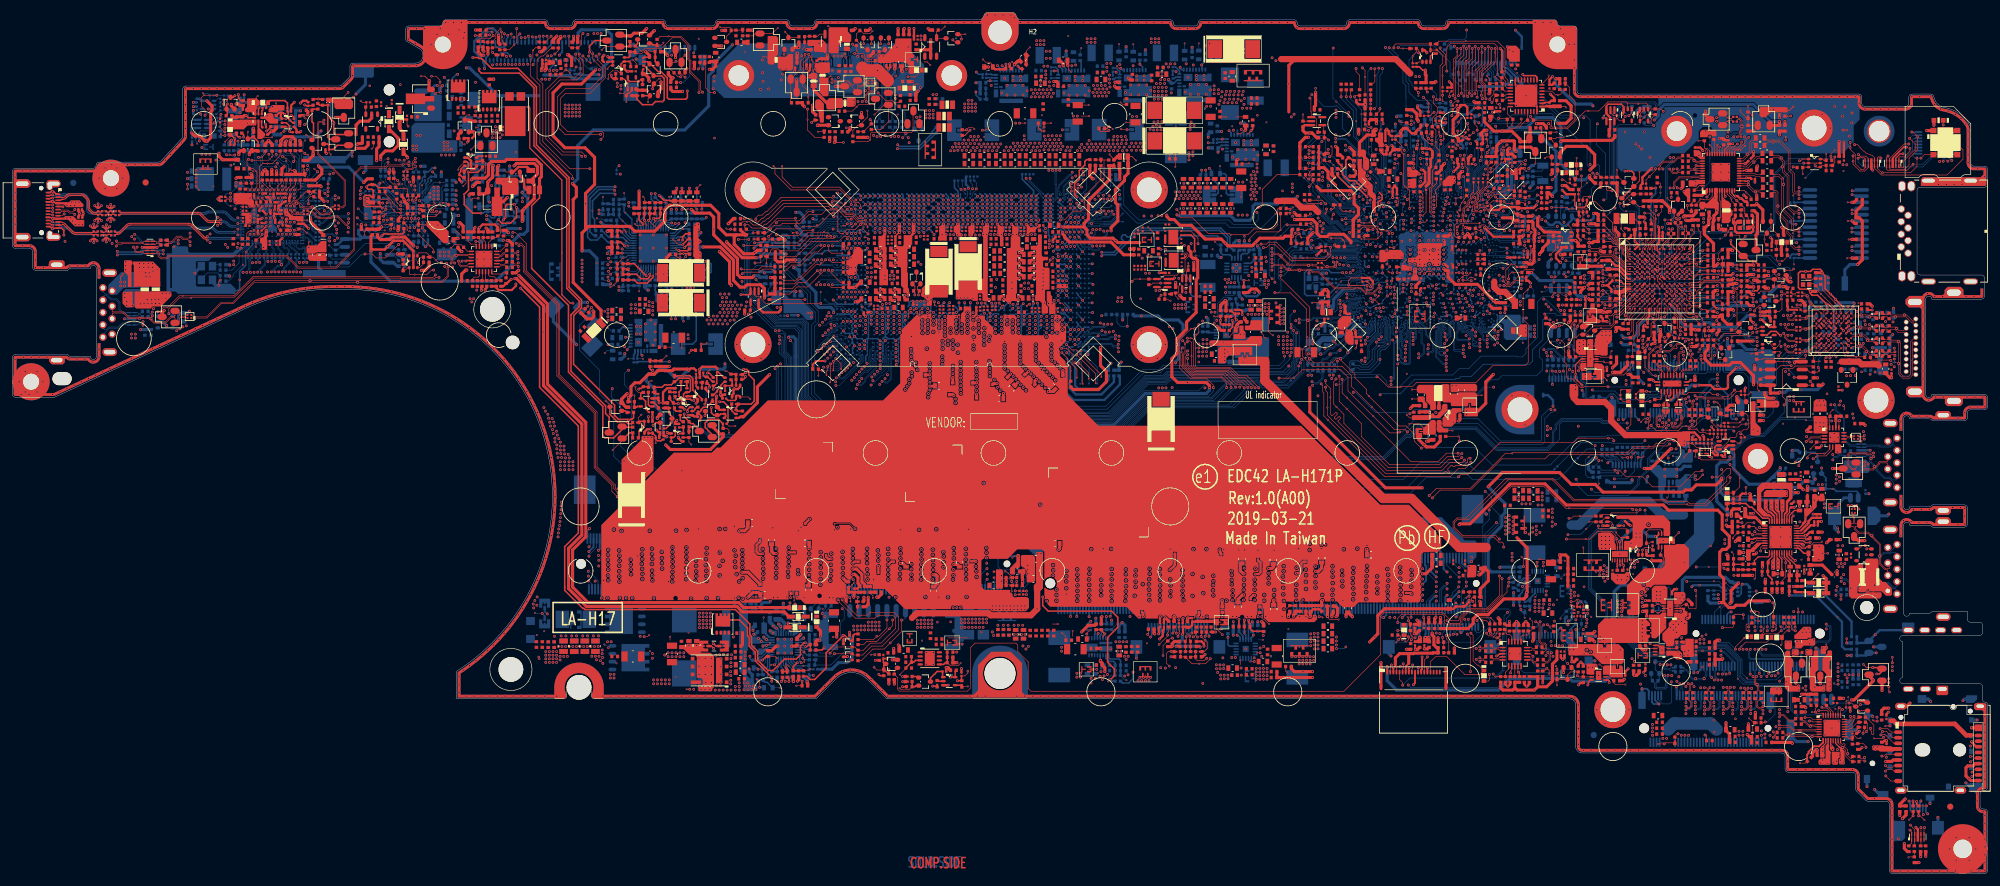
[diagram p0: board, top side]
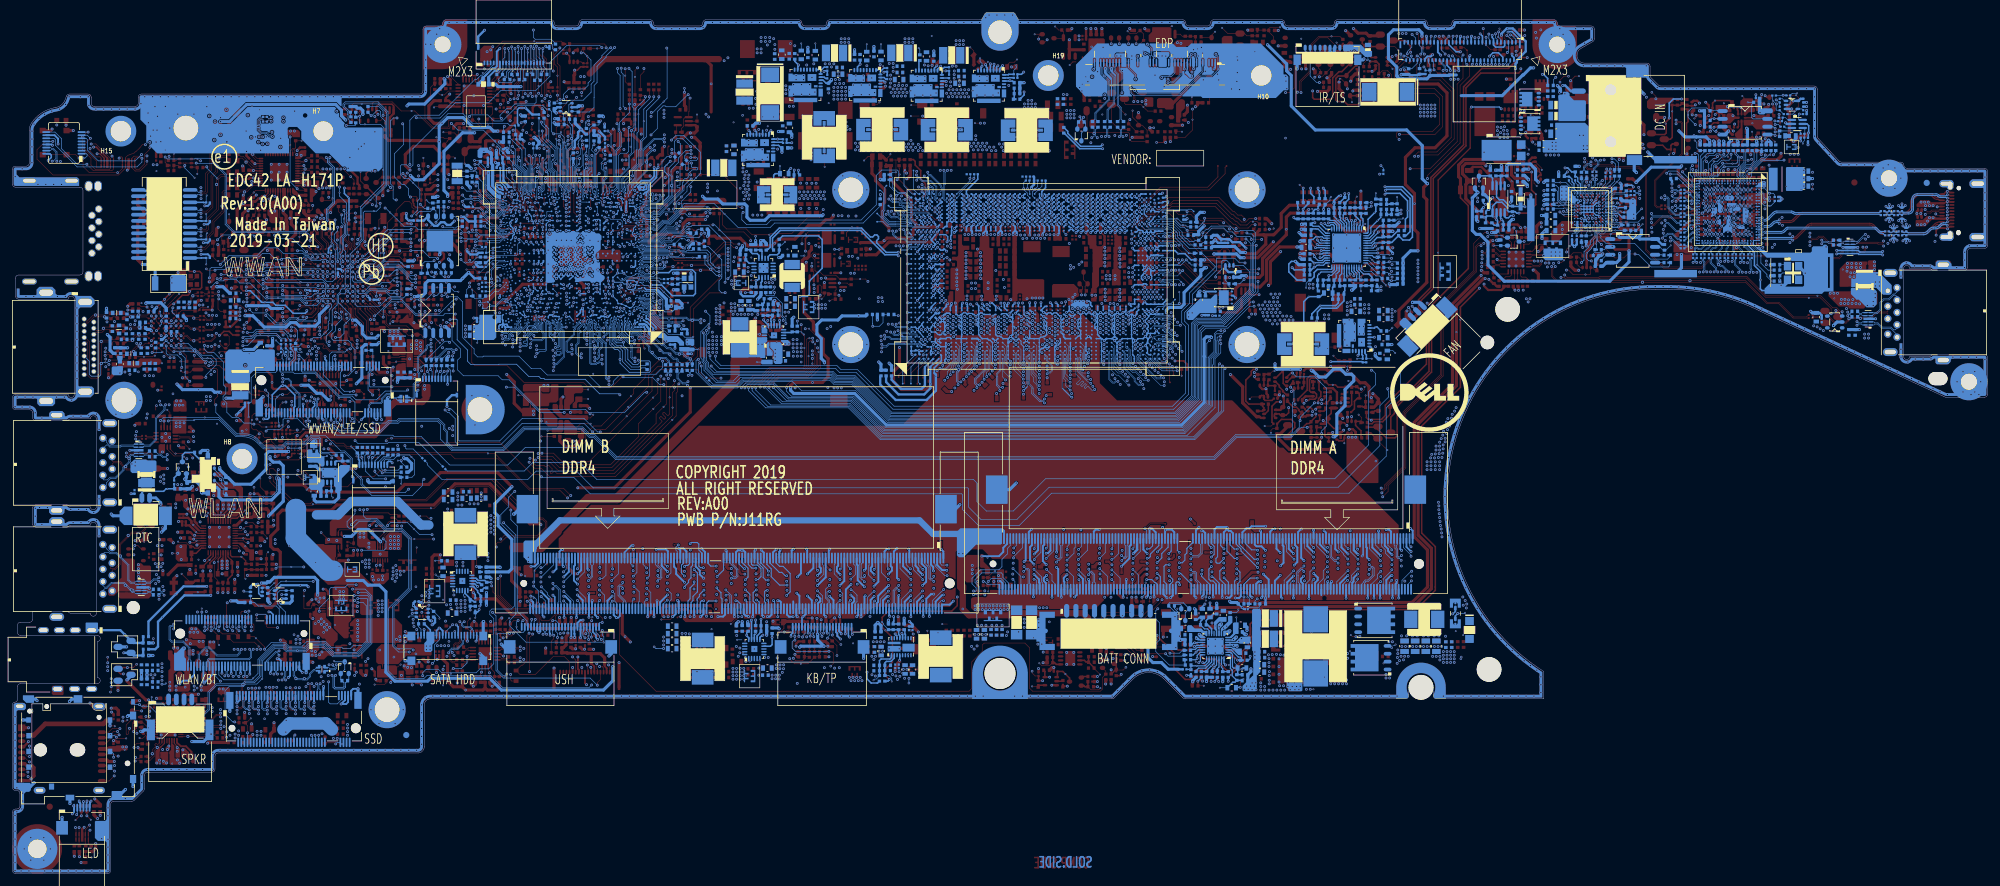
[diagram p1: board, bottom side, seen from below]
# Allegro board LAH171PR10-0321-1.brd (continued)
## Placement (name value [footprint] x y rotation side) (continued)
RH335  20K_0402_5%  [R_0402]  247.91 110.06 180 top
RH339  10K_0402_5%  [R_0402]  230.83 114.16 180 top
RH340  8.2K_0402_1%  [R_0402]  234.88 109.57 90 top
RH344  10K_0402_5%  [R_0402]  245.82 103.07 180 top
RH345  10K_0402_5%  [R_0402]  216.28 127.59 270 top
RH348  10K_0201_5%  [R_0201]  250.2 101.23 180 top
RH351  33_0402_5%  [R_0402]  248.14 97.1 0 bottom
RH352  0_0402_5%  [R_0402]  253.3 90.26 270 top
RH353  33_0402_5%  [R_0402]  250.69 90.4 270 top
RH355  10K_0402_1%  [R_0402]  230 113.22 270 top
RH361  49.9K_0402_1%  [R_0402]  224.28 122.45 270 bottom
RH364  1K_0402_5%  [R_0402]  210.96 87.26 180 bottom
RH365  0_0402_5%  [R0402_0OHM]  212.92 88.53 180 bottom
RH371  10K_0201_5%  [R_0201]  223.45 118.63 90 top
RH372  10K_0201_5%  [R_0201]  222.88 118.63 90 top
RH373  100K_0402_5%  [R_0402]  208.72 108.84 90 top
RH374  2.2K_0402_5%  [R_0402]  231.52 124.55 270 bottom
RH376  49.9K_0402_1%  [R_0402]  225.1 120.08 90 bottom
RH377  10K_0402_5%  [R_0402]  235.51 102.79 0 top
RH378  10K_0201_5%  [R_0201]  223.39 120.61 270 bottom
RH379  100_0402_1%  [R_0402]  233.67 102.83 0 top
RH400  10K_0201_5%  [R_0201]  223.32 118.08 90 bottom
RH401  10K_0201_5%  [R_0201]  223.32 117.4 270 bottom
RH402  10K_0402_5%  [R_0402]  233.56 118.44 180 top
RH424  10K_0201_5%  [R_0201]  239.8 108.72 0 top
RH431  100K_0402_5%  [R_0402]  248.72 114.64 270 top
RH432  499K_0402_1%  [R_0402]  245.16 120.53 0 top
RH433  49.9K_0402_1%  [R_0402]  248.41 119.72 270 top
RH434  0_0402_5%  [R_0402]  242.62 118.31 0 top
RH435  60.4_0402_1%  [R_0402]  211.76 92.59 0 bottom
RH436  0_0201_5%  [R_0201]  213.77 95.45 180 bottom
RH439  0_0402_5%  [R_0402]  242.62 117.42 0 top
RH440  0_0402_5%  [R0402_0OHM]  238.12 115 90 top
RH441  0_0201_5%  [R_0201]  251.58 112.23 270 top
RH442  0_0402_5%  [R0402_0OHM]  252.41 112.23 270 top
RH445  0_0402_5%  [R0402_0OHM]  249.61 113.73 90 top
RH553  10K_0402_5%  [R_0402]  229.17 126.93 90 top
RH554  10K_0402_5%  [R_0402]  228.34 126.93 90 top
RH555  10K_0402_5%  [R_0402]  226.69 126.93 90 top
RH556  10K_0402_5%  [R_0402]  227.52 126.93 90 top
RH566  0_0402_5%  [R0402_0OHM]  248.92 103.08 270 top
RH600  100K_0402_5%  [R_0402]  236.22 122.45 270 bottom
RH601  100K_0402_5%  [R_0402]  243.56 96.21 180 bottom
RH602  100K_0402_5%  [R_0402]  238.81 119.05 0 bottom
RH603  10K_0402_5%  [R_0402]  208.87 115.77 180 top
RH604  4.7K_0402_5%  [R_0402]  210.1 115.77 0 top
RH605  20K_0402_5%  [R_0402]  210.1 117.49 0 top
RH606  100K_0402_5%  [R_0402]  208.87 117.49 180 top
RH607  100K_0402_5%  [R_0402]  210.1 113.99 0 top
RH608  100K_0402_5%  [R_0402]  208.87 113.99 180 top
RH609  200_0402_1%  [R_0402]  214.05 116.16 270 top
RH610  200_0402_1%  [R_0402]  213.15 113.93 0 top
RH611  200_0402_1%  [R_0402]  213.15 113.1 0 top
RH612  150_0402_1%  [R_0402]  211.89 116.23 270 top
RH613  20K_0402_5%  [R_0402]  211.02 114.82 180 top
RH614  20K_0402_5%  [R_0402]  211.02 116.6 180 top
RH615  2.2K_0402_5%  [R_0402]  244.74 97.17 180 top
RH616  0_0402_5%  [R0402_0OHM]  213.53 108.09 0 top
RH617  75K_0402_5%  [R_0402]  223.96 116.99 270 top
RH618  71.5K_0402_1%  [R_0402]  225.23 123.47 270 top
RH619  0_0402_5%  [R_0402]  185.21 92.85 0 top
RH620  0_0402_5%  [R0402_0OHM]  187.08 93.67 180 top
RH625  0_0402_5%  [R_0402]  226.31 117.6 90 bottom
RH626  100K_0201_5%  [R_0201]  239.77 116.49 90 bottom
RH627  100K_0201_5%  [R_0201]  240.56 115.52 0 top
RH628  100K_0201_5%  [R_0201]  235.75 114.69 180 top
RH629  100K_0201_5%  [R_0201]  238.1 118.69 180 top
RH630  100K_0201_5%  [R_0201]  234.92 117.23 180 bottom
RH631  100K_0201_5%  [R_0201]  237.65 118.69 180 bottom
RH632  100K_0201_5%  [R_0201]  236.6 117.26 90 top
RH633  75K_0201_5%  [R_0201]  234.16 114.69 180 top
RH634  100K_0201_5%  [R_0201]  244.69 107.77 0 bottom
RH635  100K_0201_5%  [R_0201]  226.18 130.99 270 top
RH636  100K_0201_5%  [R_0201]  217.06 125.04 0 top
RH637  100K_0201_5%  [R_0201]  219.11 121.1 180 top
RH640  100K_0201_5%  [R_0201]  232.34 123.54 90 bottom
RH641  10K_0201_5%  [R_0201]  244.14 99.58 0 top
RH642  10K_0201_5%  [R_0201]  242.59 94.12 0 bottom
RH643  10K_0201_5%  [R_0201]  242.59 95.51 0 bottom
RH644  10K_0201_5%  [R_0201]  242.59 94.82 0 bottom
RH645  10K_0201_5%  [R_0201]  238.31 111.76 90 top
RH646  10K_0201_5%  [R_0201]  236.02 111.76 90 top
RH647  10K_0201_5%  [R_0201]  236.79 111.76 90 top
RH648  10K_0201_5%  [R_0201]  237.55 111.76 90 top
RH649  15K_0201_5%  [R_0201]  243.04 98.05 0 top
RH650  15K_0201_5%  [R_0201]  243.34 99.58 180 top
RH651  15K_0201_5%  [R_0201]  243.92 96.47 0 top
RH652  15K_0201_5%  [R_0201]  243.92 95.83 0 top
RH653  33_0402_5%  [R_0402]  250.71 97.1 180 bottom
RH654  33_0402_5%  [R_0402]  246.38 104.58 90 bottom
RH655  33_0402_5%  [R_0402]  250.26 107.77 180 bottom
RH656  33_0402_5%  [R_0402]  251.95 107.52 180 bottom
RH657  33_0402_5%  [R_0402]  252.47 90.26 270 top
RH658  33_0402_5%  [R_0402]  249.74 91.88 90 top
RH659  33_0402_5%  [R_0402]  251.01 91.88 90 top
RH660  33_0402_5%  [R_0402]  252.66 91.88 90 top
RH661  10K_0402_5%  [R_0402]  243.53 93.36 180 bottom
RH662  0_0402_5%  [R_0402]  238.81 119.83 0 bottom
RH663  0_0402_5%  [R0402_0OHM]  244.78 93.36 0 bottom
RH868  75K_0402_5%  [R_0402]  222.48 116.1 270 bottom
RI13  10K_0402_5%  [R_0402]  291.42 69.76 270 top
RI14  22.1K_0402_1%  [R_0402]  294.52 73.92 180 top
RI27  0_0402_5%  [R_0402-NPM]  267.45 75.72 270 top
RI28  0_0402_5%  [R_0402-NPM]  266.69 75.72 270 top
RI29  0_0402_5%  [R_0402-NPM]  269.48 75.8 270 top
RI30  0_0402_5%  [R_0402-NPM]  268.72 75.8 270 top
RI47  0_0402_5%  [R_0402-NPM]  255.37 76.35 0 bottom
RI48  0_0402_5%  [R_0402-NPM]  255.37 77.11 0 bottom
RI59  4.7K_0402_5%  [R_0402]  78.15 95.85 270 top
RI60  4.7K_0402_5%  [R_0402]  77.39 95.85 270 top
RI61  4.7K_0402_5%  [R_0402]  74.53 102.81 90 top
RI62  4.7K_0402_5%  [R_0402]  76.05 102.81 90 top
RI63  4.7K_0402_5%  [R_0402]  74.34 94.93 90 top
RI64  4.7K_0402_5%  [R_0402]  75.29 102.81 90 top
RI65  4.7K_0402_5%  [R_0402]  78.91 95.85 270 top
RI66  4.7K_0402_5%  [R_0402]  72.81 102.81 90 top
RI67  4.7K_0402_5%  [R_0402]  78.4 103.06 90 top
RI68  4.7K_0402_5%  [R_0402]  75.1 95.85 270 top
RI69  2K_0402_5%  [R_0402]  78.64 102.41 270 bottom
RI70  4.7K_0402_5%  [R_0402]  79.85 97.11 0 top
RI71  4.7K_0402_5%  [R_0402]  77.58 102.81 90 top
RI72  4.7K_0402_5%  [R_0402]  79.74 96.29 270 top
RI73  4.7K_0402_5%  [R_0402]  73.58 102.81 90 top
RI74  4.7K_0402_5%  [R_0402]  76.62 95.85 270 top
RI75  0_0402_5%  [R_0402]  80.76 101.61 180 top
RI76  4.7K_0402_5%  [R_0402]  75.86 95.85 270 top
RI77  4.99K_0402_1%  [R_0402]  71.98 101.23 0 top
RI78  4.7K_0402_5%  [R_0402]  76.81 102.81 90 top
RL1  10K_0402_5%  [R_0402]  274.84 118.65 90 top
RL2  10K_0402_5%  [R_0402]  273.29 118.45 90 top
RL3  0_0402_5%  [R0402_0OHM]  275.59 105.75 270 top
RL4  4.7K_0402_5%  [R_0402]  271.65 110.46 180 top
RL5  10K_0402_5%  [R_0402]  271.65 108.81 180 top
RL6  4.7K_0402_5%  [R_0402]  271.65 109.63 180 top
RL7  0_0402_5%  [R0402_0OHM]  271.2 107.12 90 top
RL8  0_0603_5%  [R0603_0OHM]  272.98 107.96 270 top
RL9  10K_0402_5%  [R_0402]  271.97 108.04 270 top
RL11  1M_0402_5%  [R_0402]  278.3 108.11 0 top
RL12  1K_0402_5%  [R_0402]  276.41 117.79 90 top
RL13  3.01K_0402_1%  [R_0402]  280.84 108.98 0 top
RL14  150_0402_5%  [R_0402]  292.97 115.29 0 top
RL15  75_0402_1%  [R_0402]  297.89 108.93 0 top
RL16  75_0402_1%  [R_0402]  297.81 105.09 90 top
RL17  75_0402_1%  [R_0402]  297.89 102.51 0 top
RL18  75_0402_1%  [R_0402]  297.89 99.47 0 top
RL19  150_0402_5%  [R_0402]  289.19 114.12 180 top
RL20  0_0402_5%  [R0402_0OHM]  293.88 114.46 180 top
RL29  1M_0402_5%  [R_0402]  293.88 113.63 180 top
RL34  0_0402_5%  [R0402_0OHM]  279.21 107.28 180 top
RL71  2.2_0603_5%  [R_0603]  282.75 109.7 0 top
RL72  2.2_0603_5%  [R_0603]  282.75 110.9 0 top
RL73  2.2_0603_5%  [R_0603]  282.75 112.17 0 top
RL74  2.2_0603_5%  [R_0603]  282.75 113.38 0 top
RL75  2.2_0603_5%  [R_0603]  282.69 115.22 0 top
RL76  2.2_0603_5%  [R_0603]  282.69 116.43 0 top
RL77  2.2_0603_5%  [R_0603]  281.61 117.7 0 top
RL78  2.2_0603_5%  [R_0603]  281.61 118.91 0 top
RN1  100K_0402_5%  [R_0402]  252.52 40.36 0 bottom
RN2  100K_0402_5%  [R_0402]  251.01 41.48 90 bottom
RN3  10K_0402_5%  [R_0402]  248.98 39.11 90 top
RN4  10K_0402_5%  [R_0402]  253.74 33.52 270 top
RN5  10K_0402_5%  [R_0402]  253.74 31.8 270 top
RN6  4.7K_0402_5%  [R_0402]  243.45 30.93 90 top
RN7  4.7K_0402_5%  [R_0402]  244.21 30.93 90 top
RN8  4.7K_0402_5%  [R_0402]  242.69 31.84 270 top
RN9  4.7K_0402_5%  [R_0402]  241.93 30.93 90 top
RN10  4.7K_0402_5%  [R_0402]  244.09 39.21 90 top
RN11  4.7K_0402_5%  [R_0402]  243.32 40.12 270 top
RN12  4.7K_0402_5%  [R_0402]  241.04 40.38 270 top
RN13  4.7K_0402_5%  [R_0402]  240.28 40.38 270 top
RN14  4.7K_0402_5%  [R_0402]  240.4 30.93 90 top
RN15  7.87K_0402_1%  [R_0402]  241.16 30.93 90 top
RN16  4.7K_0402_5%  [R_0402]  244.85 40.12 270 top
RN17  4.7K_0402_5%  [R_0402]  245.68 38.83 90 top
RN18  4.7K_0402_5%  [R_0402]  246.37 31.84 90 top
RN19  4.7K_0402_5%  [R_0402]  247.2 32.76 270 top
RN20  4.7K_0402_5%  [R_0402]  241.8 40.12 270 top
RN21  4.7K_0402_5%  [R_0402]  242.56 39.21 90 top
RN37  10K_0402_5%  [R_0402]  274.56 21.5 180 top
RN99  0_0402_5%  [R0402_0OHM]  268.54 21.14 90 top
RN129  0_0402_5%  [R0402_0OHM]  281.54 24.39 0 top
RN226  4.7K_0402_5%  [R_0402]  252.91 33.52 270 top
RN227  0_0402_5%  [R0402_0OHM]  249.48 31.46 90 top
RR3  10K_0402_5%  [R_0402]  293 28.11 270 top
RR4  6.2K_0402_1%  [R_0402]  289.91 18.14 45 top
RR5  0_0402_5%  [R0402_0OHM]  297.21 21.85 270 top
RR6  0_0402_5%  [R0402_0OHM]  298.26 23.65 0 top
RR7  0_0402_5%  [R0402_0OHM]  298.39 24.48 0 top
RR8  0_0402_5%  [R0402_0OHM]  298.39 25.3 0 top
RR9  0_0402_5%  [R0402_0OHM]  297.35 18.11 0 top
RR10  0_0402_5%  [R0402_0OHM]  297.35 18.93 0 top
RR19  10K_0402_5%  [R_0402]  291.43 27.21 180 top
RR274  0_0603_5%  [R0603_0OHM]  288.09 28.1 0 top
RT1  3.3K_0402_5%  [R_0402]  37.79 124.66 180 bottom
RT2  2.2K_0402_5%  [R_0402]  44.82 123.29 0 bottom
RT3  2.2K_0402_5%  [R_0402]  44.81 121.74 0 bottom
RT4  3.3K_0402_5%  [R_0402]  44.82 120.69 0 bottom
RT5  10K_0402_5%  [R_0402]  45.72 112.1 90 top
RT6  10K_0402_5%  [R_0402]  44.2 112.1 90 top
RT7  10K_0402_5%  [R_0402]  44.96 112.1 90 top
RT8  10K_0402_5%  [R_0402]  46.48 112.1 90 top
RT9  0_0402_5%  [R0402_0OHM]  47.24 113.02 270 top
RT10  0_0402_5%  [R_0402]  58.1 111.38 90 top
RT11  10K_0402_5%  [R_0402]  38.31 113.92 180 top
RT12  2.2K_0402_5%  [R_0402]  44.89 116.87 90 bottom
RT13  2.2K_0402_5%  [R_0402]  45.66 116.87 90 bottom
RT14  2.2K_0402_5%  [R_0402]  44.89 116.87 90 top
RT15  2.2K_0402_5%  [R_0402]  43.43 112.1 90 top
RT16  10K_0402_5%  [R_0402]  43.24 116.77 90 top
RT17  10K_0402_5%  [R_0402]  34.23 116.87 90 bottom
RT18  2.2K_0402_5%  [R_0402]  40.32 116.87 90 bottom
RT19  2.2K_0402_5%  [R_0402]  41.08 116.87 90 bottom
RT20  10K_0402_5%  [R_0402]  38.04 116.87 90 bottom
RT21  1M_0201_5%  [R_0201]  34.38 109.39 180 top
RT22  1M_0201_5%  [R_0201]  34.38 108.75 180 top
RT23  100K_0402_5%  [R_0402]  40.37 112.1 90 top
RT24  100K_0402_5%  [R_0402]  46.99 114.36 90 top
RT25  100K_0402_5%  [R_0402]  35.75 116.87 90 bottom
RT26  100K_0402_5%  [R_0402]  38.67 111.6 90 top
RT27  10K_0402_5%  [R_0402]  41.97 116.77 90 top
RT28  100K_0402_5%  [R_0402]  41.85 116.87 90 bottom
RT29  100K_0402_5%  [R_0402]  48.69 109.42 0 top
RT30  1M_0402_5%  [R_0402]  46.56 116.85 90 top
RT31  1M_0201_5%  [R_0201]  34.39 109.36 180 bottom
RT32  1M_0201_5%  [R_0201]  34.39 108.72 180 bottom
RT33  100K_0402_5%  [R_0402]  39.56 116.87 90 bottom
RT34  3.01K_0402_1%  [R_0402]  43.36 103.99 0 top
RT35  14K_0402_1%  [R_0402]  40.83 116.77 90 top
RT36  100_0402_5%  [R_0402]  34.99 116.87 90 bottom
RT37  100_0402_5%  [R_0402]  50.27 112.34 0 bottom
RT38  14K_0402_1%  [R_0402]  46.29 104.2 270 top
RT39  4.75K_0402_0.5%  [R_0402]  41.03 108.56 180 top
RT40  0_0402_5%  [R_0402]  34.48 95.76 180 bottom
RT41  499_0402_1%  [R_0402]  39.35 102.39 0 top
RT42  499_0402_1%  [R_0402]  38.04 102.63 270 top
RT48  0_0603_5%  [R0603_0OHM]  32.38 119.23 180 bottom
RT49  0_0603_5%  [R_0603]  36.33 115.38 270 top
RT50  3.3K_0402_5%  [R_0402]  52.19 100.77 90 bottom
RT51  3.3K_0402_5%  [R_0402]  56.84 103.96 180 bottom
RT52  3.3K_0402_5%  [R_0402]  63.7 99.9 180 bottom
RT53  3.3K_0402_5%  [R_0402]  62.4 99.07 0 bottom
RT54  0_0402_5%  [R0402_0OHM]  51.35 99.96 0 bottom
RT55  0_0402_5%  [R0402_0OHM]  51.35 98.75 0 bottom
RT56  0_0402_5%  [R0402_0OHM]  63.32 100.85 180 bottom
RT57  0_0402_5%  [R0402_0OHM]  58.56 103.96 180 bottom
RT58  0_0402_5%  [R0402_0OHM]  63.12 97.56 90 top
RT59  0_0402_5%  [R0402_0OHM]  67.32 99.64 180 top
RT60  0_0402_5%  [R0402_0OHM]  65.6 102.16 90 bottom
RT63  0_0201_5%  [R0201_0OHM]  58.69 106.87 180 bottom
RT64  0_0201_5%  [R_0201]  66.36 103.08 270 bottom
RT65  0_0201_5%  [R_0201]  67.13 103.08 270 bottom
RT66  3.3K_0402_5%  [R_0402]  66.4 98.82 0 top
RT67  3.3K_0402_5%  [R_0402]  63.12 99.21 90 top
RT68  10K_0402_5%  [R_0402]  64.84 103.08 270 bottom
RT69  0_0402_5%  [R_0402]  61.21 104.9 90 top
RT70  0_0402_5%  [R0402_0OHM]  59.01 104.84 180 bottom
RT71  1M_0402_5%  [R_0402]  66.42 106.23 90 top
RT72  0_0402_5%  [R0402_0OHM]  70.15 110.5 0 bottom
RT73  0_0402_5%  [R0402_0OHM]  65.6 104.89 270 top
RT74  0_0402_5%  [R_0402]  70.47 108.09 315 top
RT75  0_0402_5%  [R_0402]  70.15 111.26 0 bottom
RT76  10K_0402_1%  [R_0402]  61.93 110.94 180 top
RT81  100K_0402_5%  [R_0402]  59.27 105.22 180 top
RT82  1M_0402_5%  [R_0402]  58.43 106.95 270 top
RT83  0_0402_5%  [R0402_0OHM]  59.25 106.04 90 top
RT84  0_0402_5%  [R_0402]  60.22 110.24 180 top
RT85  0_0402_5%  [R_0402]  62.1 109.03 90 top
RT86  1M_0402_5%  [R_0402]  67.25 107.96 180 top
RT87  0_0402_5%  [R0402_0OHM]  61.59 113.27 270 top
RT88  0_0402_5%  [R0402_0OHM]  60.83 113.27 270 top
RT89  0_0201_5%  [R_0201]  61.72 113.27 270 bottom
RT90  0_0201_5%  [R_0201]  60.96 113.27 270 bottom
RT92  0_0402_5%  [R0402_0OHM]  60.26 113.65 270 bottom
RT93  0_0402_5%  [R0402_0OHM]  59.5 113.65 270 bottom
RT95  100K_0402_5%  [R_0402]  58.36 110.35 90 bottom
RT96  100K_0402_5%  [R_0402]  58.36 109.62 270 bottom
RT97  0_0402_5%  [R_0402]  71.06 109.74 180 bottom
RT98  100K_0402_5%  [R_0402]  71.06 108.94 180 bottom
RT99  0_0402_5%  [R0402_0OHM]  70.15 108.18 0 bottom
RT100  15K_0402_0.1%  [R_0402]  59.2 108.46 180 top
RT101  100K_0402_5%  [R_0402]  63.82 106.67 90 top
RT103  0_0402_5%  [R_0402]  70.15 112.02 0 bottom
RT104  0_0201_5%  [R0201_0OHM]  66.62 112.07 90 bottom
RT105  0_0201_5%  [R0201_0OHM]  67.63 112.07 90 bottom
RT106  10K_0402_5%  [R_0402]  59.2 109.35 180 top
RT107  10K_0402_5%  [R_0402]  63.24 105.18 270 top
RT108  0_0402_5%  [R0402_0OHM]  65.6 112.45 90 bottom
RT109  0_0402_5%  [R0402_0OHM]  64.78 112.45 90 bottom
RT110  0_0402_5%  [R_0402]  70.15 107.42 0 bottom
RT111  100K_0402_5%  [R_0402]  57.98 123.9 180 top
RT120  0_0402_5%  [R0402_0OHM]  24.9 102.37 180 top
RT121  0_0402_5%  [R0402_0OHM]  24.9 101.61 180 top
RT122  0_0402_5%  [R0402_0OHM]  23.99 102.37 0 bottom
RT123  0_0402_5%  [R0402_0OHM]  23.99 101.61 0 bottom
RT124  100K_0402_5%  [R_0402]  44.13 116.87 90 bottom
RT125  100K_0402_5%  [R_0402]  46.42 116.87 90 bottom
RT126  100K_0402_5%  [R_0402]  44.06 116.84 90 top
RT127  100K_0402_5%  [R_0402]  42.67 112.08 90 top
RT128  100K_0402_5%  [R_0402]  48.69 110.25 0 top
RT129  100K_0402_5%  [R_0402]  41.14 112.1 90 top
RT184  1M_0402_5%  [R_0402]  38.8 116.87 90 bottom
RT190  2.2_0201_1%  [R_0201]  16.55 103.16 180 top
RT191  2.2_0201_1%  [R_0201]  16.55 103.8 180 top
RT192  2.2_0201_1%  [R_0201]  16.55 103.16 180 bottom
RT193  2.2_0201_1%  [R_0201]  16.55 103.8 180 bottom
RT194  2.2_0201_1%  [R_0201]  17.25 107.07 180 bottom
RT195  2.2_0201_1%  [R_0201]  17.25 106.44 180 bottom
RT196  2.2_0201_1%  [R_0201]  17.25 107.07 180 top
RT197  2.2_0201_1%  [R_0201]  17.25 106.44 180 top
RT219  221K_0201_1%  [R_0201]  13.14 103.17 270 top
RT220  221K_0201_1%  [R_0201]  13.14 103.79 90 top
RT221  221K_0201_1%  [R_0201]  13.84 107.07 90 bottom
RT222  221K_0201_1%  [R_0201]  13.84 106.45 270 bottom
RT336  2.2K_0402_5%  [R_0402]  47.88 110.26 90 top
RT337  2.2K_0402_5%  [R_0402]  41.9 112.1 90 top
RT338  10K_0402_5%  [R_0402]  45.72 116.85 90 top
RT339  0_0402_5%  [R_0402]  64.71 106.67 90 top
RT371  10K_0402_5%  [R_0402]  43.37 116.87 90 bottom
RT372  10K_0402_5%  [R_0402]  37.27 116.87 90 bottom
RT377  43K_0402_1%  [R_0402]  63.84 109.6 180 top
RT391  10K_0402_5%  [R_0402]  42.61 116.87 90 bottom
RT392  0_0402_5%  [R0402_0OHM]  36.51 116.87 90 bottom
RT393  100K_0402_5%  [R_0402]  58.8 123.98 90 top
RT394  0_0402_5%  [R_0402]  34.48 97.54 180 bottom
RT398  0_0402_5%  [R_0402]  57.45 119.04 180 top
RT399  0_0402_5%  [R_0402]  57.45 118.16 180 top
RT400  0_0201_5%  [R0201_0OHM]  63.19 113.43 270 top
RT401  0_0201_5%  [R0201_0OHM]  63.82 113.43 270 top
RT402  0_0201_5%  [R_0201]  63.19 113.43 270 bottom
RT403  0_0201_5%  [R_0201]  63.82 113.43 270 bottom
RT440  1M_0201_5%  [R_0201]  30.2 118.95 180 bottom
RT441  0_0201_5%  [R0201_0OHM]  29.61 119.58 0 bottom
RT445  0_0201_5%  [R_0201]  33.82 121.61 180 bottom
RT447  10K_0201_5%  [R_0201]  29.23 122.76 0 bottom
RT448  0_0201_5%  [R0201_0OHM]  33.43 120.72 180 bottom
RT455  10K_0402_5%  [R_0402]  33.59 120.04 270 bottom
RT456  0_0201_5%  [R0201_0OHM]  33.69 122.18 180 bottom
RT482  0_0402_5%  [R_0402]  58.15 103.24 90 top
RT483  0_0402_5%  [R_0402]  58.98 103.24 90 top
RT488  221K_0201_1%  [R_0201]  13.14 103.17 270 bottom
RT489  221K_0201_1%  [R_0201]  13.14 103.79 90 bottom
RT490  221K_0201_1%  [R_0201]  13.84 106.45 270 top
RT491  221K_0201_1%  [R_0201]  13.84 107.07 90 top
RT499  0_0201_5%  [R0201_0OHM]  33.58 124.65 90 bottom
RT500  0_0201_5%  [R0201_0OHM]  32.48 125.78 180 bottom
RT501  0_0201_5%  [R0201_0OHM]  32.34 122.76 0 bottom
RT502  0_0201_5%  [R_0201]  33.58 123.97 270 bottom
RT503  100K_0201_5%  [R_0201]  29.77 123.97 270 bottom
RT554  0_0201_5%  [R_0201]  34.2 125.75 0 bottom
RT555  0_0201_5%  [R_0201]  33.54 122.01 270 top
RV1  4.7K_0402_5%  [R_0402]  136.89 136.27 0 top
RV2  4.7K_0402_5%  [R_0402]  139.99 132.85 180 top
RV3  100K_0402_5%  [R_0402]  148.64 136.34 0 top
RV4  270K_0402_5%  [R_0402]  128.77 135.34 270 top
RV5  47K_0402_5%  [R_0402]  127.96 135.27 180 top
RV6  47K_0402_5%  [R_0402]  116.87 136.33 270 top
RV7  100K_0402_5%  [R_0402]  139.37 131.39 0 top
RV8  10K_0402_5%  [R_0402]  143.44 124.84 90 top
RV9  47K_0402_5%  [R_0402]  116.11 136.28 180 top
RV22  2.2K_0402_5%  [R_0402]  292.94 82.76 270 top
RV23  2.2K_0402_5%  [R_0402]  293.77 82.76 270 top
RV24  5.6_0402_5%  [R_0402]  301.13 89.76 0 top
RV25  5.6_0402_5%  [R_0402]  301.13 90.65 0 top
RV26  200_0402_5%  [R_0402]  303.14 90.6 270 top
RV27  5.6_0402_5%  [R_0402]  301.13 87.7 0 top
RV28  5.6_0402_5%  [R_0402]  301.13 88.59 0 top
RV29  200_0402_5%  [R_0402]  303.14 88.56 270 top
RV30  5.6_0402_5%  [R_0402]  301.13 85.67 0 top
RV31  5.6_0402_5%  [R_0402]  301.13 86.56 0 top
RV32  200_0402_5%  [R_0402]  303.14 86.53 270 top
RV33  5.6_0402_5%  [R_0402]  301.11 83.64 0 top
RV34  5.6_0402_5%  [R_0402]  301.11 84.53 0 top
RV35  200_0402_5%  [R_0402]  303.14 84.5 270 top
RV38  4.3K_0402_1%  [R_0402]  294.21 89.3 270 bottom
RV98  2.2K_0402_5%  [R_0402]  108.65 129.44 180 top
RV99  2.2K_0402_5%  [R_0402]  105.96 129.44 0 top
RV319  1K_0402_5%  [R_0402]  106.35 127.07 0 top
RV323  0_0402_5%  [R0402_0OHM]  111.82 131.12 90 top
RV324  0_0402_5%  [R_0402]  111.06 131.12 90 top
RV326  100K_0402_5%  [R_0402]  112.59 131.12 90 top
RV601  68_0402_5%  [R_0402]  286.69 92.69 0 top
RV602  68_0402_5%  [R_0402]  286.69 94.59 0 top
RV603  1K_0402_5%  [R_0402]  290.9 81.88 90 top
RV604  0_0402_5%  [R_0402]  300.11 83.45 180 top
RV605  4.7K_0402_5%  [R_0402]  294.19 90.1 90 bottom
RV606  4.7K_0402_5%  [R_0402]  298.69 91.26 0 top
RV607  10K_0402_5%  [R_0402]  292.36 90.12 180 bottom
RV608  10K_0402_5%  [R_0402]  289.56 91.84 270 top
RV609  1K_0402_5%  [R_0402]  292.1 95.25 90 top
RV610  4.7K_0402_5%  [R_0402]  292.49 87.57 0 bottom
RV611  4.7K_0402_5%  [R_0402]  294.95 85.41 90 bottom
RV614  0_0603_5%  [R0603_0OHM]  301.68 83.07 270 bottom
RV615  10K_0402_5%  [R_0402]  298.69 92.09 0 top
RV616  4.7K_0402_5%  [R_0402]  291.69 78.94 180 top
RV617  4.7K_0402_5%  [R_0402]  282.34 78.99 90 top
RV618  4.7K_0402_5%  [R_0402]  282.35 81.48 180 top
RV619  10K_0402_5%  [R_0402]  290.91 81.04 270 top
RV623  100K_0402_5%  [R_0402]  132.9 119 90 top
RV624  1M_0402_5%  [R_0402]  132.01 119.91 270 top
RV625  47K_0402_5%  [R_0402]  135.76 118.3 90 top
RV626  200K_0402_5%  [R_0402]  145.02 124.98 0 top
RV627  10K_0402_5%  [R_0402]  143.24 124.03 0 top
RV628  0_0402_5%  [R0402_0OHM]  131.12 119.91 270 top
RV629  200K_0402_5%  [R_0402]  136.58 119.91 270 top
RV630  47K_0402_5%  [R_0402]  134.45 123.24 180 top
RV631  10K_0402_5%  [R_0402]  138.74 120.27 90 top
RV732  0_0603_5%  [R_0603]  113.6 132.66 270 top
RV733  0_0603_5%  [R0603_0OHM]  118.46 134.35 180 top
RV1400  0_0402_5%  [R0402_0OHM]  117.95 136.33 270 top
RV1657  100K_0402_5%  [R_0402]  106.35 127.9 0 top
RZ8  4.7K_0402_5%  [R_0402]  230.3 35.7 0 top
RZ9  4.7K_0402_5%  [R_0402]  230.28 36.52 0 top
RZ10  100K_0402_5%  [R_0402]  225.86 36.26 90 top
RZ18  4.7K_0402_5%  [R_0402]  188.59 36.7 0 top
RZ19  4.7K_0402_5%  [R_0402]  191.22 36.7 180 top
RZ20  2.2K_0402_5%  [R_0402]  191.27 40.78 270 top
RZ21  2.2K_0402_5%  [R_0402]  193.62 40.78 270 top
RZ22  0_0402_5%  [R_0402]  189.49 35.89 270 top
RZ23  0_0402_5%  [R_0402]  190.31 35.89 270 top
RZ25  150_0402_5%  [R_0402]  259.2 112.55 270 top
RZ26  0_0402_5%  [R0402_0OHM]  191.19 39.05 0 top
RZ28  330_0402_5%  [R_0402]  307.02 10.03 90 top
RZ29  0_0402_5%  [R0402_0OHM]  193.76 39.05 180 top
RZ32  330_0402_5%  [R_0402]  281.74 84.03 270 top
RZ38  100K_0402_5%  [R_0402]  271.28 43.5 180 top
RZ40  100K_0402_5%  [R_0402]  251.59 83.53 0 top
RZ43  10K_0402_5%  [R_0402]  261.93 84.58 90 bottom
RZ56  0_0402_5%  [R0402_0OHM]  284.48 41.43 270 top
RZ58  33_0402_5%  [R_0402]  241.45 121.92 0 top
RZ59  33_0402_5%  [R_0402]  239.76 124.98 0 top
RZ60  33_0402_5%  [R_0402]  239.74 126.87 0 top
RZ61  0_0402_5%  [R0402_0OHM]  239.76 125.8 0 top
RZ63  33_0402_5%  [R_0402]  239.74 127.69 0 top
RZ64  0_0402_5%  [R0402_0OHM]  260.88 55.24 270 top
RZ69  10K_0402_5%  [R_0402]  240.6 129.56 270 top
RZ70  0_0402_5%  [R_0402]  272.98 86.26 270 top
RZ71  0_0402_5%  [R_0402]  274.76 86.26 270 top
RZ78  0_0402_5%  [R_0402]  286.13 41.43 270 top
RZ79  0_0402_5%  [R_0402]  286.95 41.43 270 top
RZ80  0_0402_5%  [R_0402]  287.78 41.43 270 top
RZ86  0_0201_5%  [R_0201]  259.75 77.33 270 top
RZ87  0_0201_5%  [R_0201]  262.25 77.49 270 top
RZ89  0_0402_5%  [R_0402]  249.93 127.66 270 top
RZ112  0_0402_5%  [R0402_0OHM]  250.82 127.66 270 top
RZ114  0_0402_5%  [R0402_0OHM]  225.8 40.22 270 top
RZ116  10K_0402_5%  [R_0402]  192.03 40.78 270 top
RZ117  10K_0402_5%  [R_0402]  192.85 40.78 270 top
RZ119  0_0402_5%  [R_0402]  123.93 90.88 0 bottom
RZ120  0_0402_5%  [R0402_0OHM]  121.63 95.32 0 bottom
RZ128  0_0201_5%  [R_0201]  274.12 85.58 90 bottom
RZ129  0_0201_5%  [R_0201]  274.88 85.58 90 bottom
RZ130  0_0201_5%  [R_0201]  275.64 85.58 90 bottom
RZ132  0_0402_5%  [R_0402]  273.29 85.69 270 bottom
RZ133  100K_0402_5%  [R_0402]  276.92 74.95 270 top
RZ151  0_0402_5%  [R_0402]  181.94 100.01 90 top
RZ320  0_0402_5%  [R_0402]  183.57 95.18 90 top
RZ326  0_0402_5%  [R_0402]  264.29 74.25 180 top
RZ334  51_0402_5%  [R_0402]  307.21 2.7 270 top
RZ335  15K_0402_5%  [R_0402]  309.05 3.57 90 top
RZ345  0_0402_5%  [R0402_0OHM]  269.76 37.41 180 top
RZ346  0_0402_5%  [R0402_0OHM]  192.04 35.87 180 top
RZ347  0_0402_5%  [R0402_0OHM]  187.76 35.87 0 top
RZ350  0_0201_5%  [R0201_0OHM]  277.96 121.55 0 bottom
RZ351  0_0201_5%  [R0201_0OHM]  277.96 122.31 0 bottom
RZ360  10K_0402_5%  [R_0402]  265.29 76.61 270 top
RZ361  150_0402_5%  [R_0402]  307.91 10.03 90 top
RZ362  10K_0402_5%  [R_0402]  249.92 128.47 0 top
RZ372  0_0201_5%  [R_0201]  274.88 84.89 270 bottom
RZ373  0_0201_5%  [R_0201]  275.64 84.89 270 bottom
RZ374  0_0201_5%  [R_0201]  274.12 84.89 270 bottom
RZ376  10K_0402_5%  [R_0402]  281.5 43.83 180 bottom
RZ377  100K_0402_5%  [R_0402]  277.81 44.38 90 bottom
RZ378  100K_0402_5%  [R_0402]  273.87 44.83 90 bottom
RZ379  20K_0402_5%  [R_0402]  273.87 85.34 90 top
RZ381  100K_0402_5%  [R_0402]  277.81 47.14 270 bottom
RZ400  10K_0402_5%  [R_0402]  256.61 57.79 270 top
RZ401  1K_0402_5%  [R_0402]  255.79 57.79 270 top
RZ518  100K_0402_5%  [R_0402]  277.68 88.8 270 top
RZ542  10K_0402_5%  [R_0402]  187.89 93.85 90 top
RZ543  10K_0402_5%  [R_0402]  189.91 97.55 0 top
RZ580  0_0402_5%  [R0402_0OHM]  280.35 122.17 90 top
RZ1380  0_0402_5%  [R0402_0OHM]  129.76 121.79 0 top
RZ1381  22_0402_5%  [R_0402]  278 40.52 90 top
RZ1382  33_0402_5%  [R_0402]  211.38 116.48 315 bottom
RZ1383  22_0402_5%  [R_0402]  280.98 40.52 90 top
RZ1384  33_0402_5%  [R_0402]  210.17 115.28 315 bottom
RZ1388  0_0201_5%  [R_0201]  277.96 121.55 0 top
RZ1389  0_0201_5%  [R_0201]  277.96 122.31 0 top
RZ1390  0_0402_5%  [R_0402]  285.43 120.01 90 top
RZ1391  0_0402_5%  [R_0402]  286.32 120.01 90 top
RZ1392  100K_0402_5%  [R_0402]  286.32 122.43 90 top
RZ1393  0_0201_5%  [R0201_0OHM]  276.56 72.84 0 top
RZ1394  0_0201_5%  [R0201_0OHM]  279.23 70.5 0 top
RZ1395  0_0201_5%  [R0201_0OHM]  276.09 71.09 90 top
RZ1396  0_0201_5%  [R_0201]  275.46 71.68 270 top
RZ1397  100K_0201_5%  [R_0201]  277.68 74.92 270 top
RZ1398  0_0201_5%  [R0201_0OHM]  279.2 77.96 270 top
RZ1399  10K_0201_5%  [R_0201]  279.84 77.38 90 top
RZ1400  100K_0201_5%  [R_0201]  276.73 71.68 270 top
RZ1401  0_0201_5%  [R0201_0OHM]  273.87 69.57 90 top
RZ1402  0_0402_5%  [R0402_0OHM]  271.85 68.34 180 top
RZ1403  0_0201_5%  [R_0201]  272.6 69.57 90 top
RZ1404  0_0201_5%  [R_0201]  271.97 69.57 90 top
RZ1405  10K_0201_5%  [R_0201]  271.33 70.15 270 top
RZ1406  2.2K_0201_5%  [R_0201]  274.82 71.09 90 top
RZ1407  0_0402_5%  [R_0402]  245.67 121.79 180 top
RZ1408  0_0402_5%  [R0402_0OHM]  236.9 123.77 0 top
RZ1409  0_0402_5%  [R_0402]  236.9 124.6 0 top
RZ1410  0_0402_5%  [R_0402]  249.93 124.93 270 top
RZ1411  0_0402_5%  [R0402_0OHM]  238.63 39.43 90 top
RZ1413  330K_0402_5%  [R_0402]  262.63 86.13 270 top
RZ1414  0_0402_5%  [R_0402]  239.45 39.43 90 top
RZ1415  0_0402_5%  [R0402_0OHM]  263.71 84.35 270 top
RZ1450  0_0201_5%  [R_0201]  280.9 76.09 0 bottom
RZ1471  0_0201_5%  [R_0201]  264.94 53.01 90 top
RZ1472  100K_0402_5%  [R_0402]  265 51.38 90 top
RZ1473  0_0402_5%  [R_0402]  222.87 38.55 0 top
RZ1474  100K_0402_5%  [R_0402]  259.08 89.18 270 top
RZ1475  0_0201_5%  [R0201_0OHM]  188.41 40.48 270 top
RZ1480  0_0201_5%  [R_0201]  274.51 70.15 270 top
RZ1481  0_0201_5%  [R_0201]  274.19 71.09 90 top
RZ1482  1M_0402_5%  [R_0402]  263.46 108.74 270 top
RZ1483  10K_0402_5%  [R_0402]  272.73 74.95 270 top
RZ1484  20K_0402_5%  [R_0402]  278.64 86.06 180 top
RZ1485  10K_0201_5%  [R_0201]  270.7 70.15 270 top
RZ1486  0_0603_5%  [R_0603-NPM]  133.79 124.53 0 top
RZ1487  0_0603_5%  [R0603_0OHM]  130.86 129.74 270 top
RZ1488  0_0603_5%  [R0603_0OHM]  129.43 128.79 270 top
RZ1489  0_0402_5%  [R_0402]  237.79 122.08 90 top
SHDCAN  SION_C7521R  [SION_C7521R_1P-T]  28.42 97.17 90 bottom
SW1  SSAJ120100_3P  [SW_SSAJ120100_3P]  286.42 65.53 270 bottom
SW3  SKRBAAE010_4P  [SW_SKRBAAE010_4P]  310.3 120.1 0 top
T1  PAD~D  [TPC12]  172.46 79.16 180 bottom
T2  PAD~D  [TPC12]  172.88 79.16 0 top
T3  PAD~D  [TPC12]  174.99 79.27 0 top
T4  PAD~D  [TPC12]  173.86 80.02 0 top
T5  PAD~D  [TPC12]  132.58 81.35 0 top
T6  PAD~D  [TPC12]  133.85 81.54 0 top
T7  PAD~D  [TPC12]  122.93 114.37 0 top
T8  PAD~D  [TPC12]  124.33 114.37 0 top
T9  PAD~D  [TPC12]  168.87 100.25 0 top
T10  PAD~D  [TPC12]  170.16 100.29 0 top
T11  PAD~D  [TPC12]  134.96 105.76 0 top
T12  PAD~D  [TPC12]  160.05 91.86 0 top
T13  PAD~D  [TPC12]  163.83 91.77 0 top
T14  PAD~D  [TPC12]  165.9 105.69 0 top
T15  PAD~D  [TPC12]  156.69 105.51 0 top
T18  PAD~D  [TPC12]  178.94 110.44 180 bottom
T19  PAD~D  [TPC12]  177.86 111.2 180 bottom
T20  PAD~D  [TPC12]  171.95 80.15 0 top
T21  PAD~D  [TPC12]  175.89 80.27 0 top
T22  PAD~D  [TPC12]  138.11 104.47 0 top
T23  PAD~D  [TPC12]  128.24 107.03 180 bottom
T24  PAD~D  [TPC12]  134.17 104.72 0 top
T25  PAD~D  [TPC12]  145.56 91.11 0 top
T26  PAD~D  [TPC12]  148.27 90.82 0 top
T27  PAD~D  [TPC12]  148.97 91.89 0 top
T28  PAD~D  [TPC12]  148.56 103.69 0 top
T29  PAD~D  [TPC12]  136.88 104.05 0 top
T30  PAD~D  [TPC12]  137.62 102.84 0 top
T31  PAD~D  [TPC12]  146.57 90.31 0 top
T32  PAD~D  [TPC12]  144.75 90 0 top
T33  PAD~D  [TPC12]  235.49 97.09 90 top
T34  PAD~D  [TPC12]  233.17 97.1 0 top
T35  PAD~D  [TPC12]  233.33 103.99 90 top
T36  PAD~D  [TPC12]  213.04 117.55 90 top
T37  PAD~D  [TPC12]  213.16 105.8 90 top
T38  PAD~D  [TPC12]  212.09 106.69 90 top
T40  PAD~D  [TPC12]  222.96 96.21 90 top
T41  PAD~D  [TPC12]  152.89 90.27 0 top
T42  PAD~D  [TPC12]  169.22 92.21 0 top
T43  PAD~D  [TPC12]  175.23 79.18 180 bottom
T44  PAD~D  [TPC12]  135.63 104.53 0 top
T45  PAD~D  [TPC12]  174.87 113.71 180 bottom
T46  PAD~D  [TPC12]  131.5 80.59 0 top
T47  PAD~D  [TPC12]  132.06 79.4 0 top
T48  PAD~D  [TPC12]  173.91 79.19 180 bottom
T49  PAD~D  [TPC12]  173.49 113.65 180 bottom
T50  PAD~D  [TPC12]  135.38 43.98 0 top
T51  PAD~D  [TPC12]  132.8 56.54 0 top
T52  PAD~D  [TPC12]  211.63 41.4 0 top
T53  PAD~D  [TPC12]  212.12 53.14 0 top
T60  PAD~D  [TPC12]  223.25 94.27 0 top
T61  PAD~D  [TPC12]  222.05 95.3 0 top
T62  PAD~D  [TPC12]  237 105.17 0 top
T63  PAD~D  [TPC12]  234.35 104.79 0 top
T66  PAD~D  [TPC12]  223.32 102.25 0 top
T67  PAD~D  [TPC12]  222.5 101.23 0 top
T68  PAD~D  [TPC12]  231.62 94.97 0 top
T69  PAD~D  [TPC12]  230.77 93.89 0 top
T70  PAD~D  [TPC12]  234.3 96.43 90 top
T71  PAD~D  [TPC12]  236.24 96.05 90 top
T72  PAD~D  [TPC12]  224.16 97.08 90 top
T73  PAD~D  [TPC12]  222.27 97.29 90 top
T74  PAD~D  [TPC12]  228.47 103.9 90 top
T75  PAD~D  [TPC12]  215.39 114.63 90 top
T76  PAD~D  [TPC12]  242.25 92.4 0 bottom
T77  PAD~D  [TPC12]  243.07 91.39 270 bottom
T88  PAD~D  [TPC12]  275.42 117.78 0 top
T89  PAD~D  [TPC12]  274.15 117.79 0 top
T179  PAD~D  [TPC12]  126.03 103.57 0 top
T180  PAD~D  [TPC12]  122.74 101.55 0 top
T181  PAD~D  [TPC12]  121.79 98.69 0 top
T182  PAD~D  [TPC12]  210.9 102.64 180 bottom
T183  PAD~D  [TPC12]  208.97 103.96 180 top
T184  PAD~D  [TPC12]  93.44 131.04 0 top
T185  PAD~D  [TPC12]  134.13 103.43 0 top
T186  PAD~D  [TPC12]  212.4 102.94 180 bottom
T187  PAD~D  [TPC12]  208.21 102.82 90 top
T188  PAD~D  [TPC12]  214.88 102.44 90 top
T189  PAD~D  [TPC12]  134.04 100.28 0 top
T190  PAD~D  [TPC12]  129.03 100.28 180 bottom
T191  PAD~D  [TPC12]  84.11 133.08 0 top
T192  PAD~D  [TPC12]  211.51 103.71 90 top
T194  PAD~D  [TPC12]  177.54 107.96 180 bottom
T199  PAD~D  [TPC12]  131.25 92.78 180 bottom
T258  PAD~D  [TPC12]  232.71 116.84 270 bottom
T268  PAD~D  [TPC12]  233.4 106.89 90 top
T284  PAD~D  [TPC12]  179.36 106.69 180 bottom
T285  PAD~D  [TPC12]  179.38 105.36 180 bottom
T286  PAD~D  [TPC12]  234.97 115.72 270 bottom
T287  PAD~D  [TPC12]  231.9 105.96 180 top
T300  PAD~D  [TPC12]  220.72 93.42 90 top
T301  PAD~D  [TPC12]  220.72 92.09 90 top
T302  PAD~D  [TPC12]  242.31 102.63 270 bottom
T418  PAD~D  [TPC12]  286.44 119.07 0 top
T419  PAD~D  [TPC12]  279.9 117.64 0 top
T421  PAD~D  [TPC12]  233.37 115.68 270 bottom
T422  PAD~D  [TPC12]  234.23 114.62 270 bottom
T423  PAD~D  [TPC12]  264.49 93.78 180 bottom
T424  PAD~D  [TPC12]  233.17 109.17 0 top
T425  PAD~D  [TPC12]  295.18 90.84 180 bottom
TL1  350UH_IH-160  [TAIMA_IH-160_24P]  290.35 99.5 90 bottom
UA1  -  [ALC3204-CG_MQFN40_5X5]  283.07 56.2 0 top
UC1  CFL-H_BGA1440  [CFL-H_BGA_1440P-T]  173.85 83.22 270 bottom
UC3  -  [74AHC1G09GW_TSSOP5]  209.79 122.26 270 top
UC5  W25Q256JVEIQ_WSON8_8X6  [W25Q256FVEIQ_WSON8_8X6]  251.9 98.25 180 bottom
UC6  -  [W25Q128JVSIQ_SO8]  252.34 87.38 180 bottom
UD1  74AUP1G07SE-7_SOT353  [74AUP1G07GW_TSSOP5]  120.53 94.12 180 top
UE1  MEC5105_WFBGA169_11X11  [MEC5105_WFBGA_169P]  261.27 100.93 0 top
UE3  MC74VHC1G08DFT2G_SC70-5  [TC7SH08FU_SSOP5]  261.57 123.58 180 top
UE4  -  [74AUP1G07GW_TSSOP5]  258.77 123.4 180 top
UE5  MC74VHC1G08DFT2G_SC70-5  [TC7SH08FU_SSOP5]  264.18 123.56 180 top
UH1  CNP-H_BGA874  [CNP-H_BGA_874P-T]  216.65 88.33 0 bottom
UH7  MC74VHC1G08DFT2G_SC70-5  [TC7SH08FU_SSOP5]  227.75 131.2 0 top
UI1  EM5203J-20_SOT23-5  [SY6288D20AAC_SOT23-5]  23.49 88.21 90 bottom
UI2  EM5203J-20_SOT23-5  [SY6288D20AAC_SOT23-5]  300.29 50.58 90 top
UI3  -  [SLGC55544CVTR_TQFN16_3X3]  292.73 71.25 270 top
UI6  -  [PS8713BTQFN24GTR2-A_TQFN24_4X4]  77.43 101.38 270 top
UL1  WGI219LM-SLKJ2-A0_QFN48_6X6~D  [WGI219LM-SLKJ3-A0_QFN48_6X6]  273.76 110.42 90 top
UN7  PI3EQX6741STZDEX_TQFN20_4X4  [PI3EQX6741STZDEX_TQFN20_4X4-S]  240.71 36.54 0 top
UR1  -  [RTS5242-GR_QFN32_4X4]  291.84 24.92 0 top
UT1  ALPINE-RIDGE_BGA337  [ALPINE-RIDGE_BGA_337P]  36.91 111.98 270 bottom
UT2  -  [W25Q80DVSSIG_SO8]  42.81 123.26 270 bottom
UT5  SN1804044ZBHR_NFBGA96  [TPS65982_BGA_96P]  61.7 104.88 0 bottom
UT6  GD25Q80CSIGR_SO8  [W25Q80DVSSIG_SO8]  60.95 102.56 270 bottom
UT7  AP2112K-3.3TRG1_SOT23-5  [AP2112K-3P3TRG1_SOT23-5]  58.98 122.74 180 top
UT8  AP2204R-5.0TRG1_SOT89-3  [AP2204R-5P0TRG1_SOT89-3]  67.62 123.73 90 top
UT32  -  [TS5A3159ADCKR_SC70-6]  31.6 121.82 270 bottom
UT34  MC74VHC1G08DFT2G_SC70-5  [TC7SH08FU_SSOP5]  32.56 124.89 270 bottom
UV2  -  [AP2330W-7_SC59-3]  296.35 79.01 180 top
UV24  -  [G524B1T11U_SOT23-5]  147.38 132.11 0 top
UV31  PS175HDMBGA64GTR2-B1_TFBGA64  [PS175HDMBGA64GTR2-B1_TFBGA_64P]  291.4 84.94 90 top
UV32  -  [W25X20CLSNIG_SO8]  289.11 78.94 90 top
UZ2  -  [EM5209VF_DFN14_3X2]  253.88 84.4 270 top
UZ3  -  [EM5209VF_DFN14_3X2]  260.85 52.64 180 top
UZ4  -  [EM5209VF_DFN14_3X2]  268.77 41.66 90 top
UZ6  MC74VHC1G08DFT2G_SC70-5  [TC7SH08FU_SSOP5]  257.63 57.53 270 top
UZ8  -  [AOZ1336DI_DFN8_2X2]  267.54 35.39 90 top
UZ10  MC74VHC1G08DFT2G_SC70-5  [TC7SH08FU_SSOP5]  282.7 88.35 270 top
UZ12  ST33HTPH2032AHC1_VQFN32_5X5  [ST33HTPH2E32AHB4_VQFN32_5X5]  247.06 123.98 180 top
UZ19  -  [AOZ1334DI-01_DFN8-7_3X3]  188.87 98.16 90 top
UZ21  -  [AOZ1334DI-01_DFN8-7_3X3]  188.81 101.91 90 top
UZ23  -  [AOZ1336DI_DFN8_2X2]  255.11 32.8 270 top
UZ26  -  [AOZ1334DI-01_DFN8-7_3X3]  122.08 92.13 90 bottom
UZ29  -  [PI3PCIE3212ZBEX_TQFN20_2P5X4P5]  265.79 78.95 0 top
UZ34  MC74VHC1G08DFT2G_SC70-5  [TC7SH08FU_SSOP5]  121.82 98.31 0 bottom
UZ35  MC74VHC1G08DFT2G_SC70-5  [SN74AHC1G08DCKR_SC70-5]  186.75 94.8 90 top
UZ51  -  [SN74LVC1G3157DCKR_SC70-6]  277.89 68.58 90 top
UZ52  SN74AUP1T97YZPR_DSBGA6~D  [SN74AUP1T97YZPR_DSBGA_6P]  272.93 67.9 90 top
UZ53  AOZ1336_DFN8_2X2  [AOZ1336_DFN8_2X2-S]  267.4 54.94 180 top
UZ54  MC74VHC1G32DFT2G_SC70-5~D  [MC74VHC1G32DFT2G_SC70-5]  263.29 52.48 0 top
UZ61  -  [74AUP1G07GW_TSSOP5]  190.26 96.22 180 top
YE1  32.768KHZ_9PF_X1A000141000200  [Y_X1A000141000200_2P]  259.11 105.88 0 top
YH1  32.768KHZ_12.5PF_9H03200042  [Y_9H03200042_2P]  247.2 111.92 90 bottom
YH2  24MHZ_12PF_8Y24000034  [Y_8Y24000034_4P]  210.54 96.21 270 bottom
YL1  25MHZ_20PF_XRCGB25M000F2P18R0  [Y_XRCGB25M000F2P18R0_4P]  280.38 105.37 180 top
YT1  25MHZ_10PF_7V25000034  [Y_7V25000034_4P]  32.32 98.18 270 bottom
YV6  27MHZ_10PF_XRCGB27M000F2P18R0  [Y_XRCGB27M000F2P18R0_4P]  290.25 95.22 90 top

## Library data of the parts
CA1-CA4 CA9 CA10 CA12 CA13 CA19 CA22-CA25 CA27-CA29 CA31 CA33 CA35 CA41 CA43-CA49 CA51-CA61 CA69 CA73-CA80 = CAP NP: room: CODEC
CA5 CA6 CA62 CA72 = CAP NP: room: CAMERA
CA7 CV1-CV6 CV12-CV17 CV632-CV636 CV1641 CZ1 CZ2 CZ9 CZ1206 = CAP NP: room: LCD
CA8 CD9-CD18 CD23 CD24 CD41-CD48 CD50 CD51 CD55 CD56 CE14 CE30 CE31 CE63 CH29 CH40 CH41 CH554 CN60-CN62 CN80-CN82 CN84 CN86 CR15 CR22 CT74-CT78 CT95-CT98 CT326-CT329 CV605 CV1637 CZ100 CZ102 CZ105 CZ218 = CAP NP
CA63-CA68 CE59 CE60 CH2 CI9 CI43-CI48 CL29 CL30 CR25-CR28 CT2-CT21 CT25-CT57 CT59-CT64 CT68 CT69 CT99-CT102 CT123-CT130 CT178-CT187 CT189 CT190 CV18-CV25 CV620-CV624 CZ3 CZ41 CZ57 CZ58 CZ62 CZ63 CZ83-CZ89 CZ1201 CZ1202 = CAP NP: room: TBT
CC28 CC29 CC33 CC269 CC306-CC308 CC334-CC337 = CAP NP: room: CPU XDP
CC32 CC161 CC163-CC168 CC170-CC172 CC185-CC189 CC191 CC192 CC195 CC209 CC210 CC272 CC300-CC305 CC310 CC311 CC322-CC324 CC327-CC333 CC500 CC501 CC568 CC569 CE61 CH45 CH324 CH349 CH350 CV625-CV629 = CAP NP: room: CPU
CC81-CC84 = P_CAP NP: room: CPU
CC193 CC194 CT1 CT67 = P_CAP NP: room: TBT
CC316 CC318-CC320 CC325 CE57 CH9 CH270 CH321 CH322 CT237 CT360 = CAP NP: room: SPI ROM
CC549 CC556-CC558 CE548 CE549 CH550-CH553 CH556 CH558 CZ12 CZ13 CZ27-CZ36 = CAP NP: room: WLAN
CD1-CD8 CD19 CD20 CD22 CD25-CD29 CD31-CD40 CD52-CD54 CD57-CD62 CZ544 = CAP NP: room: MEMORY
CD21 CD49 = CAP WP: room: MEMORY
CE3 CE4 CE10-CE13 CE15-CE29 CE32 CE35-CE40 CE46 CE47 CE54 CE62 CE66 CZ80 CZ81 = CAP NP: room: KBC
CE8 = CAP NP: room: SIO
CE52 CE53 CH4 CH5 CH10 CH13 CH14 CH20 CH21 CH31 CH33-CH38 CH44 CH46 CH47 CH62-CH68 CH266-CH268 CH323 CH341-CH348 CH555 = CAP NP: room: PCH
CE64 CE65 = CAP NP: room: RTC_2
CH22 CH30 CH32 CH559 CR1-CR7 CR11-CR14 CR17-CR21 = CAP NP: room: RTS5242
CH340 CZ500 CZ1200 = P_CAP NP: room: CAMERA
CI1 CI8 CI14 PC1171 PC1635 = CAP WP
CI3-CI7 = CAP NP: room: USB2
CI10-CI12 CI27 CI28 = CAP NP: room: USB3
CI13 CI16 CI17 CI19 CI31 CI33 CI34 CI49-CI54 = CAP NP: room: USB1
CI32 CI103 CI104 = CAP WP: room: USB1
CL1-CL14 CL16-CL22 CL28 = CAP NP: room: LAN
CLP1-CLP4 = EMIST_SUL-12A2M_0
CMOS1 = OPEN: User Part Number: PART#; room: PCH
CN1-CN17 CZ129 CZ130 = CAP NP: room: HDD
CN63-CN72 CN77 = CAP NP: room: SATA EXPRESS
CT70 CT82 CT92 = P_CAP NP: room: PD
CT71-CT73 CT80 CT81 CT83-CT91 CT93 CT94 = CAP NP: room: PD
CV8-CV10 CZ64 CZ66-CZ69 CZ71-CZ73 CZ1203-CZ1205 = CAP NP: room: USH
CV11 PC2 PC4 PC6 PC8-PC10 PC12 PC104-PC110 PC113 PC117 PC118 PC120-PC124 PC127 PC129 PC130 PC161-PC164 PC167 PC168 PC171 PC172 PC214 PC228-PC237 PC301 PC304-PC311 PC313 PC401-PC404 PC406-PC409 PC425 PC426 PC501 PC504 PC509-PC511 PC513 PC515 PC516 PC531 PC532 PC707 PC751 PC762 PC764 PC811 PC812 PC815-PC818 PC834-PC844 PC865 PC1000-PC1020 PC1023-PC1077 PC1079-PC1099 PC1629 PC1634 PC1636-PC1654 PC1675 PC2027-PC2058 PC2073-PC2080 PC2120 PC2121 PC2208 PC2212 PCA3 PCA4 PCA8-PCA14 PCH1 PCH4 PCH8 PCH13 PCH14 PCH17 PCH20-PCH29 PCH32 PCH33 PCH39 PCH40 PCH44-PCH54 PCT4-PCT14 PCZ1-PCZ10 PCZ12-PCZ33 PCZ35-PCZ39 = P_CAP NP
CV31-CV48 CV601-CV604 CV606-CV619 CV630 = CAP NP: room: HDMI
CV1635 CV1638 = P_CAP NP: room: TOUCH
CZ7 CZ8 CZ10 CZ11 CZ17-CZ21 CZ23-CZ25 CZ150-CZ155 CZ198 = CAP NP: room: WWAN
CZ26 = CAP WP: room: WWAN
CZ37-CZ40 = CAP NP: room: SIM
CZ50-CZ56 CZ75 = CAP NP: room: TPM
CZ82 = CAP NP: room: RSMRST
CZ90-CZ92 CZ309 = CAP NP: room: KBTP
CZ93 = CAP NP: room: LED
CZ101 = CAP NP: room: +1.0V_VCCST
CZ103 CZ104 = CAP NP: room: +VCCPLL_OC
CZ106 = CAP NP: room: +1.0V_VCCSTG
CZ109-CZ111 CZ122 = CAP NP: room: UZ2
CZ112-CZ115 CZ216 CZ217 = CAP NP: room: UZ3
CZ116-CZ119 CZ124 = CAP NP: room: UZ4
CZ120 CZ121 CZ197 CZ305 CZ306 = CAP NP: room: UZ8
DA1-DA3 DA6 DA7 = L03ESDL5V0CC3-2_SOT23-3: room: CODEC
DA4 DA5 DT1-DT3 = P_1N4148WS-7-F_SOD323-2: room: PD
DA8 DH1-DH3 DN1 = RB751S40T1G_SOD523-2: room: KBC
DA9 DA10 DZ10 DZ11 = AZC199-02SPR7G_SOT23-3
DD32 DE43 DT5 DT6 DT9 DT10 DT13 DT14 DT17 DT18 = ESD8011MUT5G_X3DFN2-2
DE1 = P_BZV55-B5V1_SOD80C2
DE2 = RB751S40T1G_SOD523-2: room: RTC_2
DI1 DZ13 = L05ESDL5V0NA-4_SLP2510P8-10-9: room: USB2
DI2 = AZC199-02SPR7G_SOT23-3: room: USB2
DI3 = AZC199-02SPR7G_SOT23-3: room: USB3
DI4 = L05ESDL5V0NA-4_SLP2510P8-10-9: room: USB1
DI5 = AZC199-02SPR7G_SOT23-3: room: USB1
DI6 = L05ESDL5V0NA-4_SLP2510P8-10-9: room: USB3
DT4 = AZ4A24-01F.R7G_DFN0603P2Y2
DT39-DT42 = L05ESDL5V0NA-4_SLP2510P8-10-9: room: JUSB2
DV1-DV3 DZ9 = BAT54CW_SOT323-3~D: room: LCD
DV11 DV12 = RB751S40T1G_SOD523-2: room: GPU
DZ1 DZ2 = RB751S40T1G_SOD523-2: room: WLAN
DZ5 DZ6 = RB751S40T1G_SOD523-2: room: WWAN
DZ8 = RB751S40T1_SOD523-2~D: room: USH
DZ12 = RB751S40T1G_SOD523-2: room: PD
FD1-FD4 = FIDUCIAL MARK: room: LED
FV1 FZ1-FZ5 = 1A_65V_T0603FF1000TM
H1-H4 H7 H8 H10-H13 H15-H20 H22 H23 H25-H27 H30 H32-H37 = HOLE: room: LED
JAPS1 = CVILU_CF4218FH0R0-05-NH_1
JDEG1 JESPI = JXT_FP241AH-010GAAM_0
JDIMM1 JDIMM2 = LOTES_ADDR0206-P001A_0
JEDP1 = ACES_50398-04041-001: room: LCD
JFAN1 = ACES_50271-0040N-001: room: KBC
JFPBTN1 = FOX_QT510166-L010-7H
JHDMI1 = YUQIU_HD074-F19M1BR-C
JHP1 = SINGA_2SJ3095-136111F~D
JIRTS1 = ACES_6
JKBTP1 = HRS_TF31-20S-0P5SH-800_0
JLED1 = HRS_TF31-6S-0P5SH_0
JLOM1 = SINGA_2RJ3081-1C8211F
JNGFF1 = LOTES_APCI0136-P001A_1
JNGFF2 = LOTES_APCI0103-P001A_1
JNGFF3 = LOTES_APCI0079-P005A_1
JRTC1 = TYCO_0
JSATA1 = FOX_GS12206-10100-7H
JSD1 = T-SOL_2
JSIM1 = JAE_SF51S006V4DR1000Q_0
JSPI1 = ACES_50696-0200M-P01: room: SPI ROM
JSPK1 = ACES_50278-00401-001: room: CODEC
JTAG1 = OPEN: User Part Number: PART#; room: KBC
JUSB1-JUSB3 = C-K_26230A-8K1A-02~D
JUSBC1 = JAE_DX07SD24JJ2R1300~D_1
JUSH1 = HRS_TF31C-26S-0P5SH-800
JXDP1 = JXT_FP270H-061G1AM
LA5-LA16 = L: room: CODEC
LC1-LC3 = L: room: PCH
LC562 LH421 LH423 = L: room: SOC
LED3 = LTW-C193DC-C_WHITE: room: LED
LGA1 = LNG2DMTR_LGA12_0: room: HDD
LI3 LI4 LI7 LZ1 = DLM0NSN900HY2D_4P
LI8 LI9 = MCM1012B900F06BP_4P
LI16 LI17 = HCM1012GH900BP_4P
LI49 LI50 = L
LL1 = L: room: LAN
LT1 LT2 = L: room: TBT
LV1 = L: room: LCD
LV3 LV6 LV9 LV12 = MCF12102G900-T_4P: room: HDMI
LV601-LV605 = L: room: GPU
PBATT1 = P_DEREN_1
PC1 PC5 PC7 PC11 PC802 PC803 PC807 PC808 PC810 = P_CAP NP: room: P_DCIN
PC3 PC102 PC111 PC112 PC114 PC119 PC125 PC126 PC128 PC142 PC204 PC205 PC302 PC312 PC314 PC411 PC507 PC508 PC514 PC517 PC719 PC725-PC727 PC736 PC740 PC743-PC750 PC752 PC753 PC755 PC765 PC766 = P_CAP NP: room: CHARGER
PC13 PC754 PC814 PC3005-PC3009 PCZ34 = P_CAP NP: room: CPU_CORE
PC100 PC103 PC115 PC116 PC303 = P_CAP NP: room: 3_5V
PC135-PC138 PC141 PC165 PC166 PC169 PC170 PC202 PC203 PC206-PC213 PC216-PC219 PC221-PC227 PC316 PC410 PC428 PC530 PC738 PC739 PC768 PCH55 PCT16 = P_CAP NP: room: P_1.2V
PC200 PC201 PC427 PC700 PC701 PC737 PC757 PC761 PC767 PC800 PC801 PC804 PC805 PC813 PC3002 = P_CAP NP: room: Charger
PC503 PC505 PC506 PC2211 = P_CAP NP: room: 1.8V
PC702-PC704 PC706 PC708-PC710 PC716 PC717 PC720 PC721 PC741 PC742 PC758 PC763 PC3001 PC3003 PC3004 = P_CAP NP: room: PWR_CHARGER
PC715 PC756 PC848 PC849 PC2060 PC2061 PCA7 PCH5 PCH15 PCH19 PCH36 PCH43 PCT1 PCT15 = P_CAP WP
PC806 PC809 = P_CAP NP: room: P_USBA
PCA1 PCA2 PCH2 PCH3 PCH6 PCH7 PCH11 PCH16 PCH30 PCH31 PCH37 PCH38 PCT2 PCT3 = P_CAP NP: room: P_1.35V0.675V
PD1 PD2 PD4 = TVNST52302AB0_SOT523-3
PD3 = P_BAS40-05W_SC70-3~D
PD5 PD801 = P_PDS5100H-13_POWERDI5-3~D: room: P_Selector
PD700 PD702 = P_SDMK0340L-7-F_SOD323-2~D
PD701 = P_DFLS160-7_POWERDI123-2
PD704 PD706 PD3001 PD3002 = RB520SM-30T2R_EMD2-2
PD705 PD800 PD803 PD3000 = BAT54CW_SOT323~D
PD802 = P_SDMK0340L-7-F_SOD323-2~D: room: P_selector
PHZ1 = P_100K_0402_1%_TSM0B104F4251RZ
PHZ2-PHZ5 = P_220K_0402_5%_ERTJ0EV224J
PJP1 = PAD-OPEN: room: +1.0V_VCCST
PJP2 = PAD-OPEN: room: +1.0V_VCCSTG
PJP3 PJP31 PJP1604 = P_JUMP_43X118: room: +3.3V_RUN_Source
PJP5 = P_JUMP_43X118: room: TBT
PJP6 = PAD-OPEN: room: TBT
PJP8 = PAD-OPEN: room: PD
PJP12 = PAD-OPEN: room: LCD
PJP14 = PAD-OPEN: room: RTS5242
PJP17 PJP40 PJP41 = PAD-OPEN: room: UZ4
PJP18 = PAD-OPEN: room: CODEC
PJP19 PJP36 PJP37 = PAD-OPEN: room: UZ2
PJP20 PJP22 = PAD-OPEN: room: KBC
PJP32-PJP34 = PAD-OPEN: room: HDD
PJP35 = PAD-OPEN: room: KBTP
PJP38 PJP39 = PAD-OPEN: room: UZ3
PJP42 = PAD-OPEN: room: UZ8
PJP100 PJP101 PJP202 PJP301 = VCCPAD: room: DDR_VTT_0.75V
PJP102 PJP103 PJP401 PJP701 = P_JUMP_43X118: room: 1.5V
PJP200 = P_JUMP_43X118: room: P_1.2V
PJP201 = P_JUMP_43X39: room: P_1.2V
PJP302 PJPA1 PJPT1 = P_JUMP_43X118
PJP403 PJP501-PJP506 = PAD-OPEN: room: VGA_CORE
PJP700 = PAD-OPEN: room: Charger
PJPDC1 = P_CVILU_CI0805M1HRC-NH_4
PL1-PL3 = P_L: room: P_DCIN
PL4 PL5 PLH11-PLH13 = P_L: room: PWR_SUPPORT
PL100 PL201 PL301 PL402 PL501 PL700 PL701 PL800 PL801 = P_L
PL101 = P_L: room: VDDCI
PLA1 = P_0.47UH_MMD05CZR47M_12A_20%
PLH1-PLH4 PLT1 = P_L_4P
PQ1 PQ10 PQ802 PQ804 PQ806 PQ813 = P_DMN65D8LDW-7_SOT363-6
PQ2 = P_FDV301N_NL_SOT23-3~D: room: P_DCIN
PQ3 = MMST3904-7-F_SOT323~D: room: P_DCIN
PQ4 = P_AON7409_DFN8-5_2
PQ5 PQ11 PQ803 PQ805 = NTR4502PT1G_SOT23-3: room: P_Charger
PQ6-PQ8 PQ12 PQ807 PQ812 PQ814 = DMN65D8LW-7_SOT323-3
PQ9 = P_DFN33-P_TR_1
PQ13 = P_L2N7002WT1G_SC70-3
PQ700 = P_DFN56-N_TR_2
PQ701 = P_AOE6930_DFN5X6E8-10_0
PQ702 = P_AON7409_DFN8-5_1
PQ703 = P_RHU002N06_SOT323-3~D
PQ704 = P_DFN56-N_TR_1
PQ800 = P_DFN33-P_TR_0
PQ801 = P_AON7409_DFN8-5_5
PQ808-PQ811 = P_DMN66D0LDW-7_SOT363-6: room: P_USBB
PQ3000 = P_L2N7002DW1T1G_SC88-6
PR1-PR8 PR11 PR13 PR14 PR16 PR24 PR27 PR41 PR43 PR511 PR804 PR819 PR821 PR823 PR831 PR856 PR857 PR862 PR866 PR870-PR872 PR1616-PR1627 RZ1406 = P_R: room: P_DCIN
PR9 PR100 PR111 PR114 PR308 PR412 PR422 PR512 PR745 PR746 PR3001 PR3006 RC140 RC141 RC221 RE79 RE300 RE362 RE731 RH361 RH376 RI27-RI30 RI47 RI48 RT190-RT197 RT219-RT222 RT398 RT399 RT440 RT447 RT482 RT483 RT488-RT491 RT503 RV732 RZ22 RZ23 RZ70 RZ89 RZ128-RZ130 RZ334 RZ372-RZ374 RZ1407 RZ1409 RZ1410 RZ1489 = R
PR10 PR15 PR17 PR28 PR33 PR45 PR705 PR706 PR801 PR802 PR806-PR808 PR810-PR813 PR822 PR824 PR825 PR828 PR830 PR833 PR838 PR839 PR846 PR851 PR852 PR855 = P_R: room: P_Selector
PR12 PR18 PR31 PR32 PR202-PR204 PR206 PR209 PR212 PR517 PR739 PR744 = P_R: room: P_1.2V
PR19 PR20 PR22 PR25 PR42 PR44 PR46 PR47 PR49 PR104 PR105 PR119 PR120 PR709 PR713 PR715 PR719 PR721 PR722 PR727 PR729 PR731 PR736 PR737 PR740 PR741 PR743 PR814 PR816 PR818 PR820 PR826 PR827 PR829 PR836 PR840 PR844 PR853 PR854 PR858 PR859 PR861 PR1649 PR1651 PR1652 PRZ11 PRZ13 PRZ21 PRZ27 PRZ28 PRZ30 PRZ31 PRZ38 PRZ78 PRZ79 = P_R-SHORT
PR38-PR40 PR102 PR108 PR116 PR117 PR205 PR207 PR208 PR210 PR302-PR304 PR306 PR311 PR312 PR402-PR404 PR421 PR425 PR429 PR504 PR509 PR510 PR513-PR516 PR701-PR703 PR712 PR717 PR718 PR720 PR725 PR726 PR728 PR733-PR735 PR800 PR809 PR815 PR817 PR832 PR835 PR842 PR843 PR865 PR1648 PR1650 PR1708 PR3002-PR3005 PR3007-PR3013 PRA1-PRA3 PRH1-PRH16 PRT1-PRT4 PRZ1 PRZ3-PRZ9 PRZ12 PRZ14-PRZ20 PRZ22-PRZ24 PRZ26 PRZ29 PRZ32 PRZ37 PRZ39-PRZ77 PRZ80-PRZ83 RH618 RZ335 RZ1413 RZ1482 = P_R
PR103 = P_R: room: 3_5V
PR106 PR112 = P_R: room: 1.5V
PR107 PR113 PR307 PR310 PR1711-PR1713 = P_R: room: 1P5V
PR405 PR501 PR502 PR505 PR506 = P_R: room: 1.8V
PR413-PR416 PR708 PR710 PR716 PR724 PR805 = P_R: room: Charger
PR700 PR711 = P_R~D: room: CHARGER
PR704 PR707 PR714 PR723 PR738 = P_R: room: CHARGER
PR803 = P_R: room: P_selector
PR834 PR841 PR845 = P_R: room: P_USBB
PU2 = AP2204R-5.0TRG1_SOT89-3
PU3 PU801 = TC7SH08FU_SSOP5~D: room: PCH
PU100 = P_SY8288BRAC_QFN20_0
PU102 = P_SY8288CRAC_QFN20_1
PU200 = P_SY8210AQVC_QFN19_4X3: room: P_1.2V
PU301 = P_SY8288RAC_QFN20_1
PU401 = P_SY8057BQDC_QFN16_0
PU501 = P_RT8097ALGE_SOT23-6
PU502 = P_EM1109V-AD_DFN3308-8_0
PU503 = P_EM1109V-AD_DFN3308-8_1
PU700 = P_ISL88738HRTZ-T_TQFN32_4X4
PU701 = SN74AHC1G08DCKR_SC70-5
PU800 = P_AS393MMTR-G1_MSOP8
PU3000 = P_AZV3002RL-7_U-FLGA8_1P65X1P65
PUA1 PUH1-PUH4 PUT1 = P_NCP302045MNTWG_PQFN33_5X5
PUZ1 = P_NCP81215MNTXG_QFN52_6X6
QE2 QZ17 QZ18 = DMN65D8LDW-7_SOT363-6
QE3-QE7 QV19 QV21 QZ21 = LMBT3904WT1G_SC70-3
QE11 QE12 QE20 QN6 QZ15 QZ19 QZ24 = L2N7002WT1G_SC-70-3
QE15 = LP2301ALT1G_SOT23-3: room: RTC_2
QE17 = L2N7002WT1G_SC-70-3: room: RTC_2
QH4 = DMN65D8LDW-7_SOT363-6: room: PCH
QH6 = L2N7002WT1G_SC-70-3: room: DSW_2
QH7 = LP2301ALT1G_SOT23-3: room: DSW_2
QH8 = DMN66D0LDW-7_SOT363-6~D: room: CPU
QI2 = L2N7002WT1G_SC-70-3: room: USB1
QL1 = P_DMN66D0LDW-7_SOT363-6~D: room: LAN
QN1 = P_DMN66D0LDW-7_SOT363-6~D: room: HDD
QR1 = L2N7002WT1G_SC-70-3: room: RTS5242
QT1 = DMN66D0LDW-7_SOT363-6~D: room: PD
QV1 = P_AO6405_TSOP6_0: room: LCD
QV2 = L2N7002WT1G_SC-70-3: room: LCD
QV7 = L2N7002WT1G_SC-70-3: room: TOUCH
QV8 = LP2301ALT1G_SOT23-3: room: TOUCH
QV18 QV20 = MMBT3906H_SOT23-3
QZ1 QZ38 = LP2301ALT1G_SOT23-3: room: CAMERA
QZ3 = DDTA144VCA-7-F_SOT23-3
QZ7 = P_DMN66D0LDW-7_SOT363-6~D: room: LED
QZ8 = L2N7002WT1G_SC-70-3: room: SIO
RA3 RA35-RA37 RA48 RA53 = R-SHORT: room: CODEC
RA5-RA9 RA12-RA14 RA17 RA18 RA44 RA45 RA51 RA52 RA59 RA60 RH97 = R: room: CODEC
RA50 RA54 RA57 RA58 = R: room: UZ8
RC1 RC2 RC5-RC7 RC66 RC71 RC74 RC78-RC80 RC83 RC84 RC114 RC152 RC153 RC157 RC166 RC168 RC171 RC177 RC181 RC239 RC240 RC321-RC325 RC370 RC436-RC443 RC557-RC561 RC834 RC840 RE95 RE349 RE529 RE716-RE718 RH1 RH104 RH152 RH156 RH267 RH268 RH311 RH355 RH379 RH435 RH436 RH625 RH649-RH652 RV7 RV98 RV99 RV319 RV324 RV326 RV623-RV627 RV629-RV631 RV1657 RZ20 RZ21 RZ86 RZ87 RZ133 RZ151 RZ1392 RZ1396 RZ1403 RZ1404 RZ1450 RZ1480 RZ1481 RZ1483 = R: room: CPU
RC75 = R: room: RSMRST
RC115 RC121 RC122 RC124 RC126-RC129 RC132 RC133 RC135-RC139 RC144 RC217-RC219 RC241 = R: room: CPU XDP
RC143 RC169 RC216 RC228-RC230 RC314 RC315 RC319 = R-SHORT: room: CPU XDP
RC178 RC179 RC326 = R-SHORT: room: CPU
RC304 = R-SHORT: room: +1.0V_VCCST
RC366-RC369 RE509 RH43 RH62 RH66 RH100 RH161 RH166-RH170 RH187 RH215 RH237 RH240 RH242 RH246 RH256-RH260 RH286-RH288 RH290 RH292-RH294 RH297-RH300 RH302-RH306 RH365 RH440 RH442 RH445 RH616 RH620 RH663 RN129 RZ580 = R-SHORT: room: PCH
RC422 = R: room: Other
RC756 RH38 RH39 RH42 RH44-RH46 RH48 RH50 RH56 RH57 RH61 RH67 RH70 RH73-RH78 RH80 RH81 RH83 RH86 RH90 RH92-RH95 RH101 RH110 RH123-RH127 RH131-RH133 RH153 RH192 RH193 RH198-RH201 RH203 RH204 RH214 RH221-RH225 RH238 RH239 RH241 RH243 RH247 RH250 RH254 RH255 RH279 RH289 RH291 RH295 RH296 RH308-RH310 RH316-RH319 RH323-RH326 RH328 RH329 RH331 RH339 RH340 RH344 RH345 RH348 RH364 RH373 RH377 RH378 RH402 RH424 RH600-RH602 RH609-RH615 RH617 RH619 RH641-RH648 RH661 RH662 RH868 RZ1399 RZ1405 RZ1485 = R: room: PCH
RC841-RC847 RE31 RE33 RE37 RE43 RE48 RE51 RE55-RE58 RE60 RE63-RE65 RE67-RE75 RE77 RE86 RE280 RE288 RE292 RE301-RE304 RE306 RE312-RE314 RE342 RE343 RE536 RE551 RE702 RE706-RE708 RE712-RE715 RE826-RE828 RH154 RH155 RH371 RH372 RH400 RH401 RH441 RH553-RH556 RH603-RH608 RZ542 RZ543 RZ1382 RZ1384 = R: room: KBC
RC866 RE5 RE8 RE10-RE12 RE20 RE21 RE25 RE26 RE35 RE83-RE85 RE91-RE94 RE274 RE324 RE340 RE365 RE505 RE507 RE508 RE524-RE526 RE532 RE549 RE550 RE561 RE605 RE606 RE704 RE721-RE730 RE821 RE825 = R: room: SIO
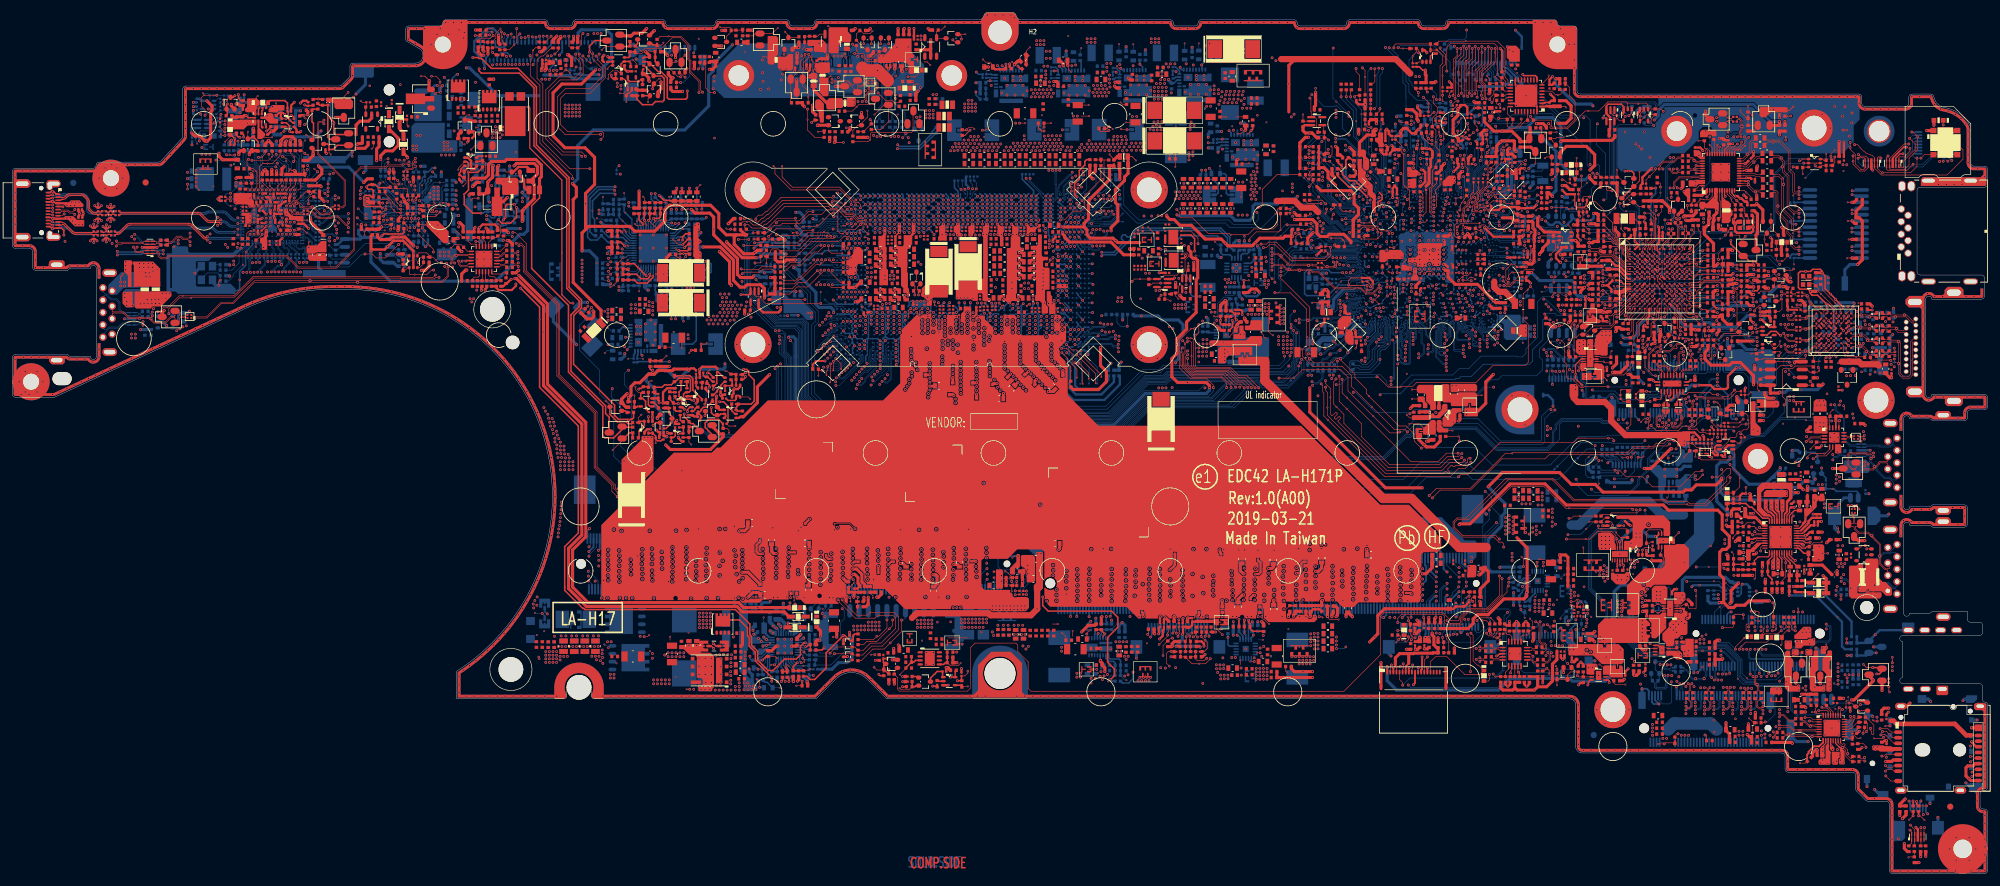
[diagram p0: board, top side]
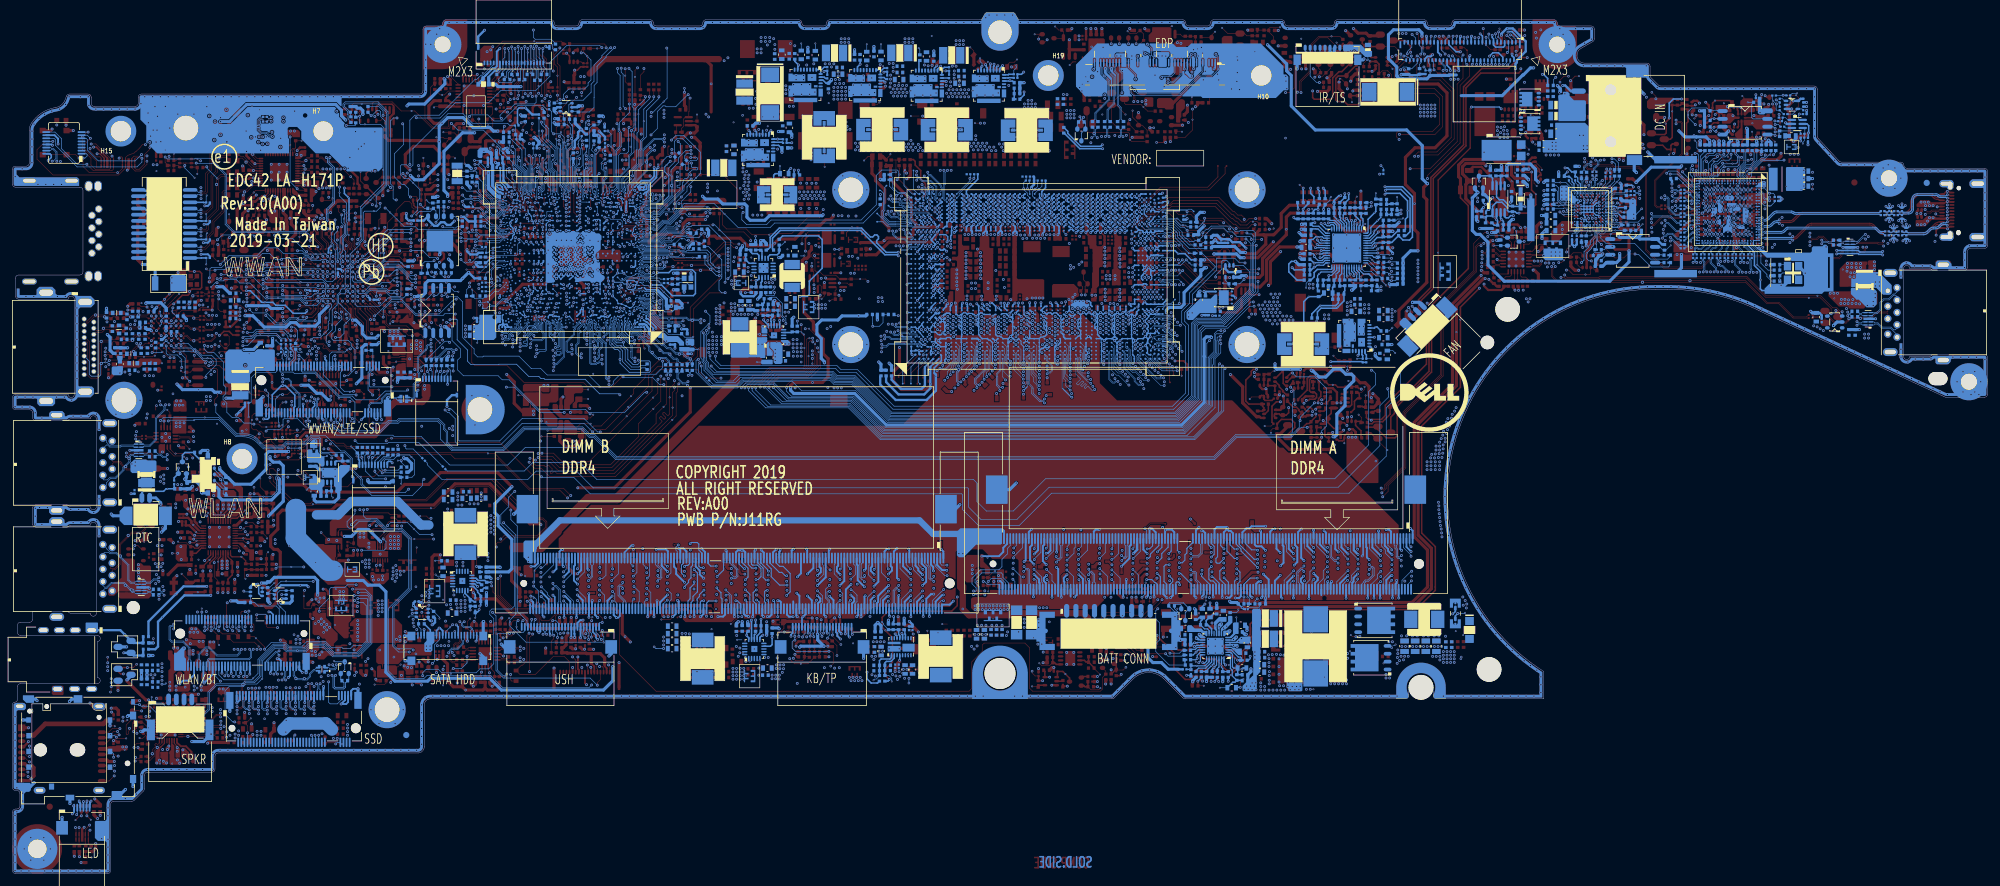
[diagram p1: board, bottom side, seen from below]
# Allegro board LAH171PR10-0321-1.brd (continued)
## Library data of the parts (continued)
RD4 RD6 RD8 RD11 RD14-RD20 RD23 RD24 RD27-RD31 = R: room: MEMORY
RD5 RD7 RD9 RD10 RD12 RD21 RD22 RD25 RD26 = R-SHORT: room: MEMORY
RE30 RE90 RE275 = R-SHORT: room: SIO
RE32 RE59 RE100 RE290 RE318 RE506 RE548 RE703 RH10 RH11 RH13-RH16 RT63 RT104 RT105 RT400 RT401 RZ350 RZ351 RZ1393-RZ1395 RZ1398 RZ1401 RZ1475 = R-SHORT: room: KBC
RE350 RE539 RH28-RH30 RH177-RH185 RH334 RH335 RH351-RH353 RH653-RH660 RZ58-RZ60 = R: room: SPI ROM
RE541 RE543 RE546 = R: room: RTC_2
RE565 RH566 RR274 RT48 RT120-RT123 RT441 RT448 RT456 RT499-RT501 RV628 RV733 RV1400 RZ61 RZ64 RZ112 RZ114 RZ345 RZ1380 RZ1402 RZ1408 RZ1411 RZ1415 RZ1487 RZ1488 = R-SHORT
RH37 = R-SHORT: room: SPI ROM
RH65 RZ1397 = R: room: RTC_1
RH312-RH315 RH333 RH374 RH626-RH637 RH640 RZ1400 = R: room: PCH XDP
RH431-RH434 RH439 = R: room: DSW_2
RI13 RI14 RI59-RI78 = R: room: USB1
RL1 RL2 RL4-RL6 RL9 RL11-RL19 RL29 RL71-RL78 = R: room: LAN
RL3 RL7 RL8 RL20 RL34 = R-SHORT: room: LAN
RN1-RN21 RN226 = R: room: HDD
RN37 = R: room: SATA EXPRESS
RN99 = R-SHORT: room: SATA EXPRESS
RN227 RV323 RZ120 = R-SHORT: room: +VCC_SFR_OC
RR3 RR4 RR19 = R: room: RTS5242
RR5-RR10 = R-SHORT: room: RTS5242
RT1-RT8 RT10-RT42 RT49 RT124-RT129 RT184 RT336-RT339 RT371 RT372 RT391 RT394 RT455 RZ1486 = R: room: TBT
RT9 RT392 = R-SHORT: room: TBT
RT50-RT53 RT66-RT69 RT71 RT74-RT76 RT81 RT82 RT84-RT86 RT95-RT98 RT100 RT101 RT103 RT106 RT107 RT110 RT111 RT377 RT393 = R: room: PD
RT54-RT60 RT70 RT72 RT73 RT83 RT87 RT88 RT92 RT93 RT99 RT108 RT109 = R-SHORT: room: PD
RT64 RT65 RT89 RT90 RT402 RT403 RT445 RT502 RT554 RT555 RZ1388 RZ1389 RZ1471 = R: room: AR
RV1-RV5 = R: room: LCD
RV6 RV8 RV9 = R: room: TOUCH
RV22-RV35 RV38 RV601-RV611 RV615-RV619 = R: room: HDMI
RV614 = R-SHORT: room: HDMI
RZ8-RZ10 RZ1414 RZ1473 = R: room: USH
RZ18 RZ19 RZ116 RZ117 = R: room: KBTP
RZ25 RZ28 RZ32 RZ361 = R: room: LED
RZ26 RZ29 RZ346 RZ347 = R-SHORT: room: KBTP
RZ38 RZ71 = R: room: UZ2
RZ40 RZ1472 RZ1474 = R: room: UZ4
RZ43 RZ63 RZ69 RZ362 RZ376-RZ379 RZ381 RZ400 RZ518 RZ1484 = R: room: TPM
RZ56 = R-SHORT: room: WLAN
RZ78-RZ80 RZ1381 RZ1383 = R: room: WLAN
RZ119 = R: room: +VCCPLL_OC
RZ132 RZ326 RZ360 = R: room: WWAN
RZ320 = R: room: +1.0V_VCCSTG
RZ401 = R: room: GPU
RZ1390 RZ1391 = R: room: CAMERA
SHDCAN = SION_C7521R_1P-T
SW1 = SSAJ120100_3P
SW3 = SKRBAAE010_4P: room: LED
T1-T15 T18-T38 T40-T49 T284 T285 T300 T301 T424 = PAD_1: room: CPU
T50-T53 T425 = PAD_9: room: MEMORY
T60-T63 = PAD_1: room: PCH
T66-T77 T179-T192 T194 T199 T258 T268 T286 T287 T302 T418 T421-T423 = PAD_0: room: CPU
T88 T89 = PAD_1: room: LAN
T419 = PAD_0: room: LAN
TL1 = 350UH_IH-160: room: LAN
UA1 = ALC3204-CG_MQFN40_5X5
UC1 = CFL-H_BGA1440: room: CPU
UC3 = 74AHC1G09GW_TSSOP5: room: PCH
UC5 = W25Q256FVEIQ_WSON8_8X6
UC6 = W25Q128JVSIQ_SO8
UD1 = 74AUP1G07GW_TSSOP5: room: MEMORY
UE1 = MEC5105_WFBGA169_0
UE3 UE5 = TC7SH08FU_SSOP5~D: room: CPU
UE4 UZ61 = 74AUP1G07GW_TSSOP5
UH1 = CNP-H_BGA874_0: room: PCH
UH7 = TC7SH08FU_SSOP5: room: PCH
UI1 = SY6288D20AAC_SOT23-5: room: USB2
UI2 = SY6288D20AAC_SOT23-5: room: USB3
UI3 = SLGC55544CVTR_TQFN16_3X3: room: USB1
UI6 = PS8713BTQFN24GTR2_TQFN24_0: room: USB1
UL1 = WGI217LM-QPN9-A2_QFN48_6X6~D: room: LAN
UN7 = PI3EQX6741STZDEX_TQFN20_0: room: HDD
UR1 = RTS5242-GR_QFN32_4X4: room: RTS5242
UT1 = ALPINE-RIDGE_BGA337: room: TBT
UT2 = W25Q80DVSSIG_SO8: room: TBT
UT5 = TPS65982_BGA96_2: room: PD
UT6 = W25Q80DVSSIG_SO8: room: PD
UT7 = AP2112K-3.3TRG1_SOT23-5: room: PD
UT8 = AP2204R-5.0TRG1_SOT89-3: room: PD
UT32 = TS5A3159ADCKR_SC70-6
UT34 = TC7SH08FU_SSOP5~D: room: +1.0V_VCCSTG
UV2 = AP2330W-7_SC59-3: room: HDMI
UV24 = G524B1T11U_SOT23-5: room: LCD
UV31 = PS175HDMBGA64GTR2-B1_TFBGA64_0
UV32 = W25X20CLSNIG_SO8
UZ2 = TPS22966DPUR_SON14_0: room: UZ2
UZ3 = TPS22966DPUR_SON14_0: room: UZ3
UZ4 = TPS22966DPUR_SON14_0: room: UZ4
UZ6 = TC7SH08FU_SSOP5~D: room: RSMRST
UZ8 = AOZ1336_DFN8_0: room: UZ8
UZ10 = TC7SH08FU_SSOP5~D: room: LED
UZ12 = ST33HTPH2E32AHB4_VQFN32_5X5
UZ19 UZ21 UZ26 = AOZ1334DI-01_DFN8-7_3X3: room: +1.0V_VCCSTG
UZ23 = AOZ1336_DFN8_0: room: HDD
UZ29 = PI3PCIE3212ZBEX_TQFN20_0: room: WWAN
UZ34 = TC7SH08FU_SSOP5: room: +VCCPLL_OC
UZ35 = SN74AHC1G08DCKR_SC70-5: room: +1.0V_VCCSTG
UZ51 = SN74LVC1G3157DCKR_SC70-6
UZ52 = SN74AUP1T97YZPR_DSBGA6~D
UZ53 = AOZ1336_DFN8_1: room: UZ8
UZ54 = MC74VHC1G32DFT2G_SC70-5~D
YE1 = 32.768KHZ_9PF_X1A000141000200
YH1 = 32.768KHZ_12.5PF_9H03200042: room: PCH
YH2 = 24MHZ_12PF_8Y24000034
YL1 = 25MHZ_20PF_XRCGB25M000F2P18R0_0
YT1 = 25MHZ_18PF_0: room: TBT
YV6 = 27MHZ_10PF_XRCGB27M000F2P18R0_0

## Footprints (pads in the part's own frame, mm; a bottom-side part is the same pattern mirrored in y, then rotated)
1N4148WS-7-F_SOD323-2
  rect 1.346x0.66 smd: 1(0,0) 2(2.4,0)
5A_Z80_0805_2P
  rect 0.813x1.397 smd: 1(0,0) 2(1.702,0)
74AHC1G09GW_TSSOP5
  oval 0.381x1.346 smd: 1(0,0) 2(0.65,0) 3(1.3,0) 4(1.3,1.79) 5(0,1.79)
74AUP1G07GW_TSSOP5
  oval 0.381x1.346 smd: 1(0,0) 2(0.65,0) 3(1.3,0) 4(1.3,1.79) 5(0,1.79)
ACES_50208-01001-P03_10P
  oval 0.508x0.991 smd: 1(0,0) 2(0.8,0) 3(1.6,0) 4(2.4,0) 5(3.2,0) 6(4,0) 7(4.8,0) 8(5.6,0) 9(6.4,0) 10(7.2,0)
  rect 1.194x1.702 smd: 11(-1.3,-1.95) 12(8.5,-1.95)
ACES_50271-0020N-001_2P-S
  oval 0.787x1.6 smd: 1(0,0) 2(1.25,0)
  rect 2.108x2.997 smd: 3(3.8,-2.9)
  custom 0.527x0.527 smd: 4(-2.55,-2.9)
ACES_50271-0040N-001_4P
  oval 0.787x1.6 smd: 1(0,0) 2(-1.25,0) 3(-2.5,0) 4(-3.75,0)
  rect 2.108x2.997 smd: 5(2.55,-2.9) 6(-6.3,-2.9)
ACES_50278-00401-001_4P
  oval 0.787x1.905 smd: 1(0,0) 2(1.25,0) 3(2.5,0) 4(3.75,0)
  rect 1.295x3.353 smd: 5(-2.85,-4.925) 6(6.6,-4.925)
ACES_50398-04041-001_40P
  oval 0.254x1.295 smd: 1(0,0) 2(0.5,0) 3(1,0) 4(1.5,0) 5(2,0) 6(2.5,0) 7(3,0) 8(3.5,0) 9(4,0) 10(4.5,0) 11(5,0) 12(5.5,0) 13(6,0) 14(6.5,0) 15(7,0) 16(7.5,0) 17(8,0) 18(8.5,0) 19(9,0) 20(9.5,0) 21(10,0) 22(10.5,0) 23(11,0) 24(11.5,0) 25(12,0) 26(12.5,0) 27(13,0) 28(13.5,0) 29(14,0) 30(14.5,0) 31(15,0) 32(15.5,0) 33(16,0) 34(16.5,0) 35(17,0) 36(17.5,0) 37(18,0) 38(18.5,0) 39(19,0) 40(19.5,0)
  rect 1.194x3.2 smd: 41(-2.4,1.95) 45(21.9,1.95)
  rect 2.311x1.295 smd: 42(0.85,3.9) 43(9.75,3.9) 44(18.65,3.9)
ACES_50696-0200M-P01_20P
  oval 0.305x0.787 smd: 1(0,0) 2(-0.5,0) 3(-1,0) 4(-1.5,0) 5(-2,0) 6(-2.5,0) 7(-3,0) 8(-3.5,0) 9(-4,0) 10(-4.5,0) 11(-5,0) 12(-5.5,0) 13(-6,0) 14(-6.5,0) 15(-7,0) 16(-7.5,0) 17(-8,0) 18(-8.5,0) 19(-9,0) 20(-9.5,0)
  rect 0.406x0.787 smd: 21(1,-2.5) 22(-10.5,-2.5)
ALC3204-CG_MQFN40_5X5
  oval 0.889x0.203 smd: 1(0,0) 2(0,-0.4) 3(0,-0.8) 4(0,-1.2) 5(0,-1.6) 6(0,-2) 7(0,-2.4) 8(0,-2.8) 9(0,-3.2) 10(0,-3.6) 21(5.1,-3.6) 22(5.1,-3.2) 23(5.1,-2.8) 24(5.1,-2.4) 25(5.1,-2) 26(5.1,-1.6) 27(5.1,-1.2) 28(5.1,-0.8) 29(5.1,-0.4) 30(5.1,0)
  oval 0.203x0.889 smd: 11(0.75,-4.35) 12(1.15,-4.35) 13(1.55,-4.35) 14(1.95,-4.35) 15(2.35,-4.35) 16(2.75,-4.35) 17(3.15,-4.35) 18(3.55,-4.35) 19(3.95,-4.35) 20(4.35,-4.35) 31(4.35,0.75) 32(3.95,0.75) 33(3.55,0.75) 34(3.15,0.75) 35(2.75,0.75) 36(2.35,0.75) 37(1.95,0.75) 38(1.55,0.75) 39(1.15,0.75) 40(0.75,0.75)
  rect 3.607x3.607 smd: 41(2.55,-1.8)
ALPINE-RIDGE_BGA_337P
  round 0.254 smd: A1(0,0) A23(10.12,0) AA2(0.46,-9.2) AA22(9.66,-9.2) AB2(0.46,-9.66) AB3(0.92,-9.66) AB4(1.38,-9.66) AB5(1.84,-9.66) AB6(2.3,-9.66) AB7(2.76,-9.66) AB8(3.22,-9.66) AB9(3.68,-9.66) AB10(4.14,-9.66) AB11(4.6,-9.66) AB12(5.06,-9.66) AB13(5.52,-9.66) AB14(5.98,-9.66) AB15(6.44,-9.66) AB16(6.9,-9.66) AB17(7.36,-9.66) AB18(7.82,-9.66) AB19(8.28,-9.66) AB20(8.74,-9.66) AB21(9.2,-9.66) AB22(9.66,-9.66) AC1(0,-10.12) AC23(10.12,-10.12) B2(0.46,-0.46) B3(0.92,-0.46) B4(1.38,-0.46) B5(1.84,-0.46) B6(2.3,-0.46) B7(2.76,-0.46) B8(3.22,-0.46) B9(3.68,-0.46) B10(4.14,-0.46) B11(4.6,-0.46) B12(5.06,-0.46) B13(5.52,-0.46) B14(5.98,-0.46) B15(6.44,-0.46) B16(6.9,-0.46) B17(7.36,-0.46) B18(7.82,-0.46) B19(8.28,-0.46) B20(8.74,-0.46) B21(9.2,-0.46) B22(9.66,-0.46) C2(0.46,-0.92) C22(9.66,-0.92) D2(0.46,-1.38) D4(1.16,-1.16) D5(1.81,-1.16) D6(2.46,-1.16) D8(3.11,-1.16) D9(3.76,-1.16) D11(4.41,-1.16) D12(5.06,-1.16) D13(5.71,-1.16) D15(6.36,-1.16) D16(7.01,-1.16) D18(7.66,-1.16) D19(8.31,-1.16) D20(8.96,-1.16) D22(9.66,-1.38) E2(0.46,-1.84) E4(1.16,-1.81) E5(1.81,-1.81) E6(2.46,-1.81) E8(3.11,-1.81) E9(3.76,-1.81) E11(4.41,-1.81) E12(5.06,-1.81) E13(5.71,-1.81) E15(6.36,-1.81) E16(7.01,-1.81) E18(7.66,-1.81) E19(8.31,-1.81) E20(8.96,-1.81) E22(9.66,-1.84) F2(0.46,-2.3) F4(1.16,-2.46) F5(1.81,-2.46) F6(2.46,-2.46) F8(3.11,-2.46) F9(3.76,-2.46) F11(4.41,-2.46) F12(5.06,-2.46) F13(5.71,-2.46) F15(6.36,-2.46) F16(7.01,-2.46) F18(7.66,-2.46) F19(8.31,-2.46) F20(8.96,-2.46) F22(9.66,-2.3) G2(0.46,-2.76) G22(9.66,-2.76) H2(0.46,-3.22) H4(1.16,-3.11) H5(1.81,-3.11) H6(2.46,-3.11) H8(3.11,-3.11) H9(3.76,-3.11) H11(4.41,-3.11) H12(5.06,-3.11) H13(5.71,-3.11) H15(6.36,-3.11) H16(7.01,-3.11) H18(7.66,-3.11) H19(8.31,-3.11) H20(8.96,-3.11) H22(9.66,-3.22) J2(0.46,-3.68) J4(1.16,-3.76) J5(1.81,-3.76) J6(2.46,-3.76) J8(3.11,-3.76) J9(3.76,-3.76) J11(4.41,-3.76) J12(5.06,-3.76) J13(5.71,-3.76) J15(6.36,-3.76) J16(7.01,-3.76) J18(7.66,-3.76) J19(8.31,-3.76) J20(8.96,-3.76) J22(9.66,-3.68) K2(0.46,-4.14) K22(9.66,-4.14) L2(0.46,-4.6) L4(1.16,-4.41) L5(1.81,-4.41) L6(2.46,-4.41) L8(3.11,-4.41) L9(3.76,-4.41) L11(4.41,-4.41) L12(5.06,-4.41) L13(5.71,-4.41) L15(6.36,-4.41) L16(7.01,-4.41) L18(7.66,-4.41) L19(8.31,-4.41) L20(8.96,-4.41) L22(9.66,-4.6) M2(0.46,-5.06) M4(1.16,-5.06) M5(1.81,-5.06) M6(2.46,-5.06) M8(3.11,-5.06) M9(3.76,-5.06) M11(4.41,-5.06) M12(5.06,-5.06) M13(5.71,-5.06) M15(6.36,-5.06) M16(7.01,-5.06) M18(7.66,-5.06) M19(8.31,-5.06) M20(8.96,-5.06) M22(9.66,-5.06) N2(0.46,-5.52) N4(1.16,-5.71) N5(1.81,-5.71) N6(2.46,-5.71) N8(3.11,-5.71) N9(3.76,-5.71) N11(4.41,-5.71) N12(5.06,-5.71) N13(5.71,-5.71) N15(6.36,-5.71) N16(7.01,-5.71) N18(7.66,-5.71) N19(8.31,-5.71) N20(8.96,-5.71) N22(9.66,-5.52) P2(0.46,-5.98) P22(9.66,-5.98) R2(0.46,-6.44) R4(1.16,-6.36) R5(1.81,-6.36) R6(2.46,-6.36) R8(3.11,-6.36) R9(3.76,-6.36) R11(4.41,-6.36) R12(5.06,-6.36) R13(5.71,-6.36) R15(6.36,-6.36) R16(7.01,-6.36) R18(7.66,-6.36) R19(8.31,-6.36) R20(8.96,-6.36) R22(9.66,-6.44) T2(0.46,-6.9) T4(1.16,-7.01) T5(1.81,-7.01) T6(2.46,-7.01) T8(3.11,-7.01) T9(3.76,-7.01) T11(4.41,-7.01) T12(5.06,-7.01) T13(5.71,-7.01) T15(6.36,-7.01) T16(7.01,-7.01) T18(7.66,-7.01) T19(8.31,-7.01) T20(8.96,-7.01) T22(9.66,-6.9) U2(0.46,-7.36) U22(9.66,-7.36) V2(0.46,-7.82) V4(1.16,-7.66) V5(1.81,-7.66) V6(2.46,-7.66) V8(3.11,-7.66) V9(3.76,-7.66) V11(4.41,-7.66) V12(5.06,-7.66) V13(5.71,-7.66) V15(6.36,-7.66) V16(7.01,-7.66) V18(7.66,-7.66) V19(8.31,-7.66) V20(8.96,-7.66) V22(9.66,-7.82) W2(0.46,-8.28) W4(1.16,-8.31) W5(1.81,-8.31) W6(2.46,-8.31) W8(3.11,-8.31) W9(3.76,-8.31) W11(4.41,-8.31) W12(5.06,-8.31) W13(5.71,-8.31) W15(6.36,-8.31) W16(7.01,-8.31) W18(7.66,-8.31) W19(8.31,-8.31) W20(8.96,-8.31) W22(9.66,-8.28) Y2(0.46,-8.74) Y4(1.16,-8.96) Y5(1.81,-8.96) Y6(2.46,-8.96) Y8(3.11,-8.96) Y9(3.76,-8.96) Y11(4.41,-8.96) Y12(5.06,-8.96) Y13(5.71,-8.96) Y15(6.36,-8.96) Y16(7.01,-8.96) Y18(7.66,-8.96) Y19(8.31,-8.96) Y20(8.96,-8.96) Y22(9.66,-8.74)
  oval 0.178x0.33 smd: A2(0.46,0) A3(0.92,0) A4(1.38,0) A5(1.84,0) A6(2.3,0) A7(2.76,0) A8(3.22,0) A9(3.68,0) A10(4.14,0) A11(4.6,0) A12(5.06,0) A13(5.52,0) A14(5.98,0) A15(6.44,0) A16(6.9,0) A17(7.36,0) A18(7.82,0) A19(8.28,0) A20(8.74,0) A21(9.2,0) A22(9.66,0) AC2(0.46,-10.12) AC3(0.92,-10.12) AC4(1.38,-10.12) AC5(1.84,-10.12) AC6(2.3,-10.12) AC7(2.76,-10.12) AC8(3.22,-10.12) AC9(3.68,-10.12) AC10(4.14,-10.12) AC11(4.6,-10.12) AC12(5.06,-10.12) AC13(5.52,-10.12) AC14(5.98,-10.12) AC15(6.44,-10.12) AC16(6.9,-10.12) AC17(7.36,-10.12) AC18(7.82,-10.12) AC19(8.28,-10.12) AC20(8.74,-10.12) AC21(9.2,-10.12) AC22(9.66,-10.12)
  oval 0.33x0.178 smd: AA1(0,-9.2) AA23(10.12,-9.2) AB1(0,-9.66) AB23(10.12,-9.66) B1(0,-0.46) B23(10.12,-0.46) C1(0,-0.92) C23(10.12,-0.92) D1(0,-1.38) D23(10.12,-1.38) E1(0,-1.84) E23(10.12,-1.84) F1(0,-2.3) F23(10.12,-2.3) G1(0,-2.76) G23(10.12,-2.76) H1(0,-3.22) H23(10.12,-3.22) J1(0,-3.68) J23(10.12,-3.68) K1(0,-4.14) K23(10.12,-4.14) L1(0,-4.6) L23(10.12,-4.6) M1(0,-5.06) M23(10.12,-5.06) N1(0,-5.52) N23(10.12,-5.52) P1(0,-5.98) P23(10.12,-5.98) R1(0,-6.44) R23(10.12,-6.44) T1(0,-6.9) T23(10.12,-6.9) U1(0,-7.36) U23(10.12,-7.36) V1(0,-7.82) V23(10.12,-7.82) W1(0,-8.28) W23(10.12,-8.28) Y1(0,-8.74) Y23(10.12,-8.74)
AO3409_SOT23-3
  oval 1.016x1.524 smd: 1(0,0) 2(0.965,2.083) 3(-0.965,2.083)
AO6405_TSOP6
  oval 0.508x1.473 smd: 1(0,0) 2(0.95,0) 3(1.9,0) 4(1.9,2.35) 5(0.95,2.35) 6(0,2.35)
AOE6930_DFN5X6E8-10
  rect 0.61x0.61 smd: 1(0,0) 2(1.27,0) 3(2.54,0) 4(3.81,0) 5(3.81,5.5) 6(2.54,5.5) 7(1.27,5.5)
  rect 0.61x1.676 smd: 8(0,4.96)
  rect 4.191x1.041 smd: 9(1.905,1.215)
  custom 0.617x0.617 smd: 10(1.905,3.465)
AOZ1334DI-01_DFN8-7_3X3
  oval 0.305x0.406 smd: 1(0,0) 2(0.65,0) 3(1.3,0) 4(1.95,0) 5(1.95,2.6)
  oval 1.6x0.406 smd: 6(0.65,2.6)
  rect 2.388x1.6 smd: 7(0.975,1.3)
AOZ1336_DFN8_2X2-S
  oval 0.254x0.787 smd: 1(0,0) 2(0.5,0) 3(1,0) 4(1.5,0) 5(1.5,2.2) 6(1,2.2) 7(0.5,2.2) 8(0,2.2)
  rect 1.499x0.889 smd: 9(0.75,1.1)
AOZ1336DI_DFN8_2X2
  oval 0.254x0.787 smd: 1(0,0) 2(0.5,0) 3(1,0) 4(1.5,0) 5(1.5,2.2) 6(1,2.2) 7(0.5,2.2) 8(0,2.2)
  rect 1.499x0.889 smd: 9(0.75,1.1)
AP2112K-3P3TRG1_SOT23-5
  oval 0.508x0.965 smd: 1(0,0) 2(0.95,0) 3(1.9,0) 4(1.9,2.375) 5(0,2.375)
AP2204R-5P0TRG1_SOT89-3
  oval 0.889x1.295 smd: 1(0,0) 3(3,0)
  custom 0.433x0.433 smd: 2(1.5,1.775)
AP2330W-7_SC59-3
  oval 0.787x0.991 smd: 1(0,0) 2(-0.95,-2.4) 3(0.95,-2.4)
AS393MMTR-G1_MSOP8
  oval 1.549x0.381 smd: 1(0,0) 2(0,-0.65) 3(0,-1.3) 4(0,-1.95) 5(4.37,-1.95) 6(4.37,-1.3) 7(4.37,-0.65) 8(4.37,0)
AZ4A24-01FPR7G_DFN0603P2Y2
  rect 0.305x0.356 smd: 1(0,0) 2(0.4,0)
AZC199-02SPR7G_SOT23-3
  oval 1.016x1.524 smd: 1(0,0) 2(0.965,2.083) 3(-0.965,2.083)
AZV3002RL-7_U-FLGA8_1P65X1P65
  oval 0.406x0.508 smd: 1(0,0)
  oval 0.305x0.508 smd: 2(0.55,0) 3(1.05,0) 5(1.05,1.22) 6(0.55,1.22) 7(0.05,1.22)
  oval 0.508x0.305 smd: 4(1.15,0.61) 8(-0.05,0.61)
BAT54CW_SOT323-3
  oval 0.711x0.889 smd: 1(0,0) 2(-0.65,-1.9) 3(0.65,-1.9)
BSS138W-7-F_SOT323-3
  oval 0.711x0.889 smd: 1(0,0) 2(-0.65,-1.9) 3(0.65,-1.9)
BZV55-B5V1_SOD80C2
  rect 0.889x1.6 smd: 1(0,0) 2(3.3,0)
C-K_26230A-8K1A-02_9P
  round 1.194 hole 0.711: 1(0,0) 2(-2.5,0) 3(-4.5,0) 4(-7,0) 5(-7.5,-1.5) 6(-5.5,-1.5) 7(-3.5,-1.5) 8(-1.5,-1.5) 9(0.5,-1.5)
  oval 1.295x2.388 hole 0.711x1.803: 10(2.9,-0.4) 11(4.2,-8.95) 12(-11.2,-8.95) 13(-9.9,-0.4)
C_0201
  rect 0.381x0.356 smd: 1(0,0) 2(0.584,0)
C_0402
  rect 0.508x0.584 smd: 1(0,0) 2(0.914,0)
C_0603
  rect 0.635x0.889 smd: 1(0,0) 2(1.397,0)
C_0603-S3
  rect 0.635x0.889 smd: 1(0,0) 2(1.397,0)
C_0805
  rect 0.813x1.397 smd: 1(0,0) 2(1.702,0)
C_1808
  rect 1.041x2.311 smd: 1(0,0) 2(4.35,0)
C_A
  rect 1.626x1.829 smd: 1(0.389,0) 2(2.989,0)
C_B2
  rect 1.346x2.692 smd: 1(0,0) 2(-2.75,0)
C_B2-NPM
  rect 1.346x2.692 smd: 1(0,0) 2(-2.75,0)
C_D2
  rect 2.388x2.794 smd: 1(0,0) 2(6.4,0)
C_D3
  rect 2.388x2.794 smd: 1(0,0) 2(6.4,0)
C_D3L
  rect 2.388x2.896 smd: 1(0,0) 2(6.1,0)
C_D7
  rect 1.803x2.794 smd: 1(0,0) 2(6.5,0)
C_X
  rect 1.803x2.896 smd: 1(0,0) 2(6,0)
CFL-H_BGA_1440P-T
  round 0.406 smd: A3(-1.254,0) A37(-26.054,0) B2(-0.66,0.66) B38(-26.628,0.553) BR1(0,40.062) BR38(-26.628,40.036) BT2(-0.571,40.628) BT37(-26.037,40.628) C1(0,1.267)
  round 0.381 smd: A4(-1.971,0) A34(-24.46,0) A36(-25.272,0) B3(-1.382,0.699) B37(-25.909,0.703) BN1(0,38.614) BN38(-26.628,38.599) BP1(0,39.338) BP38(-26.628,39.31) BR2(-0.719,39.934) BR37(-25.904,39.927) BT3(-1.295,40.628) BT4(-2.019,40.628) BT35(-24.498,40.628) BT36(-25.311,40.628) C2(-0.699,1.361) C38(-26.628,1.334) D1(0,1.991) D38(-26.628,2.097)
  round 0.356 smd: A5(-2.771,0) A33(-23.66,0) B4(-2.031,0.971) B36(-25.198,0.701) BM1(0,37.814) BM38(-26.628,37.888) BN2(-0.65,38.642) BN37(-25.965,38.665) BP2(-0.828,39.28) BP37(-25.689,39.257) BR3(-1.387,39.978) BR36(-25.193,39.971) BT5(-2.819,40.628) BT34(-23.698,40.628) C37(-25.908,1.402) D3(-1.233,1.822) E1(0,2.779) E2(-0.65,2.474) E38(-26.628,2.897)
  round 0.33 smd: A6(-3.546,0) A32(-22.872,0) B5(-2.743,0.65) B34(-24.443,0.67) BK1(0,37.037) BL2(-0.65,37.438) BL38(-26.628,37.176) BM2(-0.963,38.053) BM37(-25.978,37.986) BN3(-1.3,38.701) BN36(-25.314,38.638) BP3(-1.483,39.334) BP35(-24.561,39.328) BR5(-2.166,39.984) BR34(-23.774,39.978) BR35(-24.536,39.978) BT6(-3.594,40.628) BT32(-22.923,40.628) C36(-25.145,1.388) D4(-1.894,1.655) D37(-25.603,1.985) E3(-1.3,2.474) E37(-25.978,2.604) F2(-0.65,3.16) G1(0,3.581) G38(-26.628,3.671)
  round 0.305 smd: A8(-4.318,0) A9(-5.105,0) A10(-5.893,0) A11(-6.68,0) A12(-7.468,0) A13(-8.255,0) A14(-9.042,0) A15(-9.83,0) A16(-10.617,0) A17(-11.405,0) A18(-12.192,0) A19(-12.979,0) A20(-13.767,0) A21(-14.554,0) A22(-15.342,0) A23(-16.129,0) A24(-16.916,0) A25(-17.704,0) A26(-18.491,0) A27(-19.279,0) A28(-20.066,0) A29(-20.853,0) A30(-21.844,0) AA1(0,14.019) AA2(-0.65,14.019) AA3(-1.3,14.019) AA4(-1.951,14.019) AA5(-2.601,14.019) AA6(-3.251,13.968) AA7(-3.911,14.548) AA8(-4.561,14.548) AA9(-5.212,14.548) AA10(-5.862,14.548) AA11(-6.512,14.548) AA12(-7.162,14.548) AA13(-7.813,14.548) AA14(-8.463,14.548) AA29(-20.725,14.415) AA30(-21.376,14.415) AA31(-22.077,14.415) AA32(-22.727,14.415) AA33(-23.377,14.415) AA34(-24.027,14.415) AA35(-24.678,14.415) AA36(-25.328,14.415) AA37(-25.978,14.415) AA38(-26.628,14.415) AB1(0,14.756) AB2(-0.65,14.756) AB3(-1.3,14.756) AB4(-1.951,14.756) AB5(-2.601,14.756) AB6(-3.251,14.806) AB29(-20.725,15.203) AB30(-21.376,15.203) AB31(-22.077,15.203) AB32(-22.727,15.203) AB33(-23.377,15.203) AB34(-24.027,15.203) AB35(-24.678,15.203) AB36(-25.328,15.203) AB37(-25.978,15.203) AB38(-26.628,15.203) AC1(0,15.645) AC2(-0.65,15.645) AC3(-1.3,15.645) AC4(-1.951,15.645) AC5(-2.601,15.645) AC6(-3.251,15.645) AC7(-3.911,15.463) AC8(-4.561,15.463) AC9(-5.212,15.463) AC10(-5.862,15.463) AC11(-6.512,15.463) AC12(-7.162,15.463) AC13(-7.813,15.463) AC14(-8.463,15.463) AC29(-20.725,15.99) AC30(-21.376,15.99) AC31(-22.077,15.99) AC32(-22.727,15.99) AC33(-23.377,15.99) AC34(-24.027,15.99) AC35(-24.678,15.99) AC36(-25.328,15.99) AC37(-25.978,15.99) AC38(-26.628,15.99) AD1(0,16.534) AD2(-0.65,16.534) AD3(-1.3,16.534) AD4(-1.951,16.534) AD5(-2.601,16.534) AD6(-3.251,16.483) AD7(-3.911,16.377) AD8(-4.561,16.377) AD9(-5.212,16.377) AD10(-5.862,16.377) AD11(-6.512,16.377) AD12(-7.162,16.377) AD13(-7.813,16.377) AD14(-8.463,16.377) AD29(-20.725,16.777) AD30(-21.376,16.777) AD31(-22.077,16.777) AD32(-22.727,16.777) AD33(-23.377,16.777) AD34(-24.027,16.777) AD35(-24.678,16.777) AD36(-25.328,16.777) AD37(-25.978,16.777) AD38(-26.628,16.777) AE1(0,17.27) AE2(-0.65,17.27) AE3(-1.3,17.27) AE4(-1.951,17.27) AE5(-2.601,17.27) AE6(-3.251,17.321) AE7(-3.911,17.291) AE8(-4.561,17.291) AE9(-5.212,17.291) AE10(-5.862,17.291) AE11(-6.512,17.291) AE12(-7.162,17.291) AE13(-7.813,17.291) AE14(-8.463,17.291) AE29(-20.725,17.565) AE30(-21.376,17.565) AE31(-22.077,17.565) AE32(-22.727,17.565) AE33(-23.377,17.565) AE34(-24.027,17.565) AE35(-24.678,17.565) AE36(-25.328,17.565) AE37(-25.978,17.565) AE38(-26.628,17.565) AF1(0,18.159) AF2(-0.65,18.159) AF3(-1.3,18.159) AF4(-1.951,18.159) AF5(-2.601,18.159) AF6(-3.251,18.159) AF7(-3.911,18.206) AF8(-4.561,18.206) AF9(-5.212,18.206) AF10(-5.862,18.206) AF11(-6.512,18.206) AF12(-7.162,18.206) AF13(-7.813,18.206) AF14(-8.463,18.206) AF29(-20.725,18.352) AF30(-21.376,18.352) AF31(-22.077,18.352) AF32(-22.727,18.352) AF33(-23.377,18.352) AF34(-24.027,18.352) AF35(-24.678,18.352) AF36(-25.328,18.352) AF37(-25.978,18.352) AF38(-26.628,18.352) AG1(0,19.048) AG2(-0.65,19.048) AG3(-1.3,19.048) AG4(-1.951,19.048) AG5(-2.601,19.048) AG6(-3.251,18.997) AG7(-3.911,19.12) AG8(-4.561,19.12) AG9(-5.212,19.12) AG10(-5.862,19.12) AG11(-6.512,19.12) AG12(-7.162,19.12) AG13(-7.813,19.12) AG14(-8.463,19.12) AG29(-20.725,19.14) AG30(-21.376,19.14) AG31(-22.077,19.14) AG32(-22.727,19.14) AG33(-23.377,19.14) AG34(-24.027,19.14) AG35(-24.678,19.14) AG36(-25.328,19.14) AG37(-25.978,19.14) AG38(-26.628,19.14) AH1(0,19.785) AH2(-0.65,19.785) AH3(-1.3,19.785) AH4(-1.951,19.785) AH5(-2.601,19.785) AH6(-3.251,19.836) AH7(-3.911,20.035) AH8(-4.561,20.035) AH9(-5.212,20.035) AH10(-5.862,20.035) AH11(-6.512,20.035) AH12(-7.162,20.035) AH13(-7.813,20.035) AH14(-8.463,20.035) AH29(-20.725,19.927) AH30(-21.376,19.927) AH31(-22.077,19.927) AH32(-22.727,19.927) AH33(-23.377,19.927) AH34(-24.027,19.927) AH35(-24.678,19.927) AH36(-25.328,19.927) AH37(-25.978,19.927) AH38(-26.628,19.927) AJ1(0,20.674) AJ2(-0.65,20.674) AJ3(-1.3,20.674) AJ4(-1.951,20.674) AJ5(-2.601,20.674) AJ6(-3.251,20.674) AJ7(-3.911,20.949) AJ8(-4.561,20.949) AJ9(-5.212,20.949) AJ10(-5.862,20.949) AJ11(-6.512,20.949) AJ12(-7.162,20.949) AJ13(-7.813,20.949) AJ14(-8.463,20.949) AJ29(-20.725,20.714) AJ30(-21.376,20.714) AJ31(-22.077,20.714) AJ32(-22.727,20.714) AJ33(-23.377,20.714) AJ34(-24.027,20.714) AJ35(-24.678,20.714) AJ36(-25.328,20.714) AJ37(-25.978,20.714) AJ38(-26.628,20.714) AK1(0,21.563) AK2(-0.65,21.563) AK3(-1.3,21.563) AK4(-1.951,21.563) AK5(-2.601,21.563) AK6(-3.251,21.512) AK29(-20.725,21.502) AK30(-21.376,21.502) AK31(-22.077,21.502) AK32(-22.727,21.502) AK33(-23.377,21.502) AK34(-24.027,21.502) AK35(-24.678,21.502) AK36(-25.328,21.502) AK37(-25.978,21.502) AK38(-26.628,21.502) AL1(0,22.299) AL2(-0.65,22.299) AL3(-1.3,22.299) AL4(-1.951,22.299) AL5(-2.601,22.299) AL6(-3.251,22.35) AL7(-3.911,21.863) AL8(-4.561,21.863) AL9(-5.212,21.863) AL10(-5.862,21.863) AL11(-6.512,21.863) AL12(-7.162,21.863) AL13(-7.813,21.863) AL14(-8.463,21.863) AL29(-20.725,22.289) AL30(-21.376,22.289) AL31(-22.077,22.289) AL32(-22.727,22.289) AL33(-23.377,22.289) AL34(-24.027,22.289) AL35(-24.678,22.289) AL36(-25.328,22.289) AL37(-25.978,22.289) AL38(-26.628,22.289) AM1(0,23.188) AM2(-0.65,23.188) AM3(-1.3,23.188) AM4(-1.951,23.188) AM5(-2.601,23.188) AM6(-3.251,23.188) AM7(-3.911,22.778) AM8(-4.561,22.778) AM9(-5.212,22.778) AM10(-5.862,22.778) AM11(-6.512,22.778) AM12(-7.162,22.778) AM13(-7.813,22.778) AM14(-8.463,22.778) AM29(-20.725,23.077) AM30(-21.376,23.077) AM31(-22.077,23.077) AM32(-22.727,23.077) AM33(-23.377,23.077) AM34(-24.027,23.077) AM35(-24.678,23.077) AM36(-25.328,23.077) AM37(-25.978,23.077) AM38(-26.628,23.077) AN1(0,24.077) AN2(-0.65,24.077) AN3(-1.3,24.077) AN4(-1.951,24.077) AN5(-2.601,24.077) AN6(-3.251,24.027) AN7(-3.911,23.692) AN8(-4.561,23.692) AN9(-5.212,23.692) AN10(-5.862,23.692) AN11(-6.512,23.692) AN12(-7.162,23.692) AN13(-7.813,23.692) AN14(-8.463,23.692) AN29(-20.725,23.864) AN30(-21.376,23.864) AN31(-22.077,23.864) AN32(-22.727,23.864) AN33(-23.377,23.864) AN34(-24.027,23.864) AN35(-24.678,23.864) AN36(-25.328,23.864) AN37(-25.978,23.864) AN38(-26.628,23.864) AP1(0,24.814) AP2(-0.65,24.814) AP3(-1.3,24.814) AP4(-1.951,24.814) AP5(-2.601,24.814) AP6(-3.251,24.865) AP7(-3.911,24.607) AP8(-4.561,24.607) AP9(-5.212,24.607) AP10(-5.862,24.607) AP11(-6.512,24.607) AP12(-7.162,24.607) AP13(-7.813,24.607) AP14(-8.463,24.607) AP29(-20.725,24.651) AP30(-21.376,24.651) AP31(-22.077,24.651) AP32(-22.727,24.651) AP33(-23.377,24.651) AP34(-24.027,24.651) AP35(-24.678,24.651) AP36(-25.328,24.651) AP37(-25.978,24.651) AP38(-26.628,24.651) AR1(0,25.703) AR2(-0.65,25.703) AR3(-1.3,25.703) AR4(-1.951,25.703) AR5(-2.601,25.703) AR6(-3.251,25.703) AR7(-3.911,25.521) AR8(-4.561,25.521) AR9(-5.212,25.521) AR10(-5.862,25.521) AR11(-6.512,25.521) AR12(-7.162,25.521) AR13(-7.813,25.521) AR14(-8.463,25.521) AR29(-20.725,25.439) AR30(-21.376,25.439) AR31(-22.077,25.439) AR32(-22.727,25.439) AR33(-23.377,25.439) AR34(-24.027,25.439) AR35(-24.678,25.439) AR36(-25.328,25.439) AR37(-25.978,25.439) AR38(-26.628,25.439) AT1(0,26.592) AT2(-0.65,26.592) AT3(-1.3,26.592) AT4(-1.951,26.592) AT5(-2.601,26.592) AT6(-3.251,26.541) AT7(-3.911,26.435) AT8(-4.561,26.435) AT9(-5.212,26.435) AT10(-5.862,26.435) AT11(-6.512,26.435) AT12(-7.162,26.435) AT13(-7.813,26.435) AT14(-8.463,26.435) AT29(-20.725,26.226) AT30(-21.376,26.226) AT31(-22.077,26.226) AT32(-22.727,26.226) AT33(-23.377,26.226) AT34(-24.027,26.226) AT35(-24.678,26.226) AT36(-25.328,26.226) AT37(-25.978,26.226) AT38(-26.628,26.226) AU1(0,27.329) AU2(-0.65,27.329) AU3(-1.3,27.329) AU4(-1.951,27.329) AU5(-2.601,27.329) AU6(-3.251,27.379) AU7(-3.911,27.35) AU8(-4.561,27.35) AU9(-5.212,27.35) AU10(-5.862,27.35) AU11(-6.512,27.35) AU12(-7.162,27.35) AU13(-7.813,27.35) AU14(-8.463,27.35) AU29(-20.725,27.014) AU30(-21.376,27.014) AU31(-22.077,27.014) AU32(-22.727,27.014) AU33(-23.377,27.014) AU34(-24.027,27.014) AU35(-24.678,27.014) AU36(-25.328,27.014) AU37(-25.978,27.014) AU38(-26.628,27.014) AV29(-20.725,27.801) AV30(-21.376,27.801) AV31(-22.077,27.801) AV32(-22.727,27.801) AV33(-23.377,27.801) AV34(-24.027,27.801) AV35(-24.678,27.801) AV36(-25.328,27.801) AV37(-25.978,27.801) AV38(-26.628,27.801) AW1(0,28.218) AW2(-0.65,28.218) AW3(-1.3,28.218) AW4(-1.951,28.218) AW5(-2.601,28.218) AW6(-3.251,28.218) AW7(-3.911,28.264) AW8(-4.561,28.264) AW9(-5.212,28.264) AW10(-5.862,28.264) AW11(-6.512,28.264) AW12(-7.162,28.264) AW13(-7.813,28.264) AW14(-8.463,28.264) AW29(-20.725,28.588) AW30(-21.376,28.588) AW31(-22.077,28.588) AW32(-22.727,28.588) AW33(-23.377,28.588) AW34(-24.027,28.588) AW35(-24.678,28.588) AW36(-25.328,28.588) AW37(-25.978,28.588) AW38(-26.628,28.588) AY1(0,29.107) AY2(-0.65,29.107) AY3(-1.3,29.107) AY4(-1.951,29.107) AY5(-2.601,29.107) AY6(-3.251,29.056) AY7(-3.911,29.179) AY8(-4.561,29.179) AY9(-5.212,29.179) AY10(-5.862,29.179) AY11(-6.512,29.179) AY12(-7.162,29.179) AY13(-7.813,29.179) AY14(-8.463,29.179) AY29(-20.725,29.376) AY30(-21.376,29.376) AY31(-22.077,29.376) AY32(-22.727,29.376) AY33(-23.377,29.376) AY34(-24.027,29.376) AY35(-24.678,29.376) AY36(-25.328,29.376) AY37(-25.978,29.376) AY38(-26.628,29.376) B6(-3.531,0.65) B8(-4.318,0.65) B9(-5.105,0.65) B10(-5.893,0.65) B11(-6.68,0.65) B12(-7.468,0.65) B13(-8.255,0.65) B14(-9.042,0.65) B15(-9.83,0.65) B16(-10.617,0.65) B17(-11.405,0.65) B18(-12.192,0.65) B19(-12.979,0.65) B20(-13.767,0.65) B21(-14.554,0.65) B22(-15.342,0.65) B23(-16.129,0.65) B24(-16.916,0.65) B25(-17.704,0.65) B26(-18.491,0.65) B27(-19.279,0.65) B28(-20.066,0.65) B29(-20.853,0.65) B30(-21.641,0.65) B31(-22.428,0.65) B33(-23.216,0.65) BA1(0,29.843) BA2(-0.65,29.843) BA3(-1.3,29.843) BA4(-1.951,29.843) BA5(-2.601,29.843) BA6(-3.251,29.894) BA7(-3.911,30.093) BA8(-4.561,30.093) BA9(-5.212,30.093) BA10(-5.862,30.093) BA11(-6.512,30.093) BA12(-7.162,30.093) BA13(-7.813,30.093) BA14(-8.463,30.093) BA29(-20.725,30.163) BA30(-21.376,30.163) BA31(-22.077,30.163) BA32(-22.727,30.163) BA33(-23.377,30.163) BA34(-24.027,30.163) BA35(-24.678,30.163) BA36(-25.328,30.163) BA37(-25.978,30.163) BA38(-26.628,30.163) BB1(0,30.732) BB2(-0.65,30.732) BB3(-1.3,30.732) BB4(-1.951,30.732) BB5(-2.601,30.732) BB6(-3.251,30.732) BB7(-3.911,31.007) BB8(-4.561,31.007) BB9(-5.212,31.007) BB10(-5.862,31.007) BB11(-6.512,31.007) BB12(-7.162,31.007) BB13(-7.813,31.007) BB14(-8.463,31.007) BB29(-20.725,30.951) BB30(-21.376,30.951) BB31(-22.077,30.951) BB32(-22.727,30.951) BB33(-23.377,30.951) BB34(-24.027,30.951) BB35(-24.678,30.951) BB36(-25.328,30.951) BB37(-25.978,30.951) BB38(-26.628,30.951) BC1(0,31.621) BC2(-0.65,31.621) BC3(-1.3,31.621) BC4(-1.951,31.621) BC5(-2.601,31.621) BC6(-3.251,31.57) BC7(-3.911,31.922) BC8(-4.561,31.922) BC9(-5.212,31.922) BC10(-5.862,31.922) BC11(-6.512,31.922) BC12(-7.162,31.922) BC13(-7.813,31.922) BC14(-8.463,31.922) BC29(-20.725,31.738) BC30(-21.376,31.738) BC31(-22.077,31.738) BC32(-22.727,31.738) BC33(-23.377,31.738) BC34(-24.027,31.738) BC35(-24.678,31.738) BC36(-25.328,31.738) BC37(-25.978,31.738) BC38(-26.628,31.738) BD1(0,32.358) BD2(-0.65,32.358) BD3(-1.3,32.358) BD4(-1.951,32.358) BD5(-2.601,32.358) BD6(-3.251,32.409) BD7(-3.911,32.836) BD8(-4.561,32.836) BD9(-5.212,32.836) BD10(-5.862,32.836) BD11(-6.512,32.836) BD12(-7.162,32.836) BD13(-7.813,32.836) BD14(-8.463,32.836) BD29(-20.725,32.525) BD30(-21.376,32.525) BD31(-22.077,32.525) BD32(-22.727,32.525) BD33(-23.377,32.525) BD34(-24.027,32.525) BD35(-24.678,32.525) BD36(-25.328,32.525) BD37(-25.978,32.525) BD38(-26.628,32.525) BE1(0,33.247) BE2(-0.65,33.247) BE3(-1.3,33.247) BE4(-1.951,33.247) BE5(-2.601,33.247) BE6(-3.251,33.247) BE29(-20.725,33.313) BE30(-21.376,33.313) BE31(-22.077,33.313) BE32(-22.727,33.313) BE33(-23.377,33.313) BE34(-24.027,33.313) BE35(-24.678,33.313) BE36(-25.328,33.313) BE37(-25.978,33.313) BE38(-26.628,33.313) BF1(0,34.136) BF2(-0.65,34.136) BF3(-1.3,34.136) BF4(-1.951,34.136) BF5(-2.601,34.136) BF6(-3.251,34.085) BF7(-3.911,33.751) BF8(-4.561,33.751) BF9(-5.212,33.751) BF10(-5.862,33.751) BF11(-6.512,33.751) BF12(-7.162,33.751) BF13(-7.813,33.751) BF14(-8.463,33.751) BF29(-20.725,34.1) BF30(-21.376,34.1) BF31(-22.077,34.1) BF32(-22.727,34.1) BF33(-23.377,34.1) BF34(-24.027,34.1) BF35(-24.678,34.1) BF36(-25.328,34.1) BF37(-25.978,34.1) BF38(-26.628,34.1) BG1(0,34.872) BG2(-0.65,34.872) BG3(-1.3,34.872) BG4(-1.951,34.872) BG5(-2.601,34.872) BG6(-3.251,34.923) BG7(-3.911,34.665) BG8(-4.561,34.665) BG9(-5.212,34.665) BG10(-5.862,34.665) BG11(-6.512,34.665) BG12(-7.162,34.665) BG13(-7.813,34.665) BG14(-8.463,34.665) BG29(-20.725,34.888) BG30(-21.376,34.888) BG31(-22.077,34.888) BG32(-22.727,34.888) BG33(-23.377,34.888) BG34(-24.027,34.888) BG35(-24.678,34.888) BG36(-25.328,34.888) BG37(-25.978,34.888) BG38(-26.628,34.888) BH1(0,36.015) BH2(-0.65,35.761) BH3(-1.3,35.761) BH4(-1.951,35.761) BH5(-2.601,35.761) BH6(-3.251,35.761) BH7(-3.911,35.579) BH8(-4.561,35.579) BH9(-5.212,35.579) BH10(-5.862,35.579) BH11(-6.512,35.579) BH12(-7.162,35.579) BH13(-7.813,35.579) BH14(-8.463,35.541) BH29(-20.725,35.548) BH30(-21.376,35.675) BH31(-22.077,35.675) BH32(-22.727,35.675) BH33(-23.377,35.675) BH34(-24.027,35.675) BH35(-24.678,35.675) BH36(-25.328,35.675) BH37(-25.978,35.675) BH38(-26.628,35.675) BJ7(-3.911,36.494) BJ8(-4.561,36.494) BJ9(-5.212,36.494) BJ10(-5.862,36.494) BJ11(-6.512,36.494) BJ12(-7.282,36.405) BJ13(-8.171,36.126) BJ14(-8.851,36.077) BJ15(-9.601,36.077) BJ16(-10.388,36.077) BJ17(-11.175,36.077) BJ18(-11.963,36.077) BJ19(-12.75,36.077) BJ20(-13.538,36.077) BJ21(-14.325,36.077) BJ22(-15.112,36.077) BJ23(-15.9,36.077) BJ24(-16.687,36.077) BJ25(-17.475,36.077) BJ26(-18.262,36.077) BJ27(-19.049,36.077) BJ28(-19.837,36.077) BJ29(-20.497,36.158) BJ30(-21.353,36.329) BJ31(-22.077,36.462) BJ32(-22.727,36.462) BJ33(-23.377,36.462) BJ34(-24.027,36.462) BJ35(-24.678,36.462) BJ36(-25.328,36.462) BJ37(-25.978,36.462) BJ38(-26.628,36.412) BK2(-0.65,36.6) BK3(-1.3,36.6) BK4(-1.951,36.6) BK5(-2.601,36.6) BK6(-3.251,36.6) BK13(-7.899,36.727) BK14(-8.813,36.727) BK15(-9.601,36.727) BK16(-10.388,36.727) BK17(-11.175,36.727) BK18(-11.963,36.727) BK19(-12.75,36.727) BK20(-13.538,36.727) BK21(-14.325,36.727) BK22(-15.112,36.727) BK23(-15.9,36.727) BK24(-16.687,36.727) BK25(-17.475,36.727) BK26(-18.262,36.727) BK27(-19.049,36.727) BK28(-19.837,36.727) BK29(-20.833,36.735) BL3(-1.3,37.387) BL4(-1.951,37.387) BL5(-2.601,37.387) BL6(-3.251,37.438) BL7(-3.987,37.383) BL8(-4.876,37.377) BL9(-5.664,37.377) BL11(-6.451,37.377) BL12(-7.238,37.377) BL13(-8.026,37.377) BL14(-8.813,37.377) BL15(-9.601,37.377) BL16(-10.388,37.377) BL17(-11.175,37.377) BL18(-11.963,37.377) BL19(-12.75,37.377) BL20(-13.538,37.377) BL21(-14.325,37.377) BL22(-15.112,37.377) BL23(-15.9,37.377) BL24(-16.687,37.377) BL25(-17.475,37.377) BL26(-18.262,37.377) BL27(-19.049,37.377) BL28(-19.837,37.377) BL29(-20.624,37.377) BL30(-21.426,37.25) BL31(-22.077,37.25) BL32(-22.727,37.25) BL33(-23.377,37.25) BL34(-24.027,37.25) BL35(-24.678,37.25) BL36(-25.328,37.25) BL37(-25.978,37.25) BM3(-1.613,38.129) BM5(-2.525,38.129) BM6(-3.169,38.231) BM7(-4.089,38.027) BM8(-4.876,38.027) BM9(-5.664,38.027) BM11(-6.451,38.027) BM12(-7.238,38.027) BM13(-8.026,38.027) BM14(-8.813,38.027) BM15(-9.601,38.027) BM16(-10.388,38.027) BM17(-11.175,38.027) BM18(-11.963,38.027) BM19(-12.75,38.027) BM20(-13.538,38.027) BM21(-14.325,38.027) BM22(-15.112,38.027) BM23(-15.9,38.027) BM24(-16.687,38.027) BM25(-17.475,38.027) BM26(-18.262,38.027) BM27(-19.049,38.027) BM28(-19.837,38.027) BM29(-20.624,38.027) BM30(-21.412,38.027) BM31(-22.199,38.027) BM33(-22.986,38.027) BM34(-23.774,38.027) BM35(-24.561,38.027) BM36(-25.328,37.986) BN4(-2.106,38.629) BN5(-2.748,38.793) BN7(-4.089,38.678) BN8(-4.876,38.678) BN9(-5.664,38.678) BN11(-6.451,38.678) BN12(-7.238,38.678) BN13(-8.026,38.678) BN14(-8.813,38.678) BN15(-9.601,38.678) BN16(-10.388,38.678) BN17(-11.175,38.678) BN18(-11.963,38.678) BN19(-12.75,38.678) BN20(-13.538,38.678) BN21(-14.325,38.678) BN22(-15.112,38.678) BN23(-15.9,38.678) BN24(-16.687,38.678) BN25(-17.475,38.678) BN26(-18.262,38.678) BN27(-19.049,38.678) BN28(-19.837,38.678) BN29(-20.624,38.678) BN30(-21.412,38.678) BN31(-22.199,38.678) BN33(-22.986,38.678) BN34(-23.774,38.678) BN35(-24.562,38.678) BP5(-2.374,39.351) BP6(-3.294,39.288) BP7(-4.089,39.328) BP8(-4.876,39.328) BP9(-5.664,39.328) BP11(-6.451,39.328) BP12(-7.238,39.328) BP13(-8.026,39.328) BP14(-8.813,39.328) BP15(-9.601,39.328) BP16(-10.388,39.328) BP17(-11.175,39.328) BP18(-11.963,39.328) BP19(-12.75,39.328) BP20(-13.538,39.328) BP21(-14.325,39.328) BP22(-15.112,39.328) BP23(-15.9,39.328) BP24(-16.687,39.328) BP25(-17.475,39.328) BP26(-18.262,39.328) BP27(-19.049,39.328) BP28(-19.837,39.328) BP29(-20.624,39.328) BP30(-21.412,39.328) BP31(-22.199,39.328) BP33(-22.986,39.328) BP34(-23.774,39.328) BR6(-3.192,39.961) BR7(-4.089,39.978) BR8(-4.876,39.978) BR9(-5.664,39.978) BR11(-6.451,39.978) BR12(-7.238,39.978) BR13(-8.026,39.978) BR14(-8.813,39.978) BR15(-9.601,39.978) BR16(-10.388,39.978) BR17(-11.175,39.978) BR18(-11.963,39.978) BR19(-12.75,39.978) BR20(-13.538,39.978) BR21(-14.325,39.978) BR22(-15.112,39.978) BR23(-15.9,39.978) BR24(-16.687,39.978) BR25(-17.475,39.978) BR26(-18.262,39.978) BR27(-19.049,39.978) BR28(-19.837,39.978) BR29(-20.624,39.978) BR30(-21.412,39.978) BR31(-22.199,39.978) BR33(-22.986,39.978) BT8(-4.648,40.628) BT9(-5.664,40.628) BT11(-6.451,40.628) BT12(-7.238,40.628) BT13(-8.026,40.628) BT14(-8.813,40.628) BT15(-9.601,40.628) BT16(-10.388,40.628) BT17(-11.175,40.628) BT18(-11.963,40.628) BT19(-12.75,40.628) BT20(-13.538,40.628) BT21(-14.325,40.628) BT22(-15.112,40.628) BT23(-15.9,40.628) BT24(-16.687,40.628) BT25(-17.475,40.628) BT26(-18.262,40.628) BT27(-19.049,40.628) BT28(-19.837,40.628) BT29(-20.624,40.628) BT30(-21.412,40.628) BT31(-22.174,40.628) C5(-2.743,1.3) C6(-3.531,1.3) C8(-4.318,1.3) C9(-5.105,1.3) C10(-5.893,1.3) C11(-6.68,1.3) C12(-7.468,1.3) C13(-8.255,1.3) C14(-9.042,1.3) C15(-9.83,1.3) C16(-10.617,1.3) C17(-11.405,1.3) C18(-12.192,1.3) C19(-12.979,1.3) C20(-13.767,1.3) C21(-14.554,1.3) C22(-15.342,1.3) C23(-16.129,1.3) C24(-16.916,1.3) C25(-17.704,1.3) C26(-18.491,1.3) C27(-19.279,1.3) C28(-20.066,1.3) C29(-20.853,1.3) C30(-21.641,1.3) C31(-22.428,1.3) C33(-23.216,1.3) C34(-24.011,1.29) D5(-2.743,1.951) D6(-3.531,1.951) D8(-4.318,1.951) D9(-5.105,1.951) D10(-5.893,1.951) D11(-6.68,1.951) D12(-7.468,1.951) D13(-8.255,1.951) D14(-9.042,1.951) D15(-9.83,1.951) D16(-10.617,1.951) D17(-11.405,1.951) D18(-12.192,1.951) D19(-12.979,1.951) D20(-13.767,1.951) D21(-14.554,1.951) D22(-15.342,1.951) D23(-16.129,1.951) D24(-16.916,1.951) D25(-17.704,1.951) D26(-18.491,1.951) D27(-19.279,1.951) D28(-20.066,1.951) D29(-20.853,1.951) D30(-21.641,1.951) D31(-22.428,1.951) D33(-23.216,1.951) D34(-24.003,1.951) D35(-24.655,1.861) E4(-1.951,2.575) E5(-2.743,2.601) E6(-3.531,2.601) E8(-4.318,2.601) E9(-5.105,2.601) E10(-5.893,2.601) E11(-6.68,2.601) E12(-7.468,2.601) E13(-8.255,2.601) E14(-9.042,2.601) E15(-9.83,2.601) E16(-10.617,2.601) E17(-11.405,2.601) E18(-12.192,2.601) E19(-12.979,2.601) E20(-13.767,2.601) E21(-14.554,2.601) E22(-15.342,2.601) E23(-16.129,2.601) E24(-16.916,2.601) E25(-17.704,2.601) E26(-18.491,2.601) E27(-19.279,2.601) E28(-20.066,2.601) E29(-20.853,2.601) E30(-21.641,2.601) E31(-22.428,2.601) E33(-23.216,2.601) E34(-24.003,2.601) E35(-24.678,2.604) E36(-25.328,2.604) F3(-1.3,3.16) F4(-1.951,3.261) F5(-2.743,3.273) F6(-3.531,3.273) F8(-4.318,3.251) F9(-5.105,3.251) F10(-5.893,3.251) F11(-6.68,3.251) F12(-7.468,3.251) F13(-8.255,3.251) F14(-9.042,3.251) F15(-9.83,3.251) F16(-10.617,3.251) F17(-11.405,3.251) F18(-12.192,3.251) F19(-12.979,3.251) F20(-13.767,3.251) F21(-14.554,3.251) F22(-15.342,3.251) F23(-16.129,3.251) F24(-16.916,3.251) F25(-17.704,3.251) F26(-18.491,3.251) F27(-19.279,3.251) F28(-20.066,3.251) F29(-20.853,3.251) F30(-21.641,3.251) F31(-22.428,3.251) F33(-23.216,3.251) F34(-24.027,3.392) F35(-24.678,3.392) F36(-25.328,3.392) F37(-25.978,3.392) G2(-0.65,3.947) G3(-1.3,3.947) G4(-1.951,3.947) G5(-2.601,3.947) G6(-3.251,3.947) G8(-4.318,3.901) G9(-5.105,3.901) G10(-5.893,3.901) G11(-6.68,3.901) G12(-7.468,3.901) G13(-8.255,3.901) G14(-9.042,3.901) G15(-9.83,3.901) G16(-10.617,3.901) G17(-11.405,3.901) G18(-12.192,3.901) G19(-12.979,3.901) G20(-13.767,3.901) G21(-14.554,3.901) G22(-15.342,3.901) G23(-16.129,3.901) G24(-16.916,3.901) G25(-17.704,3.901) G26(-18.491,3.901) G27(-19.279,3.901) G28(-20.066,3.901) G29(-20.853,3.901) G30(-21.641,3.901) H1(0,4.443) H11(-6.68,4.552) H12(-7.468,4.552) H13(-8.255,4.602) H14(-9.042,4.602) H15(-9.83,4.602) H16(-10.617,4.602) H17(-11.405,4.602) H18(-12.192,4.602) H19(-12.979,4.602) H20(-13.767,4.602) H21(-14.554,4.602) H22(-15.342,4.602) H23(-16.129,4.602) H24(-16.916,4.602) H25(-17.704,4.602) H26(-18.491,4.602) H27(-19.279,4.602) H28(-20.066,4.602) H29(-20.853,4.552) H30(-21.603,4.552) H32(-22.727,4.179) H33(-23.377,4.179) H34(-24.027,4.179) H35(-24.678,4.179) H36(-25.328,4.179) H37(-25.978,4.179) J2(-0.65,4.748) J3(-1.3,4.748) J4(-1.951,4.748) J5(-2.601,4.748) J6(-3.251,4.748) J7(-3.893,4.619) J8(-4.541,4.716) J9(-5.212,4.693) J10(-5.893,4.628) J14(-9.042,5.253) J15(-9.83,5.253) J16(-10.617,5.253) J17(-11.405,5.253) J18(-12.192,5.253) J19(-12.979,5.253) J20(-13.767,5.253) J21(-14.554,5.253) J22(-15.342,5.253) J23(-16.129,5.253) J24(-16.916,5.253) J25(-17.704,5.253) J26(-18.491,5.253) J27(-19.279,5.253) J28(-20.066,5.253) J30(-21.061,5.168) J31(-22.077,5.005) J32(-22.727,4.966) J33(-23.377,4.966) J34(-24.027,4.966) J35(-24.678,4.966) J36(-25.328,4.966) J37(-25.978,4.966) J38(-26.628,4.712) K1(0,5.586) K2(-0.65,5.586) K3(-1.3,5.586) K4(-1.951,5.586) K5(-2.601,5.586) K6(-3.251,5.586) K7(-3.911,5.557) K8(-4.561,5.48) K9(-5.212,5.48) K10(-5.862,5.48) K11(-6.512,5.48) K12(-7.162,5.48) K13(-7.879,5.176) K14(-8.463,5.658) K29(-20.725,5.754) K30(-21.376,5.754) K31(-22.077,5.754) K32(-22.727,5.754) K33(-23.377,5.754) K34(-24.027,5.754) K35(-24.678,5.754) K36(-25.328,5.754) K37(-25.978,5.754) K38(-26.628,5.754) L1(0,6.475) L2(-0.65,6.475) L3(-1.3,6.475) L4(-1.951,6.475) L5(-2.601,6.475) L6(-3.251,6.424) L7(-3.911,6.395) L8(-4.561,6.344) L9(-5.212,6.319) L10(-5.862,6.319) L11(-6.512,6.319) L12(-7.162,6.319) L13(-7.813,6.319) L14(-8.463,6.319) L29(-20.725,6.541) L30(-21.376,6.541) L31(-22.077,6.541) L32(-22.727,6.541) L33(-23.377,6.541) L34(-24.027,6.541) L35(-24.678,6.541) L36(-25.328,6.541) L37(-25.978,6.541) L38(-26.628,6.541) M1(0,7.212) M2(-0.65,7.212) M3(-1.3,7.212) M4(-1.951,7.212) M5(-2.601,7.212) M6(-3.251,7.263) M7(-3.911,7.233) M8(-4.561,7.233) M9(-5.212,7.233) M10(-5.862,7.233) M11(-6.512,7.233) M12(-7.162,7.233) M13(-7.813,7.233) M14(-8.463,7.233) M29(-20.725,7.329) M30(-21.376,7.329) M31(-22.077,7.329) M32(-22.727,7.329) M33(-23.377,7.329) M34(-24.027,7.329) M35(-24.678,7.329) M36(-25.328,7.329) M37(-25.978,7.329) M38(-26.628,7.329) N1(0,8.101) N2(-0.65,8.101) N3(-1.3,8.101) N4(-1.951,8.101) N5(-2.601,8.101) N6(-3.251,8.101) N7(-3.911,8.147) N8(-4.561,8.147) N9(-5.212,8.147) N10(-5.862,8.147) N11(-6.512,8.147) N12(-7.162,8.147) N13(-7.813,8.147) N14(-8.463,8.147) N29(-20.725,8.116) N30(-21.376,8.116) N31(-22.077,8.116) N32(-22.727,8.116) N33(-23.377,8.116) N34(-24.027,8.116) N35(-24.678,8.116) N36(-25.328,8.116) N37(-25.978,8.116) N38(-26.628,8.116) P1(0,8.99) P2(-0.65,8.99) P3(-1.3,8.99) P4(-1.951,8.99) P5(-2.601,8.99) P6(-3.251,8.939) P7(-3.911,9.062) P8(-4.561,9.062) P9(-5.212,9.062) P10(-5.862,9.062) P11(-6.512,9.062) P12(-7.162,9.062) P13(-7.813,9.062) P14(-8.463,9.062) P29(-20.725,8.903) P30(-21.376,8.903) P31(-22.077,8.903) P32(-22.727,8.903) P33(-23.377,8.903) P34(-24.027,8.903) P35(-24.678,8.903) P36(-25.328,8.903) P37(-25.978,8.903) P38(-26.628,8.903) R1(0,9.726) R2(-0.65,9.726) R3(-1.3,9.726) R4(-1.951,9.726) R5(-2.601,9.726) R6(-3.251,9.777) R7(-3.911,9.976) R8(-4.561,9.976) R9(-5.212,9.976) R10(-5.862,9.976) R11(-6.512,9.976) R12(-7.162,9.976) R13(-7.813,9.976) R14(-8.463,9.976) R29(-20.725,9.691) R30(-21.376,9.691) R31(-22.077,9.691) R32(-22.727,9.691) R33(-23.377,9.691) R34(-24.027,9.691) R35(-24.678,9.691) R36(-25.328,9.691) R37(-25.978,9.691) R38(-26.628,9.691) T1(0,10.615) T2(-0.65,10.615) T3(-1.3,10.615) T4(-1.951,10.615) T5(-2.601,10.615) T6(-3.251,10.615) T7(-3.911,10.891) T8(-4.561,10.891) T9(-5.212,10.891) T10(-5.862,10.891) T11(-6.512,10.891) T12(-7.162,10.891) T13(-7.813,10.891) T14(-8.463,10.891) T29(-20.725,10.478) T30(-21.376,10.478) T31(-22.077,10.478) T32(-22.727,10.478) T33(-23.377,10.478) T34(-24.027,10.478) T35(-24.678,10.478) T36(-25.328,10.478) T37(-25.978,10.478) T38(-26.628,10.478) U1(0,11.504) U2(-0.65,11.504) U3(-1.3,11.504) U4(-1.951,11.504) U5(-2.601,11.504) U6(-3.251,11.454) U29(-20.725,11.266) U30(-21.376,11.266) U31(-22.077,11.266) U32(-22.727,11.266) U33(-23.377,11.266) U34(-24.027,11.266) U35(-24.678,11.266) U36(-25.328,11.266) U37(-25.978,11.266) U38(-26.628,11.266) V1(0,12.241) V2(-0.65,12.241) V3(-1.3,12.241) V4(-1.951,12.241) V5(-2.601,12.241) V6(-3.251,12.292) V7(-3.911,11.805) V8(-4.561,11.805) V9(-5.212,11.805) V10(-5.862,11.805) V11(-6.512,11.805) V12(-7.162,11.805) V13(-7.813,11.805) V14(-8.463,11.805) V29(-20.725,12.053) V30(-21.376,12.053) V31(-22.077,12.053) V32(-22.727,12.053) V33(-23.377,12.053) V34(-24.027,12.053) V35(-24.678,12.053) V36(-25.328,12.053) V37(-25.978,12.053) V38(-26.628,12.053) W1(0,13.13) W2(-0.65,13.13) W3(-1.3,13.13) W4(-1.951,13.13) W5(-2.601,13.13) W6(-3.251,13.13) W7(-3.911,12.719) W8(-4.561,12.719) W9(-5.212,12.719) W10(-5.862,12.719) W11(-6.512,12.719) W12(-7.162,12.719) W13(-7.813,12.719) W14(-8.463,12.719) W29(-20.725,12.84) W30(-21.376,12.84) W31(-22.077,12.84) W32(-22.727,12.84) W33(-23.377,12.84) W34(-24.027,12.84) W35(-24.678,12.84) W36(-25.328,12.84) W37(-25.978,12.84) W38(-26.628,12.84) Y7(-3.911,13.634) Y8(-4.561,13.634) Y9(-5.212,13.634) Y10(-5.862,13.634) Y11(-6.512,13.634) Y12(-7.162,13.634) Y13(-7.813,13.634) Y14(-8.463,13.634) Y29(-20.725,13.628) Y30(-21.376,13.628) Y31(-22.077,13.628) Y32(-22.727,13.628) Y33(-23.377,13.628) Y34(-24.027,13.628) Y35(-24.678,13.628) Y36(-25.328,13.628) Y37(-25.978,13.628) Y38(-26.628,13.628)
CNP-H_BGA_874P-T
  round 0.305 smd: A2(0.354,0) A3(0.855,0) A4(1.355,0) A46(22.273,0) A47(22.773,0) A48(23.274,0) AA19(8.715,-9.765) AA20(9.49,-9.765) AA22(10.265,-9.765) AA23(11.039,-9.765) AA25(11.814,-9.765) AA27(12.589,-9.765) AA28(13.363,-9.765) AA30(14.138,-9.765) AA31(14.913,-9.765) AB19(8.715,-10.539) AB20(9.49,-10.539) AB22(10.265,-10.539) AB23(11.039,-10.539) AB25(11.814,-10.539) AB27(12.589,-10.539) AB28(13.363,-10.539) AB30(14.138,-10.539) AB31(14.913,-10.539) AC6(2.44,-10.735) AC7(3.202,-10.735) AC9(3.964,-10.735) AC11(4.726,-10.735) AC12(5.488,-10.735) AC14(6.25,-10.735) AC15(7.012,-10.735) AC17(7.774,-10.735) AC33(15.854,-10.735) AC35(16.616,-10.735) AC36(17.378,-10.735) AC38(18.14,-10.735) AC39(18.902,-10.735) AC41(19.664,-10.735) AC43(20.426,-10.735) AC44(21.188,-10.735) AD19(8.715,-11.314) AD20(9.49,-11.314) AD22(10.265,-11.314) AD23(11.039,-11.314) AD25(11.814,-11.314) AD27(12.589,-11.314) AD28(13.363,-11.314) AD30(14.138,-11.314) AD31(14.913,-11.314) AE6(2.44,-11.893) AE7(3.202,-11.893) AE9(3.964,-11.893) AE11(4.726,-11.893) AE12(5.488,-11.893) AE14(6.25,-11.893) AE15(7.012,-11.893) AE17(7.774,-11.893) AE33(15.854,-11.893) AE35(16.616,-11.893) AE36(17.378,-11.893) AE38(18.14,-11.893) AE39(18.902,-11.893) AE41(19.664,-11.893) AE43(20.426,-11.893) AE44(21.188,-11.893) AF19(8.715,-12.089) AF20(9.49,-12.089) AF22(10.265,-12.089) AF23(11.039,-12.089) AF25(11.814,-12.089) AF27(12.589,-12.089) AF28(13.363,-12.089) AF30(14.138,-12.089) AF31(14.913,-12.089) AG19(8.715,-12.863) AG20(9.49,-12.863) AG22(10.265,-12.863) AG23(11.039,-12.863) AG25(11.814,-12.863) AG27(12.589,-12.863) AG28(13.363,-12.863) AG30(14.138,-12.863) AG31(14.913,-12.863) AH9(3.895,-13.519) AH10(4.634,-13.328) AH12(5.412,-13.328) AH14(6.25,-13.328) AH15(7.025,-13.328) AH17(7.787,-13.328) AH33(15.841,-13.328) AH35(16.603,-13.328) AH36(17.378,-13.328) AH38(18.216,-13.328) AH40(18.994,-13.328) AH41(19.733,-13.519) AJ6(2.417,-13.9) AJ7(3.156,-13.709) AJ19(8.715,-13.638) AJ20(9.49,-13.638) AJ22(10.265,-13.638) AJ23(11.039,-13.638) AJ25(11.814,-13.638) AJ27(12.589,-13.638) AJ28(13.363,-13.638) AJ30(14.138,-13.638) AJ31(14.913,-13.638) AJ43(20.472,-13.709) AJ44(21.211,-13.9) AK19(8.715,-14.413) AK20(9.49,-14.413) AK22(10.265,-14.413) AK23(11.039,-14.413) AK25(11.814,-14.413) AK27(12.589,-14.413) AK28(13.363,-14.413) AK30(14.138,-14.413) AK31(14.913,-14.413) AL9(3.9,-14.809) AL10(4.633,-14.573) AL12(5.395,-14.573) AL13(6.157,-14.573) AL15(6.919,-14.573) AL17(7.681,-14.573) AL21(9.8,-14.892) AL24(11.235,-14.905) AL26(12.393,-14.905) AL29(13.828,-14.892) AL33(15.947,-14.573) AL35(16.709,-14.573) AL37(17.471,-14.573) AL38(18.233,-14.573) AL40(18.995,-14.573) AL41(19.728,-14.809) AM7(3.179,-15.157) AM18(8.555,-14.997) AM32(15.073,-14.997) AM43(20.449,-15.157) AN6(2.519,-15.538) AN10(4.633,-15.97) AN12(5.37,-15.665) AN13(6.132,-15.665) AN15(6.894,-15.665) AN16(7.463,-15.708) AN18(8.555,-15.708) AN21(9.8,-15.603) AN24(11.235,-15.616) AN26(12.393,-15.616) AN29(13.828,-15.603) AN32(15.073,-15.708) AN34(16.165,-15.708) AN35(16.734,-15.665) AN37(17.496,-15.665) AN38(18.258,-15.665) AN40(18.995,-15.97) AN44(21.109,-15.538) AP9(3.9,-16.282) AP21(9.8,-16.378) AP24(11.235,-16.378) AP26(12.393,-16.378) AP29(13.828,-16.378) AP41(19.728,-16.282) AR8(3.306,-16.783) AR12(5.37,-16.757) AR13(6.132,-16.757) AR15(6.894,-16.757) AR16(7.463,-16.496) AR18(8.555,-16.47) AR32(15.073,-16.47) AR34(16.165,-16.496) AR35(16.734,-16.757) AR37(17.496,-16.757) AR38(18.258,-16.757) AR42(20.322,-16.783) AT6(2.519,-16.973) AT10(4.633,-17.087) AT16(7.463,-17.258) AT18(8.555,-17.232) AT21(9.8,-17.216) AT24(11.235,-17.14) AT26(12.393,-17.14) AT29(13.828,-17.216) AT32(15.073,-17.232) AT34(16.165,-17.258) AT40(18.995,-17.087) AT44(21.109,-16.973) AU9(3.9,-17.73) AU24(11.235,-17.902) AU26(12.393,-17.902) AU41(19.728,-17.73) AV6(2.519,-18.408) AV7(3.217,-18.078) AV11(4.735,-18.289) AV13(6.066,-18.071) AV16(7.158,-18.032) AV18(8.555,-17.994) AV21(9.8,-17.993) AV29(13.828,-17.993) AV32(15.073,-17.994) AV34(16.47,-18.032) AV37(17.562,-18.071) AV39(18.893,-18.289) AV43(20.411,-18.078) AV44(21.109,-18.408) AW9(3.99,-18.891) AW10(4.552,-18.823) AW13(5.804,-18.804) AW15(6.922,-18.766) AW18(8.319,-18.727) AW21(9.609,-18.733) AW24(11.235,-18.664) AW26(12.393,-18.664) AW29(14.019,-18.733) AW32(15.309,-18.727) AW35(16.706,-18.766) AW37(17.824,-18.804) AW40(19.076,-18.823) AW41(19.638,-18.891) AY8(3.281,-19.212) AY42(20.347,-19.212) B1(0,-0.354) B2(0.484,-0.484) B3(1.105,-0.436) B47(22.523,-0.436) B48(23.144,-0.484) B49(23.628,-0.354) BA6(2.684,-19.517) BA12(5.329,-19.449) BA14(6.574,-19.449) BA17(7.971,-19.449) BA20(9.419,-19.472) BA24(11.235,-19.426) BA26(12.393,-19.426) BA30(14.209,-19.472) BA33(15.657,-19.449) BA36(17.054,-19.449) BA38(18.299,-19.449) BA44(20.944,-19.517) BB6(2.726,-20.02) BB7(3.225,-20.314) BB9(3.79,-20.088) BB11(4.948,-20.109) BB14(6.193,-20.109) BB16(7.59,-20.109) BB20(9.228,-20.211) BB24(11.235,-20.188) BB26(12.393,-20.188) BB30(14.4,-20.211) BB34(16.038,-20.109) BB36(17.435,-20.109) BB39(18.68,-20.109) BB41(19.838,-20.088) BB43(20.403,-20.314) BB44(20.902,-20.02) BC5(2.18,-20.568) BC45(21.448,-20.568) BD1(0,-21.273) BD4(1.34,-21.297) BD46(22.288,-21.297) BD49(23.628,-21.273) BE1(0,-21.773) BE2(0.441,-21.51) BE3(0.954,-21.625) BE4(1.423,-21.801) BE5(1.849,-21.526) BE45(21.779,-21.526) BE46(22.205,-21.801) BE47(22.674,-21.625) BE48(23.187,-21.51) BE49(23.628,-21.773) BF1(0,-22.274) BF2(0.484,-22.144) BF3(1.105,-22.192) BF47(22.523,-22.192) BF48(23.144,-22.144) BF49(23.628,-22.274) BG2(0.354,-22.628) BG3(0.855,-22.628) BG4(1.355,-22.628) BG46(22.273,-22.628) BG47(22.773,-22.628) BG48(23.274,-22.628) C1(0,-0.855) C2(0.441,-1.118) C3(0.954,-1.003) C4(1.423,-0.827) C5(1.849,-1.102) C45(21.779,-1.102) C46(22.205,-0.827) C47(22.674,-1.003) C48(23.187,-1.118) C49(23.628,-0.855) D1(0,-1.355) D4(1.34,-1.331) D46(22.288,-1.331) D49(23.628,-1.355) E5(2.18,-2.06) E45(21.448,-2.06) F6(2.726,-2.608) F7(3.225,-2.314) F9(3.79,-2.539) F11(4.948,-2.519) F14(6.193,-2.519) F16(7.59,-2.519) F20(9.228,-2.417) F24(11.235,-2.44) F26(12.393,-2.44) F30(14.4,-2.417) F34(16.038,-2.519) F36(17.435,-2.519) F39(18.68,-2.519) F41(19.838,-2.539) F43(20.403,-2.314) F44(20.902,-2.608) G6(2.684,-3.111) G12(5.329,-3.179) G14(6.574,-3.179) G17(7.971,-3.179) G20(9.419,-3.156) G24(11.235,-3.202) G26(12.393,-3.202) G30(14.209,-3.156) G33(15.657,-3.179) G36(17.054,-3.179) G38(18.299,-3.179) G44(20.944,-3.111) H8(3.281,-3.416) H42(20.347,-3.416) J9(3.99,-3.737) J10(4.552,-3.805) J13(5.804,-3.824) J15(6.922,-3.862) J18(8.319,-3.9) J21(9.609,-3.895) J24(11.235,-3.964) J26(12.393,-3.964) J29(14.019,-3.895) J32(15.309,-3.9) J35(16.706,-3.862) J37(17.824,-3.824) J40(19.076,-3.805) J41(19.638,-3.737) K6(2.519,-4.22) K7(3.217,-4.55) K11(4.735,-4.339) K13(6.066,-4.557) K16(7.158,-4.595) K18(8.555,-4.633) K21(9.8,-4.634) K29(13.828,-4.634) K32(15.073,-4.633) K34(16.47,-4.595) K37(17.562,-4.557) K39(18.893,-4.339) K43(20.411,-4.55) K44(21.109,-4.22) L9(3.9,-4.898) L24(11.235,-4.726) L26(12.393,-4.726) L41(19.728,-4.898) M6(2.519,-5.655) M10(4.633,-5.541) M16(7.463,-5.37) M18(8.555,-5.395) M21(9.8,-5.412) M24(11.235,-5.488) M26(12.393,-5.488) M29(13.828,-5.412) M32(15.073,-5.395) M34(16.165,-5.37) M40(18.995,-5.541) M44(21.109,-5.655) N8(3.306,-5.845) N12(5.37,-5.871) N13(6.132,-5.871) N15(6.894,-5.871) N16(7.463,-6.132) N18(8.555,-6.157) N32(15.073,-6.157) N34(16.165,-6.132) N35(16.734,-5.871) N37(17.496,-5.871) N38(18.258,-5.871) N42(20.322,-5.845) P9(3.9,-6.346) P21(9.8,-6.25) P24(11.235,-6.25) P26(12.393,-6.25) P29(13.828,-6.25) P41(19.728,-6.346) R6(2.519,-7.09) R10(4.633,-6.658) R12(5.37,-6.963) R13(6.132,-6.963) R15(6.894,-6.963) R16(7.463,-6.919) R18(8.555,-6.919) R21(9.8,-7.025) R24(11.235,-7.012) R26(12.393,-7.012) R29(13.828,-7.025) R32(15.073,-6.919) R34(16.165,-6.919) R35(16.734,-6.963) R37(17.496,-6.963) R38(18.258,-6.963) R40(18.995,-6.658) R44(21.109,-7.09) T7(3.179,-7.471) T17(8.003,-7.631) T18(8.555,-7.631) T32(15.073,-7.631) T43(20.449,-7.471) U9(3.9,-7.819) U10(4.633,-8.055) U12(5.395,-8.055) U13(6.157,-8.055) U15(6.919,-8.055) U17(7.681,-8.055) U21(9.8,-7.736) U24(11.235,-7.723) U26(12.393,-7.723) U29(13.828,-7.736) U33(15.947,-8.055) U35(16.709,-8.055) U37(17.471,-8.055) U38(18.233,-8.055) U40(18.995,-8.055) U41(19.728,-7.819) V19(8.715,-8.215) V20(9.49,-8.215) V22(10.265,-8.215) V23(11.039,-8.215) V25(11.814,-8.215) V27(12.589,-8.215) V28(13.363,-8.215) V30(14.138,-8.215) V31(14.913,-8.215) W6(2.417,-8.728) W7(3.156,-8.919) W19(8.715,-8.99) W20(9.49,-8.99) W22(10.265,-8.99) W23(11.039,-8.99) W25(11.814,-8.99) W27(12.589,-8.99) W28(13.363,-8.99) W30(14.138,-8.99) W31(14.913,-8.99) W43(20.472,-8.919) W44(21.211,-8.728) Y9(3.895,-9.109) Y10(4.634,-9.3) Y12(5.412,-9.3) Y14(6.25,-9.3) Y15(7.025,-9.3) Y17(7.787,-9.3) Y33(15.841,-9.3) Y35(16.603,-9.3) Y36(17.378,-9.3) Y38(18.216,-9.3) Y40(18.994,-9.3) Y41(19.733,-9.109)
  round 0.279 smd: A5(1.856,0) A45(21.772,0) BC1(0,-20.772) BC49(23.628,-20.772) BG5(1.856,-22.628) BG45(21.772,-22.628) E1(0,-1.856) E49(23.628,-1.856)
  oval 0.203x0.254 smd: A6(2.415,0) A8(3.52,0) A42(20.108,0) A44(21.213,0) BD8(3.403,-21.127) BD12(5.6,-21.127) BD17(7.797,-21.127) BD21(9.994,-21.127) BD29(13.634,-21.127) BD33(15.831,-21.127) BD38(18.028,-21.127) BD42(20.225,-21.127) BE9(4.03,-21.5) BE10(4.531,-21.373) BE14(6.227,-21.5) BE15(6.728,-21.373) BE18(8.424,-21.5) BE19(8.925,-21.373) BE23(10.621,-21.5) BE24(11.122,-21.373) BE26(12.506,-21.373) BE27(13.007,-21.5) BE31(14.703,-21.373) BE32(15.204,-21.5) BE35(16.9,-21.373) BE36(17.401,-21.5) BE40(19.097,-21.373) BE41(19.598,-21.5) BG6(2.415,-22.628) BG8(3.52,-22.628) BG42(20.108,-22.628) BG44(21.213,-22.628) C9(4.03,-1.128) C10(4.531,-1.255) C14(6.227,-1.128) C15(6.728,-1.255) C18(8.424,-1.128) C19(8.925,-1.255) C23(10.621,-1.128) C24(11.122,-1.255) C26(12.506,-1.255) C27(13.007,-1.128) C31(14.703,-1.255) C32(15.204,-1.128) C35(16.9,-1.255) C36(17.401,-1.128) C40(19.097,-1.255) C41(19.598,-1.128) D8(3.403,-1.501) D12(5.6,-1.501) D17(7.797,-1.501) D21(9.994,-1.501) D29(13.634,-1.501) D33(15.831,-1.501) D38(18.028,-1.501) D42(20.225,-1.501)
  oval 0.178x0.254 smd: A13(5.742,0) A17(7.939,0) A22(10.136,0) A25(11.814,0) A28(13.492,0) A33(15.689,0) A37(17.886,0) B10(4.691,-0.711) B12(5.549,-0.498) B14(6.227,-0.627) B15(6.888,-0.711) B17(7.746,-0.498) B18(8.424,-0.627) B19(9.085,-0.711) B21(9.943,-0.498) B23(10.621,-0.627) B24(11.282,-0.711) B25(11.814,-0.508) B26(12.346,-0.711) B27(13.007,-0.627) B29(13.685,-0.498) B31(14.543,-0.711) B32(15.204,-0.627) B33(15.882,-0.498) B35(16.74,-0.711) B36(17.401,-0.627) B38(18.079,-0.498) B40(18.937,-0.711) BE11(5.054,-21.432) BE12(5.519,-21.627) BE16(7.251,-21.432) BE17(7.716,-21.627) BE20(9.448,-21.432) BE21(9.913,-21.627) BE25(11.814,-21.612) BE29(13.715,-21.627) BE30(14.18,-21.432) BE33(15.912,-21.627) BE34(16.377,-21.432) BE38(18.109,-21.627) BE39(18.575,-21.432) BF10(4.691,-21.917) BF12(5.549,-22.129) BF14(6.227,-22) BF15(6.888,-21.917) BF17(7.746,-22.129) BF18(8.424,-22) BF19(9.085,-21.917) BF21(9.943,-22.129) BF23(10.621,-22) BF24(11.282,-21.917) BF25(11.814,-22.12) BF26(12.346,-21.917) BF27(13.007,-22) BF29(13.685,-22.129) BF31(14.543,-21.917) BF32(15.204,-22) BF33(15.882,-22.129) BF35(16.74,-21.917) BF36(17.401,-22) BF38(18.079,-22.129) BF40(18.937,-21.917) BG13(5.742,-22.628) BG17(7.939,-22.628) BG22(10.136,-22.628) BG25(11.814,-22.628) BG28(13.492,-22.628) BG33(15.689,-22.628) BG37(17.886,-22.628) C11(5.054,-1.196) C12(5.519,-1.001) C16(7.251,-1.196) C17(7.716,-1.001) C20(9.448,-1.196) C21(9.913,-1.001) C25(11.814,-1.016) C29(13.715,-1.001) C30(14.18,-1.196) C33(15.912,-1.001) C34(16.377,-1.196) C38(18.109,-1.001) C39(18.575,-1.196)
  oval 0.254x0.178 smd: AA1(0,-9.636) AA49(23.628,-9.636) AB2(0.627,-10.121) AB48(23.001,-10.121) AC2(0.711,-10.782) AC48(22.917,-10.782) AD1(0,-11.314) AD2(0.508,-11.314) AD3(1.016,-11.314) AD47(22.612,-11.314) AD48(23.12,-11.314) AD49(23.628,-11.314) AE2(0.711,-11.846) AE48(22.917,-11.846) AF2(0.627,-12.507) AF48(23.001,-12.507) AG1(0,-12.992) AG49(23.628,-12.992) AH2(0.498,-13.185) AH3(1.001,-13.215) AH47(22.627,-13.215) AH48(23.13,-13.185) AJ3(1.196,-13.68) AJ47(22.432,-13.68) AK2(0.711,-14.043) AK48(22.917,-14.043) AL2(0.627,-14.704) AL48(23.001,-14.704) AM1(0,-15.189) AM2(0.498,-15.382) AM3(1.001,-15.412) AM47(22.627,-15.412) AM48(23.13,-15.382) AM49(23.628,-15.189) AN3(1.196,-15.877) AN47(22.432,-15.877) AP2(0.711,-16.24) AP48(22.917,-16.24) P2(0.711,-6.388) P48(22.917,-6.388) R3(1.196,-6.751) R47(22.432,-6.751) T1(0,-7.439) T2(0.498,-7.246) T3(1.001,-7.216) T47(22.627,-7.216) T48(23.13,-7.246) T49(23.628,-7.439) U2(0.627,-7.924) U48(23.001,-7.924) V2(0.711,-8.585) V48(22.917,-8.585) W3(1.196,-8.948) W47(22.432,-8.948) Y2(0.498,-9.443) Y3(1.001,-9.413) Y47(22.627,-9.413) Y48(23.13,-9.443)
  round 0.254 smd: AA5(1.958,-9.712) AA45(21.67,-9.712) AC4(1.754,-10.735) AC46(21.874,-10.735) AE4(1.754,-11.893) AE46(21.874,-11.893) AG5(1.958,-12.915) AG45(21.67,-12.915) AJ4(1.716,-13.588) AJ46(21.912,-13.588) AK4(1.754,-14.09) AK46(21.874,-14.09) AM5(1.958,-15.112) AM45(21.67,-15.112) AN4(1.716,-15.785) AN46(21.912,-15.785) AP4(1.754,-16.287) AP46(21.874,-16.287) AT5(1.958,-17.31) AT45(21.67,-17.31) AV4(1.716,-17.982) AV46(21.912,-17.982) AW4(1.754,-18.484) AW46(21.874,-18.484) B6(2.417,-0.503) B44(21.211,-0.503) BA2(0.498,-19.84) BA3(1.005,-19.908) BA4(1.51,-19.782) BA5(1.958,-19.507) BA45(21.67,-19.507) BA46(22.118,-19.782) BA47(22.623,-19.908) BA48(23.13,-19.84) BB3(0.496,-20.629) BB4(0.989,-20.44) BB46(22.64,-20.44) BB47(23.132,-20.629) BC8(3.621,-20.67) BC10(4.644,-20.874) BC13(5.818,-20.67) BC15(6.841,-20.874) BC17(8.015,-20.67) BC19(9.038,-20.874) BC22(10.213,-20.67) BC24(11.235,-20.874) BC26(12.393,-20.874) BC28(13.416,-20.67) BC31(14.59,-20.874) BC33(15.613,-20.67) BC35(16.787,-20.874) BC37(17.81,-20.67) BC40(18.984,-20.874) BC42(20.007,-20.67) BD7(2.9,-21.186) BD11(5.146,-20.912) BD16(7.343,-20.912) BD20(9.54,-20.912) BD30(14.088,-20.912) BD34(16.285,-20.912) BD39(18.483,-20.912) BD43(20.728,-21.186) BE6(2.723,-21.671) BE44(20.905,-21.671) BF6(2.417,-22.125) BF44(21.211,-22.125) C6(2.723,-0.957) C44(20.905,-0.957) D7(2.9,-1.441) D11(5.146,-1.716) D16(7.343,-1.716) D20(9.54,-1.716) D30(14.088,-1.716) D34(16.285,-1.716) D39(18.483,-1.716) D43(20.728,-1.441) E8(3.621,-1.958) E10(4.644,-1.754) E13(5.818,-1.958) E15(6.841,-1.754) E17(8.015,-1.958) E19(9.038,-1.754) E22(10.213,-1.958) E24(11.235,-1.754) E26(12.393,-1.754) E28(13.416,-1.958) E31(14.59,-1.754) E33(15.613,-1.958) E35(16.787,-1.754) E37(17.81,-1.958) E40(18.984,-1.754) E42(20.007,-1.958) F3(0.496,-1.999) F4(0.989,-2.187) F46(22.64,-2.187) F47(23.132,-1.999) G2(0.498,-2.788) G3(1.005,-2.72) G4(1.51,-2.846) G5(1.958,-3.121) G45(21.67,-3.121) G46(22.118,-2.846) G47(22.623,-2.72) G48(23.13,-2.788) J4(1.754,-4.144) J46(21.874,-4.144) K4(1.716,-4.645) K46(21.912,-4.645) M5(1.958,-5.318) M45(21.67,-5.318) P4(1.754,-6.341) P46(21.874,-6.341) R4(1.716,-6.843) R46(21.912,-6.843) T5(1.958,-7.515) T45(21.67,-7.515) V4(1.754,-8.538) V46(21.874,-8.538) W4(1.716,-9.04) W46(21.912,-9.04)
  oval 0.254x0.203 smd: AB3(1.128,-10.121) AB47(22.5,-10.121) AC3(1.255,-10.622) AC47(22.373,-10.622) AE3(1.255,-12.006) AE47(22.373,-12.006) AF3(1.128,-12.507) AF47(22.5,-12.507) AH4(1.501,-13.134) AH46(22.127,-13.134) AK3(1.255,-14.197) AK47(22.373,-14.197) AL3(1.128,-14.704) AL47(22.5,-14.704) AM4(1.501,-15.331) AM46(22.127,-15.331) AP3(1.255,-16.394) AP47(22.373,-16.394) AR3(1.128,-16.901) AR47(22.5,-16.901) AT1(0,-17.411) AT49(23.628,-17.411) AU4(1.501,-17.528) AU46(22.127,-17.528) AW3(1.255,-18.591) AW47(22.373,-18.591) AY3(1.128,-19.098) AY47(22.5,-19.098) BA1(0,-19.634) BA49(23.628,-19.634) G1(0,-2.994) G49(23.628,-2.994) H3(1.128,-3.53) H47(22.5,-3.53) J3(1.255,-4.037) J47(22.373,-4.037) L4(1.501,-5.1) L46(22.127,-5.1) M1(0,-5.217) M49(23.628,-5.217) N3(1.128,-5.727) N47(22.5,-5.727) P3(1.255,-6.234) P47(22.373,-6.234) T4(1.501,-7.297) T46(22.127,-7.297) U3(1.128,-7.924) U47(22.5,-7.924) V3(1.255,-8.431) V47(22.373,-8.431) Y4(1.501,-9.494) Y46(22.127,-9.494)
  oval 0.305x0.152 smd: AR2(0.627,-16.901) AR48(23.001,-16.901) AU2(0.498,-17.579) AU3(1.001,-17.609) AU47(22.627,-17.609) AU48(23.13,-17.579) AV3(1.196,-18.074) AV47(22.432,-18.074) AW2(0.711,-18.437) AW48(22.917,-18.437) AY2(0.627,-19.098) AY48(23.001,-19.098) H2(0.627,-3.53) H48(23.001,-3.53) J2(0.711,-4.19) J48(22.917,-4.19) K3(1.196,-4.553) K47(22.432,-4.553) L2(0.498,-5.049) L3(1.001,-5.019) L47(22.627,-5.019) L48(23.13,-5.049) N2(0.627,-5.727) N48(23.001,-5.727)
  oval 0.152x0.305 smd: B8(3.352,-0.498) B9(4.03,-0.627) B41(19.598,-0.627) B42(20.276,-0.498) BE8(3.322,-21.627) BE42(20.307,-21.627) BF8(3.352,-22.129) BF9(4.03,-22) BF41(19.598,-22) BF42(20.276,-22.129) C8(3.322,-1.001) C42(20.307,-1.001)
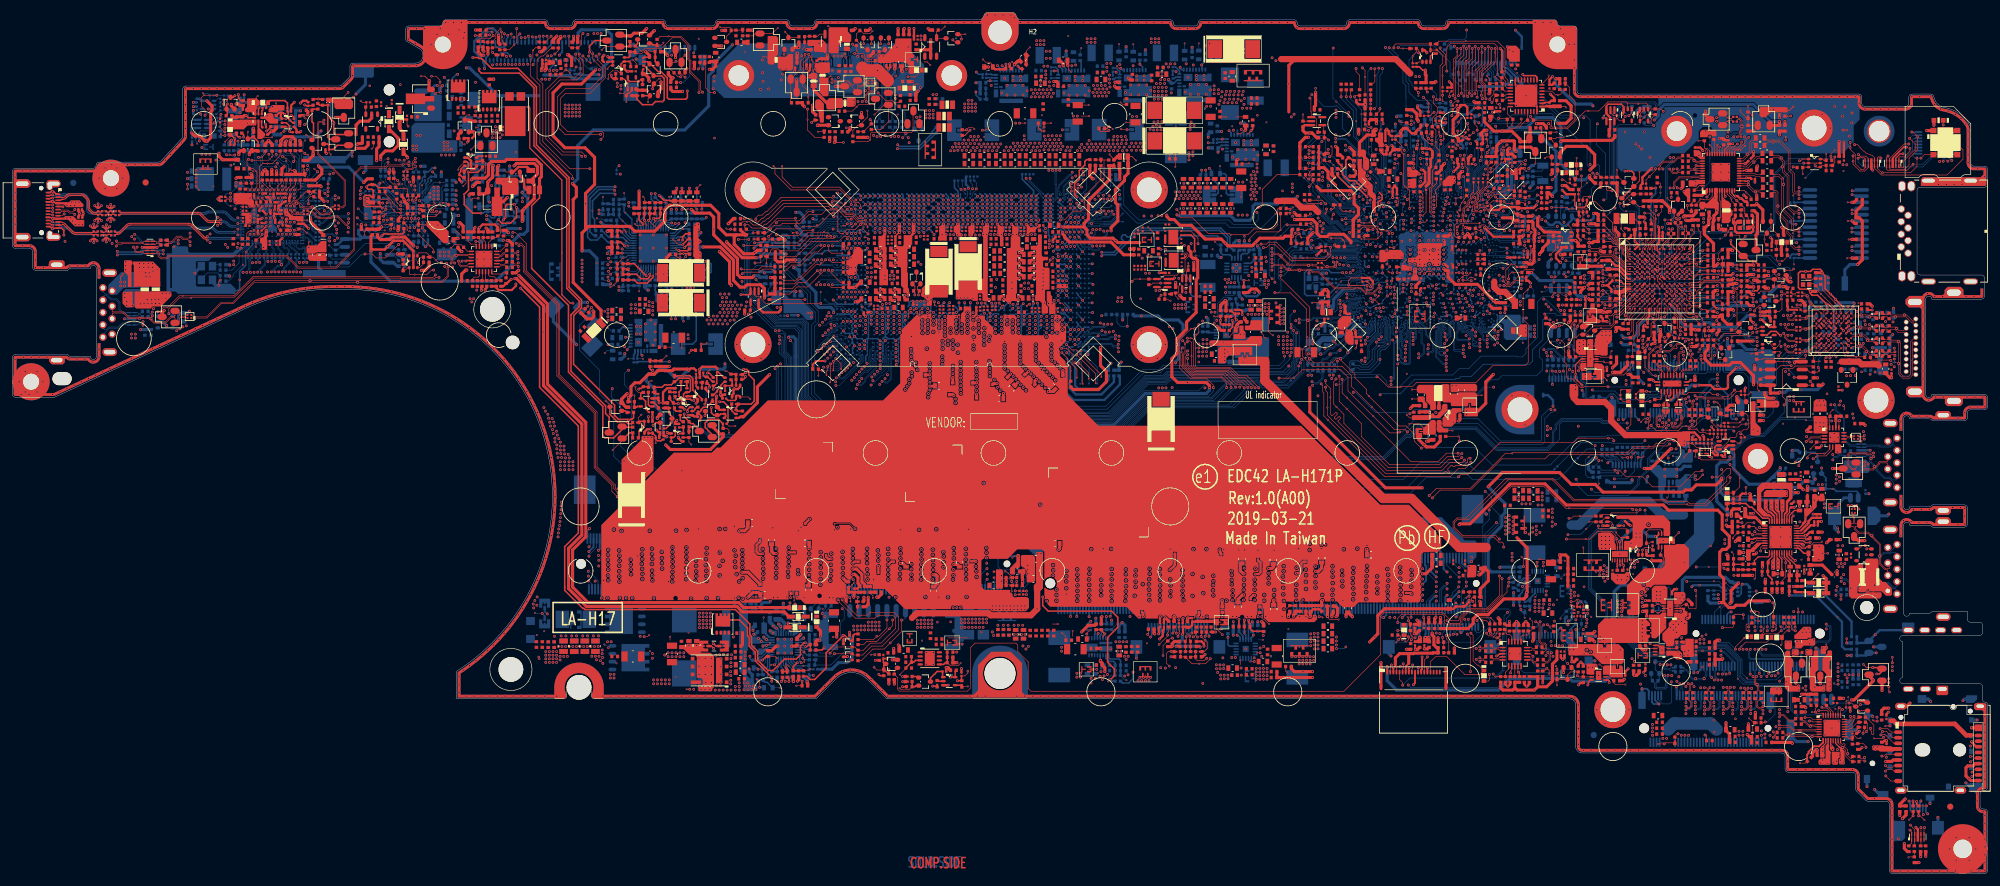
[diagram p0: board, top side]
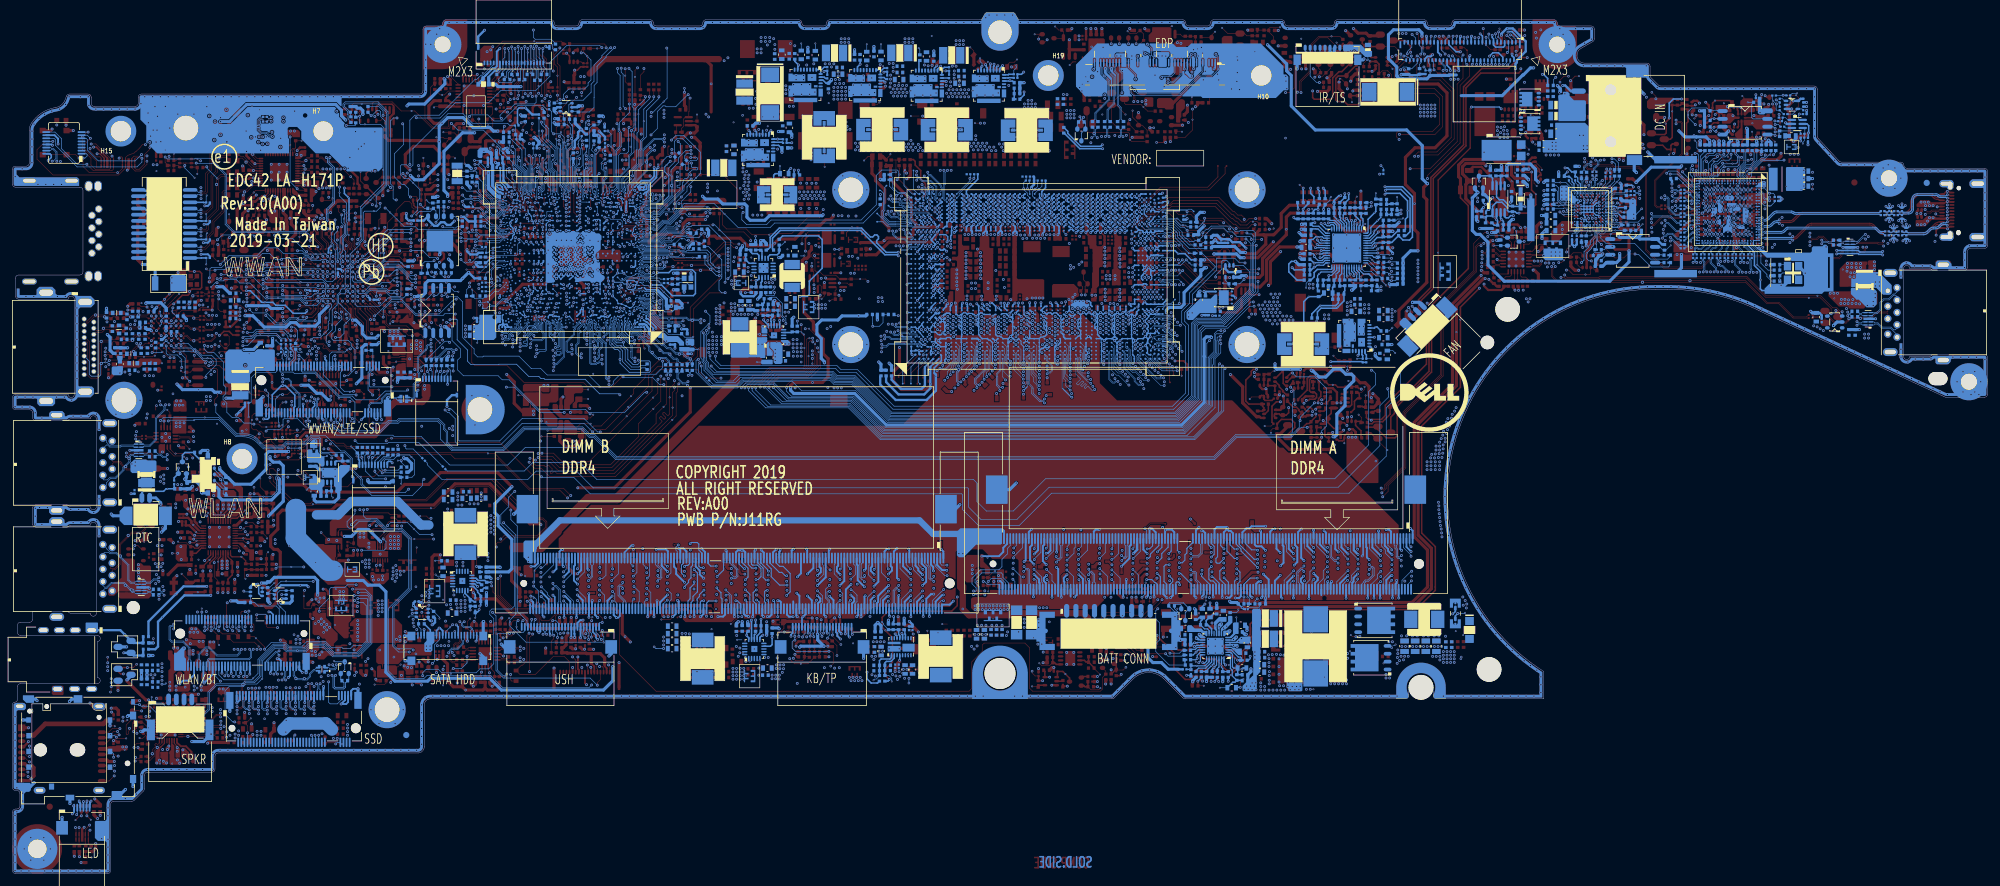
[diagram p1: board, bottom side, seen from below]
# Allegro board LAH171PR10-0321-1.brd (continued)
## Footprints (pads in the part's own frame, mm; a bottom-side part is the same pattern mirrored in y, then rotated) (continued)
CVILU_CF4218FH0R0-05-NH_18P-T
  oval 0.305x0.787 smd: 1(0,0) 2(0.5,0) 3(1,0) 4(1.5,0) 5(2,0) 6(2.5,0) 7(3,0) 8(3.5,0) 9(4,0) 10(4.5,0) 11(5,0) 12(5.5,0) 13(6,0) 14(6.5,0) 15(7,0) 16(7.5,0) 17(8,0) 18(8.5,0)
  rect 0.406x0.787 smd: 19(-1,-2.5) 20(9.5,-2.5)
CVILU_CI0805M1HRC-NH_5P-T
  round 1.803 hole 1.803 unplated: (-0.2,5.2) (8.2,5.2)
  oval 0.889x2.388 smd: 1(0,0) 2(2,0) 3(4,0) 4(6,0) 5(8,0)
  rect 1.6x2.489 smd: 6(11.15,9.05) 7(-3.15,9.05)
CYNTE_PCMB042T-1R0MS_2P
  rect 1.499x2.489 smd: 1(0,0) 2(3.7,0)
CYNTE_PCMB051H-1R0MS_2P
  rect 2.159x2.794 smd: 1(0,0) 2(4.35,0)
DB3J315E0L_SMINI3-F2-B3
  oval 0.889x0.787 smd: 1(0,0) 2(-0.65,-1.9) 3(0.65,-1.9)
DDTA114EUA-7-F_SOT323-3
  oval 0.813x0.914 smd: 1(0,0) 2(0.65,1.6) 3(-0.65,1.6)
DEREN_40-42251-01001RHF_10P-T
  oval 0.838x2.21 smd: 1(0,0.1) 2(1.5,0.1) 3(3,0.1) 4(4.5,0.1) 5(6,0.1) 6(7.5,0.1) 7(9,0.1) 8(10.5,0.1) 9(12,0.1) 10(13.5,0.1)
  custom 0.75x0.75 smd: 11(-3.4,-3.15) 12(16.9,-3.15)
DMN65D8LDW-7_SOT363-6
  oval 0.432x0.61 smd: 1(0,0) 2(0.65,0) 3(1.3,0) 4(1.3,1.9) 5(0.65,1.9) 6(0,1.9)
DMN65D8LW-7_SOT323-3
  oval 0.711x0.889 smd: 1(0,0) 2(-0.65,-1.9) 3(0.65,-1.9)
DMN66D0LDW-7_SOT363-6
  oval 0.432x0.61 smd: 1(0,0) 2(0.65,0) 3(1.3,0) 4(1.3,1.9) 5(0.65,1.9) 6(0,1.9)
EM1109V-AD_DFN3308-8_3X3
  oval 0.381x0.889 smd: 1(0,0) 2(0.65,0) 3(1.3,0) 4(1.95,0) 5(1.95,3.1) 6(1.3,3.1) 7(0.65,3.1) 8(0,3.1)
  rect 2.388x1.6 smd: 9(0.975,1.55)
EM5209VF_DFN14_3X2
  oval 0.203x0.711 smd: 1(0,0) 2(0.4,0) 3(0.8,0) 4(1.2,0) 5(1.6,0) 6(2,0) 7(2.4,0) 8(2.4,2) 9(2,2) 10(1.6,2) 11(1.2,2) 12(0.8,2) 13(0.4,2) 14(0,2)
  rect 2.591x0.991 smd: 15(1.2,1)
EMIST_SUL-12A2M_1P
  rect 6.909x1.194 smd: 1(0,0)
ESD8011MUT5G_X3DFN2-2
  rect 0.33x0.356 smd: 1(0,0) 2(0.43,0)
F_T0603FF1000TM
  rect 0.711x0.991 smd: 1(0,0) 2(1.5,0)
F_T0603FF1000TM-NPM
  rect 0.711x0.991 smd: 1(0,0) 2(1.5,0)
FDMC6679AZ_MLP8-5
  oval 0.432x0.711 smd: 1(0,0) 2(0.65,0) 3(1.3,0) 4(1.95,0)
  custom 0.537x0.537 smd: 5(0.975,2.075)
FDV301N-G_SOT23-3
  oval 1.016x1.524 smd: 1(0,0) 2(0.965,2.083) 3(-0.965,2.083)
FIDUCIAL_C40M80
  round 1.016 smd: 1(0,0)
FOX_ASAA821-H4RB5-7H_260P
  round 1.092 hole 1.092 unplated: (-67.775,-4.1)
  round 1.6 hole 1.6 unplated: (1.025,-4.1)
  oval 0.305x1.753 smd: 1(0,0) 2(-0.25,-8.2) 3(-0.5,0) 4(-0.75,-8.2) 5(-1,0) 6(-1.25,-8.2) 7(-1.5,0) 8(-1.75,-8.2) 9(-2,0) 10(-2.25,-8.2) 11(-2.5,0) 12(-2.75,-8.2) 13(-3,0) 14(-3.25,-8.2) 15(-3.5,0) 16(-3.75,-8.2) 17(-4,0) 18(-4.25,-8.2) 19(-4.5,0) 20(-4.75,-8.2) 21(-5,0) 22(-5.25,-8.2) 23(-5.5,0) 24(-5.75,-8.2) 25(-6,0) 26(-6.25,-8.2) 27(-6.5,0) 28(-6.75,-8.2) 29(-7,0) 30(-7.25,-8.2) 31(-7.5,0) 32(-7.75,-8.2) 33(-8,0) 34(-8.25,-8.2) 35(-8.5,0) 36(-8.75,-8.2) 37(-9,0) 38(-9.25,-8.2) 39(-9.5,0) 40(-9.75,-8.2) 41(-10,0) 42(-10.25,-8.2) 43(-10.5,0) 44(-10.75,-8.2) 45(-11,0) 46(-11.25,-8.2) 47(-11.5,0) 48(-11.75,-8.2) 49(-12,0) 50(-12.25,-8.2) 51(-12.5,0) 52(-12.75,-8.2) 53(-13,0) 54(-13.25,-8.2) 55(-13.5,0) 56(-13.75,-8.2) 57(-14,0) 58(-14.25,-8.2) 59(-14.5,0) 60(-14.75,-8.2) 61(-15,0) 62(-15.25,-8.2) 63(-15.5,0) 64(-15.75,-8.2) 65(-16,0) 66(-16.25,-8.2) 67(-16.5,0) 68(-16.75,-8.2) 69(-17,0) 70(-17.25,-8.2) 71(-17.5,0) 72(-17.75,-8.2) 73(-18,0) 74(-18.25,-8.2) 75(-18.5,0) 76(-18.75,-8.2) 77(-19,0) 78(-19.25,-8.2) 79(-19.5,0) 80(-19.75,-8.2) 81(-20,0) 82(-20.25,-8.2) 83(-20.5,0) 84(-20.75,-8.2) 85(-21,0) 86(-21.25,-8.2) 87(-21.5,0) 88(-21.75,-8.2) 89(-22,0) 90(-22.25,-8.2) 91(-22.5,0) 92(-22.75,-8.2) 93(-23,0) 94(-23.25,-8.2) 95(-23.5,0) 96(-23.75,-8.2) 97(-24,0) 98(-24.25,-8.2) 99(-24.5,0) 100(-24.75,-8.2) 101(-25,0) 102(-25.25,-8.2) 103(-25.5,0) 104(-25.75,-8.2) 105(-26,0) 106(-26.25,-8.2) 107(-26.5,0) 108(-26.75,-8.2) 109(-27,0) 110(-27.25,-8.2) 111(-27.5,0) 112(-27.75,-8.2) 113(-28,0) 114(-28.25,-8.2) 115(-28.5,0) 116(-28.75,-8.2) 117(-29,0) 118(-29.25,-8.2) 119(-29.5,0) 120(-29.75,-8.2) 121(-30,0) 122(-30.25,-8.2) 123(-30.5,0) 124(-30.75,-8.2) 125(-31,0) 126(-31.25,-8.2) 127(-31.5,0) 128(-31.75,-8.2) 129(-32,0) 130(-32.25,-8.2) 131(-32.5,0) 132(-32.75,-8.2) 133(-33,0) 134(-33.25,-8.2) 135(-33.5,0) 136(-33.75,-8.2) 137(-34,0) 138(-34.25,-8.2) 139(-34.5,0) 140(-34.75,-8.2) 141(-35,0) 142(-35.25,-8.2) 143(-35.5,0) 144(-35.75,-8.2) 145(-38,0) 146(-38.25,-8.2) 147(-38.5,0) 148(-38.75,-8.2) 149(-39,0) 150(-39.25,-8.2) 151(-39.5,0) 152(-39.75,-8.2) 153(-40,0) 154(-40.25,-8.2) 155(-40.5,0) 156(-40.75,-8.2) 157(-41,0) 158(-41.25,-8.2) 159(-41.5,0) 160(-41.75,-8.2) 161(-42,0) 162(-42.25,-8.2) 163(-42.5,0) 164(-42.75,-8.2) 165(-43,0) 166(-43.25,-8.2) 167(-43.5,0) 168(-43.75,-8.2) 169(-44,0) 170(-44.25,-8.2) 171(-44.5,0) 172(-44.75,-8.2) 173(-45,0) 174(-45.25,-8.2) 175(-45.5,0) 176(-45.75,-8.2) 177(-46,0) 178(-46.25,-8.2) 179(-46.5,0) 180(-46.75,-8.2) 181(-47,0) 182(-47.25,-8.2) 183(-47.5,0) 184(-47.75,-8.2) 185(-48,0) 186(-48.25,-8.2) 187(-48.5,0) 188(-48.75,-8.2) 189(-49,0) 190(-49.25,-8.2) 191(-49.5,0) 192(-49.75,-8.2) 193(-50,0) 194(-50.25,-8.2) 195(-50.5,0) 196(-50.75,-8.2) 197(-51,0) 198(-51.25,-8.2) 199(-51.5,0) 200(-51.75,-8.2) 201(-52,0) 202(-52.25,-8.2) 203(-52.5,0) 204(-52.75,-8.2) 205(-53,0) 206(-53.25,-8.2) 207(-53.5,0) 208(-53.75,-8.2) 209(-54,0) 210(-54.25,-8.2) 211(-54.5,0) 212(-54.75,-8.2) 213(-55,0) 214(-55.25,-8.2) 215(-55.5,0) 216(-55.75,-8.2) 217(-56,0) 218(-56.25,-8.2) 219(-56.5,0) 220(-56.75,-8.2) 221(-57,0) 222(-57.25,-8.2) 223(-57.5,0) 224(-57.75,-8.2) 225(-58,0) 226(-58.25,-8.2) 227(-58.5,0) 228(-58.75,-8.2) 229(-59,0) 230(-59.25,-8.2) 231(-59.5,0) 232(-59.75,-8.2) 233(-60,0) 234(-60.25,-8.2) 235(-60.5,0) 236(-60.75,-8.2) 237(-61,0) 238(-61.25,-8.2) 239(-61.5,0) 240(-61.75,-8.2) 241(-62,0) 242(-62.25,-8.2) 243(-62.5,0) 244(-62.75,-8.2) 245(-63,0) 246(-63.25,-8.2) 247(-63.5,0) 248(-63.75,-8.2) 249(-64,0) 250(-64.25,-8.2) 251(-64.5,0) 252(-64.75,-8.2) 253(-65,0) 254(-65.25,-8.2) 255(-65.5,0) 256(-65.75,-8.2) 257(-66,0) 258(-66.25,-8.2) 259(-66.5,0) 260(-66.75,-8.2)
  rect 3.505x4.597 smd: 261(-67.175,7.9) 262(0.425,7.9)
FOX_GS12206-10100-7H_20P-T
  oval 0.254x1.143 smd: 1(0,0) 2(0.5,0) 3(1,0) 4(1.5,0) 5(2,0) 6(2.5,0) 7(3,0) 8(3.5,0) 9(4,0) 10(4.5,0) 11(5,0) 12(5.5,0) 13(6,0) 14(6.5,0) 15(7,0) 16(7.5,0) 17(8,0) 18(8.5,0) 19(9,0) 20(9.5,0)
  rect 1.295x1.397 smd: 21(10.55,0.125) 22(10.55,4.125) 23(-1.05,4.125) 24(-1.05,0.125)
FOX_QT510166-L010-7H_16P
  oval 0.305x1.295 smd: 1(0,0) 2(0,-5.7) 3(-0.5,0) 4(-0.5,-5.7) 5(-1,0) 6(-1,-5.7) 7(-1.5,0) 8(-1.5,-5.7) 9(-2,0) 10(-2,-5.7) 11(-2.5,0) 12(-2.5,-5.7) 13(-3,0) 14(-3,-5.7) 15(-3.5,0) 16(-3.5,-5.7)
G524B1T11U_SOT23-5
  oval 0.533x1.194 smd: 1(0,0) 2(0.95,0) 3(1.9,0) 4(1.9,3) 5(0,3)
H_2P1N
  round 2.108 hole 2.108 unplated: (0,0)
H_2P1X3P1N
  oval 2.108x3.099 hole 2.108x3.099 unplated: (0,0)
H_2P2N
  round 2.21 hole 2.21 unplated: (0,0)
H_2P5X2P1N
  oval 2.489x2.108 hole 2.489x2.108 unplated: (0,0)
H_2P6-G
  round 3.099 hole 2.591: 1(0,0)
H_3P0-G
  round 3.505 hole 2.997: 1(0,0)
H_3P2
  round 3.708 hole 3.2: 1(0,0)
H_3P3
  round 3.81 hole 3.302: 1(0,0)
H_3P8
  round 4.318 hole 3.81: 1(0,0)
H_4P0-G
  round 4.496 hole 3.988: 1(0,0)
H_4P0N
  round 3.988 hole 3.988 unplated: (0,0)
H_5P0N
  round 5.004 hole 5.004 unplated: (0,0)
HRS_TF31-6S-0P5SH_6P-T
  oval 0.305x1.295 smd: 1(0,0) 2(0.5,0) 3(1,0) 4(1.5,0) 5(2,0) 6(2.5,0)
  rect 1.905x2.21 smd: 7(-1.95,-3.25) 8(4.45,-3.25)
HRS_TF31-20S-0P5SH-800_20P-T
  oval 0.305x1.295 smd: 1(0,0) 2(0.5,0) 3(1,0) 4(1.5,0) 5(2,0) 6(2.5,0) 7(3,0) 8(3.5,0) 9(4,0) 10(4.5,0) 11(5,0) 12(5.5,0) 13(6,0) 14(6.5,0) 15(7,0) 16(7.5,0) 17(8,0) 18(8.5,0) 19(9,0) 20(9.5,0)
  rect 1.905x2.21 smd: 21(11.45,3.25) 22(-1.95,3.25)
HRS_TF31C-26S-0P5SH-800_26P-T
  oval 0.305x1.295 smd: 1(0,0) 2(0.5,0) 3(1,0) 4(1.5,0) 5(2,0) 6(2.5,0) 7(3,0) 8(3.5,0) 9(4,0) 10(4.5,0) 11(5,0) 12(5.5,0) 13(6,0) 14(6.5,0) 15(7,0) 16(7.5,0) 17(8,0) 18(8.5,0) 19(9,0) 20(9.5,0) 21(10,0) 22(10.5,0) 23(11,0) 24(11.5,0) 25(12,0) 26(12.5,0)
  rect 1.905x2.21 smd: 27(14.45,3.25) 28(-1.95,3.25)
INPAQ_HCM1012GH900BP_4P
  rect 0.711x0.305 smd: 1(0,0) 2(1.25,0) 3(1.25,-0.5) 4(0,-0.5)
INPAQ_MCM1012B900F06BP_4P
  rect 0.711x0.305 smd: 1(0,0) 2(1.25,0) 3(1.25,-0.5) 4(0,-0.5)
INPAQ_MCM1012B900F06BP_4P-NPM
  rect 0.711x0.305 smd: 1(0,0) 2(1.25,0) 3(1.25,-0.5) 4(0,-0.5)
ISL88738HRTZ-T_TQFN32_4X4
  oval 0.889x0.203 smd: 1(0,0) 2(0,-0.4) 3(0,-0.8) 4(0,-1.2) 5(0,-1.6) 6(0,-2) 7(0,-2.4) 8(0,-2.8) 17(4.1,-2.8) 18(4.1,-2.4) 19(4.1,-2) 20(4.1,-1.6) 21(4.1,-1.2) 22(4.1,-0.8) 23(4.1,-0.4) 24(4.1,0)
  oval 0.203x0.889 smd: 9(0.65,-3.45) 10(1.05,-3.45) 11(1.45,-3.45) 12(1.85,-3.45) 13(2.25,-3.45) 14(2.65,-3.45) 15(3.05,-3.45) 16(3.45,-3.45) 25(3.45,0.65) 26(3.05,0.65) 27(2.65,0.65) 28(2.25,0.65) 29(1.85,0.65) 30(1.45,0.65) 31(1.05,0.65) 32(0.65,0.65)
  rect 2.692x2.692 smd: 33(2.05,-1.4)
JAE_DX07SD24JJ2R1300_24P
  round 0.711 hole 0.711 unplated: (-0.975,-2.7)
  oval 0.838x0.711 hole 0.838x0.711 unplated: (6.225,-2.635)
  oval 1.295x2.591 hole 0.711x2.007: 1(-1.695,-5.75) 3(6.945,-5.75)
  oval 1.194x2.311 hole 0.61x1.905: 2(-1.695,-0.7) 4(6.945,-0.7)
  oval 1.651x1.092 hole 1.245x0.711: 5(-1.37,-1.3) 6(6.62,-1.3)
  oval 0.279x0.889 smd: A1(0,0) A2(0.5,0) A3(1,0) A4(1.5,0) A5(2,0) A6(2.5,0) A7(3,0) A8(3.5,0) A9(4,0) A10(4.5,0) A11(5,0) A12(5.5,0)
  oval 0.279x0.787 smd: B1(5.25,-1.6) B2(4.75,-1.6) B3(4.25,-1.6) B4(3.75,-1.6) B5(3.25,-1.6) B6(2.75,-1.6) B7(2.25,-1.6) B8(1.75,-1.6) B9(1.25,-1.6) B10(0.75,-1.6) B11(0.25,-1.6) B12(-0.25,-1.6)
JAE_SF51S006V4DR1000Q_8P-S
  round 0.762 hole 0.762 unplated: (-2.19,-10.215)
  round 0.889 hole 0.889 unplated: (7.01,2.835)
  rect 0.991x0.838 smd: 1(10.765,-9.44)
  rect 0.889x0.61 smd: 2(-2.94,3.715)
  custom 0.311x0.311 smd: 3(-3.39,-13.165)
  rect 1.245x1.397 smd: 4(-3.39,-5.165)
  rect 1.295x1.016 smd: 5(-0.715,3.725) 6(9.535,3.725)
  rect 1.041x1.397 smd: 7(12.1,1.025)
  rect 0.94x1.397 smd: 8(12.55,-6.465)
  rect 1.219x1.143 smd: 9(10.795,-13.49)
  rect 0.889x0.762 smd: C1(0,0) C2(2.54,0) C3(5.08,0) C4(7.62,0) C5(0,-13.15) C6(2.54,-13.15) C7(5.08,-13.15) C8(7.62,-13.15)
JUMP_43X39
  custom 0.191x0.191 smd: 1(0,0) 2(0.914,0)
JUMP_43X79
  custom 0.188x0.188 smd: 1(0,0) 2(1.1,0)
JUMP_43X118
  custom 0.187x0.187 smd: 1(0,0) 2(1.1,0)
JUMP_43X118-NPM
  custom 0.187x0.187 smd: 1(0,0) 2(1.1,0)
JXT_FP241AH-010GAAM_10P
  oval 0.305x1.092 smd: 1(0,0) 2(0.5,0) 3(1,0) 4(1.5,0) 5(2,0) 6(2.5,0) 7(3,0) 8(3.5,0) 9(4,0) 10(4.5,0)
  rect 0.406x0.787 smd: 11(-1,-2.65) 12(5.5,-2.65)
JXT_FP270H-061G1AM_61P
  oval 0.305x0.787 smd: 1(0,0) 3(0.6,0) 5(1.2,0) 7(1.8,0) 9(2.4,0) 11(3,0) 13(3.6,0) 15(4.2,0) 17(4.8,0) 19(5.4,0) 21(6,0) 23(6.6,0) 25(7.2,0) 27(7.8,0) 29(8.4,0) 31(9,0) 33(9.6,0) 35(10.2,0) 37(10.8,0) 39(11.4,0) 41(12,0) 43(12.6,0) 45(13.2,0) 47(13.8,0) 49(14.4,0) 51(15,0) 53(15.6,0) 55(16.2,0) 57(16.8,0) 59(17.4,0) 61(18,0)
  oval 0.305x0.66 smd: 2(0.3,2.875) 4(0.9,2.875) 6(1.5,2.875) 8(2.1,2.875) 10(2.7,2.875) 12(3.3,2.875) 14(3.9,2.875) 16(4.5,2.875) 18(5.1,2.875) 20(5.7,2.875) 22(6.3,2.875) 24(6.9,2.875) 26(7.5,2.875) 28(8.1,2.875) 30(8.7,2.875) 32(9.3,2.875) 34(9.9,2.875) 36(10.5,2.875) 38(11.1,2.875) 40(11.7,2.875) 42(12.3,2.875) 44(12.9,2.875) 46(13.5,2.875) 48(14.1,2.875) 50(14.7,2.875) 52(15.3,2.875) 54(15.9,2.875) 56(16.5,2.875) 58(17.1,2.875) 60(17.7,2.875)
  rect 0.305x1.143 smd: 62(-0.65,0.375) 63(18.65,0.375)
L2N7002DW1T1G_SC88-6
  oval 0.406x0.508 smd: 1(0,0) 2(0.65,0) 3(1.3,0) 4(1.3,1.9) 5(0.65,1.9) 6(0,1.9)
L2N7002WT1G_SC70-3
  oval 0.711x0.889 smd: 1(0,0) 2(0.65,1.9) 3(-0.65,1.9)
L2N7002WT1G_SC-70-3
  oval 0.711x0.889 smd: 1(0,0) 2(-0.65,-1.9) 3(0.65,-1.9)
L03ESDL5V0CC3-2_SOT23-3
  oval 1.016x1.524 smd: 1(0,0) 2(0.965,2.083) 3(-0.965,2.083)
L05ESDL5V0NA-4_SLP2510P8-10-9
  rect 0.203x0.686 smd: 1(0,0) 2(-0.5,0) 4(-1.5,0) 5(-2,0) 6(-2,-0.875) 7(-1.5,-0.875) 8(-0.5,-0.875) 9(0,-0.875)
  rect 0.406x1.549 smd: 3(-1,-0.437)
L_5X5X3_M_2P
  rect 2.159x2.794 smd: 1(0,0) 2(4.35,0)
L_7X7X3_M_2P
  rect 2.362x3.505 smd: 1(0,0) 2(6.05,0)
L_7X7X4_M
  custom 0.591x0.591 smd: 1(0,0) 4(6.05,0)
  rect 0.762x0.508 smd: 2(0.8,0) 3(5.25,0)
LED_LTW-C193DC-C_2P
  rect 0.787x0.787 smd: 1(0,0) 2(1.5,0)
LMBT3904WT1G_SC70-3
  oval 0.711x0.889 smd: 1(0,0) 2(0.65,1.9) 3(-0.65,1.9)
LNG2DMTR_LGA12_2X2
  oval 0.406x0.305 smd: 1(0,0) 4(0,-1.5) 7(1.602,-1.5) 10(1.602,0)
  oval 0.508x0.305 smd: 2(0.051,-0.5) 3(0.051,-1) 8(1.551,-1) 9(1.551,-0.5)
  oval 0.305x0.508 smd: 5(0.551,-1.5) 6(1.051,-1.5) 11(1.051,0) 12(0.551,0)
LOTES_APCI0079-P005A_75P
  round 1.092 hole 1.092 unplated: (-0.75,-5.275)
  round 1.6 hole 1.6 unplated: (19.25,-5.275)
  oval 0.305x1.549 smd: 1(0,0) 2(0.25,-7.55) 3(0.5,0) 4(0.75,-7.55) 5(1,0) 6(1.25,-7.55) 7(1.5,0) 8(1.75,-7.55) 9(2,0) 10(2.25,-7.55) 11(2.5,0) 12(2.75,-7.55) 13(3,0) 14(3.25,-7.55) 15(3.5,0) 16(3.75,-7.55) 17(4,0) 18(4.25,-7.55) 19(4.5,0) 20(4.75,-7.55) 21(5,0) 22(5.25,-7.55) 23(5.5,0) 24(5.75,-7.55) 25(6,0) 26(6.25,-7.55) 27(6.5,0) 28(6.75,-7.55) 29(7,0) 30(7.25,-7.55) 31(7.5,0) 32(7.75,-7.55) 33(8,0) 34(8.25,-7.55) 35(8.5,0) 36(8.75,-7.55) 37(9,0) 38(9.25,-7.55) 39(9.5,0) 40(9.75,-7.55) 41(10,0) 42(10.25,-7.55) 43(10.5,0) 44(10.75,-7.55) 45(11,0) 46(11.25,-7.55) 47(11.5,0) 48(11.75,-7.55) 49(12,0) 50(12.25,-7.55) 51(12.5,0) 52(12.75,-7.55) 53(13,0) 54(13.25,-7.55) 55(13.5,0) 56(13.75,-7.55) 57(14,0) 58(14.25,-7.55) 67(16.5,0) 68(16.75,-7.55) 69(17,0) 70(17.25,-7.55) 71(17.5,0) 72(17.75,-7.55) 73(18,0) 74(18.25,-7.55) 75(18.5,0)
  rect 1.194x2.743 smd: 76(-1.1,-0.775) 77(19.6,-0.775)
LOTES_APCI0103-P001A_75P-T
  round 1.092 hole 1.092 unplated: (-0.75,-5.275)
  round 1.6 hole 1.6 unplated: (19.25,-5.275)
  oval 0.305x1.549 smd: 1(0,0) 2(0.25,-7.55) 3(0.5,0) 4(0.75,-7.55) 5(1,0) 6(1.25,-7.55) 7(1.5,0) 8(1.75,-7.55) 9(2,0) 10(2.25,-7.55) 11(2.5,0) 20(4.75,-7.55) 21(5,0) 22(5.25,-7.55) 23(5.5,0) 24(5.75,-7.55) 25(6,0) 26(6.25,-7.55) 27(6.5,0) 28(6.75,-7.55) 29(7,0) 30(7.25,-7.55) 31(7.5,0) 32(7.75,-7.55) 33(8,0) 34(8.25,-7.55) 35(8.5,0) 36(8.75,-7.55) 37(9,0) 38(9.25,-7.55) 39(9.5,0) 40(9.75,-7.55) 41(10,0) 42(10.25,-7.55) 43(10.5,0) 44(10.75,-7.55) 45(11,0) 46(11.25,-7.55) 47(11.5,0) 48(11.75,-7.55) 49(12,0) 50(12.25,-7.55) 51(12.5,0) 52(12.75,-7.55) 53(13,0) 54(13.25,-7.55) 55(13.5,0) 56(13.75,-7.55) 57(14,0) 58(14.25,-7.55) 59(14.5,0) 60(14.75,-7.55) 61(15,0) 62(15.25,-7.55) 63(15.5,0) 64(15.75,-7.55) 65(16,0) 66(16.25,-7.55) 67(16.5,0) 68(16.75,-7.55) 69(17,0) 70(17.25,-7.55) 71(17.5,0) 72(17.75,-7.55) 73(18,0) 74(18.25,-7.55) 75(18.5,0)
  rect 1.194x2.743 smd: 76(-1.1,-0.775) 77(19.6,-0.775)
LOTES_APCI0136-P001A_75P
  round 1.092 hole 1.092 unplated: (-0.75,-5.275)
  round 1.6 hole 1.6 unplated: (19.25,-5.275)
  oval 0.305x1.549 smd: 1(0,0) 2(0.25,-7.55) 3(0.5,0) 4(0.75,-7.55) 5(1,0) 6(1.25,-7.55) 7(1.5,0) 8(1.75,-7.55) 9(2,0) 10(2.25,-7.55) 11(2.5,0) 12(2.75,-7.55) 13(3,0) 14(3.25,-7.55) 15(3.5,0) 16(3.75,-7.55) 17(4,0) 18(4.25,-7.55) 19(4.5,0) 20(4.75,-7.55) 21(5,0) 22(5.25,-7.55) 23(5.5,0) 32(7.75,-7.55) 33(8,0) 34(8.25,-7.55) 35(8.5,0) 36(8.75,-7.55) 37(9,0) 38(9.25,-7.55) 39(9.5,0) 40(9.75,-7.55) 41(10,0) 42(10.25,-7.55) 43(10.5,0) 44(10.75,-7.55) 45(11,0) 46(11.25,-7.55) 47(11.5,0) 48(11.75,-7.55) 49(12,0) 50(12.25,-7.55) 51(12.5,0) 52(12.75,-7.55) 53(13,0) 54(13.25,-7.55) 55(13.5,0) 56(13.75,-7.55) 57(14,0) 58(14.25,-7.55) 59(14.5,0) 60(14.75,-7.55) 61(15,0) 62(15.25,-7.55) 63(15.5,0) 64(15.75,-7.55) 65(16,0) 66(16.25,-7.55) 67(16.5,0) 68(16.75,-7.55) 69(17,0) 70(17.25,-7.55) 71(17.5,0) 72(17.75,-7.55) 73(18,0) 74(18.25,-7.55) 75(18.5,0)
  rect 1.194x2.743 smd: 76(-1.1,-0.775) 77(19.6,-0.775)
LP2301ALT1G_SOT23-3
  oval 1.016x1.524 smd: 1(0,0) 2(0.965,2.083) 3(-0.965,2.083)
MAG_MLV-FY12N1R0M-O1L_2P
  rect 0.889x2.489 smd: 1(0,0) 2(2.6,0)
MAG_MMD05CZR47M_4P
  custom 0.54x0.54 smd: 1(0,0) 4(4.35,0)
  rect 0.762x0.508 smd: 2(0.699,0) 3(3.652,0)
MAG_MMD-10DZ-1R0M-X1A_2P
  rect 4.242x3.988 smd: 1(0,0) 2(8.75,0)
MAG_MND-04ABIR60M-XGL_2P
  rect 1.448x3.708 smd: 1(0,0) 2(2.845,0)
MC74VHC1G32DFT2G_SC70-5
  oval 0.457x0.711 smd: 1(-0.65,-0.925) 2(0,-0.925) 3(0.65,-0.925) 4(0.65,0.925) 5(-0.65,0.925)
MEC5105_WFBGA_169P
  round 0.343 smd: A1(0,0) A2(0.8,0) A3(1.6,0) A4(2.4,0) A5(3.2,0) A6(4,0) A7(4.801,0) A8(5.601,0) A9(6.401,0) A10(7.201,0) A11(8.001,0) A12(8.801,0) A13(9.601,0) B1(0,-0.8) B2(0.8,-0.8) B3(1.6,-0.8) B4(2.4,-0.8) B5(3.2,-0.8) B6(4,-0.8) B7(4.801,-0.8) B8(5.601,-0.8) B9(6.401,-0.8) B10(7.201,-0.8) B11(8.001,-0.8) B12(8.801,-0.8) B13(9.601,-0.8) C1(0,-1.6) C2(0.8,-1.6) C3(1.6,-1.6) C4(2.4,-1.6) C5(3.2,-1.6) C6(4,-1.6) C7(4.801,-1.6) C8(5.601,-1.6) C9(6.401,-1.6) C10(7.201,-1.6) C11(8.001,-1.6) C12(8.801,-1.6) C13(9.601,-1.6) D1(0,-2.4) D2(0.8,-2.4) D3(1.6,-2.4) D4(2.4,-2.4) D5(3.2,-2.4) D6(4,-2.4) D7(4.801,-2.4) D8(5.601,-2.4) D9(6.401,-2.4) D10(7.201,-2.4) D11(8.001,-2.4) D12(8.801,-2.4) D13(9.601,-2.4) E1(0,-3.2) E2(0.8,-3.2) E3(1.6,-3.2) E4(2.4,-3.2) E5(3.2,-3.2) E6(4,-3.2) E7(4.801,-3.2) E8(5.601,-3.2) E9(6.401,-3.2) E10(7.201,-3.2) E11(8.001,-3.2) E12(8.801,-3.2) E13(9.601,-3.2) F1(0,-4) F2(0.8,-4) F3(1.6,-4) F4(2.4,-4) F5(3.2,-4) F6(4,-4) F7(4.801,-4) F8(5.601,-4) F9(6.401,-4) F10(7.201,-4) F11(8.001,-4) F12(8.801,-4) F13(9.601,-4) G1(0,-4.801) G2(0.8,-4.801) G3(1.6,-4.801) G4(2.4,-4.801) G5(3.2,-4.801) G6(4,-4.801) G7(4.801,-4.801) G8(5.601,-4.801) G9(6.401,-4.801) G10(7.201,-4.801) G11(8.001,-4.801) G12(8.801,-4.801) G13(9.601,-4.801) H1(0,-5.601) H2(0.8,-5.601) H3(1.6,-5.601) H4(2.4,-5.601) H5(3.2,-5.601) H6(4,-5.601) H7(4.801,-5.601) H8(5.601,-5.601) H9(6.401,-5.601) H10(7.201,-5.601) H11(8.001,-5.601) H12(8.801,-5.601) H13(9.601,-5.601) J1(0,-6.401) J2(0.8,-6.401) J3(1.6,-6.401) J4(2.4,-6.401) J5(3.2,-6.401) J6(4,-6.401) J7(4.801,-6.401) J8(5.601,-6.401) J9(6.401,-6.401) J10(7.201,-6.401) J11(8.001,-6.401) J12(8.801,-6.401) J13(9.601,-6.401) K1(0,-7.201) K2(0.8,-7.201) K3(1.6,-7.201) K4(2.4,-7.201) K5(3.2,-7.201) K6(4,-7.201) K7(4.801,-7.201) K8(5.601,-7.201) K9(6.401,-7.201) K10(7.201,-7.201) K11(8.001,-7.201) K12(8.801,-7.201) K13(9.601,-7.201) L1(0,-8.001) L2(0.8,-8.001) L3(1.6,-8.001) L4(2.4,-8.001) L5(3.2,-8.001) L6(4,-8.001) L7(4.801,-8.001) L8(5.601,-8.001) L9(6.401,-8.001) L10(7.201,-8.001) L11(8.001,-8.001) L12(8.801,-8.001) L13(9.601,-8.001) M1(0,-8.801) M2(0.8,-8.801) M3(1.6,-8.801) M4(2.4,-8.801) M5(3.2,-8.801) M6(4,-8.801) M7(4.801,-8.801) M8(5.601,-8.801) M9(6.401,-8.801) M10(7.201,-8.801) M11(8.001,-8.801) M12(8.801,-8.801) M13(9.601,-8.801) N1(0,-9.601) N2(0.8,-9.601) N3(1.6,-9.601) N4(2.4,-9.601) N5(3.2,-9.601) N6(4,-9.601) N7(4.801,-9.601) N8(5.601,-9.601) N9(6.401,-9.601) N10(7.201,-9.601) N11(8.001,-9.601) N12(8.801,-9.601) N13(9.601,-9.601)
MMBT3906H_SOT23-3
  oval 1.016x1.524 smd: 1(0,0) 2(0.965,2.083) 3(-0.965,2.083)
MMST3904-7-F_SOT323-3
  oval 0.711x0.889 smd: 1(0,0) 2(0.65,1.9) 3(-0.65,1.9)
MURAT_BLM15AG102SN1D_2P
  rect 0.457x0.508 smd: 1(0,0) 2(0.85,0)
MURAT_BLM15BD121SN1D_2P
  rect 0.457x0.508 smd: 1(0,0) 2(0.85,0)
MURAT_BLM15GA750SN1D_2P
  rect 0.508x0.762 smd: 1(0,0) 2(0.75,0)
MURAT_BLM15PD800SN1D_2P
  rect 0.457x0.508 smd: 1(0,0) 2(0.85,0)
MURAT_BLM15PX221SN1D_2P
  rect 0.457x0.508 smd: 1(0,0) 2(0.85,0)
MURAT_BLM15PX330SN1D_2P
  rect 0.457x0.508 smd: 1(0,0) 2(0.85,0)
MURAT_BLM15PX600SN1D_2P
  rect 0.457x0.508 smd: 1(0,0) 2(0.85,0)
MURAT_BLM18EG221SN1D_2P
  rect 0.66x1.041 smd: 1(0,0) 2(1.2,0)
MURAT_BLM18KG331SN1D_2P
  rect 0.61x0.711 smd: 1(0,0) 2(1.3,0)
MURAT_DLM0NSN900HY2D_4P
  rect 0.305x0.305 smd: 1(0,0) 2(0.6,0) 3(0.6,-0.5) 4(0,-0.5)
MURAT_LQM18NN1R0K00D_2P
  rect 0.61x0.711 smd: 1(0,0) 2(1.3,0)
NCP81215MNTXG_QFN52_6X6
  oval 0.838x0.203 smd: 1(0,0) 2(0,-0.4) 3(0,-0.8) 4(0,-1.2) 5(0,-1.6) 6(0,-2) 7(0,-2.4) 8(0,-2.8) 9(0,-3.2) 10(0,-3.6) 11(0,-4) 12(0,-4.4) 13(0,-4.8) 27(6.15,-4.8) 28(6.15,-4.4) 29(6.15,-4) 30(6.15,-3.6) 31(6.15,-3.2) 32(6.15,-2.8) 33(6.15,-2.4) 34(6.15,-2) 35(6.15,-1.6) 36(6.15,-1.2) 37(6.15,-0.8) 38(6.15,-0.4) 39(6.15,0)
  oval 0.203x0.838 smd: 14(0.675,-5.475) 15(1.075,-5.475) 16(1.475,-5.475) 17(1.875,-5.475) 18(2.275,-5.475) 19(2.675,-5.475) 20(3.075,-5.475) 21(3.475,-5.475) 22(3.875,-5.475) 23(4.275,-5.475) 24(4.675,-5.475) 25(5.075,-5.475) 26(5.475,-5.475) 40(5.475,0.675) 41(5.075,0.675) 42(4.675,0.675) 43(4.275,0.675) 44(3.875,0.675) 45(3.475,0.675) 46(3.075,0.675) 47(2.675,0.675) 48(2.275,0.675) 49(1.875,0.675) 50(1.475,0.675) 51(1.075,0.675) 52(0.675,0.675)
  rect 4.699x4.699 smd: 53(3.075,-2.4)
NCP302045MNTWG_PQFN33_5X5
  oval 0.305x0.711 smd: 1(0,0) 2(0.5,0) 3(1,0) 4(1.5,0) 5(2,0) 6(2.5,0) 7(3,0) 8(3.5,0)
  custom 0.32x0.32 smd: 9(3.135,1.266)
  custom 0.543x0.543 smd: 10(2.225,3.266)
  rect 3.81x0.711 smd: 11(1.75,4.902)
  rect 0.711x1.295 smd: 12(-0.701,3.701)
  oval 0.711x0.305 smd: 13(-0.701,2.701) 14(-0.701,2.201) 15(-0.701,1.701) 16(-0.701,1.201) 17(-0.701,0.701)
  rect 1.422x1.118 smd: 18(0.7,1.266)
  rect 0.584x0.356 smd: 19(0.09,2.676)
PDS5100H-13_POWERDI5-3
  rect 4.851x3.353 smd: 1(0,0)
  rect 1.397x1.397 smd: 2(3.982,-0.92) 3(3.982,0.92)
PESD5V0U2BT_SOT23-3
  oval 1.016x1.524 smd: 1(0,0) 2(0.965,2.083) 3(-0.965,2.083)
PI3EQX6741STZDEX_TQFN20_4X4-S
  oval 1.041x0.254 smd: 1(0,0) 2(0,-0.5) 3(0,-1) 4(0,-1.5) 5(0,-2) 11(3.95,-2) 12(3.95,-1.5) 13(3.95,-1) 14(3.95,-0.5) 15(3.95,0)
  oval 0.254x1.041 smd: 6(0.975,-2.975) 7(1.475,-2.975) 8(1.975,-2.975) 9(2.475,-2.975) 10(2.975,-2.975) 16(2.975,0.975) 17(2.475,0.975) 18(1.975,0.975) 19(1.475,0.975) 20(0.975,0.975)
  rect 2.108x2.108 smd: 21(1.975,-1)
PI3PCIE3212ZBEX_TQFN20_2P5X4P5
  oval 0.889x0.254 smd: 1(0,0) 10(4.6,0) 11(4.6,0.5) 20(0,0.5)
  oval 0.254x0.889 smd: 2(0.55,-1.05) 3(1.05,-1.05) 4(1.55,-1.05) 5(2.05,-1.05) 6(2.55,-1.05) 7(3.05,-1.05) 8(3.55,-1.05) 9(4.05,-1.05) 12(4.05,1.55) 13(3.55,1.55) 14(3.05,1.55) 15(2.55,1.55) 16(2.05,1.55) 17(1.55,1.55) 18(1.05,1.55) 19(0.55,1.55)
  rect 2.997x0.991 smd: 21(2.3,0.25)
PS175HDMBGA64GTR2-B1_TFBGA_64P
  round 0.343 smd: A1(0,0) A2(0.8,0) A3(1.6,0) A4(2.4,0) A5(3.2,0) A6(4,0) A7(4.801,0) A8(5.601,0) B1(0,-0.8) B2(0.8,-0.8) B3(1.6,-0.8) B4(2.4,-0.8) B5(3.2,-0.8) B6(4,-0.8) B7(4.801,-0.8) B8(5.601,-0.8) C1(0,-1.6) C2(0.8,-1.6) C3(1.6,-1.6) C4(2.4,-1.6) C5(3.2,-1.6) C6(4,-1.6) C7(4.801,-1.6) C8(5.601,-1.6) D1(0,-2.4) D2(0.8,-2.4) D3(1.6,-2.4) D4(2.4,-2.4) D5(3.2,-2.4) D6(4,-2.4) D7(4.801,-2.4) D8(5.601,-2.4) E1(0,-3.2) E2(0.8,-3.2) E3(1.6,-3.2) E4(2.4,-3.2) E5(3.2,-3.2) E6(4,-3.2) E7(4.801,-3.2) E8(5.601,-3.2) F1(0,-4) F2(0.8,-4) F3(1.6,-4) F4(2.4,-4) F5(3.2,-4) F6(4,-4) F7(4.801,-4) F8(5.601,-4) G1(0,-4.801) G2(0.8,-4.801) G3(1.6,-4.801) G4(2.4,-4.801) G5(3.2,-4.801) G6(4,-4.801) G7(4.801,-4.801) G8(5.601,-4.801) H1(0,-5.601) H2(0.8,-5.601) H3(1.6,-5.601) H4(2.4,-5.601) H5(3.2,-5.601) H6(4,-5.601) H7(4.801,-5.601) H8(5.601,-5.601)
PS8713BTQFN24GTR2-A_TQFN24_4X4
  oval 0.889x0.254 smd: 1(0,0) 2(0,-0.5) 3(0,-1) 4(0,-1.5) 5(0,-2) 6(0,-2.5) 13(4.1,-2.5) 14(4.1,-2) 15(4.1,-1.5) 16(4.1,-1) 17(4.1,-0.5) 18(4.1,0)
  oval 0.254x0.889 smd: 7(0.8,-3.3) 8(1.3,-3.3) 9(1.8,-3.3) 10(2.3,-3.3) 11(2.8,-3.3) 12(3.3,-3.3) 19(3.3,0.8) 20(2.8,0.8) 21(2.3,0.8) 22(1.8,0.8) 23(1.3,0.8) 24(0.8,0.8)
  rect 2.692x2.692 smd: 25(2.05,-1.25)
Q_N_DFN56-8-5
  oval 0.61x1.27 smd: 1(0,0) 2(1.27,0) 3(2.54,0) 4(3.81,0)
  custom 1.105x1.105 smd: 5(1.905,3.715)
R0201_0OHM
  custom 0.089x0.089 smd: 1(0,0)
  rect 0.381x0.356 smd: 2(0.584,0)
R0402_0OHM
  custom 0.14x0.14 smd: 1(0,0)
  rect 0.508x0.559 smd: 2(0.914,0)
R0603_0OHM
  custom 0.222x0.222 smd: 1(0,0)
  rect 0.635x0.889 smd: 2(1.397,0)
R_0201
  rect 0.381x0.356 smd: 1(0,0) 2(0.584,0)
R_0402
  rect 0.508x0.559 smd: 1(0,0) 2(0.914,0)
R_0402-NPM
  rect 0.508x0.559 smd: 1(0,0) 2(0.914,0)
R_0603
  rect 0.635x0.889 smd: 1(0,0) 2(1.397,0)
R_0603-NPM
  rect 0.635x0.889 smd: 1(0,0) 2(1.397,0)
R_0805
  rect 0.813x1.397 smd: 1(0,0) 2(1.702,0)
R_1206
  rect 1.016x1.651 smd: 1(0,0) 2(2.667,0)
R_1206_4P-D
  custom 0.371x0.371 smd: 1(0,0) 4(3.327,0)
  custom 0.114x0.114 smd: 2(0.775,0) 3(2.553,0)
RB520SM-30T2R_EMD2-2
  rect 0.61x0.787 smd: 1(0,0) 2(1.7,0)
RB751S40T1G_SOD523-2
  rect 0.61x0.787 smd: 1(0,0) 2(1.7,0)
RT8097ALGE_SOT23-6
  oval 0.711x0.991 smd: 1(0,0) 2(0.95,0) 3(1.9,0) 4(1.9,2.6) 5(0.95,2.6) 6(0,2.6)
RTS5242-GR_QFN32_4X4
  oval 0.889x0.203 smd: 1(0,0) 2(0,-0.4) 3(0,-0.8) 4(0,-1.2) 5(0,-1.6) 6(0,-2) 7(0,-2.4) 8(0,-2.8) 17(4.1,-2.8) 18(4.1,-2.4) 19(4.1,-2) 20(4.1,-1.6) 21(4.1,-1.2) 22(4.1,-0.8) 23(4.1,-0.4) 24(4.1,0)
  oval 0.203x0.889 smd: 9(0.65,-3.45) 10(1.05,-3.45) 11(1.45,-3.45) 12(1.85,-3.45) 13(2.25,-3.45) 14(2.65,-3.45) 15(3.05,-3.45) 16(3.45,-3.45) 25(3.45,0.65) 26(3.05,0.65) 27(2.65,0.65) 28(2.25,0.65) 29(1.85,0.65) 30(1.45,0.65) 31(1.05,0.65) 32(0.65,0.65)
  rect 2.692x2.692 smd: 33(2.05,-1.4)
SDMK0340L-7-F_SOD323-2
  rect 1.346x0.66 smd: 1(0,0) 2(2.4,0)
SHORTPADS
  custom 0.19x0.19 smd: 1(-0.483,0) 2(0.483,0)
SHORTPADS-NPM
  custom 0.19x0.19 smd: 1(-0.483,0) 2(0.483,0)
SINGA_2RJ3081-1C8211F_12P-T
  round 1.194 hole 0.889: 1(0,0) 2(1.02,1.1) 3(2.04,0) 4(3.06,1.1) 5(4.08,0) 6(5.1,1.1) 7(6.12,0) 8(7.14,1.1)
  oval 0.991x2.388 hole 0.61x2.007: 9(-4.58,-3.3) 10(-4.58,-10.1) 11(11.72,-10.1) 12(11.72,-3.3)
  oval 1.702x1.295 hole 1.397x0.991: A1(10.845,0.98) A2(10.845,-0.52) B1(-3.705,0.98) B2(-3.705,-0.52)
SINGA_2SJ3095-136111F_6P
  oval 0.991x1.803 hole 0.61x1.397: 1(0,0) 2(-9.5,5.5) 3(0,5.2) 4(0,7.8) 5(-9.5,0) 6(-9.5,2.75) 7(0,2.65)
SION_C7521R_1P-T
  custom 1.55x1.55 smd: 1(0,0)
SLGC55544CVTR_TQFN16_3X3
  oval 0.254x0.889 smd: 1(0,0) 2(0.5,0) 3(1,0) 4(1.5,0) 9(1.5,3.1) 10(1,3.1) 11(0.5,3.1) 12(0,3.1)
  oval 0.889x0.254 smd: 5(2.3,0.8) 6(2.3,1.3) 7(2.3,1.8) 8(2.3,2.3) 13(-0.8,2.3) 14(-0.8,1.8) 15(-0.8,1.3) 16(-0.8,0.8)
  rect 1.702x1.702 smd: 17(0.75,1.55)
SMF4L22A_SOD123FL2
  rect 1.295x1.397 smd: 1(0,0) 2(2.9,0)
SN74AHC1G08DCKR_SC70-5
  oval 0.381x1.295 smd: 1(0,0.15) 2(0.65,0.15) 3(1.3,0.15) 4(1.3,1.89) 5(0,1.89)
SN74AUP1T97YZPR_DSBGA_6P
  round 0.254 smd: A1(0,0) A2(0.5,0) B1(0,-0.5) B2(0.5,-0.5) C1(0,-1) C2(0.5,-1)
SN74LVC1G3157DCKR_SC70-6
  oval 0.406x0.889 smd: 1(0,0) 2(0.65,0) 3(1.3,0) 4(1.3,2.2) 5(0.65,2.2) 6(0,2.2)
ST33HTPH2E32AHB4_VQFN32_5X5
  oval 0.889x0.254 smd: 1(0,0) 2(0,-0.5) 3(0,-1) 4(0,-1.5) 5(0,-2) 6(0,-2.5) 7(0,-3) 8(0,-3.5) 17(5.1,-3.5) 18(5.1,-3) 19(5.1,-2.5) 20(5.1,-2) 21(5.1,-1.5) 22(5.1,-1) 23(5.1,-0.5) 24(5.1,0)
  oval 0.254x0.889 smd: 9(0.8,-4.3) 10(1.3,-4.3) 11(1.8,-4.3) 12(2.3,-4.3) 13(2.8,-4.3) 14(3.3,-4.3) 15(3.8,-4.3) 16(4.3,-4.3) 25(4.3,0.8) 26(3.8,0.8) 27(3.3,0.8) 28(2.8,0.8) 29(2.3,0.8) 30(1.8,0.8) 31(1.3,0.8) 32(0.8,0.8)
  rect 3.607x3.607 smd: 33(2.55,-1.75)
SW_SKRBAAE010_4P
  rect 0.991x0.889 smd: 1(0,0) 2(0,-3.9) 3(3.85,0) 4(3.85,-3.9)
SW_SSAJ120100_3P
  oval 0.61x0.508 smd: 1(0,0) 2(1,0) 3(2,0)
  rect 0.889x0.711 smd: 4(-2,-1.06) 5(4,-1.06)
SY6288D20AAC_SOT23-5
  oval 0.559x0.787 smd: 1(0,0) 2(0.95,0) 3(1.9,0) 4(1.9,2.4) 5(0,2.4)
SY8057BQDC_QFN16_3X3
  oval 0.889x0.254 smd: 1(0,0) 2(0,-0.5) 3(0,-1) 4(0,-1.5) 9(3.1,-1.5) 10(3.1,-1) 11(3.1,-0.5) 12(3.1,0)
  oval 0.254x0.889 smd: 5(0.8,-2.3) 6(1.3,-2.3) 7(1.8,-2.3) 8(2.3,-2.3) 13(2.3,0.8) 14(1.8,0.8) 15(1.3,0.8) 16(0.8,0.8)
  rect 1.6x1.6 smd: 17(1.55,-0.75)
SY8210AQVC_QFN19_4X3
  oval 0.711x0.254 smd: 1(0,0) 2(0,-0.45) 3(0,-0.9) 4(0,-1.35) 5(0,-1.8) 6(0,-2.25) 7(0,-2.7) 8(0,-3.15) 12(2.75,-3.15) 13(2.75,-2.7) 14(2.75,-2.25) 15(2.75,-1.8) 16(2.75,-1.35) 17(2.75,-0.9) 18(2.75,-0.45) 19(2.75,0)
  rect 0.94x2.083 smd: 9(1.045,-0.437)
  rect 0.406x2.083 smd: 10(1.975,-0.437)
  rect 1.295x1.981 smd: 11(1.225,-2.763)
SY8288BRAC_QFN20_3X3
  oval 0.889x0.254 smd: 1(0,0) 2(0,-0.45) 3(0,-0.9) 4(0,-1.35) 5(0,-1.8) 11(3.1,-1.8) 12(3.1,-1.35) 13(3.1,-0.9) 14(3.1,-0.45) 15(3.1,0)
  oval 0.254x0.889 smd: 6(0.65,-2.45) 7(1.1,-2.45) 8(1.55,-2.45) 9(2,-2.45) 10(2.45,-2.45) 16(2.45,0.65) 17(2,0.65) 18(1.55,0.65) 19(1.1,0.65) 20(0.65,0.65)
  rect 0.991x0.991 smd: 21(1.55,-0.9)
SY8288CRAC_QFN20_3X3
  oval 0.889x0.254 smd: 1(0,0) 2(0,-0.45) 3(0,-0.9) 4(0,-1.35) 5(0,-1.8) 11(3.1,-1.8) 12(3.1,-1.35) 13(3.1,-0.9) 14(3.1,-0.45) 15(3.1,0)
  oval 0.254x0.889 smd: 6(0.65,-2.45) 7(1.1,-2.45) 8(1.55,-2.45) 9(2,-2.45) 10(2.45,-2.45) 16(2.45,0.65) 17(2,0.65) 18(1.55,0.65) 19(1.1,0.65) 20(0.65,0.65)
  rect 0.991x0.991 smd: 21(1.55,-0.9)
SY8288RAC_QFN20_3X3
  oval 0.889x0.254 smd: 1(0,0) 2(0,-0.45) 3(0,-0.9) 4(0,-1.35) 5(0,-1.8) 11(3.1,-1.8) 12(3.1,-1.35) 13(3.1,-0.9) 14(3.1,-0.45) 15(3.1,0)
  oval 0.254x0.889 smd: 6(0.65,-2.45) 7(1.1,-2.45) 8(1.55,-2.45) 9(2,-2.45) 10(2.45,-2.45) 16(2.45,0.65) 17(2,0.65) 18(1.55,0.65) 19(1.1,0.65) 20(0.65,0.65)
  rect 0.991x0.991 smd: 21(1.55,-0.9)
T-SOL_158-1240902600_23P-T
  round 0.787 hole 0.787 unplated: (2.4,-0.45) (3.4,-11.65)
  oval 0.61x1.295 smd: 1(0,0) 2(-0.9,0) 3(-1.8,0) 4(-2.7,0) 5(-3.6,0) 6(-4.5,0) 7(-5.4,0) 8(-6.3,0)
  oval 0.711x1.295 smd: 9(-7.9,0)
  oval 1.092x1.905 hole 0.508x1.194: 10(-9.4,-0.45) 11(4.2,-0.45) 12(4.2,-13.25) 13(-9.4,-10.05)
  rect 1.092x1.194 smd: 14(0.71,-12.95)
  oval 0.61x1.194 smd: 15(-0.54,-12.95) 16(-1.45,-12.95) 17(-2.36,-12.95) 18(-3.27,-12.95) 19(-4.18,-12.95) 20(-5.09,-12.95) 21(-6,-12.95) 22(-6.91,-12.95) 23(-7.82,-12.95)
TAI-T_HCB2012KF-121T50_2P
  rect 0.813x1.397 smd: 1(0,0) 2(1.702,0)
TAIMA_IH-160_24P
  oval 0.61x2.362 smd: 1(0,0) 2(1,0) 3(2,0) 4(3,0) 5(4,0) 6(5,0) 7(6,0) 8(7,0) 9(8,0) 10(9,0) 11(10,0) 12(11,0) 13(11,8.35) 14(10,8.35) 15(9,8.35) 16(8,8.35) 17(7,8.35) 18(6,8.35) 19(5,8.35) 20(4,8.35) 21(3,8.35) 22(2,8.35) 23(1,8.35) 24(0,8.35)
TAIYO_BRC2012T4R7MD_2P
  rect 0.61x1.448 smd: 1(0,0) 2(1.6,0)
TAIYO_FBMJ4516HS720NT_2P
  rect 1.549x1.854 smd: 1(0,0) 2(3.95,0)
TAIYO_MCF12102G900-T_4P-NPM
  rect 0.508x0.305 smd: 1(0,0) 2(0,-0.55) 3(1.25,-0.55) 4(1.25,0)
TC7SH08FU_SSOP5
  oval 0.406x0.787 smd: 1(0,0) 2(0.65,0) 3(1.3,0) 4(1.3,1.9) 5(0,1.9)
TPC12
  round 0.305 smd: 1(0,0)
TPS65982_BGA_96P
  round 0.254 smd: A1(0,0) A2(0.5,0) A3(1,0) A4(1.5,0) A5(2.001,0) A6(2.501,0) A7(3.001,0) A8(3.501,0) A9(4.001,0) A10(4.501,0) A11(5.001,0) B1(0,-0.5) B2(0.5,-0.5) B3(1,-0.5) B4(1.5,-0.5) B5(2.001,-0.5) B6(2.501,-0.5) B7(3.001,-0.5) B8(3.501,-0.5) B9(4.001,-0.5) B10(4.501,-0.5) B11(5.001,-0.5) C1(0,-1) C2(0.5,-1) C10(4.501,-1) C11(5.001,-1) D1(0,-1.5) D2(0.5,-1.5) D5(2.001,-1.5) D6(2.501,-1.5) D7(3.001,-1.5) D8(3.501,-1.5) D10(4.501,-1.5) D11(5.001,-1.5) E1(0,-2.001) E2(0.5,-2.001) E4(1.5,-2.001) E5(2.001,-2.001) E6(2.501,-2.001) E7(3.001,-2.001) E8(3.501,-2.001) E10(4.501,-2.001) E11(5.001,-2.001) F1(0,-2.501) F2(0.5,-2.501) F4(1.5,-2.501) F5(2.001,-2.501) F6(2.501,-2.501) F7(3.001,-2.501) F8(3.501,-2.501) F10(4.501,-2.501) F11(5.001,-2.501) G1(0,-3.001) G2(0.5,-3.001) G4(1.5,-3.001) G5(2.001,-3.001) G6(2.501,-3.001) G7(3.001,-3.001) G8(3.501,-3.001) G10(4.501,-3.001) G11(5.001,-3.001) H1(0,-3.501) H2(0.5,-3.501) H4(1.5,-3.501) H5(2.001,-3.501) H6(2.501,-3.501) H7(3.001,-3.501) H8(3.501,-3.501) H10(4.501,-3.501) H11(5.001,-3.501) J1(0,-4.001) J2(0.5,-4.001) J10(4.501,-4.001) J11(5.001,-4.001) K1(0,-4.501) K2(0.5,-4.501) K3(1,-4.501) K4(1.5,-4.501) K5(2.001,-4.501) K6(2.501,-4.501) K7(3.001,-4.501) K8(3.501,-4.501) K9(4.001,-4.501) K10(4.501,-4.501) K11(5.001,-4.501) L1(0,-5.001) L2(0.5,-5.001) L3(1,-5.001) L4(1.5,-5.001) L5(2.001,-5.001) L6(2.501,-5.001) L7(3.001,-5.001) L8(3.501,-5.001) L9(4.001,-5.001) L10(4.501,-5.001) L11(5.001,-5.001)
TS5A3159ADCKR_SC70-6
  oval 0.381x1.372 smd: 1(0,0) 2(0.65,0) 3(1.3,0) 4(1.3,1.74) 5(0.65,1.74) 6(0,1.74)
TVNST52302AB0_SOT523-3
  oval 0.508x0.559 smd: 1(0,0) 2(-0.5,-1.4) 3(0.5,-1.4)
W25Q80DVSSIG_SO8
  oval 0.635x1.676 smd: 1(0,0) 2(1.27,0) 3(2.54,0) 4(3.81,0) 5(3.81,7.25) 6(2.54,7.25) 7(1.27,7.25) 8(0,7.25)
W25Q128JVSIQ_SO8
  oval 0.635x1.676 smd: 1(0,0) 2(1.27,0) 3(2.54,0) 4(3.81,0) 5(3.81,7.25) 6(2.54,7.25) 7(1.27,7.25) 8(0,7.25)
W25Q256FVEIQ_WSON8_8X6
  oval 0.66x0.991 smd: 1(0,0) 2(1.27,0) 3(2.54,0) 4(3.81,0) 5(3.81,8) 6(2.54,8) 7(1.27,8) 8(0,8)
  rect 4.293x3.404 smd: 9(1.905,4)
W25X20CLSNIG_SO8
  oval 0.635x1.854 smd: 1(0,0) 2(1.27,0) 3(2.54,0) 4(3.81,0) 5(3.81,5.165) 6(2.54,5.165) 7(1.27,5.165) 8(0,5.165)
WGI219LM-SLKJ3-A0_QFN48_6X6
  oval 0.762x0.254 smd: 1(0,0) 2(0,-0.4) 3(0,-0.8) 4(0,-1.2) 5(0,-1.6) 6(0,-2) 7(0,-2.4) 8(0,-2.8) 9(0,-3.2) 10(0,-3.6) 11(0,-4) 12(0,-4.4) 25(5.9,-4.4) 26(5.9,-4) 27(5.9,-3.6) 28(5.9,-3.2) 29(5.9,-2.8) 30(5.9,-2.4) 31(5.9,-2) 32(5.9,-1.6) 33(5.9,-1.2) 34(5.9,-0.8) 35(5.9,-0.4) 36(5.9,0)
  oval 0.254x0.762 smd: 13(0.75,-5.15) 14(1.15,-5.15) 15(1.55,-5.15) 16(1.95,-5.15) 17(2.35,-5.15) 18(2.75,-5.15) 19(3.15,-5.15) 20(3.55,-5.15) 21(3.95,-5.15) 22(4.35,-5.15) 23(4.75,-5.15) 24(5.15,-5.15) 37(5.15,0.75) 38(4.75,0.75) 39(4.35,0.75) 40(3.95,0.75) 41(3.55,0.75) 42(3.15,0.75) 43(2.75,0.75) 44(2.35,0.75) 45(1.95,0.75) 46(1.55,0.75) 47(1.15,0.75) 48(0.75,0.75)
  rect 2.997x2.997 smd: 49(2.95,-2.2)
Y_7V25000034_4P
  rect 1.397x1.194 smd: 1(0,0) 2(2.2,0) 3(2.2,1.8) 4(0,1.8)
Y_8Y24000034_4P
  rect 0.889x0.787 smd: 1(0,0) 2(1.4,0) 3(1.4,1.1) 4(0,1.1)
Y_9H03200042_2P
  rect 0.991x1.803 smd: 1(0,0) 2(2.5,0)
Y_X1A000141000200_2P
  rect 0.991x1.803 smd: 1(0,0) 2(2.5,0)
Y_XRCGB25M000F2P18R0_4P
  rect 0.762x0.711 smd: 1(0,0) 2(1.35,0) 3(1.35,1) 4(0,1)
Y_XRCGB27M000F2P18R0_4P
  rect 0.762x0.711 smd: 1(0,0) 2(1.35,0) 3(1.35,1) 4(0,1)
YUQIU_HD074-F19M1BR-C_19P-T
  round 0.787 hole 0.559: 1(0,0) 2(0.5,1.55) 3(1,0) 4(1.5,1.55) 5(2,0) 6(2.5,1.55) 7(3,0) 8(3.5,1.55) 9(4,0) 10(4.5,1.55) 11(5,0) 12(5.5,1.55) 13(6,0) 14(6.5,1.55) 15(7,0) 16(7.5,1.55) 17(8,0) 18(8.5,1.55) 19(9,0)
  oval 1.6x2.794 hole 0.991x2.21: 20(-2.75,0.15) 21(11.75,0.15) 22(-4.25,-6.15) 23(13.25,-6.15)

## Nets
0.6V_DDR_VTT_ON: PR210.1 RD19.2 UD1.4(Y)
0.6V_DDR_VTT_ON_R: PC222.1 PR210.2 PR212.1 PU200.2(S3)
1.8V_1.0V_PWRGD: PR1712.2 PR1713.1 UE1.L7(GPIO227/SHD_IO2)
3.3V_CAM_EN#: RC834.2 RZ1380.1 UH1.BE18(GPP_D2/SPI1_MISO/SBK2_BK2)
3.3V_CAM_EN#_R: CZ1200.1 QZ1.2(G) RZ1380.2
3.3V_TS_EN: RV323.1 UE1.J7(GPIO223/SHD_IO0)
3.3V_TS_EN_R: CV1638.1 QV7.2(G) RV323.2 RV324.2 RV326.2
3.3V_WWAN_EN: RZ40.2 UE1.C6(GPIO165/32KHZ_IN/CTOUT0) UZ2.3(ON1)
3V5V_EN: PC128.1 PR114.2 PR116.1 PU100.12(EN1) PU102.12(EN1)
+0.6V_DDR_VTT: CD22.1 CD23.1 CD24.1 CD54.1 CD55.1 CD56.1 JDIMM1.258(VTT) JDIMM2.258(VTT) PJP201.2
+0.6VSP: PC219.1 PC230.1 PJP201.1 PU200.5(VTTSNS) PU200.6(VTT)
+0.9V_LAN: CL3.1 CL4.1 CL8.1 CL9.1 CL10.1 CL11.1 CL12.1 LL1.2 UL1.8(VDD0P9_8) UL1.11(VDD0P9_11) UL1.16(VDD0P9_16) UL1.22(VDD0P9_22) UL1.37(VDD0P9_37) UL1.40(VDD0P9_40) UL1.43(VDD0P9_43) UL1.46(VDD0P9_46) UL1.47(VDD0P9_47)
+0.9V_TBT_CIO: CT38.1 CT39.1 CT40.1 UT1.R8(VCC0P9_CIO#R8) UT1.R9(VCC0P9_CIO#R9) UT1.R11(VCC0P9_CIO#R11) UT1.R12(VCC0P9_CIO#R12)
+0.9V_TBT_DP: CT25.1 CT26.1 CT27.1 CT28.1 CT29.1 CT30.1 CT31.1 UT1.L6(VCC0P9_ANA_DPSRC#L6) UT1.L8(VCC0P9_DP#L8) UT1.L11(VCC0P9_DP#L11) UT1.L12(VCC0P9_DP#L12) UT1.M6(VCC0P9_ANA_DPSRC#M6) UT1.M8(VCC0P9_DP#M8) UT1.T11(VCC0P9_DP#T11) UT1.T12(VCC0P9_DP#T12) UT1.V11(VCC0P9_ANA_DPSNK#V11) UT1.V12(VCC0P9_ANA_DPSNK#V12) UT1.V13(VCC0P9_ANA_DPSNK#V13)
+0.9V_TBT_LVR_OUT: CT59.1 CT60.1 CT61.1 CT62.1 UT1.F18(VCC0P9_LVR#F18) UT1.H11(VCC0P9_LVR_SENSE) UT1.H18(VCC0P9_LVR#H18) UT1.J11(VCC0P9_LVR#J11)
+0.9V_TBT_PCIE: CT34.1 CT35.1 CT36.1 CT37.1 UT1.L18(VCC0P9_ANA_PCIE_2#L18) UT1.L19(VCC0P9_ANA_PCIE_1#L19) UT1.M13(VCC0P9_PCIE#M13) UT1.M15(VCC0P9_PCIE#M15) UT1.M16(VCC0P9_PCIE#M16) UT1.M18(VCC0P9_ANA_PCIE_2#M18) UT1.N18(VCC0P9_ANA_PCIE_2#N18) UT1.N19(VCC0P9_ANA_PCIE_1#N19)
+0.9V_TBT_SVR: CT48.1 CT49.1 CT50.1 CT51.1 CT52.1 CT53.1 CT54.1 CT55.1 CT56.1 CT57.1 LT1.2 UT1.E12(VCC0P9_SVR_ANA#E12) UT1.E13(VCC0P9_SVR_ANA#E13) UT1.F11(VCC0P9_SVR_ANA#F11) UT1.F12(VCC0P9_SVR_ANA#F12) UT1.F13(VCC0P9_SVR_ANA#F13) UT1.F15(VCC0P9_SVR_ANA#F15) UT1.J9(VCC0P9_SVR_SENSE) UT1.L9(VCC0P9_SVR#L9) UT1.M9(VCC0P9_SVR#M9)
+0.9V_TBT_USB: CT32.1 CT33.1 UT1.R15(VCC0P9_USB#R15) UT1.R16(VCC0P9_USB#R16)
+1.0V_ALW_PCH: CH29.1 LH421.1 LH423.1 PJP3.2 RH238.1 RH240.1 RH241.1 RH254.2 RH255.1 RH256.1 RH257.1 RH258.1 RH259.1 RH260.1 RH286.1 RH287.1 RH288.1 RH289.1 RH290.1
+1.0V_AMPHYPLL: CH267.1 CH324.1 CH350.1 CH555.1 LH423.2 RH289.2 UH1.C49(VCCAMPHYPLL_1P051) UH1.D49(VCCAMPHYPLL_1P052) UH1.E49(VCCAMPHYPLL_1P053)
+1.0V_AZPLL: CH32.1 CH46.1 RH241.2 UH1.D1(VCCPRIM_1P0521) UH1.E1(VCCPRIM_1P0522)
+1.0V_BCLKPLL2: CC330.1 LC2.1 RH259.2
+1.0V_BCLKPLL2_R: CC311.1 CH31.1 LC2.2 UH1.B1(VCCAPLL_1P051) UH1.B2(VCCAPLL_1P052) UH1.B3(VCCAPLL_1P053)
+1.0V_CLPLLEBB: CC328.1 CH66.1 RH290.2 UH1.W31(VCCPRIM_MPHY_1P05)
+1.0V_DSW: CH35.1 RH255.2 UH1.BG45(VCCDSW_1P051) UH1.BG46(VCCDSW_1P052)
+1.0V_DUSB: CH38.1 RH286.2 UH1.W22(VCCDUSB_1P051) UH1.W23(VCCDUSB_1P052)
+1.0V_MPHY: CH34.1 CH47.1 PJP3.1 UH1.U26(VCCPRIM_1P0523) UH1.U29(VCCPRIM_1P0524) UH1.V25(VCCPRIM_1P0525) UH1.V27(VCCPRIM_1P0526) UH1.V28(VCCPRIM_1P0527) UH1.V30(VCCPRIM_1P0528) UH1.V31(VCCPRIM_1P0529)
+1.0V_OC: CH44.1 RH260.2 UH1.V19(VCCA_BCLK_1P05)
+1.0V_OCPLL1: CC332.1 LC3.1 RH240.2
+1.0V_OCPLL1_R: CC331.1 CH20.1 LC3.2 UH1.C1(VCCAPLL_1P054) UH1.C2(VCCAPLL_1P055)
+1.0V_PRIM: CC334.1 CC335.1 CH36.1 CZ100.1 CZ105.1 PJP302.2 RC216.1 RH254.1 UH1.AA22(VCCPRIM_1P051) UH1.AA23(VCCPRIM_1P052) UH1.AB20(VCCPRIM_1P053) UH1.AB22(VCCPRIM_1P054) UH1.AB23(VCCPRIM_1P055) UH1.AB27(VCCPRIM_1P056) UH1.AB28(VCCPRIM_1P057) UH1.AB30(VCCPRIM_1P058) UH1.AD20(VCCPRIM_1P059) UH1.AD23(VCCPRIM_1P0510) UH1.AD27(VCCPRIM_1P0511) UH1.AD28(VCCPRIM_1P0512) UH1.AD30(VCCPRIM_1P0513) UH1.AF23(VCCPRIM_1P0516) UH1.AF27(VCCPRIM_1P0517) UH1.AF30(VCCPRIM_1P0518) UZ19.1(VIN1) UZ19.2(VIN2) UZ19.7(VIN THERMAL) UZ21.1(VIN1) UZ21.2(VIN2) UZ21.7(VIN THERMAL)
+1.0V_PRIM_CNV_HVLO: RH257.2 UH1.AE17(VCCPRIM_1P0515)
+1.0V_PRIM_FUSE: RH256.2 UH1.AD31(VCCPRIM_1P0514)
+1.0V_PRIM_XDP: CC28.1 CC29.1 JXDP1.43 JXDP1.44 RC115.2 RC138.1 RC216.2
+1.0V_SRC: RH258.2 UH1.W19(VCCA_SRC_1P051) UH1.W20(VCCA_SRC_1P052)
+1.0V_VCCSFR: LC562.1 RC304.2 RC422.1
+1.0V_VCCSFR_R: CC192.2 CC333.2 LC562.2 RC422.2 UC1.H28(VCCPLL1) UC1.J28(VCCPLL2)
+1.0V_VCCST: CC191.2 CC193.2 CC194.2 CC569.2 PCZ3.1 PJP1.1 PRZ6.1 PRZ7.1 PRZ8.1 PRZ9.1 RC71.1 RC79.1 RC80.1 RC152.1 RC157.1 RC166.1 RC218.1 RC304.1 RE59.1 RE90.1 RZ151.2 UC1.H30(VCCST)
+1.0V_VCCST_C: CZ101.1 PJP1.2 UZ21.6(VOUT)
+1.0V_VCCSTG: CC186.2 CC195.2 CC336.1 CC337.1 CC557.1 CC558.1 PJP2.1 RC83.1 RC135.2 RC326.2 RH312.2 RH314.2 RH315.2 RZ151.1 UC1.H29(VCCSTG2)
+1.0V_VCCSTG_C: CZ106.1 PJP2.2 UZ19.6(VOUT)
+1.0V_XTAL: CH2.1 CH45.1 CH349.1 LH421.2 RH238.2 UH1.P2(VCCA_XTAL_1P051) UH1.P3(VCCA_XTAL_1P052)
+1.0VS_VCCIO: CC187.1 CC188.1 CC189.1 CC272.1 CC500.1 CC501.1 PJP401.2 QE11.1(D) RC1.2 RC2.1 RC132.1 RC439.2 UC1.AG12(VCCIO1) UC1.G15(VCCIO2) UC1.G17(VCCIO3) UC1.G19(VCCIO4) UC1.G21(VCCIO5) UC1.H15(VCCIO6) UC1.H16(VCCIO7) UC1.H17(VCCIO8) UC1.H19(VCCIO9) UC1.H20(VCCIO10) UC1.H21(VCCIO11) UC1.H26(VCCIO12) UC1.H27(VCCIO13) UC1.J15(VCCIO14) UC1.J16(VCCIO15) UC1.J17(VCCIO16) UC1.J19(VCCIO17) UC1.J20(VCCIO18) UC1.J21(VCCIO19) UC1.J26(VCCIO20) UC1.J27(VCCIO21)
+1.2V_DDRP: PC208.1 PC209.1 PC210.1 PC211.1 PC212.1 PC213.1 PC214.1 PC216.1 PC217.1 PC223.1 PC224.1 PC225.1 PC231.1 PC232.1 PC233.1 PC234.1 PC235.1 PJP200.1 PL201.2 PR204.1 PU200.7(VLDOIN) PU200.8(VDDQSNS)
+1.2V_LDO: CR5.1 CR6.1 CR7.1 UR1.10(AV12) UR1.14(DV12S)
+1.2V_LSPCON_VDD: CV43.1 CV44.1 CV48.1 CV610.1 CV625.1 LV602.2 UV31.D6(VDD12_1) UV31.F5(VDD12_2)
+1.2V_LSPCON_VDDA: CV45.1 CV46.1 CV626.1 LV603.2 UV31.F4(VDDA12)
+1.2V_LSPCON_VDDRX: CV614.1 CV615.1 CV616.1 CV617.1 CV618.1 CV619.1 CV628.1 LV605.2 UV31.B4(VDDRX12_3) UV31.B5(VDDRX12_2) UV31.B7(VDDRX12_1)
+1.2V_LSPCON_VDDTX: CV42.1 CV611.1 CV612.1 CV613.1 CV627.1 LV604.2 UV31.G5(VDDTX12_2) UV31.G7(VDDTX12_1)
+1.2V_MEM: CC81.1 CC82.1 CC83.1 CC84.1 CC161.1 CC163.1 CC164.1 CC165.1 CC166.1 CC167.1 CC168.1 CC170.1 CC171.1 CC172.1 CC185.1 CD1.1 CD2.1 CD3.1 CD4.1 CD5.1 CD6.1 CD7.1 CD8.1 CD9.1 CD10.1 CD11.1 CD12.1 CD13.1 CD14.1 CD15.1 CD16.1 CD21.1 CD32.1 CD33.1 CD34.1 CD35.1 CD36.1 CD37.1 CD38.1 CD39.1 CD40.1 CD41.1 CD42.1 CD43.1 CD44.1 CD45.1 CD46.1 CD47.1 CD48.1 CD49.1 CZ102.1 JDIMM1.12(DM0#/DBI0#) JDIMM1.33(DM1#/DBI1#) JDIMM1.54(DM2#/DBI2#) JDIMM1.75(DM3#/DBI3#) JDIMM1.96(DM8#/DBI8#) JDIMM1.111(VDD1) JDIMM1.112(VDD2) JDIMM1.117(VDD3) JDIMM1.118(VDD4) JDIMM1.123(VDD5) JDIMM1.124(VDD6) JDIMM1.129(VDD7) JDIMM1.130(VDD8) JDIMM1.135(VDD9) JDIMM1.136(VDD10) JDIMM1.141(VDD11) JDIMM1.142(VDD12) JDIMM1.147(VDD13) JDIMM1.148(VDD14) JDIMM1.153(VDD15) JDIMM1.154(VDD16) JDIMM1.159(VDD17) JDIMM1.160(VDD18) JDIMM1.163(VDD19) JDIMM1.178(DM4#/DBI4#) JDIMM1.199(DM5#/DBI5#) JDIMM1.220(DM6#/DBI6#) JDIMM1.241(DM7#/DBI7#) JDIMM2.12(DM0#/DBI0#) JDIMM2.33(DM1#/DBI1#) JDIMM2.54(DM2#/DBI2#) JDIMM2.75(DM3#/DBI3#) JDIMM2.96(DM8#/DBI8#) JDIMM2.111(VDD1) JDIMM2.112(VDD2) JDIMM2.117(VDD3) JDIMM2.118(VDD4) JDIMM2.123(VDD5) JDIMM2.124(VDD6) JDIMM2.129(VDD7) JDIMM2.130(VDD8) JDIMM2.135(VDD9) JDIMM2.136(VDD10) JDIMM2.141(VDD11) JDIMM2.142(VDD12) JDIMM2.147(VDD13) JDIMM2.148(VDD14) JDIMM2.153(VDD15) JDIMM2.154(VDD16) JDIMM2.159(VDD17) JDIMM2.160(VDD18) JDIMM2.163(VDD19) JDIMM2.178(DM4#/DBI4#) JDIMM2.199(DM5#/DBI5#) JDIMM2.220(DM6#/DBI6#) JDIMM2.241(DM7#/DBI7#) PJP200.2 RD11.1 RD15.1 RD28.1 RZ119.1 UC1.AA6(VDDQ1) UC1.AE12(VDDQ2) UC1.AF5(VDDQ3) UC1.AF6(VDDQ4) UC1.AG5(VDDQ5) UC1.AG9(VDDQ6) UC1.AJ12(VDDQ7) UC1.AL11(VDDQ8) UC1.AP6(VDDQ9) UC1.AP7(VDDQ10) UC1.AR6(VDDQ12) UC1.AR12(VDDQ11) UC1.AT12(VDDQ13) UC1.AW6(VDDQ14) UC1.AY6(VDDQ15) UC1.J5(VDDQ16) UC1.J6(VDDQ17) UC1.K6(VDDQ19) UC1.K12(VDDQ18) UC1.L6(VDDQ21) UC1.L12(VDDQ20) UC1.R6(VDDQ22) UC1.T6(VDDQ23) UC1.W6(VDDQ24) UC1.Y12(VDDQ25) UD1.5(VCC) UZ26.1(VIN1) UZ26.2(VIN2) UZ26.7(VIN THERMAL)
+1.2V_RUN: CV621.1 CV622.1 CV623.1 CV624.1 LV602.1 LV603.1 LV604.1 LV605.1 PJP504.2
+1.05VALWP: PC308.1 PC309.1 PC310.1 PC311.1 PJP302.1 PL301.2 PR1650.2
+1.8V_ALW_PCHRES: RH247.1 RH250.1 RH294.1 RH295.1 RH296.1
+1.8V_ALW_VTR3: CE21.1 PJP20.2 RE340.1 RE549.1 UE1.N5(VTR3)
+1.8V_PHVLDO: RH239.1 UH1.AF19(VCCPRIM_1P81) UH1.AF20(VCCPRIM_1P82)
+1.8V_PRIM: CE22.1 CZ544.1 PJP20.1 PJP502.2 QZ8.2(G) QZ24.2(G) RH242.1 RH247.2 RH604.2 RH605.2 RH607.2 RH613.1 RH614.1 RZ1483.1 UZ8.1(VIN_1) UZ8.2(VIN_2) UZ61.5(VCC)
+1.8V_PRIM_PCH: CH21.1 CH22.1 RH239.2 RH242.2 RZ376.1 RZ378.1 RZ543.2 UH1.AG19(VCCPRIM_1P83) UH1.AG20(VCCPRIM_1P84) UH1.AN15(VCCPRIM_1P85) UH1.AR15(VCCPRIM_1P86) UH1.BB11(VCCPRIM_1P87)
+1.8V_RUN: CA65.1 CA66.1 PJP42.2 RA3.2
+1.8V_RUN_AUDIO: CA57.1 CA58.1 CA69.1 RA3.1 UA1.29(CPVDD) UA1.33(AVDD2)
+1.8V_RUN_CARD: CR19.2 CR20.2 JSD1.15(VDD2) UR1.13(SD_VDD2)
+1.8V_RUN_UZ8: CZ120.1 PJP42.1 UZ8.7(VOUT_1) UZ8.8(VOUT_2)
+1.8VALWP: PC501.1 PC503.1 PC504.1 PC531.1 PC532.1 PJP502.1 PL501.2 PR501.1
+1.24V_DPHY: RH237.1 UH1.AJ22(VCCDPHY_1P241) UH1.AJ23(VCCDPHY_1P242)
+1.24V_DPHY_MAR: CH30.1 CH559.1 T75.1 UH1.BG5(VCCDPHY_1P243)
+1.24V_LDOSRAM: RH237.2 T74.1 UH1.AK22(VCCPRIM_1P241) UH1.AK23(VCCPRIM_1P242)
+1VS_VCCIOP: PC406.1 PC407.1 PC425.1 PC426.1 PC427.1 PC428.1 PJP401.1 PL402.2 PR421.1 PU401.1(OUT)
+2.5V_MEM: CD17.1 CD18.1 CD19.1 CD20.1 CD50.1 CD51.1 CD52.1 CD53.1 JDIMM1.257(VPP1) JDIMM1.259(VPP2) JDIMM2.257(VPP1) JDIMM2.259(VPP2) PJP506.2
+2.8V_FHV0: RH287.2 UH1.AF31(VCCPRIM_1P0519)
+2.8V_FHV1: RH288.2 UH1.AG31(VCCPRIM_1P0520)
+3.3V_1.8V_AZIO: CC329.1 LC1.1 RH292.2 RH295.2
+3.3V_1.8V_AZIO_R: CC310.1 CC327.1 LC1.2 UH1.BB14(VCCHDA)
+3.3V_1.8V_GPPA: RH95.2 RH291.2 RH294.2 RH340.2 UH1.AN32(VCCPGPPA)
+3.3V_1.8V_GPPD: RH293.2 RH296.2 UH1.AN24(VCCPGPPD)
+3.3V_1.8V_SPI: RH246.2 RH250.2 UH1.AN44(VCCSPI)
+3.3V_ALW: CE16.1 CE52.1 CE53.1 CE59.1 CE60.1 CE61.1 CT237.1 CT360.1 CV8.1 CV9.1 CV17.1 CZ57.1 CZ58.1 CZ68.1 CZ73.1 CZ82.1 CZ91.1 CZ93.1 CZ104.1 CZ1204.1 JAPS1.3 JAPS1.7 JKBTP1.6 JLED1.1 JUSH1.11 JUSH1.12 JUSH1.13 PC206.1 PC226.1 PC312.2 PC314.2 PJP22.1 PJP102.2 PJP403.1 PJP501.1 PJP505.1 PQ807.2(G) PR1.1 PR4.2 PR28.2 PR107.1 PR113.1 PR205.1 PR307.1 PR404.1 PR413.1 PR414.1 PR517.1 PR726.1 PR821.2 PR824.1 PR825.1 PR828.1 PR830.1 PR833.1 PR838.1 PR839.1 PR851.1 PR852.1 PR865.2 PR1711.1 PU200.13(BYP) PU301.15(BYP) QH7.3(S) QZ38.3(S) RC241.1 RE5.2 RE8.2 RE10.2 RE11.2 RE12.2 RE21.2 RE25.1 RE35.2 RE37.2 RE43.2 RE63.2 RE68.2 RE69.1 RE71.1 RE72.1 RE73.1 RE74.1 RE75.1 RE79.1 RE83.2 RE84.2 RE91.2 RE92.2 RE300.1 RE301.2 RE302.2 RE303.2 RE343.2 RE362.2 RE365.2 RE505.2 RE524.2 RE525.2 RE526.1 RE532.1 RE561.2 RE605.2 RE606.2 RE704.2 RE712.1 RE713.1 RE714.1 RE715.1 RE721.2 RE722.2 RE723.2 RE724.2 RE725.2 RE726.2 RE727.2 RE728.2 RE729.2 RE730.2 RE821.2 RE827.1 RH431.2 RH432.1 RH434.2 RT48.2 RT68.2 RT483.1 RZ8.1 RZ9.1 RZ133.1 RZ377.1 RZ381.1 RZ518.1 RZ1390.2 RZ1397.1 RZ1404.2 RZ1405.1 RZ1410.1 RZ1474.2 RZ1482.1 RZ1484.1 RZ1489.1 UE3.5(P) UE4.5(VCC) UE5.5(P) UT32.5(V+) UT34.5(P) UV24.5(VIN) UZ2.1(VIN1_1) UZ2.2(VIN1_2) UZ2.6(VIN2_1) UZ2.7(VIN2_2) UZ3.1(VIN1_1) UZ3.2(VIN1_2) UZ3.6(VIN2_1) UZ3.7(VIN2_2) UZ4.6(VIN2_1) UZ4.7(VIN2_2) UZ6.5(P) UZ10.5(P) UZ34.5(P) UZ35.5(P) UZ53.1(VIN1) UZ53.2(VIN2) UZ54.5(P)
+3.3V_ALW2: PR104.2 RE57.2
+3.3V_ALW_DSW_R: QH7.1(D) RH439.2
+3.3V_ALW_PCH: CI50.1 CI52.1 CZ216.1 DH3.2 JAPS1.1 JSPI1.5 PJP38.2 RC74.1 RC133.1 RC137.2 RC557.2 RC559.1 RC834.1 RC840.1 RC866.1 RH56.1 RH57.1 RH61.1 RH67.1 RH77.1 RH78.1 RH80.1 RH81.1 RH86.1 RH101.1 RH185.1 RH203.2 RH204.2 RH279.1 RH309.1 RH310.1 RH311.1 RH329.2 RH371.2 RH376.1 RH400.2 RH440.1 RH553.2 RH555.2 RH640.2 RH641.2 RH642.2 RH643.2 RH644.2 RH645.2 RH646.2 RH647.2 RH648.2 RH661.1 RI62.2 RI63.1 RI64.2 RI65.2 RI66.2 RI67.2 RI68.2 RI72.2 RI74.2 RT391.2 RZ69.1 RZ379.1 RZ1408.1 UH7.5(P) UI6.1(VDD_1) UI6.13(VDD_2) UZ51.5(VCC)
+3.3V_ALW_PCH_UZ3: CZ112.1 PJP38.1 UZ3.13(VOUT1_2) UZ3.14(VOUT1_1)
+3.3V_ALW_PCHRES: RH246.1 RH279.2 RH291.1 RH292.1 RH293.1 RH298.1 RH299.1 RH300.1 RH302.1 RH303.1 RH304.1 RH305.1 RH306.1
+3.3V_ALW_UE1: CE13.1 CE14.1 CE15.1 CE19.1 CE20.1 CE23.1 PJP22.2 RE314.2 UE1.B7(VTR_ANALOG) UE1.G8(VTR1) UE1.H1(VTR_REG) UE1.K2(VREF_ADC) UE1.M9(VTR2)
+3.3V_ALW_UZ12: CZ51.1 CZ52.1 RZ1410.2 UZ12.1(NIC_1)
+3.3V_ALWP: PC106.1 PC107.1 PC108.1 PC109.1 PC110.1 PC129.1 PC135.1 PC136.1 PC141.1 PC142.1 PC161.1 PC162.1 PJP102.1 PL100.2 PR108.2 PU100.14(OUT)
+3.3V_CAM: CV22.1 CV23.1 CZ1.1 CZ1206.1 FZ5.1 JEDP1.11 RZ1487.1
+3.3V_CAM_F: FZ5.2 QZ1.1(D) RZ1487.2
+3.3V_DSW: CH63.1 RH92.2 RH93.2 RH94.2 RH243.2 RH434.1 RH439.1 RH440.2 RH602.2 UH1.BE48(VCCDSW_3P31) UH1.BE49(VCCDSW_3P32)
+3.3V_EC_PLL: CE17.1 CE18.1 RE314.1 UE1.F1(VTR_PLL)
+3.3V_FPBTN: CZ309.1 DT42.2 DT42.8 JFPBTN1.14 QE20.2(G) QZ38.1(D) RE706.2 RE707.2 RE708.2 RE826.1 RZ1390.1 RZ1391.1 RZ1392.2
+3.3V_FUSE: RH300.2 UH1.AT44(VCCPRIM_3P31)
+3.3V_HDD: CN10.1 CN11.1 CN16.1 CN17.1 JSATA1.9 JSATA1.10 PJP34.2 RN3.1 RN6.1 RN8.2 RN10.2 RN12.1 RN14.1 RN16.1 RN18.1 RN20.1 UN7.10(VDD_1) UN7.20(VDD_2)
+3.3V_HDD_M2: CN60.1 CN61.1 CN62.1 CN63.1 CN64.1 CN77.1 CN80.1 CN81.1 CN82.1 CN84.1 CN86.1 JNGFF3.2(3P3VAUX1) JNGFF3.4(3P3VAUX2) JNGFF3.12(3P3VAUX3) JNGFF3.14(3P3VAUX4) JNGFF3.16(3P3VAUX5) JNGFF3.18(3P3VAUX6) JNGFF3.70(3P3VAUX7) JNGFF3.72(3P3VAUX8) JNGFF3.74(3P3VAUX9) PJP31.1 PJP1604.1 RN37.1
+3.3V_LAN: CL18.1 CL19.1 JLOM1.A1(YELLOW LED+) JLOM1.B1(GREEN LED+) PJP37.2 RL1.2 RL2.2 RL4.2 RL5.2 RL6.2 RL8.2 RL29.1
+3.3V_LAN_OUT: CL7.1 CL28.1 CL29.1 CL30.1 RL8.1 UL1.4(VDD3P3_4) UL1.5(VDD3P3_IN) UL1.15(VDD3P3_15) UL1.19(VDD3P3_19) UL1.29(VDD3P3_29)
+3.3V_LAN_UZ2: CZ111.1 PJP37.1 UZ2.8(VOUT2_2) UZ2.9(VOUT2_1)
+3.3V_LSPCON: CV620.1 CV630.1 CV1641.1 LV601.1 RV605.2 RV606.2 RV607.2 RV608.1 RV614.1 RV616.1 RV617.1 UV32.8(VCC)
+3.3V_LSPCON_VDD: CV47.1 CV608.1 CV609.1 CV629.1 LV601.2 UV31.B2(VDD33_3) UV31.G2(VDD33_2) UV31.G4(VDD33_1)
+3.3V_MMI_AUX: CR1.1 CR2.1 CR27.1 CR28.1 RR3.1 RR19.2 RR274.2 UR1.27(3V3AUX)
+3.3V_MMI_IN: CR3.1 CR4.1 CR25.1 CR26.1 PJP14.2 RR274.1 UR1.11(3V3_IN)
+3.3V_PDA_VOUT: CT83.1 UT5.H2(VOUT_3V3)
+3.3V_PGPPBC: RH304.2 UH1.AN26(VCCPGPPBC1) UH1.AP26(VCCPGPPBC2)
+3.3V_PGPPEF: CH62.1 RH303.2 UH1.AE35(VCCPGPPEF1) UH1.AE36(VCCPGPPEF2)
+3.3V_PGPPG: RH305.2 UH1.AN21(VCCPGPPG_3P3)
+3.3V_PGPPHK: CH64.1 RH306.2 UH1.AC35(VCCPGPPHK1) UH1.AC36(VCCPGPPHK2)
+3.3V_PHVC: RH299.2 UH1.AW9(VCCPRIM_3P32)
+3.3V_PHVLDO: CH37.1 CH67.1 CH323.1 RH298.2 UH1.AY8(VCCPRIM_3P33) UH1.BB7(VCCPRIM_3P34)
+3.3V_PRTC: CH33.1 CH65.1 RH297.2 UH1.BC49(VCCRTC1) UH1.BD49(VCCRTC2)
+3.3V_PUSB2: RH302.2 UH1.V23(VCCPRIM_3P35)
+3.3V_RTC_LDO: PC9.1 PD3.3 PR105.2 RA53.2
+3.3V_RUN: CA7.1 CH10.1 CN1.1 CN2.1 CN3.1 CZ67.1 CZ72.1 FZ3.2 JESPI.1 JESPI.2 JUSH1.8 LGA1.2(CS) LGA1.3(SDO/SA0) LGA1.9(VDD) LGA1.10(VDD_IO) PJP5.2 PJP14.1 PJP18.1 PJP31.2 PJP34.1 PJP35.1 PJP39.2 PJP503.2 PRZ20.1 QH4.2(G1) QH4.5(G1) QV20.3 RC370.2 RD4.1 RD6.1 RD8.1 RD10.1 RD19.1 RD20.1 RD22.1 RD24.1 RD26.1 RE48.1 RE51.1 RE67.2 RH76.1 RH90.1 RH104.1 RH123.2 RH124.2 RH125.2 RH126.2 RH127.2 RH131.2 RH132.2 RH133.2 RH199.2 RH214.1 RH221.2 RH222.2 RH223.2 RH224.2 RH225.2 RH267.2 RH316.1 RH318.1 RH319.1 RH324.1 RH331.1 RH333.2 RH339.1 RH344.1 RH345.1 RH348.1 RH355.1 RH361.1 RH373.2 RH374.2 RH378.1 RH402.1 RN2.1 RN4.1 RN226.1 RV8.2 RV98.1 RV99.1 RV326.1 RV614.2 RV732.2 RV1657.1 RZ89.1 RZ362.1 RZ542.2 RZ1391.2 RZ1403.2 RZ1409.1 RZ1485.1 RZ1486.2 UC3.5(P)
+3.3V_RUN_AUDIO: CA67.1 CA68.1 LA12.2 LA14.2 PJP18.2 RA18.2 RA59.1
+3.3V_RUN_AUDIO_DVDD: CA10.1 CA61.1 LA14.1 UA1.1(DVDD)
+3.3V_RUN_AUDIO_IO: CA55.1 CA56.1 LA12.1 UA1.8(DVDD-IO)
+3.3V_RUN_CARD: CR17.2 CR18.2 JSD1.4(VDD1) UR1.12(CARD_3V3)
+3.3V_RUN_DIMM1: CD27.1 CD28.1 JDIMM1.255(VDDSPD) RD10.2
+3.3V_RUN_DIMM2: CD59.1 CD60.1 JDIMM2.255(VDDSPD) RD26.2
+3.3V_RUN_F: FZ3.1 FZ4.2 QZ1.3(S) RZ1486.1 RZ1488.2
+3.3V_RUN_QZ1: FZ4.1 JEDP1.10 RZ1488.1
+3.3V_RUN_UZ3: CZ115.1 PJP39.1 UZ3.8(VOUT2_2) UZ3.9(VOUT2_1)
+3.3V_SPI: CH9.1 CH270.1 DH3.1 JSPI1.6 RH30.1 RH185.2 RH335.1 RH600.1 RH601.1 RH615.1 UC5.8(VCC) UC6.8(VCC)
+3.3V_SSD: CZ305.1 PJP1604.2 UZ53.7(VOUT1) UZ53.8(VOUT2)
+3.3V_TBT: CT43.1 CT44.1 CT45.1 CT46.1 CT47.1 LT2.2 PJP5.1 RT11.2 RT12.2 RT13.2 RT14.2 RT15.2 RT49.2 RT336.2 RT337.2 UT1.A2(VCC3P3_SVR#A2) UT1.A3(VCC3P3_SVR#A3) UT1.B3(VCC3P3_SVR#B3) UT1.H9(VCC3P3A)
+3.3V_TBT_FLASH_R: CT1.1 RT1.2 RT2.2 RT3.2 RT4.2 RT9.2 RT10.2 UT2.8(VCC)
+3.3V_TBT_LC: CT41.1 RT5.2 RT6.2 RT7.2 RT8.2 RT9.1 UT1.R6(VCC3P3_LC)
+3.3V_TBT_S0: CT67.1 CT68.1 CT69.1 LT2.1 UT1.R13(VCC3P3_S0)
+3.3V_TBT_SX: CT42.1 PJP6.2 RT16.2 RT17.2 RT18.2 RT19.2 RT20.2 RT48.1 RT49.1 RT338.2 RT371.2 RT372.2 RT455.2 UT1.F8(VCC3P3_SX)
+3.3V_TBTA_FLASH: CT70.1 CT84.1 RT10.1 RT50.2 RT51.2 RT52.2 RT53.2 RT66.2 RT67.2 RT76.2 RT95.2 RT98.1 RT106.2 RT107.2 RT399.1 UT5.G1(LDO_3V3) UT6.8(VCC)
+3.3V_TP: CZ83.1 CZ90.1 CZ1203.1 JKBTP1.12 PJP35.2 RZ18.1 RZ19.1 RZ20.1 RZ21.1 RZ116.1 RZ117.1
+3.3V_VDD_DCIN: PC10.1 PC12.1 PC3002.1 PD800.3(1) PD3000.2 PR17.1 PR27.2 PR33.1 PR47.1 PR806.1 PR809.1 PR832.1 PR866.1 PR3002.1 PU2.3(VOUT) PU3000.8(VCC)
+3.3V_VDD_PIC: PD800.2 PJP6.1 PR810.1 PR813.1 PR822.1 PR859.1 QT1.2(G2) QT1.5(G1) RT398.2 RT399.2 RT482.1
+3.3V_VDD_PIC_PDA: CT74.1 RT482.2 RT483.2 UT5.B1(VDDIO) UT5.H1(VIN_3V3)
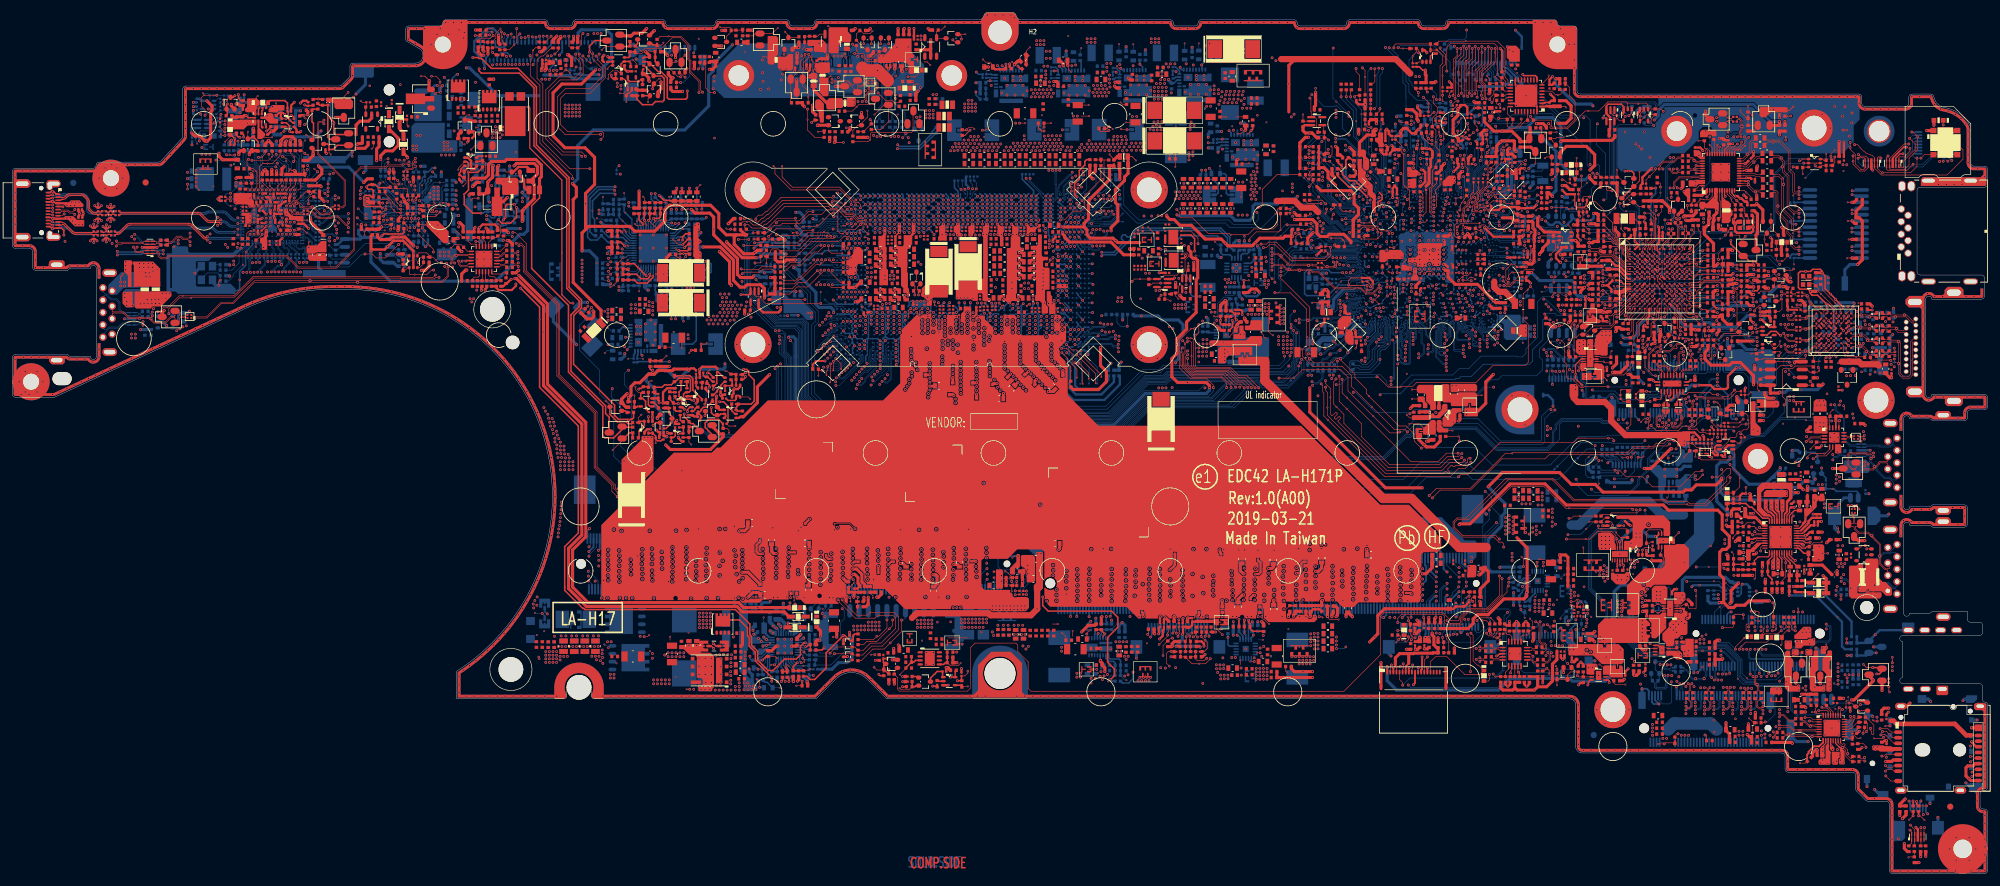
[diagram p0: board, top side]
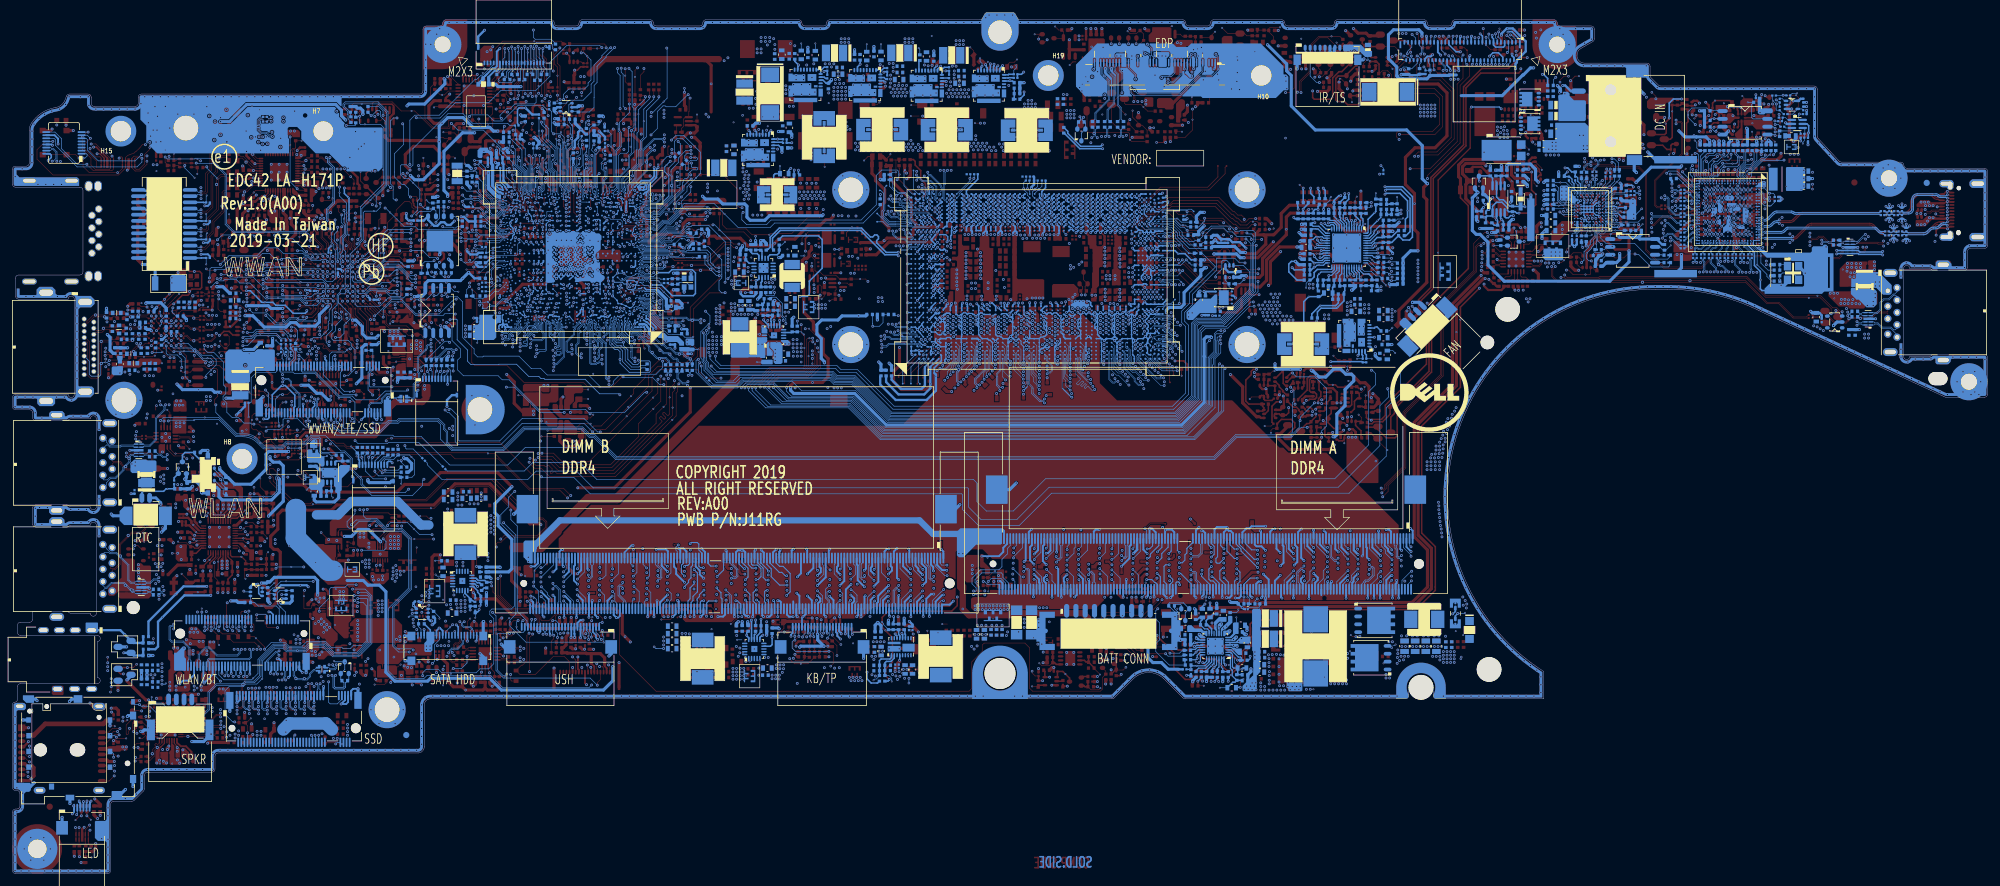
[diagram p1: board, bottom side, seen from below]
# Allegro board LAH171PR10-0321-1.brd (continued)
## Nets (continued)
+3.3V_VDD_PIC_R: CT91.1 CT92.1 RT398.1 UT7.5(VOUT)
+3.3V_VPS_UZ12: CZ53.1 CZ54.1 CZ55.1 CZ1201.1 CZ1202.1 RZ1408.2 RZ1409.2 RZ1489.2 UZ12.14(NIC_11) UZ12.22(VPS)
+3.3V_WLAN: CZ7.1 CZ8.1 CZ9.1 CZ27.1 CZ28.1 CZ29.1 CZ30.1 CZ31.1 CZ32.1 CZ33.1 CZ34.1 CZ35.1 CZ36.1 JNGFF1.2(3.3V1) JNGFF1.4(3.3V2) JNGFF1.72(3.3V3) JNGFF1.74(3.3V4) PJP36.2
+3.3V_WLAN_UZ4: CZ122.1 PJP36.1 UZ4.8(VOUT2_2) UZ4.9(VOUT2_1)
+3.3V_WWAN: CZ17.1 CZ18.1 CZ19.1 CZ20.1 CZ21.1 CZ23.1 CZ24.1 CZ25.1 CZ26.1 CZ154.1 CZ155.1 JNGFF2.2(3.3V_2) JNGFF2.4(3.3V_4) JNGFF2.70(3.3V_70) JNGFF2.72(3.3V_72) JNGFF2.74(3.3V_74) PJP41.2 RZ43.2 RZ1400.2 UZ29.1(VDD_1) UZ29.6(VDD_2) UZ29.10(VDD_3)
+3.3V_WWAN_UZ2: CZ119.1 CZ124.1 PJP41.1 UZ2.13(VOUT1_2) UZ2.14(VOUT1_1)
+5V_ALW: CI6.1 CI7.1 CI9.1 CI11.1 CI12.1 CI19.1 CI31.1 CI33.1 CI34.1 CZ64.1 CZ69.1 CZ1205.1 DT1.2 JLED1.6 JUSH1.9 JUSH1.10 LED3.2(ANODE) PCA11.1 PCH26.1 PCH27.1 PCH49.1 PCH51.1 PCT13.1 PJP8.1 PJP103.2 PR7.1 PRA1.1 PRH1.1 PRH2.1 PRH9.1 PRH11.1 PRT1.1 PRZ51.1 PRZ61.1 PRZ77.1 PUA1.15(VCCD) PUH1.2(SMOD#) PUH1.15(VCCD) PUH2.2(SMOD#) PUH2.15(VCCD) PUH3.2(SMOD#) PUH3.15(VCCD) PUH4.2(SMOD#) PUH4.15(VCCD) PUT1.2(SMOD#) PUT1.15(VCCD) RI13.2 RV9.2 UI1.5(IN) UI2.5(IN) UI3.1(VIN) UI3.7(CTL2) UI3.8(CTL3) UZ2.4(VBIAS) UZ3.4(VBIAS) UZ4.1(VIN1_1) UZ4.2(VIN1_2) UZ4.4(VBIAS) UZ8.4(VBIAS) UZ19.3(VBIAS) UZ21.3(VBIAS) UZ23.1(VIN_1) UZ23.2(VIN_2) UZ23.4(VBIAS) UZ26.3(VBIAS) UZ53.4(VBIAS)
+5V_ALW2: PC126.1 PU102.15(LDO)
+5V_ALW_PDA: CT75.1 CT76.1 CT77.1 CT78.1 PJP8.2 UT5.A11(PP_5V0_1) UT5.B11(PP_5V0_2) UT5.C11(PP_5V0_3) UT5.D11(PP_5V0_4) UT5.H10(PP_CABLE)
+5V_ALWP: PC120.1 PC121.1 PC122.1 PC123.1 PC124.1 PC130.1 PC137.1 PC138.1 PC163.1 PC164.1 PJP103.1 PL101.2 PR117.2 PU102.14(OUT)
+5V_HDD: CN8.1 CN9.1 JSATA1.15 JSATA1.16 JSATA1.17 PJP32.2 PJP33.1 RN1.1
+5V_HDD_UZ23: CZ129.1 PJP32.1 UZ23.7(VOUT_1) UZ23.8(VOUT_2)
+5V_PD_VDD: CT88.1 CT89.1 DT1.1 DT2.1 RT111.1 RT393.1 UT7.1(VCC)
+5V_RUN: CE32.1 CV39.1 CZ66.1 CZ71.1 CZ92.1 DE1.1 JFAN1.4 JKBTP1.5 JUSH1.7 PJP17.1 PJP33.2 PJP40.2 RV6.2 RV733.2 UV2.1(IN)
+5V_RUN_AUDIO: CA59.1 CA60.1 CA63.1 CA64.1 LA5.2 LA13.2 PJP17.2
+5V_RUN_PVDD_L: CA45.1 CA46.1 CA47.1 CA48.1 LA13.1 UA1.34(PVDD1) UA1.39(PVDD2)
+5V_RUN_UZ4: CZ116.1 PJP40.1 UZ4.13(VOUT1_2) UZ4.14(VOUT1_1)
+5V_TBT_VBUS: CT93.1 DT2.2 DT3.1
+5V_TBTA_VBUS_D: DT3.2 UT8.3(VOUT)
+5V_USB_CHG_PWR: CI14.1 CI17.1 CI32.1 CI43.1 CI44.1 JUSB1.1(VBUS) UI3.12(VOUT)
+13.2VB_BATT: PL1.2 PL2.2 PQ702.5(D) PR738.2
+13.2VB_PBATT_C: PBATT1.1 PBATT1.2 PBATT1.3 PC1.1 PL1.1 PL2.1
+13.5VB: CV13.2 CZ3.1 FZ1.2 PC165.1 PC166.1 PC167.1 PC168.1 PC169.1 PC170.1 PC171.1 PC172.1 PC707.1 PC708.1 PC709.1 PC710.1 PC715.1(P) PC720.1 PC721.1 PC756.1(P) PC762.1 PC764.1 PC765.1 PC766.1 PCH1.1 PCH2.1 PCH6.1 PCH13.1 PCT1.1(P) PD702.2 PD3000.3(1) PJP100.1 PJP101.1 PJP202.1 PJP301.1 PJP701.1 PJPT1.2 PLH11.1 PLH12.1 PLH13.1 PQ701.3(D1_1) PQ701.4(D1_2) PQ701.9(D1_3) PR102.2 PR711.1 PR721.2 PR3006.1 QV1.4(S) QV18.3 RV4.2
+13.5VB_1.05VALWP: PC301.1 PC303.1 PC305.1 PC306.1 PJP301.2 PU301.2(IN1) PU301.3(IN2) PU301.4(IN3) PU301.5(IN4)
+13.5VB_3V: PC100.1 PC103.1 PC104.1 PC105.1 PJP100.2 PU100.2(IN1) PU100.3(IN2) PU100.4(IN3) PU100.5(IN4)
+13.5VB_5V: PC115.1 PC116.1 PC117.1 PC118.1 PJP101.2 PU102.2(IN1) PU102.3(IN2) PU102.4(IN3) PU102.5(IN4)
+13.5VB_CPU: PCH3.1 PCH4.1 PCH5.1(P) PCH7.1 PCH8.1 PCH11.1 PCH14.1 PCH15.1(P) PCH16.1 PCH17.1 PCH19.1(P) PCH20.1 PCH24.1 PCH30.1 PCH31.1 PCH32.1 PCH33.1 PCH36.1(P) PCH37.1 PCH38.1 PCH39.1 PCH40.1 PCH43.1(P) PCH45.1 PCH47.1 PCH54.1 PCH55.1 PCT15.1(P) PJP701.2 PJPA1.2 PLH11.2 PLH12.2 PLH13.2 PRZ57.1 PUH1.8(VIN1) PUH1.9(VIN2) PUH2.8(VIN1) PUH2.9(VIN2) PUH3.8(VIN1) PUH3.9(VIN2) PUH4.8(VIN1) PUH4.9(VIN2)
+13.5VB_DDR: PC200.1 PC201.1 PC202.1 PC203.1 PC228.1 PC229.1 PC236.1 PC237.1 PJP202.2 PU200.10(IN)
+13.5VB_GT: PCT2.1 PCT3.1 PCT4.1 PCT5.1 PCT6.1 PCT7.1 PCT8.1 PCT9.1 PCT10.1 PCT16.1 PJPT1.1 PUT1.8(VIN1) PUT1.9(VIN2)
+13.5VB_IR: FZ1.1 JIRTS1.9 JIRTS1.10
+13.5VB_SA: PCA1.1 PCA2.1 PCA3.1 PCA4.1 PCA7.1(P) PCA9.1 PCA13.1 PCA14.1 PJPA1.1 PUA1.8(VIN1) PUA1.9(VIN2)
+13.5VB_VCHGR: PC741.1 PC742.1 PQ702.1(S1) PQ702.2(S2) PQ702.3(S3) PR711.4
+19.5V_AC: PD701.1 PJP700.1 PL700.1 PR700.4
+19.5V_CHARGER: PC700.1 PC701.1 PC702.1 PC703.1 PC704.1 PC706.1 PC716.1 PC717.1 PC757.1 PC758.1 PC761.1 PC763.1 PC767.1 PC768.1 PJP700.2 PL700.2 PQ704.5(D)
+19.5V_DC_IN: PC6.1 PC7.1 PL4.2 PL5.2 PQ9.1(S1) PQ9.2(S2) PQ9.3(S3) PQ11.3(S) PR12.1 PR13.1 PR31.1 PR800.1 PR871.2
+19.5V_DC_IN_SS: PC8.1 PD5.2 PD5.3 PD700.2 PQ4.5(D) PQ9.5(D) PR14.1
+19.5V_DCIN_JACK: PC5.1 PJPDC1.2 PJPDC1.3 PL4.1 PL5.1
+19.5V_SDC_IN: PC4.1 PC802.1 PD5.1 PD706.2 PD801.1 PQ4.1(S1) PQ4.2(S2) PQ4.3(S3) PQ5.3(S) PQ801.1(S1) PQ801.2(S2) PQ801.3(S3) PQ805.3(S) PR10.1 PR11.1 PR700.1 PR703.1 PR705.1 PR802.1 PR804.1
+20V_LDO_INPUT: PC11.1 PD803.1(3) PU2.1(VCC)
+20V_TBTA_VBUS: CT99.1 CT100.2 CT101.1 CT102.2 CT189.1 CT190.1 DT4.1(INPUT) JUSBC1.A4(VBUS_1) JUSBC1.A9(VBUS_2) JUSBC1.B4(VBUS_3) JUSBC1.B9(VBUS_4) PC806.1 PC807.1 PL800.1 PL801.1
+20V_TBTA_VBUS_1: CT82.1 CT94.1 PC803.1 PC808.1 PC809.1 PL800.2 PL801.2 PQ800.1(S1) PQ800.2(S2) PQ800.3(S3) PQ803.3(S) PR801.1 PR803.1 PR823.1 PR831.1 PR872.2 UT5.A10(SENSEN) UT5.B10(SENSEP) UT5.H11(VBUS_1) UT5.J10(VBUS_2) UT5.J11(VBUS_3) UT5.K11(VBUS_4) UT8.1(VCC)
+20V_VBUS_DC_SS: PD704.2 PD801.2 PD801.3 PQ800.5(D) PQ801.5(D) PR862.1 PR870.1
+DV33_18: CR22.1 UR1.18(DV33_18)
+GND_CHASSIS: CL22.2 RL15.2 RL16.2 RL17.2 RL18.2
+VCC1V8A_TBTA_LDO: CT73.1 UT5.K1(LDO_1V8A)
+VCC1V8D_TBTA_LDO: CT72.1 RT97.1 UT5.A2(LDO_1V8D)
+VCC3V3_ANA_PCIE: CT63.1 UT1.L16(VCC3P3_ANA_PCIE)
+VCC3V3_ANA_USB2: CT64.1 UT1.J16(VCC3P3_ANA_USB2)
+VCC_FUSEPRG: RC326.1 UC1.G30(VCCSTG1)
+VCC_SFR_OC: CC209.2 CC210.2 CC322.1 CC568.2 CZ103.1 RZ119.2 UC1.BH13(VCCPLL_OC1) UC1.BJ13(VCCPLL_OC2) UC1.G11(VCCPLL_OC3) UZ26.6(VOUT)
+VCCRTCEXT: CH68.1 UH1.BF47(DCPRTC1) UH1.BG47(DCPRTC2)
+VDDA_AVDD1: CA8.1 CA9.1 LA5.1 UA1.20(AVDD1)
+VSS_PLL: CE17.2 CE18.2 UE1.G1(VSS_PLL)
GND: CA5.2 CA6.2 CA7.2 CA10.2 CA12.2 CA13.1 CA19.2 CA22.2 CA23.2 CA24.2 CA31.2 CA33.2 CA45.2 CA46.2 CA47.2 CA48.2 CA49.1 CA53.2 CA54.2 CA55.2 CA56.2 CA59.2 CA60.2 CA61.2 CA62.2 CA63.2 CA64.2 CA65.2 CA66.2 CA67.2 CA68.2 CA69.2 CA72.2 CA73.2 CA74.2 CA75.2 CA76.2 CA80.1 CC28.2 CC29.2 CC32.2 CC33.2 CC81.2 CC82.2 CC83.2 CC84.2 CC161.2 CC163.2 CC164.2 CC165.2 CC166.2 CC167.2 CC168.2 CC170.2 CC171.2 CC172.2 CC185.2 CC186.1 CC187.2 CC188.2 CC189.2 CC191.1 CC192.1 CC193.1 CC194.1 CC195.1 CC209.1 CC210.1 CC269.2 CC272.2 CC300.2 CC301.2 CC302.2 CC303.2 CC304.2 CC305.2 CC306.2 CC307.2 CC308.2 CC310.2 CC311.2 CC316.2 CC318.2 CC319.2 CC320.2 CC322.2 CC323.2 CC324.2 CC325.2 CC327.2 CC328.2 CC329.2 CC330.2 CC331.2 CC332.2 CC333.1 CC334.2 CC335.2 CC336.2 CC337.2 CC500.2 CC501.2 CC549.2 CC556.2 CC557.2 CC558.2 CC568.1 CC569.1 CD1.2 CD2.2 CD3.2 CD4.2 CD5.2 CD6.2 CD7.2 CD8.2 CD9.2 CD10.2 CD11.2 CD12.2 CD13.2 CD14.2 CD15.2 CD16.2 CD17.2 CD18.2 CD19.2 CD20.2 CD21.2 CD22.2 CD23.2 CD24.2 CD25.2 CD26.2 CD27.2 CD28.2 CD29.2 CD32.2 CD33.2 CD34.2 CD35.2 CD36.2 CD37.2 CD38.2 CD39.2 CD40.2 CD41.2 CD42.2 CD43.2 CD44.2 CD45.2 CD46.2 CD47.2 CD48.2 CD49.2 CD50.2 CD51.2 CD52.2 CD53.2 CD54.2 CD55.2 CD56.2 CD57.2 CD58.2 CD59.2 CD60.2 CD61.2 CE3.2 CE4.2 CE8.2 CE10.2 CE11.2 CE12.2 CE13.2 CE14.2 CE15.2 CE16.2 CE19.2 CE20.2 CE21.2 CE22.2 CE23.2 CE25.2 CE28.2 CE29.2 CE30.2 CE31.2 CE32.2 CE36.2 CE38.2 CE40.2 CE47.2 CE52.2 CE53.2 CE54.2 CE57.2 CE59.2 CE60.2 CE61.2 CE62.2 CE63.2 CE64.2 CE65.2 CE66.2 CE548.2 CE549.2 CH2.2 CH4.1 CH5.1 CH9.2 CH10.2 CH13.2 CH14.2 CH20.2 CH21.2 CH22.2 CH29.2 CH30.2 CH31.2 CH32.2 CH33.2 CH34.2 CH35.2 CH36.2 CH37.2 CH38.2 CH40.1 CH41.1 CH44.2 CH45.2 CH46.2 CH47.2 CH62.2 CH63.2 CH64.2 CH65.2 CH66.2 CH67.2 CH68.2 CH266.2 CH267.2 CH268.1 CH270.2 CH321.2 CH322.2 CH323.2 CH324.2 CH340.2 CH341.2 CH342.2 CH343.2 CH344.2 CH345.2 CH346.2 CH347.2 CH348.2 CH349.2 CH350.2 CH550.2 CH551.2 CH552.2 CH553.2 CH554.2 CH555.2 CH556.2 CH558.2 CH559.2 CI1.2 CI3.2 CI6.2 CI7.2 CI8.2 CI9.2 CI10.2 CI11.2 CI12.2 CI14.2 CI17.2 CI19.2 CI31.2 CI32.2 CI33.2 CI34.2 CI43.2 CI44.2 CI45.2 CI46.2 CI47.2 CI48.2 CI50.2 CI52.2 CI103.2 CI104.2 CL3.2 CL4.2 CL7.2 CL8.2 CL9.2 CL10.2 CL11.2 CL12.2 CL13.2 CL14.2 CL16.2 CL17.2 CL18.2 CL19.2 CL20.2 CL21.2 CL22.1 CL28.2 CL29.2 CL30.2 CLP1.1(P1) CLP2.1(P1) CLP3.1(P1) CLP4.1(P1) CMOS1.1 CN1.2 CN2.2 CN3.2 CN8.2 CN9.2 CN10.2 CN11.2 CN16.2 CN17.2 CN60.2 CN61.2 CN62.2 CN63.2 CN64.2 CN77.2 CN80.2 CN81.2 CN82.2 CN84.2 CN86.2 CR1.2 CR2.2 CR3.2 CR4.2 CR5.2 CR6.2 CR7.2 CR15.2 CR17.1 CR18.1 CR19.1 CR20.1 CR21.2 CR22.2 CR25.2 CR26.2 CR27.2 CR28.2 CT1.2 CT20.2 CT21.2 CT25.2 CT26.2 CT27.2 CT28.2 CT29.2 CT30.2 CT31.2 CT32.2 CT33.2 CT34.2 CT35.2 CT36.2 CT37.2 CT38.2 CT39.2 CT40.2 CT41.2 CT42.2 CT43.2 CT44.2 CT45.2 CT46.2 CT47.2 CT48.2 CT49.2 CT50.2 CT51.2 CT52.2 CT53.2 CT54.2 CT55.2 CT56.2 CT57.2 CT59.2 CT60.2 CT61.2 CT62.2 CT63.2 CT64.2 CT67.2 CT68.2 CT69.2 CT70.2 CT71.2 CT72.2 CT73.2 CT74.2 CT75.2 CT76.2 CT77.2 CT78.2 CT82.2 CT83.2 CT84.2 CT85.2 CT86.2 CT87.2 CT88.2 CT89.2 CT90.2 CT91.2 CT92.2 CT93.2 CT94.2 CT99.2 CT100.1 CT101.2 CT102.1 CT189.2 CT190.2 CT237.2 CT360.2 CV8.2 CV9.2 CV10.2 CV11.2 CV12.2 CV14.2 CV15.2 CV16.2 CV17.2 CV18.2 CV19.2 CV20.2 CV21.2 CV22.2 CV23.2 CV24.2 CV25.2 CV39.2 CV40.2 CV41.2 CV42.2 CV43.2 CV44.2 CV45.2 CV46.2 CV47.2 CV48.2 CV605.2 CV606.2 CV607.2 CV608.2 CV609.2 CV610.2 CV611.2 CV612.2 CV613.2 CV614.2 CV615.2 CV616.2 CV617.2 CV618.2 CV619.2 CV620.2 CV621.2 CV622.2 CV623.2 CV624.2 CV625.2 CV626.2 CV627.2 CV628.2 CV629.2 CV630.2 CV632.2 CV633.2 CV634.2 CV635.2 CV636.2 CV1635.2 CV1637.2 CV1638.2 CV1641.2 CZ1.2 CZ2.2 CZ3.2 CZ7.2 CZ8.2 CZ9.2 CZ17.2 CZ18.2 CZ19.2 CZ20.2 CZ21.2 CZ23.2 CZ24.2 CZ25.2 CZ26.2 CZ27.2 CZ28.2 CZ29.2 CZ30.2 CZ31.2 CZ32.2 CZ33.2 CZ34.2 CZ35.2 CZ36.2 CZ37.2 CZ39.2 CZ40.2 CZ41.2 CZ50.2 CZ51.2 CZ52.2 CZ53.2 CZ54.2 CZ55.2 CZ56.2 CZ57.2 CZ58.2 CZ62.2 CZ63.2 CZ64.2 CZ66.2 CZ67.2 CZ68.2 CZ69.2 CZ71.2 CZ72.2 CZ73.2 CZ75.2 CZ80.2 CZ81.2 CZ82.2 CZ83.2 CZ84.2 CZ85.2 CZ86.2 CZ87.2 CZ88.2 CZ89.2 CZ90.2 CZ91.2 CZ92.2 CZ93.2 CZ100.2 CZ101.2 CZ102.2 CZ103.2 CZ104.2 CZ105.2 CZ106.2 CZ109.2 CZ110.2 CZ111.2 CZ112.2 CZ113.2 CZ114.2 CZ115.2 CZ116.2 CZ117.2 CZ118.2 CZ119.2 CZ120.2 CZ121.2 CZ122.2 CZ124.2 CZ129.2 CZ130.2 CZ154.2 CZ155.2 CZ197.2 CZ198.2 CZ216.2 CZ217.2 CZ218.2 CZ305.2 CZ306.2 CZ309.2 CZ500.2 CZ544.2 CZ1200.2 CZ1201.2 CZ1202.2 CZ1203.2 CZ1204.2 CZ1205.2 CZ1206.2 DA1.1 DA2.1 DA3.1 DA6.1 DA7.1 DA9.1 DA10.1 DD32.2 DE1.2 DE43.2 DI1.3 DI2.1 DI3.1 DI4.3 DI5.1 DI6.3 DT4.2(OUT) DT5.2 DT6.2 DT9.2 DT10.2 DT13.2 DT14.2 DT17.2 DT18.2 DT39.3 DT40.3 DT41.3 DT42.3 DZ10.1 DZ11.1 DZ13.3 H1.1 H2.1 H3.1 H4.1 H7.1 H8.1 H10.1 H11.1 H12.1 H13.1 H15.1 H16.1 H17.1 H18.1 H19.1 H20.1 H23.1 H30.1 H35.1 JAPS1.8 JAPS1.10 JAPS1.12 JAPS1.14 JAPS1.19(GND1) JAPS1.20(GND2) JDEG1.10 JDEG1.11(GND1) JDEG1.12(GND2) JDIMM1.1(VSS1) JDIMM1.2(VSS2) JDIMM1.5(VSS3) JDIMM1.6(VSS4) JDIMM1.9(VSS5) JDIMM1.10(VSS6) JDIMM1.14(VSS7) JDIMM1.15(VSS8) JDIMM1.18(VSS9) JDIMM1.19(VSS10) JDIMM1.22(VSS11) JDIMM1.23(VSS12) JDIMM1.26(VSS13) JDIMM1.27(VSS14) JDIMM1.30(VSS15) JDIMM1.31(VSS16) JDIMM1.35(VSS17) JDIMM1.36(VSS18) JDIMM1.39(VSS19) JDIMM1.40(VSS20) JDIMM1.43(VSS21) JDIMM1.44(VSS22) JDIMM1.47(VSS23) JDIMM1.48(VSS24) JDIMM1.51(VSS25) JDIMM1.52(VSS26) JDIMM1.56(VSS27) JDIMM1.57(VSS28) JDIMM1.60(VSS29) JDIMM1.61(VSS30) JDIMM1.64(VSS31) JDIMM1.65(VSS32) JDIMM1.68(VSS33) JDIMM1.69(VSS34) JDIMM1.72(VSS35) JDIMM1.73(VSS36) JDIMM1.77(VSS37) JDIMM1.78(VSS38) JDIMM1.81(VSS39) JDIMM1.82(VSS40) JDIMM1.85(VSS41) JDIMM1.86(VSS42) JDIMM1.89(VSS43) JDIMM1.90(VSS44) JDIMM1.93(VSS45) JDIMM1.94(VSS46) JDIMM1.98(VSS47) JDIMM1.99(VSS48) JDIMM1.102(VSS49) JDIMM1.103(VSS50) JDIMM1.106(VSS51) JDIMM1.107(VSS52) JDIMM1.167(VSS53) JDIMM1.168(VSS54) JDIMM1.171(VSS55) JDIMM1.172(VSS56) JDIMM1.175(VSS57) JDIMM1.176(VSS58) JDIMM1.180(VSS59) JDIMM1.181(VSS60) JDIMM1.184(VSS61) JDIMM1.185(VSS62) JDIMM1.188(VSS63) JDIMM1.189(VSS64) JDIMM1.192(VSS65) JDIMM1.193(VSS66) JDIMM1.196(VSS67) JDIMM1.197(VSS68) JDIMM1.201(VSS69) JDIMM1.202(VSS70) JDIMM1.205(VSS71) JDIMM1.206(VSS72) JDIMM1.209(VSS73) JDIMM1.210(VSS74) JDIMM1.213(VSS75) JDIMM1.214(VSS76) JDIMM1.217(VSS77) JDIMM1.218(VSS78) JDIMM1.222(VSS79) JDIMM1.223(VSS80) JDIMM1.226(VSS81) JDIMM1.227(VSS82) JDIMM1.230(VSS83) JDIMM1.231(VSS84) JDIMM1.234(VSS85) JDIMM1.235(VSS86) JDIMM1.238(VSS87) JDIMM1.239(VSS88) JDIMM1.243(VSS89) JDIMM1.244(VSS90) JDIMM1.247(VSS91) JDIMM1.248(VSS92) JDIMM1.251(VSS93) JDIMM1.252(VSS94) JDIMM1.261(GND2) JDIMM1.262(GND1) JDIMM2.1(VSS1) JDIMM2.2(VSS2) JDIMM2.5(VSS3) JDIMM2.6(VSS4) JDIMM2.9(VSS5) JDIMM2.10(VSS6) JDIMM2.14(VSS7) JDIMM2.15(VSS8) JDIMM2.18(VSS9) JDIMM2.19(VSS10) JDIMM2.22(VSS11) JDIMM2.23(VSS12) JDIMM2.26(VSS13) JDIMM2.27(VSS14) JDIMM2.30(VSS15) JDIMM2.31(VSS16) JDIMM2.35(VSS17) JDIMM2.36(VSS18) JDIMM2.39(VSS19) JDIMM2.40(VSS20) JDIMM2.43(VSS21) JDIMM2.44(VSS22) JDIMM2.47(VSS23) JDIMM2.48(VSS24) JDIMM2.51(VSS25) JDIMM2.52(VSS26) JDIMM2.56(VSS27) JDIMM2.57(VSS28) JDIMM2.60(VSS29) JDIMM2.61(VSS30) JDIMM2.64(VSS31) JDIMM2.65(VSS32) JDIMM2.68(VSS33) JDIMM2.69(VSS34) JDIMM2.72(VSS35) JDIMM2.73(VSS36) JDIMM2.77(VSS37) JDIMM2.78(VSS38) JDIMM2.81(VSS39) JDIMM2.82(VSS40) JDIMM2.85(VSS41) JDIMM2.86(VSS42) JDIMM2.89(VSS43) JDIMM2.90(VSS44) JDIMM2.93(VSS45) JDIMM2.94(VSS46) JDIMM2.98(VSS47) JDIMM2.99(VSS48) JDIMM2.102(VSS49) JDIMM2.103(VSS50) JDIMM2.106(VSS51) JDIMM2.107(VSS52) JDIMM2.167(VSS53) JDIMM2.168(VSS54) JDIMM2.171(VSS55) JDIMM2.172(VSS56) JDIMM2.175(VSS57) JDIMM2.176(VSS58) JDIMM2.180(VSS59) JDIMM2.181(VSS60) JDIMM2.184(VSS61) JDIMM2.185(VSS62) JDIMM2.188(VSS63) JDIMM2.189(VSS64) JDIMM2.192(VSS65) JDIMM2.193(VSS66) JDIMM2.196(VSS67) JDIMM2.197(VSS68) JDIMM2.201(VSS69) JDIMM2.202(VSS70) JDIMM2.205(VSS71) JDIMM2.206(VSS72) JDIMM2.209(VSS73) JDIMM2.210(VSS74) JDIMM2.213(VSS75) JDIMM2.214(VSS76) JDIMM2.217(VSS77) JDIMM2.218(VSS78) JDIMM2.222(VSS79) JDIMM2.223(VSS80) JDIMM2.226(VSS81) JDIMM2.227(VSS82) JDIMM2.230(VSS83) JDIMM2.231(VSS84) JDIMM2.234(VSS85) JDIMM2.235(VSS86) JDIMM2.238(VSS87) JDIMM2.239(VSS88) JDIMM2.243(VSS89) JDIMM2.244(VSS90) JDIMM2.247(VSS91) JDIMM2.248(VSS92) JDIMM2.251(VSS93) JDIMM2.252(VSS94) JDIMM2.261(GND2) JDIMM2.262(GND1) JEDP1.4 JEDP1.6 JEDP1.8 JEDP1.15 JEDP1.23 JEDP1.24 JEDP1.25 JEDP1.27 JEDP1.28 JEDP1.39 JEDP1.41(G1) JEDP1.42(G2) JEDP1.43(G3) JEDP1.44(G4) JEDP1.45(G5) JESPI.9 JESPI.11(GND1) JESPI.12(GND2) JFAN1.1 JFAN1.5(GND1) JFAN1.6(GND2) JFPBTN1.2 JFPBTN1.8 JHDMI1.2(D2_SHIELD) JHDMI1.5(D1_SHIELD) JHDMI1.8(D0_SHIELD) JHDMI1.11(CK_SHIELD) JHDMI1.17(DDC/CEC_GND) JHDMI1.20(GND1) JHDMI1.21(GND2) JHDMI1.22(GND3) JHDMI1.23(GND4) JIRTS1.6 JIRTS1.7 JIRTS1.11(GND1) JIRTS1.12(GND2) JKBTP1.2 JKBTP1.3 JKBTP1.9 JKBTP1.15 JKBTP1.17 JKBTP1.20 JKBTP1.21(GND1) JKBTP1.22(GND2) JLED1.3 JLED1.7(GND1) JLED1.8(GND2) JLOM1.9(GND1) JLOM1.10(GND2) JLOM1.11(GND3) JLOM1.12(GND4) JNGFF1.1(GND1) JNGFF1.7(GND2) JNGFF1.13(SDIO_DAT0) JNGFF1.18(GND3) JNGFF1.19(SDIO_DAT3) JNGFF1.33(GND4) JNGFF1.39(GND5) JNGFF1.45(GND6) JNGFF1.51(GND7) JNGFF1.57(GND8) JNGFF1.63(GND9) JNGFF1.69(GND10) JNGFF1.75(GND11) JNGFF1.76(GND12) JNGFF1.77(GND13) JNGFF2.3(GND_3) JNGFF2.5(GND_5) JNGFF2.11(GND_11) JNGFF2.27(GND_27) JNGFF2.33(GND_33) JNGFF2.39(GND_39) JNGFF2.45(GND_45) JNGFF2.51(GND_51) JNGFF2.57(GND_57) JNGFF2.71(GND_71) JNGFF2.73(GND_73) JNGFF2.76(GND2) JNGFF2.77(GND1) JNGFF3.1(GND1) JNGFF3.3(GND2) JNGFF3.9(GND3) JNGFF3.15(GND4) JNGFF3.21(GND5) JNGFF3.27(GND6) JNGFF3.33(GND7) JNGFF3.39(GND8) JNGFF3.45(GND9) JNGFF3.51(GND10) JNGFF3.57(GND11) JNGFF3.71(GND12) JNGFF3.73(GND13) JNGFF3.75(GND14) JNGFF3.76(GND15) JNGFF3.77(GND16) JRTC1.2 JRTC1.3(G1) JRTC1.4(G2) JSATA1.1 JSATA1.4 JSATA1.7 JSATA1.12 JSATA1.14 JSATA1.18 JSATA1.21(GND1) JSATA1.22(GND2) JSATA1.23(GND3) JSATA1.24(GND4) JSD1.6(VSS1) JSD1.10(GND1) JSD1.11(GND2) JSD1.12(GND3) JSD1.13(GND4) JSD1.14(GND5) JSD1.17(VSS2) JSD1.20(VSS3) JSD1.23(VSS4) JSIM1.3(GND1) JSIM1.4(GND2) JSIM1.5(GND3) JSIM1.6(GND4) JSIM1.7(GND5) JSIM1.8(GND6) JSIM1.9(GND7) JSIM1.C5(GND) JSPI1.1 JSPI1.2 JSPI1.3 JSPI1.21(GND_1) JSPI1.22(GND_2) JSPK1.5(G1) JSPK1.6(G2) JTAG1.2 JUSB1.4(GND1) JUSB1.7(GND_DRAIN) JUSB1.10(GND2) JUSB1.11(GND3) JUSB1.12(GND4) JUSB1.13(GND5) JUSB2.4(GND1) JUSB2.7(GND_DRAIN) JUSB2.10(GND2) JUSB2.11(GND3) JUSB2.12(GND4) JUSB2.13(GND5) JUSB3.4(GND1) JUSB3.7(GND_DRAIN) JUSB3.10(GND2) JUSB3.11(GND3) JUSB3.12(GND4) JUSB3.13(GND5) JUSBC1.1(GND_5) JUSBC1.2(GND_6) JUSBC1.3(GND_7) JUSBC1.4(GND_8) JUSBC1.5(GND_9) JUSBC1.6(GND_10) JUSBC1.A1(GND_1) JUSBC1.A12(GND_2) JUSBC1.B1(GND_3) JUSBC1.B12(GND_4) JUSH1.3 JUSH1.17 JUSH1.20 JUSH1.21 JUSH1.27(GND1) JUSH1.28(GND2) JXDP1.2 JXDP1.7 JXDP1.8 JXDP1.13 JXDP1.14 JXDP1.19 JXDP1.20 JXDP1.25 JXDP1.26 JXDP1.31 JXDP1.32 JXDP1.37 JXDP1.38 JXDP1.49 JXDP1.50 JXDP1.59 JXDP1.61 JXDP1.62(GND#62) JXDP1.63(GND#63) LGA1.5(RES) LGA1.6(GND1) LGA1.7(GND2) LGA1.8(GND3) PBATT1.7 PBATT1.8 PBATT1.9 PBATT1.10 PC1.2 PC2.1 PC3.2 PC5.2 PC7.2 PC8.2 PC9.2 PC10.2 PC11.2 PC12.2 PC13.1 PC100.2 PC103.2 PC104.2 PC105.2 PC106.2 PC107.2 PC108.2 PC109.2 PC110.2 PC111.1 PC112.2 PC115.2 PC116.2 PC117.2 PC118.2 PC119.2 PC120.2 PC121.2 PC122.2 PC123.2 PC124.2 PC125.2 PC126.2 PC128.2 PC129.2 PC130.2 PC135.2 PC136.2 PC137.2 PC138.2 PC141.2 PC142.2 PC161.2 PC162.2 PC163.2 PC164.2 PC165.2 PC166.2 PC167.2 PC168.2 PC169.2 PC170.2 PC171.2 PC172.2 PC200.2 PC201.2 PC202.2 PC203.2 PC204.2 PC206.2 PC207.2 PC209.2 PC210.2 PC211.2 PC212.2 PC213.2 PC214.2 PC216.2 PC217.2 PC218.2 PC219.2 PC221.2 PC222.2 PC223.2 PC224.2 PC225.2 PC226.2 PC227.2 PC228.2 PC229.2 PC230.2 PC231.2 PC232.2 PC233.2 PC234.2 PC235.2 PC236.2 PC237.2 PC301.2 PC302.2 PC303.2 PC305.2 PC306.2 PC308.2 PC309.2 PC310.2 PC311.2 PC312.1 PC313.2 PC314.1 PC316.2 PC401.2 PC402.2 PC403.2 PC404.2 PC406.2 PC407.2 PC408.2 PC409.2 PC410.2 PC411.2 PC425.2 PC426.2 PC427.2 PC428.2 PC501.2 PC504.2 PC505.2 PC506.2 PC507.2 PC508.2 PC510.2 PC511.2 PC513.2 PC514.2 PC516.2 PC517.2 PC530.1 PC531.2 PC532.2 PC700.2 PC701.2 PC702.2 PC703.2 PC704.2 PC706.2 PC707.2 PC708.2 PC709.2 PC710.2 PC715.2(G) PC716.2 PC717.2 PC720.2 PC721.2 PC725.2 PC726.2 PC736.2 PC737.1 PC738.2 PC739.1 PC741.2 PC742.2 PC743.2 PC744.2 PC745.2 PC746.2 PC747.2 PC748.2 PC749.2 PC750.2 PC751.2 PC753.2 PC754.1 PC755.2 PC756.2(G) PC757.2 PC758.2 PC761.2 PC762.2 PC763.2 PC764.2 PC765.2 PC766.2 PC767.2 PC768.2 PC800.2 PC801.1 PC804.2 PC805.2 PC806.2 PC807.2 PC808.2 PC809.2 PC810.2 PC811.2 PC812.2 PC813.2 PC814.1 PC815.2 PC816.2 PC817.2 PC818.2 PC834.2 PC835.2 PC836.2 PC837.2 PC838.2 PC839.2 PC840.2 PC841.2 PC842.2 PC843.2 PC844.2 PC848.2(G) PC849.2(G) PC865.2 PC1000.2 PC1001.2 PC1002.2 PC1003.2 PC1004.2 PC1005.2 PC1006.2 PC1007.2 PC1008.2 PC1009.2 PC1010.2 PC1011.2 PC1012.2 PC1013.2 PC1014.2 PC1015.2 PC1016.2 PC1017.2 PC1018.2 PC1019.2 PC1020.2 PC1023.2 PC1024.2 PC1025.2 PC1026.2 PC1027.2 PC1028.2 PC1029.2 PC1030.2 PC1031.2 PC1032.2 PC1033.2 PC1034.2 PC1035.2 PC1036.2 PC1037.2 PC1038.2 PC1039.2 PC1040.2 PC1041.2 PC1042.2 PC1043.2 PC1044.2 PC1045.2 PC1046.2 PC1047.2 PC1048.2 PC1049.2 PC1050.2 PC1051.2 PC1052.2 PC1053.2 PC1054.2 PC1055.2 PC1056.2 PC1057.2 PC1058.2 PC1059.2 PC1060.2 PC1061.2 PC1062.2 PC1063.2 PC1064.2 PC1065.2 PC1066.2 PC1067.2 PC1068.2 PC1069.2 PC1070.2 PC1071.2 PC1072.2 PC1073.2 PC1074.2 PC1075.2 PC1076.2 PC1077.2 PC1079.2 PC1080.2 PC1081.2 PC1082.2 PC1083.2 PC1084.2 PC1085.2 PC1086.2 PC1087.2 PC1088.2 PC1089.2 PC1090.2 PC1091.2 PC1092.2 PC1093.2 PC1094.2 PC1095.2 PC1096.2 PC1097.2 PC1098.2 PC1099.2 PC1171.2 PC1629.2 PC1634.2 PC1635.2 PC1636.2 PC1637.2 PC1638.2 PC1639.2 PC1640.2 PC1641.2 PC1642.2 PC1643.2 PC1644.2 PC1645.2 PC1646.2 PC1647.2 PC1648.2 PC1649.2 PC1650.2 PC1651.2 PC1652.2 PC1653.2 PC1654.2 PC1675.2 PC2027.2 PC2028.2 PC2029.2 PC2030.2 PC2031.2 PC2032.2 PC2033.2 PC2034.2 PC2035.2 PC2036.2 PC2037.2 PC2038.2 PC2039.2 PC2040.2 PC2041.2 PC2042.2 PC2043.2 PC2044.2 PC2045.2 PC2046.2 PC2047.2 PC2048.2 PC2049.2 PC2050.2 PC2051.2 PC2052.2 PC2053.2 PC2054.2 PC2055.2 PC2056.2 PC2057.2 PC2058.2 PC2060.2(G) PC2061.2(G) PC2073.2 PC2074.2 PC2075.2 PC2076.2 PC2077.2 PC2078.2 PC2079.2 PC2080.2 PC2120.2 PC2121.2 PC2208.2 PC2211.2 PC2212.2 PC3001.1 PC3002.2 PC3003.1 PC3004.1 PC3005.2 PC3006.2 PC3007.2 PC3008.2 PC3009.2 PCA1.2 PCA2.2 PCA3.2 PCA4.2 PCA7.2(G) PCA8.2 PCA9.2 PCA11.2 PCA12.2 PCA13.2 PCA14.2 PCH1.2 PCH2.2 PCH3.2 PCH4.2 PCH5.2(G) PCH6.2 PCH7.2 PCH8.2 PCH11.2 PCH13.2 PCH14.2 PCH15.2(G) PCH16.2 PCH17.2 PCH19.2(G) PCH20.2 PCH21.2 PCH23.2 PCH24.2 PCH26.2 PCH27.2 PCH28.2 PCH29.2 PCH30.2 PCH31.2 PCH32.2 PCH33.2 PCH36.2(G) PCH37.2 PCH38.2 PCH39.2 PCH40.2 PCH43.2(G) PCH44.2 PCH45.2 PCH47.2 PCH48.2 PCH49.2 PCH51.2 PCH52.2 PCH53.2 PCH54.2 PCH55.2 PCT1.2(G) PCT2.2 PCT3.2 PCT4.2 PCT5.2 PCT6.2 PCT7.2 PCT8.2 PCT9.2 PCT10.2 PCT11.2 PCT13.2 PCT14.2 PCT15.2(G) PCT16.2 PCZ3.2 PCZ6.1 PCZ8.2 PCZ9.1 PCZ12.1 PCZ22.1 PCZ24.2 PCZ27.1 PCZ30.2 PCZ31.2 PCZ32.2 PCZ33.2 PCZ34.2 PD1.1 PD2.1 PD4.1 PD701.2 PHZ4.2 PHZ5.2 PJP19.2 PJPDC1.4 PJPDC1.5 PJPDC1.6(GND1) PJPDC1.7(GND2) PQ1.1(S1) PQ1.4(S2) PQ3.3(EMITTER) PQ6.3(S) PQ7.3(S) PQ10.1(S1) PQ10.4(S2) PQ12.3(S) PQ13.3(SOURCE) PQ700.1(S1) PQ700.2(S2) PQ700.3(S3) PQ701.10(S2) PQ703.3(S) PQ802.1(S1) PQ802.4(S2) PQ804.1(S1) PQ804.4(S2) PQ806.1(S1) PQ806.4(S2) PQ808.1(S) PQ808.4(S) PQ809.1(S) PQ809.4(S) PQ811.1(S) PQ811.4(S) PQ812.3(S) PQ813.1(S1) PQ813.4(S2) PQ814.3(S) PQ3000.1(S) PQ3000.4(S) PR8.2 PR9.2 PR13.2 PR14.2 PR24.2 PR45.2 PR103.2 PR116.2 PR206.2 PR207.2 PR209.2 PR212.2 PR302.2 PR310.2 PR403.2 PR412.1 PR415.2 PR416.2 PR505.2 PR506.2 PR509.2 PR510.2 PR514.2 PR516.2 PR706.2 PR709.1 PR716.2 PR720.2 PR723.2 PR725.2 PR739.2 PR744.2 PR815.2 PR817.2 PR819.2 PR823.2 PR842.2 PR843.2 PR846.2 PR855.2 PR862.2 PR1648.2 PR1708.2 PR3003.1 PR3005.1 PR3008.1 PR3011.2 PRZ1.2 PRZ15.1 PRZ22.1 PRZ24.1 PRZ26.2 PRZ39.2 PRZ41.1 PRZ44.2 PRZ62.2 PRZ63.2 PRZ66.2 PRZ67.2 PRZ68.2 PRZ69.2 PRZ70.2 PRZ82.2 PRZ83.2 PU2.2(GND) PU3.3(G) PU100.7(GND1) PU100.8(GND2) PU100.18(GND4) PU100.21(GND3) PU102.7(GND1) PU102.8(GND2) PU102.18(GND4) PU102.21(GND3) PU200.4(VTTGND) PU200.9(PGND) PU200.15(SGND) PU301.7(GND1) PU301.8(GND2) PU301.18(GND3) PU301.21(PAD) PU401.6(SGND) PU401.15(PGND1) PU401.16(PGND2) PU401.17(TP) PU501.2(GND) PU502.4(GND1) PU502.9(GND2) PU503.4(GND1) PU503.9(GND2) PU700.33(PAD) PU701.3(G) PU800.4(G) PU801.3(G) PU3000.4(VEE) PUA1.2(SMOD#) PUA1.4(CGND) PUA1.10(PGND1) PUA1.14(PGND2) PUA1.18(AGND) PUH1.4(CGND) PUH1.10(PGND1) PUH1.14(PGND2) PUH1.18(AGND) PUH2.4(CGND) PUH2.10(PGND1) PUH2.14(PGND2) PUH2.18(AGND) PUH3.4(CGND) PUH3.10(PGND1) PUH3.14(PGND2) PUH3.18(AGND) PUH4.4(CGND) PUH4.10(PGND1) PUH4.14(PGND2) PUH4.18(AGND) PUT1.4(CGND) PUT1.10(PGND1) PUT1.14(PGND2) PUT1.18(AGND) PUZ1.53(TAB) QE2.1(S1) QE2.4(S1) QE12.3(S) QE17.3(S) QH6.3(S) QH8.1(S2) QH8.4(S1) QN1.1(S1) QN1.4(S2) QN6.3(S) QR1.3(S) QV2.3(S) QV7.3(S) QV19.3(EMITTER) QV21.3(EMITTER) QZ17.1(S1) QZ17.4(S1) QZ18.1(S1) QZ18.4(S1) QZ19.3(S) RA35.2 RA36.2 RA37.2 RA45.2 RA51.2 RA52.1 RC5.1 RC6.1 RC7.1 RC75.2 RC114.2 RC122.2 RC136.2 RC139.2 RC141.2 RC171.1 RC178.2 RC179.2 RC181.2 RC219.1 RC319.1 RC321.2 RC322.2 RC323.2 RC324.2 RC325.2 RC436.2 RC437.2 RC438.2 RC440.2 RC441.2 RC442.2 RC443.2 RC558.2 RC756.2 RD5.2 RD7.2 RD9.2 RD16.2 RD18.2 RD21.2 RD23.2 RD25.2 RD29.2 RD31.2 RE20.2 RE55.2 RE56.2 RE58.2 RE65.2 RE77.2 RE85.2 RE86.2 RE93.2 RE95.1 RE313.2 RE342.2 RE541.1 RE550.2 RE702.2 RE716.1 RE717.1 RE718.1 RH1.1 RH65.2 RH70.2 RH74.2 RH83.2 RH110.2 RH193.2 RH268.2 RH308.2 RH313.2 RH317.1 RH323.1 RH325.1 RH326.1 RH334.1 RH364.2 RH365.2 RH372.2 RH377.1 RH379.2 RH401.2 RH424.2 RH435.1 RH554.2 RH556.2 RH603.2 RH606.2 RH608.2 RH609.1 RH610.1 RH611.1 RH612.1 RH617.1 RH618.1 RH626.2 RH627.2 RH628.2 RH629.2 RH630.2 RH631.2 RH632.2 RH633.2 RH634.2 RH635.2 RH636.1 RH637.1 RH649.2 RH650.2 RH651.2 RH652.2 RH868.1 RI14.1 RI59.2 RI60.2 RI61.2 RI69.1 RI70.2 RI71.2 RI73.2 RI75.1 RI76.2 RI77.1 RI78.2 RL3.2 RL9.2 RL12.2 RL13.2 RN5.2 RN7.1 RN9.1 RN11.1 RN13.1 RN15.1 RN17.1 RN19.2 RN21.2 RR4.2 RT21.2 RT22.2 RT23.2 RT24.2 RT25.2 RT26.2 RT27.2 RT28.2 RT29.2 RT30.2 RT31.2 RT32.2 RT33.2 RT34.2 RT35.2 RT36.2 RT37.2 RT38.2 RT41.2 RT42.2 RT63.2 RT64.2 RT65.2 RT71.2 RT81.2 RT82.2 RT86.2 RT96.2 RT99.2 RT100.2 RT101.2 RT103.2 RT124.2 RT125.2 RT126.2 RT127.2 RT128.2 RT129.2 RT184.2 RT219.2 RT220.2 RT221.2 RT222.2 RT377.2 RT393.2 RT440.1 RT447.1 RT488.2 RT489.2 RT490.2 RT491.2 RT503.1 RV1.2 RV2.2 RV3.1 RV38.2 RV319.1 RV601.1 RV602.1 RV610.2 RV611.2 RV615.2 RV618.2 RV619.2 RV624.2 RV626.2 RV629.2 RZ10.1 RZ25.2 RZ38.1 RZ40.1 RZ334.2 RZ360.2 RZ1399.2 RZ1406.2 RZ1450.2 RZ1472.1 SHDCAN.1(P1) SW1.4(G1) SW1.5(G2) SW3.1 SW3.3 UA1.41(THERMAL_PAD) UC1.A3(VSS_A3) UC1.A4(VSS_A4) UC1.A6(VSS_11) UC1.A9(VSS_12) UC1.A10(VSS_1) UC1.A12(VSS_2) UC1.A14(VSS_154) UC1.A16(VSS_3) UC1.A18(VSS_4) UC1.A20(VSS_5) UC1.A22(VSS_6) UC1.A24(VSS_7) UC1.A26(VSS_8) UC1.A28(VSS_9) UC1.A30(VSS_10) UC1.A34(VSS_A34) UC1.AA12(VSS_13) UC1.AA29(VSS_14) UC1.AA30(VSS_15) UC1.AB6(VSS_18) UC1.AB33(VSS_16) UC1.AB34(VSS_17) UC1.AC1(VSS_19) UC1.AC2(VSS_21) UC1.AC3(VSS_22) UC1.AC4(VSS_25) UC1.AC5(VSS_26) UC1.AC6(VSS_27) UC1.AC12(VSS_20) UC1.AC37(VSS_23) UC1.AC38(VSS_24) UC1.AD6(VSS_33) UC1.AD7(VSS_155) UC1.AD8(VSS_34) UC1.AD9(VSS_35) UC1.AD10(VSS_28) UC1.AD11(VSS_29) UC1.AD12(VSS_30) UC1.AD29(VSS_31) UC1.AD30(VSS_32) UC1.AE6(VSS_38) UC1.AE33(VSS_36) UC1.AE34(VSS_37) UC1.AF1(VSS_39) UC1.AF2(VSS_43) UC1.AF3(VSS_44) UC1.AF4(VSS_45) UC1.AF12(VSS_40) UC1.AF13(VSS_41) UC1.AF14(VSS_42) UC1.AG6(VSS_51) UC1.AG7(VSS_52) UC1.AG8(VSS_53) UC1.AG10(VSS_46) UC1.AG11(VSS_47) UC1.AG13(VSS_48) UC1.AG29(VSS_49) UC1.AG30(VSS_50) UC1.AH6(VSS_59) UC1.AH12(VSS_54) UC1.AH33(VSS_55) UC1.AH34(VSS_56) UC1.AH35(VSS_57) UC1.AH36(VSS_58) UC1.AJ1(VSS_60) UC1.AJ2(VSS_62) UC1.AJ3(VSS_63) UC1.AJ4(VSS_66) UC1.AJ5(VSS_67) UC1.AJ6(VSS_68) UC1.AJ13(VSS_61) UC1.AJ37(VSS_64) UC1.AJ38(VSS_65) UC1.AK4(VSS_82) UC1.AK29(VSS_80) UC1.AK30(VSS_81) UC1.AL4(VSS_88) UC1.AL7(VSS_89) UC1.AL8(VSS_90) UC1.AL9(VSS_91) UC1.AL10(VSS_83) UC1.AL12(VSS_84) UC1.AL14(VSS_85) UC1.AL33(VSS_86) UC1.AL34(VSS_87) UC1.AM1(VSS_92) UC1.AM2(VSS_94) UC1.AM3(VSS_95) UC1.AM4(VSS_98) UC1.AM5(VSS_99) UC1.AM12(VSS_93) UC1.AM37(VSS_96) UC1.AM38(VSS_97) UC1.AN5(VSS_103) UC1.AN6(VSS_104) UC1.AN12(VSS_100) UC1.AN29(VSS_101) UC1.AN30(VSS_102) UC1.AP8(VSS_110) UC1.AP9(VSS_111) UC1.AP10(VSS_105) UC1.AP11(VSS_106) UC1.AP12(VSS_107) UC1.AP33(VSS_108) UC1.AP34(VSS_109) UC1.AR1(VSS_112) UC1.AR2(VSS_115) UC1.AR3(VSS_117) UC1.AR4(VSS_127) UC1.AR5(VSS_128) UC1.AR13(VSS_113) UC1.AR14(VSS_114) UC1.AR29(VSS_116) UC1.AR30(VSS_118) UC1.AR31(VSS_119) UC1.AR32(VSS_120) UC1.AR33(VSS_121) UC1.AR34(VSS_122) UC1.AR35(VSS_123) UC1.AR36(VSS_124) UC1.AR37(VSS_125) UC1.AR38(VSS_126) UC1.AT6(VSS_131) UC1.AT29(VSS_129) UC1.AT30(VSS_130) UC1.AU6(VSS_137) UC1.AU7(VSS_138) UC1.AU8(VSS_139) UC1.AU9(VSS_140) UC1.AU10(VSS_132) UC1.AU11(VSS_133) UC1.AU12(VSS_134) UC1.AU33(VSS_135) UC1.AU34(VSS_136) UC1.AV37(VSS_141) UC1.AV38(VSS_142) UC1.AW1(VSS_143) UC1.AW2(VSS_145) UC1.AW3(VSS_147) UC1.AW4(VSS_149) UC1.AW5(VSS_163) UC1.AW12(VSS_144) UC1.AW29(VSS_146) UC1.AW30(VSS_148) UC1.AY12(VSS_164) UC1.AY14(VSS_316) UC1.AY33(VSS_165) UC1.AY34(VSS_166) UC1.B3(VSS_B3) UC1.B9(VSS_167) UC1.B37(VSS_B37) UC1.BA6(VSS_173) UC1.BA7(VSS_174) UC1.BA8(VSS_175) UC1.BA9(VSS_176) UC1.BA10(VSS_168) UC1.BA11(VSS_169) UC1.BA12(VSS_170) UC1.BA37(VSS_171) UC1.BA38(VSS_172) UC1.BB1(VSS_177) UC1.BB2(VSS_179) UC1.BB3(VSS_181) UC1.BB4(VSS_183) UC1.BB5(VSS_184) UC1.BB6(VSS_185) UC1.BB12(VSS_178) UC1.BB29(VSS_180) UC1.BB30(VSS_182) UC1.BC6(VSS_191) UC1.BC12(VSS_186) UC1.BC13(VSS_187) UC1.BC14(VSS_188) UC1.BC33(VSS_189) UC1.BC34(VSS_190) UC1.BD6(VSS_196) UC1.BD7(VSS_197) UC1.BD8(VSS_198) UC1.BD9(VSS_199) UC1.BD10(VSS_192) UC1.BD11(VSS_193) UC1.BD12(VSS_194) UC1.BD37(VSS_195) UC1.BD38(VSS_317) UC1.BE1(VSS_200) UC1.BE2(VSS_201) UC1.BE3(VSS_203) UC1.BE4(VSS_205) UC1.BE5(VSS_206) UC1.BE6(VSS_207) UC1.BE29(VSS_202) UC1.BE30(VSS_204) UC1.BF6(VSS_211) UC1.BF12(VSS_208) UC1.BF33(VSS_209) UC1.BF34(VSS_210) UC1.BG6(VSS_217) UC1.BG12(VSS_212) UC1.BG13(VSS_213) UC1.BG14(VSS_214) UC1.BG37(VSS_215) UC1.BG38(VSS_216) UC1.BH1(VSS_218) UC1.BH2(VSS_223) UC1.BH3(VSS_224) UC1.BH4(VSS_225) UC1.BH5(VSS_226) UC1.BH6(VSS_227) UC1.BH7(VSS_228) UC1.BH8(VSS_229) UC1.BH9(VSS_230) UC1.BH10(VSS_219) UC1.BH11(VSS_220) UC1.BH12(VSS_221) UC1.BH14(VSS_222) UC1.BJ12(VSS_242) UC1.BJ14(VSS_243) UC1.BJ15(VSS_244) UC1.BJ18(VSS_245) UC1.BJ22(VSS_246) UC1.BJ25(VSS_247) UC1.BJ29(VSS_248) UC1.BJ30(VSS_249) UC1.BJ31(VSS_250) UC1.BJ32(VSS_251) UC1.BJ33(VSS_252) UC1.BJ34(VSS_253) UC1.BJ35(VSS_254) UC1.BJ36(VSS_255) UC1.BK6(VSS_263) UC1.BK13(VSS_256) UC1.BK14(VSS_257) UC1.BK15(VSS_258) UC1.BK18(VSS_259) UC1.BK22(VSS_260) UC1.BK25(VSS_261) UC1.BK29(VSS_262) UC1.BL6(VSS_275) UC1.BL13(VSS_264) UC1.BL14(VSS_265) UC1.BL18(VSS_266) UC1.BL19(VSS_267) UC1.BL20(VSS_268) UC1.BL21(VSS_269) UC1.BL22(VSS_270) UC1.BL29(VSS_271) UC1.BL33(VSS_272) UC1.BL35(VSS_273) UC1.BL38(VSS_274) UC1.BM2(VSS_281) UC1.BM3(VSS_291) UC1.BM5(VSS_295) UC1.BM6(VSS_296) UC1.BM7(VSS_297) UC1.BM8(VSS_298) UC1.BM9(VSS_299) UC1.BM11(VSS_276) UC1.BM12(VSS_277) UC1.BM13(VSS_278) UC1.BM14(VSS_279) UC1.BM18(VSS_280) UC1.BM21(VSS_282) UC1.BM22(VSS_283) UC1.BM23(VSS_284) UC1.BM24(VSS_285) UC1.BM25(VSS_286) UC1.BM26(VSS_287) UC1.BM27(VSS_288) UC1.BM28(VSS_289) UC1.BM29(VSS_290) UC1.BM33(VSS_292) UC1.BM35(VSS_293) UC1.BM38(VSS_294) UC1.BN2(VSS_304) UC1.BN4(VSS_325) UC1.BN7(VSS_326) UC1.BN12(VSS_300) UC1.BN14(VSS_301) UC1.BN18(VSS_302) UC1.BN19(VSS_303) UC1.BN20(VSS_305) UC1.BN21(VSS_306) UC1.BN24(VSS_307) UC1.BN29(VSS_308) UC1.BN30(VSS_309) UC1.BN31(VSS_310) UC1.BN34(VSS_311) UC1.BP7(VSS_337) UC1.BP12(VSS_327) UC1.BP14(VSS_328) UC1.BP18(VSS_329) UC1.BP21(VSS_330) UC1.BP24(VSS_331) UC1.BP25(VSS_332) UC1.BP26(VSS_333) UC1.BP29(VSS_334) UC1.BP33(VSS_335) UC1.BP34(VSS_336) UC1.BR7(VSS_348) UC1.BR9(VSS_479) UC1.BR12(VSS_338) UC1.BR14(VSS_339) UC1.BR18(VSS_340) UC1.BR21(VSS_341) UC1.BR24(VSS_342) UC1.BR25(VSS_343) UC1.BR26(VSS_344) UC1.BR29(VSS_345) UC1.BR34(VSS_346) UC1.BR36(VSS_347) UC1.BR38(VSS_BR38) UC1.BT3(VSS_BT3) UC1.BT4(VSS_BT4) UC1.BT5(VSS_357) UC1.BT8(VSS_478) UC1.BT12(VSS_349) UC1.BT14(VSS_350) UC1.BT18(VSS_351) UC1.BT21(VSS_352) UC1.BT24(VSS_353) UC1.BT26(VSS_354) UC1.BT29(VSS_355) UC1.BT32(VSS_356) UC1.BT35(VSS_BT35) UC1.BT36(VSS_BT36) UC1.C2(VSS_C2) UC1.C5(VSS_370) UC1.C8(VSS_371) UC1.C9(VSS_372) UC1.C11(VSS_358) UC1.C13(VSS_359) UC1.C15(VSS_360) UC1.C17(VSS_361) UC1.C19(VSS_362) UC1.C21(VSS_363) UC1.C23(VSS_364) UC1.C25(VSS_365) UC1.C27(VSS_366) UC1.C29(VSS_367) UC1.C31(VSS_368) UC1.C37(VSS_369) UC1.D3(VSS_383) UC1.D6(VSS_386) UC1.D9(VSS_387) UC1.D10(VSS_373) UC1.D12(VSS_374) UC1.D14(VSS_375) UC1.D16(VSS_376) UC1.D18(VSS_377) UC1.D20(VSS_378) UC1.D22(VSS_379) UC1.D24(VSS_380) UC1.D26(VSS_381) UC1.D28(VSS_382) UC1.D30(VSS_384) UC1.D33(VSS_385) UC1.D38(VSS_D38) UC1.E4(VSS_391) UC1.E9(VSS_392) UC1.E34(VSS_388) UC1.E35(VSS_389) UC1.E38(VSS_390) UC1.F2(VSS_412) UC1.F3(VSS_418) UC1.F4(VSS_421) UC1.F5(VSS_422) UC1.F8(VSS_423) UC1.F9(VSS_424) UC1.F11(VSS_407) UC1.F13(VSS_408) UC1.F15(VSS_409) UC1.F17(VSS_410) UC1.F19(VSS_411) UC1.F21(VSS_413) UC1.F23(VSS_414) UC1.F25(VSS_415) UC1.F27(VSS_416) UC1.F29(VSS_417) UC1.F31(VSS_419) UC1.F36(VSS_420) UC1.G4(VSS_436) UC1.G5(VSS_437) UC1.G6(VSS_438) UC1.G8(VSS_439) UC1.G9(VSS_440) UC1.G10(VSS_425) UC1.G12(VSS_426) UC1.G14(VSS_427) UC1.G16(VSS_428) UC1.G18(VSS_429) UC1.G20(VSS_430) UC1.G22(VSS_431) UC1.G23(VSS_432) UC1.G24(VSS_433) UC1.G26(VSS_434) UC1.G28(VSS_435) UC1.H11(VSS_441) UC1.H12(VSS_442) UC1.H18(VSS_443) UC1.H22(VSS_444) UC1.H25(VSS_445) UC1.H32(VSS_446) UC1.H35(VSS_447) UC1.J4(VSS_455) UC1.J7(VSS_456) UC1.J10(VSS_448) UC1.J18(VSS_449) UC1.J22(VSS_450) UC1.J25(VSS_451) UC1.J32(VSS_452) UC1.J33(VSS_453) UC1.J36(VSS_454) UC1.K1(VSS_457) UC1.K2(VSS_460) UC1.K3(VSS_461) UC1.K4(VSS_463) UC1.K5(VSS_464) UC1.K7(VSS_465) UC1.K8(VSS_466) UC1.K9(VSS_467) UC1.K10(VSS_458) UC1.K11(VSS_459) UC1.K38(VSS_462) UC1.L29(VSS_468) UC1.L30(VSS_469) UC1.L33(VSS_470) UC1.L34(VSS_471) UC1.M6(VSS_405) UC1.M12(VSS_472) UC1.M13(VSS_473) UC1.M14(VSS_404) UC1.N1(VSS_406) UC1.N2(VSS_477) UC1.N3(VSS_393) UC1.N4(VSS_396) UC1.N5(VSS_397) UC1.N6(VSS_398) UC1.N7(VSS_399) UC1.N8(VSS_400) UC1.N9(VSS_401) UC1.N10(VSS_474) UC1.N11(VSS_475) UC1.N12(VSS_476) UC1.N33(VSS_394) UC1.N34(VSS_395) UC1.P6(VSS_313) UC1.P12(VSS_402) UC1.P37(VSS_403) UC1.P38(VSS_312) UC1.R12(VSS_314) UC1.R29(VSS_315) UC1.R30(VSS_318) UC1.T1(VSS_319) UC1.T2(VSS_231) UC1.T3(VSS_232) UC1.T4(VSS_235) UC1.T5(VSS_236) UC1.T7(VSS_237) UC1.T8(VSS_238) UC1.T9(VSS_239) UC1.T10(VSS_320) UC1.T11(VSS_321) UC1.T12(VSS_322) UC1.T13(VSS_323) UC1.T14(VSS_324) UC1.T33(VSS_233) UC1.T34(VSS_234) UC1.U6(VSS_150) UC1.U37(VSS_240) UC1.U38(VSS_241) UC1.V6(VSS_156) UC1.V12(VSS_151) UC1.V29(VSS_152) UC1.V30(VSS_153) UC1.W1(VSS_157) UC1.W2(VSS_159) UC1.W3(VSS_160) UC1.W4(VSS_69) UC1.W5(VSS_70) UC1.W12(VSS_158) UC1.W33(VSS_161) UC1.W34(VSS_162) UC1.Y7(VSS_77) UC1.Y8(VSS_78) UC1.Y9(VSS_79) UC1.Y10(VSS_71) UC1.Y11(VSS_72) UC1.Y13(VSS_73) UC1.Y14(VSS_74) UC1.Y37(VSS_75) UC1.Y38(VSS_76) UC3.3(G) UC5.4(GND1) UC5.9(GND2) UC6.4(GND) UD1.3(GND) UE1.A6(VSS1) UE1.A13(VSS2) UE1.C4(VSS_ANALOG) UE1.E6(VSS3) UE1.H4(VSS_ADC) UE3.3(G) UE4.3(GND) UE5.3(G) UH1.A2(VSS_1) UH1.A3(VSS_3) UH1.A4(VSS_6) UH1.A5(VSS_11) UH1.A8(VSS_12) UH1.A28(VSS_2) UH1.A33(VSS_4) UH1.A37(VSS_5) UH1.A45(VSS_7) UH1.A46(VSS_8) UH1.A47(VSS_9) UH1.A48(VSS_10) UH1.AA5(VSS_21) UH1.AA19(VSS_13) UH1.AA20(VSS_14) UH1.AA25(VSS_15) UH1.AA27(VSS_16) UH1.AA28(VSS_17) UH1.AA30(VSS_18) UH1.AA31(VSS_19) UH1.AA49(VSS_20) UH1.AB19(VSS_22) UH1.AB25(VSS_23) UH1.AB31(VSS_24) UH1.AC4(VSS_29) UH1.AC12(VSS_25) UH1.AC17(VSS_26) UH1.AC33(VSS_27) UH1.AC38(VSS_28) UH1.AC46(VSS_30) UH1.AD1(VSS_31) UH1.AD2(VSS_33) UH1.AD19(VSS_32) UH1.AD22(VSS_34) UH1.AD25(VSS_35) UH1.AD49(VSS_36) UH1.AE4(VSS_40) UH1.AE12(VSS_37) UH1.AE33(VSS_38) UH1.AE38(VSS_39) UH1.AE46(VSS_41) UH1.AF22(VSS_42) UH1.AF25(VSS_43) UH1.AF28(VSS_44) UH1.AG1(VSS_45) UH1.AG22(VSS_46) UH1.AG23(VSS_47) UH1.AG25(VSS_48) UH1.AG27(VSS_49) UH1.AG28(VSS_50) UH1.AG30(VSS_51) UH1.AG49(VSS_52) UH1.AH12(VSS_53) UH1.AH17(VSS_54) UH1.AH33(VSS_55) UH1.AH38(VSS_56) UH1.AJ19(VSS_57) UH1.AJ20(VSS_58) UH1.AJ25(VSS_59) UH1.AJ27(VSS_60) UH1.AJ28(VSS_61) UH1.AJ30(VSS_62) UH1.AJ31(VSS_63) UH1.AK4(VSS_71) UH1.AK19(VSS_64) UH1.AK20(VSS_65) UH1.AK25(VSS_66) UH1.AK27(VSS_67) UH1.AK28(VSS_68) UH1.AK30(VSS_69) UH1.AK31(VSS_70) UH1.AK46(VSS_72) UH1.AL12(VSS_73) UH1.AL17(VSS_74) UH1.AL21(VSS_75) UH1.AL24(VSS_76) UH1.AL26(VSS_77) UH1.AL29(VSS_78) UH1.AL33(VSS_79) UH1.AL38(VSS_80) UH1.AM1(VSS_81) UH1.AM18(VSS_82) UH1.AM32(VSS_83) UH1.AM49(VSS_84) UH1.AN12(VSS_85) UH1.AN16(VSS_86) UH1.AN34(VSS_87) UH1.AN38(VSS_88) UH1.AP4(VSS_89) UH1.AP46(VSS_90) UH1.AR12(VSS_91) UH1.AR16(VSS_92) UH1.AR34(VSS_93) UH1.AR38(VSS_94) UH1.AT1(VSS_95) UH1.AT16(VSS_96) UH1.AT18(VSS_97) UH1.AT21(VSS_98) UH1.AT24(VSS_99) UH1.AT26(VSS_100) UH1.AT29(VSS_101) UH1.AT32(VSS_102) UH1.AT34(VSS_103) UH1.AT45(VSS_104) UH1.AV11(VSS_105) UH1.AV39(VSS_106) UH1.AW4(VSS_108) UH1.AW10(VSS_107) UH1.AW40(VSS_109) UH1.AW46(VSS_110) UH1.B47(VSS_111) UH1.B48(VSS_112) UH1.B49(VSS_113) UH1.BA5(VSS_117) UH1.BA6(VSS_118) UH1.BA12(VSS_114) UH1.BA14(VSS_115) UH1.BA44(VSS_116) UH1.BB9(VSS_121) UH1.BB41(VSS_119) UH1.BB43(VSS_120) UH1.BC8(VSS_132) UH1.BC10(VSS_122) UH1.BC13(VSS_123) UH1.BC15(VSS_124) UH1.BC19(VSS_125) UH1.BC24(VSS_126) UH1.BC26(VSS_127) UH1.BC31(VSS_128) UH1.BC35(VSS_129) UH1.BC40(VSS_130) UH1.BC45(VSS_131) UH1.BD43(VSS_133) UH1.BE44(VSS_134) UH1.BF1(VSS_135) UH1.BF2(VSS_136) UH1.BF3(VSS_137) UH1.BF48(VSS_138) UH1.BF49(VSS_139) UH1.BG2(VSS_141) UH1.BG3(VSS_145) UH1.BG4(VSS_148) UH1.BG17(VSS_140) UH1.BG22(VSS_142) UH1.BG25(VSS_143) UH1.BG28(VSS_144) UH1.BG33(VSS_146) UH1.BG37(VSS_147) UH1.BG48(VSS_149) UH1.C4(VSS_153) UH1.C5(VSS_155) UH1.C12(VSS_150) UH1.C25(VSS_151) UH1.C30(VSS_152) UH1.C48(VSS_154) UH1.D8(VSS_161) UH1.D12(VSS_156) UH1.D16(VSS_157) UH1.D17(VSS_158) UH1.D30(VSS_159) UH1.D33(VSS_160) UH1.E8(VSS_175) UH1.E10(VSS_162) UH1.E13(VSS_163) UH1.E15(VSS_164) UH1.E17(VSS_165) UH1.E19(VSS_166) UH1.E22(VSS_167) UH1.E24(VSS_168) UH1.E26(VSS_169) UH1.E31(VSS_170) UH1.E33(VSS_171) UH1.E35(VSS_172) UH1.E40(VSS_173) UH1.E42(VSS_174) UH1.F41(VSS_176) UH1.F43(VSS_177) UH1.F47(VSS_178) UH1.G6(VSS_180) UH1.G44(VSS_179) UH1.H8(VSS_181) UH1.J4(VSS_185) UH1.J9(VSS_190) UH1.J10(VSS_182) UH1.J26(VSS_183) UH1.J29(VSS_184) UH1.J40(VSS_186) UH1.J46(VSS_187) UH1.J47(VSS_188) UH1.J48(VSS_189) UH1.K11(VSS_191) UH1.K39(VSS_192) UH1.M5(VSS_200) UH1.M16(VSS_193) UH1.M18(VSS_194) UH1.M21(VSS_195) UH1.M24(VSS_196) UH1.M32(VSS_197) UH1.M34(VSS_198) UH1.M49(VSS_199) UH1.N12(VSS_201) UH1.N16(VSS_202) UH1.N34(VSS_203) UH1.N35(VSS_204) UH1.N37(VSS_205) UH1.N38(VSS_206) UH1.P4(VSS_209) UH1.P26(VSS_207) UH1.P29(VSS_208) UH1.P46(VSS_210) UH1.R3(VSS_215) UH1.R4(VSS_218) UH1.R12(VSS_211) UH1.R16(VSS_212) UH1.R26(VSS_213) UH1.R29(VSS_214) UH1.R34(VSS_216) UH1.R38(VSS_217) UH1.T4(VSS_222) UH1.T5(VSS_224) UH1.T7(VSS_225) UH1.T17(VSS_219) UH1.T18(VSS_220) UH1.T32(VSS_221) UH1.T49(VSS_223) UH1.U12(VSS_226) UH1.U15(VSS_227) UH1.U17(VSS_228) UH1.U21(VSS_229) UH1.U24(VSS_230) UH1.U33(VSS_231) UH1.U38(VSS_232) UH1.V4(VSS_235) UH1.V20(VSS_233) UH1.V22(VSS_234) UH1.V46(VSS_236) UH1.W25(VSS_237) UH1.W27(VSS_238) UH1.W28(VSS_239) UH1.W30(VSS_240) UH1.Y9(VSS_246) UH1.Y10(VSS_241) UH1.Y12(VSS_242) UH1.Y17(VSS_243) UH1.Y33(VSS_244) UH1.Y38(VSS_245) UH7.3(G) UI1.2(GND) UI2.2(GND) UI3.14(GND) UI3.17(THERMAL PAD) UI6.10(GND1) UI6.21(GND2) UI6.25(GPAD) UL1.49(VSS_EPAD) UN7.3(TDET_B#) UN7.21(GND) UR1.33(E-PAD) UT1.A1(SVR_VSS#A1) UT1.A6(VSS_ANA#A6) UT1.A8(VSS_ANA#A8) UT1.A10(VSS_ANA#A10) UT1.A12(VSS_ANA#A12) UT1.A14(VSS_ANA#A14) UT1.A16(VSS_ANA#A16) UT1.A18(VSS_ANA#A18) UT1.A20(VSS_ANA#A20) UT1.A22(VSS_ANA#A22) UT1.AA22(VSS_ANA#AA22) UT1.AA23(VSS_ANA#AA23) UT1.AB1(VSS#AB1) UT1.AB2(MONDC_DPSRC) UT1.AB6(VSS_ANA#AB6) UT1.AB8(VSS_ANA#AB8) UT1.AB10(VSS_ANA#AB10) UT1.AB12(VSS_ANA#AB12) UT1.AB14(VSS_ANA#AB14) UT1.AB16(VSS_ANA#AB16) UT1.AB18(VSS_ANA#AB18) UT1.AB20(VSS_ANA#AB20) UT1.AB22(VSS_ANA#AB22) UT1.AC1(TEST_EDM) UT1.AC2(VSS#AC2) UT1.AC6(VSS_ANA#AC6) UT1.AC8(VSS_ANA#AC8) UT1.AC10(VSS_ANA#AC10) UT1.AC12(VSS_ANA#AC12) UT1.AC14(VSS_ANA#AC14) UT1.AC16(VSS_ANA#AC16) UT1.AC18(VSS_ANA#AC18) UT1.AC20(VSS_ANA#AC20) UT1.AC22(VSS_ANA#AC22) UT1.B1(SVR_VSS#B1) UT1.B2(SVR_VSS#B2) UT1.B6(VSS_ANA#B6) UT1.B8(VSS_ANA#B8) UT1.B10(VSS_ANA#B10) UT1.B12(VSS_ANA#B12) UT1.B14(VSS_ANA#B14) UT1.B16(VSS_ANA#B16) UT1.B18(VSS_ANA#B18) UT1.B20(VSS_ANA#B20) UT1.B22(VSS_ANA#B22) UT1.C22(MONDC_CIO_1) UT1.C23(MONDC_CIO_0) UT1.D5(VSS#D5) UT1.D6(MONDC_SVR) UT1.D8(VSS_ANA#D8) UT1.D9(VSS_ANA#D9) UT1.D11(VSS_ANA#D11) UT1.D12(VSS_ANA#D12) UT1.D13(VSS_ANA#D13) UT1.D15(VSS_ANA#D15) UT1.D16(VSS_ANA#D16) UT1.D18(VSS_ANA#D18) UT1.E4(VSS#E4) UT1.E5(VSS#E5) UT1.E6(VSS#E6) UT1.E8(VSS_ANA#E8) UT1.E9(VSS_ANA#E9) UT1.E11(VSS_ANA#E11) UT1.E15(VSS_ANA#E15) UT1.E16(VSS_ANA#E16) UT1.E22(VSS_ANA#E22) UT1.E23(VSS_ANA#E23) UT1.F5(VSS#F5) UT1.F6(VSS#F6) UT1.F9(VSS_ANA#F9) UT1.F16(VSS_ANA#F16) UT1.F20(VSS_ANA#F20) UT1.G22(VSS_ANA#G22) UT1.G23(VSS_ANA#G23) UT1.H1(VSS_ANA#H1) UT1.H2(VSS_ANA#H2) UT1.H5(VSS#H5) UT1.H8(VSS#H8) UT1.H12(VSS_ANA#H12) UT1.H13(VSS_ANA#H13) UT1.H15(VSS_ANA#H15) UT1.H16(VSS_ANA#H16) UT1.H20(VSS_ANA#H20) UT1.J5(VSS_ANA#J5) UT1.J8(VSS#J8) UT1.J12(VSS#J12) UT1.J13(VSS#J13) UT1.J15(VSS#J15) UT1.J18(VSS_ANA#J18) UT1.J19(VSS_ANA#J19) UT1.J20(VSS_ANA#J20) UT1.J22(VSS_ANA#J22) UT1.J23(VSS_ANA#J23) UT1.K1(VSS_ANA#K1) UT1.K2(VSS_ANA#K2) UT1.L5(VSS_ANA#L5) UT1.L13(VSS#L13) UT1.L15(FUSE_VQPS_64) UT1.L20(VSS_ANA#L20) UT1.L22(VSS_ANA#L22) UT1.L23(VSS_ANA#L23) UT1.M1(VSS_ANA#M1) UT1.M2(VSS_ANA#M2) UT1.M5(VSS_ANA#M5) UT1.M11(VSS#M11) UT1.M12(VSS#M12) UT1.M19(VSS_ANA#M19) UT1.M20(VSS_ANA#M20) UT1.N5(VSS_ANA#N5) UT1.N8(VSS#N8) UT1.N9(VSS#N9) UT1.N11(VSS#N11) UT1.N12(VSS#N12) UT1.N13(VSS#N13) UT1.N15(FUSE_VQPS_128) UT1.N20(VSS_ANA#N20) UT1.N22(VSS_ANA#N22) UT1.N23(VSS_ANA#N23) UT1.P1(VSS_ANA#P1) UT1.P2(VSS_ANA#P2) UT1.R5(VSS_ANA#R5) UT1.R18(VSS_ANA#R18) UT1.R19(VSS_ANA#R19) UT1.R20(VSS_ANA#R20) UT1.R22(VSS_ANA#R22) UT1.R23(VSS_ANA#R23) UT1.T1(VSS_ANA#T1) UT1.T2(VSS_ANA#T2) UT1.T5(VSS_ANA#T5) UT1.T6(VSS#T6) UT1.T8(VSS#T8) UT1.T9(VSS#T9) UT1.T13(VSS#T13) UT1.T15(VSS#T15) UT1.T16(VSS#T16) UT1.T18(VSS#T18) UT1.T20(VSS_ANA#T20) UT1.U22(VSS_ANA#U22) UT1.U23(VSS_ANA#U23) UT1.V5(VSS_ANA#V5) UT1.V6(VSS_ANA#V6) UT1.V8(VSS_ANA#V8) UT1.V9(VSS_ANA#V9) UT1.V15(VSS_ANA#V15) UT1.V16(VSS_ANA#V16) UT1.V20(VSS_ANA#V20) UT1.W5(VSS_ANA#W5) UT1.W6(VSS_ANA#W6) UT1.W8(VSS_ANA#W8) UT1.W9(VSS_ANA#W9) UT1.W13(MONDC_DPSNK_0) UT1.W18(MONDC_DPSNK_1) UT1.W20(VSS_ANA#W20) UT1.W22(VSS_ANA#W22) UT1.W23(VSS_ANA#W23) UT1.Y9(VSS_ANA#Y9) UT1.Y13(VSS_ANA#Y13) UT1.Y20(VSS_ANA#Y20) UT2.4(GND) UT5.A1(GND1) UT5.A6(GND21) UT5.A7(GND22) UT5.A8(GND23) UT5.B7(GND24) UT5.B8(GND9) UT5.D8(GND10) UT5.E5(GND2) UT5.E6(GND3) UT5.E7(GND4) UT5.E8(GND11) UT5.F5(GND5) UT5.F6(GND12) UT5.F7(GND13) UT5.F8(GND14) UT5.G5(GND6) UT5.G6(GND15) UT5.G7(GND16) UT5.G8(GND17) UT5.H4(GND7) UT5.H5(GND8) UT5.H8(GND18) UT5.L1(GND19) UT6.4(GND) UT7.2(GND) UT8.2(GND) UT32.2(GND) UT34.3(G) UV2.2(GND) UV24.2(GND) UV31.B3(GND3) UV31.B6(GND8) UV31.D4(GND7) UV31.D5(GND6) UV31.E4(GND5) UV31.E5(GND2) UV31.G3(GND4) UV31.G6(GND1) UV32.4(GND) UZ2.11(GND) UZ2.15(GPAD) UZ3.11(GND) UZ3.15(GPAD) UZ4.11(GND) UZ4.15(GPAD) UZ6.3(G) UZ8.5(GND1) UZ8.9(GND2) UZ10.3(G) UZ12.2(GND0) UZ12.9(NC_6) UZ12.16(NIC_13) UZ12.23(NIC_14) UZ12.32(NIC_22) UZ12.33(THPAD) UZ19.5(GND) UZ21.5(GND) UZ23.5(GND1) UZ23.9(GND2) UZ26.5(GND) UZ29.5(GND1) UZ29.11(GND2) UZ29.20(GND3) UZ29.21(PGND) UZ34.3(G) UZ35.3(G) UZ51.2(GND) UZ52.B1(GND) UZ52.C1(A) UZ53.5(GND1) UZ53.9(GND2) UZ54.3(G) UZ61.3(GND) YH2.2(GND2) YH2.4(GND4) YL1.2(NC1) YL1.4(NC2) YT1.2(GND1) YT1.4(GND2)
GNDA: CA1.2 CA2.1 CA3.1 CA4.2 CA8.2 CA9.2 CA25.2 CA35.2 CA41.2 CA51.2 CA52.2 CA57.2 CA58.2 CA77.2 CA78.2 DA2.2 JHP1.5(#5) JHP1.7(GND) PJP19.1 RA35.1 RA36.1 RA37.1 RA44.2 UA1.19(AVSS1) UA1.31(AVSS2)
VBAT1_CHG: PC755.1 PR738.1 PU700.31(VBAT)
VBUS1_ECOK: PR20.2 PR24.1 PR826.1 PR861.2 UE1.N3(GPIO021/LPCPD#)
VBUS2_ECOK: PR49.2 PR816.1 PR819.1 PR827.1 UE1.M6(GPIO016/GPTP-IN7/SHD_IO3/ICT3)
VCC1_IA: PCH23.1 PRH1.2 PUH1.3(VCC)
VCC2_IA: PCH48.1 PRH11.2 PUH2.3(VCC)
VCC3_IA: PCH21.1 PRH2.2 PUH3.3(VCC)
VCC4_IA: PCH44.1 PRH9.2 PUH4.3(VCC)
VCC_1.05VALWP: PC313.1 PC316.1 PU301.16(NC3) PU301.17(VCC)
VCC_CPU: PCZ34.1 PRZ61.2 PUZ1.16(VCC)
VCC_DDR: PC207.1 PU200.14(VCC)
VCC_GT: PCT11.1 PRT1.2 PUT1.3(VCC)
VCC_SA: PCA8.1 PRA1.2 PUA1.3(VCC)
VCC_SENSE_GT: PRZ29.2 PRZ30.1 UC1.AH38(VCCGT_SENSE)
VCC_SENSE_IA: PRZ27.1 RC140.2 RC221.2 UC1.AG37(VCC_SENSE)
VCC_SENSE_SA: PRZ13.1 PRZ17.2 UC1.M38(VCCSA_SENSE)
VCCDSW_EN: CE66.1 RH445.1 UE1.M7(GPIO012/SMB07_DATA/TOUT3)
VCCDSW_EN_GPIO: DH1.2 QH6.2(G) RH431.1 RH445.2
VCCDSW_EN_Q: DH1.1 DH2.2 RH442.1
VCCIO_SENSE: PR422.2 UC1.H14(VCCIO_SENSE)
VCCMPHY_SENSE: PR1651.1 T76.1 UH1.K47(VCCMPHY_SENSE)
VCCST_PWRGD: CC301.1 RC71.2 RC78.1 UE4.4(Y)
VCCST_PWRGD_CPU: RC78.2 UC1.H13(VCCST_PWRGD)
VCCSTG_EN: RZ120.1 RZ320.2 UZ19.4(ON) UZ35.4(O)
VDD_CHG: PC739.2 PR707.2 PR710.2 PR712.1 PU700.18(VDD)
VDDP_CHG: PC738.1 PR707.1 PU700.8(VDDP)
VIN_1.2V_RUN: PC507.1 PC508.1 PJP503.1 PU502.8(IN)
VIN_1.8VALW: PC530.2 PJP501.2 PU501.4(IN)
VIN_1VS_VCCIO: PC403.1 PC404.1 PC408.1 PC409.1 PC410.1 PC411.1 PJP403.2 PU401.10(SVIN) PU401.11(PVIN1) PU401.12(PVIN2)
VIN_2.5V_MEM: PC514.1 PC517.1 PJP505.2 PU503.8(IN)
VSS_A36: RC178.1 UC1.A36(VSS_A36)
VSS_A37: RC179.1 UC1.A37(VSS_A37)
VSS_SENSE_GT: PRZ38.1 PRZ39.1 UC1.AH37(VSSGT_SENSE)
VSS_SENSE_IA: PRZ31.1 RC141.1 RC221.1 UC1.AG38(VSS_SENSE)
VSS_SENSE_SA: PRZ1.1 PRZ11.1 UC1.M37(VSSSA_SENSE)
VSSIO_SENSE: PR412.2 UC1.J14(VSSIO_SENSE)
VSSMPHY_SENSE: PR1649.1 T77.1 UH1.K46(VSSMPHY_SENSE)
32KHZ_OUT: CE54.1 UE1.F3(GPIO221/GPTP-IN3/32KHZ_OUT)
+BL_PWR_SRC: CV11.1 CV24.1 CV25.1 CV634.1 DV11.2 FZ2.2 JEDP1.17 JEDP1.18 JEDP1.19
+BL_PWR_SRC_P: CV15.1 FZ2.1 QV1.1(D1) QV1.2(D2) QV1.5(D5) QV1.6(D6)
+COINCELL: JRTC1.1 PC2.2 PR2.1
+DDR_VREF_A_CA: CD25.1 CD26.1 JDIMM1.164(VREFCA) RD15.2 RD16.1 RD17.1
+DDR_VREF_B_CA: CD57.1 CD58.1 JDIMM2.164(VREFCA) RD28.2 RD29.1 RD30.1
+DDR_VREF_B_DQ: CD62.1 RD30.2 UC1.BR13(DDR1_VREF_DQ)
+DDR_VREF_CA: CD31.1 RD17.2 UC1.BN13(DDR_VREF_CA)
+EC_DEBUG_VCC: JDEG1.1 RE71.2
+EDP_VDD: PJP12.2 UV24.1(VOUT)
+GT_CORE: PC848.1(P) PC849.1(P) PC1010.1 PC1023.1 PC1024.1 PC1025.1 PC1026.1 PC1027.1 PC1028.1 PC1029.1 PC1030.1 PC1088.1 PC1089.1 PC1090.1 PC1091.1 PC1092.1 PC1093.1 PC1094.1 PC1095.1 PC1096.1 PC1097.1 PC1098.1 PC1099.1 PC2027.1 PC2028.1 PC2029.1 PC2031.1 PC2033.1 PC2034.1 PC2037.1 PC2038.1 PC2039.1 PC2040.1 PC2042.1 PC2043.1 PC2044.1 PC2045.1 PC2046.1 PC2047.1 PC2048.1 PC2050.1 PC2051.1 PC2052.1 PC2053.1 PC2055.1 PC2056.1 PC2057.1 PC2058.1 PLT1.4 PRZ29.1 UC1.AT14(VCCGT1) UC1.AT31(VCCGT2) UC1.AT32(VCCGT3) UC1.AT33(VCCGT4) UC1.AT34(VCCGT5) UC1.AT35(VCCGT6) UC1.AT36(VCCGT7) UC1.AT37(VCCGT8) UC1.AT38(VCCGT9) UC1.AU14(VCCGT10) UC1.AU29(VCCGT11) UC1.AU30(VCCGT12) UC1.AU31(VCCGT13) UC1.AU32(VCCGT14) UC1.AU35(VCCGT15) UC1.AU36(VCCGT16) UC1.AU37(VCCGT17) UC1.AU38(VCCGT18) UC1.AV29(VCCGT19) UC1.AV30(VCCGT20) UC1.AV31(VCCGT21) UC1.AV32(VCCGT22) UC1.AV33(VCCGT23) UC1.AV34(VCCGT24) UC1.AV35(VCCGT25) UC1.AV36(VCCGT26) UC1.AW14(VCCGT27) UC1.AW31(VCCGT28) UC1.AW32(VCCGT29) UC1.AW33(VCCGT30) UC1.AW34(VCCGT31) UC1.AW35(VCCGT32) UC1.AW36(VCCGT33) UC1.AW37(VCCGT34) UC1.AW38(VCCGT35) UC1.AY29(VCCGT36) UC1.AY30(VCCGT37) UC1.AY31(VCCGT38) UC1.AY32(VCCGT39) UC1.AY35(VCCGT40) UC1.AY36(VCCGT41) UC1.AY37(VCCGT42) UC1.AY38(VCCGT43) UC1.BA13(VCCGT44) UC1.BA14(VCCGT45) UC1.BA29(VCCGT46) UC1.BA30(VCCGT47) UC1.BA31(VCCGT48) UC1.BA32(VCCGT49) UC1.BA33(VCCGT50) UC1.BA34(VCCGT51) UC1.BA35(VCCGT52) UC1.BA36(VCCGT53) UC1.BB13(VCCGT54) UC1.BB14(VCCGT55) UC1.BB31(VCCGT56) UC1.BB32(VCCGT57) UC1.BB33(VCCGT58) UC1.BB34(VCCGT59) UC1.BB35(VCCGT60) UC1.BB36(VCCGT61) UC1.BB37(VCCGT62) UC1.BB38(VCCGT63) UC1.BC29(VCCGT64) UC1.BC30(VCCGT65) UC1.BC31(VCCGT66) UC1.BC32(VCCGT67) UC1.BC35(VCCGT68) UC1.BC36(VCCGT69) UC1.BC37(VCCGT70) UC1.BC38(VCCGT71) UC1.BD13(VCCGT72) UC1.BD14(VCCGT73) UC1.BD29(VCCGT74) UC1.BD30(VCCGT75) UC1.BD31(VCCGT76) UC1.BD32(VCCGT77) UC1.BD33(VCCGT78) UC1.BD34(VCCGT79) UC1.BD35(VCCGT80) UC1.BD36(VCCGT81) UC1.BE31(VCCGT82) UC1.BE32(VCCGT83) UC1.BE33(VCCGT84) UC1.BE34(VCCGT85) UC1.BE35(VCCGT86) UC1.BE36(VCCGT87) UC1.BE37(VCCGT88) UC1.BE38(VCCGT89) UC1.BF13(VCCGT90) UC1.BF14(VCCGT91) UC1.BF29(VCCGT92) UC1.BF30(VCCGT93) UC1.BF31(VCCGT94) UC1.BF32(VCCGT95) UC1.BF35(VCCGT96) UC1.BF36(VCCGT97) UC1.BF37(VCCGT98) UC1.BF38(VCCGT99) UC1.BG29(VCCGT100) UC1.BG30(VCCGT101) UC1.BG31(VCCGT102) UC1.BG32(VCCGT103) UC1.BG33(VCCGT104) UC1.BG34(VCCGT105) UC1.BG35(VCCGT106) UC1.BG36(VCCGT107) UC1.BH33(VCCGT108) UC1.BH34(VCCGT109) UC1.BH35(VCCGT110) UC1.BH36(VCCGT111) UC1.BH37(VCCGT112) UC1.BH38(VCCGT113) UC1.BJ16(VCCGT114) UC1.BJ17(VCCGT115) UC1.BJ19(VCCGT116) UC1.BJ20(VCCGT117) UC1.BJ21(VCCGT118) UC1.BJ23(VCCGT119) UC1.BJ24(VCCGT120) UC1.BJ26(VCCGT121) UC1.BJ27(VCCGT122) UC1.BJ37(VCCGT123) UC1.BJ38(VCCGT124) UC1.BK16(VCCGT125) UC1.BK17(VCCGT126) UC1.BK19(VCCGT127) UC1.BK20(VCCGT128) UC1.BK21(VCCGT129) UC1.BK23(VCCGT130) UC1.BK24(VCCGT131) UC1.BK26(VCCGT132) UC1.BK27(VCCGT133) UC1.BL15(VCCGT134) UC1.BL16(VCCGT135) UC1.BL17(VCCGT136) UC1.BL23(VCCGT137) UC1.BL24(VCCGT138) UC1.BL25(VCCGT139) UC1.BL26(VCCGT140) UC1.BL27(VCCGT141) UC1.BL28(VCCGT142) UC1.BL36(VCCGT143) UC1.BL37(VCCGT144) UC1.BM15(VCCGT145) UC1.BM16(VCCGT146) UC1.BM17(VCCGT147) UC1.BM36(VCCGT148) UC1.BM37(VCCGT149) UC1.BN15(VCCGT150) UC1.BN16(VCCGT151) UC1.BN17(VCCGT152) UC1.BN36(VCCGT153) UC1.BN37(VCCGT154) UC1.BN38(VCCGT155) UC1.BP15(VCCGT156) UC1.BP16(VCCGT157) UC1.BP17(VCCGT158) UC1.BP37(VCCGT159) UC1.BP38(VCCGT160) UC1.BR15(VCCGT161) UC1.BR16(VCCGT162) UC1.BR17(VCCGT163) UC1.BR37(VCCGT164) UC1.BT15(VCCGT165) UC1.BT16(VCCGT166) UC1.BT17(VCCGT167) UC1.BT37(VCCGT168)
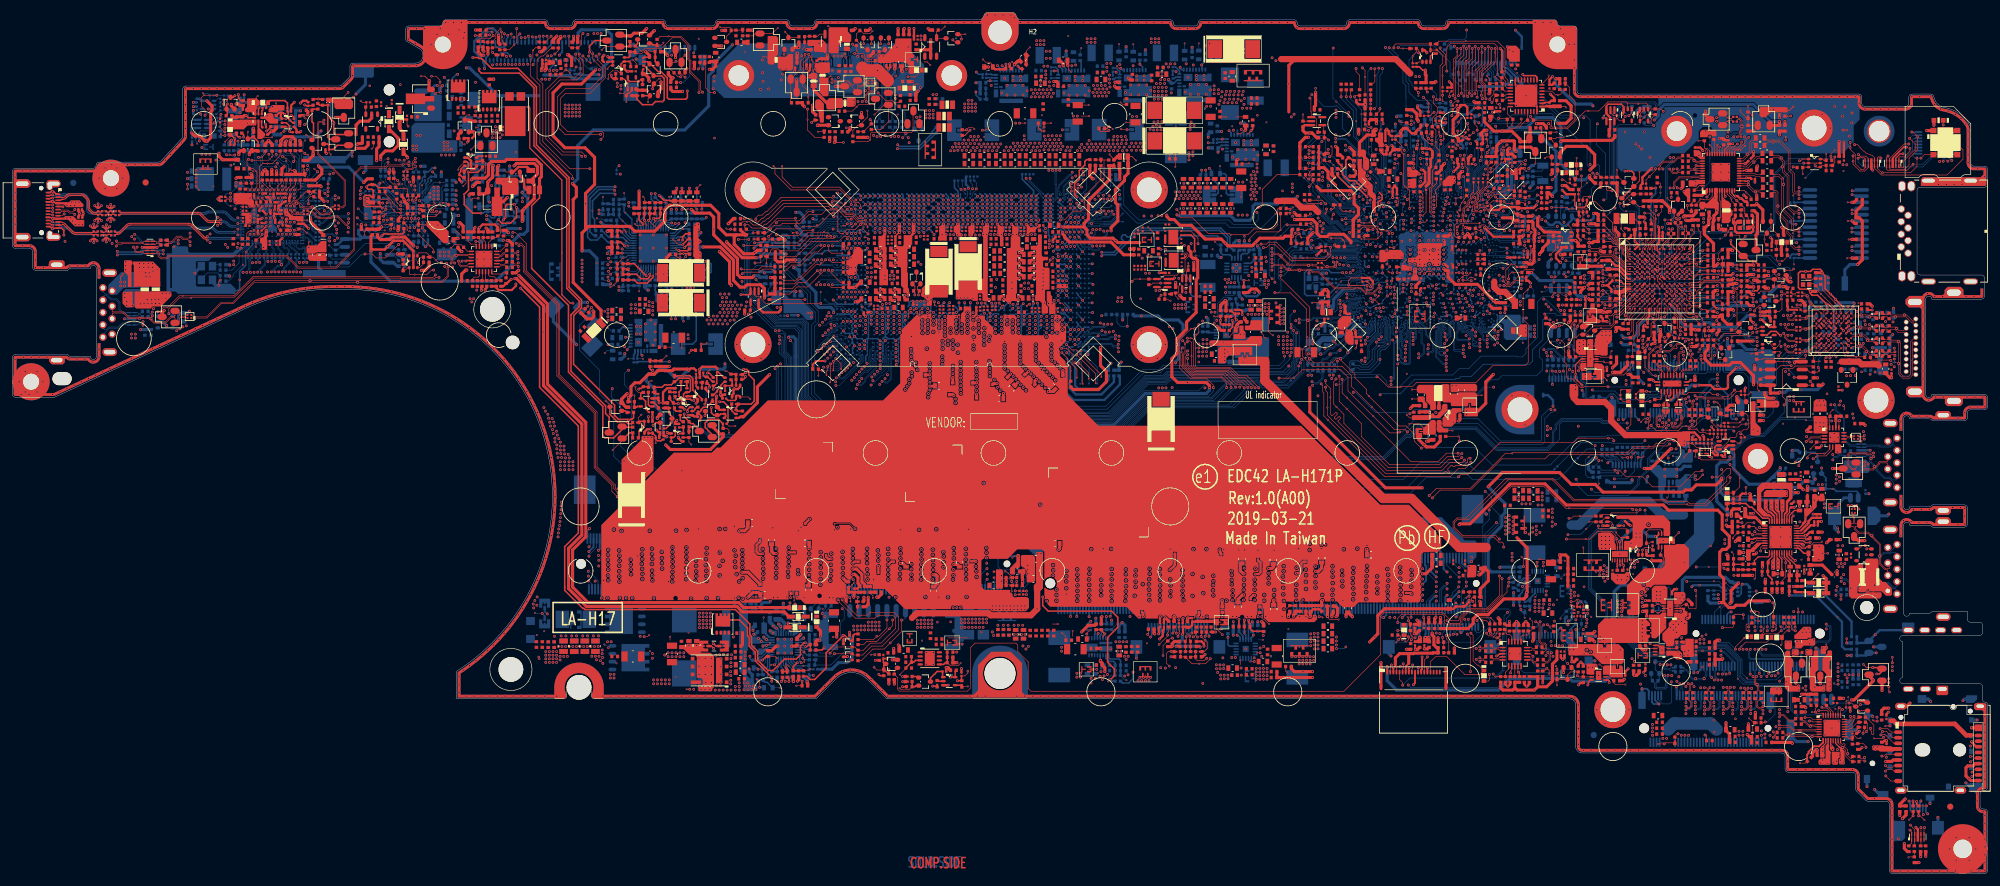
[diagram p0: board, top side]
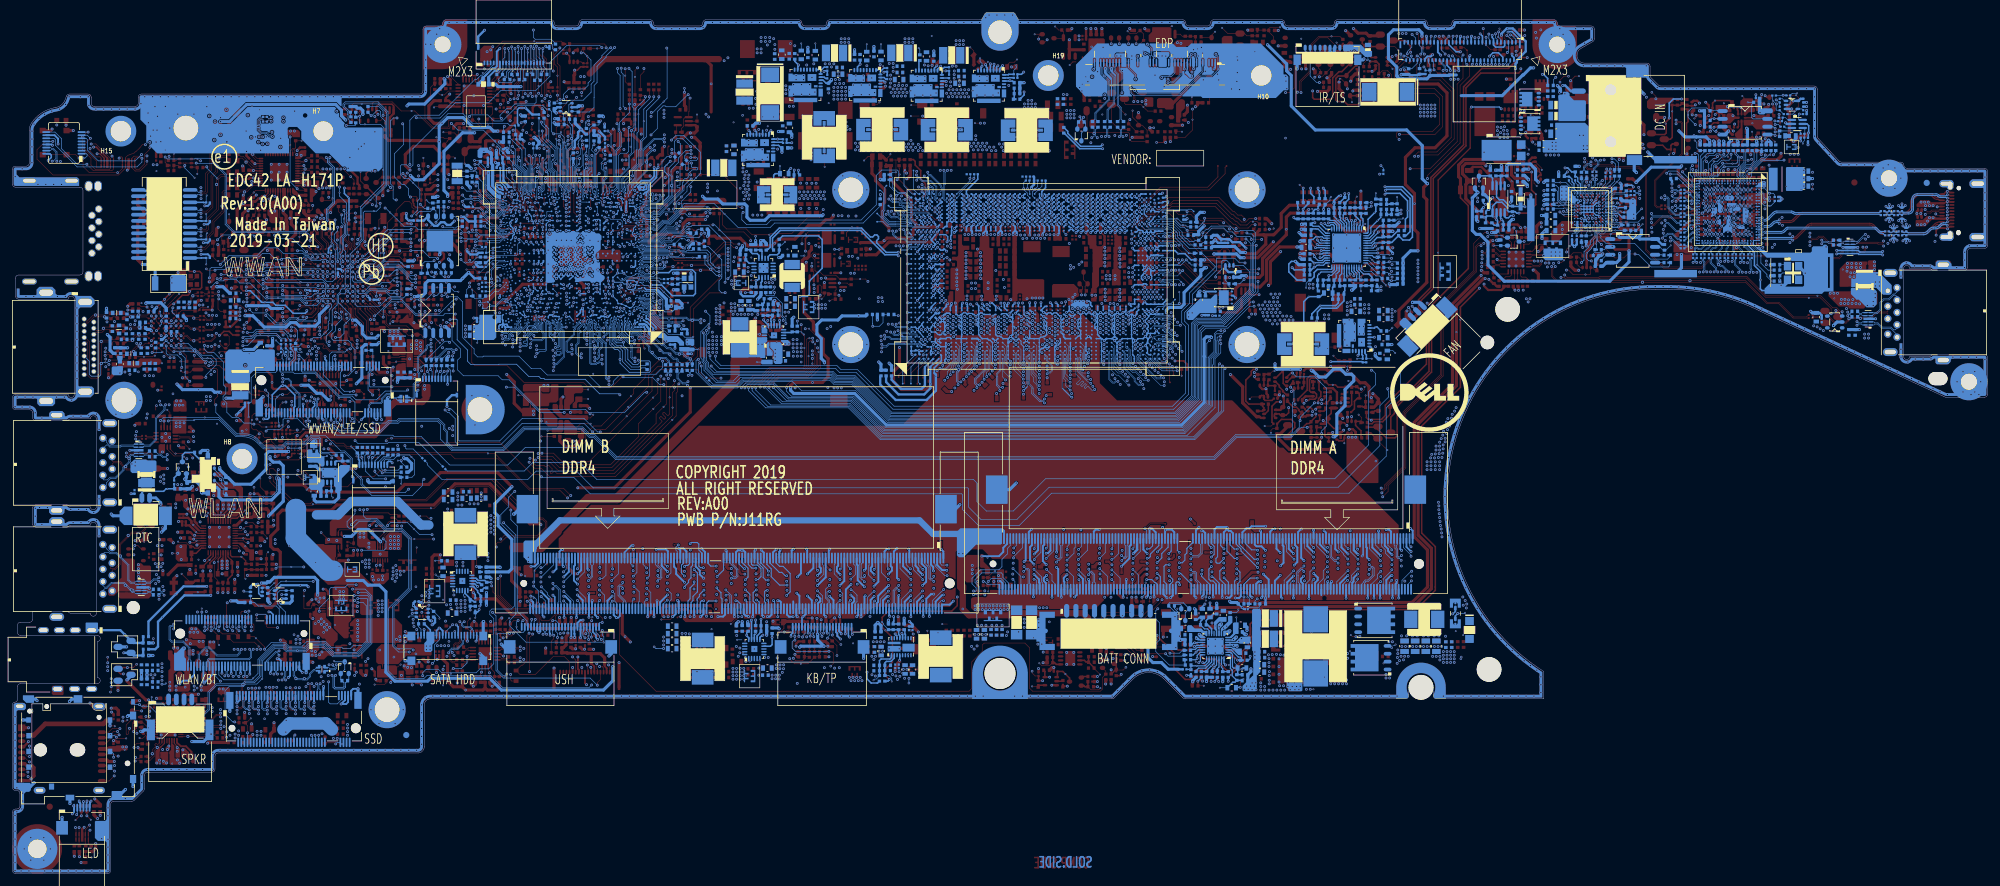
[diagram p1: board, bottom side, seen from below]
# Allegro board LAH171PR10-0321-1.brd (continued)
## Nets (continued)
+IA_CORE: PC1000.1 PC1001.1 PC1002.1 PC1003.1 PC1004.1 PC1005.1 PC1006.1 PC1007.1 PC1008.1 PC1009.1 PC1011.1 PC1012.1 PC1013.1 PC1014.1 PC1015.1 PC1016.1 PC1017.1 PC1018.1 PC1019.1 PC1020.1 PC1031.1 PC1032.1 PC1033.1 PC1034.1 PC1035.1 PC1036.1 PC1037.1 PC1038.1 PC1039.1 PC1040.1 PC1041.1 PC1042.1 PC1043.1 PC1044.1 PC1045.1 PC1046.1 PC1047.1 PC1048.1 PC1049.1 PC1050.1 PC1051.1 PC1052.1 PC1053.1 PC1054.1 PC1055.1 PC1056.1 PC1057.1 PC1058.1 PC1059.1 PC1060.1 PC1061.1 PC1062.1 PC1063.1 PC1064.1 PC1065.1 PC1066.1 PC1067.1 PC1068.1 PC1069.1 PC1070.1 PC1071.1 PC1072.1 PC1073.1 PC1074.1 PC1075.1 PC1076.1 PC1077.1 PC1079.1 PC1080.1 PC1081.1 PC1082.1 PC1083.1 PC1084.1 PC1085.1 PC1086.1 PC1087.1 PC1171.1 PC1629.1 PC1634.1 PC1635.1 PC1636.1 PC1637.1 PC1638.1 PC1639.1 PC1640.1 PC1641.1 PC1642.1 PC1643.1 PC1644.1 PC1645.1 PC1646.1 PC1647.1 PC1648.1 PC1649.1 PC1650.1 PC1651.1 PC1652.1 PC1653.1 PC1654.1 PC1675.1 PC2060.1(P) PC2061.1(P) PC2073.1 PC2074.1 PC2075.1 PC2076.1 PC2077.1 PC2078.1 PC2079.1 PC2080.1 PC2120.1 PC2121.1 PLH1.4 PLH2.4 PLH3.4 PLH4.4 PR3004.1 RC140.1 UC1.AA13(VCC1) UC1.AA31(VCC2) UC1.AA32(VCC3) UC1.AA33(VCC4) UC1.AA34(VCC5) UC1.AA35(VCC6) UC1.AA36(VCC7) UC1.AA37(VCC8) UC1.AA38(VCC9) UC1.AB29(VCC10) UC1.AB30(VCC11) UC1.AB31(VCC12) UC1.AB32(VCC13) UC1.AB35(VCC14) UC1.AB36(VCC15) UC1.AB37(VCC16) UC1.AB38(VCC17) UC1.AC13(VCC18) UC1.AC14(VCC19) UC1.AC29(VCC20) UC1.AC30(VCC21) UC1.AC31(VCC22) UC1.AC32(VCC23) UC1.AC33(VCC24) UC1.AC34(VCC25) UC1.AC35(VCC26) UC1.AC36(VCC27) UC1.AD13(VCC28) UC1.AD14(VCC29) UC1.AD31(VCC30) UC1.AD32(VCC31) UC1.AD33(VCC32) UC1.AD34(VCC33) UC1.AD35(VCC34) UC1.AD36(VCC35) UC1.AD37(VCC36) UC1.AD38(VCC37) UC1.AE13(VCC38) UC1.AE14(VCC39) UC1.AE30(VCC40) UC1.AE31(VCC41) UC1.AE32(VCC42) UC1.AE35(VCC43) UC1.AE36(VCC44) UC1.AE37(VCC45) UC1.AE38(VCC46) UC1.AF29(VCC47) UC1.AF30(VCC48) UC1.AF31(VCC49) UC1.AF32(VCC50) UC1.AF33(VCC51) UC1.AF34(VCC52) UC1.AF35(VCC53) UC1.AF36(VCC54) UC1.AF37(VCC55) UC1.AF38(VCC56) UC1.AG14(VCC57) UC1.AG31(VCC58) UC1.AG32(VCC59) UC1.AG33(VCC60) UC1.AG34(VCC61) UC1.AG35(VCC62) UC1.AG36(VCC63) UC1.AH13(VCC64) UC1.AH14(VCC65) UC1.AH29(VCC66) UC1.AH30(VCC67) UC1.AH31(VCC68) UC1.AH32(VCC69) UC1.AJ14(VCC70) UC1.AJ29(VCC71) UC1.AJ30(VCC72) UC1.AJ31(VCC73) UC1.AJ32(VCC74) UC1.AJ33(VCC75) UC1.AJ34(VCC76) UC1.AJ35(VCC77) UC1.AJ36(VCC78) UC1.AK31(VCC79) UC1.AK32(VCC80) UC1.AK33(VCC81) UC1.AK34(VCC82) UC1.AK35(VCC83) UC1.AK36(VCC84) UC1.AK37(VCC85) UC1.AK38(VCC86) UC1.AL13(VCC87) UC1.AL29(VCC88) UC1.AL30(VCC89) UC1.AL31(VCC90) UC1.AL32(VCC91) UC1.AL35(VCC92) UC1.AL36(VCC93) UC1.AL37(VCC94) UC1.AL38(VCC95) UC1.AM13(VCC96) UC1.AM14(VCC97) UC1.AM29(VCC98) UC1.AM30(VCC99) UC1.AM31(VCC100) UC1.AM32(VCC101) UC1.AM33(VCC102) UC1.AM34(VCC103) UC1.AM35(VCC104) UC1.AM36(VCC105) UC1.AN13(VCC106) UC1.AN14(VCC107) UC1.AN31(VCC108) UC1.AN32(VCC109) UC1.AN33(VCC110) UC1.AN34(VCC111) UC1.AN35(VCC112) UC1.AN36(VCC113) UC1.AN37(VCC114) UC1.AN38(VCC115) UC1.AP13(VCC116) UC1.AP30(VCC117) UC1.AP31(VCC118) UC1.AP32(VCC119) UC1.AP35(VCC120) UC1.AP36(VCC121) UC1.AP37(VCC122) UC1.AP38(VCC123) UC1.K13(VCC124) UC1.K14(VCC1) UC1.L13(VCC2) UC1.L14(VCC3) UC1.N13(VCC4) UC1.N14(VCC5) UC1.N30(VCC6) UC1.N31(VCC7) UC1.N32(VCC8) UC1.N35(VCC9) UC1.N36(VCC10) UC1.N37(VCC11) UC1.N38(VCC12) UC1.P13(VCC13) UC1.P14(VCC14) UC1.P29(VCC15) UC1.P30(VCC16) UC1.P31(VCC17) UC1.P32(VCC18) UC1.P33(VCC19) UC1.P34(VCC20) UC1.P35(VCC21) UC1.P36(VCC22) UC1.R13(VCC23) UC1.R31(VCC24) UC1.R32(VCC25) UC1.R33(VCC26) UC1.R34(VCC27) UC1.R35(VCC28) UC1.R36(VCC29) UC1.R37(VCC30) UC1.R38(VCC31) UC1.T29(VCC32) UC1.T30(VCC33) UC1.T31(VCC34) UC1.T32(VCC35) UC1.T35(VCC36) UC1.T36(VCC37) UC1.T37(VCC38) UC1.T38(VCC39) UC1.U29(VCC40) UC1.U30(VCC41) UC1.U31(VCC42) UC1.U32(VCC43) UC1.U33(VCC44) UC1.U34(VCC45) UC1.U35(VCC46) UC1.U36(VCC47) UC1.V13(VCC48) UC1.V14(VCC49) UC1.V31(VCC50) UC1.V32(VCC51) UC1.V33(VCC52) UC1.V34(VCC53) UC1.V35(VCC54) UC1.V36(VCC55) UC1.V37(VCC56) UC1.V38(VCC57) UC1.W13(VCC58) UC1.W14(VCC59) UC1.W29(VCC60) UC1.W30(VCC61) UC1.W31(VCC62) UC1.W32(VCC63) UC1.W35(VCC64) UC1.W36(VCC65) UC1.W37(VCC66) UC1.W38(VCC67) UC1.Y29(VCC68) UC1.Y30(VCC69) UC1.Y31(VCC70) UC1.Y32(VCC71) UC1.Y33(VCC72) UC1.Y34(VCC73) UC1.Y35(VCC74) UC1.Y36(VCC75)
+LCDVDD: CV10.1 CV12.1 CV16.1 CV20.1 CV21.1 CV636.1 CV1637.1 DV12.2 JEDP1.30 JEDP1.31 PJP12.1 RV7.2 RV623.1
+LINE1-VREFO-L: DA4.1 RA57.1
+LINE1-VREFO-R: DA5.1 RA58.1
+MIC2-VREFO: RA5.1 RA6.1 UA1.23(MIC2-VREFO)
+PECI_VREF: CE25.1 RE59.2 UE1.J11(GPIO044/VREF_VTT)
+REGCTL_PNP10: LL1.1 UL1.7(CTRL0P9)
+RREF: RR4.1 UR1.9(RREF)
+RSVD_VCC3P3_1: RL6.1 UL1.1(RSVD_VCC3P3_1)
+RTC_CELL: PC3.1 PD3.1 QE15.3(S) RA54.2 RE31.1 RE32.2 RE324.2 RE507.2 RE508.2 RE551.2
+RTC_CELL_PCH: CE63.1 QE15.1(D) RE546.1 RE551.1 RH198.1 RH200.1 RH201.1 RH297.1
+RTC_CELL_VBAT: CE11.1 RE32.1 UE1.A2(VBAT)
+SA_CORE: PC815.1 PC816.1 PC817.1 PC818.1 PC834.1 PC835.1 PC836.1 PC837.1 PC838.1 PC839.1 PC840.1 PC841.1 PC842.1 PC843.1 PC844.1 PC2030.1 PC2032.1 PC2035.1 PC2036.1 PC2041.1 PC2049.1 PC2054.1 PC2208.1 PLA1.4 PRZ17.1 UC1.J30(VCCSA1) UC1.K29(VCCSA2) UC1.K30(VCCSA3) UC1.K31(VCCSA4) UC1.K32(VCCSA5) UC1.K33(VCCSA6) UC1.K34(VCCSA7) UC1.K35(VCCSA8) UC1.L31(VCCSA9) UC1.L32(VCCSA10) UC1.L35(VCCSA11) UC1.L36(VCCSA12) UC1.L37(VCCSA13) UC1.L38(VCCSA14) UC1.M29(VCCSA15) UC1.M30(VCCSA16) UC1.M31(VCCSA17) UC1.M32(VCCSA18) UC1.M33(VCCSA19) UC1.M34(VCCSA20) UC1.M35(VCCSA21) UC1.M36(VCCSA22)
+SDREG2: CR15.1 UR1.24(SDREG2)
+SIM_PWR: CZ37.1 CZ41.1 JNGFF2.36(UIM_PWR) JSIM1.C1(VCC) RZ335.1
+TBT_SVR_IND: LT1.1 UT1.C1(SVR_IND#C1) UT1.C2(SVR_IND#C2) UT1.D1(SVR_IND#D1)
+TBTA_LDO_BMC: CT71.1 UT5.E1(LDO_BMC)
+TS_PWR: CV18.1 CV19.1 CZ2.1 FV1.1 JEDP1.1
+TS_PWR_QV8: FV1.2 QV8.1(D)
+USB_EX2_PWR: CI1.1 CI3.1 CI45.1 CI46.1 CI103.1 JUSB2.1(VBUS) UI1.1(OUT)
+USB_EX3_PWR: CI8.1 CI10.1 CI47.1 CI48.1 CI104.1 JUSB3.1(VBUS) UI2.1(OUT)
+UZ12_TPM: CZ50.1 CZ75.1 RZ89.2 UZ12.8(NIC_5)
+VHDMI_VCC: CV40.1 CV41.1 JHDMI1.18(+5V) RV22.2 RV23.2 UV2.3(OUT)
+VR_CAP: CE31.1 UE1.C10(VIN) UE1.J1(VR_CAP)
+Z4012: PD3.2 PQ13.2(GATE) PR2.2 PR9.1
AC1_DISC#: PR736.1 PR1652.1 RT72.2
AC1_DISC#_R: RT72.1 UT5.G11(GPIO3)
AC_DIS: PQ703.2(G) PR720.1 RE83.1 UE1.H12(GPIO134/PWM10/UART1_RTS#)
AC_DISC#: PC810.1 PQ810.3(D) PQ810.6(D) PQ811.6(D) PR828.2 PR829.1 UE1.E13(GPIO124/GPTP-OUT6/PVT_CS#)
AC_PRESENT: RH243.1 UE1.K8(GPIO233) UH1.BG42(GPD1/ACPRESENT)
ACAV_IN: DZ12.1 PR740.2 PR744.1 PR3010.2 UE1.C7(GPIO164/VCI_OVRD_IN)
ACAV_IN1: PQ703.1(D) PR710.1 PR716.1 PR722.1 PR741.1 PR3009.2
ACIN_CHG: PC736.1 PR705.2 PR706.1 PR3001.2 PU700.19(ACIN)
ACOK_CHG: PR722.2 PU700.24(ACOK)
ADJ_1.2V_RUN: PC509.2 PR510.1 PR512.2 PU502.3(ADJ/NC)
ADJ_2.5V_MEM: PC515.2 PR515.2 PR516.1 PU503.3(ADJ/NC)
ADP_CHG: PR703.2 PU700.16(ADP)
ALW_PWRGD_3V_5V: DH2.1 PR119.2 PR120.2 UZ6.2(A)
ALWON: PR114.1 UE1.A5(VCI_OUT)
AMON/BMON_CHG: PC750.1 PR729.1 PR743.1 PU700.29(AMON/BMON)
AR_DET#: RH400.1 RH401.1 UH1.BB16(GPP_D11/ISH_SPI_MISO/GP_BSSB_CL)
AR_DP1_CTRL_CLK: RT13.1 RT125.1 UT1.Y2(GPIO_7)
AR_DP1_CTRL_DATA: RT12.1 RT124.1 UT1.Y1(GPIO_6)
AUD_AZACPU_SCLK: RH38.1 UC1.G27(PROC_AUDIO_CLK)
AUD_AZACPU_SCLK_R: RH38.2 UH1.AM3(HDACPU_SCLK)
AUD_AZACPU_SDI: RC66.1 UC1.G29(PROC_AUDIO_SDO)
AUD_AZACPU_SDI_R: RC66.2 UH1.AN3(HDACPU_SDI)
AUD_AZACPU_SDO: RH39.1 UC1.G25(PROC_AUDIO_SDI)
AUD_AZACPU_SDO_R: RH39.2 UH1.AM2(HDACPU_SDO)
AUD_HP_NB_SENSE: DA2.3 JHP1.6(#6 AGND) RA60.2
AUD_HP_OUT_L: LA16.1 RA7.2 RA57.2
AUD_HP_OUT_L1: CA2.2 DA1.3 JHP1.1(#1 L) LA16.2
AUD_HP_OUT_R: LA15.1 RA8.2 RA58.2
AUD_HP_OUT_R1: CA3.2 DA1.2 JHP1.2(#2 R) LA15.2
AUD_PC_BEEP: CA27.2 CA28.2 UA1.11(PCBEEP)
AUD_PWR_EN: RH345.2 UH1.BD8(GPP_G6/SD_CLK)
AUD_SENSE_A: CA41.1 RA59.2 RA60.1 UA1.12(HP/LINE1_JD1)
AUX_EN_WOWL: DZ9.2 RZ70.1 RZ379.2 RZ1484.2 UE1.D3(GPIO210/ADC08)
BAT1_LED#: RZ28.1 UE1.D10(GPIO157/LED1)
BAT1_LED#_R: QZ3.2 QZ21.1(COLLECTOR)
BAT2_LED#: RZ361.1 UE1.D11(GPIO153/LED2)
BATGONE_CHG: PC744.1 PR723.1 PR724.2 PU700.25(BATGONE)
BATT_WHITE#: JLED1.4 RZ361.2
BATT_YELLOW#: JLED1.5 QZ3.3 RZ28.2
BBS_BIT6: RH311.2 UH1.BA26(GPP_B22/GSPI1_MOSI)
BC_CLK_ECE1117: CZ87.1 JKBTP1.10 UE1.D13(GPIO047/BCM1_CLK)
BC_DAT_ECE1117: CZ86.1 JKBTP1.8 RE365.1 UE1.D12(GPIO046/BCM1_DAT)
BC_INT#_ECE1117: CZ85.1 JKBTP1.7 UE1.E2(GPIO212/ADC10)
BCM5882_ALERT#: JUSH1.14 RE532.2 UE1.G10(GPIO135/UART1_CTS#)
BEEP: RA13.2 UE1.H11(GPIO035/PWM8/CTOUT1)
BEEP_R: CA28.1 CA62.1 RA13.1 RA45.1
BGATE_CHG: PC743.1 PQ702.4(G) PU700.32(BGATE)
BGPO0_R: RE731.1 UE1.D6(BGPO0)
BIA_PWM: DV1.1 LV1.2 RV1.1
BIA_PWM_EC: DV1.2 UE1.N1(GPIO001/PWM4)
BIA_PWM_PCH: DV1.3 UH1.AU48(GPP_F21/EDP_BKLTCTL)
BIOS_REC: RH76.2 UH1.AR42(GPP_F10/SATA_SCLOCK)
BL_PWR_MONITOR: QV19.2(BASE) RV625.2
BL_PWR_SRC_ON: CV13.1 CV14.1 QV1.3(G) RV4.1 RV5.1
BOARD_ID: CE40.1 RE79.2 UE1.J13(GPIO036/RC_ID2/SPI0_MISO)
BOOT1_CHG: PR704.2 PU700.12(BOOT1)
BOOT2_CHG: PC740.1 PU700.4(BOOT2)
BREATH_LED#: QZ7.4(S2) UE1.C11(GPIO156/LED0)
BREATH_LED#_Q: QZ7.3(D2) RZ32.1
BREATH_WHITE_LED_SNIFF#: LED3.1(CATHODE) RZ32.2
BS_DDR: PR203.1 PU200.12(BS)
BS_DDR_R: PC205.1 PR203.2
BST1_CHG_R: PC727.2 PR704.1
BST1_IA: PRH4.1 PUH1.5(BOOT)
BST1_IA_R: PCH25.1 PRH4.2
BST2_CHG_R: PC740.2 PR714.1
BST2_IA: PRH12.1 PUH2.5(BOOT)
BST2_IA_R: PCH50.1 PRH12.2
BST3_IA: PRH3.1 PUH3.5(BOOT)
BST3_IA_R: PCH22.1 PRH3.2
BST4_IA: PRH10.1 PUH4.5(BOOT)
BST4_IA_R: PCH46.1 PRH10.2
BST_1.05VALWP: PR304.1 PU301.1(BS)
BST_1.05VALWP_R: PC304.1 PR304.2
BST_3V: PR100.1 PU100.1(BS)
BST_3V_R: PC102.1 PR100.2
BST_5V: PR111.1 PU102.1(BS)
BST_5V_R: PC114.1 PR111.2
BST_GT: PRT2.1 PUT1.5(BOOT)
BST_GT_R: PCT12.1 PRT2.2
BST_SA: PRA2.1 PUA1.5(BOOT)
BST_SA_R: PCA10.1 PRA2.2
BT_RADIO_DIS#: DZ2.1 RE11.1 UE1.C2(GPIO166)
BT_RADIO_DIS#_R: DZ2.2 JNGFF1.54(W_DISABLE2#)
C10_PWR_GATE#: RH620.1 RZ542.1 UZ61.4(Y)
C10_PWR_GATE#_R: RH619.2 RH620.2 UZ35.1(IN1)
CAM_MIC_CBL_DET#: JEDP1.14 RH319.2 UH1.AW13(GPP_G0/SD_CMD)
CBN: CA29.2 CA79.2 UA1.28(CBN)
CBP: CA29.1 CA79.1 UA1.30(CBP)
CFG0: JXDP1.9 RC126.1 RC321.1 UC1.BN25(CFG_0)
CFG1: JXDP1.11 RC436.1 UC1.BN27(CFG_1)
CFG2: JXDP1.15 RC181.1 UC1.BN26(CFG_2)
CFG3: JXDP1.17 RC121.2 UC1.BN28(CFG_3)
CFG4: JXDP1.27 RC322.1 UC1.BR20(CFG_4)
CFG5: JXDP1.29 RC323.1 UC1.BM20(CFG_5)
CFG6: JXDP1.33 RC324.1 UC1.BT20(CFG_6)
CFG7: JXDP1.35 RC325.1 UC1.BP20(CFG_7)
CFG8: JXDP1.10 RC437.1 UC1.BR23(CFG_8)
CFG9: JXDP1.12 RC438.1 RC439.1 UC1.BR22(CFG_9)
CFG10: JXDP1.16 RC440.1 UC1.BT23(CFG_10)
CFG11: JXDP1.18 RC441.1 UC1.BT22(CFG_11)
CFG12: JXDP1.28 RC442.1 UC1.BM19(CFG_12)
CFG13: JXDP1.30 RC443.1 UC1.BR19(CFG_13)
CFG14: JXDP1.34 UC1.BP19(CFG_14)
CFG15: JXDP1.36 UC1.BT19(CFG_15)
CFG16: JXDP1.6 UC1.BP23(CFG_16)
CFG17: JXDP1.4 UC1.BN23(CFG_17)
CFG18: JXDP1.24 UC1.BN22(CFG_18)
CFG19: JXDP1.22 UC1.BP22(CFG_19)
CFG_RCOMP: RC114.1 UC1.BT25(CFG_RCOMP)
CHR_USB20_N1: LI7.1 UI3.11(DM_IN)
CHR_USB20_N1_R: DI5.2 JUSB1.2(D-) LI7.2
CHR_USB20_P1: LI7.4 UI3.10(DP_IN)
CHR_USB20_P1_R: DI5.3 JUSB1.3(D+) LI7.3
CLK_CNV_PRX_DTX_N: JNGFF1.21(SDIO_WAKE#) UH1.BD4(CNV_WR_CLKN)
CLK_CNV_PRX_DTX_P: JNGFF1.23(SDIO_RESET#) UH1.BE3(CNV_WR_CLKP)
CLK_CNV_PTX_DRX_N: JNGFF1.71(RESERVED/REFCLKP1) UH1.BC5(CNV_WT_CLKN)
CLK_CNV_PTX_DRX_P: JNGFF1.73(RESERVED/REFCLKN1) UH1.BB6(CNV_WT_CLKP)
CLK_PCIE_N0: JNGFF2.53(REFCLKN) UH1.AJ6(CLKOUT_PCIE_N0)
CLK_PCIE_N1: JNGFF1.49(REFCLKN0) UH1.AH9(CLKOUT_PCIE_N1)
CLK_PCIE_N3: JNGFF3.53(REFCLKN) UH1.AE6(CLKOUT_PCIE_N3)
CLK_PCIE_N4: UH1.AC2(CLKOUT_PCIE_N4) UL1.45(PE_CLKN)
CLK_PCIE_N5: UH1.AB2(CLKOUT_PCIE_N5) UR1.6(REFCLKN)
CLK_PCIE_N6: UH1.W4(CLKOUT_PCIE_N6) UT1.T19(PCIE_REFCLK_100_IN_N)
CLK_PCIE_P0: JNGFF2.55(REFCLKP) UH1.AJ7(CLKOUT_PCIE_P0)
CLK_PCIE_P1: JNGFF1.47(REFCLKP0) UH1.AH10(CLKOUT_PCIE_P1)
CLK_PCIE_P3: JNGFF3.55(REFCLKP) UH1.AE7(CLKOUT_PCIE_P3)
CLK_PCIE_P4: UH1.AC3(CLKOUT_PCIE_P4) UL1.44(PE_CLKP)
CLK_PCIE_P5: UH1.AB3(CLKOUT_PCIE_P5) UR1.5(REFCLKP)
CLK_PCIE_P6: UH1.W3(CLKOUT_PCIE_P6) UT1.V19(PCIE_REFCLK_100_IN_P)
CLK_TP_SIO_I2C_DAT: CZ81.1 RZ23.2 RZ346.2 UE1.E10(GPIO154/SMB02_DATA/PS2_CLK1B)
CLK_TP_SIO_R: CZ89.1 JKBTP1.14 RZ19.2 RZ23.1
CLKDET#: T258.1 UH1.BF35(GPP_A18/ISH_GP0)
CLKREQ_CNV: QZ18.2(G1) RH618.2 UH1.BA17(GPP_D6/I2S2_TXD/MODEM_CLKREQ)
CLKREQ_CNV_R: JNGFF1.14(PCM_OUT/I2S_SD_OUT) QZ18.3(D1) RZ376.2
CLKREQ_PCIE#0: JNGFF2.52(CLKREQ#) RH10.2
CLKREQ_PCIE#0_R: RH10.1 RH123.1 UH1.BF31(GPP_B5/SRCCLKREQ0#)
CLKREQ_PCIE#1: JNGFF1.53(CLKREQ0#) RH11.2
CLKREQ_PCIE#1_R: RH11.1 RH124.1 UH1.BE31(GPP_B6/SRCCLKREQ1#)
CLKREQ_PCIE#2_R: RH125.1 UH1.AR32(GPP_B7/SRCCLKREQ2#)
CLKREQ_PCIE#3: JNGFF3.52(CLKREQ#) RH13.2
CLKREQ_PCIE#3_R: RH13.1 RH126.1 UH1.BB30(GPP_B8/SRCCLKREQ3#)
CLKREQ_PCIE#4: RH14.2 RL4.1 UL1.48(CLK_REQ_N)
CLKREQ_PCIE#4_R: RH14.1 RH127.1 UH1.BA30(GPP_B9/SRCCLKREQ4#)
CLKREQ_PCIE#5: RH15.2 UR1.2(CLK_REQ#)
CLKREQ_PCIE#5_R: RH15.1 RH131.1 UH1.AN29(GPP_B10/SRCCLKREQ5#)
CLKREQ_PCIE#6: RH16.2 UT1.AC5(PCIE_CLKREQ_N)
CLKREQ_PCIE#6_R: RH16.1 RH132.1 UH1.AE47(GPP_H0/SRCCLKREQ6#)
CLKREQ_PCIE#7_R: RH133.1 UH1.AC48(GPP_H1/SRCCLKREQ7#)
CLKRUN#: T287.1 UH1.AV32(GPP_A8/CLKRUN#)
CMOUT: PQ811.2(G) PQ811.3(D) PQ812.2(G) PR727.1
CNV_BRI_PRX_DTX: RH614.2 RZ1381.1 UH1.AY2(GPP_J5/CNV_BRI_RSP/UART0B_RXD)
CNV_BRI_PRX_DTX_R: JNGFF1.22(UART_RXD) RZ1381.2
CNV_BRI_PTX_DRX: RH603.1 RH604.1 RZ1384.2 UH1.AV4(GPP_J4/CNV_BRI_DT/UART0B_RTS#)
CNV_BRI_PTX_DRX_R: JNGFF1.36(UART_RTS) RZ1384.1
CNV_COEX1: RH607.1 RH608.1 RZ373.2 UH1.AU9(GPP_J9/CNV_MFUART2_TXD)
CNV_COEX2: RZ372.2 UH1.AW2(GPP_J8/CNV_MFUART2_RXD)
CNV_COEX3: RZ374.2 UH1.AV6(GPP_J0/CNV_PA_BLANKING)
CNV_DET#_EC: RE100.2 RE828.2 UE1.L11(GPIO054/PWM1/GPWM1)
CNV_PRX_DTX_N0: JNGFF1.15(SDIO_DAT1) UH1.BB3(CNV_WR_D0N)
CNV_PRX_DTX_N1: JNGFF1.9(SDIO_CLK) UH1.BA3(CNV_WR_D1N)
CNV_PRX_DTX_P0: JNGFF1.17(SDIO_DAT2) UH1.BB4(CNV_WR_D0P)
CNV_PRX_DTX_P1: JNGFF1.11(SDIO_CMD) UH1.BA2(CNV_WR_D1P)
CNV_PTX_DRX_N0: JNGFF1.65(RESERVED/PERP1) UH1.BE6(CNV_WT_D0N)
CNV_PTX_DRX_N1: JNGFF1.59(RESERVED/PETP1) UH1.BG6(CNV_WT_D1N)
CNV_PTX_DRX_P0: JNGFF1.67(RESERVED/PERN1) UH1.BD7(CNV_WT_D0P)
CNV_PTX_DRX_P1: JNGFF1.61(RESERVED/PETN1) UH1.BF6(CNV_WT_D1P)
CNV_RF_RST: QZ17.5(G1) QZ17.6(D1) RE100.1 RZ377.2
CNV_RF_RST#: QZ17.2(G1) RH617.2 UH1.BE16(GPP_D5/I2S2_SFRM/CNV_RF_RESET#)
CNV_RF_RST#_R: JNGFF1.10(PCM_SYNC/I2S_WS) QZ17.3(D1) RZ378.2
CNV_RGI_PRX_DTX: RH613.2 RZ1383.1 UH1.AV3(GPP_J7/CNV_RGI_RSP/UART0B_CTS#)
CNV_RGI_PRX_DTX_R: JNGFF1.34(UART_CTS) RZ1383.2
CNV_RGI_PTX_DRX: RH605.1 RH606.1 RZ1382.2 UH1.BA4(GPP_J6/CNV_RGI_DT/UART0B_TXD)
CNV_RGI_PTX_DRX_R: JNGFF1.32(UART_TXD) RZ1382.1
CNV_WT_RCOMP: RH612.2 UH1.BA1(CNV_WT_RCOMP)
CNVI_EN#: RE828.1 RH868.2 UH1.BF15(GPP_D20/DMIC_DATA0/SNDW4_DATA)
COMP_1PH_CPU: PCZ10.2 PCZ12.2 PUZ1.50(COMP_1PH)
COMP_2PH_CPU: PCZ21.2 PCZ23.2 PUZ1.33(COMP_2PH)
COMP_4PH_CPU: PCZ17.1 PRZ42.1 PUZ1.6(COMP_4PH)
COMP_CHG: PC749.1 PR728.1 PU700.28(CMOP)
CONTACTLESS_DET#: DZ8.2 RH90.2 UH1.BG8(GPP_G4/SD_DATA3)
CONTACTLESS_DET#_R: DZ8.1 JUSH1.4
CPU_2_PCH_TRIGGER: RC177.1 UH1.AK2(TRIGGER_IN)
CPU_2_PCH_TRIGGER_R: RC177.2 UC1.J23(PROC_TRIGOUT)
CPU_24MHZ_R_D: RH169.1 UC1.E31(CLK24P)
CPU_24MHZ_R_D#: RH170.1 UC1.D31(CLK24N)
CPU_C10_GATE#: PR429.1 RH616.1 RZ543.1 UZ61.2(A)
CPU_DP1_AUXN: CT19.1 UC1.E27(DDI1_AUXN)
CPU_DP1_AUXN_C: CT19.2 UT1.W11(DPSNK0_AUX_N)
CPU_DP1_AUXP: CT18.1 UC1.D27(DDI1_AUXP)
CPU_DP1_AUXP_C: CT18.2 UT1.Y11(DPSNK0_AUX_P)
CPU_DP1_N0: CT11.1 UC1.K37(DDI1_TXN_0)
CPU_DP1_N0_C: CT11.2 UT1.AC7(DPSNK0_ML0_N)
CPU_DP1_N1: CT13.1 UC1.J34(DDI1_TXN_1)
CPU_DP1_N1_C: CT13.2 UT1.AC9(DPSNK0_ML1_N)
CPU_DP1_N2: CT15.1 UC1.H36(DDI1_TXN_2)
CPU_DP1_N2_C: CT15.2 UT1.AC11(DPSNK0_ML2_N)
CPU_DP1_N3: CT17.1 UC1.J38(DDI1_TXN_3)
CPU_DP1_N3_C: CT17.2 UT1.AC13(DPSNK0_ML3_N)
CPU_DP1_P0: CT10.1 UC1.K36(DDI1_TXP_0)
CPU_DP1_P0_C: CT10.2 UT1.AB7(DPSNK0_ML0_P)
CPU_DP1_P1: CT12.1 UC1.J35(DDI1_TXP_1)
CPU_DP1_P1_C: CT12.2 UT1.AB9(DPSNK0_ML1_P)
CPU_DP1_P2: CT14.1 UC1.H37(DDI1_TXP_2)
CPU_DP1_P2_C: CT14.2 UT1.AB11(DPSNK0_ML2_P)
CPU_DP1_P3: CT16.1 UC1.J37(DDI1_TXP_3)
CPU_DP1_P3_C: CT16.2 UT1.AB13(DPSNK0_ML3_P)
CPU_DP2_AUXN: CT184.1 UC1.E26(DDI2_AUXN)
CPU_DP2_AUXN_C: CT184.2 UT1.W12(DPSNK1_AUX_N)
CPU_DP2_AUXP: CT178.1 UC1.F26(DDI2_AUXP)
CPU_DP2_AUXP_C: CT178.2 UT1.Y12(DPSNK1_AUX_P)
CPU_DP2_N0: CT187.1 UC1.H33(DDI2_TXN_0)
CPU_DP2_N0_C: CT187.2 UT1.AC15(DPSNK1_ML0_N)
CPU_DP2_N1: CT180.1 UC1.G38(DDI2_TXN_1)
CPU_DP2_N1_C: CT180.2 UT1.AC17(DPSNK1_ML1_N)
CPU_DP2_N2: CT179.1 UC1.F35(DDI2_TXN_2)
CPU_DP2_N2_C: CT179.2 UT1.AC19(DPSNK1_ML2_N)
CPU_DP2_N3: CT181.1 UC1.E36(DDI2_TXN_3)
CPU_DP2_N3_C: CT181.2 UT1.AC21(DPSNK1_ML3_N)
CPU_DP2_P0: CT186.1 UC1.H34(DDI2_TXP_0)
CPU_DP2_P0_C: CT186.2 UT1.AB15(DPSNK1_ML0_P)
CPU_DP2_P1: CT183.1 UC1.F37(DDI2_TXP_1)
CPU_DP2_P1_C: CT183.2 UT1.AB17(DPSNK1_ML1_P)
CPU_DP2_P2: CT185.1 UC1.F34(DDI2_TXP_2)
CPU_DP2_P2_C: CT185.2 UT1.AB19(DPSNK1_ML2_P)
CPU_DP2_P3: CT182.1 UC1.E37(DDI2_TXP_3)
CPU_DP2_P3_C: CT182.2 UT1.AB21(DPSNK1_ML3_P)
CPU_DP3_AUXN: CV602.1 UC1.B27(DDI3_AUXN)
CPU_DP3_AUXN_C: CV604.2 UV31.C8(AUXN)
CPU_DP3_AUXN_R: CV602.2 CV604.1 RV602.2
CPU_DP3_AUXP: CV601.1 UC1.A27(DDI3_AUXP)
CPU_DP3_AUXP_C: CV603.2 UV31.C7(AUXP)
CPU_DP3_AUXP_R: CV601.2 CV603.1 RV601.2
CPU_DP3_N0: CV32.1 UC1.D34(DDI3_TXN_0)
CPU_DP3_N0_C: CV32.2 UV31.A7(DRX0N)
CPU_DP3_N1: CV34.1 UC1.B34(DDI3_TXN_1)
CPU_DP3_N1_C: CV34.2 UV31.A5(DRX1N)
CPU_DP3_N2: CV36.1 UC1.E33(DDI3_TXN_2)
CPU_DP3_N2_C: CV36.2 UV31.A3(DRX2N)
CPU_DP3_N3: CV38.1 UC1.B33(DDI3_TXN_3)
CPU_DP3_N3_C: CV38.2 UV31.A1(DRX3N)
CPU_DP3_P0: CV31.1 UC1.C34(DDI3_TXP_0)
CPU_DP3_P0_C: CV31.2 UV31.A8(DRX0P)
CPU_DP3_P1: CV33.1 UC1.B36(DDI3_TXP_1)
CPU_DP3_P1_C: CV33.2 UV31.A6(DRX1P)
CPU_DP3_P2: CV35.1 UC1.F33(DDI3_TXP_2)
CPU_DP3_P2_C: CV35.2 UV31.A4(DRX2P)
CPU_DP3_P3: CV37.1 UC1.C33(DDI3_TXP_3)
CPU_DP3_P3_C: CV37.2 UV31.A2(DRX3P)
CPU_VIDALERT#: RC153.2 UC1.BH31(VIDALERT#)
CPU_XDP_HOOK6: JXDP1.46 RC115.1 RC144.1
CPU_XDP_PRDY#: JXDP1.5 RC314.1 T189.1 UC1.BP27(PROC_PRDY#)
CPU_XDP_PREQ#: JXDP1.3 RC138.2 RC315.1 T190.1 UC1.BL30(PROC_PREQ#)
CPU_XDP_PRS: JXDP1.60 RC127.1
CPU_XDP_TCLK: JXDP1.57 RC139.1 RC143.1 T181.1 UC1.BR28(PROC_TCK)
CPU_XDP_TDI: JXDP1.56 RC229.1 T185.1 UC1.BL32(PROC_TDI)
CPU_XDP_TDO: CC306.1 JXDP1.52 RC135.1 RC230.1 T184.1 UC1.BT28(PROC_TDO)
CPU_XDP_TMS: JXDP1.58 RC228.1 T180.1 UC1.BP28(PROC_TMS)
CPU_XDP_TRST#: RC136.1 RC844.2 T179.1 UC1.BP30(PROC_TRST#) UH1.AM4(CPU_TRST#)
CPU_XDP_TRST#_XDP: CC308.1 JXDP1.54 RC844.1
CSCL: RV605.1 UV31.E6(CSCL)
CSCOMP_2PH_CPU: PCZ28.2 PCZ29.2 PHZ3.2 PRZ49.2 PRZ52.2 PUZ1.31(CSCOMP_2PH)
CSCOMP_4PH_CPU: PCZ25.2 PCZ26.2 PHZ2.2 PRZ48.1 PRZ50.2 PUZ1.8(CSCOMP_4PH)
CSDA: RV606.1 UV31.F6(CSDA)
CSIN_CHG: PC719.2 PC726.1 PR702.2 PU700.14(CSIN)
CSIN_CHG_R: PR700.3 PR702.1
CSIP_CHG: PC719.1 PC725.1 PR701.2 PU700.15(CSIP)
CSIP_CHG_R: PR700.2 PR701.1
CSN_1PH_CPU: PCZ2.1 PCZ5.1 PCZ8.1 PRZ5.2 PUZ1.48(CSN_1PH)
CSON_CHG: PC752.2 PC753.1 PR734.1 PU700.1(CSON)
CSON_CHG_R: PR711.3 PR734.2
CSOP_CHG: PC748.1 PC752.1 PR733.1 PU700.2(CSOP)
CSOP_CHG_R: PR711.2 PR733.2
CSP1_2PH_CPU: PCZ36.1 PRZ71.1 PRZ73.1 PUZ1.28(CSP1_2PH)
CSP1_4PH_CPU: PCZ35.1 PRZ64.2 PRZ65.1 PUZ1.11(CSP1_4PH)
CSP2_2PH_CPU: PRZ51.2 PUZ1.27(CSP2_2PH)
CSP2_4PH_CPU: PCZ37.1 PRZ72.2 PRZ74.1 PUZ1.12(CSP2_4PH)
CSP3_4PH_CPU: PCZ38.1 PRZ75.2 PRZ76.1 PUZ1.13(CSP3_4PH)
CSP4_4PH_CPU: PCZ39.1 PRZ77.2 PRZ80.2 PRZ81.1 PUZ1.26(CSP4_4PH)
CSP_1PH_CPU: PCZ2.2 PCZ5.2 PRZ3.2 PRZ4.1 PUZ1.47(CSP_1PH)
CSSUM_2PH_CPU: PCZ28.1 PCZ29.1 PRZ55.1 PRZ59.1 PUZ1.30(CSSUM_2PH)
CSSUM_4PH_CPU: PCZ25.1 PCZ26.1 PRZ53.2 PRZ54.1 PRZ56.2 PRZ58.2 PRZ60.2 PUZ1.9(CSSUM_4PH)
CV2_ON: JUSH1.24 RE539.2
CV2_ON_R: RE539.1 RE716.2 UE1.H8(GPIO222/SER_IRQ)
DAT_TP_SIO_I2C_CLK: CZ80.1 RZ22.2 RZ347.2 UE1.C12(GPIO155/SMB02_CLK/PS2_DAT1B)
DAT_TP_SIO_R: CZ88.1 JKBTP1.13 RZ18.2 RZ22.1
DCIN1_EN: PQ8.3(S) PR28.1 UE1.L12(GPIO107/NSMI)
DCIN2_EN: PQ807.3(S) PR821.1 UE1.K4(GPIO215/ADC13)
DCIN_CHG: PC737.2 PR708.1 PU700.17(DCIN)
DDR4_DRAMRST#_PCH: CH556.1 DD32.1 RD11.2 RD12.2 UH1.BB46(DRAM_RESET#)
DDR_A_ACT#: JDIMM1.114(ACT#) UC1.AU3(DDR0_CAA_8/DDR0_ACT#)
DDR_A_ALERT#: JDIMM1.116(ALERT#) UC1.AU5(NC/DDR0_ALERT#)
DDR_A_BA0: JDIMM1.150(BA0) UC1.AH5(DDR0_CAB_4/DDR0_BA_0)
DDR_A_BA1: JDIMM1.145(BA1) UC1.AH1(DDR0_CAB_6/DDR0_BA_1)
DDR_A_BG0: JDIMM1.115(BG0) UC1.AU1(DDR0_CAA_5/DDR0_BG_0)
DDR_A_BG1: JDIMM1.113(BG1) UC1.AU2(DDR0_CAA_9/DDR0_BG_1)
DDR_A_CKE0: JDIMM1.109(CKE0) UC1.AT1(DDR0_CKE_0/DDR0_CKE_0)
DDR_A_CKE1: JDIMM1.110(CKE1) UC1.AT2(DDR0_CKE_1/DDR0_CKE_1)
DDR_A_CLK0: JDIMM1.137(CK0(T)) UC1.AG1(DDR0_CKP_0/DDR0_CKP_0)
DDR_A_CLK1: JDIMM1.138(CK1(T)) UC1.AK2(DDR0_CKP_1/DDR0_CKP_1)
DDR_A_CLK#0: JDIMM1.139(CK0#(C)) UC1.AG2(DDR0_CKN_0/DDR0_CKN_0)
DDR_A_CLK#1: JDIMM1.140(CK1#(C)) UC1.AK1(DDR0_CKN_1/DDR0_CKN_1)
DDR_A_CS#0: JDIMM1.149(S0#) UC1.AD5(DDR0_CS#_0/DDR0_CS#_0)
DDR_A_CS#1: JDIMM1.157(S1#) UC1.AE2(DDR0_CS#_1/DDR0_CS#_1)
DDR_A_D0: JDIMM1.8(DQ0) UC1.BR6(DDR0_DQ_0/DDR0_DQ_0)
DDR_A_D1: JDIMM1.7(DQ1) UC1.BT6(DDR0_DQ_1/DDR0_DQ_1)
DDR_A_D2: JDIMM1.17(DQ7) UC1.BP3(DDR0_DQ_2/DDR0_DQ_2)
DDR_A_D3: JDIMM1.21(DQ3) UC1.BR3(DDR0_DQ_3/DDR0_DQ_3)
DDR_A_D4: JDIMM1.4(DQ4) UC1.BN5(DDR0_DQ_4/DDR0_DQ_4)
DDR_A_D5: JDIMM1.3(DQ5) UC1.BP6(DDR0_DQ_5/DDR0_DQ_5)
DDR_A_D6: JDIMM1.16(DQ6) UC1.BP2(DDR0_DQ_6/DDR0_DQ_6)
DDR_A_D7: JDIMM1.20(DQ2) UC1.BN3(DDR0_DQ_7/DDR0_DQ_7)
DDR_A_D8: JDIMM1.29(DQ9) UC1.BL4(DDR0_DQ_8/DDR0_DQ_8)
DDR_A_D9: JDIMM1.25(DQ13) UC1.BL5(DDR0_DQ_9/DDR0_DQ_9)
DDR_A_D10: JDIMM1.41(DQ10) UC1.BL2(DDR0_DQ_10/DDR0_DQ_10)
DDR_A_D11: JDIMM1.42(DQ11) UC1.BM1(DDR0_DQ_11/DDR0_DQ_11)
DDR_A_D12: JDIMM1.24(DQ12) UC1.BK4(DDR0_DQ_12/DDR0_DQ_12)
DDR_A_D13: JDIMM1.28(DQ8) UC1.BK5(DDR0_DQ_13/DDR0_DQ_13)
DDR_A_D14: JDIMM1.38(DQ14) UC1.BK1(DDR0_DQ_14/DDR0_DQ_14)
DDR_A_D15: JDIMM1.37(DQ15) UC1.BK2(DDR0_DQ_15/DDR0_DQ_15)
DDR_A_D16: JDIMM1.170(DQ36) UC1.BT11(DDR1_DQ_0/DDR0_DQ_16)
DDR_A_D17: JDIMM1.169(DQ37) UC1.BR11(DDR1_DQ_1/DDR0_DQ_17)
DDR_A_D18: JDIMM1.186(DQ35) UC1.BT9(DDR1_DQ_2/DDR0_DQ_18)
DDR_A_D19: JDIMM1.187(DQ34) UC1.BR8(DDR1_DQ_3/DDR0_DQ_19)
DDR_A_D20: JDIMM1.174(DQ32) UC1.BP11(DDR1_DQ_4/DDR0_DQ_20)
DDR_A_D21: JDIMM1.173(DQ33) UC1.BN11(DDR1_DQ_5/DDR0_DQ_21)
DDR_A_D22: JDIMM1.183(DQ38) UC1.BP8(DDR1_DQ_6/DDR0_DQ_22)
DDR_A_D23: JDIMM1.182(DQ39) UC1.BN8(DDR1_DQ_7/DDR0_DQ_23)
DDR_A_D24: JDIMM1.194(DQ41) UC1.BL12(DDR1_DQ_8/DDR0_DQ_24)
DDR_A_D25: JDIMM1.191(DQ44) UC1.BL11(DDR1_DQ_9/DDR0_DQ_25)
DDR_A_D26: JDIMM1.195(DQ40) UC1.BL8(DDR1_DQ_10/DDR0_DQ_26)
DDR_A_D27: JDIMM1.208(DQ43) UC1.BJ8(DDR1_DQ_11/DDR0_DQ_27)
DDR_A_D28: JDIMM1.203(DQ46) UC1.BJ11(DDR1_DQ_12/DDR0_DQ_28)
DDR_A_D29: JDIMM1.207(DQ42) UC1.BJ10(DDR1_DQ_13/DDR0_DQ_29)
DDR_A_D30: JDIMM1.190(DQ45) UC1.BL7(DDR1_DQ_14/DDR0_DQ_30)
DDR_A_D31: JDIMM1.204(DQ47) UC1.BJ7(DDR1_DQ_15/DDR0_DQ_31)
DDR_A_D32: JDIMM1.46(DQ20) UC1.BG4(DDR0_DQ_16/DDR0_DQ_32)
DDR_A_D33: JDIMM1.45(DQ21) UC1.BG5(DDR0_DQ_17/DDR0_DQ_33)
DDR_A_D34: JDIMM1.59(DQ23) UC1.BF4(DDR0_DQ_18/DDR0_DQ_34)
DDR_A_D35: JDIMM1.63(DQ19) UC1.BF5(DDR0_DQ_19/DDR0_DQ_35)
DDR_A_D36: JDIMM1.49(DQ17) UC1.BG2(DDR0_DQ_20/DDR0_DQ_36)
DDR_A_D37: JDIMM1.50(DQ16) UC1.BG1(DDR0_DQ_21/DDR0_DQ_37)
DDR_A_D38: JDIMM1.58(DQ22) UC1.BF1(DDR0_DQ_22/DDR0_DQ_38)
DDR_A_D39: JDIMM1.62(DQ18) UC1.BF2(DDR0_DQ_23/DDR0_DQ_39)
DDR_A_D40: JDIMM1.71(DQ25) UC1.BD2(DDR0_DQ_24/DDR0_DQ_40)
DDR_A_D41: JDIMM1.67(DQ29) UC1.BD1(DDR0_DQ_25/DDR0_DQ_41)
DDR_A_D42: JDIMM1.79(DQ30) UC1.BC4(DDR0_DQ_26/DDR0_DQ_42)
DDR_A_D43: JDIMM1.83(DQ26) UC1.BC5(DDR0_DQ_27/DDR0_DQ_43)
DDR_A_D44: JDIMM1.66(DQ28) UC1.BD5(DDR0_DQ_28/DDR0_DQ_44)
DDR_A_D45: JDIMM1.70(DQ24) UC1.BD4(DDR0_DQ_29/DDR0_DQ_45)
DDR_A_D46: JDIMM1.84(DQ27) UC1.BC1(DDR0_DQ_30/DDR0_DQ_46)
DDR_A_D47: JDIMM1.80(DQ31) UC1.BC2(DDR0_DQ_31/DDR0_DQ_47)
DDR_A_D48: JDIMM1.212(DQ53) UC1.BG11(DDR1_DQ_16/DDR0_DQ_48)
DDR_A_D49: JDIMM1.211(DQ52) UC1.BG10(DDR1_DQ_17/DDR0_DQ_49)
DDR_A_D50: JDIMM1.215(DQ49) UC1.BG8(DDR1_DQ_18/DDR0_DQ_50)
DDR_A_D51: JDIMM1.229(DQ51) UC1.BF8(DDR1_DQ_19/DDR0_DQ_51)
DDR_A_D52: JDIMM1.228(DQ50) UC1.BF11(DDR1_DQ_20/DDR0_DQ_52)
DDR_A_D53: JDIMM1.224(DQ54) UC1.BF10(DDR1_DQ_21/DDR0_DQ_53)
DDR_A_D54: JDIMM1.216(DQ48) UC1.BG7(DDR1_DQ_22/DDR0_DQ_54)
DDR_A_D55: JDIMM1.225(DQ55) UC1.BF7(DDR1_DQ_23/DDR0_DQ_55)
DDR_A_D56: JDIMM1.246(DQ63) UC1.BB11(DDR1_DQ_24/DDR0_DQ_56)
DDR_A_D57: JDIMM1.236(DQ57) UC1.BC11(DDR1_DQ_25/DDR0_DQ_57)
DDR_A_D58: JDIMM1.249(DQ58) UC1.BB8(DDR1_DQ_26/DDR0_DQ_58)
DDR_A_D59: JDIMM1.237(DQ56) UC1.BC8(DDR1_DQ_27/DDR0_DQ_59)
DDR_A_D60: JDIMM1.233(DQ61) UC1.BC10(DDR1_DQ_28/DDR0_DQ_60)
DDR_A_D61: JDIMM1.245(DQ62) UC1.BB10(DDR1_DQ_29/DDR0_DQ_61)
DDR_A_D62: JDIMM1.232(DQ60) UC1.BC7(DDR1_DQ_30/DDR0_DQ_62)
DDR_A_D63: JDIMM1.250(DQ59) UC1.BB7(DDR1_DQ_31/DDR0_DQ_63)
DDR_A_DQS0: JDIMM1.13(DQS0(T)) UC1.BP5(DDR0_DQSP_0/DDR0_DQSP_0)
DDR_A_DQS1: JDIMM1.34(DQS1(T)) UC1.BK3(DDR0_DQSP_1/DDR0_DQSP_1)
DDR_A_DQS2: JDIMM1.179(DQS4(T)) UC1.BP9(DDR1_DQSP_0/DDR0_DQSP_2)
DDR_A_DQS3: JDIMM1.200(DQS5(T)) UC1.BJ9(DDR1_DQSP_1/DDR0_DQSP_3)
DDR_A_DQS4: JDIMM1.55(DQS2(T)) UC1.BF3(DDR0_DQSP_2/DDR0_DQSP_4)
DDR_A_DQS5: JDIMM1.76(DQS3(T)) UC1.BC3(DDR0_DQSP_3/DDR0_DQSP_5)
DDR_A_DQS6: JDIMM1.221(DQS6(T)) UC1.BF9(DDR1_DQSP_2/DDR0_DQSP_6)
DDR_A_DQS7: JDIMM1.242(DQS7(T)) UC1.BB9(DDR1_DQSP_3/DDR0_DQSP_7)
DDR_A_DQS#0: JDIMM1.11(DQS0#(C)) UC1.BR5(DDR0_DQSN_0/DDR0_DQSN_0)
DDR_A_DQS#1: JDIMM1.32(DQS1#(C)) UC1.BL3(DDR0_DQSN_1/DDR0_DQSN_1)
DDR_A_DQS#2: JDIMM1.177(DQS4#(C)) UC1.BN9(DDR1_DQSN_0/DDR0_DQSN_2)
DDR_A_DQS#3: JDIMM1.198(DQS5#(C)) UC1.BL9(DDR1_DQSN_1/DDR0_DQSN_3)
DDR_A_DQS#4: JDIMM1.53(DQS2#(C)) UC1.BG3(DDR0_DQSN_2/DDR0_DQSN_4)
DDR_A_DQS#5: JDIMM1.74(DQS3#(C)) UC1.BD3(DDR0_DQSN_3/DDR0_DQSN_5)
DDR_A_DQS#6: JDIMM1.219(DQS6#(C)) UC1.BG9(DDR1_DQSN_2/DDR0_DQSN_6)
DDR_A_DQS#7: JDIMM1.240(DQS7#(C)) UC1.BC9(DDR1_DQSN_3/DDR0_DQSN_7)
DDR_A_MA0: JDIMM1.144(A0) UC1.AH3(DDR0_CAB_9/DDR0_MA_0)
DDR_A_MA1: JDIMM1.133(A1) UC1.AP4(DDR0_CAB_8/DDR0_MA_1)
DDR_A_MA2: JDIMM1.132(A2) UC1.AN4(DDR0_CAB_5/DDR0_MA_2)
DDR_A_MA3: JDIMM1.131(A3) UC1.AP5(NC/DDR0_MA_3)
DDR_A_MA4: JDIMM1.128(A4) UC1.AP2(NC/DDR0_MA_4)
DDR_A_MA5: JDIMM1.126(A5) UC1.AP1(DDR0_CAA_0/DDR0_MA_5)
DDR_A_MA6: JDIMM1.127(A6) UC1.AP3(DDR0_CAA_2/DDR0_MA_6)
DDR_A_MA7: JDIMM1.122(A7) UC1.AN1(DDR0_CAA_4/DDR0_MA_7)
DDR_A_MA8: JDIMM1.125(A8) UC1.AN3(DDR0_CAA_3/DDR0_MA_8)
DDR_A_MA9: JDIMM1.121(A9) UC1.AT4(DDR0_CAA_1/DDR0_MA_9)
DDR_A_MA10: JDIMM1.146(A10_AP) UC1.AH2(DDR0_CAB_7/DDR0_MA_10)
DDR_A_MA11: JDIMM1.120(A11) UC1.AN2(DDR0_CAA_7/DDR0_MA_11)
DDR_A_MA12: JDIMM1.119(A12) UC1.AU4(DDR0_CAA_6/DDR0_MA_12)
DDR_A_MA13: JDIMM1.158(A13) UC1.AE3(DDR0_CAB_0/DDR0_MA_13)
DDR_A_MA14: JDIMM1.151(A14_WE#) UC1.AG4(DDR0_CAB_2/DDR0_MA_14)
DDR_A_MA15: JDIMM1.156(A15_CAS#) UC1.AD1(DDR0_CAB_1/DDR0_MA_15)
DDR_A_MA16: JDIMM1.152(A16_RAS#) UC1.AH4(DDR0_CAB_3/DDR0_MA_16)
DDR_A_ODT0: JDIMM1.155(ODT0) UC1.AD3(DDR0_ODT_0/DDR0_ODT_0)
DDR_A_ODT1: JDIMM1.161(ODT1) UC1.AE4(NC/DDR0_ODT_1)
DDR_A_PAR: JDIMM1.143(PARITY) UC1.AG3(NC/DDR0_PAR)
DDR_B_ACT#: JDIMM2.114(ACT#) UC1.AT9(DDR1_CAA_8/DDR1_ACT#)
DDR_B_ALERT#: JDIMM2.116(ALERT#) UC1.AR8(NC/DDR1_ALERT#)
DDR_B_BA0: JDIMM2.150(BA0) UC1.AH8(DDR1_CAB_4/DDR1_BA_0)
DDR_B_BA1: JDIMM2.145(BA1) UC1.AH9(DDR1_CAB_6/DDR1_BA_1)
DDR_B_BG0: JDIMM2.115(BG0) UC1.AR9(DDR1_CAA_5/DDR1_BG_0)
DDR_B_BG1: JDIMM2.113(BG1) UC1.AR7(DDR1_CAA_9/DDR1_BG_1)
DDR_B_CKE0: JDIMM2.109(CKE0) UC1.AT8(DDR1_CKE_0/DDR1_CKE_0)
DDR_B_CKE1: JDIMM2.110(CKE1) UC1.AT10(DDR1_CKE_1/DDR1_CKE_1)
DDR_B_CLK0: JDIMM2.137(CK0(T)) UC1.AM9(DDR1_CKP_0/DDR1_CKP_0)
DDR_B_CLK1: JDIMM2.138(CK1(T)) UC1.AM7(DDR1_CKP_1/DDR1_CKP_1)
DDR_B_CLK#0: JDIMM2.139(CK0#(C)) UC1.AN9(DDR1_CKN_0/DDR1_CKN_0)
DDR_B_CLK#1: JDIMM2.140(CK1#(C)) UC1.AM8(DDR1_CKN_1/DDR1_CKN_1)
DDR_B_CS#0: JDIMM2.149(S0#) UC1.AF11(DDR1_CS#_0/DDR1_CS#_0)
DDR_B_CS#1: JDIMM2.157(S1#) UC1.AE7(DDR1_CS#_1/DDR1_CS#_1)
DDR_B_D0: JDIMM2.3(DQ5) UC1.AB1(DDR0_DQ_32/DDR1_DQ_0)
DDR_B_D1: JDIMM2.4(DQ4) UC1.AB2(DDR0_DQ_33/DDR1_DQ_1)
DDR_B_D2: JDIMM2.16(DQ6) UC1.AA4(DDR0_DQ_34/DDR1_DQ_2)
DDR_B_D3: JDIMM2.17(DQ7) UC1.AA5(DDR0_DQ_35/DDR1_DQ_3)
DDR_B_D4: JDIMM2.7(DQ1) UC1.AB5(DDR0_DQ_36/DDR1_DQ_4)
DDR_B_D5: JDIMM2.8(DQ0) UC1.AB4(DDR0_DQ_37/DDR1_DQ_5)
DDR_B_D6: JDIMM2.20(DQ2) UC1.AA2(DDR0_DQ_38/DDR1_DQ_6)
DDR_B_D7: JDIMM2.21(DQ3) UC1.AA1(DDR0_DQ_39/DDR1_DQ_7)
DDR_B_D8: JDIMM2.24(DQ12) UC1.V5(DDR0_DQ_40/DDR1_DQ_8)
DDR_B_D9: JDIMM2.29(DQ9) UC1.V2(DDR0_DQ_41/DDR1_DQ_9)
DDR_B_D10: JDIMM2.41(DQ10) UC1.U1(DDR0_DQ_42/DDR1_DQ_10)
DDR_B_D11: JDIMM2.37(DQ15) UC1.U2(DDR0_DQ_43/DDR1_DQ_11)
DDR_B_D12: JDIMM2.25(DQ13) UC1.V1(DDR0_DQ_44/DDR1_DQ_12)
DDR_B_D13: JDIMM2.28(DQ8) UC1.V4(DDR0_DQ_45/DDR1_DQ_13)
DDR_B_D14: JDIMM2.38(DQ14) UC1.U5(DDR0_DQ_46/DDR1_DQ_14)
DDR_B_D15: JDIMM2.42(DQ11) UC1.U4(DDR0_DQ_47/DDR1_DQ_15)
DDR_B_D16: JDIMM2.187(DQ34) UC1.AA11(DDR1_DQ_32/DDR1_DQ_16)
DDR_B_D17: JDIMM2.183(DQ38) UC1.AA10(DDR1_DQ_33/DDR1_DQ_17)
DDR_B_D18: JDIMM2.174(DQ32) UC1.AC11(DDR1_DQ_34/DDR1_DQ_18)
DDR_B_D19: JDIMM2.170(DQ36) UC1.AC10(DDR1_DQ_35/DDR1_DQ_19)
DDR_B_D20: JDIMM2.186(DQ35) UC1.AA7(DDR1_DQ_36/DDR1_DQ_20)
DDR_B_D21: JDIMM2.182(DQ39) UC1.AA8(DDR1_DQ_37/DDR1_DQ_21)
DDR_B_D22: JDIMM2.169(DQ37) UC1.AC8(DDR1_DQ_38/DDR1_DQ_22)
DDR_B_D23: JDIMM2.173(DQ33) UC1.AC7(DDR1_DQ_39/DDR1_DQ_23)
DDR_B_D24: JDIMM2.191(DQ44) UC1.W8(DDR1_DQ_40/DDR1_DQ_24)
DDR_B_D25: JDIMM2.195(DQ40) UC1.W7(DDR1_DQ_41/DDR1_DQ_25)
DDR_B_D26: JDIMM2.203(DQ46) UC1.V10(DDR1_DQ_42/DDR1_DQ_26)
DDR_B_D27: JDIMM2.207(DQ42) UC1.V11(DDR1_DQ_43/DDR1_DQ_27)
DDR_B_D28: JDIMM2.190(DQ45) UC1.W11(DDR1_DQ_44/DDR1_DQ_28)
DDR_B_D29: JDIMM2.194(DQ41) UC1.W10(DDR1_DQ_45/DDR1_DQ_29)
DDR_B_D30: JDIMM2.208(DQ43) UC1.V7(DDR1_DQ_46/DDR1_DQ_30)
DDR_B_D31: JDIMM2.204(DQ47) UC1.V8(DDR1_DQ_47/DDR1_DQ_31)
DDR_B_D32: JDIMM2.49(DQ17) UC1.R2(DDR0_DQ_48/DDR1_DQ_32)
DDR_B_D33: JDIMM2.58(DQ22) UC1.P5(DDR0_DQ_49/DDR1_DQ_33)
DDR_B_D34: JDIMM2.50(DQ16) UC1.R4(DDR0_DQ_50/DDR1_DQ_34)
DDR_B_D35: JDIMM2.59(DQ23) UC1.P4(DDR0_DQ_51/DDR1_DQ_35)
DDR_B_D36: JDIMM2.46(DQ20) UC1.R5(DDR0_DQ_52/DDR1_DQ_36)
DDR_B_D37: JDIMM2.63(DQ19) UC1.P2(DDR0_DQ_53/DDR1_DQ_37)
DDR_B_D38: JDIMM2.45(DQ21) UC1.R1(DDR0_DQ_54/DDR1_DQ_38)
DDR_B_D39: JDIMM2.62(DQ18) UC1.P1(DDR0_DQ_55/DDR1_DQ_39)
DDR_B_D40: JDIMM2.67(DQ29) UC1.M4(DDR0_DQ_56/DDR1_DQ_40)
DDR_B_D41: JDIMM2.70(DQ24) UC1.M1(DDR0_DQ_57/DDR1_DQ_41)
DDR_B_D42: JDIMM2.83(DQ26) UC1.L4(DDR0_DQ_58/DDR1_DQ_42)
DDR_B_D43: JDIMM2.80(DQ31) UC1.L2(DDR0_DQ_59/DDR1_DQ_43)
DDR_B_D44: JDIMM2.71(DQ25) UC1.M5(DDR0_DQ_60/DDR1_DQ_44)
DDR_B_D45: JDIMM2.66(DQ28) UC1.M2(DDR0_DQ_61/DDR1_DQ_45)
DDR_B_D46: JDIMM2.79(DQ30) UC1.L5(DDR0_DQ_62/DDR1_DQ_46)
DDR_B_D47: JDIMM2.84(DQ27) UC1.L1(DDR0_DQ_63/DDR1_DQ_47)
DDR_B_D48: JDIMM2.216(DQ48) UC1.R11(DDR1_DQ_48/DDR1_DQ_48)
DDR_B_D49: JDIMM2.229(DQ51) UC1.P11(DDR1_DQ_49/DDR1_DQ_49)
DDR_B_D50: JDIMM2.228(DQ50) UC1.P7(DDR1_DQ_50/DDR1_DQ_50)
DDR_B_D51: JDIMM2.211(DQ52) UC1.R8(DDR1_DQ_51/DDR1_DQ_51)
DDR_B_D52: JDIMM2.212(DQ53) UC1.R10(DDR1_DQ_52/DDR1_DQ_52)
DDR_B_D53: JDIMM2.225(DQ55) UC1.P10(DDR1_DQ_53/DDR1_DQ_53)
DDR_B_D54: JDIMM2.215(DQ49) UC1.R7(DDR1_DQ_54/DDR1_DQ_54)
DDR_B_D55: JDIMM2.224(DQ54) UC1.P8(DDR1_DQ_55/DDR1_DQ_55)
DDR_B_D56: JDIMM2.249(DQ58) UC1.L11(DDR1_DQ_56/DDR1_DQ_56)
DDR_B_D57: JDIMM2.236(DQ57) UC1.M11(DDR1_DQ_57/DDR1_DQ_57)
DDR_B_D58: JDIMM2.250(DQ59) UC1.L7(DDR1_DQ_58/DDR1_DQ_58)
DDR_B_D59: JDIMM2.237(DQ56) UC1.M8(DDR1_DQ_59/DDR1_DQ_59)
DDR_B_D60: JDIMM2.245(DQ62) UC1.L10(DDR1_DQ_60/DDR1_DQ_60)
DDR_B_D61: JDIMM2.232(DQ60) UC1.M10(DDR1_DQ_61/DDR1_DQ_61)
DDR_B_D62: JDIMM2.233(DQ61) UC1.M7(DDR1_DQ_62/DDR1_DQ_62)
DDR_B_D63: JDIMM2.246(DQ63) UC1.L8(DDR1_DQ_63/DDR1_DQ_63)
DDR_B_DQS0: JDIMM2.13(DQS0(T)) UC1.AB3(DDR0_DQSP_4/DDR1_DQSP_0)
DDR_B_DQS1: JDIMM2.34(DQS1(T)) UC1.V3(DDR0_DQSP_5/DDR1_DQSP_1)
DDR_B_DQS2: JDIMM2.179(DQS4(T)) UC1.AA9(DDR1_DQSP_4/DDR1_DQSP_2)
DDR_B_DQS3: JDIMM2.200(DQS5(T)) UC1.V9(DDR1_DQSP_5/DDR1_DQSP_3)
DDR_B_DQS4: JDIMM2.55(DQS2(T)) UC1.R3(DDR0_DQSP_6/DDR1_DQSP_4)
DDR_B_DQS5: JDIMM2.76(DQS3(T)) UC1.M3(DDR0_DQSP_7/DDR1_DQSP_5)
DDR_B_DQS6: JDIMM2.221(DQS6(T)) UC1.P9(DDR1_DQSP_6/DDR1_DQSP_6)
DDR_B_DQS7: JDIMM2.242(DQS7(T)) UC1.L9(DDR1_DQSP_7/DDR1_DQSP_7)
DDR_B_DQS#0: JDIMM2.11(DQS0#(C)) UC1.AA3(DDR0_DQSN_4/DDR1_DQSN_0)
DDR_B_DQS#1: JDIMM2.32(DQS1#(C)) UC1.U3(DDR0_DQSN_5/DDR1_DQSN_1)
DDR_B_DQS#2: JDIMM2.177(DQS4#(C)) UC1.AC9(DDR1_DQSN_4/DDR1_DQSN_2)
DDR_B_DQS#3: JDIMM2.198(DQS5#(C)) UC1.W9(DDR1_DQSN_5/DDR1_DQSN_3)
DDR_B_DQS#4: JDIMM2.53(DQS2#(C)) UC1.P3(DDR0_DQSN_6/DDR1_DQSN_4)
DDR_B_DQS#5: JDIMM2.74(DQS3#(C)) UC1.L3(DDR0_DQSN_7/DDR1_DQSN_5)
DDR_B_DQS#6: JDIMM2.219(DQS6#(C)) UC1.R9(DDR1_DQSN_6/DDR1_DQSN_6)
DDR_B_DQS#7: JDIMM2.240(DQS7#(C)) UC1.M9(DDR1_DQSN_7/DDR1_DQSN_7)
DDR_B_MA0: JDIMM2.144(A0) UC1.AJ9(DDR1_CAB_9/DDR1_MA_0)
DDR_B_MA1: JDIMM2.133(A1) UC1.AK6(DDR1_CAB_8/DDR1_MA_1)
DDR_B_MA2: JDIMM2.132(A2) UC1.AK5(DDR1_CAB_5/DDR1_MA_2)
DDR_B_MA3: JDIMM2.131(A3) UC1.AL5(NC/DDR1_MA_3)
DDR_B_MA4: JDIMM2.128(A4) UC1.AL6(NC/DDR1_MA_4)
DDR_B_MA5: JDIMM2.126(A5) UC1.AM6(DDR1_CAA_0/DDR1_MA_5)
DDR_B_MA6: JDIMM2.127(A6) UC1.AN7(DDR1_CAA_2/DDR1_MA_6)
DDR_B_MA7: JDIMM2.122(A7) UC1.AN10(DDR1_CAA_4/DDR1_MA_7)
DDR_B_MA8: JDIMM2.125(A8) UC1.AN8(DDR1_CAA_3/DDR1_MA_8)
DDR_B_MA9: JDIMM2.121(A9) UC1.AR11(DDR1_CAA_1/DDR1_MA_9)
DDR_B_MA10: JDIMM2.146(A10_AP) UC1.AH7(DDR1_CAB_7/DDR1_MA_10)
DDR_B_MA11: JDIMM2.120(A11) UC1.AN11(DDR1_CAA_7/DDR1_MA_11)
DDR_B_MA12: JDIMM2.119(A12) UC1.AR10(DDR1_CAA_6/DDR1_MA_12)
DDR_B_MA13: JDIMM2.158(A13) UC1.AF9(DDR1_CAB_0/DDR1_MA_13)
DDR_B_MA14: JDIMM2.151(A14_WE#) UC1.AH11(DDR1_CAB_2/DDR1_MA_14)
DDR_B_MA15: JDIMM2.156(A15_CAS#) UC1.AF8(DDR1_CAB_1/DDR1_MA_15)
DDR_B_MA16: JDIMM2.152(A16_RAS#) UC1.AH10(DDR1_CAB_3/DDR1_MA_16)
DDR_B_ODT0: JDIMM2.155(ODT0) UC1.AF7(DDR1_ODT_0/DDR1_ODT_0)
DDR_B_ODT1: JDIMM2.161(ODT1) UC1.AE8(NC/DDR1_ODT_1)
DDR_B_PAR: JDIMM2.143(PARITY) UC1.AJ7(NC/DDR1_PAR)
DDR_DRAMRST#: CD29.1 CD61.1 JDIMM1.108(RESET#) JDIMM2.108(RESET#) RD12.1
DDR_RCOMP0: RC5.2 UC1.G1(DDR_RCOMP_0)
DDR_RCOMP1: RC6.2 UC1.H1(DDR_RCOMP_1)
DDR_RCOMP2: RC7.2 UC1.J2(DDR_RCOMP_2)
DDR_VTT_CTRL: UC1.BT13(DDR_VTT_CNTL) UD1.2(A)
DDR_XDP_WAN_SMBCLK: JDIMM1.253(SCL) JDIMM2.253(SCL) LGA1.1(SCL/SPC) QH4.1(S1) RC845.1 RH333.1
DDR_XDP_WAN_SMBCLK_XDP: JXDP1.53 RC845.2
DDR_XDP_WAN_SMBDAT: JDIMM1.254(SDA) JDIMM2.254(SDA) LGA1.4(SDA/SDI/SDO) QH4.4(S1) RC846.1 RH374.1
DDR_XDP_WAN_SMBDAT_XDP: JXDP1.51 RC846.2
DEBUG_TX: JDEG1.9 RE30.2 RE74.2
DEW1: RN16.2 RN17.2 UN7.16(NC2)
DEW2: RN14.2 RN15.2 UN7.6(NC1)
DGPU_HOLD_RST#: T37.1 UH1.BB20(GPP_D10/ISH_SPI_CLK/GSPI2_CLK)
DGPU_PWR_EN: T38.1 UH1.AN18(GPP_D12/ISH_SPI_MOSI/GP_BSSB_DI)
DGPU_PWROK: RE529.1 UE1.M4(GPIO013/SMB07_CLK/TOUT2)
DIFFOUT_2PH_CPU: PRZ43.1 PRZ46.1 PUZ1.35(DIFFOUT_2PH)
DIFFOUT_4PH_CPU: PCZ18.2 PRZ45.2 PUZ1.4(DIFFOUT_4PH)
DIMM1_SA0: JDIMM1.256(SA0) RD4.2 RD5.1
DIMM1_SA1: JDIMM1.260(SA1) RD6.2 RD7.1
DIMM1_SA2: JDIMM1.166(SA2) RD8.2 RD9.1
DIMM2_SA0: JDIMM2.256(SA0) RD20.2 RD21.1
DIMM2_SA1: JDIMM2.260(SA1) RD22.2 RD23.1
DIMM2_SA2: JDIMM2.166(SA2) RD24.2 RD25.1
DISP_ON: DV2.1 JEDP1.22 RV2.1
DMI_CRX_PTX_N0: UC1.E8(DMI_RXN_0) UH1.C33(DMI0_TXN)
DMI_CRX_PTX_N1: UC1.F6(DMI_RXN_1) UH1.C32(DMI1_TXN)
DMI_CRX_PTX_N2: UC1.E5(DMI_RXN_2) UH1.C31(DMI2_TXN)
DMI_CRX_PTX_N3: UC1.J9(DMI_RXN_3) UH1.C29(DMI3_TXN)
DMI_CRX_PTX_P0: UC1.D8(DMI_RXP_0) UH1.B33(DMI0_TXP)
DMI_CRX_PTX_P1: UC1.E6(DMI_RXP_1) UH1.B32(DMI1_TXP)
DMI_CRX_PTX_P2: UC1.D5(DMI_RXP_2) UH1.B31(DMI2_TXP)
DMI_CRX_PTX_P3: UC1.J8(DMI_RXP_3) UH1.B29(DMI3_TXP)
DMI_CTX_PRX_N0: UC1.A8(DMI_TXN_0) UH1.K34(DMI0_RXN)
DMI_CTX_PRX_N1: UC1.B6(DMI_TXN_1) UH1.G33(DMI1_RXN)
DMI_CTX_PRX_N2: UC1.A5(DMI_TXN_2) UH1.K32(DMI2_RXN)
DMI_CTX_PRX_N3: UC1.B4(DMI_TXN_3) UH1.G30(DMI3_RXN)
DMI_CTX_PRX_P0: UC1.B8(DMI_TXP_0) UH1.J35(DMI0_RXP)
DMI_CTX_PRX_P1: UC1.C6(DMI_TXP_1) UH1.F34(DMI1_RXP)
DMI_CTX_PRX_P2: UC1.B5(DMI_TXP_2) UH1.J32(DMI2_RXP)
DMI_CTX_PRX_P3: UC1.D4(DMI_TXP_3) UH1.F30(DMI3_RXP)
DMIC0: CA6.1 DA9.3 JEDP1.7 RA52.2 UA1.2(GPIO0/DMIC-DATA12)
DMIC_CLK0: CA5.1 CA54.1 DA9.2 JEDP1.9 RA14.1
DMIC_CLK_CODEC: RA14.2 UA1.3(GPIO1/DMIC-CLK)
DPSNK0_DDC_CLK: RT14.1 RT126.1 UT1.Y5(DPSNK0_DDC_CLK)
DPSNK0_DDC_DATA: RT15.1 RT127.1 UT1.R4(DPSNK0_DDC_DATA)
DPSNK1_DDC_CLK: RT128.1 RT336.1 UT1.Y8(DPSNK1_DDC_CLK)
DPSNK_RBIAS: RT38.1 UT1.Y18(DPSNK_RBIAS)
DRON_CPU: PR1616.1 PR1617.1 PR1618.1 PR1619.1 PR1620.1 PR1621.1 PR1622.1 PR1623.1 PR1624.1 PR1625.1 PR1626.1 PR1627.1 PUZ1.17(DRON)
EDP_AUXN: CV1.1 UC1.B26(EDP_AUXN)
EDP_AUXN_C: CV1.2 JEDP1.33
EDP_AUXP: CV2.1 UC1.C26(EDP_AUXP)
EDP_AUXP_C: CV2.2 JEDP1.34
EDP_COMP: RC1.1 UC1.D37(DISP_RCOMP)
EDP_HPD: JEDP1.26 RH1.2 RV7.1 UH1.AN6(GPP_I4/EDP_HPD/DISP_MISC4)
EDP_TXN0: CV4.1 UC1.E29(EDP_TXN_0)
EDP_TXN0_C: CV4.2 JEDP1.36
EDP_TXN1: CV6.1 UC1.E28(EDP_TXN_1)
EDP_TXN1_C: CV6.2 JEDP1.38
EDP_TXP0: CV3.1 UC1.D29(EDP_TXP_0)
EDP_TXP0_C: CV3.2 JEDP1.35
EDP_TXP1: CV5.1 UC1.F28(EDP_TXP_1)
EDP_TXP1_C: CV5.2 JEDP1.37
EN_1.2V_RUN: PC510.1 PR509.1 PR511.2 PU502.5(EN)
EN_1.05VALWP: PC2211.1 PR302.1 PR312.2 PU301.11(EN)
EN_1.8VALW: PC505.1 PR504.2 PR505.1 PU501.1(EN)
EN_1VS_VCCIO: PC402.1 PR402.2 PR403.1 PU401.13(EN)
EN_2.5V_MEM: PC513.1 PR513.2 PR514.1 PU503.5(EN)
EN_CPU: PRZ28.1 PUZ1.43(EN)
EN_INVPWR: QV2.2(G) RE55.1 UE1.B2(GPIO023/GPTP-IN1)
EN_LCDPWR: DV3.1 RV3.2 UV24.4(EN)
EN_PD_HV_1: PQ813.2(G1) PR820.2 PR834.1 PR846.1 PR853.1 PR857.1 RT70.2
EN_PD_HV_1#: PQ802.2(G1) PQ802.3(D2) PR810.2 PR851.2
EN_PD_HV_1_R: RT70.1 UT5.C2(GPIO1)
ENABLE_DS#: RE549.2 RE550.1 UE1.L2(GPIO067/CLKRUN#)
ENLDO_3V5V: PR102.1 PR103.1 PU100.11(EN2) PU102.11(EN2)
ENVDD_PCH: DV3.3 UH1.AV44(GPP_F19/EDP_VDDEN)
ESPI_ALERT#: RH340.1 UE1.H7(GPIO063/SER_IRQ/ESPI_ALERT#) UH1.AW35(GPP_A6/SERIRQ/ESPI_CS1#)
ESPI_CLK: RH97.1 UH1.BB36(GPP_A9/CLKOUT_LPC0/ESPI_CLK)
ESPI_CLK_5105: CC316.1 JESPI.10 RE350.1 RH97.2 UE1.G7(GPIO065/PCI_CLK/ESPI_CLK)
ESPI_CS#: JESPI.7 UE1.H6(GPIO066/LFRAME#/ESPI_CS#) UH1.BE38(GPP_A5/LFRAME#/ESPI_CS0#)
ESPI_IO0: JESPI.3 RC366.2 UE1.K5(GPIO070/LAD0/ESPI_IO0)
ESPI_IO0_R: RC366.1 UH1.BB39(GPP_A1/LAD0/ESPI_IO0)
ESPI_IO1: JESPI.4 RC367.2 UE1.L4(GPIO071/LAD1/ESPI_IO1)
ESPI_IO1_R: RC367.1 UH1.AW37(GPP_A2/LAD1/ESPI_IO1)
ESPI_IO2: JESPI.5 RC368.2 UE1.G6(GPIO072/LAD2/ESPI_IO2)
ESPI_IO2_R: RC368.1 UH1.AV37(GPP_A3/LAD2/ESPI_IO2)
ESPI_IO3: JESPI.6 RC369.2 UE1.L5(GPIO073/LAD3/ESPI_IO3)
ESPI_IO3_R: RC369.1 UH1.BA38(GPP_A4/LAD3/ESPI_IO3)
ESPI_RESET#: CH348.1 JESPI.8 RH95.1 RH633.1 UE1.K6(GPIO061/LPCPD#/ESPI_RESET#) UH1.BF38(GPP_A14/SUS_STAT#/ESPI_RESET#)
FB_1.05VALWP: PR306.2 PR308.2 PR311.1 PU301.14(FB)
FB_1.8VALW: PC503.2 PR501.2 PR506.1 PU501.6(FB)
FB_2PH_CPU: PCZ19.2 PCZ21.1 PRZ46.2 PRZ47.1 PUZ1.34(FB_2PH)
FB_3V: PC113.1 PU100.13(FF)
FB_4PH_CPU: PCZ17.2 PCZ20.2 PRZ40.1 PRZ45.1 PUZ1.5(FB_4PH)
FB_5V: PC127.1 PU102.13(FF)
FB_DDR: PC208.2 PR204.2 PR206.1 PU200.16(FB)
FBS_1VS_VCCIO: PR421.2 PR422.1 PU401.5(FBS)
FFS_INT2: LGA1.11(INT 2) QN1.2(G1) RH378.2 UH1.BE14(GPP_D23/ISH_I2C2_SCL/I2C3_SCL)
FFS_INT2_Q: JSATA1.19 QN1.3(D2) RN1.2
FIVR_EN: RC217.1 RC218.2 RC219.2
FIVR_EN_R: JXDP1.45 RC126.2 RC132.2 RC217.2
FPR_DET#: DT41.1 DT41.9 JFPBTN1.1 RE606.1 UE1.D9(GPIO133/PWM9)
FPR_LOW_PWR_MODE#: DT41.4 DT41.7 JFPBTN1.11 RE708.1 UE1.K12(GPIO111/PS2_DAT2)
FPR_PWR_EN#: RE704.1 RZ580.2 UE1.M11(GPIO027/TIN2)
FPR_PWR_EN#_R: CZ500.1 QZ38.2(G) RZ580.1
FPR_RST#: DT41.5 DT41.6 JFPBTN1.12 RZ1392.1 RZ1411.1
FPR_RST#_USH: JUSH1.25 RZ1411.2
FPR_SCAN_INT#: DT42.4 DT42.7 JFPBTN1.15 QE20.3(S) RE825.1 RE826.2
FPR_SCAN_INT#_EC: QE20.1(D) RE825.2 RE827.2 RZ114.1 UE1.L8(GPIO002/PWM5)
FPR_SCAN_INT#_EC_R: JUSH1.6 RZ114.2
FPR_SSO_EN#: DT42.5 DT42.6 JFPBTN1.16 RE706.1 UE1.H9(GPIO030/TIN3)
FPR_UEFI_MGMT#: DT42.1 DT42.9 JFPBTN1.13 RE707.1 UE1.K9(GPIO032/GPTP-OUT0)
GPP_B23: RH329.1 UH1.BD33(GPP_B23/SML1ALERT#/PCHHOT#)
GPP_C5: RH78.2 UH1.BF24(GPP_C5/SML0ALERT#)
GPP_H12: RH615.2 UH1.AB47(GPP_H12/SML2ALERT#)
GPP_H15: RH601.2 UH1.AC47(GPP_H15/SML3ALERT#)
GPP_J1: RH616.2 UH1.AY3(GPP_J1/CPU_C10_GATE#)
GPPJ_RCOMP: RH609.2 UH1.BD1(GPPJ_RCOMP_1P81) UH1.BE1(GPPJ_RCOMP_1P82) UH1.BE2(GPPJ_RCOMP_1P83)
GPS_DISABLE#: DZ6.1 RE12.1 RZ87.2 UE1.H5(GPIO060/KBRST/48MHZ_OUT)
GPU_PWR_LEVEL: RE5.1 UE1.E12(GPIO126/PVT_IO3)
GPU_SMCLK: RE524.1 UE1.F7(GPIO142/SMB05_CLK/SPI1_MOSI/UAR)
GPU_SMDAT: RE525.1 UE1.B6(GPIO141/SMB05_DATA/SPI1_CLK/UAR)
H_CATERR#: RC79.2 UC1.BM30(CATERR#)
H_PECI: RE60.2 RH73.2 UC1.BT34(PECI)
H_PM_DOWN: RC168.1 UH1.AE2(PM_DOWN)
H_PM_DOWN_R: RC168.2 UC1.BP31(PM_DOWN)
H_PM_SYNC: RH156.2 UC1.BM34(PM_SYNC)
H_PM_SYNC_R: RH156.1 UH1.AF3(PM_SYNC)
H_PROCHOT#_R: RC84.2 UC1.BR30(PROCHOT#)
H_PWRGD: CC300.1 CH551.1 UC1.BT31(PROCPWRGD) UH1.AE3(CPUPWRGD)
H_SKTOCC#: RC319.2 UC1.BR33(SKTOCC#)
H_THERMTRIP#: CC323.1 QE4.3(EMITTER) RC80.2 RC169.1 RD14.2 RD27.2 RH75.2
H_THERMTRIP#_R: RC169.2 UC1.J31(THERMTRIP#)
H_VCCST_PWRGD_XDP: CC307.1 JXDP1.39 RC124.2
HDA_BIT_CLK: CA75.1 RH46.2 RH637.2 UH1.BD11(HDA_BCLK/I2S0_SCLK)
HDA_BIT_CLK_R: CH268.2 RA17.1 RH46.1 UA1.5(BIT-CLK)
HDA_RST#: RH50.2 RH636.2 UH1.BE10(HDA_RST#/I2S1_SCLK)
HDA_RST#_R: RA50.1 RH50.1
HDA_SDIN0: CA73.1 RA9.1 UH1.BE11(HDA_SDI0/I2S0_RXD)
HDA_SDIN0_R: RA9.2 UA1.7(SDATA-IN)
HDA_SDOUT: CA76.1 RH45.2 RH328.2 UH1.BF12(HDA_SDO/I2S0_TXD)
HDA_SDOUT_R: RH45.1 UA1.4(SDATA-OUT)
HDA_SYNC: CA74.1 RH48.2 UH1.BG13(HDA_SYNC/I2S0_SFRM)
HDA_SYNC_R: RH48.1 UA1.9(SYNC)
HDD_A_EQ: RN10.1 RN11.2 UN7.17(A_EQ)
HDD_A_EQ2: RN20.2 RN21.1 UN7.18(TDET_EN)
HDD_A_PRE: RN6.2 RN7.2 UN7.9(A_EM)
HDD_B_EQ: RN12.2 RN13.2 UN7.19(B_EQ)
HDD_B_EQ2: RN18.2 RN19.1 UN7.13(TDET_A#)
HDD_B_PRE: RN8.1 RN9.2 UN7.8(B_EM)
HDD_DET#: JSATA1.13 QN6.2(G) RH324.2 UH1.AK47(GPP_E2/SATAXPCIE2/SATAGP2)
HDD_DEVSLP: JSATA1.11 RN3.2 UH1.AH40(GPP_E6/SATA_DEVSLP2)
HDD_EN: RH625.2 RN4.2 RN5.1 UZ23.3(ON)
HDD_FALL_INT: LGA1.12(INT 1) RH355.2 UH1.AW26(GPP_B19/GSPI1_CS0#)
HDD_UN7_EN: QN6.1(D) RN226.2 RN227.1
HDD_UN7_EN_R: DN1.2 RN227.2 UN7.7(EN)
HDMI_1.2V_EN: PR511.1 RV615.1 UV31.G8(VDD12_ON)
HDMI_CEC: JHDMI1.13(CEC) RV604.1
HDMI_CEC_R: RV604.2 UV31.F2(HDMI_CEC)
HDMI_CLK_27M_IN: CV607.1 UV31.E8(XTLI) YV6.1
HDMI_CLK_27M_OUT: RV609.1 UV31.F8(XTLO)
HDMI_CLK_27M_OUT_R: CV606.1 RV609.2 YV6.3
HDMI_CTRL_CLK: JHDMI1.15(SCL) RV22.1 UV31.E1(DDC_SCL)
HDMI_CTRL_DATA: JHDMI1.16(SDA) RV23.1 UV31.F1(DDC_SDA)
HDMI_HPD: JHDMI1.19(HP_DET) UV31.G1(HDMI_HPD)
HDMI_L_CLKN: JHDMI1.12(CK-) LV12.3 RV33.2 RV35.2
HDMI_L_CLKP: JHDMI1.10(CK+) LV12.4 RV34.2 RV35.1
HDMI_L_TX_N0: JHDMI1.9(D0-) LV9.3 RV30.2 RV32.2
HDMI_L_TX_N1: JHDMI1.6(D1-) LV6.3 RV27.2 RV29.2
HDMI_L_TX_N2: JHDMI1.3(D2-) LV3.3 RV24.2 RV26.2
HDMI_L_TX_P0: JHDMI1.7(D0+) LV9.4 RV31.2 RV32.1
HDMI_L_TX_P1: JHDMI1.4(D1+) LV6.4 RV28.2 RV29.1
HDMI_L_TX_P2: JHDMI1.1(D2+) LV3.4 RV25.2 RV26.1
HDMI_LS_CLKN: LV12.2 RV33.1 UV31.H1(HDMICKN)
HDMI_LS_CLKP: LV12.1 RV34.1 UV31.H2(HDMICKP)
HDMI_LS_TX_N0: LV9.2 RV30.1 UV31.H3(HDMID0N)
HDMI_LS_TX_N1: LV6.2 RV27.1 UV31.H5(HDMID1N)
HDMI_LS_TX_N2: LV3.2 RV24.1 UV31.H7(HDMID2N)
HDMI_LS_TX_P0: LV9.1 RV31.1 UV31.H4(HDMID0P)
HDMI_LS_TX_P1: LV6.1 RV28.1 UV31.H6(HDMID1P)
HDMI_LS_TX_P2: LV3.1 RV25.1 UV31.H8(HDMID2P)
HDMI_PD#: RV607.1 UV31.C3(PDB)
HDMI_RST#: CV605.1 RV608.2 UV31.B8(RESETB)
HOST_DEBUG_TX: JDEG1.8 RE73.2 RE306.2 RZ132.1 UE1.G11(GPIO104/UART0_TX)
HOST_SD_WP#: QR1.2(G) RH214.2 UH1.BE8(GPP_G5/SD_CD#)
HP_OUT_L: CA43.2 CA77.1 RA7.1 UA1.25(HP-OUT-L)
HP_OUT_R: CA44.2 CA78.1 RA8.1 UA1.26(HP-OUT-R)
HV_GATE1_A: RT64.1 UT5.B9(HV_GATE1)
HV_GATE2_A: RT65.1 UT5.A9(HV_GATE2)
HW_ACAVIN_NB: PC805.1 PR25.2 PR41.1 PR42.1 PR737.1 PR746.1 PR805.2 PR806.2 PR835.1 PR844.1 PR845.1 PU800.1(O) UE1.N6(GPIO014/PWM6/GPTP-IN6)
HW_GPS_DISABLE#_R: DZ6.2 JNGFF2.26(W_DISABLE2#) RZ87.1
I2C0_SCL_TS: DZ10.2 JIRTS1.4 RV99.2 UH1.BC22(GPP_C17/I2C0_SCL)
I2C0_SDA_TS: DZ10.3 JIRTS1.3 RV98.2 UH1.BF23(GPP_C16/I2C0_SDA)
I2C1_SCK_TP: RZ21.2 RZ29.1 UH1.BE21(GPP_C19/I2C1_SCL)
I2C1_SCK_TP_R: JKBTP1.19 RZ29.2 RZ117.2 RZ347.1
I2C1_SDA_TP: RZ20.2 RZ26.1 UH1.BF21(GPP_C18/I2C1_SDA)
I2C1_SDA_TP_R: JKBTP1.18 RZ26.2 RZ116.2 RZ346.1
I_ADP: PR743.2 UE1.B11(VCP)
I_BATT: PR729.2 RE64.2
I_BATT_R: CE3.1 RE64.1 UE1.J4(GPIO200/ADC00)
I_SYS: PR731.2 PRZ62.1 PUZ1.24(TTSENSE_1PH/PSYS) RE312.2
I_SYS_R: CE4.1 RE312.1 RE313.1 UE1.J5(GPIO201/ADC01)
ILIM_1PH_CPU: PCZ9.2 PRZ22.2 PUZ1.49(ILIM_1PH)
ILIM_2PH_CPU: PRZ49.1 PUZ1.32(ILIM_2PH)
ILIM_4PH_CPU: PRZ48.2 PUZ1.7(ILIM_4PH)
ILIM_SEL: RI13.1 UI3.4(ILIM_SEL)
ILMT_1.05VALWP: PR307.2 PR310.1 PU301.13(ILMT)
ILMT_DDR: PR205.2 PR207.1 PU200.17(ILMT)
IMON_1PH_CPU: PCZ6.2 PRZ15.2 PUZ1.46(IMON_1PH)
IMON_2PH_CPU: PCZ24.1 PRZ44.1 PUZ1.36(IMON_2PH)
IMON_4PH_CPU: PCZ22.2 PRZ41.2 PUZ1.3(IMON_4PH)
IMVP_VR_ON: PRZ28.2 RE304.1 UE3.4(O) UE4.2(A)
IMVP_VR_ON_EC: RE304.2 RE717.2 UE1.N7(GPIO031/GPTP-OUT1) UE3.1(B)
INT_SPK_L+: CA22.1 LA6.1 UA1.35(SPK-OUT-LP)
INT_SPK_L-: CA23.1 LA7.1 UA1.36(SPK-OUT-LN)
INT_SPK_R+: CA19.1 LA8.1 UA1.38(SPK-OUT-RP)
INT_SPK_R-: CA24.1 LA9.1 UA1.37(SPK-OUT-RN)
INT_SPKR_L+: DA6.2 JSPK1.1 LA6.2
INT_SPKR_L-: DA6.3 JSPK1.2 LA7.2
INT_SPKR_R+: DA7.2 JSPK1.3 LA8.2
INT_SPKR_R-: DA7.3 JSPK1.4 LA9.2
IR_CAM_DET#: JIRTS1.5 RH373.1 UH1.BD16(GPP_D19/DMIC_CLK0/SNDW4_CLK)
ISEN1N_GT: PCZ30.1 PCZ36.2 PRT3.2 PRZ73.2 PUZ1.29(CSREF_2PH)
ISEN1N_IA: PCZ27.2 PCZ35.2 PCZ37.2 PCZ38.2 PCZ39.2 PRH5.2 PRH6.2 PRH13.2 PRH14.2 PRZ65.2 PRZ74.2 PRZ76.2 PRZ81.2 PUZ1.10(CSREF_4PH)
ISEN1N_SA: PHZ1.1 PLA1.3 PRZ5.1
ISEN1P_GT: PLT1.2 PRZ59.2 PRZ71.2
ISEN1P_IA: PLH1.2 PRZ53.1 PRZ64.1
ISEN1P_SA: PLA1.2 PRZ4.2
ISEN2P_IA: PLH2.2 PRZ56.1 PRZ72.1
ISEN3P_IA: PLH3.2 PRZ58.1 PRZ75.1
ISEN4P_IA: PLH4.2 PRZ60.1 PRZ80.1
ISH_UART0_CTS#_R: JNGFF1.62(ALERT#) RZ80.2
ISH_UART0_RXD_R: JNGFF1.58(I2C_DATA) RZ78.2
ISH_UART0_TXD_R: JNGFF1.60(I2C_CLK) RZ79.2
IST_TRIG: T3.1 UC1.E3(IST_TRIG)
ITP_PMODE_CPU: RC144.2 T192.1 UH1.AL3(ITP_PMODE)
JDIMM1_EVENT#: JDIMM1.134(EVENT#) RD14.1
JDIMM2_EVENT#: JDIMM2.134(EVENT#) RD27.1
JTAG_CLK: JDEG1.4 RE713.2 UE1.C8(GPIO147/SMB08_DATA/JTAG_CLK)
JTAG_RST#: CE30.1 JTAG1.1 RE63.1 RE65.1 UE1.G13(JTAG_RST#)
JTAG_TDI: JDEG1.2 RE715.2 UE1.E9(GPIO145/SMB09_DATA/JTAG_TDI)
JTAG_TDO: JDEG1.5 RE712.2 UE1.F6(GPIO146/SMB09_CLK/JTAG_TDO)
JTAG_TMS: JDEG1.3 RE714.2 UE1.C5(GPIO150/SMB08_CLK/JTAG_TMS)
KB_DET#: CZ84.1 JKBTP1.1 RC74.2 UH1.AW15(GPP_D17/DMIC_CLK1/SNDW3_CLK)
LAN_ACTLED_YEL#: QL1.6(D1) RL14.1
LAN_ACTLED_YEL_R#: JLOM1.A2(YELLOW LED-) RL14.2
LAN_DISABLE#_R: RL5.1 RL7.2 RL9.1 UL1.3(LAN_DISABLE_N)
LAN_MDIN0: RL72.1 UL1.14(MDI_MINUS0)
LAN_MDIN0_L: RL72.2 TL1.3(TD1-)
LAN_MDIN1: RL74.1 UL1.18(MDI_MINUS1)
LAN_MDIN1_L: RL74.2 TL1.6(TD2-)
LAN_MDIN2: RL76.1 UL1.21(MDI_MINUS2)
LAN_MDIN2_L: RL76.2 TL1.9(TD3-)
LAN_MDIN3: RL78.1 UL1.24(MDI_MINUS3)
LAN_MDIN3_L: RL78.2 TL1.12(TD4-)
LAN_MDIP0: RL71.1 UL1.13(MDI_PLUS0)
LAN_MDIP0_L: RL71.2 TL1.2(TD1+)
LAN_MDIP1: RL73.1 UL1.17(MDI_PLUS1)
LAN_MDIP1_L: RL73.2 TL1.5(TD2)
LAN_MDIP2: RL75.1 UL1.20(MDI_PLUS2)
LAN_MDIP2_L: RL75.2 TL1.8(TD3+)
LAN_MDIP3: RL77.1 UL1.23(MDI_PLUS3)
LAN_MDIP3_L: RL77.2 TL1.11(TD4+)
LAN_TEST_EN: RL12.1 UL1.30(TEST_EN)
LAN_WAKE#: RH93.1 UE1.L3(GPIO217/ADC15) UH1.BG44(GPD2/LAN_WAKE#) UL1.2(LANWAKE_N)
LCD_CBL_DET#: JEDP1.40 RC370.1 UH1.AW24(GPP_C14/UART1_RTS#/ISH_UART1_RT)
LCD_TST: JEDP1.29 RE20.1 UE1.M2(GPIO052/FAN_TACH2/LRESET#)
LCD_VCC_TEST_EN: DV3.2 UE1.E1(GPIO226/LED3)
LCDVDD_MONITOR: QV21.2(BASE) RV630.2
LDO_3V: PC111.2 PR104.1 PR105.1 PU100.16(NC3) PU100.17(LDO)
LED_GRN#: QL1.3(D2) RL19.1
LED_GRN_R#: JLOM1.B2(GREEN LED-) RL19.2
LED_MASK#: QL1.2(G1) QL1.5(G2) RE21.1 UE1.A12(GPIO140/SMB06_CLK/ICT5) UZ10.1(B)
LG1_CHG: PQ700.4(G) PU700.9(LGATE1)
LG2_CHG: PQ701.8(G2) PU700.7(LGATE2)
LID_CL#: JLED1.2 RE26.1 UZ10.2(A)
LID_CL#_PCH: T268.1 UH1.AV34(GPP_A23/ISH_GP5)
LID_CL_SIO#: CE8.1 RE25.2 RE26.2 UE1.N11(GPIO115/PS2_DAT0A)
LINE1-VREFO: DA4.2 DA5.2 UA1.24(LINE1-VREFO-L)
LINE1_L: CA43.1 UA1.18(LINE1-L)
LINE1_R: CA44.1 UA1.17(LINE1-R)
LM393_P: PC754.2 PC801.2 PD800.1(3) PR735.2 PR866.2 PU701.5(P) PU800.8(P)
LOM_ACTLED_YEL#: QL1.1(S1) UL1.26(LED0)
LOM_CABLE_DETECT#: RE505.1 RL20.1 UE1.D2(GPIO211/ADC09)
LOM_CONNLED_GRN#: QL1.4(S2) RL20.2 RL29.2 UL1.27(LED1)
LOM_LED2: T419.1 UL1.25(LED2)
LPM_1VS_VCCIO: PR404.2 PR425.2 PR429.2 PU401.14(L\P\)
LPSS_UART2_RXD: RH361.2 RH376.2 UH1.BD20(GPP_C20/UART2_RXD)
LSPCON_CLK: RV618.1 UV31.D2(SPI_CK_OUT) UV32.6(CLK)
LSPCON_CS#: RV616.2 UV31.C1(SPI_CS) UV32.1(CS#)
LSPCON_DI: UV31.C2(SPI_D_IN) UV32.2(DO)
LSPCON_DO: UV31.D1(SPI_D_OUT) UV32.5(DI)
LSPCON_GPIO0: RV610.1 UV31.C4(GPIO0)
LSPCON_GPIO2: RV611.1 UV31.E3(GPIO2)
LSPCON_GPIO4: T425.1 UV31.E7(CEC_EN/GPIO4)
LSPCON_HOLD#: RV617.2 UV32.7(HOLD#)
LSPCON_WP#: RV619.1 UV31.E2(SPI_WR_PROT) UV32.3(WP#)
LX1_CHG: PC727.1 PL701.1 PQ700.5(D) PQ704.1(S1) PQ704.2(S2) PQ704.3(S3) PR717.1 PU700.10(PHASE1)
LX1_IA: PLH1.1 PRH8.1 PUH1.11(SW1) PUH1.12(SW2)
LX2_CHG: PL701.2 PQ701.2(S1/D2) PQ701.5(D2/S1_1) PQ701.6(D2/S1_2) PQ701.7(D2/S1_3) PR714.2 PR718.1 PU700.6(PHASE2)
LX2_IA: PLH2.1 PRH16.1 PUH2.11(SW1) PUH2.12(SW2)
LX3_IA: PLH3.1 PRH7.1 PUH3.11(SW1) PUH3.12(SW2)
LX4_IA: PLH4.1 PRH15.1 PUH4.11(SW1) PUH4.12(SW2)
LX_1.05VALWP: PC304.2 PL301.1 PR303.1 PU301.6(LX1) PU301.19(LX2) PU301.20(LX3)
LX_1.8VALW: PL501.1 PR502.1 PU501.3(LX)
LX_1VS_VCCIO: PL402.1 PR405.1 PU401.2(LX1) PU401.3(LX2)
LX_3V: PC102.2 PL100.1 PR106.1 PU100.6(LX1) PU100.19(LX2) PU100.20(LX3)
LX_5V: PC114.2 PL101.1 PR112.1 PU102.6(LX1) PU102.19(LX2) PU102.20(LX3)
LX_DDR: PC205.2 PL201.1 PR202.1 PU200.11(LX)
LX_GT: PLT1.1 PRT4.1 PUT1.11(SW1) PUT1.12(SW2)
LX_SA: PLA1.1 PRA3.1 PUA1.11(SW1) PUA1.12(SW2)
M2280_DEVSLP: JNGFF3.38(DEVSLP) RN37.2 UH1.AH35(GPP_E5/SATA_DEVSLP1)
M2280_PCIE_SATA#: JNGFF3.69(PEDET(NC-PCIE/GND-SATA)) RH317.2 RH318.2 UH1.AJ43(GPP_E1/SATAXPCIE1/SATAGP1)
M3042_DEVSLP: JNGFF2.38(N/C_38) UH1.AR47(GPP_F6/SATA_DEVSLP4)
M3042_PCIE#_SATA: RH344.2 UE1.J12(GPIO043/SB-TSI_CLK) UH1.AM46(GPP_F1/SATAXPCIE4/SATAGP4)
M_BIST: RZ1415.2 UE1.N8(GPI0040/GPTP-OUT2)
M_BIST_R: CZ218.1 DZ12.2 QZ21.2(BASE) RZ1413.2 RZ1415.1 RZ1482.2
MASK_BASE_LEDS#: QZ7.5(G2) UZ10.4(O)
ME_FWP: RH100.1 SW1.3(C) UE1.G12(GPIO105/UART0_RX)
ME_FWP_PCH: RH100.2 RH328.1 SW1.2(B)
ME_RESET#: RH70.1 UC3.2(A)
ME_SUS_PWR_ACK_R: T422.1 UH1.BC37(GPP_A13/SUSWARN#/SUSPWRDNACK)
MEC_XTAL1: CE28.1 UE1.A1(XTAL1) YE1.1
MEC_XTAL2: CE29.1 RE290.2 YE1.2
MEC_XTAL2_R: RE290.1 UE1.A3(XTAL2)
MEDIACARD_IRQ#: RR19.1 UH1.BB26(GPP_B15/GSPI0_CS0#) UR1.32(WAKE#)
MEM_INTERLEAVED: RH371.1 RH372.1 UH1.BA20(GPP_D9/ISH_SPI_CS#/GSPI2_CS0#)
MEM_SMBCLK: CC320.1 QH4.6(D1) RH56.2 UH1.BE26(GPP_C0/SMBCLK)
MEM_SMBDATA: QH4.3(D1) RH57.2 UH1.BF26(GPP_C1/SMBDATA)
MSCLK: JDEG1.6 RE30.1 RE72.2 UE1.H10(GPIO170/TFDP_CLK/UART1_TX)
MSDATA: JDEG1.7 RE75.2 RE86.1 UE1.G9(GPIO171/TFDP_DATA/UART1_RX)
NB_MODE#: T423.1 UE1.J6(GPIO202/ADC02)
NB_MUTE#: DA8.1 RA48.1 UE1.A4(GPIO022/GPTP-IN0)
NB_PSID: PD4.2 PD4.3 PJPDC1.1 PL3.2
NFC_ACTIVITY_STATUS#_R: JUSH1.2 RZ1473.2
NGFF_CONFIG_0: JNGFF2.21(CONFIG_0) RE725.1 UE1.N9(GPIO152/GPTP-OUT3)
NGFF_CONFIG_1: JNGFF2.69(CONFIG_1) RE723.1 UE1.M10(GPIO151/ICT4) UZ29.9(SEL)
NGFF_CONFIG_2: JNGFF2.75(CONFIG_2) RE724.1 UE1.N10(GPIO132/SMB06_DATA)
NGFF_CONFIG_3: JNGFF2.1(CONFIG_3) RE726.1 UE1.F4(GPIO041/SYS_SHDN#)
NRB_BIT: RH331.2 UH1.BE30(GPP_B18/GSPI0_MOSI)
ONE_DIMM#: RH267.1 RH268.1 UH1.BF29(GPP_B16/GSPI0_CLK)
OTGEN/CMIN_CHG: PR709.2 PR712.2 PR746.2 PU700.20(OTGEN/CMIN)
OTGPG/CMOUT_CHG: PR726.2 PR727.2 PR745.2 PU700.26(OTGPG/CMOUT)
PANEL_BKEN_EC: DV2.2 UE1.J9(GPIO015/PWM7)
PANEL_BKEN_PCH: DV2.3 UH1.AV46(GPP_F20/EDP_BKLTEN)
PANEL_MONITOR: RV628.2 UE1.M8(GPIO231)
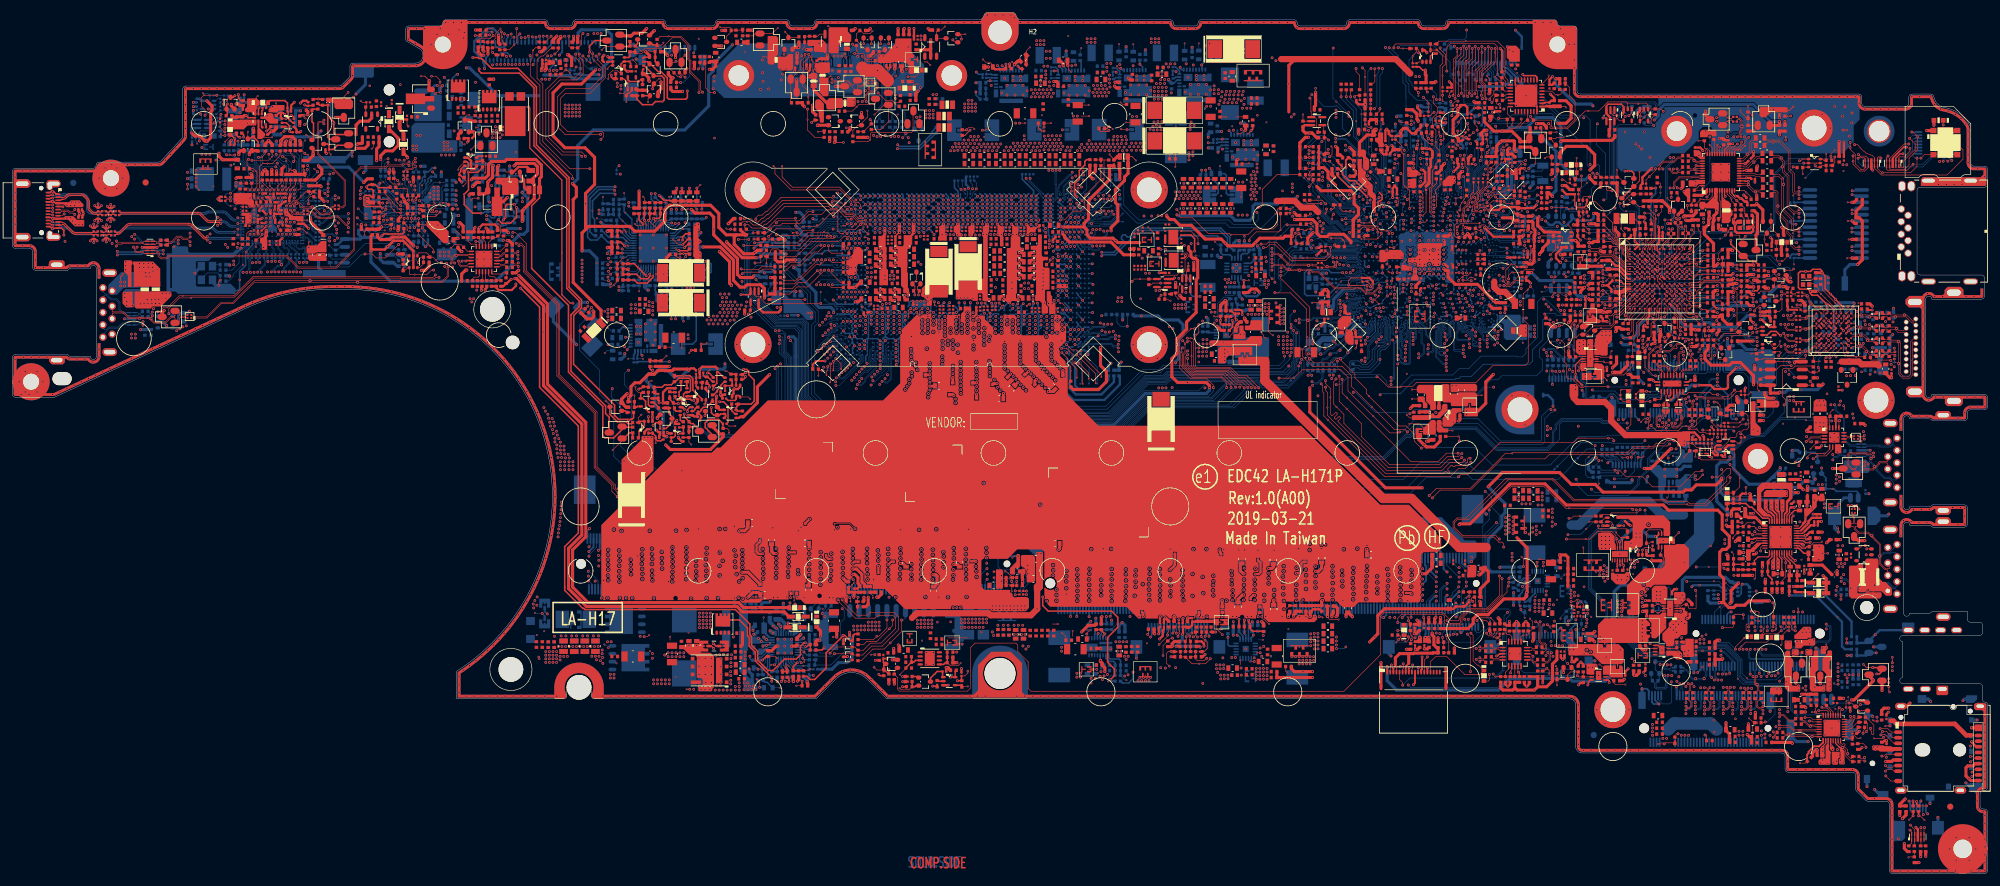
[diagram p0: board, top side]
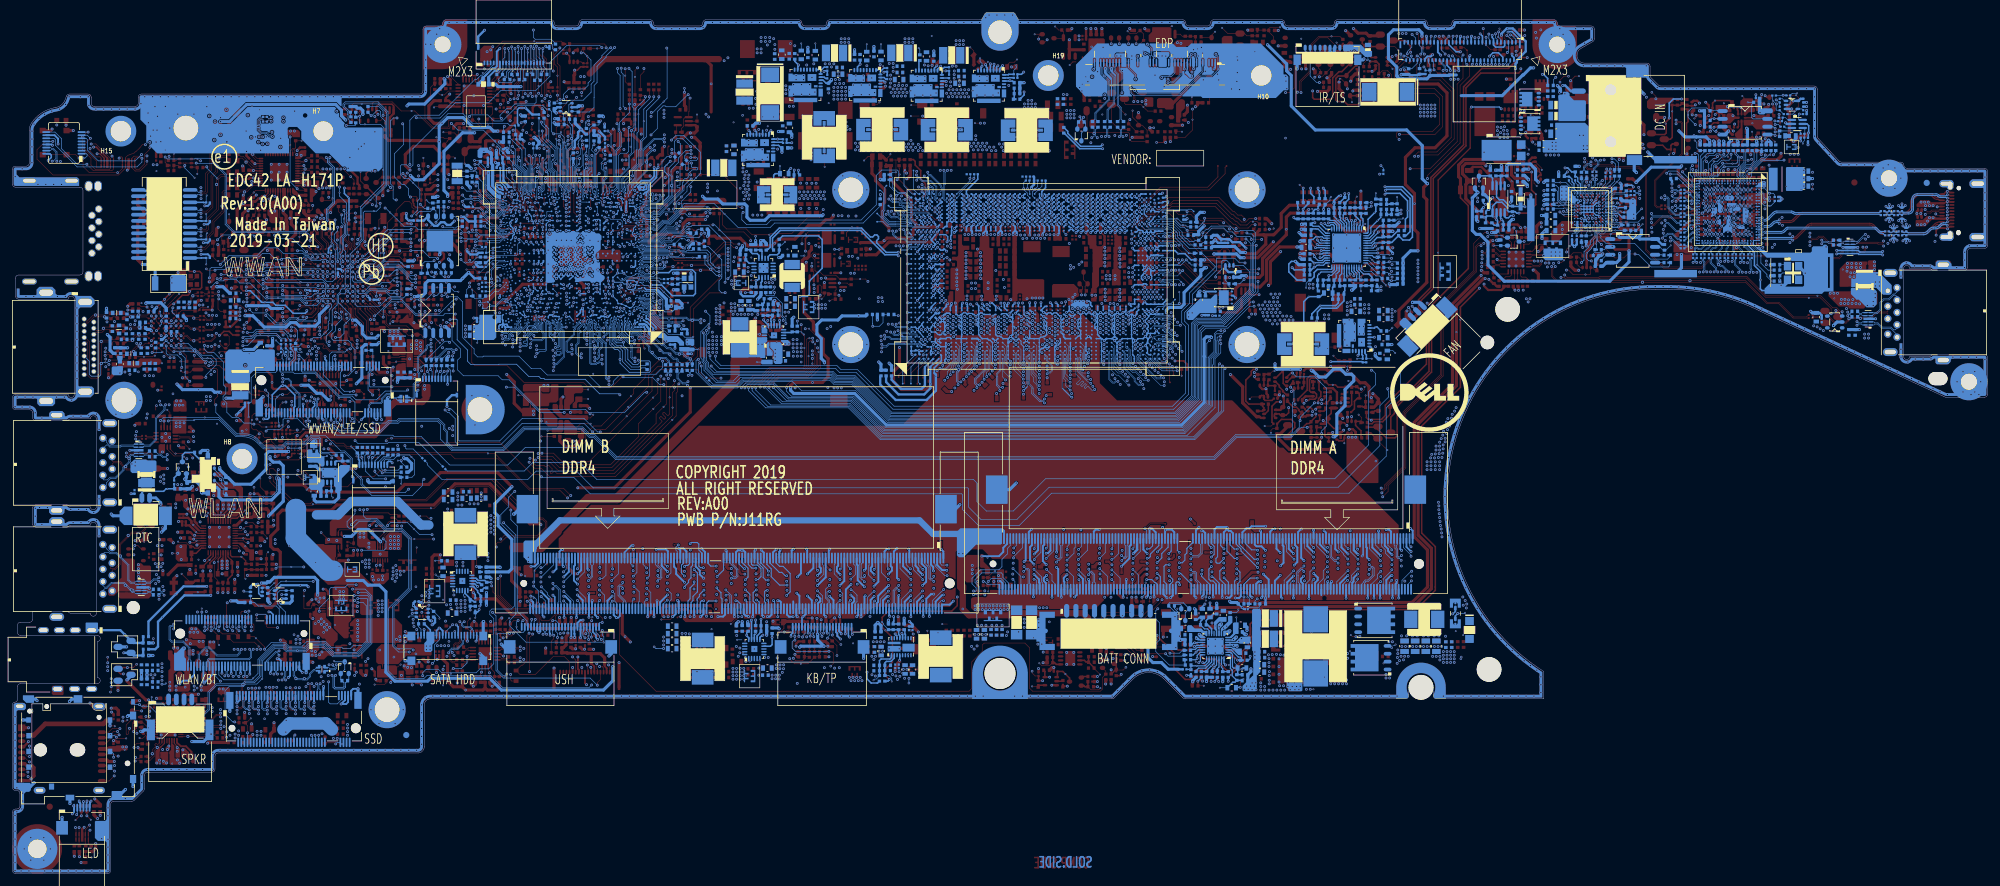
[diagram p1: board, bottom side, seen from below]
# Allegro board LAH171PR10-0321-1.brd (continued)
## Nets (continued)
PANEL_PWRGD: CV632.1 QV19.1(COLLECTOR) QV21.1(COLLECTOR) RV623.2 RV624.1 RV628.1
PBAT_CHARGER_SMBCLK: PD2.3 PR38.2 PR715.1 RE43.1 UE1.N2(GPIO131/SMB10_CLK/TOUT0)
PBAT_CHARGER_SMBDAT: PD1.2 PR39.2 PR713.1 RE37.1 UE1.M3(GPIO130/SMB10_DATA/TOUT1)
PBAT_PRES#: PD1.3 PR1.2 PR40.2 PR724.1 UE1.F9(GPIO175)
PBAT_PRES#_C: PBATT1.6 PR40.1
PBAT_SMBCLK_C: PBATT1.4 PR38.1
PBAT_SMBDAT_C: PBATT1.5 PR39.1
PCH_2_CPU_TRIGGER: RH42.2 UC1.H23(PROC_TRIGIN)
PCH_2_CPU_TRIGGER_R: RH42.1 UH1.AK3(TRIGGER_OUT)
PCH_3.3V_TS_EN: RV324.1 UH1.BD30(GPP_B21/GSPI1_MISO)
PCH_BATLOW#: RH94.1 UH1.BF44(GPD0/BATLOW#)
PCH_CL_CLK1: JNGFF1.42(VENDOR_DEFINED3) UH1.AR2(CL_CLK)
PCH_CL_DATA1: JNGFF1.40(VENDOR_DEFINED2) UH1.AT5(CL_DATA)
PCH_CL_RST1#: JNGFF1.38(VENDER_DEFINED1) UH1.AU4(CL_RST#)
PCH_CPU_BCLK_D: RH161.2 UH1.B8(CLKOUT_CPUBCLK_P)
PCH_CPU_BCLK_D#: RH166.2 UH1.C8(CLKOUT_CPUBCLK#)
PCH_CPU_BCLK_R_D: RH161.1 UC1.B31(BCLKP)
PCH_CPU_BCLK_R_D#: RH166.1 UC1.A32(BCLKN)
PCH_CPU_NSSC_CLK_D: RH169.2 UH1.D7(CLKOUT_CPUNSSC_P)
PCH_CPU_NSSC_CLK_D#: RH170.2 UH1.C6(CLKOUT_CPUNSSC#)
PCH_CPU_PCIBCLK_D: RH167.1 UH1.A6(CLKOUT_CPUPCIBCLK_P)
PCH_CPU_PCIBCLK_D#: RH168.1 UH1.B6(CLKOUT_CPUPCIBCLK#)
PCH_CPU_PCIBCLK_R_D: RH167.2 UC1.D35(PCI_BCLKP)
PCH_CPU_PCIBCLK_R_D#: RH168.2 UC1.C36(PCI_BCLKN)
PCH_DP1_CTRL_CLK: RH222.1 UH1.AL13(GPP_I5/DDPB_CTRLCLK)
PCH_DP1_CTRL_DATA: RH223.1 UH1.AR8(GPP_I6/DDPB_CTRLDATA)
PCH_DP1_HPD: RT24.1 UH1.AT6(GPP_I0/DDPB_HPD0/DISP_MISC0) UT1.AA2(DPSNK0_HPD)
PCH_DP2_CTRL_DATA: RH221.1 UH1.AL10(GPP_I8/DDPC_CTRLDATA)
PCH_DP2_HPD: RT29.1 UH1.AN10(GPP_I1/DDPC_HPD1/DISP_MISC1) UT1.Y6(DPSNK1_HPD)
PCH_DP3_CTRL_CLK: RH224.1 UH1.AL9(GPP_I9/DDPD_CTRLCLK)
PCH_DP3_CTRL_DATA: RH225.1 UH1.AR3(GPP_I10/DDPD_CTRLDATA)
PCH_DP3_HPD: RV603.1 UH1.AP9(GPP_I2/DPPD_HPD2/DISP_MISC2)
PCH_DP3_HPD_R: RV603.2 UV31.B1(DP_HPD)
PCH_DPWROK: CH266.1 CH558.1 RE536.1 RH215.1 RH308.1 UH1.AW41(DSW_PWROK)
PCH_DPWROK_EC: RE536.2 UE1.F8(GPIO020)
PCH_HDD_EN: RH625.1 UH1.BD21(GPP_C15/UART1_CTS#/ISH_UART1_CT)
PCH_INTRUDER_HDR#: RH198.2 UH1.BB44(INTRUDER#)
PCH_JTAG_TCK: RC843.1 RH313.1 T188.1 UH1.AJ3(PCH_JTAG_TCK)
PCH_JTAG_TCK_XDP: JXDP1.55 RC843.2
PCH_JTAG_TDI: CC304.1 RC229.2 RH314.1 T187.1 UH1.AH2(PCH_JTAG_TDI)
PCH_JTAG_TDO: CC303.1 RC230.2 RH315.1 T186.1 UH1.AH3(PCH_JTAG_TDO)
PCH_JTAG_TMS: RC228.2 RH312.1 T183.1 UH1.AJ4(PCH_JTAG_TMS)
PCH_JTAGX: CC305.1 RC143.2 RC166.2 T182.1 UH1.AH4(PCH_JTAGX)
PCH_PCIE_WAKE#: RE274.2 RH92.1 RT445.1 UE1.L1(GPIO216/ADC14) UH1.BB47(WAKE#)
PCH_PECI: RH73.1 RH74.1 UH1.AF2(PECI)
PCH_PLTRST#: CH552.1 RH62.2 RH635.1 UH1.AV29(GPP_B13/PLTRST#) UH7.1(B) UH7.2(A)
PCH_PLTRST#_AND: JIRTS1.1 JNGFF1.52(PERST0#) JNGFF3.50(PERST#) RH65.1 RH187.2 RT499.1 RT502.1 RZ1481.2 UH7.4(Y) UR1.1(PERST#) UZ52.A1(B)
PCH_PRIM_EN: PR312.1 PR504.1 RH441.2 RH442.2 RZ64.1 UZ34.1(B)
PCH_PWROK: CH553.1 PRZ20.2 PUZ1.45(VR_RDY) RH424.1 UH1.AY42(PCH_PWROK)
PCH_RSMRST#: RE342.1 RZ400.1 RZ1413.1 UE1.M5(GPIO055/PWM2/SHD_CS#/(RSMRST#))
PCH_RSMRST#_AND: CC556.1 RC75.1 RC841.1 RH215.2 UH1.BA47(RSMRST#) UZ6.4(O)
PCH_RSMRST#_AND_XDP: RC124.1 RC841.2 T191.1
PCH_RTCRST#: CH40.2 CMOS1.2 JAPS1.9 RE94.2 RH200.2 UH1.BE47(RTCRST#)
PCH_RTCX1: RH43.2 RH44.1 UH1.BA49(RTCX1)
PCH_RTCX1_R: CH4.2 RH43.1 YH1.1
PCH_RTCX2: CH5.2 RH44.2 UH1.BA48(RTCX2) YH1.2
PCH_SMB_ALERT#: RH61.2 UH1.BE25(GPP_C2/SMBALERT#)
PCH_SPI_CLK: JSPI1.13 RH181.2 RH634.1 UH1.AW47(SPI0_CLK)
PCH_SPI_CLK_0_R: RH29.1 RH655.2 UC5.6(CLK)
PCH_SPI_CLK_1_R: RH28.1 RH659.2 UC6.6(CLK)
PCH_SPI_CLK_2_R: RZ60.2 RZ63.2 UZ12.19(SPI_CLK)
PCH_SPI_CLK_R1: JSPI1.14 RH181.1 RH655.1 RH659.1 RZ60.1
PCH_SPI_CS#0: JSPI1.11 RH182.2 UH1.AY47(SPI0_CS0#)
PCH_SPI_CS#0_R1: JSPI1.12 RH37.1 RH182.1
PCH_SPI_CS#0_R2: RH37.2 UC5.1(CS#)
PCH_SPI_CS#1: JSPI1.19 RH177.2 UH1.AW48(SPI0_CS1#)
PCH_SPI_CS#1_R1: JSPI1.20 RH177.1 RH352.1
PCH_SPI_CS#1_R3: RH352.2 UC6.1(CS#)
PCH_SPI_CS#2: RZ61.1 UH1.AT40(SPI0_CS2#)
PCH_SPI_CS#2_R: RZ61.2 UZ12.20(SPI_CS#)
PCH_SPI_D0: JSPI1.17 RC128.1 RH178.2 RH600.2 UH1.AU41(SPI0_MOSI)
PCH_SPI_D0_0_R: RH654.2 UC5.5(DI)
PCH_SPI_D0_1_R: RH658.2 UC6.5(DI(IO0))
PCH_SPI_D0_2_R: RZ59.2 UZ12.21(MOSI)
PCH_SPI_D0_R1: JSPI1.18 RH178.1 RH654.1 RH658.1 RZ59.1
PCH_SPI_D1: JSPI1.15 RH179.2 UH1.BA45(SPI0_MISO)
PCH_SPI_D1_0_R: RH653.2 UC5.2(DO)
PCH_SPI_D1_1_R: RH657.2 UC6.2(DO(IO1))
PCH_SPI_D1_2_R: RZ58.2 UZ12.24(MISO)
PCH_SPI_D1_R1: JSPI1.16 RH179.1 RH653.1 RH657.1 RZ58.1
PCH_SPI_D2: JSPI1.9 RH30.2 RH180.2 RH183.2 UH1.AY48(SPI0_IO2)
PCH_SPI_D2_0_R: RH351.2 UC5.3(WP#)
PCH_SPI_D2_1_R: RH353.2 UC6.3(IO2)
PCH_SPI_D2_R1: JSPI1.10 RH183.1 RH351.1 RH353.1
PCH_SPI_D2_XDP: RC127.2 RH180.1
PCH_SPI_D3: JSPI1.7 RH184.2 RH334.2 RH335.2 UH1.BA46(SPI0_IO3)
PCH_SPI_D3_0_R: RH656.2 UC5.7(HOLD#_RESET#)
PCH_SPI_D3_1_R: RH660.2 UC6.7(IO)
PCH_SPI_D3_R1: JSPI1.8 RH184.1 RH656.1 RH660.1
PCH_TBT_PERST#: RC557.1 RC558.1 RT500.1 RT554.1 UH1.AM48(GPP_F4/SATAXPCIE7/SATAGP7)
PCH_THERMTRIP#: RH75.1 UH1.AD3(THRMTRIP#)
PCH_XDP_CLK_DN: JXDP1.42 RH154.2
PCH_XDP_CLK_DN_R: RH154.1 UH1.Y3(CLKOUT_ITPXDP#)
PCH_XDP_CLK_DP: JXDP1.40 RH155.2
PCH_XDP_CLK_DP_R: RH155.1 UH1.Y4(CLKOUT_ITPXDP_P)
PCH_XDP_PRDY#: RC314.2 UH1.AM5(PRDY#)
PCH_XDP_PREQ#: RC315.2 UH1.AL2(PREQ#)
PCI_CLK_LPC1: T424.1 UH1.BB34(GPP_A10/CLKOUT_LPC1)
PCIE_PRX_C_DTX_N5: CL2.2 UL1.39(PETN)
PCIE_PRX_C_DTX_N6: CR14.2 UR1.8(HSON)
PCIE_PRX_C_DTX_P5: CL1.2 UL1.38(PETP)
PCIE_PRX_C_DTX_P6: CR13.2 UR1.7(HSOP)
PCIE_PRX_C_TTX_N1: CT7.1 UT1.V22(PCIE_TX0_N)
PCIE_PRX_C_TTX_N2: CT9.1 UT1.P22(PCIE_TX1_N)
PCIE_PRX_C_TTX_N3: CT128.1 UT1.K22(PCIE_TX2_N)
PCIE_PRX_C_TTX_N4: CT130.1 UT1.F22(PCIE_TX3_N)
PCIE_PRX_C_TTX_P1: CT6.1 UT1.V23(PCIE_TX0_P)
PCIE_PRX_C_TTX_P2: CT8.1 UT1.P23(PCIE_TX1_P)
PCIE_PRX_C_TTX_P3: CT127.1 UT1.K23(PCIE_TX2_P)
PCIE_PRX_C_TTX_P4: CT129.1 UT1.F23(PCIE_TX3_P)
PCIE_PRX_DTX_N5: CL2.1 UH1.F20(PCIE5_RXN)
PCIE_PRX_DTX_N6: CR14.1 UH1.K21(PCIE6_RXN)
PCIE_PRX_DTX_N7: JNGFF1.43(PERN0) UH1.L24(PCIE7_RXN)
PCIE_PRX_DTX_N9: JNGFF3.5(PERN3) UH1.G36(PCIE9_RXN)
PCIE_PRX_DTX_N10: JNGFF3.17(PERN2) UH1.K37(PCIE10_RXN)
PCIE_PRX_DTX_N11: JNGFF3.29(PERN1) UH1.G38(PCIE11_RXN/SATA0A_RXN)
PCIE_PRX_DTX_N12: JNGFF3.43(PERP0/SATA-B-) UH1.H42(PCIE12_RXN/SATA1A_RXN)
PCIE_PRX_DTX_N17: JNGFF2.43(PET_P0) UH1.K43(PCIE17_RXN/SATA4_RXN)
PCIE_PRX_DTX_N18: UH1.P41(PCIE18_RXN/SATA5_RXN) UZ29.14(C0-)
PCIE_PRX_DTX_P5: CL1.1 UH1.G20(PCIE5_RXP)
PCIE_PRX_DTX_P6: CR13.1 UH1.J21(PCIE6_RXP)
PCIE_PRX_DTX_P7: JNGFF1.41(PERP0) UH1.J24(PCIE7_RXP)
PCIE_PRX_DTX_P9: JNGFF3.7(PERP3) UH1.F36(PCIE9_RXP)
PCIE_PRX_DTX_P10: JNGFF3.19(PERP2) UH1.J37(PCIE10_RXP)
PCIE_PRX_DTX_P11: JNGFF3.31(PERP1) UH1.F39(PCIE11_RXP/SATA0A_RXP)
PCIE_PRX_DTX_P12: JNGFF3.41(PERN0/SATA-B+) UH1.J41(PCIE12_RXP/SATA_1A_RXP)
PCIE_PRX_DTX_P17: JNGFF2.41(PET_N0) UH1.K44(PCIE17_RXP/SATA4_RXP)
PCIE_PRX_DTX_P18: UH1.R40(PCIE18_RXP/SATA5_RXP) UZ29.15(C0+)
PCIE_PRX_L_DTX_N18: JNGFF2.29(USB3.0_TX_N) LI16.2 RI27.2
PCIE_PRX_L_DTX_P18: JNGFF2.31(USB3.0_TX_P) LI16.3 RI28.2
PCIE_PRX_SW_DTX_N18: LI16.1 RI27.1 UZ29.4(A0-)
PCIE_PRX_SW_DTX_P18: LI16.4 RI28.1 UZ29.3(A0+)
PCIE_PRX_TTX_N1: CT7.2 UH1.G17(PCIE1_RXN/USB31_7_RXN)
PCIE_PRX_TTX_N2: CT9.2 UH1.R21(PCIE2_RXN/USB31_8_RXN)
PCIE_PRX_TTX_N3: CT128.2 UH1.K18(PCIE3_RXN/USB31_9_RXN)
PCIE_PRX_TTX_N4: CT130.2 UH1.N18(PCIE4_RXN/USB31_10_RXN)
PCIE_PRX_TTX_P1: CT6.2 UH1.F16(PCIE1_RXP/USB31_7_RXP)
PCIE_PRX_TTX_P2: CT8.2 UH1.P21(PCIE2_RXP/USB31_8_RXP)
PCIE_PRX_TTX_P3: CT127.2 UH1.J18(PCIE3_RXP/USB31_9_RXP)
PCIE_PRX_TTX_P4: CT129.2 UH1.R18(PCIE4_RXP/USB31_10_RXP)
PCIE_PTX_C_DRX_N5: CL6.2 UL1.42(PERN)
PCIE_PTX_C_DRX_N6: CR12.2 UR1.4(HSIN)
PCIE_PTX_C_DRX_N7: CZ13.2 JNGFF1.37(PETN0)
PCIE_PTX_C_DRX_N9: CN65.1 JNGFF3.11(PETN3)
PCIE_PTX_C_DRX_N10: CN67.1 JNGFF3.23(PETN2)
PCIE_PTX_C_DRX_N11: CN69.1 JNGFF3.35(PETN1)
PCIE_PTX_C_DRX_N12: CN71.1 JNGFF3.47(PETN0/SATA-A-)
PCIE_PTX_C_DRX_N17: CZ10.2 JNGFF2.47(PER_N0)
PCIE_PTX_C_DRX_P5: CL5.2 UL1.41(PERP)
PCIE_PTX_C_DRX_P6: CR11.2 UR1.3(HSIP)
PCIE_PTX_C_DRX_P7: CZ12.2 JNGFF1.35(PETP0)
PCIE_PTX_C_DRX_P9: CN66.1 JNGFF3.13(PETP3)
PCIE_PTX_C_DRX_P10: CN68.1 JNGFF3.25(PETP2)
PCIE_PTX_C_DRX_P11: CN70.1 JNGFF3.37(PETP1)
PCIE_PTX_C_DRX_P12: CN72.1 JNGFF3.49(PETP0/SATA-A+)
PCIE_PTX_C_DRX_P17: CZ11.2 JNGFF2.49(PER_P0)
PCIE_PTX_C_SW_DRX_N18: CZ153.2 UZ29.12(C1-)
PCIE_PTX_C_SW_DRX_P18: CZ152.2 UZ29.13(C1+)
PCIE_PTX_C_TRX_N1: CT3.2 UT1.Y22(PCIE_RX0_N)
PCIE_PTX_C_TRX_N2: CT5.2 UT1.T22(PCIE_RX1_N)
PCIE_PTX_C_TRX_N3: CT124.2 UT1.M22(PCIE_RX2_N)
PCIE_PTX_C_TRX_N4: CT126.2 UT1.H22(PCIE_RX3_N)
PCIE_PTX_C_TRX_P1: CT2.2 UT1.Y23(PCIE_RX0_P)
PCIE_PTX_C_TRX_P2: CT4.2 UT1.T23(PCIE_RX1_P)
PCIE_PTX_C_TRX_P3: CT123.2 UT1.M23(PCIE_RX2_P)
PCIE_PTX_C_TRX_P4: CT125.2 UT1.H23(PCIE_RX3_P)
PCIE_PTX_DRX_N5: CL6.1 UH1.B21(PCIE5_TXN)
PCIE_PTX_DRX_N6: CR12.1 UH1.D21(PCIE6_TXN)
PCIE_PTX_DRX_N7: CZ13.1 UH1.C23(PCIE7_TXN)
PCIE_PTX_DRX_N9: CN65.2 UH1.C34(PCIE9_TXN)
PCIE_PTX_DRX_N10: CN67.2 UH1.C35(PCIE10_TXN)
PCIE_PTX_DRX_N11: CN69.2 UH1.B36(PCIE11_TXN/SATA0A_TXN)
PCIE_PTX_DRX_N12: CN71.2 UH1.D38(PCIE12_TXN/SATA1A_TXN)
PCIE_PTX_DRX_N17: CZ10.1 UH1.A42(PCIE17_TXN/SATA4_TXN)
PCIE_PTX_DRX_N18: CZ153.1 UH1.C42(PCIE18_TXN/SATA5_TXN)
PCIE_PTX_DRX_P5: CL5.1 UH1.A22(PCIE5_TXP)
PCIE_PTX_DRX_P6: CR11.1 UH1.C21(PCIE6_TXP)
PCIE_PTX_DRX_P7: CZ12.1 UH1.B23(PCIE7_TXP)
PCIE_PTX_DRX_P9: CN66.2 UH1.D34(PCIE9_TXP)
PCIE_PTX_DRX_P10: CN68.2 UH1.B35(PCIE10_TXP)
PCIE_PTX_DRX_P11: CN70.2 UH1.C36(PCIE11_TXP/SATA0A_TXP)
PCIE_PTX_DRX_P12: CN72.2 UH1.E37(PCIE12_TXP/SATA1A_TXP)
PCIE_PTX_DRX_P17: CZ11.1 UH1.B42(PCIE17_TXP/SATA4_TXP)
PCIE_PTX_DRX_P18: CZ152.1 UH1.D42(PCIE18_TXP/SATA5_TXP)
PCIE_PTX_L_DRX_N18: JNGFF2.35(USB3.0_RX_N) LI17.2 RI29.2
PCIE_PTX_L_DRX_P18: JNGFF2.37(USB3.0_RX_P) LI17.3 RI30.2
PCIE_PTX_SW_DRX_N18: LI17.1 RI29.1 UZ29.8(A1-)
PCIE_PTX_SW_DRX_P18: LI17.4 RI30.1 UZ29.7(A1+)
PCIE_PTX_TRX_N1: CT3.1 UH1.A17(PCIE1_TXN/USB31_7_TXN)
PCIE_PTX_TRX_N2: CT5.1 UH1.B18(PCIE2_TXN/USB31_8_TXN)
PCIE_PTX_TRX_N3: CT124.1 UH1.B19(PCIE3_TXN/USB31_9_TXN)
PCIE_PTX_TRX_N4: CT126.1 UH1.D20(PCIE4_TXN/USB31_10_TXN)
PCIE_PTX_TRX_P1: CT2.1 UH1.B17(PCIE1_TXP/USB31_7_TXP)
PCIE_PTX_TRX_P2: CT4.1 UH1.C18(PCIE2_TXP/USB31_8_TXP)
PCIE_PTX_TRX_P3: CT123.1 UH1.C19(PCIE3_TXP/USB31_9_TXP)
PCIE_PTX_TRX_P4: CT125.1 UH1.C20(PCIE4_TXP/USB31_10_TXP)
PCIE_WAKE#: JNGFF1.55(PEWAKE0#) JNGFF3.54(PEWAKE#) RE274.1 RE275.1 RT448.1 UZ51.1(B2)
PCIE_WAKE#_AR: RT441.2 RT455.1 RT555.2 UT1.W1(GPIO_4)
PCIE_WAKE#_AR_R: RT440.2 RT441.1 UT32.4(COM)
PCIE_WAKE#_R: RE35.1 RE275.2 UE1.N13(GPIO025/TIN0/NEM_INT/UART_CLK)
PCIECOMP: RH192.1 UH1.A13(PCIE_RCOMPP)
PCIECOMP#: RH192.2 UH1.B12(PCIE_RCOMPN)
PD1_GPIO0: RT69.1 UT5.B2(GPIO0)
PD1_GPIO2: RT71.1 UT5.D10(GPIO2)
PD1_GPIO5: RT74.1 UT5.E10(GPIO5)
PD1_GPIO6: RT75.1 UT5.G10(GPIO6)
PD1_GPIO7: RT339.1 UT5.D7(GPIO7)
PD1_GPIO8: RT76.1 RT377.1 UT5.H6(GPIO8)
PD#: CA31.1 DA8.2 RA18.1 RA48.2 RA50.2 UA1.40(PDB)
PECI_EC_R: RE60.1 UE1.K13(GPIO042/PECI_DAT/SB-TSI_DAT)
PEG_COMP: RC2.2 UC1.G2(PEG_RCOMP)
PG_1.05VALWP: PR1711.2 PR1712.1 PU301.9(PG)
PGOOD_3V: PR107.2 PR119.1 PU100.9(PG)
PGOOD_5V: PR113.2 PR120.1 PU102.9(PG)
PLTRST_CPU#: CC549.1 CH550.1 UC1.BP35(RESET#) UH1.AG5(PLTRST_CPU#)
PLTRST_LAN#: RH62.1 UL1.36(PE_RST_N)
PLTRST_TPM#: RH187.1 UZ12.17(SPI_RST#)
PM_LANPHY_ENABLE: RL7.1 UH1.BF41(GPD11/LANPHYPC)
POWER_SW#_MB: CE10.1 JAPS1.11 RE33.2 RZ1414.1 SW3.2 SW3.4
POWER_SW#_MB_USH: JUSH1.26 RZ1414.2
POWER_SW_IN#: CE12.1 QZ21.3(EMITTER) RE31.2 RE33.1 UE1.D5(GPIO163/VCI_IN0#)
PROCHOT#: CC324.1 PR719.1 PR745.1 PRZ6.2 PRZ16.2 RC83.2 RC84.1 RE288.2
PROCHOT#_CHG: PQ812.1(D) PR719.2 PU700.23(PROCHOT#)
PROCHOT#_R1: RE288.1 UE1.H13(GPIO160/PWM11/PROCHOT#)
PROG_CHG: PR725.1 PU700.27(PROG)
PROM_BIOS: RZ400.2 RZ401.2 UZ6.1(B)
PROM_BIOS_R: JSPI1.4 RZ401.1
PS_ID: PR4.1 PR5.2 UE1.J8(GPIO056/PWM3/SHD_CLK)
PSYS_CHG: PR731.1 PU700.30(PSYS)
PTP_DISABLE#: RE605.1 RZ1475.1 UE1.N12(GPIO026/TIN1)
PTP_DISABLE#_R: JKBTP1.11 RZ1475.2
PWM1_1PH/ICCMAX1_CPU: PRZ26.1 PUA1.1(PWM) PUZ1.44(PWM_1PH/ICCMAX_1PH)
PWM1_2PH/ICCMAX2_CPU: PRZ63.1 PUT1.1(PWM) PUZ1.23(PWM1_2PH/ICCMAX_2PH)
PWM1_4PH/ICCMAX4_CPU: PRZ66.1 PUH1.1(PWM) PUZ1.18(PWM1_4PH/ICCMAX_4PH)
PWM2_2PH/ROSC1_CPU: PRZ70.1 PUZ1.22(PWM2_2PH/ROSC_1PH)
PWM2_4PH/ADDR_CPU: PRZ67.1 PUH2.1(PWM) PUZ1.19(PWM2_4PH/ADDR)
PWM3_4PH/VBOOT_CPU: PRZ68.1 PUH3.1(PWM) PUZ1.20(PWM3_4PH/VBOOT)
PWM4_4PH/ROSCM_CPU: PRZ69.1 PUH4.1(PWM) PUZ1.21(PWM4_4PH/ROSC_MPH)
PWM_FAN1: JFAN1.2 RE48.2 UE1.L10(GPIO053/PWM0/GPWM0)
REFCLK_CNV: CH554.1 JNGFF1.64(RESERVED) RH110.1 UH1.R6(CLKIN_XTAL)
REM_DIODE1_N: CE24.1 CE35.1 QE3.3(EMITTER) UE1.A8(DN1_DP1A)
REM_DIODE1_P: CE24.2 CE35.2 QE3.1(COLLECTOR) QE3.2(BASE) UE1.A7(DP1_DN1A)
REM_DIODE2_N: CE26.1 CE37.2 CE46.2 QE5.3(EMITTER) QE7.1(COLLECTOR) QE7.2(BASE) UE1.A10(DN2_DP2A)
REM_DIODE2_P: CE26.2 CE37.1 CE46.1 QE5.1(COLLECTOR) QE5.2(BASE) QE7.3(EMITTER) UE1.A9(DP2_DN2A)
REM_DIODE4_N: CE27.1 CE39.1 QE6.3(EMITTER) UE1.A11(DN4_DP4A)
REM_DIODE4_P: CE27.2 CE39.2 QE6.1(COLLECTOR) QE6.2(BASE) UE1.B10(DP4_DN4A)
RES_BIAS: RL13.1 UL1.12(RBIAS)
RESERVE: DT41.2 DT41.8 JFPBTN1.10 T418.1
RESET_IN#: RE362.1 UE1.C1(GPIO024/NRESETI)
RESET_OUT: RE548.2 UE1.G4(GPIO106/PWROK)
RING2: LA10.1 RA5.2 UA1.13(MIC2-L/RING2)
RING2_R: CA4.1 CA13.2 DA3.2 JHP1.4(#4 G/M) LA10.2
RJ45_MDIN0: JLOM1.2(PR1-) TL1.22(MX1-)
RJ45_MDIN1: JLOM1.6(PR2-) TL1.19(MX2-)
RJ45_MDIN2: JLOM1.5(PR3-) TL1.16(MX3-)
RJ45_MDIN3: JLOM1.8(PR4-) TL1.13(MX4-)
RJ45_MDIP0: JLOM1.1(PR1+) TL1.23(MX1+)
RJ45_MDIP1: JLOM1.3(PR2+) TL1.20(MX2+)
RJ45_MDIP2: JLOM1.4(PR3+) TL1.17(MX3+)
RJ45_MDIP3: JLOM1.7(PR4+) TL1.14(MX4+)
RTC_DET#: PQ13.1(DRAIN) RC866.2 UH1.BF18(GPP_D3/SPI1_MOSI/SBK3_BK3)
RTCRST_ON: QE12.2(G) RE93.1 UE1.F11(GPIO122/BCM0_DAT/PVT_IO1)
RTCRST_ON_POWER: RE565.2 UE1.B13(GPIO127/A20M/UART0_CTS#)
RTCRST_ON_R: CE65.1 DE2.2 QE17.2(G) RE543.1
RTCRST_ON_R1: CE64.1 DE2.1 QE15.2(G) RE541.2 RE543.2 RE565.1
RTD3_CIO_PWR_EN: RC559.2 RT392.2 UH1.AE43(GPP_H16/SML4CLK)
RTD3_CIO_PWR_EN_R: RT25.1 RT372.1 RT392.1 UT1.F1(POC_GPIO_6)
RTD3_SELECT: RE509.1 RT447.2 UT32.6(IN)
RTD3_SELECT_EC: RE509.2 UE1.F13(GPIO121/PVT_IO0)
RTD3_USB_PWR_EN: RT26.1 UT1.D4(POC_GPIO_2)
RUN_ON: PR402.1 QE2.2(G1) RE280.2 RE292.1 RZ320.1 RZ345.1 UE5.4(O) UZ3.5(ON2) UZ4.3(ON1) UZ35.2(IN2) UZ54.1(INB)
RUN_ON#: QE2.5(G1) QE2.6(D1) RE68.1
RUN_ON_1.8V: CZ197.1 RZ345.2 UZ8.3(ON)
RUN_ON_EC: DE43.1 RE292.2 RE718.2 UE1.E8(GPIO045) UE5.2(A)
RUNPWROK: CE549.1 QE2.3(D1) RE67.1 UE1.G3(GPIO057/VCC_PWRGD)
S1_OVP: PQ10.3(D2) PR32.2 PR46.1 PR836.2
SATA_PRX_C_DTX_N2: CN6.1 JSATA1.5
SATA_PRX_C_DTX_P2: CN7.1 JSATA1.6
SATA_PRX_C_RD_DTX_N2: CN14.2 UN7.4(BO-)
SATA_PRX_C_RD_DTX_P2: CN15.2 UN7.5(BO+)
SATA_PRX_DTX_N2: CN14.1 UH1.F44(PCIE15_RXN/SATA2_RXN)
SATA_PRX_DTX_P2: CN15.1 UH1.E45(PCIE15_RXP/SATA2_RXP)
SATA_PRX_RD_DTX_N2: CN6.2 UN7.12(BI-)
SATA_PRX_RD_DTX_P2: CN7.2 UN7.11(BI+)
SATA_PTX_C_DRX_N2: CN5.1 JSATA1.3
SATA_PTX_C_DRX_P2: CN4.1 JSATA1.2
SATA_PTX_C_RD_DRX_N2: CN13.2 UN7.2(AI-)
SATA_PTX_C_RD_DRX_P2: CN12.2 UN7.1(AI+)
SATA_PTX_DRX_N2: CN13.1 UH1.B40(PCIE_15_SATA_2_TXN)
SATA_PTX_DRX_P2: CN12.1 UH1.C40(PCIE15_TXP/SATA2_TXP)
SATA_PTX_RD_DRX_N2: CN5.2 UN7.14(AO-)
SATA_PTX_RD_DRX_P2: CN4.2 UN7.15(AO+)
SATAGP0: RH316.2 RH377.2 UH1.AH41(GPP_E0/SATAXPCIE0/SATAGP0)
SATAGP3: RH323.2 UH1.AN47(GPP_F0/SATAXPCIE3/SATAGP_3)
SATAGP5: RH325.2 UH1.AM43(GPP_F2/SATAXPCIE5/SATAGP5)
SATAGP6: RH326.2 UH1.AM47(GPP_F3/SATAXPCIE6/SATAGP6)
SBIOS_TX: RE306.1 UH1.BB24(GPP_C9/UART0A_TXD)
SCL_CHG: PR715.2 PU700.22(SCL)
SD_1_CD#: JSD1.9(CD) UR1.30(SD_CD#)
SD_1_CLK: RR5.1 UR1.17(SP3)
SD_1_CLK_R: CR21.1 JSD1.5(CLK) RR5.2
SD_1_CMD: RR6.1 UR1.19(SP4)
SD_1_CMD_R: JSD1.3(CMD) RR6.2
SD_1_DAT0: RR10.1 UR1.16(SP2)
SD_1_DAT0_R: JSD1.7(DAT0/RCLK+) RR10.2
SD_1_DAT1: RR9.1 UR1.15(SP1)
SD_1_DAT1_R: JSD1.8(DAT1/RCLK-) RR9.2
SD_1_DAT2: RR8.1 UR1.21(SP6)
SD_1_DAT2_R: JSD1.1(DAT2) RR8.2
SD_1_DAT3: RR7.1 UR1.20(SP5)
SD_1_DAT3_R: JSD1.2(CD/DAT3) RR7.2
SD_1_N0: JSD1.19(D0-) UR1.25(SD_LN0_M)
SD_1_N1: JSD1.21(D1-) UR1.23(SD_LN1_M)
SD_1_P0: JSD1.18(D0+) UR1.26(SD_LN0_P)
SD_1_P1: JSD1.22(D1+) UR1.22(SD_LN1_P)
SD_GPIO: RR3.2 UR1.28(GPIO)
SD_RCOMP_1P8: RH611.2 UH1.BE5(SD_1P8_RCOMP)
SD_RCOMP_3P3: RH610.2 UH1.BE4(SD_3P3_RCOMP)
SDA_CHG: PR713.2 PU700.21(SDA)
SDWP: QR1.1(D) UR1.29(SP7)
SIM_DET: DZ13.5 DZ13.6 JNGFF2.66(SIM_DETECT) JSIM1.2(DTSW)
SIO_EXT_SMI#: RH310.2 UH1.AL47(GPP_E3/CPU_GP0)
SIO_EXT_WAKE#: RE703.1 RH309.2 UH1.AU24(GPP_C12/UART1_RXD/ISH_UART1_RXD)
SIO_EXT_WAKE#_EC: RE703.2 UE1.M12(GPIO120)
SIO_PWRBTN#: RC842.1 UE1.K11(GPIO113/PS2_DAT1A) UH1.BE46(GPD3/PWRBTN#)
SIO_PWRBTN#_XDP: CC269.1 JXDP1.41 RC241.2 RC842.2
SIO_RCIN#: T286.1 UH1.BE39(GPP_A0/RCIN#/ESPI_ALERT1#)
SIO_SLP_A#: CH343.1 JAPS1.6 RH628.1 UH1.BE40(GPD6/SLP_A#)
SIO_SLP_LAN#: CH346.1 RH204.1 RH631.1 UH1.BF40(SLP_LAN#) UZ2.5(ON2)
SIO_SLP_S0#: DN1.1 JAPS1.15 PR425.1 RH619.1 RH640.1 RZ112.1 RZ362.2 RZ1407.1 UH1.BC28(GPP_B12/SLP_S0#)
SIO_SLP_S3#: CH341.1 JAPS1.2 QE11.2(G) RE280.1 RH626.1 UE3.2(A) UE5.1(B) UH1.BF42(GPD4/SLP_S3#) UT1.D2(POC_GPIO_5)
SIO_SLP_S4#: CH342.1 JAPS1.5 PR208.1 PR513.1 RH627.1 UH1.BE42(GPD5/SLP_S4#) UZ21.4(ON) UZ34.2(A)
SIO_SLP_S4#_R: PC221.1 PR208.2 PR209.1 PU200.1(S5)
SIO_SLP_S5#: CH347.1 JAPS1.4 RH632.1 UH1.BC42(GPD10/SLP_S5#)
SIO_SLP_SUS#: CH345.1 RE349.1 RH441.1 RH630.1 UH1.BD39(SLP_SUS#)
SIO_SLP_SUS#_R: RE349.2 RE561.1 UE1.N4(GPIO230)
SIO_SLP_WLAN#: CH344.1 QZ15.1(D) RH629.1 UH1.BD42(GPD9/SLP_WLAN#)
SKL_CNL#: RC171.2 UC1.BN1(PROC_SELECT#)
SLEEVE: LA11.1 RA6.2 UA1.14(MIC2-R/SLEEVE)
SLEEVE_R: CA1.1 CA12.1 DA3.3 JHP1.3(#3 M/G) LA11.2
SLP_WLAN#_GATE: QZ15.2(G) RZ518.2 UE1.K10(GPIO114/PS2_CLK0A/NEC_SCI)
SLP_WLAN#_M: DZ9.3 QZ15.3(S) RZ71.1
SML0_SMBCLK: CC318.1 RH67.2 UH1.BF25(GPP_C3/SML0CLK) UL1.28(SMB_CLK)
SML0_SMBDATA: RH77.2 UH1.BE24(GPP_C4/SML0DATA) UL1.31(SMB_DATA)
SML1_SMBCLK: CC319.1 RH80.2 UE1.D8(GPIO010/SMB03_CLK/PS2_DAT0B) UH1.BF27(GPP_C6/SML1CLK)
SML1_SMBDATA: RH81.2 UE1.E11(GPIO007/SMB03_DATA/PS2_CLK0B) UH1.BE27(GPP_C7/SML1DATA)
SNK0_CONFIG1: RT129.1 RT337.1 UT1.N4(DPSNK1_DDC_DATA)
SNUB1_CHG: PC746.1 PR717.2
SNUB2_CHG: PC747.1 PR718.2
SNUB_1.05VALWP: PC302.1 PR303.2
SNUB_1.8VALW: PC506.1 PR502.2
SNUB_1VS_VCCIO: PC401.1 PR405.2
SNUB_3V: PC112.1 PR106.2
SNUB_5V: PC125.1 PR112.2
SNUB_DDR: PC204.1 PR202.2
SPKR: RA12.2 RH86.2 UH1.AW29(GPP_B14/SPKR)
SPKR_R: CA27.1 CA72.1 RA12.1 RA51.1
SRTCRST#: CH41.2 RH201.2 UH1.BD46(SRTCRST#)
SS_1VS_VCCIO: PC2212.1 PR1708.1 PU401.7(MODE)
SSD_EN: RZ1471.2 UZ53.3(ON) UZ54.4(O)
SSD_SCP#: RE821.1 RN129.2 UE1.L6(GPIO224/GPTP-IN4/SHD_IO1)
SSD_SCP#_R: JNGFF3.8(NC_2) RN129.1
SSD_SCP_PWR_EN: QZ24.3(S) UE1.M1(GPIO100/NEC_SCI)
SSD_SCP_PWR_EN_D: QZ24.1(D) RZ1471.1 RZ1472.2 RZ1474.1 UZ54.2(INA)
SUSACK#_R: T421.1 UH1.BE35(GPP_A15/SUSACK#)
SUSCLK: RH83.1 RN99.2 RZ56.1 UH1.BE45(GPD8/SUSCLK)
SUSCLK_R: JNGFF3.68(SUSCLK(32KHZ)) RN99.1
SVID_ALERT#_PWR_CPU: PRZ21.1 PUZ1.41(ALERT#)
SVID_CLK_PWR_CPU: PRZ19.1 PUZ1.42(SCLK)
SVID_DAT_PWR_CPU: PRZ23.1 PUZ1.40(SDIO)
SW_TBT_A_USB20_N1: RT122.2 UT5.L7(C_USB_BN)
SW_TBT_A_USB20_N1_R: DT40.1 DT40.9 JUSBC1.A7(DN1) RT122.1
SW_TBT_A_USB20_N2: RT121.1 UT5.L6(C_USB_TN)
SW_TBT_A_USB20_N2_R: DT39.4 DT39.7 JUSBC1.B7(DN2) RT121.2
SW_TBT_A_USB20_P1: RT123.2 UT5.K7(C_USB_BP)
SW_TBT_A_USB20_P1_R: DT40.2 DT40.8 JUSBC1.A6(DP1) RT123.1
SW_TBT_A_USB20_P2: RT120.1 UT5.K6(C_USB_TP)
SW_TBT_A_USB20_P2_R: DT39.5 DT39.6 JUSBC1.B6(DP2) RT120.2
SYS_PWROK: CE548.1 RC129.1 RE56.1 RE548.1 RH199.1 UH1.AU3(SYS_PWROK)
SYS_PWROK_R: CC33.1 JXDP1.47 RC128.2 RC129.2 RC133.2
SYS_RESET#: CC302.1 JAPS1.13 RH66.2 UC3.4(Y) UH1.AU2(SYS_RESET#)
SYSTEM_ID: CE47.1 RE300.2 UE1.J10(GPIO034/RC_ID1/SPI0_CLK)
TACH_FAN1: JFAN1.3 RE51.2 UE1.E3(GPIO050/FAN_TACH0/GTACH0)
TBT_A_TRX_C_DTX_N0: CT327.2 JUSBC1.A10(SSRXN2) RT220.1
TBT_A_TRX_C_DTX_N1: CT329.2 JUSBC1.B10(SSRXN1) RT222.1
TBT_A_TRX_C_DTX_P0: CT326.2 JUSBC1.A11(SSRXP2) RT219.1
TBT_A_TRX_C_DTX_P1: CT328.2 JUSBC1.B11(SSRXP1) RT221.1
TBT_A_TRX_DTX_N0: RT191.1 UT1.A21(PA_RX0_N)
TBT_A_TRX_DTX_N1: RT195.1 UT1.B15(PA_RX1_N)
TBT_A_TRX_DTX_P0: RT190.1 UT1.B21(PA_RX0_P)
TBT_A_TRX_DTX_P1: RT194.1 UT1.A15(PA_RX1_P)
TBT_A_TRX_R_DTX_N0: CT327.1 DT14.1 RT191.2
TBT_A_TRX_R_DTX_N1: CT329.1 DT10.1 RT195.2
TBT_A_TRX_R_DTX_P0: CT326.1 DT13.1 RT190.2
TBT_A_TRX_R_DTX_P1: CT328.1 DT9.1 RT194.2
TBT_A_TTX_C_DRX_N0: CT96.2 JUSBC1.B3(SSTXN2) RT489.1
TBT_A_TTX_C_DRX_N1: CT98.2 JUSBC1.A3(SSTXN1) RT490.1
TBT_A_TTX_C_DRX_P0: CT95.2 JUSBC1.B2(SSTXP2) RT488.1
TBT_A_TTX_C_DRX_P1: CT97.2 JUSBC1.A2(SSTXP1) RT491.1
TBT_A_TTX_DRX_N0: RT193.1 UT1.B19(PA_TX0_N)
TBT_A_TTX_DRX_N1: RT197.1 UT1.B17(PA_TX1_N)
TBT_A_TTX_DRX_P0: RT192.1 UT1.A19(PA_TX0_P)
TBT_A_TTX_DRX_P1: RT196.1 UT1.A17(PA_TX1_P)
TBT_A_TTX_R_DRX_N0: CT96.1 DT6.1 RT193.2
TBT_A_TTX_R_DRX_N1: CT98.1 DT18.1 RT197.2
TBT_A_TTX_R_DRX_P0: CT95.1 DT5.1 RT192.2
TBT_A_TTX_R_DRX_P1: CT97.1 DT17.1 RT196.2
TBT_CIO_PLUG_EVENT#: RT371.1 RT391.1 UH1.BF8(GPP_G2/SD_DATA1) UT1.W2(GPIO_5)
TBT_DP_RBIAS: RT35.1 UT1.N6(DPSRC_RBIAS)
TBT_FORCE_PWR: RT27.1 UH1.BE15(GPP_D4/ISH_I2C2_SDA/I2C3_SDA/SB) UT1.H4(POC_GPIO_3)
TBT_I2C_SCL: RT19.1 UT1.U2(GPIO_1) UT5.D2(I2C_SCL1)
TBT_I2C_SDA: RT18.1 UT1.U1(GPIO_0) UT5.D1(I2C_SDA1)
TBT_JTAG_TCK: RT6.1 UT1.T4(TCK)
TBT_JTAG_TDI: RT8.1 UT1.Y4(TDI)
TBT_JTAG_TDO: RT5.1 UT1.W4(TDO)
TBT_JTAG_TMS: RT7.1 UT1.V4(TMS)
TBT_PCIE_RBIAS: RT34.1 UT1.N16(PCIE_RBIAS)
TBT_PERST#: RT501.2 RT502.2 RT554.2 UT1.L4(PERST_N)
TBT_PERST#_R: RT501.1 RT503.2 UT34.4(O)
TBT_RBIAS: RT39.2 UT1.H6(RBIAS)
TBT_RESET_N_EC: RE506.1 RT11.1 RT110.2 UT1.F4(RESET_N)
TBT_RESET_N_EC_R: RE95.2 RE506.2 UE1.D1(GPIO051/FAN_TACH1/GTACH1)
TBT_ROM_CLK: UT1.AB4(EE_CLK) UT2.6(CLK)
TBT_ROM_CS#: RT2.1 UT1.AC3(EE_CS_N) UT2.1(CS#)
TBT_ROM_DI: UT1.AB3(EE_DI) UT2.5(DI(IO0))
TBT_ROM_DO: RT3.1 UT1.AC4(EE_DO) UT2.2(DO(IO1))
TBT_ROM_HOLD#: RT1.1 UT2.7(HOLD#(IO3))
TBT_ROM_WP#: RT4.1 UT1.V1(GPIO_2) UT2.3(WP#(IO2))
TBT_RSENSE: RT39.1 UT1.J6(RSENSE)
TBT_RTD3_WAKE#: RH662.2 RH663.2 RT456.1 RT555.1
TBT_RTD3_WAKE#_GPD7: RH602.1 RH662.1 UH1.BE41(GPD7)
TBT_RTD3_WAKE#_K18: RH661.2 RH663.1 UH1.T47(GPP_K18/NMI#)
TBT_SRC_CFG1: RT30.1 RT338.1 UT1.AA1(GPIO_8)
TBT_SRC_HPD: RT184.1 UT1.G1(DPSRC_HPD)
TBT_TMU_CLK_OUT: RT28.1 UT1.V2(GPIO_3)
TBTA_AUXN: CT81.1 UT1.W15(PA_DPSRC_AUX_N)
TBTA_AUXN_C: CT81.2 RT95.1 UT5.J2(AUX_N)
TBTA_AUXP: CT80.1 UT1.Y15(PA_DPSRC_AUX_P)
TBTA_AUXP_C: CT80.2 RT96.1 UT5.J1(AUX_P)
TBTA_CC1: CT86.1 DT40.4 DT40.7 JUSBC1.B5(CC2) RT104.2 UT5.L9(C_CC1)
TBTA_CC2: CT85.1 DT40.5 DT40.6 JUSBC1.A5(CC1) RT105.2 UT5.L10(C_CC2)
TBTA_DBG_CTL1: RT106.1 UT5.E4(DEBUG_CTL1)
TBTA_DBG_CTL2: RT107.1 UT5.D5(DEBUG_CTL2)
TBTA_DEBUG1: RT92.2 UT5.L2(DEBUG1)
TBTA_DEBUG2: RT93.2 UT5.K2(DEBUG2)
TBTA_DEBUG3: RT89.2 UT5.L3(DIG_AUD_P/DEBUG3)
TBTA_DEBUG4: RT90.2 UT5.K3(DIG_AUD_N/DEBUG4)
TBTA_HPD: RT23.1 RT73.2 UT1.M4(PA_DPSRC_HPD)
TBTA_HPD_R: RT73.1 UT5.C10(GPIO4)
TBTA_I2C_INT: RT16.1 UT1.J4(POC_GPIO_0) UT5.C1(I2C_IRQ1_N)
TBTA_LSRX: RT21.1 RT88.1 RT90.1 UT1.A4(PA_LSRX)
TBTA_LSRX_R: RT88.2 UT5.K4(TBT_LSRX/P2R)
TBTA_LSTX: RT22.1 RT87.1 RT89.1 UT1.A5(PA_LSTX)
TBTA_LSTX_R: RT87.2 UT5.L4(TBT_LSTX/R2P)
TBTA_MRESET: RT86.1 UT5.E11(MRESET)
TBTA_RESET_N_EC_R: RT110.1 UT5.F11(RESET_N)
TBTA_ROM_CLK_PD: RT54.1 UT5.A3(SPI_CLK)
TBTA_ROM_CLK_PD_R: RT54.2 UT6.6(CLK)
TBTA_ROM_CS#_PD: RT57.1 UT5.B3(SPI_SS_N)
TBTA_ROM_CS#_PD_R: RT51.1 RT57.2 UT6.1(CS#)
TBTA_ROM_DI_PD: RT55.1 UT5.B4(SPI_MOSI)
TBTA_ROM_DI_PD_R: RT55.2 UT6.5(DI(IO0))
TBTA_ROM_DO_PD: RT56.1 UT5.A4(SPI_MISO)
TBTA_ROM_DO_PD_R: RT52.1 RT56.2 UT6.2(DO(IO1))
TBTA_ROM_HOLD#_PD: RT50.1 UT6.7(HOLD#(IO3))
TBTA_ROM_WP#_PD: RT53.1 UT6.3(WP#(IO2))
TBTA_ROSC: RT100.1 UT5.G2(R_OSC)
TBTA_SBU1: DT39.2 DT39.8 JUSBC1.B8(SBU2) RT108.2
TBTA_SBU1_R: RT108.1 UT5.K8(C_SBU1)
TBTA_SBU2: DT39.1 DT39.9 JUSBC1.A8(SUB1) RT109.2
TBTA_SBU2_R: RT109.1 UT5.L8(C_SBU2)
TBTA_USB2_RBIAS: RT41.1 UT1.H19(PA_USB2_RBIAS)
TBTA_USB20_N: RT403.1 UT1.D20(PA_USB2_D_N)
TBTA_USB20_N_R: RT401.2 RT403.2 UT5.K5(USB_RP_N)
TBTA_USB20_P: RT402.1 UT1.E20(PA_USB2_D_P)
TBTA_USB20_P_R: RT400.2 RT402.2 UT5.L5(USB_RP_P)
TBTB_HPD: RT33.1 UT1.G2(PB_DPSRC_HPD)
TBTB_I2C_INT: RT17.1 UT1.E2(POC_GPIO_1)
TBTB_LSRX: RT32.1 UT1.B5(PB_LSRX)
TBTB_LSTX: RT31.1 UT1.B4(PB_LSTX)
TBTB_USB2_RBIAS: RT42.1 UT1.F19(PB_USB2_RBIAS)
TDOCK_BATLOW#: RT20.1 UT1.F2(POC_GPIO_4)
TEST_EN: RT36.1 UT1.E1(TEST_EN)
TEST_PWRGD: RT37.1 UT1.AB5(TEST_PWR_GOOD)
THERMDA: UT1.AB23(THERMDA#AB23) UT1.AC23(THERMDA#AC23)
THERMTRIP1#: RE301.1 UE1.B12(THERMTRIP1#)
THERMTRIP2#: CE36.1 QE4.1(COLLECTOR) RE69.2 UE1.H3(GPIO103/THERMTRIP2#)
TOUCH_SCREEN_DET#: JEDP1.32 RV8.1 UH1.BC33(GPP_B4/CPU_GP3)
TOUCH_SCREEN_PD: QH8.5(G1) QH8.6(D2) RH104.2
TOUCH_SCREEN_PD#: QH8.2(G2) RH348.2 RH566.1 UH1.AM45(GPP_E7/CPU_GP1)
TOUCH_SCREEN_PD#_R: JEDP1.5 QH8.3(D1) RH566.2
TOUCHPAD_INTR#: JKBTP1.16 RE318.2 RH402.2 UH1.BF32(GPP_B3/CPU_GP2)
TP_LAN_JTAG_TCK: RL2.1 UL1.35(JTAG_TCK)
TP_LAN_JTAG_TDI: T88.1 UL1.32(JTAG_TDI)
TP_LAN_JTAG_TDO: T89.1 UL1.34(JTAG_TDO)
TP_LAN_JTAG_TMS: RL1.1 UL1.33(JTAG_TMS)
TP_SKL_E30: T284.1 UC1.E30(RSVD23)
TP_SKL_F30: T285.1 UC1.F30(RSVD24)
TPM_GPIO0: RZ112.2 UZ12.6(GPIO)
TPM_GPIO0_NU: RZ1407.2 UZ12.29(NIC_19)
TPM_PIRQ#: RC560.1 RC561.1 RZ69.2 UZ12.18(SPI_PIRQ#)
TPM_PIRQ#_B20: RC561.2 RH339.2 UH1.AU26(GPP_B20/GSPI1_CLK)
TPM_PIRQ#_R: RC560.2 UH1.BD29(GPP_B17/GSPI0_MISO)
TPM_TYPE: RH379.1 UH1.AW32(GPP_A22/ISH_GP4)
TS_INT#: JIRTS1.2 RV319.2 RV1657.2 UH1.AV21(GPP_C23/UART2_CTS#)
TSENSE_2PH_CPU: PCZ33.1 PRZ79.2 PUZ1.25(TTSENSE_2PH)
TSENSE_4PH_CPU: PCZ32.1 PRZ78.2 PUZ1.14(TSENSE_4PH)
TYPEC_CON_SEL1: RH555.1 RH556.1 UH1.BA24(GPP_C10/UART0A_RTS#)
TYPEC_CON_SEL2: RH553.1 RH554.1 UH1.AP24(GPP_C11/UART0A_CTS#)
TYPEC_ID: CE62.1 RE343.1 UE1.F2(GPIO033/RC_ID0)
UART_MISO: RT82.1 RT83.2 UT5.F2(UART_RX)
UART_MOSI: RT81.1 RT83.1 UT5.E2(UART_TX)
UG1_CHG: PQ704.4(G) PU700.11(UGATE1)
UG2_CHG: PQ701.1(G1) PU700.5(UGATE2)
UIM_CLK: CZ38.1 DZ13.2 DZ13.8 JNGFF2.32(UIM_CLK) JSIM1.C3(CLK)
UIM_DATA: CZ39.1 DZ13.4 DZ13.7 JNGFF2.34(UIM_DATA) JSIM1.C7(IO) RZ335.2
UIM_RESET: CZ40.1 DZ13.1 DZ13.9 JNGFF2.30(UIM_RESET) JSIM1.C2(RST)
UPD1_SMBCLK: QT1.1(S2) RE303.1 RT58.1 UE1.C3(GPIO144/SMB04_CLK/SPI1_CS#/UART)
UPD1_SMBCLK_Q: QT1.6(D2) RT58.2 RT67.1 RT92.1 UT5.B5(I2C_SCL2)
UPD1_SMBDAT: QT1.4(S1) RE302.1 RT59.1 UE1.B4(GPIO143/SMB04_DATA/SPI1_MISO/UA)
UPD1_SMBDAT_Q: QT1.3(D1) RT59.2 RT66.1 RT93.1 UT5.A5(I2C_SDA2)
UPD1_SMBINT#: RE91.1 RT60.1 UE1.F10(GPIO225/UART0_RTS#)
UPD1_SMBUS_ALERT#: RT60.2 RT68.1 UT5.B6(I2C_IRQ2_N)
UPD2_SMBCLK: RE721.1 UE1.D7(GPIO004/SMB00_CLK/SPI0_MOSI)
UPD2_SMBDAT: RE722.1 UE1.E7(GPIO003/SMB00_DATA/SPI0_CS#)
UPD2_SMBINT#: RE92.1 UE1.F5(GPIO214/ADC12)
USB2_COMP: RH193.1 UH1.F4(USB2_COMP)
USB2_ID: RH365.1 UH1.G3(USB2_ID)
USB2_VBUSSENSE: RH364.1 UH1.F3(USB2_VBUSSENSE)
USB3_A_DE0: RI60.1 RI74.1 UI6.16(A_DE0/SCL_CTL)
USB3_A_DE1: RI70.1 RI72.1 UI6.18(A_DE1/NC)
USB3_A_EQ0: RI59.1 RI65.1 UI6.17(A_EQ0/NC)
USB3_A_EQ1: RI68.1 RI76.1 UI6.15(A_EQ1/SDA_CTL)
USB3_B_DE0: RI62.1 RI78.1 UI6.3(B_DE0/I2C_ADDR0)
USB3_B_DE1: RI66.1 RI73.1 UI6.6(B_DE1/NC)
USB3_B_EQ0: RI67.1 RI71.1 UI6.2(B_EQ0/NC)
USB3_B_EQ1: RI61.1 RI64.1 UI6.4(B_EQ1/I2C_ADDR1)
USB3_PD#_UI6: QI2.1(D) UI6.5(PD#)
USB3_PRX_C_RD_DTX_N3: CI49.2 UI6.23(B_OUTN)
USB3_PRX_C_RD_DTX_P3: CI53.2 UI6.22(B_OUTP)
USB3_PRX_DTX_N1: DI4.1 DI4.9 JUSB1.5(STDA_SSRX-) UH1.D11(USB31_1_RXN)
USB3_PRX_DTX_N2: UH1.B9(USB31_2_RXN) UZ29.18(B0-)
USB3_PRX_DTX_N3: CI49.1 UH1.B10(USB31_3_RXN)
USB3_PRX_DTX_N4: DI6.1 DI6.9 JUSB3.5(STDA_SSRX-) UH1.K16(USB31_4_RXN)
USB3_PRX_DTX_P1: DI4.2 DI4.8 JUSB1.6(STDA_SSRX+) UH1.C11(USB31_1_RXP)
USB3_PRX_DTX_P2: UH1.C9(USB31_2_RXP) UZ29.19(B0+)
USB3_PRX_DTX_P3: CI53.1 UH1.C10(USB31_3_RXP)
USB3_PRX_DTX_P4: DI6.2 DI6.8 JUSB3.6(STDA_SSRX+) UH1.J15(USB31_4_RXP)
USB3_PRX_RD_DTX_N3: DI1.1 DI1.9 JUSB2.5(STDA_SSRX-) UI6.8(B_INN)
USB3_PRX_RD_DTX_P3: DI1.2 DI1.8 JUSB2.6(STDA_SSRX+) UI6.9(B_INP)
USB3_PTX_C_DRX_N1: CI13.1 DI4.4 DI4.7 JUSB1.8(STDA_SSTX-)
USB3_PTX_C_DRX_N2: CZ151.2 UZ29.16(B1-)
USB3_PTX_C_DRX_N3: CI5.1 DI1.4 DI1.7 JUSB2.8(STDA_SSTX-)
USB3_PTX_C_DRX_N4: CI27.1 DI6.4 DI6.7 JUSB3.8(STDA_SSTX-)
USB3_PTX_C_DRX_P1: CI16.1 DI4.5 DI4.6 JUSB1.9(STDA_SSTX+)
USB3_PTX_C_DRX_P2: CZ150.2 UZ29.17(B1+)
USB3_PTX_C_DRX_P3: CI4.1 DI1.5 DI1.6 JUSB2.9(STDA_SSTX+)
USB3_PTX_C_DRX_P4: CI28.1 DI6.5 DI6.6 JUSB3.9(STDA_SSTX+)
USB3_PTX_C_RD_DRX_N3: CI51.1 UI6.20(A_INN)
USB3_PTX_C_RD_DRX_P3: CI54.1 UI6.19(A_INP)
USB3_PTX_DRX_N1: CI13.2 UH1.F9(USB31_1_TXN)
USB3_PTX_DRX_N2: CZ151.1 UH1.C3(USB31_2_TXN)
USB3_PTX_DRX_N3: CI51.2 UH1.F11(USB31_3_TXN)
USB3_PTX_DRX_N4: CI27.2 UH1.B14(USB31_4_TXN)
USB3_PTX_DRX_P1: CI16.2 UH1.F7(USB31_1_TXP)
USB3_PTX_DRX_P2: CZ150.1 UH1.D4(USB31_2_TXP)
USB3_PTX_DRX_P3: CI54.2 UH1.G12(USB31_3_TXP)
USB3_PTX_DRX_P4: CI28.2 UH1.C14(USB31_4_TXP)
USB3_PTX_RD_DRX_N3: CI5.2 UI6.11(A_OUTN)
USB3_PTX_RD_DRX_P3: CI4.2 UI6.12(A_OUTP)
USB3_TEST: RI63.2 UI6.14(TEST)
USB20_N1: UH1.J3(USB2N_1) UI3.2(DM_OUT)
USB20_N2: LI3.4 UH1.N13(USB2N_2)
USB20_N2_R: DI2.3 JUSB2.2(D-) LI3.3
USB20_N3: LI4.4 UH1.K4(USB2N_3)
USB20_N3_R: DI3.3 JUSB3.2(D-) LI4.3
USB20_N4: RZ1388.2 UH1.M10(USB2N_4)
USB20_N4_FP: DZ11.2 JFPBTN1.6 RZ350.1 RZ1388.1
USB20_N4_USH: JUSH1.23 RZ350.2
USB20_N5: RT401.1 UH1.M1(USB2N_5)
USB20_N6: T300.1 UH1.K7(USB2N_6)
USB20_N8: LI8.4 RI48.1 UH1.G4(USB2N_8)
USB20_N8_R: JNGFF2.9(USB_D_N) LI8.3 RI48.2
USB20_N10: JUSH1.19 UH1.H3(USB2N_10)
USB20_N11: LZ1.1 UH1.R10(USB2N_11)
USB20_N11_R: DA10.2 JEDP1.12 LZ1.2
USB20_N14: LI9.1 LI50.1 UH1.E5(USB2N_14)
USB20_N14_R: JNGFF1.5(USB_D-) LI9.2 LI50.2
USB20_P1: UH1.J2(USB2P_1) UI3.3(DP_OUT)
USB20_P2: LI3.1 UH1.N15(USB2P_2)
USB20_P2_R: DI2.2 JUSB2.3(D+) LI3.2
USB20_P3: LI4.1 UH1.K3(USB2P_3)
USB20_P3_R: DI3.2 JUSB3.3(D+) LI4.2
USB20_P4: RZ1389.2 UH1.L9(USB2P_4)
USB20_P4_FP: DZ11.3 JFPBTN1.4 RZ351.1 RZ1389.1
USB20_P4_USH: JUSH1.22 RZ351.2
USB20_P5: RT400.1 UH1.L2(USB2P_5)
USB20_P6: T301.1 UH1.K6(USB2P_6)
USB20_P8: LI8.1 RI47.1 UH1.G5(USB2P_8)
USB20_P8_R: JNGFF2.7(USB_D_P) LI8.2 RI47.2
USB20_P10: JUSH1.18 UH1.H2(USB2P_10)
USB20_P11: LZ1.4 UH1.P9(USB2P_11)
USB20_P11_R: DA10.3 JEDP1.13 LZ1.3
USB20_P14: LI9.4 LI49.1 UH1.F6(USB2P_14)
USB20_P14_R: JNGFF1.3(USB_D+) LI9.3 LI49.2
USB_OC0#: RH644.1 RH651.1 UH1.AH36(GPP_E9/USB2_OC0#) UI3.13(FAULT#)
USB_OC1#: RH641.1 RH650.1 UH1.AL40(GPP_E10/USB2_OC1#) UI1.3(OCB)
USB_OC2#: RH642.1 RH652.1 UH1.AJ44(GPP_E11/USB2_OC2#) UI2.3(OCB)
USB_OC3#: RH643.1 RH649.1 UH1.AL41(GPP_E12/USB2_OC3#)
USB_OC4#: RH645.1 UH1.AV47(GPP_F15/USB2_OC4#)
USB_OC5#: RH646.1 UH1.AR35(GPP_F16/USB2_OC5#)
USB_OC6#: RH647.1 UH1.AR37(GPP_F17/USB2_OC6#)
USB_OC7#: RH648.1 UH1.AV43(GPP_F18/USB2_OC7#)
USB_POWERSHARE_EN#: RE728.1 UE1.J3(GPIO206/ADC06) UI3.6(CTL1)
USB_POWERSHARE_VBUS_EN: RE702.1 RE730.1 UE1.J2(GPIO205/ADC05) UI3.5(EN)
USB_PWR_EN1#: QI2.2(G) RE729.1 UE1.K3(GPIO207/ADC07) UI1.4(E\N\)
USB_PWR_EN2#: RE727.1 UE1.G5(GPIO213/ADC11) UI2.4(E\N\)
USH_DET#: JUSH1.1 RE526.2 UE1.C13(GPIO125/GPTP-OUT5/PVT_CLK)
USH_EXPANDER_SMBCLK: CZ62.1 JUSH1.16 RZ8.2 UE1.B3(GPIO006/SMB01_CLK/GPTP-OUT7)
USH_EXPANDER_SMBDAT: CZ63.1 JUSH1.15 RZ9.2 UE1.E5(GPIO005/SMB01_DATA/GPTP-OUT4)
USH_PWR_STATE#: JUSH1.5 RZ10.2 UE1.H2(GPIO204/ADC04)
VCI_IN1#: RE507.1 UE1.B5(GPIO162/VCI_IN1#)
VCI_IN2#: RE508.1 UE1.D4(GPIO161/VCI_IN2#)
VCI_IN3#: RE324.1 UE1.E4(GPIO000/VCI_IN3#)
VCT_LAN_R1: RL3.1 UL1.6(SVR_EN_N)
VGA_IDENTIFY: RE84.1 RE85.1 UE1.L9(GPIO017/GPTP-IN5)
VID0_1VS_VCCIO: PR414.2 PR416.1 PU401.9(VID0)
VID1_1VS_VCCIO: PR413.2 PR415.1 PU401.8(VID1)
VOUT_1.2V_RUN: PC509.1 PC511.1 PJP504.1 PR512.1 PU502.1(OUT)
VOUT_2.5V_MEM: PC515.1 PC516.1 PJP506.1 PR515.1 PU503.1(OUT)
VR_SVID_ALERT#: PRZ8.2 PRZ21.2 RC152.2 RC153.1
VR_SVID_CLK: CC325.1 PRZ9.2 PRZ19.2 UC1.BH32(VIDSCK)
VR_SVID_DATA: PRZ7.2 PRZ23.2 RC157.2 UC1.BH29(VIDSOUT)
VRALERT#: RH203.1 UH1.BE32(GPP_B2/VRALERT#)
VRHOT#_CPU: PRZ16.1 PUZ1.39(VRHOT#)
VRMP_CPU: PCZ31.1 PRZ57.2 PUZ1.15(VRMP)
VSET_5105: CE38.1 RE77.1 UE1.C9(VSET)
VSN_1PH_CPU: PCZ1.2 PRZ12.2 PUZ1.51(VSN_1PH)
VSN_2PH_CPU: PCZ16.2 PRZ37.2 PUZ1.37(VSN_2PH)
VSN_4PH_CPU: PCZ14.2 PRZ32.2 PUZ1.2(VSN_4PH)
VSP_1PH_CPU: PCZ7.2 PRZ14.2 PUZ1.52(VSP_1PH)
VSP_2PH_CPU: PCZ15.1 PRZ30.2 PUZ1.38(VSP_2PH)
VSP_4PH_CPU: PCZ13.1 PRZ27.2 PUZ1.1(VSP_4PH)
VSYS_CHG: PC745.1 PR721.1 PU700.3(VSYS)
VTTREF_DDR: PC218.1 PC227.1 PU200.3(VTTREF)
WIGIG_32KHZ: JNGFF1.50(SUSCLK(32KHZ)) RZ56.2
WLAN_COEX1: JNGFF1.48(COEX1) RZ130.2
WLAN_COEX2: JNGFF1.46(COEX2) RZ129.2
WLAN_COEX3: JNGFF1.44(COEX3) RZ128.2
WLAN_PWR_EN: DZ9.1 RZ38.2 RZ70.2 RZ71.2 UZ4.5(ON2)
WLAN_WIGIG60GHZ_DIS#: DZ1.1 RE8.1 UE1.L13(GPIO112/PS2_CLK1A)
WLAN_WIGIG60GHZ_DIS#_R: DZ1.2 JNGFF1.56(W_DISABLE1#)
WWAN_ANT_CONFIG: JNGFF2.68(N/C_68) RZ1450.1
WWAN_BB_RST#: RZ1393.2 UH1.BE36(GPP_A11/PME#/SD_VDD2_PWR_EN#)
WWAN_BB_RST#_PCH: RC847.1 UH1.BF36(GPP_A12/BM_BUSY#/ISH_GP6/SX_EXI)
WWAN_BB_RST#_R: JNGFF2.67(RESET#) RC847.2 RZ1393.1
WWAN_COEX1: JNGFF2.64(COEX1) RZ130.1 RZ373.1
WWAN_COEX2: JNGFF2.62(COEX2) RZ129.1 RZ372.1
WWAN_COEX3: JNGFF2.60(COEX3) RZ128.1 RZ374.1
WWAN_FULL_PWR_EN: CZ198.1 JNGFF2.6(FUL_CARD_PWR_OFF#) RZ43.1 UH1.BF19(GPP_D0/SPI1_CS#/SBK0_BK0)
WWAN_GPIO_CTRL: RE340.2 RZ1398.1 UE1.K1(GPIO064/LRESET#)
WWAN_GPIO_CTRL#: QZ19.1(D) RZ1397.2 UZ51.6(S)
WWAN_GPIO_CTRL_R: QZ19.2(G) RZ1398.2 RZ1399.1
WWAN_GPIO_PERST#: RC756.1 RZ1402.2 RZ1405.2 RZ1480.2 RZ1485.2 UH1.BC17(GPP_D22/SPI1_IO3)
WWAN_GPIO_PERST#_R: RZ1402.1 UZ52.A2(C)
WWAN_GPIO_WAKE#: RC840.2 RZ1394.2 RZ1396.2 UH1.BD17(GPP_D21/SPI1_IO2)
WWAN_GPIO_WAKE#_R: RZ1394.1 UZ51.3(B1)
WWAN_PERST#: JNGFF2.50(PERST#) RZ1401.2 RZ1406.1 RZ1480.1 RZ1481.1
WWAN_PERST#_R: RZ1401.1 UZ52.C2(Y)
WWAN_PEWAKE#: JNGFF2.54(PEWAKE#) RZ1395.2 RZ1396.1 RZ1400.1
WWAN_PEWAKE#_R: RZ1395.1 UZ51.4(A)
WWAN_RADIO_DIS#: DZ5.1 RE10.1 RZ86.2 UE1.F12(GPIO123/BCM0_CLK/PVT_IO2)
WWAN_RADIO_DIS#_R: DZ5.2 JNGFF2.8(W_DISABLE1#) RZ86.1
WWAN_WAKE#: QZ8.1(D) RZ133.2 UE1.M13(GPIO110/PS2_CLK2)
WWAN_WAKE#_D: JNGFF2.23(WOWWAN#) QZ8.3(S) RZ1483.2
XCLK_RBIAS: RH435.2 UH1.T3(XCLK_BIASREF)
XDP_DBRESET#: CC32.1 JXDP1.48 RC137.1 RH66.1 UC3.1(B)
XDP_OBS0: RC239.1 UC1.BR27(BPM#_0)
XDP_OBS0_R: JXDP1.21 RC239.2
XDP_OBS1: RC240.1 UC1.BT27(BPM#_1)
XDP_OBS1_R: JXDP1.23 RC240.2
XDP_PRSNT_PIN1: JXDP1.1 RC121.1 RC122.1
XTAL24_IN: CH13.1 RH153.1 RH436.2 YH2.3(CRYSTAL3)
XTAL24_IN_R1: RH436.1 UH1.U10(XTAL_IN)
XTAL24_OUT: CH14.1 RH152.2 RH153.2 YH2.1(CRYSTAL1)
XTAL24_OUT_R1: RH152.1 UH1.U9(XTAL_OUT)
XTAL_25_IN: RT394.1 UT1.D22(XTAL_25_IN)
XTAL_25_IN_R: CT21.1 RT394.2 YT1.1(IN)
XTAL_25_OUT: RT40.1 UT1.D23(XTAL_25_OUT)
XTAL_25_OUT_R: CT20.1 RT40.2 YT1.3(OUT)
XTALI: CL14.1 RL11.2 UL1.10(XTAL_IN) YL1.1
XTALO: RL11.1 RL34.2 UL1.9(XTAL_OUT)
XTALO_R: CL13.1 RL34.1 YL1.3
Z2805: RL18.1 TL1.24(MCT1)
Z2806: RL16.1 TL1.18(MCT3)
Z2807: RL17.1 TL1.21(MCT2)
Z2808: RL15.1 TL1.15(MCT4)
N13800829: CD31.2 RD18.1
N13829184: CD62.2 RD31.1
N14169789: QN1.5(G2) QN1.6(D1) RN2.2
N16624469: CT90.1 RT111.2 UT7.3(EN)
N16783095: PC113.2 PR108.1
N16783134: PC127.2 PR117.1
N16783222: PC119.1 PU102.16(NC2) PU102.17(VCC)
N17114118: QV2.1(D) RV5.2
N17115081: JEDP1.21 LV1.1
N17138495: RZ360.1 UZ29.2(PD)
N17142422: RI14.2 UI3.16(ILIM_HI)
N17151556: CZ38.2 RZ334.1
N17370862: PC4.2 PQ4.4(G) PQ5.1(D) PR11.2 PR16.1
N17370885: PQ5.2(G) PR10.2 PR15.1
N17370921: PQ1.6(D1) PR15.2
N17370927: PQ7.1(D) PR16.2
N17370961: PL3.1 PQ2.1(D) PR3.1 PR6.1
N17370983: PQ2.3(S) PR3.2 PR5.1
N17370995: PQ3.2(BASE) PR6.2 PR8.1
N17370999: PQ2.2(G) PQ3.1(COLLECTOR) PR7.2
N17371029: PC6.2 PQ9.4(G) PQ11.1(D) PR12.2 PR18.1
N17371043: PQ6.1(D) PR18.2
N17371125: PQ7.2(G) PR20.1
N17371182: PQ6.2(G) PR22.2
N17372063: PQ1.3(D2) PR17.2 PR19.2
N17372074: PQ1.5(G2) PR25.1
N17372283: PQ1.2(G1) PR19.1
N17538214: PQ11.2(G) PR31.2 PR32.1
N17539406: PQ10.5(G2) PQ10.6(D1) PR33.2
N18394878: RE57.1 RE58.1 UE1.B1(SYSPWR_PRES)
N18394936: RE318.1 UE1.G2(GPIO203/ADC03)
N18783667: RT103.1 UT5.L11(GND20)
N18783677: RT104.1 UT5.K9(RPD_G1)
N18783744: RT97.2 RT98.2 RT99.1 UT5.F10(BUSPOWER_N)
N18783748: RT101.1 UT5.D6(HRESET)
N18785154: CT87.1 UT5.H7(SS)
N18785244: RT85.1 UT5.G4(SWD_CLK)
N18785246: RT84.1 UT5.F4(SWD_DATA)
N18785591: RT105.1 UT5.K10(RPD_G2)
N18964580: CZ109.1 UZ2.12(CT1)
N18964619: CZ113.1 UZ3.12(CT1)
N18964665: RZ64.2 UZ3.3(ON1)
N18964738: CZ121.1 UZ8.6(CT)
N18965068: CZ110.1 UZ2.10(CT2)
N18965149: CZ117.1 UZ4.12(CT1)
N18965206: CZ114.1 UZ3.10(CT2)
N18965394: CZ118.1 UZ4.10(CT2)
N19180571: RT63.1 UT5.F1(I2C_ADDR)
N21789330: RI77.2 UI6.7(REXT)
N21789359: RI75.2 UI6.24(I2C_EN)
N22349729: JNGFF2.58(REF_RFFE2_SDATA) RZ132.2
N23124850: CE57.1 RE350.2
N23602829: QE12.1(D) RE94.1
N23766683: T194.1 UC1.A33(EDP_DISP_UTIL)
N23770309: T199.1 UC1.BP13(DDR0_VREF_DQ)
N23795295: T42.1 UC1.G13(RSVD25)
N23795364: T18.1 UC1.B30(RSVD7)
N23795366: T19.1 UC1.C30(RSVD21)
N23795368: T21.1 UC1.G3(RSVD26)
N23795370: T20.1 UC1.J3(RSVD29)
N23795372: T24.1 UC1.BR31(RSVD18)
N23795374: T22.1 UC1.BH30(RSVD9)
N23795376: T23.1 UC1.BR35(RSVD19)
N23795378: T1.1 UC1.D1(RSVD_TP3)
N23795380: T2.1 UC1.E1(RSVD_TP4)
N23795385: T4.1 UC1.E2(RSVD_TP5)
N23795387: T5.1 UC1.BR1(RSVD_TP1)
N23795389: T6.1 UC1.BT2(RSVD_TP2)
N23795391: T7.1 UC1.BN35(RSVD15)
N23795393: T8.1 UC1.BL34(RSVD13)
N23795395: T11.1 UC1.BN33(RSVD14)
N23795397: T9.1 UC1.J24(RSVD28)
N23795399: T10.1 UC1.H24(RSVD27)
N23795401: T12.1 UC1.AA14(RSVD1)
N23795403: T15.1 UC1.AE29(RSVD2)
N23795405: T14.1 UC1.N29(RSVD30)
N23795407: T13.1 UC1.R14(RSVD31)
N23795412: T28.1 UC1.AP29(RSVD5)
N23795414: T27.1 UC1.AP14(RSVD4)
N23795416: T29.1 UC1.BK28(RSVD11)
N23795418: T30.1 UC1.BJ28(RSVD10)
N23795436: T41.1 UC1.AJ8(RSVD3)
N23795438: T44.1 UC1.BL31(RSVD12)
N23795440: T43.1 UC1.B2(RSVD6)
N23795442: T45.1 UC1.B38(RSVD8)
N23795444: T46.1 UC1.BP1(RSVD16)
N23795446: T47.1 UC1.BR2(RSVD17)
N23795448: T48.1 UC1.C1(RSVD20)
N23795450: T49.1 UC1.C38(RSVD22)
N23797472: T25.1 UC1.AW13(MSM#)
N23797474: T26.1 UC1.AT13(ZVM#)
N23797500: T32.1 UC1.AY13(RSVD2)
N23797502: T31.1 UC1.AU13(RSVD1)
N23807582: RZ120.2 UZ26.4(ON) UZ34.4(Y)
N23944525: T34.1 UH1.Y35(RSVD2)
N23944527: T33.1 UH1.Y36(RSVD3)
N23944529: T36.1 UH1.BC1(RSVD1)
N23944531: T35.1 UH1.AL35(TP)
N23948454: T40.1 UH1.U13(RSVD1)
N23950785: T60.1 UH1.R15(RSVD2)
N23950786: T61.1 UH1.R13(RSVD1)
N23950788: T62.1 UH1.AN35(TP)
N23950789: T63.1 UH1.AL37(VSS)
N23950882: CH321.1 RH28.2
N23950883: CH322.1 RH29.2
N23961117: T70.1 UH1.U35(RSVD5)
N23961134: T66.1 UH1.AH14(RSVD1)
N23961136: T67.1 UH1.AH15(RSVD2)
N23961138: T68.1 UH1.R32(RSVD4)
N23961140: T71.1 UH1.U37(RSVD6)
N23961142: T72.1 UH1.Y15(RSVD8)
N23961144: T73.1 UH1.Y14(RSVD7)
N23961148: T69.1 UH1.N32(RSVD3)
N23961156: QH6.1(D) RH433.2
N23961158: CH340.1 QH7.2(G) RH432.2 RH433.1
N24088922: QE17.1(D) RE546.2
N24114512: QI2.3(S) RI69.2
N24908379: PD705.2 PR737.2
N24908381: PD705.3(1) PR735.1 PR736.2
N24908396: PR741.2 PU701.2(IN2)
N24908406: PD705.1(3) PR739.1 PU701.1(IN1)
N24908424: PR740.1 PU701.4(O)
N24908981: PC751.1 PR728.2
N25075615: T302.1 UH1.AL48(GPP_E4/SATA_DEVSLP0)
N25591846: PC13.2 PR47.2 PU3.5(P)
N25591872: PR43.2 PR45.1 PU3.4(O)
N25591876: PR44.2 PU3.2(A)
N25591912: PQ10.2(G1) PR41.2 PR43.1
N25591942: PQ8.1(D) PR22.1 PR27.1 PR44.1
N25591952: PR42.2 PU3.1(B)
N25736614: PR517.2 PR1713.2 PU501.5(PG)
N25907811: PC804.1 PR800.2 PR805.1 PR817.1 PU800.3(+)
N25907817: PC800.1 PR809.2 PR815.1 PU800.2(-)
N25907922: PQ803.2(G) PR801.2 PR807.1
N25907924: PQ802.6(D1) PR807.2 PR858.1
N25907948: PR853.2 PU801.1(B)
N25907954: PC814.2 PR859.2 PU801.5(P)
N25907966: PQ804.2(G1) PR818.2
N25907978: PQ807.1(D) PR818.1 PR822.2 PR854.1
N25907980: PQ802.5(G2) PR856.1 PR857.2
N25907988: PR855.1 PR856.2 PU801.4(O)
N25908000: PR854.2 PU801.2(A)
N25908024: PC811.1 PD802.1 PQ813.6(D1) PR831.2 PR842.1 PR870.2 PU800.5(+)
N25908041: PC813.1 PD802.2 PR835.2 PR840.1 PU800.7(O)
N25908049: PC812.1 PR832.2 PR843.1 PU800.6(-)
N25908061: PQ813.5(G2) PR840.2
N25908120: PQ804.6(D1) PR811.2
N25908122: PC803.2 PQ800.4(G) PQ803.1(D) PR803.2 PR811.1
N25908132: PQ813.3(D2) PR836.1
N25908138: PQ805.2(G) PR802.2 PR808.1
N25908140: PQ806.3(D2) PR808.2
N25908152: PC802.2 PQ801.4(G) PQ805.1(D) PR804.2 PR812.1
N25908168: PQ806.6(D1) PR813.2 PR814.2 PR852.2
N25908188: PQ804.3(D2) PR812.2
N25908210: PQ806.5(G2) PR814.1
N25908220: PQ806.2(G1) PR820.1
N25908319: PQ804.5(G2) PR816.2
N25908329: PQ810.5(G) PR825.2 PR826.2
N25908331: PQ808.5(G) PR834.2 PR841.1 PR1652.2
N25908337: PQ808.6(D) PQ810.1(S) PR830.2 PR841.2
N25908347: PQ808.2(G) PQ808.3(D) PR833.2
N25908367: PQ811.5(G) PR829.2
N25908379: PQ810.2(G) PR824.2 PR827.2
N25908405: PQ809.6(D) PQ810.4(S) PR838.2 PR845.2
N25908421: PQ809.5(G) PR844.2
N25908431: PQ809.2(G) PQ809.3(D) PR839.2
N26168283: PQ12.1(D) PR46.2
N26168409: PQ12.2(G) PR49.1
N26168635: PQ814.1(D) PR858.2
N26172409: PQ814.2(G) PR861.1
N26187732: PHZ5.1 PRZ79.1 PRZ83.1
N26187863: PCZ20.1 PRZ42.2
N26187879: PCZ13.2 PCZ14.1 PRZ31.2 PRZ32.1
N26187927: PCZ10.1 PRZ24.2
N26187941: PHZ2.1 PRZ50.1 PRZ54.2
N26187983: PCZ15.2 PCZ16.1 PRZ37.1 PRZ38.2
N26188037: PCZ1.1 PCZ4.2 PRZ11.2 PRZ12.1
N26188062: PHZ4.1 PRZ78.1 PRZ82.1
N26189598: PCZ19.1 PRZ43.2
N26189600: PCZ18.1 PRZ40.2
N26189682: PCZ4.1 PRZ13.2 PRZ14.1 PRZ18.1
N26189729: PHZ3.1 PRZ52.1 PRZ55.2
N26189992: PCZ7.1 PRZ18.2
N26190033: PHZ1.2 PRZ3.1
N26190221: PCZ23.1 PRZ47.2
N26192621: PCH46.2 PUH4.7(PHASE)
N26192663: PLH4.3 PRH13.1
N26192730: PLH3.3 PRH5.1
N26193321: PCH22.2 PUH3.7(PHASE)
N26193447: PLH1.3 PRH6.1
N26193461: PLH2.3 PRH14.1
N26194097: PCH25.2 PUH1.7(PHASE)
N26194151: PCH50.2 PUH2.7(PHASE)
N26195379: PCT12.2 PUT1.7(PHASE)
N26195438: PLT1.3 PRT3.1
N26196770: PCA10.2 PUA1.7(PHASE)
N26737016: PR1616.2 PUH1.17(THWN)
N26737032: PR1617.2 PUH1.16(DISB#)
N26738097: PR1619.2 PUH2.16(DISB#)
N26738100: PR1618.2 PUH2.17(THWN)
N26738443: PR1620.2 PUT1.17(THWN)
N26738446: PR1621.2 PUT1.16(DISB#)
N26738777: PR1623.2 PUA1.16(DISB#)
N26738780: PR1622.2 PUA1.17(THWN)
N26739146: PR1624.2 PUH4.17(THWN)
N26739149: PR1625.2 PUH4.16(DISB#)
N26739609: PR1626.2 PUH3.17(THWN)
N26739612: PR1627.2 PUH3.16(DISB#)
N26924776: PR311.2 PR1648.1 PR1649.2
N26924800: PC307.1 PR306.1 PR1650.1 PR1651.2
N26924806: PC307.2 PR308.1
N27521746: PCH29.1 PRH8.2
N27522693: PCH28.1 PRH7.2
N27523201: PCH53.1 PRH16.2
N27523847: PCH52.1 PRH15.2
N27524640: PCT14.1 PRT4.2
N27525287: PCA12.1 PRA3.2
N27689839: PC865.1 PQ8.2(G) PR865.1
N27714854: PD803.3(1) PR871.1
N27715583: PC3003.2 PD3001.1 PR3004.2 PR3005.2 PU3000.3(IN+1)
N27715644: PC3004.2 PR3007.2 PR3008.2 PU3000.6(IN-2)
N27715680: PC3005.1 PD3002.1 PR3009.1 PR3010.1 PR3011.1 PU3000.5(IN+2)
N27715692: PD3000.1(3) PR3006.2 PR3007.1
N27715813: PC3007.1 PC3009.1 PD3002.2 PQ3000.2(G) PR3013.2
N27715838: PQ3000.3(D) PQ3000.6(D) PR3001.1
N27715861: PC3006.1 PC3008.1 PD3001.2 PQ3000.5(G) PR3012.2
N27715969: PC3001.2 PR3002.2 PR3003.2 PU3000.2(IN-1)
N27884552: PD700.1 PD702.1 PD704.1 PD706.1 PR708.2
N28028546: PD803.2 PR872.1
N29556778: RV38.1 UV31.C6(REXT)
N29565659: CA51.1 RA44.1 UA1.21(LDO1-CAP)
N29565663: CA53.1 UA1.6(LDO3-CAP)
N29565665: CA52.1 UA1.32(LDO2-CAP)
N29565749: CA25.1 UA1.15(MIC2-CAP)
N29565777: CA49.2 CA80.2 UA1.27(CPVEE)
N29565781: RA53.1 RA54.1 UA1.16(VD33STB)
N29565804: CA35.1 UA1.22(VREF)
N29566049: CA33.1 RA17.2
N29624840: CZ306.1 UZ53.6(CT)
N29889874: RH101.2 SW1.1(A)
N30096018: JDIMM1.162(S2#/C0) T50.1
N30096036: JDIMM1.165(S3#/C1) T51.1
N30107347: JDIMM2.162(S2#/C0) T52.1
N30107379: JDIMM2.165(S3#/C1) T53.1
N30319136: JNGFF2.25(DPR) RZ326.1
N31929130: QV7.1(D) RV6.1 RV9.1 RV1400.1
N31929169: QV8.3(S) RV732.1 RV733.1
N31929212: CV1635.1 QV8.2(G) RV1400.2
N32006014: QZ18.5(G1) QZ18.6(D1) RZ381.2
N32126868: CZ130.1 UZ23.6(CT)
N33127151: CZ56.1 RZ63.1
N35444529: QE11.3(S) RE70.1 RE90.2
N35444573: QE4.2(BASE) RE70.2
N35445396: CV633.1 DV11.1 RV626.1 RV627.2
N35445409: CV635.1 DV12.1 RV629.1 RV631.2
N35445460: QV20.1 RV630.1
N35445475: QV20.2 RV631.1
N35445606: QV18.1 RV625.1
N35445635: QV18.2 RV627.1
N35445977: QZ3.1 RZ25.1
N35754103: RT445.2 RT456.2 UT32.1(NO)
N35754105: RT448.2 UT32.3(NC)
N35754309: RT499.2 UT34.1(B)
N35754313: RT500.2 UT34.2(A)
N38529389: CL17.1 TL1.4(TCT2)
N38529394: CL16.1 TL1.1(TCT1)
N38529410: CL20.1 TL1.7(TCT3)
N38529414: CL21.1 TL1.10(TCT4)
N42376964: CZ217.1 RZ1403.1 RZ1404.1 UZ52.B2(VCC)
N356040180: PR3012.1 PU3000.1(OUT1)
N356040181: PR3013.1 PU3000.7(OUT2)

Pads without a net: FD1 1; FD2 1; FD3 1; FD4 1; JAPS1 16 17 18; JDIMM1 87 88 91 92 95 97 100 101 104 105; JDIMM2 87 88 91 92 95 97 100 101 104 105; JEDP1 2 3 16 20; JFPBTN1 3 5 7 9; JHDMI1 14; JIRTS1 8; JKBTP1 4; JNGFF1 6 8 12 16 20 66 68 70; JNGFF2 10 20 22 24 28 40 42 44 46 48 56 59 61 63 65; JNGFF3 6 10 20 22 24 26 28 30 32 34 36 40 42 44 46 48 56 58 67; JSATA1 8 20; JSD1 16; JSIM1 1 C4 C6 C8; PBATT1 11 12; PD2 2; PU100 10 15; PU102 10; PU200 18 19; PU301 10 12; PU401 4; PU502 2 6 7; PU503 2 6 7; PU700 13; PUA1 6 13 19; PUH1 6 13 19; PUH2 6 13 19; PUH3 6 13 19; PUH4 6 13 19; PUT1 6 13 19; QZ7 1 2 6; RE529 2; RE731 2; RT69 2; RT74 2; RT75 2; RT84 2; RT85 2; RT339 2; RZ78 1; RZ79 1; RZ80 1; RZ326 2; RZ1473 1; UA1 10; UC1 A11 A13 A15 A17 A19 A21 A23 A25 A29 AD2 AD4 AE1 AE5 AE9 AE10 AE11 AF10 AJ10 AJ11 AK3 AL1 AL2 AL3 AM10 AM11 AT3 AT5 AT7 AT11 AW7 AW8 AW9 AW10 AW11 AY1 AY2 AY3 AY4 AY5 AY7 AY8 AY9 AY10 AY11 B10 B11 B12 B13 B14 B15 B16 B17 B18 B19 B20 B21 B22 B23 B24 B25 B28 B29 BA1 BA2 BA3 BA4 BA5 BM31 BT30 C10 C12 C14 C16 C18 C20 C22 C24 C28 D11 D13 D15 D17 D19 D21 D23 D25 E10 E11 E12 E13 E14 E15 E16 E17 E18 E19 E20 E21 E22 E23 E24 E25 F10 F12 F14 F16 F18 F20 F22 F24; UD1 1; UE1 B8 B9 K7; UE4 1; UH1 A25 A44 AA1 AA45 AB48 AC6 AC7 AC9 AC11 AC14 AC15 AC39 AC41 AC43 AC44 AD47 AD48 AE9 AE11 AE14 AE15 AE39 AE41 AE44 AE48 AF47 AF48 AG45 AH46 AH47 AH48 AJ46 AJ47 AK48 AL15 AM7 AN4 AN13 AN37 AN40 AN46 AP2 AP3 AP21 AP29 AP41 AP47 AP48 AR13 AR18 AR48 AT10 AT49 AU46 AU47 AV7 AV13 AV16 AV18 AW3 AW18 AW21 B15 B24 B25 B26 B27 B38 B41 B44 BA33 BA36 BD12 BD34 BD38 BE9 BE12 BE17 BE19 BE20 BE23 BE29 BE33 BE34 BF9 BF10 BF14 BF17 BF33 C15 C16 C17 C24 C26 C27 C38 C39 C41 C44 C45 C46 C47 D29 D39 D43 D46 E28 F14 F24 F26 F46 G1 G2 G14 G24 G26 G45 G46 G47 G48 G49 H47 H48 J13 K13 K29 L3 L4 L26 L41 L46 L47 L48 M6 M26 M29 M40 M44 M45 N2 N3 N8 N42 N47 N48 P24 P47 P48 R24 R35 R37 R44 R46 R47 T1 T2 T43 T45 T46 T48 U2 U3 U40 U41 U47 U48 V2 V3 V47 V48 W6 W7 W43 W44 W46 W47 Y2 Y40 Y41 Y46 Y47 Y48; UI3 9 15; UR1 31; UT1 A7 A9 A11 A13 A23 B7 B9 B11 B13 B23 D19 E18 E19 J1 J2 L1 L2 N1 N2 R1 R2 V18 W16 W19 Y16 Y19; UT7 4; UV24 3; UV31 C5 D3 D7 D8 F3 F7; UZ12 3 4 5 7 10 11 12 13 15 25 26 27 28 30 31; UZ61 1; YV6 2 4

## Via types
v1: diameter 0.305, hole 0.152, TOP to BOTTOM, 917 vias
v2: diameter 0.457, hole 0.203, TOP to BOTTOM, 7777 vias
v3: diameter 0.508, hole 0.254, TOP to BOTTOM, 79 vias
v4: diameter 0.406, hole 0.203, TOP to BOTTOM, 139 vias

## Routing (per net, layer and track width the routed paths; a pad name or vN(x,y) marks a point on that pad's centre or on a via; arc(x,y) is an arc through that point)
0.6V_DDR_VTT_ON: length 28.6
  TOP w0.102: UD1.4 119.2,92.3 RD19.2 119.2,90.74 v2(118.89,90.44)
  TOP w0.254: v2(166.43,44.71) 166.43,43.32 167.32,42.43 177.54,42.43 178.56,41.41 178.56,39.82 v1(178.05,39.32) 176.91,38.17 176.91,34.17 177.99,33.09 177.99,31.97 v2(177.41,31.4)
  BOTTOM w0.254: PR210.1 177.62,31.11 177.41,31.32 v2(177.41,31.4)
0.6V_DDR_VTT_ON_R: length 6.1
  BOTTOM w0.102: PR210.2 177.47,32.03 177.01,31.57 v1(177.01,31.06)
  BOTTOM w0.254: PR210.2 178.14,32.05 PR212.1 178.13,32.83 PC222.1 178.13,34.05 177.87,34.3 177.13,34.3 176.61,34.83 PU200.2
1.8V_1.0V_PWRGD: length 4.3
  TOP w0.102: PR1713.1 v1(233.59,70.67) 233.74,70.52 v2(233.74,69.92)
  TOP w0.109: v2(265.72,92.53) 265.72,92.58 UE1.L7
  BOTTOM w0.102: PR1712.2 192.27,89.31 v2(192.26,89.31)
3.3V_CAM_EN#: length 10.1
  TOP w0.102: RZ1380.1 129.48,121.79 v2(129.1,121.41)
  BOTTOM w0.089: UH1.BE18 225.34,110.09 225.34,110.68 225.06,110.96 225.06,116.49 225.52,116.95 225.52,117.07 225.31,117.28
  BOTTOM w0.102: 225.31,117.28 225.31,117.69 225.19,117.8 v2(225.1,117.8) RC834.2
3.3V_TS_EN: length 6.6
  TOP w0.102: v2(113.41,126.24) 112.73,126.24 112,126.97 112,130.5 111.82,130.68 RV323.1
  TOP w0.109: UE1.J7 265.67,94.93 265.67,94.95 265.67,94.95 v2(265.67,94.99)
3.3V_TS_EN_R:
  vias: v1(110.87,134.95)
3.3V_WWAN_EN: length 7.4
  TOP w0.109: v2(252.26,88.71) 252.26,88.64 252.26,88.64 v1(252.26,84.64) 252.26,83.73 252.46,83.53 RZ40.2 253.02,83.53 253.09,83.6 UZ2.3 ; UE1.C6 264.87,99.73 v2(264.87,99.82)
3V5V_EN: length 5.8
  TOP w0.254: PR114.2 v2(198.13,41.11)
  BOTTOM w0.254: v2(243.91,46.42) 243.95,46.42 244.39,46.86 PU100.12 ; v2(198.13,41.11) PR116.1 PC128.1 198.13,39.05 198.76,38.42 PU102.12
+0.6V_DDR_VTT: length 24.2
  TOP w0.356: CD55.1 CD56.1
  TOP w0.381: v2(235.3,44.21) 235.3,43.9 234.58,43.18 CD55.1 ; CD56.1 232.8,42.81 CD54.1
  TOP w0.508: v2(219.23,37.45) v4(220.09,38.3) 220.54,38.76 220.54,41.72 221.63,42.81 CD54.1
  BOTTOM w0.305: JDIMM2.258 234.92,43.87 235.26,44.21 235.33,44.21 235.33,44.21 v2(235.3,44.21) ; JDIMM1.258 159.12,46.96 159.45,47.28 v2(159.76,47.28)
  vias: v2(159.76,48.17) v2(171.94,32.38) v2(171.94,31.76) v2(172.52,32.38) v2(172.52,31.76)
+0.6VSP:
  vias: v1(175.32,32.4) v2(174.56,33.02) v2(175.14,33.02)
+0.9V_LAN: length 11
  TOP w0.203: UL1.40 272.03,114.37 v2(271.96,114.44) ; v2(280.09,112.44) 280.02,112.37 UL1.16 ; UL1.43 272.03,113.17 v2(271.96,113.24) ; v2(279.87,114.74) 279.84,114.77 UL1.22 ; v2(276.67,109.46) 276.56,109.57 UL1.8 ; UL1.11 277.76,109.98 278.02,109.72 278.02,109.67 278.18,109.51 v2(278.31,109.51)
  TOP w0.381: v2(278.31,109.51) 278.67,109.51 v1(279.07,109.12) 279.31,109.12 279.8,108.62 CL9.1 280.25,108.47 CL10.1 ; v2(279.87,114.74) 279.95,114.74 CL3.1 ; v2(280.09,112.44) 280.72,112.44 CL8.1
  vias: v2(271.91,111.91) v2(271.91,111.27) v2(272.41,116.09) v2(276.66,107.08) v2(277.3,107.08)
+0.9V_TBT_CIO: length 2.9
  TOP w0.381: CT38.1 44.02,108.55 v2(43.59,108.55) 43.59,108.35 43.17,107.94 CT39.1 42.97,107.27 v2(42.94,107.25) 42.98,107.21 CT40.1
+0.9V_TBT_DP: length 3.6
  TOP w0.089: CT29.1 47.24,105.61
  TOP w0.102: 47.24,105.61 v1(47.62,105.61)
  TOP w0.381: v2(41.64,107.25) 41.69,107.2 CT25.1 ; v2(42.29,109.2) 42.2,109.29 CT28.1 ; CT26.1 41.35,109.34 41.5,109.2 v2(41.64,109.2) 41.62,109.18 41.62,108.64 CT27.1
  vias: v2(44.24,107.25) v2(44.24,106.6)
+0.9V_TBT_LVR_OUT: length 1
  TOP w0.254: v2(40.34,107.9) 40.34,107.86 39.89,107.41 CT61.1
  vias: v1(35.87,103.77) v2(39.69,104.65) v2(40.34,104.65)
+0.9V_TBT_PCIE:
  vias: v1(41.97,103.77) v2(41.64,105.95) v2(41.64,105.3) v2(41.64,104.65)
+0.9V_TBT_SVR: length 0.8
  TOP w0.102: v1(30.13,110.54) 29.69,110.98 v2(29.69,111.13)
  vias: v2(29.69,113.67) v2(29.69,113.03) v2(29.69,112.4) v2(29.69,111.76) v2(35.98,107.45) v2(39.04,107.25) v2(39.04,106.6) v2(39.04,105.95) v2(39.04,105.3) v2(40.99,107.9) v2(41.64,107.9)
+0.9V_TBT_USB: length 1.2
  TOP w0.254: CT33.1 43.65,105.24 v2(43.59,105.3) 43.12,105.3 CT32.1
+1.0V_ALW_PCH: length 1.2
  BOTTOM w0.508: RH255.1 240.88,115.78 v2(240.88,116.92)
  vias: v1(225.23,80.78) v2(210.05,86.21) v2(210.05,85.62) v2(240.37,90.65) v2(241.06,90.66) v2(241.43,100.31) v2(241.43,98.53)
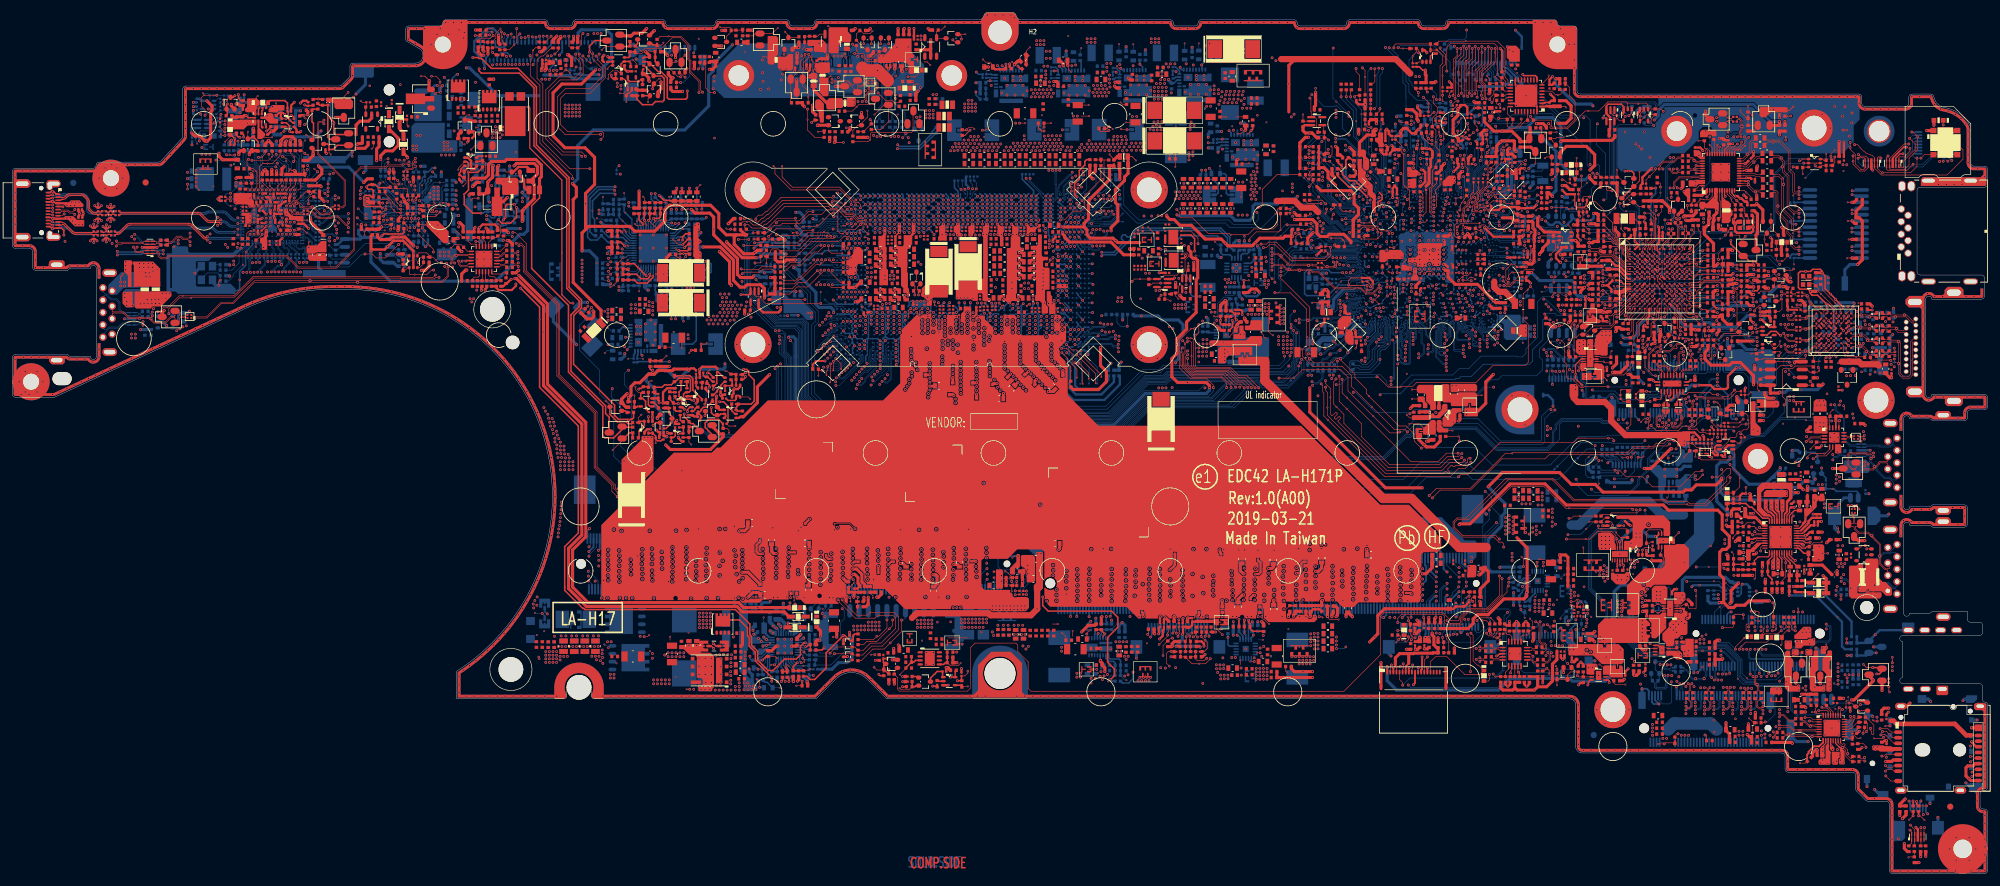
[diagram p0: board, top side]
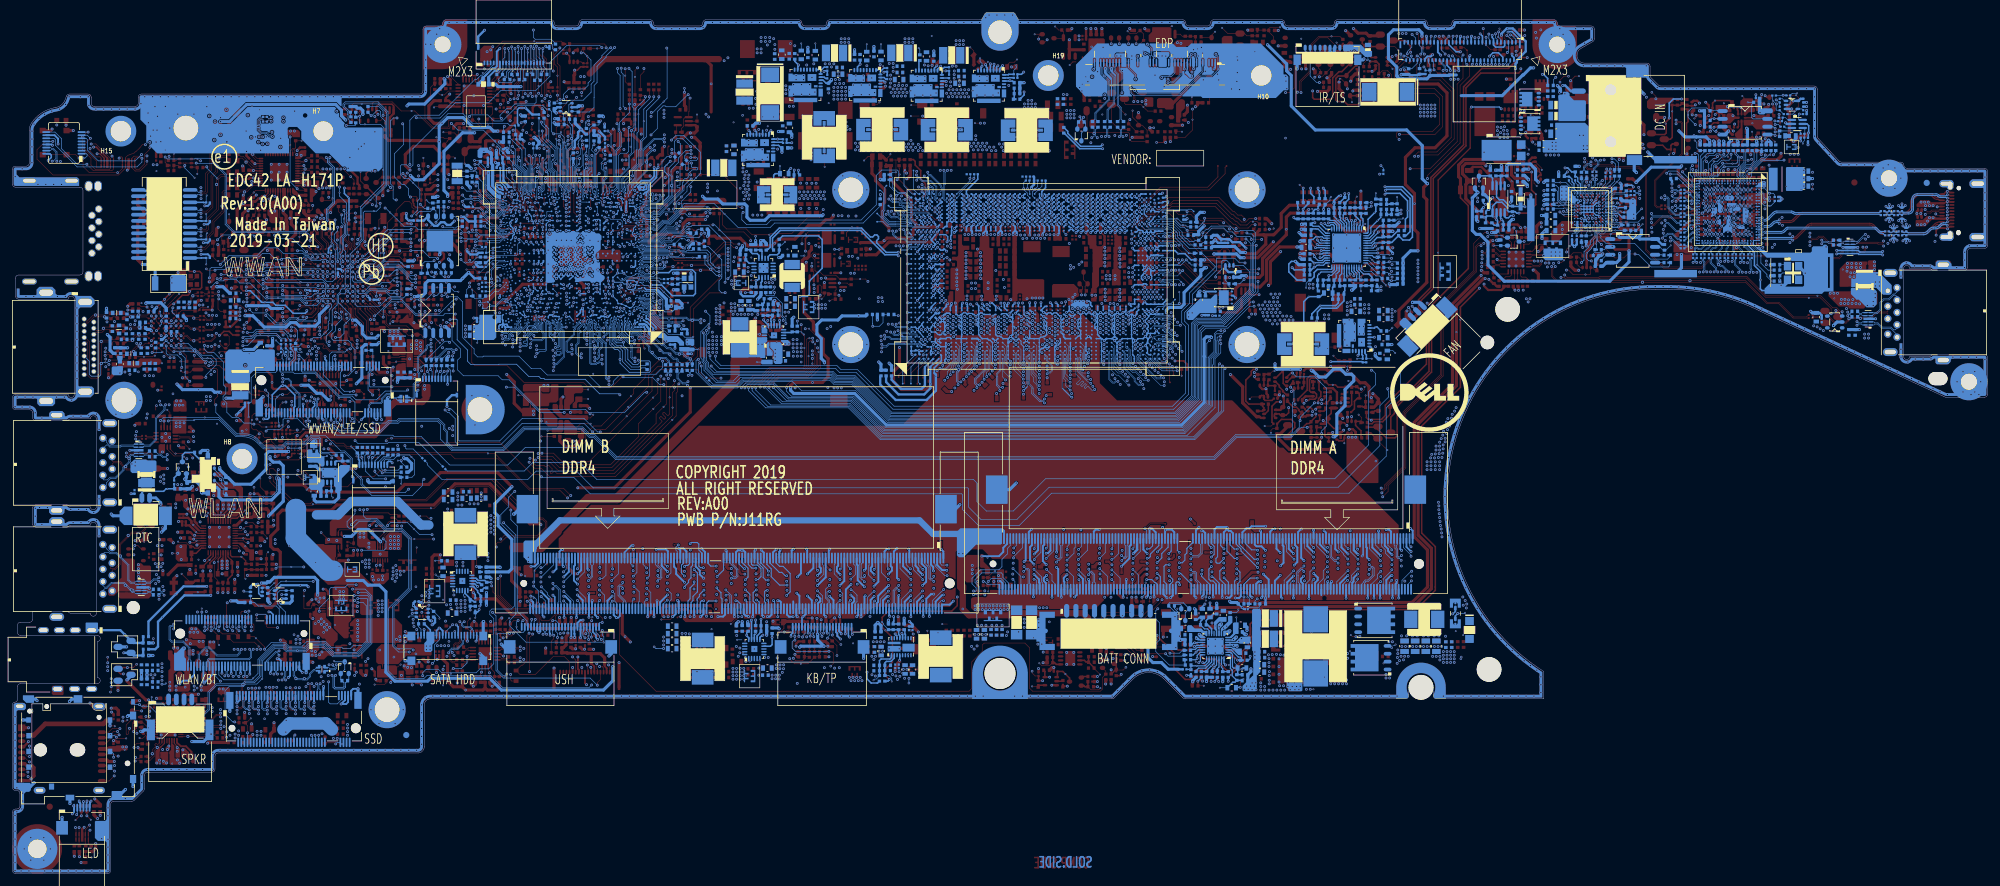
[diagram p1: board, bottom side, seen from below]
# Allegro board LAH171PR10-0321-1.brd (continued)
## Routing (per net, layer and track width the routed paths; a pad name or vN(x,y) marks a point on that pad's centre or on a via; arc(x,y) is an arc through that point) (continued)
+1.0V_AMPHYPLL: length 1.3
  BOTTOM w0.089: v1(243.96,85.8) 243.96,86.81 CH324.1
  vias: v2(244.45,88.15) v2(244.45,87.51)
+1.0V_AZPLL: length 2.8
  BOTTOM w0.254: v2(215.1,88.14) 215.1,88.38 216.41,89.68 UH1.D1 UH1.E1
  vias: v1(215.9,88.91)
+1.0V_BCLKPLL2: length 1
  BOTTOM w0.127: RH259.2 v1(208.24,84.74)
+1.0V_BCLKPLL2_R: length 2
  TOP w0.102: v2(213.37,86.07) v1(213.73,85.7)
  BOTTOM w0.254: UH1.B3 UH1.B2 UH1.B1 216.4,88.37
+1.0V_CLPLLEBB: length 13.5
  TOP w0.508: v2(231.19,97.77) 231.45,97.51 CH66.1 231.9,97.45 231.9,96.42 233.06,95.25 236.64,95.25 v1(239.25,92.65) 239.61,92.29 CC328.1 RH290.2
  BOTTOM w0.254: UH1.W31 231.57,97.39 v2(231.19,97.77)
+1.0V_DSW: length 7.9
  BOTTOM w0.127: v1(240.81,117.52) 240.69,117.52 240.37,117.19 240.37,116.36 239.89,115.87 RH255.2
  BOTTOM w0.254: UH1.BG45 UH1.BG46
  BOTTOM w0.381: RH255.2 CH35.1 239.73,114.67 239.73,111.96 238.93,111.16 UH1.BG46
+1.0V_DUSB: length 2.8
  TOP w0.127: v1(227.69,97.37) 227.36,97.04 227.33,97.04 v2(227.33,96.97)
  TOP w0.508: RH286.2 226.73,95.06 227.31,95.64
  BOTTOM w0.203: UH1.W23 227.6,97.32 227.33,97.04 v2(227.33,96.97) 227.24,96.97 226.92,97.3 UH1.W22
+1.0V_MPHY: length 7.5
  BOTTOM w0.203: UH1.V28 v2(230.37,96.9) 230.44,96.9 UH1.V30 ; UH1.V28 229.63,96.93 v2(229.56,96.93) ; UH1.V28 UH1.U29 UH1.V30 ; UH1.V30 v2(231.18,96.16) UH1.V31 v2(231.18,96.93) UH1.V30 ; UH1.V27 v2(228.89,96.9) 228.53,96.54 UH1.V25 228.79,96.27 UH1.U26
  BOTTOM w0.254: v2(229.56,96.93) 229.56,96.86 UH1.V27
  vias: v1(230.5,89.67) v2(228.61,91.74) v2(229.55,93.24) v2(229.73,90.59) v2(233.74,94.67) v2(234.18,93.42) v2(235.33,91.83) v2(235.87,93.42) v2(236.41,96.78) v2(236.84,93.62) v2(237.61,90.37)
+1.0V_OC: length 1.3
  TOP w0.127: 225.41,95.79 225.41,95.24 v1(225.27,95.1)
  BOTTOM w0.254: v2(225.76,96.93) UH1.V19
+1.0V_OCPLL1: length 1.1
  TOP w0.127: v1(216.94,84.87) 217.1,85.03 LC3.1
+1.0V_OCPLL1_R: length 2.5
  BOTTOM w0.254: v2(215.56,87.72) 215.56,88.17 216.57,89.18 UH1.C1 UH1.C2
  vias: v1(215.37,86.19)
+1.0V_PRIM: length 133.8
  TOP w0.508: 189.99,101.36 189.99,100.85 190.37,100.47 190.37,99.77 190.69,99.45 191.09,99.45 191.46,99.08 191.46,96.29 191.22,96.05 191.22,90.71 189.67,89.16 189.67,88 188.08,86.41 188.08,84.03 187.28,83.23 187.28,80.31 188.21,79.38 v4(189.8,79.38) 192.84,79.38 193.35,78.88 v2(193.35,78.56) ; CC334.1 86.2,130.09 86.19,130.08 86.19,130.06 86.04,129.91 v2(86.04,129.76)
  BOTTOM w0.203: v2(230.36,100.07) 230.02,99.73 UH1.AD28 ; v2(230.36,100.07) UH1.AD30 230.41,99.26 v2(230.38,99.26) ; v2(230.36,100.07) 230.7,100.42 230.77,100.42 ; v2(229.58,99.25) 229.97,99.64 UH1.AD28 ; v2(229.58,99.25) 229.96,98.87 UH1.AB28 ; v2(229.58,99.25) 229.24,99.58 UH1.AD27 ; v2(229.58,99.25) 229.24,98.91 UH1.AB27 ; 230.77,100.42 v2(230.37,100.82) ; 230.77,100.42 UH1.AF30 ; UH1.AB30 230.77,98.87 ; 230.77,98.87 230.74,98.87 v2(230.36,98.49) 230.02,98.83 UH1.AB28 ; 230.77,98.87 v2(230.38,99.26) ; v2(230.38,99.26) 230.38,99.23 UH1.AB28 ; v2(230.38,99.26) 230.38,99.28 UH1.AD28 ; UH1.AB27 v2(228.88,99.23) 228.88,99.28 UH1.AD27 ; UH1.AB27 229.56,98.55 v2(229.56,98.48) 229.63,98.48 UH1.AB28 ; UH1.AB23 v2(227.31,98.48) ; UH1.AB23 v2(227.31,99.25) ; UH1.AB23 v2(228.08,98.48) UH1.AA23 v2(227.31,98.48) ; v2(227.31,98.48) UH1.AA22 ; v2(227.31,98.48) UH1.AB22 v2(227.31,99.25) ; v2(227.31,99.25) UH1.AD23 227.69,99.72 v2(227.33,100.08) 227.67,100.42 UH1.AF23 v2(227.31,100.8) ; UH1.AD27 228.91,99.98 v2(228.91,100.05) 228.93,100.05 229.24,100.37 UH1.AF27 v2(228.88,100.78)
  BOTTOM w0.254: v2(226.53,99.25) UH1.AD20
  BOTTOM w0.305: UH1.AB20 v2(225.76,99.25)
  BOTTOM w0.508: v2(193.35,78.56) 193.35,78.12 192.84,77.61 182.99,77.61 177.88,72.5 130.2,72.5 126.55,76.15 126.55,83.61 126.55,86.39 126.18,86.76 125.46,86.76 v2(125.37,86.67)
  vias: v2(188.73,101.29) v2(189.29,101.55) v2(190.4,101.84) v2(204.1,92.24) v2(204.53,86.79) v2(204.53,86.15) v2(204.53,85.52) v2(204.78,91.86) v2(204.78,91.27) v2(204.78,90.69) v2(204.78,90.02) v2(204.78,89.43) v2(204.78,88.85) v2(205.37,91.34) v2(205.37,90.75) v2(205.37,90.08) v2(205.37,89.49) v2(205.37,88.91) v2(205.29,86.79) v2(205.29,86.15) v2(205.29,85.52) v2(205.29,84.88) v2(205.29,84.25) v2(205.93,86.79) v2(205.93,86.15) v2(205.93,85.52) v2(205.93,84.88) v2(205.93,84.25) v2(205.99,87.51) v2(206.56,86.15) v2(206.56,85.52) v2(206.56,84.88) v2(206.56,84.25)
+1.0V_PRIM_CNV_HVLO: length 0.6
  BOTTOM w0.254: v2(224.46,99.63) UH1.AE17
  vias: v1(223.2,99.83)
+1.0V_PRIM_FUSE: length 0.5
  BOTTOM w0.203: UH1.AD31 v2(231.18,99.25)
  vias: v1(235.52,98.94)
+1.0V_PRIM_XDP: length 4.2
  TOP w0.508: RC138.1 75.24,132.79 v1(75.43,132.6) 75.75,132.28 v2(76.13,132.28)
  BOTTOM w0.305: JXDP1.43 88.8,134.34 88.8,132.77 88.35,132.31 v2(88.35,132.28)
+1.0V_SRC: length 2.4
  TOP w0.127: v1(225.1,99.13) 224.62,98.65 RH258.2
  BOTTOM w0.203: UH1.W20 v2(225.76,97.71) UH1.W19
+1.0V_VCCSFR: length 2.3
  TOP w0.127: RC304.2 177.92,115.45 177.22,116.15 v1(177.22,116.28)
  TOP w0.508: RC422.1 178.48,115.9 RC304.2
+1.0V_VCCSFR_R: length 18.3
  TOP w0.127: v1(181.48,115.26) 180.84,115.9 RC422.2
  TOP w0.381: v2(168.08,102.12) 168.08,102.45 168.49,102.86 CC192.2
  TOP w0.508: RC422.2 CC333.2 180.21,113.17 179.64,112.6 179.64,112.04 179.62,112.01 178.16,110.55 178.16,108.48 178.56,108.09 178.56,105.49 177.47,104.4 v2(177.47,103.89)
  BOTTOM w0.203: v2(168.08,102.12) 167.95,102.25 167.95,102.94 168.29,103.28 UC1.J28 UC1.H28
+1.0V_VCCST: length 137.1
  TOP w0.508: 92.58,104.1 92.02,103.54 v2(92.02,100.66) ; 92.58,104.1 v4(92.58,108.28) 92.58,109.93 94.04,111.39 94.04,115.77 92.49,117.32 89.25,117.32 87.33,119.24 87.33,126.19 88.76,127.62 91.91,127.62 v2(94.21,129.92) ; 92.58,104.1 93.09,104.61 99.74,104.61 100.51,103.84 103.76,103.84 105.41,105.48 105.41,107.33 106.1,108.02 112.77,108.02 114.1,106.69 114.1,104.46 115.31,103.25 116.95,103.25 ; RC166.1 120.35,100.76 120.02,100.43 119.95,100.43 v2(119.9,100.38) 119.7,100.18 118.15,100.18 116.59,101.74 116.59,102.89 116.95,103.25 ; 182.09,101.92 182.01,101.99 178.56,101.99 v2(178.24,102.31) 178.18,102.31 177.77,102.71 174.12,102.71 173.57,103.26 173.57,104.05 173.1,104.52 ; RE90.1 281.83,95.92 281.28,95.92 v2(281.27,95.93) ; v2(283.68,94.63) 283.15,94.63 RE59.1 ; 118.39,103.25 RC157.1 ; 118.39,103.25 116.95,103.25 ; 118.39,103.25 117.61,104.03 RC152.1 ; v2(76.16,132.92) 76,133.08 RC218.1 ; 173.1,104.52 170.45,104.52 ; 173.1,104.52 173.1,105.11 173.81,105.82 173.81,108.12 173.88,108.19 173.88,108.85 177.22,112.19 177.22,114.3 RC80.1 177.29,114.42 177.29,114.42 RC304.1
  BOTTOM w0.254: UC1.H30 169.65,104.47 v2(169.67,104.47)
  BOTTOM w0.508: PCZ3.1 PRZ6.1 PRZ7.1 PRZ8.1 PRZ9.1 94.42,99.45 93.21,100.66 v2(92.02,100.66) ; v2(119.9,100.38) 120.65,100.38 121.62,101.36 125.18,101.36 RC79.1 ; RC71.1 181.05,90.31 181.21,90.14 v2(182.37,90.14) 185.04,90.14 185.7,89.48 188.34,89.48 189.1,88.72 189.1,87.2 188.39,86.49 188.39,83.25 187.89,82.75 v2(187.89,82.56)
+1.0V_VCCST_C: length 1.9
  TOP w0.127: 184.34,102.97 184.34,103.58 v1(183.45,104.47)
+1.0V_VCCSTG: length 44.2
  TOP w0.381: RH312.2 206.62,103.97 206.62,103.18 v2(206.78,103.03) 206.55,102.8 RH314.2
  TOP w0.508: RC326.2 181.15,100.02 179.51,100.02 177.46,102.08 170.73,102.08 169.96,102.84 169.96,103.06 ; v2(124.78,102.42) 124.77,102.42 124.63,102.56 RC135.2 ; v2(186.46,106.42) 186.46,106.22 186.96,105.71 187.66,105.71 188.58,104.79 190.43,104.79 192.65,102.56 195.26,102.56 v4(195.92,101.9) 196.35,101.47 200.25,101.47 201.48,102.7 205.24,102.7 205.57,103.03 v2(206.78,103.03)
  BOTTOM w0.254: UC1.H29 169.3,104.04 v2(169.66,103.68)
  BOTTOM w0.381: v2(124.78,102.42) 124.31,101.95 CC336.1 CC337.1
  BOTTOM w0.508: v2(124.78,102.42) 124.78,102.42 125.22,101.99 RC83.1 ; v2(206.78,103.03) 206.59,103.21 206.59,103.93 206.8,104.14 RH315.2
  vias: v2(182.49,99.47)
+1.0V_VCCSTG_C:
  vias: v2(185.39,99.53)
+1.0V_XTAL: length 12
  TOP w0.127: CH349.1 v1(209.93,92.28)
  TOP w0.508: RH238.2 211.58,92.15 CH349.1 211.56,92.39 CH2.1 212.53,91.77 v2(212.59,91.7)
  BOTTOM w0.152: UH1.P3 217.52,94.56 UH1.P2
  BOTTOM w0.254: 214.88,94.31 214.94,94.37 216.66,94.37 216.97,94.69
  BOTTOM w0.508: v2(212.59,91.7) 212.99,91.7 213.18,91.51 CH45.1 213.28,91.62 213.42,91.76 213.42,92.85 214.88,94.31
+1.0VS_VCCIO: length 44.8
  TOP w0.508: v2(175.76,85.04) 175.76,82.12 176.72,81.16 176.72,79.51 175.45,78.24 171.38,78.24 RC2.1 ; RC132.1 78.53,134.27 v2(78.53,135.5) ; v2(174.59,112.31) 174.49,112.31 173.99,112.82 173.99,113.49 174.05,113.56 RC1.2 ; QE11.1 286.66,96.57 286.62,96.53 286.62,96.02 286.98,95.67 287.27,95.67 287.27,95.64 v2(287.23,95.64)
  BOTTOM w0.254: UC1.G21 169.95,97.64 v2(169.69,97.38) 169.3,97.77 UC1.H21 ; v2(169.63,96.62) 169.26,96.98 UC1.H20 ; UC1.AG12 155.02,90.66 v2(155.19,90.66) ; v2(170.3,94.21) 169.95,94.56 UC1.G17 ; UC1.H17 169.25,94.56 v2(169.6,94.21) 169.25,93.86 UC1.H16 ; UC1.H19 169.28,96.2 v2(169.68,95.8) ; v2(170.29,95.83) 169.95,96.17 UC1.G19
  BOTTOM w0.381: v2(76.26,130.1) 76.26,130.89 76.04,131.11 76.04,131.46 74.61,132.89 74.61,134.52 76.69,136.6 77.68,136.6 78.53,135.75 v2(78.53,135.5)
  BOTTOM w0.508: v2(132.65,90.69) 132.65,91.07 132.2,91.51 130.3,91.51 129.79,92.02 129.79,93.93 127.09,96.63 RC439.2 126.88,97.55 126.51,97.91 126.24,97.91 v2(126.2,97.95)
  vias: v2(167.46,101.19) v2(167.49,101.74) v2(168.02,101.42) v2(168.92,97.38) v2(168.92,96.59) v2(168.92,94.23) v2(168.92,93.44) v2(178.49,92.47) v2(178.61,93.08) v2(179.19,93.1) v2(179.19,92.47) v2(186.88,88.43) v2(187.45,88.08) v2(187.73,91.96) v2(187.73,91.37) v2(188.31,91.96) v2(188.31,91.37) v2(188.9,91.96) v2(188.9,91.37) v2(189.48,91.98) v2(189.48,91.4) v4(182.24,92.91)
+1.2V_DDRP: length 3
  TOP w0.102: 168.02,40.33 v1(168.84,40.33)
  BOTTOM w0.254: PC208.1 PR204.1 176.78,40.7 176.66,40.81 176.66,41.5 v2(176.72,41.55)
  vias: v2(159.19,40.14) v2(160.08,40.14) v2(160.84,40.14) v2(161.79,40.14) v2(162.49,40.14) v2(163.19,40.14)
+1.2V_LDO: length 1.3
  TOP w0.203: 295.08,20.46 294.49,21.04 UR1.14
  vias: v1(295.21,17.79) v2(292.43,20.37) v2(292.43,19.78) v2(295.28,18.34) v2(295.71,17.88)
+1.2V_LSPCON_VDD: length 1.1
  TOP w0.254: v2(293.38,89.37) 293.8,88.95 UV31.D6 ; v2(295.77,87.76) UV31.F5
  vias: v1(296.22,87.26)
+1.2V_LSPCON_VDDA: length 0.5
  TOP w0.254: UV31.F4 v2(295.01,86.95)
  vias: v1(294.89,82.5) v2(294.56,83.59)
+1.2V_LSPCON_VDDRX: length 1.7
  TOP w0.254: UV31.B5 291.81,88.52 v2(291.81,88.54) ; UV31.B4 v2(291.8,86.94) ; UV31.B7 v2(291.8,89.34)
  vias: v1(283.9,88.47)
+1.2V_LSPCON_VDDTX: length 1.1
  TOP w0.254: UV31.G7 v2(296.6,90.14) ; UV31.G5 v2(296.6,88.54)
  vias: v1(298.19,92.21) v2(296.5,91.64)
+1.2V_MEM: length 128.6
  TOP w0.356: v2(192.26,41.52) 192.25,41.53 CD47.1 ; CD48.1 181.88,41.63 v2(181.98,41.53)
  TOP w0.381: UD1.5 120.53,91.42 121.26,90.7 123.73,90.7 124.11,91.08 v2(124.11,91.51)
  TOP w0.508: v2(208.92,41.54) 208.94,41.56 RD28.1
  BOTTOM w0.203: UC1.K6 168.07,86.66 167.62,86.66 167.43,86.47 UC1.L6 ; v2(155.25,86.15) 155.28,86.15 155.6,86.47 UC1.AF6 ; v2(155.25,86.15) 154.92,85.82 UC1.AG5 ; v2(155.25,86.15) 155.59,85.82 UC1.AF5 ; v2(155.19,88.83) 154.78,88.43 UC1.AG9 ; UC1.AL11 152.07,89.73 152.38,90.04 v2(152.45,90.04) 152.57,90.04 UC1.AJ12 ; UC1.Y12 160.39,90.38 v2(160.68,90.09)
  BOTTOM w0.254: JDIMM1.33 100.87,51.53 101.02,51.38 v2(101.02,51.34) ; 160.27,86.08 160.65,86.47 UC1.W6 ; 160.27,86.08 v2(160.27,86.02) ; 160.27,86.08 159.88,86.46 UC1.AA6 ; v2(162.79,86.14) 163.12,86.47 UC1.T6 ; UC1.AE12 156.44,90.38 v2(156.08,90.02) ; UC1.AW6 145.31,86.79 v2(145.23,86.79) 145.05,86.79 144.8,86.54 UC1.AY6 ; UC1.AR12 148.01,90.05 v2(147.87,90.05) 147.74,90.05 UC1.AT12 ; UC1.J5 169.19,85.82 v2(169.5,86.13) 169.17,86.47 UC1.J6 UC1.K6 ; JDIMM2.199 220.17,51.93 219.06,53.04 v2(218.8,53.04) ; v2(168.79,90.09) 168.54,90.34 168.54,90.38 UC1.K12 168.17,90.58 167.73,90.58 UC1.L12 ; v2(149.66,87.54) 149.66,87.48 149.31,87.13 UC1.AP7 149.25,86.73 UC1.AP6 UC1.AR6
  BOTTOM w0.279: JDIMM1.136 126.62,45.08 126.87,44.84 v2(126.87,44.65)
  BOTTOM w0.305: 135.35,55.71 135.35,55.78 135.37,55.75 JDIMM1.163 ; 135.35,55.71 135.29,55.77 134.98,55.77 134.37,55.16 JDIMM1.159 ; 135.35,55.71 v2(135.36,55.71) ; JDIMM2.141 203.67,52.14 v2(203.79,52.26) ; v2(199.03,52.31) 199.17,52.17 JDIMM2.123 ; JDIMM1.75 111.37,55.21 110.89,55.7 v2(110.84,55.7) ; JDIMM1.153 132.87,55.54 132.87,55.55 v2(132.8,55.55) 132.76,55.59 131.76,55.59 131.37,55.2 JDIMM1.147 ; JDIMM2.153 208.67,49.64 208.02,48.98 208.02,48.36 v2(207.4,47.74) ; v2(105.98,47.2) 105.98,47.1 106.12,46.95 JDIMM1.54 ; JDIMM2.12 171.42,44.42 170.67,45.18 v2(170.24,45.18) ; JDIMM1.12 95.62,46.81 95.46,46.97 v2(95.46,47.41) ; JDIMM2.148 207.42,41.95 207.85,41.52 v2(207.93,41.52) ; JDIMM2.112 196.42,41.85 196.74,41.54 v2(197.1,41.54) ; v2(225.39,44.13) 225.42,44.09 JDIMM2.220 ; JDIMM2.33 176.67,52.06 176.21,52.52 v2(176.2,52.52) ; JDIMM2.130 200.92,42 200.59,41.67 200.27,41.67 v2(200.15,41.54) ; JDIMM2.163 211.17,52.29 v2(211.42,52.54) 211.38,52.57 210.66,52.57 210.17,52.08 JDIMM2.159 ; JDIMM1.220 v2(149.62,44.67) ; JDIMM1.111 120.37,55.16 119.73,55.8 119.23,55.8 118.89,56.14 v2(116.63,56.14) ; v2(131.97,44.6) 131.62,44.94 JDIMM1.148 ; v2(207.72,52.52) 207.17,51.98 JDIMM2.147 ; JDIMM1.130 125.12,44.75 v2(125.09,44.71) ; JDIMM1.142 128.12,44.85 v2(127.87,44.59) ; JDIMM2.135 202.17,51.95 201.87,52.26 v2(201.21,52.26) 200.98,52.26 200.67,51.95 JDIMM2.129 ; v2(181.98,41.53) 181.92,41.58 JDIMM2.54 ; JDIMM2.96 192.42,41.68 v2(192.26,41.52) ; JDIMM1.123 123.37,55.17 122.81,55.74 v2(122.81,55.89) ; v2(197.73,41.54) 197.92,41.73 JDIMM2.118 ; UC1.R6 UC1.T6 ; v2(205.1,41.54) 204.25,41.54 203.92,41.87 JDIMM2.142 ; JDIMM2.111 196.17,51.92 v2(195.67,52.43) ; v2(198.11,52.31) 197.67,51.88 JDIMM2.117 ; v2(122.81,55.89) 122.94,56.02 124.48,56.02 124.87,55.63 JDIMM1.129 ; v2(122.81,55.89) 122.89,55.81 122.89,55.71 122.59,55.41 122.28,55.41 121.87,55 JDIMM1.117 ; JDIMM1.154 133.12,45.16 v2(132.55,44.59) ; v2(199.48,41.52) 199.42,41.58 JDIMM2.124 ; JDIMM1.118 122.12,44.92 122.43,44.61 v2(122.93,44.61) ; JDIMM2.136 202.42,41.93 202.43,41.92 v2(202.43,41.54) ; JDIMM1.241 154.87,55.23 v2(154.44,55.66) ; JDIMM1.124 v2(123.62,44.65) ; JDIMM1.141 127.87,55.48 v2(127.39,55.96) ; JDIMM2.178 v2(214.92,44.11) ; v2(121.51,44.55) 120.89,44.55 120.62,44.82 JDIMM1.112 ; v2(134.62,44.71) JDIMM1.160 ; JDIMM2.160 v2(210.42,41.52) ; v2(126.95,55.41) 126.72,55.41 126.37,55.06 JDIMM1.135 ; JDIMM1.199 144.37,55.29 144.08,55.59 v2(143.49,55.59) ; JDIMM2.241 230.67,52.06 230.37,52.37 v2(230.19,52.37) ; v2(187.03,52.45) 187.03,52.43 187.17,52.29 JDIMM2.75 ; v2(116.63,44.55) 116.62,44.56 JDIMM1.96 ; JDIMM1.178 v2(139.12,47.53) ; JDIMM2.154 v2(208.92,41.54)
  BOTTOM w0.381: v2(116.63,44.55) RD11.1
  vias: v2(123.53,91.51) v2(158.29,43.27) v2(158.29,42.68) v2(158.87,43.27) v2(158.87,42.68) v2(159.46,43.27) v2(159.46,42.68) v2(160.04,43.27) v2(160.04,42.68) v2(160.63,43.27) v2(160.63,42.68) v2(161.21,43.27) v2(161.21,42.68) v2(161.79,43.27) v2(161.79,42.68) v2(162.38,43.27) v2(162.38,42.68) v2(162.96,43.27) v2(162.96,42.68) v2(163.55,43.27) v2(163.55,42.68) v4(108.14,65.1)
+1.2V_RUN: length 128.4
  TOP w0.102: v2(240.17,54.08) 239.63,54.61 234.31,54.61 232.94,55.98 232.94,56.75 233.39,57.2 235.17,57.2 241.45,63.47 241.63,63.65 248.74,63.65 248.87,63.52 252.14,60.25 266.92,60.25 267.46,59.7 v1(270.51,59.7) 270.66,59.55 273.66,59.55 277.45,63.34 v2(277.45,64.02) ; v2(240.89,52.79) 240.89,53.3 240.62,53.57 240.11,53.57 239.29,54.39 234.21,54.39 232.71,55.89 232.71,56.84 232.84,56.98 232.84,56.98 233.35,57.48 234.82,57.48 241.23,63.89 248.85,63.89 252.27,60.48 267.06,60.48 267.42,60.12 270.59,60.12 270.94,59.78 273.25,59.78 276.92,63.45 276.92,64.07 277.55,64.7 277.55,65.35 277.45,65.45 276.91,65.45 275.54,64.08 v1(275.2,64.08) v2(274.56,64.08)
  TOP w0.127: v2(271.89,63.7) 272.28,63.7 v4(273.05,64.46)
  vias: v2(271.86,64.29) v2(281.16,92.4) v2(281.74,92.4) v2(286.42,81.15) v2(286.95,80.69) v2(288.55,65.94) v2(288.63,66.52) v2(300.07,80.71) v2(300.87,81.07) v2(302.57,89.23) v2(303.77,89.18)
+1.05VALWP: length 3.7
  TOP w0.102: v1(203.64,87.01) 203.51,87.01 202.89,87.63 202.89,88.85
  BOTTOM w0.508: PC310.1 199.33,91.15 199.17,90.98 PR1650.2
  vias: v2(199.58,90.4) v2(200.18,90.4) v2(200.76,90.4) v2(201.34,90.4) v2(201.93,90.4) v2(202.37,92.11) v2(202.34,91.51) v2(202.34,90.92) v2(202.62,90.4) v2(202.95,92.11) v2(202.92,91.5) v2(202.92,90.91)
+1.8V_ALW_PCHRES: length 2.9
  TOP w0.381: v2(244.14,104) 243.63,104 RH250.1
  TOP w0.508: RH294.1 233.66,113.03 234.1,113.47 v2(234.25,113.47) ; RH296.1 226.19,114.87 v2(226.35,114.7)
  vias: v1(219.2,117.49) v2(220.28,117.04)
+1.8V_ALW_VTR3: length 10
  TOP w0.305: v2(264.11,89.46) 264.11,89.8 264.37,90.06 264.37,91.22 UE1.N5
  TOP w0.356: v2(264.11,89.46) 264.14,89.43 CE21.1
  TOP w0.508: v2(256.92,90.75) 257.61,90.75 257.72,90.86 RE549.1
  BOTTOM w0.508: v2(264.11,89.46) 263.56,89.46 262.5,88.4 262.5,87.26 261.81,86.56 260.37,86.56 259.93,87.01
  vias: v1(258.11,90.71)
+1.8V_PHVLDO: length 1
  BOTTOM w0.254: UH1.AF19 225.44,100.42 v2(225.77,100.09) 226.09,100.42 UH1.AF20
  vias: v1(226.37,103.13)
+1.8V_PRIM: length 350.8
  TOP w0.102: v2(214.31,80.4) 214.31,76.33 v1(215.51,75.13) 217.93,72.72 217.93,70.61 222.45,66.09 230.46,66.09 231.77,67.4 233.56,67.4 234.06,67.89 v2(234.12,67.89) ; v2(234.56,66.84) 234.16,66.43 232.17,66.43 230.86,65.12 222.05,65.12 214.13,73.04 214.13,73.18 214.51,73.56 214.51,73.71 214.37,73.85 214.23,73.85 213.84,73.47 213.7,73.47 213.54,73.63 213.54,73.77 213.98,74.21 213.98,74.44 213.88,74.54 213.73,74.54 213.25,74.06 213.11,74.06 212.89,74.28 v1(212.89,76.97) 212.89,78.43 212.12,79.19 v2(212.12,79.67) ; v2(235.58,66.49) 235.58,66.4 234.65,65.47 233.57,65.47 232.26,64.16 221.64,64.16 v1(212.46,73.34) 211.83,73.97 211.83,77.67 211.63,77.87 211.63,78.92 v2(211.39,79.16) ; v2(267.69,69.45) 267.36,69.12 265.42,69.12 265.07,68.77 262.05,68.77 261.06,67.77 v1(256.79,67.77) 252.93,67.77 252.9,67.75 248.26,67.75 247.55,67.04 240.58,67.04 235.52,61.99 230.63,61.99 v2(229.37,60.73) ; v2(228.86,61.11) 229.97,62.22 235.43,62.22 241.14,67.92 v1(242.25,67.92) 242.28,67.92 242.38,68.03 252.86,68.03 252.93,68.1 260.92,68.1 261.87,69.05 265.02,69.05 265.54,69.57 266.78,69.57 267.19,69.98 268.36,69.98 v2(268.37,69.98) ; v2(212.12,78.62) 212.12,78.08 212.4,77.8 v1(212.4,75.32) 212.4,74.08 221.85,64.64 231.06,64.64 231.43,65.01 231.57,65.01 231.93,64.65 232.07,64.65 232.17,64.75 232.17,64.9 231.86,65.2 231.86,65.45 232.37,65.95 232.6,65.95 232.73,65.82 233,65.82 233.14,65.95 234.45,65.95 235.05,66.55 235.05,67.04 235.2,67.19 235.39,67.19 v2(235.45,67.13) ; v2(234.12,67.26) 233.78,66.91 231.97,66.91 230.66,65.61 222.25,65.61 215.07,72.78 215.07,74.24 v1(213.86,75.45) 213.43,75.89 213.43,79.51 213.8,79.89 v2(213.8,79.96) ; v2(233.52,67.96) 231.64,67.96 230.26,66.57 225.92,66.57 v1(215.55,76.94) 214.8,77.69 214.8,79.86 v2(214.77,79.89)
  TOP w0.381: RH607.2 RH613.1 RH604.2 RH614.1 RH605.2
  TOP w0.508: v2(268.03,68.65) 267.84,68.65 264.66,65.48 263.61,65.48 v2(263.58,65.5) ; v2(213.74,111.25) 212.52,112.47 212.52,113.43 211.85,114.1 211.13,114.1 RH607.2 ; v2(239.2,80.68) 237.99,79.47 237.99,76.02 236.53,74.56 235.83,74.56
  TOP w1.016: 210.91,106.91 210.18,107.64 208.21,107.64 207.13,108.72 204.21,108.72
  BOTTOM w0.102: v2(229.91,74.55) 233.87,74.55 237.94,78.62 v2(239.26,78.62)
  BOTTOM w0.127: v2(248.36,89.51) 248.25,89.62 248.24,89.61 247.33,89.61 247.2,89.48 247.2,86.3 245.55,84.64 245.55,82.84 245.01,82.3 240.5,82.3 240.47,82.32 237.61,82.32 235.62,80.34 233.99,80.34 233.66,80.01 233.16,80.01 233.04,79.89 226.53,79.89 224.2,77.56 221.09,77.56 v2(220.92,77.39)
  vias: v2(189.57,95.17) v2(189.54,94.56) v2(189.54,93.93) v2(197.99,106.44) v2(198.69,106.44) v2(199.45,106.44) v2(206.75,111.45) v2(206.76,110.87) v2(206.75,110.18) v2(210.91,105.96) v2(211.2,105.42) v2(219.94,115.36) v2(220.34,113.9) v2(220.53,115.33) v2(234.88,74.76) v2(234.88,74.18) v2(252.93,72.31) v2(254.19,89.04) v2(268.73,68.65) v2(269.04,35.82) v2(269.43,35.38) v2(273.92,76.31) v2(273.92,75.73) v4(205.16,110.35)
+1.8V_PRIM_PCH: length 93.5
  TOP w0.508: 216.21,101.93 216.21,102.18 215.07,103.33 212.72,103.33 212.38,102.99 211.23,102.99 210.72,103.49 210.72,105.01 210.02,105.71 v2(207.1,105.71) ; v2(233.69,56.41) 233.82,56.54 235.45,56.54 241.72,62.81 241.9,62.99 247.57,62.99 250.97,59.59 266.64,59.59 267.48,58.75 275.46,58.75 276.18,58.03 276.18,55.67 277.33,54.53 277.33,52.91 276.82,52.4 276.22,52.4 275.78,51.95 275.78,48.33 276.42,47.69 276.42,43.83 ; v2(190.83,98.82) RZ543.2 ; v2(283.78,44.08) 280.52,44.08 279.82,43.38 278.42,43.38 278.04,43 277.24,43 276.42,43.83 ; 276.42,43.83 v2(275.72,43.83)
  BOTTOM w0.254: v2(223.32,104.48) 223.55,104.26 UH1.AN15 ; UH1.AG19 225.74,100.83 v2(225.79,100.83) 226.14,101.18 UH1.AG20 ; v2(221.09,108.26) 221.27,108.44 UH1.BB11 ; UH1.AR15 v2(223.02,105.62)
  BOTTOM w0.508: v2(275.72,43.83) 275.61,43.72 274.23,43.72 273.87,44.08 RZ378.1 ; RZ376.1 282.59,43.83 282.84,44.08 v2(283.78,44.08)
  vias: v1(217.29,101.55)
+1.8V_RUN:
  vias: v2(261.62,34.74) v2(262,34.3) v2(262.99,30.63) v2(263.77,32.03) v2(276.6,53.99) v2(276.6,53.35) v2(291.71,62.88) v2(292.35,62.88) v4(274.32,52.97)
+1.8V_RUN_AUDIO: length 4.6
  TOP w0.203: UA1.29 288.63,55.8 289.18,56.35 289.18,56.63 ; CA57.1 287.06,58.99 287.06,58.37 286.62,57.93 UA1.33
  TOP w0.381: CA57.1 v2(287.8,59.2)
  vias: v1(289.64,57.64) v2(290.7,58.95) v2(291.05,60.35)
+1.8V_RUN_CARD: length 14.7
  TOP w0.127: v2(301.22,24.65) 300.66,24.65 v1(300.48,24.84)
  TOP w0.762: 316.35,22.36 315.59,22.36 313.75,24.2 304.35,24.2 303.84,24.71 303.4,24.71
  vias: v2(294.78,20.06) v2(301.18,25.28)
+1.8V_RUN_UZ8:
  vias: v1(265.3,34.11)
+1.8VALWP: length 1.2
  TOP w0.102: PC532.1 v1(237.32,77.32)
+1.24V_DPHY: length 3.1
  TOP w0.102: v1(232.53,102.75) 232.53,103.07 232.28,103.32 v2(232.28,103.42)
  TOP w0.508: RH237.1 231.9,103.04 v2(232.28,103.42)
  BOTTOM w0.254: UH1.AJ23 227.69,101.97 v2(227.32,102.35) 226.93,101.97 UH1.AJ22
+1.24V_DPHY_MAR: length 8.2
  TOP w0.254: CH30.1 216.02,115.71 216.48,115.25 CH559.1
  TOP w0.305: CH30.1 215.39,115.31 T75.1 v2(215.39,114.12)
  BOTTOM w0.203: 217.47,112 218.51,110.96 UH1.BG5
  BOTTOM w0.305: v2(215.39,114.12) 215.39,112.69 216.08,112 217.47,112
+1.24V_LDOSRAM: length 1.1
  BOTTOM w0.254: UH1.AK22 227.29,103.11 v2(227.33,103.11) 227.33,103.11 UH1.AK23
+1VS_VCCIOP: length 18.8
  BOTTOM w0.254: PR421.1 195.19,102.52 194.64,103.07 188.83,103.07 188.25,102.49 188.25,97.84 190.33,95.76 190.33,93.62 190.66,93.29 v2(191.83,93.29)
  vias: v1(191.77,95.32)
+2.5V_MEM: length 96.1
  TOP w1.016: 165.54,46.43 v4(165.54,42.77) 164.52,41.76 157.99,41.76 157.66,42.09 146.08,42.09 145.83,41.83 145.81,41.83 145.31,41.33
  BOTTOM w1.016: 165.73,55.06 165.89,54.91 170.33,54.91 172.52,57.1 230.63,57.1 234.5,53.22
  vias: v2(165.53,51.73) v2(166.16,51.73) v2(235.71,51.13) v2(235.71,50.43)
+2.8V_FHV0: length 0.5
  BOTTOM w0.203: UH1.AF31 231.49,100.42 v2(231.19,100.11)
  vias: v1(233.93,99.64)
+2.8V_FHV1: length 0.5
  BOTTOM w0.203: UH1.AG31 v2(231.18,100.8)
  vias: v1(232.79,100.28)
+3.3V_1.8V_AZIO: length 1
  TOP w0.127: v1(221.04,120.34) 220.86,120.17 RH292.2
+3.3V_1.8V_AZIO_R: length 3.5
  TOP w0.381: v2(221.84,117.71) 222.11,117.44 CC327.1 221.94,116.88 CC310.1 221.49,116.25 221.11,116.63 LC1.2
  BOTTOM w0.254: UH1.BB14 v2(222.3,108.44)
+3.3V_1.8V_GPPA: length 0.5
  BOTTOM w0.254: UH1.AN32 v2(232.27,104.04)
  vias: v1(231.64,104.47)
+3.3V_1.8V_GPPD: length 0.9
  BOTTOM w0.254: v2(227.23,104.44) 227.72,103.94 UH1.AN24
  vias: v1(225.42,112.91) v2(227.2,113.1)
+3.3V_1.8V_SPI: length 6.7
  TOP w0.381: RH250.2 RH246.2 v1(240.53,102.94) 239.23,102.94 v2(237.76,104.41)
  BOTTOM w0.254: UH1.AN44 v2(237.76,104.41)
+3.3V_ALW: length 295.9
  TOP w0.102: 271.15,88.66 RE723.2
  TOP w0.254: PR865.2 102.07,131.96 PR28.2 ; PC312.2 197.54,89.7 v2(197.73,89.51)
  TOP w0.305: JAPS1.7 225.06,33.49 225.55,33.98 ; 223.39,33.79 223.39,33.54 223.06,33.21 JAPS1.3 ; PC314.2 PC312.2 197.33,90.52 196.9,90.96 PR307.1
  TOP w0.356: v2(185.3,37.92) 185.81,38.43 185.81,39.3 186,39.49 CZ91.1
  TOP w0.381: PR1.1 v2(135.23,39.01) ; PR838.1 PR839.1 107.06,72.97 v2(107.32,73.24) ; PR828.1 113.57,81.93 111.43,81.93 v2(111.02,81.52) PR825.1 111.05,80.95 PR852.1 ; v2(46.55,124.53) 46.93,124.91 47.49,124.91 47.71,124.7 PR4.2 ; RZ133.1 276.96,74.92 RZ1397.1 ; v2(263.57,105.35) 263.81,105.11 RE302.2 ; PR851.1 104.49,70.81 104.61,70.93 PR821.2 104.34,71.36 v2(104.02,71.68) ; v2(114.4,77.39) 114.4,77.26 114.7,76.96 PR833.1 ; v2(114.4,77.39) 115.07,77.39 PR830.1 ; v2(114.4,77.39) PR824.1 ; v2(271.49,70.72) 271.33,70.56 RZ1405.1 RZ1404.2 ; v2(282.32,89.51) 282.6,89.51 283.76,88.35 UZ10.5 284.58,88.38 CZ93.1 ; RE43.2 RE37.2
  TOP w0.457: v2(271.81,87.88) 271.73,87.96 RE724.2 ; v2(275.32,87.06) 275.32,87.31 275.66,87.65 RE300.1
  TOP w0.508: v2(172.72,39.06) 173.79,40.14 174.86,40.14 PR205.1 ; RE821.2 v2(281.53,26.07) ; v2(281.21,93.6) 281,93.6 280.54,94.05 RE25.1 ; v2(281.16,86.08) 278.66,86.08 RZ1484.1 ; v2(102.29,132.85) 102.92,132.23 PR865.2 ; RZ1489.1 237.79,121.5 239.28,120.01 v2(240.64,120.01) 242.2,120.01 243.53,118.68 RH434.2 244.56,118.31 QH7.3 245.16,118.91 RH432.1 ; v2(281.27,98.33) 281.23,98.37 RE91.2 RE10.2 ; v2(64.84,101.45) 63.41,102.88 61.34,102.88 60.93,102.48 59.43,102.48 58.98,102.94 RT483.1 ; v2(277.87,100.73) 277.73,100.73 277.62,100.85 RE606.2 RE63.2 ; RE526.1 RE365.2 RE5.2 275.14,98.24 275.46,98.56 v2(275.49,98.56) ; 223.39,33.79 223.39,34.87 224.07,35.56 225.55,35.56 ; 271.15,88.66 271.15,87.97 RE724.2 RE725.2 ; RE605.2 271.94,85.19 v2(271.24,85.19) ; 225.55,35.56 225.55,33.98 ; 225.55,35.56 226.3,35.56 226.38,35.63 229.42,35.63 229.48,35.7 RZ8.1 230.28,35.72 RZ9.1 230.06,36.52 229.61,36.97 229.61,38.3 229.33,38.59 v2(229.33,38.89) ; v2(282.32,90.78) 283.23,90.78 283.33,90.88 RE69.1 ; RZ518.1 277.03,88.8 276.21,89.62 CE60.1 275.92,90.24 275.67,90 v2(275.41,90) 275.4,90.02 274.75,90.02 RE35.2 ; RE827.1 268.49,89.71 v2(268.38,89.81) ; RE729.2 254.82,92.72 v2(254.64,92.9) ; v2(254.64,97.17) RE727.2 RE728.2 ; 227.2,70.43 227.2,70.12 227.97,69.35 v2(228.02,69.35) 228.42,68.96 229.66,68.96 230.63,69.92 PR517.1 ; v2(277.45,43.69) 277.62,43.86 277.62,45.76 v2(278.82,46.96) ; RE84.2 RE79.1 277.68,94.05 277.69,94.04 277.84,94.04 v2(277.97,93.91) ; v2(278.13,75.71) 278.13,75.71 278.13,75.7 277.43,75.7 276.92,75.19 RZ133.1 ; RE83.2 277.74,95.96 278,96.21 v2(278,96.21) ; v2(285.43,121.54) RZ1390.2 283.88,120.93 QZ38.3 ; v2(249.64,121.27) 250.95,121.27 251.77,122.1 251.77,124.1 250.95,124.93 RZ1410.1 ; v2(254.65,101.96) 254.65,101.97 255.24,101.97 255.46,102.18 RE505.2 RE362.2 RE11.2 ; v2(109.66,107.35) 110.26,106.75 112.64,106.75 113.28,106.12 v4(113.28,104.15) 113.28,103.25 117.11,99.42 117.11,96.85 117.62,96.34 119.5,96.34 v2(119.76,96.59) ; RE524.2 255.55,111.63 254.77,112.41 v2(254.77,112.84) ; RC241.1 88.18,134.69 88.58,135.09 v2(88.58,135.33) ; v2(250.11,118.31) 250.27,118.48 255.13,118.48 255.16,118.51 258.33,118.51 258.83,119.02 CE52.1 ; RH431.2 248.72,113.17 v2(248.53,112.98) ; RE561.2 260.87,82.13 259.77,81.03 258.83,81.03 258.83,81.04 v2(258.46,81.04) ; v2(258.96,87.61) 259.08,87.72 RZ1474.2 259.6,88.26 259.87,87.99 RE37.2 ; RE301.2 RE21.2 271.19,105.66 271.09,105.56 270.37,105.56 v2(270.28,105.64) ; RE730.2 v2(254.64,94.5) ; RZ1482.1 RE525.2 RE721.2 RE722.2 266.54,108.74 267.66,107.61 v2(267.66,106.84) ; 243.01,54.3 244.67,52.64 244.67,45.49 v2(244.6,45.41) 244.6,44.84 244.15,44.4 240.91,44.4 238.37,41.86 236.64,41.86 235.95,41.16 235.95,40.45 235.12,39.62 CZ73.1 ; RE8.2 RE532.1 274.91,94.15 275.04,94.15 275.13,94.24 v2(275.39,94.24) ; v2(104.17,73.58) 104.17,73.71 PQ807.2 ; v2(31.41,124.89) 32.24,124.07 32.24,123.32 32.02,123.1 32.02,118.92 31.52,118.41 v2(31.35,118.41) 31.1,118.41 30.28,119.23 29.43,119.23 v2(28.95,119.71) ; v2(271.81,87.88) RE704.2 ; RE68.2 RE303.2 v2(252.13,104.85)
  BOTTOM w0.254: PU301.15 196.92,88.62 197.73,89.43 v2(197.73,89.51) ; JLED1.1 309.07,9.96 v2(309.37,9.66) ; UT32.5 29.17,121.17 28.9,120.9 28.9,119.76 v2(28.95,119.71) 28.96,119.7 28.96,118.97 CT237.1 ; PR107.1 244.28,45.1 v2(244.6,45.41)
  BOTTOM w0.305: v2(185.3,37.92) 185.81,38.43 185.81,38.82 186.01,39.03 JKBTP1.6
  BOTTOM w0.381: RE12.2 254.66,94.51 v2(254.64,94.5) ; 130.68,33.03 130.66,33.02 PR726.1 ; CT360.1 30.22,125.24 30.56,124.89 UT34.5 v2(31.41,124.89) ; RT68.2 v2(64.84,101.45)
  BOTTOM w0.508: 130.68,33.03 132.37,33.03 133.45,34.11 134.83,34.11 135.62,34.91 135.62,37.05 135.61,37.07 135.61,37.4 135.62,37.41 135.62,37.92 135.23,38.31 v2(135.23,39.01) ; v2(192.84,89.93) 193.1,89.67 PR1711.1 ; v2(254.77,112.84) 254.08,112.15 252.68,112.15 250.11,114.72 v2(250.11,118.31) 250.11,120.81 v2(249.64,121.27) 248.73,122.18 246.23,122.18 244.64,120.6 241.93,120.6 241.35,120.01 v2(240.64,120.01) ; PR414.1 201.51,100.77 PR413.1 201.43,101.01 201.12,101.31 v2(201.12,101.48) ; PR404.1 198.12,93.48 198.26,93.35 198.26,93.28 v2(198.69,92.85) ; PR113.1 195.33,39.71 v2(195.2,39.58) ; RZ377.1 277.79,44.37 277.79,44.05 277.64,43.89 277.64,43.88 v2(277.45,43.69) ; v2(111.02,81.52) 114.82,81.52 115.1,81.8 v2(115.1,82.4) ; v2(278.82,46.96) 277.99,46.96 RZ381.1 277.48,47.14 276.73,47.89 270.25,47.89 269.74,47.38 v2(269.74,45.03) ; v2(31.35,118.41) 30.99,118.78 RT48.2 ; v2(285.43,121.54) 283.98,121.54 281.21,124.31 266.84,124.31 265.9,123.37 265.9,122.48 v2(265.22,121.8) ; v2(119.76,96.59) 119.8,96.64 120.52,96.64 CZ104.1 121.8,96.39 UZ34.5
  vias: v2(146.76,135.39) v2(146.76,134.77) v2(152.78,37.09) v2(153.41,37.09) v2(184.72,94.24) v2(185.3,94.24) v2(202.29,95.83) v2(202.29,95.25) v2(202.57,94.73) v2(202.88,95.83) v2(202.88,95.25) v2(229.99,38.89) v2(230.56,38.81) v2(241.2,57.54) v2(241.2,56.84) v2(241.2,56.15) v2(241.2,55.51) v2(241.2,54.88) v2(241.77,57.86) v2(241.77,57.16) v2(241.77,56.46) v2(241.77,55.83) v2(241.77,55.19) v2(242.4,57.61) v2(242.4,56.91) v2(242.4,56.21) v2(242.4,55.57) v2(242.4,54.94) v2(253.13,85.81) v2(253.13,85.18) v2(253.13,84.54) v2(253.61,99.9) v2(253.76,86.13) v2(253.76,85.5) v2(253.76,84.86) v2(254.06,81.48) v2(256.7,54.48) v2(256.7,53.84) v2(256.7,53.21) v2(256.7,52.57) v2(256.82,69.19) v2(257.34,54.48) v2(257.34,53.84) v2(257.34,53.21) v2(257.34,52.57) v2(257.97,54.48) v2(257.97,53.84) v2(257.97,53.21) v2(257.97,52.57) v2(260.51,122.38) v2(261.47,53.4) v2(261.47,52.76) v2(262.27,55.02) v2(262.27,54.38) v2(262.91,55.02) v2(262.91,54.38) v2(267.46,67.19) v2(268.73,44.57) v2(269.36,44.52) v2(269.55,43.94) v2(270,44.38) v4(260.5,119.9) v4(263.62,119.94)
+3.3V_ALW2: length 4.7
  TOP w0.508: RE57.2 255.84,104.85 255.67,105.02 v2(254.61,105.02)
  BOTTOM w0.127: v2(254.61,105.02) 255.24,105.02 v1(255.34,105.12)
  BOTTOM w0.508: PR104.2 240.33,49.54 v2(240.27,49.48)
+3.3V_ALW_DSW_R: length 4.7
  TOP w0.102: v1(245.99,114.75) QH7.1
  TOP w0.508: RH439.2 245.27,117.42 QH7.1
+3.3V_ALW_PCH: length 343.6
  TOP w0.102: v2(81.83,101.5) 82.25,101.5 82.55,101.2 82.55,97.28 87.94,91.88 87.94,80.45 93.98,74.42 93.98,65.59 96.83,62.74 96.83,61.78 v2(97.71,60.91) ; v2(97.85,61.54) 97.15,62.24 97.15,62.74 94.2,65.69 94.2,74.51 88.17,80.54 88.17,91.98 82.77,97.38 82.77,101.3 82.17,101.9 81.41,101.9 v2(81.37,101.86)
  TOP w0.254: CZ216.1 275.48,67.87 274.99,68.36 274.99,68.95 275.27,69.23 UZ51.5 ; v2(236.15,123.75) 236.2,123.75 236.22,123.77 RZ1408.1
  TOP w0.305: JAPS1.1 v2(222.06,33.47) ; RZ69.1 240.6,133.08 v2(240.32,133.36)
  TOP w0.381: RI74.2 76.62,94.72 76.46,94.56 76.46,94.53 76.35,94.42 v2(76.35,94.3) ; RH80.1 227.5,120.63 v2(227.19,120.32) 227.19,120.32 227.06,120.32 226.68,119.93 RH81.1 226.04,119.64 RC74.1 ; v2(274.44,68.22) 275.03,67.64 CZ216.1 ; RI62.2 RI64.2 75.29,104.26 v2(75.43,104.4) 75.94,104.91 77.94,104.91 78.4,104.45 ; 229.08,114.26 RH78.1 229.37,115.78 RH67.1 229.37,116.77 229,117.14 v2(228.47,117.14) 228.41,117.2 RH77.1 ; UH7.5 228.09,133.1 228.47,132.72 v2(228.47,132.66) ; RH371.2 v2(224.34,119.21) ; v2(80.56,96.05) 80.53,96.05 79.85,95.38 RI72.2 79.29,94.93 RI65.2 ; v2(244.75,100.64) 244.75,99.61 RH641.2
  TOP w0.508: RH310.1 248.1,101.99 247.2,101.09 247.2,100.76 247.07,100.64 247.07,100.59 246.66,100.18 v2(246.66,100.06) ; RC559.1 207.52,106.37 v2(207.04,106.86) ; RZ379.1 273.87,84.72 273.38,84.23 273.38,83.18 274.38,82.18 277.36,82.18 277.81,82.62 279.1,82.62 281.24,80.49 v2(281.24,79) ; RC557.2 244.86,104.11 v2(244.75,104) ; v2(72.09,105.18) 72.31,105.18 72.81,104.67 RI66.2 ; RI67.2 78.4,104.45 ; v2(229.93,127.99) 229.86,127.99 229.72,127.85 RH553.2 ; v2(224.34,119.21) 224.28,119.27 v2(224.28,120.03) 224.71,120.46 RC74.1 ; 207.2,131.65 206.18,130.63 v4(206.18,127.65) 206.18,123.11 ; 229.08,114.26 228.86,114.03 228.86,111.63 RH309.1 ; RC133.1 91.31,135.29 v2(91.37,135.35)
  TOP w1.016: 204.94,131.65 223.45,131.65 225.79,129.31
  BOTTOM w0.254: RH204.2 237.29,121.06 237.46,121.22 237.46,123.5 237.2,123.75 v2(236.15,123.75)
  BOTTOM w0.305: RH185.1 242.64,128.98 242.64,128.99 242.48,129.16 242.46,129.16 241.44,130.19 241.11,130.19 240.81,130.49 JSPI1.5 240.81,132.87 v2(240.32,133.36)
  BOTTOM w0.381: v2(228.47,117.14) 228.21,117.4 228.21,118.44 227.68,118.97 RH61.1 227.68,119.83 v2(227.19,120.32) 227.19,120.25 226.47,119.52 RC866.1 ; v2(224.28,120.03) 223.32,119.07 RH400.2 ; RH203.2 235.09,122.69 v2(236.15,123.75) ; RH640.2 v2(232.34,124.79)
  BOTTOM w0.508: 272.79,59.38 273.24,58.94 ; v2(91.37,135.35) 91.37,135.88 91.88,136.39 95.96,136.39 96.78,135.57 96.78,131.72 95.44,130.38 95.44,128.97 95.37,128.9 95.37,128.84 95,128.47 94.47,128.47 94.47,128.47 90.56,128.47 RC137.2 90.03,129 87.61,129 87.61,129.01 87.03,129.01 86.95,129.08 85.82,129.08 ; RH376.1 RC834.1 224.47,119.34 v2(224.34,119.21) 224.28,119.15 RC840.1 ; DH3.2 243.02,128.36 RH185.1 ; v2(274.44,68.22) 277.63,68.22 278.07,67.78 278.07,66.04 278.06,66.03 278.06,65.35 280.47,62.94 283.14,62.94 284.23,64.03 RH101.1 284.54,64.3 285.55,65.31 v2(285.55,65.61) ; RT391.2 42.61,118.33 v2(42.67,118.39) ; v2(227.19,120.32) 228.14,121.26 RH57.1 ; RH56.1 230.88,122.01 v2(231.44,122.01) ; 264.98,47.38 262.38,47.38 261.62,46.62 259.77,46.62 258.72,45.57 258.72,32.56 257.27,31.11 251.98,31.11 251.52,31.57 241.96,31.57 240.06,29.67 223.57,29.67 222.06,31.18 v2(222.06,33.47)
  BOTTOM w1.524: 269.93,57.99 266.44,57.99 264.28,60.14 256.85,60.14 253.04,56.33 251.77,56.33
  BOTTOM w3.302: 273.24,58.94 273.26,58.91 273.26,54.2 268.03,48.97 267.27,48.97
  vias: v2(72.09,104.54) v2(75.01,94.31) v2(80.74,102.98) v2(85.53,128.39) v2(86.11,128.39) v2(203.47,131.86) v2(204.08,131.39) v2(206.59,122.31) v2(207.02,122.74) v2(226.68,128.83) v2(227.26,128.83) v2(231.8,116.07) v2(237.71,112.98) v2(243.71,95.26) v2(243.71,94.56) v2(246.57,103.45) v2(247.73,92.05) v2(247.93,72.31) v2(247.93,71.73) v2(247.93,70.79) v2(248.12,91.61) v2(248.47,71.96) v2(248.53,91.13) v2(248.72,56.84) v2(248.72,56.14) v2(249.23,56.46)
+3.3V_ALW_PCH_UZ3:
  vias: v1(261.81,48.4) v2(261.42,50.68) v2(261.42,50.1) v2(261.42,49.52) v2(262.01,50.68) v2(262.01,50.1) v2(262.01,49.52) v2(262.53,50.42)
+3.3V_ALW_PCHRES: length 14.1
  TOP w0.254: v2(242.49,106.94) 242.92,106.51 RH300.1 243.68,106.51 RH302.1
  TOP w0.508: RH292.1 218.82,119.39 217.61,118.18 RH298.1 ; RH303.1 RH246.1 243.86,102.94 v2(244.13,103.21)
  TOP w1.016: RH279.2 242.69,92.4 241.07,94.02 240.12,94.02 239.37,94.78 239.37,95.68
  vias: v1(218.63,115.39) v2(220.28,120.28) v2(225.62,111.78) v2(225.62,111.2) v2(232.94,112.34) v2(232.94,111.76) v2(240.15,96.72) v2(240.28,95.07) v2(241.87,103.97)
+3.3V_ALW_UE1: length 30.3
  TOP w0.203: 265.67,100.73 265.67,101.7
  TOP w0.229: 265.67,100.73 266.07,100.33 UE1.B7
  TOP w0.254: UE1.H1 260.22,95.33 v2(259.81,95.73) 259.66,95.88 CE15.1
  TOP w0.305: v2(261.67,93.32) 261.67,93.33 UE1.K2
  TOP w0.356: UE1.G8 266.48,96.52 v2(266.39,96.52) ; UE1.M9 v2(268.07,91.73)
  TOP w0.381: CE19.1 281.3,90.35 v2(281.47,90.17) ; v2(265.85,104.55) 265.97,104.43 CE23.1 CE14.1 265.97,101.99 265.67,101.7
  TOP w0.508: v2(254.44,98.18) 256.7,98.18 RE314.2
  BOTTOM w0.356: CE20.1 266.47,96.61 v2(266.39,96.52) ; v2(261.67,93.32) 261.67,93.32 261.29,92.94 CE13.1
  BOTTOM w0.508: v2(268.07,91.73) 269.46,90.34 269.46,89.15 270.12,88.49 272.69,88.49 273.26,89.06 274.12,89.06 274.84,88.34 278.38,88.34 v1(279.24,89.2) 280.21,90.17 v2(281.47,90.17)
  vias: v2(262,101.55)
+3.3V_ALW_UZ12: length 1.1
  TOP w0.102: v1(250.95,123.84) 250.77,124.01 RZ1410.2
+3.3V_ALWP: length 3.4
  BOTTOM w0.254: v2(241.71,47.09) PR108.2 242.73,47.38 243.8,47.38 244.03,47.62 244.04,47.62 244.18,47.76 PU100.14
  vias: v1(247.07,56.27) v2(243.84,59.76) v2(244.47,59.76) v2(244.43,55.83) v2(244.43,55.13) v2(245.01,54.88) v2(245.17,59.76) v2(245.58,55.89) v2(245.58,55.19) v2(246.15,56.15) v2(246.15,55.51) v2(246.15,54.81) v2(246.44,59.57) v2(246.72,55.13) v2(247.07,59.57)
+3.3V_CAM: length 2.7
  TOP w0.127: CZ1.1 129.77,130.78 129.09,131.46 129.09,131.98 v4(129.04,132.02)
  BOTTOM w0.254: v2(129.76,130.06) JEDP1.11
+3.3V_CAM_F: length 1.5
  TOP w0.102: v1(132.15,128.9) 131.54,128.29 FZ5.2
+3.3V_DSW: length 9.7
  TOP w0.508: v2(242.88,116.72) 242.62,116.99 RH439.1 RH434.1 242.49,118.44 v1(241.07,118.44) 240.55,118.44 v2(240.36,118.25) 239.77,117.66 239.77,116.85 239.64,116.72 RH94.2 RH93.2 RH440.2
  BOTTOM w0.508: RH602.2 239.72,118.25 RH243.2 239.85,118.25 239.85,118.25 v2(240.36,118.25)
+3.3V_EC_PLL: length 5.5
  TOP w0.305: UE1.F1 260.8,96.93
  TOP w0.356: CE18.1 259.46,98.26 260.8,96.93
  TOP w0.381: CE18.1 258.14,99.11 CE17.1 256.79,99.11 RE314.1
+3.3V_FPBTN: length 20.6
  TOP w0.127: v4(287.65,123.96) 287.03,123.34 RZ1392.2
  TOP w0.203: DT42.8 DT42.2 304.22,115.64 304.92,116.34 v2(305.37,116.34)
  TOP w0.305: RE708.2 274.72,91.87 275.18,91.41 275.33,91.41 v2(275.39,91.35)
  TOP w0.381: 280.61,91.83 281.19,91.83 v2(281.27,91.75)
  TOP w0.508: RE826.1 266.06,86.9 QE20.2 v2(266.21,87.94) ; RZ1391.1 RZ1390.1 285.43,119.41 v2(285.44,119.4) ; 280.61,91.83 280.17,92.26 RE707.2 ; v2(281.27,96.84) 281.26,96.82 280.27,96.82 RE706.2
  BOTTOM w0.305: JFPBTN1.14 312.24,119.35 311.67,118.78 v2(311.67,117.93)
  BOTTOM w0.508: v2(275.39,91.35) 277.26,91.35 277.71,91.79 281.23,91.79 v2(281.27,91.75)
  vias: v2(284.48,123.45)
+3.3V_FUSE: length 3.2
  TOP w0.508: 240.66,105.99 242.12,105.99 242.51,105.6 RH300.2
  BOTTOM w0.254: UH1.AT44 237.62,105.45 237.62,105.77 v2(237.62,105.77)
  vias: v1(238.25,105.67)
+3.3V_HDD: length 23.2
  TOP w0.381: RN18.1 CN16.1 ; RN16.1 244.85,40.4 v2(244.47,40.78) 244.09,40.4 RN10.2 ; v2(241.8,40.75) RN20.1 241.29,40.12 RN12.1
  TOP w0.508: RN14.1 240.4,30.01 240.74,29.67 242.35,29.67 242.69,30.01 ; RN6.1 RN8.2 242.69,30.01 ; 246.37,30.2 247.83,30.2 248.76,31.14 248.76,33.88 249.49,34.61 249.49,35.98 ; 246.37,30.2 RN18.1 ; 246.37,30.2 v4(245.84,29.67) 243.03,29.67 242.69,30.01
  vias: v2(240.3,37.75) v2(248.6,36.84) v2(249.23,36.84) v2(249.82,36.84) v2(250.4,36.84) v4(247.59,39.14) v4(248.53,37.54)
+3.3V_HDD_M2: length 8.6
  BOTTOM w2.032: 275.27,23.29 274.29,24.27 268.41,24.27 267.44,23.29
  vias: v2(259.33,44.08) v2(259.33,43.5) v2(259.33,42.91) v2(259.33,42.33) v2(259.96,44.08) v2(259.91,43.5) v2(259.91,42.91) v2(259.91,42.33) v2(259.96,41.73) v2(264.92,24.12) v2(264.92,23.53) v2(264.92,22.95) v2(264.92,22.36) v2(278.89,23) v2(278.89,22.36) v2(279.52,23) v2(279.52,22.36) v2(282.51,23.06) v2(282.51,22.36) v2(283.08,22.55) v2(283.08,21.92) v4(274.82,24.78) v4(274.89,22.87) v4(278.32,25.03)
+3.3V_LAN:
  vias: v1(295.78,113.55) v2(249.57,85) v2(253.36,113.86) v2(253.44,114.44) v2(254.06,80.66) v2(254.06,80.02) v2(270,110.25) v2(273.17,105.85) v2(273.17,105.27) v2(273.49,120.03) v2(274.12,120.03) v2(295.69,114.58) v2(296.3,114.58)
+3.3V_LAN_OUT: length 9.3
  TOP w0.203: UL1.15 279.83,111.97 279.9,111.9 280.39,111.9 v2(280.4,111.89) ; UL1.19 279.55,113.57 279.62,113.64 v2(280.12,113.64) ; UL1.29 276.56,117 277.17,117.61 CL7.1
  TOP w0.381: CL7.1 v2(277.87,117.96)
  TOP w0.508: CL28.1 274.7,105.36 274.84,105.5 274.84,105.66 274.84,105.67 274.84,106.32 275.3,106.79 v2(275.3,107.2) ; CL29.1 280.81,113.64 v2(280.12,113.64)
  vias: v1(274.93,109.15)
+3.3V_LAN_UZ2: length 0.9
  TOP w0.127: v1(257.55,79.7) 257.55,79.77 257.11,80.21 256.92,80.21
+3.3V_LSPCON: length 23.9
  TOP w0.33: RV606.2 299.77,91.09 v2(300.4,91.09)
  TOP w0.508: RV617.1 282.39,78.94 UV32.8 283.95,77.7 CV630.1 285.3,77.67 v2(285.44,77.81) ; v2(288.54,92.66) 288.98,92.66 289.38,92.26 289.38,92.24 289.47,92.15 289.47,91.97 289.56,91.88 RV608.1 ; RV616.1 292.28,78.94 v2(292.46,79.12)
  BOTTOM w0.508: v2(292.46,79.12) 291.57,78.23 v1(288.98,78.23) 286.81,78.23 286.39,77.81 v2(285.44,77.81) ; v2(290.94,89.38) 290.94,89.61 RV607.2 ; v2(303.72,87.13) 303.27,86.69 303.27,84.59 302.76,84.08 CV1641.1 ; RV605.2 294.19,91.39 295.08,92.28 297.39,92.28 v2(297.49,92.17)
+3.3V_LSPCON_VDD: length 2.8
  TOP w0.203: UV31.B2 v2(291.8,85.34)
  TOP w0.254: UV31.G4 v2(296.62,87.75) ; UV31.G2 v2(296.6,85.34)
  BOTTOM w0.508: v2(296.62,87.75) 296.81,87.95 297.28,87.95 CV609.1
  vias: v1(296.03,83.7)
+3.3V_MMI_AUX:
  vias: v1(294.44,26.62)
+3.3V_MMI_IN:
  vias: v1(293.24,17.79) v2(286.78,26.83) v2(286.78,26.19) v2(292.03,17.85) v2(292.38,18.37)
+3.3V_PDA_VOUT: length 2.6
  BOTTOM w0.076: 60.91,108.81 61.09,108.63 61.95,108.63 UT5.H2
  BOTTOM w0.112: 60.91,108.81 60.88,108.84
  BOTTOM w0.254: 60.88,108.84 60.56,109.16 CT83.1
+3.3V_PGPPBC: length 1.1
  BOTTOM w0.254: UH1.AN26 v2(229.59,103.94) ; UH1.AP26 v2(229.59,104.71)
  vias: v1(230.25,104.85)
+3.3V_PGPPEF: length 1.5
  BOTTOM w0.254: UH1.AE36 234.03,100.6 v2(234.21,100.78) ; v2(233.63,100.81) 233.37,100.81 233.27,100.71 UH1.AE35
  vias: v1(237.93,101.61)
+3.3V_PGPPG: length 0.5
  BOTTOM w0.254: v2(225.91,103.93) 225.91,103.93 UH1.AN21
  vias: v1(226.37,107.58)
+3.3V_PGPPHK: length 1.3
  BOTTOM w0.254: UH1.AC36 234.03,98.73 v2(234.21,98.55) ; UH1.AC35 233.27,98.87 233.61,98.52 v2(233.61,98.46)
  vias: v1(234.37,97.74)
+3.3V_PHVC: length 3.6
  TOP w0.254: 220.81,110.07 221.25,109.63 221.25,108.99 221.03,108.77 220.86,108.77 220.6,108.5 220.6,107.99 v2(220.85,107.73)
  BOTTOM w0.254: UH1.AW9 220.71,107.29 220.71,107.59 v2(220.85,107.73)
  vias: v1(220.28,111.64)
+3.3V_PHVLDO: length 1.7
  BOTTOM w0.254: UH1.BB7 219.88,107.95 219.94,107.9 UH1.AY8 219.94,107.01 v2(219.91,106.98)
  vias: v1(218.94,111.33)
+3.3V_PRTC: length 1.2
  TOP w0.102: CH33.1 242.91,113.89 v1(243.71,114.69)
  vias: v2(242.18,113.23)
+3.3V_PUSB2: length 2.7
  TOP w0.127: v1(229.23,97.34) 228.52,97.34 228.13,96.95 v2(228.1,96.95)
  TOP w0.508: v2(245.61,106.42) 245.44,106.25 RH302.2
  BOTTOM w0.254: UH1.V23 v2(228.1,96.95)
  vias: v2(237.99,97.61)
+3.3V_RTC_LDO: length 83.1
  TOP w0.508: v2(276.09,63.93) 276.09,63.7 275.22,62.82 272,62.82 271.19,62.01 270.21,62.01 v1(269.87,61.67) 256.92,61.67 255.68,62.9 251.82,62.9 249.91,64.82 240.66,64.82 v2(238.37,62.53) ; RA53.2 v2(285.05,45.41)
  BOTTOM w0.508: v2(276.09,63.93) 275.93,63.77 275.93,61.64 277.17,60.4 285.17,60.4 285.68,60.91 285.68,62.05 286.06,62.43 288.41,62.43 289.35,63.37 290.55,63.37 PC9.1 290.81,63.37 v2(291.21,63.76) 290.94,64.03 PD3.3 ; PR105.2 242.06,48.76 242.06,48.77 238.9,48.77 238.39,49.27 238.39,54.02 240.59,56.22 240.59,57.8 241.1,58.31 241.1,59.8 v2(238.37,62.53)
+3.3V_RUN: length 180.4
  TOP w0.254: LGA1.2 LGA1.3 252.76,43.66 v2(252.83,43.73)
  TOP w0.356: RH125.2 RH127.2
  TOP w0.381: v2(233.48,123.63) 233.52,123.63 233.61,123.72 233.64,123.72 233.83,123.91 233.83,123.93 233.9,124.01 RH126.2 234.63,124.22 235.01,123.84 RH123.2 ; RH267.2 231.16,122.98 v2(231.2,122.95) ; RN4.1 253.74,33.82 v2(253.36,34.2) 252.91,33.76 RN226.1 ; RH125.2 232.47,127.61 v2(232.09,127.99) ; v2(250.06,98.8) 249.99,98.87 249.93,98.87 249.34,99.46 249.34,100.14 250.2,101 RH348.1 RH104.1 ; RC370.2 227.5,111.12 228.21,111.83 228.21,113.36 227.83,113.74 v2(227.55,113.74) ; v2(226.96,124.09) 226.96,123.74 227.42,123.28 RH131.2 ; 270.37,71.3 271.69,71.3 272.6,70.38 RZ1403.2 ; RH124.2 234.09,118.44 RH402.1 ; RH324.1 RH316.1 245.82,101.05 v2(245.61,100.85) ; v2(128.52,129.55) 128.52,129.56 128.81,129.85 128.81,130.33 128.88,130.39 CA7.1
  TOP w0.457: RD6.1 v2(163.14,47.21) RD4.1
  TOP w0.508: RE48.1 RE51.1 92.46,90.05 92.83,89.67 93.55,89.67 93.91,90.03 93.91,90.82 v2(93.78,90.94) ; RH402.1 233.56,118.81 232.72,119.64 232.72,121.8 233.48,122.57 v2(233.48,123.63) ; v2(108.92,130.07) 108.65,129.8 RV98.1 ; RH76.1 245.42,105.42 245.61,105.23 v2(245.61,104.34) 245.94,104.02 245.94,103.19 RH344.1 RH324.1 ; v2(226.88,40.97) 227.26,40.59 CZ72.1 227.16,40.31 CZ67.1 ; RZ89.1 249.93,128.46 RZ362.1 v2(249.31,128.47) ; v2(236.08,124.81) 236.28,124.6 RZ1409.1 ; RD8.1 137.85,43.15 138.24,43.53 v2(138.24,44.67) ; RD4.1 163.14,48.73 RD10.1 ; v2(245.61,100.85) 245.78,100.68 245.78,98.88 245.42,98.52 244.92,98.52 244.7,98.74 v2(244.15,98.74) ; RD22.1 RD20.1 237.09,46 238.4,47.32 238.4,48.8 237.89,49.31 RD26.1 237.54,48.8 237.03,48.29 v2(236.86,48.29) ; v2(114.2,100.54) 115.84,98.89 115.84,95.43 116.14,95.13 v2(116.14,95.07) ; RZ542.2 v2(187.89,95.53) ; RD19.1 v2(118.28,90.43) ; 210.69,111.07 211.39,110.37 216.21,110.37 216.72,109.87 216.72,108.28 217.42,107.58 217.42,106.51 216.58,105.67 RH223.2 RH222.2 RH224.2 RH221.2 ; v2(213.13,41.52) 213.13,41.84 213.34,42.05 RD24.1 ; RV1657.1 106.35,128.27 v2(106.7,128.62) 106.69,128.63 106.47,128.63 105.96,129.14 RV99.1 ; RZ1391.2 v2(286.32,121.55) ; RH355.1 230.23,113.22 230.83,113.82 RH339.1 230.83,114.26 v2(231.33,114.75) ; RV326.1 112.73,131.26 RV732.2 113.6,130.5 113.09,129.99 v2(112.58,129.99) ; RE67.2 251.57,110.56 250.92,111.21 v2(250.33,111.21)
  TOP w1.016: 269.17,70.88 260.55,70.88 258.25,73.18 258.25,75.21 257.23,76.22 252.84,76.22 252.15,76.91
  BOTTOM w0.102: v2(215.9,119.39) 214.88,120.41 214.88,123.17 213.96,124.09 213.61,124.09 213.47,123.95 211.89,123.95 209.94,125.91 v2(209.89,125.91) ; v2(215.84,123.03) 215.59,123.03 v1(213.85,124.78) 213.29,125.33 213.29,133.37 v2(213.35,133.43)
  BOTTOM w0.254: RH331.1 233.17,123.31 v2(233.48,123.63)
  BOTTOM w0.305: v2(226.88,40.97) 227.33,40.97 227.78,40.52 JUSH1.8
  BOTTOM w0.381: CN2.1 253.39,43.98 253.27,43.86 252.96,43.86 v2(252.83,43.73) ; v2(245.61,100.85) 245.61,100.59 245.09,100.07 244,100.07 243.73,100.34 RH132.2 ; QH4.2 227.79,123.87 RH333.2 ; PRZ20.1 96.09,100.33 v2(96.09,100.21) ; QH4.5 231.04,123.87 231.28,123.63 RH374.2 ; v2(251.26,40.21) 251.19,40.21 250.78,40.61 250.78,41.25 RN2.1 ; RH378.1 v2(223.39,121.17) ; RH133.2 243.77,98.07 244.15,98.45 v2(244.15,98.74)
  BOTTOM w0.508: RH374.2 231.52,123.26 v2(231.2,122.95) ; v2(226.96,124.09) 227.56,124.09 RH333.2 ; RH361.1 223.71,122.45 v2(223.58,122.32) ; v2(255.3,124.1) 255.02,124.38 252.46,124.38 249.2,127.64 249.2,128.36 v2(249.31,128.47) ; v2(188.11,106.49) 188.26,106.34 196.77,106.34 197.51,105.6 199.89,105.6 200.4,106.11 200.4,107.88 200.76,108.24 204.3,108.24 205.09,109.03 207.12,109.03 v2(207.58,109.48) ; v2(244.15,98.74) RH318.1
  vias: v2(30.59,116.26) v2(31.24,116.26) v2(31.88,116.26) v2(135.97,124.95) v2(135.97,124.37) v2(142.62,125.88) v2(142.62,125.3) v2(180.53,41.56) v2(196.18,40.79) v2(211.64,113.36) v2(211.64,112.62) v2(211.63,112.03) v2(212.53,117.05) v2(213.8,123.39) v2(213.8,122.81) v2(213.8,122.22) v2(215.89,122.4) v2(222.5,41.41) v2(252.47,78.88) v2(252.47,78.29) v2(253.74,39.44) v2(254.18,39.94) v2(254.31,41.09) v2(254.31,40.51) v2(255.81,48.87) v2(256.39,48.87) v2(256.39,48.29) v2(256.97,49) v2(256.97,48.42) v2(256.97,47.83) v2(257.12,49.79) v2(257.23,47.25) v2(257.56,49.4) v2(257.56,48.81) v2(257.56,48.23) v2(257.69,47.66) v2(264.54,37.16) v2(268.85,31.06) v2(269.17,31.82) v2(270.06,69.92) v2(270.04,69.34) v2(284.92,75.92) v2(285,29.84) v2(285.64,29.84) v2(301.68,80.91) v4(253.87,46.37)
+3.3V_RUN_AUDIO: length 15.6
  TOP w0.508: LA12.2 v2(278.89,50.89) ; LA14.2 278.96,58.94 RA18.2 277.67,58.61 277.67,57.8 v2(277.68,57.8) ; RA59.1 v2(284.22,45.41)
  BOTTOM w0.508: v2(277.44,67.39) 277.44,67.01 276.93,66.5 275.89,66.5 275.3,65.91 275.3,60.18 v2(277.68,57.8)
  vias: v1(281.24,71.77) v2(281.94,71.51)
+3.3V_RUN_AUDIO_DVDD:
  vias: v1(282,57.16)
+3.3V_RUN_AUDIO_IO:
  vias: v1(281.43,52.91)
+3.3V_RUN_CARD:
  vias: v1(300.92,20.01) v2(293.78,20.62) v2(294,20.07) v2(300.64,20.48) v2(301.22,20.48)
+3.3V_RUN_DIMM1: length 7.2
  TOP w0.102: v1(161.54,51.06) 161.79,51.32 v2(162.46,51.32)
  BOTTOM w0.305: v2(162.46,51.32) 159.67,51.32 159,51.99 159,52.68 158.37,53.3 JDIMM1.255
+3.3V_RUN_DIMM2: length 2.2
  BOTTOM w0.305: v2(235.29,49.65) 234.66,49.65 234.17,50.14 JDIMM2.255
  vias: v1(236.22,48.11)
+3.3V_RUN_F: length 4.4
  TOP w0.508: RZ1488.2 129.43,127.39 FZ4.2 129.43,126.67 131.73,124.37 QZ1.3
+3.3V_RUN_QZ1: length 3.8
  TOP w0.102: v1(129.28,129.87) 129.43,129.72 FZ4.1 129.43,128.79 RZ1488.1
  BOTTOM w0.254: JEDP1.10 129.26,129.57 129.34,129.49
  BOTTOM w0.508: 129.34,129.49 129.31,129.49 129.31,129.41 128.8,128.9 v2(128.57,128.9)
+3.3V_RUN_UZ3: length 1
  TOP w0.102: 253.74,51.76 v1(253.74,52.72)
+3.3V_SPI: length 48.8
  TOP w0.356: v2(254.13,93.24) 254.06,93.17 CH270.1
  TOP w0.508: v2(245.36,97.17) RH615.1 ; v2(248.75,109.47) 248.16,110.06 RH335.1 RH30.1
  BOTTOM w0.305: JSPI1.6 240.31,130.16 240.72,129.74 241.17,129.74 242.11,128.8 RH185.2
  BOTTOM w0.381: v2(245.36,97.17) 244.41,96.21 RH601.1 ; CH9.1 252.6,105.55 UC5.8 251.9,105.67 250.94,104.71 250.4,104.71 249.84,105.28 249.28,105.28 248.85,104.85 248.27,104.85 v2(247.65,105.47)
  BOTTOM w0.508: v2(248.75,109.47) 248.75,109.83 249.33,110.41 249.33,116.75 246.35,119.73 v2(244.39,119.73) ; v2(236.95,122.63) 236.77,122.45 RH600.1 ; v2(245.36,97.17) v1(246.31,96.21) 246.67,95.85 251.88,95.85 252.34,95.39 UC6.8 252.34,93.86 252.85,93.35 253.55,93.35 253.64,93.26 254.11,93.26 v2(254.13,93.24) ; v2(236.91,127.2) 240.6,127.2 240.98,127.58 DH3.1 242.11,127.59 RH185.2
+3.3V_SSD:
  vias: v1(270.06,50.3)
+3.3V_TBT: length 16.9
  TOP w0.305: CT43.1 39.4,108.28 39.69,107.99 v2(39.69,107.9)
  TOP w0.508: RT14.2 v2(44.89,118.47) ; v2(41.9,113.83) 41.9,113.67 41.9,113.67 RT337.2 ; LT2.2 50.23,103.27 48.17,105.33 v2(48.17,105.99) ; RT336.2 49.73,111.18 v2(49.86,111.05) ; v2(43.87,114.24) 43.54,113.91 43.54,113.12 RT15.2
  BOTTOM w0.203: v2(39.69,107.9) UT1.H9
  BOTTOM w0.508: RT13.2 RT14.2 v2(44.89,118.47) 45.5,119.08 47.06,119.08 47.06,119.07 48.89,119.07 v2(49.86,120.05)
  vias: v1(32.47,111.08) v2(35.3,114.5) v2(36.13,111.75) v2(36.13,111.14)
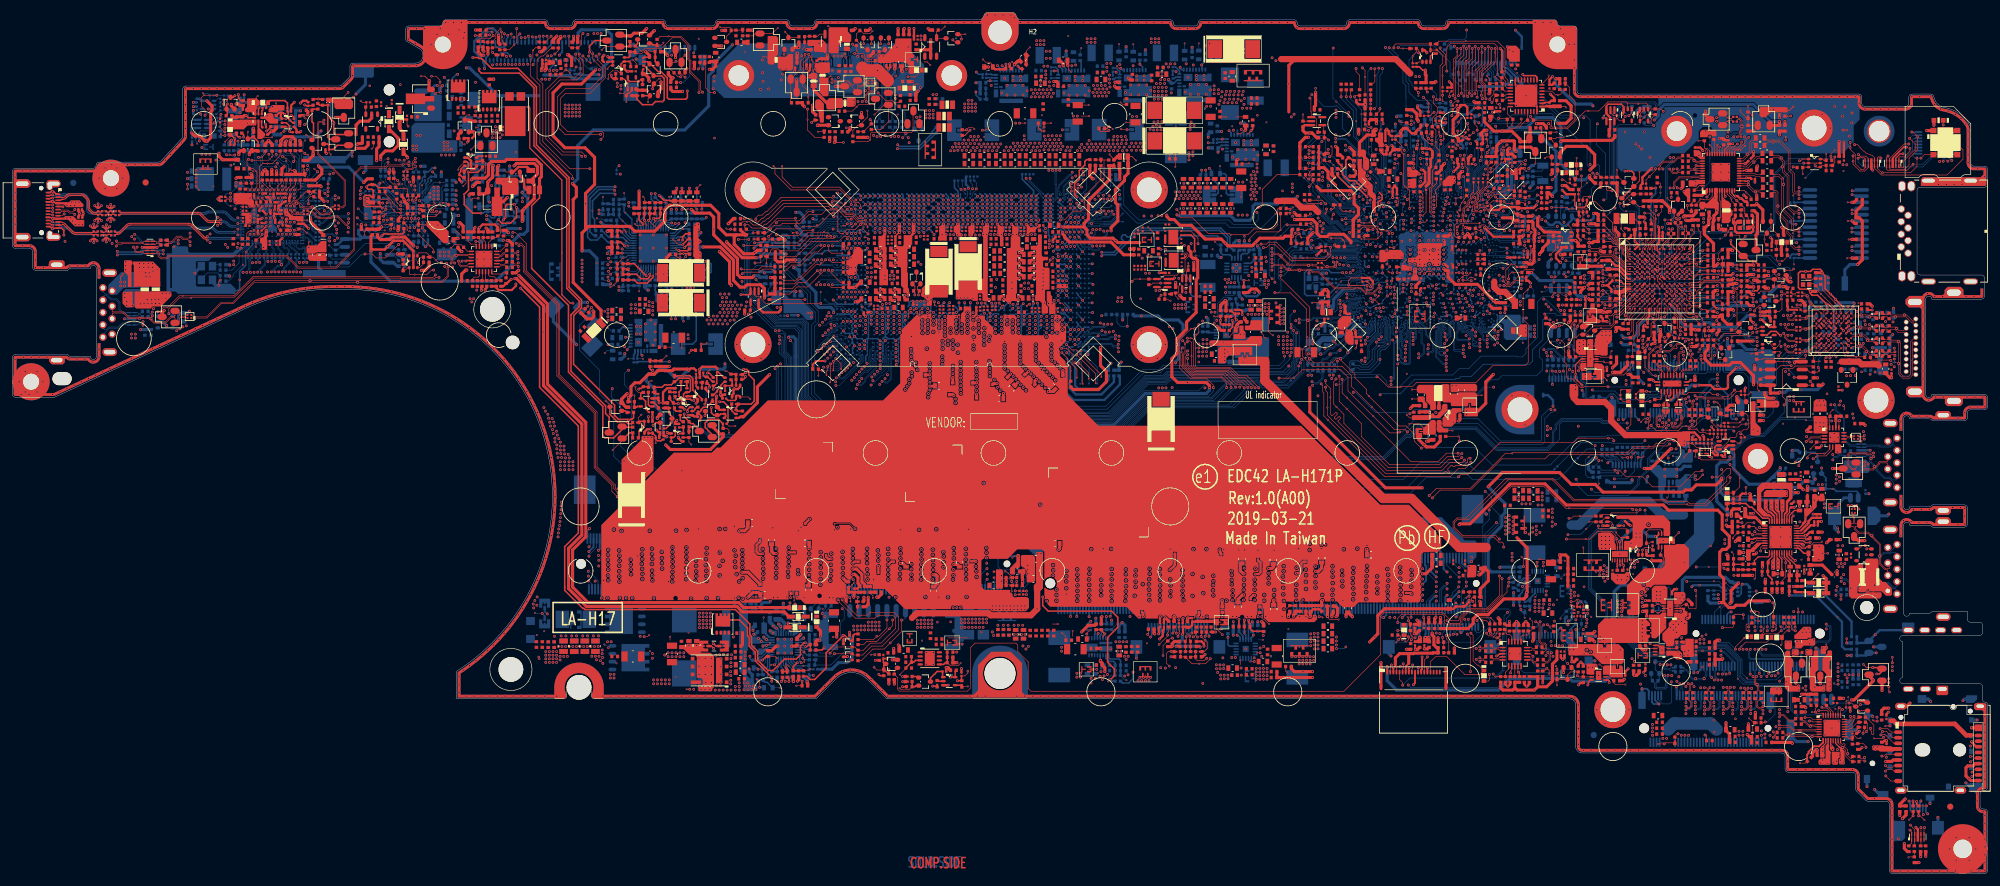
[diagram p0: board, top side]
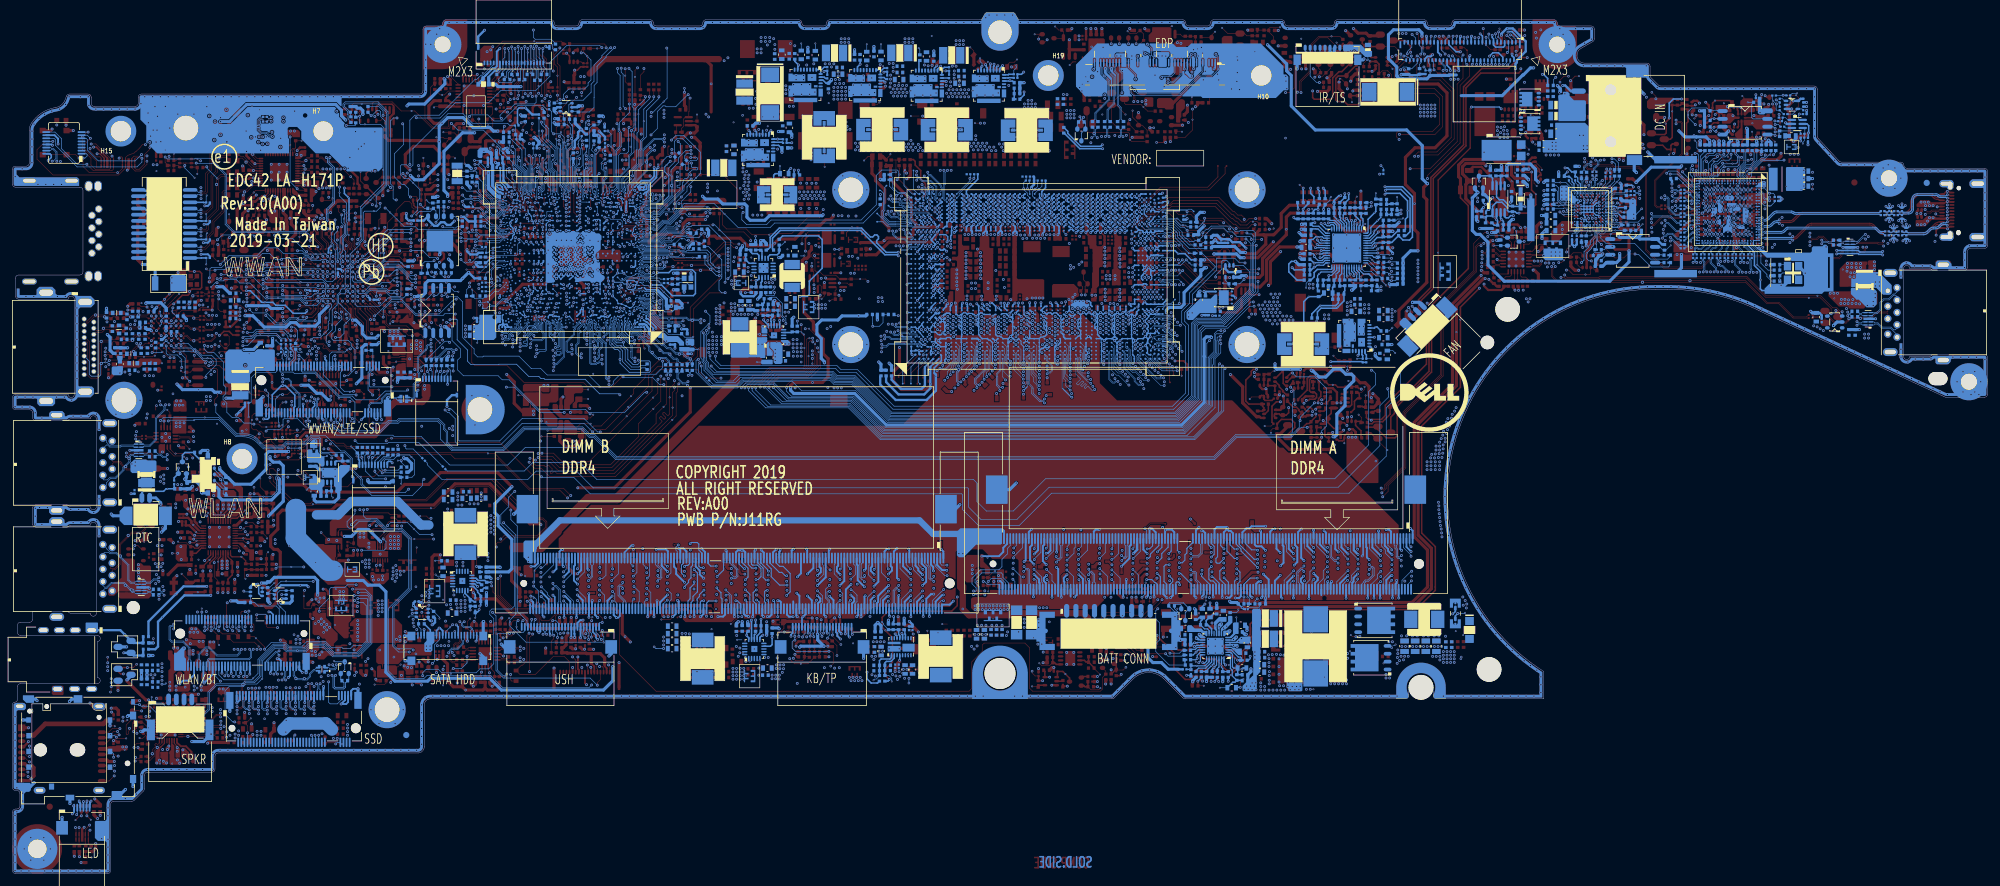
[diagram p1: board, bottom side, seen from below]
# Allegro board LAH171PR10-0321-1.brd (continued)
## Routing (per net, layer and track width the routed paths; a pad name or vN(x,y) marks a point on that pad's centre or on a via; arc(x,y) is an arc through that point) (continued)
+3.3V_TBT_FLASH_R: length 18.1
  TOP w0.508: RT9.2 48.95,112.1 v1(49.42,112.57) 49.97,113.12 49.97,113.84 v2(49.42,114.39) ; RT10.2 57.34,112.29 56.78,111.73 v2(56.78,111.72)
  BOTTOM w0.508: v2(56.78,111.72) 56.78,111.73 54.33,114.18 49.63,114.18 v2(49.42,114.39) ; RT4.2 45.73,121.74 RT3.2 45.73,122.4 45.73,122.4 RT2.2 v2(46.55,123.29)
  vias: v2(36.76,123.01)
+3.3V_TBT_LC: length 5.8
  TOP w0.127: v1(44.76,113.93) 45.04,113.65 v2(45.54,113.65)
  TOP w0.254: v2(43.6,109.19) 43.71,109.29 44.13,109.29 CT41.1
  TOP w0.508: RT5.2 RT8.2 RT9.1 ; RT5.2 RT7.2 RT6.2 ; RT5.2 45.72,113.47 v2(45.54,113.65)
  BOTTOM w0.203: v2(43.6,109.19) 43.27,109.52 UT1.R6
+3.3V_TBT_S0: length 1.4
  TOP w0.127: v2(47.87,101.18) v1(47.87,102.12)
  BOTTOM w0.203: v2(43.6,105.95) 43.28,106.27 UT1.R13
+3.3V_TBT_SX: length 12.7
  TOP w0.356: CT42.1 39.04,109.57 v2(39.04,109.2)
  TOP w0.508: RT16.2 43.36,117.81 v2(43.36,118.4) 43.37,118.41 43.37,118.51 43.97,119.1 45.21,119.1 45.72,118.59 RT338.2 ; v2(33.37,116.43) 33.37,115.96 33.88,115.45 33.9,115.45 v1(33.98,115.38) RT49.1
  BOTTOM w0.203: UT1.F8 v2(39.04,109.2)
  BOTTOM w0.508: v2(40.44,118.39) 40.32,118.27 RT18.2 RT19.2 ; v2(37.34,118.39) 37.34,118.34 37.27,118.28 RT372.2 RT20.2 ; RT371.2 43.37,118.4 v2(43.36,118.4)
+3.3V_TBTA_FLASH: length 40.3
  TOP w0.254: v2(59.74,107.57) 59.47,107.83 57.04,107.83 56.79,108.09 56.79,109.41 56.98,109.61 57.75,109.61 57.9,109.45 57.91,109.45 58.01,109.35 RT106.2 58.29,110.38 58.06,110.61 57.46,110.61 57.25,110.82 57.25,110.97 v2(57.22,111) 57.6,111.38 RT10.1 58.62,111.38 59.12,110.87 60.95,110.87 RT76.2 ; RT107.2 63.24,103.64 62.99,103.39 v1(60.89,103.39) 59.98,103.39 v2(59.69,103.09)
  TOP w0.508: v2(62.17,100.16) 63.09,100.16 RT67.2 ; RT399.1 57.45,117.74 56.94,117.23 v2(55.53,117.23) ; RT66.2 67.32,98.17 66.66,97.52 v2(66.05,97.52)
  BOTTOM w0.203: UT5.G1 61.13,107.88 61.05,107.8 59.96,107.8 v2(59.74,107.57) 59.67,107.64 CT84.1
  BOTTOM w0.254: v2(57.22,111) 57.49,111.27 RT95.2
  BOTTOM w0.381: UT6.8 53.46,102.56 52.59,101.69 RT50.2
  BOTTOM w0.508: v2(62.17,100.16) 62.43,99.9 RT52.2 62.78,99.78 63.06,99.5 63.06,99.46 63.29,99.24 63.32,99.24 RT53.2 63.32,98.24 CT70.1 ; v2(59.69,103.09) 59.41,102.82 56.45,102.82 ; UT6.8 56.19,102.56 56.45,102.82 ; v2(71.67,108.79) 71.51,108.94 RT98.1 ; RT51.2 55.93,103.34 56.45,102.82
+3.3V_TP: length 17.9
  TOP w0.127: v4(195.45,38.62) 194.43,39.63 194.43,40.59
  TOP w0.356: v2(189.01,38.68) 189.1,38.77 189.1,39.85 CZ90.1 189.7,39.9 CZ83.1
  TOP w0.381: v2(187.96,36.76) 187.97,36.77 188.51,36.77 RZ18.1 ; RZ20.1 191.22,40.73 CZ1203.1 190.57,40.18 190.19,39.8 CZ83.1 ; v2(191.87,36.61) 191.77,36.71 191.23,36.71 RZ19.1
  TOP w0.508: RZ20.1 RZ116.1 RZ117.1 RZ21.1
  BOTTOM w0.254: JKBTP1.12 v2(189.01,38.68)
  BOTTOM w0.508: v2(191.87,36.61) 191.72,36.76 v2(187.96,36.76) 188.97,37.77 188.97,38.64 v2(189.01,38.68)
+3.3V_VDD_DCIN: length 25.9
  TOP w0.254: PR27.2 101.79,129.89 PR47.1
  TOP w0.381: v2(72.58,111.77) 72.19,112.15 PR17.1 ; v2(95.56,132.28) 95.31,132.03 95.31,131.42 PR33.1
  TOP w0.508: v2(77.66,114.44) 77.54,114.32 77.54,112.55 v1(76.89,111.9) 76.79,111.79 PU2.3 76.29,109.87 PC10.1 75.37,109.87 PC12.1 ; PD3000.2 36.89,116.85 36.57,116.53 v2(36.57,116.22) ; v2(102.88,128.08) 102.88,128.09 102.78,128.19 102.78,128.62 102.15,129.25 PR47.1
  BOTTOM w0.305: v2(80.58,107.35) 80.72,107.35 81.02,107.04 PR806.1
  BOTTOM w0.508: PR832.1 v2(77.66,114.44) 77.4,114.69 73.86,114.69 73.02,113.85 73.02,112.21 v2(72.58,111.77) ; v2(80.58,107.35) 80.58,107.52 80.49,107.61 80.49,109.01 81.24,109.75 PR809.1 81.51,109.8 PD800.3
  vias: v2(41.14,122.5)
+3.3V_VDD_PIC: length 92.3
  TOP w0.381: v2(109.25,81.36) 109.54,81.65 110.1,81.65 PR813.1 ; PR822.1 PR810.1 105.58,70.75 v2(105.72,70.61)
  TOP w0.406: v2(57.92,100.65) 58.15,100.88 60.16,100.88 v4(60.64,101.36) 61.58,102.3 63.13,102.3 64.77,100.65 QT1.5 QT1.2
  TOP w0.508: RT398.2 RT399.2 56.38,117.99 55.82,117.99 v2(55.69,117.87) ; v2(109.25,81.36) 109.06,81.56 106.84,81.56 106.57,81.29 105.36,81.29 105.31,81.34 104.49,81.34 104.44,81.29 104.24,81.29 103.67,80.72 103.17,80.72 103.13,80.76 102.78,80.76 101.35,79.33 100.54,79.33 99.92,78.72 99.92,77.31 v2(99.55,76.93) PR859.1 ; v2(57.92,100.65) 57.92,103.01 RT482.1
  BOTTOM w0.508: v2(109.25,81.36) 109.15,81.25 108.98,81.25 107.98,80.26 106.92,80.26 105.63,81.54 104.49,81.54 103.67,80.72 102.74,80.72 102.38,80.36 102.38,79.64 103.79,78.23 103.79,75.61 105.11,74.29 105.11,70.97 105.47,70.61 v2(105.72,70.61) ; v2(57.92,100.65) 57.92,98.87 61.04,95.75 78.08,95.75 80.7,98.37 80.7,102.06 81.97,103.32 82.61,103.32 83.23,103.94 83.23,109.2 82.74,109.69 82.73,109.69 v2(82.33,110.09) 82.81,110.58 PD800.2
  vias: v2(30.6,117.36)
+3.3V_VDD_PIC_PDA: length 7.3
  TOP w0.102: v1(56.88,103.19) 56.88,103.74 CT74.1
  TOP w0.508: CT74.1 57.29,104.16 RT482.2 RT483.2 59.25,104.16 v2(59.62,104.53)
  BOTTOM w0.203: v2(59.62,104.53) 59.69,104.47 60.61,104.47 61.52,105.38 UT5.B1 ; UT5.H1 60.68,108.38 60.64,108.42 v2(60.52,108.42)
+3.3V_VDD_PIC_R: length 1.1
  TOP w0.102: CT92.1 58.32,117.45 v1(58.03,117.17)
+3.3V_VPS_UZ12:
  vias: v1(243.07,129.42) v2(240.91,123.58) v2(242.81,130.06)
+3.3V_WLAN:
  vias: v2(272.6,37.87) v2(272.6,37.23) v2(272.92,38.38) v2(273.23,37.87) v2(273.23,37.23) v2(289.11,39.01) v2(289.42,39.55) v2(289.75,39.01) v2(290.08,39.57) v2(290.36,39.01) v4(273.01,36.03) v4(272.99,33.4) v4(273.55,38.62)
+3.3V_WLAN_UZ4:
  vias: v1(266.82,45.98) v2(265.57,45.58) v2(265.57,44.99) v2(265.57,44.41) v2(266.16,45.58) v2(266.16,44.99) v2(266.16,44.41)
+3.3V_WWAN: length 24.2
  TOP w0.254: UZ29.6 268.34,77 267.9,76.56 v2(267.72,76.56)
  TOP w0.381: v2(276.52,70.26) 276.73,70.47 RZ1400.2 ; v2(272.44,78.94) 274.32,78.94 274.92,78.33 276.86,78.33 277.11,78.59 v4(277.11,79.39) 277.11,80.44 v2(278.46,81.79)
  BOTTOM w0.508: v2(267.72,76.56) 268.06,76.56 269.14,77.64 269.9,77.64 271.2,78.94 v2(272.44,78.94) ; RZ43.2 262.09,85.49 262.6,84.99 262.6,80.08 v2(263.5,79.17)
  vias: v2(260.66,79.71) v2(260.66,79.08) v2(279.07,81.79)
+3.3V_WWAN_UZ2:
  vias: v1(257.61,85.99) v2(256.76,87.63) v2(256.76,87) v2(257.39,87.63) v2(257.39,87) v2(258.03,87.63) v2(258.03,87)
+5V_ALW: length 142.2
  TOP w0.203: UZ2.4 253.41,83.2 252.49,82.27 v4(252.49,80.72) 252.49,80 253.37,79.12 253.38,79.12 v2(253.55,78.95) ; UZ3.4 259.65,53.57 v2(259.58,53.64) ; UZ4.4 269.49,42.86
  TOP w0.254: UZ21.3 190.39,103.21 190.96,102.63 v2(190.96,100.62) ; v2(189.48,99.89) 189.48,99.89 189.48,99.71 189.23,99.46 UZ19.3 ; v2(265.43,54.51) 265.64,54.51 265.9,54.76 UZ53.4 ; v2(254.46,30.5) 254.56,30.6 254.56,30.97 254.89,31.3 UZ23.4
  TOP w0.381: RI13.2 291.9,68.84 v2(292.22,69.16) ; v2(50.73,116.41) 50.57,116.57 PR7.1
  TOP w0.508: PRH11.1 169.16,131.46 169.73,130.88 v2(169.73,130.57) ; v2(310.38,120.97) LED3.2 ; PCH26.1 178.74,127.91 v2(178.1,127.91) ; RV9.2 v2(114.58,136.28) ; v2(168.21,128.03) 168.65,128.03 168.89,127.79 PCH51.1 ; v2(111.55,101.29) 114.35,101.29 116.48,99.15 116.48,95.87 117.56,94.79 118.27,94.79 118.66,95.18 120.86,95.18 121.46,94.57 v2(121.46,93.04) ; v2(59.49,115.42) 59.49,116.05 60.26,116.81 61.43,116.81 62.31,117.7 62.31,118.87 60.83,120.35 DT1.2 ; PRH1.1 v2(157.67,130.38)
  BOTTOM w0.102: v2(264.28,56.4) 263.52,57.16 260.27,57.16 258.65,55.55 256.17,55.55 254.82,54.2 254.82,46.05 257.64,43.22 257.64,36.8 256.67,35.82 v2(254.95,35.82) ; v2(262.31,58.8) 262.31,57.8 261.91,57.39 260.17,57.39 259.1,56.31 258.56,55.78 256.07,55.78 254.59,54.29 254.59,45.96 257.42,43.13 257.42,36.89 256.86,36.33 v1(256.6,36.33) 254.5,36.33 v2(254.31,36.14)
  BOTTOM w0.254: PUH2.15 168.27,128.09 v2(168.21,128.03) ; PUH3.15 178.35,128.17 178.1,127.91 v2(178.1,127.91) ; v2(111.82,98.96) 112.45,98.96 112.87,98.54 112.87,97.25 111.55,95.94 PRZ51.1 ; PUH1.2 160.08,130.37 159.88,130.57 v2(159.87,130.57) ; PUA1.15 195.3,117.72 194.88,117.29 PCA11.1 ; PUH2.2 170.12,130.18 v2(169.73,130.57) ; PUH4.15 188.1,128.24 187.62,127.75 PCH49.1 ; PUH1.15 157.97,128.11 v2(157.92,128.15) 157.86,128.09 157.49,128.09 PCH27.1
  BOTTOM w0.305: v2(121.46,93.04) 121.85,93.43 UZ26.3 ; JUSH1.10 228.78,38.21 v2(228.82,38.16) ; v2(306.35,11.72) 306.53,11.54 306.53,11.26 306.57,11.22 JLED1.6 ; JUSH1.9 228.28,38.76 228.24,38.73 v2(228.24,38.16) ; PUT1.15 101.56,83.92 v2(101.71,83.77)
  BOTTOM w0.508: PRZ77.1 111.28,98.41 v2(111.82,98.96) ; PRA1.1 193.48,119.83 193.16,119.52 v2(193.16,119.01) ; v2(259.58,53.64) 259.58,53.68 261.53,55.62 263.16,55.62 264.28,54.51 v2(265.43,54.51) ; PCH49.1 186.75,128.24 v2(186.75,128.34) ; PRZ61.1 110.9,101.29 v2(111.55,101.29) ; PCA11.1 v2(194.75,116.6)
  vias: v2(26.54,87.77) v2(27.05,88.06) v2(27.54,88.37) v2(28.1,88.54) v2(69.1,100.46) v2(69.1,99.83) v2(69.79,100.46) v2(69.79,99.83) v2(70.49,100.46) v2(70.49,99.83) v2(98.86,85.16) v2(178.87,130.76) v2(189.61,130.88) v2(206.69,35.06) v2(207.27,35.06) v2(207.86,35.06) v2(207.86,34.48) v2(207.86,33.89) v2(208.44,35.06) v2(208.44,34.48) v2(208.44,33.89) v2(209.02,35.06) v2(209.02,34.48) v2(209.02,33.89) v2(209.61,35.06) v2(209.61,34.48) v2(209.61,33.89) v2(210.19,35.06) v2(210.19,34.48) v2(254.6,33.28) v2(255.2,33.34) v2(255.77,33.57) v2(267.82,39.82) v2(268.27,40.26) v2(268.28,39.38) v2(268.66,39.82) v2(268.72,40.71) v2(269.17,41.16) v2(269.13,40.3) v2(269.58,40.75) v2(291.32,72.86) v2(291.98,72.87) v2(291.98,72.26) v2(292.59,72.86) v2(292.59,72.26) v2(294.76,50.14) v2(294.83,68.15) v2(295.03,49.6) v2(295.39,50.11) v2(295.66,49.59) v2(295.97,50.11) v4(268.78,39) v4(270.12,40.41)
+5V_ALW2: length 1.5
  BOTTOM w0.254: PU102.15 200.11,38.1 200.44,38.43 v2(200.44,38.54) 200.44,38.95 PC126.1
+5V_ALW_PDA: length 0.6
  BOTTOM w0.203: UT5.H10 66.14,108.38 65.79,108.73 65.79,108.75 v2(65.76,108.78)
  vias: v1(68.7,103.52) v2(67.18,105.19) v2(68.71,104.81) v2(68.71,104.12)
+5V_ALWP: length 7
  TOP w0.254: PC137.1 202.05,39.19 200.34,39.19 199.91,39.62 PR117.2 199.91,40.38 199.68,40.61 199.68,40.97 v2(199.69,40.98)
  BOTTOM w0.254: PU102.14 199.66,40.71 199.69,40.74 v2(199.69,40.98)
  vias: v1(206.12,39.51) v2(202.05,38.49) v2(209.71,38.75) v2(209.71,38.11) v2(209.71,37.48) v2(209.71,36.84) v2(210.29,38.82) v2(210.29,38.24) v2(210.29,37.6) v2(210.29,36.97) v2(210.29,36.33) v2(210.88,38.82) v2(210.88,38.24) v2(210.88,37.6) v2(210.88,36.97) v2(210.88,36.33)
+5V_HDD: length 2.2
  BOTTOM w0.254: RN1.1 251.55,39.39 JSATA1.16
  vias: v2(251.58,36.77) v2(251.58,36.19) v2(252.16,36.78) v2(252.16,36.19) v4(253.87,35.51) v4(257.42,35) v4(259.71,36.14)
+5V_HDD_UZ23: length 1.1
  TOP w0.102: v1(256.34,33.79) 256.41,33.79 256.79,33.41 257.3,33.41
+5V_PD_VDD:
  vias: v1(60.45,124.09)
+5V_RUN: length 71
  TOP w0.356: v2(185.17,38.76) 185.17,39.71 CZ92.1
  TOP w0.508: DE1.1 95.08,91.05 90.58,95.55 90.58,108.94 91.09,109.45 91.09,110.91 v2(90.48,111.52)
  BOTTOM w0.305: JKBTP1.5 185.51,39.16 185.19,38.83 185.17,38.83 v2(185.17,38.76) ; v2(227.28,38.12) JUSH1.7
  BOTTOM w0.508: v2(116.31,133.96) 113.22,130.86 113.22,129.74 112.48,129 112.48,124.08 108.6,120.2 93.84,120.2 91.32,117.67 91.32,112.31 90.52,111.52 v2(90.48,111.52)
  vias: v2(93.15,88.21) v2(93.56,87.8) v2(182.59,46.79) v2(256.47,38.29) v2(256.45,37.71) v2(257.01,37.86) v2(263.27,40.89) v2(263.27,40.25) v2(263.27,39.62) v2(263.27,38.98) v2(263.27,38.35) v2(263.27,37.73) v2(287.08,77.1) v2(287.08,76.46) v2(287.71,77.1) v2(287.71,76.46) v4(293.11,77.54)
+5V_RUN_AUDIO: length 0.6
  TOP w0.508: LA5.2 v2(294.74,48.97)
  vias: v1(286,72.72) v2(290.63,65.73)
+5V_RUN_PVDD_L:
  vias: v1(283.27,62.75)
+5V_RUN_UZ4:
  vias: v1(266.95,40.21)
+5V_TBT_VBUS: length 5.2
  TOP w0.127: CT93.1 63.75,120.98 v4(63.93,120.8)
  TOP w0.381: CT93.1 62.92,121.89 62.54,121.51 DT2.2
  TOP w0.508: DT3.1 63.18,119.77 62.54,120.41 DT2.2
+5V_TBTA_VBUS_D: length 4.5
  TOP w0.127: v2(67.37,128.15) 66.63,128.89 v1(66.01,128.89)
  TOP w0.457: v2(63.8,115.68) 63.8,115.83 63.18,116.46 DT3.2
  TOP w0.508: v2(67.37,128.15) 67.31,128.09 67.31,127.05 UT8.3
+5V_USB_CHG_PWR: length 0.8
  TOP w0.127: v4(295.78,75.64) 295.91,75.51 295.91,74.94
  vias: v2(294.6,64.42) v2(294.6,63.76) v2(294.58,63.09) v2(295.11,64.12) v2(295.13,63.41) v2(297.26,74.29) v2(297.37,73.63)
+13.2VB_BATT: length 15.4
  TOP w0.254: v2(122.65,31.08) 122.65,31.72 v1(122.26,32.11) 120.01,34.36 120.01,35.76 118.99,36.78 118.99,38.21 118.74,38.46 118.74,39.7 117.43,41.01 PQ702.5
  BOTTOM w0.254: PR738.2 v2(122.65,31.08)
  vias: v2(110.98,42.1) v2(110.98,41.51) v2(110.98,40.93) v2(110.98,40.35) v2(110.98,39.76) v2(111.56,42.1) v2(111.56,41.51) v2(111.56,40.93) v2(111.56,40.35) v2(111.56,39.76) v2(112.15,42.1) v2(112.15,41.51) v2(112.15,40.93) v2(112.15,40.35) v2(112.15,39.76) v2(112.73,42.1) v2(112.73,41.51) v2(112.73,40.93) v2(112.73,40.35) v2(112.73,39.76) v2(151.96,42.97) v2(152.55,42.97) v2(153.13,42.97) v2(153.27,41.13) v2(153.27,40.55) v2(153.86,41.13) v2(153.86,40.55) v2(154.44,41.13) v2(154.44,40.55) v2(155.02,41.13) v2(155.02,40.55) v2(155.61,41.13) v2(155.61,40.55) v2(156.19,41.13) v2(156.19,40.55) v2(156.78,41.13) v2(156.78,40.55) v2(157.36,41.13) v2(157.36,40.55)
+13.2VB_PBATT_C:
  vias: v2(146.17,40.97) v2(146.17,40.38) v2(146.17,39.8) v2(146.76,40.97) v2(146.76,40.38) v2(146.76,39.8) v2(147.34,40.97) v2(147.34,40.38) v2(147.34,39.8) v2(147.93,40.97) v2(147.93,40.38) v2(147.93,39.8) v2(148.51,40.97) v2(148.51,40.38) v2(148.51,39.8) v2(153.28,39.8) v2(153.87,39.8) v2(154.45,39.8) v2(155.04,39.8) v2(155.62,39.8) v2(156.21,39.8) v2(156.79,39.8) v4(149.41,40.65) v4(151.56,40.69) v4(156.52,39.08)
+13.5VB: length 146
  TOP w0.102: v2(235.01,38.72) 235.01,38.65 235.52,38.15 v2(235.52,32.65)
  TOP w0.254: 125.22,39.82 125.22,40.45 v2(125.28,40.51)
  TOP w0.508: v2(38.26,116.19) 38.26,116.43 PD3000.3 39.6,116.85 PR3006.1
  TOP w1.524: 202.31,82.62 202.31,79.69 221.36,60.63 226.01,60.63 231.07,55.57 231.07,55.33 233.69,52.72 238.06,52.72
  BOTTOM w0.102: v2(263.71,58.75) 263.71,58.18 264.98,56.91 264.98,56.14 264.66,55.83 264.16,55.83 263.05,56.93 260.36,56.93 258.75,55.32 256.26,55.32 255.05,54.11 255.05,46.14 258.29,42.9 258.29,32.74 257.09,31.54 252.56,31.54 252.1,32 241.78,32 239.88,30.1 225.87,30.1 v2(225.48,30.49)
  BOTTOM w0.203: v2(119.12,35.13) 119.12,34.74 119.38,34.49 PR721.2
  BOTTOM w0.508: 85.02,125.74 78.41,125.74 75.06,129.09 74.99,129.09 73.85,130.23 v2(73.33,130.23) ; PR102.2 242.48,44 v2(242.48,43.38)
  vias: v2(85.85,75.32) v2(86.1,74.75) v2(86.48,74.24) v2(86.61,73.61) v2(86.8,72.97) v2(86.93,72.34) v2(87.19,73.54) v2(87.24,71.77) v2(87.37,71.13) v2(87.43,72.97) v2(87.56,72.34) v2(87.63,70.37) v2(87.63,69.78) v2(87.88,71.51) v2(87.94,69.29) v2(87.94,68.65) v2(88.01,70.88) v2(88.01,67.96) v2(88.13,67.26) v2(88.26,70.3) v2(88.51,69.73) v2(88.51,69.1) v2(88.51,68.46) v2(88.51,66.56) v2(88.51,65.92) v2(88.51,65.29) v2(88.59,67.88) v2(88.72,67.26) v2(89.1,69.1) v2(89.1,68.46) v2(89.21,67.83) v2(89.21,66.56) v2(89.21,65.92) v2(89.21,65.29) v2(89.29,124.22) v2(89.29,123.63) v2(89.29,123.05) v2(89.29,122.44) v2(89.34,67.19) v2(89.87,124.22) v2(89.87,123.63) v2(89.87,123.05) v2(89.87,122.44) v2(89.79,67.76) v2(89.97,67.19) v2(89.91,66.56) v2(89.91,65.92) v2(89.91,65.29) v2(90.46,124.22) v2(90.46,123.63) v2(90.46,123.05) v2(90.46,122.44) v2(90.55,66.56) v2(90.55,65.92) v2(90.55,65.29) v2(91.04,124.22) v2(91.04,123.63) v2(91.04,123.05) v2(91.04,122.44) v2(91.63,124.22) v2(91.63,123.63) v2(91.63,123.05) v2(91.63,122.44) v2(113.53,29.66) v2(113.65,35.32) v2(113.72,30.36) v2(114.17,29.66) v2(114.23,35.38) v2(114.36,30.36) v2(114.45,34.71) v2(114.45,33.46) v2(114.45,32.22) v2(114.45,30.97) v2(114.87,35.44) v2(114.8,29.66) v2(115.44,29.66) v2(115.55,35.41) v2(116.07,34.74) v2(116.07,34.1) v2(116.07,33.47) v2(116.07,29.66) v2(116.16,35.37) v2(116.77,30.25) v2(116.77,29.66) v2(117.41,30.83) v2(117.41,30.25) v2(117.41,29.66) v2(130.3,134.19) v2(130.87,134.31) v2(147.56,123.34) v2(147.56,122.73) v2(147.56,122.15) v2(148.14,123.34) v2(148.14,122.73) v2(148.14,122.15) v2(148.75,123.34) v2(148.73,122.73) v2(148.73,122.15) v2(163.23,36.8) v2(163.71,36.29) v2(164.12,36.73) v2(181.82,31.19) v2(182.1,31.71) v2(182.41,31.19) v2(182.68,31.71) v2(183,31.19) v2(183.27,31.71) v2(183.59,31.19) v2(183.85,31.71) v2(185.48,33.28) v2(186.24,33.22) v2(187.89,33.28) v2(192.27,30.75) v2(200.91,33.17) v2(200.91,32.59) v2(200.91,32) v2(200.91,31.42) v2(201.49,33.17) v2(201.49,32.59) v2(201.49,32) v2(201.49,31.42) v2(202.08,33.17) v2(202.08,32.59) v2(202.08,32) v2(202.08,31.42) v2(202.66,33.17) v2(202.66,32.59) v2(202.66,32) v2(202.66,31.42) v2(242.24,51.76) v2(242.24,51.18) v2(242.24,50.59) v2(249.08,40.8) v2(251.75,45.76) v2(251.75,45.17) v2(251.75,44.59) v2(252.31,45.48) v2(252.31,44.89) v2(252.91,44.91) v4(113.41,118.88)
+13.5VB_1.05VALWP:
  vias: v1(196.34,84.34) v2(195.83,84.69) v2(195.83,84.11) v2(195.83,83.53) v2(195.83,82.94)
+13.5VB_3V:
  vias: v1(249.49,44.27) v2(248.22,42.87) v2(248.28,43.51) v2(248.92,43.44)
+13.5VB_5V: length 0.7
  TOP w0.102: 198.37,33.79 v1(198.37,34.49)
  vias: v2(198.47,33.22) v2(198.5,32.08)
+13.5VB_CPU: length 1.2
  BOTTOM w0.508: PRZ57.1 110.78,103.18 v2(111.22,103.62)
  vias: v1(170.56,135.39) v2(153.82,124.4) v2(153.82,123.82) v2(153.82,123.23) v2(154.4,124.98) v2(154.4,124.4) v2(154.4,123.82) v2(154.4,123.23) v2(154.99,124.98) v2(154.99,124.4) v2(154.99,123.82) v2(154.99,123.23) v2(155.57,124.4) v2(155.57,123.82) v2(155.57,123.23) v2(161.63,128.88) v2(161.63,128.2) v2(162.84,128.88) v2(162.84,128.2) v2(165.45,134.63) v2(165.45,134) v2(166.04,134.63) v2(166.04,134) v2(166.62,134.63) v2(166.62,134) v2(171.67,128.86) v2(171.67,128.19) v2(172.88,128.86) v2(172.88,128.19) v2(173.6,134.94) v2(173.6,134.35) v2(174.24,134.94) v2(174.24,134.35) v2(174.87,134.94) v2(174.87,134.35) v2(181.6,128.94) v2(181.6,128.27) v2(182.81,128.94) v2(182.81,128.27) v2(183.95,134.94) v2(183.95,134.35) v2(184.59,134.94) v2(184.59,134.35) v2(185.17,134.94) v2(185.17,134.35) v2(191.25,129.01) v2(191.25,128.34) v2(192.46,129.01) v2(192.46,128.34) v2(196.08,134.95) v2(196.72,135.14) v2(196.72,134.5) v2(197.1,133.93) v2(197.42,135.14) v2(197.42,134.5) v2(198.12,135.14) v2(198.12,134.5)
+13.5VB_DDR:
  vias: v1(183.26,37.22) v2(178.24,37.48) v2(178.82,37.48) v2(179.41,37.48) v2(179.99,37.48)
+13.5VB_GT:
  vias: v1(94.36,98.69) v2(92.02,99.16) v2(92.02,98.58) v2(92.02,97.99) v2(92.02,97.41) v2(92.02,96.82) v2(92.02,96.24) v2(92.02,95.65) v2(99.94,91.96) v2(99.94,91.32) v2(99.94,90.62) v2(100.64,91.96) v2(100.64,91.32) v2(100.64,90.62) v2(100.79,88.44) v2(100.79,87.23) v2(101.46,88.44) v2(101.46,87.23)
+13.5VB_IR: length 1.2
  BOTTOM w0.102: v1(99.82,131.37) 100.1,131.65 FZ1.1
+13.5VB_SA:
  vias: v1(202.56,121.42) v2(198.91,118.49) v2(198.91,117.81) v2(200.12,118.49) v2(200.12,117.81)
+13.5VB_VCHGR:
  vias: v1(109.22,38.94)
+19.5V_AC:
  vias: v1(85.91,39.19)
+19.5V_CHARGER:
  vias: v1(84.7,38.55) v2(87.56,38.36) v2(88.64,38.43) v2(89.4,38.43) v2(90.36,38.43) v2(91.12,38.43) v2(92.13,38.43) v2(92.9,38.43) v2(93.85,38.43) v2(94.67,38.43)
+19.5V_DC_IN: length 20.2
  TOP w0.508: PQ11.3 98.31,135.41 PR31.1 99.96,135.41 100.39,135.84 101.7,135.84 v2(102.44,136.58) ; v2(81.03,114.4) 81.43,114.79 84.28,114.79 84.81,114.27 84.81,113.09 83.73,112.01 PR871.2 84.29,111.39 84.29,109.09 v4(82.66,107.46) 82.35,107.15 v2(82.35,105.42)
  BOTTOM w0.508: v2(82.35,105.42) 82.57,105.63 PR800.1
  vias: v2(71.36,120.04)
+19.5V_DC_IN_SS: length 93.4
  TOP w0.508: PD700.2 125.45,41.54 124.67,42.31 117.89,42.31 117.02,43.19 92.71,43.19 89.85,46.05 89.85,46.57 89.85,46.57 89.85,52.59 91.98,54.72 91.98,72.67 85.8,78.86 v1(85.8,87.51) 85.8,91.81 81.44,96.17 v2(81.16,96.17)
  vias: v2(74.23,116.28)
+19.5V_DCIN_JACK: length 4.7
  TOP w0.102: v4(67.7,128.88) 68.44,128.88 69.07,128.24 v4(69.07,127.92) 69.07,127.12 69.22,126.97 69.22,126.34 v4(69.15,126.26) 68.5,126.26 v2(68.28,126.05)
+19.5V_SDC_IN: length 15.1
  TOP w0.508: v2(130.53,38.39) 130.53,39.25 PD706.2 ; PQ805.3 113.05,72.27 114.27,71.05 PR802.1 114.8,70.6 112.76,68.55 106.26,68.55 v2(105.52,69.29)
  vias: v2(77.53,119.53) v2(77.53,118.95) v2(77.6,120.11) v2(78.03,120.72) v2(78.11,119.53) v2(78.11,118.95) v2(78.19,120.15) v2(78.6,120.59) v2(78.66,119.76) v2(78.77,118.95) v2(79.13,119.41) v2(79.18,120.67) v2(79.18,120.09) v2(84.13,43.57) v2(84.2,42.94) v2(84.39,44.14) v2(84.77,44.71) v2(84.7,43.38) v2(88.13,54.43) v2(88.26,55.7) v2(88.2,55.06) v2(88.45,56.91) v2(88.39,56.27) v2(88.51,57.54) v2(88.64,59.44) v2(88.64,58.81) v2(88.58,58.18) v2(88.7,60.02) v4(81.34,116.6)
+20V_LDO_INPUT:
  vias: v1(79.41,111.92)
+20V_TBTA_VBUS:
  vias: v1(23.39,97.64) v2(6.51,108.63) v2(6.51,105.9) v2(8.81,107.96) v2(8.81,106) v2(9.39,107.96) v2(9.39,106) v2(9.58,108.53) v2(9.7,105.47) v2(10.03,107.96) v2(10.17,108.53) v2(10.16,104.9) v2(10.75,108.53) v2(10.74,104.87) v2(11.32,104.87) v2(20.53,98.6) v2(20.53,97.97) v2(21.23,98.6) v2(21.23,97.97) v2(21.51,97.12) v2(21.59,96.47) v2(21.95,98.63) v2(21.95,97.99) v2(22.09,97.1) v2(22.22,96.47) v2(22.65,98.63) v2(22.65,97.99) v2(22.72,97.38)
+20V_TBTA_VBUS_1: length 70.4
  TOP w0.254: PR801.1 98.59,72.16 PQ803.3 98.48,71.78 97.14,70.43 95.72,70.43 95.37,70.77 95.37,75.51 89.82,81.06 89.82,91.86 83.88,97.8 83.88,107.96 85.15,109.23 PR872.2
  TOP w0.508: v2(74.18,112.14) 74.44,112.41 76.39,112.41 76.89,112.91 76.89,114.62 77.39,115.11 79.52,115.11 79.84,115.43 84.54,115.43 85.44,114.53 85.44,112.63 85.15,112.34 PR872.2
  BOTTOM w0.508: v2(74.18,112.14) 74.18,112.23 74.8,112.85 PR831.1
  vias: v1(24.76,92.97) v2(20.68,92.09) v2(21.27,92.15) v2(21.78,92.78) v2(21.9,92.15) v2(22.46,92.73) v2(22.54,92.15) v2(23.05,92.82) v2(23.12,92.15) v2(23.63,92.82) v2(23.71,92.15) v2(24.25,93.8) v2(24.84,93.8) v2(25.42,93.8) v2(35.75,99.01) v2(35.75,98.42) v2(66.21,104.38) v2(66.61,103.86) v2(67.44,109.99) v2(67.44,109.35) v2(68.08,110.94) v2(68.08,110.3) v2(68.08,109.67) v2(68.08,109.03) v2(68.78,110.94) v2(68.78,110.3) v2(68.78,109.67) v2(68.78,109.03) v2(69.29,116.14) v2(69.98,116.14) v2(70.62,116.14) v2(71.32,116.14) v2(73.92,92.91) v2(74.21,92.4) v2(74.51,92.91) v2(82.37,109.19) v2(82.4,108.61)
+20V_VBUS_DC_SS: length 93
  TOP w0.508: PD704.2 v4(120.39,43) 118.11,43 117.28,43.83 92.97,43.83 90.48,46.31 90.48,52.33 92.62,54.46 92.62,72.94 86.43,79.12 86.43,92.07 v2(81.82,96.69)
  BOTTOM w0.508: PR870.1 76.89,108.71 v2(77.07,108.53)
  vias: v2(74.81,127.9)
+DV33_18: length 1.4
  TOP w0.089: 297.3,22.36 297.49,22.36 297.75,22.11
  TOP w0.102: 297.75,22.11 298,21.85 298.45,21.85 v1(298.51,21.92)
+GND_CHASSIS: length 16.5
  TOP w0.508: v2(298.05,98.45) 298.8,99.2 RL18.2 v1(298.8,100.85) RL17.2 298.8,105.51 298.31,106 RL16.2 297.81,107.07 298.8,108.07 RL15.2
  BOTTOM w0.508: CL22.2 295.98,97.63 296.81,98.45 v2(298.05,98.45)
+VCC1V8A_TBTA_LDO: length 2.2
  BOTTOM w0.203: UT5.K1 60.92,110.17
  BOTTOM w0.381: CT73.1 60.34,110.75 60.92,110.17
+VCC1V8D_TBTA_LDO: length 2.4
  TOP w0.508: CT72.1 62.35,104.17 62.29,104.1 v2(62.29,103.9)
  BOTTOM w0.203: v2(62.29,103.9) 62.23,103.96 62.23,104.53 62.18,104.57 62.18,104.86 UT5.A2
  BOTTOM w0.508: RT97.1 71.55,109.74 v2(71.67,109.61)
+VCC3V3_ANA_PCIE: length 1.5
  TOP w0.203: v2(40.99,104.65) 40.28,103.94 CT63.1
  BOTTOM w0.203: UT1.L16 v2(40.99,104.65)
+VCC3V3_ANA_USB2: length 1.3
  TOP w0.254: v2(40.99,105.3) 40.85,105.15 40.3,105.15 CT64.1
  BOTTOM w0.203: v2(40.99,105.3) 40.99,105.28 40.69,104.97 UT1.J16
+VCC_FUSEPRG: length 1.3
  TOP w0.508: RC326.1 180.51,100.92 v2(180.46,100.98)
  BOTTOM w0.254: UC1.G30 169.95,104.99 v2(170.27,105.31)
+VCC_SFR_OC: length 3
  TOP w0.127: v2(129.07,90.62) v4(128.48,90.62)
  TOP w0.381: v2(138.73,90.73) 138.17,90.73 CC209.2
  BOTTOM w0.254: UC1.BJ13 138.09,91.03 UC1.BH13 138.43,91.03 v2(138.73,90.73)
  BOTTOM w0.305: v2(169.63,89.5) 169.95,89.84 UC1.G11
  vias: v2(129.07,89.99)
+VCCRTCEXT: length 3.9
  BOTTOM w0.254: UH1.BF47 UH1.BG47 239.43,111.03 240.24,111.84 CH68.1
+VDDA_AVDD1: length 4.1
  TOP w0.508: LA5.1 292.36,49.87 CA9.1
  vias: v1(288.98,50.75)
+VSS_PLL: length 4.2
  TOP w0.305: UE1.G1 260.95,96.13
  TOP w0.356: CE18.2 259.4,97.68 260.95,96.13
  TOP w0.381: CE18.2 257.92,97.68 CE17.2
GND: length 5940.1
  TOP w0.102: v2(189.76,85.95) 189.93,86.12 190.18,86.12 190.45,85.85 v1(190.45,83.64) 190.45,82.02 191.12,81.35 196.4,81.35 197.99,79.77 198.93,79.77 200.15,78.55 v2(200.15,78.54) ; v2(199.56,78.56) 198.67,79.45 197.89,79.45 196.21,81.13 191.02,81.13 189.84,82.31 v1(189.84,82.46) v2(189.84,83.26) ; v2(189.03,86.13) 189.41,85.76 v1(189.41,85.59) 189.41,84.39 188.97,83.96 188.97,82.19 190.73,80.43 195.3,80.43 196.85,78.88 v2(196.85,78.56) ; v2(196.14,78.56) 196.14,79.26 195.21,80.2 190.64,80.2 188.74,82.09 188.74,84.24 v1(188.84,84.34) 188.84,84.85 188.97,84.97 v2(189,84.97) ; v2(189.84,84.48) 189.2,83.85 189.2,82.28 190.83,80.65 195.58,80.65 v1(196.91,79.32) v2(197.61,78.62) ; v2(200.73,78.51) 200.73,78.53 199.12,80.14 198.03,80.14 196.59,81.58 191.21,81.58 190.8,81.99 190.8,86.31 190.57,86.53 v1(190.3,86.53) v2(189.79,86.53) ; v2(189.84,83.86) 189.79,83.86 189.43,83.5 189.43,82.4 190.93,80.9 195.91,80.9 v1(196.18,80.62) 197.67,79.13 198.33,79.13 198.94,78.53 v2(198.98,78.53) ; v2(193.99,78.56) 193.99,78.94 192.96,79.97 190.29,79.97 188.51,81.75 188.51,86.23 v1(190.36,88.07) v2(190.98,88.07) ; v2(191.64,88.73) 191.64,87.38 191.13,86.88 v1(191.13,84.97) 191.13,81.99 191.31,81.81 196.78,81.81 198.14,80.45 199.44,80.45 201.31,78.58 v2(201.31,78.53) ; v2(224.09,71.38) 223.93,71.23 222.51,71.23 v1(219.83,73.92) 215.73,78.01 215.73,80.25 214.54,81.44 208.4,81.44 207.04,80.08 v2(204.59,80.08)
  TOP w0.127: v4(269.17,55.13) 268.03,53.99 v2(267.97,53.99) ; v2(54.89,116.63) v4(54.89,115.94) ; v2(280.02,61.39) v4(280.02,62.44) ; v2(33.36,95.08) 33.33,95.11 33.33,95.7 v4(33.59,95.96) ; v4(294.79,55.92) 294.95,55.75 v2(294.95,55.19) ; v2(295.69,120.17) v4(296.3,120.17) ; v2(28.29,111.42) v4(28.29,110.64) ; RH110.2 216.21,96.28 215.83,95.9 v2(215.83,95.13) 215.9,95.07 v2(218.83,95.07) 218.82,95.05 v2(218.82,94.31) 219.45,94.31 219.77,94.63 219.77,95.26 219.74,95.29 v2(219.74,95.29) ; v2(295.36,44.35) v4(295.36,44.97)
  TOP w0.203: UZ4.11 v2(267.77,42.86) ; QE2.1 254.33,108.42 254.2,108.29 254.2,107.97 253.93,107.71 252.66,107.71 252.37,108 CE549.2 ; UZ52.C1 273.93,67.49 274.13,67.28 v2(274.5,67.28) ; v2(259.66,49.86) 259.65,49.87 UZ3.11 ; v2(292.98,92.09) 293.05,92.02 293.37,92.02 294.2,91.19 294.2,88.54 UV31.E5
  TOP w0.254: v2(16.42,105.66) 16.11,105.97 DT18.2 ; CZ51.2 247.55,124.64 247.41,124.5 247.2,124.5 247.18,124.48 UZ12.2 ; UZ12.23 242.61,124.48 v2(242.94,124.15) ; v2(15.88,108.14) DT17.2 ; DT17.2 15.65,107.54 v2(15.34,107.85) ; DT17.2 16.11,107.54 v2(16.42,107.85) ; v2(239.71,35.18) 239.71,35.19 239.86,35.19 240.21,35.54 UN7.3 ; UV31.D4 293.4,86.94 v2(293.34,86.94) ; DT18.2 15.65,105.97 v2(15.34,105.66) ; DT18.2 v2(15.88,105.37) ; JUSBC1.B1 6.11,104.57 v2(6.47,104.21) 6.58,104.32 JUSBC1.A12 7.95,104.32 8.31,103.96 v2(8.31,103.2) ; v2(13.68,104.69) 13.37,104.38 RT220.2 ; UZ8.5 265.82,36.89 266.44,36.27 v2(266.44,36.14) ; v2(15.72,104.58) 15.41,104.27 DT14.2 ; RT220.2 12.91,104.38 v2(12.6,104.69) ; RT220.2 v2(13.14,104.98) ; v2(13.14,101.99) RT219.2 ; RT219.2 13.37,102.59 v2(13.68,102.28) ; RT219.2 12.91,102.59 v2(12.6,102.28) ; v2(228.23,129.86) 227.8,129.86 227.26,130.4 CH552.2 RH635.2 ; v2(246.09,124.15) 246.26,123.98 UZ12.32 ; UD1.3 119.23,93.83 118.98,93.57 v2(117.68,93.57) ; v2(13.84,108.25) RT491.2 ; RT491.2 14.07,107.66 v2(14.38,107.97) ; RT491.2 13.61,107.66 v2(13.3,107.97) ; 294.47,92.81 295.72,91.56 v2(295.72,91.55) ; 294.47,92.81 v2(294.46,92.82) ; 294.47,92.81 294.47,92.89 v4(293.69,93.67) 292.79,94.57 292.79,96.64 v2(292.29,97.14) 292.29,97.42 292.03,97.67 290.79,97.67 290.44,97.33 v2(289.66,97.33) 288.79,97.33 288.48,97.01 288.48,94.73 288.73,94.47 290.06,94.47 v2(290.43,94.1) 290.43,93.75 290.7,93.48 291.59,93.48 v2(292.98,92.09) ; v2(226.63,36.27) 226.56,36.33 CZ66.2 ; UH7.3 229.05,132.14 v2(229.52,132.61) ; DT13.2 14.95,102.69 v2(14.64,102.38) ; DT13.2 v2(15.18,102.1) ; DT13.2 15.41,102.69 v2(15.72,102.38) ; UE3.3 260.27,123.96 259.87,124.36 257.75,124.36 257.47,124.07 UE4.3 ; UV31.B3 v2(291.8,86.14) ; UZ12.16 242.76,127.48 v2(242.94,127.3) ; v2(292.61,88.54) 292.21,88.94 UV31.B6 ; UZ10.3 283.44,87.05 284.03,87.64 284.89,87.64 285.47,87.07 285.55,87.07 v2(285.62,87.01) ; UI6.10 73.28,99.08 73.21,99.01 73.21,99.01 v2(73.22,99.01) ; v2(271.12,79.75) 271.01,79.75 270.72,79.45 UZ29.11 ; v2(79.23,99.26) 79.04,99.08 UI6.21 ; v2(13.3,105.55) 13.61,105.86 RT490.2 ; CZ68.2 228.02,41.31 v2(227.96,41.38) ; v2(13.84,105.27) RT490.2 ; RT490.2 14.07,105.86 v2(14.38,105.55) ; v2(296.62,89.3) 296.25,88.94 UV31.G6 ; PU3000.4 38.1,122.17 v2(37.75,122.52) ; UV31.E4 v2(294.2,86.94) ; CN17.2 240.24,38.36 239.98,38.11 v2(239.77,38.11) ; DT14.2 14.95,104.27 v2(14.64,104.58) ; DT14.2 v2(15.18,104.86) ; UV31.G3 v2(296.6,86.14) ; RZ1406.2 274.82,71.77 274.47,72.12 v2(274.47,72.22) ; UE1.A6 265.27,101.35 v2(265.13,101.5) ; CZ64.2 v2(228.07,36.33) ; CT87.2 65.16,109.15 v2(65.16,108.94) ; DT42.3 303.72,115.64 305.49,117.42 v2(305.94,117.42) ; UZ52.C1 UZ52.B1 ; UV31.E5 294.24,87.78 v2(294.24,87.73) ; v2(294.56,73.15) 294.53,73.11 UI3.14 ; v2(267.61,77.16) 267.84,77.39 UZ29.5 ; v2(265.05,79.69) 265.29,79.45 UZ29.20 ; JUSBC1.A1 7.08,109.82 6.64,110.27 v2(6.51,110.27) 6.51,110.27 6.3,110.27 6.11,110.07 JUSBC1.B12 ; v2(257.93,30.9) 257.93,31.16 257.79,31.3 UZ23.5 ; UV31.D5 v2(293.42,88.51) ; UZ12.9 246.26,128.72 246.01,128.97 244.16,128.97 v2(243.96,129.17)
  TOP w0.305: v2(227.71,35.02) 227.71,33.1 227.56,32.96 JAPS1.12 ; RH325.1 235.31,104.34 235.11,104.34 235.02,104.43 v2(234.71,104.43) ; RC171.1 129.27,82.29 129.84,82.86 v2(131.26,82.86) ; JAPS1.14 v2(228.56,33.32) ; v2(198.65,90.37) 198.65,90.89 198.43,91.11 PC314.1 PC312.1 ; v2(271.08,101.39) 271.08,101.21 270.87,101.01 UE1.A13 ; CT39.2 42.39,107.34 v2(42.29,107.25) ; PR3003.1 42.67,122.55 43.09,122.97 PC3001.1 43.72,122.97 v2(44,122.69) ; v2(286.77,91.08) 286.83,91.13 CV605.2 ; CV39.2 v2(295.58,78.14) ; v2(225.62,33.34) 225.56,33.28 JAPS1.8 ; JAPS1.10 226.56,30.8 226.31,30.55 v2(226.31,30.53)
  TOP w0.356: RI59.2 78.15,94.7 78.53,94.32 80.67,94.32 81.34,94.99 v2(81.34,95.29) ; CE11.2 261.45,103 261.1,102.65 v2(261.09,102.65) ; v2(43.58,102.7) 43.21,102.34 CT35.2 CT34.2 ; v2(126.35,129.68) 126.45,129.77 CZ2.2 ; CZ218.2 264.87,85.67 v2(265.32,85.67) ; v2(263.62,88.66) 263.96,88.33 CE21.2 ; PC1044.2 PC1045.2 155.7,90.4 155.35,90.05 v2(155.15,90.05) ; v2(265.71,97.38) 265.71,97.35 265.65,97.41 265.64,97.41 265.32,97.73 UE1.E6 ; v2(35.37,118.53) 35.21,118.37 PC3007.2 ; CR19.1 302.7,25.78 v2(303.03,26.11) ; v2(256.82,95.06) 257.66,95.06 258.29,94.44 CE31.2 ; v2(45.54,124.67) 45.02,124.15 PC3006.2 PC3008.2 ; v2(46.58,119.97) 46.43,119.82 PC3009.2 45.89,120.27 PQ3000.4 ; CA55.2 281.52,51.61 v2(281.74,51.84) ; v2(74.61,119.78) 74.61,119.23 PR24.2 ; v2(44.89,109.85) 44.89,109.39 CT41.2 44.76,109.19 44.74,109.17 CT38.2 ; v2(263.25,94.9) 263.25,94.97 263.6,95.33 UE1.H4 ; CR17.1 v2(302.72,21.51) ; v2(241.02,114.96) 241.14,115.09 RH627.2 ; CH22.2 222.95,110.78 CH21.2 222.95,109.28 v2(222.95,109.28) ; PC1060.2 155.72,92.82 PC1043.2 155.26,92.82 v2(155.16,92.92) ; RH110.2 CH554.2 219.2,96.28 219.74,95.73 v2(219.74,95.29) ; CV22.2 130.28,131.7 CZ1.2 ; CA10.2 v2(281.21,58.23)
  TOP w0.381: v2(253.17,106.25) 253.03,106.39 QE2.4 ; v2(105.78,71.31) 105.79,71.31 105.79,71.32 105.96,71.15 PQ809.1 ; CZ75.2 248.75,127.49 CZ50.2 248.28,128.33 v2(248.76,128.81) ; CE549.2 251,109.8 v2(250.32,110.48) ; CH348.2 233.41,114.86 RH633.2 233.57,114.23 v2(232.79,113.44) ; v2(128.76,57.31) 128.08,56.63 CD11.2 ; UC3.3 208.72,120.96 RH70.2 ; CT99.2 10.66,106.25 10.79,106.37 v2(10.79,106.69) 10.79,106.94 10.66,107.07 CT100.1 ; PQ3000.1 43.37,122.2 PC3001.1 ; CD58.2 211.15,42.73 CD57.2 210.1,42.73 RD29.2 ; CD26.2 136.51,46.07 CD25.2 ; v2(207.39,48.55) 207.86,48.55 208.21,48.91 208.21,50.11 208.51,50.41 CD44.2 ; CD12.2 120.77,53.67 120.2,53.1 120.2,52.02 120.52,51.7 v2(121.23,51.7) ; v2(278,105.67) 278,105.74 278.3,106.04 CL13.2 ; PC1091.2 145.53,92.45 v2(145.47,92.51) ; CZ90.2 189.04,41.21 v2(189.1,41.26) ; v2(134.88,35.09) 134.83,35.04 PD2.1 ; v2(261.33,56.25) 261.18,56.41 261.05,56.41 CZ82.2 ; PQ806.4 111.96,78.43 111.96,78.31 112.34,77.92 v2(112.45,77.92) ; v2(260,122.72) 260,122.77 260.27,123.04 UE3.3 ; CZ111.2 v2(257.55,81.86) ; CE19.2 280.73,89.47 281.11,89.09 v2(281.2,89.09) ; v2(252.96,30.5) 253.27,30.81 253.66,30.81 RN5.2 ; v2(161.08,130.88) 161.08,130.41 PCH23.2 ; PQ802.4 v2(103.39,73.78) 103.39,74.59 PR855.2 ; PR45.2 v2(99.44,129.68) 99.25,129.68 98.86,130.06 PQ10.1 ; CH551.2 211.45,100.72 v2(210.69,99.96) ; v2(278.25,104.98) 278.25,103.87 278.55,103.57 280.84,103.57 281.17,103.89 v2(281.17,104.49) v2(281.17,105.25) 281.17,106.22 CL14.2 ; CV40.2 v2(303.53,80.15) ; CD43.2 201.2,50.65 201.61,50.24 201.61,48.71 201.3,48.41 v2(200.73,48.41) ; PQ802.1 102.09,71.39 102.52,71.82 v2(103.12,71.82) ; v2(262.43,122.74) 262.43,122.81 262.88,123.26 UE5.3 ; CH343.2 235.16,115.43 RH628.2 ; CD9.2 125.4,51.91 v2(125.39,51.93) ; CD47.2 191.67,41.82 v2(191.35,41.5) ; v2(244.53,98.05) 244.41,98.05 244.41,98.05 RH649.2 ; CE63.2 284.16,101.93 284.24,102.01 284.24,102.55 v2(283.99,102.79) ; UE1.C4 v2(264.07,98.93) ; CH37.2 217,113.02 CH67.2 216.71,113.84 CH323.2 ; v2(104.45,76.08) 104.45,76.4 104.33,76.53 PR846.2 104.2,76.81 PU801.3 ; v2(132.25,50.87) 131.76,50.87 131.44,51.19 CD14.2 ; v2(40.34,105.95) 40.2,105.8 CT49.2 39.66,105.78 CT64.2 ; CZ1204.2 268.07,45.58 268.47,45.98 v2(268.85,45.98) ; CA31.2 279.01,61.04 279.4,61.42 279.99,61.42 v2(280.02,61.39) ; PR744.2 v2(153.3,33.14) ; RN11.1 243.32,40.43 243.01,40.75 v2(242.94,40.75) 242.56,40.36 RN21.2 ; PQ808.1 116.25,77.33 116.48,77.56 116.48,78.27 v2(116.57,78.37) 116.63,78.32 117.17,78.32 117.55,78.7 PQ808.4 ; v2(286.77,91.08) 286.77,91.62 286.69,91.7 RV601.1 ; v2(236.4,118.39) 236.6,118.19 RH632.2 ; v2(155.64,50.42) 155.57,50.49 CD10.2 ; v2(187.7,96.28) 187.53,96.1 UZ35.3 ; CD46.2 187.76,49.87 v2(186.97,49.08) ; v2(42.94,108.55) 42.91,108.51 CT27.2 ; CL8.2 v2(281.47,111.75) ; v2(23.37,101.22) DT39.3 v2(20.96,101.22) ; v2(246.18,108.09) 245.66,107.57 CH40.1 244.32,107.54 CMOS1.1 243.01,107.73 CH556.2 240.56,107.73 ; RH636.1 217.06,124.7 217.44,124.32 v2(218.54,124.32) ; CH34.2 227.43,94.51 v2(227.43,94.12) ; v2(39.69,103.36) 39.66,103.4 CT63.2 ; CZ92.2 185.36,41.46 v2(185.42,41.52) ; CZ100.2 v2(185.22,97.1) ; v2(110.42,76.02) 110.72,76.32 PQ806.1 110.17,77.15 PQ813.1 ; CZ117.2 263.98,41.64 CZ116.2 ; PC3004.1 41.27,119.45 v2(41.84,120.03) ; v2(141.44,49.91) 141.96,50.43 CD16.2 ; v2(232.51,100.77) 232.56,100.82 CH62.2 ; v2(273.05,116.85) 273.05,116.91 272.6,117.36 CL11.2 ; RN19.2 v2(247.2,30.81) ; CD41.2 200.02,44.6 200.4,44.98 v2(200.68,44.98) ; RH627.2 241.17,115.49 CC556.2 ; RC756.2 223.64,110.74 CH22.2 ; UZ51.2 277.13,69.23 276.61,68.71 v2(276.61,67.41) 276.3,67.41 CZ216.2 ; v2(74.73,104.47) 74.59,104.33 74.59,103.79 RI61.2 ; 240.56,107.73 240.38,107.91 RH424.2 ; 240.56,107.73 240.09,107.26 v2(238.68,107.26) 238.86,107.44 CH553.2 ; v2(47.84,104.28) 47.08,105.03 CT29.2 46.23,105.03 CT30.2 ; v2(65.71,107.99) 65.74,107.96 RT86.2 ; v2(65.72,107.41) 65.92,107.41 66.18,107.15 RT71.2 ; CA75.2 219.11,121.57 RH637.1 ; v2(139.89,49.68) 139.89,49.67 CD15.2 ; v2(187.15,35.05) CZ80.2 ; PR3005.1 37.23,124.06 PC3003.1 ; CE548.2 v2(253.93,94.75) ; CZ217.2 273.24,70.63 v2(273.05,70.82) ; CL10.2 281.49,108.02 v2(281.74,108.28) ; v2(192.65,35.44) 192.26,35.05 CZ81.2 ; CA45.2 v2(288.49,61.59) ; CC209.1 137.54,90.33 v2(137.82,90.05) ; CN9.2 v2(251.9,34.24) ; v2(226.44,38.78) 226.44,38.88 226.5,38.94 CZ67.2 ; v2(192.47,36.76) 192.47,37.14 192.09,37.52 CZ89.2 ; PQ1.4 74.99,114.25 74.61,113.87 v2(74.1,113.87) 74.1,115.2 73.58,115.72 PQ1.1 ; PQ804.1 108.19,75.4 v2(108.53,75.05) ; v2(296.86,26.24) 296.86,26.76 CR15.2 ; CH347.2 237.51,118.1 RH629.2 237.51,119.16 CH344.2 ; CZ51.2 248.57,124.93 CZ52.2 249.04,125.36 v2(248.41,125.99) ; PQ10.4 96.35,131.91 96.33,131.94 96.3,131.94 v2(96.17,132.06) ; CR18.1 302.16,21.25 302.41,21.51 v2(302.72,21.51) ; DZ13.3 307.78,7.17 v2(307.46,7.49) ; v2(109.12,74.09) 109.13,74.1 PQ804.4 109.93,74.1 110.13,73.9 110.6,73.9 PR819.2 ; CE15.2 258.43,95.83 257.66,95.06 ; v2(225.96,45.24) 225.83,45.36 CD42.2 ; v2(134.35,37.92) 134.25,37.82 PD1.1 ; v2(265.05,79.69) 264.9,79.85 CZ155.2 ; v2(263.94,52.26) UZ54.3 264.11,51.38 RZ1472.1 ; CC335.2 CC334.2 85.62,130.3 85.43,130.11 v2(85.43,129.77) ; CE62.2 v2(254.12,99.17) ; PU701.3 v2(151.16,30.45) ; v2(75.76,94.27) 75.76,94.84 RI76.2 ; CC332.2 217.04,86.73 CH20.2 216.97,86.79 216.97,87.3 CC331.2 216.95,87.69 216.84,87.8 v2(216.84,87.84) ; CR21.2 298.45,20.08 v2(298.76,20.39) ; v2(282.32,90.17) 283.65,90.17 CE36.2 283.99,89.82 CZ93.2 ; CA47.2 281.39,59.94 CA46.2 ; v2(40.36,109.85) 40.44,109.92 CT26.2 ; v2(210.69,101.14) 211.08,101.14 211.29,101.36 CH550.2 ; RH313.2 213.84,101.36 v2(213.58,101.61) ; v2(231.54,121.36) 231.07,121.36 230.75,121.68 RH268.2 ; v2(241.43,99.55) 241.45,99.58 242.76,99.58 ; v2(189.87,41.32) 189.88,41.31 CZ1203.2 ; CD13.2 136.02,50.43 v2(135.75,50.16) ; CT102.1 11.3,106.31 11.43,106.44 v2(11.43,106.69) 11.43,107.01 11.23,107.2 CT101.2 ; v2(40.99,106.6) 40.47,107.12 CT61.2 ; CL7.2 276.64,118.54 276.47,118.7 RL12.2 276.41,118.77 276.34,118.84 v2(275.71,118.84) ; v2(186.25,41.33) 186,41.08 CZ91.2 ; v2(279.65,109.67) 279.71,109.67 280.09,109.29 CL9.2 ; CH270.2 v2(254.06,91.56) ; v2(195.04,52.36) 195.04,52.05 195.13,51.95 195.13,51.78 CD45.2 ; CZ54.2 CZ53.2 239.53,123.21 239.45,123.14 239.45,123.14 239.4,123.08 v2(239.07,123.08) ; PC810.2 117.58,73.85 117.39,73.66 PQ811.4 ; PQ811.1 114.23,74.96 113.85,75.34 PQ812.3 113.69,75.56 113.69,76.87 113.72,76.91 113.72,77.14 v2(113.78,77.19) ; CT32.2 42.45,105.79 v2(42.29,105.95) 42.27,105.97 CT25.2 42.31,106.63 CT40.2 ; RE342.2 263.46,88.49 263.62,88.66 v2(263.62,88.66) ; v2(261,33.11) 260.51,32.62 CZ129.2 ; v2(105.09,76.08) 105.1,76.09 105.1,77.79 105.76,78.45 PQ813.4 ; CH36.2 231.33,102.2 v2(231.18,102.35) ; v2(222.81,117.7) 223.02,117.49 CC327.2 223.02,116.93 222.53,116.43 CC310.2 ; CC329.2 221.78,120.12 v2(221.99,120.34) 222.31,120.02 222.31,119.59 222.69,119.21 RH372.2 ; v2(229.52,132.61) 229.59,132.53 RH65.2 ; v2(244.22,113.99) 243.68,113.99 CH33.2 CH65.2 ; CE30.2 277.62,96.72 277.92,97.02 v2(277.94,97.02) ; CN10.2 250.12,34.94 v2(250.44,34.62) 250.69,34.87 CN11.2 ; v2(234.8,119) 235.08,118.72 CH558.2 ; DT41.3 300.27,113.92 v2(300.49,113.7) ; CD48.2 182.67,42.08 v2(182.67,41.53) ; CR22.2 297.95,22.64 v2(298.32,23.01) ; v2(44.24,105.3) 44.24,105.8 CT31.2 ; v2(211.39,88.53) 211.92,89.06 CH29.2 ; v2(145.63,136.6) CV8.2 CV9.2 ; CT28.2 44.18,109.9 v2(44.24,109.85) ; v2(266.56,102.41) CE14.2 CE23.2 ; CA49.1 CA80.1 v2(292.22,56.92) ; CZ309.2 v2(285.43,122.17) ; v2(270.51,41.22) 270.53,41.24 270.68,41.24 270.93,41.48 CZ1205.2 ; v2(281.24,116.72) 281.24,116.02 CL3.2 ; QN6.3 v2(250.55,32.49) ; v2(232.51,98.52) 232.69,98.34 CH64.2 ; CH66.2 231.45,98.48 v2(231.18,98.48) ; CV12.2 141.16,130.42 v2(141.52,130.06) 141.79,130.33 CV10.2 ; RN7.1 244.21,30.59 244.5,30.3 v2(244.6,30.3) 244.69,30.3 245.04,30.65 CN16.2 ; RT377.2 62.92,109.43 63.26,109.09 v2(63.26,108.94) ; UZ6.3 v2(256.88,56.23) ; CT33.2 44.33,104.65 44.9,104.65 v2(44.9,104.65) ; UE4.3 257.47,122.83 258.06,122.25 258.06,120.36 CE53.2 ; CI19.2 289.93,71.39 v2(289.81,71.51) ; v2(263.5,32.55) 263.77,32.83 CZ120.2 ; CE12.2 263.01,111.24 CE10.2 263.29,112.54 264.75,113.99 v2(264.81,113.99) ; CH32.2 215.49,90.47 CH46.2 ; RN9.1 241.93,30.59 241.64,30.3 v2(241.55,30.3) 241.45,30.3 241.16,30.59 RN15.1 ; CL19.2 v2(295.84,118.25) ; JSD1.17 317.22,20.5 316.47,21.26 v2(316.47,21.33) ; CC319.2 229.31,119.18 v2(229.3,119.17) ; CA7.2 128.26,130.73 v2(128.26,130.08) ; v2(107.57,70.54) 107.57,70.41 108.13,69.85 PQ809.4 ; 248.53,103.7 249.3,103.7 249.34,103.66 QH8.1 ; RE550.2 256.89,89.74 CE22.2 257.51,89.29 v2(257.59,89.22) ; CZ122.2 v2(263.76,44.13) ; RT22.2 33.5,108.75 v2(33.21,109.04) 33.55,109.39 RT21.2 ; RH651.2 RH652.2 244.84,95.83 v2(245.21,95.46) ; v2(279.94,78.51) 279.94,78.47 279.84,78.37 RZ1399.2 ; PR739.2 v2(150.83,33.31) ; RI60.2 RI59.2 ; RE93.2 v2(267.37,105.06)
  TOP w0.406: QH8.4 252.46,102.36
  TOP w0.457: v2(162.43,79.43) 161.93,78.93 CC84.2 ; v2(265.32,85.67) 265.32,86.27 CE66.2 ; v2(144.67,93.48) 144.67,93.89 PC2039.2 ; PC1016.2 165.42,98.59 v2(165.01,98.59) ; v2(140.17,94.43) 140.58,94.43 PC2052.2 ; PC1009.2 160.54,92.76 v2(160.14,92.76) ; PC1007.2 162.26,96.17 v2(162.66,96.17) ; CC81.2 148.98,78.8 v2(148.2,78.8) ; v2(151.91,80.16) 151.89,80.13 CC166.2 ; v2(140.19,99.89) 140.59,99.89 PC2050.2 ; v2(165.01,96.17) 165.42,96.17 PC1011.2 ; v2(148.16,80.62) 147.53,80.62 147.5,80.59 CC171.2 ; PC2037.2 140.6,93.22 v2(140.19,93.22) ; CC163.2 163.61,80.66 v2(164.12,81.17) ; v2(140.18,101.11) 140.59,101.11 PC2042.2 ; CC33.2 90.66,134.63 v2(90.66,135.35) ; PC1002.2 162.08,92.74 v2(162.49,92.74) ; v2(218.33,102.96) 218.49,103.12 RH1.1 ; PC1015.2 162.26,98.59 v2(162.66,98.59) ; RD5.2 160.51,47.23 v2(160.52,47.21) 160.51,47.2 RD7.2 ; v2(162.66,99.79) 162.26,99.79 PC1629.2 ; v2(161.22,80.75) 160.74,80.26 160.74,80.23 CC168.2 ; PC1005.2 165.42,99.79 v2(165.01,99.79) ; v2(142.54,92.65) 142.13,92.65 PC2034.2 ; PC2056.2 142.12,93.86 v2(142.53,93.86) ; v2(155.73,79.33) 155.72,79.32 CC164.2 ; PC1008.2 165.42,97.38 v2(165.01,97.38) ; v2(142.6,100) 143,100 PC1010.2 ; RT38.2 45.62,103.29 v2(45.54,103.36) ; v2(140.15,98.66) 140.56,98.66 PC2040.2 ; v2(165.42,79.89) 165.15,79.62 165.15,79.05 ; JSD1.23 316.3,15.04 v2(316.03,15.31) ; CE47.2 274.66,87.75 v2(273.99,87.75) ; CC161.2 155.74,77.48 v2(155.73,77.49) ; v2(294.56,73.15) 294.52,73.19 RI14.1 CI43.2 ; v2(279.23,57.45) 279.21,57.47 279.21,57.48 278.75,57.94 CA61.2 ; PC2038.2 143,98.79 v2(142.6,98.79) ; v2(152.06,77.27) 151.91,77.42 CC165.2 ; v2(159.04,79.23) 159.01,79.19 158.48,79.19 CC170.2 ; v2(142.6,101.2) 143,101.2 PC2051.2 ; v2(162.66,97.38) 162.26,97.38 PC1634.2 ; v2(163.17,100.94) 162.83,100.94 PC1001.2 ; v2(160.08,77.61) 160.06,77.59 CC83.2
  TOP w0.508: v2(209.35,119.01) 208.85,119.01 207.96,118.12 RH606.2 RH603.2 RH608.2 ; DZ11.1 273.46,122.63 v2(273.46,123.24) ; CE60.2 RE85.2 277.89,91.17 v2(278.01,91.05) ; CZ41.2 305.87,9.48 v2(305.29,8.9) ; v2(46.45,118.44) 46.42,118.44 46.56,118.3 RT30.2 ; v2(147.92,136.58) 148.15,136.34 RV3.1 ; v2(269.89,106.14) 270.05,106.3 271.46,106.3 271.97,106.81 RL9.2 ; CA76.2 218.49,124.37 v2(218.54,124.32) 218.49,124.27 CH268.1 ; CH32.2 215.26,91.7 v2(215.06,91.9) ; v2(259.22,109.58) 259.2,109.6 RZ25.2 RE313.2 ; v2(128.39,31.01) 128.39,30.81 128.47,30.73 PC751.2 ; RI61.2 RI73.2 ; RI71.2 RI78.2 76.81,104.04 v2(76.51,104.34) ; v2(142.46,30.64) 142.46,31.3 PR720.2 ; RA45.2 277.1,51.33 276.96,51.47 v2(276.96,51.6) ; v2(287.51,21.07) 287.38,21.21 CN62.2 ; v2(210.5,126.29) 210.5,124.15 210.29,123.95 CH10.2 ; CZ83.2 189.81,41.26 v2(189.87,41.32) ; v2(209.99,31.7) PC166.2 PC167.2 ; CI52.2 79.74,103.98 v2(80.11,103.61) ; PC739.1 v2(142.35,36.4) ; v2(297.05,28.08) 297.49,28.08 300.54,31.13 v2(300.54,31.32) 299.91,31.95 DA2.1 ; PRZ41.1 PCZ22.1 v2(101.23,110.31) ; v2(254.5,95.12) 254.77,95.39 RE702.2 ; CZ86.2 187.25,36.69 v2(187.33,36.76) 187.33,37.14 187.71,37.52 CZ88.2 ; v2(216.02,117.36) 216.72,116.66 CH559.2 ; RA52.1 CA54.2 ; CA54.2 277.06,56.09 v2(276.83,56.32) ; CA54.2 CA33.2 ; RV624.2 v2(132.01,118.31) ; v2(145.33,128.01) 145.32,128.03 CV634.2 ; CD61.2 195.42,44.11 v2(195.42,44.12) ; v2(240,41.31) 240.03,41.31 240.03,41.29 240.28,41.04 RN13.1 ; PC765.2 117.93,37.03 PC743.2 ; v2(106.1,81.98) PRZ83.2 PHZ5.2 ; RZ334.2 v2(307.96,1.79) ; CI50.2 72.56,96.9 73.21,97.55 v2(73.4,97.55) ; RA35.2 v2(283.14,45.43) ; CE4.2 256.55,111.58 256.55,111 256.49,110.94 v2(256.49,110.93) ; v2(152.56,34.09) PR514.2 PC513.2 ; v2(250.06,100.02) 250.43,100.02 250.51,100.1 CE16.2 ; v2(188.59,93.48) 188.59,93.42 189.1,92.91 CZ544.2 ; v2(128.68,52.56) 128.71,52.59 CD6.2 ; v2(306.51,27.56) 306.01,27.06 JSD1.11 ; QR1.3 299.38,27.65 299.08,27.95 v2(298.51,27.95) ; RC139.2 RC436.2 123.24,99.24 123.6,98.88 124.71,98.88 125.03,99.2 v2(126.47,99.2) ; CZ121.2 262.87,36.67 263.38,36.16 v2(263.85,36.16) ; CA66.2 262.76,32.44 262.38,32.06 v2(262,32.06) 261.87,32.19 CA65.2 ; CA73.2 v2(217.47,119.53) ; CZ39.2 v2(308.22,2.74) ; CR27.2 CR28.2 v2(289,29) ; CA75.2 CA74.2 v2(220.33,121.22) ; v2(278.55,95.39) 278.03,95.39 277.9,95.26 277.31,95.26 CE40.2 ; UT7.2 58.03,122.12 57.53,121.61 56.13,121.61 55.51,121 v2(55.51,119.43) ; v2(137.55,44.67) 137.55,44.1 RD9.2 ; v2(199,89.8) 199,89.73 199.12,89.61 199.12,89.49 199.4,89.22 PC313.2 ; v2(216.05,112.76) 216.08,112.72 CH37.2 ; v2(198.93,48.46) 198.85,48.46 198.34,48.97 198.34,49.91 CD39.2 ; PD4.1 52.33,122.22 52.32,122.21 v2(52.16,122.21) ; CT74.2 v2(56.37,104.9) ; v2(126.68,128.29) DA9.1 ; v2(144.07,136.58) 143.95,136.46 CV21.2 ; v2(79.94,109.27) 79.27,108.6 PU2.2 ; 126.99,133.55 126.32,133.55 QV2.3 ; 126.99,133.55 127.05,133.61 CV14.2 ; 126.99,133.55 v2(126.99,133.54) ; CH344.2 237.22,119.64 237.73,120.15 v2(238.17,120.15) ; CZ34.2 276.16,34.63 v2(276.27,34.74) ; CZ34.2 CZ35.2 ; CZ34.2 CZ33.2 ; PCH26.2 178.32,126.99 v2(178.02,127.28) ; v2(50.33,108.66) 49.6,109.39 RT29.2 RT128.2 ; CE28.2 259.47,103.45 258.9,104.02 v2(258.9,104.47) ; CE53.2 CE52.2 ; CC269.2 87.32,134.73 v2(87.94,135.35) ; RH618.1 226.17,123.47 226.87,122.77 226.87,121.94 227.06,121.75 v2(227.06,121.59) ; RC75.2 242.24,116.3 241.52,116.3 CH342.2 241.5,116.97 241.76,117.23 v2(241.87,117.23) ; RV1.2 138.27,136.27 v2(138.57,136.58) ; 274.19,105.93 274,105.74 274,104.98 CL28.2 273.3,103.34 274.77,101.86 RE77.2 CE38.2 ; 274.19,105.93 v2(274.2,105.93) ; 274.19,105.93 274.06,106.06 CL30.2 ; PR862.2 77.73,128.39 v2(77.73,128.43) ; CZ71.2 227,36.27 v2(226.63,36.27) ; v2(263.68,105.96) 263.52,106.13 CE29.2 ; CR20.1 301.94,26.38 302.31,26.74 v2(303.08,26.74) ; v2(238.5,126.06) 238.63,126.18 CZ56.2 ; v2(263.33,42.36) 263.38,42.42 CZ117.2 ; CT78.2 71.46,102.65 v2(71.98,102.65) ; CV607.2 v2(290.43,94.1) ; v2(150.83,33.31) 151.1,33.31 151.17,33.23 151.18,33.23 151.4,33.01 151.4,33 PC754.1 ; v2(134.17,47.76) 134.77,47.16 RD16.2 ; v2(134.2,101.06) 134.22,101.08 RC181.2 ; v2(129.26,124.2) 129.26,123.15 CZ1200.2 ; UV32.4 288.05,82.75 287.86,82.56 v2(287.85,82.56) ; CZ37.2 v2(304.86,9.41) ; v2(24.51,91.01) 24.19,90.69 DI2.1 ; v2(260.96,80.68) 261.29,80.68 CZ21.2 CZ17.2 ; RD18.2 140.34,45.13 139.89,44.67 v2(139.62,44.67) ; v2(210.08,103.59) 209.24,102.75 CC304.2 ; CN3.2 255.23,38.78 255.58,39.13 v2(255.6,39.13) ; v2(258.46,81.73) 258.46,81.75 259.11,82.4 CZ110.2 CZ109.2 ; RH612.1 212.1,116.44 v2(212.53,116.44) ; v2(227.72,62.35) 221.8,62.35 209.56,74.59 v2(209.56,78.52) ; v2(117.85,48.71) 118.82,48.71 CD32.2 ; PC11.2 78.34,114.23 v2(78.54,114.44) ; v2(35.36,124.33) 35.36,124.09 35.87,123.58 PQ13.3 ; v2(210.49,48.86) 210.97,48.86 211.48,49.37 CD33.2 ; CH30.2 214.87,115.77 214.47,116.16 RH609.1 214.05,117.23 v2(213.74,117.55) ; RT127.2 v2(42.67,113.6) ; v2(74.8,136.34) RC122.2 ; v2(216.42,41.52) 216.42,41.54 CD35.2 215.42,41.91 v2(215.42,41.52) ; v2(125.87,36.76) 125.88,36.78 126.56,36.78 PC737.1 ; CR26.2 v2(289.62,26.13) ; PC865.2 105.21,132.85 v2(105.85,132.22) ; QZ19.3 278.55,76.46 v2(278.55,77.08) ; v2(44.26,118.4) 44.06,118.21 RT126.2 ; YL1.4 280.5,104.49 v2(281.17,104.49) ; CA48.2 288.7,62.63 v2(289.28,62.06) ; v2(117.48,55.41) 118.3,55.41 118.8,55.91 CD2.2 ; v2(135.79,48.38) 136.08,48.38 136.58,47.87 136.58,46.91 136.84,46.66 CD26.2 ; JAPS1.19 v2(221.06,34.11) ; v2(228.92,74.55) 228.86,74.55 228.77,74.64 PC505.2 227.33,74.64 PR505.2 ; CZ500.2 v2(281.29,120.01) ; CZ57.2 v2(228.79,41.41) ; PC744.2 126.12,31.11 v2(126.17,31.06) ; PU501.2 230.44,76.72 v2(230.12,77.04) ; RV626.2 CV633.2 145.93,126.13 v2(146.3,126.5) ; v2(122.42,96.34) RC441.2 RC437.2 RC324.2 RC322.2 123.15,93.7 RC442.2 ; CR25.2 289.47,27.02 v2(289.67,26.82) ; CZ55.2 238.8,121.83 v2(238.65,121.69) ; v2(174.62,113.23) 174.94,113.55 CC323.2 ; CE3.2 259.72,92.91 v2(259.77,92.86) ; v2(276.79,24.39) CN63.2 276.79,23.12 277.35,22.57 CN60.2 277.37,22.15 CN61.2 ; v2(203.77,44.2) 203.74,44.17 CD37.2 ; v2(232.91,36.45) 232.93,36.43 CZ62.2 ; PC2055.2 136.65,92.42 v2(136.15,92.42) ; v2(197.94,115.44) 197.72,115.23 PCA12.2 ; v2(58.83,115.24) 58.83,117.12 59.23,117.51 CT92.2 CT91.2 ; CC82.2 168.06,77.92 v2(167.33,77.92) ; RE58.2 RE55.2 255.94,106.7 v2(255.42,106.7) ; CV632.2 135.31,120.27 135.31,120.55 v2(135.33,120.55) ; v2(96.09,103.81) 96.21,103.94 PCZ9.1 PRZ22.1 ; CZ306.2 264.91,50.57 v2(264.79,50.68) ; v2(216.02,114.56) 216.21,114.37 CH323.2 ; v2(105.65,98.99) 105.65,99.52 PRZ63.2 ; v2(96.09,101.14) 96.15,101.21 PCZ6.1 ; v2(316.03,15.31) 315.55,15.8 315.55,17.13 315.83,17.41 316.67,17.41 317.04,17.77 JSD1.20 ; CV1637.2 v2(144.84,136.58) ; PCZ6.1 PRZ15.1 ; PCZ6.1 PRZ26.2 ; v2(253.93,94.75) 253.31,94.13 RE56.2 ; 252.46,102.36 v2(252.5,102.32) 252.93,101.89 CE61.2 253.85,101.41 CE59.2 ; v2(148.33,134.77) 148.33,133.3 ; 148.33,133.3 148.19,133.16 CV17.2 ; 148.33,133.3 UV24.2 ; RH379.2 234.58,102.91 235.08,103.4 v2(235.08,103.42) 235.34,103.16 235.34,102.96 RH377.1 ; v2(280.63,61.4) 280.73,61.3 CA46.2 ; v2(201.8,40.71) 202.1,40.41 PC137.2 ; CV630.2 283.07,77.35 283.57,76.85 v2(284.54,76.85) ; PQ12.3 103.65,136.23 v2(103.7,136.23) ; CD3.2 122.61,52.1 122.98,51.74 v2(123.36,51.74) ; v2(76.82,132.46) 76.82,133.42 RC219.1 ; v2(72.6,100.56) 72.48,100.56 71.98,101.06 RI77.1 ; QV21.3 130.04,120.96 v2(130.04,120.96) ; YL1.2 278.64,105.37 v2(278.25,104.98) 278,105.22 v2(278,105.67) ; v2(186.25,41.33) 186.76,40.83 CZ85.2 ; v2(278.28,53.65) 278.68,54.06 CA53.2 ; CV606.2 292.26,97.11 v2(292.29,97.14) ; CZ36.2 270.63,34.24 270.55,34.15 v2(270.51,34.15) ; CH321.2 251.65,89.35 v2(251.35,89.05) ; PR302.2 195.22,87.8 v2(194.56,88.47) ; PC125.2 206.57,33.16 207.08,32.65 v4(208.47,32.65) v2(209.99,32.65) ; v2(283.66,96.67) 283.04,96.67 CE57.2 ; v2(81.79,97.51) 81.74,97.51 81.33,97.11 RI70.2 ; PR723.2 127.01,31.33 v2(126.8,31.13) ; CT46.2 RT26.2 38.67,112.99 v2(38.54,113.12) ; v2(246.58,106.16) 246.38,105.95 246.38,104.78 247.45,103.7 248.53,103.7 ; PC810.2 118.09,73.85 120.33,76.09 120.33,78.69 v2(122.31,80.67) ; JSD1.6 303.8,18.36 303.56,18.13 v2(302.59,18.13) ; CZ69.2 228.59,36.33 v2(228.07,36.33) ; DA6.1 v2(292.02,30.68) ; CL18.2 v2(295.07,118.31) ; v2(233.99,90.01) 233.78,89.8 CH47.2 ; v2(130.36,37.73) 129.98,37.73 129.79,37.54 PR709.1 ; CZ73.2 v2(230.67,41.39) ; RZ10.1 v2(225.17,36.26) ; RE20.2 248.17,88.9 248.68,88.38 v2(249.3,88.38) ; CC307.2 85.97,133.35 85.46,132.83 v2(85.16,132.83) ; v2(152.06,49.96) 152.64,49.96 CD7.2 ; v2(202.92,49.31) 203.43,49.31 203.67,49.55 CD38.2 ; v2(246.17,121.22) 247.28,121.22 247.79,120.71 CH340.2 ; v2(131.64,132.32) 131.64,131.75 CV23.2 CV22.2 ; CL4.2 276.31,104.07 276.22,104.16 v2(275.72,104.16) 275.59,104.3 RL3.2 ; v2(300.41,91.7) 300.03,92.09 RV615.2 ; CV19.2 CV18.2 126.74,132.53 v2(126.8,132.6) ; CD34.2 218.78,52.38 v2(218.75,52.42) ; CZ118.2 263.97,43.32 263.59,43.32 263.46,43.19 v2(263.33,43.19) ; v2(157.79,92.76) 157.38,92.76 PC1018.2 ; v2(169.03,52.41) 169.16,52.54 CD40.2 ; QH6.3 249.95,116.49 251,117.54 254.25,117.54 255.58,116.22 255.58,114.47 v2(254.82,113.71) ; CR1.2 v2(295.78,28.33) ; RV602.1 286.4,94.88 v2(286.01,94.88) ; v2(228.42,69.91) 228.77,69.91 228.98,70.11 PC530.1 ; DI3.1 298.14,53.82 v2(299.22,53.82) ; CZ3.2 v2(128.26,133.17) ; CA62.2 276.42,50 v2(276.41,49.99) ; CA68.2 v2(282.89,74.11) ; RZ40.1 251.39,83.73 v2(251.39,84.51) ; CC333.1 178.81,113.8 178.87,113.74 v2(178.87,112.21) ; CD52.2 CD53.2 229.33,49.46 228.32,48.46 v2(227.76,48.46) ; v2(213.6,112.5) 213.15,112.95 RH611.1 RH610.1 ; RV2.2 139.08,132.66 138.57,132.15 v2(138.23,132.15) ; RE65.2 277.12,98.41 JTAG1.2 277.74,98.5 277.88,98.36 v2(277.93,98.36) ; PR3005.1 36.76,124.15 36.52,124.4 v2(36.13,124.4) ; QE12.3 269.62,107.07 269.06,106.51 v2(269.06,106.45) ; PC3002.2 42.6,120.41 42.22,120.03 v2(41.84,120.03) ; RT35.2 40.83,117.91 41.38,118.46 v2(41.38,118.47) 41.97,117.87 RT27.2 ; v2(123.63,36.76) 123.36,36.76 122.63,36.03 PC745.2 ; CC328.2 239.07,91.37 v2(238.55,91.89) ; RL13.2 v2(281.76,109.66) ; v2(37.75,122.52) 37.47,122.52 37.27,122.32 PC3005.2 36.25,122.32 PR3011.2 35.68,122.26 PR9.2 ; v2(143.11,36.94) 143.26,36.79 PC516.2 ; v2(175.99,41.52) 175.89,41.43 PR207.2 ; CZ87.2 187.65,41.51 v2(187.65,41.52) ; v2(228.23,129.86) 228.23,129.15 228.34,129.04 RH554.2 RH556.2 ; CE66.2 265.18,86.43 265.18,87.49 RE717.1 ; v2(184.51,38.76) 184.4,38.87 CZ84.2 ; DI5.1 v2(294,65.48) ; v2(312.63,120.34) 312.87,120.1 SW3.3 ; CC185.2 169.67,81.27 v2(169.69,81.29) ; CZ40.2 306.1,3.57 305.6,4.08 v2(305.6,4.85) ; CV41.2 302.57,80.85 303.27,80.15 v2(303.53,80.15) ; v2(235.6,116.07) 235.19,115.65 CH343.2 ; v2(270.67,44.26) 271.28,43.65 RZ38.1 ; v2(225.8,75.19) 226.25,75.64 PC506.2 ; RD29.2 209.64,42.27 209.64,41.59 v2(209.58,41.52) ; CV1638.2 110.17,130.13 v2(110.1,130.07) ; CZ130.2 260.12,31.19 v2(260.35,31.42) ; CE65.2 286.06,103.27 286.06,104.21 v2(285.81,104.47) ; v2(275.76,37.73) 275.34,37.73 CZ8.2 CZ7.2 ; v2(47.72,122.64) 47.72,123.15 PR8.2 ; v2(201.41,94) 200.91,94.5 200.15,94.5 199.56,93.91 PC402.2 ; v2(180.25,128.6) 180.59,128.27 PCH54.2 ; v2(245.55,37.57) 245.68,37.71 RN17.1 ; RD31.2 206.34,42.05 206.12,41.83 v2(206.12,41.54) ; v2(285.87,101.67) 285.73,101.53 RE541.1 285.73,100.02 CE64.2 ; RD25.2 213.7,43.24 214.02,42.92 214.02,41.74 v2(213.81,41.52) ; RD23.2 237.12,43.91 v2(237.02,44.02) ; v2(118.8,44.66) 119.58,45.44 120.46,45.44 CD4.2 ; CL12.2 269.8,110.98 v2(269.53,110.71) ; v2(251.9,34.24) 252.26,34.24 CN8.2 ; v2(143.42,50.11) 143.85,50.11 CD8.2 ; PR716.2 v2(141.57,30.65) ; RV618.2 v2(281.44,82.16) ; v2(176.46,32.65) 176.46,33.28 PC230.2 176.03,34.02 175.75,34.31 v2(175.75,34.47) ; DA10.1 133.09,127.26 133.03,127.2 v2(133,127.2) ; v2(136.14,136.58) 135.84,136.28 CV15.2 ; PC112.2 250.02,51.41 v2(249.92,51.51) 250.88,51.51 251.26,51.13 PC172.2 251.26,48.41 PC170.2 PC169.2 PC171.2 ; CA56.2 v2(279.65,51.9) ; RT23.2 40.39,113.03 40.39,113.33 40.47,113.42 40.47,113.43 40.7,113.65 40.71,113.65 v2(40.83,113.77) 41.14,113.46 RT129.2 ; PC813.2 v2(105.09,76.08) ; PQ703.3 v2(142.11,34.56) ; v2(99.29,77.58) 98.42,76.71 PQ814.3 99.13,75.38 PC814.1 ; v2(128.68,47.5) 128.68,46.65 CD5.2 ; CH2.2 212.53,94.1 v2(212.28,94.36) 211.96,94.36 211.45,93.85 CH349.2 ; v2(127.96,123.95) 127.62,124.29 CA5.2 CA6.2 ; v2(198.88,45.03) 198.67,45.03 197.99,44.35 CD36.2 ; v2(108.23,126.43) 108.21,126.41 106.68,126.41 106.35,126.74 RV319.1 ; PQ6.3 104.28,126.36 104.77,126.86 104.77,127.94 v2(104.76,127.94) ; v2(142.51,130.06) 142.55,130.1 CV636.2 ; CA67.2 v2(282.82,73.23) ; v2(280.22,22.49) 280.6,22.11 CN80.2 280.93,21.17 CN81.2 ; PR506.2 233.82,73.36 v2(233.63,73.17) ; CV20.2 v2(143.07,136.58) ; v2(79.91,102.31) 80.23,102.31 80.76,101.77 RI75.1 ; CT47.2 36.27,112.51 v2(36.13,112.37) ; v2(73.78,109.67) 73.98,109.87 PC10.2 ; v2(281.74,108.28) 282.75,107.28 QE17.3 ; PU3.3 100.85,126.8 101.04,126.62 PC13.1 102.42,126.62 v2(102.53,126.5) ; CC327.2 223.91,117.04 RH617.1 ; PC204.2 175.75,36.4 v2(175.81,36.34) ; v2(63.26,108.94) 63.26,108.88 63.38,108.75 63.38,108.6 63.82,108.16 RT101.2 ; CC29.2 CC28.2 90.33,131.84 89.82,132.35 v2(89.65,132.35) ; CV1635.2 v2(119.5,136.33) ; CN64.2 v2(280.41,24.2) ; v2(281.1,48.21) CA72.2 RA51.2 ; RZ360.2 v2(266.02,75.7) ; QV19.3 v2(137.15,123.01) ; PR310.2 196.02,92.53 v2(195.92,92.63) 195.15,91.87 PC2211.2 ; RT34.2 v2(44.89,103.99) ; v2(148.71,48.31) 149.14,48.31 149.38,48.08 149.38,46.86 148.9,46.39 CD1.2 ; PR3008.1 38.97,120.23 38.92,120.28 v2(38.92,120.47) ; QV7.3 v2(114.59,133.79) ; v2(256.49,100.65) 256.63,100.65 256.77,100.51 RE95.1 ; CT72.2 62.35,105.81 v2(62.72,106.17) ; CN1.2 255.21,37.85 v2(255.58,37.48) ; RT24.2 47.8,115.28 48.58,116.05 v2(48.58,116.34) 48.58,117.09 PQ3.3 ; CV16.2 143.63,129.75 v2(143.76,129.61) ; CR5.2 v2(291.51,20) 291.27,20 290.76,19.49 290.76,18.98 RR4.2 ; DA7.1 v2(288.08,30.8) ; v2(138.17,119.01) 138.16,119 CV635.2 RV629.2 ; CZ63.2 v2(230.28,38.11) ; PC12.2 75.03,111.72 v2(74.35,111.04) ; SW3.1 v2(309.22,120.1) ; CI44.2 299,72.73 v2(299.27,72.46) ; v2(288.81,63.7) CA63.2 CA64.2 ; CZ154.2 v2(271.77,80.4) ; v2(281.87,114.37) 281.79,114.29 281.79,114.11 281.76,114.08 CL29.2 ; RA37.2 v2(295.27,53.99) ; CC302.2 210.69,118.95 209.93,119.71 v2(209.55,119.71) 208.85,119.71 208.47,120.09 RH70.2 ; v2(248.53,110.88) RH334.1 ; CC325.2 116.45,105.86 115.63,105.04 v2(115.63,105.06) ; v2(64.77,111.77) 64.77,112.52 CT94.2 ; PQ7.3 74.5,119.89 v2(74.61,119.78) ; CI31.2 289.81,71.57 v2(289.81,71.51) ; v2(281.26,94.81) 281.26,94.82 280.41,94.82 280.28,94.94 CE8.2 ; JSD1.14 v2(316.44,23.57) ; v2(226.44,38.78) 226.75,38.78 227.26,39.29 CZ72.2 ; RV619.2 v2(291.57,80.13) ; JAPS1.20 v2(231.56,33.22) ; DZ10.1 v2(107.12,131.9) ; v2(289.94,62.61) RA36.2 ; v2(229.92,41.41) 229.74,41.23 CZ58.2 ; RC325.2 RC443.2 136.13,94.74 v2(136.14,94.75) 136.98,95.6 PC2058.2
  GND1 w0.203: 1.75,80.77 H23.1 ; H23.1 3.02,81.23 ; H23.1 4.3,78.23 ; H23.1 1.3,79.5 ; H23.1 3.02,77.77 ; H23.1 4.75,79.5 ; H23.1 1.75,78.23 ; H23.1 4.3,80.77 ; JHDMI1.11 307.91,85.1 ; JHDMI1.11 307.91,84.19 ; JHDMI1.11 308.02,84.65 ; JHDMI1.11 306.99,84.19 ; JHDMI1.11 306.88,84.65 ; JHDMI1.11 306.99,85.1 ; JUSB2.12 8.54,82.17 ; JUSB2.12 5.8,82.17 ; JUSB2.12 7.17,82.17 ; JUSB2.12 5.8,83 ; JUSB2.12 8.54,83 ; JUSB3.13 304.7,54.77 ; JUSB3.13 301.96,54.77 ; JUSB3.13 303.33,56.43 ; JUSB3.13 304.7,55.6 ; JUSB3.13 303.33,54.77 ; JUSB3.13 304.7,56.43 ; JUSB3.13 301.96,55.6 ; JUSB3.13 301.96,56.43 ; 14.35,97.1 JUSB2.10 ; JUSB2.10 14.35,97.93 ; JUSB2.10 15.72,97.93 ; JUSB2.10 17.09,97.1 ; JUSB2.10 17.09,96.27 ; JUSB2.10 15.72,96.27 ; JUSB2.10 17.09,97.93 ; JUSB2.10 14.35,96.27 ; JLOM1.12 310.87,112.67 ; JLOM1.12 308.13,112 ; JLOM1.12 308.13,112.67 ; JLOM1.12 309.5,111.33 ; JLOM1.12 310.87,111.33 ; JLOM1.12 308.13,111.33 ; JLOM1.12 309.5,112.67 ; JLOM1.12 310.87,112 ; H3.1 186.05,85.52 ; H3.1 185.39,83.75 ; H3.1 181.86,83.75 ; H3.1 183.62,87.95 ; H3.1 185.39,87.29 ; H3.1 181.2,85.52 ; H3.1 183.62,83.09 ; H3.1 181.86,87.29 ; 301.96,41.97 JUSB3.10 ; JUSB3.10 303.33,43.63 ; JUSB3.10 304.7,41.97 ; JUSB3.10 303.33,41.97 ; JUSB3.10 304.7,43.63 ; JUSB3.10 304.7,42.8 ; JUSB3.10 301.96,42.8 ; JUSB3.10 301.96,43.63 ; JSD1.10 306.18,13.46 ; JSD1.10 303.92,13.46 ; JSD1.10 305.05,14.19 ; JSD1.10 303.92,14.19 ; JSD1.10 303.92,12.74 ; JSD1.10 305.05,12.74 ; JSD1.10 306.18,12.74 ; JSD1.10 306.18,14.19 ; 289.26,118.73 H12.1 ; H12.1 289.26,122.27 ; H12.1 291.02,118.07 ; H12.1 292.79,118.73 ; H12.1 288.6,120.5 ; H12.1 292.79,122.27 ; H12.1 291.02,122.93 ; H12.1 293.45,120.5 ; JHDMI1.2 306.36,88.69 ; JHDMI1.2 305.44,88.69 ; JHDMI1.2 306.47,89.15 ; JHDMI1.2 305.9,89.72 ; JHDMI1.2 305.33,89.15 ; JHDMI1.2 306.36,89.6 ; JHDMI1.2 305.44,89.6 ; 16.12,86.42 JUSB2.4 ; JUSB2.4 15.52,86.6 ; JUSB2.4 16.12,87.98 ; JUSB2.4 15.34,87.2 ; JUSB2.4 16.9,87.2 ; JUSB2.4 15.52,87.8 ; JUSB2.4 16.72,87.8 ; JUSB2.4 16.72,86.6 ; 280.46,65.56 H8.1 ; H8.1 283.44,65.56 ; H8.1 279.92,67.05 ; H8.1 283.44,68.54 ; H8.1 281.95,65.02 ; H8.1 283.98,67.05 ; H8.1 280.46,68.54 ; H8.1 281.95,69.08 ; JUSB1.11 313.25,58.7 ; JUSB1.11 310.51,57.87 ; JUSB1.11 311.88,57.87 ; JUSB1.11 310.51,58.7 ; JUSB1.11 313.25,57.87 ; JHDMI1.23 315.18,75.42 ; JHDMI1.23 313.6,75.42 ; JHDMI1.23 312.02,76.4 ; JHDMI1.23 315.18,76.4 ; JHDMI1.23 312.02,75.42 ; 314.93,112.67 JLOM1.11 ; JLOM1.11 316.3,112.67 ; JLOM1.11 316.3,111.33 ; JLOM1.11 314.93,111.33 ; JLOM1.11 317.67,111.33 ; JLOM1.11 317.67,112 ; JLOM1.11 317.67,112.67 ; JLOM1.11 314.93,112 ; 303.83,49.8 JUSB3.7 ; JUSB3.7 305.03,48.6 ; JUSB3.7 304.43,48.42 ; JUSB3.7 305.03,49.8 ; JUSB3.7 304.43,49.98 ; JUSB3.7 303.65,49.2 ; JUSB3.7 303.83,48.6 ; JUSB2.7 15.39,90.7 ; JUSB2.7 14.02,91.3 ; JUSB2.7 14.62,91.48 ; JUSB2.7 14.62,89.92 ; JUSB2.7 15.22,91.3 ; JUSB2.7 15.22,90.1 ; JUSB2.7 14.02,90.1 ; 305.72,91.42 JHDMI1.20 ; JHDMI1.20 307.3,91.42 ; JHDMI1.20 305.72,93.38 ; JHDMI1.20 307.3,93.38 ; JHDMI1.20 305.72,92.4 ; JHDMI1.20 308.88,93.38 ; H17.1 17.2,113.67 ; H17.1 14.65,111.13 ; H17.1 17.2,111.13 ; H17.1 14.65,113.67 ; H17.1 15.93,110.67 ; H17.1 15.93,114.13 ; H17.1 17.65,112.4 ; H17.1 14.2,112.4 ; 305.05,26.34 JSD1.11 ; JSD1.11 306.18,26.34 ; JSD1.11 303.92,27.06 ; JSD1.11 303.92,26.34 ; JSD1.11 303.92,27.79 ; JSD1.11 306.18,27.79 ; JSD1.11 306.18,27.06 ; JSD1.11 305.05,27.79 ; JHDMI1.17 307.91,82.1 ; JHDMI1.17 306.99,82.1 ; JHDMI1.17 306.99,81.19 ; JHDMI1.17 307.91,81.19 ; JHDMI1.17 308.02,81.65 ; JHDMI1.17 306.88,81.65 ; JLOM1.9 310.87,96.37 ; JLOM1.9 308.13,95.7 ; JLOM1.9 310.87,95.7 ; JLOM1.9 310.87,95.03 ; JLOM1.9 309.5,95.03 ; JLOM1.9 309.5,96.37 ; JLOM1.9 308.13,95.03 ; JLOM1.9 308.13,96.37 ; JUSB3.12 313.25,56.9 ; JUSB3.12 313.25,57.73 ; JUSB3.12 310.51,56.9 ; JUSB3.12 311.88,57.73 ; JUSB3.12 310.51,57.73 ; JHDMI1.5 307.91,87.19 ; JHDMI1.5 307.91,88.1 ; JHDMI1.5 306.99,88.1 ; JHDMI1.5 306.88,87.65 ; JHDMI1.5 306.99,87.19 ; JHDMI1.5 308.02,87.65 ; 303.33,59.17 JUSB1.10 ; JUSB1.10 303.33,60.83 ; JUSB1.10 304.7,59.17 ; JUSB1.10 301.96,60.83 ; JUSB1.10 304.7,60.83 ; JUSB1.10 301.96,60 ; JUSB1.10 301.96,59.17 ; JUSB1.10 304.7,60 ; 117.2,85.52 H1.1 ; H1.1 119.62,83.09 ; H1.1 117.86,83.75 ; H1.1 121.39,83.75 ; H1.1 117.86,87.29 ; H1.1 119.62,87.95 ; H1.1 121.39,87.29 ; H1.1 122.05,85.52 ; 256.1,26.5 H11.1 ; H11.1 260.29,28.27 ; H11.1 258.53,28.93 ; H11.1 256.76,24.73 ; H11.1 260.29,24.73 ; H11.1 258.53,24.07 ; H11.1 256.76,28.27 ; H11.1 260.95,26.5 ; JUSB3.4 303.53,52.1 ; JUSB3.4 303.53,53.3 ; JUSB3.4 302.33,52.1 ; JUSB3.4 302.33,53.3 ; JUSB3.4 302.15,52.7 ; JUSB3.4 302.93,53.48 ; JUSB3.4 303.71,52.7 ; JUSB3.4 302.93,51.92 ; 69.52,132.27 H16.1 ; H16.1 69.52,135.73 ; H16.1 68.25,132.73 ; H16.1 68.25,135.27 ; H16.1 67.8,134 ; H16.1 71.25,134 ; H16.1 70.8,135.27 ; H16.1 70.8,132.73 ; JUSBC1.4 7.98,102.88 ; JUSBC1.4 7.98,103.65 ; JUSBC1.4 6.65,102.1 ; JUSBC1.4 5.32,102.88 ; JUSBC1.4 5.32,102.1 ; JUSBC1.4 7.98,102.1 ; JUSB1.7 304.43,67.18 ; JUSB1.7 303.65,66.4 ; JUSB1.7 304.43,65.62 ; JUSB1.7 303.83,65.8 ; JUSB1.7 305.03,65.8 ; JUSB1.7 303.83,67 ; JUSB1.7 305.03,67 ; 241.1,75 H35.1 ; H35.1 245.29,76.77 ; H35.1 245.95,75 ; H35.1 241.76,73.23 ; H35.1 243.52,72.57 ; H35.1 245.29,73.23 ; H35.1 241.76,76.77 ; H35.1 243.52,77.43 ; JHDMI1.22 315.18,93.9 ; JHDMI1.22 312.02,94.88 ; JHDMI1.22 313.6,94.88 ; JHDMI1.22 312.02,93.9 ; JHDMI1.22 315.18,94.88 ; 305.33,86.15 JHDMI1.8 ; JHDMI1.8 306.36,86.6 ; JHDMI1.8 305.44,85.69 ; JHDMI1.8 305.44,86.6 ; JHDMI1.8 306.47,86.15 ; JHDMI1.8 306.36,85.69 ; 157.82,134.3 H2.1 ; H2.1 157.19,136 ; H2.1 157.82,137.7 ; H2.1 161.23,134.3 ; H2.1 159.52,133.66 ; H2.1 161.23,137.7 ; H2.1 159.52,138.34 ; H2.1 161.86,136 ; 300,118.48 H15.1 ; H15.1 299.44,120 ; H15.1 301.52,122.08 ; H15.1 303.61,120 ; H15.1 301.52,117.92 ; H15.1 300,121.52 ; H15.1 303.05,121.52 ; H15.1 303.05,118.48 ; JUSB2.13 17.09,83.47 ; JUSB2.13 14.35,85.13 ; JUSB2.13 14.35,84.3 ; JUSB2.13 17.09,85.13 ; JUSB2.13 15.72,83.47 ; JUSB2.13 14.35,83.47 ; JUSB2.13 17.09,84.3 ; JUSB2.13 15.72,85.13 ; JUSB1.4 303.71,69.9 ; JUSB1.4 303.53,70.5 ; JUSB1.4 302.93,70.67 ; JUSB1.4 303.53,69.3 ; JUSB1.4 302.15,69.9 ; JUSB1.4 302.33,70.5 ; JUSB1.4 302.33,69.3 ; JUSB1.4 302.93,69.12 ; 310.51,41.5 JUSB3.11 313.25,41.5 ; 313.52,12.74 JSD1.13 ; JSD1.13 313.52,13.46 ; JSD1.13 315.78,13.46 ; JSD1.13 315.78,14.19 ; JSD1.13 314.65,12.74 ; JSD1.13 315.78,12.74 ; JSD1.13 314.65,14.19 ; JSD1.13 313.52,14.19 ; 314.93,96.37 JLOM1.10 ; JLOM1.10 317.67,95.03 ; JLOM1.10 316.3,96.37 ; JLOM1.10 317.67,95.7 ; JLOM1.10 316.3,95.03 ; JLOM1.10 314.93,95.7 ; JLOM1.10 317.67,96.37 ; JLOM1.10 314.93,95.03 ; 6.05,102.1 JUSBC1.6 ; JUSBC1.6 6.77,102.1 ; JUSBC1.6 6.05,104.11 ; JUSBC1.6 6.77,104.11 ; JUSBC1.6 5.33,102.1 ; JUSBC1.6 5.33,104.11 ; H7.1 270.86,120 ; H7.1 268.82,122.03 ; H7.1 267.34,118.51 ; H7.1 268.82,117.97 ; H7.1 270.31,121.49 ; H7.1 267.34,121.49 ; H7.1 270.31,118.51 ; H7.1 266.79,120 ; 1.6,102.05 JUSBC1.3 ; JUSBC1.3 1.6,103.71 ; JUSBC1.3 3.07,102.05 ; JUSBC1.3 3.07,102.88 ; JUSBC1.3 3.07,103.71 ; H13.1 186.05,110.52 ; H13.1 181.86,112.29 ; H13.1 183.62,108.09 ; H13.1 183.62,112.95 ; H13.1 185.39,112.29 ; H13.1 181.2,110.52 ; H13.1 181.86,108.75 ; H13.1 185.39,108.75 ; 307.3,76.92 JHDMI1.21 ; JHDMI1.21 308.88,76.92 ; JHDMI1.21 305.72,76.92 ; JHDMI1.21 307.3,78.88 ; JHDMI1.21 305.72,77.9 ; JHDMI1.21 305.72,78.88 ; 5.32,111.52 JUSBC1.2 ; JUSBC1.2 7.98,111.52 ; JUSBC1.2 7.98,110.74 ; JUSBC1.2 5.32,112.29 ; JUSBC1.2 7.98,112.29 ; JUSBC1.2 6.65,112.29 ; 301.96,72.8 JUSB1.13 ; JUSB1.13 304.7,71.97 ; JUSB1.13 301.96,73.63 ; JUSB1.13 304.7,72.8 ; JUSB1.13 304.7,73.63 ; JUSB1.13 303.33,73.63 ; JUSB1.13 301.96,71.97 ; JUSB1.13 303.33,71.97 ; H19.1 151.72,131.08 ; H19.1 153.81,129 ; H19.1 149.64,129 ; H19.1 151.72,126.92 ; H19.1 153.25,130.52 ; H19.1 150.2,130.52 ; H19.1 153.25,127.48 ; H19.1 150.2,127.48 ; H10.1 119.41,129 ; H10.1 117.32,131.08 ; H10.1 115.8,127.48 ; H10.1 117.32,126.92 ; H10.1 115.8,130.52 ; H10.1 115.24,129 ; H10.1 118.85,127.48 ; H10.1 118.85,130.52 ; H20.1 315.03,5.93 ; H20.1 313.09,4 ; H20.1 316.44,2.58 ; H20.1 313.61,5.42 ; H20.1 316.96,4 ; H20.1 316.44,5.42 ; H20.1 313.61,2.58 ; H20.1 315.03,2.07 ; JUSBC1.5 6.77,112.3 ; JUSBC1.5 5.33,112.3 ; JUSBC1.5 5.33,111.19 ; JUSBC1.5 5.33,110.29 ; JUSBC1.5 6.77,110.29 ; JUSBC1.5 6.05,112.3 ; JUSBC1.5 6.05,110.29 ; H18.1 301.03,78.93 ; H18.1 298.6,76.5 ; H18.1 299.26,74.73 ; H18.1 301.03,74.07 ; H18.1 302.79,74.73 ; H18.1 303.45,76.5 ; H18.1 302.79,78.27 ; H18.1 299.26,78.27 ; 117.86,112.29 H4.1 ; H4.1 122.05,110.52 ; H4.1 119.62,108.09 ; H4.1 121.39,112.29 ; H4.1 119.62,112.95 ; H4.1 117.86,108.75 ; H4.1 117.2,110.52 ; H4.1 121.39,108.75 ; JUSB2.11 8.54,98.4 ; JUSB2.11 7.17,99.23 ; JUSB2.11 5.8,99.23 ; JUSB2.11 8.54,99.23 ; JUSB2.11 5.8,98.4 ; JUSB1.12 313.25,74.93 ; JUSB1.12 310.51,74.93 ; JUSB1.12 311.88,74.93 ; JUSB1.12 313.25,74.1 ; JUSB1.12 310.51,74.1 ; 247.83,134.02 H30.1 ; H30.1 248.28,132.75 ; H30.1 250.83,135.29 ; H30.1 249.56,135.75 ; H30.1 251.28,134.02 ; H30.1 249.56,132.29 ; H30.1 248.28,135.29 ; H30.1 250.83,132.75 ; JUSBC1.1 3.07,112.35 ; JUSBC1.1 1.6,110.69 ; JUSBC1.1 3.07,110.69 ; JUSBC1.1 3.07,111.52 ; JUSBC1.1 1.6,112.35 ; 316.72,27.06 JSD1.12 ; JSD1.12 316.72,27.79 ; JSD1.12 317.85,27.79 ; JSD1.12 317.85,26.34
  VCC w0.203: JUSB2.10 15.72,97.93 ; JUSB2.10 14.35,96.27 ; JUSB2.10 14.35,97.93 ; JUSB2.10 17.09,97.1 ; JUSB2.10 17.09,97.93 ; JUSB2.10 15.72,96.27 ; JUSB2.10 17.09,96.27 ; JUSB2.10 14.35,97.1 ; 301.03,74.07 H18.1 ; H18.1 298.6,76.5 ; H18.1 302.79,78.27 ; H18.1 299.26,74.73 ; H18.1 302.79,74.73 ; H18.1 301.03,78.93 ; H18.1 299.26,78.27 ; H18.1 303.45,76.5 ; 267.34,118.51 H7.1 ; H7.1 270.31,118.51 ; H7.1 266.79,120 ; H7.1 270.86,120 ; H7.1 267.34,121.49 ; H7.1 268.82,122.03 ; H7.1 270.31,121.49 ; H7.1 268.82,117.97 ; 310.51,41.5 JUSB3.11 313.25,41.5 ; JUSB2.13 17.09,85.13 ; JUSB2.13 14.35,84.3 ; JUSB2.13 14.35,85.13 ; JUSB2.13 15.72,83.47 ; JUSB2.13 17.09,84.3 ; JUSB2.13 15.72,85.13 ; JUSB2.13 14.35,83.47 ; JUSB2.13 17.09,83.47 ; 305.05,26.34 JSD1.11 ; JSD1.11 305.05,27.79 ; JSD1.11 303.92,27.06 ; JSD1.11 303.92,27.79 ; JSD1.11 306.18,27.06 ; JSD1.11 306.18,26.34 ; JSD1.11 303.92,26.34 ; JSD1.11 306.18,27.79 ; 5.33,110.29 JUSBC1.5 ; JUSBC1.5 5.33,112.3 ; JUSBC1.5 5.33,111.19 ; JUSBC1.5 6.77,112.3 ; JUSBC1.5 6.05,112.3 ; JUSBC1.3 1.6,103.71 ; JUSBC1.3 1.6,102.05 ; JUSBC1.3 3.07,102.88 ; JUSBC1.3 3.07,103.71 ; JUSBC1.3 3.07,102.05 ; 314.93,96.37 JLOM1.10 ; JLOM1.10 317.67,96.37 ; JLOM1.10 317.67,95.7 ; JLOM1.10 314.93,95.7 ; JLOM1.10 316.3,96.37 ; JLOM1.10 317.67,95.03 ; JLOM1.10 314.93,95.03 ; JLOM1.10 316.3,95.03 ; 1.3,79.5 H23.1 ; H23.1 1.75,80.77 ; H23.1 4.3,78.23 ; H23.1 3.02,77.77 ; H23.1 1.75,78.23 ; H23.1 4.3,80.77 ; H23.1 3.02,81.23 ; H23.1 4.75,79.5 ; H3.1 186.05,85.52 ; H3.1 183.62,83.09 ; H3.1 185.39,87.29 ; H3.1 181.86,83.75 ; H3.1 181.86,87.29 ; H3.1 183.62,87.95 ; H3.1 181.2,85.52 ; H3.1 185.39,83.75 ; H15.1 303.61,120 ; H15.1 303.05,121.52 ; H15.1 300,118.48 ; H15.1 301.52,117.92 ; H15.1 301.52,122.08 ; H15.1 299.44,120 ; H15.1 300,121.52 ; H15.1 303.05,118.48 ; JUSB1.13 304.7,72.8 ; JUSB1.13 304.7,73.63 ; JUSB1.13 301.96,73.63 ; JUSB1.13 303.33,71.97 ; JUSB1.13 303.33,73.63 ; JUSB1.13 304.7,71.97 ; JUSB1.13 301.96,72.8 ; JUSB1.13 301.96,71.97 ; JUSBC1.2 7.98,112.29 ; JUSBC1.2 5.32,112.29 ; JUSBC1.2 6.65,112.29 ; JUSBC1.2 5.32,111.52 ; JUSBC1.2 7.98,111.52 ; JUSBC1.2 7.98,110.74 ; H20.1 316.44,5.42 ; H20.1 315.03,2.07 ; H20.1 313.61,2.58 ; H20.1 315.03,5.93 ; H20.1 313.09,4 ; H20.1 316.44,2.58 ; H20.1 313.61,5.42 ; H20.1 316.96,4 ; JUSB3.7 305.03,49.8 ; JUSB3.7 303.83,48.6 ; JUSB3.7 304.43,48.42 ; JUSB3.7 303.83,49.8 ; JUSB3.7 303.65,49.2 ; JUSB3.7 305.03,48.6 ; JUSB3.7 304.43,49.98 ; 303.33,59.17 JUSB1.10 ; JUSB1.10 304.7,60.83 ; JUSB1.10 303.33,60.83 ; JUSB1.10 304.7,60 ; JUSB1.10 304.7,59.17 ; JUSB1.10 301.96,60 ; JUSB1.10 301.96,59.17 ; JUSB1.10 301.96,60.83 ; 289.26,118.73 H12.1 ; H12.1 291.02,118.07 ; H12.1 291.02,122.93 ; H12.1 288.6,120.5 ; H12.1 292.79,118.73 ; H12.1 289.26,122.27 ; H12.1 292.79,122.27 ; H12.1 293.45,120.5 ; 310.51,74.93 JUSB1.12 ; JUSB1.12 311.88,74.93 ; JUSB1.12 313.25,74.1 ; JUSB1.12 313.25,74.93 ; JUSB1.12 310.51,74.1 ; JUSB2.12 8.54,82.17 ; JUSB2.12 5.8,82.17 ; JUSB2.12 5.8,83 ; JUSB2.12 7.17,82.17 ; JUSB2.12 8.54,83 ; JUSB3.10 303.33,43.63 ; JUSB3.10 301.96,41.97 ; JUSB3.10 304.7,42.8 ; JUSB3.10 304.7,41.97 ; JUSB3.10 301.96,42.8 ; JUSB3.10 304.7,43.63 ; JUSB3.10 303.33,41.97 ; JUSB3.10 301.96,43.63 ; 1.6,110.69 JUSBC1.1 ; JUSBC1.1 1.6,112.35 ; JUSBC1.1 3.07,110.69 ; JUSBC1.1 3.07,112.35 ; JUSBC1.1 3.07,111.52 ; H17.1 17.2,111.13 ; H17.1 17.2,113.67 ; H17.1 14.65,111.13 ; H17.1 14.65,113.67 ; H17.1 14.2,112.4 ; H17.1 15.93,114.13 ; H17.1 15.93,110.67 ; H17.1 17.65,112.4 ; 303.65,66.4 JUSB1.7 ; JUSB1.7 303.83,65.8 ; JUSB1.7 305.03,67 ; JUSB1.7 303.83,67 ; JUSB1.7 305.03,65.8 ; JUSB1.7 304.43,65.62 ; JUSB1.7 304.43,67.18 ; JUSB2.7 14.62,91.48 ; JUSB2.7 15.22,90.1 ; JUSB2.7 15.22,91.3 ; JUSB2.7 14.02,90.1 ; JUSB2.7 15.39,90.7 ; JUSB2.7 14.62,89.92 ; JUSB2.7 14.02,91.3 ; 302.93,51.92 JUSB3.4 ; JUSB3.4 303.71,52.7 ; JUSB3.4 302.15,52.7 ; JUSB3.4 303.53,53.3 ; JUSB3.4 302.33,53.3 ; JUSB3.4 302.33,52.1 ; JUSB3.4 302.93,53.48 ; JUSB3.4 303.53,52.1 ; 312.02,76.4 JHDMI1.23 ; JHDMI1.23 312.02,75.42 ; JHDMI1.23 315.18,75.42 ; JHDMI1.23 315.18,76.4 ; JHDMI1.23 313.6,75.42 ; 119.62,108.09 H4.1 ; H4.1 121.39,108.75 ; H4.1 119.62,112.95 ; H4.1 117.2,110.52 ; H4.1 122.05,110.52 ; H4.1 121.39,112.29 ; H4.1 117.86,108.75 ; H4.1 117.86,112.29 ; 305.72,92.4 JHDMI1.20 ; JHDMI1.20 305.72,93.38 ; JHDMI1.20 307.3,91.42 ; JHDMI1.20 308.88,93.38 ; JHDMI1.20 305.72,91.42 ; JHDMI1.20 307.3,93.38 ; 302.33,70.5 JUSB1.4 ; JUSB1.4 302.33,69.3 ; JUSB1.4 303.71,69.9 ; JUSB1.4 303.53,69.3 ; JUSB1.4 302.93,69.12 ; JUSB1.4 303.53,70.5 ; JUSB1.4 302.15,69.9 ; JUSB1.4 302.93,70.67 ; JLOM1.9 310.87,96.37 ; JLOM1.9 308.13,95.03 ; JLOM1.9 308.13,96.37 ; JLOM1.9 309.5,95.03 ; JLOM1.9 310.87,95.03 ; JLOM1.9 309.5,96.37 ; JLOM1.9 310.87,95.7 ; JLOM1.9 308.13,95.7 ; JUSB3.13 303.33,56.43 ; JUSB3.13 301.96,56.43 ; JUSB3.13 301.96,54.77 ; JUSB3.13 304.7,54.77 ; JUSB3.13 301.96,55.6 ; JUSB3.13 304.7,55.6 ; JUSB3.13 303.33,54.77 ; JUSB3.13 304.7,56.43 ; 306.99,84.19 JHDMI1.11 ; JHDMI1.11 306.88,84.65 ; JHDMI1.11 307.91,84.19 ; JHDMI1.11 307.91,85.1 ; JHDMI1.11 306.99,85.1 ; JHDMI1.11 308.02,84.65 ; JHDMI1.21 308.88,76.92 ; JHDMI1.21 307.3,76.92 ; JHDMI1.21 305.72,78.88 ; JHDMI1.21 307.3,78.88 ; JHDMI1.21 305.72,76.92 ; JHDMI1.21 305.72,77.9 ; JSD1.13 315.78,14.19 ; JSD1.13 314.65,12.74 ; JSD1.13 313.52,13.46 ; JSD1.13 313.52,12.74 ; JSD1.13 313.52,14.19 ; JSD1.13 315.78,12.74 ; JSD1.13 315.78,13.46 ; JSD1.13 314.65,14.19 ; 306.99,81.19 JHDMI1.17 ; JHDMI1.17 306.88,81.65 ; JHDMI1.17 306.99,82.1 ; JHDMI1.17 307.91,81.19 ; JHDMI1.17 307.91,82.1 ; JHDMI1.17 308.02,81.65 ; JUSB2.4 16.72,87.8 ; JUSB2.4 15.34,87.2 ; JUSB2.4 16.72,86.6 ; JUSB2.4 15.52,87.8 ; JUSB2.4 15.52,86.6 ; JUSB2.4 16.12,87.98 ; JUSB2.4 16.12,86.42 ; JUSB2.4 16.9,87.2 ; JLOM1.12 309.5,112.67 ; JLOM1.12 310.87,112 ; JLOM1.12 310.87,111.33 ; JLOM1.12 309.5,111.33 ; JLOM1.12 308.13,111.33 ; JLOM1.12 308.13,112 ; JLOM1.12 308.13,112.67 ; JLOM1.12 310.87,112.67 ; 305.33,86.15 JHDMI1.8 ; JHDMI1.8 305.44,86.6 ; JHDMI1.8 306.36,86.6 ; JHDMI1.8 306.36,85.69 ; JHDMI1.8 305.44,85.69 ; JHDMI1.8 306.47,86.15 ; JUSB2.11 7.17,99.23 ; JUSB2.11 8.54,99.23 ; JUSB2.11 5.8,99.23 ; JUSB2.11 5.8,98.4 ; JUSB2.11 8.54,98.4 ; 310.51,57.87 JUSB1.11 ; JUSB1.11 310.51,58.7 ; JUSB1.11 311.88,57.87 ; JUSB1.11 313.25,57.87 ; JUSB1.11 313.25,58.7 ; JHDMI1.2 306.36,89.6 ; JHDMI1.2 305.44,89.6 ; JHDMI1.2 305.44,88.69 ; JHDMI1.2 306.47,89.15 ; JHDMI1.2 305.9,89.72 ; JHDMI1.2 306.36,88.69 ; JHDMI1.2 305.33,89.15 ; JLOM1.11 317.67,112 ; JLOM1.11 314.93,112 ; JLOM1.11 316.3,112.67 ; JLOM1.11 316.3,111.33 ; JLOM1.11 317.67,112.67 ; JLOM1.11 317.67,111.33 ; JLOM1.11 314.93,111.33 ; JLOM1.11 314.93,112.67 ; JUSB3.12 313.25,57.73 ; JUSB3.12 313.25,56.9 ; JUSB3.12 310.51,57.73 ; JUSB3.12 310.51,56.9 ; JUSB3.12 311.88,57.73 ; JHDMI1.22 315.18,94.88 ; JHDMI1.22 315.18,93.9 ; JHDMI1.22 312.02,93.9 ; JHDMI1.22 313.6,94.88 ; JHDMI1.22 312.02,94.88 ; 306.99,88.1 JHDMI1.5 ; JHDMI1.5 306.88,87.65 ; JHDMI1.5 306.99,87.19 ; JHDMI1.5 307.91,87.19 ; JHDMI1.5 307.91,88.1 ; JHDMI1.5 308.02,87.65 ; 5.32,102.1 JUSBC1.4 ; JUSBC1.4 5.32,102.88 ; JUSBC1.4 6.65,102.1 ; JUSBC1.4 7.98,102.1 ; JUSBC1.4 7.98,102.88 ; 5.33,102.1 JUSBC1.6 ; JUSBC1.6 6.05,102.1 ; JUSBC1.6 6.77,102.1 ; JUSBC1.6 5.33,104.11 ; 317.85,26.34 JSD1.12 ; JSD1.12 316.72,27.79 ; JSD1.12 316.72,27.06 ; JSD1.12 317.85,27.79
  GND2 w0.203: JHDMI1.11 307.91,85.1 ; JHDMI1.11 306.99,85.1 ; JHDMI1.11 306.99,84.19 ; JHDMI1.11 306.88,84.65 ; JHDMI1.11 308.02,84.65 ; JHDMI1.11 307.91,84.19 ; 310.51,74.93 JUSB1.12 ; JUSB1.12 311.88,74.93 ; JUSB1.12 313.25,74.93 ; JUSB1.12 310.51,74.1 ; JUSB1.12 313.25,74.1 ; JSD1.10 306.18,14.19 ; JSD1.10 306.18,13.46 ; JSD1.10 306.18,12.74 ; JSD1.10 303.92,14.19 ; JSD1.10 305.05,12.74 ; JSD1.10 303.92,12.74 ; JSD1.10 305.05,14.19 ; JSD1.10 303.92,13.46 ; JHDMI1.21 308.88,76.92 ; JHDMI1.21 305.72,78.88 ; JHDMI1.21 305.72,77.9 ; JHDMI1.21 307.3,78.88 ; JHDMI1.21 305.72,76.92 ; JHDMI1.21 307.3,76.92 ; 256.76,28.27 H11.1 ; H11.1 258.53,24.07 ; H11.1 260.29,24.73 ; H11.1 260.95,26.5 ; H11.1 260.29,28.27 ; H11.1 256.1,26.5 ; H11.1 258.53,28.93 ; H11.1 256.76,24.73 ; JUSB1.13 303.33,73.63 ; JUSB1.13 304.7,72.8 ; JUSB1.13 301.96,71.97 ; JUSB1.13 303.33,71.97 ; JUSB1.13 301.96,73.63 ; JUSB1.13 304.7,71.97 ; JUSB1.13 304.7,73.63 ; JUSB1.13 301.96,72.8 ; H1.1 119.62,87.95 ; H1.1 119.62,83.09 ; H1.1 122.05,85.52 ; H1.1 117.86,83.75 ; H1.1 121.39,83.75 ; H1.1 117.86,87.29 ; H1.1 121.39,87.29 ; H1.1 117.2,85.52 ; JUSB2.10 17.09,96.27 ; JUSB2.10 15.72,97.93 ; JUSB2.10 17.09,97.1 ; JUSB2.10 14.35,97.93 ; JUSB2.10 14.35,96.27 ; JUSB2.10 17.09,97.93 ; JUSB2.10 15.72,96.27 ; JUSB2.10 14.35,97.1 ; 266.79,120 H7.1 ; H7.1 268.82,117.97 ; H7.1 270.31,118.51 ; H7.1 267.34,118.51 ; H7.1 268.82,122.03 ; H7.1 270.31,121.49 ; H7.1 267.34,121.49 ; H7.1 270.86,120 ; 302.33,53.3 JUSB3.4 ; JUSB3.4 302.15,52.7 ; JUSB3.4 303.53,52.1 ; JUSB3.4 302.93,53.48 ; JUSB3.4 303.71,52.7 ; JUSB3.4 302.93,51.92 ; JUSB3.4 303.53,53.3 ; JUSB3.4 302.33,52.1 ; 303.83,65.8 JUSB1.7 ; JUSB1.7 304.43,65.62 ; JUSB1.7 303.83,67 ; JUSB1.7 304.43,67.18 ; JUSB1.7 303.65,66.4 ; JUSB1.7 305.03,65.8 ; JUSB1.7 305.03,67 ; 5.32,111.52 JUSBC1.2 ; JUSBC1.2 7.98,111.52 ; JUSBC1.2 5.32,112.29 ; JUSBC1.2 7.98,110.74 ; JUSBC1.2 6.65,112.29 ; JUSBC1.2 7.98,112.29 ; H15.1 303.05,121.52 ; H15.1 299.44,120 ; H15.1 301.52,117.92 ; H15.1 303.05,118.48 ; H15.1 303.61,120 ; H15.1 300,121.52 ; H15.1 300,118.48 ; H15.1 301.52,122.08 ; 181.86,83.75 H3.1 ; H3.1 185.39,87.29 ; H3.1 185.39,83.75 ; H3.1 181.86,87.29 ; H3.1 186.05,85.52 ; H3.1 183.62,83.09 ; H3.1 183.62,87.95 ; H3.1 181.2,85.52 ; 149.64,129 H19.1 ; H19.1 150.2,130.52 ; H19.1 151.72,131.08 ; H19.1 153.25,127.48 ; H19.1 150.2,127.48 ; H19.1 151.72,126.92 ; H19.1 153.81,129 ; H19.1 153.25,130.52 ; JUSB3.13 304.7,54.77 ; JUSB3.13 304.7,56.43 ; JUSB3.13 301.96,56.43 ; JUSB3.13 301.96,55.6 ; JUSB3.13 303.33,56.43 ; JUSB3.13 303.33,54.77 ; JUSB3.13 301.96,54.77 ; JUSB3.13 304.7,55.6 ; JUSB3.10 303.33,43.63 ; JUSB3.10 301.96,43.63 ; JUSB3.10 301.96,42.8 ; JUSB3.10 304.7,42.8 ; JUSB3.10 303.33,41.97 ; JUSB3.10 301.96,41.97 ; JUSB3.10 304.7,41.97 ; JUSB3.10 304.7,43.63 ; JUSB2.12 8.54,82.17 ; JUSB2.12 5.8,83 ; JUSB2.12 8.54,83 ; JUSB2.12 7.17,82.17 ; JUSB2.12 5.8,82.17 ; 303.92,27.79 JSD1.11 ; JSD1.11 306.18,26.34 ; JSD1.11 303.92,26.34 ; JSD1.11 303.92,27.06 ; JSD1.11 306.18,27.06 ; JSD1.11 305.05,26.34 ; JSD1.11 306.18,27.79 ; JSD1.11 305.05,27.79 ; 305.72,91.42 JHDMI1.20 ; JHDMI1.20 308.88,93.38 ; JHDMI1.20 307.3,93.38 ; JHDMI1.20 305.72,92.4 ; JHDMI1.20 305.72,93.38 ; JHDMI1.20 307.3,91.42 ; JUSB3.7 304.43,49.98 ; JUSB3.7 303.83,48.6 ; JUSB3.7 305.03,48.6 ; JUSB3.7 303.83,49.8 ; JUSB3.7 304.43,48.42 ; JUSB3.7 303.65,49.2 ; JUSB3.7 305.03,49.8 ; 313.09,4 H20.1 ; H20.1 315.03,5.93 ; H20.1 315.03,2.07 ; H20.1 316.44,2.58 ; H20.1 313.61,5.42 ; H20.1 316.96,4 ; H20.1 313.61,2.58 ; H20.1 316.44,5.42 ; JHDMI1.23 315.18,75.42 ; JHDMI1.23 312.02,75.42 ; JHDMI1.23 313.6,75.42 ; JHDMI1.23 315.18,76.4 ; JHDMI1.23 312.02,76.4 ; JUSB1.4 303.53,70.5 ; JUSB1.4 302.33,70.5 ; JUSB1.4 302.93,69.12 ; JUSB1.4 302.33,69.3 ; JUSB1.4 303.71,69.9 ; JUSB1.4 302.15,69.9 ; JUSB1.4 303.53,69.3 ; JUSB1.4 302.93,70.67 ; 305.33,86.15 JHDMI1.8 ; JHDMI1.8 306.47,86.15 ; JHDMI1.8 305.44,85.69 ; JHDMI1.8 306.36,85.69 ; JHDMI1.8 305.44,86.6 ; JHDMI1.8 306.36,86.6 ; JUSB2.13 17.09,84.3 ; JUSB2.13 15.72,83.47 ; JUSB2.13 14.35,85.13 ; JUSB2.13 17.09,85.13 ; JUSB2.13 14.35,84.3 ; JUSB2.13 17.09,83.47 ; JUSB2.13 14.35,83.47 ; JUSB2.13 15.72,85.13 ; 314.93,112.67 JLOM1.11 ; JLOM1.11 316.3,112.67 ; JLOM1.11 317.67,111.33 ; JLOM1.11 316.3,111.33 ; JLOM1.11 314.93,112 ; JLOM1.11 317.67,112.67 ; JLOM1.11 317.67,112 ; JLOM1.11 314.93,111.33 ; H35.1 245.29,76.77 ; H35.1 241.1,75 ; H35.1 243.52,77.43 ; H35.1 241.76,76.77 ; H35.1 245.29,73.23 ; H35.1 241.76,73.23 ; H35.1 245.95,75 ; H35.1 243.52,72.57 ; JUSB2.7 15.22,90.1 ; JUSB2.7 15.22,91.3 ; JUSB2.7 14.02,90.1 ; JUSB2.7 14.02,91.3 ; JUSB2.7 15.39,90.7 ; JUSB2.7 14.62,91.48 ; JUSB2.7 14.62,89.92 ; 306.99,82.1 JHDMI1.17 ; JHDMI1.17 307.91,82.1 ; JHDMI1.17 306.99,81.19 ; JHDMI1.17 308.02,81.65 ; JHDMI1.17 307.91,81.19 ; JHDMI1.17 306.88,81.65 ; H30.1 249.56,135.75 ; H30.1 248.28,132.75 ; H30.1 248.28,135.29 ; H30.1 247.83,134.02 ; H30.1 249.56,132.29 ; H30.1 251.28,134.02 ; H30.1 250.83,132.75 ; H30.1 250.83,135.29 ; H12.1 293.45,120.5 ; H12.1 292.79,122.27 ; H12.1 288.6,120.5 ; H12.1 291.02,118.07 ; H12.1 292.79,118.73 ; H12.1 289.26,122.27 ; H12.1 291.02,122.93 ; H12.1 289.26,118.73 ; H18.1 302.79,74.73 ; H18.1 303.45,76.5 ; H18.1 299.26,78.27 ; H18.1 299.26,74.73 ; H18.1 298.6,76.5 ; H18.1 301.03,74.07 ; H18.1 302.79,78.27 ; H18.1 301.03,78.93 ; JLOM1.10 316.3,96.37 ; JLOM1.10 317.67,95.03 ; JLOM1.10 314.93,96.37 ; JLOM1.10 317.67,96.37 ; JLOM1.10 317.67,95.7 ; JLOM1.10 314.93,95.7 ; JLOM1.10 314.93,95.03 ; JLOM1.10 316.3,95.03 ; JUSBC1.5 6.77,112.3 ; JUSBC1.5 5.33,111.19 ; JUSBC1.5 6.05,110.29 ; JUSBC1.5 5.33,112.3 ; JUSBC1.5 6.05,112.3 ; JUSBC1.5 5.33,110.29 ; JUSBC1.5 6.77,110.29 ; JSD1.13 315.78,14.19 ; JSD1.13 313.52,13.46 ; JSD1.13 314.65,14.19 ; JSD1.13 314.65,12.74 ; JSD1.13 315.78,12.74 ; JSD1.13 313.52,14.19 ; JSD1.13 313.52,12.74 ; JSD1.13 315.78,13.46 ; 119.62,108.09 H4.1 ; H4.1 117.86,112.29 ; H4.1 121.39,108.75 ; H4.1 119.62,112.95 ; H4.1 117.2,110.52 ; H4.1 121.39,112.29 ; H4.1 122.05,110.52 ; H4.1 117.86,108.75 ; 115.24,129 H10.1 ; H10.1 117.32,131.08 ; H10.1 117.32,126.92 ; H10.1 118.85,130.52 ; H10.1 115.8,127.48 ; H10.1 118.85,127.48 ; H10.1 119.41,129 ; H10.1 115.8,130.52 ; JUSB2.11 8.54,98.4 ; JUSB2.11 7.17,99.23 ; JUSB2.11 8.54,99.23 ; JUSB2.11 5.8,98.4 ; JUSB2.11 5.8,99.23 ; 279.92,67.05 H8.1 ; H8.1 283.44,68.54 ; H8.1 281.95,69.08 ; H8.1 280.46,68.54 ; H8.1 283.44,65.56 ; H8.1 280.46,65.56 ; H8.1 283.98,67.05 ; H8.1 281.95,65.02 ; JUSB2.4 16.12,87.98 ; JUSB2.4 15.52,86.6 ; JUSB2.4 15.34,87.2 ; JUSB2.4 16.12,86.42 ; JUSB2.4 16.9,87.2 ; JUSB2.4 16.72,87.8 ; JUSB2.4 15.52,87.8 ; JUSB2.4 16.72,86.6 ; 306.99,87.19 JHDMI1.5 ; JHDMI1.5 306.99,88.1 ; JHDMI1.5 308.02,87.65 ; JHDMI1.5 307.91,88.1 ; JHDMI1.5 306.88,87.65 ; JHDMI1.5 307.91,87.19 ; JUSBC1.3 3.07,102.88 ; JUSBC1.3 3.07,103.71 ; JUSBC1.3 1.6,103.71 ; JUSBC1.3 3.07,102.05 ; JUSBC1.3 1.6,102.05 ; 157.19,136 H2.1 ; H2.1 161.23,137.7 ; H2.1 157.82,134.3 ; H2.1 161.23,134.3 ; H2.1 157.82,137.7 ; H2.1 159.52,138.34 ; H2.1 159.52,133.66 ; H2.1 161.86,136 ; 310.51,57.87 JUSB1.11 ; JUSB1.11 313.25,57.87 ; JUSB1.11 313.25,58.7 ; JUSB1.11 311.88,57.87 ; JUSB1.11 310.51,58.7 ; JHDMI1.22 315.18,93.9 ; JHDMI1.22 315.18,94.88 ; JHDMI1.22 313.6,94.88 ; JHDMI1.22 312.02,93.9 ; JHDMI1.22 312.02,94.88 ; JUSB1.10 304.7,59.17 ; JUSB1.10 301.96,59.17 ; JUSB1.10 301.96,60.83 ; JUSB1.10 301.96,60 ; JUSB1.10 304.7,60 ; JUSB1.10 303.33,59.17 ; JUSB1.10 304.7,60.83 ; JUSB1.10 303.33,60.83 ; 1.75,80.77 H23.1 ; H23.1 1.3,79.5 ; H23.1 1.75,78.23 ; H23.1 3.02,81.23 ; H23.1 4.3,80.77 ; H23.1 4.3,78.23 ; H23.1 4.75,79.5 ; H23.1 3.02,77.77 ; H16.1 70.8,132.73 ; H16.1 71.25,134 ; H16.1 69.52,135.73 ; H16.1 70.8,135.27 ; H16.1 68.25,135.27 ; H16.1 68.25,132.73 ; H16.1 67.8,134 ; H16.1 69.52,132.27 ; JLOM1.12 310.87,112 ; JLOM1.12 310.87,111.33 ; JLOM1.12 310.87,112.67 ; JLOM1.12 308.13,111.33 ; JLOM1.12 308.13,112.67 ; JLOM1.12 308.13,112 ; JLOM1.12 309.5,111.33 ; JLOM1.12 309.5,112.67 ; JUSBC1.4 7.98,102.88 ; JUSBC1.4 7.98,102.1 ; JUSBC1.4 5.32,102.1 ; JUSBC1.4 7.98,103.65 ; JUSBC1.4 5.32,102.88 ; JUSBC1.4 6.65,102.1 ; JUSBC1.6 6.77,102.1 ; JUSBC1.6 6.05,102.1 ; JUSBC1.6 6.05,104.11 ; JUSBC1.6 6.77,104.11 ; JUSBC1.6 5.33,102.1 ; JUSBC1.6 5.33,104.11 ; JUSB3.12 313.25,57.73 ; JUSB3.12 310.51,57.73 ; JUSB3.12 311.88,57.73 ; JUSB3.12 313.25,56.9 ; JUSB3.12 310.51,56.9 ; 313.25,41.5 JUSB3.11 310.51,41.5 ; 14.65,111.13 H17.1 ; H17.1 14.2,112.4 ; H17.1 17.65,112.4 ; H17.1 17.2,113.67 ; H17.1 15.93,110.67 ; H17.1 17.2,111.13 ; H17.1 15.93,114.13 ; H17.1 14.65,113.67 ; JHDMI1.2 306.36,89.6 ; JHDMI1.2 306.36,88.69 ; JHDMI1.2 305.33,89.15 ; JHDMI1.2 305.9,89.72 ; JHDMI1.2 306.47,89.15 ; JHDMI1.2 305.44,88.69 ; JHDMI1.2 305.44,89.6 ; 309.5,95.03 JLOM1.9 ; JLOM1.9 310.87,95.03 ; JLOM1.9 310.87,96.37 ; JLOM1.9 310.87,95.7 ; JLOM1.9 309.5,96.37 ; JLOM1.9 308.13,95.7 ; JLOM1.9 308.13,95.03 ; JLOM1.9 308.13,96.37 ; 183.62,108.09 H13.1 ; H13.1 181.2,110.52 ; H13.1 181.86,108.75 ; H13.1 181.86,112.29 ; H13.1 183.62,112.95 ; H13.1 186.05,110.52 ; H13.1 185.39,112.29 ; H13.1 185.39,108.75 ; 316.72,27.79 JSD1.12 ; JSD1.12 316.72,27.06 ; JSD1.12 317.85,27.79 ; JSD1.12 317.85,26.34 ; JUSBC1.1 1.6,112.35 ; JUSBC1.1 3.07,112.35 ; JUSBC1.1 1.6,110.69 ; JUSBC1.1 3.07,111.52 ; JUSBC1.1 3.07,110.69
  GND3 w0.203: 312.02,76.4 JHDMI1.23 ; JHDMI1.23 313.6,75.42 ; JHDMI1.23 315.18,76.4 ; JHDMI1.23 315.18,75.42 ; JHDMI1.23 312.02,75.42 ; 306.99,82.1 JHDMI1.17 ; JHDMI1.17 307.91,81.19 ; JHDMI1.17 306.99,81.19 ; JHDMI1.17 307.91,82.1 ; JHDMI1.17 306.88,81.65 ; JHDMI1.17 308.02,81.65 ; JUSB2.7 15.22,90.1 ; JUSB2.7 15.39,90.7 ; JUSB2.7 14.62,89.92 ; JUSB2.7 14.02,90.1 ; JUSB2.7 14.02,91.3 ; JUSB2.7 15.22,91.3 ; JUSB2.7 14.62,91.48 ; JLOM1.10 317.67,95.03 ; JLOM1.10 317.67,96.37 ; JLOM1.10 314.93,95.03 ; JLOM1.10 316.3,95.03 ; JLOM1.10 314.93,95.7 ; JLOM1.10 317.67,95.7 ; JLOM1.10 316.3,96.37 ; JLOM1.10 314.93,96.37 ; JHDMI1.2 306.36,88.69 ; JHDMI1.2 305.44,88.69 ; JHDMI1.2 305.44,89.6 ; JHDMI1.2 306.36,89.6 ; JHDMI1.2 305.9,89.72 ; JHDMI1.2 306.47,89.15 ; JHDMI1.2 305.33,89.15 ; 289.26,118.73 H12.1 ; H12.1 291.02,118.07 ; H12.1 291.02,122.93 ; H12.1 292.79,118.73 ; H12.1 289.26,122.27 ; H12.1 292.79,122.27 ; H12.1 288.6,120.5 ; H12.1 293.45,120.5 ; JHDMI1.5 308.02,87.65 ; JHDMI1.5 307.91,87.19 ; JHDMI1.5 306.88,87.65 ; JHDMI1.5 306.99,87.19 ; JHDMI1.5 307.91,88.1 ; JHDMI1.5 306.99,88.1 ; H23.1 4.3,80.77 ; H23.1 4.3,78.23 ; H23.1 1.3,79.5 ; H23.1 4.75,79.5 ; H23.1 3.02,81.23 ; H23.1 1.75,78.23 ; H23.1 3.02,77.77 ; H23.1 1.75,80.77 ; JUSB1.12 311.88,74.93 ; JUSB1.12 313.25,74.1 ; JUSB1.12 310.51,74.93 ; JUSB1.12 313.25,74.93 ; JUSB1.12 310.51,74.1 ; 302.33,69.3 JUSB1.4 ; JUSB1.4 303.53,70.5 ; JUSB1.4 302.93,69.12 ; JUSB1.4 302.15,69.9 ; JUSB1.4 303.71,69.9 ; JUSB1.4 302.33,70.5 ; JUSB1.4 302.93,70.67 ; JUSB1.4 303.53,69.3 ; JUSB2.10 17.09,97.1 ; JUSB2.10 15.72,96.27 ; JUSB2.10 15.72,97.93 ; JUSB2.10 14.35,96.27 ; JUSB2.10 17.09,97.93 ; JUSB2.10 14.35,97.1 ; JUSB2.10 14.35,97.93 ; JUSB2.10 17.09,96.27 ; JSD1.12 317.85,27.79 ; JSD1.12 316.72,27.79 ; JSD1.12 317.85,26.34 ; JSD1.12 316.72,27.06 ; JUSB3.4 303.53,53.3 ; JUSB3.4 303.71,52.7 ; JUSB3.4 302.33,53.3 ; JUSB3.4 302.93,51.92 ; JUSB3.4 302.15,52.7 ; JUSB3.4 303.53,52.1 ; JUSB3.4 302.33,52.1 ; JUSB3.4 302.93,53.48 ; 181.86,83.75 H3.1 ; H3.1 183.62,87.95 ; H3.1 185.39,87.29 ; H3.1 186.05,85.52 ; H3.1 181.86,87.29 ; H3.1 183.62,83.09 ; H3.1 181.2,85.52 ; H3.1 185.39,83.75 ; 248.28,132.75 H30.1 ; H30.1 248.28,135.29 ; H30.1 249.56,132.29 ; H30.1 249.56,135.75 ; H30.1 247.83,134.02 ; H30.1 250.83,132.75 ; H30.1 250.83,135.29 ; H30.1 251.28,134.02 ; 1.6,110.69 JUSBC1.1 ; JUSBC1.1 3.07,111.52 ; JUSBC1.1 3.07,112.35 ; JUSBC1.1 3.07,110.69 ; JUSBC1.1 1.6,112.35 ; JUSB3.13 304.7,56.43 ; JUSB3.13 303.33,54.77 ; JUSB3.13 301.96,55.6 ; JUSB3.13 304.7,55.6 ; JUSB3.13 301.96,54.77 ; JUSB3.13 303.33,56.43 ; JUSB3.13 301.96,56.43 ; JUSB3.13 304.7,54.77 ; 5.33,104.11 JUSBC1.6 ; JUSBC1.6 6.77,102.1 ; JUSBC1.6 5.33,102.1 ; JUSBC1.6 6.05,102.1 ; JUSBC1.6 6.05,104.11 ; JUSBC1.6 6.77,104.11 ; 279.92,67.05 H8.1 ; H8.1 283.44,65.56 ; H8.1 281.95,65.02 ; H8.1 283.98,67.05 ; H8.1 283.44,68.54 ; H8.1 281.95,69.08 ; H8.1 280.46,68.54 ; H8.1 280.46,65.56 ; H7.1 270.31,118.51 ; H7.1 267.34,121.49 ; H7.1 270.31,121.49 ; H7.1 266.79,120 ; H7.1 267.34,118.51 ; H7.1 270.86,120 ; H7.1 268.82,122.03 ; H7.1 268.82,117.97 ; JUSBC1.2 7.98,112.29 ; JUSBC1.2 5.32,112.29 ; JUSBC1.2 5.32,111.52 ; JUSBC1.2 7.98,111.52 ; JUSBC1.2 6.65,112.29 ; JUSBC1.2 7.98,110.74 ; JUSB1.13 304.7,73.63 ; JUSB1.13 304.7,72.8 ; JUSB1.13 301.96,72.8 ; JUSB1.13 303.33,71.97 ; JUSB1.13 301.96,71.97 ; JUSB1.13 303.33,73.63 ; JUSB1.13 304.7,71.97 ; JUSB1.13 301.96,73.63 ; 310.51,41.5 JUSB3.11 313.25,41.5 ; 300,121.52 H15.1 ; H15.1 303.61,120 ; H15.1 303.05,118.48 ; H15.1 299.44,120 ; H15.1 301.52,117.92 ; H15.1 303.05,121.52 ; H15.1 300,118.48 ; H15.1 301.52,122.08 ; 6.65,102.1 JUSBC1.4 ; JUSBC1.4 5.32,102.88 ; JUSBC1.4 7.98,102.1 ; JUSBC1.4 7.98,102.88 ; JUSBC1.4 5.32,102.1 ; JUSBC1.4 7.98,103.65 ; JHDMI1.11 307.91,85.1 ; JHDMI1.11 308.02,84.65 ; JHDMI1.11 306.99,85.1 ; JHDMI1.11 307.91,84.19 ; JHDMI1.11 306.88,84.65 ; JHDMI1.11 306.99,84.19 ; 303.33,59.17 JUSB1.10 ; JUSB1.10 304.7,60.83 ; JUSB1.10 304.7,59.17 ; JUSB1.10 301.96,59.17 ; JUSB1.10 301.96,60 ; JUSB1.10 303.33,60.83 ; JUSB1.10 301.96,60.83 ; JUSB1.10 304.7,60 ; 303.92,26.34 JSD1.11 ; JSD1.11 303.92,27.79 ; JSD1.11 306.18,27.79 ; JSD1.11 305.05,27.79 ; JSD1.11 306.18,27.06 ; JSD1.11 303.92,27.06 ; JSD1.11 305.05,26.34 ; JSD1.11 306.18,26.34 ; JUSB1.7 305.03,65.8 ; JUSB1.7 304.43,65.62 ; JUSB1.7 303.83,65.8 ; JUSB1.7 303.65,66.4 ; JUSB1.7 303.83,67 ; JUSB1.7 305.03,67 ; JUSB1.7 304.43,67.18 ; H17.1 17.65,112.4 ; H17.1 17.2,113.67 ; H17.1 17.2,111.13 ; H17.1 14.65,111.13 ; H17.1 15.93,114.13 ; H17.1 14.2,112.4 ; H17.1 14.65,113.67 ; H17.1 15.93,110.67 ; 150.2,127.48 H19.1 ; H19.1 153.25,127.48 ; H19.1 151.72,126.92 ; H19.1 150.2,130.52 ; H19.1 153.81,129 ; H19.1 153.25,130.52 ; H19.1 149.64,129 ; H19.1 151.72,131.08 ; 115.8,127.48 H10.1 ; H10.1 115.8,130.52 ; H10.1 117.32,131.08 ; H10.1 117.32,126.92 ; H10.1 115.24,129 ; H10.1 118.85,127.48 ; H10.1 118.85,130.52 ; H10.1 119.41,129 ; 5.8,82.17 JUSB2.12 ; JUSB2.12 5.8,83 ; JUSB2.12 7.17,82.17 ; JUSB2.12 8.54,82.17 ; JUSB2.12 8.54,83 ; 258.53,24.07 H11.1 ; H11.1 256.1,26.5 ; H11.1 260.29,28.27 ; H11.1 260.95,26.5 ; H11.1 256.76,28.27 ; H11.1 256.76,24.73 ; H11.1 260.29,24.73 ; H11.1 258.53,28.93 ; JUSB3.7 305.03,49.8 ; JUSB3.7 303.83,49.8 ; JUSB3.7 305.03,48.6 ; JUSB3.7 303.65,49.2 ; JUSB3.7 303.83,48.6 ; JUSB3.7 304.43,49.98 ; JUSB3.7 304.43,48.42 ; JLOM1.9 310.87,95.7 ; JLOM1.9 310.87,96.37 ; JLOM1.9 308.13,96.37 ; JLOM1.9 308.13,95.03 ; JLOM1.9 308.13,95.7 ; JLOM1.9 309.5,95.03 ; JLOM1.9 309.5,96.37 ; JLOM1.9 310.87,95.03 ; JUSB2.4 16.12,87.98 ; JUSB2.4 15.52,87.8 ; JUSB2.4 16.12,86.42 ; JUSB2.4 15.52,86.6 ; JUSB2.4 15.34,87.2 ; JUSB2.4 16.72,86.6 ; JUSB2.4 16.9,87.2 ; JUSB2.4 16.72,87.8 ; JLOM1.12 309.5,112.67 ; JLOM1.12 309.5,111.33 ; JLOM1.12 308.13,111.33 ; JLOM1.12 310.87,112 ; JLOM1.12 310.87,112.67 ; JLOM1.12 310.87,111.33 ; JLOM1.12 308.13,112 ; JLOM1.12 308.13,112.67 ; H1.1 121.39,83.75 ; H1.1 121.39,87.29 ; H1.1 117.2,85.52 ; H1.1 119.62,87.95 ; H1.1 117.86,83.75 ; H1.1 119.62,83.09 ; H1.1 122.05,85.52 ; H1.1 117.86,87.29 ; H16.1 69.52,135.73 ; H16.1 70.8,135.27 ; H16.1 67.8,134 ; H16.1 68.25,132.73 ; H16.1 68.25,135.27 ; H16.1 71.25,134 ; H16.1 69.52,132.27 ; H16.1 70.8,132.73 ; JLOM1.11 317.67,112 ; JLOM1.11 317.67,111.33 ; JLOM1.11 317.67,112.67 ; JLOM1.11 314.93,112 ; JLOM1.11 314.93,111.33 ; JLOM1.11 316.3,112.67 ; JLOM1.11 314.93,112.67 ; JLOM1.11 316.3,111.33 ; H2.1 159.52,138.34 ; H2.1 157.19,136 ; H2.1 161.23,137.7 ; H2.1 161.86,136 ; H2.1 157.82,134.3 ; H2.1 157.82,137.7 ; H2.1 159.52,133.66 ; H2.1 161.23,134.3 ; H20.1 316.96,4 ; H20.1 315.03,5.93 ; H20.1 316.44,2.58 ; H20.1 313.61,2.58 ; H20.1 313.09,4 ; H20.1 316.44,5.42 ; H20.1 313.61,5.42 ; H20.1 315.03,2.07 ; JUSBC1.3 3.07,102.88 ; JUSBC1.3 3.07,103.71 ; JUSBC1.3 3.07,102.05 ; JUSBC1.3 1.6,103.71 ; JUSBC1.3 1.6,102.05 ; 15.72,83.47 JUSB2.13 ; JUSB2.13 17.09,84.3 ; JUSB2.13 14.35,84.3 ; JUSB2.13 17.09,85.13 ; JUSB2.13 14.35,85.13 ; JUSB2.13 17.09,83.47 ; JUSB2.13 15.72,85.13 ; JUSB2.13 14.35,83.47 ; JHDMI1.8 306.36,85.69 ; JHDMI1.8 305.44,85.69 ; JHDMI1.8 306.36,86.6 ; JHDMI1.8 305.44,86.6 ; JHDMI1.8 305.33,86.15 ; JHDMI1.8 306.47,86.15 ; 310.51,56.9 JUSB3.12 ; JUSB3.12 313.25,56.9 ; JUSB3.12 311.88,57.73 ; JUSB3.12 313.25,57.73 ; JUSB3.12 310.51,57.73 ; JSD1.10 306.18,12.74 ; JSD1.10 306.18,14.19 ; JSD1.10 303.92,13.46 ; JSD1.10 303.92,14.19 ; JSD1.10 305.05,12.74 ; JSD1.10 306.18,13.46 ; JSD1.10 303.92,12.74 ; JSD1.10 305.05,14.19 ; JUSB3.10 304.7,43.63 ; JUSB3.10 301.96,42.8 ; JUSB3.10 303.33,41.97 ; JUSB3.10 304.7,42.8 ; JUSB3.10 304.7,41.97 ; JUSB3.10 301.96,41.97 ; JUSB3.10 303.33,43.63 ; JUSB3.10 301.96,43.63 ; H13.1 185.39,112.29 ; H13.1 181.86,108.75 ; H13.1 183.62,108.09 ; H13.1 186.05,110.52 ; H13.1 181.86,112.29 ; H13.1 183.62,112.95 ; H13.1 181.2,110.52 ; H13.1 185.39,108.75 ; 241.76,76.77 H35.1 ; H35.1 241.76,73.23 ; H35.1 241.1,75 ; H35.1 243.52,77.43 ; H35.1 245.29,73.23 ; H35.1 243.52,72.57 ; H35.1 245.95,75 ; H35.1 245.29,76.77 ; JHDMI1.22 315.18,93.9 ; JHDMI1.22 312.02,93.9 ; JHDMI1.22 312.02,94.88 ; JHDMI1.22 313.6,94.88 ; JHDMI1.22 315.18,94.88 ; 5.8,99.23 JUSB2.11 ; JUSB2.11 7.17,99.23 ; JUSB2.11 5.8,98.4 ; JUSB2.11 8.54,98.4 ; JUSB2.11 8.54,99.23 ; 313.52,12.74 JSD1.13 ; JSD1.13 313.52,14.19 ; JSD1.13 314.65,12.74 ; JSD1.13 314.65,14.19 ; JSD1.13 315.78,12.74 ; JSD1.13 315.78,13.46 ; JSD1.13 313.52,13.46 ; JSD1.13 315.78,14.19 ; 305.72,76.92 JHDMI1.21 ; JHDMI1.21 305.72,77.9 ; JHDMI1.21 307.3,76.92 ; JHDMI1.21 305.72,78.88 ; JHDMI1.21 308.88,76.92 ; JHDMI1.21 307.3,78.88 ; H4.1 119.62,112.95 ; H4.1 117.86,108.75 ; H4.1 121.39,108.75 ; H4.1 119.62,108.09 ; H4.1 117.2,110.52 ; H4.1 117.86,112.29 ; H4.1 121.39,112.29 ; H4.1 122.05,110.52 ; 305.72,93.38 JHDMI1.20 ; JHDMI1.20 307.3,91.42 ; JHDMI1.20 305.72,91.42 ; JHDMI1.20 307.3,93.38 ; JHDMI1.20 305.72,92.4 ; JHDMI1.20 308.88,93.38 ; 5.33,111.19 JUSBC1.5 ; JUSBC1.5 6.77,110.29 ; JUSBC1.5 6.05,112.3 ; JUSBC1.5 6.77,112.3 ; JUSBC1.5 5.33,112.3 ; JUSBC1.5 5.33,110.29 ; JUSBC1.5 6.05,110.29 ; 310.51,58.7 JUSB1.11 ; JUSB1.11 313.25,58.7 ; JUSB1.11 311.88,57.87 ; JUSB1.11 313.25,57.87 ; JUSB1.11 310.51,57.87 ; H18.1 302.79,78.27 ; H18.1 303.45,76.5 ; H18.1 299.26,74.73 ; H18.1 299.26,78.27 ; H18.1 301.03,74.07 ; H18.1 298.6,76.5 ; H18.1 302.79,74.73 ; H18.1 301.03,78.93
  BOTTOM w0.076: UC1.F25 170.6,101.04 v2(170.28,101.36)
  BOTTOM w0.089: 220.28,97.04 219.71,96.48 219.01,96.48 218.79,96.69 218.58,96.69 UH1.V4 218.25,97.02 217.8,97.02 217.64,96.86 217.64,96.8 217.51,96.68 217.07,96.68 216.96,96.57 216.17,96.57 216.12,96.52 216.05,96.52 ; 216.14,95.51 216.38,95.75 216.38,95.9 216.48,96 216.8,96 216.98,95.81 217.97,95.81 UH1.T4 ; UH1.AR12 222.25,104.86 222.25,104.21 UH1.AN12 ; 221.96,86.28 221.96,88.98 222.17,89.19 UH1.C12 ; 210.08,103.59 v2(210.08,103.59)
  BOTTOM w0.099: v2(218.82,94.31) 217.1,94.31 217.04,94.24
  BOTTOM w0.102: v2(196.14,78.56) 196.12,78.56 194.05,76.49 183.5,76.49 178.37,71.36 129.76,71.36 125.43,75.68 125.43,83.25 124.5,84.18 124.5,86.1 124.46,86.14 124.46,86.62 124.33,86.75 123.99,86.75 v2(123.9,86.84) ; v2(197.61,78.62) 197.48,78.62 194.85,75.99 183.73,75.99 178.58,70.84 129.28,70.84 124.8,75.32 124.8,83.23 123.87,84.17 v2(123.87,85.67) ; v2(125.69,86.15) 126.12,85.72 126.12,83.43 126.12,75.97 130.02,72.07 178.06,72.07 183.17,77.18 193.22,77.18 193.99,77.94 v2(193.99,78.56) ; 222.04,85.02 222.57,85.55 222.57,88.11 222.64,88.18 222.64,88.48 222.49,88.63 222.49,89.59 UH1.D12 ; 221.96,86.28 221.64,85.96 ; UH1.D8 220.21,89.68 220.21,89.03 220.23,89 220.23,88.66 220.21,88.64 220.21,88.46 220.17,88.42 UH1.A8 ; v2(123.25,87.76) 123.25,87.63 123.63,87.25 124.58,87.25 124.68,87.15 124.68,86.25 124.73,86.21 124.73,84.27 125.66,83.34 125.66,75.78 129.85,71.59 178.27,71.59 183.4,76.72 193.73,76.72 196.08,79.07 200.35,79.07 200.75,78.67 200.75,78.52 v2(200.73,78.51) ; v2(124.06,82.39) 124.26,82.19 124.26,74.58 128.24,70.61 178.68,70.61 183.81,75.74 196.56,75.74 198.98,78.15 v2(198.98,78.53) ; v2(224.09,71.38) 224.53,71.38 226.72,73.57 236.7,73.57 240.34,69.93 246.86,69.93 246.96,70.03 246.96,73.89 248.29,75.21 248.43,75.21 248.53,75.11 v2(248.53,75) ; v2(196.85,78.56) 196.85,78.43 194.68,76.26 183.59,76.26 178.46,71.13 129.66,71.13 125.2,75.59 125.2,82.19 125.03,82.37 125.03,83.33 124.27,84.08 124.27,86.01 124.02,86.26 v2(123.96,86.26) ; v2(123.6,82.03) 123.69,81.94 123.69,74.83 128.14,70.38 178.77,70.38 183.9,75.51 197.02,75.51 199.56,78.05 v2(199.56,78.56) ; v2(200.15,78.54) 200.15,78.05 197.38,75.28 184,75.28 178.87,70.15 128.05,70.15 123.38,74.82 123.38,81.52 123.27,81.62 v2(123.19,81.62) ; v2(123.84,87.76) 123.91,87.76 123.92,87.77 124.39,87.77 124.91,87.24 124.91,86.35 124.96,86.3 124.96,84.37 125.89,83.44 125.89,75.87 129.95,71.82 178.16,71.82 183.3,76.95 193.63,76.95 195.98,79.3 200.59,79.3 201.31,78.58 v2(201.31,78.53)
  BOTTOM w0.127: v4(210.5,126.92) v2(210.5,126.29) ; v2(238.55,91.89) 237.81,91.89 237.6,91.68 UH1.G44 ; v2(238.55,91.89) UH1.J47 ; v2(238.55,91.89) 238.53,91.92 UH1.J46 ; CH45.2 211.88,91.39 212.48,90.79 213.65,90.79 213.98,91.13 213.98,92.78 215.29,94.08 216.87,94.08 217.04,94.24 ; v2(215.83,95.13) 215.83,95.2 216.14,95.51 ; v2(213.86,36.38) 215.12,36.38 v4(215.39,36.65) ; v2(130.91,86.95) 131.36,86.95 131.44,87.03 131.78,87.03 131.92,87.17 131.99,87.17 132.35,87.53 132.89,87.53 UC1.BT8 ; v4(55.88,107.45) 56.77,106.56 v2(57.16,106.56) ; v2(135.33,120.55) v4(134.69,120.55) ; v4(199,103.02) 199,102.32 v2(199,102.31) ; v2(186.24,100.91) 186.22,100.89 v4(185.5,100.89) ; 222.04,85.02 221.73,84.72 221.27,84.72 220.9,84.35 v2(220.9,83.11) 220.9,82.51 219.41,81.02 216.17,81.02 216.02,81.17 216.02,82.69 216.21,82.88 217.47,82.88 218.04,82.31 218.82,82.31 219.64,83.13 219.64,84.65 220.33,85.34 v2(220.33,85.91) 220.44,85.8 221.48,85.8 221.64,85.96 ; UT1.A22 UT1.B22 ; v2(174.24,31.57) v4(174.24,30.8) ; v2(292.08,75.72) v4(291.49,75.72) ; v2(221.29,97.08) 221.25,97.04 220.28,97.04 ; v4(259.27,48.13) v2(259.27,47.49) ; 216.05,96.52 215.48,96.52 v2(214.87,97.13)
  BOTTOM w0.152: v2(234.71,104.43) 234.71,104.39 234.91,104.18 UH1.AN38 ; UH1.J48 239.42,92.36 UH1.J47 ; v2(222.34,103.45) 222.34,103.68 UH1.AN12 ; UC1.BH5 UC1.BH4 UC1.BH3 UC1.BH2 ; v2(224.27,113.15) 224.61,112.82 224.61,110.97 UH1.BG17 ; UH1.AE4 218.41,99.86 v2(218.5,99.77) ; UH1.A8 220.17,88.25 220.19,88.23 220.19,87.62 219.41,86.83 219.02,86.83 218.88,86.69 v2(218.88,86.68) ; v2(215.34,105.85) 215.38,105.81 215.48,105.81 215.55,105.74 UH1.AT1 ; 224.98,100.03 UH1.AD19 224.98,99.25 ; v2(228.08,97.71) v2(227.31,97.71) v2(226.53,97.71) UH1.AA20 ; v2(228.08,97.71) UH1.AA25 228.54,98.09 v2(228.89,97.74) ; v2(228.08,97.71) UH1.W25 v2(228.89,97.74) ; UH1.E40 235.72,90.01 v2(236.19,90.01) ; UC1.AC5 158.21,85.69 158.22,85.68 158.22,85.35 158.21,85.34 UC1.AC4 UC1.AC3 UC1.AC2 158.21,83.83 158.2,83.82 158.21,83.69 UC1.AC1 v2(157.83,82.84) ; UC1.AE6 156.12,86.06 156.12,85.6 UC1.AF4 UC1.AF3 UC1.AF2 UC1.AF1 v2(155.69,82.67) ; UH1.AT18 225.06,105.71 224.85,105.71 v2(224.71,105.57) 224.56,105.74 224.3,105.75 UH1.AT16 UH1.AR16 UH1.AN16 ; 224.73,97.91 UH1.Y17 ; UH1.Y17 224.16,97.91 ; UH1.Y17 224.16,97.34 ; UH1.Y17 224.73,97.34 ; UH1.AJ25 228.86,101.58 ; UH1.AJ25 228.08,101.58 ; UH1.AJ25 228.47,102.02 v2(228.78,102.33) ; UH1.AJ25 228.08,102.35 UH1.AK25 228.47,102.65 v2(228.78,102.33) ; 228.86,101.58 UH1.AG27 229.63,101.58 ; 228.86,101.58 UH1.AJ27 ; 228.86,101.58 UH1.AG25 ; v2(238.6,98.52) 238.53,98.59 UH1.AC46 ; UH1.A37 234.6,88.33 234.81,88.53 235.58,88.53 235.88,88.23 v2(235.88,87.88) ; UH1.J29 231.1,92.22 v2(231.2,92.12) ; v2(229.55,102.37) 229.92,102.74 UH1.AK28 230.02,102.72 v2(230.36,102.37) ; v2(229.55,102.37) 229.62,102.37 UH1.AJ28 ; v2(229.55,102.37) 229.55,102.43 UH1.AK27 229.19,102.74 v2(228.78,102.33) ; v2(160.28,84.19) 160.28,84.17 160.63,84.52 UC1.W3 ; 231.18,101.58 UH1.AJ31 v2(231.18,102.35) ; 231.18,101.58 UH1.AJ30 ; 231.18,101.58 UH1.AG30 230.41,101.58 ; UC1.W3 UC1.W4 UC1.W5 ; UC1.W3 UC1.W2 160.72,83.87 160.72,83.74 160.72,83.52 UC1.W1 160.72,82.6 v2(160.28,82.24) ; UT1.B20 37.37,103.24 UT1.A20 v2(36.41,103.24) ; UH1.BC26 229.22,109.38 v2(229.59,109.38) ; UH1.AL38 234.89,103.24 v2(235.08,103.42) ; UH1.AK20 225.76,103.13 UH1.AK19 ; UH1.AK20 v2(225.76,102.35) ; UH1.AK20 226.53,102.35 UH1.AJ20 ; v2(232.25,105.59) 232.22,105.56 UH1.AT32 ; v2(232.25,105.59) 232.28,105.56 UH1.AT34 ; v2(232.25,105.59) 232.81,105.02 232.82,105.02 UH1.AR34 UH1.AN34 ; UH1.N38 234.91,94 v2(235.19,93.73) 235.47,93.45 235.47,92.81 235.55,92.73 UH1.K39 235.73,92.48 UH1.J40 ; UH1.M32 232.11,93.72 232.28,93.9 v2(232.38,93.9) 232.38,93.9 232.45,93.9 232.82,94.27 UH1.N34 UH1.R34 232.82,95.74 232.79,95.77 ; UH1.T17 224.66,96.06 UH1.U17 ; UH1.P46 v2(238.53,94.2) ; v2(230.37,97.74) 230.72,98.09 UH1.AA30 v2(231.18,98.48) ; v2(230.37,97.74) 230.02,97.39 UH1.W28 ; v2(230.37,97.74) UH1.AA28 ; v2(230.37,97.74) UH1.W30 ; UH1.AJ20 UH1.AG22 226.53,100.8 UH1.AF22 226.53,100.03 UH1.AD22 ; UH1.AJ20 v2(225.76,102.35) ; UH1.AJ20 225.76,101.58 UH1.AJ19 ; v2(219.74,95.29) 220.25,95.29 220.53,95.58 221.79,95.58 222.02,95.81 ; v2(219.74,95.29) 219.74,95.71 UH1.T7 219.79,95.84 UH1.T5 218.39,95.62 UH1.T4 218.16,95.39 UH1.R4 ; v2(219.74,95.29) 219.78,95.25 219.78,95.25 219.78,94.63 219.54,94.39 219,94.39 218.92,94.31 v2(218.82,94.31) ; UT1.B18 UT1.A18 v2(36.41,104.16) ; UH1.J26 229.32,92.02 v2(229.55,92.02) ; v2(231.65,86.22) 232.34,86.92 UH1.A33 ; UC1.N5 UC1.N4 UC1.N3 ; v2(229.59,88.33) UH1.A28 ; UH1.AC12 222.14,98.65 v2(222.02,98.53) ; UH1.W27 229.24,97.39 v2(228.89,97.74) ; UH1.AA20 v2(225.76,98.48) ; UH1.AA20 v2(226.53,98.48) ; v2(225.76,98.48) UH1.AB19 ; v2(225.76,98.48) UH1.AA19 ; UH1.AM49 240.56,103.52 240.94,103.9 v2(241.02,103.9) ; UH1.R16 UH1.N16 UH1.M16 224.44,94.02 224.58,94.02 v2(224.58,94.03) 224.91,94.03 UH1.M18 ; UH1.AW46 238.45,106.89 238.45,107.11 238.6,107.26 v2(238.68,107.26) 238.68,107.31 238.6,107.38 238.6,107.4 238.57,107.36 238.32,107.36 237.84,107.84 UH1.BA44 ; UT1.AC2 UT1.AB2 UT1.AB1 UT1.AC1 ; UH1.AJ19 224.98,101.58 ; UH1.AJ19 v2(225.76,102.35) ; UH1.AJ19 224.98,102.35 UH1.AK19 ; v2(227.43,94.12) 227.59,94.12 UH1.M24 ; v2(213.58,101.61) 213.87,101.32 UH1.AG1 ; UH1.AT24 227.53,105.83 227.43,105.83 v2(227.43,105.83) ; UH1.R29 230.32,95.19 v2(230.03,95.19) ; UH1.BA14 v2(222.47,107.78) ; UH1.AJ28 230.41,101.58 ; UH1.AJ28 230.02,102.03 v2(230.36,102.37) ; UH1.AJ28 229.63,101.58 ; 230.41,101.58 UH1.AG28 229.63,101.58 ; 230.41,101.58 UH1.AJ30 ; UC1.BB6 143.19,86.4 143.19,85.89 UC1.BB5 143.12,85.7 143.13,85.68 143.13,85.3 143.12,85.29 UC1.BB4 143.12,85.05 143.13,85.03 143.13,84.65 143.12,84.64 UC1.BB3 143.15,84.49 143.15,83.9 UC1.BB2 143.12,83.73 143.12,83.72 143.12,83.36 143.12,83.35 UC1.BB1 143.12,83.08 143.16,83.03 143.16,82.68 142.77,82.28 v2(142.77,82.28) ; v2(221.99,106.12) 221.99,106.18 221.56,106.62 UH1.AV11 UH1.AW10 ; UT1.AC6 UT1.AB6 ; UH1.AH33 232.5,102.11 v2(232.56,102.18) 232.6,102.22 UH1.AL33 ; v2(226.31,114.09) 226.6,113.8 226.6,111.27 226.79,111.08 UH1.BG22 ; v2(218.82,94.31) 218.65,93.67 UH1.M5 ; v2(218.82,94.31) 218.46,94.67 UH1.P4 UH1.R4 ; v2(215.14,99.55) 215.23,99.64 UH1.AD1 UH1.AD2 ; v2(233.99,90.01) 233.52,90.01 UH1.E35 ; v2(232.79,113.44) 232.53,113.19 232.53,111.15 UH1.BG33 ; 228.08,101.58 UH1.AG25 ; 228.08,101.58 UH1.AG23 227.69,101.17 v2(228.09,100.77) ; UC1.K3 UC1.K2 UC1.K1 ; UC1.K3 168.27,84.64 168.28,84.65 168.28,85.03 168.27,85.05 UC1.K4 ; UC1.K3 168.19,84.52 167.82,84.15 v2(167.82,84.13) ; UH1.N35 233.57,94.02 v2(233.57,93.64) UH1.M34 ; UH1.R12 222.02,94.81 v2(222.01,94.8) ; v2(228.78,102.33) 229.15,101.97 UH1.AJ27 ; UC1.AJ6 UC1.AJ5 UC1.AJ4 UC1.AJ3 ; UH1.BC31 231.32,109.28 231.74,109.28 v2(231.8,109.34) ; UC1.BN4 135.22,85.43 135.53,85.74 UC1.BM5 ; v2(162.83,82.4) 162.83,82.4 163.24,82.81 163.24,83.12 163.24,83.12 UC1.T1 UC1.T2 UC1.T3 ; UT1.A12 UT1.B12 ; UT1.U22 UT1.U23 ; 222.02,95.81 222.05,95.84 UH1.U12 221.99,96.38 v2(221.29,97.08) UH1.Y10 ; 222.02,95.81 v2(222.02,95.78) ; v2(225.97,105.19) 226.32,105.54 UH1.AT21 ; UC1.BT3 v2(132.62,84.32) ; v2(222.47,98.09) 222.47,98.03 UH1.Y12 ; v2(225.76,102.35) UH1.AK19 ; UT1.AC8 46.57,108.76 UT1.AB8 ; UH1.AC33 v2(232.51,98.52) ; UT1.H1 UT1.H2 ; v2(237.56,108.9) UH1.BC45 ; v2(237.56,108.9) UH1.BD43 237.45,109.7 UH1.BE44 ; v2(237.56,108.9) UH1.BB43 ; v2(148.17,82.47) 148.17,83.19 UC1.AR1 UC1.AR2 UC1.AR3 ; UT1.E22 UT1.E23 38.75,101.56 ; v2(235.3,102.06) 235.28,102.06 UH1.AH38 ; v2(227.39,109.37) 227.56,109.2 UH1.BC24 ; UH1.BB41 v2(236.19,109.28) 235.72,109.28 UH1.BC40 ; UH1.T49 240.28,96.11 240.61,96.44 v2(240.79,96.44) ; v2(234.87,97.08) UH1.Y38 ; UT1.J23 UT1.J22 ; UH1.AG49 240.37,101.23 241.27,101.23 241.43,101.08 v2(241.43,101.07) ; UH1.AT29 230.54,105.49 231.02,105.49 v2(231.04,105.51) ; v2(228.89,97.74) UH1.AA27 v2(228.91,98.48) UH1.AB25 228.08,99.25 UH1.AD25 228.08,100.03 UH1.AF25 228.44,100.42 v2(228.09,100.77) ; UC1.T3 163.12,84.52 v2(162.79,84.21) ; UC1.T3 UC1.T4 UC1.T5 ; 229.63,101.58 UH1.AJ27 ; UH1.AA49 240.66,97.96 240.78,97.84 v2(240.78,97.84) ; UH1.D30 230.74,89.62 UH1.C30 ; UT1.AB12 46.57,106.92 UT1.AC12 ; UH1.R4 218.73,95.17 v2(218.83,95.07) ; UH1.R4 UH1.R3 ; v2(36.91,101.1) 37.21,101.1 37.83,101.72 UT1.C23 UT1.C22 UT1.B22 ; UH1.N37 234.29,94.2 v2(234.75,94.65) 234.75,94.68 234.91,94.85 UH1.R38 ; v2(238.6,100.77) 238.53,100.69 UH1.AE46 ; v2(231.18,98.48) UH1.AB31 ; v2(231.18,98.48) UH1.AA31 ; UC1.AJ3 152.85,84.19 v2(152.73,84.19) ; UC1.AJ3 UC1.AJ2 UC1.AJ1 v2(153.18,82.67) ; UH1.R26 v2(229.4,94.99) ; UT1.AC10 UT1.AB10 ; UH1.F43 UH1.E42 v2(236.19,90.01) ; UH1.AG25 228.47,101.15 v2(228.09,100.77) ; v2(165.76,82.49) 165.75,82.5 165.75,83.08 165.75,83.08 UC1.N1 UC1.N2 UC1.N3 ; UH1.AC38 v2(234.79,98.52) ; v2(231.18,102.35) UH1.AJ30 ; v2(231.18,102.35) UH1.AK30 230.73,102.74 v2(230.36,102.37) ; v2(231.18,102.35) UH1.AK31 ; UH1.AJ30 230.77,101.97 v2(230.36,102.37) ; UH1.AF28 229.63,100.03 ; UT1.A6 UT1.B6 ; UH1.P26 v2(228.7,94.92) ; UH1.AR38 234.91,105.37 235.06,105.52 v2(235.14,105.52) 235.18,105.56 235.18,106.16 235.3,106.28 235.3,106.37 UH1.AV39 235.73,106.8 UH1.AW40 ; UH1.AH12 222.07,102.02 v2(221.96,102.13) 222.04,102.21 222.04,102.23 222.05,102.24 UH1.AL12 ; UT1.AC22 46.57,102.32 UT1.AB22 ; UT1.K2 UT1.K1 ; UH1.AD49 241.27,99.64 241.36,99.55 v2(241.43,99.55) ; UT1.R23 UT1.R22 ; UT1.AC14 UT1.AB14 ; UH1.BB9 v2(220.75,109.28) ; v2(220.75,109.28) UH1.BC8 ; v2(220.75,109.28) 221.22,109.28 UH1.BC10 ; v2(36.41,106) UT1.A14 UT1.B14 ; v2(233.99,109.28) 233.52,109.28 UH1.BC35 ; UT1.L22 UT1.L23 ; UH1.P29 v2(229.96,94.58) ; UC1.N3 165.63,84.52 v2(165.31,84.19) ; v2(228.44,114.65) 228.44,114.59 228.53,114.5 228.53,111.72 228.47,111.65 UH1.BG25 ; UH1.C25 UH1.E26 229.12,90.01 v2(229.57,90.01) ; UH1.V22 v2(226.53,96.93) UH1.V20 ; v2(236.19,90.01) 236.31,90.33 236.32,90.39 UH1.F41 ; UH1.AM1 216.11,103.52 v2(215.97,103.66) ; 224.05,96.1 UH1.U17 ; UH1.U17 224.62,96.67 ; UH1.U17 UH1.U15 ; UH1.U17 224.05,96.67 ; v2(220.27,97.04) 220.28,97.04 220.55,97.32 UH1.Y9 ; UT1.AA22 UT1.AA23 ; v2(222.01,100.8) 222.14,100.67 UH1.AE12 ; UT1.T2 43.81,111.52 UT1.T1 ; UH1.AP4 218.41,104.62 218.71,104.32 218.71,103.82 218.88,103.64 218.88,103.6 218.92,103.57 218.92,103.31 218.74,103.14 218.57,102.96 v2(218.33,102.96) 218.41,102.89 UH1.AK4 ; UH1.N12 222.02,93.47 v2(222.12,93.37) 222.09,93.37 UH1.K11 UH1.J10 UH1.J9 UH1.H8 UH1.G6 219.11,91.44 218.75,91.8 218.75,92.04 v2(218.69,92.11) 218.69,92.19 218.41,92.47 UH1.J4 ; UH1.BC15 223.42,109.28 v2(222.95,109.28) UH1.BC13 ; UH1.AL17 224.34,102.3 v2(224.44,102.2) 224.44,102.2 UH1.AH17 ; v2(225.3,108.95) 225.3,108.99 225.51,109.2 UH1.BC19 ; UC1.BE3 140.61,84.39 140.62,84.38 140.62,84 140.61,83.99 UC1.BE2 UC1.BE1 140.61,82.7 v2(140.16,82.26) ; 224.73,101.37 UH1.AH17 ; UH1.AH17 224.16,101.37 ; v2(235.64,95.84) 235.19,95.84 234.89,96.14 UH1.U38 ; UH1.E10 221.22,90.01 v2(220.79,90.01) 220.76,90 UH1.E8 ; v2(230.73,117.93) 230.49,117.69 230.49,111.3 UH1.BG28 ; UT1.W23 UT1.W22 ; UT1.AB16 46.57,105.08 47.03,105.08 UT1.AC16 ; UH1.BG37 234.54,112.51 v2(234.41,112.64) ; UT1.B16 UT1.A16 v2(36.41,105.08) ; UT1.P1 UT1.P2 ; UT1.G23 UT1.G22 ; UH1.AT26 v2(229.59,105.47) ; UT1.AB20 UT1.AC20 ; UH1.AE33 v2(232.51,100.77) ; UH1.V46 v2(238.53,96.41) ; UT1.A8 UT1.B8 ; UT1.N22 UT1.N23 ; UH1.AE38 v2(234.79,100.77) ; UT1.M1 UT1.M2 ; UT1.AC18 UT1.AB18
  BOTTOM w0.203: UT5.B8 65.21,105.73 v2(65.03,105.91) ; UC1.BN12 135.2,90.45 135.5,90.16 135.5,90.09 ; UC1.BN12 135.12,90.4 135.05,90.4 135.04,90.39 134.66,90.39 134.65,90.4 134.58,90.4 UC1.BP12 134.4,90.45 134.37,90.43 134.03,90.43 134,90.45 UC1.BR12 UC1.BT12 ; UC1.BN12 135.17,90.5 135.48,90.8 v2(135.48,90.87) 135.83,91.21 UC1.BM13 ; UC1.A6 175.21,86.76 v2(175.39,86.94) ; UC1.BM3 135.7,84.8 135.7,84.28 UC1.BM2 135.49,83.87 UC1.BN2 ; v2(137.65,86.12) 137.95,85.82 UC1.BH5 138.09,85.91 138.13,85.95 138.13,86.33 138.09,86.37 UC1.BH6 ; v2(137.65,86.12) 138,86.47 UC1.BH6 ; v2(137.65,86.12) 137.55,86.12 137.25,86.42 UC1.BK6 UC1.BL6 ; UC1.C29 172.67,104.07 172.87,103.87 v2(172.87,103.7) ; v2(136.15,101.08) 135.83,101.41 UC1.BM26 ; UC1.AG10 155.11,89.45 v2(155.2,89.45) ; UC1.AU7 146.5,86.5 UC1.AU6 ; UC1.AU7 146.75,86.88 146.9,86.88 UC1.AT6 ; UC1.AU7 146.5,87.29 146.51,87.3 146.51,87.65 146.5,87.66 UC1.AU8 146.55,87.78 v2(146.96,88.18) ; UC1.A30 173.95,105.15 174.23,105.15 v2(174.32,105.07) ; UC1.F19 170.6,96.27 v2(170.28,96.59) 169.95,96.92 UC1.G20 ; v2(166.16,90.06) 165.85,90.38 UC1.N12 ; v2(166.16,90.06) 165.83,89.73 UC1.N11 ; v2(166.16,90.06) 166.48,90.38 UC1.M12 UC1.M13 ; UT5.E8 UT5.D8 65.03,106.21 v2(65.03,105.91) ; UT5.E8 65.58,106.88 v2(65.71,106.75) ; UT5.E8 UT5.E7 ; UT5.E8 UT5.F8 ; UC1.N5 165.79,85.86 165.79,86.43 UC1.N6 ; UC1.AY12 144.5,90.38 v2(144.22,90.09) 143.93,90.38 UC1.BA12 ; UC1.AY12 144.67,90.39 144.33,90.74 v2(144.22,90.74) 144.1,90.74 143.76,90.39 UC1.BA12 ; UC1.AY12 144.77,90.38 v2(145.14,90.75) 145.23,90.75 145.59,90.39 UC1.AW12 145.92,90.71 v2(146.07,90.71) 146.4,90.38 UC1.AU12 ; UC1.BA12 UC1.BA11 ; UC1.BA12 143.63,90.38 v2(143.3,90.7) 143.17,90.7 UC1.BB12 142.58,90.65 v2(142.39,90.65) ; UC1.L33 167.38,106.59 v2(167.71,106.91) 167.38,107.24 UC1.L34 ; UC1.T10 UC1.T11 ; UC1.T10 UC1.T9 ; UC1.T10 163.22,88.82 v2(163.43,88.82) 163.04,88.43 UC1.T9 ; UC1.T10 163.05,89.08 v2(163.42,89.45) 163.15,89.73 UC1.T11 ; UC1.T11 UC1.T12 ; v2(168.75,87.4) 169.04,87.11 UC1.J7 169.53,87.11 UC1.G8 UC1.F8 170.6,87.6 v2(170.93,87.93) ; UC1.AY33 144.55,106.59 v2(144.87,106.91) 144.54,107.24 UC1.AY34 ; UC1.Y10 UC1.Y11 160.39,89.73 160.49,89.63 160.5,89.63 v2(160.68,89.45) 160.31,89.08 UC1.Y10 ; UC1.Y10 UC1.Y9 UC1.Y8 UC1.Y7 159.97,86.88 159.56,86.88 159.45,86.77 159.35,86.77 UC1.AB6 UC1.AC6 158.21,86.35 158.22,86.33 158.22,85.95 158.21,85.94 UC1.AC5 ; v2(157,88.17) 157.26,88.43 UC1.AD9 ; UC1.AD12 UC1.AD11 UC1.AD10 ; UC1.A10 174.39,89.11 v2(174.43,89.07) ; UC1.BJ35 137.46,107.89 137.73,108.16 v2(137.79,108.16) 137.78,108.17 137.78,108.22 137.45,108.54 UC1.BJ36 ; UC1.BB3 143,84.52 142.9,84.42 142.9,84.42 v2(142.69,84.22) ; UC1.BH6 UC1.BG6 UC1.BF6 139.79,86.47 v2(140.15,86.11) 140.3,85.96 140.46,85.96 UC1.BE5 ; UC1.BH6 138.27,86.65 UC1.BH7 UC1.BH8 UC1.BH9 UC1.BH10 ; UH1.D33 232.49,90.07 UH1.E33 ; UC1.BA11 143.95,89.73 v2(144.22,89.45) ; UC1.BA11 UC1.BA10 ; UC1.BH2 137.84,83.61 UC1.BH1 137.84,82.66 138.05,82.45 v2(138.05,82.45) ; UT5.A6 64.21,104.41 v2(64.22,104.4) ; UT5.G7 UT5.G8 ; UT5.G7 UT5.G6 ; UT5.G7 UT5.F7 ; UT5.G8 65.58,107.88 65.69,107.99 v2(65.71,107.99) ; UT5.G8 UT5.F8 ; UT5.G8 UT5.H8 65.16,108.43 v2(65.16,108.94) ; UC1.K8 168.47,87.87 168.47,88.33 UC1.K9 168.47,88.52 168.47,88.98 UC1.K10 ; v2(154.28,90.69) 153.97,90.38 UC1.AH12 ; UC1.A20 v2(174.43,96.98) ; UC1.AM4 150.66,85.04 150.69,85.01 150.69,84.67 150.66,84.64 UC1.AM3 UC1.AM2 UC1.AM1 150.66,82.55 150.38,82.27 150.26,82.27 v2(150.18,82.34) ; UT5.E5 UT5.F5 ; UT5.E5 63.24,106.42 62.92,106.42 62.68,106.17 v2(62.72,106.17) ; UT5.E5 UT5.E6 ; UT5.F5 UT5.G5 ; UT5.F5 UT5.F6 ; v2(135.5,97.94) 135.83,97.61 UC1.BM21 ; UC1.F17 170.28,94.95 v2(170.28,95.02) 169.95,95.34 169.95,95.37 ; UC1.C27 172.55,102.64 172.35,102.84 172.31,102.84 v2(172.28,102.88) 172.21,102.95 172.21,102.97 172.16,103.01 172.16,103.02 172.15,103.03 172.15,103.03 UC1.D28 ; v2(146.95,90.74) 146.59,90.38 UC1.AU12 ; UC1.AD10 157.54,89.08 157.85,89.39 v2(157.94,89.39) ; UC1.AD10 UC1.AD9 ; UC1.BJ15 UC1.BK15 ; v2(141.47,88.18) 141.23,88.43 UC1.BD9 ; v2(141.47,88.18) 141.42,88.18 UC1.BD8 ; v2(141.47,88.18) 141.49,88.17 141.49,87.5 141.12,87.13 UC1.BD7 ; v2(146.96,88.18) 146.72,88.43 UC1.AU9 UC1.AU10 ; v2(146.96,88.18) v2(146.96,88.82) ; UC1.A9 UC1.B9 173.04,88.16 173.04,88.09 v2(172.88,87.93) ; UC1.N11 UC1.N10 UC1.N9 ; UC1.N11 UC1.N12 ; UC1.A34 173.86,107.68 174.24,107.68 v2(174.42,107.87) ; v2(172.88,87.93) 172.88,87.86 UC1.C8 172.5,87.47 172.5,87.45 172.41,87.36 UC1.D6 ; v2(172.88,87.93) 172.55,88.25 UC1.C9 172.15,88.72 ; UC1.AN5 149.78,86.42 UC1.AN6 ; UT5.G6 UT5.G5 ; UT5.G6 UT5.F6 ; UT5.F8 65.69,107.38 v2(65.72,107.41) ; UT5.F8 UT5.F7 ; UC1.BM28 135.83,102.98 v2(136.15,102.66) 136.15,102.59 UC1.BM27 ; UC1.BD7 UC1.BD8 ; UC1.BD7 141.02,86.73 141.03,86.72 ; v2(132.69,85.16) 132.79,85.16 132.86,85.24 UC1.BT4 ; v2(148.79,90.71) 148.65,90.71 UC1.AR13 148,90.7 v2(147.8,90.7) ; v2(152.45,88.82) v2(152.45,88.18) 152.04,87.78 UC1.AL8 ; v2(152.45,88.82) v2(152.45,89.45) 152.36,89.45 UC1.AL10 UC1.AL9 ; v2(152.45,88.82) 152.06,88.43 UC1.AL9 ; UT5.E6 UT5.E7 ; UT5.E6 UT5.F6 ; UT5.E7 UT5.F7 ; UC1.AD9 UC1.AD8 UC1.AD7 ; v2(65.03,105.91) 64.83,105.71 64.83,105.5 UT5.B7 ; UC1.T9 162.96,88.29 162.97,88.28 162.97,87.93 162.96,87.92 UC1.T8 UC1.T7 162.71,86.88 162.71,86.78 UC1.U6 UC1.V6 161.31,86.22 161.12,86.22 UC1.W5 ; UH1.BA6 UH1.BA5 v2(218.33,107.36) UH1.AW4 ; UT5.F7 UT5.F6 ; v2(142.51,107.56) 142.19,107.24 UC1.BC34 ; UC1.AL8 UC1.AL7 152.17,86.95 152.29,86.82 152.49,86.82 152.59,86.72 152.93,86.72 UC1.AJ6 UC1.AH6 UC1.AG6 154.93,86.47 155.21,86.75 v2(155.28,86.75) ; UC1.AL8 UC1.AL9 ; UH1.AT45 238.62,105.34 v2(238.62,105.13) 238.62,104.71 UH1.AP46 238.49,104.62 238.18,104.31 238.18,103.77 237.99,103.58 237.99,103.3 238,103.29 238,103.29 238.25,103.04 238.25,102.7 UH1.AK46 ; UC1.AH33 154,106.59 v2(154.32,106.91) 153.99,107.24 UC1.AH34 ; v2(63.26,108.94) 63.26,108.88 63.71,108.43 UT5.H5 ; UC1.BD10 UC1.BD9 ; UC1.BD10 141.21,89.08 v2(141.47,88.82) ; UC1.BD10 UC1.BD11 ; UC1.BD9 UC1.BD8 ; UC1.BL13 136.15,90.92 136.15,90.9 v2(136.09,90.84) 136.09,90.72 UC1.BM12 135.83,90.41 135.5,90.09 ; UC1.BD11 UC1.BD12 141.11,90.38 141.4,90.09 v2(141.47,90.09) 141.76,90.38 UC1.BC12 UC1.BC13 ; UC1.BD11 141.2,89.73 v2(141.48,89.45) ; UT1.B10 UT1.A10 ; UC1.T13 UC1.T12 ; UC1.T12 162.7,90.64 162.44,90.64 162.18,90.38 UC1.V12 UC1.W12 ; UC1.T12 163.13,90.38 163.42,90.09 ; UC1.BE5 140.61,85.7 140.62,85.68 140.62,85.3 140.61,85.29 UC1.BE4 140.61,85.05 140.62,85.03 140.62,84.65 140.61,84.64 UC1.BE3 140.19,84.1 v2(140.15,84.1) ; UC1.BE5 140.69,85.82 141,86.13 v2(141,86.14) 141.33,86.47 UC1.BD6 ; UC1.N8 UC1.N9 ; UC1.N8 166.16,88.23 v2(166.16,88.7) 166.1,88.7 165.82,88.43 UC1.N9 ; UC1.N8 UC1.N7 165.71,86.87 165.75,86.82 UC1.N6 ; UC1.D26 172.15,101.46 172.15,101.32 UC1.C25 172.55,100.83 v2(172.88,100.51) ; v2(132.45,101.48) UC1.BT26 ; UC1.A12 v2(174.49,90.68) ; 144.22,88.18 144.17,88.18 UC1.BA8 ; 144.22,88.18 144.22,88.82 143.96,89.08 UC1.BA10 ; 144.22,88.18 143.97,88.43 UC1.BA9 ; UT5.A7 64.85,104.73 64.85,104.51 v2(64.95,104.41) 65.21,104.66 UT5.A8 ; v2(170.93,87.93) 170.6,88.25 UC1.F9 170.6,88.39 v2(170.28,88.72) ; v2(170.93,87.93) 171.25,88.25 UC1.E9 ; UC1.BA10 UC1.BA9 ; UH1.C5 218.5,88.88 v2(218.57,88.82) 218.56,88.86 UH1.C4 ; UC1.BA6 UC1.BB6 ; UC1.BB6 143.51,86.86 143.51,86.88 UC1.BA7 UC1.BA8 ; UC1.BB6 143.03,86.47 142.7,86.13 v2(142.69,86.13) ; UC1.AU10 146.7,89.08 v2(146.96,88.82) ; UC1.AU10 UC1.AU11 ; UC1.BH11 138.46,89.73 v2(138.74,89.45) ; UC1.BH11 UC1.BH10 ; UC1.BH11 UC1.BH12 138.44,90.38 v2(138.73,90.09) 139.02,90.38 UC1.BG12 UC1.BG13 ; UC1.BA8 UC1.BA9 ; v2(146.96,88.82) v2(146.97,89.45) 146.78,89.63 146.77,89.63 146.68,89.73 UC1.AU11 ; UC1.J18 UC1.H18 169.27,95.41 v2(169.63,95.05) ; UT5.A1 61.7,104.33 v2(61.65,104.28) ; UC1.A16 v2(174.49,93.83) ; 141.03,86.72 140.86,86.72 UC1.BE6 ; 141.03,86.72 141.19,86.72 UC1.BD6 ; UC1.N12 165.44,90.64 165.05,90.64 UC1.P12 164.63,90.54 164.04,90.54 UC1.R12 163.71,90.38 163.42,90.09 ; v2(136.14,107.42) 136.23,107.33 136.23,106.61 UC1.BM33 ; UC1.AU12 UC1.AU11 ; UC1.BC14 UC1.BC13 ; UC1.BC13 141.75,91.03 v2(141.45,90.73) ; UC1.AP9 149.46,88.43 v2(149.7,88.18) ; UC1.BM35 135.85,107.78 v2(136.18,108.1) 136.39,107.89 UC1.BL35 ; 172.15,88.72 172.15,88.86 UC1.D10 ; 172.15,88.72 UC1.D9 ; UC1.BD38 141.39,109.84 v2(141.72,109.52) 141.4,109.19 UC1.BD37 ; UC1.BL29 136.61,103.98 137.05,103.98 UC1.BK29 ; UC1.BG14 UC1.BG13 ; UC1.BG13 139.52,90.69 v2(139.67,90.69) 139.99,90.38 UC1.BF12 ; 169.51,85.49 169.84,85.82 UC1.G5 ; 169.51,85.49 169.43,85.49 UC1.J4 UC1.K4 168.27,85.29 168.28,85.3 168.28,85.68 168.27,85.7 UC1.K5 ; 169.51,85.49 169.84,85.17 UC1.G4 ; UC1.G5 169.91,85.89 169.96,85.94 169.96,86.32 169.91,86.38 UC1.G6 ; UC1.G5 170.05,85.96 UC1.F5 ; UC1.BN24 135.17,99.83 v2(135.5,99.51) 135.83,99.18 UC1.BM23 ; UC1.BD6 UC1.BC6 ; UC1.AU33 146.9,106.59 v2(147.23,106.26) ; v2(163.42,90.07) 163.42,90.09 ; UC1.AW5 UC1.AW4 UC1.AW3 145.31,84.19 v2(145.19,84.19) 145.52,83.87 UC1.AW2 UC1.AW1 ; UC1.F15 170.6,93.12 v2(170.28,93.44) 169.95,93.77 UC1.G16 ; UC1.C5 172.03,85.44 171.67,85.44 171.61,85.5 171.61,85.53 v2(171.64,85.53) ; UC1.E4 171.14,85.17 171.1,85.12 170.72,85.12 170.67,85.17 UC1.F4 170.59,84.62 UC1.F3 ; UC1.A26 173.88,101.68 174.22,101.68 v2(174.49,101.42) ; UC1.BN30 135.49,104.94 v2(135.49,105.05) 135.49,105.1 UC1.BN31 134.78,105.81 134.78,105.95 UC1.BP33 ; UC1.AJ38 UC1.AJ37 ; UC1.AG7 UC1.AG8 ; UC1.BH10 138.47,89.08 v2(138.73,88.82) ; 135.5,90.09 135.5,89.99 UC1.BM11 135.83,89.66 v2(136.19,89.29) 135.83,88.92 UC1.BM9 135.57,88.63 135.57,88.34 UC1.BM8 135.57,87.84 135.57,87.56 UC1.BM7 UC1.BN7 ; v2(147.23,107.56) 146.91,107.24 UC1.AU34 ; UC1.L30 167.34,104.57 167.34,103.97 UC1.L29 ; UC1.AP8 149.3,87.78 v2(149.7,88.18) ; UH1.A5 UH1.A4 UH1.A3 UH1.A2 ; v2(142.51,106.26) 142.18,106.59 UC1.BC33 ; v2(134.2,89.24) 133.87,88.91 UC1.BR9 ; UC1.BT32 133.07,106.29 132.78,106.29 v2(132.68,106.19) ; UC1.A14 v2(174.41,92.26) ; UH1.AC17 224.79,99.06 224.98,99.25 ; UT5.G5 63.56,108.03 63.56,108.03 63.35,108.23 63.35,108.24 UT5.H4 62.91,108.38 v2(62.74,108.55) ; UC1.A18 174.36,95.41 v2(174.54,95.22) ; UC1.A22 v2(174.43,98.56) ; v2(149.7,88.82) v2(149.71,89.45) 149.71,90.09 v2(149.7,90.09) 149.87,90.09 UC1.AN12 150.42,90.64 150.81,90.64 UC1.AM12 151.34,90.64 151.73,90.64 UC1.AL12 ; v2(149.7,88.82) 149.44,89.08 UC1.AP10 ; v2(149.7,88.82) v2(149.7,88.18) ; UC1.N6 UC1.M6 ; UC1.N6 UC1.P6 ; UC1.BN7 UC1.BP7 134.52,87.44 134.24,87.73 v2(134.23,87.73) 133.87,87.37 UC1.BR7 ; UC1.BN7 135.25,87.23 v2(135.25,86.77) ; v2(146.45,109.52) 146.12,109.19 UC1.AV37 ; v2(132.12,85.99) 132.23,85.99 132.26,86.01 133.2,86.01 UC1.BT5 ; UC1.AD6 157.04,86.13 v2(156.95,86.13) 156.87,86.13 UC1.AE6 ; UC1.AF14 UC1.AF13 UC1.AF12 155.32,90.05 v2(155.15,90.05) 154.83,89.73 UC1.AG11 ; UC1.BL33 136.61,106.59 v2(137,106.99) ; v2(174.58,100.15) 174.31,100.15 174.3,100.13 UC1.A24 ; UC1.BN18 UC1.BP18 UC1.BR18 UC1.BT18 v2(132.45,95.18) ; v2(174.28,103.55) 174.12,103.55 UC1.A28 ; UC1.D12 171.9,90.55 UC1.C11 172.55,89.83 v2(172.88,89.5) ; UC1.B3 173.28,84.47 UC1.A3 UC1.A4 ; UC1.F3 170.69,84.44 170.75,84.38 170.75,84 170.69,83.94 UC1.F2 170.37,84.19 170.37,84.19 ; UC1.F3 170.37,84.19 ; v2(170.3,84.19) 170.37,84.19 ; v2(172.88,92.65) 172.55,92.98 UC1.C15 172.15,93.44 172.15,93.58 UC1.D16 ; UC1.BT35 132.98,107.71 132.4,108.3 132.4,108.58 v2(132.42,108.6) 132.44,108.62 133.13,108.62 UC1.BT36 133.34,108.41 UC1.BR36 ; UH1.F47 239.93,90.19 239.93,89.53 UH1.C48 ; v2(132.44,97.49) 132.49,97.54 UC1.BT21 UC1.BR21 ; UH1.E31 231.21,90.04 UH1.D30 ; UC1.BN20 135.01,96.59 135.01,96.13 UC1.BN19 ; UC1.AC12 158.52,90.5 159.18,90.5 UC1.AA12 ; UC1.AR5 148.15,85.68 148.15,85.68 148.15,85.31 148.15,85.31 UC1.AR4 148.15,85.04 148.16,85.03 148.16,84.53 UC1.AR3 ; UC1.BR34 UC1.BP34 ; v2(61.45,110.3) 61.7,110.05 UT5.L1 ; UH1.M21 227.18,93.74 v2(227.38,93.53) ; UC1.BJ33 137.46,106.59 v2(137.78,106.91) 137.45,107.24 UC1.BJ34 ; UC1.AE34 UC1.AE33
  BOTTOM w0.254: v2(134.2,101.06) 133.87,100.74 UC1.BR25 ; v2(134.2,101.06) 134.2,101.15 UC1.BP26 ; v2(134.2,101.06) 133.87,101.38 UC1.BR26 UC1.BT26 ; v2(134.2,101.06) 134.52,100.73 UC1.BP25 ; v2(170.85,108.91) 170.49,108.54 UC1.F36 ; v2(216.84,87.84) 216.81,87.93 UH1.A2 ; UH1.BA12 v2(221.44,107.78) ; UC1.J32 v2(169.31,106.26) ; v2(169.31,106.26) UC1.H32 ; v2(169.31,106.26) UC1.J33 ; UC1.R30 164.11,104.59 v2(163.76,104.94) ; UC1.AM38 151.19,109.43 v2(151.19,108.85) 150.84,109.19 UC1.AM37 ; PU800.4 78.01,106.22 77.78,105.99 77.4,105.99 77.05,106.35 v2(76.6,106.35) ; UH1.B48 UH1.C48 ; UH1.B48 UH1.A47 ; UH1.B48 UH1.B47 UH1.A46 ; UH1.B48 UH1.B49 240.46,88.5 v2(240.46,87.94) ; UH1.B48 UH1.A48 ; UH1.E13 222.75,90.01 v2(222.95,90.01) 223.42,90.01 UH1.E15 223.96,90.08 UH1.D16 224.21,89.83 UH1.D17 ; v2(80.02,135.5) 80.02,135.12 79.81,134.92 JXDP1.13 79.81,133.92 79.48,133.59 78.21,133.59 78.01,133.79 JXDP1.7 ; v2(170.97,91.06) 170.97,91.06 170.6,91.43 UC1.F13 170.6,91.61 UC1.G14 ; UC1.BJ15 UC1.BJ14 137.78,92.07 v2(138.66,92.07) 138.66,92.03 UC1.BH14 ; UC1.D14 171.9,92.2 v2(172.21,91.89) 172.55,91.55 UC1.C13 ; 135.83,103.82 v2(136.19,103.45) 136.48,103.74 UC1.BL29 ; 135.83,103.82 UC1.BM29 ; 135.83,103.82 135.83,103.74 v2(135.54,103.45) 135.17,103.82 ; v2(173.72,83.87) 173.85,84 UC1.A3 ; UC1.BP21 134.63,97.44 135.07,97.44 UC1.BN21 ; JUSH1.17 232.28,38.89 232.19,38.8 v2(232.19,38.53) ; JFPBTN1.2 313,116.35 312.77,116.12 312.77,115.75 v2(313.26,115.26) ; v2(14.38,105.55) 14.07,105.86 RT490.2 ; v2(161.39,104.98) 161.78,104.59 UC1.V30 ; JDIMM2.202 220.92,41.63 221.18,41.37 221.49,41.37 221.49,41.38 v2(221.49,41.39) ; UC1.AR37 148.48,109.19 v2(148.81,108.87) 148.49,108.54 UC1.AR36 ; UC1.BJ31 137.28,105.4 137.28,105.83 UC1.BJ32 137.37,105.96 137.37,105.99 137.09,106.27 v2(136.99,106.27) ; v2(253.54,78.14) 253.75,77.92 JESPI.11 ; v2(145.66,104.97) 145.28,104.59 UC1.AW30 ; v2(257.71,66.4) 257.94,66.64 258.3,66.64 258.49,66.45 JDEG1.10 ; UC1.BL14 136.48,92.1 v2(136.15,92.42) 135.83,92.1 UC1.BM14 UC1.BN14 UC1.BP14 UC1.BR14 UC1.BT14 133.22,92.08 v2(132.58,92.72) ; RT219.2 v2(13.14,101.99) ; RT219.2 12.91,102.59 v2(12.6,102.28) ; RT219.2 13.37,102.59 v2(13.68,102.28) ; v2(277.38,32.37) 277.38,32.65 277.2,32.83 JNGFF1.19 ; v2(170.94,89.55) 170.6,89.88 UC1.F11 169.95,90.55 UC1.G12 ; v2(14.64,104.58) 14.95,104.27 DT14.2 ; UC1.K1 168.27,83.19 168.45,83.01 168.45,82.7 168.39,82.65 v2(168.39,82.59) ; UC1.D18 171.9,95.31 v2(172.21,95.01) 172.55,94.66 UC1.C17 ; JNGFF2.3 260.04,74.44 260.04,73.53 260.19,73.39 ; v2(141.47,88.82) 141.41,88.82 UC1.BD9 ; v2(175.75,34.47) 175.71,34.51 PU200.4 ; JXDP1.8 78.31,131.97 79,132.66 79.92,132.66 v2(80.45,132.13) ; v2(232.91,133.72) 232.9,133.72 232.7,133.53 JSPI1.22 ; UC1.C2 172.6,84.02 v2(172.6,84.55) ; JNGFF1.18 276.95,41.89 277.36,42.3 v2(277.62,42.3) ; v2(145.47,92.51) 145.1,92.51 144.87,92.28 144.87,91.88 UC1.AY14 ; UC1.F31 170.6,105.71 170.95,106.06 v2(170.95,106.07) ; UC1.AL12 152.31,90.7 v2(152.48,90.7) 152.81,91.03 UC1.AJ13 152.25,91.68 UC1.AL14 ; v2(138.1,101.09) UC1.BJ25 UC1.BK25 ; v2(148.02,104.27) 147.69,103.94 UC1.AT29 ; v2(148.02,104.27) 148.35,103.94 UC1.AR29 ; v2(148.02,104.27) 148.34,104.59 UC1.AR30 ; v2(137.26,91.58) 137.13,91.71 UC1.BK14 ; UC1.D22 171.9,98.43 v2(172.21,98.12) 172.55,97.78 UC1.C21 ; JXDP1.37 87.01,133.98 85.86,132.83 v2(85.16,132.83) ; JEDP1.24 136.26,131.83 v2(136.52,132.09) 136.76,131.85 JEDP1.25 ; JEDP1.15 131.76,132.19 v2(131.64,132.32) ; 38.75,101.56 37.66,100.48 37.66,98.28 36.71,97.33 v4(36.71,95.96) 36.71,94.51 36.44,94.24 35.87,94.24 ; v2(136.04,86.84) 135.8,87.09 135.8,87.28 UC1.BM7 ; v2(136.04,86.84) 135.62,86.42 UC1.BM6 ; v2(136.04,86.84) UC1.BL6 ; v2(177.33,41.58) 177.42,41.68 177.42,41.73 ; UH1.E31 231.61,90.08 v2(231.69,90.16) 231.82,90.29 UH1.E33 ; UC1.AR38 148.71,109.55 148.81,109.55 v2(148.85,109.51) ; v2(170.94,99.7) 170.95,99.7 170.95,99.69 UC1.F23 170.29,99.66 170.29,99.76 v2(170.27,99.78) ; JEDP1.39 v2(143.76,129.61) ; v2(128.26,130.08) JEDP1.8 ; UH1.BG4 UH1.BF3 ; UH1.BG4 218.01,110.99 217.52,111.49 v2(216.66,111.49) ; UH1.BG4 UH1.BG3 ; UH1.BF3 UH1.BF2 ; UH1.BF3 UH1.BG3 ; UC1.Y37 v2(160.62,109.52) UC1.Y38 ; UC1.C31 172.44,105.64 172.19,105.39 v2(172.19,105.23) 172.19,105.14 UC1.D30 ; v2(240.41,93.1) 240.28,93.23 UH1.M49 ; JKBTP1.20 193.01,38.9 193.29,38.62 v2(193.29,38.36) ; UC1.AC38 157.88,109.84 v2(158.24,109.48) ; UC1.AL34 151.5,107.24 v2(151.17,106.91) 151.49,106.59 UC1.AL33 ; RT490.2 13.61,105.86 v2(13.3,105.55) ; RT490.2 v2(13.84,105.27) ; UC1.L29 167.36,103.89 167.36,103.22 167.49,103.09 v2(167.49,102.31) ; UH1.BF2 UH1.BF1 216.59,110.66 216.59,111.42 v2(216.66,111.49) ; UH1.BF2 UH1.BG2 ; 224.1,95.69 224.12,95.68 UH1.R16 ; v2(143.3,103.62) 142.97,103.94 UC1.BB29 ; v2(170.94,98.12) 170.6,97.78 UC1.F21 170.28,98.1 v2(170.28,98.17) 169.95,98.49 UC1.G22 169.85,98.46 169.35,98.46 UC1.H22 169.1,98.41 168.75,98.41 UC1.J22 ; UC1.AM4 150.52,85.31 150.43,85.31 v2(150.27,85.47) ; v2(219.07,98.11) 219,98.04 UH1.AA5 218.41,98.24 UH1.AC4 ; DD32.2 120.19,42.75 CD29.2 ; v2(159.08,104.98) 159.44,104.62 UC1.AA30 UC1.AA29 ; UC1.D24 171.9,100.01 v2(172.21,99.71) 172.55,99.36 UC1.C23 ; UC1.W34 161.36,106.9 v2(161.42,106.9) ; UC1.B37 173.15,109.12 v2(172.78,108.76) 172.45,109.09 UC1.C37 ; v2(13.68,104.69) 13.37,104.38 RT220.2 ; UC1.AC37 v2(158.26,108.87) ; UC1.AK4 152.24,85.17 v2(151.92,84.85) 151.87,84.85 UC1.AL4 ; UC1.AK4 152.58,84.88 152.82,84.88 UC1.AJ3 ; UC1.AK4 151.97,85.49 v2(151.92,85.49) ; UC1.AG7 154.73,86.59 UC1.AG6 ; v2(15.34,107.85) 15.65,107.54 DT17.2 ; v2(239.43,87.85) UH1.A47 ; UH1.A47 UH1.A46 ; UH1.Y33 232.5,97.09 v2(232.5,97.08) 232.6,96.98 UH1.U33 ; UC1.BA10 144.14,89.45 v2(144.22,89.45) ; JNGFF2.57 273.58,75.36 273.43,75.51 273.43,77.35 274.95,78.88 v2(275.39,78.88) 275.49,78.79 275.67,78.79 277.08,77.39 JNGFF2.71 ; UH1.E22 226.87,91.31 226.94,91.39 226.94,91.39 v2(226.96,91.39) 227.3,91.04 227.3,90.67 UH1.E24 ; UH1.E17 224.7,90.32 v2(225.3,90.32) 225.44,90.32 225.67,90.08 UH1.E19 ; UC1.AP11 149.52,89.45 v2(149.71,89.45) ; DT14.2 15.41,104.27 v2(15.72,104.58) ; DT14.2 v2(15.18,104.86) ; v2(15.34,105.66) 15.65,105.97 DT18.2 ; UC1.P37 164.9,109.19 v2(164.58,109.51) 164.92,109.84 UC1.P38 164.95,110.39 163.11,112.23 PRZ1.2 ; v2(224.51,37.86) 224.79,38.14 224.79,38.55 225.28,39.05 JUSH1.3 ; v2(172.6,84.55) 173.1,84.55 UC1.B3 ; v2(172.6,84.55) 172.5,84.45 UC1.D3 ; JDIMM2.244 231.42,44.69 v2(231.74,45.01) ; v2(171.64,106.04) 171.64,106.17 UC1.D33 ; RT220.2 v2(13.14,104.98) ; RT220.2 12.91,104.38 v2(12.6,104.69) ; v2(171.05,110.33) 170.96,110.24 UC1.E38 ; JDIMM2.248 232.42,44.35 232.45,44.37 ; JXDP1.38 87.31,130.63 86.78,130.1 v2(86.78,129.8) ; v2(154.71,103.22) UC1.AG29 UC1.AG30 154.74,104.59 v2(155.12,104.98) ; v2(191.35,41.5) 191.51,41.35 JKBTP1.17 ; UC1.BP34 134.52,107.07 v2(134.85,107.4) 135.17,107.07 UC1.BN34 ; v2(134.49,129.04) 135.76,130.32 JEDP1.23 ; v2(262.69,73.35) 262.08,73.97 JNGFF2.11 ; v2(133.28,109.99) 133.43,109.84 UC1.BR38 ; UC1.BE6 140.68,86.47 v2(141,86.14) ; UC1.J36 168.9,108.54 ; 168.9,108.54 v2(169.24,108.89) ; 168.9,108.54 169.08,108.36 169.2,108.36 UC1.H35 ; UC1.BL22 v2(136.15,97.94) ; v2(136.15,97.94) UC1.BM22 ; v2(136.15,97.94) UC1.BL21 ; v2(135.25,86.77) UC1.BM6 ; UC1.BM6 UC1.BM5 136.01,85.46 v2(136.01,85.32) 135.72,85.03 UC1.BM3 ; UC1.G18 169.95,95.37 v2(169.63,95.05) ; PU200.15 175.26,38.57 175.27,38.58 175.27,38.69 v2(175.38,38.81) ; UC1.BN21 135.17,97.61 v2(135.5,97.94) ; UC1.BN21 UC1.BN20 ; UC1.BG37 139.01,109.19 v2(139.35,109.54) 139.05,109.84 UC1.BG38 ; UC1.AV38 146.12,109.84 v2(146.45,109.52) ; v2(170.27,99.78) 170.27,99.69 169.95,99.37 UC1.G23 ; v2(170.27,99.78) 169.95,100.1 UC1.G24 ; JEDP1.6 127.26,131.91 v2(127.51,132.16) ; PUT1.4 99.06,86.68 v2(99.06,86.69) ; UC1.AN5 150.13,85.47 v2(150.27,85.47) ; UC1.T34 163.44,107.24 v2(163.77,106.91) UC1.T33 ; v2(157.83,86.8) 157.5,87.13 UC1.AD7 ; v2(157.83,86.8) 157.77,86.8 157.44,86.47 UC1.AD6 ; v2(157.83,86.8) 158.16,86.47 UC1.AC6 ; v2(150.27,85.47) 150.31,85.47 UC1.AM5 ; v2(15.88,105.37) DT18.2 ; DT18.2 16.11,105.97 v2(16.42,105.66) ; UC1.AP33 149.27,106.59 v2(149.59,106.91) 149.27,107.24 UC1.AP34 ; v2(143.27,104.99) 142.9,104.62 UC1.BB30 ; JKBTP1.2 184.01,38.42 v2(183.83,38.24) ; UC1.M13 UC1.M14 ; JSATA1.4 v2(245.55,37.57) ; UC1.U38 v2(162.98,109.52) UC1.U37 ; UC1.BD12 140.88,90.38 v2(140.56,90.7) 140.23,90.38 UC1.BF12 ; JEDP1.4 126.26,132.06 v2(126.8,132.6) ; UC1.G10 169.95,89.04 v2(170.28,88.72) 170.28,88.65 UC1.G9 ; UH1.BG2 v2(216.66,111.49) ; UH1.BG2 UH1.BG3 ; CZ102.2 v2(125.21,90.18) ; v2(137.05,109.53) 136.73,109.84 UC1.BL38 UC1.BM38 ; UC1.AW29 145.33,103.94 v2(145.66,103.62) ; v2(81.96,135.72) 81.61,135.37 JXDP1.19 ; JSATA1.18 v2(252.55,39.45) ; JSATA1.14 250.55,39.27 v2(250.12,39.7) ; UC1.AR34 148.49,107.24 v2(148.81,107.56) 148.48,107.89 UC1.AR35 ; UC1.AC12 158.01,90 v2(157.94,90) 157.74,90 UC1.AD11 ; v2(15.72,102.38) 15.41,102.69 DT13.2 ; v2(152.71,104.98) 152.35,104.62 UC1.AK30 UC1.AK29 152.35,103.76 152.65,103.46 v2(152.65,103.21) ; UC1.N10 165.87,89.08 v2(166.17,89.38) ; UH1.A45 UH1.A46 ; v2(150.18,103.26) 149.99,103.46 UC1.AN29 UC1.AN30 150,104.59 150.37,104.97 v2(150.37,104.98) ; UC1.AR32 148.49,105.94 v2(148.81,106.26) 148.48,106.59 UC1.AR33 ; DE43.2 267.99,101.04 v2(267.57,101.46) ; UC1.N34 v2(165.3,106.91) UC1.N33 ; v2(148.79,90.04) 149.13,90.38 UC1.AP12 ; UC1.H25 169.1,100.77 168.75,100.77 UC1.J25 168.47,100.92 v2(168.15,100.59) ; UC1.AT30 147.63,104.61 148,104.99 v2(148,105.01) 148.13,105.01 UC1.AR31 ; v2(157.77,86.15) 158.1,85.82 UC1.AC5 ; v2(278.46,73.48) 278.42,73.48 278.38,73.45 277.83,73.45 277.58,73.7 JNGFF2.73 ; v2(247.36,40.21) 247.04,39.9 JSATA1.7 ; UC1.AG13 154.62,91.03 v2(154.28,90.69) ; RT491.2 v2(13.84,108.25) ; RT491.2 13.61,107.66 v2(13.3,107.97) ; RT491.2 14.07,107.66 v2(14.38,107.97) ; DT17.2 16.11,107.54 v2(16.42,107.85) ; DT17.2 v2(15.88,108.14) ; UC1.K9 168.05,88.75 v2(167.95,88.75) ; DT13.2 v2(15.18,102.1) ; DT13.2 14.95,102.69 v2(14.64,102.38) ; v2(135.5,99.51) 135.83,99.83 UC1.BM24 ; v2(279.43,46.78) 279.26,46.61 279.26,45.28 278.87,44.89 QZ18.4 ; 135.17,103.82 135.17,103.78 v2(134.82,103.43) 134.52,103.73 UC1.BP29 UC1.BR29 UC1.BT29 ; 135.17,103.82 UC1.BN29 ; UC1.D20 171.9,96.9 v2(172.21,96.59) 172.55,96.25 UC1.C19 ; UC1.AB34 v2(159.04,106.91) UC1.AB33 ; UC1.BF34 139.72,107.24 v2(139.39,106.91) 139.7,106.59 UC1.BF33 ; v2(272.08,75.88) 272.08,75.56 272.08,75.56 JNGFF2.51 ; v2(163.29,92.11) 162.96,91.78 UC1.T14 UC1.T13 ; UC1.BE30 140.61,104.59 v2(140.93,104.27) ; v2(80.11,130.79) JXDP1.14 ; UC1.K7 168.48,87.13 v2(168.75,87.4) UC1.K8 ; v2(270.39,76.16) 270.22,75.99 270.22,75.61 270.58,75.25 JNGFF2.45 ; v2(140.93,103.62) 140.61,103.94 UC1.BE29 ; UC1.E34 171.25,107.23 v2(171.61,107.59) 171.31,107.89 UC1.E35 ; v2(156.73,106.27) 156.33,106.6 UC1.AE33 ; v2(170.28,101.36) 169.95,101.69 UC1.G26 170.6,102.36 UC1.F27 UC1.G28 ; JNGFF2.5 260.58,73.65 260.32,73.39 260.19,73.39 ; v2(172.12,110.2) UC1.D38 ; v2(170.86,103.68) 170.87,103.7 UC1.F29 ; CE25.2 271.05,94.31 v2(271.71,94.31) ; UC1.BJ29 137.45,103.71 UC1.BK29 137.52,104.46 UC1.BJ30 ; RH317.1 242.51,98.74 241.7,99.55 v2(241.43,99.55) ; UC1.BK22 UC1.BJ22 v2(138.1,97.93) ; v2(154.27,88.75) 154.6,89.08 UC1.AG10 ; UC1.AH35 153.98,107.89 v2(154.33,108.23) 154.01,108.54 UC1.AH36 ; UC1.AR13 UC1.AR14 ; 260.19,73.39 v2(260.19,73.36) ; UC1.Y13 UC1.Y14 160.78,92.24 v2(161.09,92.24) ; UC1.BK13 137.45,90.79 UC1.BJ12 137.45,90.42 v2(137.82,90.05) 138.14,90.38 UC1.BH12 ; JDIMM2.238 v2(229.92,41.41) ; UC1.BA11 144.12,90.09 v2(144.22,90.09) ; PUH1.4 v2(161.08,130.88) ; UC1.AD29 UC1.AD30 157.1,104.59 v2(157.48,104.98) ; JDIMM2.252 233.42,41.71 v2(233.19,41.48) ; UC1.BM18 135.97,95.32 136.33,95.32 UC1.BL18 UC1.BK18 UC1.BJ18 v2(138.1,94.78) ; v2(136.15,101.08) UC1.BM25 ; JSATA1.1 244.04,37.7 v2(244.17,37.57) ; UC1.BN24 135.12,99.95 134.69,99.95 134.64,99.9 UC1.BP24 134.43,99.9 134.31,100.02 134.04,100.02 133.92,99.9 UC1.BR24 UC1.BT24 ; UC1.BM21 136.1,97.2 136.13,97.17 v2(136.13,97.15) 136.48,96.8 UC1.BL20 136.67,96.56 136.67,96.17 136.48,95.97 UC1.BL19 ; UC1.BA38 143.77,109.77 143.88,109.65 143.88,109.39 UC1.BA37 143.75,109.19 v2(144.08,108.87) ; UC1.K38 168,109.84 v2(167.67,109.52) ; CT1.2 v2(37.44,125.89) ; JXDP1.62 75.56,134.81 76.84,136.09 77.38,136.09 77.48,135.99 77.48,136.01 v2(77.47,136.01) ; v2(214.87,97.13) 213.01,97.13 212.53,97.61 209.23,97.61 208.72,97.1 208.72,93.76 209.06,93.42 212.47,93.42 214.18,95.13 v2(215.83,95.13) ; JESPI.9 v2(248.75,79.08) ; UC1.W33 v2(161.41,106.26) ; UH1.BG48 240.25,111.27 240.77,111.27 v2(240.83,111.22) 240.83,111.07 240.36,110.6 UH1.BF49 UH1.BF48 UH1.BG48
  BOTTOM w0.305: JDIMM2.77 187.67,47.91 v2(189.02,46.56) ; v2(96.12,44.53) JDIMM1.14 ; JDIMM1.23 98.37,55.38 v2(98.39,55.39) ; JDIMM2.85 189.67,49.38 v2(190.62,48.44) ; JDIMM2.72 186.42,44.21 v2(187.04,44.83) ; v2(159.19,103.3) 159.19,103.69 UC1.AA29 159.81,103.57 v2(159.81,103.3) ; UC1.R30 UC1.R29 164.03,103.81 v2(164.03,103.3) ; JDIMM1.69 109.87,52.94 v2(108.88,51.94) ; JDIMM2.15 172.17,50.1 171.45,49.37 171.45,47.16 v2(172.03,46.58) ; JNGFF2.33 v2(267.58,73.3) ; JDIMM2.2 168.92,43.33 168.79,43.47 167.66,43.47 v2(167.07,44.05) ; JDIMM1.235 153.37,52.27 v2(154.01,51.64) ; v2(152.06,49.96) 152.59,50.49 152.59,52.97 152.37,53.18 JDIMM1.231 ; JDIMM2.39 178.17,52.09 177.79,52.48 v2(177.47,52.48) ; v2(191.35,41.5) 190.92,41.93 JDIMM2.90 ; JDIMM2.57 182.67,49.99 182.5,49.82 182.5,47.42 v2(181.43,46.35) ; JDIMM2.52 181.42,44.77 v2(181.29,44.9) ; JDIMM1.202 145.12,47.44 v2(145.23,47.55) ; v2(181.45,49.02) 181.17,49.3 JDIMM2.51 ; JDIMM2.82 188.92,43.68 188.61,44 188.55,44 188.55,44.45 v2(189.02,44.93) ; v2(195.04,52.36) 195.04,52.17 195.17,52.03 JDIMM2.107 ; v2(274.83,27.64) 274.82,27.65 JNGFF3.33 ; JDIMM1.9 94.87,52.46 v2(94.66,52.25) ; JDIMM1.57 106.87,55.11 v2(107.19,55.42) ; v2(112.11,48.11) 113.12,47.09 JDIMM1.82 ; UC1.V29 162.22,103.52 v2(162.22,103.3) ; UC1.V29 UC1.V30 ; UC1.V29 161.61,103.76 v2(161.61,103.3) ; JDIMM2.234 228.92,44.01 229.75,44.84 v2(229.99,44.84) ; v2(185.34,48.36) 185.87,48.88 185.87,49.56 185.67,49.76 JDIMM2.69 ; JNGFF1.39 282.2,32.41 v2(282.16,32.37) ; RV610.2 293.4,87.51 293.4,86.99 v2(293.34,86.94) ; v2(157.4,103.3) 157.4,103.61 UC1.AD29 156.82,103.69 v2(156.82,103.3) ; v2(152.08,51.79) 151.78,51.79 151.37,52.2 JDIMM1.227 ; JDIMM2.167 212.17,49.61 211.84,49.27 211.84,48.44 v2(210.49,47.09) ; v2(154.04,48.39) 153.22,47.57 153.22,47.06 153.12,46.97 JDIMM1.234 ; JNGFF1.57 286.7,32.19 v2(288.08,30.8) 288.2,30.92 JNGFF1.63 ; v2(292.02,30.68) 291.51,31.19 290.63,31.19 289.7,32.12 JNGFF1.69 ; JDIMM1.86 114.12,44.68 v2(113.98,44.53) ; JNGFF3.75 264.32,29.56 264.02,29.87 v2(263.23,29.87) ; JNGFF3.15 v2(279.32,27.64) ; JDIMM1.72 110.62,46.88 110.93,47.19 110.93,47.63 v2(110.48,48.08) ; JDIMM1.77 111.87,53.09 111.5,52.71 111.5,50.36 v2(112,49.86) ; JDIMM1.56 106.62,47.16 v2(106.59,47.2) ; v2(183.59,46.76) 184.42,45.92 JDIMM2.64 ; v2(192.25,47.95) 191.67,48.53 JDIMM2.93 ; v2(288.21,101.98) 287.47,101.98 287.16,102.28 CL17.2 ; JNGFF3.21 277.82,27.67 v2(277.91,27.58) ; v2(230.05,49.63) 230.17,49.76 JDIMM2.239 ; v2(210.69,101.14) 210.81,101.26 210.94,101.26 211.25,101.56 CC305.2 ; JXDP1.26 83.71,132.13 v2(83.62,132.22) ; JDIMM1.81 112.87,52.48 v2(112.13,51.74) ; v2(117.31,44.58) 117.12,44.77 JDIMM1.98 ; v2(169.03,52.41) 168.67,52.06 JDIMM2.1 ; JDIMM1.40 102.62,47.01 102.42,47.22 102.42,47.79 v2(101.78,48.44) ; JDIMM1.210 147.12,45.05 v2(147.47,44.7) ; v2(114.25,48.21) 115.12,47.33 JDIMM1.90 ; JDIMM2.30 175.92,44.92 v2(175.87,44.98) ; v2(117.48,55.41) 117.37,55.3 JDIMM1.99 ; JDIMM2.31 176.17,47.8 v2(175.87,47.5) ; v2(85.43,129.77) 85.43,130.17 85.51,130.26 JXDP1.32 ; JDIMM2.6 169.92,43.97 168.84,45.05 v2(168.67,45.05) ; CL16.2 287.16,99.79 287.47,100.1 v2(288.58,100.1) ; CL21.2 287.16,108.24 287.47,107.93 v2(287.97,107.93) ; v2(168.81,89.41) 168.48,89.08 UC1.K10 ; v2(168.81,89.41) 168.63,89.6 168.59,89.6 168.47,89.73 UC1.K11 ; v2(168.81,89.41) 169.3,89.9 UC1.H11 ; v2(168.81,89.41) 169.12,89.11 UC1.J10 ; JXDP1.31 85.21,135.07 85.13,135.15 v2(85.13,135.35) ; JDIMM2.81 188.67,49.58 188.47,49.37 188.47,48.72 v2(189,48.2) ; UC1.H12 169.45,90.53 169.8,90.53 169.81,90.54 UC1.G12 ; JDIMM2.36 177.42,41.73 ; JDIMM1.175 138.37,53.14 138.62,52.9 138.62,50.96 v2(139.89,49.68) ; v2(179.86,44.8) 180.42,44.24 JDIMM2.48 ; v2(83.35,135.35) 83.41,135.29 JXDP1.25 ; 101.37,52.87 JDIMM1.35 ; v2(103.34,48.18) 104.62,46.9 JDIMM1.48 ; v2(185.39,46.58) 184.67,47.3 JDIMM2.65 ; v2(276.32,27.64) JNGFF3.27 ; v2(227.96,41.38) 227.92,41.41 JDIMM2.230 ; JDIMM2.44 179.42,43.69 179.2,43.91 179.2,44.9 v2(177.52,46.58) ; v2(173.94,44.93) 174.92,43.94 JDIMM2.26 ; v2(271.82,27.64) JNGFF3.45 ; RT440.1 v2(30.2,118.41) ; v2(103.62,44.51) JDIMM1.44 ; v2(99.89,50.75) 100.26,51.12 100.26,52.65 100.37,52.76 JDIMM1.31 ; v2(179.88,46.45) 179.17,47.16 JDIMM2.43 ; v2(226.01,49.07) 226.17,49.24 JDIMM2.223 ; JDIMM2.47 180.17,49.66 180.18,49.66 180.41,49.44 180.41,48.94 v2(179.85,48.38) ; v2(227.76,48.46) 227.17,49.05 JDIMM2.227 ; v2(96.21,51.54) 96.83,52.16 96.83,52.46 97.37,53 JDIMM1.19 ; v2(114.26,51.89) 114.87,52.5 JDIMM1.89 ; JNGFF1.33 v2(280.7,32.24) ; v2(213.23,48.82) 214.17,49.76 JDIMM2.175 ; v2(177.54,48.41) 176.98,48.98 176.98,49.5 177.17,49.7 JDIMM2.35 ; v2(98.05,51.38) 99.37,52.71 JDIMM1.27 ; JDIMM1.93 115.87,55.28 115.44,55.71 v2(115.14,55.71) ; v2(110.43,50.6) 110.87,51.04 JDIMM1.73 ; JDIMM2.86 189.92,44.18 v2(190.62,44.88) ; v2(135.76,51.75) 136.37,52.37 JDIMM1.167 ; JDIMM2.176 214.42,43.86 v2(213.23,45.06) ; JNGFF1.1 272.7,33 v2(272.22,32.52) ; v2(221.49,41.39) 221.51,41.39 221.92,41.8 JDIMM2.206 ; JDIMM2.56 182.42,41.77 v2(182.67,41.53) ; JNGFF1.51 v2(285.2,32.39) ; v2(227.76,46.78) 228.34,47.37 228.34,49.67 228.17,49.84 JDIMM2.231 ; JDIMM1.1 92.87,55.42 v2(93.23,55.77) ; JNGFF3.71 265.32,28.04 v2(265.95,27.42) 265.13,27.42 264.82,27.72 JNGFF3.73 ; v2(89.65,132.35) 89.91,132.09 90.49,132.09 90.91,131.67 JXDP1.50 ; v2(95.12,44.53) JDIMM1.10 ; JDIMM1.226 v2(151.12,44.67) ; v2(117.39,47.22) 117.76,47.22 118.12,46.85 JDIMM1.102 ; v2(81.93,130.79) 81.91,130.81 JXDP1.20 ; v2(99.12,44.53) JDIMM1.26 ; JDIMM1.206 146.12,47.63 v2(146.8,48.31) ; JKBTP1.3 v2(184.51,38.76) ; JDIMM1.15 96.37,55.3 96.67,55.6 v2(97.15,55.6) ; JDIMM2.106 194.92,43.89 195.15,44.12 v2(195.42,44.12) ; JDIMM1.61 107.87,53.22 v2(106.62,51.97) ; JXDP1.49 90.61,135.26 90.66,135.31 v2(90.66,135.35) ; JDIMM2.19 173.17,49.76 172.72,49.31 172.72,49 v2(172.03,48.31) ; v2(96.21,48.18) 96.39,48.18 97.12,47.45 JDIMM1.18 ; 126.57,94.08 UZ26.5 ; v2(222.18,44.86) 222.92,44.12 JDIMM2.210 ; v2(150.38,51.95) 150.37,51.95 JDIMM1.223 ; JDIMM2.10 v2(170.92,41.58) ; v2(274.48,31.69) 274.2,31.97 JNGFF1.7 ; v2(154.12,44.73) JDIMM1.238 ; JDIMM1.68 109.62,44.49 v2(109.64,44.48) ; JDIMM1.5 93.87,52.8 v2(93.13,52.06) ; JNGFF3.1 282.82,27.62 v2(282.78,27.58) 282.32,28.04 JNGFF3.3 ; UC1.BC6 142.35,86.47 v2(142.69,86.13) ; v2(215.06,52.42) 213.48,52.42 213.17,52.12 JDIMM2.171 ; v2(288.09,104.95) 287.47,104.95 287.16,105.25 CL20.2 ; v2(250.12,39.7) 249.99,39.7 249.55,39.25 JSATA1.12 ; v2(108.85,48.51) 108.2,47.86 108.2,47.44 108.62,47.02 JDIMM1.64 ; JDIMM1.78 112.12,44.56 v2(112.14,44.54) ; v2(224.5,41.39) 224.51,41.39 224.92,41.8 JDIMM2.218 ; v2(152,48.2) 152.46,47.74 152.46,47.32 152.12,46.98 JDIMM1.230 ; JDIMM2.243 231.17,49.24 231.66,48.76 v2(231.74,48.76) ; v2(104.89,51.99) 105.37,52.47 JDIMM1.51 ; JDIMM1.30 v2(100.12,44.53) ; v2(187.65,41.52) 187.92,41.79 JDIMM2.78 ; v2(174.27,52.45) 174.17,52.36 JDIMM2.23 ; JLED1.3 308.07,11.37 308.26,11.56 v2(308.26,11.74) ; 149.12,45.12 JDIMM1.218 149.12,47.16 149.22,47.25 149.22,47.8 v2(148.71,48.31) ; JDIMM1.239 154.37,53.08 154.68,52.78 154.68,50.65 v2(154.04,50.01) ; JNGFF3.39 v2(273.32,27.59) ; JDIMM1.47 104.37,52.72 v2(103.32,51.66) ; v2(170.25,48.92) 170.31,48.97 170.31,49.56 170.67,49.93 JDIMM2.9 ; JDIMM1.65 108.87,55.52 v2(108.89,55.54) ; v2(268.86,73.34) 269.08,73.55 JNGFF2.39 ; JKBTP1.15 190.51,38.89 v2(190.51,38.89) ; v2(172.03,44.86) 172.92,43.96 JDIMM2.18 ; JUSH1.21 234.28,39.21 v2(234,38.94) 233.78,39.16 JUSH1.20 ; JDIMM2.27 175.17,49.67 v2(173.96,48.46) ; 150.12,44.85 JDIMM1.222 150.12,49.22 v2(150.4,49.5) ; v2(225.96,45.24) 225.92,45.2 JDIMM2.222 v2(225.92,41.44) ; v2(118.8,44.66) 118.88,44.66 119.12,44.91 JDIMM1.106 ; JDIMM2.5 169.67,49.88 168.85,49.06 168.16,49.06 v2(168.12,49.02) ; v2(187.43,38.87) 187.5,38.95 187.5,39.08 187.51,39.09 JKBTP1.9 ; v2(268.78,30.24) 268.79,30.22 268.79,29.88 268.82,29.84 JNGFF3.57 ; JDIMM2.68 v2(185.42,41.52) ; v2(155.64,50.42) 155.37,50.68 JDIMM1.243 ; v2(227.78,45.03) 226.92,44.17 JDIMM2.226 ; v2(229.99,47.95) 229.17,48.77 JDIMM2.235 ; 232.45,44.37 v2(233.65,45.57) ; v2(117,48.41) 116.12,47.54 JDIMM1.94 116.12,44.72 ; JDIMM2.40 178.42,44.16 177.75,44.83 v2(177.57,44.83) ; JDIMM2.180 v2(215.42,41.52) ; JXDP1.2 76.51,131.9 76.82,132.2 v2(76.82,132.46) ; v2(152.74,108.87) 153.07,109.19 UC1.AJ37 ; JDIMM1.103 118.37,53.17 118.11,52.9 117.3,52.9 v2(116.64,52.25) ; JDIMM2.14 v2(171.92,41.58) ; v2(98.12,44.53) JDIMM1.22 ; JNGFF3.51 v2(270.32,27.64) ; v2(276.27,34.74) 276,34.74 275.7,34.43 JNGFF1.13 ; JDIMM2.102 193.92,41.85 193.6,41.52 v2(192.94,41.52) ; JDIMM2.94 191.92,44.91 v2(192.35,45.34) ; JDIMM2.89 190.67,52.35 v2(190.78,52.45) ; JNGFF3.9 v2(280.82,27.64) ; v2(312.58,117.72) 312.71,117.85 JFPBTN1.8 ; JDIMM2.99 193.17,52.23 192.96,52.45 v2(192.88,52.45) ; 148.12,44.79 JDIMM1.214 ; 107.62,45.02 JDIMM1.60 ; v2(183.61,45.03) 183.07,44.49 183.07,44.01 183.42,43.66 JDIMM2.60 ; JDIMM1.85 113.87,53.05 113.72,52.9 113.72,50.25 v2(114.21,49.76) ; JDIMM2.22 v2(173.92,41.52) ; 192.92,43.99 JDIMM2.98 ; JNGFF2.27 v2(266.08,73.3) ; 157.28,51.87 v2(157.34,51.87) ; v2(283.7,32.37) JNGFF1.45 ; JDIMM2.184 v2(216.42,41.52) ; JDIMM1.180 v2(139.62,44.67)
  BOTTOM w0.356: QZ18.1 280.57,46.22 280.57,46.4 280.19,46.78 v2(279.43,46.78) ; QZ17.4 276.52,45.75 275.66,46.61 v4(272.54,46.61) 271.51,46.61 v2(271.27,46.37) ; v2(265.71,97.38) 265.71,97.36 266.07,97.72 CE20.2 ; QZ17.1 v2(275.55,44.45) ; CE13.2 259.87,92.76 v2(259.77,92.86) ; v2(101.69,51.59) 102.37,52.27 JDIMM1.39 ; RH626.2 239.67,117.08 239.5,117.25 v2(239.14,117.25) ; CI17.2 v2(299.89,61.4) ; DI4.3 v2(300.08,68.43) ; CH68.2 240.83,114.27 240.47,114.63 CH35.2 240.87,114.82 241.01,114.96 v2(241.02,114.96)
  BOTTOM w0.381: CC549.2 129.47,105.7 v2(129.3,105.86) ; CH9.2 254.24,105.56 255.04,105.56 255.42,105.94 v2(255.42,106.7) ; RH326.1 245.35,105.42 246.09,106.16 v2(246.58,106.16) ; RH326.1 RH323.1 ; RH326.1 RC558.2 ; CN2.2 254.25,43.75 254.25,43.32 ; CH346.2 237.07,119.23 RH631.2 236.71,118.69 v2(236.4,118.39) ; CC330.2 v2(209.36,84.02) ; v2(174.18,40.78) 173.65,40.26 PC226.2 PC206.2 ; RH365.2 RH193.2 ; CC303.2 209.57,103.53 209.63,103.59 210.08,103.59 ; v2(242.78,136.32) 243.81,135.29 JSPI1.21 ; JDEG1.11 263.99,64.02 v2(264.16,64.18) ; v2(282.89,74.11) v4(282.28,74.72) 281.49,75.52 RZ1450.2 ; RT64.2 66.36,101.69 v2(66.74,101.32) 67.13,101.71 RT65.2 ; UZ34.3 123.12,97.73 122.61,97.23 121.6,97.23 v2(121.47,97.1) ; v2(210.97,88.04) 210.94,88.04 210.94,88.02 210.96,88 210.1,88 210.04,87.95 RH364.2 ; v2(50.99,111.45) 50.99,111.96 51.19,112.16 RT37.2 ; CT360.2 v2(29.24,124.65) ; RV611.2 294.81,86.32 v2(294.2,86.94) ; 254.25,43.32 253.8,42.87 QN1.1 ; 254.25,43.32 v2(254.27,43.32) ; CT237.2 29.01,117.8 v2(29.01,117.79) ; RH630.2 234.34,117.64 CH345.2 ; PR403.2 198.94,93.68 199.3,93.32 201.02,93.32 201.41,93.7 v2(201.41,94) ; JESPI.12 248.04,77.34 248.85,76.53 v2(248.85,75.51) ; v2(212.02,84.91) CH31.2 212.06,85.51 CC311.2 ; RH634.2 245.87,107.77 v2(246.18,108.09) ; CH555.2 CH267.2 v2(244.53,89.8) ; v2(111.07,100.19) 111.07,100.19 PRZ62.2 ; v2(296.93,46.12) 297.07,46.26 DI6.3 ; RH74.2 209.28,101.8 209.67,101.42 209.67,101.28 v2(209.84,101.1) ; RT503.1 v2(29.24,123.97) ; v2(251.33,40.84) 251.52,40.84 251.9,41.22 QN1.4 ; v2(23.37,101.22) DT39.3 v2(20.96,101.22) ; CC336.2 CC337.2 122.48,102.54 122,102.05 120.76,102.05 v2(119.79,101.08) ; v2(154.44,110.75) 154.44,110.97 154.02,111.39 PRZ39.2 154.02,112.58 RC141.2 ; CI7.2 26.79,90.24 27.17,90.62 CI6.2 ; CC308.2 93.39,129.04 92.07,129.04 91.92,129.19 CC306.2 91.71,129.23 CC32.2 ; v2(126.57,94.08) 126.35,93.85 126.35,93.6 126.34,93.6 CC322.2 ; CH63.2 v2(242.25,114.31) ; v2(18.09,89.67) DI1.3 ; JDIMM1.171 137.37,52.35 v2(138.01,51.71) ; v2(32.63,121.36) 32.44,121.17 UT32.2 ; UT34.3 v2(31.63,123.59) ; CC210.1 126.02,90.27 126.02,90.27 CZ103.2 126.89,90.27 v2(126.93,90.23) ; RT447.1 v2(29.23,123.37) ; RT31.2 33.52,109.36 v2(33.21,109.04) 33.52,108.72 RT32.2 ; CC318.2 v2(228.44,114.65)
  BOTTOM w0.457: CV612.2 296.17,91.1 v2(295.72,91.55) ; v2(295.08,59.7) 295.08,59.94 295.88,60.74 JRTC1.2 ; v2(105.85,132.22) 105.85,132.53 106.23,132.91 JIRTS1.6 ; CT73.2 59.18,111.41 v2(59.37,111.61)
  BOTTOM w0.508: v2(41.84,120.03) 42.42,119.45 UT2.4 ; CLP1.1 53.65,115.39 v2(54.89,116.63) ; v2(309.83,27.82) 309.43,28.22 JSIM1.4 ; RC6.1 RC7.1 178.75,82.33 v2(179.11,82.69) ; JNGFF2.76 258.47,76.83 v2(258.33,76.98) ; CD29.2 121.27,43.83 122.23,43.83 v2(122.42,44.02) ; v2(82.02,104.26) PC805.2 PC800.2 ; v2(69.5,127.36) 69.02,126.88 PC5.2 ; RE716.1 RE718.1 263.33,123.72 262.83,123.72 262.44,123.33 262.44,122.75 v2(262.43,122.74) ; v2(71.68,108.05) 71.58,108.15 71.36,108.15 71.33,108.18 RT99.2 ; JLED1.8 v2(304.62,5.64) ; JFAN1.1 91.82,92.34 92.9,92.34 v2(92.9,92.33) ; v2(130.36,37.73) 130.25,37.84 PR706.2 PC736.2 ; v2(300.79,13.6) 301.66,12.73 JSIM1.7 ; CH14.2 v2(212.28,97.05) ; PC229.2 179.7,40.14 v2(179.26,40.59) 178.75,40.08 PC237.2 ; v2(283.93,26.24) JNGFF3.76 ; PC753.2 PC748.2 118.99,32.64 v2(118.99,33.09) ; v2(288.49,61.59) 288.43,61.53 SW1.5 ; v2(106.44,107.37) 106.44,107.37 PCZ27.1 ; v2(210.54,93.99) YH2.2 ; PC126.2 200.21,40.32 200.27,40.38 v2(200.27,40.71) ; PCZ3.2 95.44,95.2 96.52,95.2 v2(96.64,95.32) ; RT28.2 41.85,118.09 41.47,118.47 v2(41.38,118.47) ; v2(255.71,38.39) 255.71,38.39 255.71,38.4 JSATA1.21 ; PR116.2 PC128.2 v2(197.21,38.54) ; CH345.2 233.98,118.3 234.68,119 v2(234.8,119) ; CZ23.2 CZ24.2 CZ25.2 256.79,79.74 256.86,79.67 v2(256.86,79.42) ; CZ20.2 280.1,84.72 v2(281.62,84.72) ; v2(145.33,128.01) 144.51,127.18 JEDP1.44 ; JFAN1.6 93.65,86.82 v2(93.4,87.07) ; v2(94.74,129.11) 94.67,129.17 CC308.2 ; v2(80.11,103.61) 79.69,103.61 79.67,103.63 79.41,103.63 PR815.2 ; JSIM1.3 315.33,28.22 v2(315.07,27.96) ; PRZ44.2 PCZ24.2 102.12,94.82 102.63,94.31 v2(102.74,94.31) ; PC508.2 PC507.2 270.03,65.83 269.49,65.29 268.78,65.29 ; v2(24.89,88.59) 24.32,89.16 UI1.2 ; v2(289.94,62.61) 290.36,62.19 PC9.2 290.83,62.2 PC2.1 ; v2(98.91,84.04) 98.91,83.69 98.4,83.18 PCT13.2 ; JDIMM1.261 157.97,62.06 v2(156.9,63.13) ; CA12.2 v2(298.2,32.14) CA13.1 ; v2(245.11,110.82) 245.11,110.94 245.13,110.94 245.6,111.42 245.6,111.5 245.61,111.51 CH4.1 ; PCZ34.2 110.95,102.29 v2(111.07,102.16) ; PC3.2 288.37,68.4 v2(287.48,68.4) SW1.4 ; PCA11.2 v2(193.16,117.29) ; v2(300.54,31.32) 299.89,31.97 DA3.1 ; v2(195.92,92.63) 196.15,92.4 PR1648.2 ; PC2212.2 v2(198.17,102.31) 197.72,102.31 197.29,101.88 PR412.1 ; v2(100.74,131.68) 100.89,131.53 JIRTS1.12 ; PC511.2 270.29,60.38 269.99,60.08 267.01,60.08 266.34,60.75 266.34,61.59 PR510.2 ; v2(250.31,109.46) 250.53,109.46 250.68,109.31 CH322.2 ; YT1.2 32.32,95.59 32.83,95.08 v2(33.36,95.08) ; v2(56.73,113.31) 57.08,113.66 57.08,115.28 PJPDC1.6 ; JDIMM2.262 166.73,58.91 v2(166.02,59.62) ; DA1.1 v2(300.6,36.65) ; JUSH1.28 222.33,35.54 v2(222.69,35.18) ; v2(106.5,94.41) 106.5,94.97 PCZ30.2 ; RC438.2 RC114.2 v2(126.47,99.2) ; PJPDC1.7 57.03,127.53 v2(55.49,125.99) ; v2(294.95,55.19) 294.34,55.8 JRTC1.3 ; v2(284.54,76.85) 283.4,76.85 282.93,77.31 CZ26.2 ; v2(277.02,86.5) 277.02,85.33 CZ19.2 CZ18.2 ; v2(20.72,87.93) CI46.2 CI45.2 ; RE86.2 255.07,64.88 254.57,65.39 254.57,66.3 255.33,67.07 255.69,67.07 v2(255.85,67.22) ; v2(73.78,109.67) CLP2.1 ; PCZ33.2 110.82,99.3 v2(111.07,99.56) ; v2(128.39,31.01) 128.39,31.2 PR725.2 ; v2(121.47,97.1) 121.27,97.31 CZ104.2 ; JSPK1.6 287.22,22.28 288.16,21.35 v2(290.06,21.35) ; CI6.2 28.32,90.62 v2(28.57,90.88) ; v2(248.6,99.32) 248.09,98.82 UC5.4 ; CH13.2 v2(212.28,94.36) ; PC401.2 194.95,99.58 v2(195.26,99.58) ; JUSH1.27 239.63,36.64 v2(240.09,37.09) ; PCA9.2 198.99,121.3 v2(198.37,121.3) ; JRTC1.4 302.81,57.84 v2(303.08,58.11) ; PCT11.2 v2(96.23,85.51) ; PCH20.2 v2(183.02,133.16) ; CV1641.2 301.57,85 CV620.2 v2(300.44,84.99) ; JKBTP1.22 v2(181.56,34.81) ; RT36.2 34.99,118.15 v2(35.37,118.53) 35.37,118.47 35.75,118.09 RT25.2 ; PC111.1 241.98,47.94 v2(241.74,47.7) ; v2(177.43,82.5) 177.03,82.1 RC5.1 ; CC316.2 248.85,83.36 v2(248.57,83.64) ; v2(35.09,96.57) 35.02,96.65 CT20.2 ; PC811.2 74.86,111.83 74.35,111.33 v2(74.35,111.04) ; RT124.2 44.13,118.28 v2(44.26,118.4) ; v2(126.17,31.06) PC749.2 126.16,31.73 PC750.2 ; PR206.2 v2(177.54,40.96) ; v2(211.39,88.53) RH365.2 ; PC207.2 v2(175,41.29) ; v2(263.23,29.87) JNGFF3.77 ; v2(110.87,104.15) 110.28,104.15 PCZ31.2 ; PC755.2 v2(123.54,31.02) ; CH341.2 239.14,116.74 v2(239.14,117.25) ; JIRTS1.7 105.53,133.38 105.53,132.53 v2(105.85,132.22) ; CC320.2 231.26,121.08 v2(231.54,121.36) ; UC5.9 249.99,100.09 v2(250.06,100.02) ; PR842.2 74.91,113.87 v2(74.1,113.87) ; JNGFF1.76 v2(271.6,32.47) ; v2(278.55,77.08) 279.17,76.46 JNGFF2.77 ; v2(96.09,103.81) 96.09,103.81 PCZ8.2 ; CC568.1 127.4,93.97 v2(127.22,94.14) ; JSIM1.9 316.17,14.03 v2(315.53,14.68) ; CZ198.2 260.18,85.49 v2(259.83,85.84) ; JSATA1.22 v2(255.62,34.4) ; CH5.1 245.42,114.45 v2(244.94,113.97) ; RC179.2 RC178.2 178.81,112.15 v2(178.87,112.21) ; v2(71.98,102.65) 71.98,103.42 71.47,103.92 CT77.2 ; CC324.2 125.09,103.17 124.45,103.17 CC336.2 ; JSPK1.5 297.75,23.23 297.98,23.01 v2(298.32,23.01) ; CT85.2 v2(69.29,113.42) ; v2(126.53,106.88) 127.19,106.88 127.81,106.26 RC319.1 ; v2(126.55,104.7) 127.44,103.81 RC136.2 128.18,103.27 CC300.2 ; UC6.4 248.53,87.87 249.04,88.38 v2(249.3,88.38) ; JSATA1.24 242.99,40.69 v2(242.94,40.75) ; CT70.2 62.16,98.18 61.59,98.75 UT6.4 59.94,98.75 59.43,99.26 v2(59.43,100.21) ; v2(254.12,99.17) 254.28,99.02 CE54.2 ; RT103.2 71.38,112.02 71.66,111.74 v2(71.67,111.74) ; PC738.2 120.03,38.71 119.92,38.71 119.89,38.68 v2(119.76,38.68) ; PR817.2 77.33,104.87 PC804.2 77.3,105.23 76.79,105.74 v2(76.6,105.74) ; PC726.2 v2(124.52,43.7) ; PR843.2 PC812.2 v2(78.54,114.44) ; JDEG1.12 257.81,63.43 258.05,63.19 261.41,63.19 261.62,63.4 261.62,63.64 v2(261.63,63.65) ; PCH48.2 v2(170.22,132.96) ; v2(201.8,40.71) 202.1,40.41 PC137.2 ; PCH21.2 v2(179.89,133.68) ; v2(286.01,94.88) 285.98,94.85 285.03,94.85 283.98,93.8 CV623.2 ; CC301.2 v2(179.33,89.49) ; JFAN1.5 87.39,89.22 91.12,85.49 v2(91.13,85.49) ; JEDP1.45 v2(146.66,127.04) ; JIRTS1.11 v2(111.53,130.06) ; v2(35.11,98.35) 35.03,98.43 CT21.2 ; v2(72.07,106.37) CT75.2 CT76.2 ; PC801.1 v2(80.32,114.37) ; RT33.2 RT184.2 38.8,120.35 v2(38.92,120.47) ; JLED1.7 v2(311.02,9.09) ; JSIM1.C5 v2(317.36,24.83) ; v2(133,127.2) 133.02,127.18 JEDP1.43 ; v2(128.12,42.81) 127.93,42.62 PC725.2 ; v2(29.46,97.05) 29.46,97.12 YT1.4 ; JSIM1.8 v2(309.75,11.33) ; v2(46.45,118.44) 46.42,118.44 RT125.2 ; v2(209.44,97.1) YH2.4 ; RV38.2 294.21,87.76 v2(294.24,87.73) ; PCZ32.2 v2(110.82,104.95) ; PC119.2 v2(201.16,40.71) ; v2(95.05,105.29) 95.66,104.69 PRZ24.1 96.69,104.69 PCZ12.1 ; v2(238.11,58.12) 237.99,58.12 237.2,58.91 JDIMM2.261 ; CT56.2 v2(28.29,112.33) ; v2(49.45,100.05) 49.45,97.92 CLP4.1 ; CV624.2 v2(303.84,91.37) ; CT86.2 v2(65.95,114.32) ; PRZ82.2 PHZ4.2 PCH27.2 v2(155.63,127.84) ; v2(199,102.31) PR1708.2 199,101.69 PR415.2 ; CH45.2 211.39,91.51 211.33,91.46 v2(210.89,91.46) 210.89,92.09 211.4,92.59 RH435.1 ; v2(243.51,35.54) 242.99,35.02 JSATA1.23 ; v2(300.48,25.41) 300.34,25.54 JSIM1.5 ; RI69.1 78.98,102.41 79.02,102.37 v2(79.31,102.37) ; PCA8.2 v2(195.31,119.95) ; JSIM1.6 v2(299.56,14.06) ; v2(242.48,45.41) PR103.2 ; CV613.2 CV609.2 ; v2(190.56,133.55) PCH44.2
  vias: v2(0.43,112.58) v2(0.43,110.04) v2(0.43,108.77) v2(0.43,107.5) v2(0.43,106.23) v2(0.43,104.96) v2(0.43,101.71) v2(0.43,83.08) v2(1.12,79.5) v2(1.41,77.43) v2(1.66,113.57) v2(1.67,101.48) v2(1.8,83.47) v2(2.07,81.15) v2(2.07,77.85) v2(2.68,77.43) v2(2.93,113.57) v2(2.94,101.48) v2(3.07,83.47) v2(3.7,100.43) v2(3.7,99.16) v2(3.73,97.95) v2(3.98,81.15) v2(3.98,77.85) v2(4.2,113.57) v2(4.34,83.47) v2(4.93,79.5) v2(5,97.95) v2(5.47,113.57) v2(5.61,83.47) v2(6.49,77.43) v2(6.74,113.57) v2(7.68,77.88) v2(8.01,113.57) v2(8.5,102.18) v2(8.82,78.41) v2(9.14,83.2) v2(9.27,98.23) v2(9.28,113.57) v2(9.98,78.95) v2(10.41,83.17) v2(10.55,113.57) v2(10.54,98.24) v2(11.13,79.49) v2(11.68,83.17) v2(11.82,113.57) v2(11.81,98.24) v2(12.29,80.02) v2(12.88,82.68) v2(13.14,98.73) v2(13.44,80.56) v2(14.02,112.4) v2(14,97.84) v2(14,96.57) v2(14.01,84.74) v2(13.99,83.47) v2(14.59,81.09) v2(14.97,114.05) v2(14.97,110.75) v2(15.74,81.63) v2(16.05,114.57) v2(16.11,101.85) v2(16.88,114.05) v2(16.88,110.75) v2(16.89,82.17) v2(17.83,112.4) v2(18.04,82.7) v2(18.16,93.74) v2(18.16,93.1) v2(18.28,98.88) v2(18.28,98.24) v2(18.28,97.61) v2(18.47,92.47) v2(18.47,91.83) v2(18.59,114.57) v2(19.2,83.24) v2(19.28,102.96) v2(19.86,114.57) v2(20.35,83.77) v2(21.13,114.57) v2(21.5,84.31) v2(22.4,114.57) v2(22.65,84.84) v2(22.79,91.32) v2(23.67,114.57) v2(23.8,85.38) v2(24.7,115.31) v2(24.95,85.91) v2(25.56,116.24) v2(26.09,101.29) v2(26.11,86.45) v2(26.43,117.18) v2(27.26,86.98) v2(27.29,118.11) v2(27.96,126.82) v2(27.96,125.55) v2(27.96,124.28) v2(27.96,123.01) v2(27.96,121.74) v2(27.96,120.47) v2(27.96,119.2) v2(28.29,113.36) v2(28.41,87.52) v2(28.7,103.52) v2(28.7,101.53) v2(29.25,126.87) v2(29.56,88.05) v2(30.52,126.87) v2(30.71,88.59) v2(31.79,126.87) v2(31.86,89.12) v2(31.94,103.39) v2(31.94,101.99) v2(33.06,126.87) v2(33.02,89.66) v2(33.14,104.79) v2(33.21,106.06) v2(34.17,90.19) v2(34.33,126.87) v2(34.4,101.7) v2(34.78,101.22) v2(35.32,90.73) v2(35.6,126.87) v2(36,108.53) v2(36.32,101.23) v2(36.44,101.86) v2(36.47,91.26) v2(36.87,126.87) v2(37.27,97.19) v2(37.62,91.81) v2(38.14,126.87) v2(38.39,109.2) v2(38.39,107.9) v2(38.41,106.6) v2(38.41,105.95) v2(38.41,105.3) v2(38.78,98.74) v2(38.78,92.32) v2(39.04,107.9) v2(39.04,97.18) v2(39.41,126.87) v2(39.96,92.78) v2(40.35,111.13) v2(40.57,101.18) v2(40.68,126.87) v2(40.99,105.95) v2(40.99,104) v2(40.99,103.35) v2(41.16,93.2) v2(41.27,98.94) v2(41.22,97.24) v2(41.64,109.85) v2(41.95,126.87) v2(42.38,93.57) v2(42.94,103.35) v2(43.01,97.26) v2(43.11,98.94) v2(43.22,126.87) v2(43.59,111.13) v2(43.61,93.9) v2(44.49,126.87) v2(44.76,97.26) v2(44.84,94.18) v2(44.89,103.36) v2(45.76,126.87) v2(46.09,94.41) v2(46.37,98.78) v2(46.53,97.23) v2(47.03,126.87) v2(47.35,94.6) v2(48.3,126.87) v2(48.61,94.74) v2(49.57,126.87) v2(49.88,94.83) v2(50.16,100.05) v2(50.48,109.96) v2(50.84,126.87) v2(50.94,107.68) v2(51.15,94.88) v2(52.07,102.34) v2(52.11,126.87) v2(52.39,104.12) v2(52.42,94.88) v2(52.64,105.17) v2(52.71,109.23) v2(53.37,127.04) v2(53.69,94.88) v2(54.27,127.93) v2(54.22,103.68) v2(54.96,129.01) v2(54.96,94.86) v2(55.13,130.57) v2(55.11,125.49) v2(56.2,109.13) v2(56.22,94.79) v2(56.36,110.92) v2(57.16,105.92) v2(57.28,108.97) v2(57.28,108.33) v2(57.49,94.67) v2(58.75,94.51) v2(58.95,130.57) v2(60,94.3) v2(60.22,130.57) v2(61.24,94.04) v2(61.49,130.57) v2(61.94,115.36) v2(62.48,93.74) v2(62.76,130.57) v2(63.7,93.39) v2(63.96,136.5) v2(63.97,134.88) v2(64.03,130.57) v2(64.69,117.63) v2(64.69,117.04) v2(64.9,92.99) v2(65.09,134.21) v2(65.27,117.63) v2(65.27,117.04) v2(65.28,136.57) v2(65.3,130.58) v2(65.31,119.33) v2(65.9,119.33) v2(66.1,92.55) v2(66.55,136.57) v2(67.27,92.06) v2(67.62,134) v2(68.42,91.54) v2(68.57,135.65) v2(69.1,136.57) v2(69.56,90.96) v2(69.73,118.18) v2(69.73,117.6) v2(69.73,117.02) v2(69.99,137.56) v2(70.12,98.64) v2(70.32,118.18) v2(70.32,117.6) v2(70.32,117.02) v2(70.48,135.65) v2(70.67,90.35) v2(70.89,117.09) v2(71.12,98.05) v2(71.27,137.57) v2(71.76,89.7) v2(72.17,136.37) v2(72.16,31.81) v2(72.16,30.54) v2(72.16,29.27) v2(72.54,137.57) v2(72.82,89) v2(72.81,32.9) v2(72.88,135.05) v2(73.01,135.96) v2(73.28,28.68) v2(73.86,88.27) v2(73.85,33.63) v2(73.89,137.56) v2(74.55,28.68) v2(74.87,87.49) v2(74.86,34.4) v2(75.06,100.45) v2(75.06,99.33) v2(75.06,98.21) v2(75.08,137.57) v2(75.84,86.68) v2(75.85,35.22) v2(75.82,28.68) v2(76.18,100.45) v2(76.18,99.33) v2(76.18,98.21) v2(76.35,137.57) v2(76.79,85.84) v2(76.78,36.06) v2(77.09,28.68) v2(77.3,100.45) v2(77.3,99.33) v2(77.3,98.21) v2(77.4,111.2) v2(77.62,137.57) v2(77.71,84.96) v2(77.7,36.94) v2(78.36,28.68) v2(78.59,84.04) v2(78.58,37.85) v2(78.89,137.57) v2(79.43,83.1) v2(79.43,38.8) v2(79.63,28.68) v2(80.16,137.57) v2(80.25,82.12) v2(80.24,39.77) v2(80.9,28.68) v2(81.02,81.11) v2(81.01,40.78) v2(81.43,137.57) v2(81.66,99.38) v2(81.75,80.08) v2(81.75,41.82) v2(82.17,28.68) v2(82.45,79.01) v2(82.45,42.88) v2(82.7,137.57) v2(83.11,77.93) v2(83.1,43.96) v2(83.44,28.68) v2(83.72,76.82) v2(83.72,45.08) v2(83.97,137.57) v2(84.29,75.68) v2(84.29,46.21) v2(84.71,28.68) v2(84.83,74.52) v2(84.82,47.36) v2(85.24,137.57) v2(85.31,73.35) v2(85.31,48.54) v2(85.75,72.16) v2(85.75,49.73) v2(85.98,28.68) v2(86.15,70.95) v2(86.15,50.93) v2(86.15,35.89) v2(86.15,35.3) v2(86.15,34.72) v2(86.15,34.14) v2(86.32,136.89) v2(86.5,69.73) v2(86.5,52.15) v2(86.74,35.89) v2(86.74,35.3) v2(86.74,34.72) v2(86.74,34.14) v2(86.81,68.51) v2(86.81,53.39) v2(87.07,67.26) v2(87.07,54.63) v2(87.28,66.01) v2(87.28,55.88) v2(87.32,35.89) v2(87.32,35.3) v2(87.32,34.72) v2(87.32,34.14) v2(87.45,64.75) v2(87.44,57.14) v2(87.55,136.57) v2(87.56,63.49) v2(87.56,58.4) v2(87.64,62.22) v2(87.66,60.95) v2(87.64,59.67) v2(87.9,35.89) v2(87.9,35.3) v2(87.9,34.72) v2(87.9,34.14) v2(87.9,28.69) v2(88.18,36.71) v2(88.48,35.11) v2(88.48,34.53) v2(88.77,36.71) v2(88.82,136.57) v2(89.06,35.11) v2(89.35,36.71) v2(89.64,35.11) v2(89.94,36.71) v2(90.09,136.57) v2(90.52,36.71) v2(91,137.56) v2(91.11,36.71) v2(91.69,36.71) v2(92.27,137.57) v2(92.27,36.71) v2(92.86,36.71) v2(93.05,48.08) v2(93.44,36.71) v2(93.54,137.57) v2(93.58,35.13) v2(93.93,135.78) v2(94.03,36.71) v2(94.14,47.28) v2(94.17,35.13) v2(94.36,34.55) v2(94.52,135.78) v2(94.61,36.71) v2(94.7,49.72) v2(94.75,35.13) v2(94.81,137.57) v2(94.99,34.43) v2(95.1,135.78) v2(95.27,36.14) v2(95.27,35.56) v2(95.33,34.94) v2(95.37,33.98) v2(95.38,28.68) v2(96.08,137.57) v2(96.2,98.44) v2(96.2,96.41) v2(96.2,91.18) v2(96.2,90.6) v2(96.2,90.02) v2(96.22,89.43) v2(96.23,49.93) v2(96.29,97.35) v2(96.59,32.2) v2(96.59,31.62) v2(96.65,28.68) v2(97.18,32.2) v2(97.18,31.62) v2(97.35,137.57) v2(97.71,127.77) v2(97.71,127.19) v2(97.92,28.68) v2(98.01,49.76) v2(98.03,48.01) v2(98.29,127.39) v2(98.29,126.81) v2(98.62,137.57) v2(99.19,28.68) v2(99.89,137.57) v2(99.94,48.39) v2(100.46,28.68) v2(101.16,137.57) v2(101.12,85.88) v2(101.41,103.23) v2(101.41,101.11) v2(101.41,98.99) v2(101.67,50.06) v2(101.73,28.68) v2(102.07,70.53) v2(102.27,88.85) v2(102.27,87.56) v2(102.27,86.26) v2(102.43,137.57) v2(102.65,70.53) v2(102.85,92.44) v2(102.85,91.81) v2(102.96,55.4) v2(103,28.68) v2(103.12,89.5) v2(103.24,70.53) v2(103.3,50.04) v2(103.44,92.28) v2(103.44,91.64) v2(103.44,91.01) v2(103.44,90.31) v2(103.53,103.23) v2(103.53,101.11) v2(103.53,98.99) v2(103.48,85.41) v2(103.7,137.57) v2(103.83,88.85) v2(103.83,87.56) v2(103.83,86.26) v2(104.27,28.68) v2(104.97,137.57) v2(104.94,49.3) v2(105.48,136.75) v2(105.54,28.68) v2(105.65,103.23) v2(105.65,101.11) v2(106.42,90.31) v2(106.42,89.67) v2(106.64,50.42) v2(106.62,48.77) v2(106.74,136.57) v2(106.81,28.68) v2(107.12,90.31) v2(107.12,89.67) v2(108.01,136.57) v2(108.08,28.68) v2(108.96,95.26) v2(108.96,94.63) v2(108.91,50.37) v2(109.28,136.57) v2(109.28,36.9) v2(109.35,28.68) v2(109.55,95.27) v2(109.55,94.64) v2(109.86,36.9) v2(110.35,47.33) v2(110.55,136.57) v2(110.49,36.9) v2(110.62,28.68) v2(110.9,34.81) v2(110.9,33.5) v2(110.9,32.18) v2(111.03,30.27) v2(111.25,29.73) v2(111.62,30.25) v2(111.82,136.57) v2(111.91,34.81) v2(111.91,33.5) v2(111.91,32.18) v2(111.88,29.73) v2(111.89,28.68) v2(111.98,30.87) v2(112.33,30.24) v2(112.64,29.73) v2(112.92,34.81) v2(112.92,33.5) v2(112.92,32.18) v2(112.92,30.87) v2(113.03,30.24) v2(113.09,136.57) v2(113.16,28.68) v2(113.19,126.87) v2(113.37,128.85) v2(113.34,128.09) v2(114,137.56) v2(114.23,55.7) v2(114.43,28.68) v2(114.74,50.56) v2(115.27,137.57) v2(115.7,28.68) v2(116.54,137.57) v2(116.71,50.43) v2(116.77,49.54) v2(116.84,51.38) v2(116.97,28.68) v2(117.02,110.52) v2(117.02,85.52) v2(117.81,137.57) v2(117.91,51.57) v2(117.91,50.18) v2(118.17,29.73) v2(118.2,30.85) v2(118.24,28.68) v2(118.32,112.77) v2(118.32,108.27) v2(118.32,87.77) v2(118.32,83.27) v2(118.36,35.82) v2(118.36,35.24) v2(118.36,34.66) v2(118.42,30.3) v2(118.8,30.82) v2(118.8,29.73) v2(119.06,30.3) v2(119.08,137.57) v2(119.44,29.79) v2(119.51,28.68) v2(119.7,30.31) v2(120.07,29.79) v2(120.35,137.57) v2(120.84,126.72) v2(120.78,28.68) v2(120.93,112.77) v2(120.93,108.27) v2(120.93,87.77) v2(120.93,83.27) v2(121.14,131.49) v2(121.19,129.46) v2(121.27,128.04) v2(121.25,50.14) v2(121.3,48.49) v2(121.62,137.57) v2(122.05,28.68) v2(122.13,126.82) v2(122.23,110.52) v2(122.23,85.52) v2(122.89,137.57) v2(123.32,28.68) v2(123.38,50.21) v2(123.38,48.59) v2(123.63,37.88) v2(123.63,35.65) v2(124.16,137.57) v2(124.2,128.28) v2(124.4,129.21) v2(124.59,28.68) v2(124.75,37.88) v2(124.75,36.76) v2(124.75,35.65) v2(125.32,136.89) v2(125.29,48.77) v2(125.42,50.4) v2(125.87,37.88) v2(125.87,35.65) v2(125.86,28.68) v2(126.55,136.57) v2(126.9,49.04) v2(127.13,28.68) v2(127.82,136.57) v2(128.4,28.68) v2(128.71,50.02) v2(129.09,136.57) v2(129.96,137.49) v2(130.31,29.35) v2(130.54,95.18) v2(130.57,51.1) v2(130.57,49.48) v2(130.55,47.62) v2(130.6,97.54) v2(130.71,99.21) v2(130.7,84.86) v2(130.84,137.57) v2(130.85,89.12) v2(131.15,83.93) v2(131.21,30.25) v2(131.79,87.84) v2(131.88,90.67) v2(132.11,137.57) v2(132.12,47.34) v2(132.11,31.15) v2(132.25,48.97) v2(132.62,99.21) v2(132.98,79.49) v2(133.02,32.03) v2(133.26,55.97) v2(133.38,137.57) v2(133.98,81) v2(134.09,51.08) v2(134.15,49.39) v2(134.12,32.67) v2(134.65,137.57) v2(135.37,82.18) v2(135.37,32.93) v2(135.87,40) v2(135.92,137.57) v2(135.91,39.39) v2(135.99,80.16) v2(136.3,78.39) v2(136.48,40) v2(136.5,39.39) v2(136.58,124.79) v2(136.62,32.78) v2(136.82,81.11) v2(137.08,40.03) v2(137.08,39.39) v2(137.19,137.57) v2(137.19,80.01) v2(137.66,40.03) v2(137.66,39.39) v2(137.77,32.23) v2(138.06,50.19) v2(138.14,48.39) v2(138.25,40.64) v2(138.25,40.03) v2(138.26,39.39) v2(138.46,137.57) v2(138.71,31.38) v2(138.83,40.64) v2(138.83,40.03) v2(138.84,39.39) v2(138.99,79.67) v2(139.11,119.32) v2(139.26,80.72) v2(139.42,40.64) v2(139.42,40.03) v2(139.43,39.39) v2(139.61,30.48) v2(139.73,137.57) v2(139.79,52.25) v2(140,40.64) v2(140,40.03) v2(140.01,39.39) v2(140.1,79.07) v2(140.51,29.58) v2(140.95,96.64) v2(140.95,96.06) v2(141,137.57) v2(140.98,119.3) v2(141.34,80.62) v2(141.47,51.66) v2(141.47,48.31) v2(141.4,28.69) v2(141.6,44.67) v2(142.27,137.57) v2(142.62,44.67) v2(143.12,119.15) v2(143.19,28.68) v2(143.37,48.44) v2(143.54,137.57) v2(143.48,51.79) v2(144.46,28.68) v2(144.53,78.75) v2(144.81,137.57) v2(144.85,118.13) v2(145.16,84.77) v2(145.19,83.54) v2(145.22,82.96) v2(145.2,50.01) v2(145.3,80.39) v2(145.73,28.68) v2(145.89,81.97) v2(146.08,137.57) v2(146.46,55.56) v2(146.83,51.61) v2(146.8,49.93) v2(147,28.68) v2(147.35,137.57) v2(147.4,93.6) v2(147.61,35.76) v2(147.61,33.83) v2(147.76,93.16) v2(147.89,92.52) v2(147.96,77.59) v2(148.27,28.68) v2(148.39,92.78) v2(148.62,137.57) v2(148.7,125.9) v2(148.68,51.51) v2(148.73,49.86) v2(148.75,35.76) v2(148.75,33.83) v2(149.24,55.65) v2(149.28,125.93) v2(149.54,28.68) v2(149.89,137.57) v2(150.8,103.27) v2(150.81,28.68) v2(151.16,137.57) v2(151.93,82.05) v2(152.08,28.68) v2(152.43,137.57) v2(152.61,93.04) v2(153.17,93.04) v2(153.16,81.32) v2(153.17,79.5) v2(153.2,77.61) v2(153.28,103.21) v2(153.35,28.68) v2(153.7,137.57) v2(153.75,93.04) v2(154.31,93.04) v2(154.62,28.68) v2(154.81,116.85) v2(154.97,137.57) v2(155.19,117.36) v2(155.51,116.85) v2(155.73,81.12) v2(155.74,47.95) v2(155.82,117.36) v2(155.89,28.68) v2(156.1,88.75) v2(156.23,137.57) v2(156.27,116.85) v2(157.16,28.68) v2(157.39,50.17) v2(157.47,48.41) v2(157.49,138.76) v2(157.88,81.04) v2(158.11,127.39) v2(158.3,39.06) v2(158.49,38.49) v2(158.75,138.77) v2(159.81,126.18) v2(160.02,138.77) v2(160.21,116.85) v2(160.28,128.54) v2(160.52,117.42) v2(160.66,127.4) v2(160.66,125.83) v2(160.9,116.85) v2(161.22,117.42) v2(161.29,138.77) v2(161.44,95.5) v2(161.46,94.56) v2(161.83,138.34) v2(161.82,38.66) v2(161.95,127.4) v2(161.95,125.83) v2(162.24,28.69) v2(162.4,38.66) v2(162.81,137.57) v2(162.99,38.66) v2(163.25,127.4) v2(163.25,125.83) v2(163.57,38.66) v2(163.51,28.68) v2(163.72,78.11) v2(163.9,126.54) v2(164.01,49.82) v2(164,49.12) v2(164,48.49) v2(164.08,137.57) v2(164.59,126.69) v2(164.59,125.55) v2(164.65,116.85) v2(164.78,28.68) v2(164.9,126.12) v2(164.9,117.42) v2(165.22,126.69) v2(165.22,125.55) v2(165.35,137.57) v2(165.29,116.85) v2(165.54,126.12) v2(165.54,117.42) v2(165.86,126.69) v2(165.86,125.55) v2(165.92,116.85) v2(166.05,28.68) v2(166.09,128.09) v2(166.09,127.45) v2(166.17,126.12) v2(166.42,94.46) v2(166.49,126.69) v2(166.49,125.55) v2(166.49,97.58) v2(166.5,96.93) v2(166.5,96.29) v2(166.5,95.66) v2(166.5,95.05) v2(166.62,137.57) v2(166.62,130.5) v2(166.74,92.22) v2(166.81,126.12) v2(166.82,78.49) v2(166.9,129.73) v2(166.92,129.14) v2(166.92,128.56) v2(167,132.92) v2(167,131.77) v2(167.13,126.69) v2(167.1,81.09) v2(167.22,130.5) v2(167.18,125.6) v2(167.32,28.68) v2(167.44,126.12) v2(167.41,113.67) v2(167.51,127.96) v2(167.51,127.26) v2(167.58,132.92) v2(167.64,131.77) v2(167.76,126.69) v2(167.83,125.55) v2(167.89,137.57) v2(168.14,126.12) v2(168.21,127.39) v2(168.45,79.74) v2(168.59,28.68) v2(169.16,137.57) v2(169.17,113.67) v2(169.85,126.17) v2(169.86,28.68) v2(170.18,116.85) v2(170.23,46.12) v2(170.32,128.53) v2(170.43,137.57) v2(170.43,117.42) v2(170.7,127.39) v2(170.7,125.82) v2(170.81,116.85) v2(171.06,117.42) v2(171.13,130.57) v2(171.13,28.68) v2(171.7,137.57) v2(171.76,112.75) v2(172,127.39) v2(172,125.82) v2(172.4,28.68) v2(172.68,110.98) v2(172.97,137.57) v2(172.98,113.5) v2(173.29,127.39) v2(173.29,125.82) v2(173.67,28.68) v2(173.94,126.53) v2(173.94,46.66) v2(174.24,137.57) v2(174.56,126.25) v2(174.62,127.39) v2(174.87,126.82) v2(174.81,125.68) v2(174.94,31.57) v2(174.94,28.68) v2(175.1,106.91) v2(175.26,127.39) v2(175.19,126.25) v2(175.45,125.68) v2(175.43,109.53) v2(175.51,137.57) v2(175.51,126.82) v2(175.69,104.14) v2(175.72,88.99) v2(175.7,31.89) v2(175.83,126.25) v2(175.83,32.65) v2(175.89,127.39) v2(176,87.75) v2(176.14,126.82) v2(176.08,125.68) v2(176.08,31.38) v2(176.21,28.68) v2(176.31,109.04) v2(176.32,101.47) v2(176.33,31.95) v2(176.46,126.25) v2(176.53,127.39) v2(176.63,106.6) v2(176.72,125.68) v2(176.78,137.57) v2(176.78,130.95) v2(176.78,130.31) v2(176.78,129.68) v2(176.78,126.82) v2(176.88,32.18) v2(177.1,126.25) v2(177.16,109.55) v2(177.2,129.06) v2(177.21,128.41) v2(177.21,127.77) v2(177.29,127.14) v2(177.41,130.95) v2(177.43,36.34) v2(177.57,88.8) v2(177.48,28.68) v2(177.82,87.65) v2(177.91,106.56) v2(178.05,137.57) v2(178.49,35.95) v2(178.66,84.34) v2(178.75,86.86) v2(178.73,86.15) v2(178.75,28.68) v2(179.08,35.95) v2(179.32,137.57) v2(179.64,35.13) v2(179.66,31.94) v2(179.78,126.24) v2(179.9,34.6) v2(180.02,28.68) v2(180.22,35.13) v2(180.21,32.14) v2(180.59,137.57) v2(180.63,127.46) v2(180.63,125.9) v2(181.03,130.58) v2(181.02,110.52) v2(181.02,85.52) v2(181.29,28.68) v2(181.86,137.57) v2(181.93,127.46) v2(181.93,125.9) v2(182.32,112.77) v2(182.32,108.27) v2(182.32,87.77) v2(182.32,83.27) v2(182.56,28.68) v2(182.79,106.28) v2(183.05,97.04) v2(183.13,137.57) v2(183.22,127.46) v2(183.22,125.9) v2(183.37,99.77) v2(183.64,97.04) v2(183.72,48.46) v2(183.87,126.6) v2(183.83,28.68) v2(183.95,99.77) v2(184.02,106.28) v2(184.4,137.57) v2(184.46,127.07) v2(184.46,126.44) v2(184.46,125.8) v2(184.46,125.17) v2(184.78,127.71) v2(184.93,112.77) v2(184.93,108.27) v2(184.93,87.77) v2(184.93,83.27) v2(185.06,106.33) v2(185.1,127.07) v2(185.1,126.44) v2(185.1,125.8) v2(185.1,125.17) v2(185.16,78.51) v2(185.1,28.68) v2(185.34,44.95) v2(185.42,127.71) v2(185.48,128.34) v2(185.67,137.57) v2(185.67,129.55) v2(185.67,128.92) v2(185.64,106.33) v2(185.73,127.07) v2(185.73,126.44) v2(185.73,125.8) v2(185.73,125.17) v2(185.75,78.51) v2(186.11,128.34) v2(186.11,127.71) v2(186.23,110.52) v2(186.23,85.52) v2(186.37,130.88) v2(186.37,127.07) v2(186.37,126.44) v2(186.37,125.8) v2(186.37,125.17) v2(186.33,78.51) v2(186.37,28.68) v2(186.75,130.38) v2(186.94,137.57) v2(187.07,130.88) v2(187.02,47.55) v2(187.19,126.18) v2(187.32,136.89) v2(187.33,78.56) v2(187.64,28.68) v2(187.76,130.88) v2(188.4,96.21) v2(188.54,136.57) v2(188.91,28.68) v2(189.16,107.52) v2(189.23,111.58) v2(189.29,119.64) v2(189.29,119.06) v2(189.29,118.44) v2(189.29,117.8) v2(189.43,126.31) v2(189.82,136.57) v2(189.9,128.67) v2(189.92,111.58) v2(190.24,120.91) v2(190.24,120.28) v2(190.18,28.68) v2(190.28,127.53) v2(190.28,125.97) v2(190.37,107.52) v2(190.4,121.48) v2(190.75,130.69) v2(190.75,111.58) v2(190.88,120.91) v2(191.09,136.57) v2(191.45,28.68) v2(191.57,127.53) v2(191.57,125.97) v2(191.64,85.61) v2(191.64,84.97) v2(191.64,84.34) v2(191.64,83.64) v2(191.73,111.61) v2(191.7,107.52) v2(192,137.56) v2(192.27,84.34) v2(192.25,83.64) v2(192.31,86.31) v2(192.31,85.61) v2(192.31,84.98) v2(192.62,78.51) v2(192.68,133.8) v2(192.72,28.68) v2(192.87,127.53) v2(192.87,125.97) v2(192.91,107.52) v2(192.95,86.31) v2(192.95,85.61) v2(192.95,84.98) v2(192.88,84.37) v2(192.91,83.64) v2(193,111.61) v2(193.27,137.57) v2(193.52,126.67) v2(193.66,90.75) v2(193.92,45.79) v2(193.99,47.25) v2(193.99,28.68) v2(194.11,127.33) v2(194.11,126.69) v2(194.11,126.06) v2(194.24,107.52) v2(194.24,90.75) v2(194.47,33.75) v2(194.54,137.57) v2(194.5,33.12) v2(194.69,32.52) v2(194.81,126.69) v2(194.81,126.06) v2(194.88,124.34) v2(195.07,124.91) v2(195.05,33.73) v2(195.08,33.12) v2(195.15,32.08) v2(195.18,31.46) v2(195.26,28.68) v2(195.32,125.55) v2(195.38,126.38) v2(195.45,117.1) v2(195.51,107.52) v2(195.51,34.87) v2(195.64,33.73) v2(195.66,33.14) v2(195.7,124.6) v2(195.74,32.08) v2(195.76,31.49) v2(195.81,137.57) v2(195.86,125.16) v2(195.89,134) v2(195.89,133.23) v2(195.96,125.87) v2(195.89,96.05) v2(196.02,87.01) v2(196.1,126.43) v2(196.25,95.51) v2(196.34,124.6) v2(196.34,32.08) v2(196.35,31.49) v2(196.48,96.05) v2(196.53,28.68) v2(196.59,125.87) v2(196.59,125.17) v2(196.73,126.43) v2(196.78,107.52) v2(196.83,95.51) v2(196.97,48.27) v2(196.97,46.75) v2(197.04,124.6) v2(197.08,137.57) v2(197.09,115.79) v2(197.15,97.9) v2(197.1,44.97) v2(197.23,120.15) v2(197.29,125.87) v2(197.29,125.17) v2(197.43,126.43) v2(197.42,95.51) v2(197.56,118.15) v2(197.73,124.6) v2(197.72,98.47) v2(197.72,97.32) v2(197.7,28.68) v2(197.97,125.18) v2(197.94,117.01) v2(197.99,125.87) v2(198.12,133.3) v2(198.12,132.66) v2(198.13,126.43) v2(198.25,78.64) v2(198.35,137.57) v2(198.29,97.9) v2(198.34,87.17) v2(198.5,124.91) v2(198.5,120.28) v2(198.65,125.85) v2(198.75,133.3) v2(198.75,132.66) v2(198.69,123.71) v2(198.81,126.44) v2(198.94,124.34) v2(198.94,87.2) v2(198.93,46.66) v2(198.97,28.68) v2(199,125.3) v2(199.23,117.01) v2(199.23,115.44) v2(199.21,36.31) v2(199.39,123.71) v2(199.62,137.57) v2(199.89,91.84) v2(200.02,123.71) v2(200.02,109.67) v2(200.08,112.91) v2(200.08,111.77) v2(200.08,110.61) v2(200.15,109.04) v2(200.21,112.34) v2(200.23,111.17) v2(200.24,28.68) v2(200.46,113.48) v2(200.4,110.12) v2(200.53,117.01) v2(200.53,115.44) v2(200.5,91.84) v2(200.67,110.64) v2(200.59,109.55) v2(200.72,112.91) v2(200.72,111.77) v2(200.68,46.73) v2(200.85,112.34) v2(200.85,108.98) v2(200.89,137.57) v2(200.91,111.21) v2(201.04,114.69) v2(201.04,114.06) v2(201.05,113.42) v2(200.99,110.11) v2(201.09,91.84) v2(201.18,116.15) v2(201.54,36.46) v2(201.51,28.68) v2(201.67,91.84) v2(202.16,137.57) v2(202.12,36.71) v2(202.2,45.04) v2(202.43,99.64) v2(202.54,98.93) v2(202.78,28.68) v2(202.92,46.9) v2(203.43,137.57) v2(203.45,101.05) v2(203.45,99.3) v2(203.45,97.55) v2(204.05,28.68) v2(204.7,137.57) v2(205.23,47.14) v2(205.33,48.87) v2(205.29,45.13) v2(205.32,28.68) v2(205.97,137.57) v2(206.59,28.68) v2(207.3,89.37) v2(207.34,45.02) v2(207.39,46.72) v2(207.48,136.75) v2(207.86,28.68) v2(208.74,136.57) v2(208.96,48.23) v2(208.96,46.01) v2(209.23,28.68) v2(209.54,52.31) v2(210.01,136.57) v2(210.5,28.68) v2(210.88,77.23) v2(211.28,136.57) v2(211.57,45.04) v2(211.77,28.68) v2(212.55,136.57) v2(213.04,28.68) v2(213.1,80.02) v2(213.27,46.96) v2(213.3,99.55) v2(213.74,119.41) v2(213.82,136.57) v2(213.86,38.24) v2(213.86,37.6) v2(213.86,36.97) v2(214.31,28.68) v2(214.4,98.48) v2(214.43,90.32) v2(214.78,48.97) v2(214.83,46.43) v2(215.07,109.1) v2(215.09,136.57) v2(215.58,28.68) v2(215.96,137.49) v2(216.09,109.16) v2(216.55,97.52) v2(216.51,46.96) v2(216.58,48.64) v2(216.63,45.21) v2(216.85,28.68) v2(217.27,137.57) v2(217.24,52.52) v2(217.94,82.98) v2(218.12,28.68) v2(218.54,137.57) v2(218.67,45.49) v2(218.72,47.24) v2(218.78,48.97) v2(219.39,28.68) v2(219.81,137.57) v2(220.43,48.04) v2(220.47,45.32) v2(220.66,28.68) v2(221.08,137.57) v2(221.93,28.68) v2(222.22,48.31) v2(222.18,46.43) v2(222.35,137.57) v2(222.69,79.05) v2(222.97,86.24) v2(223.2,28.68) v2(223.28,41.39) v2(223.54,88.2) v2(223.62,137.57) v2(223.81,83.79) v2(224.19,48.69) v2(224.24,46.63) v2(224.23,45.03) v2(224.47,28.68) v2(224.89,137.57) v2(225.01,84.16) v2(225.22,85.96) v2(225.74,28.68) v2(225.97,94.07) v2(225.96,46.38) v2(226.16,137.57) v2(226.25,87.32) v2(226.26,85.54) v2(227.01,28.68) v2(227.32,136.89) v2(228.28,28.68) v2(228.54,136.57) v2(228.72,85.48) v2(229.55,93.82) v2(229.48,92.66) v2(229.55,28.68) v2(229.58,100.82) v2(229.58,97.72) v2(229.82,136.57) v2(229.99,46.4) v2(230.82,28.68) v2(231.09,136.57) v2(231.59,83.05) v2(231.67,81.29) v2(231.73,84.59) v2(232,137.56) v2(232.09,28.68) v2(232.56,78.92) v2(233.27,137.57) v2(233.2,78.92) v2(233.36,28.68) v2(233.68,48.69) v2(233.68,47.14) v2(234.38,85.31) v2(234.54,137.57) v2(234.58,83.55) v2(234.63,28.68) v2(234.82,86.98) v2(235.39,85.02) v2(235.81,137.57) v2(235.9,28.68) v2(236.44,36.4) v2(236.46,34.62) v2(237.04,86.32) v2(237.04,84.49) v2(237.08,137.57) v2(237.17,28.68) v2(238.25,86.93) v2(238.25,85.13) v2(238.35,137.57) v2(238.44,28.68) v2(239.39,86.83) v2(239.42,85.46) v2(239.62,137.57) v2(239.71,28.68) v2(240.82,107.1) v2(240.89,137.57) v2(240.98,28.68) v2(241.46,133.65) v2(241.79,133.14) v2(241.86,35.54) v2(242.16,137.57) v2(242.22,77.25) v2(242.25,28.68) v2(242.37,132.85) v2(243.32,61.54) v2(243.32,60.96) v2(243.32,60.38) v2(243.43,137.57) v2(243.52,28.68) v2(244.33,72.51) v2(244.51,125.73) v2(244.7,137.57) v2(244.83,77.25) v2(244.79,28.68) v2(245.87,88.53) v2(245.87,87.95) v2(245.87,87.36) v2(245.87,86.78) v2(245.97,137.57) v2(245.93,44.17) v2(245.93,43.58) v2(245.93,43) v2(245.93,42.36) v2(246.06,28.68) v2(246.09,127.3) v2(246.28,50.32) v2(246.28,49.73) v2(246.38,47.31) v2(246.61,44.14) v2(246.61,43.56) v2(246.61,42.98) v2(246.58,42.39) v2(247.1,61.54) v2(247.1,60.96) v2(247.1,60.38) v2(247.24,137.57) v2(247.2,42.94) v2(247.33,43.56) v2(247.33,28.68) v2(247.71,35.25) v2(248.51,137.57) v2(248.6,135.67) v2(248.6,28.68) v2(248.74,58.93) v2(248.74,58.34) v2(248.75,57.54) v2(248.85,35.13) v2(249.87,28.68) v2(250.03,136.57) v2(250.51,135.67) v2(251.14,28.68) v2(251.46,134.02) v2(251.44,86.29) v2(252.29,134.06) v2(252.29,131.52) v2(252.29,130.25) v2(252.29,128.98) v2(252.29,127.71) v2(252.29,126.44) v2(252.38,28.4) v2(252.53,41.03) v2(252.92,42.24) v2(252.96,27.27) v2(252.96,26) v2(252.96,24.72) v2(252.96,23.45) v2(252.96,22.18) v2(252.96,20.91) v2(253.22,125.57) v2(253.76,19.93) v2(254.49,125.57) v2(254.59,85.5) v2(254.59,84.86) v2(254.88,83.2) v2(255.03,19.93) v2(255.76,125.57) v2(255.92,26.5) v2(256.21,32.05) v2(256.3,19.93) v2(257.03,125.57) v2(257.22,24.25) v2(257.57,19.93) v2(258.3,125.57) v2(258.78,62.52) v2(258.84,19.93) v2(259.57,125.57) v2(259.65,51.64) v2(259.83,24.25) v2(259.9,47.49) v2(260.11,19.93) v2(260.73,47.44) v2(260.84,125.57) v2(260.88,48.02) v2(261.13,26.5) v2(261.38,19.93) v2(262.11,125.57) v2(262.21,117.96) v2(262.65,19.93) v2(262.69,117.55) v2(263.15,117.12) v2(263.38,125.57) v2(263.92,19.93) v2(264.54,115.74) v2(264.65,125.57) v2(265.19,19.93) v2(265.92,125.57) v2(266.14,33.79) v2(266.46,19.93) v2(266.65,53.84) v2(266.58,21.85) v2(266.82,79.2) v2(266.91,65.36) v2(266.91,64.22) v2(267.19,125.57) v2(267.19,21.85) v2(267.76,110.81) v2(267.73,19.93) v2(267.9,33.75) v2(268.03,32.01) v2(268.46,125.57) v2(268.84,65.36) v2(268.84,64.22) v2(268.89,113.9) v2(269,19.93) v2(269.36,79.2) v2(269.62,84.91) v2(269.73,125.57) v2(269.93,83.15) v2(270,35.25) v2(270.12,35.89) v2(270.27,19.93) v2(270.31,30.25) v2(270.31,25.85) v2(270.63,35.32) v2(270.75,77.04) v2(270.7,36.01) v2(271,125.57) v2(271.04,84.5) v2(271.33,72.6) v2(271.54,19.93) v2(271.63,30.24) v2(271.86,25.88) v2(272.27,125.57) v2(272.7,30.05) v2(272.81,19.93) v2(273.31,25.83) v2(273.54,125.57) v2(274.08,19.93) v2(274.69,114.64) v2(274.69,113.37) v2(274.69,112.1) v2(274.81,125.57) v2(274.82,30.05) v2(274.82,25.85) v2(275.35,19.93) v2(275.42,80.66) v2(275.52,32.27) v2(275.96,114.64) v2(275.96,113.37) v2(275.96,112.1) v2(276.08,125.57) v2(276.08,31.28) v2(276.35,30.11) v2(276.35,25.88) v2(276.62,19.93) v2(277.23,114.64) v2(277.23,113.37) v2(277.23,112.1) v2(277.35,125.57) v2(277.87,25.83) v2(277.89,19.93) v2(278.04,119.07) v2(278.1,30.11) v2(278.62,125.57) v2(279.16,19.93) v2(279.18,30) v2(279.27,25.84) v2(279.54,36.26) v2(279.79,119.07) v2(279.89,125.57) v2(280.43,19.93) v2(280.85,42.43) v2(280.78,25.88) v2(280.94,29.94) v2(281.16,125.57) v2(281.46,36.26) v2(281.7,19.93) v2(282.27,91.39) v2(282.43,125.57) v2(282.76,25.83) v2(282.97,19.93) v2(283.23,36.26) v2(283.7,125.57) v2(283.9,22.36) v2(284.04,55.98) v2(284.04,54.4) v2(284.04,52.83) v2(284.24,19.93) v2(284.86,23.76) v2(284.97,125.57) v2(285.36,24.63) v2(285.43,26.51) v2(285.51,19.93) v2(285.64,88.78) v2(285.62,55.98) v2(285.62,54.4) v2(285.62,52.83) v2(285.68,85.23) v2(286.09,90.19) v2(286.24,125.57) v2(286.53,61.75) v2(286.53,61.11) v2(286.66,19.41) v2(286.76,18.14) v2(286.78,16.87) v2(287.19,55.98) v2(287.19,54.4) v2(287.19,52.83) v2(287.42,87) v2(287.51,125.57) v2(287.52,88.78) v2(287.48,85.22) v2(287.73,42.35) v2(287.78,90.62) v2(288.27,91.91) v2(288.25,37.54) v2(288.32,16.83) v2(288.6,110.88) v2(288.58,109.1) v2(288.58,106.1) v2(288.58,103.1) v2(288.86,91.89) v2(288.88,37.54) v2(289.16,42.29) v2(289.59,16.83) v2(289.72,122.75) v2(289.81,70.62) v2(290.05,125.57) v2(290.32,37.16) v2(290.86,16.83) v2(290.95,37.79) v2(291.32,125.57) v2(291.33,36.46) v2(291.84,76.4) v2(292.13,16.83) v2(292.33,122.75) v2(292.54,76.4) v2(292.59,125.57) v2(292.72,75.72) v2(292.78,24.64) v2(292.78,22.41) v2(293.29,96.3) v2(293.29,95.48) v2(293.4,16.83) v2(293.63,120.5) v2(293.66,70.5) v2(293.73,75.78) v2(293.86,125.57) v2(293.89,23.52) v2(294.14,17.89) v2(294.34,124) v2(294.28,71.13) v2(294.28,69.88) v2(294.67,18.17) v2(294.67,16.83) v2(294.75,46.41) v2(294.9,70.5) v2(294.88,53.01) v2(295.02,51.51) v2(295.01,24.64) v2(295.01,22.41) v2(295.13,125.57) v2(295.28,76.36) v2(295.61,122.4) v2(295.64,53.01) v2(295.78,48.33) v2(295.91,46.87) v2(295.94,16.83) v2(296.02,123.98) v2(296.27,80.46) v2(296.4,125.57) v2(296.52,59.51) v2(296.73,119.2) v2(296.91,80.49) v2(297.14,122.93) v2(297.09,121.36) v2(297.21,16.83) v2(297.67,125.57) v2(297.67,80.49) v2(298.16,15.98) v2(298.16,14.71) v2(298.25,58.94) v2(298.29,124.45) v2(298.33,85.7) v2(298.42,76.5) v2(298.59,69.9) v2(298.69,49.92) v2(298.69,49.29) v2(298.69,48.65) v2(298.69,48.02) v2(298.97,85.7) v2(299.01,71.44) v2(298.99,12.85) v2(299.22,123.57) v2(299.21,89.35) v2(299.19,66.52) v2(299.22,65.91) v2(299.3,88.75) v2(299.43,51.53) v2(299.72,74.25) v2(299.75,66.22) v2(299.98,88.75) v2(300.49,123.57) v2(300.81,12.13) v2(301.76,123.57) v2(302.33,74.25) v2(303.03,123.57) v2(303.32,11.87) v2(303.63,76.5) v2(303.61,10.63) v2(303.61,9.36) v2(303.61,5.55) v2(303.61,4.28) v2(303.61,3.01) v2(303.61,1.74) v2(303.61,0.48) v2(303.97,84.92) v2(303.97,83.17) v2(304.3,123.57) v2(304.94,0.43) v2(305.05,73.06) v2(305.05,71.79) v2(305.05,60.58) v2(305.05,59.3) v2(305.05,55.86) v2(305.05,54.59) v2(305.45,74.27) v2(305.45,57.06) v2(305.57,123.57) v2(305.91,58.37) v2(306.21,0.43) v2(306.7,124.16) v2(306.71,74.08) v2(306.71,56.88) v2(306.8,125.56) v2(307.08,58.87) v2(307.48,0.43) v2(307.97,73.93) v2(307.97,56.73) v2(308.07,125.56) v2(308.35,58.87) v2(308.62,91.43) v2(308.62,90.16) v2(308.62,88.89) v2(308.61,87.63) v2(308.62,86.35) v2(308.62,85.08) v2(308.62,83.81) v2(308.62,82.54) v2(308.62,81.27) v2(308.62,80.01) v2(308.75,0.43) v2(309.24,73.93) v2(309.24,56.73) v2(309.33,93.76) v2(309.48,76.52) v2(309.62,58.87) v2(309.89,125.55) v2(310.02,0.43) v2(310.46,124.33) v2(310.51,93.28) v2(310.65,77.02) v2(311.11,111.39) v2(311.29,115.1) v2(311.29,0.43) v2(311.43,123.57) v2(311.78,93.28) v2(311.92,77.02) v2(312.38,111.39) v2(312.56,0.43) v2(312.7,123.24) v2(312.92,4) v2(313.39,59.17) v2(313.65,111.39) v2(313.85,122.73) v2(313.83,0.43) v2(313.97,5.83) v2(313.97,2.17) v2(314.29,73.63) v2(314.28,56.43) v2(314.66,59.17) v2(314.75,122.06) v2(314.92,111.39) v2(315.35,74.48) v2(315.35,59.04) v2(315.35,57.77) v2(315.34,56.5) v2(315.55,121.14) v2(315.59,93.28) v2(315.73,77.02) v2(315.89,120) v2(315.89,118.73) v2(315.89,117.46) v2(315.89,116.19) v2(315.89,114.92) v2(316.08,5.83) v2(316.08,2.17) v2(316.22,75.41) v2(316.37,0.43) v2(316.86,93.28) v2(317,77.02) v2(317.13,4) v2(317.46,113.92) v2(317.39,13.01) v2(317.39,11.74) v2(317.49,75.41) v2(317.53,10.45) v2(317.64,0.43) v2(318.27,77.02) v2(318.32,13.87) v2(318.32,10.01) v2(318.6,112.66) v2(318.62,75.48) v2(318.62,25.37) v2(318.62,24.1) v2(318.62,22.83) v2(318.62,21.56) v2(318.62,20.29) v2(318.62,19.02) v2(318.62,17.75) v2(318.62,16.48) v2(318.62,15.21) v2(318.62,9.39) v2(318.62,8.12) v2(318.62,6.85) v2(318.62,5.58) v2(318.62,4.31) v2(318.62,3.04) v2(318.62,1.77) v2(318.62,0.5) v4(19.43,91.83) v4(37.78,100.47) v4(57.72,127.33) v4(62.67,127.52) v4(85.02,35) v4(85.09,34.74) v4(95.69,90.89) v4(96.26,36.52) v4(98.8,66.69) v4(108.39,89.29) v4(110.27,104.77) v4(191.64,82.69) v4(193.39,134.16) v4(201.1,122.57) v4(201.49,110.77) v4(232.28,47.95) v4(278.95,116.91) v4(298.7,81.1)
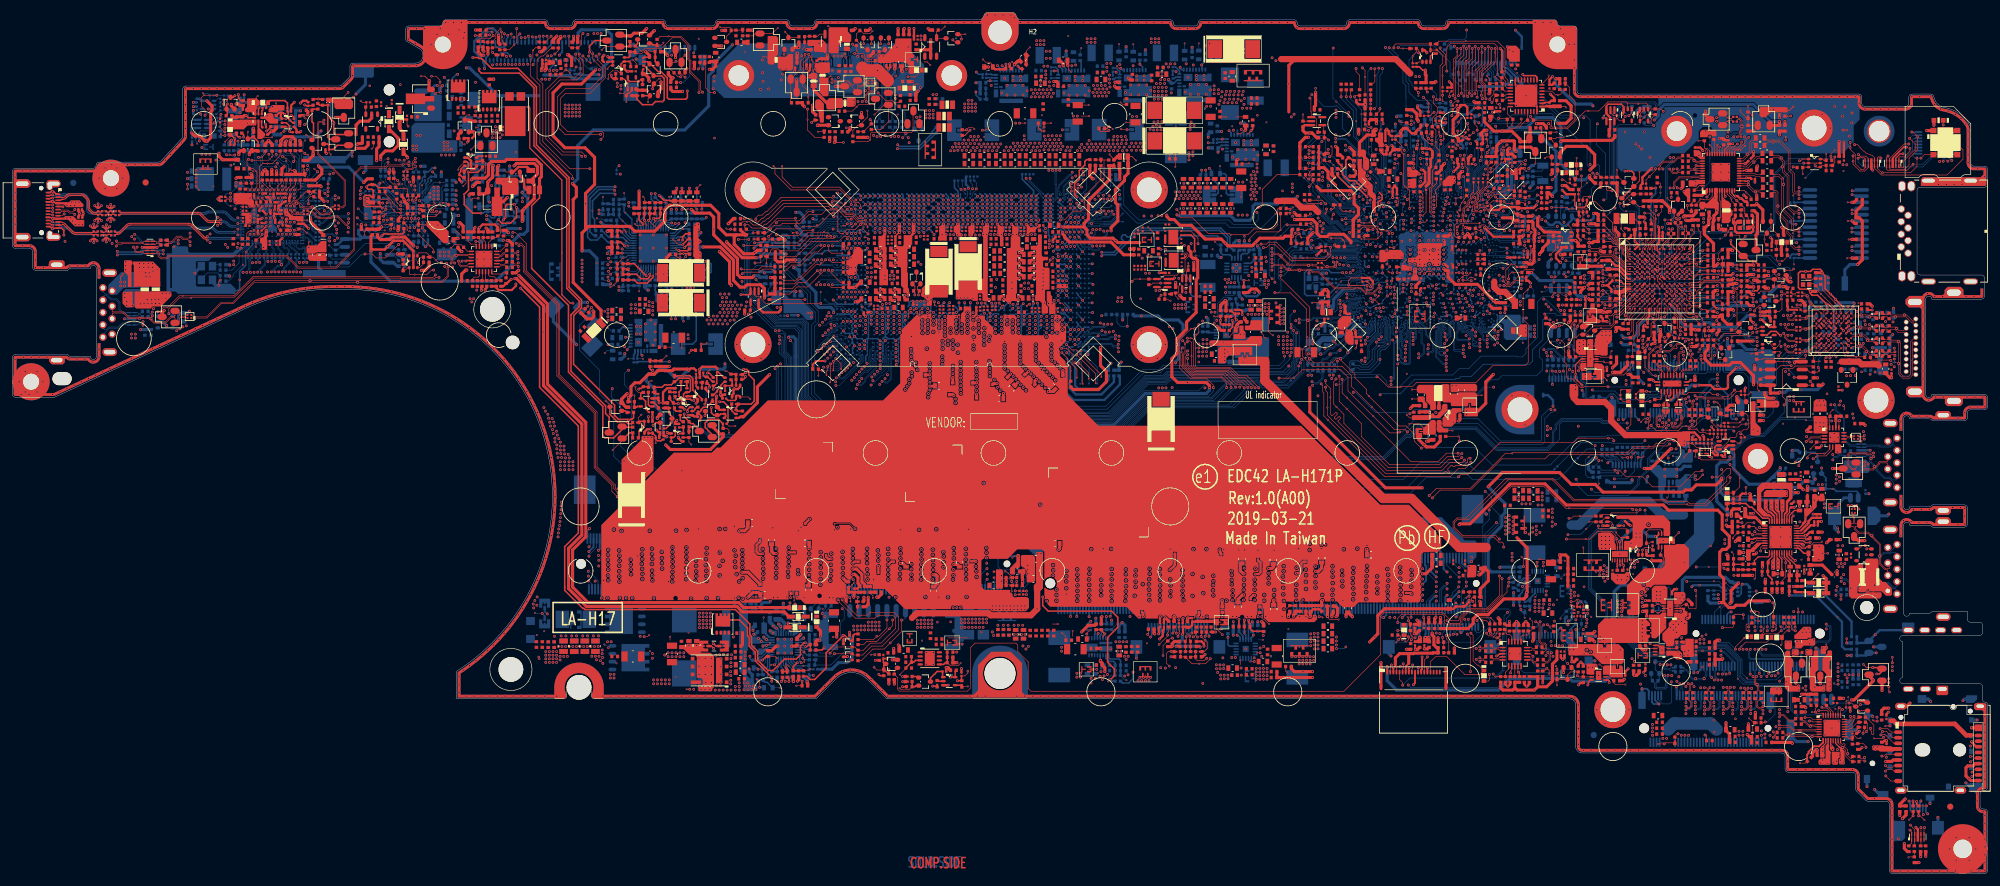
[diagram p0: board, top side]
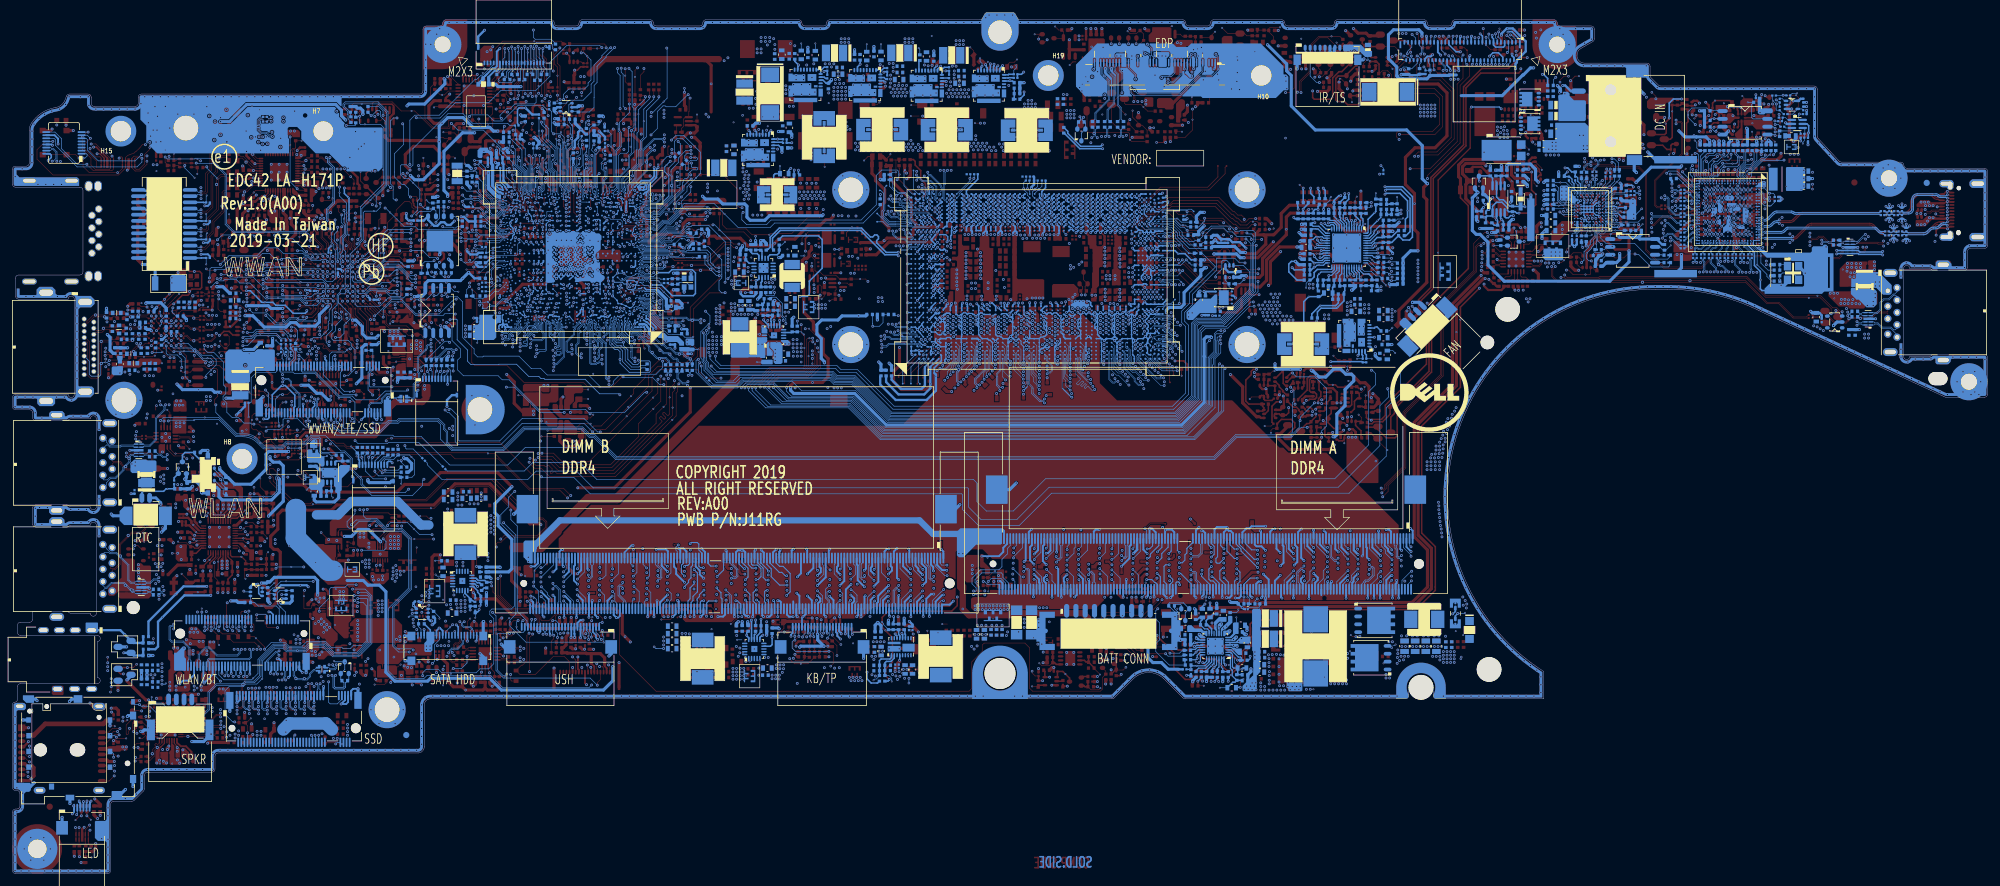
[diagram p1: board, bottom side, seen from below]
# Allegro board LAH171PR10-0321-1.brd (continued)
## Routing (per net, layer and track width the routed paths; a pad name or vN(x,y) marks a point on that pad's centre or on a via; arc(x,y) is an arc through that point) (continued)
GNDA: length 52.3
  TOP w0.127: v2(296.29,37.28) v4(296.29,37.98) ; v2(292.35,51.78) v4(293.23,51.78) ; v2(296.35,35.25) v4(297.02,35.25)
  TOP w0.203: UA1.19 287.02,51.48 287.89,50.61 v2(288,50.61) ; UA1.31 287.42,57.58 v2(287.66,57.82)
  TOP w0.356: CA8.2 v2(289.43,48.54) ; v2(287.78,60.09) 287.78,60.09 287.47,59.78 CA57.2
  TOP w0.508: CA35.2 v2(291.84,52.86) ; RA37.1 293.56,53.99 v2(293.05,53.48) ; CA78.2 v2(292.35,55.19) ; CA51.2 v2(292.35,51.78) ; CA25.2 v2(285.17,48.46) ; CA41.2 v2(282.68,49.54) ; CA77.2 v2(291.89,54.25) ; RA35.1 v2(283.14,47.57) ; v2(288.66,59.4) 288.66,60.09 CA52.2 ; DA2.2 v2(301.99,29.6) ; RA36.1 289.94,60.16 CA58.2 289.87,60.09 v2(289.87,59.4) ; CA9.2 v2(290.38,49.17) ; RA44.2 v2(291.78,50.76)
  GND1 w0.203: JHP1.5 307.33,29.18 ; JHP1.5 307.33,29.85 ; JHP1.5 305.17,29.18 ; JHP1.5 305.17,29.85 ; JHP1.5 306.25,29.18 ; JHP1.7 309.98,40.02 ; JHP1.7 307.82,40.02 ; JHP1.7 307.82,39.35 ; JHP1.7 308.9,40.02 ; JHP1.7 309.98,39.35
  GND2 w0.203: JHP1.7 308.9,40.02 ; JHP1.7 309.98,40.02 ; JHP1.7 307.82,40.02 ; JHP1.7 309.98,39.35 ; JHP1.7 307.82,39.35 ; 306.25,29.18 JHP1.5 ; JHP1.5 305.17,29.85 ; JHP1.5 305.17,29.18 ; JHP1.5 307.33,29.85 ; JHP1.5 307.33,29.18
  GND3 w0.203: JHP1.5 307.33,29.18 ; JHP1.5 306.25,29.18 ; JHP1.5 305.17,29.18 ; JHP1.5 307.33,29.85 ; JHP1.5 305.17,29.85 ; JHP1.7 308.9,40.02 ; JHP1.7 309.98,39.35 ; JHP1.7 307.82,40.02 ; JHP1.7 309.98,40.02 ; JHP1.7 307.82,39.35
  BOTTOM w0.508: CA2.1 v2(296.29,37.28) ; CA1.2 v2(297.31,32.14) CA4.2 ; CA3.1 v2(296.35,35.25)
  vias: v2(292.67,59.76) v2(292.67,59.13)
VBAT1_CHG: length 3
  BOTTOM w0.203: PR738.1 PC755.1 123.54,33.13 123.75,33.34 v1(123.75,33.6) PU700.31
VBUS1_ECOK: length 248.1
  TOP w0.109: v2(261.01,87.27) 261.07,87.27 261.59,87.79 261.59,89.93 262.87,91.21 UE1.N3
  TOP w0.254: PR826.1 112.6,78.95 v2(112.6,78.62) ; PR861.2 100.34,73.7 100.08,73.44 99.83,73.44 99.68,73.29 99.68,73.29 v2(99.56,73.29) 99.44,73.42 97.91,73.42 97.28,74.05 97.28,75.7 90.65,82.33 90.65,85.84 v1(90.67,85.86) 90.67,90.22 91.92,91.47 91.92,92.75 89.92,94.75 89.92,112.51 84.64,117.79 84.64,127.18 81.67,130.15 77.38,130.15 75.78,131.75 75.4,131.75 75.24,131.9 74.38,131.9 74.38,131.88 v2(74.36,131.88)
  TOP w0.381: PR20.2 73.02,118.87 PR24.1 73.67,118.43 v2(73.48,118.23)
  BOTTOM w0.102: v2(112.6,78.62) 112.58,78.62 112.05,78.09 112.05,76.36 112.28,76.13 112.28,71.38 112.71,70.94 121.48,70.94 125.02,67.41 221.43,67.41 224.96,70.94 225.67,70.94 226.92,72.2 236.49,72.2 239.88,68.82 247.86,68.82 248.74,69.7 248.74,71.47 249.2,71.92 249.2,72.56 250.19,73.55 256.66,73.55 256.97,73.24 258.35,73.24 258.77,72.82 v2(260.83,72.82)
VBUS2_ECOK: length 193.5
  TOP w0.102: v2(111.49,126.3) 111.13,126.65 111.13,128.06 109.6,129.6 109.6,131.39 109.28,131.71 109.28,134.06 108.01,135.33 v1(105.98,135.33) 104.63,135.33 PR49.2
  TOP w0.109: v2(265.01,89.77) 264.68,90.1 264.68,91.07 264.8,91.19 264.8,91.65 UE1.M6
  TOP w0.254: PR827.1 113.09,76.34 112.14,75.38 111.63,75.38 111.25,75 111.25,74.85 111.04,74.65 110.88,74.65 PR816.1 110.75,74.48 111.29,73.95 PR819.1 111.29,73.65 111.06,73.42 v2(111.06,73.22)
  BOTTOM w0.102: v2(267.52,72.46) 267.01,72.46 266.12,71.57 259.67,71.57 258.25,72.99 256.89,72.99 256.56,73.32 250.28,73.32 249.43,72.47 249.43,71.82 248.97,71.37 248.97,69.61 247.95,68.59 239.78,68.59 236.4,71.97 227.02,71.97 225.76,70.71 225.05,70.71 221.52,67.18 124.92,67.18 121.39,70.71 112.62,70.71 112.45,70.88 112.45,70.88 111.18,72.15 111.18,73.11 111.07,73.22 v2(111.06,73.22) 111,73.27 111,73.79 108.93,75.86 108.93,75.9 v2(108.73,76.1)
VCC1_IA: length 6.3
  TOP w0.102: v1(156.78,131.58) 157.22,131.14 157.92,131.14 158.24,130.82 158.24,130.5 PRH1.2
  TOP w0.254: PCH23.1 160.49,130.16 v2(160.49,130.82)
  TOP w0.381: PCH23.1 160.32,129.99 158.75,129.99 PRH1.2
  BOTTOM w0.254: v2(160.49,130.82) 160.49,130.54 160.58,130.45 PUH1.3
VCC2_IA: length 2.1
  TOP w0.102: v1(170.94,129.61) 170.56,129.99 170.56,130.57 v2(170.49,130.63)
  TOP w0.508: PRH11.2 170.43,130.69 v2(170.49,130.63)
VCC3_IA: length 1.2
  BOTTOM w0.102: PRH2.2 v1(178.75,134.06)
VCC4_IA: length 1.2
  BOTTOM w0.102: PRH9.2 v1(189.35,134.19)
VCC_1.05VALWP: length 3.4
  TOP w0.102: v1(196.59,86.75) 196.59,86.81 197.49,87.72 PC316.1
  TOP w0.508: PC316.1 197.61,88.21 v2(197.8,88.4) 197.8,88.72 198.24,89.16 PC313.1
VCC_CPU: length 4.3
  BOTTOM w0.203: PUZ1.16 107.24,102.71 107.45,102.92 v1(107.95,102.92) 108.54,102.92 108.96,102.5 109.26,102.5 PCZ34.1
  BOTTOM w0.508: PCZ34.1 109.47,101.26 PRZ61.2
VCC_DDR: length 1.5
  BOTTOM w0.254: PU200.14 174.81,38.66 174.88,38.73 174.88,39.31 PC207.1
VCC_GT: length 1.4
  BOTTOM w0.102: v1(95.69,84.15) 96.07,84.53 PRT1.2
VCC_SA: length 0.7
  BOTTOM w0.254: PUA1.3 197.86,120.15
  vias: v1(197.04,120.79)
VCC_SENSE_GT: length 3.5
  BOTTOM w0.076: 153.26,110.59 v2(153.23,110.59)
  BOTTOM w0.102: v2(97.97,94.86) 98.08,94.75 98.34,94.75 PRZ30.1 ; PRZ29.2 152.75,111.1 153.26,110.59 153.93,109.92 UC1.AH38
VCC_SENSE_IA: length 5
  BOTTOM w0.102: RC140.2 155.3,112.08 RC221.2 155.7,111.68 v2(155.7,110.69) 155.7,110.58 155.13,110.01 155.13,109.67 154.71,109.26 UC1.AG37 ; v2(99.55,107.89) 99.81,107.63 PRZ27.1
VCC_SENSE_SA: length 4.9
  BOTTOM w0.102: PRZ13.1 95.17,107.13 94.86,107.13 v2(94.75,107.24) ; PRZ17.2 164.32,112.43 v2(164.39,112.37) 164.39,111.98 UC1.M38
VCCDSW_EN: length 9.7
  TOP w0.102: v2(263.36,85.59) 263.52,85.59 264.02,86.08 264.02,86.18 CE66.1
  TOP w0.109: UE1.M7 265.67,91.73 265.67,91.09 265.52,90.93 265.52,90.4 265.52,90.4 265.52,89.73 264.69,88.9 264.69,86.86 CE66.1 ; RH445.1 249.61,113.04 v1(249.16,112.58) v2(248.72,112.15)
VCCDSW_EN_GPIO: length 4.7
  TOP w0.102: QH6.2 247.76,115.84 v1(247.54,115.62)
  TOP w0.109: QH6.2 248.65,114.72 RH431.1 RH445.2 250.4,114.64 250.48,114.56 DH1.2
VCCDSW_EN_Q: length 3.6
  TOP w0.102: v1(252.66,115.68) DH1.1
  TOP w0.109: DH1.1 252.69,114.54 DH2.2 252.69,112.51 RH442.1
VCCIO_SENSE: length 25.1
  BOTTOM w0.076: v2(168.92,92.65) 169.25,92.33 UC1.H14
  BOTTOM w0.254: v2(175.95,99.85) 176.13,100.02 178.11,100.02 182.05,103.96 195.01,103.96 196.27,102.7 196.27,100.96 PR422.2
VCCMPHY_SENSE: length 11.3
  BOTTOM w0.089: UH1.K47 239.26,92.88 239.32,92.94 239.89,92.94 240.97,91.87 241.71,91.87 T76.1 242.61,92.4 242.74,92.27 243.38,92.27 v2(243.58,92.47)
  BOTTOM w0.102: v2(194.11,88.91) 194.11,89.67 194.69,90.24 194.69,92.15 195.7,93.16 196.45,93.16 PR1651.1
VCCST_PWRGD: length 21.6
  TOP w0.102: v2(256.93,122.13) 257.32,122.13 257.47,121.98 UE4.4
  BOTTOM w0.102: v2(256.93,122.13) 257.5,122.13 257.97,121.66 257.97,112.34 257.97,111.47 257.55,111.05 257.55,109.11 257.33,108.88 v2(257.04,108.88) ; RC71.2 180.13,88.92 180.08,88.87 v2(180.08,88.47) 179,88.47 178.42,89.05 CC301.1 RC78.1
VCCST_PWRGD_CPU: length 1.3
  BOTTOM w0.076: v2(169.66,91.08) 169.27,91.47 UC1.H13 ; 176.34,90.18 v2(175.95,90.18)
  BOTTOM w0.102: RC78.2 176.45,90.18 176.34,90.18
VCCSTG_EN: length 15.1
  TOP w0.102: v2(180.86,95.72) 181.24,96.1 v1(182.11,96.1) RZ320.2 184.03,96.1 184.03,96.1 UZ35.4 185.43,96.1 186.05,96.72 188.08,96.72 188.59,97.23 189.16,97.23 189.42,97.48 189.42,99.2 189.92,99.71 189.92,100.09 189.71,100.3 189.31,100.3 189.12,100.11 UZ19.4
  BOTTOM w0.102: v2(120.11,96.03) 120.35,95.79 120.35,95.78 120.8,95.32 RZ120.1
VDD_CHG: length 1.6
  TOP w0.102: v2(139.32,35.38) v1(138.68,35.38)
  BOTTOM w0.508: v2(119.63,39.32) 119.63,39.82 PR707.2
  vias: v2(127.82,38.05)
VDDP_CHG: length 1.3
  BOTTOM w0.102: PR707.1 v1(121.34,41.41)
VIN_1.2V_RUN: length 0.9
  BOTTOM w0.102: v1(268.22,67.51) 268.35,67.38 269.11,67.38
VIN_1.8VALW: length 3.2
  TOP w0.102: PJP501.2 227.97,72.01 227.27,72.71 v1(225.65,72.71)
VIN_1VS_VCCIO:
  vias: v1(199.7,99.58) v2(199.7,96.66) v2(200.21,97.99) v2(200.21,97.29)
VIN_2.5V_MEM: length 3
  TOP w0.102: 151.13,38.11 v1(154.11,38.11)
VSS_A36: length 6.4
  BOTTOM w0.102: 174.75,109.78 174.19,109.21 174.19,108.83 UC1.A36
  BOTTOM w0.109: 174.75,109.78 174.88,109.9 175.8,109.9 176.07,109.64 v2(176.22,109.64) 176.28,109.64 176.63,109.99 176.63,110.35 177.4,111.13 177.4,112.07 RC178.1
VSS_A37: length 7.1
  BOTTOM w0.102: v1(176.34,113.36) 176.94,113.36 RC179.1
  BOTTOM w0.109: UC1.A37 173.97,109.27 174.8,110.1 176.04,110.1 176.84,110.9 176.84,112.5 RC179.1
VSS_SENSE_GT: length 4.2
  BOTTOM w0.102: PRZ39.1 153.44,111.05 v2(153.87,110.61) 154.3,110.18 154.3,109.55 153.95,109.19 UC1.AH37 ; v2(97.97,94.28) 98.19,94.5 98.34,94.5 PRZ38.1
VSS_SENSE_IA: length 4
  BOTTOM w0.102: PRZ31.1 100.36,108.47 v2(99.55,108.47) ; UC1.AG38 154.71,110.3 v2(155.1,110.69) 155.1,111.34 154.77,111.67 RC221.1 154.68,112.11 RC141.1
VSS_SENSE_SA: length 5.8
  BOTTOM w0.102: UC1.M37 166.12,109.6 166.12,109.92 163.75,112.29 v2(163.75,112.37) 163.7,112.42 PRZ1.1 ; v2(94.75,106.66) 94.93,106.84 95.08,106.84 PRZ11.1
VSSIO_SENSE: length 27.2
  BOTTOM w0.076: UC1.J14 168.6,92.33 v2(168.27,92.65)
  BOTTOM w0.254: PR412.2 197.15,100.91 196.97,100.91 196.65,101.23 196.65,102.86 195.17,104.34 181.89,104.34 180.45,102.9 180.09,102.9 179.77,103.22 179.41,103.22 179.15,102.97 179.15,102.61 179.45,102.32 179.45,101.96 177.89,100.4 175.98,100.4 v2(175.95,100.43)
VSSMPHY_SENSE: length 9.6
  BOTTOM w0.089: UH1.K46 238.89,92.65 239.29,92.65 239.4,92.75 239.81,92.75 240.89,91.68 242.15,91.68 242.44,91.39 T77.1 243.07,91.69 243.01,91.75 243.01,91.89 243.19,92.08 243.38,92.08 v2(243.58,91.88)
  BOTTOM w0.102: v2(194.54,89.42) 194.54,89.77 194.92,90.15 194.92,91.74 195.14,91.97 PR1649.1
32KHZ_OUT: length 8.9
  TOP w0.109: v2(262.44,97.31) 262.47,97.28 262.49,97.28 262.84,96.93 UE1.F3
  BOTTOM w0.109: v2(262.44,97.31) 262.42,97.33 260.62,97.33 259.04,98.9 256.43,98.9 v1(256.19,98.66) 255.63,98.11 CE54.1
+BL_PWR_SRC: length 5
  TOP w2.032: 141.41,128.15 v4(139.76,129.8) 137.73,129.8 137.28,130.25
  vias: v2(132.75,132.13) v2(133.35,132.15) v2(133.98,132.15) v2(134.47,132.48) v4(134.62,131.91) v4(142.68,128.92)
+BL_PWR_SRC_P: length 0.4
  TOP w0.102: v1(131.76,136.98) 131.88,136.98 132.08,136.79
+COINCELL: length 7.2
  BOTTOM w0.254: JRTC1.1 298.14,61.54 297.89,61.8 294.62,61.8 294.22,62.2 v1(294,62.2) PC2.2 292.92,62.29 PR2.1
+DDR_VREF_A_CA: length 6.8
  TOP w0.127: v1(135.99,47.04) 135.2,46.25 RD16.1
  TOP w0.457: CD25.1 CD26.1 RD17.1 ; CD25.1 135.09,45.49 RD15.2 135.07,46.24 RD16.1 ; CD25.1 135.95,44.74 v2(135.89,44.67)
  BOTTOM w0.305: JDIMM1.164 135.62,44.94 v2(135.89,44.67)
+DDR_VREF_B_CA: length 6.8
  TOP w0.127: v1(208.48,44.28) 208.12,43.92 RD30.1
  TOP w0.508: RD30.1 RD28.2 RD29.1 CD57.1 CD58.1 211.48,44.05 v2(211.6,44.17)
  BOTTOM w0.305: JDIMM2.164 211.42,43.99 v2(211.6,44.17)
+DDR_VREF_B_DQ: length 2.3
  TOP w0.508: v2(206.94,41.6) 206.94,41.79 207.23,42.08 CD62.1 RD30.2
  BOTTOM w0.254: UC1.BR13 133.87,91.2 v2(134.2,90.88)
+DDR_VREF_CA: length 5.4
  TOP w0.508: CD31.1 RD17.2 137.66,46.73 137.22,47.18 137.22,48.37 136.36,49.23 v2(135.77,49.23)
  BOTTOM w0.254: v2(134.85,90.85) 134.85,90.92 UC1.BN13
+EC_DEBUG_VCC: length 3.5
  BOTTOM w0.127: v1(264.33,69.04) 263.34,68.06 RE71.2
  BOTTOM w0.254: RE71.2 263.14,67.78 263.14,66.94 262.99,66.79 JDEG1.1
+EDP_VDD: length 1.2
  TOP w0.127: v1(148.27,130.69) 147.76,131.2 147.25,131.2
+GT_CORE: length 304.2
  TOP w0.457: PC2038.1 142.19,98.21 v2(142.6,98.21) ; v2(142.6,99.41) 142.19,99.41 PC1010.1 ; PC2037.1 139.78,92.64 v2(140.19,92.64) ; PC2042.1 139.78,100.53 v2(140.18,100.53) ; v2(140.19,99.31) 139.78,99.31 PC2050.1 ; PC2056.1 142.94,94.45 v2(142.53,94.45) ; v2(142.54,93.23) 142.94,93.23 PC2034.1 ; v2(142.6,100.62) 142.19,100.62 PC2051.1 ; PC2052.1 139.76,93.84 v2(140.17,93.84) ; v2(140.15,98.08) 139.74,98.08 PC2040.1 ; PC2039.1 144.08,93.08 v2(144.08,93.48)
  TOP w0.508: v2(115.37,102.12) 115.37,102.05 117.88,99.55 v2(120.11,99.55)
  BOTTOM w0.102: v2(208.24,83.13) 208.35,83.02 208.52,83.02 208.62,82.92 208.62,81.01 206.1,78.5 201.92,78.5 200.9,79.53 193.05,79.53 191.56,78.04 182.81,78.04 177.7,72.93 130.52,72.93 126.99,76.46 126.99,87.47 126.29,88.17 122.73,88.17 119.19,91.7 v2(118.49,91.7) ; v2(208.04,82.58) 208.07,82.54 208.07,82.44 208.09,82.42 208.09,82.37 208.22,82.24 208.22,80.94 206.16,78.88 201.87,78.88 200.99,79.75 187.03,79.75 186.38,79.11 183.5,79.11 177.54,73.16 130.74,73.16 127.22,76.68 127.22,87.7 126.52,88.39 123.01,88.39 119.01,92.4 v2(118.6,92.4)
  BOTTOM w0.254: v2(139.36,104.97) 139.68,105.29 UC1.BF31 ; UC1.AW14 146.11,92.2 v2(146.11,92.51) ; UC1.BB38 142.97,109.84 v2(143.3,109.52) ; UC1.AW36 145.33,108.54 v2(145.66,108.22) ; v2(147.23,105.61) 146.9,105.94 UC1.AU32 ; v2(143.3,106.26) 142.97,106.59 UC1.BB33 ; v2(143.3,106.91) 142.97,107.24 UC1.BB34 ; UC1.BE35 140.61,107.89 v2(140.93,108.22) ; v2(142.51,108.87) 142.18,109.19 UC1.BC37 ; UC1.AW34 145.33,107.24 v2(145.66,106.91) ; UC1.AW37 145.59,108.87 v2(145.66,108.87) ; UC1.BC29 142.18,103.94 v2(142.51,103.62) ; UC1.AU36 146.91,108.54 v2(147.23,108.87) 146.9,109.19 UC1.AU37 ; UC1.AV34 146.12,107.24 v2(146.45,106.91) ; v2(141.72,108.87) 141.4,108.54 UC1.BD36 ; v2(146.45,108.22) 146.77,107.89 UC1.AU35 ; UC1.AU30 146.91,104.59 v2(147.23,104.27) ; UC1.BA30 143.76,104.59 v2(144.08,104.27) ; UC1.AY36 144.54,108.54 v2(144.87,108.22) ; UC1.AT14 147.42,92.39 v2(147.28,92.52) ; v2(138.54,104.97) 138.92,104.59 UC1.BG30 ; v2(139.37,108.2) 139.27,108.2 UC1.BG35 ; v2(143.3,107.56) 142.97,107.89 UC1.BB35 ; UC1.BH34 138.25,107.24 v2(138.57,107.56) 138.24,107.89 UC1.BH35 ; v2(144.87,105.61) 144.54,105.94 UC1.AY32 ; UC1.AV36 146.12,108.54 v2(146.45,108.87) ; UC1.BF32 139.82,105.94 v2(140.15,105.61) ; v2(141.72,103.62) 141.4,103.94 UC1.BD29 ; v2(144.08,104.97) 143.76,105.29 UC1.BA31 ; v2(141.72,108.22) 142.04,107.89 UC1.BC35 ; UC1.BA29 143.76,103.94 v2(144.08,103.62) ; UC1.BG29 139.04,103.94 v2(139.36,103.62) ; UC1.BE31 140.5,105.29 v2(140.17,104.96) ; UC1.BC36 142.18,108.54 v2(142.51,108.22) ; v2(146.45,106.26) 146.12,106.59 UC1.AV33 ; UC1.BC32 142.04,105.94 v2(141.72,106.26) ; v2(139.36,106.26) 139.03,106.59 UC1.BG33 ; UC1.AT34 147.56,107.24 v2(147.23,106.91) ; v2(141.72,104.27) 142.04,104.59 UC1.BC30 ; UC1.BB13 UC1.BB14 ; UC1.BE37 140.6,109.19 v2(140.93,108.87) 140.61,108.54 UC1.BE36 ; UC1.BE32 140.61,105.94 v2(140.93,106.26) ; v2(143.3,108.87) 142.97,109.19 UC1.BB37 ; UC1.BB31 142.57,104.96 v2(142.47,104.96) ; UC1.BG36 138.9,108.54 v2(138.57,108.22) 138.24,108.54 UC1.BH36 ; v2(140.93,105.61) 141.26,105.94 UC1.BD32 ; v2(144.87,103.62) 144.55,103.94 UC1.AY29 ; UC1.AT35 147.55,107.89 v2(147.23,108.22) ; UC1.BT37 132.87,109.25 v2(132.66,109.47) ; v2(144.87,107.56) 144.54,107.89 UC1.AY35 ; UC1.AV29 146.12,103.94 v2(146.44,103.62) ; UC1.BE34 140.61,107.24 v2(140.93,107.56) ; v2(140.15,106.26) 140.47,106.59 UC1.BE33 ; UC1.BH38 138.24,109.84 v2(138.57,109.52) 138.25,109.19 UC1.BH37 ; UC1.BF29 139.82,103.94 v2(140.15,104.27) ; v2(152.69,109.52) 152.77,109.6 152.77,110.25 152.17,110.86 PRZ29.1 ; UC1.AW33 145.33,106.59 v2(145.66,106.26) 145.34,105.94 UC1.AW32 ; UC1.BF35 139.82,107.89 v2(140.15,107.56) ; v2(138.56,106.29) 138.26,106.59 UC1.BH33 ; v2(140.15,108.22) 139.82,108.54 UC1.BF36 ; UC1.BF38 139.87,109.84 v2(140.2,109.52) 139.87,109.19 UC1.BF37 ; v2(148.02,108.86) 147.69,109.19 UC1.AT37 ; v2(139.36,105.61) 139.04,105.29 UC1.BG31 ; UC1.BD31 141.4,105.29 v2(141.72,104.98) ; UC1.BB36 142.97,108.54 v2(143.3,108.22) ; v2(140.96,109.54) 140.65,109.84 UC1.BE38 ; v2(148.02,108.22) 147.69,108.54 UC1.AT36 ; UC1.BJ37 137.49,109.19 v2(137.78,109.48) ; v2(145.66,107.56) 145.33,107.89 UC1.AW35 ; v2(146.45,107.56) 146.12,107.89 UC1.AV35 ; v2(144.87,104.27) 144.55,104.59 UC1.AY30 ; UC1.BA35 143.75,107.89 v2(144.08,107.56) ; v2(148.02,109.52) 147.69,109.84 UC1.AT38 ; UC1.BB32 142.84,105.94 v2(142.51,105.61) ; v2(144.08,108.22) 143.76,108.54 UC1.BA36 ; v2(140.93,106.91) 141.26,107.24 UC1.BD34 ; UC1.AT32 147.69,105.94 v2(148.02,105.61) 147.95,105.61 UC1.AT31 ; UC1.BD30 141.33,104.6 v2(140.93,105) ; v2(138.57,105.61) UC1.BG32 ; v2(139.36,104.27) 139.68,104.59 UC1.BF30 ; v2(142.51,109.52) 142.18,109.84 UC1.BC38 ; v2(141.72,105.61) 142.04,105.29 UC1.BC31 ; v2(141.72,107.56) 141.39,107.89 UC1.BD35 ; UC1.AY38 144.54,109.84 v2(144.87,109.52) ; v2(145.69,105.61) 145.58,105.61 UC1.AW31 ; UC1.AV31 146.34,105 v2(146.45,105) ; UC1.BA13 UC1.BA14 ; v2(147.23,103.62) 146.91,103.94 UC1.AU29 ; v2(146.69,92.51) 146.69,91.87 UC1.AU14 ; UC1.AT33 147.7,106.59 v2(148.02,106.91) ; v2(144.08,105.62) 143.76,105.94 UC1.BA32 ; v2(144.88,104.96) 144.55,105.29 UC1.AY31 ; UC1.BA34 143.76,107.24 v2(144.08,106.92) ; v2(144.08,106.26) 143.75,106.59 UC1.BA33 ; v2(141.72,106.91) 141.4,106.59 UC1.BD33 ; v2(145.65,109.49) 145.3,109.84 UC1.AW38 ; UC1.BG34 139.04,107.24 v2(139.36,107.56) ; UC1.AY37 144.54,109.19 v2(144.87,108.87) ; UC1.AU31 147.13,105 v2(147.24,105) ; UC1.BF13 UC1.BF14 ; UC1.BD13 UC1.BD14 ; UC1.AV32 146.12,105.94 v2(146.45,105.61) ; UC1.AU38 146.9,109.84 v2(147.24,109.5) ; v2(146.44,104.27) 146.12,104.59 UC1.AV30
  BOTTOM w0.508: v2(124.96,100.15) 124.96,100.15 121.31,100.15 120.71,99.55 v2(120.11,99.55)
  vias: v1(134.55,92.34) v2(112.2,89.48) v2(112.52,90.05) v2(112.52,88.85) v2(112.83,89.48) v2(113.22,90.12) v2(113.22,88.85) v2(113.53,89.48) v2(113.85,90.12) v2(113.98,88.85) v2(114.36,93.67) v2(114.36,91.83) v2(114.3,90.69) v2(114.3,89.48) v2(114.68,93.1) v2(114.68,92.4) v2(114.74,91.26) v2(114.68,90.12) v2(114.74,88.85) v2(115.06,93.67) v2(114.99,91.83) v2(114.99,90.69) v2(115.12,89.42) v2(115.37,93.1) v2(115.31,92.4) v2(115.44,91.26) v2(115.44,90.12) v2(115.5,88.85) v2(115.76,93.67) v2(115.69,91.83) v2(115.69,90.69) v2(115.95,89.42) v2(116.01,92.4) v2(116.07,91.26) v2(116.26,90.12) v2(116.33,91.83) v2(116.39,90.69) v2(116.58,89.48) v2(116.71,92.4) v2(116.77,91.26) v2(116.96,90.12) v2(117.09,91.89) v2(117.09,90.69) v2(117.47,91.26) v2(117.72,91.89) v2(119.31,89.93) v2(133.56,93.18) v2(134.18,94.01) v2(134.2,93.18) v2(134.53,108.37) v2(134.83,94.01) v2(134.89,93.19) v2(135.53,94.01) v2(135.53,93.18) v2(136.14,101.89) v2(136.16,94.01) v2(136.16,93.18) v2(136.24,108.88) v2(136.81,102.66) v2(136.8,101.88) v2(136.8,94.01) v2(137,108.91) v2(137.43,101.88) v2(137.43,94.01) v2(138.1,97.14) v2(138.1,96.4) v2(138.08,94.01) v2(138.26,101.88) v2(138.74,97.93) v2(138.74,97.14) v2(138.74,96.4) v2(140.15,103.62) v2(140.54,92) v2(141.15,92.15) v2(141.73,92.15) v2(141.78,96.67) v2(141.78,96.09) v2(142.37,96.67) v2(142.37,96.09) v2(142.51,104.27) v2(143.08,92.15) v2(146.31,98.85) v2(146.66,103.01) v2(146.74,98.47)
+IA_CORE: length 109.1
  TOP w0.254: PR3004.1 36.95,124.91 36.52,125.35 36.52,125.9 v2(36.5,125.92)
  TOP w0.457: PC1016.1 164.61,99.17 v2(165.01,99.17) ; v2(165.01,100.38) 164.61,100.38 PC1005.1 ; PC1634.1 163.07,97.96 v2(162.66,97.96) ; PC1629.1 163.07,100.38 v2(162.66,100.38) ; PC1015.1 163.07,99.17 v2(162.66,99.17) ; v2(165.01,96.76) 164.61,96.76 PC1011.1 ; PC1008.1 164.61,97.96 v2(165.01,97.96) ; PC1002.1 162.89,93.33 v2(162.49,93.33) ; v2(162.66,96.76) 163.07,96.76 PC1007.1 ; v2(160.12,93.33) 159.72,93.33 PC1009.1
  BOTTOM w0.152: UC1.W14 161.46,92 v2(161.64,92)
  BOTTOM w0.203: UC1.N32 165.65,105.94 v2(165.33,106.27) 165,106.59 UC1.P33
  BOTTOM w0.254: v2(162.19,108.22) UC1.V35 ; UC1.AJ34 153.21,107.24 v2(153.53,107.56) ; UC1.U33 162.67,106.59 v2(162.99,106.91) ; UC1.AN32 150.06,105.94 v2(150.37,105.63) 150.71,105.29 UC1.AM31 ; v2(153.53,106.26) 153.21,105.94 UC1.AJ32 ; v2(163.77,108.22) 163.45,107.89 UC1.T35 ; UC1.Y31 v2(160.62,105.61) ; v2(162.18,107.56) 161.86,107.24 UC1.V34 ; v2(159.83,107.56) 159.51,107.24 UC1.AA34 ; UC1.AG31 154.75,105.29 v2(155.09,105.63) ; v2(149.59,105.61) 149.27,105.94 UC1.AP32 ; v2(155.09,108.23) 154.75,107.89 UC1.AG35 ; UC1.U31 v2(162.98,104.97) UC1.T30 UC1.T29 UC1.U29 UC1.U30 v2(162.19,104.99) ; v2(163.77,109.52) 163.44,109.84 UC1.T38 ; v2(163.77,109.52) 164.1,109.84 UC1.R38 ; v2(163.77,109.52) 163.45,109.19 UC1.T37 ; v2(155.1,108.86) 155.03,108.86 UC1.AG36 ; v2(151.95,109.55) 152.05,109.55 UC1.AK38 ; v2(151.95,109.55) 152.3,109.19 UC1.AK37 ; v2(151.95,109.55) 151.65,109.84 UC1.AL38 ; v2(148.86,105.62) 149.18,105.29 UC1.AP31 ; v2(161.6,91.39) 161.24,91.03 UC1.W13 ; UC1.AE31 156.27,105.29 v2(155.94,105.62) 156.27,105.94 UC1.AE32 ; v2(156.52,92.22) 156.56,92.18 UC1.AE14 ; UC1.AD14 157.48,91.85 v2(157.1,92.22) ; UC1.AK31 152.31,105.29 v2(151.98,105.63) 152.29,105.94 UC1.AK32 ; v2(162.17,106.3) 161.82,105.94 UC1.V32 ; v2(159.83,108.22) 160.16,107.89 UC1.Y35 ; UC1.AJ14 v2(152.9,92.28) ; v2(153.56,105.63) 153.9,105.29 UC1.AH31 ; v2(157.47,108.87) 157.15,108.54 UC1.AD36 ; v2(152.74,105.61) 153.07,105.29 UC1.AJ31 ; v2(163.77,106.26) 164.1,106.59 UC1.R33 ; UC1.AG14 v2(154.73,92.28) ; v2(154.33,106.27) 154.65,105.94 UC1.AG32 ; UC1.AH14 v2(153.82,92.28) ; v2(158.17,92.2) 158.39,91.98 UC1.AC14 ; v2(162.98,108.87) UC1.U36 ; v2(151.15,106.27) 150.82,106.59 UC1.AM33 ; v2(162.99,108.22) 162.67,107.89 UC1.U35 ; UC1.AB31 158.67,105.29 v2(159.01,105.63) ; v2(151.17,105.61) 151.24,105.61 UC1.AL31 ; UC1.T36 163.45,108.54 v2(163.77,108.87) ; v2(162.18,105.63) 161.85,105.29 UC1.V31 ; UC1.AP30 149.2,104.6 v2(148.84,104.97) ; v2(154.33,105.63) 154.01,105.94 UC1.AH32 ; v2(160.62,107.56) 160.3,107.24 UC1.Y34 ; UC1.AF35 155.54,107.89 v2(155.87,107.57) ; UC1.AM29 UC1.AM30 151.17,104.98 v2(151.19,104.98) ; UC1.V14 162.05,91.77 v2(162.39,92.1) ; v2(155.86,106.94) 155.52,106.59 UC1.AF33 ; v2(164.96,92.18) 164.79,92.01 UC1.P14 UC1.P13 ; v2(157.02,90.57) UC1.AE13 ; v2(159.76,91.45) 159.34,91.03 UC1.AA13 ; v2(159.04,107.56) 158.71,107.89 UC1.AB35 ; v2(158.26,106.26) UC1.AC32 ; UC1.AP36 149.27,108.54 v2(149.59,108.22) ; UC1.R32 164.21,105.98 v2(164.56,106.26) ; v2(158.26,108.22) 157.93,107.89 UC1.AC35 ; v2(167.96,92.12) 168.19,91.89 UC1.K14 168.68,91.2 UC1.K13 ; UC1.AA36 159.51,108.54 v2(159.83,108.87) ; v2(150.38,108.21) 150.05,108.54 UC1.AN36 ; UC1.W38 161.05,109.84 v2(161.41,109.48) ; UC1.AD34 v2(157.47,106.91) ; v2(165.55,92.21) 165.71,92.06 UC1.N14 UC1.N13 ; UC1.AE36 156.36,108.54 v2(156.68,108.87) ; UC1.R31 164.09,105.29 v2(163.77,105.61) UC1.T31 ; UC1.AA31 159.5,105.29 v2(159.83,105.62) ; v2(156.73,107.57) 156.41,107.89 UC1.AE35 ; UC1.W35 v2(161.41,107.56) ; v2(162.98,106.26) UC1.U32 ; UC1.AL29 UC1.AL30 v2(151.95,104.97) ; v2(152.76,107.53) 152.4,107.89 UC1.AK35 ; UC1.AC13 158.81,91.45 v2(158.81,92.2) ; UC1.AD37 v2(157.47,109.52) 157.14,109.84 UC1.AD38 ; UC1.R36 164.21,108.58 v2(164.56,108.87) UC1.R37 ; UC1.L13 UC1.L14 167.36,91.85 v2(167.36,92.15) ; UC1.AK33 152.41,106.59 v2(152.74,106.27) ; UC1.R35 164.1,107.89 v2(163.77,107.56) ; v2(165.35,109.51) 165.68,109.84 UC1.N38 ; UC1.AB36 158.72,108.54 v2(159.04,108.87) ; UC1.Y29 UC1.Y30 ; UC1.AM36 150.84,108.54 v2(151.18,108.21) ; UC1.P31 164.87,105.29 v2(164.56,105.59) 164.91,105.94 UC1.P32 ; UC1.AM14 151.07,91.95 v2(151.4,92.28) ; v2(151.96,107.56) 151.63,107.89 UC1.AL35 ; UC1.V13 v2(162.48,91.46) ; UC1.AN14 150.16,91.95 v2(150.49,92.28) ; UC1.AP37 149.27,109.19 v2(149.59,109.52) 149.27,109.84 UC1.AP38 ; UC1.N36 v2(165.34,108.22) UC1.N35 ; UC1.AG33 154.76,106.59 v2(155.09,106.27) ; v2(162.98,105.61) 163.31,105.94 UC1.T32 ; UC1.AL32 151.64,105.94 v2(151.96,106.26) ; UC1.AE37 156.36,109.19 v2(156.67,109.5) 156.33,109.84 UC1.AE38 ; v2(160.62,108.87) 160.94,108.54 UC1.W36 ; v2(157.93,90.57) UC1.AD13 ; UC1.AN38 150.29,109.55 v2(150.36,109.55) ; UC1.AJ33 153.19,106.59 v2(153.5,106.9) ; UC1.W37 v2(161.41,108.87) ; UC1.AM32 150.74,105.94 v2(150.37,106.31) 150.09,106.59 UC1.AN33 ; v2(153.52,108.23) 153.18,107.89 UC1.AJ35 ; v2(151.19,107.58) 151.09,107.58 UC1.AM35 ; UC1.AH30 153.93,104.6 v2(154.33,105) ; UC1.AC31 157.93,105.29 v2(158.26,105.62) ; UC1.AN31 149.68,104.99 v2(149.59,104.99) ; v2(153.54,104.98) 153.15,104.59 UC1.AJ30 UC1.AJ29 ; v2(155.09,107.6) 154.73,107.24 UC1.AG34 ; UC1.AL36 151.7,108.54 v2(151.96,108.8) 151.56,109.19 UC1.AL37 ; v2(158.26,106.92) 157.93,106.59 UC1.AC33 ; v2(152.74,106.91) 152.42,107.24 UC1.AK34 ; v2(151.99,108.2) 152.33,108.54 UC1.AK36 ; v2(157.47,105.61) UC1.AD31 ; v2(165.35,105.64) 165.69,105.29 UC1.N31 ; 161.08,105.94 UC1.W32 ; UC1.AF32 155.55,105.94 v2(155.87,106.27) ; v2(155.09,106.94) 155.4,107.24 UC1.AF34 ; UC1.AA38 159.51,109.84 v2(159.83,109.52) 159.5,109.19 UC1.AA37 ; UC1.P29 UC1.P30 164.88,104.59 v2(164.53,104.95) ; UC1.P36 165.03,108.54 v2(165.36,108.87) 165.68,109.19 UC1.N37 ; v2(162.98,107.56) UC1.U34 ; UC1.AB38 158.71,109.84 v2(159.04,109.52) 158.72,109.19 UC1.AB37 ; UC1.AN35 150.05,107.89 v2(150.38,107.56) 150.7,107.24 UC1.AM34 ; v2(164.56,107.56) 164.23,107.24 UC1.R34 ; UC1.P35 164.87,107.89 v2(164.53,108.23) ; UC1.V37 v2(162.19,109.52) UC1.V38 161.87,109.84 ; UC1.AF36 v2(155.89,108.22) ; v2(160.62,106.92) 160.3,106.59 UC1.Y33 ; UC1.P34 165.27,107.56 v2(165.34,107.56) ; v2(162.18,106.91) 162.12,106.91 UC1.V33 ; v2(159.01,106.26) 158.96,106.26 UC1.AB32 ; v2(159.83,106.92) 159.5,106.59 UC1.AA33 ; UC1.AN37 150.05,109.19 v2(150.38,108.87) ; UC1.AD35 157.14,107.89 v2(157.47,107.56) ; v2(161.41,108.22) 161.73,108.54 UC1.V36 ; v2(156.73,106.91) 157.05,106.59 UC1.AD33 ; UC1.AJ36 153.07,108.54 v2(152.74,108.22) ; UC1.AF38 155.53,109.84 v2(155.9,109.48) 155.61,109.19 UC1.AF37 ; v2(157.47,106.26) 157.15,105.94 UC1.AD32 ; UC1.W29 UC1.W30 ; UC1.AC34 v2(158.26,107.56) ; v2(160.62,106.26) 160.3,105.94 UC1.Y32 ; v2(159.83,106.26) UC1.AA32 ; UC1.AA35 159.36,107.89 v2(159.04,108.22) ; UC1.AP35 149.27,107.89 v2(149.59,107.56) 149.92,107.24 UC1.AN34 ; v2(155.89,105.02) 155.62,105.29 UC1.AF31 ; UC1.Y36 v2(160.62,108.22) ; v2(157.47,108.22) UC1.AC36
  vias: v1(156.97,119.07) v2(147.63,97.99) v2(148.14,98.3) v2(148.14,97.74) v2(148.33,101.85) v2(149.57,92.28) v2(149.59,106.26) v2(151.46,103.27) v2(151.55,116.84) v2(151.87,117.42) v2(151.99,106.92) v2(152.05,103.27) v2(152.13,116.84) v2(152.28,118.03) v2(152.31,102.69) v2(152.45,117.47) v2(152.71,116.91) v2(152.88,117.99) v2(152.97,102.66) v2(153.03,117.42) v2(153.46,117.99) v2(153.41,116.91) v2(153.51,108.88) v2(153.6,102.69) v2(153.73,118.56) v2(153.73,117.42) v2(153.9,103.21) v2(154.05,117.99) v2(154.11,116.91) v2(154.26,102.69) v2(154.36,117.49) v2(154.43,118.56) v2(154.74,117.99) v2(154.8,119.14) v2(155.13,118.56) v2(155.2,102.68) v2(155.38,119.14) v2(155.44,117.99) v2(155.53,103.22) v2(155.76,118.56) v2(155.84,102.64) v2(155.88,92.22) v2(156.01,119.14) v2(156.14,117.93) v2(156.2,103.21) v2(156.4,118.56) v2(156.52,117.49) v2(156.73,108.22) v2(156.9,117.93) v2(156.97,116.85) v2(157.22,117.42) v2(157.54,117.93) v2(157.6,116.85) v2(157.86,117.42) v2(158.01,103.3) v2(158.24,117.93) v2(158.27,104.98) v2(158.3,116.85) v2(158.55,117.42) v2(158.6,103.3) v2(158.81,94.74) v2(158.94,117.93) v2(159,116.85) v2(158.99,96.04) v2(159.25,117.42) v2(159.63,117.93) v2(159.84,104.98) v2(160.21,97.48) v2(160.4,103.3) v2(160.6,104.98) v2(161.01,103.3) v2(161.67,118.06) v2(161.67,116.98) v2(161.98,117.55) v2(162.36,118.06) v2(162.36,116.98) v2(162.68,117.55) v2(162.84,103.3) v2(163.06,118.06) v2(163.06,116.98) v2(163.44,119.26) v2(163.44,118.63) v2(163.38,117.55) v2(163.42,103.3) v2(163.49,95.45) v2(163.49,94.56) v2(163.76,118.06) v2(163.83,116.98) v2(164.14,117.55) v2(164.12,95.45) v2(164.12,94.56) v2(164.46,118.06) v2(164.62,103.3) v2(164.85,93.36) v2(164.85,92.77) v2(165.16,118.06) v2(165.2,103.3) v2(165.86,118.06) v2(166.17,117.55) v2(166.56,118.06) v2(166.62,116.98) v2(166.68,119.2) v2(166.87,118.63) v2(166.87,117.55) v2(167.25,118.06) v2(167.32,119.26) v2(167.38,116.98) v2(167.57,118.63) v2(167.64,117.55) v2(167.95,119.26) v2(168.02,118.06) v2(168.08,116.98) v2(168.33,118.63) v2(168.33,117.55) v2(168.65,119.26) v2(168.65,118.06) v2(168.71,116.98) v2(168.97,117.55) v2(169.03,118.63) v2(169.29,119.26) v2(169.35,118.06) v2(169.35,117.04) v2(169.67,117.55) v2(172.02,116.85) v2(172.4,117.36) v2(172.72,117.87) v2(172.72,116.85) v2(173.16,117.36) v2(173.6,117.93) v2(173.6,116.91) v2(173.92,118.5) v2(173.92,117.42) v2(174.3,117.93) v2(174.3,116.91) v2(174.62,117.42) v2(175,117.93) v2(175,116.91) v2(175.32,117.42) v2(175.7,117.93) v2(175.76,116.91) v2(176.08,117.42) v2(176.4,117.93) v2(176.46,116.85) v2(176.78,117.42) v2(177.1,118.56) v2(177.1,117.93) v2(177.16,116.85) v2(177.41,117.42) v2(177.8,118.56) v2(177.8,117.93) v2(177.86,116.85) v2(177.92,119.14) v2(178.11,117.42) v2(178.51,119.15) v2(178.49,118.56) v2(178.49,117.93) v2(178.56,116.85) v2(178.81,117.42) v2(179.09,119.14) v2(179.13,117.99) v2(179.26,118.56) v2(179.32,116.85) v2(179.57,117.42) v2(179.76,119.14) v2(179.97,118.59) v2(179.89,117.99) v2(180.02,116.91) v2(180.46,117.49) v2(180.78,118.06) v2(180.78,116.91) v2(181.16,117.49) v2(181.48,118.06) v2(181.54,116.91) v2(181.86,117.49) v2(182.18,118.06) v2(182.24,116.91) v2(182.56,117.49) v2(182.88,118.06) v2(182.88,116.98) v2(183.76,120.3) v2(184.23,120.77) v2(184.34,120.2) v2(184.4,121.49) v2(184.78,120.98) v2(184.92,120.22) v2(185.03,121.55) v2(185.35,120.85) v2(185.53,120.22) v2(185.67,121.55) v2(186.11,120.22) v2(186.11,119.58) v2(186.11,118.96) v2(186.11,118.37) v2(186.11,117.61) v2(186.7,120.22) v2(186.7,119.58) v2(186.75,118.96) v2(186.75,118.37) v2(190.04,116.53) v2(190.05,115.95) v2(190.05,115.36) v2(190.69,116.66) v2(190.69,116.02)
+LCDVDD: length 2.3
  TOP w0.127: v2(132.77,118.18) v4(134.23,118.18)
  TOP w0.508: RV623.1 132.9,118.31 v2(132.77,118.18)
  vias: v2(140.01,132.15) v2(140.65,132.15) v4(142.87,133.55) v4(144.71,133.61)
+LINE1-VREFO-L: length 3.6
  TOP w0.127: DA4.1 290.58,47.32 v1(291.71,48.46)
  TOP w0.381: DA4.1 289.86,47.03 289.54,47.34 RA57.1
+LINE1-VREFO-R: length 2.8
  TOP w0.381: DA5.1 290.41,45.49 v1(289.11,45.49) 288.04,45.49 RA58.1
+MIC2-VREFO: length 0.8
  TOP w0.127: v2(296.35,31.63) v1(296.35,30.81)
  vias: v2(289.24,53.11) v2(296.03,32.14) v2(296.67,32.14)
+PECI_VREF: length 14.1
  TOP w0.254: RE59.2 282.05,94.46 281.8,94.21 v2(281.25,94.21) ; UE1.J11 269.69,94.11 v2(269.74,94.11)
  BOTTOM w0.254: v2(281.25,94.21) 280.61,94.21 v1(279.74,93.33) 278.87,92.47 278.74,92.33 276.97,92.33 276.5,91.86 274.98,91.86 273.69,90.56 271.75,90.56 271.5,90.82 v2(271.5,91.01) ; v2(269.74,94.11) 269.81,94.18 CE25.1
+REGCTL_PNP10:
  vias: v1(276.35,109)
+RREF: length 5.4
  TOP w0.102: v1(288.73,17.85) 289.63,17.85 RR4.1
  TOP w0.305: 292.1,20.84 291.84,20.58 291.02,20.58 290.13,19.7 290.13,19.46 289.9,19.24 289.9,18.15 RR4.1
+RSVD_VCC3P3_1: length 1.8
  TOP w0.508: RL6.1 272.91,109.63 273.29,110.02
+RTC_CELL: length 22.3
  TOP w0.254: v2(277.57,102.32) 277.57,101.76 278.6,100.72 278.63,100.72 279.54,99.82 QE15.3 279.73,99.82 280.56,98.98 v2(281.16,98.98) 281.44,98.98 RE551.2 ; v2(260.48,104.31) 260.85,104.31 261.06,104.1 RE32.2 ; v2(253.3,102.39) 253.28,102.39 252.84,102.83 RE324.2 RE508.2 ; v2(264.68,105.63) 264.72,105.59 RE507.2 ; v2(265.43,110.81) 265.38,110.77 RE31.1
  TOP w0.508: v2(285.87,45.41) RA54.2
  BOTTOM w0.254: v2(287.98,66.49) 287.98,66.61 288.45,67.08 288.93,67.08 289.62,67.76 PC3.1 291.17,68.07 291.59,67.65 PD3.1 ; v2(265.43,110.81) 265.43,109.93 v1(264.79,109.29) 264.68,109.18 v2(264.68,105.63)
+RTC_CELL_PCH: length 7
  TOP w0.508: v2(280.98,107.13) 281.36,107.13 281.87,106.63 281.87,103.45 281.64,103.22 QE15.1
  vias: v1(244.53,111.52) v2(244.15,111.15)
+RTC_CELL_VBAT: length 3.6
  TOP w0.33: CE11.1 262.04,102.22 v2(262.12,102.13) 262.15,102.13 262.55,101.73 262.55,101.37 262.11,100.93 UE1.A2
  TOP w0.508: CE11.1 RE32.1
+SA_CORE: length 13.5
  BOTTOM w0.254: UC1.L35 167.24,107.89 v2(166.92,108.22) ; v2(166.92,105.61) 167.24,105.29 UC1.L31 167.33,105.29 v2(167.67,105.63) ; v2(166.92,105.61) 166.85,105.61 UC1.M32 166.84,106.26 v2(166.93,106.26) ; v2(166.92,105.61) 166.6,105.29 UC1.M31 ; UC1.L37 167.64,108.87 v2(167.66,108.87) ; v2(166.92,109.51) 167.26,109.84 UC1.L38 ; UC1.M33 166.6,106.59 v2(166.92,106.91) 166.85,106.91 UC1.M34 166.84,107.56 v2(166.92,107.56) ; UC1.J30 168.37,104.59 UC1.K30 UC1.K31 168,105.29 v2(167.67,105.63) ; UC1.K33 168.03,106.59 v2(167.71,106.26) 168.03,105.94 UC1.K32 ; v2(167.67,105.63) 167.35,105.94 UC1.L32 ; v2(166.92,108.86) 167.23,108.54 UC1.L36 167.64,108.22 v2(167.71,108.22) 168.03,107.89 UC1.K35 ; UC1.M35 166.6,107.89 v2(166.92,108.22) ; UC1.K34 167.77,107.58 v2(167.66,107.58) ; UC1.M36 166.59,108.54 v2(166.92,108.22) ; v2(166.91,103.63) 166.83,103.63 UC1.M29 ; v2(166.87,104.28) 166.56,104.59 UC1.M30
  vias: v1(195.27,109.56) v2(187.83,109.04) v2(187.89,110.18) v2(188.08,109.61) v2(188.46,109.1) v2(188.53,110.18) v2(188.78,109.61) v2(189.16,110.18) v2(189.16,109.1) v2(189.48,109.61) v2(189.86,110.18) v2(189.86,109.1) v2(190.18,109.61) v2(190.56,110.18) v2(190.56,109.1) v2(190.88,109.61) v2(191.19,110.18) v2(191.19,109.1) v2(191.51,109.61) v2(191.89,110.18) v2(191.89,109.1)
+SDREG2: length 1.1
  TOP w0.102: CR15.1 296.18,27.84 v1(296.29,27.95)
+SIM_PWR: length 6.7
  TOP w0.127: v1(302.51,23.82) 302.57,23.89 v2(303.28,23.89)
  TOP w0.508: v2(305.74,12.08) 304.86,11.2 CZ37.1 CZ41.1 ; RZ335.1 v2(309.05,2.8)
  BOTTOM w0.254: JNGFF2.36 268.33,82.92 268.54,83.13 v2(268.54,83.58)
  BOTTOM w0.508: JSIM1.C1 v2(303.28,23.89)
+TBT_SVR_IND:
  vias: v1(36.38,114.17)
+TBTA_LDO_BMC: length 3.3
  BOTTOM w0.203: UT5.E1 61.7,106.88 61.15,106.88 60.99,106.73 v1(59.7,106.73) 59.08,106.11 CT71.1
+TS_PWR: length 1.1
  BOTTOM w0.254: JEDP1.1 124.76,130.26 v2(124.96,130.06)
  vias: v4(124.14,130.06)
+TS_PWR_QV8: length 1.6
  TOP w0.102: v1(121.22,132.03) 121.76,132.03 122.27,131.52 FV1.2
+USB_EX2_PWR: length 1.4
  TOP w0.127: v2(17.48,95.62) 17.48,96.48 v4(17.86,96.86)
  vias: v2(17.48,94.98) v2(18.12,95.62) v2(18.12,94.98) v2(19.24,87.2) v2(19.24,86.56) v2(19.87,87.2) v2(19.87,86.56)
+USB_EX3_PWR:
  vias: v4(299.58,45.81)
+UZ12_TPM: length 2
  TOP w0.102: v1(248.15,128.98) 248.15,128.73 247.06,127.63 247.07,127.63 247.07,127.48 UZ12.8
+VHDMI_VCC: length 6.3
  TOP w1.016: 301.49,82.12 301.29,82.32 298.69,82.32 298.25,82.75 v1(296.67,82.75) 295.46,82.75
  vias: v2(303.46,82.31) v2(303.97,81.93)
+VR_CAP: length 1.6
  TOP w0.102: CE31.1 258.87,94.76 v1(258.68,94.96)
  TOP w0.356: v2(268.91,99.78) 268.91,99.76 UE1.C10
  vias: v2(259.62,93.5)
+Z4012: length 4.4
  TOP w0.254: v2(34.74,124.39) 34.59,124.24 PQ13.2 34.71,123.46 34.71,122.69 PR9.1
  BOTTOM w0.254: PR2.2 292.92,63.97 PD3.2 v2(292.24,65.56)
AC1_DISC#: length 2.1
  TOP w0.254: PR736.1 v2(143.8,31.04) ; v2(118.45,80.99) 118.33,80.87 118.23,80.87 118.02,80.66 PR1652.1
  BOTTOM w0.102: v2(71.67,110.4) 71.57,110.5 RT72.2
AC1_DISC#_R: length 5.4
  BOTTOM w0.076: UT5.G11 67.18,107.88 67.5,108.2 68.25,108.2
  BOTTOM w0.107: 68.25,108.2 68.93,108.2 69.5,108.78 69.5,110.29 69.72,110.5 RT72.1
AC_DIS: length 135.9
  TOP w0.102: PQ703.2 142.44,32.73 PR720.1 142.95,31.74 142.95,29.86 143.31,29.49 154.26,29.49 154.74,29.97 154.74,36.51 155.49,37.26 162.09,37.26 162.39,36.95 162.39,35.91 164.08,34.22 164.08,29.92 164.52,29.47 215.07,29.47 220.98,35.38 220.98,41.54 221.65,42.21 231.04,42.21 232.38,40.87 233.53,40.87 233.69,41.03 233.69,41.42 235.11,42.85 238.11,42.85 240.2,44.94 v2(240.2,48.11)
  TOP w0.109: RE83.1 275.77,95.96 275.69,95.88 273.25,95.88 272.49,95.11 271.37,95.11 v2(271.34,95.14) 271.31,95.11 271.26,95.11 271.13,94.98 270.42,94.98 UE1.H12
AC_DISC#: length 16.8
  TOP w0.109: v2(271.33,97.14) 271.28,97.19 271.26,97.19 270.87,97.58 UE1.E13
  TOP w0.254: PC810.1 117.09,74.76 116.9,74.96 PQ811.6 116.9,75.31 117.1,75.51 PR829.1 119.34,75.89 119.82,76.38 119.82,79.77 118.94,80.65 118.94,81.19 118.63,81.49 118.11,81.49 v2(118.1,81.51) ; v2(113.22,78.29) PQ810.6 113.39,78.86 113.78,79.25 113.78,80.99 PR828.2 114.02,81.06 114.92,80.16 PQ810.3
AC_PRESENT: length 9.2
  TOP w0.102: v1(238.56,116.99) 238.24,116.67 v2(238.24,116.54)
  TOP w0.109: v2(267.21,93.35) 267.21,93.39 UE1.K8
  BOTTOM w0.089: UH1.BG42 236.76,113.29 237.92,114.45
  BOTTOM w0.109: 237.92,114.45 238.07,114.6 238.07,116.36 v2(238.24,116.54) 238.24,116.64 238.7,117.1 238.7,117.62 238.81,117.72 RH243.1
ACAV_IN: length 6.7
  TOP w0.102: v4(154.34,32.73) 154.34,32.43 153.86,31.95 PR744.1 ; DZ12.1 262.69,81.81 v2(263.52,80.99)
  TOP w0.109: UE1.C7 265.69,99.71 265.69,99.79 v2(265.67,99.79)
  TOP w0.254: PR3010.2 36.19,119.36 36.44,119.1 36.63,119.1 v2(36.76,118.97) ; v2(152.64,31.18) PR740.2 153.3,31.24 PR744.1
ACAV_IN1: length 7.8
  TOP w0.102: PR722.1 139.63,32.91 v4(139.19,33.35)
  TOP w0.254: PR3009.2 37.35,119.4 v2(37.35,119.04) ; v2(141.57,32.94) PR716.1 141.55,32.27 140.91,32.91 PR722.1 140.75,33.59 PQ703.1 140.94,33.91 140.68,34.16 PR710.1 v2(141.27,34.76) ; PR741.1 v2(148.65,30.3)
ACIN_CHG: length 107.5
  TOP w0.254: v2(82.09,94.62) 85.16,91.55 v1(85.16,89.55) 85.16,78.6 91.41,72.35 91.41,55.05 89.21,52.85 89.21,46.31 89.21,46.31 89.21,45.79 92.12,42.87 92.3,42.87 92.49,42.68 116.77,42.68 119.12,40.33 119.12,38.62 119.38,38.36 119.38,36.93 120.39,35.92 120.39,34.52 122.07,32.84 122.88,32.84 124.73,34.68 126.62,34.68 127.29,35.35 127.29,36.72 127.88,37.31 v2(128.07,37.31)
  TOP w0.508: PR3001.2 v2(46.41,120.91)
  BOTTOM w0.203: PU700.19 127.68,37.36 127.73,37.31 v2(128.07,37.31)
  BOTTOM w0.254: PC736.1 128.57,36.98 128.24,37.31 v2(128.07,37.31)
  BOTTOM w0.508: PR705.2 PR706.1 PC736.1
ACOK_CHG: length 2.5
  TOP w0.254: v2(139.95,32.2) 140.16,31.99 PR722.2
  BOTTOM w0.203: PU700.24 127.04,35.36 127.16,35.24 127.16,34.35 v2(127.42,34.1)
ADJ_1.2V_RUN: length 4.2
  BOTTOM w0.102: PR510.1 267.51,61 v1(267.29,60.78)
  BOTTOM w0.254: PU502.3 267.55,61.89 PR510.1 PC509.2 PR512.2
ADJ_2.5V_MEM: length 5.2
  TOP w0.102: v1(143.39,32.17) 143.39,32.22 144.32,33.14 PR516.1
  TOP w0.254: PU503.3 145.89,34.47 145.64,34.21 145.22,34.21 ; PR516.1 144.32,33.27 PC515.2 145.22,34.21 ; 145.22,34.21 PR515.2
ALW_PWRGD_3V_5V: length 11.8
  TOP w0.102: DH2.1 250.66,112.97 v2(250.31,112.97)
  TOP w0.109: UZ6.2 258.2,56.88 258.45,56.63 v2(258.45,56.25)
  BOTTOM w0.102: v2(258.45,56.25) 257.92,56.78 255.27,56.78 v1(254.22,55.73) 253.27,54.79 v2(251.26,54.79)
  BOTTOM w0.254: PR120.2 244.29,43.23 PR119.2 v2(245.11,42.62)
ALWON: length 8
  TOP w0.102: PR114.1 v2(197.21,40.71)
  TOP w0.109: UE1.A5 264.53,100.98 264.53,101.8 265.18,102.45 265.18,105.98 264.41,106.75 v2(263.65,106.75)
AMON/BMON_CHG: length 4.3
  TOP w0.102: v2(124.96,33.28) v1(124.96,33.79)
  TOP w0.254: v2(124.96,33.28) 125.13,33.12 PR743.1 PR729.1
  BOTTOM w0.203: v2(124.96,33.28) 124.55,33.7 PU700.29
  BOTTOM w0.254: PC750.1 125.26,32.99 v2(124.96,33.28)
AR_DET#: length 2.8
  BOTTOM w0.089: 223.44,117.28 223.71,117.02 223.71,116.6 v2(223.29,116.18) ; v2(224.75,108.24) 224.56,108.44 UH1.BB16
  BOTTOM w0.109: 223.44,117.28 RH401.1 RH400.1
AR_DP1_CTRL_CLK: length 8.8
  BOTTOM w0.076: UT1.Y2 45.89,111.76 45.89,112.22 46.33,112.66 46.33,113.05
  BOTTOM w0.102: v1(47.3,118.5) 46.97,118.17 46.97,117.28 46.56,116.87 RT125.1
  BOTTOM w0.107: RT125.1 RT13.1 45.66,116.72 46.41,115.96 46.41,113.13 46.33,113.05
AR_DP1_CTRL_DATA: length 7.3
  BOTTOM w0.076: UT1.Y1 45.7,112.03 45.7,112.41 45.84,112.55 45.84,113.05
  BOTTOM w0.107: 45.84,113.05 46.18,113.39 46.18,115.5 45.27,116.41 44.32,116.41 44.13,116.59 RT124.1 RT12.1
AUD_AZACPU_SCLK: length 22.7
  TOP w0.102: RH38.1 204.47,107.52 204.35,107.4 204.35,104.86 203.69,104.2 200.51,104.2 199.58,103.26 v1(196.78,103.26) 196.57,103.48 193.14,103.48 190.62,105.99 188.72,105.99 188.51,106.2 188.51,106.89 v2(188.08,107.33)
  BOTTOM w0.076: UC1.G27 169.95,102.37 v2(169.6,102.02)
AUD_AZACPU_SCLK_R: length 14.6
  TOP w0.102: v1(206.84,107.68) 206.53,107.37 v2(206.36,107.37)
  TOP w0.109: RH38.2 206.21,107.52 v2(206.36,107.37)
  BOTTOM w0.089: 210.09,107.77 210.44,107.77 212.98,105.23 213.88,105.23 214.97,104.14 215.44,104.14 215.58,104.28 216.31,104.28 216.45,104.14 217.26,104.14 UH1.AM3
  BOTTOM w0.102: 210.09,107.77 206.62,107.77 206.36,107.5 v2(206.36,107.37)
AUD_AZACPU_SDI: length 1.2
  BOTTOM w0.076: UC1.G29 170.25,103.69 v2(170.28,103.69)
  BOTTOM w0.102: RC66.1 178.87,109.73 v2(178.84,109.76)
AUD_AZACPU_SDI_R: length 44.4
  BOTTOM w0.089: 210.09,108.34 210.53,108.34 210.82,108.06 210.82,107.77 210.82,107.67 213.06,105.42 213.96,105.42 215.05,104.33 215.36,104.33 215.53,104.49 216.36,104.49 216.53,104.33 217.73,104.33 UH1.AN3
  BOTTOM w0.102: RC66.2 178.87,107.9 181.62,105.15 195.92,105.15 196.64,104.43 201.82,104.43 v1(204.03,106.64) 205.74,108.34 210.09,108.34
AUD_AZACPU_SDO: length 9.1
  TOP w0.102: RH39.1 204.83,104.04 v1(204.85,104.02) 204.54,103.72 200.92,103.72 199.8,102.59 v2(199.8,102.31)
  BOTTOM w0.076: v2(169.61,101.24) 169.63,101.24 UC1.G25
AUD_AZACPU_SDO_R: length 13.3
  TOP w0.102: RH39.2 205.88,106.82 206.29,106.82 v2(206.36,106.75)
  BOTTOM w0.089: v1(210.09,107.29) 210.66,107.29 212.91,105.04 213.8,105.04 214.9,103.94 215.52,103.94 215.66,104.09 216.23,104.09 216.37,103.94 216.59,103.94 216.83,103.71 UH1.AM2
  BOTTOM w0.102: v1(210.09,107.29) 206.85,107.29 206.36,106.8 v2(206.36,106.75)
AUD_HP_NB_SENSE: length 5.4
  TOP w0.127: v2(300.48,33.3) 299.51,33.3 v4(298.98,33.83)
  TOP w0.254: RA60.2 v2(282.62,48.21) ; v2(300.48,33.3) 301.81,33.3 DA2.3 302.01,33.1 302.01,32.72 301.57,32.28 v2(301.13,32.28)
AUD_HP_OUT_L: length 15.6
  TOP w0.381: RA57.2 RA7.2 v2(287.65,46.43)
  BOTTOM w0.381: LA16.1 297.07,40.76 v1(292.76,45.06) 291.4,46.43 v2(287.65,46.43)
AUD_HP_OUT_L1: length 10.2
  BOTTOM w0.381: LA16.2 297.92,37.32 CA2.2 299.55,37.28 DA1.3 v2(300.88,38.62) 301.62,39.35 JHP1.1
AUD_HP_OUT_R: length 17.5
  TOP w0.381: RA8.2 287.02,45.63 RA58.2 v2(287,44.98)
  BOTTOM w0.381: LA15.1 295.97,36.27 295.52,36.71 295.52,40.71 v1(294.79,41.44) 291.27,44.97 287.02,44.97 v2(287,44.98)
AUD_HP_OUT_R1: length 4.3
  BOTTOM w0.381: v2(301.06,35.68) DA1.2 299.45,35.25 CA3.2 297.92,35.29 LA15.2
AUD_PC_BEEP: length 4.7
  TOP w0.203: CA28.2 280.5,50.07 CA27.2 281.36,50.57 282,51.2 v1(282.06,51.2) 283.59,51.2 283.82,51.44 UA1.11
AUD_PWR_EN: length 19.3
  TOP w0.109: v2(216.16,125.57) 216.16,126.57 RH345.2
  BOTTOM w0.089: UH1.BD8 220.22,109.62 220.22,110.01 220.44,110.22 220.44,110.57 220.61,110.75 220.61,112.32 218.2,114.73 218.2,116.94
  BOTTOM w0.109: 218.2,116.94 218.2,117.04 218.16,117.08 218.16,119.69 217.93,119.92 v1(217.93,122.76) 217.93,123.45 216.16,125.22 v2(216.16,125.57)
AUD_SENSE_A: length 5.5
  TOP w0.203: 283.69,50.67 284.22,51.2 UA1.12
  TOP w0.254: RA59.2 284.22,47.59 283.54,48.28 RA60.1 283.54,50.18 CA41.1 283.6,50.58 283.69,50.67
AUX_EN_WOWL: length 15.5
  TOP w0.102: v2(281.12,87.46) 281.12,87.39 280.73,87.01 278.06,87.01 277.72,86.67 RZ1484.2 277.72,85.38 DZ9.2 ; RZ70.1 RZ379.2 274.06,86.45 v2(274.06,86.92)
  TOP w0.109: v2(262.49,98.96) 262.49,98.91 UE1.D3
  BOTTOM w0.102: v2(281.12,87.46) 280.17,87.46 279.73,87.91 275.05,87.91 v1(274.59,87.45) v2(274.06,86.92)
BAT1_LED#: length 2.1
  TOP w0.127: v2(307.02,9.34) v1(306.38,8.71)
  TOP w0.254: RZ28.1 v2(307.02,9.34) ; UE1.D10 268.83,98.88 v2(268.83,98.88)
BAT1_LED#_R: length 5.5
  TOP w0.127: QZ3.2 261.92,111.06 262.82,111.96 v1(262.82,113.42)
  TOP w0.254: QZ21.1 261.86,111.06 QZ3.2
BAT2_LED#: length 2.5
  TOP w0.127: v1(308.86,8.65) 308.16,9.34 v2(307.91,9.34)
  TOP w0.254: UE1.D11 269.58,98.22 v2(269.68,98.22) ; RZ361.1 v2(307.91,9.34)
BATGONE_CHG: length 5.5
  TOP w0.102: v1(128.84,33.09) 128.55,32.81 PR724.2
  TOP w0.254: PR724.2 PR723.1 PC744.1 126.12,33.43 v2(126.78,34.1)
  BOTTOM w0.203: v2(126.78,34.1) 126.72,34.03 126.46,34.03 126.15,34.35 PU700.25
BATT_WHITE#: length 3.2
  TOP w0.127: RZ361.2 v4(309.23,10.95)
  TOP w0.254: v2(307.57,11.65) 307.57,11.28 RZ361.2
  BOTTOM w0.254: v2(307.57,11.65) JLED1.4
BATT_YELLOW#: length 4.3
  TOP w0.254: RZ28.2 307.02,11.72 v2(307,11.74) ; QZ3.3 261.91,113.19 261.55,113.55 v4(261.04,113.55) v2(260.47,113.55)
  BOTTOM w0.254: JLED1.5 307.07,11.51 307.01,11.57 307.01,11.72 v2(307,11.74)
BBS_BIT6: length 6.1
  TOP w0.109: v2(229.59,107.5) 229.67,107.5 230.06,107.88 230.06,109.8 v1(229.88,109.98) 229.88,110.51 230.76,111.39 RH311.2
  BOTTOM w0.089: v2(229.59,107.5) 229.3,107.5 UH1.BA26
BC_CLK_ECE1117: length 3.4
  TOP w0.102: v2(272.04,98.48) 271.94,98.48 271.77,98.66 271.01,98.66 UE1.D13 ; CZ87.1 187.65,39.24 v2(188.01,38.87)
  BOTTOM w0.102: JKBTP1.10 v2(188.01,38.87)
BC_DAT_ECE1117: length 9.7
  TOP w0.102: UE1.D12 270.34,98.53 270.7,98.88 271.2,98.88 271.22,98.86 272.46,98.86 272.5,98.91 272.72,98.91 272.82,99.01 v2(272.82,99.01) 272.92,99.01 272.98,99.07 RE365.1 ; v2(187.4,38.05) 187.08,38.05 CZ86.1 186.62,37.6 185.86,36.84 v4(185.86,35.25)
  BOTTOM w0.102: v2(187.4,38.05) 187.4,38.19 187.02,38.57 187.02,39.88 JKBTP1.8
BC_INT#_ECE1117: length 10.2
  TOP w0.102: v2(186.61,38.56) 186.61,38.41 v4(185.22,37.03)
  TOP w0.109: v2(259.03,100.91) 258.66,100.54 258.66,100.09 259.02,99.73 259.16,99.73 260.77,98.12 261.68,98.12 UE1.E2 ; CZ85.1 186.76,39.06 186.61,38.91 v2(186.61,38.56)
  BOTTOM w0.109: JKBTP1.7 186.51,38.66 v2(186.61,38.56)
BCM5882_ALERT#: length 17.6
  TOP w0.102: v2(231.77,40.89) 232.24,40.42 233.7,40.42 233.92,40.64 233.92,41.33 235.21,42.62 238.2,42.62 240.61,45.03 v2(240.61,47.69)
  TOP w0.109: v2(268.17,96.52) 268.17,96.44 UE1.G10 ; v2(272.52,93.86) 273.7,93.86 RE532.2
  BOTTOM w0.102: JUSH1.14 230.78,40.42 231.25,40.89 v2(231.77,40.89)
BEEP: length 5.8
  TOP w0.102: RA13.2 276.65,49.17 v2(276.47,49.35)
  TOP w0.109: v2(269.68,95.02) 269.58,95.02 UE1.H11
  BOTTOM w0.102: v2(276.47,49.35) 276.26,49.57 v1(274,49.57) v2(271.98,49.57)
BEEP_R: length 4.4
  TOP w0.102: v1(277.74,51.95) 278.01,51.69 RA45.1
  TOP w0.203: CA62.1 CA28.1 ; CA62.1 RA13.1 ; CA62.1 RA45.1
BGATE_CHG: length 1.6
  TOP w0.102: v2(123.1,33.73) v1(122.56,33.73)
  BOTTOM w0.203: v2(123.1,33.73) 123.35,33.99 PU700.32
  vias: v2(116.45,38.24)
BGPO0_R: length 14.8
  TOP w0.102: RE731.1 266.1,111.63 266.2,111.53 v2(266.2,110.97)
  TOP w0.109: UE1.D6 265.27,98.7 265.05,98.93 264.97,98.93 v2(264.89,99)
  BOTTOM w0.109: v2(264.89,99) 264.95,99 265.27,99.33 265.27,100.6 265.54,100.86 265.54,102.7 264.98,103.26 264.98,105.29 265.09,105.4 265.09,106.46 265.08,106.47 265.08,108.38 266.2,109.5 v1(266.2,110.06) v2(266.2,110.97)
BIA_PWM: length 6.7
  TOP w0.102: RV1.1 136.98,136.27 137.5,135.76 138.51,135.76 v1(138.91,136.16) ; DV1.1 138.11,133.17
  TOP w0.107: 138.11,133.17 137.84,133.17 LV1.2 136.33,135.71 RV1.1
BIA_PWM_EC: length 18.8
  TOP w0.102: DV1.2 138.79,134.14 v2(138.76,134.12)
  TOP w0.109: UE1.N1 260.42,90.48 260.42,90.27 v2(260.55,90.15)
  BOTTOM w0.089: 247.77,92.75 247.67,92.85 v2(247.36,92.85)
  BOTTOM w0.102: v2(260.55,90.15) 260.44,90.15 257.78,92.82 256.18,92.82 253.82,90.46 250.1,90.46 248.03,92.53 247.99,92.53 247.77,92.75
BIA_PWM_PCH: length 1.7
  TOP w0.102: v2(137.54,134.12) 137.49,134.16 DV1.3
  BOTTOM w0.089: UH1.AU48 239.78,105.86 240.11,105.53 240.11,105.38 240.13,105.37 v2(240.13,105.33)
BIOS_REC: length 8.4
  TOP w0.109: v2(237.04,104.53) 237.36,104.85 237.87,104.85 238.44,104.28 v1(238.88,104.28) 240.72,104.28 241.61,105.16 243.69,105.16 RH76.2
  BOTTOM w0.089: v2(237.04,104.53) 236.98,104.6 UH1.AR42
BL_PWR_MONITOR: length 5.4
  TOP w0.102: RV625.2 135.76,120.15 136.57,120.96 QV19.2 137.15,121.29 138.11,122.25 v1(138.11,123.33)
BL_PWR_SRC_ON: length 5.6
  TOP w0.102: v1(127.63,133.3) 127.96,133.63 CV14.1
  TOP w0.107: CV14.1 RV5.1 128.03,135.33 128.77,135.33 RV4.1 128.78,135.33 CV13.1 130.08,135.33 130.41,135.67 QV1.3
BOARD_ID: length 8.1
  TOP w0.102: v1(276.16,93.04) 276.16,94 RE79.2
  TOP w0.109: UE1.J13 271.08,94.73 272.4,94.73 273.3,95.63 275.65,95.63 CE40.1 RE79.2
BOOT1_CHG:
  vias: v1(124.77,40.02)
BOOT2_CHG:
  vias: v1(121.6,36.14)
BREATH_LED#: length 20.2
  TOP w0.102: QZ7.4 284.74,84.4 285.43,84.4 v1(285.62,84.21) 285.62,84.02 v2(285.3,83.7)
  TOP w0.109: UE1.C11 269.63,99.68 v2(269.72,99.68)
  BOTTOM w0.102: v2(269.72,99.68) 269.72,99.54 269.92,99.34 270.73,99.34 271.25,99.87 271.74,99.87 272.13,100.26 275.31,100.26 276.19,101.14 278.28,101.14 279.52,99.9 284.05,99.9 v2(285.47,98.48)
BREATH_LED#_Q: length 2
  TOP w0.102: QZ7.3 281.97,84.26 RZ32.1 v1(280.81,84.03)
BREATH_WHITE_LED_SNIFF#: length 9.2
  TOP w0.102: v2(289.67,83.77) 289.67,83.37 289.54,83.24 282.74,83.24 282.62,83.12 RZ32.2 ; LED3.1 v2(311.88,121)
BS_DDR: length 0.8
  TOP w0.102: v1(173.99,39.32) 173.54,38.87 v2(173.54,38.72)
BS_DDR_R: length 0.9
  TOP w0.102: 171.25,38.36 v1(171.25,39.25)
BST1_CHG_R: length 1.7
  BOTTOM w0.102: PC727.2 121.33,42.19 121.03,42.49 v1(121.03,42.68)
BST1_IA: length 2.8
  TOP w0.102: 161.86,130.8 161.86,130.85 v1(161.49,131.21)
  TOP w0.508: PRH4.1 162.38,131.32 161.86,130.8 v2(161.86,130.76)
  BOTTOM w0.254: v2(161.86,130.76) 161.74,130.64 161.74,130.38 161.58,130.22 PUH1.5
BST1_IA_R: length 3.1
  TOP w0.102: v1(164.33,133.55) 163.8,133.01 PRH4.2
  TOP w0.508: PCH25.1 163.74,132.25 PRH4.2
BST2_IA:
  vias: v2(171.74,130.69)
BST2_IA_R: length 1.2
  BOTTOM w0.102: v1(172.65,133.42) 172.48,133.25 PCH50.1
BST3_IA_R: length 1.2
  BOTTOM w0.102: PRH3.2 v1(181.05,134.04)
BST4_IA_R: length 1.2
  BOTTOM w0.102: PRH10.2 v1(191.63,134.18)
BST_1.05VALWP_R: length 1
  BOTTOM w0.102: PC304.1 v1(198.81,82.67)
BST_3V: length 1.3
  BOTTOM w0.102: PR100.1 250.44,48.08 v1(250.69,48.33)
BST_3V_R: length 1
  BOTTOM w0.102: PC102.1 v1(250.76,50.57)
BST_5V: length 0.6
  TOP w0.102: v2(200.59,34.29) v1(199.96,34.29)
  vias: v2(200.59,34.88)
BST_GT_R: length 1.1
  BOTTOM w0.102: v1(96.15,88.23) 96.67,87.71 PCT12.1
BST_SA: length 3
  TOP w0.102: v1(197.99,119.58) 198.43,119.58 199,120.15 v2(199.13,120.15)
  TOP w0.508: v2(199.13,120.15) 199.19,120.22 PRA2.1
  BOTTOM w0.254: PUA1.5 198.86,119.88 v2(199.13,120.15)
BST_SA_R: length 1.3
  TOP w0.102: PRA2.2 v1(197.86,122.31)
BT_RADIO_DIS#: length 36.6
  TOP w0.102: v2(278.32,36.27) 278.32,36.65 v1(279.71,38.05) 279.97,38.3 DZ2.1
  TOP w0.109: RE11.1 257.14,103.96 v2(257.9,103.2) 257.92,103.2 258.8,102.32 259.18,102.32 260.45,101.05 260.45,100.65 260.92,100.18 260.92,99.91 261.11,99.72 261.68,99.72 UE1.C2
  BOTTOM w0.102: v2(263.26,43.84) 263.25,43.83 262.4,43.83 261.89,43.32 261.89,37.58 262.63,36.84 264.03,36.84 264.47,36.4 265.65,36.4 265.81,36.55 267.52,36.55 268.48,37.5 271.5,37.5 272.23,36.76 274.41,36.76 274.96,37.32 277.26,37.32 v2(278.32,36.27)
BT_RADIO_DIS#_R: length 7
  TOP w0.102: v1(282.89,39.63) 282.89,39 282.6,38.71 DZ2.2
  TOP w0.109: v2(285.71,39.25) 285.64,39.25 285.13,38.75 283.04,38.75 DZ2.2
  BOTTOM w0.109: JNGFF1.54 285.95,40.45 286.1,40.29 286.1,39.59 285.86,39.35 285.81,39.35 v2(285.71,39.25)
C10_PWR_GATE#: length 4.8
  TOP w0.102: RZ542.1 188.3,93.85 188.4,93.95 188.4,94.94 188.58,95.13 188.85,95.13 188.96,95.02 UZ61.4 ; RZ542.1 187.89,93.36 v1(188.34,92.91) ; RZ542.1 187.26,93.85 RH620.1
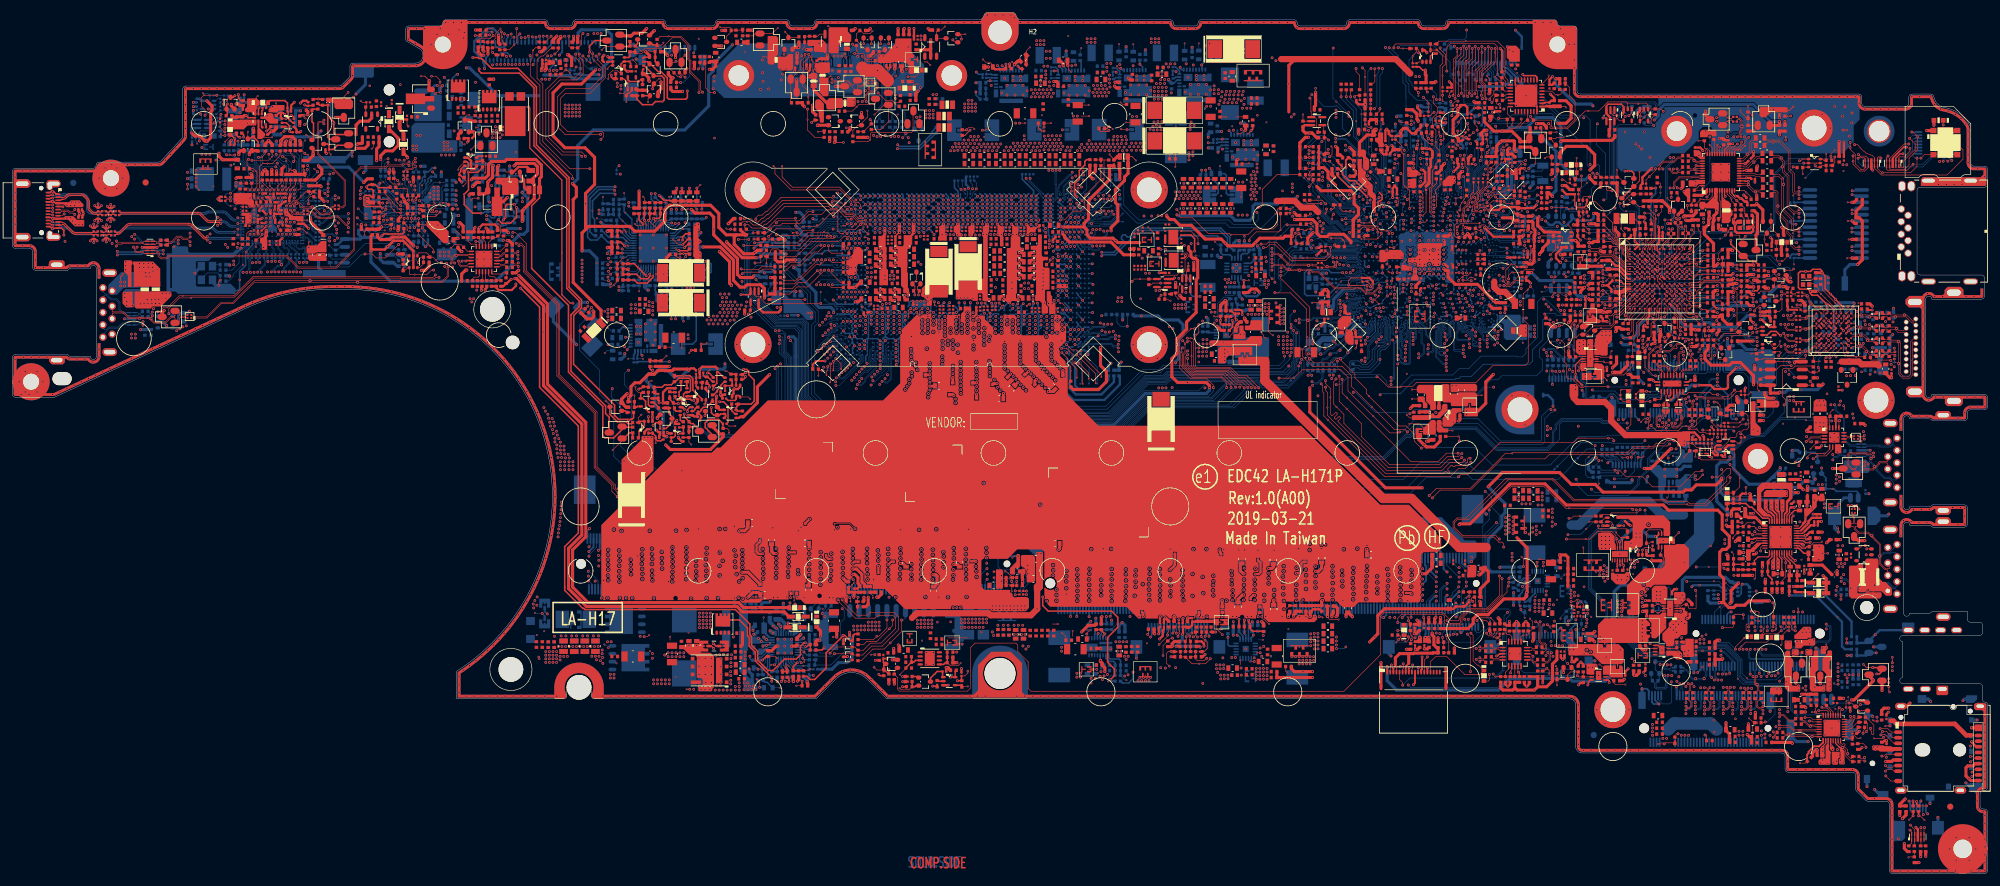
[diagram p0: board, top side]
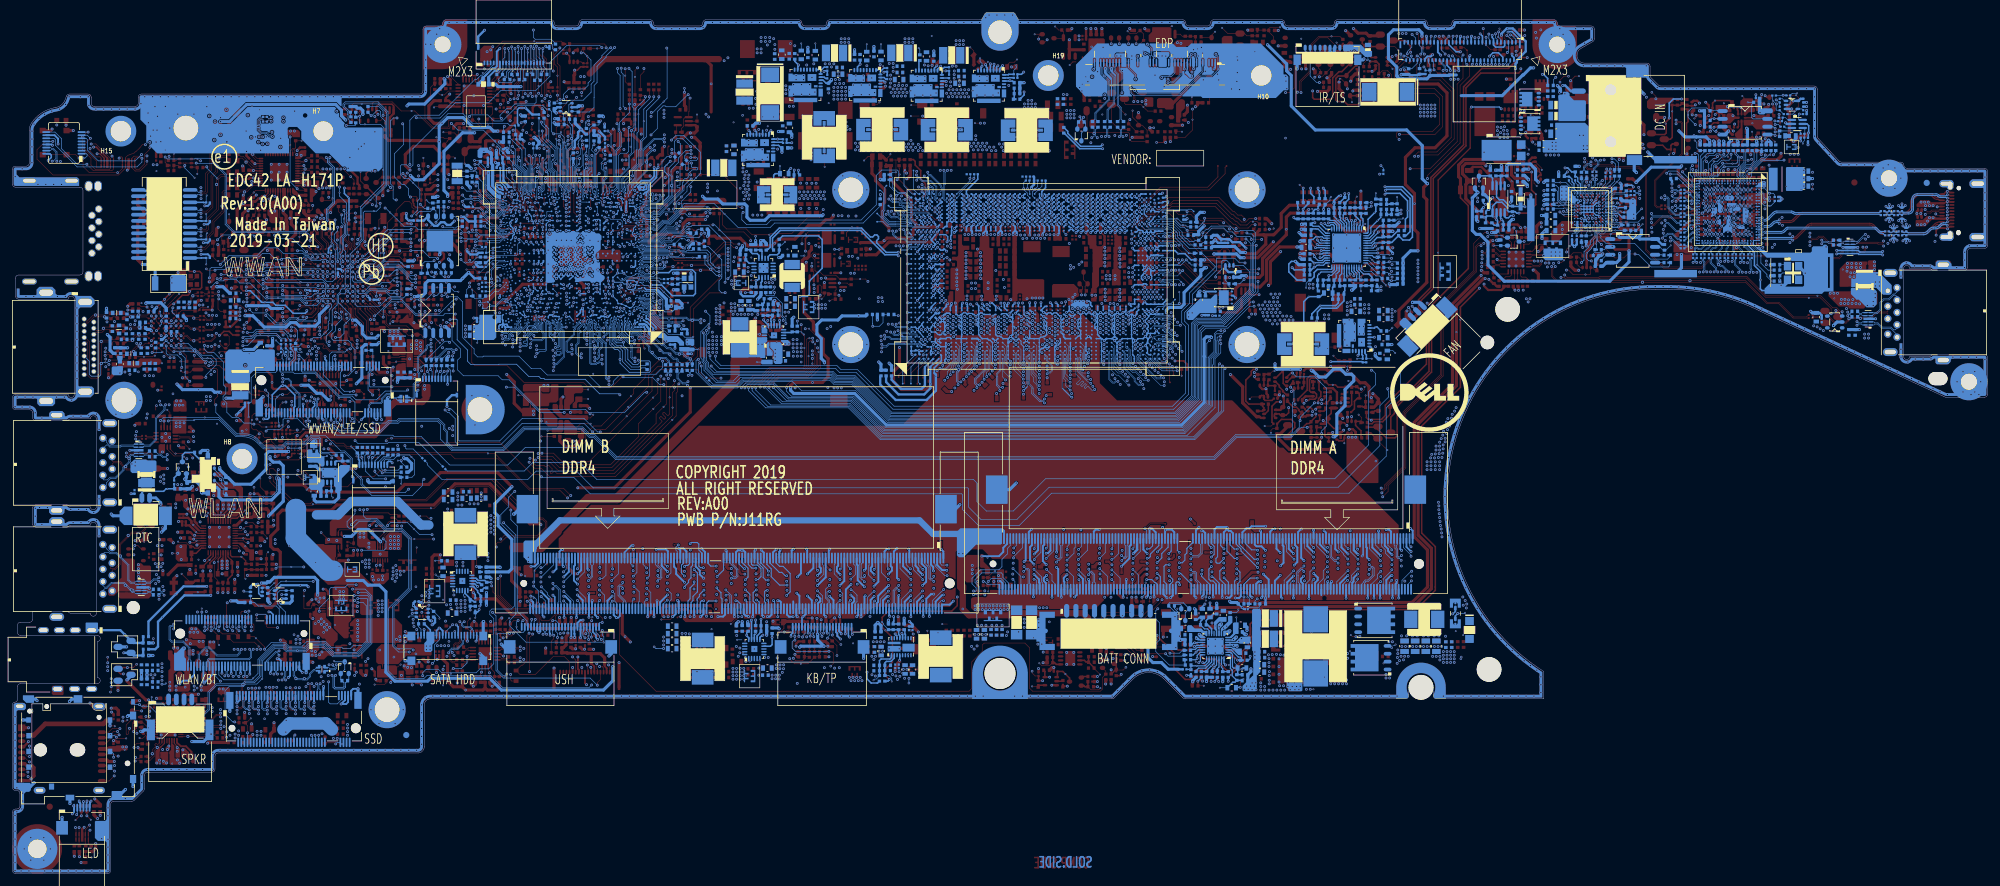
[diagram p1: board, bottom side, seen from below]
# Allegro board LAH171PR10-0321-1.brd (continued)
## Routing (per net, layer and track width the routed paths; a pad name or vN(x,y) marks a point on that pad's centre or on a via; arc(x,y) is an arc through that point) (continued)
C10_PWR_GATE#_R: length 3.6
  TOP w0.102: UZ35.1 186.09,94.8 185.99,94.7 185.99,94.4 186.16,94.22 RH620.2 186.16,92.89 RH619.2 186.62,92.85 186.88,92.59 v1(187.07,92.59)
CAM_MIC_CBL_DET#: length 7.6
  TOP w0.109: RH319.2 211.56,108.84 v2(212.14,108.26)
  BOTTOM w0.089: UH1.AW13 222.23,107.13 v2(221.93,106.82)
  BOTTOM w0.107: v2(133.42,128.66) 133.23,128.85 131.82,128.85 131.26,129.41 JEDP1.14
CBN: length 5
  TOP w0.203: 288.98,55.52 288.86,55.4 UA1.28
  TOP w0.381: CA29.2 CA79.2 290.67,57.52 290.13,56.98 290.13,56.68 v1(289.83,56.38) 288.98,55.52
CBP: length 1.2
  TOP w0.381: v2(290.86,58.1) CA79.1 CA29.1
  vias: v2(288.72,56.86)
CFG0: length 5.6
  TOP w0.102: v2(135.5,101.08) 135.11,100.7 RC321.1
  TOP w0.107: v2(78.99,136.05) 79.07,135.97 v1(79.07,135.21) 79.07,134.57 RC126.1
  BOTTOM w0.076: v2(135.5,101.08) 135.17,100.76 UC1.BN25
  BOTTOM w0.107: JXDP1.9 78.61,134.8 78.99,135.18 v2(78.99,136.05)
CFG1: length 15
  TOP w0.102: RC436.1 124.52,99.58 124.65,99.71 126.61,99.71 129.05,102.14 133.43,102.14 134.3,103.01 135.12,103.01 v2(135.51,102.61)
  BOTTOM w0.076: v2(135.51,102.61) 135.45,102.61 135.17,102.33 UC1.BN27
  BOTTOM w0.107: JXDP1.11 79.21,134.82 79.48,135.08 v2(79.48,135.74)
CFG2: length 2.8
  TOP w0.102: v2(134.85,101.08) 134.85,101.51 RC181.1
  BOTTOM w0.076: v2(134.85,101.08) 135.17,101.41 UC1.BN26
  BOTTOM w0.107: v2(80.57,135.69) 80.57,134.93 80.41,134.77 JXDP1.15
CFG3: length 2.2
  TOP w0.102: v2(74.77,135.46) 75.05,135.46 75.12,135.52 RC121.2
  BOTTOM w0.076: UC1.BN28 135.17,102.98 134.85,102.66 v2(134.85,102.61)
  BOTTOM w0.107: JXDP1.17 v2(81.01,135.18)
CFG4: length 12.9
  TOP w0.102: v2(131.18,97.54) 128.45,94.82 126.73,94.82 125.59,93.67 RC322.1
  BOTTOM w0.076: UC1.BR20 133.58,97.05 133.1,97.05 132.96,96.91 131.81,96.91 v2(131.18,97.54)
  BOTTOM w0.107: JXDP1.27 84.01,134.74 84.16,134.89 84.16,135.13 84.06,135.24 v2(83.98,135.24)
CFG5: length 3.1
  TOP w0.102: v2(135.5,96.36) 135.09,96.36 RC323.1
  BOTTOM w0.076: v2(135.5,96.36) 135.83,96.69 UC1.BM20
  BOTTOM w0.107: v2(84.57,135.19) 84.49,135.11 84.49,134.85 84.61,134.72 JXDP1.29
CFG6: length 11.8
  TOP w0.102: RC324.1 125.98,94.56 126.93,95.51
  TOP w0.109: 126.93,95.51 128.08,95.51 v2(130.02,97.45)
  BOTTOM w0.076: 130.31,97.22 130.42,97.1 v1(130.42,97.04) 130.85,96.61 133.08,96.61 UC1.BT20
  BOTTOM w0.107: v2(85.74,135.35) 85.74,135.1 85.81,135.03 JXDP1.33
  BOTTOM w0.127: 130.31,97.22 130.07,97.45 v2(130.02,97.45)
CFG7: length 7.4
  TOP w0.102: v2(131.81,97.54) 133.8,95.55 RC325.1
  BOTTOM w0.076: v2(131.81,97.54) 132.24,97.12 132.84,97.12 132.97,97.25 133.8,97.25 134,97.05 134.23,97.05 UC1.BP20
  BOTTOM w0.107: v2(86.35,135.35) 86.35,135.1 86.41,135.03 JXDP1.35
CFG8: length 12.5
  TOP w0.102: v2(131.35,99.21) 130.58,98.44 129.79,98.44 127.38,96.02 127.06,96.02 126.36,95.32 124.21,95.32 RC437.1
  BOTTOM w0.076: v2(131.35,99.21) 131.75,99.61 133.38,99.61 UC1.BR23
  BOTTOM w0.107: JXDP1.10 78.91,130.83 v2(78.87,130.79)
CFG9: length 8.4
  BOTTOM w0.076: UC1.BR22 133.5,97.95 132.77,97.95 132.46,98.26 132.25,98.26
  BOTTOM w0.107: JXDP1.12 79.51,130.8 v2(79.52,130.79)
  BOTTOM w0.109: RC439.1 RC438.1 128.61,98.37 v1(128.91,98.68) v2(129.44,99.21) 130.39,98.26 132.25,98.26
CFG10: length 4.8
  TOP w0.102: RC440.1 132.43,98.75 v2(131.98,99.21)
  BOTTOM w0.076: v2(131.98,99.21) 132.46,98.72 132.83,98.72 UC1.BT23
  BOTTOM w0.107: JXDP1.16 80.71,130.78 v2(80.7,130.76)
CFG11: length 11.7
  TOP w0.102: 128.91,98.04 127.27,96.4 127.06,96.4 126.57,95.91 124.52,95.91 RC441.1
  TOP w0.109: 128.91,98.04 v2(130.08,99.21)
  BOTTOM w0.076: UC1.BT22 133.07,98.48 131.93,98.48
  BOTTOM w0.107: v2(81.29,130.79) 81.31,130.82 JXDP1.18
  BOTTOM w0.109: 130.4,98.88 v1(130.57,98.71) 130.8,98.48 131.93,98.48
  BOTTOM w0.127: 130.4,98.88 v2(130.08,99.21)
CFG12: length 7
  TOP w0.102: RC442.1 v2(128.01,92.78)
  BOTTOM w0.076: UC1.BM19 135.83,96.04 v2(136.15,96.36)
  BOTTOM w0.102: v2(84.11,130.76) 84.31,130.97 JXDP1.28
CFG13: length 6.1
  TOP w0.102: RC443.1 132.25,94.74 v2(131.81,95.18)
  BOTTOM w0.076: UC1.BR19 133.87,95.84 133.5,95.47 132.97,95.47 132.87,95.57 132.21,95.57 v2(131.81,95.18)
  BOTTOM w0.102: v2(84.73,132.32) 84.91,132.14 JXDP1.30
CFG14: length 5
  BOTTOM w0.076: v2(131.18,95.18) 131.67,95.67 131.79,95.79 132.99,95.79 133.1,95.67 133.4,95.67 133.52,95.8 133.52,96.06 133.76,96.3 134.2,96.3 UC1.BP19
  BOTTOM w0.102: JXDP1.34 86.11,131.83 v2(86.46,132.17)
CFG15: length 4.6
  BOTTOM w0.076: v1(130.25,95.63) 130.67,96.05 133.14,96.05 UC1.BT19
  BOTTOM w0.102: JXDP1.36 86.71,131.77 87.04,132.1 v2(87.04,132.19)
  BOTTOM w0.127: v1(130.25,95.63) 129.91,95.29 v2(129.91,95.18)
CFG16: length 1.6
  BOTTOM w0.076: v2(134.2,99.51) 134.52,99.18 UC1.BP23
  BOTTOM w0.107: v2(78.27,130.78) 78.04,130.78 77.71,131.11 JXDP1.6
CFG17: length 1.5
  BOTTOM w0.076: UC1.BN23 135.17,99.18 v2(134.85,99.51)
  BOTTOM w0.107: JXDP1.4 77.11,131.13 v2(77.55,130.69)
CFG18: length 1.3
  BOTTOM w0.076: UC1.BN22 135.17,98.26 v2(134.85,97.94)
  BOTTOM w0.107: JXDP1.24 83.11,130.94 v2(83.25,130.81)
CFG19: length 1.2
  BOTTOM w0.076: v2(134.2,97.94) 134.52,98.26 UC1.BP22
  BOTTOM w0.107: v2(82.56,130.79) 82.51,130.84 JXDP1.22
CFG_RCOMP: length 5.8
  BOTTOM w0.254: UC1.BT25 131.26,100.69 v1(130.77,100.2) 129.65,100.2 128.65,99.2 RC114.1
CHR_USB20_N1: length 1.8
  TOP w0.094: UI3.11 296.22,70.75 296.36,70.61 297.35,70.61 LI7.1
CHR_USB20_N1_R: length 16.6
  TOP w0.094: v2(299.13,70.83) 298.92,70.62 298.24,70.62 LI7.2 ; v2(300.64,67.98) 299.51,67.98 299.47,68.01 296.65,68.01 296.36,67.71 296.36,66.06 297.12,65.29 297.7,65.29 297.8,65.2 DI5.2 297.86,64.51 298.57,65.23 300.6,65.23 301.56,66.18 301.56,66.3 301.65,66.39 302.75,66.39 302.93,66.21 JUSB1.2
CHR_USB20_P1: length 1.8
  TOP w0.094: UI3.10 296.21,70.25 296.38,70.42 297.33,70.42 LI7.4
CHR_USB20_P1_R: length 16.3
  TOP w0.094: v2(299.13,70.24) 298.97,70.41 298.24,70.41 LI7.3 ; v2(300.64,67.4) 300.24,67.8 299.43,67.8 299.4,67.83 296.73,67.83 296.54,67.64 296.54,66.13 297.2,65.48 297.7,65.48 297.8,65.57 DI5.3 297.92,66.44 298.95,65.42 300.53,65.42 301.37,66.26 301.37,66.41 301.54,66.58 302.8,66.58 302.93,66.71 JUSB1.3
CLK_CNV_PRX_DTX_N: length 4.3
  BOTTOM w0.089: UH1.BD4 v2(218.17,108.94)
  BOTTOM w0.094: JNGFF1.21 277.7,34.07 277.79,34.15 277.79,34.4 276.43,35.76 276.3,35.76 276.13,35.59 276.13,35.44 v2(275.98,35.29)
CLK_CNV_PRX_DTX_P: length 4.4
  BOTTOM w0.089: UH1.BE3 217.51,109.89 217.41,109.53 217.48,109.43 v2(217.54,109.41)
  BOTTOM w0.094: JNGFF1.23 278.2,34.1 277.97,34.33 277.97,34.48 276.5,35.95 276.03,35.95 v2(275.97,36)
CLK_CNV_PTX_DRX_N: length 10.4
  BOTTOM w0.089: UH1.BC5 218.94,108.79 219.23,108.79 v2(219.32,108.87)
  BOTTOM w0.094: JNGFF1.71 290.2,34.45 290.36,34.6 290.36,36.51 291.45,37.6 293.29,37.6 293.56,37.87 293.56,39.81 293.45,39.92 293.01,39.92 292.92,39.83 292.92,39.62 v2(293,39.55)
CLK_CNV_PTX_DRX_P: length 10.4
  BOTTOM w0.089: v2(218.83,108.41) 218.9,108.35 UH1.BB6
  BOTTOM w0.094: v2(292.98,40.32) 293.2,40.11 293.59,40.11 293.75,39.95 293.75,37.79 293.37,37.41 291.52,37.41 290.54,36.43 290.54,34.6 290.7,34.45 JNGFF1.73
CLK_PCIE_N0: length 8
  BOTTOM w0.094: JNGFF2.53 272.58,77.53 273.94,78.89 273.94,79.56 274.43,80.05 v2(275.39,80.05) ; UH1.AJ6 219.07,101.99 v2(218.76,101.68)
CLK_PCIE_N1: length 2.4
  BOTTOM w0.094: v2(220.2,101.39) 220.3,101.39 220.55,101.64 UH1.AH9 ; v2(284.74,31.97) 284.54,32.18 284.54,32.71 284.7,32.87 JNGFF1.49
CLK_PCIE_N3: length 2.9
  BOTTOM w0.094: UH1.AE6 219.2,100.22 219.67,99.75 v2(219.67,99.72) ; JNGFF3.53 269.82,29.7 269.71,29.81 269.71,30.47 v2(269.93,30.69)
CLK_PCIE_N4: length 9.9
  TOP w0.094: v2(268.93,110.83) 268.93,110.95 268.84,111.05 268.72,111.05 268.53,111.23 268.53,111.7 269.27,112.44 271.28,112.44 271.39,112.55 272.4,112.55 272.57,112.37 UL1.45
  BOTTOM w0.089: UH1.AC2 217.26,99.22 215.6,99.22 215.37,98.99 214.74,98.99 214.56,99.17 214.25,99.17 213.9,99.51 v2(213.9,99.54)
CLK_PCIE_N5: length 10.2
  TOP w0.094: v2(285.39,23.46) 285.59,23.66 287.1,23.66 287.71,23.06 v3(288.74,23.06) 291.22,23.06 291.36,22.92 UR1.6
  BOTTOM w0.089: v2(215.82,98.28) 215.73,98.18 215.53,98.18 215.42,98.29 215.42,98.42 215.79,98.79 217.03,98.79 217.13,98.68 217.44,98.68 217.51,98.61 217.51,98.5 217.45,98.43 217.3,98.43 UH1.AB2
CLK_PCIE_N6: length 3.2
  BOTTOM w0.089: v2(216.1,97.15) 216.1,97.13 216.28,96.95 216.77,96.95 217.21,97.4 217.59,97.4 217.66,97.47 217.91,97.57 218.27,97.57 218.37,97.47 UH1.W4
  BOTTOM w0.094: v2(43.59,103.35) UT1.T19
CLK_PCIE_P0: length 8
  BOTTOM w0.094: UH1.AJ7 219.6,102.04 219.34,101.78 v2(219.34,101.67) ; v2(275.39,79.46) 275,79.86 274.51,79.86 274.12,79.48 274.12,78.81 272.76,77.45 272.76,75.45 273.08,75.14 JNGFF2.55
CLK_PCIE_P1: length 2.3
  BOTTOM w0.094: JNGFF1.47 284.2,32.86 284.35,32.71 284.35,32.17 v2(284.16,31.97) ; UH1.AH10 221.01,101.66 220.92,101.56 v2(220.92,101.35)
CLK_PCIE_P3: length 2.9
  BOTTOM w0.094: v2(220.41,99.67) 220.41,99.67 UH1.AE7 ; v2(269.35,30.69) 269.53,30.51 269.53,29.9 269.32,29.7 JNGFF3.55
CLK_PCIE_P4: length 9.9
  TOP w0.094: UL1.44 272.49,112.77 272.44,112.73 271.31,112.73 271.23,112.65 269.2,112.65 268.35,111.8 v2(268.35,110.83)
  BOTTOM w0.089: UH1.AC3 217.89,98.95 217.67,99.17 217.67,99.17 217.44,99.41 215.52,99.41 215.29,99.18 214.81,99.18 214.55,99.44 v2(214.55,99.54)
CLK_PCIE_P5: length 10.2
  TOP w0.094: v2(285.39,24.05) 285.53,23.91 287.12,23.91 287.78,23.25 288.43,23.25 288.45,23.28 289.03,23.28 289.06,23.25 291.26,23.25 291.33,23.32 UR1.5
  BOTTOM w0.089: v2(215,98.34) 215.07,98.34 215.71,98.98 217.1,98.98 217.21,98.87 217.52,98.87 217.7,98.69 217.7,98.53 UH1.AB3
CLK_PCIE_P6: length 3.2
  BOTTOM w0.089: v2(215.45,97.14) 215.83,96.76 216.85,96.76 217.29,97.21 217.67,97.21 217.74,97.28 UH1.W3
  BOTTOM w0.094: UT1.V19 44.57,103.64 44.27,103.35 v2(44.24,103.35)
CLK_TP_SIO_I2C_DAT: length 4.8
  TOP w0.109: CZ81.1 191.08,35.1 190.44,35.1 RZ23.2 ; CZ81.1 RZ346.2 ; CZ81.1 191.13,34.68 191.4,34.41 192.51,34.41 v2(192.91,34.81) ; v2(268.87,98.19) 268.87,98.12 268.87,98.12 UE1.E10
CLK_TP_SIO_R: length 4.7
  TOP w0.102: v1(189.8,38.81) 190.18,38.42 v2(190.18,38.39)
  TOP w0.109: v2(190.18,38.39) 190.18,37.77 190.3,37.65 CZ89.1 RZ19.2 190.3,35.9 RZ23.1
  BOTTOM w0.109: v2(190.18,38.39) 190.18,38.42 190.1,38.51 190.1,39.08 190.01,39.17 JKBTP1.14
CLKDET#: length 7.1
  BOTTOM w0.089: UH1.BF35 233.15,110.48 233.15,111.33 233.44,111.61 233.44,112.9 233.31,113.03 233.31,115.12 232.71,115.72 T258.1
CLKREQ_CNV: length 3.3
  TOP w0.109: RH618.2 225.71,122.55 225.91,122.35 v2(226.02,122.35)
  BOTTOM w0.089: v2(224.53,106.5) 224.53,107.69 224.62,107.78 UH1.BA17
  BOTTOM w0.109: QZ18.2 281.54,45.54 v2(281.67,45.66)
CLKREQ_CNV_R: length 7.9
  BOTTOM w0.109: JNGFF1.14 275.95,42.79 276.41,43.26 v1(278.82,43.26) 279.33,43.26 279.9,43.83 RZ376.2 280.6,43.84 QZ18.3
CLKREQ_PCIE#0: length 23.6
  TOP w0.102: RH10.2 235.86,122.73 236.22,122.37 v1(236.22,121.36) 236.22,121.1 236.6,120.72 v2(236.6,120.15)
  BOTTOM w0.109: v2(255.2,78.18) 255.38,78 258.82,78 260.04,76.78 260.04,76.77 260.22,76.59 263.56,76.59 264.17,77.19 266.2,77.19 270.08,81.07 272.22,81.07 272.33,81.18 JNGFF2.52
CLKREQ_PCIE#0_R: length 15.1
  TOP w0.102: RH10.1 RH123.1 234.15,122.15 233.58,121.58 v2(233.58,121.46)
  BOTTOM w0.089: 232.84,119.17 232.84,118.73 232.03,117.93 232.03,117.93 231.23,117.13 231.23,115.38 231.83,114.78 231.83,114.1 231.2,113.46 UH1.BF31
  BOTTOM w0.109: v2(233.58,121.46) 233.58,121.07 232.84,120.33 v1(232.84,119.39) 232.84,119.17
CLKREQ_PCIE#1: length 40.9
  TOP w0.102: v2(235.07,121.23) 235.07,120.85 235.15,120.77 RH11.2
  BOTTOM w0.102: JNGFF1.53 285.7,32.12 284.91,31.33 280.4,31.33 v1(280.16,31.57) 279.38,32.34 279.38,34.62 276.91,37.09 275.06,37.09 274.5,36.53 271.91,36.53 271.17,37.27 268.57,37.27 267.03,35.74 263.41,35.74 261.67,37.48 261.67,44.36 261.77,44.46 v2(263.27,44.46)
CLKREQ_PCIE#1_R: length 13.9
  TOP w0.102: RH11.1 234.74,119.67 RH124.1
  TOP w0.109: v2(233.46,120.03) 233.46,119.61 233.89,119.17 RH124.1
  BOTTOM w0.089: 233.46,119.17 233.46,118.9 231.42,116.86 231.42,115.68 v1(231.7,115.4) 232.02,115.08 232.02,114.02 231.43,113.43 231.43,110.05 231.36,109.98 UH1.BE31
  BOTTOM w0.102: v2(233.46,120.03) 233.46,119.17
CLKREQ_PCIE#2_R: length 1.5
  TOP w0.109: v2(232.15,125.59) 232.15,126.15 RH125.1
  BOTTOM w0.089: UH1.AR32 v2(232.27,104.8)
CLKREQ_PCIE#3: length 2.5
  TOP w0.102: RH13.2 232.66,124.41 233.1,124.85 v2(233.48,124.85)
  BOTTOM w0.109: JNGFF3.52 270.07,22.28 v2(270.16,22.36)
CLKREQ_PCIE#3_R: length 2.7
  TOP w0.102: RH126.1 233.32,124.11 232.75,123.54 RH13.1 232.66,122.86 232.51,122.71 v2(232.51,122.5)
  BOTTOM w0.089: v2(231.45,108.15) UH1.BB30
CLKREQ_PCIE#4: length 18.9
  TOP w0.109: UL1.48 272.48,111.17 272.02,110.71 271.91,110.71 RL4.1 272.81,110.46 v2(273.05,110.69) ; v2(230.62,133.46) 230.62,133.23 231.45,132.4 231.45,130.81 231.01,130.37 v1(231.01,128.98) RH14.2
  BOTTOM w0.102: v2(274.19,119.07) 274.19,111.83 v2(273.05,110.69)
CLKREQ_PCIE#4_R: length 3
  TOP w0.102: v1(231.03,124.85) 231.03,125.8 v2(231,125.82)
  TOP w0.109: RH127.1 231.75,126.49 RH14.1 231.01,125.82 v2(231,125.82)
  BOTTOM w0.089: UH1.BA30 230.92,107.8 v2(231.26,107.45)
CLKREQ_PCIE#5: length 53.3
  TOP w0.109: UR1.2 290.83,24.52 290.68,24.67 v2(290.27,24.67) ; v2(227.92,125.45) 228.72,124.65 v1(228.72,124.34) RH15.2
  BOTTOM w0.102: v2(290.27,24.67) 289.03,24.67 287.23,26.46 287.23,29.25 286.04,30.44 281.87,30.44 281.43,30.87 279.93,30.87 278.89,31.92 278.89,34.47 276.72,36.64 275.25,36.64 274.69,36.08 271.72,36.08 270.98,36.82 268.76,36.82 267.22,35.28 263.22,35.28 261.21,37.29 261.21,44.81 261.81,45.41 v2(263.2,45.41)
CLKREQ_PCIE#5_R: length 2.4
  TOP w0.109: RH131.1 228.02,122.49 RH15.1 228.75,122.51 229.01,122.51 229.54,123.04 v2(229.63,123.04)
  BOTTOM w0.089: UH1.AN29 231.03,103.93 v2(231.03,103.93)
CLKREQ_PCIE#6: length 6.7
  BOTTOM w0.076: UT1.AC5 47.2,110.14 48.02,110.97
  BOTTOM w0.089: RH16.2 243.49,101.59 244.23,101.59 v2(244.27,101.54)
  BOTTOM w0.102: 48.02,110.97 48.17,111.11
  BOTTOM w0.107: v2(51.27,113.06) 50.06,113.06 48.25,111.25 48.25,111.19 48.17,111.11
CLKREQ_PCIE#6_R: length 6.9
  BOTTOM w0.089: v1(244.52,101.09) 243.98,101.09 243.84,100.95 242.96,100.95 RH16.1 242.53,101.2 RH132.1 242.24,100.34 241.88,100.7 241.05,100.7 240.88,100.53 239.22,100.53 UH1.AE47
CLKREQ_PCIE#7_R: length 4.9
  BOTTOM w0.089: v1(243.66,97.19) 243.47,97.19 RH133.1 242.48,98.07 241.43,99.11 UH1.AC48
CLKRUN#: length 1.1
  TOP w0.109: v2(232.27,106.32) 231.92,105.96 T287.1
  BOTTOM w0.089: UH1.AV32 v2(232.27,106.32)
CMOUT: length 4.7
  TOP w0.254: v2(112.9,75.32) 112.9,74.5 113.29,74.1 PQ812.2 114.22,74.1 114.42,74.31 PQ811.2 115.03,74.31 115.21,74.13 115.21,73.87 PQ811.3
  BOTTOM w0.203: PR727.1 v2(129.38,32.05)
CNV_BRI_PRX_DTX: length 19
  TOP w0.102: RH614.2 209.87,116.6 209.55,116.91 v2(209.44,116.91) ; RZ1381.1 278,39.95 277.81,39.76 v2(276.22,39.76)
  BOTTOM w0.089: 212.66,113.47 212.66,112.99 212.37,112.7 212.37,111.47 212.36,111.46 212.36,110.94 212.37,110.93 212.37,109.59 214.44,107.52 216.86,107.52 217.04,107.7 217.43,107.7 217.52,107.62 217.52,107.49 217.45,107.43 UH1.AY2
  BOTTOM w0.102: 212.66,113.47 212.66,113.74 211.43,114.96 211.43,115.73 210.25,116.91 v2(209.44,116.91)
CNV_BRI_PRX_DTX_R: length 5
  TOP w0.102: v1(279.59,41.23) v2(279.59,41.83) 279.5,41.92 278.25,41.92 278,41.67 RZ1381.2
  BOTTOM w0.102: v2(279.59,41.83) 279.5,41.92 278.14,41.92 277.95,41.73 JNGFF1.22
CNV_BRI_PTX_DRX: length 21.2
  TOP w0.102: RH603.1 209.46,115.77 v2(209.48,115.75) 209.55,115.75 209.59,115.71 210.04,115.71 RH604.1
  BOTTOM w0.089: 211.21,112.02 211.21,111.35 211.3,111.26 211.6,111.26 211.69,111.17 211.69,111 211.6,110.91 211.3,110.91 211.21,110.82 211.21,110.48 214.75,106.94 215.69,106.94 216.06,106.57 217.17,106.57 217.2,106.54 217.53,106.54 217.62,106.62 218.06,106.62 UH1.AV4
  BOTTOM w0.102: 211.21,112.02 211.21,114.25 RZ1384.2 210.42,114.64 210.31,114.53 210.31,113.79 210.21,113.69 209.99,113.69 209.89,113.79 209.89,114.89 209.48,115.29 208.54,115.29 208.42,115.42 208.42,115.65 208.52,115.75 v1(208.76,115.75) v2(209.48,115.75)
CNV_BRI_PTX_DRX_R: length 3.3
  BOTTOM w0.102: RZ1384.1 210.45,115.56 210.45,116.03 210.05,116.43 209.51,116.43 v2(209.41,116.33) ; JNGFF1.36 v2(281.45,39.89)
CNV_COEX1: length 3.7
  TOP w0.102: v2(209.48,112.93) 209.48,113.36 209.99,113.87 209.99,113.99 ; 209.99,113.99 RH608.1 ; 209.99,113.99 RH607.1
  BOTTOM w0.089: v2(220.35,106.49) 220.37,106.49 220.55,106.31 UH1.AU9
  BOTTOM w0.102: RZ373.2 276.01,83.94 v2(276.18,83.94)
CNV_COEX2: length 1.4
  BOTTOM w0.089: UH1.AW2 216.85,106.77 216.69,106.93 v2(216.69,106.95)
  BOTTOM w0.109: v2(274.94,83.76) 275.05,83.87 275.05,84.14 RZ372.2
CNV_COEX3: length 1.3
  BOTTOM w0.089: UH1.AV6 219.17,106.33 v2(219.39,106.12)
  BOTTOM w0.109: RZ374.2 274.12,83.88 274.11,83.87 274.11,83.85 v2(274,83.74)
CNV_DET#_EC: length 11.5
  TOP w0.102: RE100.2 270.85,86.35 v2(270.8,86.29) 270.59,86.5 RE828.2
  TOP w0.109: v2(268.87,92.57) 268.92,92.57 UE1.L11
  BOTTOM w0.102: v2(268.87,92.57) 268.45,92.14 267.68,92.14 267.52,91.98 267.52,91.47 267.88,91.12 267.88,89.38 268.03,89.23 268.03,87.94 v1(268.69,87.28) 269.34,86.62 270.46,86.62 v2(270.8,86.29)
CNV_PRX_DTX_N0: length 4.9
  BOTTOM w0.089: UH1.BB3 217.1,109.01 216.97,109.01 216.74,108.78 215.77,108.78 215.64,108.92 215.64,109.52 215.47,109.68 215.47,109.89 215.61,110.03 215.77,110.03 215.96,109.84 v2(215.96,109.73)
  BOTTOM w0.094: JNGFF1.15 276.2,32.92 276.38,32.75 276.38,32.41 v2(276.22,32.25)
CNV_PRX_DTX_N1: length 6.6
  BOTTOM w0.089: UH1.BA3 217.26,108.44 216.94,108.44 216.9,108.4 215.14,108.4 214.8,108.74 214.48,109.06 v2(214.48,109.65)
  BOTTOM w0.094: v2(274.91,31.3) 275.08,31.47 275.08,31.68 274.88,31.88 274.88,32.72 274.7,32.9 JNGFF1.9
CNV_PRX_DTX_P0: length 4.9
  BOTTOM w0.089: UH1.BB4 217.52,108.65 216.87,108.65 216.82,108.59 215.69,108.59 215.44,108.84 215.44,109.44 215.18,109.7 v2(215.06,109.7)
  BOTTOM w0.094: v2(276.81,32.25) 276.56,32.5 276.56,32.74 276.7,32.87 JNGFF1.17
CNV_PRX_DTX_P1: length 6.6
  BOTTOM w0.089: UH1.BA2 217.08,108.24 217.01,108.24 216.98,108.21 215.06,108.21 214.28,108.98 214.28,109.31 214.13,109.47 214.07,109.47 v2(213.89,109.65)
  BOTTOM w0.094: v2(275.5,31.3) 275.27,31.53 275.27,31.75 275.07,31.95 275.07,32.77 275.2,32.9 JNGFF1.11
CNV_PTX_DRX_N0: length 23.3
  BOTTOM w0.089: UH1.BE6 219.31,110 219.22,110.09 219.22,110.21 219.32,110.31 219.46,110.31 219.55,110.4 219.55,111.12 218.31,112.35 218.31,113.54 218.11,113.75 217.98,113.75 217.88,113.66 217.76,113.66 217.57,113.84 217.57,113.97 217.67,114.07 217.67,114.19 217.17,114.69 217.17,116.8 216.68,117.28
  BOTTOM w0.094: v2(213.74,118.24) 214.14,118.64 215.33,118.64 216.68,117.28 ; JNGFF1.65 288.7,34.45 288.86,34.6 288.86,35.35 287.74,36.46 287.34,36.46 286.04,35.17 282.68,35.17 282.25,35.6 282.25,36.06 v2(282.05,36.26)
CNV_PTX_DRX_N1: length 17.9
  BOTTOM w0.089: 216,116.81 216.66,116.15 v3(216.66,115.01) 216.66,113.67 218.35,111.97 218.35,111.97 219.01,111.31 219.01,111.02 UH1.BG6
  BOTTOM w0.094: v2(280.14,36.26) 280.4,36 280.4,34.96 280.77,34.59 287.26,34.59 287.39,34.46 287.39,34.24 287.2,34.05 JNGFF1.59 ; 216,116.81 215.62,117.19 215.62,117.2 215.33,117.49 v2(215.33,117.73)
CNV_PTX_DRX_P0: length 23.3
  BOTTOM w0.089: UH1.BD7 219.55,109.79 219.74,109.97 219.74,111.2 218.51,112.43 218.51,113.62 217.36,114.77 217.36,116.88 216.95,117.28
  BOTTOM w0.094: JNGFF1.67 289.2,34.45 289.04,34.6 289.04,35.42 287.82,36.65 287.26,36.65 285.97,35.36 282.76,35.36 282.43,35.68 282.43,36.06 v2(282.63,36.26) ; v2(213.74,118.83) 215.41,118.83 216.67,117.56 216.67,117.56 216.95,117.28
CNV_PTX_DRX_P1: length 17.9
  BOTTOM w0.089: 215.86,116.68 216.47,116.07 216.47,115.32 216.44,115.29 216.44,114.72 216.47,114.7 216.47,113.59 218.24,111.81 218.24,111.6 218.33,111.51 218.54,111.51 218.54,111.51 218.8,111.26 218.8,110.77 219,110.47 UH1.BF6
  BOTTOM w0.094: v2(215.33,116.91) 215.64,116.91 215.74,116.81 215.74,116.8 215.86,116.68 ; JNGFF1.61 287.7,34.15 287.57,34.28 287.57,34.57 287.37,34.77 280.85,34.77 280.58,35.03 280.58,36.12 v2(280.72,36.26)
CNV_RF_RST: length 11.5
  TOP w0.102: RE100.1 270.91,85.76 270.81,85.66 270.81,85 270.66,84.86 v2(270.58,84.86)
  BOTTOM w0.102: v2(270.45,47.23) 270.48,47.23 270.5,47.25 v1(274.82,47.25) 275.65,47.25 276.73,46.17 276.98,46.17 277.81,45.35 RZ377.2
  BOTTOM w0.109: QZ17.6 QZ17.5 276.93,45.3 RZ377.2
CNV_RF_RST#: length 8.1
  TOP w0.102: v2(223.34,115.5) 223.63,115.5 223.96,115.83 RH617.2
  BOTTOM w0.089: v2(223.34,115.5) 223.34,115.47 223.88,114.93 223.88,113.89 223.45,113.47 223.45,112.69 223.78,112.36 223.78,109.89 UH1.BE16
  BOTTOM w0.109: QZ17.2 v2(275.55,45.1)
CNV_RF_RST#_R: length 7.3
  BOTTOM w0.109: JNGFF1.10 274.95,42.3 v1(275.78,43.13) 276.24,43.59 276.24,45.35 275.85,45.75 QZ17.3 274.1,45.75 274.1,45.74 RZ378.2
CNV_RGI_PRX_DTX: length 19.1
  TOP w0.102: RZ1383.1 280.79,40.33 280.15,40.33 280.04,40.23 280.04,39.36 280.15,39.25 v2(280.47,39.25) ; RH613.2 209.65,114.82 209.59,114.76 209.44,114.76 v2(209.36,114.84)
  BOTTOM w0.089: 210.83,110.47 214.54,106.75 215.51,106.75 215.88,106.38 217.09,106.38 217.12,106.35 217.46,106.35 217.63,106.19 217.76,106.19 217.85,106.28 UH1.AV3
  BOTTOM w0.102: v2(209.36,114.84) 209.36,114.24 209.26,114.14 208.48,114.14 208.38,114.04 208.38,113.84 208.48,113.74 209.26,113.74 209.89,113.1 209.89,112.57 210.15,112.31 210.47,112.31 210.69,112.09 210.69,111.77 210.83,111.64
  BOTTOM w0.107: 210.83,110.47 210.83,111.64
CNV_RGI_PRX_DTX_R: length 5.6
  TOP w0.102: v2(281.43,42.34) 282.02,42.34 282.13,42.24 282.13,41.54 282.02,41.44 RZ1383.2 281.58,40.84 v1(282.19,40.84)
  BOTTOM w0.102: JNGFF1.34 280.93,41.09 280.93,41.94 281.33,42.34 v2(281.43,42.34)
CNV_RGI_PTX_DRX: length 21.2
  TOP w0.102: RH605.1 209.5,117.49 v2(209.49,117.49) 208.88,117.49 RH606.1
  BOTTOM w0.089: 213.13,113.94 213.13,113.2 212.58,112.64 v3(212.58,111.2) 212.58,109.65 214.51,107.72 216.53,107.72 216.53,107.71 216.78,107.71 216.96,107.89 217.67,107.89 217.74,107.83 217.74,107.77 217.83,107.67 218.12,107.67 218.33,107.89 218.33,108.01 218.24,108.11 UH1.BA4
  BOTTOM w0.102: 213.13,113.94 212.03,115.05 RZ1382.2 212.03,116.53 212.09,116.58 212.09,118.38 211.69,118.78 210.77,118.78 v2(209.49,117.49)
CNV_RGI_PTX_DRX_R: length 3.3
  BOTTOM w0.102: RZ1382.1 211.13,116.72 211.13,117.95 v2(211.51,118.33) ; JNGFF1.32 v2(280.45,39.88)
CNV_WT_RCOMP: length 11.5
  TOP w0.109: v2(212.78,115.14) 212.07,115.14 RH612.2
  BOTTOM w0.089: UH1.BA1 216.42,107.96 216.36,107.91 214.64,107.91 214.52,108.03
  BOTTOM w0.152: 214.52,108.03 213.01,109.53 213.01,112.76 213.67,113.42 213.67,114.25 v1(213.39,114.53) v2(212.78,115.14)
CNVI_EN#: length 7.3
  TOP w0.102: RE828.1 269.2,86.92 v2(269.41,87.13) ; v2(223.29,114.76) v1(223.86,114.76)
  BOTTOM w0.089: RH868.2 222.87,115.18 v2(223.29,114.76) 223.58,114.47 223.58,113.87 223.2,113.48 223.2,112.48 223.58,112.1 223.58,110.28 UH1.BF15
COMP_1PH_CPU: length 4.7
  BOTTOM w0.203: PCZ12.2 98.2,104.7 v1(98.87,104.03) 99.12,103.78 99.12,103.45 99.86,102.71 PUZ1.50
  BOTTOM w0.254: PCZ12.2 PCZ10.2
COMP_2PH_CPU: length 7.1
  TOP w0.254: PCZ23.2 98.64,95.95 PCZ21.2 100.47,95.95 100.96,95.45 v1(102.42,95.45) 102.55,95.45 103.45,96.35 v2(103.45,96.57)
  BOTTOM w0.203: v2(103.45,96.57) 103.53,96.65 PUZ1.33
COMP_4PH_CPU: length 6.1
  TOP w0.102: 103.71,105.91 103.71,105.59 103.81,105.48 104.64,105.48 v1(104.83,105.67)
  TOP w0.254: v2(103.58,105.91) 104.43,105.91 104.67,106.15 PCZ17.1 104.67,107.49 PRZ42.1
  BOTTOM w0.203: v2(103.58,105.91) 103.27,105.6 103.27,105.47 103.13,105.33 PUZ1.6
COMP_CHG: length 3.4
  BOTTOM w0.203: PR728.1 PC749.1 126.17,32.8 125.36,33.61 v1(125.35,33.61) 125.35,33.62 124.95,34.02 PU700.28
CONTACTLESS_DET#: length 56.2
  TOP w0.102: v2(223.77,39.29) 224.51,39.29 224.79,39.57 DZ8.2
  TOP w0.109: RH90.2 v2(214.63,125.57)
  BOTTOM w0.089: UH1.BG8 220.17,111.94 219.32,112.79 v2(218.88,112.79) 218.88,112.79 218.88,113.51 217.66,114.74 217.66,116.87
  BOTTOM w0.102: v2(239.71,56.72) 237.73,54.73 237.73,41.93 238.69,40.97 v1(238.69,40.71) 238.69,40.01 236.09,37.41 223.62,37.41 223.51,37.51 223.51,38.3 223.77,38.55 v2(223.77,39.29)
  BOTTOM w0.109: 217.66,116.87 217.36,117.16 217.36,118.38 216.66,119.08 216.66,123.26 214.63,125.3 v2(214.63,125.57)
CONTACTLESS_DET#_R: length 3.7
  TOP w0.102: v1(224.98,37.54) 225.23,37.54 225.53,37.84 v2(225.53,38.22) 225.23,38.53 DZ8.1
  BOTTOM w0.109: JUSH1.4 225.78,39.1 225.53,38.86 v2(225.53,38.22)
CPU_2_PCH_TRIGGER: length 23.2
  TOP w0.109: RC177.1 167.04,98.43 167.64,99.03 v2(167.64,99.2)
  BOTTOM w0.089: UH1.AK2 217.32,102.33 214.52,102.33 213.2,103.65 210.98,103.65 210.13,104.51
  BOTTOM w0.109: 210.13,104.51 210.11,104.51 210.03,104.59 209.43,104.59 209.26,104.76 206.55,104.76 v1(204.85,103.07) 203.9,102.11 203.9,97.07 203.89,97.06 203.89,95.64 203.96,95.58 v2(203.93,95.58)
CPU_2_PCH_TRIGGER_R: length 1.8
  TOP w0.109: v2(168.08,99.58) 168.08,98.57 RC177.2
  BOTTOM w0.102: UC1.J23 168.37,99.58 v2(168.08,99.58)
CPU_24MHZ_R_D: length 4
  BOTTOM w0.094: v2(210.02,78.92) 210.24,79.14 210.81,79.14 211.7,80.04 RH169.1 ; UC1.E31 171.25,105.53 170.97,105.25 v2(170.97,105.24)
CPU_24MHZ_R_D#: length 4
  BOTTOM w0.094: UC1.D31 171.59,105.33 v2(171.59,105.26) ; RH170.1 211.52,80.7 211.52,80.12 210.73,79.33 210.12,79.33 v2(209.93,79.51)
CPU_C10_GATE#: length 4.9
  TOP w0.102: UZ61.2 189.61,97.24 RZ543.1 189.91,98.16 v2(189.93,98.18) v1(189.93,98.69)
  TOP w0.109: RH616.1 213.53,107.63 213.23,107.33 213.06,107.33 v2(213.01,107.38)
  BOTTOM w0.102: PR429.1 196.55,93.91 195.96,94.51 v2(195.96,94.82)
CPU_DP1_AUXN: length 24.5
  TOP w0.094: CT19.1 52.87,107.8 53.34,107.8 53.59,108.04 53.59,112.02 50.21,115.39 50.16,115.39 49.28,116.28 49.28,121.35 49.48,121.55 50.09,121.55 v2(50.32,121.78)
  BOTTOM w0.076: UC1.E27 171.25,102.31 171.52,102.04 174.54,102.04 174.95,102.45 176.03,102.45 176.34,102.76
  BOTTOM w0.094: 176.34,102.76 176.36,102.78 176.39,102.78 176.86,103.24 v2(176.86,103.86)
CPU_DP1_AUXN_C: length 9.6
  TOP w0.094: v2(44.89,107.9) 44.93,107.9 45.61,108.57 46.25,108.57 47.05,107.77 v3(48.45,107.77) 48.68,107.77 49.7,106.75 51.16,106.75 51.37,106.95 51.37,107.58 51.62,107.83 51.93,107.83 CT19.2
  BOTTOM w0.094: UT1.W11 v2(44.89,107.9)
CPU_DP1_AUXP: length 24.4
  TOP w0.094: v2(50.32,121.2) 50.16,121.36 49.56,121.36 49.46,121.27 49.46,116.35 50.24,115.58 50.29,115.58 53.77,112.1 53.77,107.97 53.42,107.61 52.87,107.61 CT18.1
  BOTTOM w0.076: UC1.D27 171.9,102.49 171.61,102.49 171.51,102.39 171.51,102.28 171.59,102.21 174.47,102.21 174.88,102.61 175.95,102.61 176.33,102.99 176.34,102.99
  BOTTOM w0.094: 176.27,103.8 176.27,103.74 176.44,103.58 176.57,103.58 176.67,103.48 176.67,103.32 176.34,102.99
  BOTTOM w0.107: 176.27,103.8 v2(176.27,103.86)
CPU_DP1_AUXP_C: length 9.6
  TOP w0.094: CT18.2 51.87,107.64 51.69,107.64 51.55,107.5 51.55,106.88 51.24,106.56 49.63,106.56 48.64,107.55 47.01,107.55 46.82,107.74 46.68,107.74 46.61,107.67 46.44,107.67 46.34,107.76 46.34,107.94 46.42,108.01 46.42,108.14 46.21,108.35 v3(45.91,108.35) 45.66,108.35 45.44,108.13 45.44,107.99 v2(45.54,107.9)
  BOTTOM w0.094: v2(45.54,107.9) 45.54,107.74 45.71,107.57 UT1.Y11
CPU_DP1_N0: length 7.2
  BOTTOM w0.076: 168.39,111.42 168.39,111.4 168.44,111.35 168.44,108.99 168.34,108.89 168.17,108.89 168.1,108.96 UC1.K37
  BOTTOM w0.094: CT11.1 49.79,110.18 50.1,110.18 50.3,110.37 50.86,110.37 v2(51,110.23) ; 168.39,111.42 168.39,111.44 168.4,111.45 168.4,113.28 v2(168,113.68)
CPU_DP1_N0_C: length 3.1
  BOTTOM w0.076: UT1.AC7 46.9,109.22 46.81,109.14 46.81,109.06 46.89,108.98 47.19,108.98 47.39,109.18 47.61,109.18 47.99,109.56 48.02,109.56
  BOTTOM w0.094: 48.02,109.56 48.06,109.56 48.61,110.11 48.83,110.11 CT11.2
CPU_DP1_N1: length 2.3
  BOTTOM w0.076: UC1.J34 169.21,106.92 169.32,106.92 v2(169.33,106.92)
  BOTTOM w0.094: CT13.1 49.68,108.69 50.06,109.07 50.64,109.07 50.92,108.78 50.92,108.68 v2(50.94,108.66)
CPU_DP1_N1_C: length 2.8
  BOTTOM w0.076: UT1.AC9 47,108.3 46.93,108.22 46.93,108.14 47,108.07 47.26,108.07 47.43,108.24 47.43,108.52 47.54,108.62 47.78,108.62 48.02,108.62
  BOTTOM w0.094: 48.02,108.62 48.47,108.62 48.64,108.79 48.89,108.79 CT13.2
CPU_DP1_N2: length 7.9
  BOTTOM w0.076: UC1.H36 169.92,108.79 169.96,108.79 170.17,109 170.17,109.38 169.88,109.67 169.88,110.99 170.14,111.24 170.15,111.24 170.19,111.28 170.2,111.28 170.78,111.86 172.11,111.86 172.11,111.86
  BOTTOM w0.094: v2(50.4,107.15) 50.4,107.36 50.24,107.52 49.67,107.52 CT15.1 ; 172.11,111.86 172.68,112.42 172.81,112.42 172.98,112.25 v2(172.98,112.08)
CPU_DP1_N2_C: length 2.8
  BOTTOM w0.076: 47.86,107.29 47.37,107.29 47.22,107.15 46.87,107.15 46.81,107.21 46.81,107.31 46.89,107.38 UT1.AC11
  BOTTOM w0.094: CT15.2 48.82,107.58 48.17,107.58 47.88,107.29 47.86,107.29
CPU_DP1_N3: length 10.2
  BOTTOM w0.076: 169.39,111.42 169.25,111.28 169.23,111.28 169.16,111.21 169.16,110.94 169.03,110.81 169.03,110.32 169.16,110.18 169.2,110.18 169.42,109.96 169.42,109.62 169.34,109.55 169.2,109.55 169.14,109.61 UC1.J38
  BOTTOM w0.094: CT17.1 49.76,106.53 50.37,106.53 51.45,107.61 51.45,109.15 51.65,109.36 51.94,109.36 v2(52.15,109.56) ; 169.39,111.42 170.76,112.79 171.08,112.79 171.19,112.68 v2(171.19,112.45)
CPU_DP1_N3_C: length 2.7
  BOTTOM w0.076: UT1.AC13 46.89,106.46 46.82,106.54 46.82,106.64 46.86,106.69 47.21,106.69 47.36,106.54 47.86,106.54 47.89,106.58 48.02,106.58
  BOTTOM w0.094: 48.02,106.58 48.84,106.58 CT17.2
CPU_DP1_P0: length 7.2
  BOTTOM w0.076: 168.61,111.42 168.61,108.92 168.41,108.72 168.17,108.72 168.1,108.65 UC1.K36
  BOTTOM w0.094: 168.61,111.42 168.59,111.43 168.59,113.67 v2(168.59,113.68) ; v2(51,110.81) 50.75,110.56 50.22,110.56 50.03,110.37 49.72,110.37 CT10.1
CPU_DP1_P0_C: length 3
  BOTTOM w0.076: UT1.AB7 46.78,109.44 47.23,109.44 47.32,109.34 47.54,109.34 47.88,109.68 47.88,109.69 47.89,109.71
  BOTTOM w0.094: 47.89,109.71 v3(48.12,109.94) 48.48,110.3 48.73,110.3 48.96,110.53 CT10.2
CPU_DP1_P1: length 2.4
  BOTTOM w0.076: UC1.J35 169.21,107.57 169.22,107.57 169.23,107.57 v2(169.33,107.57)
  BOTTOM w0.094: v2(50.95,109.58) 50.95,109.35 50.86,109.25 49.98,109.25 49.85,109.11 49.71,109.11 CT12.1
CPU_DP1_P1_C: length 2.8
  BOTTOM w0.076: 47.89,108.81 47.87,108.79 47.47,108.79 47.2,108.52 46.86,108.52 46.78,108.44 46.7,108.44 UT1.AB9
  BOTTOM w0.094: 48.02,108.83 48.41,108.83 48.62,109.04 48.76,109.04 CT12.2
  BOTTOM w0.097: 47.89,108.81 48,108.81 48.02,108.83
CPU_DP1_P2: length 7.9
  BOTTOM w0.076: UC1.H37 169.74,109.13 169.74,109.06 169.82,108.99 169.93,108.99 170,109.06 170,109.31 169.71,109.6 169.71,111.06 170.08,111.42
  BOTTOM w0.094: v2(173.03,112.92) 173.03,112.85 172.96,112.78 172.96,112.75 172.82,112.61 172.6,112.61 172.03,112.04 170.7,112.04 170.08,111.42 ; CT14.1 49.62,107.99 49.91,107.71 50.24,107.71 50.42,107.88 v2(50.42,107.97)
CPU_DP1_P2_C: length 2.8
  BOTTOM w0.076: 47.87,107.55 47.78,107.46 47.35,107.46 47.2,107.61 46.8,107.61 UT1.AB11
  BOTTOM w0.094: 47.87,107.55 48.09,107.77 48.76,107.77 CT14.2
CPU_DP1_P3: length 10.2
  BOTTOM w0.076: UC1.J37 168.86,109.22 168.86,110.88 168.99,111.01 168.99,111.29 169.13,111.42
  BOTTOM w0.094: CT16.1 49.76,106.34 50.45,106.34 51.64,107.53 51.64,109.08 51.73,109.17 51.95,109.17 v2(52.15,108.98) ; 169.13,111.42 170.68,112.98 171.1,112.98 171.19,113.07 v2(171.19,113.36)
CPU_DP1_P3_C: length 2.7
  BOTTOM w0.076: 48.02,106.39 47.94,106.39 47.9,106.35 47.43,106.35 47.31,106.23 46.84,106.23 46.61,106.46 UT1.AB13
  BOTTOM w0.094: CT16.2 48.76,106.37 48.72,106.37 48.7,106.39 48.02,106.39
CPU_DP2_AUXN: length 8.5
  TOP w0.094: CT184.1 47.88,106.81 48.45,106.81 49.35,105.9 51.51,105.9 51.73,106.12 52.5,106.12 53.9,104.72 54.19,104.72 54.29,104.63 v2(54.29,104.4)
  BOTTOM w0.076: UC1.E26 171.25,101.61 171.5,101.37 v2(171.58,101.37)
CPU_DP2_AUXN_C: length 3.2
  TOP w0.089: CT184.2 47.06,106.57 46.43,106.57
  TOP w0.094: v2(44.89,107.25) 45.09,107.05 45.09,106.71 45.23,106.57 45.77,106.57 45.8,106.54 46.39,106.54 46.43,106.57
  BOTTOM w0.094: UT1.W12 v2(44.89,107.25)
CPU_DP2_AUXP: length 8.6
  TOP w0.094: v2(54.29,105.23) 54.29,105 54.19,104.91 53.97,104.91 52.57,106.31 51.66,106.31 51.44,106.09 49.43,106.09 48.53,106.99 47.83,106.99 CT178.1
  BOTTOM w0.076: v2(170.93,101.37) 170.93,101.51 170.73,101.71 UC1.F26
CPU_DP2_AUXP_C: length 3.1
  TOP w0.089: CT178.2 46.67,106.75
  TOP w0.094: v2(45.52,107.25) 45.41,107.25 45.27,107.1 45.27,106.85 45.36,106.75 v3(46.1,106.75) 46.67,106.75
  BOTTOM w0.094: UT1.Y12 45.54,107.25 v2(45.52,107.25)
CPU_DP2_N0: length 6
  BOTTOM w0.076: UC1.H33 170.03,106.95 v2(170.04,106.95)
  BOTTOM w0.094: v2(54.32,105.82) 54.32,106.03 54.22,106.12 51.25,106.12 50.2,105.07 49.76,105.07 CT187.1
CPU_DP2_N0_C: length 2.8
  BOTTOM w0.076: UT1.AC15 46.89,105.54 46.81,105.46 46.81,105.35 46.86,105.3 47.5,105.3 47.59,105.39 48.02,105.39
  BOTTOM w0.094: CT187.2 48.81,105.05 48.57,105.05 48.24,105.38 48.12,105.38 48.12,105.39 48.02,105.39
CPU_DP2_N1: length 5.8
  BOTTOM w0.094: v2(52.14,104.67) 52.14,104.93 52.02,105.04 51.6,105.04 50.34,103.77 49.74,103.77 CT180.1 ; UC1.G38 170.36,109.84 170.46,109.94 170.46,110.07 170.3,110.23 170.3,110.9 170.5,111.1 170.64,111.1 v2(171.04,111.5)
CPU_DP2_N1_C: length 3.1
  BOTTOM w0.076: 47.94,104.74 47.94,104.75 47.94,104.75 47.5,104.75 47.4,104.65 47.4,104.65 47.34,104.59 47.34,104.5 47.22,104.39 47.04,104.39 46.99,104.44 46.99,104.58 UT1.AC17
  BOTTOM w0.094: 47.94,104.74 47.94,104.74 48.3,104.39 48.3,104.11 48.58,103.83 48.76,103.83 CT180.2
CPU_DP2_N2: length 4.3
  BOTTOM w0.076: UC1.F35 170.53,107.89 170.79,108.15 170.83,108.15 v2(170.9,108.22)
  BOTTOM w0.094: CT179.1 49.74,102.5 50.14,102.5 50.96,103.32 51.61,103.32 51.92,103.01 52.31,103.01 52.52,102.81 v2(52.52,102.71)
CPU_DP2_N2_C: length 3.1
  BOTTOM w0.076: UT1.AC19 46.89,103.7 46.84,103.65 46.84,103.55 46.92,103.47 47.22,103.47 47.4,103.65 47.6,103.65 47.84,103.41 47.84,103.39 47.84,103.39 47.89,103.35 47.88,103.35 47.88,103.33 47.89,103.33
  BOTTOM w0.094: CT179.2 48.79,102.53 48.68,102.53 47.89,103.33
CPU_DP2_N3: length 5.3
  BOTTOM w0.076: v2(172.12,110.79) 172.09,110.82 171.69,110.82 171.62,110.74 171.62,110.15 171.44,109.98 171.44,109.71 171.58,109.57 171.58,109.11 171.25,108.77 UC1.E36
  BOTTOM w0.094: CT181.1 49.67,101.17 49.73,101.17 50.96,102.4 51.1,102.4 v2(51.24,102.25)
CPU_DP2_N3_C: length 3.5
  BOTTOM w0.076: UT1.AC21 46.94,102.78 46.86,102.7 46.86,102.59 46.92,102.54 47.19,102.54 47.37,102.72 47.59,102.72 47.85,102.46 47.85,102.45 47.88,102.41 47.88,102.4 47.89,102.39
  BOTTOM w0.094: CT181.2 48.79,101.26 48.53,101.26 48.32,101.47 48.32,101.96 47.89,102.39
CPU_DP2_P0: length 6
  BOTTOM w0.076: UC1.H34 169.68,107.24 170.02,107.58 v2(170.02,107.58)
  BOTTOM w0.094: v2(54.29,106.69) 54.29,106.46 54.14,106.31 51.18,106.31 50.12,105.26 49.76,105.26 CT186.1
CPU_DP2_P0_C: length 2.8
  BOTTOM w0.076: 48.02,105.58 47.37,105.58 47.17,105.78 46.8,105.78 46.75,105.72 46.75,105.72 UT1.AB15
  BOTTOM w0.094: 48.02,105.58 48.31,105.58 48.64,105.24 48.78,105.24 CT186.2
CPU_DP2_P1: length 5.7
  BOTTOM w0.094: v2(171.04,110.92) 170.58,110.92 170.48,110.82 170.48,110.31 170.64,110.15 170.64,109.51 170.46,109.33 UC1.F37 ; v2(52.09,105.6) 52.09,105.45 51.87,105.22 51.53,105.22 50.26,103.96 49.79,103.96 CT183.1
CPU_DP2_P1_C: length 3.1
  BOTTOM w0.076: 48.02,104.92 47.43,104.92 47.36,104.84 46.79,104.84 UT1.AB17
  BOTTOM w0.094: 48.02,104.92 48.03,104.92 48.08,104.87 48.08,104.87 48.48,104.47 48.48,104.19 48.58,104.09 48.89,104.09 CT183.2
CPU_DP2_P2: length 4.2
  BOTTOM w0.076: UC1.F34 170.53,107.24 170.87,107.58 v2(170.9,107.58)
  BOTTOM w0.094: v2(52.39,103.53) 52.39,103.29 52.29,103.2 52,103.2 51.68,103.51 50.88,103.51 50.06,102.69 49.79,102.69 CT185.1
CPU_DP2_P2_C: length 3.1
  BOTTOM w0.076: UT1.AB19 46.7,103.84 46.81,103.94 47.22,103.94 47.35,103.81 47.67,103.81 48.02,103.46
  BOTTOM w0.094: 48.02,103.46 48.76,102.72 48.79,102.72 CT185.2
CPU_DP2_P3: length 5.2
  BOTTOM w0.076: v2(172.12,111.37) 171.73,110.98 171.62,110.98 171.45,110.81 171.45,110.22 171.27,110.04 171.27,109.57 171.2,109.49 171.08,109.49 171,109.42 171,109.27 171.08,109.19 UC1.E37
  BOTTOM w0.094: v2(51.24,102.84) 50.99,102.58 50.89,102.58 49.82,101.52 49.69,101.52 CT182.1
CPU_DP2_P3_C: length 3.5
  BOTTOM w0.076: UT1.AB21 46.61,102.78 46.84,103.01 47.19,103.01 47.33,102.88 47.66,102.88 48.02,102.52
  BOTTOM w0.094: CT182.2 48.79,101.45 48.6,101.45 48.51,101.54 48.51,102.04 48.02,102.52
CPU_DP3_AUXN: length 4
  TOP w0.094: v2(285.74,94.06) 285.97,93.83 286.62,93.83 CV602.1
  BOTTOM w0.076: v2(174.52,104.09) 174.77,103.84 174.77,103.34 174.4,102.98 173.68,102.98 173.44,102.75 173.44,102.57 173.37,102.49 UC1.B27
CPU_DP3_AUXN_C: length 6.2
  TOP w0.094: UV31.C8 293.02,90.52 293.17,90.52 293.26,90.61 293.26,90.84 293.1,91.01 292.74,91.01 292.06,91.69 291.21,91.69 290.25,92.65 290.25,93.05 v3(289.9,93.39) 289.56,93.73 289.28,93.73 CV604.2
CPU_DP3_AUXN_R: length 2.1
  TOP w0.094: RV602.2 287.31,94.29 CV602.2 287.5,93.73 287.97,93.73 288.16,93.93 CV604.1
CPU_DP3_AUXP: length 4
  TOP w0.094: v2(285.74,93.48) 285.9,93.64 286.35,93.64 286.63,93.36 CV601.1
  BOTTOM w0.076: v2(175.1,104.09) 174.93,103.92 174.93,103.28 174.47,102.82 173.75,102.82 173.61,102.68 173.61,102.57 173.69,102.49 UC1.A27
CPU_DP3_AUXP_C: length 6.2
  TOP w0.094: CV603.2 289.22,93.49 289.49,93.49 290.06,92.92 290.06,92.52 v3(290.5,92.08) 291.08,91.5 291.98,91.5 292.6,90.88 292.6,90.13 UV31.C7
CPU_DP3_AUXP_R: length 2.1
  TOP w0.094: CV603.1 288.16,93.36 287.97,93.55 287.5,93.55 CV601.2 287.31,92.99 RV601.2
CPU_DP3_N0: length 8.2
  TOP w0.094: CV32.1 287.77,89.5 287.69,89.42 286.95,89.42 286.73,89.64 v2(286.73,90.25)
  BOTTOM w0.076: 176.34,108.64 176.32,108.64 176.3,108.62 175.86,108.62 175.25,108.01 175.07,108.01 174.41,107.36 173.07,107.36 172.92,107.51 172.19,107.51 UC1.D34
  BOTTOM w0.094: v2(176.9,109.03) 176.9,108.71 176.82,108.63 176.35,108.63 176.34,108.64
CPU_DP3_N0_C: length 3
  TOP w0.094: CV32.2 288.83,89.61 289.58,89.61 v3(289.75,89.79) 290.02,90.05 291.08,90.05 UV31.A7
CPU_DP3_N1: length 5.9
  TOP w0.094: CV34.1 286.76,87.77 286.32,88.2 286.32,88.74 v2(286.29,88.78)
  BOTTOM w0.076: UC1.B34 173.53,108.01 174.05,108.01 174.39,108.34 175.35,108.34 175.53,108.52 175.53,108.82 v2(175.73,109.02)
CPU_DP3_N1_C: length 3.1
  TOP w0.094: CV34.2 288.99,87.99 v3(289.68,87.99) 290.33,87.99 290.78,88.44 291.26,88.44 291.4,88.3 UV31.A5
CPU_DP3_N2: length 9.4
  TOP w0.094: CV36.1 288.12,85.99 286.87,85.99 286.19,86.68 286.19,87.24 v2(286.11,87.32)
  BOTTOM w0.076: v2(176.33,107.12) 176.33,107.07 176.02,106.76 176.02,106.55 175.85,106.38 173.65,106.38 173.28,106.75 171.15,106.75 171.01,106.62 171.01,106.51 171.09,106.43 UC1.E33
CPU_DP3_N2_C: length 3.3
  TOP w0.094: CV36.2 288.96,86.12 v3(289.75,86.12) 290.2,86.12 290.93,86.84 291.3,86.84 291.4,86.75 UV31.A3
CPU_DP3_N3: length 3.3
  TOP w0.094: CV38.1 286.89,84.15 286.32,84.72 v2(286.32,85.48)
  BOTTOM w0.076: UC1.B33 172.93,106.16 172.93,106.03 v2(172.94,106.03)
CPU_DP3_N3_C: length 3.4
  TOP w0.094: UV31.A1 291.4,85.15 291.3,85.24 291.17,85.24 290.2,84.27 288.83,84.27 CV38.2
CPU_DP3_P0: length 8.2
  TOP w0.094: v2(287.32,90.24) 287.29,90.24 286.95,89.9 286.95,89.7 287.05,89.61 287.61,89.61 CV31.1
  BOTTOM w0.076: UC1.C34 172.68,107.34 172.85,107.34 173.02,107.18 174.47,107.18 175.14,107.85 175.32,107.85 175.48,108.01 175.59,108.01 175.65,107.95 175.75,107.95 175.83,108.03 175.83,108.13 175.77,108.19 175.77,108.3 175.93,108.45 176.33,108.45 176.34,108.45
  BOTTOM w0.094: v2(177.48,109.03) 177.19,108.74 177.18,108.74 176.9,108.45 176.36,108.45 176.34,108.45
CPU_DP3_P0_C: length 3.1
  TOP w0.094: UV31.A8 291.36,90.54 291.06,90.24 289.9,90.24 289.5,89.84 288.98,89.84 CV31.2
CPU_DP3_P1: length 5.9
  TOP w0.094: v2(286.87,88.78) 286.51,88.42 286.51,88.28 286.84,87.95 287.79,87.95 288.18,88.34 CV33.1
  BOTTOM w0.076: UC1.B36 173.39,108.17 173.98,108.17 174.32,108.51 175.28,108.51 175.37,108.59 175.37,108.8 175.19,108.98 v2(174.87,108.98)
CPU_DP3_P1_C: length 3.1
  TOP w0.094: UV31.A6 291.4,88.77 291.25,88.63 290.71,88.63 290.25,88.17 290.01,88.17 289.97,88.21 289.39,88.21 289.36,88.17 288.93,88.17 CV33.2
CPU_DP3_P2: length 9.3
  TOP w0.094: v2(286.81,87) 286.68,87.13 286.49,87.13 286.38,87.02 286.38,86.76 286.95,86.18 287.86,86.18 288.18,86.5 CV35.1
  BOTTOM w0.076: UC1.F33 170.77,106.43 170.84,106.51 170.84,106.68 171.08,106.92 173.34,106.92 173.72,106.55 175.78,106.55 175.86,106.62 175.86,107 175.78,107.07 v2(175.66,107.07)
CPU_DP3_P2_C: length 3.2
  TOP w0.094: UV31.A4 291.4,87.12 291.3,87.03 290.85,87.03 290.16,86.34 288.93,86.34 CV35.2
CPU_DP3_P3: length 3.3
  TOP w0.094: v2(286.88,85.22) 286.63,85.22 286.5,85.1 286.5,84.79 286.96,84.33 287.68,84.33 287.78,84.43 287.78,84.63 287.87,84.72 CV37.1
  BOTTOM w0.076: v2(172.23,106.09) 172.55,106.41 UC1.C33
CPU_DP3_P3_C: length 3.4
  TOP w0.094: UV31.A2 291.4,85.52 291.3,85.43 291.09,85.43 290.15,84.49 v3(289.62,84.49) 288.93,84.49 CV37.2
CPU_VIDALERT#: length 23.7
  TOP w0.102: RC153.2 118.01,105.38 v1(118.68,105.38) 119.09,105.38
  TOP w0.109: 119.09,105.38 119.64,104.83 120.69,104.83 121.31,105.45 121.51,105.45 121.95,105.89 122.14,105.89 124.57,108.33 131.65,108.33 131.98,108 133.2,108 134.71,106.5 135.74,106.5 136.69,105.55 137.72,105.55 v2(137.78,105.61)
  BOTTOM w0.076: UC1.BH31 138.11,105.29 v2(137.78,105.61)
CPU_XDP_HOOK6: length 4.5
  TOP w0.102: v1(90.04,129.42) 89.55,129.91 v2(89.42,129.91) 89.34,129.91 88.65,129.22 RC115.1 87.82,129.22 RC144.1
  BOTTOM w0.102: JXDP1.46 89.53,131.3 89.53,130.03 v2(89.42,129.91)
CPU_XDP_PRDY#: length 8.8
  TOP w0.102: v2(77.58,132.72) 77.95,132.34 RC314.1 ; v2(131.81,101.48) 131.81,100.73 132.27,100.28 T189.1
  BOTTOM w0.076: UC1.BP27 134.03,101.77 132.66,101.77 132.6,101.83 132.17,101.83 v2(131.81,101.48)
  BOTTOM w0.107: v2(77.58,132.72) 77.59,132.72 77.59,132.73 77.41,132.91 JXDP1.5
CPU_XDP_PREQ#: length 15.4
  TOP w0.102: v2(77.67,135.46) 77.23,135.02 75.52,135.02 75.24,134.74 RC138.2
  BOTTOM w0.076: UC1.BL30 136.11,104.15 132.61,104.15 v2(132.58,104.18) 132.04,104.18 131.15,103.29
  BOTTOM w0.107: JXDP1.3 76.81,134.71 77.55,135.46 v2(77.67,135.46)
  BOTTOM w0.109: 131.15,103.29 131.15,102.7 130.04,101.6 130.04,101.29 T190.1 128.69,100.28 RC315.1
CPU_XDP_PRS: length 2.4
  TOP w0.102: v2(248.48,108.66) 248.24,108.42 RC127.1
  BOTTOM w0.102: v2(94.78,132.46) 94.76,132.44 94.76,131.73 94.51,131.48 JXDP1.60
CPU_XDP_TCLK: length 42.8
  TOP w0.102: v2(95.01,119.49) 89.24,119.49 88.02,120.71 88.02,125.56 89.34,126.88 93.37,126.88 95.31,128.83 95.31,130.07 93.74,131.65 v2(93.74,132.51) ; T181.1 121.79,99.76 RC143.1 122.42,100.39 122.42,100.66 122.74,100.98 123.64,100.98 RC139.1 124.34,100.66 126.88,100.66 128.85,102.62 132.64,102.62 132.77,102.75 v2(132.77,102.95)
  BOTTOM w0.076: v2(132.77,102.95) 132.95,102.76 133.58,102.76 UC1.BR28
  BOTTOM w0.107: JXDP1.57 93.01,133.59 93.74,132.86 v2(93.74,132.51)
CPU_XDP_TDI: length 23.3
  TOP w0.102: v2(137,104.93) 136.15,104.09 134.79,104.09 T185.1 133.78,103.43 133.35,103.86 133.35,107.03 133.1,107.28 131.44,107.28 130.72,106.56 128.71,106.56 127.25,105.1 124.36,105.1 124.05,104.79 123.05,104.79 v2(122.46,104.21) 121.83,103.58 RC229.1
  BOTTOM w0.076: v2(137,104.93) 137,105.53 136.6,105.93 UC1.BL32
  BOTTOM w0.107: JXDP1.56 92.71,131.53 93.09,131.91 v2(93.09,132.15)
CPU_XDP_TDO: length 19.6
  TOP w0.102: v2(119.88,101.95) 119.93,102 121.14,102 121.36,102.22 RC230.1 RC135.1 123.43,101.93 126.8,101.93 128.46,103.58 131.69,103.58 132.19,103.09 v2(132.19,103.01) ; v2(92.15,132.16) 93.27,131.04 T184.1
  BOTTOM w0.102: v2(132.19,103.01) 132.58,103.4 132.87,103.4 UC1.BT28 ; JXDP1.52 91.51,131.06 91.75,130.82 CC306.1
  BOTTOM w0.107: JXDP1.52 91.51,131.66 92.02,132.16 v2(92.15,132.16)
CPU_XDP_TMS: length 41.3
  TOP w0.102: v2(95.05,118.66) 95.49,119.1 95.49,119.69 95.21,119.97 89.65,119.97 88.5,121.12 88.5,125.28 89.34,126.12 93.29,126.12 95.79,128.63 95.79,130.27 94.48,131.58 94.48,131.94 v2(94.29,132.14) ; v2(131.6,103.02) 131.49,103.13 128.68,103.13 127.09,101.55 T180.1 RC228.1
  BOTTOM w0.076: 132.24,103.63 132.97,103.63 133.12,103.48 134.1,103.48 UC1.BP28
  BOTTOM w0.102: v2(131.6,103.02) 131.6,103.42 131.81,103.63 132.24,103.63
  BOTTOM w0.107: JXDP1.58 93.31,131.74 93.53,131.95 93.76,131.95 93.97,132.16 94.26,132.16 v2(94.29,132.14)
CPU_XDP_TRST#: length 157.7
  TOP w0.102: v2(126.77,103.57) 126.04,103.57 T179.1
  BOTTOM w0.076: UC1.BP30 134.04,105.11 131.51,105.11 130.11,103.71
  BOTTOM w0.089: UH1.AM4 217.99,103.49 217.3,103.49 217.27,103.46 216.99,103.46 216.81,103.28 214.92,103.28 213.35,104.85 212.83,104.85 211.01,106.66 210.35,106.66 210.24,106.56
  BOTTOM w0.102: v2(98.2,113.05) 98.17,113.09 RC844.2 ; 128.9,102.18 128.19,102.18 128.01,102.36 RC136.1 ; v2(207.44,87.4) 207.44,83.27 207.42,83.24 207.42,82.77 207.08,82.44 207.08,81.55 205.14,79.61 202.62,79.61 201.76,80.48 186.78,80.48 186.1,79.8 183.21,79.8 177.26,73.84 131.03,73.84 127.9,76.97 127.9,88.68 127.5,89.08 123.58,89.08 118.54,94.12 118.54,101.88 118.3,102.12 118.3,103.61 118.65,103.96 120.71,103.96 120.84,103.83 121.54,103.83 121.85,104.15 121.85,104.17 122.34,104.66 125.41,104.66 125.94,104.13 126.21,104.13 v2(126.77,103.57) ; v2(206.79,106.25) 206.88,106.16 207.64,106.16 ; 210.24,106.56 209.84,106.16
  BOTTOM w0.109: v2(126.77,103.57) 126.77,103.01 127.41,102.36 RC136.1 ; 128.9,102.18 129.41,102.69 129.54,102.69 130.11,103.26 130.11,103.71 ; 209.84,106.16 207.64,106.16
CPU_XDP_TRST#_XDP: length 4.8
  BOTTOM w0.102: v2(94.82,129.92) 94.38,130.36 93.8,130.36 CC308.1 93.01,130.08 92.11,130.98 JXDP1.54 ; RC844.1 97.59,114.02 v2(98,114.42)
CSCL: length 2.6
  TOP w0.109: UV31.E6 294.64,88.94 294.98,89.28 294.98,89.29 v2(294.99,89.29)
  BOTTOM w0.102: v2(294.99,89.29) 294.99,88.78 v1(295.21,88.57)
  BOTTOM w0.109: v2(294.99,89.29) 294.99,89.5 294.38,90.1 RV605.1
CSCOMP_2PH_CPU: length 12.6
  BOTTOM w0.203: PUZ1.31 104.33,96.96 104.64,96.65 PCZ28.2
  BOTTOM w0.254: PCZ28.2 PCZ29.2 103.88,94.98 PRZ49.2 103.83,94.19 103.97,94.05 PRZ52.2 103.97,92.56 v1(104.95,91.58) 105.14,91.39 107.67,91.39 108.25,90.8 PHZ3.2
CSCOMP_4PH_CPU: length 14.9
  BOTTOM w0.203: PUZ1.8 103.93,105.01 104.52,105.6 104.52,105.99
  BOTTOM w0.254: PHZ2.2 148.59,119.97 148.59,119.66 146.48,117.55 143.25,117.55 v2(143,117.8) ; v2(103.2,109.91) 103.2,109 PRZ50.2 PRZ48.1 103.84,107.62 PCZ25.2 PCZ26.2 104.64,106.12 104.52,105.99
CSDA: length 2.9
  TOP w0.102: v2(297.94,90.85) 298.34,91.26 RV606.1
  TOP w0.109: v2(295.84,90.13) 295.82,90.1 295.82,89.31 295.44,88.94 UV31.F6
  BOTTOM w0.102: v1(296.1,89.61) 295.84,89.86 v2(295.84,90.13)
CSIN_CHG: length 4.7
  BOTTOM w0.254: PC726.1 125.04,41.97 PR702.2 125.71,41.41 126.22,40.9 PC719.2 125.98,40.21 125.35,39.58 PU700.14
CSIN_CHG_R: length 3.2
  BOTTOM w0.102: v2(85.59,42.05) 84.51,42.05 v1(84.4,42.16)
  BOTTOM w0.254: v2(85.59,42.05) 85.97,41.67 PR700.3 ; PR702.1 v2(125.6,43.75)
CSIP_CHG: length 4.8
  BOTTOM w0.203: PC719.1 126.49,39.56 126.03,39.56 125.75,39.28 PU700.15
  BOTTOM w0.254: PC719.1 127.14,40.76 126.85,41.05 PR701.2 127.31,41.4 127.64,41.07 PC725.1
CSIP_CHG_R: length 2.1
  BOTTOM w0.254: v2(126.42,43.57) 126.85,43.15 PR701.1 ; v2(86.42,41.98) 86.36,41.98 85.97,42.36 PR700.2
CSN_1PH_CPU: length 7
  BOTTOM w0.203: v1(99.16,102.3) 99.55,101.91 PUZ1.48
  BOTTOM w0.254: PCZ2.1 PCZ5.1 96.24,102.93 95.24,103.94 PRZ5.2 ; PCZ2.1 97.62,102.95 PCZ8.1 ; PCZ2.1 97.73,102.82 98.61,102.82 99.13,102.3 v1(99.16,102.3)
CSON_CHG: length 8.9
  BOTTOM w0.102: v1(124.01,30.05) PR734.1
  BOTTOM w0.203: PC752.2 122.01,31.97 122.01,32.87 122.31,33.17 122.31,35.11 122.56,35.36 PU700.1
  BOTTOM w0.254: PC753.1 120.45,31.24 PC752.2 121.59,30.93 121.92,30.93 PR734.1
CSON_CHG_R: length 3.3
  TOP w0.102: v2(120.72,30.11) 120.72,30.93 v1(120.2,31.44)
  TOP w0.254: v2(113.28,36.4) 112.9,36.78 PR711.3
  BOTTOM w0.254: PR734.2 121.34,30.11 v2(120.72,30.11)
CSOP_CHG: length 7.7
  BOTTOM w0.102: v1(121.6,34.81) 121.66,34.74 121.66,34.11 121.13,33.58 PR733.1
  BOTTOM w0.203: PU700.2 122.29,35.76 122.22,35.69 122.22,35.69 121.98,35.45 121.98,33.42 121.78,33.22 121.14,33.22 PR733.1
  BOTTOM w0.254: PC748.1 120.42,32.15 PC752.1 121.13,32.3 PR733.1
CSOP_CHG_R: length 2
  TOP w0.254: PR711.2 113.66,36.78 113.28,37.16 v2(113.22,37.16)
  BOTTOM w0.254: v2(120.45,33.03) 120.25,33.23 PR733.2
CSP1_2PH_CPU: length 6.1
  BOTTOM w0.203: PUZ1.28 105.53,97.61 105.9,97.24 107.66,97.24 v1(107.96,96.94) 108.23,96.67 108.23,95.94 PRZ73.1
  BOTTOM w0.254: PRZ73.1 PCZ36.1 108.23,94.31 PRZ71.1
CSP1_4PH_CPU: length 6.2
  BOTTOM w0.102: v1(106.07,109.39) 106.23,109.23 106.23,108.85 106.9,108.18 PRZ64.2
  BOTTOM w0.203: PUZ1.11 105.13,104.79 105.56,105.22 106.43,105.22 v2(106.48,105.17)
  BOTTOM w0.254: PCZ35.1 PRZ65.1 v2(107.26,107.35) 107.26,107.69 107.01,107.94 PRZ64.2
CSP2_2PH_CPU: length 6.5
  BOTTOM w0.102: PRZ51.2 109.56,95.94 110.08,95.41 v1(110.08,94.7)
  BOTTOM w0.203: PUZ1.27 105.93,97.78 106.06,97.65 106.63,97.65
  BOTTOM w0.254: 106.63,97.65 108.28,97.65 108.79,97.14 108.79,96.45 109.3,95.94 PRZ51.2
CSP2_4PH_CPU: length 6.3
  TOP w0.102: v2(108.14,107.35) 108.99,107.35 v1(109.08,107.44)
  BOTTOM w0.203: v2(107.07,105.08) 106.7,104.71 106.24,104.71 106.06,104.89 105.74,104.89 105.53,104.68 PUZ1.12
  BOTTOM w0.254: PCZ37.1 PRZ74.1 108.91,107.1 108.65,107.35 v2(108.14,107.35) 108.14,107.82 107.95,108.02 PRZ72.2
CSP3_4PH_CPU: length 5
  BOTTOM w0.203: PUZ1.13 106.87,104.18 107.66,104.97 v2(107.66,105.08)
  BOTTOM w0.254: PRZ75.2 109.74,108.27 110.56,107.44 v2(110.56,107.39) PRZ76.1 PCZ38.1
CSP4_4PH_CPU: length 6.1
  BOTTOM w0.203: PUZ1.26 106.89,98.71 107.27,98.33 v1(107.98,98.33) 108.31,98.33 108.61,98.03 v2(108.79,98.03)
  BOTTOM w0.254: PCZ39.1 109.23,97.59 v2(108.79,98.03) ; PCZ39.1 PRZ77.2 ; PCZ39.1 PRZ81.1 ; v2(111.36,107.4) 111.37,107.4 111.37,107.69 111.45,107.77 PRZ80.2
CSP_1PH_CPU: length 21.4
  BOTTOM w0.203: PUZ1.47 99.48,101.51 99.06,101.93 97.7,101.93 PCZ2.2
  BOTTOM w0.254: v2(193.33,113.99) 193.67,113.65 PRZ4.1 ; v2(97.35,111.02) 94.5,111.02 92.91,109.43 92.91,102.87 93.37,102.4 94.44,102.4 PRZ3.2 96.24,102.02 PCZ5.2 PCZ2.2
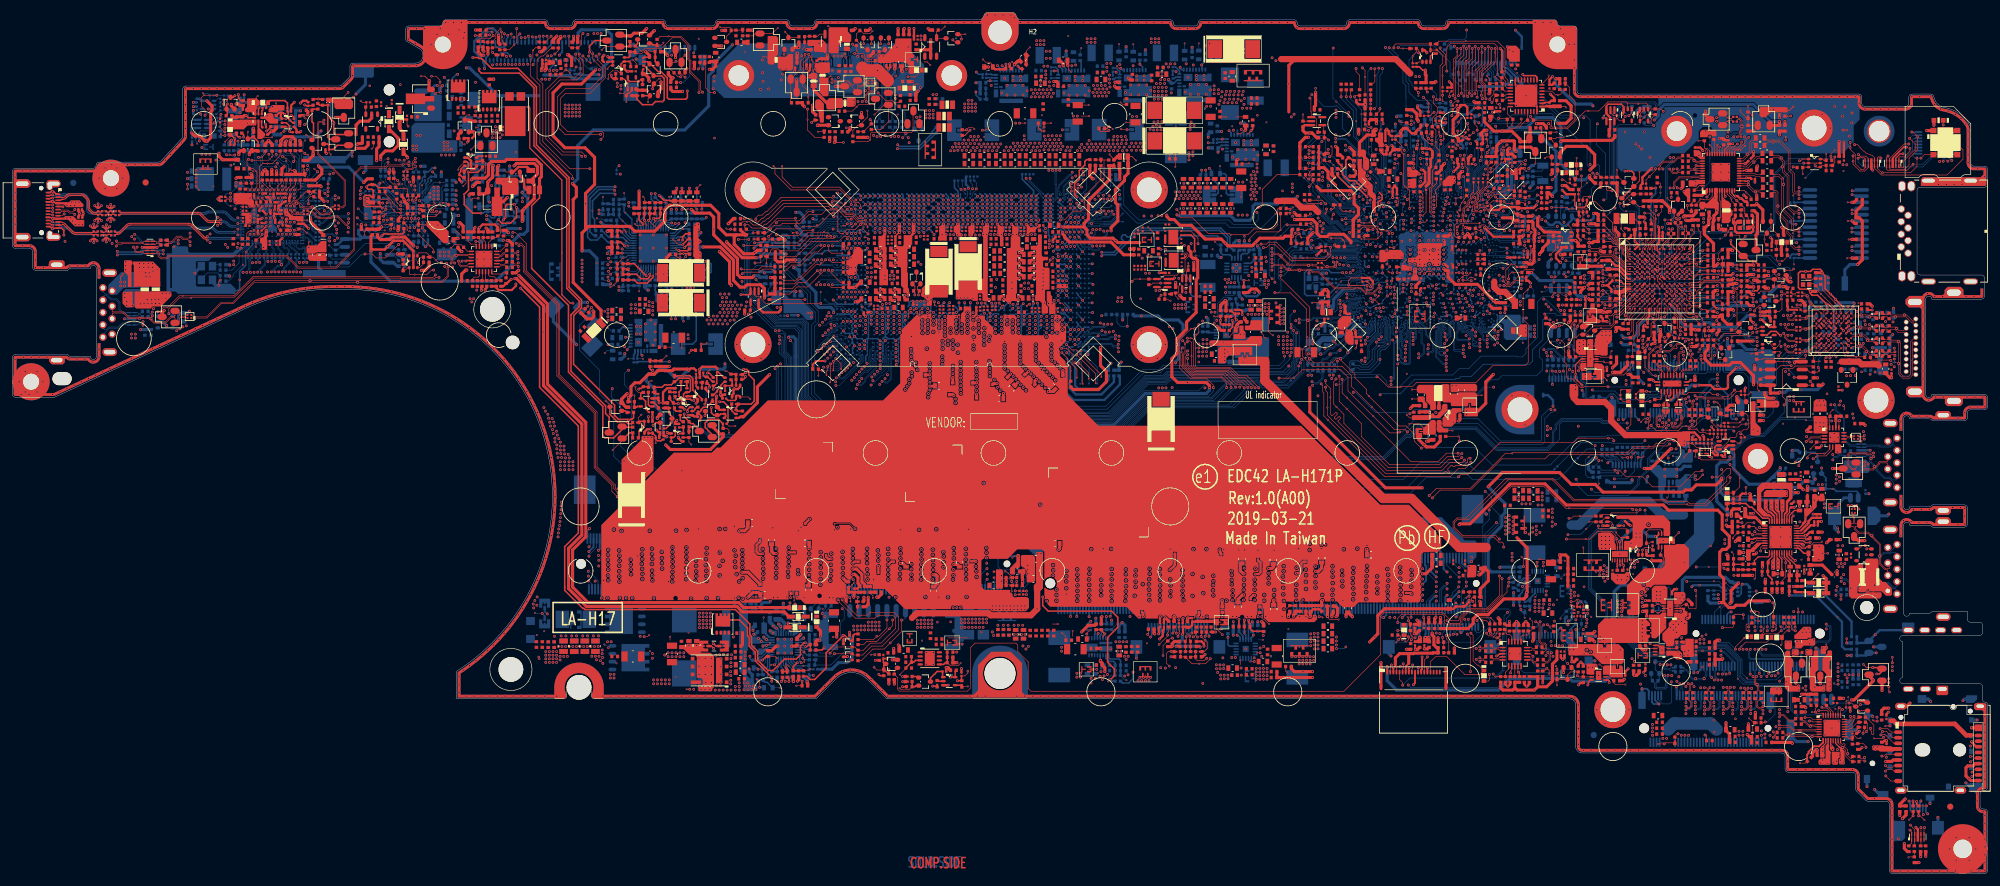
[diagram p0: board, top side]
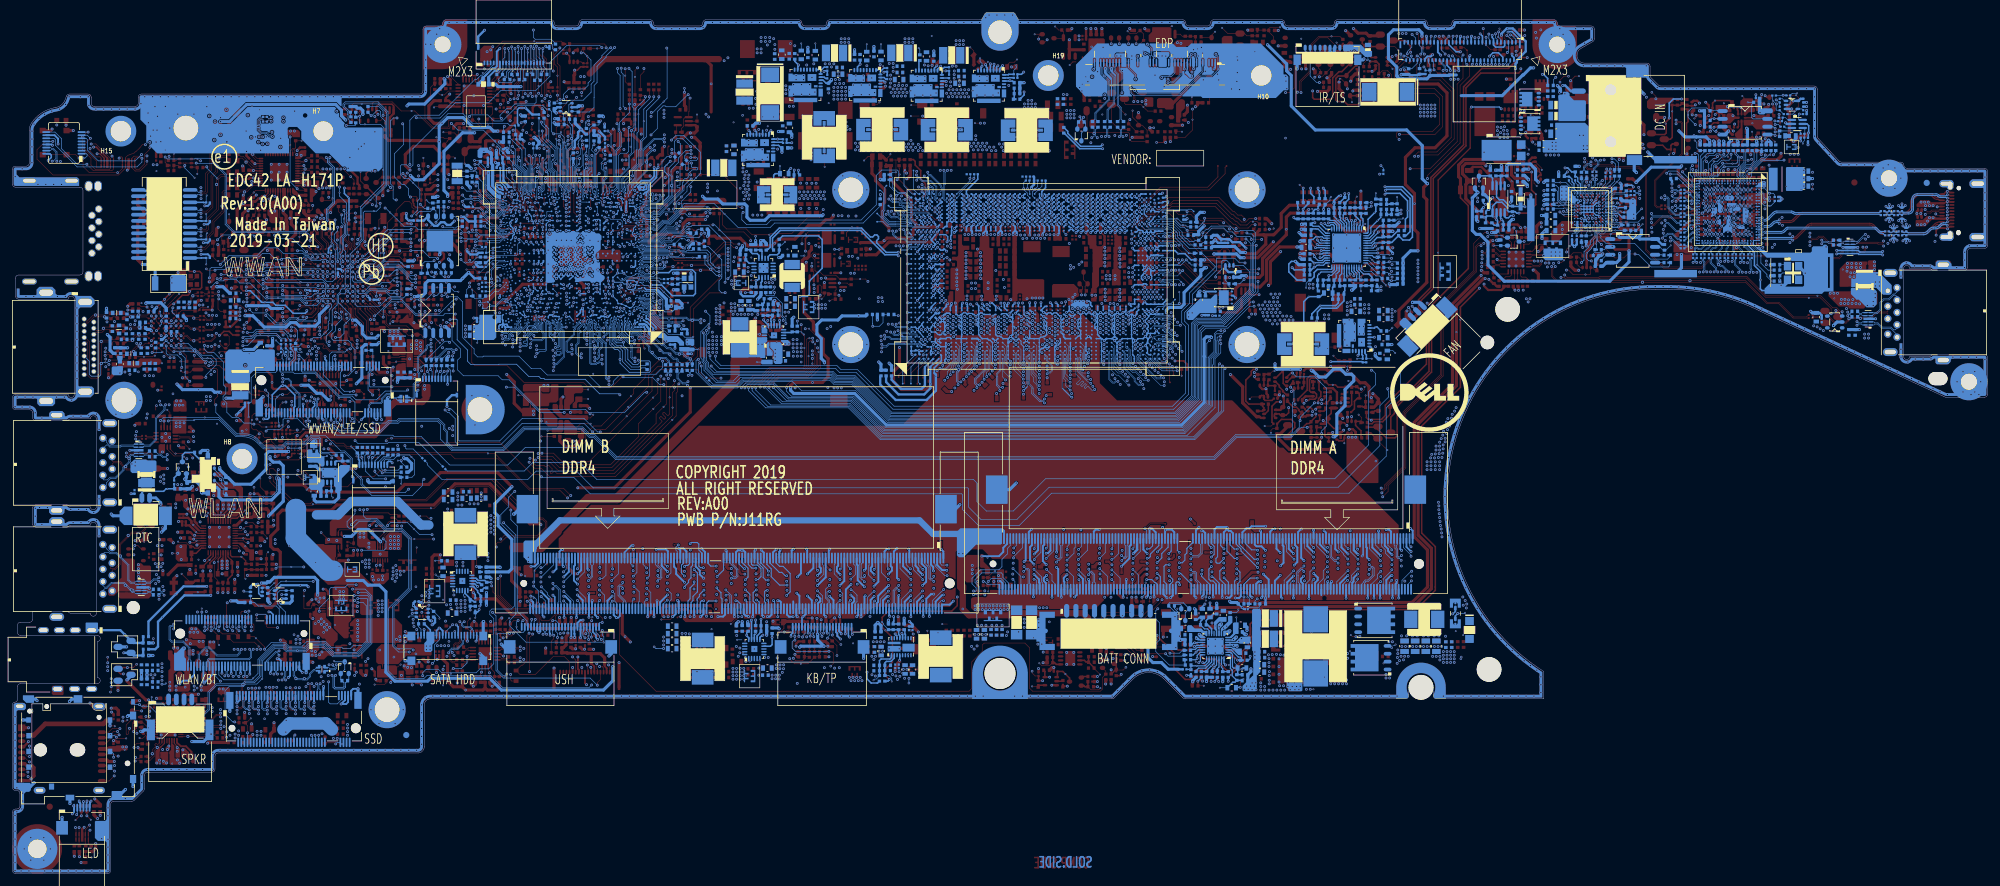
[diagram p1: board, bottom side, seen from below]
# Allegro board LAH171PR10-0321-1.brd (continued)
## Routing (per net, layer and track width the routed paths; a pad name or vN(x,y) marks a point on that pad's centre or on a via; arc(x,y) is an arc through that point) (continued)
CSSUM_2PH_CPU: length 5.6
  BOTTOM w0.203: PCZ28.1 105.21,96.28 v1(105.21,96.89) 104.73,97.37 PUZ1.30
  BOTTOM w0.254: PCZ28.1 PCZ29.1 105.8,94.74 PRZ59.1 105.8,93.84 PRZ55.1
CSSUM_4PH_CPU: length 13
  TOP w0.254: PRZ60.2 PRZ58.2 PRZ56.2 PRZ53.2 106.24,108.72 106.14,108.83 105.25,108.83 105.11,108.97 105.1,108.97 v2(104.49,109.58)
  BOTTOM w0.203: PCZ26.1 105.56,106.23 v1(105.04,105.7) 105.04,105.65 104.33,104.94 PUZ1.9
  BOTTOM w0.254: v2(104.49,109.58) 104.8,109.58 105.56,108.82 PRZ54.1 PCZ25.1 PCZ26.1
CV2_ON: length 70.5
  TOP w0.102: v2(261.74,58.88) 261.56,59.05 v1(251.46,59.05) 250.9,59.05 247.39,62.56 242.08,62.56 238.54,59.02 238.54,58.76 v2(238.53,58.76)
  BOTTOM w0.102: RE539.2 264.37,121.54 264.83,122 264.83,122.63 264.93,122.73 264.93,123.19 265.65,123.92 265.65,124.37 265.29,124.74 259.97,124.74 258.38,123.14 258.38,111.3 258.12,111.05 v2(257.96,110.88) ; JUSH1.24 235.93,40.04 235.93,40.86 237.5,42.42 237.5,56.18 238.53,57.22 238.53,57.94 238.54,57.94 238.54,58.3 238.53,58.3 v2(238.53,58.76)
CV2_ON_R: length 26.3
  TOP w0.109: v2(267.29,94.93) 267.27,94.93 UE1.H8
  BOTTOM w0.102: v2(260.28,107.9) 260.28,109.48 258.61,111.16 258.61,123.05 259.96,124.41 v1(262.63,124.41) 265.3,124.41 265.43,124.28 265.43,124.01 RE716.2 264.47,122.43 RE539.1
DAT_TP_SIO_I2C_CLK: length 7.1
  TOP w0.109: v2(270.57,99.72) 270.47,99.72 UE1.C12 ; RZ347.2 CZ80.1 189.41,35.05 RZ22.2 190.54,33.92 v1(191.7,33.92) 192.72,33.92 193.48,34.68 193.48,34.74 v2(193.49,34.74)
DAT_TP_SIO_R: length 4.1
  TOP w0.109: v2(189.61,38.3) 189.61,37.82 189.44,37.65 CZ88.1 189.44,36.76 RZ18.2 189.5,35.9 RZ22.1
  BOTTOM w0.109: JKBTP1.13 189.51,38.97 189.61,38.88 189.61,38.3 v2(189.61,38.3)
DCIN1_EN: length 13.2
  TOP w0.109: v2(269.72,92.54) 269.75,92.58 269.75,92.61 UE1.L12
  TOP w0.254: v2(109.02,126.5) 109.02,125.42 108.77,125.17 106.04,125.17 105.79,125.42 105.79,128.6 104.77,129.61 104.33,129.61 103.06,130.88 PQ8.3 102.57,131.23 PR28.1
DCIN2_EN: length 2.9
  TOP w0.109: v2(263.27,93.27) 263.27,93.32 UE1.K4
  TOP w0.254: PR821.1 104.61,72.85 PQ807.3 103.94,72.89 v2(103.49,72.44)
DCIN_CHG: length 3.2
  TOP w0.102: v2(133.15,38.24) v1(132.52,38.24)
  TOP w0.508: v2(127.34,38.68) 126.74,38.08 PC737.2 ; v2(133.15,38.24) 133.15,39.13 PR708.1
DDR4_DRAMRST#_PCH: length 7.5
  TOP w0.102: v2(240.93,108.65) 241.26,108.32 CH556.1
  BOTTOM w0.089: v2(240.93,108.65) 240.89,108.6 240.02,108.6 239.94,108.68 239.67,108.68 239.59,108.77 UH1.BB46
  BOTTOM w0.102: v2(117.98,44.41) 118.35,44.04 RD12.2 118.35,43.59 117.55,43.59 ; DD32.1 119.2,43.05 117.67,43.05 117.55,43.18 117.55,43.59 ; 117.55,43.59 RD11.2
DDR_A_ACT#: length 7.2
  BOTTOM w0.076: UC1.AU3 146.6,84.44 146.6,84.26 146.53,84.19 146.32,84.19 146.24,84.11 146.24,83.09 146.36,82.98 146.36,81.6 v2(146.17,81.41)
  BOTTOM w0.168: JDIMM1.114 121.12,46.86 120.76,47.23 120.76,48.73 v2(121.28,49.26)
DDR_A_ALERT#: length 5.8
  BOTTOM w0.076: UC1.AU5 145.91,85.21 145.91,83.1 145.39,82.58 v2(145.39,82.4)
  BOTTOM w0.168: JDIMM1.116 121.62,47.28 v2(121.24,47.66)
DDR_A_BA0: length 6.7
  BOTTOM w0.076: v2(153.18,82.02) 153.57,82.42 153.57,85.32 UC1.AH5
  BOTTOM w0.168: v2(132.17,48.11) 131.63,47.57 131.63,47.19 131.99,46.83 131.99,46.82 132.12,46.68 JDIMM1.150
DDR_A_BA1: length 5.8
  BOTTOM w0.076: v2(153.15,80.1) 154.07,81.02 UC1.AH1
  BOTTOM w0.168: JDIMM1.145 130.87,52.25 v2(130.57,51.95)
DDR_A_BG0: length 9.5
  BOTTOM w0.076: UC1.AU1 146.52,82.65 146.52,82.65 146.52,81.23 146.2,80.91 145.33,80.91 v2(145.26,80.97)
  BOTTOM w0.168: JDIMM1.115 121.37,53.25 120.59,52.47 120.59,52.15 v2(117.91,49.48)
DDR_A_BG1: length 10.2
  BOTTOM w0.076: v2(144.88,79.87) 145.48,79.87 146.77,81.15 146.77,83.07 146.8,83.1 146.8,83.33 146.77,83.37 146.52,83.61 UC1.AU2
  BOTTOM w0.168: JDIMM1.113 120.87,53.22 118.46,50.81 v2(117.91,50.81)
DDR_A_CKE0: length 14.1
  BOTTOM w0.076: UC1.AT1 147.26,80.72 146.53,79.99 146.53,79.89 147.15,79.27 147.15,79.16 146.98,78.99 146.87,78.99 146.25,79.61 146.14,79.61 146.04,79.5 146.04,79.39 146.47,78.96 146.47,78.85 146.36,78.75 146.25,78.75 145.82,79.18 145.71,79.18 145.6,79.07 145.6,78.96 145.91,78.66 145.91,78.55 145.8,78.44 145.69,78.44 145.39,78.74 145.28,78.74 144.68,78.14 144.31,78.14 144.23,78.22 v2(144.23,78.25)
  BOTTOM w0.168: v2(117.91,52.27) 117.97,52.33 118.87,52.33 119.87,53.34 JDIMM1.109
DDR_A_CKE1: length 9
  BOTTOM w0.076: v2(144.86,79.23) 145.46,79.62 146.97,81.12 146.97,83.03 146.97,83.3 UC1.AT2
  BOTTOM w0.168: v2(117.98,47.76) 119.12,47.76 120.12,46.76 JDIMM1.110
DDR_A_CLK0: length 13.9
  BOTTOM w0.076: 154.17,78.36 154.17,78.38 154.2,78.41 154.2,78.62 154.75,79.17 154.75,82.51 155.16,82.92 155.16,83.46 155.03,83.6 154.91,83.6 154.8,83.49 UC1.AG1
  BOTTOM w0.102: v2(128.7,50.87) 128.41,51.17 127.46,51.17 126.87,51.76 JDIMM1.137 ; 154.17,78.36 154.17,77.67 153.01,76.51 152.55,76.51 v2(152.34,76.71)
DDR_A_CLK1: length 8.3
  BOTTOM w0.076: UC1.AK2 152.16,83.74 152.02,83.74 151.84,83.57 151.84,82.95 151.04,82.15 151.04,81.26 151.4,80.91 151.8,80.91 v2(151.91,80.79)
  BOTTOM w0.102: JDIMM1.138 127.12,46.88 127.79,47.54 127.79,48.62 127.98,48.81 128.41,48.81 v2(128.7,49.11)
DDR_A_CLK#0: length 14
  BOTTOM w0.076: 154.4,78.04 154.4,78.38 154.37,78.41 154.37,78.55 154.92,79.1 154.92,82.44 155.33,82.85 155.33,83.53 155.1,83.76 154.91,83.76 UC1.AG2
  BOTTOM w0.102: v2(128.69,51.71) 128.38,51.4 127.56,51.4 127.1,51.85 127.1,53.14 127.37,53.41 JDIMM1.139 ; v2(152.34,76.08) 152.55,76.28 153.1,76.28 154.4,77.58 154.4,78.04
DDR_A_CLK#1: length 7.7
  BOTTOM w0.076: v2(151.91,81.43) 151.91,81.29 151.69,81.07 151.47,81.07 151.21,81.33 151.21,82.08 152.01,82.88 152.01,83.5 152.08,83.57 152.21,83.57 152.29,83.5 UC1.AK1
  BOTTOM w0.102: v2(128.68,48.26) 128.35,48.59 128.07,48.59 128.01,48.52 128.01,47.44 127.62,47.06 JDIMM1.140
DDR_A_CS#0: length 3.1
  BOTTOM w0.076: v2(156.95,85.47) 157.3,85.82 UC1.AD5
  BOTTOM w0.168: JDIMM1.149 131.87,52.11 v2(132.27,51.72)
DDR_A_CS#1: length 10.3
  BOTTOM w0.076: UC1.AE2 156.3,83.59 156.3,82.43 155.98,82.11 155.53,82.11 155.29,81.86 155.29,79.18 v2(155.76,78.71)
  BOTTOM w0.168: v2(135.76,50.97) 135.5,50.97 135.25,51.23 135.25,51.64 133.87,53.01 JDIMM1.157
DDR_A_D0: length 7.3
  BOTTOM w0.076: v2(131.13,85.29) 131.13,85.84 131.83,86.54 132.48,86.54 132.56,86.45 132.91,86.45 132.96,86.51 133.79,86.51 UC1.BR6
  BOTTOM w0.102: JDIMM1.8 94.62,46.77 94.6,46.8 94.6,47.4 93.13,48.87 v2(93.03,48.87)
DDR_A_D1: length 3.9
  BOTTOM w0.076: UC1.BT6 v2(132.7,86.81)
  BOTTOM w0.102: JDIMM1.7 94.37,52.73 93.13,51.49 v2(93.13,51.3)
DDR_A_D2: length 5.4
  BOTTOM w0.076: UC1.BP3 134.3,84.92 133.74,84.92 133.72,84.9 133.11,84.9 132.93,84.71 132.46,84.71 132.16,84.42 132.16,83.84 v2(132.18,83.82)
  BOTTOM w0.102: v2(96.24,52.32) 96.24,52.44 96.87,53.08 JDIMM1.17
DDR_A_D3: length 6.8
  BOTTOM w0.076: UC1.BR3 133.83,84.6 133.36,84.13 133.03,84.13 132.22,83.31 v2(131.69,83.31)
  BOTTOM w0.102: v2(96.2,50.72) 97.24,51.76 97.24,52.3 97.87,52.93 JDIMM1.21
DDR_A_D4: length 8.6
  BOTTOM w0.076: UC1.BN5 134.86,86.63 134.69,86.8 133.15,87.17 132.56,87.17 131.68,86.7
  BOTTOM w0.102: JDIMM1.4 93.62,46.76 v2(93.07,47.32) ; v2(130.12,84.41) 130.3,84.59 130.3,85.32 131.68,86.7
DDR_A_D5: length 5.2
  BOTTOM w0.076: v2(131.59,85.71) 131.59,86.03 131.93,86.37 132.41,86.37 132.49,86.29 133.03,86.29 133.08,86.34 133.5,86.34 133.73,86.12 134.17,86.12 134.56,86.51 UC1.BP6
  BOTTOM w0.102: JDIMM1.3 93.37,53.06 v2(93.14,52.82)
DDR_A_D6: length 7.2
  BOTTOM w0.076: v2(131.04,81.85) 131.28,81.85 131.54,81.59 133.36,81.59 134.85,83.08 134.85,83.77 UC1.BP2
  BOTTOM w0.102: v2(96.24,47.42) 96.62,47.04 JDIMM1.16
DDR_A_D7: length 4.5
  BOTTOM w0.102: JDIMM1.20 97.62,47.61 96.24,48.99 v2(96.24,49.12) ; UC1.BN3 135.15,84.73 v2(134.75,85.13)
DDR_A_D8: length 4.9
  BOTTOM w0.076: UC1.BL4 136.53,85.17 v2(136.86,84.84)
  BOTTOM w0.102: v2(98.08,50.57) 98.08,50.73 99.87,52.52 JDIMM1.29
DDR_A_D9: length 2.8
  BOTTOM w0.076: v2(136.86,85.49) 136.53,85.82 UC1.BL5
  BOTTOM w0.102: JDIMM1.25 98.87,53.1 v2(98,52.23)
DDR_A_D10: length 7.4
  BOTTOM w0.076: v2(134.5,81.34) 134.42,81.41 134.42,81.97 135.35,82.89 135.37,82.89 135.59,83.11 135.59,83.34 136.11,83.87 UC1.BL2
  BOTTOM w0.102: v2(101.72,50.82) 102.87,51.98 JDIMM1.41
DDR_A_D11: length 5.9
  BOTTOM w0.076: v2(134.92,81.75) 134.92,82.23 135.33,82.63 135.37,82.63 135.95,83.22 UC1.BM1
  BOTTOM w0.102: JDIMM1.42 103.12,46.95 102.98,47.1 102.98,47.17 102.75,47.39 102.75,48.21 v2(101.72,49.25)
DDR_A_D12: length 2.1
  BOTTOM w0.076: v2(137.68,84.84) 137.65,84.84 UC1.BK4
  BOTTOM w0.102: v2(98.05,47.2) 98.13,47.2 98.62,46.71 JDIMM1.24
DDR_A_D13: length 4.1
  BOTTOM w0.102: JDIMM1.28 99.62,46.68 98.55,47.76 98.55,48.34 v2(98.02,48.87) ; v2(137.66,85.44) 137.28,85.82 UC1.BK5
DDR_A_D14: length 3
  BOTTOM w0.076: UC1.BK1 136.21,82.61 v2(135.86,82.61)
  BOTTOM w0.102: v2(101.74,47.62) 101.74,47.42 102.12,47.04 JDIMM1.38
DDR_A_D15: length 9.1
  BOTTOM w0.076: UC1.BK2 137.54,83.58 137.54,82.86 133.6,78.92 133.04,78.92 v2(133.01,78.89)
  BOTTOM w0.102: JDIMM1.37 101.87,52.55 v2(101.75,52.43)
DDR_A_D16: length 5.6
  BOTTOM w0.076: UC1.BT11 132.49,89.67 132.33,89.51 131.39,89.51 131.33,89.57 v2(131.33,89.61)
  BOTTOM w0.102: JDIMM1.170 137.12,48.23 v2(138.06,49.17)
DDR_A_D17: length 7.6
  BOTTOM w0.076: v2(130.39,88.63) 131.39,88.63 132.04,89.28 132.32,89.28 132.4,89.36 133.33,89.36 133.64,89.67 UC1.BR11
  BOTTOM w0.102: JDIMM1.169 136.87,52.06 v2(138.01,50.93)
DDR_A_D18: length 2.9
  BOTTOM w0.076: v2(132.21,88.79) 132.21,88.9 132.31,89.01 133.1,89.01 UC1.BT9
  BOTTOM w0.102: v2(141.47,47.52) 141.12,47.18 JDIMM1.186
DDR_A_D19: length 4.7
  BOTTOM w0.076: UC1.BR8 133.77,88.2 133.12,88.2 132.65,87.72 132.23,87.72 131.87,87.36 131.37,87.36 v2(131.31,87.41)
  BOTTOM w0.102: v2(141.46,52.5) 141.37,52.58 JDIMM1.187
DDR_A_D20: length 4.9
  BOTTOM w0.076: v2(131.59,90.13) 132.01,89.71 132.3,89.71 132.55,89.96 134.23,89.96 UC1.BP11
  BOTTOM w0.102: JDIMM1.174 v2(138.12,47.55)
DDR_A_D21: length 5
  BOTTOM w0.076: UC1.BN11 134.94,89.67 134.44,90.16 132.25,90.16 v2(132.19,90.1)
  BOTTOM w0.102: v2(138.06,52.5) 137.87,52.69 JDIMM1.173
DDR_A_D22: length 7
  BOTTOM w0.076: v2(132.25,88.21) 132.25,88.08 132.38,87.94 132.63,87.94 133.1,88.41 134.52,88.41 134.61,88.32 134.61,88.18 UC1.BP8
  BOTTOM w0.102: v2(141.47,50.77) 141.32,50.77 140.37,51.72 JDIMM1.183
DDR_A_D23: length 6.3
  BOTTOM w0.076: v2(132.77,88.59) 132.78,88.58 134.69,88.58 UC1.BN8
  BOTTOM w0.102: v2(141.46,49.1) 140.12,47.77 JDIMM1.182
DDR_A_D24: length 2.3
  BOTTOM w0.076: UC1.BL12 136.48,90.39 v2(136.15,90.06)
  BOTTOM w0.102: JDIMM1.194 143.12,47.4 v2(143.35,47.62)
DDR_A_D25: length 4.3
  BOTTOM w0.076: UC1.BL11 136.56,89.67 v2(136.94,90.05)
  BOTTOM w0.102: v2(143.44,50.95) 142.53,51.86 142.53,53.31 142.37,53.47 JDIMM1.191
DDR_A_D26: length 2.1
  BOTTOM w0.076: v2(136.15,88.49) 136.48,88.16 UC1.BL8
  BOTTOM w0.102: v2(143.44,52.58) 143.37,52.64 JDIMM1.195
DDR_A_D27: length 2.2
  BOTTOM w0.076: UC1.BJ8 137.49,87.78 v2(137.82,88.1)
  BOTTOM w0.102: v2(146.78,47.52) 146.62,47.37 JDIMM1.208
DDR_A_D28: length 4.6
  BOTTOM w0.076: UC1.BJ11 137.49,89.73 v2(137.82,89.4)
  BOTTOM w0.102: JDIMM1.203 145.37,52.27 v2(146.87,50.77)
DDR_A_D29: length 2.5
  BOTTOM w0.076: UC1.BJ10 137.49,89.08 v2(137.82,88.75)
  BOTTOM w0.102: JDIMM1.207 146.37,52.87 v2(146.84,52.4)
DDR_A_D30: length 4.5
  BOTTOM w0.076: UC1.BL7 136.47,87.39 v2(136.19,87.67)
  BOTTOM w0.102: JDIMM1.190 142.12,48.01 v2(143.41,49.3)
DDR_A_D31: length 4.3
  BOTTOM w0.076: UC1.BJ7 137.49,87.13 v2(137.82,87.45)
  BOTTOM w0.102: JDIMM1.204 145.62,47.21 145.76,47.34 145.76,47.99 146.82,49.04 v2(146.82,49.15)
DDR_A_D32: length 6
  BOTTOM w0.076: v2(137.64,81.97) 138.23,81.97 138.41,82.14 138.41,82.65 138.32,82.74 138.32,83.55 138.49,83.71 138.49,84.67 UC1.BG4
  BOTTOM w0.102: JDIMM1.46 104.12,46.76 103.49,47.4 v2(103.38,47.4)
DDR_A_D33: length 7.9
  BOTTOM w0.076: UC1.BG5 139.18,85.82 139.28,85.73 139.28,85.07 139.26,85.05 139.1,84.89 139.09,84.88 138.94,84.88 138.68,84.62 138.68,83.61 138.51,83.45 138.51,82.85 138.57,82.79 138.57,82.07 138.3,81.8 138.14,81.8 137.9,81.56 v2(137.22,81.56)
  BOTTOM w0.102: v2(103.3,52.53) 103.87,53.1 JDIMM1.45
DDR_A_D34: length 2.4
  BOTTOM w0.076: UC1.BF4 139.88,85.17 v2(140.15,84.89)
  BOTTOM w0.102: JDIMM1.59 107.37,53.22 106.88,52.73 v2(106.63,52.73)
DDR_A_D35: length 4.3
  BOTTOM w0.076: v2(140.16,85.49) 139.84,85.82 UC1.BF5
  BOTTOM w0.102: JDIMM1.63 108.37,52.96 v2(106.62,51.21)
DDR_A_D36: length 9.2
  BOTTOM w0.076: v2(136.34,80.66) 136.5,80.49 136.85,80.49 137.61,81.25 138.08,81.25 138.87,82.04 138.87,82.81 138.68,82.99 138.68,83.33 138.98,83.63 UC1.BG2
  BOTTOM w0.102: JDIMM1.49 104.87,52.55 104.05,51.73 104.05,51.55 v2(103.35,50.85)
DDR_A_D37: length 9.5
  BOTTOM w0.076: UC1.BG1 138.98,83.09 139.07,83 139.07,81.95 138.08,80.97 137.6,80.97 136.35,79.72 135.6,79.72 v2(135.59,79.74)
  BOTTOM w0.102: JDIMM1.50 105.12,47.17 v2(103.33,48.97)
DDR_A_D38: length 2.8
  BOTTOM w0.076: v2(140.16,82.89) 139.84,83.22 UC1.BF1
  BOTTOM w0.102: JDIMM1.58 107.12,47.43 106.6,47.95 v2(106.6,47.95)
DDR_A_D39: length 4.8
  BOTTOM w0.076: UC1.BF2 139.79,83.87 v2(140.14,83.52)
  BOTTOM w0.102: v2(106.64,49.6) 107.31,48.94 107.31,47.67 108.12,46.86 JDIMM1.62
DDR_A_D40: length 9
  BOTTOM w0.076: v2(138.81,80.27) 139.37,80.27 140.01,80.91 140.47,80.91 141.28,81.72 141.28,82.91 141.22,82.97 141.22,83.35 141.49,83.63 UC1.BD2
  BOTTOM w0.102: JDIMM1.71 110.37,52.67 v2(108.86,51.16)
DDR_A_D41: length 7.3
  BOTTOM w0.076: UC1.BD1 141.49,81.33 140.73,80.57 140.4,80.57 138.79,78.96 v2(138.7,78.96)
  BOTTOM w0.102: JDIMM1.67 109.37,53.22 v2(108.86,52.7)
DDR_A_D42: length 2.3
  BOTTOM w0.076: v2(142.73,84.84) 142.4,85.17 UC1.BC4
  BOTTOM w0.102: v2(112.15,52.62) 112.37,52.85 JDIMM1.79
DDR_A_D43: length 4.5
  BOTTOM w0.076: v2(142.74,85.49) 142.42,85.82 UC1.BC5
  BOTTOM w0.102: v2(112.04,50.83) 113.28,52.07 113.28,53.15 113.37,53.25 JDIMM1.83
DDR_A_D44: length 6.5
  BOTTOM w0.076: v2(140.16,81.62) 140.89,82.34 140.89,83.68 140.98,83.77 140.98,85.3 UC1.BD5
  BOTTOM w0.102: v2(108.84,47.57) 109.12,47.29 JDIMM1.66
DDR_A_D45: length 9.1
  BOTTOM w0.076: v2(139.71,81.17) 140.27,81.17 141.11,82.01 141.11,82.75 141.05,82.81 141.05,83.52 141.2,83.67 141.2,84.87 UC1.BD4
  BOTTOM w0.102: JDIMM1.70 110.12,46.85 109.47,47.51 109.47,48.8 v2(108.86,49.4)
DDR_A_D46: length 4.3
  BOTTOM w0.076: v2(142.77,82.88) 142.43,83.22 UC1.BC1
  BOTTOM w0.102: v2(112.09,48.95) 113.62,47.41 JDIMM1.84
DDR_A_D47: length 2.3
  BOTTOM w0.076: v2(142.73,83.54) 142.4,83.87 UC1.BC2
  BOTTOM w0.102: JDIMM1.80 112.62,46.96 112.29,47.29 v2(112.13,47.29)
DDR_A_D48: length 4.2
  BOTTOM w0.076: UC1.BG11 139.34,89.73 v2(139.64,90.04)
  BOTTOM w0.102: JDIMM1.212 147.62,47.98 v2(148.72,49.07)
DDR_A_D49: length 4.6
  BOTTOM w0.076: UC1.BG10 139.32,89.08 v2(139.64,89.4)
  BOTTOM w0.102: JDIMM1.211 147.37,52.75 147.57,52.55 147.57,51.8 v2(148.69,50.67)
DDR_A_D50: length 2.5
  BOTTOM w0.076: UC1.BG8 139.3,87.78 v2(139.63,88.11)
  BOTTOM w0.102: JDIMM1.215 148.37,53.18 148.68,52.87 v2(148.68,52.37)
DDR_A_D51: length 2.3
  BOTTOM w0.076: v2(140.57,88.12) 140.56,88.11 140.56,88.08 140.26,87.78 UC1.BF8
  BOTTOM w0.102: JDIMM1.229 151.87,52.79 v2(152.06,52.6)
DDR_A_D52: length 2.2
  BOTTOM w0.076: UC1.BF11 140.52,90.01 v2(140.56,90.04)
  BOTTOM w0.102: v2(151.93,47.52) 151.62,47.21 JDIMM1.228
DDR_A_D53: length 4.4
  BOTTOM w0.076: UC1.BF10 140.23,89.08 v2(140.56,89.4)
  BOTTOM w0.102: v2(152,49.17) 151.13,48.3 151.13,47.32 150.62,46.82 JDIMM1.224
DDR_A_D54: length 2.2
  BOTTOM w0.076: UC1.BG7 139.31,87.13 v2(139.63,87.45)
  BOTTOM w0.102: JDIMM1.216 148.67,46 v2(148.67,47.55)
DDR_A_D55: length 4.3
  BOTTOM w0.076: UC1.BF7 140.23,87.13 140.56,87.46 v2(140.6,87.46)
  BOTTOM w0.102: v2(152.06,50.95) 150.87,52.14 JDIMM1.225
DDR_A_D56: length 4.5
  BOTTOM w0.076: UC1.BB11 142.98,89.73 v2(143.3,90.05)
  BOTTOM w0.102: v2(157.42,49.3) 156.15,48.03 156.15,45.98 JDIMM1.246
DDR_A_D57: length 2.5
  BOTTOM w0.076: UC1.BC11 142.08,89.73 v2(142.39,90.04)
  BOTTOM w0.102: v2(154.04,47.57) 153.86,47.57 153.62,47.34 JDIMM1.236
DDR_A_D58: length 2.3
  BOTTOM w0.076: v2(143.34,88.1) 143.02,87.78 UC1.BB8
  BOTTOM w0.102: v2(157.31,52.63) 156.87,53.06 JDIMM1.249
DDR_A_D59: length 2.3
  BOTTOM w0.076: v2(142.41,88.11) 142.38,88.11 142.05,87.78 UC1.BC8
  BOTTOM w0.102: JDIMM1.237 153.87,52.64 v2(154,52.51)
DDR_A_D60: length 4.5
  BOTTOM w0.076: UC1.BC10 142.06,89.08 v2(142.39,89.4)
  BOTTOM w0.102: JDIMM1.233 152.87,53.29 152.92,53.24 152.92,51.91 153.98,50.85 v2(153.98,50.75)
DDR_A_D61: length 4.3
  BOTTOM w0.076: UC1.BB10 142.98,89.08 v2(143.3,89.4)
  BOTTOM w0.102: v2(157.35,51.02) 157.35,51.19 155.87,52.66 JDIMM1.245
DDR_A_D62: length 4.4
  BOTTOM w0.076: v2(142.38,87.45) 142.06,87.13 UC1.BC7
  BOTTOM w0.102: v2(154.03,49.18) 152.79,47.94 152.79,47.14 152.62,46.98 JDIMM1.232
DDR_A_D63: length 2.4
  BOTTOM w0.076: v2(143.34,87.47) 143.32,87.47 142.97,87.13 UC1.BB7
  BOTTOM w0.102: JDIMM1.250 157.12,47.25 v2(157.44,47.57)
DDR_A_DQS0: length 8.4
  BOTTOM w0.076: v2(131.63,84.34) 131.63,84.72 131.54,84.82 131.54,85.15 131.82,85.43 132.2,85.43 132.49,85.72 133.45,85.72 133.63,85.9 134.14,85.9 134.45,85.59 UC1.BP5
  BOTTOM w0.102: v2(94.73,50.65) 94.99,50.94 95.13,50.95 95.26,50.95 95.53,51.22 95.53,52.37 95.74,52.57 95.74,53 95.87,53.14 JDIMM1.13
DDR_A_DQS1: length 12.4
  BOTTOM w0.076: UC1.BK3 136.92,84.18 136.92,83.8 136.97,83.75 137.31,83.41 137.31,83.02 134.25,79.95 133.58,79.95 133.4,80.13 v2(133.11,80.13)
  BOTTOM w0.102: v2(99.88,49.15) 99.59,49.44 99.45,49.44 99.31,49.3 99.31,48.27 100.12,47.46 100.54,47.46 100.77,47.22 100.77,47.13 101.12,46.77 JDIMM1.34
DDR_A_DQS2: length 4.3
  BOTTOM w0.076: v2(134.85,89.27) 134.52,88.95 UC1.BP9
  BOTTOM w0.102: v2(139.89,51.42) 139.84,51.42 139.56,51.13 139.41,51.13 139.41,51.16 139.24,51.33 139.24,53 139.37,53.14 JDIMM1.179
DDR_A_DQS3: length 4.3
  BOTTOM w0.076: v2(136.84,88.58) 136.96,88.69 137.19,88.69 137.36,88.52 UC1.BJ9
  BOTTOM w0.102: JDIMM1.200 144.62,46.98 144.49,47.12 144.49,48.3 144.84,48.65 145.03,48.65 145.03,48.64 145.12,48.55 145.12,48.37 145.18,48.31 v2(145.23,48.31)
DDR_A_DQS4: length 12.3
  BOTTOM w0.076: v2(136.48,79.04) 136.75,79.04 136.89,78.9 137.19,78.9 137.86,79.57 137.86,79.97 139.51,81.62 139.51,82.84 139.43,82.92 139.43,84.05 139.58,84.2 139.58,84.37 UC1.BF3
  BOTTOM w0.102: v2(104.92,50.19) 105.21,50.48 105.35,50.47 105.52,50.47 106.2,51.16 106.2,53.1 106.37,53.27 JDIMM1.55
DDR_A_DQS5: length 11
  BOTTOM w0.076: v2(140.48,79.56) 140.71,79.56 140.98,79.28 141.37,79.28 141.95,79.86 141.95,84.02 142.04,84.11 142.04,84.32 UC1.BC3
  BOTTOM w0.102: v2(110.44,49.72) 110.44,49.65 110.68,49.41 110.93,49.41 111.61,48.73 111.61,48.18 111.62,48.17 JDIMM1.76
DDR_A_DQS6: length 4.9
  BOTTOM w0.076: v2(140.53,88.75) 140.48,88.81 140.25,88.81 140.1,88.66 UC1.BF9
  BOTTOM w0.102: JDIMM1.221 149.87,53.14 149.74,53 149.74,51.18 150.05,50.87 150.24,50.87 150.44,51.08 v2(150.44,51.25)
DDR_A_DQS7: length 4.7
  BOTTOM w0.076: v2(143.31,88.79) 143.31,88.76 143.3,88.75 142.99,88.75 142.85,88.61 UC1.BB9
  BOTTOM w0.102: JDIMM1.242 155.12,46.68 154.99,46.82 154.99,49.03 155.06,49.11 155.41,49.11 v2(155.71,48.86)
DDR_A_DQS#0: length 8.2
  BOTTOM w0.076: UC1.BR5 133.87,85.2 133.94,85.12 134.13,85.12 134.2,85.2 134.2,85.61 134.08,85.73 133.7,85.73 133.52,85.55 132.56,85.55 132.26,85.26 131.88,85.26 131.7,85.08 131.7,84.89 131.82,84.77 131.93,84.77 v2(132.01,84.85)
  BOTTOM w0.102: v2(94.67,51.42) 94.97,51.17 95.11,51.18 95.12,51.18 95.17,51.18 95.31,51.32 95.31,52.46 95.51,52.66 95.51,53 95.37,53.14 JDIMM1.11
DDR_A_DQS#1: length 12.3
  BOTTOM w0.076: UC1.BL3 136.51,84.52 136.76,84.27 136.76,83.73 136.81,83.68 137.14,83.35 137.14,83.09 134.18,80.12 133.64,80.12 133.55,80.21 v2(133.55,80.56)
  BOTTOM w0.102: v2(99.89,49.96) 99.59,49.67 99.45,49.67 99.35,49.67 99.08,49.4 99.08,48.18 100.03,47.23 100.44,47.23 100.54,47.13 100.54,47.03 100.62,46.95 JDIMM1.32
DDR_A_DQS#2: length 4.6
  BOTTOM w0.076: v2(135.47,89.25) 135.47,89.25 135.47,89.18 135.17,88.89 UC1.BN9
  BOTTOM w0.102: v2(139.86,50.61) 139.56,50.91 139.32,50.91 139.19,51.04 139.19,51.06 139.01,51.24 139.01,53 138.87,53.14 JDIMM1.177
DDR_A_DQS#3: length 4.6
  BOTTOM w0.076: v2(136.99,89.37) 136.5,88.88 UC1.BL9
  BOTTOM w0.102: v2(145.19,49.21) 145.19,49.04 145.03,48.88 144.75,48.88 144.26,48.39 144.26,47.12 144.12,46.98 JDIMM1.198
DDR_A_DQS#4: length 11.9
  BOTTOM w0.076: UC1.BG3 139.03,84.56 139.28,84.56 139.41,84.44 139.41,84.26 139.27,84.12 139.27,82.85 139.35,82.77 139.35,81.69 137.7,80.03 137.7,79.64 137.12,79.06 136.96,79.06 136.84,79.19 v2(136.84,79.54)
  BOTTOM w0.102: v2(104.92,50.99) 105.21,50.7 105.35,50.7 105.42,50.7 105.98,51.25 105.98,53.1 105.87,53.2 JDIMM1.53
DDR_A_DQS#5: length 10.7
  BOTTOM w0.076: v2(140.96,80.01) 140.86,79.91 140.86,79.64 141.05,79.45 141.3,79.45 141.78,79.93 141.78,84.09 141.87,84.18 141.87,84.39 141.74,84.52 UC1.BD3
  BOTTOM w0.102: v2(110.45,48.84) 110.58,48.97 110.58,49.09 110.68,49.19 110.84,49.19 111.39,48.64 111.39,48.18 111.38,48.17 111.38,47.11 111.12,46.86 JDIMM1.74
DDR_A_DQS#6: length 5.1
  BOTTOM w0.076: UC1.BG9 139.32,88.43 139.67,88.78 v2(139.67,88.82)
  BOTTOM w0.102: v2(150.4,50.34) 150.4,50.48 150.24,50.65 149.95,50.65 149.51,51.09 149.51,53 149.37,53.14 JDIMM1.219
DDR_A_DQS#7: length 5
  BOTTOM w0.076: UC1.BC9 142.06,88.43 142.4,88.76 v2(142.4,88.79)
  BOTTOM w0.102: v2(155.64,49.63) 155.39,49.33 154.97,49.33 154.76,49.13 154.76,46.95 154.62,46.82 JDIMM1.240
DDR_A_MA0: length 9.8
  BOTTOM w0.076: v2(153.18,78.86) 153.7,79.38 153.7,80.25 154.35,80.9 154.35,84.24 UC1.AH3
  BOTTOM w0.168: v2(130.57,48.52) 130.33,48.52 128.62,46.81 JDIMM1.144
DDR_A_MA1: length 6.1
  BOTTOM w0.076: UC1.AP4 148.75,84.87 148.75,83.98 148.59,83.83 148.59,82.97 148.72,82.84 148.72,81.74 v2(148.19,81.21)
  BOTTOM w0.168: JDIMM1.133 125.87,53.16 v2(125.4,52.69)
DDR_A_MA2: length 3.6
  BOTTOM w0.076: v2(150.27,84.84) 149.95,85.17 UC1.AN4
  BOTTOM w0.168: JDIMM1.132 125.62,46.71 126.96,48.05 v2(126.96,48.41)
DDR_A_MA3: length 7.8
  BOTTOM w0.076: UC1.AP5 148.49,85.27 148.49,84.04 148.43,83.97 148.43,82.88 148.54,82.77 148.54,82.22 v2(148.16,81.84)
  BOTTOM w0.168: JDIMM1.131 125.37,53.35 124.93,52.91 124.93,51.61 v2(125.38,51.16)
DDR_A_MA4: length 8.9
  BOTTOM w0.076: UC1.AP2 148.76,83.59 148.76,83.1 148.92,82.94 148.92,80.76 v2(148.19,80.03)
  BOTTOM w0.168: JDIMM1.128 124.62,46.82 125.1,47.3 125.51,47.3 125.79,47.58 125.79,49.23 v2(125.38,49.64)
DDR_A_MA5: length 6.8
  BOTTOM w0.076: v2(148.21,79.42) 149.13,80.34 149.13,83.13 UC1.AP1
  BOTTOM w0.168: v2(125.3,47.99) 125.18,47.99 124.12,46.93 JDIMM1.126
DDR_A_MA6: length 12.6
  BOTTOM w0.076: 148.43,78.39 148.94,78.9 148.94,79.72 149.32,80.1 149.32,84.24 UC1.AP3
  BOTTOM w0.168: JDIMM1.127 124.37,51.21 124.65,50.94 124.65,50.34 124.48,50.18 124.04,50.18 123.4,50.82 v2(123.4,50.98) ; 148.43,78.39 v2(148.19,78.15)
DDR_A_MA7: length 4.7
  BOTTOM w0.076: v2(150.22,82.92) 149.93,83.22 UC1.AN1
  BOTTOM w0.168: v2(123.4,49.41) 123.55,49.41 124.02,48.94 124.02,47.59 123.12,46.7 JDIMM1.122
DDR_A_MA8: length 10.2
  BOTTOM w0.076: UC1.AN3 149.5,84.24 149.5,78.49 149.4,78.39 149.39,78.39
  BOTTOM w0.168: JDIMM1.125 123.87,53.02 v2(123.36,52.5) ; 149.39,78.39 148,77 v2(147.92,77)
DDR_A_MA9: length 4.7
  BOTTOM w0.076: UC1.AT4 147.38,85.17 v2(147.7,84.84)
  BOTTOM w0.168: JDIMM1.121 122.87,52.14 121.67,50.94 v2(121.23,50.94)
DDR_A_MA10: length 5.6
  BOTTOM w0.076: UC1.AH2 153.78,83.57 153.78,81.3 v2(153.18,80.7)
  BOTTOM w0.168: v2(130.51,46.68) 130.51,46.98 130.68,47.14 130.96,47.14 131.12,46.98 JDIMM1.146
DDR_A_MA11: length 2.7
  BOTTOM w0.076: v2(150.2,83.56) 149.89,83.87 UC1.AN2
  BOTTOM w0.168: v2(123.33,47.81) 122.62,47.1 JDIMM1.120
DDR_A_MA12: length 5.3
  BOTTOM w0.076: v2(145.95,82.56) 146.08,82.69 146.08,84.72 UC1.AU4
  BOTTOM w0.168: v2(121.21,52.46) 121.68,52.46 122.37,53.15 JDIMM1.119
DDR_A_MA13: length 6.4
  BOTTOM w0.076: v2(155.71,81.71) 155.97,81.71 156.86,82.6 156.86,84.24 UC1.AE3
  BOTTOM w0.168: JDIMM1.158 134.12,46.77 134.38,47.03 134.49,47.03 134.99,47.52 v2(135.83,47.52)
DDR_A_MA14: length 5.1
  BOTTOM w0.076: UC1.AG4 154.97,85.34 v2(155.25,85.34)
  BOTTOM w0.168: JDIMM1.151 132.37,52.76 133.39,51.74 133.39,51.02 v2(134.15,50.27)
DDR_A_MA15: length 6.7
  BOTTOM w0.076: v2(155.76,79.93) 157.34,81.51 157.34,83.19 UC1.AD1
  BOTTOM w0.168: JDIMM1.156 133.62,48 v2(134.15,48.52)
DDR_A_MA16: length 6.2
  BOTTOM w0.076: v2(155.25,84.75) 155.15,84.85 154.38,84.85 UC1.AH4
  BOTTOM w0.168: v2(132.19,49.91) 132.78,49.91 133.03,49.67 133.03,47.21 132.62,46.81 JDIMM1.152
DDR_A_ODT0: length 7.1
  BOTTOM w0.076: v2(155.73,80.52) 157.04,81.83 157.04,84.09 157.32,84.37 UC1.AD3
  BOTTOM w0.168: v2(134.09,52) 133.37,52.72 JDIMM1.155
DDR_A_ODT1: length 10.5
  BOTTOM w0.076: 155.16,78.65 155.08,78.73 155.08,81.91 155.46,82.29 155.93,82.29 156.14,82.5 156.14,84.72 UC1.AE4
  BOTTOM w0.168: 155.16,78.65 v2(155.74,78.07) ; JDIMM1.161 134.87,52.97 135.33,52.51 135.73,52.51 v2(135.77,52.48)
DDR_A_PAR: length 12.1
  BOTTOM w0.076: v2(153.18,78.23) 153.53,78.58 153.53,78.94 154.08,79.48 154.08,80.19 154.51,80.62 154.51,84.22 UC1.AG3
  BOTTOM w0.168: v2(130.55,50.24) 130.09,50.24 129.66,50.67 129.66,51.51 129.34,51.83 129.34,52.56 128.37,53.53 JDIMM1.143
DDR_B_ACT#: length 2.1
  BOTTOM w0.076: UC1.AT9 147.55,88.43 v2(147.87,88.75)
  BOTTOM w0.168: JDIMM2.114 196.92,44.06 v2(197.07,44.21)
DDR_B_ALERT#: length 3.9
  BOTTOM w0.076: UC1.AR8 148.45,87.78 148.66,87.56 v2(148.75,87.56)
  BOTTOM w0.168: JDIMM2.116 197.42,43.83 197.54,43.95 197.54,45.6 197.36,45.78 v2(197.11,45.78)
DDR_B_BA0: length 2.3
  BOTTOM w0.076: UC1.AH8 v2(154.28,88.1)
  BOTTOM w0.168: JDIMM2.150 207.92,43.89 207.71,44.11 v2(207.39,44.11)
DDR_B_BA1: length 3
  BOTTOM w0.076: UC1.AH9 153.72,88.43 v2(153.36,88.07)
  BOTTOM w0.168: JDIMM2.145 206.67,50.14 206.24,49.7 v2(205.36,49.7)
DDR_B_BG0: length 7
  BOTTOM w0.076: UC1.AR9 148.21,88.43 v2(147.89,88.11)
  BOTTOM w0.168: v2(193.93,46.63) 195.12,46.63 196.48,47.99 196.48,49.28 197.17,49.97 JDIMM2.115
DDR_B_BG1: length 5
  BOTTOM w0.076: v2(147.84,87.42) 148.13,87.13 UC1.AR7
  BOTTOM w0.168: v2(193.99,48.15) 194.22,48.15 194.76,48.69 195.17,48.69 196.67,50.2 JDIMM2.113
DDR_B_CKE0: length 8.1
  BOTTOM w0.076: v2(147,87.38) 147.02,87.38 UC1.AT8
  BOTTOM w0.168: JDIMM2.109 195.67,50.21 195.13,49.67 194.56,49.67 193.42,48.52 193.42,45.54 v2(193.99,44.97)
DDR_B_CKE1: length 2
  BOTTOM w0.076: UC1.AT10 v2(147.87,89.4)
  BOTTOM w0.168: JDIMM2.110 195.92,43.94 v2(196.12,44.13)
DDR_B_CLK0: length 5.1
  BOTTOM w0.076: v2(150.61,88.13) 150.91,88.43 UC1.AM9
  BOTTOM w0.102: v2(202.9,47.75) 202.88,47.73 202.18,47.73 201.86,48.05 201.86,49.19 202.67,50.01 JDIMM2.137
DDR_B_CLK1: length 4
  BOTTOM w0.076: UC1.AM7 151.21,87.13 v2(151.53,87.45)
  BOTTOM w0.102: v2(203.81,45.84) 203.37,45.41 203.19,45.23 202.92,44.96 JDIMM2.138
DDR_B_CLK#0: length 5.2
  BOTTOM w0.076: UC1.AN9 150.26,88.43 150.26,88.43 150.29,88.43 v2(150.61,88.74)
  BOTTOM w0.102: v2(202.92,48.55) 202.92,48.34 202.53,47.95 202.25,47.95 202.07,48.13 202.07,49.11 203.17,50.22 JDIMM2.139
DDR_B_CLK#1: length 3.5
  BOTTOM w0.076: v2(151.53,88.1) 151.21,87.78 UC1.AM8
  BOTTOM w0.102: JDIMM2.140 203.42,43.53 203.15,43.81 203.15,44.87 203.35,45.07 203.72,45.07 v2(203.78,45.01)
DDR_B_CS#0: length 4.6
  BOTTOM w0.168: v2(209.57,53.31) 209.36,53.51 208.42,53.51 208.17,53.27 208.17,52.31 207.67,51.81 JDIMM2.149 ; UC1.AF11 v2(156.09,89.37)
DDR_B_CS#1: length 2.5
  BOTTOM w0.076: UC1.AE7 156.58,87.13 v2(156.95,86.76)
  BOTTOM w0.168: v2(210.49,49.62) 210.31,49.81 209.95,49.81 209.67,50.09 JDIMM2.157
DDR_B_D0: length 5.7
  BOTTOM w0.076: v2(158.63,79.79) 158.63,79.8 159.11,80.28 159.11,83.2 UC1.AB1
  BOTTOM w0.102: v2(168.1,49.87) 168.94,49.87 169.17,50.1 JDIMM2.3
DDR_B_D1: length 6
  BOTTOM w0.076: UC1.AB2 158.82,83.59 158.82,83.1 158.89,83.02 158.89,81.12 158.17,80.4 v2(157.89,80.4)
  BOTTOM w0.102: v2(168.65,44.11) 169.01,44.11 169.42,43.69 JDIMM2.4
DDR_B_D2: length 2.1
  BOTTOM w0.076: v2(160.28,84.8) 160.28,84.8 160.28,84.82 159.93,85.17 UC1.AA4
  BOTTOM w0.102: v2(172.01,44.09) 172.42,43.68 JDIMM2.16
DDR_B_D3: length 2.7
  BOTTOM w0.076: UC1.AA5 v2(160.26,85.39)
  BOTTOM w0.102: v2(171.98,49.17) 172.67,49.87 JDIMM2.17
DDR_B_D4: length 8
  BOTTOM w0.076: v2(157.87,82.24) 158.49,82.86 158.49,85.21 UC1.AB5
  BOTTOM w0.102: v2(168.07,48.16) 168.42,48.16 170,49.74 170,50 170.17,50.17 JDIMM2.7
DDR_B_D5: length 7.9
  BOTTOM w0.076: UC1.AB4 158.8,84.87 158.8,84.03 158.65,83.88 158.65,83 158.73,82.92 158.73,82.48 v2(157.89,81.64)
  BOTTOM w0.102: v2(168.63,45.92) 170.42,44.12 JDIMM2.8
DDR_B_D6: length 4
  BOTTOM w0.076: UC1.AA2 159.98,83.87 160.24,83.61 v2(160.28,83.61)
  BOTTOM w0.102: v2(172.03,45.69) 173.42,44.3 JDIMM2.20
DDR_B_D7: length 4.8
  BOTTOM w0.076: UC1.AA1 160.02,83.22 160.28,82.95 v2(160.28,83.02)
  BOTTOM w0.102: v2(172.01,47.5) 172.01,47.63 173.5,49.12 173.5,49.49 173.67,49.66 JDIMM2.21
DDR_B_D8: length 6.2
  BOTTOM w0.076: UC1.V5 161,85.21 161,85.05 161,85.05 161,84.63 161,84.63 161,84.4 161,84.4 161,83.98 161,83.98 161,83.75 161,83.75 161,83.33 161,83.33 161,82.37 v2(160.28,81.65)
  BOTTOM w0.102: v2(173.94,44.12) 174.42,43.63 JDIMM2.24
DDR_B_D9: length 8
  BOTTOM w0.076: UC1.V2 161.33,83.59 161.33,81.42 161.75,81 161.75,80.79 161.67,80.7 v2(161.67,80.35)
  BOTTOM w0.102: v2(173.91,47.55) 175.67,49.31 JDIMM2.29
DDR_B_D10: length 4.5
  BOTTOM w0.076: v2(162.8,82.99) 162.58,83.22 UC1.U1
  BOTTOM w0.102: v2(177.57,47.55) 178.67,48.65 JDIMM2.41
DDR_B_D11: length 2.4
  BOTTOM w0.076: v2(162.79,83.57) 162.5,83.87 UC1.U2
  BOTTOM w0.102: v2(177.57,49.25) 177.67,49.36 JDIMM2.37
DDR_B_D12: length 5.6
  BOTTOM w0.076: v2(162.09,79.9) 162.17,79.98 162.17,80.94 161.63,81.48 161.63,83.2 UC1.V1
  BOTTOM w0.102: JDIMM2.25 174.67,49.94 v2(174,49.26)
DDR_B_D13: length 7.9
  BOTTOM w0.076: UC1.V4 161.61,85.02 161.17,84.57 161.17,83.68 161.17,81.62 v2(160.78,81.24)
  BOTTOM w0.102: v2(173.94,45.8) 175.42,44.31 JDIMM2.28
DDR_B_D14: length 2
  BOTTOM w0.076: v2(162.79,85.49) 162.47,85.82 UC1.U5
  BOTTOM w0.102: JDIMM2.38 177.92,43.69 v2(177.57,44.04)
DDR_B_D15: length 4
  BOTTOM w0.076: UC1.U4 162.47,85.17 v2(162.79,84.84)
  BOTTOM w0.102: JDIMM2.42 178.92,43.58 178.81,43.69 178.81,44.4 v2(177.54,45.67)
DDR_B_D16: length 2.4
  BOTTOM w0.076: UC1.AA11 159.51,89.73 v2(159.76,89.98)
  BOTTOM w0.102: v2(216.61,49.41) 217.17,49.97 JDIMM2.187
DDR_B_D17: length 4
  BOTTOM w0.076: UC1.AA10 159.46,89.08 v2(159.76,89.38)
  BOTTOM w0.102: JDIMM2.183 216.17,51.01 216.17,48.1 v2(216.51,47.76)
DDR_B_D18: length 2.2
  BOTTOM w0.076: UC1.AC11 v2(158.85,90.05)
  BOTTOM w0.102: JDIMM2.174 213.92,43.56 v2(213.27,44.21)
DDR_B_D19: length 4
  BOTTOM w0.076: v2(158.85,89.4) 158.52,89.08 UC1.AC10
  BOTTOM w0.102: JDIMM2.170 212.92,43.99 212.64,44.28 212.64,45.29 v2(213.24,45.89)
DDR_B_D20: length 2.2
  BOTTOM w0.076: UC1.AA7 v2(159.77,87.46)
  BOTTOM w0.102: v2(216.56,44.33) 216.92,43.97 JDIMM2.186
DDR_B_D21: length 4.1
  BOTTOM w0.076: UC1.AA8 159.73,88.08 v2(159.77,88.08)
  BOTTOM w0.102: JDIMM2.182 215.92,45.45 v2(216.59,46.11)
DDR_B_D22: length 3.7
  BOTTOM w0.076: UC1.AC8 v2(158.77,88.05)
  BOTTOM w0.102: JDIMM2.169 212.67,48.58 v2(213.25,48)
DDR_B_D23: length 2.1
  BOTTOM w0.076: v2(158.8,87.41) 158.8,87.37 158.55,87.13 UC1.AC7
  BOTTOM w0.102: v2(213.24,49.67) 213.36,49.67 213.67,49.99 JDIMM2.173
DDR_B_D24: length 3.8
  BOTTOM w0.076: v2(161.57,88.17) 161.17,87.78 UC1.W8
  BOTTOM w0.102: v2(218.75,48.08) 218.17,48.65 JDIMM2.191
DDR_B_D25: length 2
  BOTTOM w0.076: UC1.W7 161.23,87.13 v2(161.6,87.5)
  BOTTOM w0.102: JDIMM2.195 219.17,50.09 v2(218.82,49.73)
DDR_B_D26: length 4.6
  BOTTOM w0.076: v2(162.47,89.4) 162.05,89.11 UC1.V10
  BOTTOM w0.102: v2(222.25,47.37) 221.17,48.44 JDIMM2.203
DDR_B_D27: length 2.3
  BOTTOM w0.076: UC1.V11 162.05,89.75 v2(162.48,90.05)
  BOTTOM w0.102: v2(222.09,49.25) 222.17,49.33 JDIMM2.207
DDR_B_D28: length 4.6
  BOTTOM w0.076: v2(161.59,89.4) 161.27,89.73 UC1.W11
  BOTTOM w0.102: v2(218.64,46.4) 217.8,45.56 217.8,43.99 217.92,43.87 JDIMM2.190
DDR_B_D29: length 2.2
  BOTTOM w0.076: v2(160.69,88.79) 160.69,88.84 160.94,89.08 UC1.W10
  BOTTOM w0.102: v2(218.67,44.37) 218.92,44.11 JDIMM2.194
DDR_B_D30: length 2
  BOTTOM w0.076: UC1.V7 162.21,87.13 162.53,87.45 v2(162.54,87.45)
  BOTTOM w0.102: JDIMM2.208 222.42,43.77 v2(222.15,44.05)
DDR_B_D31: length 3.7
  BOTTOM w0.076: v2(162.56,88.08) 162.26,87.78 UC1.V8
  BOTTOM w0.102: JDIMM2.204 221.42,43.7 221.74,44.02 221.74,45.22 v2(222.12,45.6)
DDR_B_D32: length 7.5
  BOTTOM w0.076: UC1.R2 163.85,83.59 163.85,81.97 164.54,81.28 v2(164.54,80.76)
  BOTTOM w0.102: JDIMM2.49 180.67,49.85 180.78,49.75 180.78,48.29 v2(179.88,47.4)
DDR_B_D33: length 4.3
  BOTTOM w0.076: v2(165.31,85.49) 164.98,85.82 UC1.P5
  BOTTOM w0.102: JDIMM2.58 182.92,43.66 182.62,43.97 182.62,45.03 183.49,45.9 v2(183.59,45.9)
DDR_B_D34: length 7.1
  BOTTOM w0.076: v2(163.66,81.56) 163.68,81.58 163.68,84.72 UC1.R4
  BOTTOM w0.102: v2(179.86,45.62) 179.98,45.62 180.92,44.67 JDIMM2.50
DDR_B_D35: length 4.4
  BOTTOM w0.076: v2(165.31,84.84) 164.98,85.17 UC1.P4
  BOTTOM w0.102: v2(183.61,47.6) 182.87,48.34 182.87,49.72 183.17,50.02 JDIMM2.59
DDR_B_D36: length 5.5
  BOTTOM w0.076: v2(163.27,82) 163.52,82.24 163.52,85.21 UC1.R5
  BOTTOM w0.102: v2(179.76,44.07) 179.92,43.91 JDIMM2.46
DDR_B_D37: length 2.5
  BOTTOM w0.076: UC1.P2 164.98,83.87 v2(165.31,83.54)
  BOTTOM w0.102: v2(183.69,49.27) 184.17,49.76 JDIMM2.63
DDR_B_D38: length 5.2
  BOTTOM w0.076: UC1.R1 164.13,82.46 165.01,81.58 165.01,80.38 v2(164.95,80.32)
  BOTTOM w0.102: v2(179.86,49.17) 179.67,49.35 JDIMM2.45
DDR_B_D39: length 2.1
  BOTTOM w0.076: v2(165.36,82.92) 165.29,82.92 164.98,83.22 UC1.P1
  BOTTOM w0.102: v2(183.67,44.2) 183.92,43.94 JDIMM2.62
DDR_B_D40: length 5.8
  BOTTOM w0.076: UC1.M4 166.2,84.72 166.2,82.86 166.4,82.66 166.4,82.41 166.65,82.16 166.65,81.59 v2(166.67,81.57)
  BOTTOM w0.102: v2(185.34,49.22) 185.17,49.39 JDIMM2.67
DDR_B_D41: length 5.2
  BOTTOM w0.076: v2(168,80.19) 168,81.16 167.34,81.82 167.34,82.09 166.75,82.68 166.75,82.83 166.64,82.95 UC1.M1
  BOTTOM w0.102: v2(185.37,44.17) 185.92,43.61 JDIMM2.70
DDR_B_D42: length 2.7
  BOTTOM w0.076: UC1.L4 167.78,84.76 v2(167.82,84.76)
  BOTTOM w0.102: v2(188.99,49.02) 189.17,49.2 JDIMM2.83
DDR_B_D43: length 3.9
  BOTTOM w0.076: v2(167.82,83.54) 167.49,83.87 UC1.L2
  BOTTOM w0.102: JDIMM2.80 188.42,43.55 188.21,43.76 188.21,44.92 v2(189,45.71)
DDR_B_D44: length 8.1
  BOTTOM w0.076: UC1.M5 166.03,85.21 166.03,82.72 166.2,82.55 166.2,82.03 v2(166.22,82.02)
  BOTTOM w0.102: v2(185.37,47.52) 186.3,48.46 186.3,49.94 186.17,50.07 JDIMM2.71
DDR_B_D45: length 7
  BOTTOM w0.076: v2(167.55,80.64) 167.55,81.23 167.05,81.73 167.05,82.07 166.56,82.56 166.56,82.73 166.36,82.93 166.36,83.59 UC1.M2
  BOTTOM w0.102: JDIMM2.66 184.92,45.27 v2(185.39,45.74)
DDR_B_D46: length 4.6
  BOTTOM w0.076: UC1.L5 167.67,85.52 v2(167.83,85.52)
  BOTTOM w0.102: JDIMM2.79 188.17,49.95 188.08,49.85 188.08,48.31 v2(189.02,47.37)
DDR_B_D47: length 2.1
  BOTTOM w0.076: v2(167.87,82.96) 167.83,82.96 167.57,83.22 UC1.L1
  BOTTOM w0.102: v2(189.16,44.21) 189.16,44.08 189.42,43.82 JDIMM2.84
DDR_B_D48: length 2
  BOTTOM w0.076: UC1.R11 164.21,89.96 v2(164.33,90.05)
  BOTTOM w0.102: v2(224.19,44.17) 224.42,43.93 JDIMM2.216
DDR_B_D49: length 2.3
  BOTTOM w0.076: UC1.P11 v2(165.25,90.05)
  BOTTOM w0.102: v2(227.78,49.27) 227.67,49.38 JDIMM2.229
DDR_B_D50: length 2.1
  BOTTOM w0.076: v2(165.25,87.45) 164.92,87.13 UC1.P7
  BOTTOM w0.102: JDIMM2.228 227.42,43.8 v2(227.78,44.15)
DDR_B_D51: length 4.6
  BOTTOM w0.076: UC1.R8 164.2,88.1 v2(164.31,88.1)
  BOTTOM w0.102: v2(224.16,47.67) 223.73,47.67 223.17,48.23 JDIMM2.211
DDR_B_D52: length 3.9
  BOTTOM w0.076: UC1.R10 164.21,89.31 v2(164.33,89.4)
  BOTTOM w0.102: v2(224.24,45.84) 223.42,45.03 JDIMM2.212
DDR_B_D53: length 4.4
  BOTTOM w0.076: UC1.P10 v2(165.25,89.4)
  BOTTOM w0.102: v2(227.78,47.61) 226.67,48.72 JDIMM2.225
DDR_B_D54: length 2.1
  BOTTOM w0.076: v2(164.29,87.42) 164.05,87.19 164.04,87.19 163.98,87.13 UC1.R7
  BOTTOM w0.102: JDIMM2.215 224.16,51 v2(224.16,49.5)
DDR_B_D55: length 4.3
  BOTTOM w0.076: UC1.P8 164.92,87.78 v2(165.25,88.1)
  BOTTOM w0.102: JDIMM2.224 226.42,44.5 v2(227.83,45.91)
DDR_B_D56: length 2.7
  BOTTOM w0.076: UC1.L11 v2(167.96,90.05)
  BOTTOM w0.102: v2(233.69,49.46) 233.64,49.41 233.48,49.41 232.67,50.22 JDIMM2.249
DDR_B_D57: length 2.1
  BOTTOM w0.076: UC1.M11 v2(167.08,90.05)
  BOTTOM w0.102: JDIMM2.236 229.42,43.52 229.98,44.08 v2(230,44.08)
DDR_B_D58: length 2.9
  BOTTOM w0.076: UC1.L7 v2(167.94,87.48)
  BOTTOM w0.102: JDIMM2.250 232.92,44.07 v2(233.63,44.78)
DDR_B_D59: length 3
  BOTTOM w0.076: v2(167.01,87.42) 166.62,87.81 UC1.M8
  BOTTOM w0.102: v2(230.03,48.77) 229.61,49.19 229.61,49.85 229.67,49.91 JDIMM2.237
DDR_B_D60: length 4.5
  BOTTOM w0.076: UC1.L10 v2(167.96,89.4)
  BOTTOM w0.102: JDIMM2.245 231.67,49.87 233.62,47.93 v2(233.69,47.93)
DDR_B_D61: length 4
  BOTTOM w0.076: UC1.M10 v2(167.08,89.4)
  BOTTOM w0.102: JDIMM2.232 228.42,44.05 v2(229.98,45.6)
DDR_B_D62: length 4.9
  BOTTOM w0.076: v2(167.01,86.78) 166.66,87.13 UC1.M7
  BOTTOM w0.102: JDIMM2.233 228.67,48.49 v2(229.99,47.17)
DDR_B_D63: length 4.9
  BOTTOM w0.076: v2(167.96,88.15) 167.59,87.78 UC1.L8
  BOTTOM w0.102: v2(233.61,46.36) 232.62,45.37 232.62,45.1 231.92,44.4 JDIMM2.246
DDR_B_DQS0: length 11.5
  BOTTOM w0.076: UC1.AB3 159.31,84.52 159.38,84.44 159.38,81.31 159.91,80.78 159.91,80.37 159.88,80.34 159.88,80.32
  BOTTOM w0.102: v2(159.11,78.6) 159.48,78.6 159.88,79 159.88,80.32 ; JDIMM2.13 171.67,50.15 171.32,49.79 171.32,49.79 171.25,49.72 171,49.47 171,47.7 170.77,47.46 170.41,47.46 170.32,47.37 170.32,47.32 v2(170.23,47.23)
DDR_B_DQS1: length 11.1
  BOTTOM w0.076: 162.89,80.41 162.88,80.42 162.88,80.47 161.9,81.44 161.9,84.44 161.82,84.52 UC1.V3
  BOTTOM w0.102: v2(175.89,46.6) 175.89,46.49 176.08,46.3 176.27,46.3 176.79,45.79 176.79,43.75 176.92,43.62 JDIMM2.34 ; 162.89,80.41 163.11,80.19 163.41,79.89 163.41,79.31 163.1,78.99 v2(162.83,78.99)
DDR_B_DQS2: length 4.8
  BOTTOM w0.076: UC1.AA9 159.44,88.43 v2(159.76,88.75)
  BOTTOM w0.102: JDIMM2.179 215.17,49.94 214.37,49.14 214.37,47.93 214.5,47.8 214.66,47.8 214.81,47.94 v2(214.81,48.21)
DDR_B_DQS3: length 5.8
  BOTTOM w0.076: v2(162.48,88.82) 162.47,88.81 162.47,88.76 162.14,88.43 UC1.V9
  BOTTOM w0.102: JDIMM2.200 220.42,43.83 220.29,43.97 220.29,44.02 221.23,44.97 221.23,46.43 221,46.66 220.67,46.66 220.47,46.86 v2(220.47,47.06)
DDR_B_DQS4: length 10.6
  BOTTOM w0.076: UC1.R3 164.34,84.52 164.41,84.44 164.41,83.04 165.71,81.75 165.71,81.65 166.18,81.18 166.18,81.16 166.19,81.15
  BOTTOM w0.102: JDIMM2.55 182.17,49.99 182.17,49.98 182.17,47.88 181.89,47.6 181.85,47.6 v2(181.43,47.18) ; v2(165.84,79.48) 166.13,79.48 166.33,79.68 166.33,81.01 166.19,81.15
DDR_B_DQS5: length 9.1
  BOTTOM w0.076: v2(169.23,81.69) 169.03,81.69 168.76,81.43 168.3,81.43 166.93,82.8 166.93,84.05 166.83,84.14 166.83,84.33 UC1.M3
  BOTTOM w0.102: JDIMM2.76 187.42,43.59 187.29,43.73 187.29,44.12 187.7,44.53 187.7,45.97 v2(187.08,46.6)
DDR_B_DQS6: length 4.5
  BOTTOM w0.076: v2(165.25,88.75) 164.92,88.43 UC1.P9
  BOTTOM w0.102: JDIMM2.221 225.67,49.99 225.54,49.85 225.54,48.09 225.76,47.87 225.91,47.87 225.99,47.95 225.99,48.22 v2(226.03,48.26)
DDR_B_DQS7: length 5
  BOTTOM w0.076: UC1.L9 v2(167.12,88.15)
  BOTTOM w0.102: v2(231.74,46.02) 231.74,46.14 231.52,46.37 231.33,46.37 230.79,45.83 230.79,43.97 230.92,43.83 JDIMM2.242
DDR_B_DQS#0: length 11.4
  BOTTOM w0.076: UC1.AA3 159.62,84.52 159.55,84.44 159.55,81.38 160.08,80.85 160.08,80.37 160.11,80.34 160.11,80.32
  BOTTOM w0.102: 160.11,80.32 160.11,78.91 159.69,78.49 159.61,78.12 v2(159.56,78.07) ; v2(170.23,48.05) 170.23,47.87 170.41,47.69 170.67,47.69 170.77,47.79 170.77,49.56 171.13,49.91 171.13,50.08 171.17,50.13 JDIMM2.11
DDR_B_DQS#1: length 11
  BOTTOM w0.076: 163.05,80.57 163.04,80.58 162.99,80.58 162.06,81.51 162.06,84.44 162.14,84.52 UC1.U3
  BOTTOM w0.102: 163.05,80.57 163.63,79.98 163.63,79.21 163.26,78.84 v2(163.26,78.57) ; v2(175.84,45.74) 175.99,45.89 175.99,45.98 176.08,46.08 176.18,46.08 176.56,45.69 176.56,43.73 176.42,43.6 JDIMM2.32
DDR_B_DQS#2: length 5.1
  BOTTOM w0.076: v2(158.85,88.75) 158.52,88.43 UC1.AC9
  BOTTOM w0.102: v2(214.82,47.27) 214.83,47.29 214.83,47.5 214.76,47.57 214.41,47.57 214.15,47.83 214.15,49.23 214.76,49.85 214.76,50.1 214.67,50.19 JDIMM2.177
DDR_B_DQS#3: length 5.4
  BOTTOM w0.076: UC1.W9 161.19,88.43 161.57,88.81 v2(161.57,88.82)
  BOTTOM w0.102: v2(220.49,46.08) 220.49,46.32 220.6,46.44 220.9,46.44 221.01,46.33 221.01,45.06 220.06,44.12 220.06,43.97 219.92,43.83 JDIMM2.198
DDR_B_DQS#4: length 10.8
  BOTTOM w0.076: UC1.P3 164.65,84.52 164.58,84.44 164.58,83.11 165.88,81.8 165.88,81.78 v3(166.22,81.45) 166.35,81.31
  BOTTOM w0.102: v2(181.4,48.18) 181.34,48.12 181.34,47.9 181.41,47.83 181.79,47.83 181.95,47.98 181.95,50.05 181.67,50.32 JDIMM2.53 ; v2(166.29,79.03) 166.29,79.32 166.56,79.59 166.56,81.11 166.35,81.31
DDR_B_DQS#5: length 8.2
  BOTTOM w0.076: UC1.L3 167.1,84.52 167,84.41 167,84.21 167.09,84.12 167.09,82.87 168.37,81.59 168.69,81.59 168.85,81.75 168.85,82.07 v2(168.78,82.14)
  BOTTOM w0.102: v2(187.08,45.62) 187.37,45.62 187.48,45.51 187.48,44.62 187.06,44.21 187.06,43.76 186.92,43.62 JDIMM2.74
DDR_B_DQS#6: length 4.7
  BOTTOM w0.076: v2(164.34,88.78) 164.34,88.76 164.01,88.43 UC1.R9
  BOTTOM w0.102: JDIMM2.219 225.17,49.99 225.31,49.85 225.31,48 225.95,47.35 v2(226,47.35)
DDR_B_DQS#7: length 5.5
  BOTTOM w0.076: UC1.M9 166.77,88.43 167.12,88.77 v2(167.15,88.77)
  BOTTOM w0.102: JDIMM2.240 230.42,43.83 230.56,43.97 230.56,45.92 231.23,46.59 231.58,46.59 231.74,46.75 v2(231.74,46.91)
DDR_B_MA0: length 4.3
  BOTTOM w0.076: UC1.AJ9 153.04,88.43 v2(153.36,88.75)
  BOTTOM w0.168: JDIMM2.144 204.42,44.42 204.59,44.59 204.59,45.41 205.26,46.09 v2(205.26,46.19)
DDR_B_MA1: length 2.7
  BOTTOM w0.076: v2(151.89,86.16) 152.03,86.16 UC1.AK6
  BOTTOM w0.168: JDIMM2.133 201.67,50.05 200.92,49.29 v2(200.78,49.29)
DDR_B_MA2: length 2.3
  BOTTOM w0.076: v2(152.67,85.48) 152.62,85.48 UC1.AK5
  BOTTOM w0.168: JDIMM2.132 201.42,43.58 201.95,44.1 v2(202.2,44.1)
DDR_B_MA3: length 4.7
  BOTTOM w0.076: UC1.AL5 151.44,85.82 v2(151.11,85.49)
  BOTTOM w0.168: JDIMM2.131 201.17,50.27 200.83,49.92 200.79,49.92 200.22,49.35 200.22,47.93 v2(200.66,47.5)
DDR_B_MA4: length 2
  BOTTOM w0.076: UC1.AL6 151.49,86.47 v2(151.14,86.12)
  BOTTOM w0.168: JDIMM2.128 200.42,43.98 v2(200.66,44.22)
DDR_B_MA5: length 4
  BOTTOM w0.076: v2(150.24,86.06) 150.25,86.06 UC1.AM6
  BOTTOM w0.168: v2(200.65,45.88) 199.92,45.16 JDIMM2.126
DDR_B_MA6: length 3.1
  BOTTOM w0.076: UC1.AN7 150.44,87.13 150.62,86.95 150.63,86.95 v2(150.64,86.94)
  BOTTOM w0.168: v2(198.96,49.38) 199.6,49.38 200.17,49.95 JDIMM2.127
DDR_B_MA7: length 4.1
  BOTTOM w0.076: UC1.AN10 v2(150.62,89.4)
  BOTTOM w0.168: v2(198.89,45.85) 198.97,45.85 199.41,45.41 199.41,44.05 198.92,43.57 JDIMM2.122
DDR_B_MA8: length 5.7
  BOTTOM w0.076: v2(150.61,87.54) 150.37,87.78 UC1.AN8
  BOTTOM w0.168: JDIMM2.125 199.67,50.02 199.51,49.86 198.69,49.86 198.13,49.29 198.13,48 198.6,47.53 v2(198.94,47.53)
DDR_B_MA9: length 5.1
  BOTTOM w0.076: v2(148.78,89.35) 148.4,89.73 UC1.AR11
  BOTTOM w0.168: v2(196.97,47.44) 197.35,47.44 197.78,47.87 197.78,49.36 198.67,50.26 JDIMM2.121
DDR_B_MA10: length 3.2
  BOTTOM w0.076: UC1.AH7 v2(154.28,87.45)
  BOTTOM w0.168: JDIMM2.146 206.92,43.72 206.58,44.07 v2(205.38,44.07)
DDR_B_MA11: length 2.2
  BOTTOM w0.076: UC1.AN11 v2(150.62,90.05)
  BOTTOM w0.168: v2(198.86,44.23) 198.77,44.23 198.42,43.88 JDIMM2.120
DDR_B_MA12: length 3.2
  BOTTOM w0.076: v2(148.79,88.74) 148.45,89.08 UC1.AR10
  BOTTOM w0.168: JDIMM2.119 198.17,50.24 197.08,49.14 197.08,49.04 v2(196.93,48.89)
DDR_B_MA13: length 5.3
  BOTTOM w0.076: UC1.AF9 155.54,88.43 v2(155.23,88.12)
  BOTTOM w0.168: JDIMM2.158 209.92,44.07 209.59,44.41 209.59,46.17 208.93,46.83 v2(208.93,47.15)
DDR_B_MA14: length 2.7
  BOTTOM w0.076: UC1.AH11 v2(154.28,90.05)
  BOTTOM w0.168: JDIMM2.151 208.17,49.72 207.9,49.45 v2(207.43,49.45)
DDR_B_MA15: length 7.6
  BOTTOM w0.076: UC1.AF8 155.69,87.78 v2(156.08,88.16)
  BOTTOM w0.168: v2(208.93,49.14) 208.4,48.61 208.4,45.54 209.12,44.82 209.12,44.13 209.42,43.82 JDIMM2.156
DDR_B_MA16: length 4
  BOTTOM w0.076: UC1.AH10 v2(154.28,89.4)
  BOTTOM w0.168: JDIMM2.152 208.43,44.44 208.08,44.78 208.08,45.08 v2(207.34,45.83)
DDR_B_ODT0: length 5.9
  BOTTOM w0.076: v2(156.13,87.43) 155.83,87.13 UC1.AF7
  BOTTOM w0.168: v2(210.5,46.24) 210.45,46.28 210.45,46.45 209.83,47.07 209.83,47.42 209.44,47.81 209.44,49.54 209.17,49.8 JDIMM2.155
DDR_B_ODT1: length 3.8
  BOTTOM w0.076: UC1.AE8 v2(156.99,87.35)
  BOTTOM w0.168: JDIMM2.161 210.67,50.17 210.99,49.85 210.99,48.59 v2(210.49,48.1)
DDR_B_PAR: length 4
  BOTTOM w0.076: UC1.AJ7 v2(153.36,87.45)
  BOTTOM w0.168: v2(205.21,48.02) 204.17,49.06 JDIMM2.143
DDR_DRAMRST#: length 7.1
  TOP w0.102: CD61.1 195.42,41.53 v2(195.42,41.52) ; v2(120.12,44.73) 119.63,44.73 v1(119.55,44.65)
  BOTTOM w0.102: JDIMM1.108 119.62,44.9 119.26,44.54 RD12.1 CD29.1 v2(120.13,44.73) ; JDIMM2.108 v2(195.42,41.52)
DDR_RCOMP0: length 11.8
  BOTTOM w0.254: 171.66,81.89 170.33,83.22 UC1.G1
  BOTTOM w0.381: 171.66,81.89 171.66,78.88 172.19,78.34 175.55,78.34 177.03,79.82 RC5.2
DDR_RCOMP1: length 14.8
  BOTTOM w0.254: UC1.H1 170.27,82.36 170.32,82.36 170.77,81.91
  BOTTOM w0.381: RC6.2 177.92,79.46 175.92,77.46 171.76,77.46 170.77,78.45 v1(170.77,79.15) 170.77,81.91
DDR_RCOMP2: length 18.5
  BOTTOM w0.254: UC1.J2 168.99,83.76 168.99,82.89 170.14,81.75 170.14,80.91
  BOTTOM w0.381: 170.14,80.91 169.88,80.66 v1(169.88,80.38) 169.88,78.05 171.38,76.55 176.37,76.55 178.87,79.06 178.87,80.33 RC7.2
DDR_VTT_CTRL: length 16.9
  TOP w0.102: UD1.2 119.88,93.53 120.15,93.27 120.6,93.27 121.75,92.12 130.54,92.12 v2(130.57,92.15)
  BOTTOM w0.076: v2(130.57,92.15) v1(130.57,93.99)
  BOTTOM w0.102: UC1.BT13 133.22,91.35 132.61,91.96 130.67,91.96 130.57,92.06 v2(130.57,92.15)
DDR_XDP_WAN_SMBCLK: length 36.2
  TOP w0.102: v2(163.8,45.68) 163.77,45.65 163.3,45.65 RC845.1 ; v2(251.77,43.97) 252.31,43.97 252.6,44.26 v1(252.75,44.26) 253.05,44.26 253.76,43.55 LGA1.1
  BOTTOM w0.102: 163.74,45.62 v2(163.8,45.68) ; 225.1,125.43 225.1,123.84 225.84,123.1 RH333.1 ; 158.33,52.56 158.33,51.67
  BOTTOM w0.109: JDIMM2.253 233.67,50.1 234.76,49.01 234.76,47.2 v2(234.85,47.11) ; v2(221.78,133.53) 223.16,132.15 223.16,131.94 224.61,130.49 224.61,127.86 225.08,127.39 225.08,125.45 225.1,125.43 ; 158.33,52.56 157.87,53.01 JDIMM1.253 ; 158.33,51.67 159.21,50.79 159.21,49.59 159.7,49.1 162.67,49.1 164.05,47.72 164.05,46.85 163.38,46.17 163.38,45.74 163.5,45.62 163.74,45.62 ; RH333.1 227.77,123.22 QH4.1
DDR_XDP_WAN_SMBCLK_XDP: length 27.7
  TOP w0.102: v2(92.55,115.94) 92.43,116.05 92.43,116.15 91.95,116.63 88.97,116.63 86.65,118.96 86.65,126.48 88.45,128.28 91.19,128.28 92.2,129.29 92.2,131.35 v1(91.97,131.58) 91.51,132.04 91.51,132.4 v2(91.56,132.45) ; v2(161.98,45.7) 161.99,45.69 RC845.2
  BOTTOM w0.102: v2(91.56,132.45) 91.44,132.57 91.44,133.5 91.81,133.87 JXDP1.53
DDR_XDP_WAN_SMBDAT: length 31.7
  TOP w0.102: LGA1.4 252.05,43.38 v2(251.77,43.38) ; RC846.1 163.3,45.17 163.73,45.17 v2(163.8,45.1)
  BOTTOM w0.109: RH374.1 231.49,124.52 QH4.4 229.6,124.52 229.11,125.01 226.85,125.01 225.57,126.29 225.57,127.59 225.1,128.06 225.1,130.69 223.83,131.96 223.83,132.2 222.55,133.49 v2(222.41,133.49) ; v2(234.85,46.48) 234.09,45.72 234.09,43.82 233.92,43.65 JDIMM2.254 ; JDIMM1.254 158.12,46.95 159.06,47.88 159.06,48.36 159.32,48.61 162.47,48.61 163.56,47.52 163.56,47.05 162.89,46.38 162.89,45.54 163.3,45.13 163.77,45.13 v2(163.8,45.1)
DDR_XDP_WAN_SMBDAT_XDP: length 27.6
  TOP w0.102: v2(161.98,45.07) 162.03,45.12 RC846.2 ; v2(90.98,132.45) 91.03,132.4 91.03,131.84 91.71,131.15 91.71,129.49 90.99,128.76 88.25,128.76 86.16,126.68 86.16,118.76 88.77,116.15 91.75,116.15 v2(91.97,115.94)
  BOTTOM w0.102: JXDP1.51 91.21,132.69 v2(90.98,132.45)
DEBUG_TX: length 10.1
  BOTTOM w0.109: RE30.2 254.51,64.06 254.11,64.46 254.11,66.86 v1(254.6,67.35) 254.91,67.67 RE74.2 257.46,66.95 258.8,66.95 258.99,66.76 JDEG1.9
DEW1: length 5.4
  TOP w0.102: RN16.2 245.15,39.21 RN17.2 245.55,39.87 245.55,40.78 v1(245.11,41.22)
  TOP w0.109: UN7.16 243.69,38.28 243.96,38.55 244.74,38.55 244.85,38.66 RN16.2
DEW2: length 3.6
  TOP w0.102: v1(239.52,31.84) RN14.2
  TOP w0.109: UN7.6 241.69,33.08 241.16,32.55 RN15.2 RN14.2
DGPU_HOLD_RST#: length 2.5
  TOP w0.109: T37.1 213.16,106.33 v2(213.41,106.57)
  BOTTOM w0.089: UH1.BB20 225.89,108.53 226.32,108.53 226.33,108.54 227.21,108.54 227.39,108.72 v2(227.39,108.76)
DGPU_PWR_EN: length 1.4
  TOP w0.109: v2(212.27,107.41) 212.27,106.87 T38.1
  BOTTOM w0.089: UH1.AN18 224.83,104.04 v2(224.66,104.21)
DGPU_PWROK: length 7.7
  TOP w0.102: v4(260.16,86.62) RE529.1
  TOP w0.109: RE529.1 261.82,87.09 261.82,89.34 263.22,90.73 263.22,91.67 UE1.M4
DIFFOUT_2PH_CPU: length 6.1
  TOP w0.254: PRZ43.1 99.42,98.56 PRZ46.1 100.43,98.58 v1(101.15,97.86) v2(102.37,96.64)
  BOTTOM w0.203: v2(102.37,96.64) 102.37,97 102.73,97.36 PUZ1.35
DIFFOUT_4PH_CPU: length 4.4
  TOP w0.102: v2(102.12,105.59) 102.12,105.34 102.34,105.12 102.34,104.86 v1(102.42,104.79)
  TOP w0.254: v2(102.12,105.59) 102.04,105.67 PRZ45.2 102.12,106.74 PCZ18.2
  BOTTOM w0.203: v2(102.12,105.59) 102.33,105.38 PUZ1.4
DIMM1_SA0: length 7.4
  TOP w0.102: v1(160.33,48.91) 160.47,48.91 161.43,47.95 RD5.1
  TOP w0.109: RD4.2 RD5.1 v2(161.43,47.21)
  BOTTOM w0.109: JDIMM1.256 158.62,46.97 159.38,47.72 160.92,47.72 v2(161.43,47.21)
DIMM1_SA1: length 5.9
  TOP w0.102: RD7.1 v1(161.43,45.62)
  TOP w0.109: RD7.1 RD6.2 v2(162.23,47.21)
  BOTTOM w0.109: v2(162.23,47.21) 162.01,47.21 161.56,46.77 159.76,46.77 159.62,46.63 JDIMM1.260
DIMM1_SA2: length 3.9
  TOP w0.102: v1(136.51,42.25) RD8.2
  TOP w0.109: RD8.2 RD9.1 136.51,44.6 v2(136.58,44.67)
  BOTTOM w0.127: JDIMM1.166 136.12,45.13 v2(136.58,44.67)
DIMM2_SA0: length 4.7
  TOP w0.102: v1(234.86,44.56) 235.14,44.84 v2(235.31,44.84)
  TOP w0.109: v2(235.31,44.84) RD21.1 RD20.2
  BOTTOM w0.109: v2(235.31,44.84) 234.93,44.84 234.42,44.34 JDIMM2.256
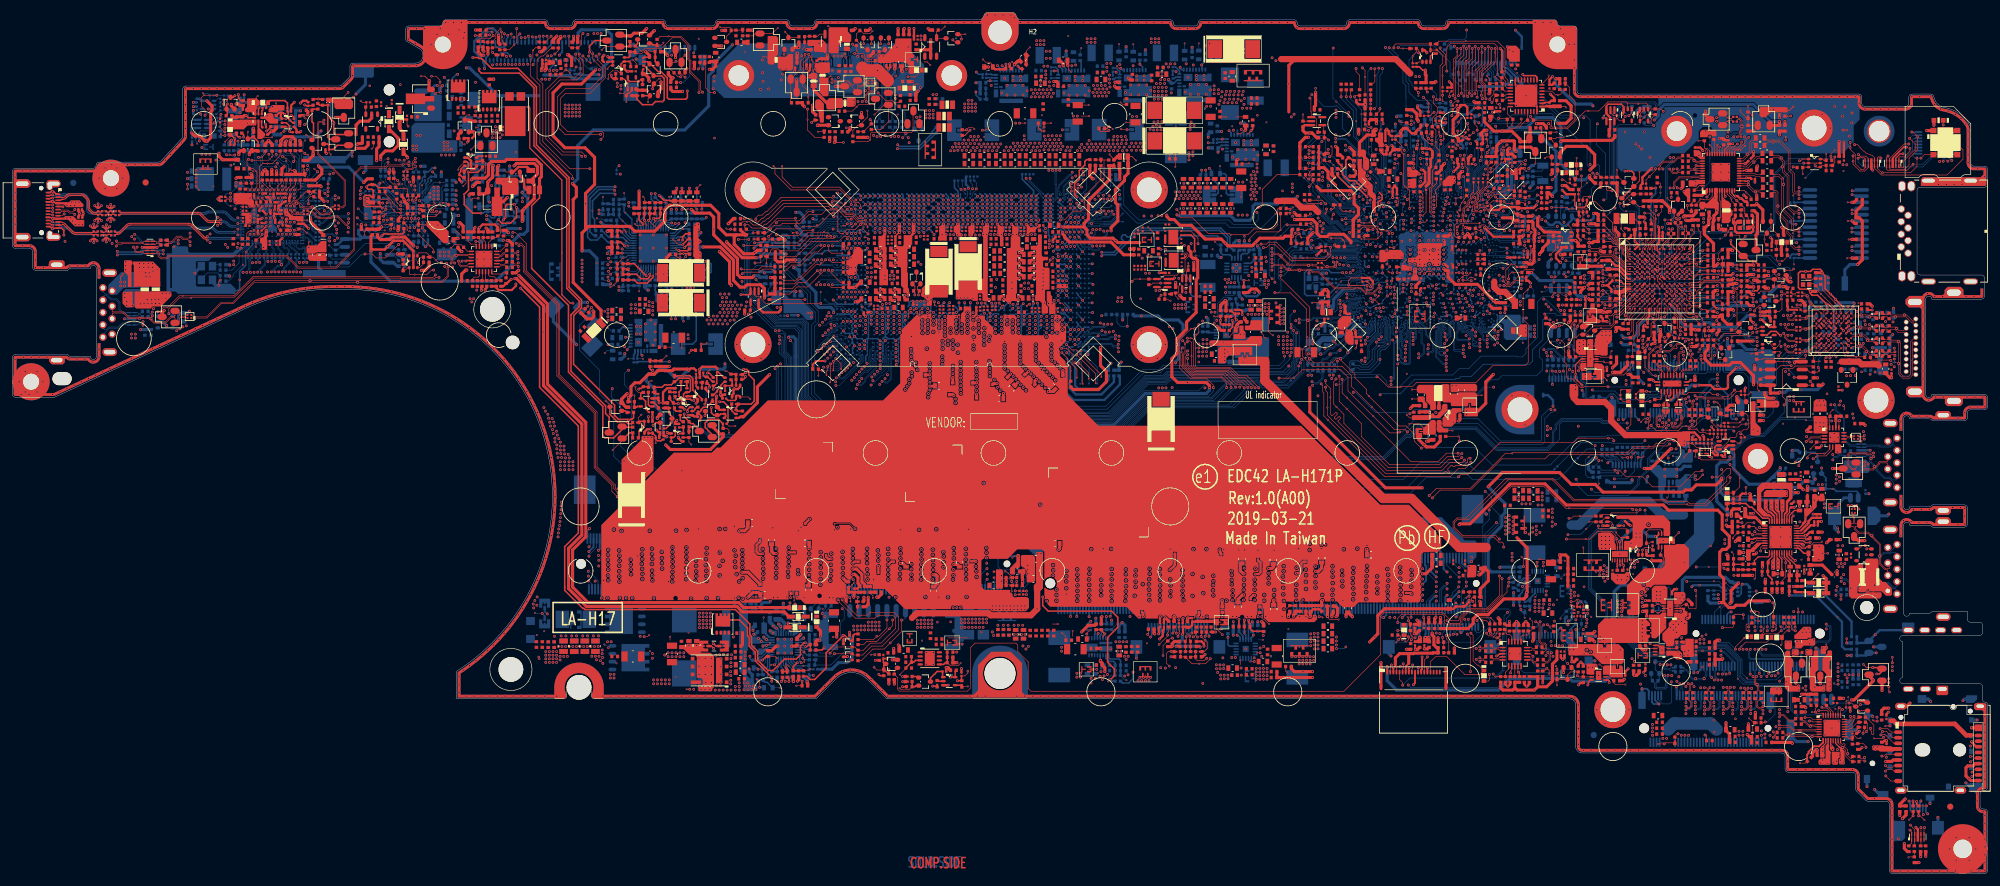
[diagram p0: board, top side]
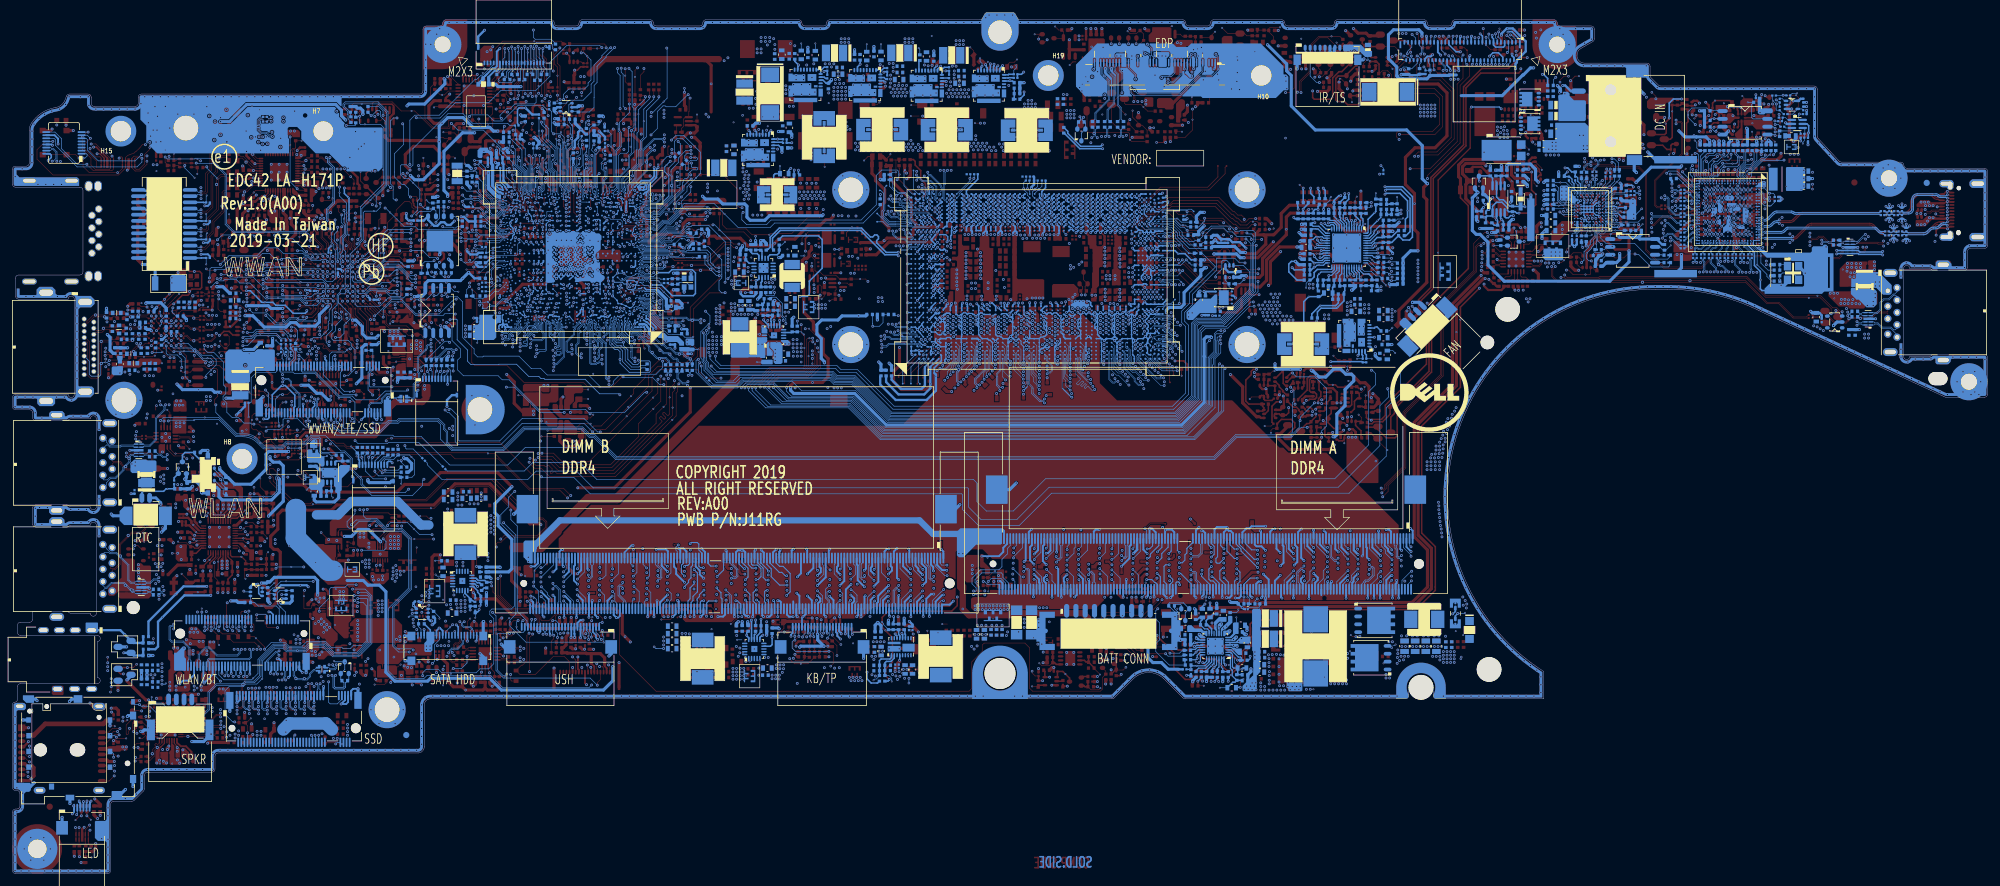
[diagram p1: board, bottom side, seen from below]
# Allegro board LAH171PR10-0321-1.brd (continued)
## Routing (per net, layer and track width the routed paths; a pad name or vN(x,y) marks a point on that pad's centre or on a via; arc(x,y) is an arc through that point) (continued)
DIMM2_SA1: length 5.1
  TOP w0.102: RD23.1 235.42,43.35 v1(235.26,43.19)
  TOP w0.109: RD23.1 236.34,43.48 236.34,44.53 RD22.2 235.88,44.7 235.71,44.52 235.71,44.21 v2(235.9,44.02)
  BOTTOM w0.109: JDIMM2.260 235.42,43.73 235.71,44.02 v2(235.9,44.02)
DIMM2_SA2: length 5.3
  TOP w0.102: v1(214.22,41.07) 212.8,41.07 212.42,41.44 v2(212.42,41.54)
  TOP w0.508: RD25.1 RD24.2 v2(212.42,41.54)
  BOTTOM w0.305: v2(212.42,41.54) 212.33,41.54 211.92,41.95 JDIMM2.166
DISP_ON: length 8.2
  TOP w0.107: DV2.1 140.61,132.85 RV2.1 139.97,132.85 138.72,131.6 v1(138.23,131.6) 138.04,131.6 137.67,131.97 137.67,132.3 137.43,132.54 136.07,132.54 v2(136.05,132.56)
  BOTTOM w0.107: v2(136.05,132.56) 135.66,132.56 135.29,132.2 135.29,132.18 135.26,132.15 JEDP1.22
DMI_CRX_PTX_N0: length 3.6
  BOTTOM w0.076: UC1.E8 171.58,87.86 v2(171.58,87.93)
  BOTTOM w0.089: UH1.C33 232.48,89.24 232.3,89.24 232.16,89.1 232.11,88.98 232.11,88.75 231.92,88.56 231.92,87.24 231.79,87.11 231.64,87.11 v2(231.4,87.34)
DMI_CRX_PTX_N1: length 6.2
  BOTTOM w0.076: UC1.F6 170.69,86.75 170.87,86.57 v2(170.87,86.37)
  BOTTOM w0.089: v2(231.34,85.03) 231.26,85.03 231.26,85.04 231.26,85.04 230.83,85.04 230.63,85.24 230.63,87.36 231.15,87.88 231.15,88.62 231.43,88.9 231.43,89.22 231.67,89.46 UH1.C32
DMI_CRX_PTX_N2: length 8.1
  BOTTOM w0.076: UC1.E5 171.25,85.99 v2(171.6,86.33)
  BOTTOM w0.089: v2(231.65,83.63) 231.27,83.63 231.2,83.7 230.64,83.7 230.25,84.09 230.25,87.52 230.76,88.04 230.76,89.08 230.98,89.3 231.08,89.3 UH1.C31
DMI_CRX_PTX_N3: length 8.6
  BOTTOM w0.076: UC1.J9 169.24,88.43 v2(169.57,88.75)
  BOTTOM w0.089: v2(231.59,82.46) 231.17,82.46 230.06,83.58 230.06,87.6 230.57,88.12 230.57,89.12 UH1.C29
DMI_CRX_PTX_P0: length 3.8
  BOTTOM w0.076: UC1.D8 172.23,87.86 v2(172.23,87.93)
  BOTTOM w0.089: UH1.B33 232.54,89 232.48,89.05 232.38,89.05 232.32,89 232.3,88.94 232.3,88.68 232.11,88.48 232.11,87.16 231.87,86.92 231.57,86.92 v2(231.4,86.75)
DMI_CRX_PTX_P1: length 6.3
  BOTTOM w0.076: UC1.E6 170.91,87.09 v2(170.91,87.14)
  BOTTOM w0.089: UH1.B32 231.88,88.97 231.88,89.1 231.78,89.19 231.67,89.19 231.62,89.14 231.62,88.82 231.34,88.54 231.34,88.34 231.4,88.28 231.49,88.28 231.58,88.19 231.58,88.05 231.49,87.96 231.4,87.96 231.34,87.89 231.34,87.8 230.82,87.28 230.82,87.08 230.94,86.95 230.94,86.75 230.82,86.62 230.82,85.32 230.91,85.23 230.94,85.23 231.17,85.46 231.18,85.46 231.33,85.61 231.33,85.67 v2(231.34,85.67)
DMI_CRX_PTX_P2: length 8.1
  BOTTOM w0.076: v2(172.25,86.35) 171.9,86.01 UC1.D5
  BOTTOM w0.089: UH1.B31 231.12,89.11 231.06,89.11 230.96,89.01 230.96,87.96 230.44,87.44 230.44,84.88 230.56,84.76 231.01,84.76 231.1,84.67 231.1,84.44 231.01,84.35 230.49,84.35 230.44,84.3 230.44,84.17 230.72,83.89 231.08,83.89 v2(231.34,84.15)
DMI_CRX_PTX_P3: length 8.6
  BOTTOM w0.076: v2(169.63,87.93) 169.46,87.76 UC1.J8
  BOTTOM w0.089: v2(231.59,81.88) 231.59,81.93 231.26,82.27 231.09,82.27 229.87,83.5 229.87,87.68 230.38,88.19 230.38,88.46 230.24,88.6 230.24,88.73 UH1.B29
DMI_CTX_PRX_N0: length 4.7
  BOTTOM w0.076: UC1.A8 173.75,87.53 173.68,87.6 173.68,87.76 173.77,87.85 174.01,87.85 174.09,87.93 174.19,87.93
  BOTTOM w0.094: v2(176.93,88.8) 176.61,88.48 176.61,88.47 176.36,88.22 174.55,88.22 174.26,87.93 174.19,87.93 ; v2(233.67,92.93) 233.59,92.85 233.2,92.85 UH1.K34
DMI_CTX_PRX_N1: length 5.6
  BOTTOM w0.076: UC1.B6 173.07,86.75 173.02,86.8 173.02,86.97 173.1,87.06 174.12,87.06 174.41,87.34 174.66,87.34 174.67,87.33 174.68,87.33 174.67,87.32 174.69,87.32
  BOTTOM w0.094: UH1.G33 232.65,91.51 v2(232.78,91.38) ; 174.69,87.32 175.57,87.32 175.93,86.97 176.62,86.97 v2(177.19,87.53)
DMI_CTX_PRX_N2: length 6.2
  BOTTOM w0.076: 176.08,86.29 175.78,86.29 175.76,86.31 174.85,86.31 174.84,86.3 173.61,86.3 173.51,86.21 173.51,86.01 173.6,85.92 173.79,85.92 UC1.A5
  BOTTOM w0.094: UH1.K32 231.9,92.78 232.16,92.78 v2(232.29,92.91) ; v2(178.17,86.44) 177.97,86.63 177.44,86.63 177.1,86.29 176.08,86.29
DMI_CTX_PRX_N3: length 7.6
  BOTTOM w0.076: UC1.B4 172.88,85.22 172.76,85.11 172.66,85.11 172.54,85.22 172.54,85.39 172.64,85.49 172.8,85.55 172.95,85.56 173.12,85.47 173.36,85.47 173.41,85.52 174.83,85.52 174.85,85.5 175,85.5
  BOTTOM w0.094: 175,85.5 177.46,85.5 177.86,85.1 178.49,85.1 v2(178.62,84.97) ; v2(231.41,91.48) UH1.G30
DMI_CTX_PRX_P0: length 4.6
  BOTTOM w0.076: 174.19,88.13 174.05,88.13 173.94,88.02 173.7,88.02 173.51,87.83 173.51,87.67 173.38,87.53 UC1.B8
  BOTTOM w0.094: v2(233.87,92.38) 233.68,92.19 UH1.J35 ; v2(176.3,88.8) 176.42,88.68 176.42,88.55 176.28,88.42 174.48,88.42 174.19,88.13
DMI_CTX_PRX_P1: length 5.6
  BOTTOM w0.076: 174.69,87.52 174.67,87.52 174.66,87.51 174.34,87.51 174.06,87.23 173.04,87.23 172.85,87.04 172.85,86.79 172.77,86.71 172.59,86.71 UC1.C6
  BOTTOM w0.094: v2(176.55,87.53) 176.66,87.43 176.66,87.28 176.54,87.16 176.01,87.16 175.65,87.52 174.69,87.52 ; v2(233.16,90.72) 233.03,90.85 UH1.F34
DMI_CTX_PRX_P2: length 6.2
  BOTTOM w0.076: 176.08,86.48 174.78,86.48 174.77,86.47 173.54,86.47 173.35,86.28 173.35,86.11 UC1.B5
  BOTTOM w0.094: v2(178.17,87.02) 177.98,86.83 177.36,86.83 177.01,86.48 176.08,86.48 ; UH1.J32 232.43,92.23 v2(232.6,92.06)
DMI_CTX_PRX_P3: length 7.6
  BOTTOM w0.076: UC1.D4 172.26,85.11 172.33,85.19 172.33,85.42 172.55,85.63 172.77,85.71 172.98,85.72 173.16,85.63 173.29,85.63 173.34,85.68 174.89,85.68 174.92,85.71 174.93,85.71
  BOTTOM w0.094: v2(178.62,85.56) 178.39,85.33 177.9,85.33 177.52,85.71 175.06,85.71 ; v2(231.6,90.75) UH1.F30
  BOTTOM w0.107: 174.93,85.71 175.06,85.71
DMIC0: length 12
  TOP w0.102: v2(279.36,56.73) 278.9,56.73 RA52.2 ; CA6.1 125.71,124.72 DA9.3 127.31,130.01 127.31,131.33 128.03,132.05 v2(128.03,132.42)
  TOP w0.109: v2(282.2,55.96) 282.35,55.8 UA1.2
  BOTTOM w0.102: JEDP1.7 127.76,131.84 128.03,132.1 v2(128.03,132.42)
DMIC_CLK0: length 12.9
  TOP w0.107: CA5.1 v1(128.54,125.54) 128.54,126.45 127.64,127.34 DA9.2 127.64,129.55 127.82,129.73 127.82,131.07 128.58,131.84 128.58,132.41 v2(128.61,132.41)
  TOP w0.109: v2(281.3,56.72) 280.2,56.72 RA14.1 CA54.1
  BOTTOM w0.107: v2(128.61,132.41) 128.58,132.41 128.76,132.23 JEDP1.9
DMIC_CLK_CODEC: length 2.9
  TOP w0.109: RA14.2 281.37,56.09 v1(281.69,55.77) 282.06,55.4 UA1.3
DPSNK0_DDC_CLK: length 3.4
  TOP w0.102: RT14.1 44.09,116.87 RT126.1 ; 45.52,115.2 45.55,115.22 v1(45.55,115.83) 44.89,116.49 44.89,116.53
  TOP w0.107: 45.52,115.2 v2(45.4,115.07) ; 44.89,116.53 RT14.1
  BOTTOM w0.076: v2(45.53,109.84) 45.53,109.84 45.86,110.17 UT1.Y5
DPSNK0_DDC_DATA: length 3.1
  TOP w0.102: RT15.1 42.7,112.1 RT127.1
  TOP w0.107: v2(42.94,110.5) 42.86,110.58 v1(42.86,111.07) 42.86,111.16 43.43,111.74 RT15.1
  BOTTOM w0.076: v2(42.94,110.5) 42.94,110.51 42.97,110.51 43.27,110.8 UT1.R4
DPSNK1_DDC_CLK: length 7.7
  TOP w0.102: RT336.1 47.45,110.26 v1(46.64,109.45) 46.01,108.82 45.45,108.82 44.9,108.28 44.64,108.28 v2(44.26,107.9)
  TOP w0.107: RT128.1 48.67,110.26 RT336.1
  BOTTOM w0.076: UT1.Y8 45.56,108.56 44.45,108.56 44.26,108.37 v2(44.26,107.9)
DPSNK_RBIAS: length 2.9
  TOP w0.102: v1(47.56,103.52) 46.87,104.2 RT38.1
  TOP w0.107: RT38.1 46.08,103.99 45.55,103.99 v2(45.53,103.98)
  BOTTOM w0.102: v2(45.53,103.98) 45.54,103.98 45.87,104.31 UT1.Y18
DRON_CPU: length 14.1
  TOP w0.102: v2(168.28,129.74) v1(168.79,129.74)
  BOTTOM w0.203: v2(107.64,102.41) 107.53,102.31 PUZ1.17
  BOTTOM w0.254: PR1620.1 PR1621.1 101.05,82.75 v2(106.1,82.75) ; PR1617.1 PR1616.1 156.05,129.19 v2(155.7,129.55) ; v2(168.28,129.74) PR1618.1 PR1619.1 ; PR1622.1 PR1623.1 193.18,118.11 v2(193.16,118.12) ; PR1627.1 PR1626.1 178.19,129.61 v2(178.28,129.53) ; v2(187.96,129.63) 187.82,129.77 PR1624.1 PR1625.1
EDP_AUXN: length 6
  BOTTOM w0.076: UC1.B26 173.09,101.82 172.98,101.82 172.84,101.68 172.84,101.46 172.93,101.36 174.04,101.36 174.49,100.91 175.42,100.91 175.5,100.99 175.5,101.14 175.18,101.46 v2(175.15,101.46)
  BOTTOM w0.094: v2(139.66,119.12) 139.89,119.35 139.89,120.31 139.89,120.31 139.89,120.33 CV1.1
EDP_AUXN_C: length 10.1
  BOTTOM w0.094: JEDP1.33 140.76,130.51 140.92,130.36 140.92,129.76 140.4,129.24 140.4,124.29 139.95,123.85 139.95,121.95 CV1.2
EDP_AUXP: length 6
  BOTTOM w0.076: UC1.C26 172.67,101.59 172.67,101.39 172.86,101.2 173.97,101.2 174.42,100.75 175.49,100.75 175.66,100.92 175.66,101.39 v2(175.73,101.46)
  BOTTOM w0.094: v2(140.24,119.12) 140.08,119.28 140.08,120.19 CV2.1
EDP_AUXP_C: length 10.2
  BOTTOM w0.094: JEDP1.34 141.26,130.55 141.11,130.39 141.11,129.68 140.58,129.16 140.58,124.22 140.14,123.77 140.14,121.94 CV2.2
EDP_COMP: length 8.2
  TOP w0.254: RC1.1 173.52,115.4 173.22,115.11 173.22,114.53 172.33,113.64 172.33,112.28 171.57,111.52 171.57,109.74 171.92,109.39 v2(171.98,109.39)
  BOTTOM w0.127: v2(171.98,109.39) 171.98,109.34 171.96,109.32 171.96,108.91 UC1.D37
EDP_HPD: length 5.2
  TOP w0.107: v2(137.26,132.13) 137.26,132.05 138.04,131.26 139.24,131.26 RV7.1
  TOP w0.109: v2(219.77,104.12) 219.03,104.12 RH1.2
  BOTTOM w0.089: v2(219.77,104.12) 219.52,103.87 UH1.AN6
  BOTTOM w0.102: v2(137.26,132.13) JEDP1.26
EDP_TXN0: length 2.2
  BOTTOM w0.076: v2(171.53,103.69) 171.53,103.79 UC1.E29
  BOTTOM w0.094: v2(142.5,119.14) 142.29,119.34 142.29,120.31 CV4.1
EDP_TXN0_C: length 10.5
  BOTTOM w0.094: CV4.2 142.24,121.94 142.24,123.46 141.24,124.45 141.24,128.69 142.11,129.55 142.11,130.37 142.26,130.53 JEDP1.36
EDP_TXN1: length 2.6
  BOTTOM w0.076: v2(171.59,102.84) 171.59,102.92 171.25,103.25 UC1.E28
  BOTTOM w0.094: v2(144.71,118.95) 144.58,118.95 144.33,119.2 v3(144.33,119.64) 144.33,120.38 CV6.1
EDP_TXN1_C: length 11.1
  BOTTOM w0.094: CV6.2 144.2,121.94 144.2,122.95 141.98,125.18 141.98,128.09 143.11,129.21 143.11,130.36 143.26,130.52 JEDP1.38
EDP_TXP0: length 2.3
  BOTTOM w0.076: UC1.D29 171.9,104.06 v2(172.27,103.69)
  BOTTOM w0.094: CV3.1 141.81,120.64 142.11,120.34 142.11,119.33 v2(141.92,119.14)
EDP_TXP0_C: length 10.5
  BOTTOM w0.094: JEDP1.35 141.76,130.53 141.92,130.37 141.92,129.63 141.06,128.76 141.06,124.38 142.05,123.39 142.05,121.87 CV3.2
EDP_TXP1: length 2.6
  BOTTOM w0.076: UC1.F28 170.69,103.28 170.88,103.09 170.88,102.9 v2(170.86,102.88)
  BOTTOM w0.094: CV5.1 144.11,120.23 144.11,119.25 v2(143.81,118.95)
EDP_TXP1_C: length 11.1
  BOTTOM w0.094: JEDP1.37 142.76,130.48 142.92,130.33 142.92,129.29 141.8,128.17 141.8,125.1 144.02,122.88 144.02,121.87 CV5.2
EN_1.2V_RUN: length 3.3
  BOTTOM w0.254: PC510.1 265.72,67.51 PR511.2 ; PC510.1 266.72,66.68 266.9,66.5 PU502.5 ; PC510.1 PR509.1
EN_1.05VALWP: length 4.6
  TOP w0.102: v1(194.08,90.09) PC2211.1
  TOP w0.254: PC2211.1 195.15,89.45 v2(195.12,89.42) 195.12,88.97 195.37,88.72 PR302.1 PR312.2
  BOTTOM w0.254: v2(195.12,89.42) PU301.11
EN_1.8VALW: length 1.4
  TOP w0.102: v1(225.23,74.18) 225.23,74.11 225.69,73.66 PR504.2
EN_1VS_VCCIO: length 4.5
  TOP w0.102: v2(198.95,95.9) v1(199.7,95.9)
  TOP w0.254: PC402.1 198.88,95.82 v2(198.95,95.9)
  BOTTOM w0.254: PR402.2 198.95,94.84 PR403.1 198.94,95.34 198.95,95.35 v2(198.95,95.9) 198.72,95.9 198.47,96.15 PU401.13
EN_2.5V_MEM: length 5.6
  TOP w0.102: PR514.1 151.05,34.09 151.52,33.61 152.78,33.61 v1(153.17,34.01)
  TOP w0.254: PR513.2 PC513.1 PR514.1 150.7,34.09 150.43,33.82 PU503.5
EN_CPU: length 4.3
  BOTTOM w0.102: PRZ28.1 98.45,99.73 98.09,100.09 96.67,100.09 v1(96.6,100.02)
  BOTTOM w0.203: PRZ28.1 99.13,99.62 99.42,99.91 PUZ1.43
EN_INVPWR: length 39.8
  TOP w0.102: 257.64,106.03 257.17,106.5 RE55.1 257.06,107.25 255.66,108.65 254.95,108.65 254.52,108.22 254.52,107.73 254.23,107.43 v1(251.39,107.43) 251.13,107.69 v2(248.63,107.69)
  TOP w0.107: QV2.2 124.65,133.18 v2(124.65,132.43)
  TOP w0.109: 257.64,106.03 258.44,105.24 258.44,103.87 258.96,103.35 258.96,102.87 259.07,102.76 259.51,102.76 260.92,101.36 260.92,100.81 261.21,100.52 261.68,100.52 UE1.B2
  BOTTOM w0.107: v2(138.36,126.91) 138.36,126.19 137.98,125.8 130.3,125.8 127.19,128.92 125.32,128.92 124.33,129.9 124.33,132.11 v2(124.65,132.43)
EN_LCDPWR: length 4.2
  TOP w0.102: DV3.1 149.38,135.01 UV24.4 149.28,136.08 RV3.2 150.05,136.34 v1(150.62,136.92)
EN_PD_HV_1: length 15.7
  TOP w0.254: v2(118.41,80.36) 118.41,80.2 118.11,79.89 PR834.1 ; v2(110.06,76.48) 109.7,76.48 109.51,76.68 108.68,76.68 108.4,76.95 108.4,77.49 108.71,77.8 PQ813.2 109.28,77.8 109.53,78.05 109.53,79.83 109.28,80.08 107.67,80.08 107.08,79.5 PR820.2 106.43,79 v1(105.79,79) 105.34,79 104.96,78.62 PR857.1 PR853.1 103.92,77.52 PR846.1
  BOTTOM w0.102: RT70.2 v2(57.09,104.84)
EN_PD_HV_1#: length 4
  TOP w0.102: 103.91,70.23 v1(103.91,69.57)
  TOP w0.254: PR810.2 105,70.17 104.78,69.95 104.19,69.95 103.91,70.23 PR851.2 103.91,70.71 103.42,71.2 PQ802.3 PQ802.2
EN_PD_HV_1_R: length 3.6
  BOTTOM w0.076: UT5.C2 62.21,105.84 61.99,105.63 61.61,105.63 61.59,105.61 61.43,105.61 60.8,104.98 59.94,104.98
  BOTTOM w0.102: 59.94,104.98 59.15,104.98 RT70.1
ENABLE_DS#: length 7.1
  TOP w0.102: v1(258.03,88.9) 258.03,89.51 RE550.1
  TOP w0.109: RE550.1 257.64,90.16 258.27,90.16 RE549.2 259.04,90.92 259.47,90.92 261.08,92.53 261.67,92.53 UE1.L2
ENLDO_3V5V: length 4.9
  BOTTOM w0.254: PU100.11 244.58,46.41 243.9,45.72 243.9,45.48 243.39,44.97 PR103.1 243.39,44.03 PR102.1 243.39,44 243.39,43.42 v2(243.55,43.25) ; PU102.11 198.31,38.17 198.05,38.43 197.94,38.43 v2(197.83,38.55)
ENVDD_PCH: length 2.7
  TOP w0.102: v2(153.28,134.88) 153.28,135.33 152.95,135.66 ; 152.95,135.66 DV3.3 ; 152.95,135.66 v1(153.92,135.66)
  BOTTOM w0.089: UH1.AV44 237.76,107.25 v2(237.74,107.27)
ESPI_ALERT#: length 4.5
  TOP w0.109: v2(265.75,96.54) 265.75,96.54 265.75,95.76 266.07,95.44 UE1.H7 ; v2(233.81,107.27) 233.91,107.37 233.91,108.08 234.87,109.57 RH340.1
  BOTTOM w0.089: UH1.AW35 233.63,107.09 v2(233.81,107.27)
ESPI_CLK: length 1.2
  BOTTOM w0.089: UH1.BB36 v2(234.63,108.44)
  BOTTOM w0.102: RH97.1 v2(247.96,83.69)
ESPI_CLK_5105: length 19.6
  TOP w0.102: RE350.1 278.9,95.81 278.71,96 v2(278.57,96)
  TOP w0.109: v2(266.49,94.95) 266.47,94.97 266.47,95.73 UE1.G7
  BOTTOM w0.102: v2(278.57,96) 278.57,95.98 278.11,95.52 v1(272.6,95.52) 268.77,95.52 268.47,95.22 268.47,94.81 268.21,94.55 266.59,94.55 266.47,94.66 266.47,94.93 v2(266.49,94.95) ; v2(247.85,81.24) 247.85,81.99 RH97.2 CC316.1 248.85,81.95 248.25,81.35 JESPI.10
ESPI_CS#: length 8.3
  TOP w0.109: v2(264.9,94.99) 264.9,94.99 264.94,94.99 UE1.H6
  BOTTOM w0.089: UH1.BE38 234.98,110.17 234.98,110.55 234.98,111.73 235,111.76 235,114.38 234.63,114.75 234.63,115.87 234.52,115.97 v2(234.52,116.12)
  BOTTOM w0.102: v2(249.3,81.17) 249.75,80.71 JESPI.7
ESPI_IO0: length 4
  TOP w0.109: UE1.K5 v2(264.07,93.33)
  BOTTOM w0.102: v1(253.14,81.8) 253.04,81.8 252.74,82.1 RC366.2 251.96,81.85 251.96,81.38 252.03,81.31 252.03,81.17 v2(252.03,81.17) 252.03,81.14 251.75,80.86 JESPI.3
ESPI_IO0_R: length 5.6
  BOTTOM w0.089: UH1.BB39 235.74,108.44 v2(235.82,108.51)
  BOTTOM w0.102: v2(248.43,85.86) 248.61,86.05 249.18,86.05 252.2,83.02 RC366.1
ESPI_IO1: length 2.9
  TOP w0.109: v2(263.27,92.53) 263.28,92.54 263.29,92.54 UE1.L4
  BOTTOM w0.102: RC367.2 251.54,81.96 v2(251.54,81.48) 251.25,81.2 JESPI.4
ESPI_IO1_R: length 5.6
  BOTTOM w0.089: UH1.AW37 234.88,107.13 235.04,107.3 v2(235.11,107.3)
  BOTTOM w0.102: v2(247.37,84.69) 247.42,84.64 247.84,84.64 248.11,84.91 248.96,84.91 250.35,83.51 250.86,83.51 251.35,83.02 RC367.1
ESPI_IO2: length 2.8
  TOP w0.109: UE1.G6 v2(264.87,96.53)
  BOTTOM w0.102: RC368.2 250.57,81.37 250.51,81.32 v2(250.51,81.24) 250.57,81.24 250.67,81.13 250.67,81.01 250.75,80.92 JESPI.5
ESPI_IO2_R: length 4.3
  BOTTOM w0.089: UH1.AV37 234.7,106.4 v2(234.77,106.33)
  BOTTOM w0.102: v2(247.76,84.23) 248.2,84.68 248.87,84.68 250.53,83.02 RC368.1
ESPI_IO3: length 2.9
  TOP w0.109: UE1.L5 v2(264.07,92.53)
  BOTTOM w0.102: RC369.2 249.74,81.35 v2(249.93,81.16) 250.25,80.84 JESPI.6
ESPI_IO3_R: length 2.2
  BOTTOM w0.089: v2(235.44,107.78) 235.44,107.78 UH1.BA38
  BOTTOM w0.102: RC369.1 249.74,83.08 248.57,84.25 v2(248.57,84.27)
ESPI_RESET#: length 10.3
  TOP w0.109: v2(234.25,114.12) 234.16,114.21 RH633.1 234.16,115.22 CH348.1 234.63,115.15 234.63,114.37 235.07,113.93 v1(235.07,113.87) RH95.1 ; v2(264.92,93.32) 264.92,93.38 UE1.K6
  BOTTOM w0.089: UH1.BF38 234.73,110.77 234.79,110.82 234.79,111.81 234.81,111.84 234.81,113.87 234.57,114.12 v2(234.25,114.12)
  BOTTOM w0.102: JESPI.8 249.25,80.38 248.85,80.78 248.85,81.1 v2(248.72,81.24)
FB_1.05VALWP: length 3.4
  BOTTOM w0.254: PU301.14 196.47,89.21 196.53,89.27 196.53,89.67 196.27,89.93 PR311.1 197.01,90.24 PR308.2 PR306.2
FB_1.8VALW:
  vias: v1(232.79,72.97)
FB_2PH_CPU: length 8.1
  TOP w0.254: PRZ46.2 99.36,97.74 PCZ19.2 PRZ47.1 98.64,96.86 PCZ21.1 100.82,96.86 v1(101.18,96.5) 101.53,96.15 102.62,96.15 102.94,96.48 v2(102.94,96.89)
  BOTTOM w0.203: PUZ1.34 103.13,97.08 v2(102.94,96.89)
FB_3V: length 1.8
  BOTTOM w0.254: PU100.13 244.27,47.31 243.96,47 243.58,47 PC113.1
FB_4PH_CPU: length 6.6
  TOP w0.102: v2(102.75,105.59) 103.75,104.59 v1(103.75,104.59)
  TOP w0.254: v2(102.75,105.59) 102.96,105.79 PRZ45.1 ; PRZ45.1 PCZ17.2 103.83,106.74 PCZ20.2 ; PRZ45.1 102.94,106.68 PRZ40.1
  BOTTOM w0.203: PUZ1.5 102.73,105.57 v2(102.75,105.59)
FB_5V: length 1.4
  BOTTOM w0.254: PC127.1 199,38.81 199.21,38.6 PU102.13
FB_DDR: length 4.8
  BOTTOM w0.102: v1(178.62,40.71) 178.37,40.46 178.37,40.28 177.54,39.46 PR206.1
  BOTTOM w0.254: PU200.16 175.71,38.45 175.89,38.63 PC208.2 PR204.2 PR206.1
FBS_1VS_VCCIO: length 4.7
  BOTTOM w0.102: v1(194.24,102.12) 194.76,101.6 PR421.2
  BOTTOM w0.254: PR421.2 195.18,101.59 PR422.1 195.18,100.35 195.51,100.02 196.65,100.02 196.97,99.71 PU401.5
FFS_INT2: length 13.2
  TOP w0.109: LGA1.11 254.3,42.12 254.38,42.05 v2(254.46,42.05)
  BOTTOM w0.089: 222.15,117.28 221.88,117.02 221.88,111.88 222.69,111.07 222.69,110.75 222.56,110.63 222.56,109.99 222.73,109.83 UH1.BE14
  BOTTOM w0.102: 222.15,117.28 v1(222.35,117.49) 222.35,117.49 ; QN1.2 254.28,42.14 254.38,42.05 v2(254.46,42.05) ; RH378.2 v2(222.86,120.03)
  BOTTOM w0.109: v2(222.86,120.03) 222.35,119.52 222.35,117.49
FFS_INT2_Q: length 4.6
  BOTTOM w0.102: v1(255.03,41.49) 254.88,41.64 253.95,41.64 QN1.3
  BOTTOM w0.109: JSATA1.19 253.04,39.52 253.43,39.9 RN1.2 253.43,41.13 QN1.3
FIVR_EN: length 4.3
  TOP w0.102: v1(78.85,136.58) 78.09,135.81 78.09,135.06 77.53,134.5 RC217.1 RC219.2 76.13,134.39 RC218.2
FIVR_EN_R: length 7.9
  TOP w0.102: v2(81.47,136.57) 81.47,134.36 v1(81,133.89) 80.26,133.16 RC126.2 RC132.2 78.42,133.47 RC217.2
  BOTTOM w0.107: JXDP1.45 89.41,135.23 89.31,135.34 v2(89.19,135.34)
FPR_DET#: length 37.9
  TOP w0.102: v2(275.59,99.26) 275.59,100.21 276.21,100.84 RE606.1 ; v2(301.81,115.64) 301.81,115.73 301.71,115.83 301.37,115.83 301.27,115.74 DT41.1 DT41.9 301.27,113.97 301.95,113.3 v4(302.06,113.3) 306.63,113.3 307.64,114.31 v2(307.64,115.64)
  TOP w0.109: v2(268.15,98.91) 268.17,98.91 268.17,98.89 268.04,98.89 UE1.D9
  BOTTOM w0.102: v2(275.59,99.26) 276.54,99.26 277.49,100.21 278.7,100.21 279.24,99.67 283.56,99.67 285.23,97.99 286.89,97.99 287.14,97.74 287.14,96.37 v2(287.23,96.28) ; JFPBTN1.1 307.11,116.35 306.97,116.21 306.97,115.99 307.32,115.64 v2(307.64,115.64)
  BOTTOM w0.109: v2(268.15,98.91) 268.17,98.91 268.17,99.02 268.41,99.27 269.1,99.27 269.23,99.14 270.81,99.14 271.34,99.66 271.95,99.66 272.18,99.42 275.42,99.42 v2(275.59,99.26)
FPR_LOW_PWR_MODE#: length 41.4
  TOP w0.102: v2(298.19,116.22) 298.45,115.96 299.39,115.96 299.77,115.58 DT41.4 DT41.7 299.77,114.11 299.22,113.56 298.41,113.56 297.32,114.65 v4(297.32,115.14) v2(297.32,116)
  TOP w0.109: UE1.K12 270.46,93.35 270.46,92.78 270.78,92.45 271.31,92.45 v2(271.52,92.24) 271.72,92.24 271.73,92.25 RE708.1
  BOTTOM w0.102: JFPBTN1.11 307.14,118.85 306.93,118.63 306.93,116.95 305.18,115.2 299.21,115.2 v2(298.19,116.22) ; v2(285.98,96.16) 285.62,95.81 284.95,95.81 284.72,96.04 282.9,96.04 282.32,95.45 280.68,95.45 278.11,92.88 277.77,92.88 277.68,92.97 272.49,92.97 271.76,92.24 v2(271.52,92.24)
FPR_PWR_EN#: length 17.9
  TOP w0.102: v1(280.35,124.11) RZ580.2 280.53,123.09 v2(281.01,122.6) ; RE704.1 272.45,88.97
  TOP w0.109: UE1.M11 269.67,91.73 269.67,90.82 270.58,89.91 v2(271.5,89.91) 272.45,88.97
  BOTTOM w0.102: v2(280.72,91.17) 280.72,91.12 280.22,90.62 277.96,90.62 276.33,89 275.11,89 274.25,89.86 273.1,89.86 272.79,89.55 271.75,89.55 271.5,89.79 v2(271.5,89.91)
FPR_PWR_EN#_R: length 4.8
  TOP w0.102: QZ38.2 281.9,120.93 CZ500.1 RZ580.1 280.09,122.17 279.14,123.12 v1(279.14,123.45)
FPR_RST#: length 38.8
  TOP w0.102: RZ1392.1 287.07,122.43 287.1,122.46 v2(287.25,122.46) ; RZ1411.1 238.63,39.06 238.76,38.94 v2(238.76,38.82) ; v2(298.13,115.63) 298.21,115.71 299.09,115.71 299.27,115.53 DT41.5 DT41.6 299.27,114.04 299.07,113.84 298.56,113.84 297.72,114.68 297.72,116.2 296.86,117.07 v4(296.86,117.36) v2(296.86,118.18)
  BOTTOM w0.102: v2(238.76,38.82) 240.6,38.82 240.71,38.72 240.71,32.92 239.8,32.01 239.43,32.01 v2(239.19,32.26) ; v2(298.13,115.63) 298.13,115.01 298.92,114.22 308.59,114.22 312.1,117.73 312.1,118.62 312.33,118.85 JFPBTN1.12
FPR_RST#_USH: length 5.3
  TOP w0.102: RZ1411.2 238.06,40.91 237.37,40.91 v2(237.36,40.92)
  BOTTOM w0.102: JUSH1.25 236.28,39.25 236.53,39 237.04,39 237.61,39.57 v1(237.61,39.89) 237.61,40.67 v2(237.36,40.92)
FPR_SCAN_INT#: length 20.2
  TOP w0.102: RE826.2 266.97,86.04 267.51,86.58 QE20.3 268.05,87.05 RE825.1 268.51,86.21 268.31,86 267.93,86 v2(267.89,85.96) ; v2(306.81,119.85) 306.99,119.85 v4(307.75,119.09) 307.75,117.04 306.36,115.64 306.36,114.53 305.67,113.84 303.33,113.84 303.22,113.96 DT42.7 DT42.4 303.22,115.58 305.56,117.93 v2(306.32,117.93)
  BOTTOM w0.102: v2(306.81,119.85) JFPBTN1.15
FPR_SCAN_INT#_EC: length 8.6
  TOP w0.102: RZ114.1 225.8,40.57 v2(225.48,40.89) 225.48,41.34 v1(225.37,41.45) ; UE1.L8 266.85,92.93 266.4,92.48 266.4,89.95 v2(266.29,89.84) 266.29,89.52 QE20.1 267.79,88.95 RE827.2 268.49,87.53 RE825.2
FPR_SCAN_INT#_EC_R: length 3.6
  TOP w0.102: v2(226.56,38.11) 226.3,38.11 v1(226.03,38.38) 225.8,38.61 RZ114.2
  BOTTOM w0.109: v2(226.56,38.11) 226.89,38.44 226.89,39.05 226.78,39.17 JUSH1.6
FPR_SSO_EN#: length 39.2
  TOP w0.102: v2(286.32,97.52) 287.5,97.52 v4(287.71,97.74) ; RE706.1 v2(278.57,96.72) ; v2(307.02,114.65) 305.98,113.61 302.98,113.61 302.72,113.88 DT42.6 DT42.5 302.72,115.74 v2(302.95,115.97)
  TOP w0.109: v2(268.09,94.97) 268.03,94.97 UE1.H9
  BOTTOM w0.102: JFPBTN1.16 312.18,119.85 311.11,118.78 311.11,117.17 308.59,114.65 v2(307.02,114.65) ; v2(268.09,94.97) 268.08,94.98 268.08,95.12 268.97,96 277.22,96 277.83,96.62 278.47,96.62 v2(278.57,96.72) 280.03,96.72 280.55,97.24 281.68,97.24 282.41,97.97 284.37,97.97 284.73,97.61 286.23,97.61 v2(286.32,97.52)
FPR_UEFI_MGMT#: length 36.9
  TOP w0.102: v2(306.45,118.84) 307.35,117.95 307.35,117.07 305.49,115.21 305.49,114.2 305.39,114.09 304.82,114.09 304.72,114.2 DT42.9 DT42.1 304.72,115.68 304.88,115.85 305.57,115.85 306.5,116.77 v2(306.5,117.22) ; v4(279.65,91.17) 279.26,91.56 RE707.1 278.89,92.28 278.57,92.59 278.57,93.92 277.94,94.55 v2(277.94,94.65)
  TOP w0.109: UE1.K9 268.03,93.37 268.12,93.37 v2(268.12,93.37)
  BOTTOM w0.102: v2(306.45,118.84) 306.96,119.35 JFPBTN1.13 ; v2(285.33,96.84) 285.28,96.79 284.35,96.79 283.83,96.26 282.77,96.26 282.62,96.42 280.15,96.42 278.72,94.98 278.04,94.98 277.94,94.88 v2(277.94,94.65) 277.91,94.69 275.59,94.69 275.55,94.65 275.22,94.65 275.18,94.69 269.88,94.69 269.76,94.57 268.54,94.57 268.44,94.47 268.44,93.58 268.24,93.37 268.12,93.37 v2(268.12,93.37)
GPP_B23: length 7
  TOP w0.109: v2(232.85,114.86) 232.85,115.04 232.53,115.35 RH329.1
  BOTTOM w0.089: UH1.BD33 232.11,109.83 232.11,113.3 232.85,114.03 v1(232.85,114.25) v2(232.85,114.86)
GPP_C5: length 6.8
  TOP w0.109: v2(227.44,115.58) 228.41,115.58 RH78.2
  BOTTOM w0.089: v2(227.44,115.58) 227.44,114.75 v1(227.51,114.68) 228.11,114.08 228.11,111.88 228.03,111.8 228.03,110.46 227.94,110.37 UH1.BF24
GPP_H12: length 9.4
  TOP w0.102: RH615.2 243.85,97.17 244.32,97.64 v1(245.69,97.64)
  TOP w0.109: RH615.2 242.12,97.17 241.68,96.72 v2(241.68,96.13)
  BOTTOM w0.089: UH1.AB47 239.16,98.45 239.46,98.15 239.84,98.15 240.03,98.34 240.81,98.34 241.68,97.47 v2(241.68,96.13)
GPP_H15: length 5.1
  BOTTOM w0.089: RH601.2 242.64,96.89 v1(242.35,97.18) 242.25,97.18 240.56,98.87 239.42,98.87 239.35,98.95 UH1.AC47
GPP_J1: length 4.5
  TOP w0.109: RH616.2 214.45,107.5 214.88,107.07 v1(215.39,107.07) v2(216.09,107.07)
  BOTTOM w0.089: v2(216.09,107.07) 216.09,107.07 216.34,107.32 216.35,107.32 216.36,107.33 216.89,107.33 217.09,107.13 217.56,107.13 217.78,107.35 UH1.AY3
GPPJ_RCOMP: length 7.8
  TOP w0.305: RH609.2 214.18,115.12 214.18,114.88 214.75,114.31 v2(214.75,114.12)
  BOTTOM w0.089: v2(214.75,114.12) v1(214.75,114.63)
  BOTTOM w0.254: UH1.BE1 216.62,110.1 216.24,110.48 216.24,111.28 215.01,112.51 215.01,113.87 v2(214.75,114.12) ; UH1.BE1 UH1.BD1 ; UH1.BE1 216.83,110.1 UH1.BE2
GPS_DISABLE#: length 15.5
  TOP w0.102: RZ87.2 262.84,76.32 DZ6.1
  TOP w0.109: v2(264.53,76.32) DZ6.1 ; UE1.H5 264.09,94.94 v2(264.05,94.94)
  BOTTOM w0.102: RE12.1 255.88,93.05 258.37,93.05 v1(258.72,92.69) 259.71,91.7 263.39,91.7 263.69,92 263.69,94.55 264.05,94.9 v2(264.05,94.94)
GPU_PWR_LEVEL: length 4.1
  TOP w0.109: RE5.1 273.6,97.99 272.57,97.99 v1(272.52,98.03) 272.5,98.05 270.4,98.05 UE1.E12
GPU_SMCLK: length 9.1
  TOP w0.102: RE524.1 255.53,112.73 255.53,113.1 255.39,113.23 v2(255.27,113.23)
  TOP w0.109: UE1.F7 266.47,97.33 266.47,98.83 266.5,98.86 v2(266.5,98.93)
  BOTTOM w0.109: v2(266.52,104.47) 266.52,104.47 266.52,103.88 267.06,103.35 267.06,102.26 266.62,101.83 266.62,101.27 266.58,101.23 v1(266.58,100.91) 266.58,99.01 v2(266.5,98.93)
GPU_SMDAT: length 8.7
  TOP w0.109: UE1.B6 264.87,100.53 264.87,101.14 264.74,101.27 264.74,101.71 265.44,102.41 265.44,106.38 v1(265.09,106.73) 264.35,107.47 RE525.1
H_CATERR#: length 11.6
  BOTTOM w0.076: 131.82,104.47 132.25,104.47 132.37,104.59 132.75,104.59 133.01,104.34 135.53,104.34 UC1.BM30
  BOTTOM w0.109: RC79.2 126.42,101.04 128.96,101.04 130.87,102.94 130.87,103.52 v1(131.12,103.77) 131.82,104.47
H_PECI: length 90.8
  TOP w0.102: 223.7,71.79 223.7,71.79 223.7,71.79 ; 223.7,71.79 224.91,71.79 v2(225.32,71.38) ; 223.7,71.79 223.24,71.79 v1(219.58,75.45) 216.29,78.74 216.29,80.02 216.29,80.02 216.29,80.48 214.77,82 210.01,82 208.39,83.62 208.39,84.74 209,85.35 209,91.3 206.43,93.86 203.96,93.86 203.96,93.9 v2(203.92,93.9) ; v2(132.66,106.77) 132.31,106.77 132.23,106.69 132.13,106.69 130.04,104.59 127.65,104.59 127.26,104.21 123.4,104.21 122.5,103.31 122.46,103.31 v2(122.14,102.99)
  TOP w0.109: RE60.2 274.86,95.06 v2(275.39,95.06)
  BOTTOM w0.076: UC1.BT34 132.8,106.91 v2(132.66,106.77)
  BOTTOM w0.102: v2(225.32,71.38) 226.69,72.76 236.73,72.76 240.11,69.37 247.09,69.37 247.52,69.8 247.52,73.53 248.49,74.5 248.72,74.5 v2(249.15,74.94)
  BOTTOM w0.109: v2(203.92,93.9) 203.96,93.86 204.47,93.86 204.91,94.31 204.91,95.83 204.47,96.28 204.47,96.48 204.46,96.49 204.46,96.83 204.47,96.84 204.47,99.22 206.59,101.34 RH73.2
H_PM_DOWN: length 22.9
  TOP w0.102: v2(126.49,105.93) 123.55,105.93 122.1,104.47 121.78,104.47 121.57,104.26 v2(121.39,104.26)
  BOTTOM w0.089: 210.08,100.33 210.84,100.33 211.41,99.76 212.72,99.76 213.08,100.13 217.23,100.13 217.27,100.17 UH1.AE2
  BOTTOM w0.102: 210.08,100.33 209.86,100.33
  BOTTOM w0.109: RC168.1 127.4,104.53 v1(126.69,105.24) 126.49,105.44 v2(126.49,105.93) ; 209.86,100.33 206.96,100.33 206.69,100.06 206.69,98.63 205.35,97.29 v2(204.91,97.29)
H_PM_DOWN_R: length 6.5
  BOTTOM w0.076: UC1.BP31 134.18,105.76 133.72,105.76 133.63,105.67 131.24,105.67
  BOTTOM w0.109: 131.24,105.67 130.39,104.81 v1(129.98,104.81) 129.55,104.81 129.27,104.53 RC168.2
H_PM_SYNC: length 23.7
  TOP w0.102: v2(135.5,107.38) 135.05,107.83 134.49,107.83 133.6,108.72 132.84,108.72 132.26,109.3 124.17,109.3 121.87,107.01 121.68,107.01 121.1,106.43 120.51,106.43 120.07,105.99 v2(120.07,105.74)
  BOTTOM w0.076: UC1.BM34 135.83,107.06 v2(135.5,107.38)
  BOTTOM w0.109: v2(204.91,97.91) 205.39,97.91 v1(205.92,98.44) 206.27,98.8 206.27,100.23 206.82,100.78 207.94,100.78 RH156.2
H_PM_SYNC_R: length 9.1
  BOTTOM w0.089: 210.21,100.59 210.28,100.52 211.08,100.52 211.13,100.48 v1(211.93,100.48) 211.98,100.52 212.85,100.52 212.86,100.51 217.05,100.51 217.14,100.6 217.55,100.6 UH1.AF3
  BOTTOM w0.109: 210.21,100.59 210.11,100.69 209.33,100.69 RH156.1
H_PROCHOT#_R: length 7.6
  BOTTOM w0.076: 130.55,103.71 131.57,104.72 132.06,104.72 132.27,104.93 133.57,104.93 UC1.BR30
  BOTTOM w0.109: 130.55,103.71 130.55,103.21 v1(130.16,102.82) 128.95,101.61 RC84.2
H_PWRGD: length 30.3
  TOP w0.102: v2(201.7,101.75) 202.56,101.75 202.86,102.05 204.15,102.05 206.71,99.49 v1(208.47,99.49) 210.46,99.49 210.53,99.43 211.87,99.43 212.54,100.1 v2(212.54,100.14) ; v2(123.42,103.25) 123.77,103.25 123.85,103.17 124.87,103.17 124.93,103.11 126.95,103.11 127.83,103.99 v2(129.3,103.99)
  TOP w0.109: v2(212.54,100.14) 212.38,100.3 212.38,100.4 CH551.1
  BOTTOM w0.089: v2(212.54,100.14) 212.56,100.14 212.74,100.32 217.14,100.32 217.23,100.41 217.56,100.41 217.63,100.33 UH1.AE3
  BOTTOM w0.102: UC1.BT31 131.35,105.39 130.44,104.48 129.8,104.48 v2(129.3,103.99) 129.17,103.85 CC300.1
H_SKTOCC#: length 5.6
  BOTTOM w0.076: UC1.BR33 133.51,105.83 131.36,105.83 131.33,105.87 131.06,105.87
  BOTTOM w0.109: RC319.2 130.23,105.29 130.81,105.87 v1(130.93,105.87) 131.06,105.87
H_THERMTRIP#: length 146.3
  TOP w0.102: CC323.1 175.22,115.4 175.28,115.34 RC169.1 176.33,115.34 ; v2(176.14,112.15) 176.33,112.34 176.33,115.34 ; v2(204.87,96.66) 204.87,96.22 209.56,91.53 209.56,85.11 208.95,84.51 208.95,83.85 210.24,82.56 213.18,82.56 213.85,83.23 214.33,83.23 216.85,80.72 216.85,80.15 218.69,78.31 218.69,77.61 v1(219.13,77.16) 223.95,72.35 225.15,72.35 226.44,71.06 226.44,69.91 v2(227.58,68.77) ; QE4.3 282.19,91.88 281.75,91.44 281.74,91.44 281.55,91.26 281.55,91.12 v2(281.39,90.95) ; 176.33,115.34 RC80.2
  TOP w0.109: RD27.2 201.23,41.92 v2(201.23,41.54) ; RD14.2 125.7,45.23 v2(125.7,44.61)
  BOTTOM w0.102: v2(227.58,68.77) 227.66,68.84 236.24,68.84 239.04,66.04 248.38,66.04 248.52,66.18 248.54,66.18 253.02,70.66 257.4,70.66 257.6,70.86 266.67,70.86 268.13,72.32 271.02,72.32 271.16,72.19 271.63,72.19 272.96,73.52 275.18,73.52 275.33,73.37 275.33,72.26 275.78,71.82 277.77,71.82 v2(278.06,71.53) ; v2(201.02,106.88) 201.23,106.67 201.23,105.67 200.46,104.91 197.22,104.91 196.5,105.64 181.96,105.64 179.51,108.09 179.51,112.85 178.65,113.71 176.11,113.71 175.95,113.56 175.95,112.34 v2(176.14,112.15)
  BOTTOM w0.109: v2(204.87,96.66) 205.31,96.66 207.18,98.54 RH75.2
H_THERMTRIP#_R: length 13.2
  TOP w0.109: RC169.2 175.83,113.99 175.73,113.9 v1(175.73,113) 175.73,112.09 173.19,109.55 173.19,108.48 173.12,108.41 173.12,107.57 172.62,107.07 171.36,107.07 169.96,105.66 169.3,105.66 v2(169.29,105.67)
  BOTTOM w0.076: UC1.J31 168.89,105.29 169.27,105.67 v2(169.29,105.67)
H_VCCST_PWRGD_XDP: length 3.6
  TOP w0.107: RC124.2 85.11,134.39 CC307.1 86.05,134.39 v2(87.02,135.35)
  BOTTOM w0.107: v2(87.02,135.35) 87.02,135.3 87.61,134.71 JXDP1.39
HDA_BIT_CLK: length 15.9
  TOP w0.109: RH46.2 CA75.1 218.49,121.14 RH637.2 218.52,121.06 218.99,120.6 v2(219.45,120.6)
  BOTTOM w0.089: UH1.BD11 221.94,109.38 221.94,109.86 221.93,109.9 221.93,110.12 221.3,110.75 221.3,112.68 221.17,112.82 221.17,116.08 220.81,116.44 219.8,116.44
  BOTTOM w0.109: 219.8,116.44 219.54,116.7 219.54,120.51 v2(219.45,120.6)
HDA_BIT_CLK_R: length 11.2
  TOP w0.109: RA17.1 280.7,55.14 v2(281.08,54.76) 282.57,54.76 282.73,54.6 UA1.5 ; v2(220.01,123.63) 219.41,123.63 CH268.2 RH46.1
  BOTTOM w0.102: v2(220.71,130.19) 220.71,129.52 220.4,129.21 220.4,124.02 v2(220.01,123.63)
HDA_RST#: length 19.4
  TOP w0.102: v2(216.8,125.57) 217.02,125.79 RH50.2 217.65,125.75 RH636.2
  BOTTOM w0.089: UH1.BE10 220.91,109.97 220.91,112.53 219.33,114.11 219.33,115.94 218.65,116.62 218.65,117.28
  BOTTOM w0.102: v2(216.8,125.57) 216.8,125.27 218.41,123.66 218.41,120.12 218.65,119.89 218.65,117.28
HDA_RST#_R: length 4.6
  TOP w0.102: v2(276.87,57.1) 276.87,57.21 276.98,57.33 RA50.1 ; RH50.1 217.61,129.04 217.04,129.61 v2(217.04,130.12)
HDA_SDIN0: length 23.5
  TOP w0.102: CA73.1 218.58,120.09 v2(219.07,120.09) ; RA9.1 v2(278.95,52.98)
  BOTTOM w0.089: UH1.BE11 221.53,109.76 221.31,109.97 221.25,109.97 221.11,110.11 221.11,112.61 219.52,114.19 219.52,116.02 219.06,116.48 219.06,117.28
  BOTTOM w0.102: v2(219.45,130.13) 218.94,129.62 218.94,123.96 218.64,123.66 218.64,120.52 v2(219.07,120.09) 219.06,120.07 219.06,117.28
HDA_SDIN0_R: length 2.9
  TOP w0.102: UA1.7 281.69,53.8 281.38,53.49 v2(281,53.49) RA9.2
HDA_SDOUT: length 17.8
  TOP w0.102: RH45.2 219.39,125.88 RH328.2 CA76.1 v2(219.4,124.39)
  BOTTOM w0.102: UH1.BF12 221.91,110.46 221.5,110.87 221.5,116.7 220.7,117.5 220.7,119.82 220.98,120.09 220.98,121.11 220.99,121.13 220.99,121.41 219.4,123 v2(219.4,124.39)
HDA_SDOUT_R: length 4.7
  TOP w0.102: v2(281.43,55.27) 281.69,55 UA1.4 ; RH45.1 219.65,127.59 220.07,128.01 v1(220.07,128.98) v2(220.07,130.09)
HDA_SYNC: length 12.9
  TOP w0.102: RH48.2 CA74.1 221.24,121.66 221.4,121.51 v2(221.4,121.21)
  BOTTOM w0.089: 221.24,117.28 221.69,116.83 221.69,111.18 221.92,110.96 UH1.BG13
  BOTTOM w0.102: 221.24,117.28 220.93,117.59 220.93,119.72 221.2,119.99 221.2,121.02 v2(221.4,121.21)
HDA_SYNC_R: length 9.1
  TOP w0.102: UA1.9 282.67,53 282.38,52.72 v2(282.38,52.16) ; v2(220.88,123.64) 220.89,123.64 220.89,123.32 RH48.1
  BOTTOM w0.102: v2(220.88,123.64) 220.88,129.01 221.29,129.42 v2(221.29,130.12)
HDD_A_EQ: length 2.5
  TOP w0.109: RN10.1 RN11.2 243.32,38.8 243.19,38.67 UN7.17
HDD_A_EQ2: length 2.5
  TOP w0.109: RN20.2 RN21.1 242.56,38.77 242.69,38.65 UN7.18
HDD_A_PRE: length 2.6
  TOP w0.109: RN7.2 RN6.2 243.45,32.39 v2(243.27,32.57) 243.19,32.65 UN7.9
HDD_B_EQ: length 5.1
  TOP w0.102: v1(239.25,38.25) 239.73,38.73 239.73,38.91 240.28,39.45 RN13.2
  TOP w0.109: RN13.2 RN12.2 241.23,39.27 241.23,38.87 241.45,38.65 241.86,38.65 242.19,38.32 UN7.19
HDD_B_EQ2: length 7.5
  TOP w0.102: v2(247.84,33.16) 247.96,33.16 248.23,32.89 v1(248.23,32.31)
  TOP w0.109: UN7.13 244.67,35.53 245.21,35.53 v2(245.61,35.13) ; v2(247.84,33.16) 247.44,32.76 RN19.1 RN18.2
  BOTTOM w0.109: v2(245.61,35.13) 245.61,34.05 246.5,33.16 v2(247.84,33.16)
HDD_B_PRE: length 2.5
  TOP w0.109: UN7.8 RN8.1 RN9.2
HDD_DET#: length 12.3
  TOP w0.102: v2(251.2,33.98) 251.85,33.34 QN6.2
  TOP w0.109: RH324.2 244.78,102.12 v2(244.28,102.12)
  BOTTOM w0.089: v2(244.28,102.12) 242.39,102.12 242.22,101.95 240.38,101.95 239.74,102.6 239.72,102.6 239.72,102.61 239.11,102.61 UH1.AK47
  BOTTOM w0.102: JSATA1.13 250.04,37.81 250.88,36.97 250.88,34.3 v2(251.2,33.98)
HDD_DEVSLP: length 4
  TOP w0.102: RN3.2 248.14,40.03 v2(247.94,40.23)
  BOTTOM w0.089: v2(236.04,102.18) 236.04,102.13 235.65,101.74 UH1.AH40
  BOTTOM w0.102: JSATA1.11 249.04,39.12 v1(248.38,39.79) v2(247.94,40.23)
HDD_EN: length 50.5
  TOP w0.109: RN5.1 253.75,31.8 UZ23.3 ; RN5.1 252.96,31.8 v2(252.77,32) ; RN5.1 RN4.2
  BOTTOM w0.102: v2(252.77,32) 252.77,32.48 252.22,33.03 250.25,33.03 249.68,32.46 244.15,32.46 243.52,33.09 242.12,33.09 241.3,33.92 241.3,41.22 241.93,41.86 241.93,42.43 241.59,42.77 238.44,42.77 237.96,43.25 237.96,54.38 240.15,56.58 240.15,58.03 238.94,59.24 238.94,60.79 237.94,61.78 v2(237.9,61.78)
  BOTTOM w0.109: RH625.2 226.92,118.51 v2(227.01,118.42)
HDD_FALL_INT: length 7.3
  TOP w0.109: v2(229.59,106.9) 229.47,106.9 229.17,107.2 229.17,110.69 230,111.52 RH355.2 ; v2(254.49,42.63) 254.49,42.62 LGA1.12
  BOTTOM w0.089: UH1.AW26 229.14,106.9 v2(229.59,106.9)
HDD_UN7_EN: length 5.4
  TOP w0.102: v1(249.48,30.43) RN227.1
  TOP w0.109: RN227.1 250.15,31.46 250.2,31.41 QN6.1 251.2,32.11 251.69,32.6 RN226.2
HDD_UN7_EN_R: length 4.3
  TOP w0.102: v1(249.3,33.54) 249.48,33.35 v2(249.48,33) ; v2(238.58,32.19) 238.58,31.32 238.39,31.13 DN1.2
  TOP w0.109: UN7.7 242.19,32.94 241.99,32.75 v2(241.99,32.46) ; RN227.2 v2(249.48,33)
HDMI_1.2V_EN: length 35.2
  TOP w0.109: RV615.1 298.29,91.69 297.42,91.69 v2(297.3,91.58) 296.26,90.54 UV31.G8
  BOTTOM w0.102: PR511.1 267.67,67.62 267.9,67.85 269.13,67.85 269.46,68.18 269.46,70.23 269.59,70.36 270.58,70.36 271.62,69.31 274.73,69.31 275.39,68.65 278.51,68.65 279.51,69.65 arc(280.58,70.37) 281.84,70.62 282.93,70.62 285.71,73.4 289.57,73.4 v1(289.68,73.29) 293.75,73.29 v2(293.87,73.16)
HDMI_CEC: length 12.5
  TOP w0.102: v2(303.4,82.94) 303.33,83 300.29,83 300.11,83.18 RV604.1
  BOTTOM w0.109: JHDMI1.13 306.64,82.84 306.64,80.72 306.32,80.4 304.99,80.4 304.86,80.53 304.86,82.5 304.71,82.64 v1(304.03,82.64) 303.7,82.64 v2(303.4,82.94)
HDMI_CEC_R: length 5.4
  TOP w0.109: RV604.2 299.11,83.54 v1(297.81,83.54) 296.41,83.54 295.8,84.15 295.8,85.34 UV31.F2
HDMI_CLK_27M_IN: length 7.1
  TOP w0.102: UV31.E8 294.61,90.55 294.61,91.22 292.8,93.04 292.8,93.04 v1(292.13,93.71) 291.74,94.09 291.74,94.55 CV607.1 290.95,95.34 290.36,95.34 YV6.1
HDMI_CLK_27M_OUT: length 6.1
  TOP w0.102: UV31.F8 295.4,90.89 295.23,91.06 295.23,91.43 295.22,91.44 295.22,91.48 v1(294.41,92.29) 293.41,93.29 293.41,93.29 292.36,94.34 292.36,94.99 RV609.1
HDMI_CLK_27M_OUT_R: length 3.2
  TOP w0.102: RV609.2 292.06,96.2 CV606.1 290.94,96.2 290.7,95.96 289.86,95.96 YV6.3
HDMI_CTRL_CLK: length 3.1
  TOP w0.089: RV22.1 292.69,83.01 292.69,83.13 v2(292.94,83.38) 294.5,84.94 UV31.E1
HDMI_CTRL_DATA: length 3.2
  TOP w0.089: UV31.F1 294.8,84.34 294.74,84.34 293.79,83.38 v2(293.58,83.38) 293.58,82.95 RV23.1
HDMI_HPD: length 2.5
  TOP w0.109: UV31.G1 296.2,84.49 v2(296.48,84.21)
  BOTTOM w0.102: v2(296.48,84.21) 294.95,84.21 v1(294.83,84.34)
HDMI_L_CLKN: length 2.5
  TOP w0.089: RV33.2 302.02,83.67 LV12.3 302.24,83.82 302.39,83.97 302.76,83.97 RV35.2 303.45,83.89 303.93,83.89 v2(304.07,83.75)
HDMI_L_CLKP: length 2.4
  TOP w0.089: v2(304.07,84.34) 303.93,84.19 303.45,84.19 RV35.1 302.91,84.27 302.37,84.27 302.27,84.37 LV12.4 302.02,84.51 RV34.2
HDMI_L_TX_N0: length 16.9
  TOP w0.089: RV30.2 302.05,85.73 LV9.3 302.24,85.85 302.37,85.98 302.78,85.98 RV32.2 303.45,85.93 304.37,85.93 304.69,85.61 v3(304.69,82.46) 304.69,80.72 305.43,79.97 306.32,79.97 306.87,80.53 306.87,85.82 306.98,85.93 307.3,85.93 307.45,85.77 JHDMI1.9
HDMI_L_TX_N1: length 4.6
  TOP w0.089: JHDMI1.6 305.55,87.5 304.55,87.5 304.1,87.96 303.42,87.96 303.14,87.68 RV29.2 302.78,88.01 302.44,88.01 302.3,87.88 LV6.3 302.05,87.76 RV27.2
HDMI_L_TX_N2: length 6.3
  TOP w0.089: JHDMI1.3 307.1,89 306.85,89 305.86,89.99 v3(304.16,89.99) 303.45,89.99 RV26.2 302.83,89.99 302.25,89.99 LV3.3 302.05,89.79 RV24.2
HDMI_L_TX_P0: length 16.8
  TOP w0.089: RV31.2 302.05,86.52 LV9.4 302.23,86.4 302.35,86.28 302.88,86.28 RV32.1 303.45,86.22 304.5,86.22 v3(304.7,86.02) 304.99,85.74 304.99,80.85 305.56,80.27 306.19,80.27 306.57,80.66 306.57,85.95 307.28,86.65 JHDMI1.7
HDMI_L_TX_P1: length 4.6
  TOP w0.089: 303.14,88.54 303.33,88.34 304.13,88.34 304.35,88.13 v3(304.35,88.13) 304.68,87.8 305.55,87.8 JHDMI1.4 ; 303.14,88.54 303.14,88.46 302.99,88.31 302.29,88.31 LV6.4 302.05,88.55 RV28.2 ; 303.14,88.54 RV29.1
HDMI_L_TX_P2: length 6.4
  TOP w0.089: RV25.2 302.05,90.58 LV3.4 302.26,90.37 302.91,90.37 RV26.1 303.14,90.57 303.42,90.29 305.62,90.29 v3(305.62,90.29) 305.98,90.29 306.97,89.3 307.1,89.3 JHDMI1.1
HDMI_LS_CLKN: length 4.8
  TOP w0.089: RV33.1 300.93,83.82 LV12.2 300.87,83.82 300.75,83.94 299.91,83.94 v3(299.47,84.38) 298.85,85 297.87,85 297.7,85.16 297.23,85.16 UV31.H1
HDMI_LS_CLKP: length 4.8
  TOP w0.089: RV34.1 300.95,84.37 LV12.1 300.82,84.37 300.7,84.24 300.03,84.24 298.97,85.3 v3(298.57,85.3) 297.99,85.3 297.56,85.74 UV31.H2
HDMI_LS_TX_N0: length 4.7
  TOP w0.089: RV30.1 300.95,85.85 LV9.2 300.68,85.85 300.56,85.97 299.86,85.97 v3(299.65,86.18) 299.06,86.77 297.23,86.77 UV31.H3
HDMI_LS_TX_N1: length 4.5
  TOP w0.089: UV31.H5 297.15,88.14 297.35,88.34 297.57,88.34 297.87,88.04 v3(299.97,88.04) 300.76,88.04 LV6.2 300.95,87.88 RV27.1
HDMI_LS_TX_N2: length 4.4
  TOP w0.089: UV31.H7 297.15,89.74 297.39,89.98 v3(299.97,89.98) 300.21,89.98 300.3,90.07 300.65,90.07 300.81,89.91 LV3.2 300.98,89.91 RV24.1
HDMI_LS_TX_P0: length 4.7
  TOP w0.089: UV31.H4 297.27,87.07 v3(298.57,87.07) 299.19,87.07 299.98,86.27 300.7,86.27 300.82,86.4 LV9.1 300.97,86.4 RV31.1
HDMI_LS_TX_P1: length 4.5
  TOP w0.089: RV28.1 300.97,88.43 LV6.1 300.83,88.34 v3(298.57,88.34) 298.06,88.34 297.47,88.94 UV31.H6
HDMI_LS_TX_P2: length 4.4
  TOP w0.089: RV25.1 300.95,90.46 LV3.1 300.83,90.37 300.18,90.37 300.11,90.3 299.26,90.3 299.25,90.31 v3(298.64,90.31) 298.4,90.31 298.37,90.28 297.26,90.28 UV31.H8
HDMI_PD#: length 2.4
  TOP w0.109: UV31.C3 v2(293.36,86.17)
  BOTTOM w0.109: RV607.1 292.6,90.12 293.23,90.74 v1(293.23,90.91) 293.23,91.36 v2(293.13,91.45)
HDMI_RST#: length 5.3
  TOP w0.102: UV31.B8 291.72,91.02 289.64,91.02 RV608.2 289.03,90.93 CV605.1 288.83,91.26 288.6,91.49 287.57,91.49 v1(287.45,91.62)
HOST_DEBUG_TX: length 27.4
  TOP w0.102: v2(258.84,65.2) 259.61,65.2 260.66,64.15 v1(262.76,64.15) 263.29,64.15 264.92,62.52 269.36,62.52 271.81,64.97 272.73,64.97 v2(272.92,65.16)
  TOP w0.109: UE1.G11 v2(269.67,96.53)
  BOTTOM w0.102: RZ132.1 273.29,86.06 272.98,86.37 272.98,87.78 273.54,88.34 v2(273.98,88.34)
  BOTTOM w0.109: RE306.2 256.75,65.2 v2(258.84,65.2) 259.23,65.2 259.49,65.46 JDEG1.8 259.49,66.59 258.9,67.18 258.05,67.18 RE73.2
HOST_SD_WP#: length 20.5
  TOP w0.102: QR1.2 298.64,26.35 298.58,26.29 v2(298.17,26.29)
  TOP w0.109: RH214.2 v2(215.45,125.57)
  BOTTOM w0.089: UH1.BE8 219.98,110.04 220.24,110.3 220.24,110.65 220.42,110.83 220.42,112.24 217.89,114.77 217.89,116.95
  BOTTOM w0.109: v2(215.45,125.57) 215.45,125.17 217.06,123.56 v1(217.06,121.61) 217.06,119.01 217.6,118.48 217.6,117.24 217.89,116.95
HP_OUT_L: length 4
  TOP w0.203: v2(289.76,54.07) 289.62,54.2 UA1.25
  TOP w0.381: v2(288.29,48.92) 288.29,48.35 CA43.2 288.29,48.09 RA7.1 ; v2(289.76,54.07) 290.18,54.07 CA77.1
HP_OUT_R: length 4.5
  TOP w0.203: UA1.26 289.4,54.6 289.48,54.69 v2(289.61,54.69)
  TOP w0.381: RA8.1 287.02,48.09 CA44.2 287.08,48.29 v2(287.08,48.94) ; v2(289.61,54.69) 289.81,54.69 290.32,55.19 CA78.1
HV_GATE1_A: length 2.8
  BOTTOM w0.076: RT64.1 66.36,103.36 65.46,104.27 65.46,105.16 65.68,105.38 UT5.B9
HV_GATE2_A: length 2.7
  BOTTOM w0.076: UT5.A9 65.71,104.25 66.47,103.49 67.02,103.49 67.13,103.38 RT65.1
HW_ACAVIN_NB: length 195
  TOP w0.109: UE1.N6 265.27,90.53 265.17,90.43 v2(265.13,90.43)
  TOP w0.254: v2(131.12,36.52) 130.74,36.14 PR746.1 ; PR844.1 109.28,72.2 PR845.1 109.82,72.21 v2(109.9,72.13) ; v2(73.64,113.4) 73.67,113.37 ; 73.67,113.37 73.67,112.1 73.67,112.1 73.67,110.49 v1(72.98,109.8) 72.98,108.13 74.35,106.75 v2(75.69,106.75) ; 73.67,113.37 73.69,113.35 75.17,113.35 75.94,114.12 PR25.2 ; PR737.1 v2(143.8,31.86) ; PR41.1 PR42.1 97.01,128.47 96.76,128.72 v2(96.76,129.04)
  BOTTOM w0.102: v2(109.9,72.13) 109.92,72.15 110.86,72.15 112.32,70.69 112.42,70.58 112.52,70.48 121.29,70.48 124.83,66.95 221.62,66.95 225.15,70.48 225.86,70.48 227.11,71.74 236.3,71.74 239.69,68.36 248.05,68.36 248.98,69.29 248.98,69.3 249.87,70.18 249.87,72.59 250.38,73.1 256.41,73.1 256.74,72.76 258.16,72.76 259.57,71.35 266.22,71.35 266.71,71.84 266.96,71.84 v2(267.14,72.02)
  BOTTOM w0.254: PR805.2 81.73,106.14 PR806.2 ; PC805.1 81.02,105.24 PR806.2 ; PR806.2 80.88,106.28 80.22,106.28 79.96,106.54 PU800.1 79.96,107.87 79.33,108.51 78.44,108.51 77.55,107.62 77.55,107.2 77.34,106.98 PR835.1 76.3,106.98 76.07,106.75 v2(75.69,106.75)
HW_GPS_DISABLE#_R: length 8.5
  TOP w0.102: v1(264.54,77.86) 264.44,77.96 v2(263.95,77.96) ; DZ6.2 262.78,78.02 RZ87.1
  TOP w0.109: DZ6.2 263.26,77.96 v2(263.95,77.96)
  BOTTOM w0.109: JNGFF2.26 265.83,81.25 266.08,80.99 266.08,78.58 265.46,77.96 v2(263.95,77.96)
I2C0_SCL_TS: length 11
  TOP w0.102: v2(107.18,131.29) 107.02,131.13 DZ10.2 106.15,130.16 RV99.2 107.53,128.79 v2(107.94,128.79)
  BOTTOM w0.089: v2(227.52,112.46) 227.32,112.46 227.09,112.23 227.09,111.72 227.26,111.55 227.26,110.77 227.02,110.54 227.02,109.62 226.94,109.54 226.94,109.35 226.87,109.28 UH1.BC22
  BOTTOM w0.102: JIRTS1.4 107.83,131.66 107.47,131.29 v2(107.18,131.29)
I2C0_SDA_TS: length 7.3
  TOP w0.102: v2(108.64,132.28) 108.08,131.72 DZ10.3 108.08,130.19 107.74,129.85 RV98.2 107.87,129.44 108.58,128.72 v2(108.67,128.72)
  BOTTOM w0.089: v2(227.46,111.88) 227.45,111.87 227.45,110.7 227.28,110.52 UH1.BF23
  BOTTOM w0.102: JIRTS1.3 108.63,132.3 v2(108.64,132.28)
I2C1_SCK_TP: length 8.2
  TOP w0.109: v2(194.37,39.05) RZ29.1 193.62,39.19 RZ21.2
  BOTTOM w0.089: v2(226.35,116.05) 226.34,116.05 226.25,115.96 226.25,115.89 225.75,115.39 225.75,113.86 226.19,113.42 226.19,110.48 226.57,110.1 UH1.BE21
I2C1_SCK_TP_R: length 15.2
  TOP w0.102: v2(187.15,35.92) 186.72,35.92 186.43,35.63 186.43,33.98 v4(186.88,33.54)
  TOP w0.109: v2(187.15,35.92) 187.71,35.92 RZ347.1 ; RZ117.2 192.84,39.85 RZ29.2 192.84,38.53 v2(192.66,38.35)
  BOTTOM w0.109: JKBTP1.19 192.51,38.91 192.66,38.76 v2(192.66,38.35) 192.66,37.91 193.1,37.47 193.1,36.46 192.56,35.92 v2(187.15,35.92)
I2C1_SDA_TP: length 7.4
  TOP w0.109: v2(190.75,38.27) 190.85,38.27 191.19,38.62 RZ26.1 191.19,39.79 RZ20.2
  BOTTOM w0.089: v2(226.35,115.46) 226.25,115.46 225.94,115.15 225.94,113.94 226.38,113.5 226.38,110.94 226.6,110.72 UH1.BF21
I2C1_SDA_TP_R: length 6.6
  TOP w0.109: RZ116.2 192.11,39.79 RZ26.2 192.11,38.44 v2(192.01,38.35) v4(192.64,37.72) 192.98,37.38 192.98,36.38 192.48,35.87 RZ346.1
  BOTTOM w0.109: JKBTP1.18 v2(192.01,38.35)
I_ADP: length 2.2
  TOP w0.102: UE1.B11 269.27,100.32
  TOP w0.109: 269.27,100.32 269.72,100.77 v2(269.72,101.31)
  TOP w0.254: PR743.2 125.42,31.44 v2(125.42,31.06)
I_BATT: length 1.4
  TOP w0.102: RE64.2 v2(254.64,93.61)
  TOP w0.254: v2(124.2,31.06) 124.37,31.23 PR729.2
I_BATT_R: length 10.7
  TOP w0.102: RE64.1 256.17,93.71 256.72,94.26 v2(256.92,94.26) 257.09,94.26 v1(257.39,93.96) 258.05,93.3 CE3.1
  TOP w0.109: UE1.J4 263.32,94.18 v2(263.23,94.18)
  BOTTOM w0.102: v2(256.92,94.26) 258.33,94.26 258.59,94.52 261.34,94.52 262.12,93.74 263.07,93.74 263.23,93.9 263.23,94.17 v2(263.23,94.18)
I_SYS: length 6.5
  TOP w0.102: RE312.2 257.49,110.56 257.61,110.44 258.31,110.44 v2(258.38,110.37)
  BOTTOM w0.203: v2(124.84,31.06) 124.84,31.13 124.43,31.53 PR731.2 ; PRZ62.1 109.47,100.19 108.95,100.19 108.75,99.99 v2(108.75,99.74) 108.75,99.7 108.14,99.09 107.5,99.09 107.08,99.51 PUZ1.24
I_SYS_R: length 3.9
  TOP w0.102: v2(255.96,113.17) 256.03,113.17 256.6,112.6 CE4.1 RE312.1 RE313.1
  TOP w0.109: v2(264.07,94.08) 264.07,94.09 264.47,94.49 UE1.J5
  BOTTOM w0.102: v2(255.96,113.17) v1(255.52,112.72)
ILIM_1PH_CPU: length 5.1
  TOP w0.102: v1(99.18,103.77) 99.12,103.71 v2(98.42,103.71)
  TOP w0.254: PRZ22.2 PCZ9.2 98.19,103.94 v2(98.42,103.71)
  BOTTOM w0.203: v2(98.42,103.71) 98.42,103.64 99.75,102.31 PUZ1.49
ILIM_2PH_CPU: length 2.1
  BOTTOM w0.203: PUZ1.32 v1(103.93,96.91) 103.93,96.05 PRZ49.1
ILIM_4PH_CPU: length 2.9
  BOTTOM w0.203: PUZ1.7 103.53,105.16 v1(103.78,105.41) 104.09,105.72 104.09,106.46
  BOTTOM w0.254: PRZ48.2 104.09,106.46
ILIM_SEL: length 2.8
  TOP w0.102: RI13.1 291.42,69.63 v1(290.44,68.65)
  TOP w0.109: UI3.4 291.42,69.75 RI13.1
ILMT_1.05VALWP: length 2.2
  TOP w0.254: v2(196.02,89.43) PR310.1 PR307.2
  BOTTOM w0.254: v2(196.02,89.43) 196.02,88.56
ILMT_DDR: length 3.1
  TOP w0.102: v2(176.46,38.75) 176.14,38.43 v1(176.14,38.3)
  TOP w0.254: v2(176.46,38.75) 175.89,39.32 PR207.1 PR205.2
  BOTTOM w0.254: PU200.17 176.16,38.36 176.23,38.43 176.23,38.43 176.45,38.66 176.45,38.66 176.46,38.67 v2(176.46,38.75)
IMON_1PH_CPU: length 4.6
  TOP w0.102: v2(98.88,101.46) v1(99.48,101.46)
  TOP w0.254: PCZ6.2 PRZ15.2 98.25,102.1 v2(98.88,101.46)
  BOTTOM w0.203: PUZ1.46 99.24,101.11 v2(98.88,101.46)
IMON_2PH_CPU: length 3.2
  BOTTOM w0.203: PUZ1.36 102.33,97.43 101.93,97.03 v1(101.93,96.89) 101.91,96.87 101.91,96.15 PCZ24.1
  BOTTOM w0.254: PCZ24.1 PRZ44.1
IMON_4PH_CPU: length 5.3
  TOP w0.102: v2(101.86,105.02) 101.86,104.86 101.72,104.72 100.81,104.72 v1(100.52,105.02)
  TOP w0.254: PRZ41.2 PCZ22.2 101.23,105.65 v2(101.86,105.02)
  BOTTOM w0.203: PUZ1.3 101.93,104.95 v2(101.86,105.02)
IMVP_VR_ON: length 8.2
  TOP w0.102: UE3.4 259.58,121.68 259.14,122.12 259.14,122.51 ; UE4.2 258.12,123.01 258.63,122.5 259.13,122.5 259.14,122.51 ; v2(259.17,122.54) 259.14,122.51
  BOTTOM w0.102: v2(259.17,122.54) 259.17,123.29 259.86,123.98 RE304.1
  BOTTOM w0.109: v2(96.28,99.45) 96.32,99.49 97.41,99.49 PRZ28.2
IMVP_VR_ON_EC: length 30.8
  TOP w0.102: v2(261.11,122.5) 261.57,122.96 UE3.1 ; v2(265.9,90.77) 265.87,90.74 265.87,89.79 265.17,89.09 RE717.2
  TOP w0.109: UE1.N7 266.07,90.95 v2(265.9,90.77)
  BOTTOM w0.102: v2(263.38,101.8) 262.61,102.57 262.61,107.48 v1(261.2,108.89) 258.83,111.26 258.83,121.63 259.58,122.37 259.58,123.13 259.77,123.32 260.18,123.32 261,122.5 v2(261.11,122.5) 261.49,122.88 261.49,122.9 261.59,123 261.62,123 RE304.2
INT_SPK_L+: length 0.6
  TOP w0.127: v2(292.98,36.46) v1(292.98,37.06)
  vias: v2(285.87,59.59) v2(285.87,58.95) v2(292.35,36.46)
INT_SPK_L-:
  vias: v1(285.36,58.37) v2(284.98,59.59) v2(284.98,58.95) v2(289.86,36.06) v2(289.86,35.48)
INT_SPK_R+:
  vias: v1(283.59,58.49) v2(283.27,59.59) v2(283.27,58.95) v2(287.64,36) v2(287.64,35.41)
INT_SPK_R-:
  vias: v2(284.09,59.59) v2(284.09,58.95) v2(286.53,37.43) v2(287.12,37.43)
INT_SPKR_L+:
  vias: v2(293.62,30.3) v2(293.62,29.66) v4(293.62,30.93)
INT_SPKR_L-:
  vias: v2(292.6,30.3) v2(292.6,29.66) v4(291.14,30.13)
INT_SPKR_R+:
  vias: v2(289.68,30.3) v2(289.68,29.66) v4(289.21,30)
INT_SPKR_R-:
  vias: v2(288.54,30.3) v2(288.54,29.66) v4(286.51,31.04)
IR_CAM_DET#: length 5.2
  TOP w0.109: RH373.1 209.22,108.33 211.35,108.33 v2(211.39,108.3)
  BOTTOM w0.089: UH1.BD16 223.45,108.69 v2(223.45,108.61)
  BOTTOM w0.102: v2(106.48,132.28) 107.03,132.82 JIRTS1.5
ISEN1N_GT: length 5.9
  TOP w0.102: v1(109.34,84.15) 109.34,84.27 v2(109.66,84.59)
  TOP w0.254: PRT3.2 v2(109.66,84.59)
  BOTTOM w0.203: PCZ30.1 106.42,95.96 v2(106.42,96.66) 106.38,96.7 105.96,96.7 105.13,97.53 PUZ1.29
  BOTTOM w0.254: PCZ36.2 PRZ73.2 107.3,95.95 PCZ30.1
ISEN1N_IA: length 19
  TOP w0.152: v2(166.63,120.03) 166.24,120.03 v1(165.95,120.31) 165.72,120.55 PRH14.2 ; PRH13.2 186.94,115.53 v2(186.94,117.55) ; v2(154.69,120.15) 154.68,120.15 153.84,119.31 PRH6.2 ; v2(177.11,120.13) 176.95,119.96 175.76,119.96 175.5,120.23 PRH5.2
  BOTTOM w0.203: PUZ1.10 104.73,104.86 105.45,105.58 106.18,105.58 PCZ27.2
  BOTTOM w0.254: PRZ81.2 PCZ39.2 111.99,97.59 v2(112.34,97.94) ; PCZ27.2 PRZ65.2 PCZ35.2 PRZ74.2 PCZ37.2 PRZ76.2 PCZ38.2 111.85,105.83 v2(112.07,106.06)
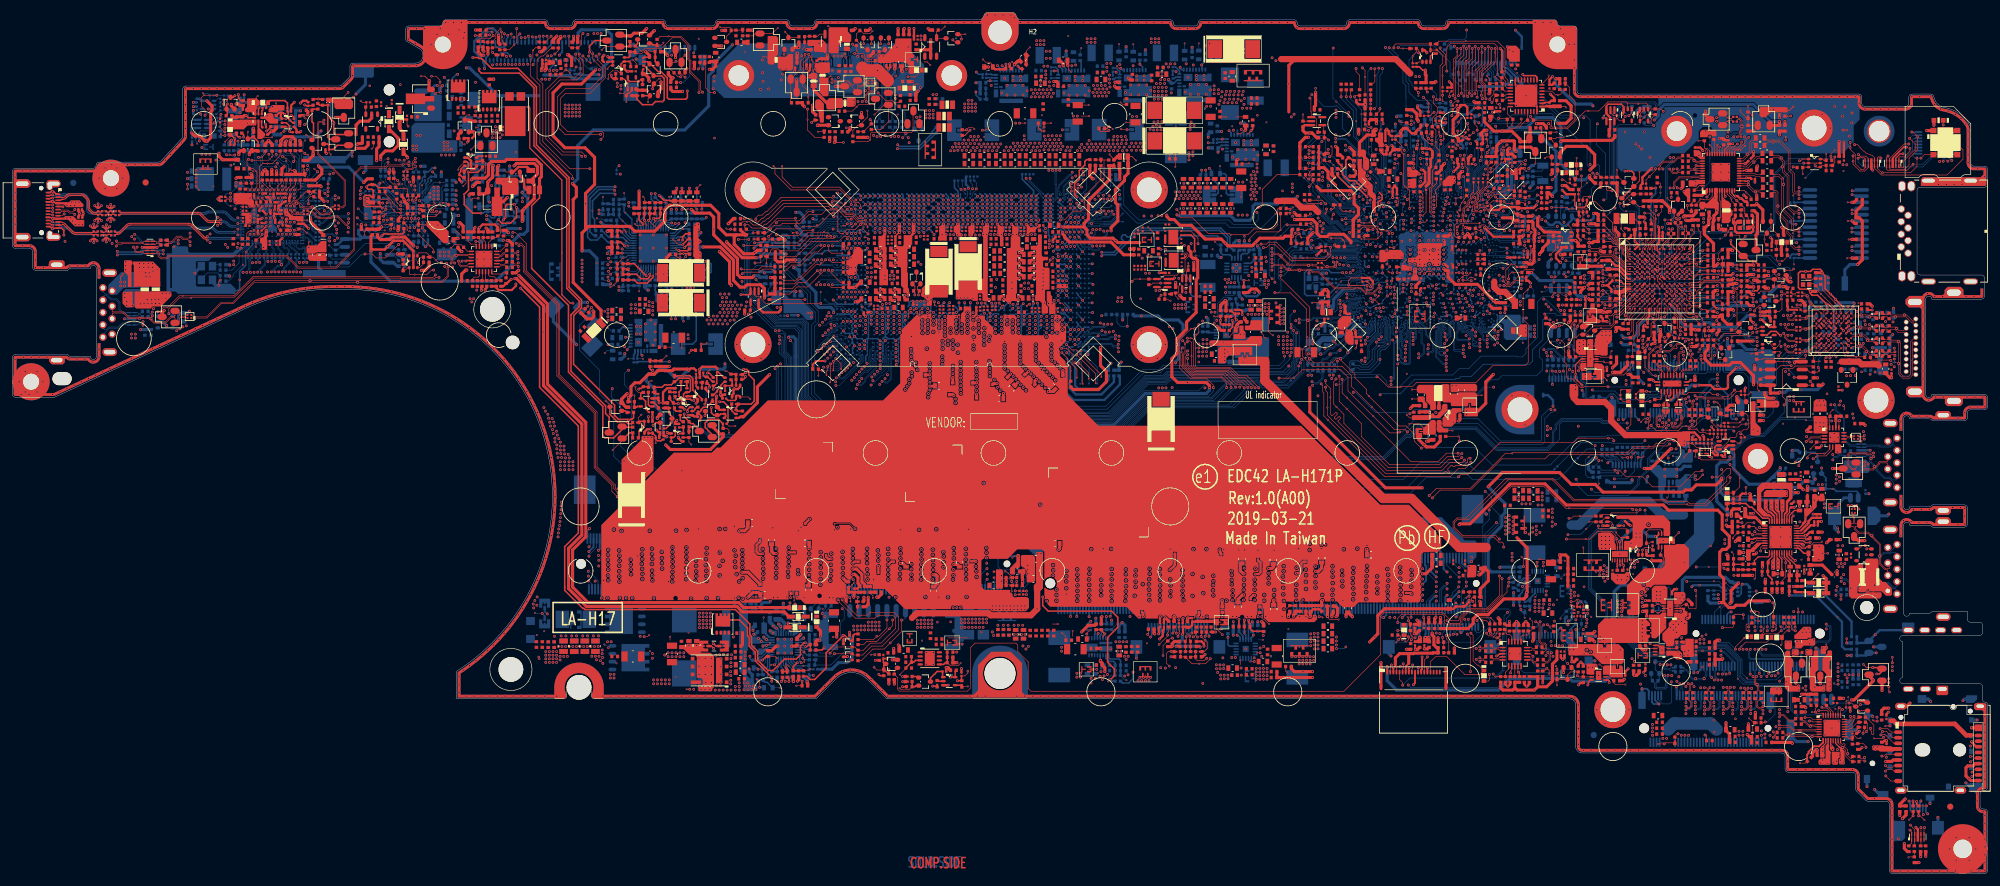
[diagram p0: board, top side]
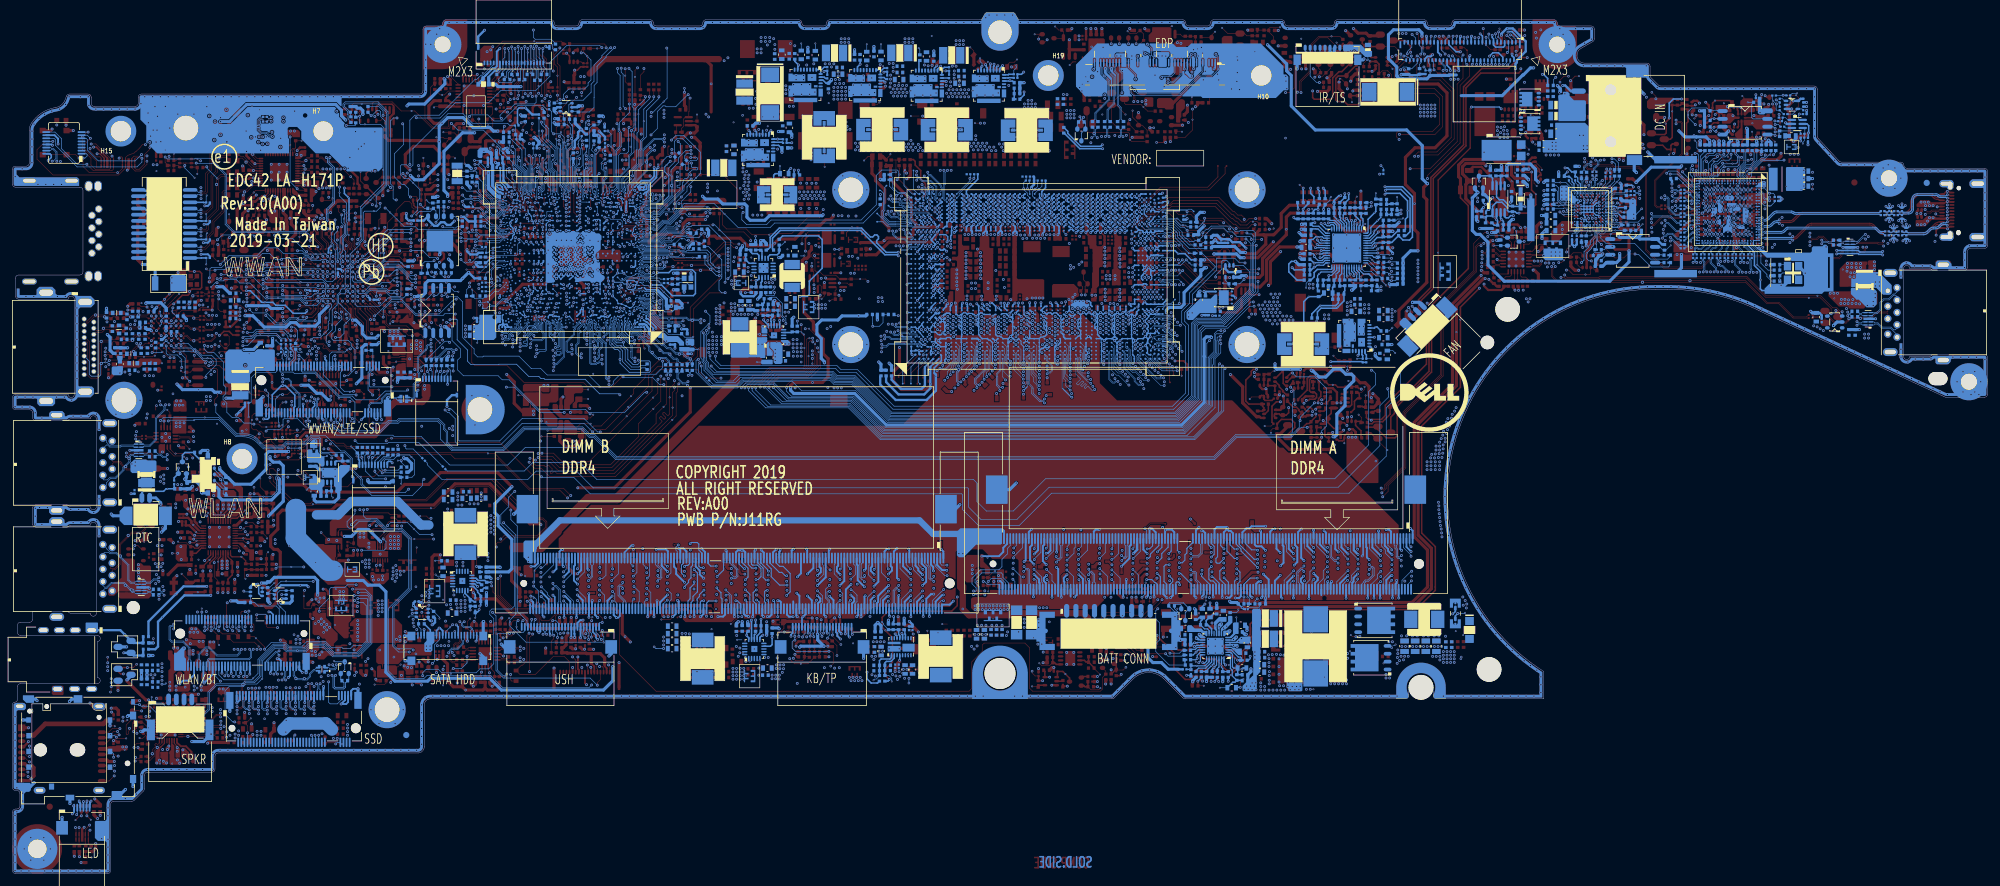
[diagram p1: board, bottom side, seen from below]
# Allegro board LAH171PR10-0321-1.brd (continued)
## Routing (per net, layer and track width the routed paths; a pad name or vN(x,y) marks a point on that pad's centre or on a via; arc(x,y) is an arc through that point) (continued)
ISEN1N_SA: length 15.1
  BOTTOM w0.254: PRZ5.1 94.04,104.12 94.04,105.77 93.7,106.12 v1(93.7,107.13) 93.7,108.73 94.92,109.96 97.19,109.96 v2(97.34,109.8) ; PLA1.3 194.47,109.72 194.78,110.02 194.78,111.35 193.91,112.21 193.12,112.21 192.79,112.55 PHZ1.1 192.79,113.66 v2(192.74,113.71)
ISEN1P_GT: length 12.5
  BOTTOM w0.254: PLT1.2 109.89,85.59 110.46,86.15 110.46,92.44 v1(109.65,93.26) PRZ71.2 107.78,93.26 PRZ59.2
ISEN1P_IA: length 4.2
  TOP w0.102: v1(157.35,120.41) 157.09,120.15 v2(156.68,120.15)
  TOP w0.254: v2(107.31,110.8) 107.31,110.49 PRZ53.1
  BOTTOM w0.152: PLH1.2 v2(156.68,120.15)
  BOTTOM w0.254: PRZ64.1 107.01,110.45 107.31,110.75 v2(107.31,110.8)
ISEN1P_SA: length 6.3
  BOTTOM w0.102: PRZ4.2 v1(195.07,114.37)
  BOTTOM w0.254: PRZ4.2 195.83,113.13 196.08,112.88 196.08,109.97 196.34,109.72 PLA1.2
ISEN2P_IA: length 3.2
  TOP w0.254: PRZ56.1 v2(108.15,110.8)
  BOTTOM w0.152: PLH2.2 v2(169.6,120.21)
  BOTTOM w0.254: PRZ72.1 v1(107.95,110.06) 107.95,110.35 108.15,110.55 v2(108.15,110.8)
ISEN3P_IA: length 5
  TOP w0.102: v2(180.05,120.25) 179.16,120.25 v1(179.07,120.34)
  TOP w0.254: PRZ58.1 v2(109.36,110.8)
  BOTTOM w0.152: PLH3.2 v2(180.05,120.25)
  BOTTOM w0.254: PRZ75.1 108.82,109.41 109.36,109.94 v2(109.36,110.8)
ISEN4P_IA: length 4.6
  TOP w0.102: v2(110.55,110.8) 110.59,110.8 v1(111.12,111.33)
  TOP w0.254: v2(110.55,110.8) 110.55,110.24 110.56,110.22 PRZ60.1
  BOTTOM w0.152: PLH4.2 v2(187.93,120.53)
  BOTTOM w0.254: v2(110.55,110.8) 110.55,108.47 PRZ80.1
ISH_UART0_CTS#_R: length 2
  TOP w0.102: RZ80.2 287.95,40.34 v2(287.95,39.84)
  BOTTOM w0.102: JNGFF1.62 v2(287.95,39.84)
ISH_UART0_RXD_R: length 3
  TOP w0.102: v2(286.95,39.84) 286.79,39.84 ; 286.79,39.84 286.46,39.84 v1(286.19,39.57) ; 286.79,39.84 RZ78.2
  BOTTOM w0.102: JNGFF1.58 v2(286.95,39.84)
ISH_UART0_TXD_R: length 4
  TOP w0.102: v2(288,39.26) 287.72,39.26 v1(287.52,39.46) 287.4,39.58 287.4,40.07 RZ79.2
  BOTTOM w0.102: v2(288,39.26) 287.9,39.26 287.46,39.7 287.46,40.07 287.45,40.08 JNGFF1.60
IST_TRIG: length 6.7
  TOP w0.109: T3.1 174.99,80.78 v2(171.93,83.84)
  BOTTOM w0.076: v2(171.93,83.84) 171.93,83.97 UC1.E3
ITP_PMODE_CPU: length 8.3
  TOP w0.102: RC144.2 86.85,128.51 v2(86.72,128.38)
  TOP w0.109: v2(211.69,104.21) 211.51,104.03 T192.1
  BOTTOM w0.089: v2(211.69,104.21) 211.88,104.03 213.36,104.03 214.68,102.71 217.06,102.71 217.14,102.8 217.55,102.8 UH1.AL3
JDIMM1_EVENT#: length 2.6
  TOP w0.102: v2(126.27,44.71) v1(126.27,44.14)
  TOP w0.109: v2(126.27,44.71) 126.69,45.14 RD14.1
  BOTTOM w0.109: JDIMM1.134 126.12,44.86 v2(126.27,44.71)
JDIMM2_EVENT#: length 5
  TOP w0.102: v2(201.81,41.54) 201.81,41.33 202.11,41.03 202.25,41.03 202.91,40.37 v1(203,40.37)
  TOP w0.109: RD27.1 201.99,42.65 201.99,41.67 201.86,41.54 v2(201.81,41.54)
  BOTTOM w0.109: JDIMM2.134 201.92,41.65 201.82,41.54 v2(201.81,41.54)
JTAG_CLK: length 3.8
  TOP w0.102: v1(262.12,68.08) 261.49,67.45 v2(261.49,67.3)
  TOP w0.109: UE1.C8 267.28,99.73 v2(267.28,99.76)
  BOTTOM w0.109: JDEG1.4 v2(261.49,67.3) 261.49,67.36 RE713.2
JTAG_RST#: length 8.5
  TOP w0.109: UE1.G13 271.52,96.13 272.22,96.83 v1(272.92,96.83) 275.71,96.83 275.81,96.72 CE30.1 276.21,96.75 RE65.1 276.21,97.9 276.25,97.94 JTAG1.1 276.25,99.08 276.21,99.12 RE63.1
JTAG_TDI: length 3.7
  TOP w0.102: v2(262.61,67.28) 263.29,67.28 v1(263.46,67.45)
  TOP w0.109: v2(268.09,98.21) 268.09,98.14 UE1.E9
  BOTTOM w0.109: RE715.2 262.71,67.79 262.71,67.38 v2(262.61,67.28) 262.66,67.23 262.66,67.06 262.49,66.89 JDEG1.2
JTAG_TDO: length 3.9
  TOP w0.102: v2(260.91,67.26) v1(260.03,67.26)
  TOP w0.109: v2(264.88,97.38) 264.88,97.32 UE1.F6
  BOTTOM w0.109: JDEG1.5 260.99,66.98 260.91,67.07 v2(260.91,67.26) 260.8,67.26 260.08,67.98 RE712.2
JTAG_TMS: length 7.6
  TOP w0.109: v2(264.07,99.82) 264.47,99.42 UE1.C5
  BOTTOM w0.102: v2(258.76,63.8) 260.77,63.8 261.99,65.03 JDEG1.3
  BOTTOM w0.109: JDEG1.3 262.12,66.22 262.12,67.55 RE714.2
KB_DET#: length 4.9
  TOP w0.102: RC74.2 224.33,121.37 v4(224.02,121.68) ; v2(183.38,38.67) 183.38,38.67 183.38,38.75 183.48,38.85 CZ84.1
  TOP w0.109: v2(225.95,121.08) 225.52,121.08 RC74.2
  BOTTOM w0.089: UH1.AW15 223.26,107.09 v2(223.08,106.91)
  BOTTOM w0.109: v2(183.38,38.67) 183.38,38.67 183.38,38.75 183.51,38.87 JKBTP1.1
LAN_ACTLED_YEL#: length 2.1
  TOP w0.102: RL14.1 v1(292.97,116.36)
  TOP w0.109: RL14.1 292.59,115.29 292.39,115.49 QL1.6
LAN_ACTLED_YEL_R#: length 2
  TOP w0.102: v2(293.74,115.92) 293.74,116.32 v1(294.36,116.94)
  TOP w0.109: v2(293.74,115.92) 293.74,115.43 RL14.2
LAN_DISABLE#_R: length 6.1
  TOP w0.102: RL9.1 RL7.2
  TOP w0.109: RL5.1 271.2,108.36 RL7.2 ; RL9.1 271.97,108.21 272.47,108.72 272.47,108.81 v1(272.66,109) 273.11,109 273.2,108.91 274.02,108.91 274.56,109.45 UL1.3
LAN_MDIN0: length 4.5
  TOP w0.089: RL72.1 282.33,110.48 281.3,110.48 v3(280.43,111.35) 280.25,111.53 279.5,111.53 279.45,111.57 UL1.14
LAN_MDIN0_L: length 14.1
  TOP w0.089: RL72.2 284.15,110.76 284.53,110.38 284.91,110.38 285.17,110.11 v3(285.17,107.9) 285.17,107.05 285.49,106.74 286.79,105.44 286.79,103.76 287.52,103.03 287.52,101.67 287.97,101.23 288.52,101.23 v2(288.58,101.29)
  BOTTOM w0.089: v2(288.58,101.29) 288.71,101.17 289.04,101.17 289.38,101.5 TL1.3
LAN_MDIN1: length 4.1
  TOP w0.089: RL74.1 282.33,112.96 281.67,112.96 281.48,113.14 279.67,113.14 279.64,113.17 UL1.18
LAN_MDIN1_L: length 14.2
  TOP w0.089: v2(288.58,104.29) 288.42,104.15 287.78,104.15 287.69,104.24 287.69,105.81 286.07,107.43 v3(286.07,111.39) 286.07,112.33 285.45,112.96 284.43,112.96 284.15,113.24 RL74.2
  BOTTOM w0.089: v2(288.58,104.29) 288.74,104.13 289.01,104.13 289.38,104.5 TL1.6
LAN_MDIN2: length 4.7
  TOP w0.089: UL1.21 279.59,114.37 279.62,114.34 280.17,114.34 281.07,115.24 281.77,115.94 282.21,115.94 RL76.1
LAN_MDIN2_L: length 14.3
  TOP w0.089: v2(288.58,107.29) 288.36,107.07 287.69,107.07 286.97,107.8 286.97,112.77 286.19,113.55 286.19,115.2 v3(285.71,115.68) 285.36,116.02 284.49,116.02 RL76.2
  BOTTOM w0.089: v2(288.58,107.29) 288.74,107.13 289.01,107.13 289.38,107.5 TL1.9
LAN_MDIN3: length 5
  TOP w0.089: UL1.24 279.52,115.57 v3(280.22,116.28) 280.58,116.63 280.58,118.14 280.89,118.45 281.16,118.45 RL78.1
LAN_MDIN3_L: length 14.7
  TOP w0.089: RL78.2 283.35,118.56 285.48,118.56 287.14,116.91 287.14,113.87 287.86,113.14 287.86,110.25 287.95,110.17 288.46,110.17 v2(288.58,110.29)
  BOTTOM w0.089: TL1.12 289.38,110.5 288.97,110.09 288.79,110.09 v2(288.58,110.29)
LAN_MDIP0: length 4.5
  TOP w0.089: UL1.13 279.5,111.17 279.56,111.23 280.12,111.23 281.17,110.18 v3(281.55,110.18) 282.27,110.18 282.75,109.7 RL71.1
LAN_MDIP0_L: length 14.1
  TOP w0.089: RL71.2 284.15,109.8 284.43,110.08 284.79,110.08 284.87,109.99 284.87,106.93 285.19,106.61 286.49,105.31 286.49,103.63 287.22,102.9 287.22,101.55 287.84,100.93 288.36,100.93 v2(288.58,100.71)
  BOTTOM w0.089: TL1.2 289.39,100.5 289.02,100.87 288.74,100.87 v2(288.58,100.71)
LAN_MDIP1: length 4.1
  TOP w0.089: UL1.17 279.62,112.77 279.69,112.84 281.36,112.84 281.54,112.66 282.27,112.66 RL73.1
LAN_MDIP1_L: length 14.2
  TOP w0.089: RL73.2 284.15,112.3 284.51,112.66 285.32,112.66 285.77,112.21 285.77,107.3 287.39,105.68 287.39,104.12 287.65,103.85 288.44,103.85 v2(288.58,103.71)
  BOTTOM w0.089: TL1.5 289.39,103.5 289.05,103.83 288.71,103.83 v2(288.58,103.71)
LAN_MDIP2: length 4.6
  TOP w0.089: RL75.1 282.27,115.64 281.95,115.64 v3(281.31,115) 280.35,114.04 279.69,114.04 279.62,113.97 UL1.20
LAN_MDIP2_L: length 14.4
  TOP w0.089: RL75.2 284.09,115.41 284.41,115.73 285.24,115.73 285.89,115.08 v3(285.89,114.25) 285.89,113.42 286.67,112.65 286.67,107.67 287.57,106.77 288.49,106.77 288.5,106.79 v2(288.58,106.71)
  BOTTOM w0.089: TL1.8 289.39,106.5 289.05,106.84 288.71,106.84 v2(288.58,106.71)
LAN_MDIP3: length 5
  TOP w0.089: RL77.1 281.16,118.15 281.01,118.15 280.87,118.01 280.87,116.51 279.54,115.17 UL1.23
LAN_MDIP3_L: length 14.8
  TOP w0.089: RL77.2 283.3,117.99 283.34,117.99 283.61,118.27 v3(284.41,118.27) 285.36,118.27 286.84,116.78 286.84,113.74 287.56,113.02 287.56,110.13 287.83,109.87 288.43,109.87 v2(288.58,109.71)
  BOTTOM w0.089: v2(288.58,109.71) 288.66,109.79 289.09,109.79 289.09,109.79 289.39,109.5 TL1.11
LAN_TEST_EN: length 1.6
  TOP w0.109: UL1.30 276.16,117.36 276.41,117.61 RL12.1
LAN_WAKE#: length 6.4
  TOP w0.109: RH93.1 238.88,114.97 238.35,114.43 238.35,112.93 v2(238.31,112.9) ; v2(273.72,109.36) 274.16,109.8 UL1.2 ; UE1.L3 262.48,92.53 262.4,92.53 v2(262.38,92.52)
  BOTTOM w0.089: UH1.BG44 237.87,111.9 238.31,112.34 v2(238.31,112.9)
LCD_CBL_DET#: length 5.3
  TOP w0.109: v2(227.39,107.01) 227.52,107.01 227.83,107.33 227.83,109.76 RC370.1
  BOTTOM w0.089: v2(227.39,107.01) 227.4,106.99 UH1.AW24
  BOTTOM w0.107: JEDP1.40 144.26,130.13 v2(144.39,129.99)
LCD_TST: length 22
  TOP w0.102: RE20.1 247.71,90.25 v2(247.52,90.44)
  TOP w0.109: v2(259.15,89.94) 259.43,89.94 261.17,91.68 261.38,91.68 261.83,92.13 UE1.M2
  BOTTOM w0.102: v2(247.52,90.44) 247.58,90.5 248.4,90.5 248.4,90.5 249.2,90.5 249.46,90.23 253.92,90.23 256.09,92.4 v1(256.73,92.4) 257.87,92.4 259.15,91.12 v2(259.15,89.94)
  BOTTOM w0.107: JEDP1.29 138.76,130.27 137.62,129.13 v2(137.62,128.41)
LCD_VCC_TEST_EN: length 13.6
  TOP w0.102: v2(151.91,134.77) 152.32,134.36 DV3.2
  TOP w0.109: UE1.E1 260.87,97.73 259.1,99.5 258.92,99.5 258.42,100 256.53,100 256,100.52 254.87,100.52 v2(254.69,100.7)
  BOTTOM w0.102: v2(254.69,100.7) 252.77,100.7 251.65,99.58 250.69,99.58 250.53,99.41 v2(250.36,99.41)
LDO_3V: length 1.7
  TOP w0.102: v1(243.76,51.21) 244.06,50.91 v2(244.06,49.64)
LED_GRN#: length 2
  TOP w0.102: RL19.1 v1(289.19,113.09)
  TOP w0.109: QL1.3 289.26,114.19 RL19.1
LED_GRN_R#: length 3.3
  TOP w0.102: RL19.2 287.78,114.12 v2(287.65,114.25)
  BOTTOM w0.102: v2(287.65,114.25) 287.65,114.06 v1(285.94,112.34)
LED_MASK#: length 37.2
  TOP w0.102: v2(281.58,88.09) 282,88.09 282.27,88.35 UZ10.1
  TOP w0.109: v2(289.36,114.84) QL1.2 291.03,114.84 291.04,114.85 291.38,114.85 291.38,114.84 QL1.5 ; RE21.1 271.65,104.57 v1(271.65,103.76) 271.65,103.48 271.01,102.84 271.01,102.4 v2(270.96,102.35) 270.96,102.04 270.07,101.15 UE1.A12
  BOTTOM w0.102: v2(270.96,102.35) 270.96,103.14 271.34,103.53 276.04,103.53 276.11,103.6 283.35,103.6 284.69,104.94 284.69,112.94 286.56,114.81 289.29,114.81 289.32,114.84 v2(289.36,114.84)
LG1_CHG: length 0.5
  BOTTOM w0.102: v1(95.63,37.03) 95.82,36.84 96.07,36.84
  vias: v2(96.13,37.48) v2(96.72,37.48) v2(122.39,39.24) v2(122.87,38.88)
LG2_CHG: length 0.5
  TOP w0.102: v2(109.41,29.79) v1(108.9,29.79)
  vias: v2(110.04,29.79) v2(121.36,38.22) v2(121.82,37.84)
LID_CL#: length 3.3
  TOP w0.102: UZ10.2 281.87,87.7 281.77,87.6 v2(281.77,87.5) ; RE26.1 280.99,93.16 v2(281.17,92.99)
  BOTTOM w0.109: JLED1.2 308.57,9.63 v2(308.67,9.54)
LID_CL#_PCH: length 1.2
  TOP w0.102: 233.63,106.59 233.63,106.66 T268.1
  TOP w0.109: 233.63,106.59 v2(233.63,106.29)
  BOTTOM w0.089: UH1.AV34 233.56,106.36 v2(233.63,106.29)
LID_CL_SIO#: length 14.1
  TOP w0.102: RE26.2 RE25.2 CE8.1 278.91,94.94 v2(278.52,94.55)
  TOP w0.109: UE1.N11 269.27,90.59 270.13,89.73 270.13,89.37 v2(270.13,89.36)
  BOTTOM w0.102: v2(270.13,89.36) 270.13,89.36 270.13,89.36 270.17,89.32 272.88,89.32 273.2,89.63 274.15,89.63 275.02,88.77 276.68,88.77 v2(278.13,90.22)
LINE1-VREFO: length 5.4
  TOP w0.203: UA1.24 v1(289.31,53.8) 289.62,53.49 290.32,53.49 v2(290.38,53.55)
  TOP w0.508: v2(292.48,48.16) 292.98,47.66 DA4.2 292.98,45.33 DA5.2
LINE1_L: length 3
  TOP w0.203: UA1.18 286.62,51.3 v1(287.21,50.71) 287.24,50.71 288.33,49.62 CA43.1
LINE1_R: length 2.6
  TOP w0.203: UA1.17 286.22,51.16 287.14,50.24 287.14,50.16 287.14,50.16 CA44.1
LM393_P: length 8
  TOP w0.254: PR735.2 v2(143.77,30.21) ; PR866.2 41.75,120.66 41.12,120.03 v2(41.07,120.03) ; v2(151.51,31.75) PU701.5 152.28,32.68 PC754.2
  BOTTOM w0.254: v2(82.1,111.92) 82.16,111.98 PD800.1 82.11,112.77 PC801.2 79.96,112.42 PU800.8
LOM_ACTLED_YEL#: length 6
  TOP w0.109: QL1.1 v1(289.15,115.49) 288.87,115.21 v2(288.65,115.21) ; v2(280.47,119.01) 280.41,119.01 279.84,118.44 279.84,118.09 278.84,117.08 277.95,117.08 277.76,116.9 UL1.26
LOM_CABLE_DETECT#: length 41.9
  TOP w0.109: RL20.1 294.37,114.96 v2(294.37,115.83) ; RE505.1 258.21,102.18 258.62,101.77 258.96,101.77 v1(258.99,101.74) 259.17,101.74 260.03,100.88 260.03,100.21 260.65,99.58 v2(260.65,99.08) 260.67,99.1 260.89,99.1 260.99,99 261.6,99 UE1.D2
  BOTTOM w0.102: v2(294.37,115.83) 294.37,115.83 294.06,115.51 289.62,115.51 289.52,115.62 287.05,115.62 284.46,113.03 284.46,105.04 283.26,103.83 276.02,103.83 275.94,103.76 271.51,103.76 271.23,104.03 v2(271.23,104.05)
LOM_CONNLED_GRN#: length 8.7
  TOP w0.109: RL29.2 RL20.2 292.29,114.46 QL1.4 291.45,114.19 v2(291.21,114.44) ; v2(279.33,118.24) 279.2,118.11 279.2,117.83 278.65,117.28 277.72,117.28 277.36,116.92 UL1.27
  BOTTOM w0.102: v2(291.21,114.44) 291.21,114.06 v1(289.62,112.47)
LOM_LED2: length 2.6
  TOP w0.109: T419.1 279.13,116.87 278.25,116.87 278.16,116.79 UL1.25
LPM_1VS_VCCIO: length 3.1
  BOTTOM w0.254: PU401.14 197.97,95.7 198.12,95.54 PR404.2 197.36,94.82 PR425.2 197.29,94.83 197.28,94.82 196.6,94.82 PR429.2
LPSS_UART2_RXD: length 14.1
  BOTTOM w0.089: 225.79,117.28 225.92,117.15 225.92,115.93 225.47,115.47 225.47,113.56 v1(225.67,113.36) 226,113.03 226,110.38 226.21,110.16 226.34,109.87 226.34,109.38 UH1.BD20
  BOTTOM w0.102: RH361.2 224.28,121.1 224.39,120.99 RH376.2 225.28,120.99 225.79,120.48 225.79,117.28
LSPCON_CLK: length 14.9
  TOP w0.109: v2(287.32,82.1) 285.59,82.1 284.97,81.48 UV32.6 RV618.1 ; UV31.D2 v2(293.4,85.34)
  BOTTOM w0.102: v2(293.4,85.34) 293.02,84.95 290.24,84.95 289.92,84.64 289.59,84.64 288.25,83.3 v1(287.52,83.3) 287.07,83.3 286.62,82.85 286.62,82.41 286.93,82.1 v2(287.32,82.1)
LSPCON_CS#: length 9
  TOP w0.109: v2(291.93,84.05) 292.12,84.05 UV31.C1 ; v2(290.4,79.57) 290.77,79.2 RV616.2 UV32.1
  BOTTOM w0.102: v2(290.4,79.57) 291.14,80.31 v1(291.14,81.04) 291.14,83.32 291.87,84.05 v2(291.93,84.05)
LSPCON_DI: length 13.1
  TOP w0.109: UV31.C2 v2(292.6,85.34) ; UV32.2 v2(287.8,80.21)
  BOTTOM w0.102: v2(292.6,85.34) 292.22,85.72 290.68,85.72 289.8,84.84 289.51,84.84 288.45,83.78 286.87,83.78 286.14,83.05 286.14,82.21 v1(287.01,81.34) 287.8,80.55 v2(287.8,80.21)
LSPCON_DO: length 10.9
  TOP w0.109: UV31.D1 293.22,84.36 v2(292.97,84.36) ; v2(287.02,82.66) 286.93,82.75 UV32.5
  BOTTOM w0.102: v2(287.02,82.66) 287.37,82.66 287.69,82.97 288.21,82.97 289.67,84.44 v1(291.31,84.44) 292.89,84.44 v2(292.97,84.36)
LSPCON_GPIO0: length 1.9
  TOP w0.109: UV31.C4 v2(292.6,86.94)
  BOTTOM w0.102: v1(292.35,86.43) 292.6,86.68 v2(292.6,86.94)
  BOTTOM w0.109: v2(292.6,86.94) 292.6,87.46 RV610.1
LSPCON_GPIO2: length 2.2
  TOP w0.109: UV31.E3 294.22,86.15 294.22,86.15 v2(294.21,86.15)
  BOTTOM w0.102: 294.21,86.15 294.21,86.14 v1(293.81,85.74)
  BOTTOM w0.109: RV611.1 294.21,86.15 v2(294.21,86.15)
LSPCON_GPIO4: length 1.4
  TOP w0.109: UV31.E7 294.76,89.74 295.01,89.98 v2(295.01,90.14)
  BOTTOM w0.102: v2(295.01,90.14) 295.18,90.31 T425.1
LSPCON_HOLD#: length 3.9
  TOP w0.102: RV617.2 282.32,79.9 281.88,79.46 281.88,78.3 v1(282.13,78.05)
  TOP w0.109: UV32.7 282.64,80.21 RV617.2
LSPCON_WP#: length 9.6
  TOP w0.109: v2(294.2,85.29) 294.2,85.34 UV31.E2 ; v2(291.69,81.82) 291.84,81.67 v1(291.84,81.29) 291.6,81.04 RV619.1 290.31,81.04 289.88,81.48 UV32.3
  BOTTOM w0.102: v2(291.69,81.82) 291.69,83.11 292.41,83.83 293.94,83.83 294.2,84.1 v2(294.2,85.29)
LX1_CHG:
  vias: v1(102.99,35.95) v2(103.39,35.57) v2(103.39,34.81) v2(122.91,40) v2(123.42,39.68)
LX1_IA: length 1.1
  TOP w0.102: v1(163.57,121.3) v2(162.68,121.3) 162.81,121.42
  vias: v2(162.05,121.3)
LX2_CHG:
  vias: v1(107.12,31.76) v2(103.56,31.32) v2(103.56,30.68) v2(104.2,31.32) v2(104.2,30.68) v2(104.83,31.32) v2(104.83,30.68) v2(105.37,35.33) v2(105.47,31.32) v2(105.47,30.68) v2(105.91,35.7) v2(105.91,35.06) v2(106.1,31.32) v2(106.1,30.68) v2(106.55,35.7) v2(106.55,35.06) v2(107.18,35.7) v2(107.18,35.06) v2(107.82,35.7) v2(107.82,35.06) v2(108.45,35.7) v2(108.45,35.06) v2(116.01,32.65) v2(116.04,32.01) v2(120.52,37.98) v2(120.96,37.54)
LX2_IA: length 1.3
  TOP w0.102: 172.59,122.44 v1(173.92,122.44)
  vias: v2(171.38,122.44) v2(172.02,122.44)
LX3_IA: length 1.5
  TOP w0.102: v1(179.89,121.42) PRH7.1
  vias: v2(180.91,122.37) v2(181.61,122.37)
LX4_IA:
  vias: v1(187.19,124.53) v2(192.91,124.03) v2(193.54,124.03)
LX_1.05VALWP:
  vias: v1(195.58,85.86) v2(193.62,85.61) v2(194.22,85.61) v2(197.96,85.55) v2(198.6,85.55)
LX_1.8VALW: length 0.9
  TOP w0.102: 226.94,78.24 v1(226.06,78.24)
LX_1VS_VCCIO: length 0.7
  BOTTOM w0.102: v1(191.13,99.9) 191.19,99.83 191.77,99.83
LX_3V: length 1
  TOP w0.102: v1(246.59,50.88) 246.72,50.75 247.52,50.75
  vias: v2(247.29,50.32) v2(247.29,49.73) v2(247.76,45.67) v2(247.74,45.03)
LX_5V: length 0.5
  TOP w0.102: v2(201.56,35.7) v1(201.04,35.7)
  vias: v2(196.96,34.94) v2(197.54,34.93) v2(201.8,35.13)
LX_DDR: length 1.5
  TOP w0.102: v1(169.54,38.94) 170.16,38.31 PC205.2
  vias: v2(169.48,36.59) v2(169.48,35.95)
LX_GT: length 1.6
  TOP w0.102: PRT4.1 v1(108.14,85.01)
  vias: v2(109.13,87.09) v2(109.16,86.47)
LX_SA: length 1.5
  TOP w0.102: PRA3.1 v1(198.5,109.36)
  vias: v2(198.05,111.77) v2(198.75,111.77)
M2280_DEVSLP: length 2.9
  TOP w0.109: RN37.2 273.64,22.3 273.54,22.4 v2(273.41,22.4)
  BOTTOM w0.089: UH1.AH35 233.26,101.84 v2(233.55,102.13)
  BOTTOM w0.109: v2(273.41,22.4) 273.58,22.24 JNGFF3.38
M2280_PCIE_SATA#: length 18.5
  BOTTOM w0.089: UH1.AJ43 237.42,101.74 237.42,100.11 237.61,99.92 237.97,99.92 237.98,99.93 241.77,99.93 242.04,99.65 RH317.2 RH318.2 243.95,99.65 244.85,98.75 v1(245.87,98.75) 246.08,98.75 v2(246.6,99.26)
  BOTTOM w0.109: v2(267.97,31) 267.97,27.68 267.73,27.44 266.56,27.44 265.82,28.18 JNGFF3.69
M3042_DEVSLP: length 9.3
  BOTTOM w0.089: v2(240.18,104.75) 240.07,104.75 239.86,104.95 239.43,104.95 UH1.AR47
  BOTTOM w0.109: JNGFF2.38 268.82,80.63 265.62,77.42 263.59,77.42 v2(263.53,77.36)
M3042_PCIE#_SATA: length 24.5
  TOP w0.109: RH344.2 245.33,103.5 v2(245.33,103.67) ; v2(271.42,93.8) 271.42,93.83 271.12,94.13 270.47,94.13 UE1.J12
  BOTTOM w0.089: 247.77,104.13 247.68,104.13 247.66,104.15 246.73,104.15 246.26,103.67 v2(245.33,103.67) 245.28,103.62 243.94,103.62 243.6,103.28 240.13,103.28 239.94,103.48 239.5,103.48 239.47,103.51 238.94,103.51 UH1.AM46
  BOTTOM w0.102: v2(258.85,107.58) 258.76,107.58 v1(258.03,106.85) 255.79,104.61 254.01,104.61 253.53,104.13 247.77,104.13
M_BIST: length 20.1
  TOP w0.102: RZ1415.2 263.71,81.86 v1(264.31,81.26) 265.11,80.46 v2(265.43,80.46)
  TOP w0.109: v2(266.84,90.7) 266.87,90.73 UE1.N8
  BOTTOM w0.102: v2(266.84,90.7) 266.5,90.7 265.83,90.03 265.83,89.6 266.89,88.54 266.89,87.7 267.46,87.13 267.46,86.42 267.24,86.21 264.82,86.21 264.33,85.72 264.33,85.3 263.71,84.68 263.71,81.54 264.79,80.46 v2(265.43,80.46)
M_BIST_R: length 7.4
  TOP w0.102: RZ1482.2 262.65,107.82 261.96,108.52 QZ21.2 261.3,108.52 v2(260.9,108.12) ; v2(263.36,85) 263.6,85 264.1,85.51 CZ218.1 264.12,85.19 263.71,84.78 RZ1415.1 263.6,84.24 DZ12.2 262.63,84.3 RZ1413.2
MASK_BASE_LEDS#: length 4.4
  TOP w0.102: v1(285.49,86.05) 285.49,85.61 284.79,84.91 QZ7.5 284.03,85.48 284.03,86.81 284.27,87.05 UZ10.4
ME_FWP: length 16.3
  TOP w0.109: UE1.G12 v2(270.47,96.53)
  BOTTOM w0.102: RH100.1 284.2,60.93 v1(278.51,60.93) 277.25,60.93 276.36,61.82 276.36,63.59 276.53,63.75 276.53,64.11 276.27,64.36 276.27,65.12 276.1,65.3 v2(276.09,65.3)
  BOTTOM w0.109: RH100.1 284.89,61.28 285,61.38 285,62.19 286.33,63.53 SW1.3
ME_FWP_PCH: length 7.8
  TOP w0.102: v2(218.07,130.23) 218.49,129.82 v1(218.49,128.79) RH328.1
  BOTTOM w0.109: RH100.2 284.54,62.33 285.23,63.01 285.23,63.49 v2(285.41,63.67) 285.55,63.82 285.55,63.89 286.19,64.53 SW1.2
ME_RESET#: length 2.4
  TOP w0.102: UC3.2 208.48,121.61 RH70.1 v1(208.47,122.69)
ME_SUS_PWR_ACK_R: length 6.1
  BOTTOM w0.089: UH1.BC37 234.46,109.28 234.41,109.33 234.41,109.45 234.34,109.53 234.34,110.47 234.31,110.51 234.31,112.08 234.04,112.35 234.04,113.12 233.88,113.28 233.88,114.34 234.16,114.62 T422.1
MEC_XTAL1: length 6.1
  TOP w0.109: UE1.A1 261.27,101.83 260.38,102.71 CE28.1 260.38,103.63 259.85,104.16 v1(259.85,104.28) 259.85,105.65 259.62,105.88 YE1.1
MEC_XTAL2: length 2.5
  TOP w0.109: RE290.2 262.82,104.36 CE29.1 262.79,105.25 262.68,105.25 262.04,105.88 YE1.2
MEC_XTAL2_R: length 2.4
  TOP w0.109: RE290.1 262.87,103.29 UE1.A3
MEDIACARD_IRQ#: length 4.1
  TOP w0.102: v2(291.23,26.11) v1(290.7,26.11)
  TOP w0.109: RR19.1 291.43,26.9 291.23,26.7 v2(291.23,26.11) 291.42,25.92 292.38,25.92 292.49,25.81 UR1.32
  BOTTOM w0.089: UH1.BB26 229.16,108.52 v2(229.59,108.08)
MEM_INTERLEAVED: length 13.1
  TOP w0.109: RH372.1 RH371.1 224.42,117.66 224.42,116.52 224.72,116.22 224.72,111.33 v1(225.01,111.04) 225.69,110.36 v2(225.69,107.51)
  BOTTOM w0.089: UH1.BA20 225.98,107.8 v2(225.69,107.51)
MEM_SMBCLK: length 15.1
  BOTTOM w0.089: UH1.BE26 229.16,110.02 229.24,110.1 229.24,110.41 229.16,110.48 229.13,110.51 229.13,111.46 229.4,111.74 229.4,117.02 228.79,117.64 228.79,119.05 228.79,119.39 v1(228.91,119.52) 228.91,120.53 229.33,120.95
  BOTTOM w0.109: 229.33,120.95 229.46,121.08 CC320.1 RH56.2 230.05,122.1 230.05,122.95 230.32,123.22 QH4.6
MEM_SMBDATA: length 15.3
  BOTTOM w0.089: 228.56,117.58 229.21,116.93 229.21,111.81 228.94,111.54 228.94,110.43 229,110.37 229,110.37 UH1.BF26
  BOTTOM w0.109: 228.56,117.58 228.56,120.88 v1(228.66,120.98) 229.05,121.37 RH57.2 229.05,122.45 229.17,122.57 229.17,124.26 228.9,124.52 QH4.3
MSCLK: length 9.9
  TOP w0.109: UE1.H10 268.85,94.95 v2(268.94,94.95)
  BOTTOM w0.102: RE30.1 v1(256.24,63.03)
  BOTTOM w0.109: RE30.1 256.48,64.29 259.92,64.29 260.5,64.87 v2(260.5,65.03) 260.5,66.07 JDEG1.6 260.48,66.09 260.48,66.72 RE72.2
MSDATA: length 7.7
  TOP w0.109: UE1.G9 v2(267.27,96.53)
  BOTTOM w0.109: RE75.2 258.64,67.42 259.04,67.42 259.99,66.47 JDEG1.7 259.99,65.47 259.31,64.79 v2(259.31,64.78) 256.35,64.78 RE86.1
NB_MODE#: length 1.1
  TOP w0.109: UE1.J6 v2(264.87,94.13)
  BOTTOM w0.109: T423.1 264.52,93.78 v2(264.87,94.13)
NB_MUTE#: length 8.5
  TOP w0.102: RA48.1 279.01,62.52 v1(279.01,63.89) 279.01,64.46 277.51,65.97 277.51,66.06 v2(277.43,66.13)
  TOP w0.109: v2(264.17,102.54) 264.03,102.4 264.03,101.42 263.67,101.07 UE1.A4 ; DA8.1 277.99,61.52 RA48.1
NB_PSID: length 4.2
  TOP w0.102: v2(53.59,125.23) 53.59,125.63 v4(54.24,126.27)
  BOTTOM w0.381: v2(68.64,127.38) 68.22,127.38 67.32,126.47 PJPDC1.1
Net_21: length 0.6
  BOTTOM w0.089: 225.21,104.8 224.91,104.8 v2(224.72,104.99)
NFC_ACTIVITY_STATUS#_R: length 4.2
  TOP w0.102: v1(223.52,37.35) 223.92,37.75 v2(223.92,37.85) 224.21,38.14 224.21,38.29 223.95,38.55 RZ1473.2
  BOTTOM w0.109: JUSH1.2 224.78,38.99 224.21,38.43 224.21,38.14 v2(223.92,37.85)
NGFF_CONFIG_0: length 7.9
  TOP w0.102: v2(264.13,73.54) 263.6,73.54 v1(263.04,72.97)
  TOP w0.109: RE725.1 270.19,87.17 269.64,87.72 v2(269.4,87.72) 268.96,88.16 268.96,89.86 267.67,91.14 UE1.N9
  BOTTOM w0.109: JNGFF2.21 264.58,73.87 264.24,73.54 v2(264.13,73.54)
NGFF_CONFIG_1: length 14.1
  TOP w0.109: UZ29.9 269.84,77.55 269.95,77.44 270.41,77.44 270.7,77.73 v1(273.17,77.73) 274.32,77.73 274.63,77.42 v2(275.42,77.42) ; UE1.M10 268.83,91.77 268.91,91.77 v2(268.92,91.77) 268.92,90.64 269.57,89.99 269.57,89.29 270.11,88.75 RE723.1
  BOTTOM w0.109: v2(275.42,77.42) 275.84,77.42 276.58,76.68 JNGFF2.69
NGFF_CONFIG_2: length 15.4
  TOP w0.102: v2(271.79,77.24) 271.86,77.24 271.96,77.14 273.08,77.14 273.2,77.01 276.2,77.01 v1(276.28,77.1) 277.11,77.1 278.17,78.16 v2(278.17,78.17) ; v2(269.43,88.32) 269.89,88.32 RE724.1
  TOP w0.109: v2(269.43,88.32) 269.31,88.43 269.31,89.8 268.47,90.64 UE1.N10
  BOTTOM w0.109: v2(278.17,78.17) 277.68,77.67 277.68,75.58 278.08,75.18 JNGFF2.75
NGFF_CONFIG_3: length 13.5
  TOP w0.102: RE726.1 253.31,96.48 253.53,96.7 v2(253.93,96.7)
  TOP w0.109: v2(263.27,97.25) 263.35,97.25 UE1.F4
  BOTTOM w0.102: v2(253.93,96.7) 254.84,96.7 256.65,98.52 v1(258.38,98.52) 258.99,98.52 260.6,96.91 260.89,96.91 260.9,96.9 262.92,96.9 v2(263.27,97.25)
  BOTTOM w0.109: v2(259.41,73.37) 259.41,73.56 259.58,73.73 JNGFF2.1
NRB_BIT: length 13.3
  BOTTOM w0.089: UH1.BE30 230.94,109.87 230.94,117.11 232.41,118.57 232.41,119.17
  BOTTOM w0.102: 232.41,119.17 232.41,119.37
  BOTTOM w0.109: 232.41,119.37 232.41,120.41 v1(232.85,120.85) 233.17,121.17 RH331.2
ONE_DIMM#: length 14.4
  TOP w0.102: RH268.1 229.8,121.77 229.8,122.06 230.14,122.4 RH267.1
  TOP w0.109: RH268.1 229.89,121.52 230.12,121.3 230.48,121.3 231.2,120.57 231.2,119.08 231.2,119.07 v1(231.2,118.75) 231.2,118.63 231.09,118.52 v2(230.75,118.52)
  BOTTOM w0.089: v2(230.75,118.52) 231.11,118.52 231.2,118.43 231.2,117.64 230.72,117.15 230.72,111.14 230.34,110.77 UH1.BF29
OTGEN/CMIN_CHG: length 3.8
  TOP w0.203: v2(128.13,36.7) 128.35,36.7 128.68,37.03 PR709.2 PR746.2
  TOP w0.254: PR712.2 v2(139.38,34.47)
  BOTTOM w0.203: v2(128.13,36.7) 127.97,36.7 127.78,36.89 126.87,36.89 PU700.20
OTGPG/CMOUT_CHG: length 5.2
  BOTTOM w0.203: PU700.26 125.75,34.24 126.4,33.59 v1(127.76,33.59) 128.55,33.59 PR745.2 128.69,33.7 PR727.2 128.74,33.02 PR726.2
PANEL_BKEN_EC: length 1.5
  TOP w0.107: v2(141.56,134.12) 141.56,135.04 DV2.2
  TOP w0.109: UE1.J9 267.75,94.53 268,94.28 v2(268,94.12)
PANEL_BKEN_PCH: length 1.4
  TOP w0.107: v2(140.26,134.12) 140.26,135.04 DV2.3
  BOTTOM w0.089: v2(238.11,106.33) 238.11,106.33 238.13,106.32 238.56,106.32 UH1.AV46
PANEL_MONITOR: length 9
  TOP w0.102: v2(128.43,123.57) v1(128.43,121.87) 128.43,120.18 129.61,119 RV628.2
  TOP w0.109: v2(266.88,90) 267.28,90.4 267.28,91.72 UE1.M8
PANEL_PWRGD: length 1
  TOP w0.102: RV628.1 v1(130.12,119.91)
PBAT_CHARGER_SMBCLK: length 31.2
  TOP w0.102: v2(132.77,35.54) PD2.3 135.86,35.33 PR38.2 137.35,35.33 138.79,36.78 140.5,36.78 143.14,39.42 143.14,41.5 142.4,42.24 v1(138.55,42.24) 138.08,41.77 136.37,41.77 134.04,44.09 v2(134.04,44.27)
  TOP w0.109: UE1.N2 262.07,90.98 261.2,90.11 v2(261.2,89.55) 261.2,89.11 RE43.1
  BOTTOM w0.102: v2(132.77,35.54) 132.39,35.15 130.15,35.15 129.97,35.33 PR715.1
PBAT_CHARGER_SMBDAT: length 32.7
  TOP w0.102: v2(133.35,44.27) 133.46,44.27 133.56,44.17 133.56,43.89 136.17,41.29 139.31,41.29 v1(139.76,41.73) 139.78,41.76 142.2,41.76 142.65,41.3 142.65,39.62 140.3,37.26 138.59,37.26 137.44,36.11 PR39.2 136.07,36.63 PD1.2 133.08,36.63 v2(132.08,35.63)
  TOP w0.109: UE1.M3 262.49,91.75 261.95,91.75 261.69,91.49 261.69,91.24 260.93,90.47 260.93,89.82 260.65,89.54 v2(260.62,89.54) 260.42,89.34 260.42,89.33 260.17,89.08 RE37.1
  BOTTOM w0.102: PR713.1 130.06,36.09 130.52,35.63 v2(132.08,35.63)
PBAT_PRES#: length 15.4
  TOP w0.109: UE1.F9 268.08,97.33 v2(268.16,97.33)
  TOP w0.254: PR724.1 128.32,31.9 128.84,31.38 129.6,31.38 131.44,33.22 131.44,35.7 v1(132.74,37) 134.17,38.43 v2(134.17,38.5) 134.45,38.5 135.29,37.67 135.62,37.67 PD1.3 135.81,37.8 PR1.2 136.08,38.74 PR40.2
PBAT_PRES#_C: length 8.2
  TOP w0.102: v2(141.26,41.02) 141.26,39.68 139.95,38.36 v4(139.63,38.36) 139.09,37.82 PR40.1
  BOTTOM w0.102: PBATT1.6 v2(141.26,41.02)
PBAT_SMBCLK_C: length 12.8
  TOP w0.102: v2(143.63,40.97) 143.63,39.13 v4(141.79,37.28) 140.8,36.29 138.99,36.29 137.11,34.41 PR38.1
  BOTTOM w0.102: v2(143.63,40.97) 143.89,40.97 144.26,41.34 PBATT1.4
PBAT_SMBDAT_C: length 9.5
  TOP w0.102: v2(142.2,40.99) 142.2,40.1 v4(141.66,39.57) 139.61,37.51 137.98,37.51 137.49,37.02 PR39.1
  BOTTOM w0.102: v2(142.2,40.99) 142.76,41.56 PBATT1.5
PCH_2_CPU_TRIGGER: length 14.3
  TOP w0.102: v2(205.89,104.86) 205.9,104.85 207.95,104.85 RH42.2
  BOTTOM w0.076: v2(170.93,99) 169.57,99 169.25,99.32 UC1.H23
  BOTTOM w0.102: v2(203.48,96.15) 203.29,96.35 203.29,96.38 203,96.66 203,102.25 205.62,104.86 v2(205.89,104.86)
PCH_2_CPU_TRIGGER_R: length 10.9
  TOP w0.102: v1(210.12,104.59) 209.74,104.97 v2(209.74,105.1)
  TOP w0.109: RH42.1 209.08,105.07 209.72,105.07 v2(209.74,105.1)
  BOTTOM w0.089: 210.09,105.06 210.62,104.52 210.62,104.28 211.06,103.84 213.28,103.84 214.6,102.52 217.14,102.52 217.23,102.61 217.65,102.61 217.73,102.52 UH1.AK3
  BOTTOM w0.102: 210.09,105.06 210.07,105.07
  BOTTOM w0.109: v2(209.74,105.1) 209.77,105.07 210.07,105.07
PCH_3.3V_TS_EN: length 2.3
  TOP w0.102: v2(110.8,130.06) 111.06,130.32 RV324.1
  BOTTOM w0.089: UH1.BD30 230.74,109.12 230.94,108.91 231.39,108.91 v2(231.58,108.72)
PCH_BATLOW#: length 5.9
  TOP w0.109: v2(238.79,113.99) 239.42,114.61 239.42,114.77 RH94.1
  BOTTOM w0.089: 239.26,113.15 239.26,112.66 238.14,111.54 238.14,110.83 237.87,110.56 UH1.BF44
  BOTTOM w0.102: 239.26,113.15 239.26,113.32
  BOTTOM w0.109: v2(238.79,113.99) 239.15,113.99 239.26,113.88 239.26,113.32
PCH_CL_CLK1: length 4.3
  BOTTOM w0.089: UH1.AR2 217.28,105.39 217.19,105.48 217.04,105.48 216.72,105.16 215.76,105.16 215.7,105.1 215.46,105.1 v2(215.41,105.06)
  BOTTOM w0.102: v2(282.44,39.25) 282.95,39.76 JNGFF1.42
PCH_CL_DATA1: length 5.3
  BOTTOM w0.089: UH1.AT5 218.31,105.64 218.28,105.61 217.34,105.61 217.27,105.67 216.96,105.67 216.72,105.43 214.93,105.43 214.78,105.58 v2(214.78,105.67)
  BOTTOM w0.102: v2(282.45,39.89) JNGFF1.40
PCH_CL_RST1#: length 2.7
  BOTTOM w0.089: UH1.AU4 218.29,105.86 218.4,105.97 218.65,105.97 v2(218.77,106.09)
  BOTTOM w0.102: v2(281.49,39.25) 281.95,39.71 JNGFF1.38
PCH_CPU_BCLK_D: length 11.4
  BOTTOM w0.089: 213.99,83.23 v3(214.52,83.23) 214.96,83.23 215.59,83.86 215.63,83.86 216.26,84.49 216.26,85.09 216.32,85.14 217.59,86.41 217.71,86.41 217.82,86.31 217.94,86.31 218.07,86.43 218.07,86.56 217.97,86.66 217.97,86.79 218.23,87.05 219.03,87.05 219.93,87.96 219.93,88.47 220.01,88.55 UH1.B8
  BOTTOM w0.094: 213.99,83.23 213.54,83.23 213.12,82.81 213.12,82.68 RH161.2
PCH_CPU_BCLK_D#: length 11.4
  BOTTOM w0.089: 213.99,83.42 214.16,83.42 214.18,83.44 214.91,83.44 v3(215.7,84.24) 216.07,84.6 216.07,85.16 216.19,85.28 218.15,87.25 218.95,87.25 219.74,88.03 219.74,88.55 219.77,88.59 219.77,89 219.98,89.2 UH1.C8
  BOTTOM w0.094: 213.99,83.42 213.46,83.42 212.94,82.89 212.94,82.6 213,82.54 RH166.2
PCH_CPU_BCLK_R_D: length 6.3
  BOTTOM w0.076: UC1.B31 173.57,105.64 173.69,105.76 175.8,105.76 176.05,106.01 176.3,106.01 176.32,105.99 176.34,105.99
  BOTTOM w0.094: v2(213.36,80.58) 213.2,80.74 213.2,80.99 RH161.1 ; 176.34,105.99 177.1,105.99 177.5,106.39 177.5,106.96 v2(177.62,107.07)
PCH_CPU_BCLK_R_D#: length 6.3
  BOTTOM w0.076: UC1.A32 173.85,106 173.93,105.93 174.21,105.93 174.29,106 174.29,106.14 174.36,106.22 174.51,106.22 174.59,106.14 174.59,106 174.67,105.93 174.88,105.93 174.96,106 174.96,106.14 175.04,106.22 175.19,106.22 175.27,106.14 175.27,106 175.34,105.93 175.73,105.93 175.98,106.17 176.3,106.17 176.32,106.19 176.34,106.19
  BOTTOM w0.094: 176.34,106.19 177.03,106.19 177.32,106.48 177.32,106.79 v2(177.03,107.07) ; v2(212.78,80.58) 213.01,80.81 213.01,81.05 RH166.1
PCH_CPU_NSSC_CLK_D: length 12.4
  BOTTOM w0.089: 213.99,84.13 v3(214.45,84.59) 215.81,85.96 216.6,85.96 218.07,87.44 218.87,87.44 219.52,88.09 219.52,88.61 219.55,88.63 219.55,89.05 219.65,89.16 219.65,89.43 UH1.D7
  BOTTOM w0.094: 213.99,84.13 213.87,84.02 213.21,84.02 212.33,83.13 211.8,83.13 211.7,83.04 RH169.2
PCH_CPU_NSSC_CLK_D#: length 12.4
  BOTTOM w0.089: UH1.C6 219.28,89.28 219.21,89.21 219.21,89.08 219.36,88.93 219.36,88.71 219.33,88.68 219.33,88.17 218.79,87.63 217.99,87.63 216.52,86.15 215.73,86.15 214.52,84.94 214.49,84.94 214.1,84.55 214.1,84.52 213.97,84.39 213.97,84.39 213.86,84.28
  BOTTOM w0.094: 213.86,84.28 213.79,84.21 213.1,84.21 v3(212.85,83.96) 212.2,83.32 211.72,83.32 211.52,83.12 211.52,82.85 211.26,82.59 211.16,82.59 210.88,82.32 RH170.2
PCH_CPU_PCIBCLK_D: length 13.1
  BOTTOM w0.089: UH1.A6 219.07,88.18 218.71,87.82 217.62,87.82 217.48,87.68 217.48,87.56 217.51,87.53 217.51,87.41 217.38,87.28 217.25,87.28 217.23,87.3 217.11,87.3 216.98,87.18 216.98,87.05 217,87.03 217,86.91 216.88,86.78 216.75,86.78 216.73,86.8 216.6,86.8 216.24,86.44 215.28,86.44 214.15,85.31 213.81,85.31 213.34,84.83
  BOTTOM w0.094: 213.34,84.83 213.31,84.83 212.73,84.79 211.9,83.96 v3(211.32,83.96) 210.81,83.96 210.16,83.31 209.97,83.31 209.55,82.9 209.55,82.75 RH167.1
PCH_CPU_PCIBCLK_D#: length 13.2
  BOTTOM w0.089: 213.13,85.02 213.25,85.02 213.73,85.5 214.07,85.5 215.2,86.63 216.16,86.63 217.54,88.01 218.63,88.01 218.81,88.19 218.81,88.46 219.07,88.73 UH1.B6
  BOTTOM w0.094: RH168.1 209.23,82.88 v3(209.55,83.2) 209.85,83.5 210.09,83.5 210.76,84.18 211.86,84.18 212.7,85.02 213.13,85.02
PCH_CPU_PCIBCLK_R_D: length 1.6
  BOTTOM w0.094: RH167.2 209.69,80.98 209.69,80.71 v2(209.87,80.53) ; UC1.D35 172.09,107.97 172.36,107.97 v2(172.46,107.87)
PCH_CPU_PCIBCLK_R_D#: length 1.6
  BOTTOM w0.094: v2(209.29,80.53) 209.51,80.75 209.51,81.06 RH168.2 ; v2(171.92,108.34) 171.94,108.36 UC1.C36
PCH_DP1_CTRL_CLK: length 6.6
  TOP w0.109: v2(222.92,103.46) 222.49,103.89 v1(221.99,103.89) 221.1,103.89 220.29,104.71 217.5,104.71 RH222.1
  BOTTOM w0.089: UH1.AL13 222.81,103.37 222.9,103.46 v2(222.92,103.46)
PCH_DP1_CTRL_DATA: length 3.9
  TOP w0.109: RH223.1 217.88,105.17 v1(218.37,105.17) 219.72,105.17 220.2,105.64 v2(220.2,105.73)
  BOTTOM w0.089: v2(220.2,105.73) 220.2,105.59 219.96,105.36 UH1.AR8
PCH_DP1_HPD: length 3.9
  TOP w0.102: v2(47.08,113.63) 46.99,113.72 RT24.1
  BOTTOM w0.076: UT1.AA2 46.33,111.74 46.33,111.84 46.35,111.86 46.35,112.15 46.48,112.27 46.53,112.27 47.08,112.81
  BOTTOM w0.089: v2(219.58,105.57) 219.58,105.46 219.41,105.3 UH1.AT6
  BOTTOM w0.107: 47.08,112.81 v2(47.08,113.63)
PCH_DP2_CTRL_DATA: length 5
  TOP w0.109: RH221.1 217.94,102.56 220.4,102.56 v1(220.58,102.74) 221.11,103.27 221.11,103.51 v2(221.11,103.51)
  BOTTOM w0.089: UH1.AL10 221.29,103.33 v2(221.11,103.51)
PCH_DP2_HPD: length 3.2
  TOP w0.102: RT29.1 48.13,109.42
  TOP w0.107: 48.13,109.42 47.81,109.1 v1(47.81,108.91) 47.81,108.27 v2(47.81,108.27)
  BOTTOM w0.089: v2(220.93,105.04) 221.17,104.8 221.17,104.76 221.29,104.64 UH1.AN10
  BOTTOM w0.102: v2(45.52,109.19) 45.53,109.19 45.86,109.52 UT1.Y6
PCH_DP3_CTRL_CLK: length 4.4
  TOP w0.109: RH224.1 218.17,104.5 220.05,104.5 220.38,104.18 220.38,104.15 v1(220.38,104.14) 220.41,104.14 220.55,104 220.55,103.68 v2(220.55,103.68)
  BOTTOM w0.089: v2(220.55,103.68) 220.55,103.68 UH1.AL9
PCH_DP3_CTRL_DATA: length 14.8
  TOP w0.109: RH225.1 210.1,111.76 209.47,111.12 v2(209.47,111.03)
  BOTTOM w0.089: 210.09,109.56 211.01,108.64 211.01,107.75 213.14,105.61 214.04,105.61 214.97,104.68 216.17,104.68 216.46,104.97 218.18,104.97 218.29,105.07 218.29,105.23 218.18,105.33 217.88,105.33 UH1.AR3
  BOTTOM w0.109: 210.09,109.56 209.47,110.17 v2(209.47,111.03)
PCH_DP3_HPD: length 55.9
  TOP w0.109: RV603.1 290.73,82.05 287.96,82.05 287.53,81.61 286.07,81.61 285.94,81.47 v1(285.94,77.61) 285.94,77.08 286.38,76.63 286.38,75.96 v2(286.19,75.77)
  BOTTOM w0.089: UH1.AP9 220.55,105.44 220.86,105.75 222.38,105.75 222.69,106.06 223.13,106.06 223.17,106.09 v2(223.36,106.09)
  BOTTOM w0.102: v2(286.19,75.77) 286.19,74.53 282.74,71.07 281.41,71.07 arc(280.37,70.87) 279.49,70.28 278.32,69.11 275.58,69.11 274.92,69.77 271.86,69.77 270.82,70.81 268.47,70.81 265.97,68.31 265.35,68.31 264.15,67.11 264.15,65.35 262.53,63.74 262.53,62.97 261.15,61.59 255.6,61.59 v2(255.05,62.14)
PCH_DP3_HPD_R: length 3.7
  TOP w0.102: RV603.2 v1(291.9,82.8)
  TOP w0.109: UV31.B1 290.9,83.63 RV603.2
PCH_DPWROK: length 10.6
  TOP w0.102: RE536.1 283.5,97.48 283.66,97.32 v2(283.66,97.28)
  TOP w0.109: v2(236,119.77) 235.53,119.3 CH558.1 ; RH215.1 241.45,112.8 RH308.1 CH266.1 239.38,112.41 239.07,112.41 238.88,112.21 238.88,111.52 237.18,109.81 237.18,108.99 236.65,108.45 236.65,107.82 v2(236.55,107.73)
  BOTTOM w0.089: v2(236.55,107.73) 236.51,107.73 236.29,107.51 UH1.AW41
PCH_DPWROK_EC: length 16.1
  TOP w0.102: RE536.2 282.02,97.51 281.41,97.51 281.27,97.64 281.27,97.65 v2(281.27,97.65)
  TOP w0.109: v2(267.27,97.25) 267.2,97.25 UE1.F8
  BOTTOM w0.102: v2(281.27,97.65) 281.19,97.73 280.34,97.73 279.9,97.29 278.27,97.29 278.13,97.43 277.31,97.43 276.86,96.97 v1(273.87,96.97) 273.05,96.97 272.82,96.75 270.79,96.75 270.63,96.91 267.65,96.91 267.31,97.25 v2(267.27,97.25)
PCH_HDD_EN: length 8.6
  BOTTOM w0.089: UH1.BD21 226.65,109.54 226.83,109.72 226.83,110.61 227.07,110.85 227.07,111.12 226.82,111.36 226.82,116.11 226.4,116.53
  BOTTOM w0.109: RH625.1 226.31,116.62 v1(226.35,116.58) 226.4,116.53
PCH_INTRUDER_HDR#: length 5.9
  TOP w0.109: RH198.2 242.49,109.67 v1(241.1,109.67) 240.41,109.67 240.28,109.8 239.37,109.8 238.18,108.61 v2(238.18,108.42)
  BOTTOM w0.089: v2(238.18,108.42) 238.11,108.35 UH1.BB44
PCH_JTAG_TCK: length 10.7
  TOP w0.109: v2(212.98,102.72) 214.6,102.72 T188.1 215.15,102.17 RH313.1
  BOTTOM w0.089: UH1.AJ3 217.79,101.95 214.32,101.95 213.54,102.72 212.98,102.72 v2(212.98,102.72)
  BOTTOM w0.102: RC843.1 207.75,80.97 207.75,82.02 v2(207.79,82.05)
PCH_JTAG_TCK_XDP: length 110.3
  BOTTOM w0.102: v2(117.85,95.7) 117.85,94.05 118.42,93.48 118.53,93.48 123.39,88.62 126.74,88.62 127.45,87.91 127.45,76.78 130.84,73.39 177.45,73.39 183.4,79.34 186.29,79.34 186.93,79.98 201.09,79.98 201.96,79.11 205.89,79.11 RC843.2 ; v2(92.96,135.62) 92.41,135.08 JXDP1.55
PCH_JTAG_TDI: length 138
  TOP w0.102: T187.1 208.08,102.94 208.08,103.34 207.98,103.44 207.89,103.44 ; RC229.2 119.67,103.58 v2(119.65,103.55)
  TOP w0.109: 207.89,103.44 v2(207.79,103.44) 207.31,102.97 207.31,102.02 RH314.1 CC304.1
  BOTTOM w0.089: UH1.AH2 216.83,101.51 216.78,101.56 214.16,101.56 213.65,102.08 212.64,102.08 211.7,103.01 210.32,103.01 210.13,102.82 210.08,102.82
  BOTTOM w0.102: v2(206.94,87.8) 206.94,87.33 207.21,87.06 207.21,83.36 207.19,83.34 207.19,82.87 206.85,82.53 206.85,81.65 205.91,80.71 186.68,80.71 186,80.03 183.12,80.03 177.16,74.07 131.12,74.07 128.13,77.06 128.13,88.77 127.59,89.31 123.67,89.31 118.77,94.22 118.77,101.97 118.52,102.21 118.52,103.03 118.88,103.39 119.48,103.39 v2(119.65,103.55)
  BOTTOM w0.109: v2(207.79,103.44) 207.79,103.18 208.15,102.82 210.08,102.82
PCH_JTAG_TDO: length 134.8
  TOP w0.102: v2(119.8,102.58) 119.81,102.56 RC230.2 ; v2(206.54,88.23) v4(206.54,88.79)
  BOTTOM w0.089: 210.08,103.05 210.22,103.2 212.15,103.2 T186.1 212.59,102.75 212.59,102.41 212.72,102.28 213.72,102.28 214.24,101.75 217.39,101.75 217.6,101.54 UH1.AH3
  BOTTOM w0.102: v2(206.54,88.23) 206.53,88.21 206.53,87.42 206.97,86.98 206.97,83.44 206.96,83.43 206.96,82.96 206.62,82.63 206.62,81.92 205.64,80.93 186.59,80.93 185.91,80.25 183.02,80.25 177.12,74.35 131.16,74.35 128.36,77.16 128.36,88.87 127.69,89.54 123.77,89.54 118.99,94.31 118.99,101.83 119.74,102.58 v2(119.8,102.58)
  BOTTOM w0.109: v2(207.2,103.5) 207.36,103.66 207.36,103.87 207.64,104.15 RH315.1 208.28,104.15 208.58,103.85 CC303.1 209.05,103.05 210.08,103.05
PCH_JTAG_TMS: length 141.1
  TOP w0.102: RC228.2 v2(118.13,101.55)
  TOP w0.109: RH312.1 208.51,104.09 208.64,103.96 T183.1 209.19,104.18 v2(209.75,104.18)
  BOTTOM w0.089: UH1.AJ4 218.04,102.25 217.64,102.25 217.53,102.14 214.44,102.14 213.11,103.46 210.75,103.46 210.08,104.12
  BOTTOM w0.102: v2(118.13,101.55) 118.28,101.39 118.28,94.05 123.48,88.85 127.36,88.85 127.67,88.54 127.67,76.87 130.93,73.62 177.35,73.62 183.31,79.57 186.19,79.57 186.84,80.21 201.42,80.21 202.24,79.39 205.38,79.39 207.34,81.35 207.34,82.38 207.65,82.68 207.65,83.15 207.85,83.35 207.85,87.57 206.37,89.05 206.37,90.18 v2(207.09,90.9)
  BOTTOM w0.109: 210.08,104.12 209.93,104.12 209.88,104.18 v2(209.75,104.18)
PCH_JTAGX: length 124
  TOP w0.102: v2(119.95,98.7) 120.79,98.7 120.89,98.8 RC143.2 120.89,99.83 121.8,100.75 RC166.2
  BOTTOM w0.089: 210.08,102.31 210.18,102.31 210.51,102.64 T182.1 211.2,102.64 CC305.1 212.99,101.67 213.58,101.08 216.8,101.08 216.99,101.27 217.88,101.27 218.07,101.46 UH1.AH4
  BOTTOM w0.102: v2(119.95,98.7) 120.07,98.82 120.95,98.82 121.6,99.47 124.48,99.47 124.58,99.36 124.58,97.5 128.42,93.66 128.42,91.99 129.69,90.72 129.69,89.26 129.08,88.65 129.08,77.45 131.46,75.06 176.83,75.06 182.73,80.97 185.4,80.97 186.08,81.65 204.82,81.65 206.37,83.2 v2(206.37,83.7) ; 210.08,102.31 209.91,102.31 v2(209.85,102.37)
PCH_PCIE_WAKE#: length 15
  TOP w0.109: v2(257.19,91.39) 258.48,91.39 RE274.2 259,91.83 260.08,91.83 261.18,92.93 UE1.L1
  BOTTOM w0.089: UH1.BB47 239.94,108.96 240.1,108.79 240.48,108.79 240.73,109.05 241.3,109.05 242.66,110.4 242.66,112.97
  BOTTOM w0.102: RT445.1 34.32,121.61 v2(34.36,121.66)
  BOTTOM w0.109: v2(244.41,115.26) 243.64,115.26 243.51,115.12 RH92.1 243.45,114.88 242.66,114.08 242.66,112.97
PCH_PECI: length 11.4
  BOTTOM w0.089: 210.13,101.55 v1(210.14,101.54) 210.31,101.37 210.31,100.97 210.57,100.72 211.22,100.72 211.31,100.81 212.81,100.81 212.92,100.7 216.96,100.7 217.1,100.83 UH1.AF2
  BOTTOM w0.102: 210.13,101.55 210.05,101.55
  BOTTOM w0.109: RH73.1 207.72,101.8 RH74.1 208.57,102.24 209.37,102.24 210.05,101.55
PCH_PLTRST#: length 18.2
  TOP w0.102: RH62.2 226.89,133.36 227.17,133.08 v2(227.17,132.66)
  TOP w0.109: UH7.2 UH7.1 227.2,131.2 226.98,130.99 CH552.1 RH635.1 v1(226.18,132.09) 226.18,132.22 226.77,132.8 RH62.2
  BOTTOM w0.089: UH1.AV29 230.51,106.29 v2(231.03,106.29)
  BOTTOM w0.102: v2(227.17,132.66) 226.75,132.66 225.59,131.5 225.59,128.27 226.06,127.8 226.06,127.39 226.63,126.82 229.17,126.82 230,125.98 v2(230,125.11)
PCH_PLTRST#_AND: length 26
  TOP w0.089: 290.25,25.22 290.51,25.22 290.8,24.92 UR1.1
  TOP w0.102: v2(230.59,125.11) 230.59,125.13 230.6,125.14 230.6,130.54 231.04,130.98 231.04,132.17 230.09,133.12 ; v2(273.05,71.69) 273.06,71.68 RZ1481.2 ; v2(272.45,67.83) 272.86,67.83 272.93,67.9 UZ52.A1 ; 290.25,25.22 v2(289.56,25.22) ; v2(223.14,133.47) 223.14,133.81 223.43,134.1 RH187.2 229.05,133.11 UH7.4
  TOP w0.109: 230.09,133.12 RH65.1 230.04,133.1 UH7.4
  BOTTOM w0.102: v2(110.04,132.64) 110.23,132.83 JIRTS1.1 ; v2(34.15,125.05) 34.09,125.05 33.68,124.65 RT499.1 RT502.1
  BOTTOM w0.109: JNGFF1.52 285.45,39.99 285.56,39.88 v2(285.69,39.88) ; JNGFF3.50 270.58,22.18 v2(270.76,22.36)
PCH_PRIM_EN: length 165.5
  TOP w0.102: PR504.1 226,74.57 225.76,74.32 v2(225.74,74.32) ; v2(250.33,112.15) 250.63,112.15 251.14,111.64 RH441.2 251.91,111.31 RH442.2 ; v2(256.17,56.18) 256.17,55.84 256.27,55.74 v1(256.66,55.74) 260.77,55.74 260.88,55.64 RZ64.1
  TOP w0.254: v2(197.04,89.42) 197.1,89.35 197.1,88.35 PR312.1
  BOTTOM w0.102: v2(248.92,89.1) 248.6,89.1 248.04,88.54 248.04,86.17 246.69,84.82 246.69,83.45 247.12,83.02 247.12,81.4 246.19,80.46 240.58,80.46 239.94,79.82 238.81,79.82 234,75 226.44,75 225.76,74.32 v2(225.74,74.32) 225.5,74.56 220.14,74.56 216.91,77.8 v2(216.59,77.8) ; v2(206.18,82.05) 205.3,81.16 186.49,81.16 185.81,80.48 182.93,80.48 177.03,74.58 131.26,74.58 128.59,77.25 128.59,82.29
  BOTTOM w0.109: 128.59,82.29 128.59,88.96 127.79,89.77 123.86,89.77 119.23,94.41 119.23,97.3 120.23,98.31 UZ34.1
PCH_PWROK: length 6.6
  TOP w0.102: RH424.1 239.1,108.72 CH553.1
  TOP w0.109: v2(237.04,108.06) 237.07,108.09 237.68,108.09 237.87,107.9 CH553.1
  BOTTOM w0.089: v2(237.04,108.06) 237,108.02 UH1.AY42
  BOTTOM w0.109: PUZ1.45 98.75,100.71 v2(98.5,100.95) 98.31,101.14 PRZ20.2
PCH_RSMRST#: length 15.5
  TOP w0.102: v2(263.36,86.18) 263.46,86.28 RE342.1 263.34,86.87 262.63,86.15 RZ1413.1
  TOP w0.109: v2(262.92,58.82) 262.4,58.3 258.31,58.3 258.03,58.02 256.85,58.02 RZ400.1 ; UE1.M5 264.03,91.68 264.03,90.22 262.81,88.99 v1(262.81,88.89) 262.81,87.04 262.48,86.72 262.48,86.28 RZ1413.1
PCH_RSMRST#_AND: length 18.5
  TOP w0.109: UZ6.4 v2(260.28,56.23) ; RH215.2 241.49,114.46 CC556.1 242.67,114.91 RC75.1 242.83,115.07 243.91,115.07 v2(244.34,114.64)
  BOTTOM w0.089: 243.15,112.97 243.15,112.79 242.85,112.49 242.85,110.27 241.42,108.85 241.42,108.61 241.09,108.27 240.62,108.27 240.49,108.4 239.96,108.4 239.9,108.45 239.49,108.45 UH1.BA47
  BOTTOM w0.102: RC841.1 254.32,68.63 255.41,68.63 255.52,68.74 255.52,69.04 v2(255.65,69.18)
  BOTTOM w0.109: v2(244.34,114.64) 244.19,114.64 244.17,114.62 243.95,114.62 243.15,113.81 243.15,112.97
PCH_RSMRST#_AND_XDP: length 200.9
  TOP w0.102: v2(90.48,112.34) 90.48,112.81 85.2,118.1 85.2,127.41 83.7,128.91 83.7,131.54 84.07,131.91 84.07,133.04 T191.1 84.54,133.52 RC124.1
  BOTTOM w0.102: RC841.2 252.04,66.36 252.04,66.09 249.66,63.7 235.8,63.7 234.44,65.06 227.94,65.06 225.23,62.35 164.72,62.35 164.62,62.25 164.62,59.26 162.6,57.24 156.8,57.24 151.58,62.45 104.88,62.45 98.17,69.16 98.17,75.62 96.74,77.04 96.74,77.97 96.9,78.13 v2(96.9,78.39)
PCH_RTCRST#: length 9
  TOP w0.102: RE94.2 v2(267.95,109.31) ; RH200.2 CH40.2 243.99,108.51 CMOS1.2 ; JAPS1.9 226.06,33.03 226.18,33.16 v2(226.18,33.72)
  TOP w0.109: v2(239.57,109.36) 239.57,109.36 239.83,109.1 241.49,109.1 241.5,109.09 242.62,109.09 CMOS1.2
  BOTTOM w0.089: UH1.BE47 239.33,109.61 239.57,109.37 v2(239.57,109.36)
PCH_RTCX1: length 6.9
  BOTTOM w0.089: UH1.BA49 240.35,107.89 241.39,107.89 243.74,110.24 v1(243.74,110.56) 243.74,110.85
  BOTTOM w0.109: 243.74,110.85 243.74,111.47 RH44.1 RH43.2
PCH_RTCX1_R: length 3
  BOTTOM w0.109: RH43.1 CH4.2 247,112.67 247.2,112.47 YH1.1
PCH_RTCX2: length 12
  BOTTOM w0.089: UH1.BA48 240.09,108.17 240.13,108.21 240.41,108.21 240.54,108.08 241.22,108.08 241.74,108.6 241.74,108.85 243.13,110.24 243.13,111.78 243.39,112.04
  BOTTOM w0.109: YH1.2 247.2,113.71 247.02,113.54 CH5.2 244.59,113.54 v1(244.53,113.6) 244.52,113.58 244.25,113.58 244.03,113.36 RH44.2 243.39,112.04
PCH_SMB_ALERT#: length 10.3
  BOTTOM w0.089: UH1.BE25 228.22,110.19 228.22,111.72 228.3,111.8 228.3,114.16 227.87,114.59 227.87,115.9 227.78,115.99 227.58,115.99 227.31,116.25 227.31,117.17 227.43,117.28
  BOTTOM w0.102: 227.43,117.28 227.64,117.5
  BOTTOM w0.109: RH61.2 227.1,118.92 227.64,118.37 v1(227.64,117.87) 227.64,117.5
PCH_SPI_CLK: length 21
  TOP w0.102: v2(236.81,133.36) 236.85,133.32 236.85,131.35 v1(236.48,130.99) 235.78,130.28 235.78,125.75 235.74,125.71 235.74,125.71 v2(235.74,125.71)
  BOTTOM w0.089: UH1.AW47 239.32,106.92 239.4,107 239.76,107 239.8,106.96 239.81,106.96 239.87,106.9 239.91,106.9 240.66,106.14 242.22,106.14 242.9,106.82 242.9,107.1 243.46,107.67 244.58,107.67 RH634.1 244.69,107.99 244.99,108.29 v2(244.99,108.47)
  BOTTOM w0.102: v2(236.81,133.36) JSPI1.13
  BOTTOM w0.109: RH181.2 236.98,128.55 236.98,130.06 236.81,130.23 JSPI1.13
PCH_SPI_CLK_0_R: length 2.4
  BOTTOM w0.102: RH29.1 RH655.2 v2(249.35,107.11) 249.35,106.26 UC5.6
PCH_SPI_CLK_1_R: length 3.4
  TOP w0.109: v2(250.95,93.42) 251.01,93.36 RH659.2 RH28.1
  BOTTOM w0.109: UC6.6 249.8,94.11 250.5,93.42 v2(250.95,93.42)
PCH_SPI_CLK_2_R: length 3.9
  TOP w0.102: UZ12.19 241.04,126.48 RZ60.2 RZ63.2 240.61,127.69 v1(239.49,128.82)
PCH_SPI_CLK_R1: length 19.2
  TOP w0.102: RZ60.1 239.29,126.42 239.29,126.02 238.64,125.37 238.64,125.12 v2(238.63,125.11) ; v2(236.29,133.69) 236.29,131.54 235.29,130.55 v4(235.29,129.44) 235.29,126.15 v2(235.33,126.12) ; RH659.1 250.39,91.88 v2(250.38,91.89)
  BOTTOM w0.102: RH655.1 250.08,107.59 250.08,105.91 250.63,105.36 v2(250.63,105.27) ; JSPI1.14 236.31,133.27 236.29,133.28 v2(236.29,133.69)
  BOTTOM w0.109: RH181.1 236.47,128.55 236.47,129.87 236.31,130.03 JSPI1.14
PCH_SPI_CS#0: length 22
  TOP w0.102: v2(236.59,125.49) 236.66,125.56 236.66,126.38 236.51,126.53 236.51,128.03 v1(236.61,128.13) 236.61,129.69 237.87,130.95 v2(237.87,133.36)
  BOTTOM w0.089: UH1.AY47 239.39,107.19 239.84,107.19 239.88,107.15 239.89,107.15 239.94,107.09 239.99,107.09 240.74,106.33 241.64,106.33 242.06,106.75 242.06,107.12 243.72,108.79 244.57,108.79 244.7,108.91 246.12,108.91 v2(246.38,108.66)
  BOTTOM w0.102: JSPI1.11 237.81,132.89 237.87,132.95 v2(237.87,133.36)
  BOTTOM w0.109: RH182.2 238.39,129.54 237.81,130.12 JSPI1.11
PCH_SPI_CS#0_R1: length 16.4
  TOP w0.102: v2(236.22,126.06) 236.26,126.1 236.26,129.79 237.36,130.88 v4(237.36,132.73) v2(237.36,133.68)
  BOTTOM w0.102: v2(250.93,99.08) 250.93,99.02 251.03,98.92 252.43,98.92 252.93,98.42 RH37.1 ; v2(237.36,133.68) 237.36,133.33 237.31,133.28 JSPI1.12
  BOTTOM w0.109: RH182.1 237.47,130.33 237.31,130.49 JSPI1.12
PCH_SPI_CS#0_R2: length 3.2
  TOP w0.102: v4(250.57,96.91) 250.95,96.53 v2(250.95,96.47)
  BOTTOM w0.102: v2(250.95,96.47) 251.39,96.47 251.96,97.04 RH37.2 252.01,98.13 UC5.1
PCH_SPI_CS#1: length 19.4
  TOP w0.102: v2(233.04,125.3) 233.11,125.37 v1(233.11,131.23) 233.11,131.65 233.99,132.53 233.99,133.23 233.95,133.28 v2(233.95,133.37)
  BOTTOM w0.089: UH1.AW48 239.73,106.77 239.79,106.71 239.83,106.71 240.58,105.95 242.35,105.95 243.09,106.69 243.09,107.02 243.54,107.47 244.25,107.47 v2(244.75,106.98)
  BOTTOM w0.102: v2(233.95,133.37) 233.95,133.28 233.96,133.27 233.96,131.82 233.81,131.66 JSPI1.19
  BOTTOM w0.109: JSPI1.19 233.81,130.46 233.62,130.27 RH177.2
PCH_SPI_CS#1_R1: length 13
  TOP w0.102: v2(233.36,133.36) 233.36,133.35 v1(233.36,132.85) 233.36,132.22 232.78,131.65 232.78,128.59 232.84,128.53 232.84,126.11 232.71,125.98 v2(232.71,125.79)
  TOP w0.109: RH352.1 v2(253.3,90.87)
  BOTTOM w0.102: v2(233.36,133.36) 233.36,133.24 233.46,133.14 233.46,131.79 233.31,131.63 JSPI1.20
  BOTTOM w0.109: JSPI1.20 233.31,130.52 232.71,129.92 RH177.1
PCH_SPI_CS#1_R3: length 3.1
  TOP w0.102: v1(252.64,88.01) 252.64,88.27 v2(252.84,88.48)
  TOP w0.109: v2(252.84,88.48) 252.8,88.52 252.8,88.67 253.3,89.16 RH352.2
  BOTTOM w0.109: UC6.1 252.34,88.21 252.61,88.48 252.84,88.48 v2(252.84,88.48)
PCH_SPI_CS#2: length 2.1
  TOP w0.102: RZ61.1 239.26,125.31 239.26,124.93 v2(238.97,124.63)
  BOTTOM w0.089: UH1.AT40 235.65,105.68 v2(235.88,105.91)
PCH_SPI_CS#2_R: length 1.4
  TOP w0.102: UZ12.20 241.28,125.98 241.1,125.8 RZ61.2
PCH_SPI_D0: length 19.5
  TOP w0.102: v2(234.06,126.12) v1(234.06,127.29) 234.06,131.2 234.86,132 v2(234.86,133.36)
  BOTTOM w0.089: UH1.AU41 236.38,106.15 v2(236.02,106.51)
  BOTTOM w0.102: RC128.1 231.63,133.16 231.83,133.36 231.83,134 232.21,134.38 234.37,134.38 234.86,133.89 v2(234.86,133.36) 234.81,133.31 JSPI1.17
  BOTTOM w0.109: v2(236.87,121.36) 236.69,121.54 RH600.2 ; JSPI1.17 234.81,130.24 234.44,129.87 234.44,128.51 234.7,128.24 RH178.2
PCH_SPI_D0_0_R: length 2
  BOTTOM w0.089: 247.77,106.25 247.58,106.25 v2(247.05,105.71) 246.83,105.5 RH654.2
  BOTTOM w0.102: UC5.5 247.77,106.25
PCH_SPI_D0_1_R: length 4.4
  TOP w0.109: v2(249.68,93.42) 249.74,93.36 RH658.2
  BOTTOM w0.089: 247.77,94.19 247.63,94.05 v1(247.01,94.05)
  BOTTOM w0.102: UC6.5 248.21,94.63 247.77,94.19
  BOTTOM w0.109: UC6.5 248.53,94.11 249.23,93.42 v2(249.68,93.42)
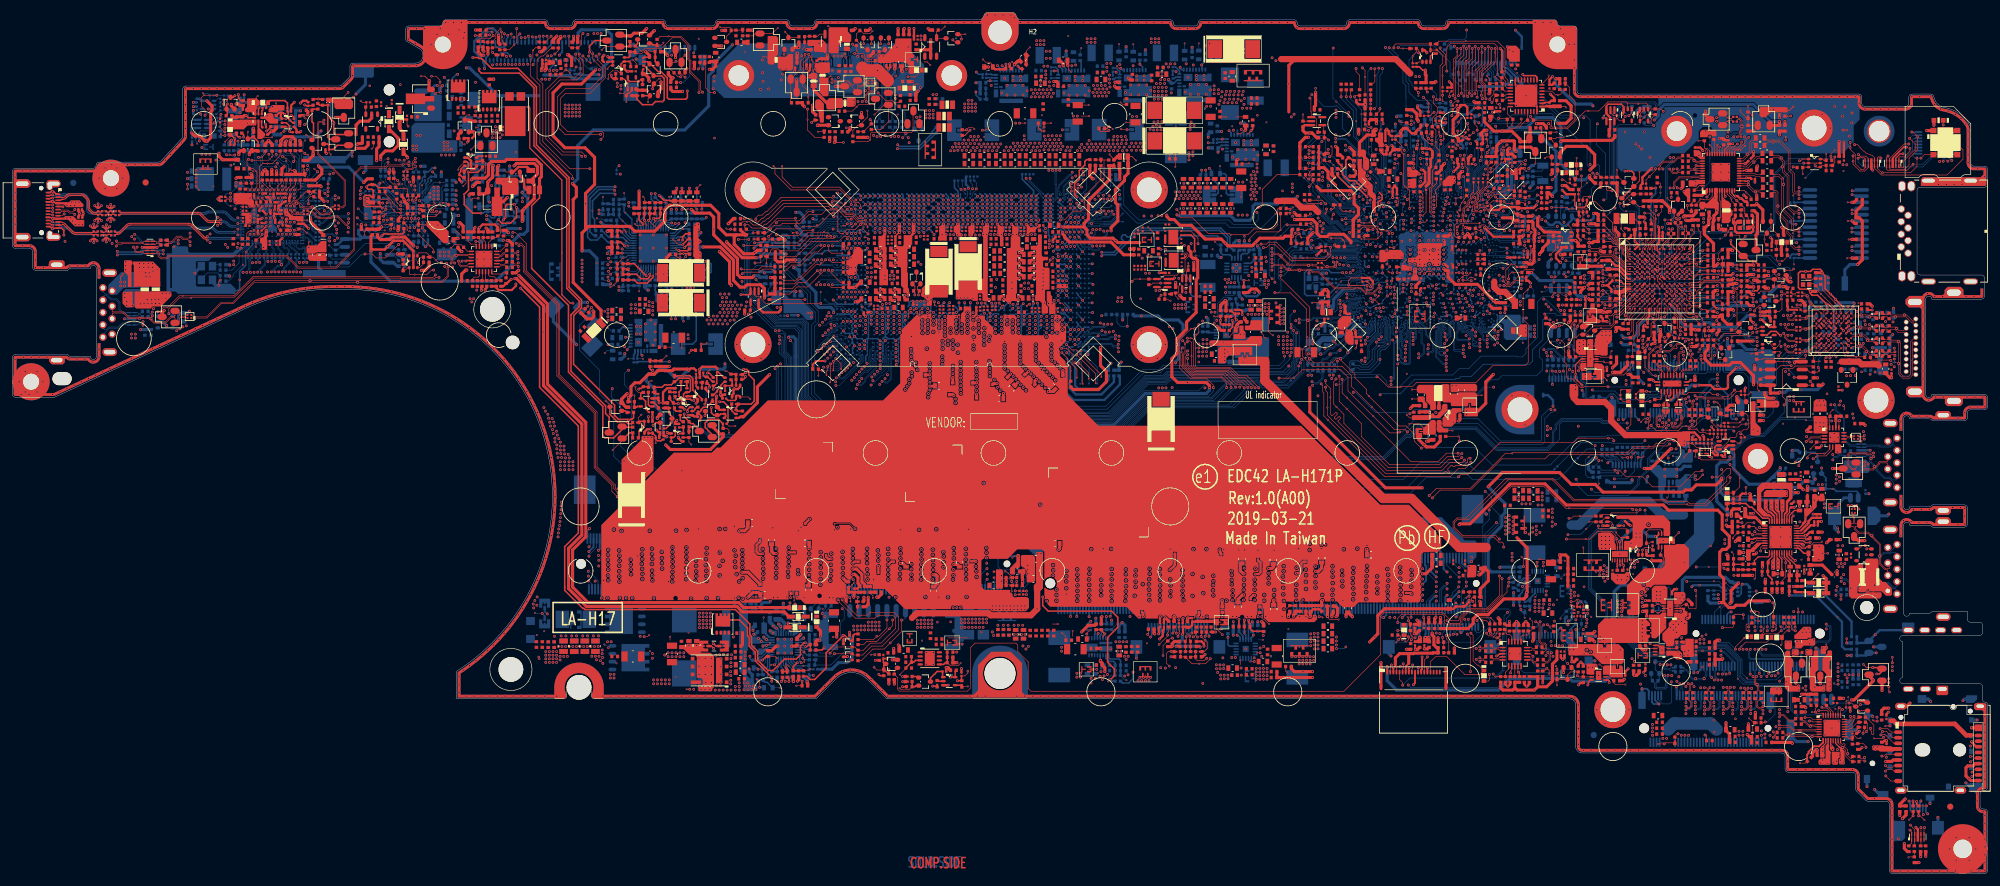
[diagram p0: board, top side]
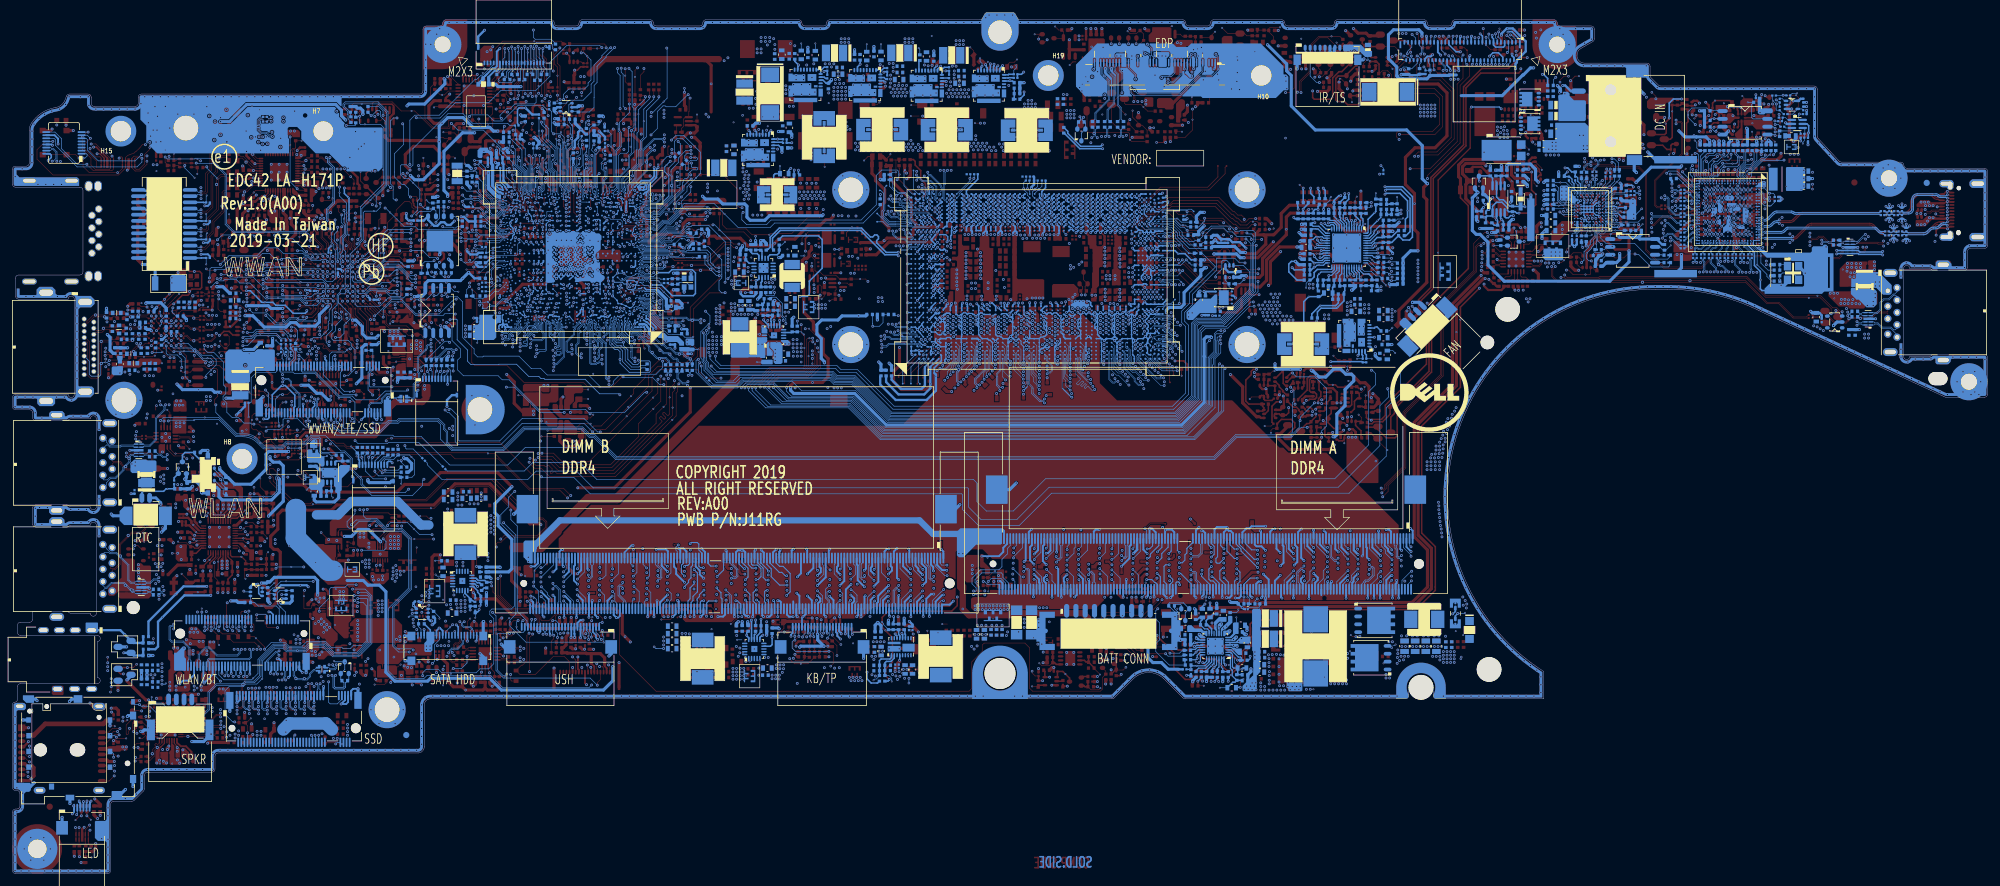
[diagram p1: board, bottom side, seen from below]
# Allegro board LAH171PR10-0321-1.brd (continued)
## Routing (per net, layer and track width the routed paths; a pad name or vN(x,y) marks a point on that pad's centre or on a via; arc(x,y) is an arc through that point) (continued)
PCH_SPI_D0_2_R: length 1.5
  TOP w0.102: RZ59.2 240.91,124.98 241.41,125.48 UZ12.21
PCH_SPI_D0_R1: length 19.6
  TOP w0.102: RZ59.1 239.75,124.97 239.75,124.46 239.86,124.34 v2(240.2,124.34) ; v2(233.57,125.74) 233.55,125.77 v4(233.55,129.54) 233.55,131.39 234.45,132.29 234.45,133.69 v2(234.41,133.73)
  TOP w0.109: v2(250.11,91.03) 249.74,91.39 RH658.1
  BOTTOM w0.089: 247.77,104.35 247.44,104.35 247.21,104.58 RH654.1
  BOTTOM w0.102: JSPI1.18 234.31,131.53 234.45,131.67 234.45,133.69 v2(234.41,133.73) ; v2(249.55,104.59) 249.55,104.58 249.44,104.48 247.9,104.48 247.77,104.35
  BOTTOM w0.109: RH178.1 234.15,128.58 234.15,130.22 234.31,130.37 JSPI1.18
PCH_SPI_D1: length 20.2
  TOP w0.102: v2(235.07,125.6) 235.07,125.6 235.07,125.61 234.81,125.87 234.81,130.75 235.81,131.75 v1(235.81,132.73) v2(235.81,133.36)
  BOTTOM w0.089: 243.29,109.05 241.75,107.51 240.07,107.51 239.9,107.68 239.42,107.68 239.36,107.74 238.87,107.74 238.78,107.82 238.65,107.82 238.64,107.83 UH1.BA45
  BOTTOM w0.102: 243.29,109.05 243.73,109.49 v2(245.01,109.49) ; v2(235.81,133.36) JSPI1.15
  BOTTOM w0.109: RH179.2 235.91,129.73 235.81,129.83 JSPI1.15
PCH_SPI_D1_0_R: length 3.5
  TOP w0.102: v2(249.18,96.47) 248.98,96.26 v4(248.98,95.58)
  BOTTOM w0.102: v2(249.18,96.47) 249.42,96.47 249.79,96.84 RH653.2 249.79,97.41 UC5.2
PCH_SPI_D1_1_R: length 4.7
  TOP w0.109: v2(251.75,88.33) 251.75,88.78 252.32,89.34 252.47,89.34 RH657.2
  BOTTOM w0.102: v1(249.99,85.8) 251.07,86.88 UC6.2
  BOTTOM w0.109: v2(251.75,88.33) 251.07,87.65 UC6.2
PCH_SPI_D1_2_R: length 3.9
  TOP w0.102: UZ12.24 241.59,123.98 241.49,123.87 241.49,122.8 RZ58.2 242.36,121.29 242.18,121.1 v1(242.18,120.91)
PCH_SPI_D1_R1: length 28.6
  TOP w0.102: v2(235.31,133.73) 235.31,131.78 v4(234.81,131.29) 234.5,130.98 234.5,125.72 v2(234.46,125.68) ; v2(243.71,121.97) 243.71,121.45 242.73,120.47 241.8,120.47 241.45,120.82 RZ58.1 241.31,122.06 v2(240.06,122.06)
  TOP w0.109: v2(252.4,90.87) 252.47,90.79 RH657.1
  BOTTOM w0.102: v2(251.33,97.23) 251.2,97.1 RH653.1 ; v2(240.06,122.06) 240.28,122.27 240.28,122.57 239.14,123.71 238.56,123.71 237.87,124.4 234.7,124.4 234.46,124.65 v2(234.46,125.68) ; v2(235.31,133.73) JSPI1.16
  BOTTOM w0.109: RH179.1 235,129.92 235.31,130.23 JSPI1.16
PCH_SPI_D2: length 24.8
  TOP w0.102: v2(237.44,125.24) 237.74,125.54 237.74,127.45 237.26,127.93 237.26,129.44 v1(238.92,131.1) v2(238.92,133.36)
  TOP w0.109: RH180.2 247.01,109.22 RH30.2 246.55,109.68 v2(246.32,109.68)
  BOTTOM w0.089: 240.06,107.28 240.03,107.32 239.99,107.32 239.89,107.43 UH1.AY48
  BOTTOM w0.102: JSPI1.9 238.81,132.84 238.92,132.95 v2(238.92,133.36) ; 240.06,107.28 240.07,107.28 240.82,106.53 241.52,106.53 241.8,106.82 241.8,107.2 243.72,109.11 245.83,109.11 246.32,109.59 v2(246.32,109.68)
  BOTTOM w0.109: RH183.2 239.26,128.67 239.26,129.55 238.81,130.01 JSPI1.9
PCH_SPI_D2_0_R: length 1.3
  BOTTOM w0.102: RH351.2 249.06,97.43 249.36,97.74 UC5.3
PCH_SPI_D2_1_R: length 3.8
  TOP w0.102: RH353.2 250.69,88.87 250.39,88.57 v2(249.9,88.57) 249.49,88.98 v1(249.49,89.48)
  BOTTOM w0.109: UC6.3 249.8,88.23 249.84,88.27 249.84,88.51 v2(249.9,88.57)
PCH_SPI_D2_R1: length 15.9
  TOP w0.102: v2(238.4,133.63) 238.4,130.98 237.03,129.6 237.03,127.84 237.49,127.38 237.49,126.59 v1(237.28,126.39) v2(237.28,125.81)
  TOP w0.109: RH353.1 v2(250.69,91.01)
  BOTTOM w0.102: RH351.1 248.14,96.78 248.46,96.47 v2(248.6,96.47) ; JSPI1.10 238.31,133.13 238.4,133.23 v2(238.4,133.63)
  BOTTOM w0.109: RH183.1 238.96,128.62 238.96,129.41 238.31,130.06 JSPI1.10
PCH_SPI_D2_XDP: length 1.8
  TOP w0.102: v1(246.12,107.2) 246.43,107.5 RH180.1 RC127.2
PCH_SPI_D3: length 24.5
  TOP w0.102: v2(239.5,133.36) v1(239.5,132.73) 239.5,131.13 237.49,129.11 237.49,128.03 237.96,127.55 237.96,125.29 v2(238.02,125.23)
  TOP w0.109: RH335.2 RH334.2 246.4,110.88 v2(246.39,110.87)
  BOTTOM w0.089: UH1.BA46 238.95,107.93 239.44,107.93 239.5,107.87 239.98,107.87 240.15,107.7 241.57,107.7 243.12,109.25
  BOTTOM w0.102: v2(246.39,110.87) 246.38,110.87 246.24,110.87 245.68,110.31 244.18,110.31 243.12,109.25 ; JSPI1.7 239.81,131.62 239.5,131.93 v2(239.5,133.36)
  BOTTOM w0.109: RH184.2 239.81,130.16 JSPI1.7
PCH_SPI_D3_0_R: length 4.6
  BOTTOM w0.102: v1(253.8,106.5) 253.27,107.03 251.52,107.03 RH656.2 250.63,107.11 UC5.7
PCH_SPI_D3_1_R: length 5.1
  TOP w0.102: RH660.2 253.24,92.8 v2(253.3,92.74)
  BOTTOM w0.102: v2(253.3,92.74) 253.91,92.74 v1(254.19,92.47)
  BOTTOM w0.109: UC6.7 251.07,93.89 252.24,92.72 253.28,92.72 v2(253.3,92.74)
PCH_SPI_D3_R1: length 8.4
  TOP w0.109: v2(253.3,91.88) 253.29,91.88 RH660.1
  BOTTOM w0.102: RH184.1 239.89,129.06 240.51,128.43 v1(240.51,128.22) 240.51,127.99 240.4,127.89 238.35,127.89 238.01,128.23 v2(238.01,128.27) ; v2(253.17,108.19) 252.5,107.52 RH656.1
  BOTTOM w0.109: JSPI1.8 239.31,130.14 239.89,129.56 RH184.1
PCH_TBT_PERST#: length 12.7
  TOP w0.102: v2(33.03,125.8) v1(30.93,125.8) 30.92,125.8 30.54,125.42 30.54,124.03 31.12,123.45 v2(31.12,122.55) ; RC557.1 243.7,104.66
  TOP w0.109: v2(242.78,104.66) 242.78,104.66 243.7,104.66
  BOTTOM w0.089: 242.47,104.34 240.84,104.34 240.26,103.76 240.02,103.76 239.97,103.71 UH1.AM48
  BOTTOM w0.102: RT554.1 33.08,125.75 v2(33.03,125.8) 32.51,125.8 RT500.1
  BOTTOM w0.109: 242.47,104.34 v2(242.78,104.66) 242.78,104.66 RC558.1
PCH_THERMTRIP#: length 9.9
  BOTTOM w0.089: 210.13,99.56 210.14,99.57 212.79,99.57 213.16,99.94 217.28,99.94 217.57,99.64 UH1.AD3
  BOTTOM w0.109: RH75.1 208.24,99.56 v1(209.16,99.56) 210.13,99.56
PCH_XDP_CLK_DN: length 10.5
  TOP w0.094: RH154.2 210.6,98.4 210.09,98.4 209.98,98.51 206.26,98.51 v3(204.92,99.85) 204.49,100.28 203.64,100.28 v2(203.45,100.47)
  BOTTOM w0.094: v2(87.95,129.81) 87.78,129.98 87.78,130.46 88.31,130.98 88.31,131.18 88.51,131.39 JXDP1.42
PCH_XDP_CLK_DN_R: length 8.7
  TOP w0.094: v2(213.37,98.85) 213.37,98.85 213.57,98.66 213.57,98.38 213.32,98.13 v3(212.35,98.13) 212.07,98.13 RH154.1
  BOTTOM w0.089: UH1.Y3 217.69,97.78 217.69,97.92 217.6,98.02 216.97,98.02 216.78,98.21 216.53,98.21 216.37,98.06 216.37,97.97 216.11,97.71 214.5,97.71
  BOTTOM w0.107: 214.5,97.71 213.97,97.71 213.67,98.01 213.67,98.55 v2(213.37,98.85)
PCH_XDP_CLK_DP: length 10.5
  TOP w0.094: v2(203.45,99.88) 203.66,100.09 204.42,100.09 204.42,100.04 204.97,99.48 205.02,99.48 206.21,98.29 v3(209.35,98.29) 209.93,98.29 210.01,98.21 210.63,98.21 RH155.2
  BOTTOM w0.094: v2(87.37,129.81) 87.38,129.81 87.6,130.03 87.6,130.54 88.12,131.06 88.12,131.27 JXDP1.40
PCH_XDP_CLK_DP_R: length 8.7
  TOP w0.094: v2(213.95,98.85) 213.83,98.74 213.83,98.33 v3(213.68,98.18) 213.41,97.91 211.52,97.91 RH155.1
  BOTTOM w0.089: 214.5,97.92 214.51,97.92 214.52,97.91 214.58,97.91 214.59,97.9 216.03,97.9 216.18,98.05 216.18,98.13 216.45,98.4 216.86,98.4 217.05,98.21 217.68,98.21 218.06,97.82 UH1.Y4
  BOTTOM w0.107: 214.5,97.92 214.06,97.92 213.88,98.1 213.88,98.78 v2(213.95,98.85)
PCH_XDP_PRDY#: length 8.6
  TOP w0.102: RC314.2 79.54,132.34 v2(79.8,132.08)
  BOTTOM w0.089: v2(211.75,105.12) 212.35,104.53 213.4,104.53 214.84,103.09 216.89,103.09 217.06,103.27 217.35,103.27 217.38,103.3 218.07,103.3 218.18,103.41 218.28,103.41 218.31,103.44 UH1.AM5
PCH_XDP_PREQ#: length 113.4
  BOTTOM w0.089: v2(211.35,104.7) 211.74,104.7 212.1,104.34 213.32,104.34 214.76,102.9 216.97,102.9 217.1,103.03 UH1.AL2
  BOTTOM w0.102: RC315.2 126.87,100.28 124.79,98.19 124.79,97.98 128.9,93.86 128.9,92.19 130.17,90.92 130.17,89.06 129.56,88.45 129.56,77.65 131.66,75.55 176.62,75.55 182.53,81.45 185.2,81.45 185.88,82.13 204.62,82.13 205.48,82.99 v2(205.48,83.64)
PCI_CLK_LPC1: length 1.5
  TOP w0.102: T424.1 233.17,108.27 v2(233.13,108.23)
  BOTTOM w0.089: UH1.BB34 232.93,108.44 v2(233.13,108.23)
PCIE_PRX_C_DTX_N5: length 2.8
  TOP w0.094: UL1.39 272.58,114.77 272.48,114.88 272.01,114.88 v3(271.64,115.25) 271.35,115.53 271.08,115.53 CL2.2
PCIE_PRX_C_DTX_N6: length 6.1
  TOP w0.094: CR14.2 286.37,22.33 287.16,22.33 287.32,22.17 v3(290.7,22.17) 291.21,22.17 291.25,22.12 UR1.8
PCIE_PRX_C_DTX_P5: length 2.7
  TOP w0.094: UL1.38 272.51,115.17 272.42,115.09 272.11,115.09 271.48,115.72 271.03,115.72 CL1.2
PCIE_PRX_C_DTX_P6: length 6.1
  TOP w0.094: UR1.7 291.74,22.43 287.33,22.43 287.21,22.55 v3(286.95,22.55) 286.24,22.55 CR13.2
PCIE_PRX_C_TTX_N1: length 3
  BOTTOM w0.076: 46.16,100.22 46.06,100.32 46.06,100.44 45.37,101.13 45.19,101.13 44.87,101.45 44.87,101.56 44.95,101.64 44.95,102.1 UT1.V22
  BOTTOM w0.094: CT7.1 46.16,100.22
PCIE_PRX_C_TTX_N2: length 2.7
  BOTTOM w0.076: 43.31,100.22 43.37,100.28 43.37,100.51 42.81,101.06 42.81,101.44 42.81,101.44 42.8,101.51 42.65,101.66 42.65,101.67 42.65,102.08 42.75,102.18 UT1.P22
  BOTTOM w0.094: CT9.1 43.31,100.22
PCIE_PRX_C_TTX_N3: length 2.5
  BOTTOM w0.076: 41.08,100.22 41.01,100.29 41.01,100.51 41.15,100.65 41.15,100.82 41.15,100.83 41.15,101.54 41.27,101.66 41.27,102.1 UT1.K22
  BOTTOM w0.094: CT128.1 41.08,100.22
PCIE_PRX_C_TTX_N4: length 2.8
  BOTTOM w0.076: 38.54,100.22 38.42,100.34 38.42,100.45 39.29,101.33 39.29,101.52 39.43,101.66 39.43,102.1 UT1.F22
  BOTTOM w0.094: CT130.1 38.54,100.22
PCIE_PRX_C_TTX_P1: length 3
  BOTTOM w0.076: UT1.V23 44.73,101.98 44.68,102.02 44.58,102.02 44.49,101.94 44.49,101.65 44.57,101.58 44.63,101.58 44.7,101.5 44.7,101.38 45.12,100.96 45.31,100.96 45.9,100.37 45.9,100.26 45.85,100.22
  BOTTOM w0.094: CT6.1 45.85,100.22
PCIE_PRX_C_TTX_P2: length 2.7
  BOTTOM w0.076: UT1.P23 42.89,101.99 42.95,102.05 43.08,102.05 43.13,102 43.13,101.68 42.98,101.53 42.98,101.46 42.98,101.45 42.98,101.13 43.54,100.57 43.54,100.31 43.62,100.22
  BOTTOM w0.094: CT8.1 43.62,100.22
PCIE_PRX_C_TTX_P3: length 2.6
  BOTTOM w0.076: 40.77,100.22 40.84,100.29 40.84,100.29 40.85,100.3 40.85,100.58 40.98,100.72 40.98,100.82 40.98,100.83 40.98,101.52 40.82,101.68 40.82,101.99 40.9,102.07 41,102.07 41.05,102.02 UT1.K23
  BOTTOM w0.094: CT127.1 40.77,100.22
PCIE_PRX_C_TTX_P4: length 2.8
  BOTTOM w0.076: 38.23,100.22 38.25,100.24 38.25,100.58 39.06,101.39 39.06,101.6 38.98,101.68 38.98,101.99 39.06,102.07 39.16,102.07 39.21,102.02 UT1.F23
  BOTTOM w0.094: CT129.1 38.23,100.22
PCIE_PRX_DTX_N5: length 6.1
  TOP w0.094: v2(266.61,113.88) 266.17,114.32 266.17,114.47 266.67,114.98 268.41,114.98 269.08,115.64 269.35,115.64 269.79,115.21 CL2.1
  BOTTOM w0.094: v2(225.3,90.9) 225.56,91.17 225.73,91.17 225.88,91.01 UH1.F20
PCIE_PRX_DTX_N6: length 1.7
  TOP w0.094: CR14.1 285.05,22.04 284.75,22.33 284.61,22.33 284.44,22.17 v2(284.44,22.03)
  BOTTOM w0.094: v2(226.91,92.73) 226.83,92.66 226.63,92.66 226.45,92.83 UH1.K21
PCIE_PRX_DTX_N7: length 2.5
  BOTTOM w0.094: v2(283.4,31.87) 283.26,31.87 283.02,32.11 283.02,32.78 283.2,32.96 JNGFF1.43 ; v2(228.39,93.05) UH1.L24
PCIE_PRX_DTX_N9: length 3.6
  BOTTOM w0.094: JNGFF3.5 281.82,26.95 281.37,26.5 281.13,26.5 280.81,26.49 v2(280.79,26.48) ; v2(234.26,91.43) 234.18,91.51 UH1.G36
PCIE_PRX_DTX_N10: length 3.7
  BOTTOM w0.094: UH1.K37 234.27,92.83 234.6,92.83 234.7,92.93 v2(234.7,92.97) ; v2(277.87,26.41) 278.49,26.41 278.82,26.74 JNGFF3.17
PCIE_PRX_DTX_N11: length 4.1
  BOTTOM w0.094: UH1.G38 235.01,91.45 235.67,91.45 235.81,91.59 v2(235.87,91.59) ; JNGFF3.29 275.82,26.86 275.47,26.5 274.84,26.5 v2(274.82,26.48)
PCIE_PRX_DTX_N12: length 3.7
  BOTTOM w0.094: JNGFF3.43 272.32,28.16 272.64,27.85 272.64,26.83 272.47,26.66 272.24,26.66 v2(271.84,27.06) ; UH1.H42 237.31,92.05 v2(237.31,92.19)
PCIE_PRX_DTX_N17: length 3.4
  BOTTOM w0.094: v2(237.48,93.6) 237.41,93.6 237.07,93.25 UH1.K43 ; v2(270.26,76.73) 270.06,76.53 270.06,76.4 269.92,76.26 269.92,75.4 270.08,75.24 JNGFF2.43
PCIE_PRX_DTX_N18: length 5.7
  TOP w0.094: UZ29.14 268.84,80.94 268.75,81.02 268.6,81.02 268.52,81.1 268.52,81.21 268.52,81.21 269.23,81.91 269.23,84 269.39,84.16 269.54,84.16 v2(269.93,83.77)
  BOTTOM w0.094: v2(236.02,94.31) 236.02,94.64 236.12,94.74 236.32,94.74 UH1.P41
PCIE_PRX_DTX_P5: length 6.1
  TOP w0.094: v2(265.98,113.88) 265.98,114.55 266.59,115.16 268.34,115.16 269,115.83 269.57,115.83 CL1.1
  BOTTOM w0.094: v2(225.27,91.65) 225.27,91.52 225.42,91.36 225.95,91.36 UH1.G20
PCIE_PRX_DTX_P6: length 1.8
  TOP w0.094: CR13.1 284.75,22.52 284.62,22.52 284.52,22.61 284.52,22.82 v2(284.42,22.91)
  BOTTOM w0.094: UH1.J21 226.65,92.22 226.85,92.03 v2(226.85,91.97)
PCIE_PRX_DTX_P7: length 2.5
  BOTTOM w0.094: v2(228.39,92.29) UH1.J24 ; v2(282.45,31.86) 282.48,31.89 282.59,31.89 282.84,32.13 282.84,32.76 282.7,32.9 JNGFF1.41
PCIE_PRX_DTX_P9: length 3.6
  BOTTOM w0.094: v2(234.64,90.86) 234.63,90.85 UH1.F36 ; JNGFF3.7 281.32,28.12 281.64,27.8 281.64,27.03 281.29,26.68 281.16,26.68 280.79,27.05 v2(280.79,27.06)
PCIE_PRX_DTX_P10: length 3.7
  BOTTOM w0.094: v2(277.87,27) 278.24,26.63 278.45,26.63 278.64,26.82 278.64,27.75 278.32,28.07 JNGFF3.19 ; UH1.J37 234.71,92.38 234.94,92.38 v2(234.95,92.39)
PCIE_PRX_DTX_P11: length 4.1
  BOTTOM w0.094: UH1.F39 235.33,91.14 235.43,91.23 235.73,91.23 235.84,91.13 235.84,91.04 v2(235.87,91.01) ; JNGFF3.31 275.32,28.19 275.64,27.88 275.64,26.93 275.39,26.68 275.19,26.68 274.82,27.05 v2(274.82,27.06)
PCIE_PRX_DTX_P12: length 3.7
  BOTTOM w0.094: UH1.J41 236.63,92.06 236.73,92.16 v2(236.73,92.27) ; v2(271.84,26.48) 272.55,26.48 272.82,26.76 JNGFF3.41
PCIE_PRX_DTX_P17: length 3.4
  BOTTOM w0.094: JNGFF2.41 269.58,75.28 269.73,75.44 269.73,76.33 269.88,76.48 269.88,76.53 v2(269.68,76.73) ; v2(237.53,92.99) 237.8,92.99 237.98,92.81 237.98,92.68 237.85,92.55 UH1.K44
PCIE_PRX_DTX_P18: length 5.7
  TOP w0.094: v2(269.93,84.35) 269.92,84.36 269.31,84.36 269.04,84.1 269.04,81.99 268.34,81.29 UZ29.15
  BOTTOM w0.094: v2(235.44,94.31) 235.45,94.31 235.45,94.54 235.65,94.74 UH1.R40
PCIE_PRX_L_DTX_N18: length 7.6
  TOP w0.094: v2(266.53,72.89) 266.55,72.89 266.75,72.69 266.75,72.46 266.53,72.24 266.07,72.24 v3(265.88,72.44) 265.67,72.64 265.67,73.62 265.98,73.93 266.28,73.93 266.37,73.83 266.37,73.64 266.47,73.54 266.61,73.54 266.72,73.65 266.72,73.81 266.84,73.93 266.96,73.93 267.17,74.14 267.17,74.49 LI16.2 267.32,74.7 267.43,74.81 RI27.2
  BOTTOM w0.094: v2(266.53,72.89) 266.73,73.09 266.73,73.63 266.58,73.79 JNGFF2.29
PCIE_PRX_L_DTX_P18: length 7.6
  TOP w0.094: RI28.2 266.82,74.68 LI16.3 266.82,74.38 266.92,74.29 266.92,74.15 266.87,74.11 265.91,74.11 265.49,73.69 265.49,72.52 265.95,72.06 266.61,72.06 266.98,72.42 266.98,72.75 v2(267.12,72.89)
  BOTTOM w0.094: JNGFF2.31 267.08,73.73 266.92,73.57 266.92,73.09 v2(267.12,72.89)
PCIE_PRX_SW_DTX_N18: length 2.4
  TOP w0.094: RI27.1 267.45,75.76 LI16.1 267.32,76.22 267.18,76.36 267.18,77.3 267.34,77.46 UZ29.4
PCIE_PRX_SW_DTX_P18: length 2.4
  TOP w0.094: UZ29.3 266.84,77.43 266.99,77.27 266.99,76.32 266.82,76.14 LI16.4 266.82,75.85 RI28.1
PCIE_PRX_TTX_N1: length 3.8
  BOTTOM w0.089: UH1.G17 224.08,91.51 223.64,91.07 v2(223.42,91.07)
  BOTTOM w0.094: CT7.2 46.11,99.33 46.11,99.09 45.86,98.83 45.86,97.33 v2(45.93,97.25)
PCIE_PRX_TTX_N2: length 3.8
  BOTTOM w0.094: CT9.2 43.18,99.46 43.45,99.19 43.45,99.18 43.51,99.11 43.51,98.78 43.03,98.3 42.77,98.3 42.08,97.61 42.08,97.51 v2(41.82,97.25) ; UH1.R21 226.35,95.25 225.99,95.25 v2(225.98,95.24)
PCIE_PRX_TTX_N3: length 3.8
  BOTTOM w0.089: v2(225.69,93.1) 225.69,93 225.4,92.72 225.26,92.72 225.21,92.77 UH1.K18
  BOTTOM w0.094: CT128.2 41.21,99.45 40.87,99.11 40.87,98.35 40.03,97.51 40.03,97.38 v2(40.21,97.2)
PCIE_PRX_TTX_N4: length 3.3
  BOTTOM w0.094: CT130.2 38.45,99.28 38.45,99.1 38.38,99.03 38.38,97.73 38.26,97.61 38.26,97.36 v2(38.44,97.18) ; UH1.N18 224.93,94.77 224.79,94.77 v2(224.64,94.61)
PCIE_PRX_TTX_P1: length 3.9
  BOTTOM w0.089: v2(223.3,90.5) 223.5,90.7 223.59,90.7 223.97,91.08 224.16,91.08 224.24,90.99 UH1.F16
  BOTTOM w0.094: v2(45.35,97.25) 45.67,97.58 45.67,98.91 45.93,99.17 45.93,99.3 CT6.2
PCIE_PRX_TTX_P2: length 3.7
  BOTTOM w0.094: CT8.2 43.63,99.39 43.63,99.26 43.7,99.19 43.7,98.65 v3(43.47,98.42) 43.16,98.11 42.85,98.11 42.27,97.53 42.27,97.39 v2(42.41,97.25) ; UH1.P21 226.37,94.66 225.98,94.66 v2(225.98,94.66)
PCIE_PRX_TTX_P3: length 3.7
  BOTTOM w0.094: v2(225.71,92.5) 225.68,92.53 225.27,92.53 UH1.J18 ; CT127.2 40.75,99.39 40.75,99.26 40.68,99.19 40.68,98.43 39.84,97.59 39.84,97.43 v2(39.62,97.21)
PCIE_PRX_TTX_P4: length 3.3
  BOTTOM w0.094: CT129.2 38.26,99.34 38.26,99.18 38.19,99.11 38.19,97.81 38.07,97.68 38.07,97.39 v2(37.86,97.18) ; v2(224.62,95.22) 224.8,95.03 224.99,95.03 UH1.R18
PCIE_PTX_C_DRX_N5: length 2.5
  TOP w0.094: CL6.2 270.74,113.36 270.74,113.36 271.06,113.67 272.25,113.67 272.34,113.57 UL1.42
PCIE_PTX_C_DRX_N6: length 3.3
  TOP w0.094: UR1.4 291.25,23.72 291.14,23.83 v3(290.43,23.83) 290.14,23.83 289.48,24.49 289.28,24.49 CR12.2
PCIE_PTX_C_DRX_N7: length 4.9
  TOP w0.094: CZ13.2 282.09,29.65 282.09,30.27 v3(281.81,30.55) 281.54,30.82 281.54,31.66 v2(281.74,31.86)
  BOTTOM w0.094: v2(281.74,31.86) 281.54,32.06 281.54,32.83 281.7,32.99 JNGFF1.37
PCIE_PTX_C_DRX_N9: length 6.1
  TOP w0.094: CN65.1 280.39,28.19 280.39,26.79 280.04,26.43 279.27,26.43 v2(279.27,26.43)
  BOTTOM w0.094: JNGFF3.11 280.32,26.76 280.12,26.56 279.4,26.56 v2(279.27,26.43)
PCIE_PTX_C_DRX_N10: length 5.8
  TOP w0.094: CN67.1 277.47,28.11 277.47,26.98 276.96,26.47 v2(276.35,26.47)
  BOTTOM w0.094: v2(276.35,26.47) 276.99,26.47 277.32,26.8 JNGFF3.23
PCIE_PTX_C_DRX_N11: length 5.9
  TOP w0.094: CN69.1 274.38,28.19 274.38,26.74 274.06,26.42 273.65,26.42 v2(273.31,26.43)
  BOTTOM w0.094: JNGFF3.35 274.32,27 273.84,26.51 273.65,26.51 273.4,26.51 v2(273.31,26.43)
PCIE_PTX_C_DRX_N12: length 5.6
  TOP w0.094: v2(270.33,26.47) 270.53,26.67 270.94,26.67 271.31,27.04 271.31,28.17 CN71.1
  BOTTOM w0.094: JNGFF3.47 271.32,26.93 270.87,26.47 v2(270.33,26.47)
PCIE_PTX_C_DRX_N17: length 2.7
  TOP w0.094: CZ10.2 271.23,73.72 271.23,73.31 v2(271.03,73.12)
  BOTTOM w0.094: v2(271.03,73.12) 271.23,73.31 271.23,73.65 271.08,73.8 JNGFF2.47
PCIE_PTX_C_DRX_P5: length 2.5
  TOP w0.094: CL5.2 271.02,113.89 v3(271.78,113.89) 272.17,113.89 272.25,113.97 UL1.41
PCIE_PTX_C_DRX_P6: length 3.4
  TOP w0.094: CR11.2 289.33,24.67 289.56,24.67 290.18,24.05 290.72,24.05 290.76,24.02 291.14,24.02 291.25,24.12 UR1.3
PCIE_PTX_C_DRX_P7: length 4.9
  TOP w0.094: CZ12.2 281.91,29.65 281.91,30.15 281.36,30.7 281.36,31.66 v2(281.16,31.86)
  BOTTOM w0.094: JNGFF1.35 281.2,32.94 281.36,32.78 281.36,32.06 v2(281.16,31.86)
PCIE_PTX_C_DRX_P9: length 6.1
  TOP w0.094: CN66.1 279.76,28.32 280.2,27.87 280.2,26.87 279.95,26.62 279.68,26.62 v2(279.3,27.03)
  BOTTOM w0.094: JNGFF3.13 279.82,28.16 280.14,27.84 280.14,26.84 280.05,26.74 279.56,26.74 v2(279.3,27.03)
PCIE_PTX_C_DRX_P10: length 5.8
  TOP w0.094: v2(276.35,27.05) 276.75,26.65 276.88,26.65 277.28,27.05 277.28,27.78 CN68.1
  BOTTOM w0.094: JNGFF3.25 276.82,28.11 277.14,27.79 277.14,26.88 276.94,26.68 276.72,26.68 v2(276.35,27.05)
PCIE_PTX_C_DRX_P11: length 5.9
  TOP w0.094: CN70.1 274.19,27.69 274.19,26.82 273.98,26.61 273.71,26.61 v2(273.32,27.01)
  BOTTOM w0.094: v2(273.32,27.01) 273.63,26.7 273.76,26.69 274.14,27.08 274.14,27.75 273.82,28.06 JNGFF3.37
PCIE_PTX_C_DRX_P12: length 5.6
  TOP w0.094: v2(270.33,27.06) 270.53,26.86 270.86,26.86 271.12,27.12 271.12,27.73 270.98,27.87 270.89,27.87 CN72.1
  BOTTOM w0.094: v2(270.33,27.06) 270.5,27.06 270.59,26.97 270.59,26.79 270.68,26.71 270.81,26.71 271.13,27.02 271.13,27.89 270.82,28.19 JNGFF3.49
PCIE_PTX_C_DRX_P17: length 2.7
  TOP w0.094: CZ11.2 271.41,73.72 271.41,73.32 v2(271.62,73.12)
  BOTTOM w0.094: JNGFF2.49 271.58,73.85 271.42,73.7 271.42,73.31 v2(271.62,73.12)
PCIE_PTX_C_SW_DRX_N18: length 3.1
  TOP w0.094: UZ29.12 269.84,81.24 269.95,81.36 271.27,81.36 CZ153.2
PCIE_PTX_C_SW_DRX_P18: length 3.1
  TOP w0.094: CZ152.2 271.06,81.98 271.23,81.81 271.23,81.64 271.14,81.54 269.87,81.54 269.65,81.32 269.65,81.2 269.34,80.88 UZ29.13
PCIE_PTX_C_TRX_N1: length 4
  BOTTOM w0.076: UT1.Y22 45.65,102.3 45.87,102.07 45.87,101.71 45.83,101.67 45.83,101.48 46.29,101.01 46.68,101.01 46.77,101.11 46.77,101.12 46.93,101.29 47.12,101.29
  BOTTOM w0.094: CT3.2 47.37,100.28 47.37,101.1 47.18,101.29 47.12,101.29
PCIE_PTX_C_TRX_N2: length 3.1
  BOTTOM w0.076: UT1.T22 44.03,102.1 44.03,101.67 43.89,101.53 43.89,101.29 44.01,101.17 44.41,101.17 44.81,100.78 44.81,100.31 44.89,100.22
  BOTTOM w0.094: CT5.2 44.89,100.22
PCIE_PTX_C_TRX_N3: length 2.6
  BOTTOM w0.076: UT1.M22 42.19,102.1 42.19,101.66 42.06,101.52 42.06,101.24 42.27,101.03 42.27,100.31 42.35,100.22
  BOTTOM w0.094: CT124.2 42.35,100.22
PCIE_PTX_C_TRX_N4: length 2.7
  BOTTOM w0.076: 39.81,100.22 39.73,100.31 39.73,100.57 40.2,101.05 40.2,101.51 40.35,101.66 40.35,102.1 UT1.H22
  BOTTOM w0.094: CT126.2 39.81,100.22
PCIE_PTX_C_TRX_P1: length 4
  BOTTOM w0.076: UT1.Y23 45.65,102 45.59,102.05 45.49,102.05 45.41,101.97 45.41,101.66 46.22,100.85 46.74,100.85 46.95,101.05
  BOTTOM w0.094: 46.95,101.05 47,101.1 47.1,101.1 47.18,101.02 47.18,100.28 CT2.2
PCIE_PTX_C_TRX_P2: length 3.1
  BOTTOM w0.076: 44.58,100.22 44.64,100.28 44.64,100.71 44.34,101 43.94,101 43.72,101.22 43.72,101.54 43.58,101.68 43.58,101.99 43.66,102.07 43.76,102.07 43.81,102.02 UT1.T23
  BOTTOM w0.094: CT4.2 44.58,100.22
PCIE_PTX_C_TRX_P3: length 2.6
  BOTTOM w0.076: 42.04,100.22 42.1,100.28 42.1,100.96 41.89,101.17 41.89,101.53 41.74,101.68 41.74,101.99 41.82,102.07 41.92,102.07 41.97,102.02 UT1.M23
  BOTTOM w0.094: CT123.2 42.04,100.22
PCIE_PTX_C_TRX_P4: length 2.7
  BOTTOM w0.076: UT1.H23 40.13,102.02 40.08,102.07 39.98,102.07 39.9,101.99 39.9,101.63 40.04,101.49 40.04,101.18 39.56,100.71 39.56,100.28 39.5,100.22
  BOTTOM w0.094: CT125.2 39.5,100.22
PCIE_PTX_DRX_N5: length 5.5
  TOP w0.094: v2(267.71,113.88) 267.91,113.68 267.91,113.43 268.17,113.17 268.89,113.17 269.04,113.32 CL6.1
  BOTTOM w0.089: v2(226.25,86.74) 226.44,86.54 226.53,86.54 226.62,86.63 226.62,87.69 226.28,88.03 226.28,88.32 226.6,88.63 UH1.B21
PCIE_PTX_DRX_N6: length 10.9
  TOP w0.094: v2(285.42,25.34) 285.42,25.36 285.6,25.54 286.05,25.54 287.08,24.51 287.72,24.51 288.04,24.2 CR12.1
  BOTTOM w0.089: UH1.D21 226.65,89.72 226.75,89.62 226.77,89.62 227.03,89.35 227.03,88.82 227.71,88.15 227.71,85.83 228.07,85.47 228.07,84.06 227.59,83.57 227.24,83.57 227.15,83.48 v2(227.15,83.39)
PCIE_PTX_DRX_N7: length 9.8
  TOP w0.094: CZ13.1 282.41,28.32 281.83,27.74 281.83,27.16 282.19,26.81 282.57,26.81 v2(282.76,27)
  BOTTOM w0.089: UH1.C23 227.47,89.26 227.49,89.26 227.7,89.06 227.7,88.9 228.23,88.37 228.23,88.08 228.4,87.91 228.4,87.2 229.63,85.97 229.63,84.49 229.36,84.21 228.9,84.21 v2(228.65,83.97)
PCIE_PTX_DRX_N9: length 7.9
  TOP w0.094: CN65.2 280.15,29.63 280.15,29.78 v2(280.35,29.98)
  BOTTOM w0.089: UH1.C34 233.01,89.55 232.89,89.55 232.8,89.46 232.8,89.21 232.77,89.18 232.77,84.63 232.97,84.43 233.86,84.43 234,84.28 234,84.21 234.12,84.09 v2(234.35,84.09)
PCIE_PTX_DRX_N10: length 6.4
  TOP w0.094: CN67.2 277.68,29.25 277.3,29.63 277.3,29.89 v2(277.52,30.11)
  BOTTOM w0.089: UH1.C35 233.63,89.51 233.63,88.88 233.54,88.79 233.54,87.51 233.34,87.31 233.34,86.58 233.61,86.31 235.2,86.31 v2(235.33,86.44)
PCIE_PTX_DRX_N11: length 8
  TOP w0.094: CN69.2 274.38,29.23 273.94,29.67 273.94,29.81 v2(274.19,30.06)
  BOTTOM w0.089: v2(237.04,85.74) 236.65,85.35 236.11,85.35 236.02,85.43 236.02,85.63 236.11,85.72 236.41,85.72 236.5,85.81 236.5,85.96 236.38,86.07 236.11,86.07 236.02,86.16 236.02,86.59 234.94,87.67 234.28,87.67 233.92,88.03 233.92,88.63 234.06,88.77 UH1.B36
PCIE_PTX_DRX_N12: length 6.8
  TOP w0.094: v2(271.27,30.7) 271.05,30.48 271.05,29.64 CN71.2
  BOTTOM w0.089: v2(236.36,87.54) 236.3,87.54 236.22,87.45 236.22,87.31 236.09,87.19 235.97,87.19 235.83,87.33 235.83,87.43 235.72,87.55 235.61,87.55 235.51,87.65 235.51,87.84 235.39,87.96 235.2,87.96 235.1,88.05 235.1,88.21 235.02,88.3 234.89,88.3 234.8,88.21 234.8,88.14 234.71,88.05 234.44,88.05 234.31,88.19 234.31,88.46 234.5,88.66 234.5,89.43 234.72,89.66 234.72,89.79 UH1.D38
PCIE_PTX_DRX_N17: length 6.4
  TOP w0.094: v2(270.97,76.4) 270.99,76.4 271.23,76.15 271.23,75.97 271.34,75.86 271.34,75.53 270.88,75.07 CZ10.1
  BOTTOM w0.102: v2(239.9,85.78) 239.9,85.83 239.49,86.24 238.87,86.24 238.65,86.46 238.65,87.06 238.26,87.45 237.53,87.45 236.81,88.17 236.81,88.28 UH1.A42
PCIE_PTX_DRX_N18: length 6
  TOP w0.094: v2(271.35,83.98) 271.2,83.83 271.2,83.58 271.88,82.9 CZ153.1
  BOTTOM w0.089: v2(239.98,87.03) 239.72,87.28 239.13,87.28 238.56,87.85 237.7,87.85 237.21,88.34 237.21,88.45 237.4,88.63 237.4,88.79 237.1,89.09 237.1,89.19 UH1.C42
PCIE_PTX_DRX_P5: length 5.5
  TOP w0.094: v2(268.29,113.88) 268.09,113.68 268.09,113.51 268.25,113.35 268.82,113.35 268.97,113.5 269.08,113.5 CL5.1
  BOTTOM w0.089: v2(226.25,86.15) 226.44,86.35 226.61,86.35 226.81,86.55 226.81,87.77 226.47,88.11 226.47,88.24 226.61,88.38 226.74,88.38 UH1.A22
PCIE_PTX_DRX_P6: length 10.8
  TOP w0.094: v2(285.42,25.93) 285.62,25.72 286.13,25.72 287.16,24.7 287.69,24.7 CR11.1
  BOTTOM w0.089: v2(227.15,84.02) 227.15,83.88 227.27,83.76 227.51,83.76 227.88,84.14 227.88,85.39 227.52,85.75 227.52,87.32 227.43,87.41 227.27,87.41 227.16,87.52 227.16,87.67 227.25,87.76 227.43,87.76 227.52,87.85 227.52,88.07 226.84,88.74 226.84,89.27 226.72,89.39 226.63,89.39 UH1.C21
PCIE_PTX_DRX_P7: length 9.8
  TOP w0.094: v2(282.76,26.41) 282.71,26.41 282.5,26.62 282.11,26.62 281.64,27.09 281.64,28.17 CZ12.1
  BOTTOM w0.089: UH1.B23 227.28,88.97 227.38,89.08 227.39,89.08 227.39,89.07 227.41,89.07 227.51,88.98 227.51,88.82 228.04,88.29 228.04,88 228.21,87.83 228.21,87.12 229.44,85.89 229.44,84.57 229.28,84.4 228.57,84.4 228.48,84.49 228.48,84.77 228.57,84.86 v2(228.67,84.86)
PCIE_PTX_DRX_P9: length 8
  TOP w0.094: v2(279.77,29.98) 279.97,29.78 279.97,29.61 CN66.2
  BOTTOM w0.089: v2(234.38,84.67) 233.05,84.67 232.96,84.76 232.96,89.08 232.99,89.11 233.09,89.21 233.29,89.42 233.29,89.69 UH1.D34
PCIE_PTX_DRX_P10: length 6.4
  TOP w0.094: CN68.2 277.11,29.64 277.11,29.93 v2(276.93,30.11)
  BOTTOM w0.089: UH1.B35 233.39,88.93 233.35,88.89 233.35,87.59 233.15,87.39 233.15,86.5 233.53,86.12 235.07,86.12 235.33,85.85 v2(235.33,85.61)
PCIE_PTX_DRX_P11: length 8
  TOP w0.094: CN70.2 273.74,29.44 273.74,29.95 273.65,30.05 v2(273.3,30.05)
  BOTTOM w0.089: v2(237.04,85.16) 236.03,85.16 235.83,85.35 235.83,86.51 234.87,87.48 234.21,87.48 233.73,87.95 233.73,88.71 233.82,88.8 233.82,89.1 234.06,89.34 UH1.C36
PCIE_PTX_DRX_P12: length 6.8
  TOP w0.094: CN72.2 270.87,29.66 270.87,30.52 v2(270.69,30.7)
  BOTTOM w0.089: v2(236.36,86.9) 236.26,87 235.89,87 235.53,87.36 235.53,87.36 235.32,87.57 235.32,87.57 235.03,87.86 234.36,87.86 234.11,88.11 234.11,88.54 234.31,88.74 234.31,88.97 234.3,88.98 234.3,89.8 234.34,89.84 234.34,89.88 234.46,90 UH1.E37
PCIE_PTX_DRX_P17: length 6.3
  TOP w0.094: v2(271.55,76.4) 271.42,76.27 271.42,76.05 271.52,75.94 271.52,75.44 271.44,75.35 271.44,75.22 271.67,74.99 CZ11.1
  BOTTOM w0.102: UH1.B42 237.02,88.74 237.02,88.25 237.62,87.65 238.35,87.65 238.86,87.15 238.86,86.55 238.96,86.45 239.86,86.45 v2(239.87,86.45)
PCIE_PTX_DRX_P18: length 5.9
  TOP w0.094: CZ152.1 271.13,83.02 271.13,83.39 271.02,83.5 271.02,83.73 v2(270.77,83.98)
  BOTTOM w0.089: v2(239.98,87.61) 239.84,87.47 239.21,87.47 238.64,88.04 237.78,88.04 237.59,88.23 237.59,88.87 237.29,89.17 237.29,89.42 UH1.D42
PCIE_PTX_L_DRX_N18: length 6.7
  TOP w0.094: RI29.2 269.35,74.75 LI17.2 269.35,74.51 269.7,74.17 v3(269.7,73.65) 269.7,72.8 268.91,72.01 268.25,72.01 268.03,72.24 v2(268.03,72.8)
  BOTTOM w0.094: JNGFF2.35 268.08,73.75 268.23,73.59 268.23,73 v2(268.03,72.8)
PCIE_PTX_L_DRX_P18: length 6.8
  TOP w0.094: v2(268.62,72.8) 268.62,72.62 268.52,72.52 268.33,72.52 268.24,72.43 268.24,72.29 268.33,72.2 268.84,72.2 269.51,72.87 269.51,73.32 269.48,73.35 269.48,74.03 269.33,74.17 268.95,74.17 268.85,74.27 LI17.3 268.85,74.75 RI30.2
  BOTTOM w0.094: v2(268.62,72.8) 268.42,73 268.42,73.61 268.58,73.77 JNGFF2.37
PCIE_PTX_SW_DRX_N18: length 2.3
  TOP w0.094: UZ29.8 269.34,77.31 269.17,77.15 269.17,76.53 269.35,76.35 LI17.1 269.35,75.93 RI29.1
PCIE_PTX_SW_DRX_P18: length 2.3
  TOP w0.094: RI30.1 268.85,75.93 LI17.4 268.85,76.35 268.99,76.48 268.99,77.18 268.84,77.33 UZ29.7
PCIE_PTX_TRX_N1: length 10.7
  BOTTOM w0.089: UH1.A17 224.29,88.33 224.11,88.14 224.11,87.85 224.2,87.77 224.2,86.55 223.32,85.67
  BOTTOM w0.094: 223.32,85.67 223.28,85.64 223.29,85.63 223.29,80.03 223.08,79.82 222.88,79.82 v2(222.69,79.63) ; v2(47.57,98.79) 47.37,98.99 47.37,99.31 CT3.1
PCIE_PTX_TRX_N2: length 10.7
  BOTTOM w0.089: UH1.B18 224.95,88.96 224.87,88.87 224.87,88.83 224.89,88.77 225.02,88.64 225.02,88.1 224.58,87.66 224.58,87.45 224.64,87.39 224.93,87.39 225.03,87.28 225.03,87.16 224.94,87.07 224.66,87.07 224.58,86.99 224.58,86.39 223.93,85.74 223.93,85.67
  BOTTOM w0.094: 223.93,85.67 223.93,85.66 223.97,85.62 223.97,85.1 224.41,84.65 224.41,84.27 224.47,84.22 224.47,83.83 224.41,83.78 224.41,83.47 224.64,83.24 224.82,83.24 224.99,83.42 v2(224.99,83.46) ; v2(44.18,97.25) 43.98,97.46 43.98,97.84 44.83,98.69 44.83,99.31 45.02,99.51 CT5.1
PCIE_PTX_TRX_N3: length 6.4
  BOTTOM w0.089: 224.57,85.67 224.57,85.69 224.56,85.7 224.56,85.83 225.41,86.68 225.41,87.59 225.5,87.68 225.5,87.72 225.68,87.89 225.68,88.02 225.5,88.19 225.5,88.34 225.67,88.51 225.67,88.72 225.5,88.89 225.5,89.18 225.58,89.26 225.7,89.26 225.8,89.16 225.8,89.1 UH1.B19
  BOTTOM w0.094: v2(42.48,98.96) 42.29,99.15 42.29,99.31 42.48,99.5 CT124.1 ; v2(225.05,85.35) 224.87,85.18 224.71,85.18 224.57,85.31 224.57,85.67
PCIE_PTX_TRX_N4: length 10.8
  BOTTOM w0.089: UH1.D20 225.87,89.72 225.87,89.36 226.02,89.21 226.02,88.95 225.9,88.83 225.9,87.78 225.6,87.48 225.6,85.7 225.59,85.69 225.59,85.67
  BOTTOM w0.094: v2(39.95,98.79) 39.75,98.99 39.75,99.31 CT126.1 ; v2(223.83,83.13) 223.92,83.13 224.4,82.66 224.63,82.66 224.82,82.47 225.51,82.47 225.6,82.57 225.6,85.66 225.59,85.67
PCIE_PTX_TRX_P1: length 10.8
  BOTTOM w0.089: 223.09,85.76 223.11,85.78 223.16,85.78 224.01,86.63 224.01,87.69 223.92,87.77 223.92,88.22 224.4,88.7 UH1.B17
  BOTTOM w0.094: v2(46.98,98.79) 47.18,98.99 47.18,99.31 CT2.1 ; 223.09,85.76 223.07,85.74 223.07,80.62 223.09,80.59 223.09,80.11 223,80.02 222.89,80.02 v2(222.69,80.21)
PCIE_PTX_TRX_P2: length 10.7
  BOTTOM w0.089: 223.73,85.67 223.73,85.81 224.39,86.47 224.39,87.75 224.83,88.19 224.83,88.56 224.73,88.67 224.67,88.79 224.67,89.05 UH1.C18
  BOTTOM w0.094: v2(224.99,82.87) 224.8,83.06 224.56,83.06 224.23,83.39 224.23,84.57 223.73,85.07 223.73,85.67 ; v2(43.59,97.25) 43.79,97.45 43.79,97.92 44.64,98.77 44.64,99.31 CT4.1
PCIE_PTX_TRX_P3: length 6.4
  BOTTOM w0.089: UH1.C19 225.29,89.3 225.29,89.11 225.31,89.09 225.31,87.76 225.22,87.67 225.22,86.76 224.37,85.91 224.37,85.7 224.36,85.69 224.36,85.67
  BOTTOM w0.094: 224.36,85.67 224.36,85.26 224.85,84.77 v2(225.05,84.77) ; CT123.1 42.11,99.31 42.11,99.17 v2(41.9,98.96)
PCIE_PTX_TRX_P4: length 10.8
  BOTTOM w0.089: 225.79,85.67 225.79,85.67 225.79,87.4 226.09,87.7 226.09,88.75 226.21,88.87 226.31,88.87 226.37,88.93 226.37,89.13 226.31,89.19 226.31,89.43 226.22,89.52 UH1.C20
  BOTTOM w0.094: v2(39.36,98.79) 39.56,98.99 39.56,99.31 CT125.1 ; 225.79,85.67 225.79,82.49 225.59,82.29 224.74,82.29 224.56,82.47 224.32,82.47 224.17,82.62 223.9,82.62 223.77,82.5 v2(223.77,82.37)
PCIE_WAKE#: length 13.9
  TOP w0.102: RE275.1 274.87,90.72 275.33,90.72 v2(275.39,90.65) ; v2(257.24,91.98) 257.34,91.87 258.04,91.87 RE274.1 ; UZ51.1 278.13,68.34 278.13,67.32 277.68,66.88 272.82,66.88 v2(272.45,67.24)
  BOTTOM w0.102: v2(285.44,31.11) 286.2,31.87 JNGFF1.55 ; RT448.1 33.78,121.07 v2(34.32,121.07)
  BOTTOM w0.109: JNGFF3.54 v2(269.58,22.36)
PCIE_WAKE#_AR: length 12.4
  TOP w0.102: v1(44.25,115.14) 44.19,115.2 44.19,115.58 43.86,115.92 v2(43.63,115.92) ; v2(34.32,119.88) 34.27,119.88 33.54,120.61 RT555.2
  BOTTOM w0.076: 45.12,113.05 45.12,112.77 45.19,112.71 UT1.W1
  BOTTOM w0.102: 45.12,113.05 45.12,113.19 ; RT441.2 30.2,119.83 30.4,120.04 33.22,120.04 33.22,120.04 RT455.1 33.75,119.88 v2(34.32,119.88)
  BOTTOM w0.107: 45.12,113.19 45.12,114.77 44.33,115.56 43.9,115.56 43.63,115.83 v2(43.63,115.92)
PCIE_WAKE#_AR_R: length 2.9
  BOTTOM w0.102: UT32.4 29.69,120.52 29.52,120.35 29.52,119.67 RT441.1 RT440.2 29.61,118.44 29.84,118.22 v1(29.84,117.99)
PCIE_WAKE#_R: length 4.2
  TOP w0.109: UE1.N13 271.14,91.59 272.3,91.59 272.69,91.2 v1(272.85,91.2) 273.48,91.2 RE275.2 273.81,90.86 273.81,90.53 273.79,90.51 RE35.1
PCIECOMP: length 11.4
  BOTTOM w0.089: UH1.A13 222.37,88.3 222.37,85.82 v1(222.15,85.6) 221.96,85.41
  BOTTOM w0.109: 221.96,85.41 221.65,85.1 221.1,85.1 220.48,84.47 220.48,82.76 219.18,81.47 217.67,81.47 217.4,81.74 216.8,81.74 RH192.1
PCIECOMP#: length 11.3
  BOTTOM w0.089: UH1.B12 222.2,88.53 222.16,88.49 222.16,86.1 221.8,85.74
  BOTTOM w0.109: 221.8,85.74 221.38,85.31 v1(220.7,85.31) 220.06,84.67 220.06,82.93 219.01,81.88 217.84,81.88 217.57,82.15 216.76,82.15 RH192.2
PD1_GPIO0: length 3.7
  TOP w0.102: v1(60.24,104.9) RT69.1 61.21,104.28 v2(61.08,104.15)
  BOTTOM w0.076: v2(61.08,104.15) 61.08,104.63 61.59,105.13 61.96,105.13 UT5.B2
PD1_GPIO2: length 6.2
  TOP w0.107: RT71.1 68.37,106.23 69.02,106.88 v2(69.08,106.94)
  BOTTOM w0.076: 66.92,106.63 66.46,106.63 UT5.D10
  BOTTOM w0.107: v2(69.08,106.94) 68.64,106.5 v1(68.45,106.5) 67.05,106.5 66.92,106.63
PD1_GPIO5: length 5
  TOP w0.107: v2(67.87,107.22) 69.05,108.4 v1(69.53,108.4) 70.16,108.4 RT74.1
  BOTTOM w0.076: UT5.E10 66.46,107.13 67.77,107.13 v2(67.87,107.22)
PD1_GPIO6: length 6.5
  BOTTOM w0.076: UT5.G10 66.46,108.13 67.16,108.13 67.55,108.52 v1(68.07,108.52) 68.37,108.52
  BOTTOM w0.102: 68.44,108.52 68.37,108.52
  BOTTOM w0.107: 68.44,108.52 68.45,108.53 68.93,108.53 69.27,108.87 69.27,110.81 69.72,111.26 RT75.1
PD1_GPIO7: length 2
  TOP w0.102: v2(64.45,105.91) v1(64.45,105.36)
  TOP w0.107: v2(64.45,105.91) 64.45,106.4 RT339.1
  BOTTOM w0.076: v2(64.45,105.91) 64.45,106.12 UT5.D7
PD1_GPIO8: length 4.4
  TOP w0.107: RT76.1 62.12,110.75 v1(63.24,110.75) 63.69,110.75 63.84,110.6 RT377.1 63.96,109.48 63.96,108.88 v2(63.99,108.86)
  BOTTOM w0.076: v2(63.99,108.86) 63.99,108.6 UT5.H6
PD#: length 9.9
  TOP w0.203: UA1.40 283.82,57.28 283.65,57.45 283.46,57.45
  TOP w0.254: RA18.1 278.01,59.84 CA31.1 279.98,59.84 280.59,59.23 280.95,59.23 v1(281.5,58.69) 282.74,57.45 283.46,57.45 ; RA18.1 277.02,59.85 DA8.2 RA50.2 ; RA18.1 RA48.2
PECI_EC_R: length 3.9
  TOP w0.109: UE1.K13 271.18,93.42 271.53,93.42 271.55,93.44 271.86,93.44 272.09,93.67 272.09,94.12 272.32,94.35 v1(272.89,94.35) 273.41,94.86 273.75,94.86 RE60.1
PEG_COMP: length 5.7
  TOP w0.127: v2(169.51,84.19) 170.44,83.27 170.44,82.46 170.95,81.95 v1(170.95,81.29) RC2.2
  BOTTOM w0.076: v2(169.51,84.19) 169.84,83.87 UC1.G2
PG_1.05VALWP: length 3.5
  BOTTOM w0.102: PR1712.1 191.63,87.56 v1(191.19,87.13)
  BOTTOM w0.254: PR1712.1 PR1711.2 193.21,87.46 PU301.9
PGOOD_3V: length 3.7
  BOTTOM w0.102: v1(245.99,44.71) 246.21,44.93 246.21,45.07 245.93,45.35
  BOTTOM w0.254: PU100.9 245.93,45.28 245.11,44.46 PR119.1 244.72,44.14 244.52,43.94 PR107.2
PGOOD_5V: length 5
  BOTTOM w0.102: PR120.1 v1(244.28,41.35)
  BOTTOM w0.254: PR120.1 243.91,42.3 243.65,42.56 v2(243.65,42.68) ; PU102.9 196.59,36.76 196.34,37.01 v2(196.34,38.19) PR113.2
PLTRST_CPU#: length 34.1
  TOP w0.102: v2(212.9,101.23) 212.9,100.6 212.95,100.56 212.95,99.93 212.09,99.07 210.31,99.07 210.29,99.08 v1(206.81,99.08) 206.54,99.08 203.98,101.65 203.03,101.65 202.55,101.17 v2(202.07,101.17) ; v2(123.4,105.2) 123.41,105.2 123.73,105.52 127.1,105.52 128.58,107.01 v2(129.31,107.01)
  TOP w0.109: CH550.1 212.78,101.36 v2(212.9,101.23)
  BOTTOM w0.076: UC1.BP35 134.13,107.38 133.81,107.38 133.65,107.22 129.52,107.22 v2(129.31,107.01) 129.31,106.54
  BOTTOM w0.089: UH1.AG5 218.31,101.24 218.28,101.21 218.09,101.21 217.96,101.08 217.07,101.08 216.88,100.89 213.24,100.89 v2(212.9,101.23)
  BOTTOM w0.109: CC549.1 129.56,106.28 129.31,106.54
PLTRST_LAN#: length 40.2
  TOP w0.089: v2(273.11,116.22) 273.43,116.53 273.43,116.91 273.52,117.01 273.65,117.01 273.76,116.9 UL1.36
  TOP w0.102: v2(223.83,133.51) 224.07,133.51 224.21,133.36 v1(224.59,133.36) RH62.1
  BOTTOM w0.102: v2(253.82,122.17) 253.76,122.12 249.98,122.12 247.51,124.6 242.12,124.6 240.13,126.59 234.5,126.59 232.21,128.88 232.21,131.14 229.48,133.87 224.19,133.87 v2(223.83,133.51)
PLTRST_TPM#: length 18
  TOP w0.102: UZ12.17 241.57,127.86 241.57,128.25 241.1,128.72 241.1,133.3 239.86,134.55 v1(234.75,134.55) 230.42,134.55 RH187.1
PM_LANPHY_ENABLE: length 6.8
  TOP w0.109: v2(270.54,108) 270.54,107.42 270.84,107.12 RL7.1
  BOTTOM w0.089: UH1.BF41 236.25,110.52 236.12,110.65 236.12,111.26 236.17,111.31 236.17,113.5 237.02,114.36 237.02,115.16 v2(237.11,115.26)
POWER_SW#_MB: length 13
  TOP w0.102: v2(265.4,113.93) 265.4,113.64 v4(264.41,112.65) 263.88,112.12 CE10.1 263.9,111.49 RE33.2 ; v2(238.12,38.87) 238.12,38.74 238.45,38.42 238.93,38.42 239.45,38.94 RZ1414.1 ; v2(227.07,33.32) 227.06,33.3 JAPS1.11 ; SW3.4 SW3.2 308.83,116.2 v2(308.27,115.64)
POWER_SW#_MB_USH: length 4.8
  TOP w0.102: RZ1414.2 239.45,40.65 v1(238.82,41.29) 238.76,41.35 237,41.35 v2(236.56,40.91)
  BOTTOM w0.109: JUSH1.26 236.78,40.8 236.67,40.91 v2(236.56,40.91)
POWER_SW_IN#: length 19.7
  TOP w0.102: RE31.2 RE33.1 CE12.1 261.9,109.85 QZ21.3 261.46,109.82 259.98,108.34 v2(259.65,108.34)
  TOP w0.109: UE1.D5 264.51,98.53 264.87,98.17 v2(264.87,98.17)
  BOTTOM w0.109: v2(264.87,98.17) 264.67,98.37 264.67,98.38 264.49,98.56 264.49,100.11 262.92,101.67 262.92,101.92 262.38,102.47 262.38,106.85 262.15,107.07 v1(260.66,107.07) 260.22,107.07 259.65,107.64 v2(259.65,108.34)
PROCHOT#: length 29.3
  TOP w0.102: v2(117.26,102.5) v2(118.93,102.5)
  TOP w0.109: v2(275.44,96.41) 274.84,96.41 RE288.2
  BOTTOM w0.102: PR745.1 132.19,33.71 134.36,35.89 134.36,37.17 133.76,37.77 133.76,40.55 134.36,41.15 134.36,42.49 v2(134.04,42.81) ; RC84.1 126.73,101.99 126.29,101.99 RC83.2 CC324.1 126.29,103.33 125.28,104.34 123.38,104.34 122.76,103.72 122,103.72 121.26,102.98 119.16,102.98 118.93,102.75 v2(118.93,102.5)
  BOTTOM w0.109: PRZ16.2 96.54,95.84 v2(96.3,95.84) 95.69,95.84 PRZ6.2
  BOTTOM w0.203: PR719.1 129.65,33.78 PR745.1
PROCHOT#_CHG: length 4.1
  TOP w0.102: v2(127.67,34.79) 127.91,34.56 v1(127.91,34.24)
  TOP w0.254: PQ812.1 111.95,74.12 v2(111.87,74.04)
  BOTTOM w0.203: PU700.23 127.17,35.76 127.67,35.27 v2(127.67,34.79) 127.9,34.57 PR719.2
PROCHOT#_R1: length 3.4
  TOP w0.109: RE288.1 273.22,96.34 v1(272.49,95.6) 272.41,95.53 271.07,95.53 UE1.H13
PROG_CHG: length 3.8
  BOTTOM w0.203: PR725.1 127.86,32.8 127.45,33.21 126.31,33.21 125.35,34.17 PU700.27
PROM_BIOS: length 3.2
  TOP w0.102: v1(254.66,56.87) RZ401.2
  TOP w0.109: UZ6.1 257.28,57.53 RZ400.2 RZ401.2
PROM_BIOS_R: length 29.2
  TOP w0.102: RZ401.1 v1(253.17,57.79) 252.16,57.79 251.8,57.43 v2(251.43,57.43)
  BOTTOM w0.102: JSPI1.4 241.31,130.81 243.06,129.06 243.35,129.06 244.06,128.34 244.34,128.34 250.1,122.58 254.05,122.58 254.85,121.78 v2(254.85,114.61)
PS_ID: length 2.1
  TOP w0.109: v2(267.29,94.05) 267.29,94.11 UE1.J8
  TOP w0.254: PR5.2 48.48,124.11 PR4.1 47.43,124.11 47.29,124.26 v2(47.22,124.26)
PSYS_CHG: length 2.2
  BOTTOM w0.203: PU700.30 124.15,33.4 124.43,33.12 PR731.1
PTP_DISABLE#: length 4.1
  TOP w0.102: RE605.1 272.09,86.65 271.94,86.81 v2(271.94,87.07)
  TOP w0.109: UE1.N12 270.07,91.09 270.79,90.37 271.69,90.37 271.99,90.07 272,90.07 v2(272.1,89.98) ; RZ1475.1 v2(188.41,41.03)
PTP_DISABLE#_R: length 3.3
  TOP w0.109: RZ1475.2 188.41,39.37 188.51,39.27 v1(188.51,38.97) 188.51,38.79 188.28,38.56 188.28,38.36 v2(188.28,38.35)
  BOTTOM w0.109: v2(188.28,38.35) 188.29,38.52 188.51,38.75 JKBTP1.11
PWM1_1PH/ICCMAX1_CPU: length 3.5
  TOP w0.254: PRZ26.1 98.49,100.32 v2(98.5,100.31)
  BOTTOM w0.203: PUZ1.44 v2(98.5,100.31)
  BOTTOM w0.254: v2(196.53,120.09) 196.86,119.76 PUA1.1
PWM1_2PH/ICCMAX2_CPU: length 3.3
  TOP w0.102: v2(107.83,99.56) 107.41,99.56 107.13,99.83 PRZ63.1
  BOTTOM w0.203: PUZ1.23 107.19,99.91 107.54,99.56 v2(107.83,99.56)
  BOTTOM w0.254: v2(99.31,84.66) 99.31,84.78 99.71,85.18 PUT1.1
PWM1_4PH/ICCMAX4_CPU: length 4.7
  TOP w0.254: PRZ66.1 108.75,103.43 108.26,102.94 108.26,102.43 v2(108.28,102.41)
  BOTTOM w0.203: PUZ1.18 107.83,101.91 108.28,102.35 v2(108.28,102.41)
  BOTTOM w0.254: v2(159.11,130.6) 159.58,130.13 PUH1.1
PWM2_2PH/ROSC1_CPU: length 2.9
  TOP w0.254: PRZ70.1 109.25,100.22 108.4,100.22 v1(108.39,100.21) 107.89,100.21 v2(107.83,100.15)
  BOTTOM w0.203: PUZ1.22 107.33,100.31 107.48,100.15 v2(107.83,100.15)
PWM2_4PH/ADDR_CPU: length 6
  TOP w0.102: v1(106.74,102.5) 107.54,101.7 v2(108.29,101.7)
  TOP w0.254: PRZ67.1 109.19,102.6 v2(108.29,101.7)
  BOTTOM w0.203: PUZ1.19 108.09,101.51 v2(108.29,101.7)
  BOTTOM w0.254: v2(169.11,130.5) 169.62,129.99 PUH2.1
PWM3_4PH/VBOOT_CPU: length 4.4
  TOP w0.102: v2(179.03,130.16) 178.75,130.16 v1(178.4,130.51)
  TOP w0.254: PRZ68.1 109.18,101.78 v2(108.57,101.17)
  BOTTOM w0.203: v2(108.57,101.17) 107.16,101.17 107.1,101.11 PUZ1.20
  BOTTOM w0.254: v2(179.03,130.16) 179.32,129.87 PUH3.1
PWM4_4PH/ROSCM_CPU: length 4.3
  TOP w0.102: v2(107.64,100.71) 107.45,100.71 v1(107.12,101.04)
  TOP w0.254: v2(107.64,100.71) 107.67,100.67 109.07,100.67 PRZ69.1
  BOTTOM w0.203: PUZ1.21 v2(107.64,100.71)
  BOTTOM w0.254: v2(188.63,130.33) 188.63,130.19 188.88,129.94 PUH4.1
PWM_FAN1: length 2.4
  TOP w0.109: 92.49,91.28 92.52,91.28 v2(92.95,91.71) ; UE1.L10 268.16,92.61 268.16,92.59 v2(268.09,92.52)
  BOTTOM w0.109: JFAN1.2 v2(92.95,91.71)
REFCLK_CNV: length 4.3
  TOP w0.102: v2(288.45,42.28) v1(288.45,42.85)
  TOP w0.109: v2(219.37,94.84) 219.37,95.19 CH554.1 RH110.1
  BOTTOM w0.089: UH1.R6 219.37,95.22 v2(219.37,94.84)
  BOTTOM w0.102: JNGFF1.64 v2(288.45,42.28)
REM_DIODE1_N: length 6.4
  TOP w0.127: v2(268.15,104.22) 268,104.08 268,103.8 CE24.1 268.02,103.08 268.02,102.84 266.71,101.53 266.71,101.09 UE1.A8 ; QE3.3 146.22,94.87 146.22,94.45 CE35.1 146.36,94.05 v2(146.36,93.53)
REM_DIODE1_P: length 8.7
  TOP w0.127: UE1.A7 266.11,100.93 266.46,101.27 266.46,101.6 267.8,102.94 267.8,103.09 CE24.2 267.75,103.72 267.75,104.09 267.62,104.22 v2(267.56,104.22) ; QE3.1 146.03,95.98 QE3.2 145.77,94.93 145.77,94.38 CE35.2 145.76,93.99 v2(145.76,93.53)
REM_DIODE2_N: length 20.9
  TOP w0.109: v2(269.33,105.91) 269.18,105.76 269.18,105.55 CE26.1 269.19,104.88 269.19,102.73 268.27,101.81 268.27,101.14 UE1.A10
  BOTTOM w0.127: QE5.3 264.71,31.38 CE37.2 265.23,30.86 265.23,30.13 265.51,29.85 266.99,29.85 267.27,30.13 267.27,31.88 v2(267.43,32.05) ; QE7.1 129.6,42.16 QE7.2 129.9,43.76 132.14,43.76 132.26,43.63 CE46.2 131.26,42.27 v2(131.26,41.55)
REM_DIODE2_P: length 18.9
  TOP w0.109: v2(268.74,105.91) 268.94,105.71 268.94,105.55 CE26.2 268.93,104.88 268.93,102.84 268.01,101.92 268.01,101.26 UE1.A9
  BOTTOM w0.127: v2(266.85,32.05) 266.89,32.05 267.01,31.92 267.01,30.23 266.89,30.11 265.62,30.11 265.49,30.23 265.49,30.86 CE37.1 266.01,31.38 QE5.2 265.36,32.98 QE5.1 266.95,34.23 v1(267.08,34.36) ; QE7.3 130.25,43.38 130.38,43.51 131.12,43.51 CE46.1 131.35,42.85 130.81,42.3 v2(130.81,42.05)
REM_DIODE4_N: length 21.1
  TOP w0.109: UE1.A11 269.12,101.08 269.12,101.33
  TOP w0.127: 269.12,101.33 270.38,102.59 270.38,103.15 CE27.1 270.38,103.84 270.38,104.53 v2(270.25,104.66)
  BOTTOM w0.127: v2(267.76,115.74) 267.76,115.71 267.9,115.57 267.9,115.02 267.03,114.15 267.03,108.35 268.08,107.3 268.08,106.67 268.07,106.66 268.07,105.48 269.45,104.09 269.83,104.09 270.07,104.34 270.07,104.48 v2(270.25,104.66) ; v2(146.62,122.32) 146.51,122.22 146.51,121.82 CE39.1 147.03,121.29 QE6.3
REM_DIODE4_P: length 22.7
  TOP w0.109: CE27.2 270.14,103.16 270.14,102.71 268.87,101.44 268.87,100.52 UE1.B10
  TOP w0.127: v2(269.65,104.51) 270.12,104.04 270.12,103.81 CE27.2
  BOTTOM w0.127: v2(146.03,122.25) 146.26,122.02 146.26,121.82 CE39.2 145.73,121.29 QE6.2 146.38,119.69 QE6.1 ; v2(269.65,104.51) 269.59,104.58 269.33,104.58 268.32,105.59 268.32,106.56 268.33,106.57 268.33,107.41 267.28,108.46 267.28,114.04 268.16,114.92 268.16,115.52 268.35,115.71 v2(268.35,115.74)
RES_BIAS: length 3.5
  TOP w0.109: UL1.12 279.74,110.42 v1(280.07,110.1) 280.84,109.32 RL13.1
RESERVE: length 27.7
  TOP w0.102: T418.1 v2(286.44,118.56) ; v2(297.56,117.81) 298.05,117.81 298.19,117.68 298.45,117.31 299.04,116.76 299.22,116.65 299.41,116.45 300.43,116.07 300.77,115.73 DT41.2 DT41.8 300.77,114.04 301.9,112.91 312.49,112.91 315.07,115.49 315.07,116.99 313.71,118.35 v2(312.52,118.35)
  BOTTOM w0.102: JFPBTN1.10 v2(312.52,118.35)
RESET_IN#: length 6.2
  TOP w0.109: UE1.C1 261.09,99.51 261.02,99.51 260.24,100.29 260.24,100.96 259.12,102.08 258.7,102.08 258.17,102.61 v1(257.99,102.61) 257.9,102.61 257.45,103.07 RE362.1
RESET_OUT: length 15.9
  TOP w0.102: RE548.2 251.57,94.75 v1(250.44,94.75) 248.08,94.75 248.01,94.82 v2(247.61,94.82)
  TOP w0.109: v2(263.19,96.51) 263.58,96.13 UE1.G4
  BOTTOM w0.109: v2(253.92,96.12) 253.94,96.1 254.56,96.1 256.65,98.18 259,98.18 260.5,96.68 261.28,96.68 261.93,96.02 262.71,96.02 v2(263.19,96.51)
RING2:
  vias: v1(295.46,33.54) v2(284.35,50.51) v2(284.35,49.92) v2(284.35,49.34) v2(294.89,33.92) v2(294.89,33.28) v2(294.89,32.65)
RING2_R: length 0.9
  TOP w0.127: v2(303.66,34.08) v4(303.66,34.98)
  vias: v2(303.66,33.44) v2(303.66,32.81)
RJ45_MDIN0: length 1.6
  BOTTOM w0.254: v2(297.13,101.33) 297.72,101.33 297.89,101.5 TL1.22
RJ45_MDIN1: length 1.6
  BOTTOM w0.254: v2(297.13,104.33) 297.6,104.33 297.78,104.5 TL1.19
RJ45_MDIN2: length 1.6
  BOTTOM w0.254: TL1.16 297.73,107.5 297.49,107.26 v2(297.16,107.26)
RJ45_MDIN3: length 1.6
  BOTTOM w0.254: TL1.13 297.75,110.5 297.58,110.33 297.22,110.33 v2(297.18,110.37)
RJ45_MDIP0: length 1.7
  BOTTOM w0.254: v2(297.13,100.69) 297.46,100.69 297.65,100.5 TL1.23
RJ45_MDIP1: length 1.7
  BOTTOM w0.254: v2(297.13,103.69) 297.57,103.69 297.76,103.5 TL1.20
RJ45_MDIP2: length 1.6
  BOTTOM w0.254: v2(297.16,106.68) 297.5,106.68 297.68,106.5 TL1.17
RJ45_MDIP3: length 1.6
  BOTTOM w0.254: v2(297.16,109.73) 297.5,109.73 297.73,109.5 TL1.14
RTC_DET#: length 3.6
  TOP w0.254: v2(35.94,125.73) 35.69,125.48 PQ13.1
  BOTTOM w0.089: v2(224.91,109.39) 224.91,109.49 224.83,109.57 224.83,110.23 224.93,110.33 UH1.BF18
  BOTTOM w0.102: v2(225.96,121.67) 226.3,121.67 226.43,121.54 v1(226.43,121.35) 226.43,120.54 RC866.2
RTCRST_ON: length 15.9
  TOP w0.102: QE12.2 268.47,107 268.47,106.22 RE93.1 266.93,105.65 v2(266.92,105.66)
  TOP w0.109: UE1.F11 v2(268.87,96.53)
  BOTTOM w0.102: v2(266.92,105.66) 266.92,104.84 267,104.75 267,104.1 267.54,103.56 267.54,102.04 v1(267.5,102) 267.13,101.63 267.13,100.95 266.89,100.71 266.89,96.15 267.33,95.7 268.28,95.7 268.87,96.3 v2(268.87,96.53)
RTCRST_ON_POWER: length 8.6
  TOP w0.102: v2(276.69,103.2) 276.7,103.2 277.19,103.68 277.19,103.96 277.49,104.26 RE565.2
  TOP w0.109: UE1.B13 271.14,100.13 v2(271.53,100.52)
  BOTTOM w0.102: v2(276.69,103.2) 276.14,102.64 v1(275.84,102.64) 273.76,102.64 271.63,100.52 v2(271.53,100.52)
RTCRST_ON_R: length 6.3
  TOP w0.102: v1(284.05,106.56) QE17.2 284.05,104.38 CE65.1 285.22,102.32 DE2.2 284.96,100.9 RE543.1
RTCRST_ON_R1: length 16.8
  TOP w0.102: RE565.1 277.78,103.2 278.91,103.2 279.01,103.1 279.01,102.58 279.56,102.04 ; v2(279.9,103.01) 279.9,103.01 279.56,102.66 279.56,102.04 ; RE543.2 284.92,99.26 285.17,99.01 v1(285.81,99.01) 286,99.01 286.71,99.72 CE64.1 286.65,100.02 RE541.2 286.57,100.92 286.57,101.97 DE2.1 286.32,102.05 v2(285.94,102.44) ; 279.56,102.04 QE15.2
  BOTTOM w0.102: v2(279.9,103.01) 279.91,103.01 280.12,103.22 285.15,103.22 v2(285.94,102.44)
RTD3_CIO_PWR_EN: length 2.1
  TOP w0.109: RC559.2 209.42,106.37 v2(209.67,106.63)
  BOTTOM w0.089: UH1.AE43 237.08,100.69 v2(237.05,100.72)
  BOTTOM w0.107: RT392.2 36.51,118.32 v2(36.44,118.39)
RTD3_CIO_PWR_EN_R: length 8
  BOTTOM w0.076: 39.62,113.58 39.62,112.87 39.21,112.46 UT1.F1
  BOTTOM w0.102: 39.62,113.68 39.62,113.58
  BOTTOM w0.107: 39.62,113.68 39.09,114.21 38.33,114.21 37.27,115.26 RT372.1 RT392.1 RT25.1
RTD3_SELECT: length 3
  TOP w0.109: RE509.1 275.42,97.42 275.44,97.4 v2(275.6,97.4)
  BOTTOM w0.102: UT32.6 30.44,121.82 30.54,121.92 30.54,122.63 v2(30.41,122.76) RT447.2
RTD3_SELECT_EC: length 3.6
  TOP w0.109: RE509.2 272.52,97.42 271.53,96.43 271.37,96.43 UE1.F13
RTD3_USB_PWR_EN: length 1.7
  TOP w0.107: RT26.1 38.67,110.78 v2(38.39,110.5)
  BOTTOM w0.102: UT1.D4 v2(38.39,110.5)
RUN_ON: length 54.4
  TOP w0.102: RZ320.1 183.94,95.18 184.21,95.45 v2(185.48,95.45) UZ35.2 ; v2(251.02,54.07) v1(254.12,54.07) 254.78,54.07 256.04,55.33 258.32,55.33 259.01,54.65 259.01,54.25 v2(259.15,54.11) ; UE5.4 262.99,121.66 264.02,122.68 RE280.2 264.8,122.12 264.8,121.24 v2(265.13,120.91) ; v2(254.76,109.35) 254.71,109.4 254.66,109.4 254.64,109.42 253.8,109.42 253.68,109.29 QE2.2
  TOP w0.109: v2(259.15,54.11) 259.15,53.49 259.25,53.39 UZ3.5 ; RZ345.1 269.55,37.62 269.55,38.05 v2(269.63,38.13) ; v2(269.48,42.4) 269.43,42.46 UZ4.3 ; v2(262.64,52.27) UZ54.1
  BOTTOM w0.102: v2(263.52,46.68) 264.92,46.68 265.36,46.24 267.58,46.24 267.84,45.98 267.84,44.59 269.48,42.94 v2(269.48,42.4) ; v2(254.76,109.35) 254.76,109.36 255.07,109.66 255.07,110.72 255.71,111.36 256.1,111.36 257.34,112.6 257.34,113.4 257.34,116.36 255.86,117.84 255.86,121.08 255.96,121.18 256.01,121.18 v2(256.01,121.19) ; v2(262.64,52.27) 259.01,52.27 258.69,52.59 258.69,53.67 259.14,54.11 v2(259.15,54.11) ; RE292.1 263.59,121.02 263.7,120.91 v2(265.13,120.91) ; PR402.1 200.62,93.92 v2(200.66,93.89)
RUN_ON#: length 3.3
  TOP w0.102: QE2.6 QE2.5 253.68,105.81 253.75,105.74 RE68.1 254.95,105.61 v1(255.01,105.67)
RUN_ON_1.8V: length 2.2
  TOP w0.109: UZ8.3 268.71,36.39 CZ197.1 RZ345.2
RUN_ON_EC: length 31.2
  TOP w0.102: UE5.2 263.53,123.42 263.25,123.14 263.25,123.11 262.95,122.8 v2(262.95,122.41)
  TOP w0.109: UE1.E8 267.3,98.15 v2(267.3,98.19)
  BOTTOM w0.102: DE43.1 267.67,100.25 267.67,100.12 267.67,99.68 267.75,99.6 267.75,98.64 v2(267.3,98.19) ; v2(263.26,102.5) 262.84,102.92 262.84,107.78 259.06,111.55 259.06,120.58 259.58,121.1 v1(262.12,121.1) 262.84,121.1 262.95,121.21 v2(262.95,122.41) 263.19,122.41 263.34,122.26 RE292.2 263.62,122.29 263.62,123.02 RE718.2
RUNPWROK: length 4.7
  TOP w0.102: QE2.3 252.95,108.92 CE549.1 252.99,109.84 RE67.1 253.44,111.02 v1(253.44,111.91) v2(253.44,112.76)
  TOP w0.109: v2(262.47,96.44) 262.56,96.44 UE1.G3
S1_OVP: length 25.1
  TOP w0.102: v2(110.9,126.24) 110.9,127.97 109.37,129.5 109.37,131.3 109.05,131.61 109.05,133.96 107.91,135.1 106.57,135.1 104.83,133.36 102.19,133.36 101.86,133.03 101.86,132.74 101.66,132.53 100.88,132.53 PR46.1
  TOP w0.254: PR46.1 PR32.2 99.75,132.09 99.58,131.91 PQ10.3 ; PR836.2 108,78.17 107.69,77.86 107.69,77.15 108.06,76.78 108.06,76.48 108.15,76.39 v2(108.15,76.09)
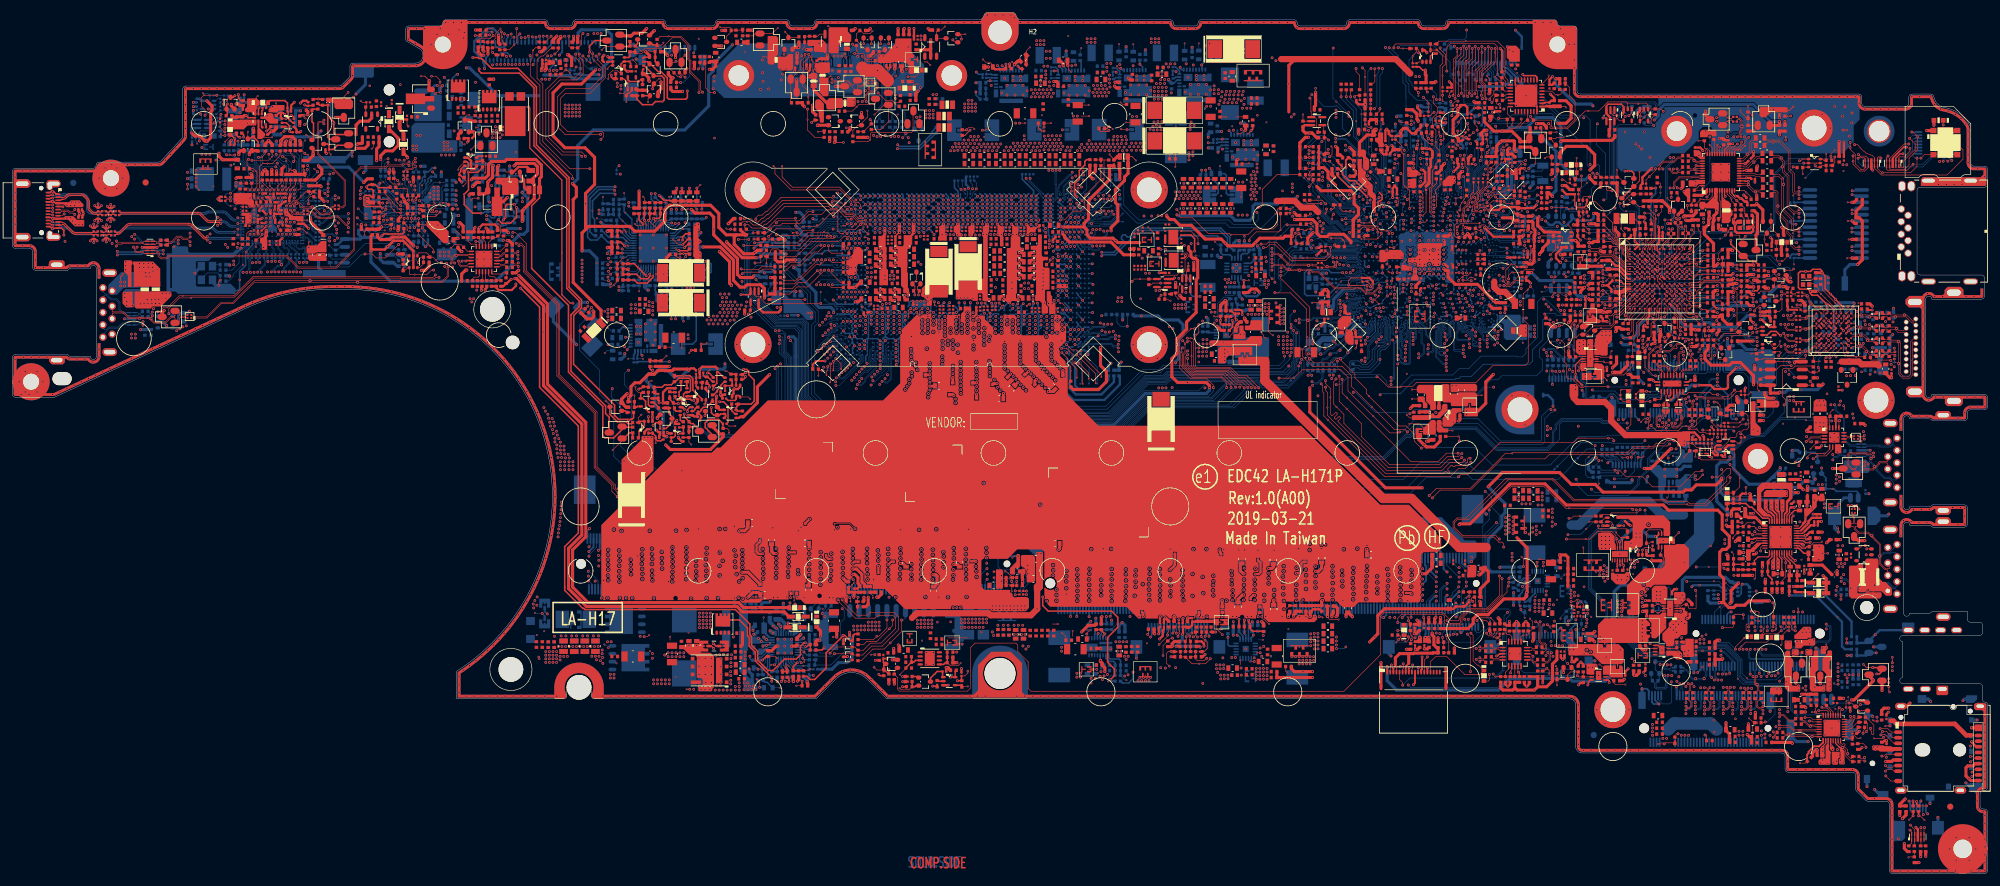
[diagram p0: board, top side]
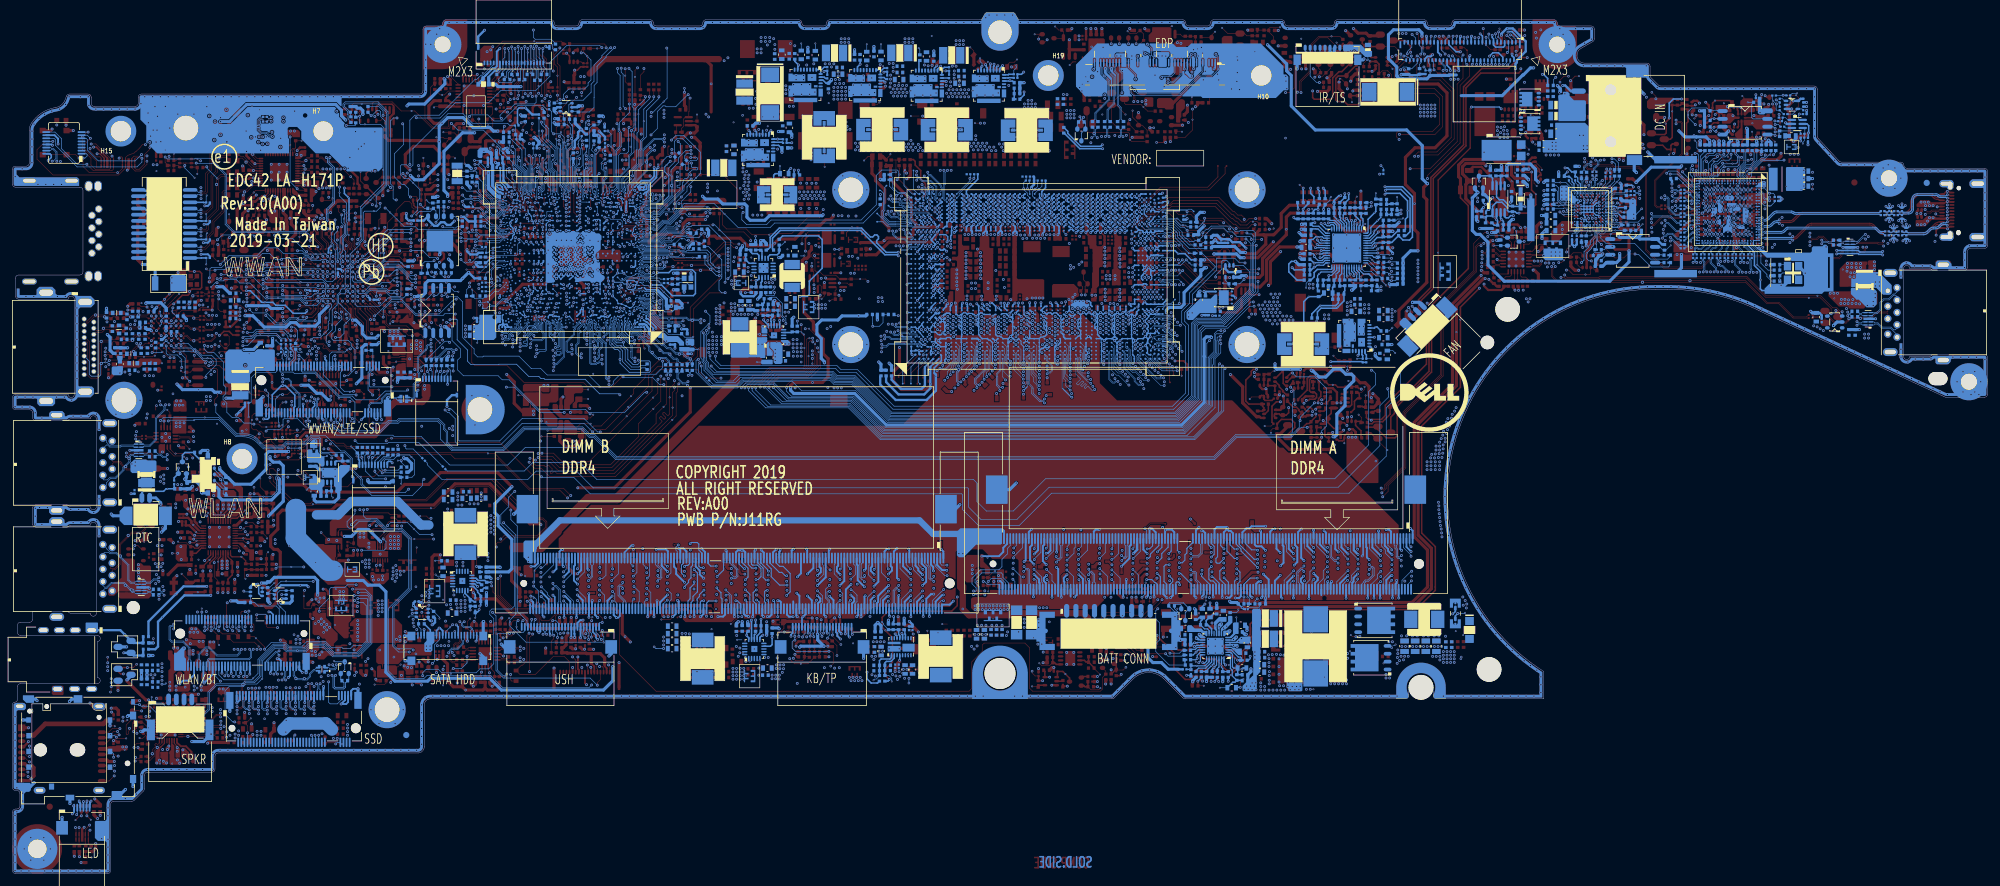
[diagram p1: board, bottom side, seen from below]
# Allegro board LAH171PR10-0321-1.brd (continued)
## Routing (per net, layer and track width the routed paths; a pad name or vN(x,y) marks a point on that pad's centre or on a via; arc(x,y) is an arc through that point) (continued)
SATA_PRX_C_DTX_N2: length 6.8
  TOP w0.094: CN6.1 247.62,34.23 247.89,34.23 248.22,34.57 248.22,35.53 248.01,35.74 v2(248.01,35.75)
  BOTTOM w0.094: v2(248.01,35.75) 248.22,35.97 248.22,36.07 248.02,36.27 247.07,36.27 246.2,37.13 246.2,37.65 246.04,37.8 JSATA1.5
SATA_PRX_C_DTX_P2: length 7.1
  TOP w0.094: v2(248.59,35.69) 248.58,35.69 248.41,35.52 248.41,34.49 247.97,34.05 247.62,34.05 CN7.1
  BOTTOM w0.094: JSATA1.6 246.55,37.8 246.39,37.65 246.39,37.21 247.14,36.45 248.1,36.45 248.41,36.14 248.41,35.87 248.58,35.69 v2(248.59,35.69)
SATA_PRX_C_RD_DTX_N2: length 2.1
  TOP w0.094: UN7.4 240.29,35.04 239.98,34.72 239.2,34.72 CN14.2
SATA_PRX_C_RD_DTX_P2: length 2
  TOP w0.094: UN7.5 239.29,34.54 CN15.2
SATA_PRX_DTX_N2: length 1.8
  TOP w0.094: v2(237.03,34.88) 237.23,34.68 237.62,34.68 CN14.1
  BOTTOM w0.089: UH1.F44 v2(238.22,90.94)
SATA_PRX_DTX_P2: length 1.8
  TOP w0.094: v2(237.03,34.3) 237.22,34.49 237.62,34.49 CN15.1
  BOTTOM w0.089: UH1.E45 238.5,90.39 v2(238.65,90.54)
SATA_PRX_RD_DTX_N2: length 2.2
  TOP w0.094: CN6.2 246.01,34.23 245.81,34.23 245,35.04 UN7.12
SATA_PRX_RD_DTX_P2: length 2
  TOP w0.094: CN7.2 246.01,34.05 245.73,34.05 245.24,34.54 UN7.11
SATA_PTX_C_DRX_N2: length 9.9
  TOP w0.094: CN5.1 247.33,35.73 247.84,36.24 247.84,36.98 247.53,37.28 247.02,37.28 246.77,37.53 v2(246.77,40.72)
  BOTTOM w0.094: v2(246.77,40.72) 246.78,40.72 246.78,40.71 246.76,40.71 246.5,40.46 246.5,40.08 246.18,39.76 245.12,39.76 244.89,39.53 244.89,39.4 245.04,39.24 JSATA1.3
SATA_PTX_C_DRX_P2: length 9.9
  TOP w0.094: CN4.1 247.08,36.43 247.18,36.33 247.55,36.33 247.65,36.43 247.65,36.9 247.45,37.09 246.95,37.09 246.59,37.45 246.59,40.32 246.19,40.71 v2(246.06,40.71)
  BOTTOM w0.094: JSATA1.2 244.55,39.24 244.7,39.4 244.7,39.61 245.04,39.95 246.11,39.95 246.31,40.15 246.31,40.59 246.19,40.71 v2(246.06,40.71)
SATA_PTX_C_RD_DRX_N2: length 2
  TOP w0.094: UN7.2 240.32,36.04 240.09,36.27 239.18,36.27 CN13.2
SATA_PTX_C_RD_DRX_P2: length 2
  TOP w0.094: CN12.2 239.31,36.45 240.02,36.45 240.1,36.54 UN7.1
SATA_PTX_DRX_N2: length 5.8
  TOP w0.094: v2(237.02,36.07) 237.27,36.32 237.64,36.32 CN13.1
  BOTTOM w0.089: UH1.B40 235.71,89.04 235.84,88.9 235.84,88.6 237.45,86.99 237.45,86.32 237.65,86.12 237.83,86.12 v2(238.22,85.73)
SATA_PTX_DRX_P2: length 5.8
  TOP w0.094: v2(237.02,36.65) 237.16,36.51 237.72,36.51 237.98,36.76 CN12.1
  BOTTOM w0.089: v2(238.22,86.31) 237.73,86.31 237.64,86.4 237.64,87.07 236.03,88.67 236.03,88.98 235.75,89.26 UH1.C40
SATA_PTX_RD_DRX_N2: length 1.7
  TOP w0.094: CN5.2 245.76,36.14 245.43,36.14 245.33,36.04 UN7.14
SATA_PTX_RD_DRX_P2: length 1.7
  TOP w0.094: UN7.15 245.33,36.54 245.54,36.33 245.88,36.33 CN4.2
SATAGP0: length 4.4
  TOP w0.102: v2(245.17,99.13) 245.23,99.2 v1(245.23,100.47) 245.17,100.53 245.17,101.36 RH316.2
  TOP w0.109: RH377.2 236.96,102.79 v2(237.24,102.51)
  BOTTOM w0.089: v2(237.24,102.51) 237.05,102.51 UH1.AH41
SATAGP3: length 6.3
  BOTTOM w0.089: v1(243.82,107.15) 243.38,106.71 RH323.2 ; UH1.AN47 239.24,104.21 239.3,104.15 240.11,104.15 240.81,104.85
  BOTTOM w0.109: 240.81,104.85 241.58,104.85 242.91,106.18 RH323.2
SATAGP5: length 2.2
  TOP w0.102: v1(237.55,103.52) 237.55,103.64 v2(237.23,103.96)
  TOP w0.109: RH325.2 236.47,104.28 236.79,103.96 v2(237.23,103.96)
  BOTTOM w0.089: v2(237.23,103.96) 237.19,103.96 237.1,103.87 UH1.AM43
SATAGP6: length 4.8
  BOTTOM w0.089: UH1.AM47 239.43,103.74 239.65,103.96 240.19,103.96 240.83,104.59 241.8,104.59
  BOTTOM w0.109: RH326.2 242.63,105.42 v1(242.38,105.17) 241.8,104.59
SBIOS_TX: length 2.8
  BOTTOM w0.089: v2(227.39,108.18) 227.73,108.18 227.89,108.33 UH1.BB24
  BOTTOM w0.102: RE306.1 255.46,65.71 256.25,66.5 v2(256.25,66.76) v1(256.78,66.76)
SCL_CHG: length 2.3
  BOTTOM w0.203: PR715.2 128.33,35.33 v2(127.86,35.81) 127.5,36.16 PU700.22
SD_1_CD#: length 4.5
  TOP w0.102: JSD1.9 303.43,14.96 v2(302.6,15.8) ; 291.97,26.36 v2(291.77,26.36)
  TOP w0.109: 291.97,26.36 293.12,26.36 293.29,26.18 UR1.30
SD_1_CLK: length 1.4
  TOP w0.102: 296.53,21.98 296.66,21.85 RR5.1
  TOP w0.109: UR1.17 296.39,22.12 296.53,21.98
SD_1_CLK_R: length 5.4
  TOP w0.102: RR5.2 298.02,20.93 CR21.1 298.99,21 299.4,20.58 v2(299.4,20.39) ; JSD1.5 302.52,19.26 302.18,18.92 302.04,18.92 v2(301.96,19)
SD_1_CMD: length 2.7
  TOP w0.102: 296.6,23.04 297.77,23.04 297.88,23.14 297.88,23.27 RR6.1
  TOP w0.109: 296.6,23.04 296.49,22.92 UR1.19
SD_1_CMD_R: length 4.5
  TOP w0.102: RR6.2 299.18,23.28 298.93,23.04 v2(298.93,22.68) ; v2(301.81,22.43) 301.87,22.49 302.48,22.49 303.91,21.06 JSD1.3
SD_1_DAT0: length 4.6
  TOP w0.089: UR1.16 295.29,21.16 295.54,20.91 295.67,20.91 295.78,21.02 295.9,21.02 296.03,20.89 296.03,20.77 295.92,20.66 295.92,20.53 296.45,20 v3(296.45,19.38) 296.45,19.08 296.9,18.63 297.05,18.63 RR10.1
SD_1_DAT0_R: length 3.4
  TOP w0.089: v2(302.55,17.46) 302.55,17.44 302.83,17.16 303.63,17.16 303.92,17.46 304.59,17.46 JSD1.7 ; v2(299.17,18.78) 299.04,18.64 298.56,18.64 RR10.2
SD_1_DAT1: length 4.6
  TOP w0.089: RR9.1 297.13,18.33 296.78,18.33 296.15,18.96 296.15,19.9 v3(295.65,20.39) 294.89,21.15 UR1.15
SD_1_DAT1_R: length 3.4
  TOP w0.089: JSD1.8 303.93,16.56 303.63,16.86 302.83,16.86 302.55,16.59 v2(302.55,16.56) ; v2(299.22,18.19) 299.07,18.34 298.5,18.34 RR9.2
SD_1_DAT2: length 3.3
  TOP w0.102: RR8.1 298.12,25.03 297.57,25.03 v1(297.39,24.85) 297.39,24.52 296.59,23.72
  TOP w0.109: UR1.21 296.59,23.72
SD_1_DAT2_R: length 7.9
  TOP w0.102: v2(301.68,23.44) 302.93,23.44 303.51,22.86 JSD1.1 ; RR8.2 299.38,25.3 300.67,24.01 300.67,22.59 300.57,22.49 300.42,22.49 300.32,22.59 300.32,23 300.08,23.24 300.08,23.42 v2(300.14,23.48)
SD_1_DAT3: length 2.9
  TOP w0.102: 296.79,23.44 296.98,23.44 v1(297.1,23.56) 298.02,24.48 RR7.1
  TOP w0.109: 296.79,23.44 296.68,23.32 UR1.20
SD_1_DAT3_R: length 4.8
  TOP w0.102: v2(302.05,22.97) 302.73,22.97 v1(303.21,22.49) 303.73,21.96 JSD1.2 ; RR7.2 299.5,24.48 299.61,24.37 299.61,23.11 v2(299.45,22.95)
SD_1_N0: length 2.7
  TOP w0.089: v2(295.61,26.53) 295.38,26.53 295.29,26.44 UR1.25 ; v2(316.28,18.06) 316.46,18.23 316.52,18.23 316.97,18.68 JSD1.19
SD_1_N1: length 2.8
  TOP w0.089: JSD1.21 317,16.86 v2(316.54,16.41) ; v2(296.9,25.41) 296.9,25.07 296.72,24.89 296.72,24.68 296.56,24.52 UR1.23
SD_1_P0: length 2.9
  TOP w0.089: UR1.26 294.89,25.58 294.89,26.6 v2(295.09,26.8) ; v2(316.28,18.93) 316.58,18.93 317.24,19.59 JSD1.18
SD_1_P1: length 3.3
  TOP w0.089: UR1.22 296.41,24.12 296.9,24.61 296.9,24.82 v2(297.48,25.4) ; v2(316.51,15.69) 316.77,15.95 JSD1.22
SD_GPIO: length 2.1
  TOP w0.109: UR1.28 294.09,26.14 293.04,27.19 RR3.2
SD_RCOMP_1P8: length 7.1
  TOP w0.254: RH611.2 214.07,112.75 v1(215.72,111.15) 215.89,110.98 217.2,110.98 v2(218.8,109.38)
  BOTTOM w0.089: UH1.BE5 218.68,109.68 218.8,109.56 v2(218.8,109.38)
SD_RCOMP_3P3: length 6.7
  TOP w0.254: 215.31,112.54 215.87,112 216.85,112 218.4,110.45 v2(218.56,110.45) ; 215.31,112.54 v1(215.32,112.54) ; 215.31,112.54 214.82,113.02 214.82,113.36 214.24,113.93 RH610.2
  BOTTOM w0.089: UH1.BE4 218.24,110.13 v2(218.56,110.45)
SDA_CHG: length 2.1
  BOTTOM w0.203: PU700.21 127.65,36.56 127.96,36.26 128.57,36.26 PR713.2
SDWP: length 9.3
  TOP w0.102: v2(296.67,27.57) 297.09,27.57 297.66,27 QR1.1
  TOP w0.109: v2(292.28,26.91) 292.45,26.74 293.11,26.74 293.69,26.16 UR1.29
  BOTTOM w0.102: v1(296.54,28.52) 296.54,28.01 296.67,27.89 v2(296.67,27.57) 294.89,27.57 294.23,26.91 v2(292.28,26.91)
SIM_DET: length 78.9
  TOP w0.102: v2(308.86,7.44) 308.78,7.36 DZ13.6 DZ13.5
  BOTTOM w0.102: v2(298.51,27.31) 298.26,27.06 v1(297.87,27.06) 296.86,27.06 295.45,25.66 288.36,25.66 287.46,26.56 287.46,29.35 286.14,30.67 281.96,30.67 281.53,31.1 280.03,31.1 279.15,31.97 279.15,34.53 276.82,36.86 275.15,36.86 274.6,36.31 271.81,36.31 271.08,37.04 268.66,37.04 267.13,35.51 263.32,35.51 261.44,37.39 261.44,44.72 261.67,44.96 v2(263.84,44.96)
  BOTTOM w0.109: v2(298.51,27.31) 299.27,27.31 299.57,27.62 JSIM1.2 ; v2(263.88,72.97) 263.88,72.97 263.72,73.13 263.72,76.17 264.5,76.95 266.3,76.95 270.18,80.83 273.51,80.83 273.75,81.07 275.72,81.07 275.82,81.18 JNGFF2.66
SIO_EXT_SMI#: length 8.6
  TOP w0.109: v2(246.57,102.18) 246.63,102.25 RH310.2
  BOTTOM w0.089: UH1.AL47 239.27,103.03 239.51,102.8 239.8,102.8 239.8,102.79 239.82,102.79 240.28,102.33 243.79,102.33 243.96,102.5 245.49,102.5 v1(245.74,102.25) 246.5,102.25 v2(246.57,102.18)
SIO_EXT_WAKE#: length 6.4
  TOP w0.102: v2(273.46,86.9) 273.34,87.03 RE703.1
  TOP w0.109: v2(227.39,106.41) 227.87,106.41 228.34,106.88 RH309.2
  BOTTOM w0.089: v2(227.39,106.41) 227.56,106.41 227.75,106.23 UH1.AU24
SIO_EXT_WAKE#_EC: length 5.4
  TOP w0.102: RE703.2 273.34,89.05 272.98,89.4
  TOP w0.109: UE1.M12 270.17,92.13 270.46,91.84 270.46,91.01 270.88,90.59 272.08,90.59 v1(272.86,89.81) 272.98,89.69 272.98,89.4
SIO_PWRBTN#: length 17.2
  TOP w0.109: UE1.K11 v2(269.67,93.33)
  BOTTOM w0.089: v2(238.34,110.33) 238.54,110.37 238.85,110.18 UH1.BE46
  BOTTOM w0.102: RC842.1 249.53,65.8 253.42,69.7 258.29,69.7 258.47,69.52 263.24,69.52 v2(263.7,69.97)
SIO_PWRBTN#_XDP: length 202.7
  TOP w0.102: v2(93.28,113.93) 90.05,113.93 85.68,118.3 85.68,127.61 84.74,128.55 84.74,131.48 85.41,132.15 85.74,132.15 87.04,133.45 CC269.1 RC241.2 88.18,133.02 v2(87.62,132.46)
  BOTTOM w0.102: JXDP1.41 88.21,133.11 87.62,132.52 v2(87.62,132.46) ; RC842.2 248.8,65.07 236.36,65.07 235.01,66.43 227.37,66.43 224.66,63.72 163.84,63.72 163.25,63.13 163.25,60.14 161.72,58.61 157.37,58.61 152.15,63.83 105.45,63.83 99.97,69.3 99.97,77.9 98.86,79 98.86,80.85 99.38,81.36 v2(99.53,81.36)
SIO_RCIN#: length 6.1
  BOTTOM w0.089: UH1.BE39 235.23,109.95 235.17,110.02 235.17,110.47 235.17,111.65 235.21,111.7 235.21,114.55 234.97,114.79 T286.1
SIO_SLP_A#: length 8.1
  TOP w0.102: JAPS1.6 224.56,33.06 224.66,33.15 v2(224.66,33.92)
  TOP w0.109: v2(236.31,114.59) 235.85,114.59 RH628.1 236.1,115.05 CH343.1
  BOTTOM w0.089: v2(236.31,114.59) 236.31,114.47 235.78,113.94 235.78,111.46 235.74,111.42 235.74,110.49 235.83,110.41 235.83,110.09 235.75,110.01 UH1.BE40
SIO_SLP_LAN#: length 48.9
  TOP w0.102: v2(252.95,81.26) 252.95,81.26 253.06,81.37 253.06,82.44 253.41,82.8 UZ2.5
  BOTTOM w0.089: 236.22,116.2 236.22,115.39 235.59,114.77 235.59,111.54 235.55,111.5 235.55,110.41 235.59,110.37 UH1.BF40
  BOTTOM w0.102: RH204.1 238.69,120.91 239.05,121.27 244.71,121.27 246.25,122.82 248.71,122.82 254.35,117.18 254.35,114.53 254.7,114.18 254.99,114.18 255.38,114.56 256.21,114.56 256.37,114.4 256.37,113 255.7,112.33 255,112.33 v1(254.31,111.64) 253.23,110.56 253.23,109.1 253.58,108.76 253.58,107.24 254.52,106.29 v2(254.55,106.29) ; RH631.1 237.65,118.6 236.22,117.17 236.22,116.2
  BOTTOM w0.109: RH631.1 237.65,119.35 CH346.1 237.75,120.79 RH204.1
SIO_SLP_S0#: length 70.3
  TOP w0.102: v2(245.23,122.37) 245.23,122.22 RZ1407.1 248.5,121.79 248.6,121.69 248.6,120.76 248.7,120.66 251.13,120.66 252.41,121.94 252.41,124.89 251.51,125.79 251.51,127.07 250.92,127.66 RZ112.1 250.82,128.46 RZ362.2 ; v2(185.54,93.48) 185.21,93.15 RH619.1 ; v2(235.59,38.86) 235.95,38.5 235.95,34.38 236.63,33.69 236.82,33.69 DN1.1 237.03,32.17 234.59,32.17 231.69,35.06 229.87,35.06 229.06,34.26 JAPS1.15
  BOTTOM w0.089: 230.06,119.17 229.93,119.04 229.93,118.18 230,118.11 230,117.95 229.99,117.94 229.99,111.44 229.71,111.16 229.71,110.74 229.91,110.54 229.91,109.76 230.03,109.64 230.03,109.32 230.07,109.28 UH1.BC28 229.82,109 v2(229.61,108.79)
  BOTTOM w0.102: v2(245.23,122.37) 244.98,122.63 242.25,122.63 241.26,121.64 239.9,121.64 237.37,124.17 233.38,124.17 232.75,123.54 RH640.1 ; PR425.1 197.35,93.52 197.25,93.42 196.06,93.42 195.96,93.52 v2(195.96,93.93)
  BOTTOM w0.109: 230.06,119.17 230.45,119.57 v2(231.61,119.57) 231.97,119.93 231.97,123.18 RH640.1
SIO_SLP_S3#: length 51.9
  TOP w0.102: JAPS1.2 222.56,33.54 v2(222.75,33.73) ; v2(266.66,123.21) 266.28,123.59 RE280.1 264.22,123.59 UE5.1 264.18,124.25 263.9,124.53 260.85,124.53 ; QE11.2 284.6,96.91 285.3,96.22 285.39,96.22 v2(285.39,96.21) ; 260.85,124.53 260.66,124.72 257.69,124.72 256.23,123.26 v1(254.57,123.26) 254.06,123.26 251.23,120.43 248.48,120.43 248.37,120.55 248.37,121.02 v2(248.15,121.24) ; 260.85,124.53 260.92,124.47 UE3.2
  BOTTOM w0.076: UT1.D2 38.5,111.74 38.5,112.31 38.17,112.65
  BOTTOM w0.089: 238.17,114.04 237.99,113.87 v2(237.93,113.87) 237.73,113.87 237.04,113.18 237.04,110.79 236.93,110.68 UH1.BF42
  BOTTOM w0.102: v2(248.15,121.24) 247.07,120.17 242.96,120.17 240.13,117.33 240.13,116.81 239.97,116.66 239.94,116.66 RH626.1
  BOTTOM w0.107: v2(32.89,115.33) 32.97,115.24 36.31,115.24 38.17,113.38 38.17,112.65
  BOTTOM w0.109: 238.17,114.04 238.17,114.37 238.3,114.5 238.3,114.99 CH341.1 239.77,116.46 RH626.1
SIO_SLP_S4#: length 53
  TOP w0.102: JAPS1.5 224.06,31.37 224.57,30.86 v2(224.57,30.45) ; UZ21.4 190.35,103.86 v1(190.91,103.29) 191.51,102.69 v2(191.51,101.8) ; v2(241.4,117.78) 240.95,117.33 240.7,117.33 240.47,117.1 240.47,116.6 240.58,116.48 CH342.1 ; PR513.1 v2(152.55,35.8)
  TOP w0.109: v2(238.79,113.4) 238.99,113.4 240.47,114.88 240.47,115.43 RH627.1 240.58,115.54 CH342.1
  BOTTOM w0.089: v2(238.79,113.4) 237.6,113.4 237.23,113.03 237.23,110.37 236.96,110.1 UH1.BE42
  BOTTOM w0.102: UZ34.2 122.47,98.67 122.87,99.07 123.59,99.07 123.69,98.97 123.69,97.71 124.7,96.7 v2(124.7,96.43) ; v2(241.5,42.23) 240.94,41.67 240.94,32.83 239.71,31.61 225.72,31.61 v2(224.57,30.45)
  BOTTOM w0.254: v2(181.01,32.56) 181.01,31.48 180.33,30.81 179.31,30.81 PR208.1
SIO_SLP_S4#_R: length 6.2
  BOTTOM w0.102: v1(179.95,31.25) 179.76,31.44 179.51,31.44 179,31.95 PR208.2
  BOTTOM w0.254: PR208.2 178.99,32.04 PR209.1 PC221.1 178.99,34.43 178.74,34.68 177.31,34.68 177.06,34.94 PU200.1
SIO_SLP_S5#: length 11.1
  TOP w0.102: JAPS1.4 223.56,33.24 223.72,33.4 223.72,33.42 223.77,33.48 v2(224.2,33.48)
  TOP w0.109: v2(237.29,115.83) 237.36,115.9 CH347.1 237.36,117.09 237.19,117.26 RH632.1
  BOTTOM w0.089: UH1.BC42 236.66,109.3 236.63,109.33 236.63,109.6 236.51,109.73 236.51,110.54 236.32,110.72 236.32,111.2 236.36,111.23 236.36,113.42 237.52,114.59 237.52,114.89
  BOTTOM w0.102: 237.52,114.89 237.52,115.08
  BOTTOM w0.109: v2(237.29,115.83) 237.29,115.62 237.52,115.4 237.52,115.08
SIO_SLP_SUS#: length 17.2
  TOP w0.102: v2(257.74,80.51) 257.83,80.6 260.27,80.6 v1(261.13,81.46) 261.69,82.03 RE349.1
  TOP w0.109: RH441.1 251.58,113.99 v2(251.9,114.31)
  BOTTOM w0.089: UH1.BD39 235.48,109.59 235.48,109.97 235.36,110.1 235.36,110.39 235.36,110.4 235.36,111.58 235.4,111.62 235.4,115.73 234.92,116.21 RH630.1 234.89,117.26 CH345.1 v2(235.54,117.99)
SIO_SLP_SUS#_R: length 9.4
  TOP w0.102: RE561.1 RE349.2
  TOP w0.109: UE1.N4 263.67,90.33 263.27,89.93 262.32,88.98 v1(262.32,87.53) 262.32,87.25 261.93,86.86 261.93,85.49 261.71,85.27 261.69,85.27 RE349.2
SIO_SLP_WLAN#: length 12
  TOP w0.102: v2(281.62,88.67) 281.19,88.67 280.79,88.27 QZ15.1 ; RH629.1 238.29,118.5 v2(238.29,117.56)
  TOP w0.109: CH344.1 238.13,118.73 RH629.1
  BOTTOM w0.089: UH1.BD42 236.88,109.62 236.7,109.81 236.7,110.61 236.52,110.79 236.52,111.12 236.55,111.15 236.55,113.35 237.72,114.52 237.72,114.58
  BOTTOM w0.109: 237.72,114.58 237.83,114.69 237.83,117.1 v2(238.29,117.56)
SKL_CNL#: length 7.1
  TOP w0.102: RC171.2 v1(130.18,80.48)
  TOP w0.109: v2(130.89,81.29) 130.44,81.29 RC171.2
  BOTTOM w0.102: 131,81.26 133.35,81.26 135.24,83.15 UC1.BN1
  BOTTOM w0.109: 131,81.26 131,81.26 130.97,81.29 v2(130.89,81.29)
SLEEVE: length 0.7
  BOTTOM w0.127: v1(294.25,30.74) 294.38,30.62 v2(294.89,30.62)
  vias: v2(285.17,50.51) v2(285.17,49.92) v2(285.17,49.34) v2(294.89,31.89) v2(294.89,31.25)
SLEEVE_R: length 0.9
  TOP w0.127: v4(303.21,29.35) 303.21,29.41 303.09,29.53 v2(303.09,30.24)
  vias: v2(303.09,31.51) v2(303.09,30.87)
SLP_WLAN#_GATE: length 16.9
  TOP w0.102: RZ518.2 278.3,87.88 278.89,88.47 QZ15.2 278.57,89.18 278.57,92.02 v1(278.25,92.34) 277.94,92.65 v2(277.94,93.28)
  TOP w0.109: UE1.K10 268.79,93.41 v2(268.79,93.34)
  BOTTOM w0.102: v2(268.79,93.34) 268.87,93.34 268.88,93.33 269.13,93.33 269.51,92.95 269.9,92.95 270.17,92.68 271.87,92.68 272.4,93.2 277.86,93.2 v2(277.94,93.28)
SLP_WLAN#_M: length 6.5
  TOP w0.102: DZ9.3 274.76,86.23 RZ71.1 275.47,86.26 v1(276.03,86.81) 276.54,87.32 278.32,87.32 278.55,87.56 QZ15.3
SML0_SMBCLK: length 10.6
  TOP w0.109: RH67.2 228.29,116.44 227.91,116.44 v2(227.78,116.57) ; UL1.28 276.96,116.92 277.52,117.49 278.09,117.49 278.54,117.93 v2(278.63,117.93)
  BOTTOM w0.089: v2(227.78,116.57) 227.85,116.49 CC318.1 228.88,116.06 228.88,115.27 228.89,115.26 v1(228.89,114.25) 228.89,111.76 228.75,111.62 228.75,111.62 228.7,111.57 228.7,110.76 228.47,110.53 UH1.BF25
SML0_SMBDATA: length 10.9
  TOP w0.109: UL1.31 v2(275.76,117.44) ; RH77.2 226.81,117.67 v2(226.98,117.84)
  BOTTOM w0.089: 227.15,117.28 227.01,117.15 227.01,114.4 227.3,114.11 227.75,114.11 227.92,113.94 227.92,113.22 v1(227.79,113.08) 227.79,112.72 227.83,112.68 227.83,112.68 227.9,112.61 227.9,111.93 227.84,111.88 227.84,110.54 227.7,110.41 227.7,110.06 227.78,109.98 UH1.BE24
  BOTTOM w0.109: 227.15,117.28 227.15,117.67 v2(226.98,117.84)
SML1_SMBCLK: length 12.4
  TOP w0.109: UE1.D8 266.97,98.53 v2(267.36,98.92) ; v2(229.3,118.54) 229.24,118.48 229.05,118.48 v3(228.72,118.82) 228.39,119.14 CC319.1 228.42,119.86 RH80.2
  BOTTOM w0.089: UH1.BF27 229.66,110.52 229.51,110.67 229.51,111.24 229.8,111.53 229.8,117.16 229.67,117.29 229.67,117.6 229.69,117.61 229.8,117.73 229.8,118.03
  BOTTOM w0.102: 229.8,118.03 v2(229.3,118.54)
SML1_SMBDATA: length 11.8
  TOP w0.109: v2(269.75,97.31) 269.69,97.31 UE1.E11 ; RH81.2 227.9,119.33 227.9,118.94 228.85,117.99 229.19,117.99 v2(229.28,117.9)
  BOTTOM w0.089: v2(229.28,117.9) 229.49,117.69 229.48,117.68 229.48,117.21 229.59,117.1 229.59,111.59 229.32,111.32 229.32,110.59 229.43,110.48 229.43,110.06 UH1.BE27
SNK0_CONFIG1: length 3.3
  TOP w0.102: v1(41.59,111.15) 41.59,111.13 42.21,110.5 v2(42.27,110.5)
  TOP w0.107: v1(41.59,111.15) 41.59,111.79 RT337.1 RT129.1
  BOTTOM w0.076: v2(42.27,110.5) 42.6,110.82 UT1.N4
SNUB1_CHG:
  vias: v1(97.57,34)
SNUB2_CHG: length 0.6
  TOP w0.102: 106.23,37.73 v1(106.23,38.3)
SNUB_1.05VALWP: length 1.9
  TOP w0.102: 201.61,88.08 201.61,87.51 202.05,87.07 202.05,86.88 v1(202.43,86.5)
SNUB_1.8VALW: length 1.5
  TOP w0.102: PR502.2 v1(226.06,76.72)
SNUB_1VS_VCCIO:
  vias: v1(193.86,100.91)
SNUB_3V:
  vias: v1(250.19,47.7)
SNUB_5V: length 1
  TOP w0.102: v1(205.86,32.52) 205.66,32.73 PC125.1
SNUB_DDR:
  vias: v1(174.33,35.42)
SPKR: length 2
  TOP w0.109: RH86.2 232.86,117.49 v2(233.17,117.18) ; RA12.2 v2(278.07,48.21)
  BOTTOM w0.089: UH1.AW29 230.87,106.87 v2(231.2,106.87)
SPKR_R: length 4.3
  TOP w0.102: v1(281.4,47.66) 281.54,47.8 281.54,48.98 CA27.1
  TOP w0.203: RA12.1 RA51.1 CA72.1 280.45,49.16 CA27.1
SRTCRST#: length 6.3
  TOP w0.102: v1(242.62,111.25) RH201.2 242.43,110.5 CH41.2 241.24,110.5 240.91,110.17
  TOP w0.109: v2(238.4,109.37) 238.43,109.37 239.23,110.17 240.91,110.17
  BOTTOM w0.089: v2(238.4,109.37) 238.65,109.63 UH1.BD46
SS_1VS_VCCIO: length 2.3
  BOTTOM w0.254: PR1708.1 198.95,100.82 198.23,100.82 PC2212.1 197.97,100.56 PU401.7
SSD_EN: length 6
  TOP w0.109: UZ53.3 266.4,55.36 266.19,55.57 264.29,55.57 263.94,55.22 v1(263.94,54.94) UZ54.4 264.4,53.4 264.6,53.59 RZ1471.2
SSD_SCP#: length 49.5
  TOP w0.102: v2(283.14,24.52) 283.01,24.52 282.89,24.39 RN129.2 282.46,25.16 RE821.1
  TOP w0.109: v2(264.9,92.53) 264.9,92.55 UE1.L6
  BOTTOM w0.102: v2(283.14,24.52) 283.46,24.52 284.7,25.76 284.7,29.56 284.05,30.21 281.77,30.21 281.34,30.64 279.56,30.64 v1(278.7,31.51) 278.66,31.54 278.66,34.37 276.63,36.41 275.34,36.41 274.78,35.85 271.62,35.85 270.89,36.59 268.85,36.59 267.32,35.05 263.13,35.05 260.98,37.2 260.98,44.91 262.06,45.98 264.09,45.98 v2(264.09,45.98)
SSD_SCP#_R: length 4.7
  TOP w0.102: v1(280.54,25.09) 281.24,24.39 RN129.1 281.54,24.37 281.07,23.9 v2(281.07,22.76)
  BOTTOM w0.109: JNGFF3.8 v2(281.07,22.76)
SSD_SCP_PWR_EN: length 11.6
  TOP w0.102: 258.62,90.14 258.62,88.94 258.21,88.53 255.39,88.53 253.98,87.12 QZ24.3 253.06,87.12 v1(252.61,86.67)
  TOP w0.109: UE1.M1 261.04,91.9 260.96,91.9 259.48,90.42 258.89,90.42 258.62,90.14
SSD_SCP_PWR_EN_D: length 9.3
  TOP w0.102: RZ1474.1 259.08,89.05 258.17,88.15 v1(256.6,88.15) 255.96,88.15 QZ24.1 255.58,87.45 255.07,86.94 254.71,86.94 254.66,86.99 254.51,86.99 v2(254.46,86.94)
  TOP w0.109: RZ1472.2 264.94,52.36 ; 264.94,52.36 RZ1471.1 ; 264.94,52.36 264.59,52.72 263.72,52.72 v2(263.29,52.28) UZ54.2
SUSACK#_R: length 6.4
  BOTTOM w0.089: UH1.BE35 233.63,109.78 233.63,110.4 233.35,110.68 233.35,111.25 233.63,111.53 233.63,112.97 233.5,113.11 233.5,115.56 T421.1
SUSCLK: length 5.6
  TOP w0.102: RN99.2 268.54,22.3 268.84,22.6 v2(269.04,22.6)
  TOP w0.109: RZ56.1 284.48,43.64 v2(284.34,43.77) ; v2(237.96,109.76) 238.07,109.87 238.5,109.87 239.31,110.68 RH83.1
  BOTTOM w0.089: UH1.BE45 238.05,109.85 v2(237.96,109.76)
SUSCLK_R: length 3.7
  TOP w0.102: RN99.1 267,21.14 v2(266.82,20.97) v1(265.81,20.97)
  BOTTOM w0.109: v2(266.82,20.97) 266.56,21.23 JNGFF3.68
SVID_ALERT#_PWR_CPU: length 2.5
  BOTTOM w0.109: PUZ1.41 99.98,99.11 98.84,97.97 PRZ21.1
SVID_CLK_PWR_CPU: length 2.3
  BOTTOM w0.109: PRZ19.1 98.97,98.79 98.99,98.82 99.06,98.82 v1(99.37,99.13) 99.74,99.51 PUZ1.42
SVID_DAT_PWR_CPU: length 2.7
  BOTTOM w0.109: PUZ1.40 100.28,98.71 v1(99.4,97.83) 98.72,97.14 PRZ23.1
SW_TBT_A_USB20_N1: length 3.6
  BOTTOM w0.076: 64.81,110.94 64.81,110.92 64.65,110.76 64.65,110.28 64.71,110.22 UT5.L7
  BOTTOM w0.094: RT122.2 25.17,102.1 25.64,102.1 25.75,102.2 26.61,102.2 v2(26.79,102.39)
  BOTTOM w0.112: 64.81,110.94 v2(65.02,111.14)
SW_TBT_A_USB20_N1_R: length 8
  TOP w0.094: JUSBC1.A7 7.71,106.82 ; 8.42,107.03 8.94,107.03 9.22,106.75 9.97,106.75 10.07,106.66 v2(10.07,106.54)
  TOP w0.102: 8.42,107.03 7.91,107.03 7.71,106.82
  BOTTOM w0.094: RT122.1 23.69,102.07 23.3,102.07 23.15,102.22 DT40.1 DT40.9 21.3,102.22 21.2,102.12 21.07,102.12 19.88,103.32 v2(19.74,103.32)
SW_TBT_A_USB20_N2: length 6.6
  TOP w0.094: v2(28.7,102.12) 28.32,102.5 27.51,102.5 27.19,102.82 26.65,102.82 25.72,101.88 25.17,101.88 RT121.1
  BOTTOM w0.076: 64.13,111.74 64.01,111.61 64.01,111.08 64.21,110.88 UT5.L6
  BOTTOM w0.089: 64.13,111.74 64.14,111.74 v2(64.14,111.8)
SW_TBT_A_USB20_N2_R: length 8.4
  TOP w0.094: RT121.2 23.73,101.86 23.3,101.86 23.15,101.72 DT39.4 DT39.7 21.3,101.72 21.18,101.84 17.8,101.84 17.7,101.74 16.94,101.74 16.8,101.6 v2(16.8,101.43)
  TOP w0.107: JUSBC1.B7 6.47,107.57 v2(6.51,107.54)
SW_TBT_A_USB20_P1: length 3.6
  BOTTOM w0.076: UT5.K7 64.74,109.42 64.88,109.42 64.96,109.5 64.96,110.06 65.15,110.25 65.15,110.35 v2(65,110.5)
  BOTTOM w0.094: RT123.2 25.17,101.88 25.73,101.88 25.84,101.99 26.6,101.99 v2(26.79,101.8)
SW_TBT_A_USB20_P1_R: length 8
  TOP w0.094: v2(10.09,107.34) 9.72,106.97 9.31,106.97 9.03,107.24 8.42,107.24 ; JUSBC1.A6 7.74,107.32
  TOP w0.102: 8.42,107.24 7.83,107.24 7.74,107.32
  BOTTOM w0.094: v2(19.71,102.55) 19.71,102.65 19.81,102.74 20.15,102.74 20.98,101.91 21.11,101.91 21.3,101.72 DT40.8 DT40.2 23.15,101.72 23.3,101.86 23.73,101.86 RT123.1
SW_TBT_A_USB20_P2: length 6.6
  TOP w0.094: RT120.1 25.17,102.1 25.63,102.1 26.56,103.03 27.28,103.03 27.6,102.71 28.56,102.71 28.7,102.85 28.7,102.91 v2(28.72,102.93)
  BOTTOM w0.076: UT5.K6 64.46,109.63 64.46,109.99 64.39,110.05 64.39,111.26 v2(64.41,111.28)
SW_TBT_A_USB20_P2_R: length 8.5
  TOP w0.094: RT120.2 23.69,102.08 23.3,102.08 23.15,102.22 DT39.5 DT39.6 21.3,102.22 21.13,102.05 17.71,102.05 17.61,101.95 16.91,101.95 16.81,102.05 v2(16.81,102.24)
  TOP w0.107: v2(6.51,106.99) 6.42,107.07 JUSBC1.B6
SYS_PWROK: length 65.5
  TOP w0.102: v2(248.78,93.23) 248.78,93.55 v4(249.08,93.85) RE548.1 252.26,93.85 RE56.1 252.37,94.02 CE548.1
  TOP w0.109: 209.41,112.28 RH199.1 ; 209.41,112.28 209.29,112.28 208.87,112.7 RC129.1 ; 209.41,112.28 v2(209.41,112.26)
  BOTTOM w0.089: 210.57,111.2 210.57,110.44 214.45,106.56 215.43,106.56 215.8,106.19 216.85,106.19 216.88,106.16 217.39,106.16 217.61,105.94 UH1.AU3 ; 226.12,80.59 232.66,80.59
  BOTTOM w0.102: v2(214.02,82.83) 214.02,81.77 215.08,80.71 220.86,80.71 221.99,79.58 221.99,79.17 222.52,78.64 224.04,78.64 225.99,80.59 226.12,80.59 ; v2(248.78,93.23) 247.14,93.23 246.32,92.42 246.32,86.66 244.47,84.8 244.47,84.08 243.9,83.51 243.07,83.51 242.94,83.64 237.23,83.64 235.26,81.67 235.22,81.67 235.22,81.67 233.73,81.67 232.66,80.59
  BOTTOM w0.109: 210.57,111.2 209.52,112.26 v2(209.41,112.26)
SYS_PWROK_R: length 22.6
  TOP w0.102: v2(92.16,135.78) 91.93,135.55 91.93,134.09 RC133.2 CC33.1 90.15,133.47 89.88,133.74 v2(89.88,135.35)
  TOP w0.109: RC129.2 v1(205.42,112.98) 204.27,112.98 201.89,110.59 201.89,107.97 201.54,107.63 v2(201.18,107.63)
  BOTTOM w0.102: JXDP1.47 90.01,135.22 v2(89.88,135.35) ; RC128.2 231.33,134.17 232.01,134.86 234.6,134.86 234.89,135.15 v2(234.89,136.34)
SYS_RESET#: length 28.7
  TOP w0.102: JAPS1.13 228.06,34.52 v2(228.57,35.02) ; v2(212.59,118.56) 212.21,118.95 CC302.1 RH66.2 211.77,119.97 211.77,120.86 211.67,120.96 UC3.4
  BOTTOM w0.089: UH1.AU2 216.86,105.91 216.77,106 215.72,106 215.5,106.23 214.52,106.23 213.8,106.95 212.08,106.95 211.76,107.26 211.76,108.6 v2(211.01,109.36) 210.09,110.28 210.09,110.9
  BOTTOM w0.109: 210.09,110.9 210.09,111 v1(208.67,112.42) 207.89,113.19 207.89,116.6 210.56,119.26 211.89,119.26 212.21,118.95 212.21,118.95 v2(212.59,118.56)
SYSTEM_ID: length 9.4
  TOP w0.102: v2(275.28,89.41) 275.66,89.03 RE300.2 CE47.1
  TOP w0.109: v2(268.82,94.09) 268.82,94.18 UE1.J10
  BOTTOM w0.109: v2(268.82,94.09) 269.2,93.71 270.28,93.71 270.76,93.23 v1(271.01,93.23) 271.34,93.23 271.55,93.44 271.87,93.44 271.9,93.42 272.28,93.42 272.32,93.45 275.3,93.45 v2(275.46,93.61)
TACH_FAN1: length 207.5
  TOP w0.102: v2(233.61,64.15) 233.97,64.5 235.11,64.5 240.29,69.68 252.17,69.68 252.88,70.38 253.21,70.38 253.22,70.4 254.15,70.4 254.16,70.38 v4(257.81,70.38) 258.43,70.38 258.67,70.14 v2(258.67,69.95)
  TOP w0.109: v2(262.49,98.13) 262.49,98.09 262.86,97.73 UE1.E3 ; v2(93.54,91.5) 93.29,91.25 93.29,90.91 RE51.2
  BOTTOM w0.102: JFAN1.3 92.97,90 91.63,88.66 91.63,84.59 94.86,81.35 94.86,77.56 97.14,75.29 97.14,67.47 103.12,61.49 151.18,61.49 156.4,56.27 163,56.27 165.58,58.86 165.58,61.28 165.69,61.39 225.71,61.39 228.34,64.02 233.48,64.02 v2(233.61,64.15)
  BOTTOM w0.109: JFAN1.3 93.29,90.28 93.29,91.25 v2(93.54,91.5) ; v2(259.06,100.33) 259.06,99.22 260.18,98.1 262.45,98.1 262.49,98.14 v2(262.49,98.13)
TBT_A_TRX_C_DTX_N0: length 7.2
  TOP w0.18: CT327.2 13.78,103.77 arc(13.65,103.68) 13.49,103.65 arc(13.3,103.69) RT220.1 13.04,103.69 arc(12.96,103.64) 12.86,103.62 10.19,103.62 arc(9.95,103.67) 9.74,103.8 8.47,105.07 arc(8.32,105.17) 8.14,105.21 arc(8.01,105.29) 7.86,105.32 JUSBC1.A10
TBT_A_TRX_C_DTX_N1: length 11.5
  TOP w0.18: JUSBC1.B10 6,109.07 arc(6.07,109.09) 6.13,109.13 6.18,109.17 arc(6.31,109.23) 6.43,109.17 v2(6.51,109.17)
  BOTTOM w0.18: CT329.2 14.46,106.48 arc(14.34,106.57) 14.19,106.6 arc(14,106.56) RT222.1 13.74,106.55 arc(13.65,106.61) 13.55,106.63 12.74,106.63 arc(12.21,106.85) 11.98,107.39 11.98,108.99 arc(11.8,109.43) 11.36,109.61 8.3,109.61 arc(8.2,109.59) 8.11,109.53 8.01,109.44 arc(7.84,109.32) 7.63,109.28 6.61,109.28 v2(6.51,109.17)
TBT_A_TRX_C_DTX_P0: length 7.2
  TOP w0.18: JUSBC1.A11 7.86,104.82 arc(8.01,104.85) 8.14,104.94 arc(8.22,104.92) 8.28,104.88 9.55,103.61 arc(9.84,103.42) 10.19,103.35 12.86,103.35 arc(12.96,103.33) 13.04,103.27 RT219.1 13.14,103.17 arc(13.3,103.28) 13.49,103.32 13.49,103.32 arc(13.64,103.29) 13.77,103.2 CT326.2
TBT_A_TRX_C_DTX_P1: length 11.5
  TOP w0.18: JUSBC1.B11 5.97,109.57 arc(6.09,109.6) 6.19,109.67 arc(6.25,109.71) 6.32,109.72 v2(6.51,109.72)
  BOTTOM w0.18: v2(6.51,109.72) 6.61,109.62 arc(6.69,109.57) 6.78,109.55 7.63,109.55 arc(7.73,109.57) 7.82,109.63 7.92,109.72 arc(8.09,109.84) 8.3,109.88 11.36,109.88 arc(11.99,109.62) 12.25,108.99 12.25,107.39 arc(12.4,107.04) 12.74,106.89 13.55,106.89 arc(13.65,106.91) 13.74,106.97 RT221.1 13.84,107.07 arc(14,106.96) 14.19,106.93 arc(14.34,106.96) 14.48,107.04 CT328.2
TBT_A_TRX_DTX_N0: length 22.6
  TOP w0.18: v2(31.48,102.97) 31.4,102.89 arc(31.33,102.85) 31.26,102.83 31.24,102.83 arc(31.1,102.86) 30.98,102.94 29.08,104.84 arc(28.78,105.03) 28.44,105.1 19.04,105.1 arc(18.69,105.03) 18.4,104.84 17.26,103.69 arc(17.13,103.61) 16.98,103.58 16.91,103.58 arc(16.78,103.6) 16.67,103.68 RT191.1
  BOTTOM w0.076: 36,102.82 36.01,102.82 36.03,102.81 36.4,102.81 arc(36.54,102.83) 36.65,102.91 36.69,102.94 arc(36.78,103) 36.88,103.02 36.95,103.02 arc(37,103.01) 37.05,102.98 37.07,102.97 arc(37.09,102.93) 37.1,102.88 arc(37.07,102.8) 37,102.77 36.92,102.77 UT1.A21
  BOTTOM w0.18: v2(31.48,102.97) 31.57,102.88 arc(31.64,102.83) 31.73,102.82 36,102.82
TBT_A_TRX_DTX_N1: length 20.9
  BOTTOM w0.076: 36,105.46 36.01,105.46 36.07,105.52 36.09,105.52 36.13,105.48 36.2,105.48 36.43,105.48 36.57,105.48 36.62,105.43 36.63,105.43 36.67,105.38 arc(36.75,105.33) 36.83,105.32 36.95,105.32 arc(37.12,105.35) 37.27,105.45 UT1.B15
  BOTTOM w0.18: RT195.1 17.37,106.56 31.11,106.56 arc(31.29,106.6) 31.43,106.7 31.46,106.72 arc(31.57,106.79) 31.69,106.82 34.04,106.82 arc(34.28,106.77) 34.49,106.63 35.33,105.79 35.38,105.74 35.38,105.74 35.41,105.71 arc(35.68,105.53) 36,105.46
TBT_A_TRX_DTX_P0: length 22.6
  TOP w0.18: v2(31.48,102.39) 31.31,102.56 31.24,102.56 arc(30.99,102.61) 30.79,102.75 28.89,104.65 arc(28.68,104.79) 28.44,104.83 19.04,104.83 arc(18.8,104.79) 18.59,104.65 17.45,103.5 arc(17.23,103.36) 16.98,103.31 16.78,103.31 arc(16.7,103.29) 16.64,103.25 RT190.1
  BOTTOM w0.076: 36,102.55 36.07,102.55 36.12,102.6 arc(36.17,102.63) 36.22,102.64 36.4,102.64 36.66,102.6 36.67,102.59 arc(36.71,102.57) 36.75,102.56 36.96,102.56 arc(37.13,102.59) 37.28,102.69 UT1.B21
  BOTTOM w0.18: v2(31.48,102.39) 31.57,102.48 arc(31.65,102.53) 31.74,102.55 36,102.55
TBT_A_TRX_DTX_P1: length 20.9
  BOTTOM w0.076: 36,105.73 36.11,105.73 36.2,105.64 36.51,105.64 arc(36.58,105.66) 36.64,105.7 arc(36.73,105.76) 36.84,105.78 36.91,105.78 arc(37,105.76) 37.06,105.72 arc(37.09,105.64) 37.06,105.57 arc(37.03,105.55) 36.98,105.54 UT1.A15
  BOTTOM w0.18: RT194.1 17.38,106.94 arc(17.5,106.86) 17.64,106.83 31.11,106.83 arc(31.18,106.85) 31.24,106.89 31.27,106.91 arc(31.46,107.04) 31.69,107.09 34.04,107.09 arc(34.38,107.02) 34.68,106.82 35.6,105.9 arc(35.78,105.78) 36,105.73
TBT_A_TRX_R_DTX_N0: length 1.8
  TOP w0.18: RT191.2 15.95,103.78 arc(15.8,103.68) 15.63,103.65 arc(15.39,103.7) DT14.1 arc(14.97,103.7) 14.73,103.65 14.71,103.65 arc(14.55,103.68) 14.42,103.77 CT327.1
TBT_A_TRX_R_DTX_N1: length 1.8
  BOTTOM w0.18: CT329.1 15.11,106.46 arc(15.25,106.55) 15.43,106.59 15.55,106.59 arc(15.68,106.56) 15.79,106.49 DT10.1 15.98,106.5 arc(16.08,106.57) 16.19,106.59 16.3,106.59 arc(16.5,106.55) RT195.2
TBT_A_TRX_R_DTX_P0: length 1.8
  TOP w0.18: CT326.1 14.43,103.2 arc(14.56,103.29) 14.71,103.32 arc(14.96,103.27) 15.18,103.12 DT13.1 15.18,103.12 arc(15.4,103.27) 15.65,103.32 arc(15.8,103.29) 15.93,103.2 RT190.2
TBT_A_TRX_R_DTX_P1: length 1.8
  BOTTOM w0.18: CT328.1 15.12,107.05 arc(15.26,106.95) 15.43,106.92 15.55,106.92 arc(15.67,106.94) 15.78,107.01 DT9.1 15.99,107 arc(16.08,106.94) 16.19,106.92 16.31,106.92 arc(16.49,106.95) 16.65,107.06 RT194.2
TBT_A_TTX_C_DRX_N0: length 8.9
  TOP w0.18: v2(6.51,105.35) 6.35,105.35 6.23,105.48 arc(6.12,105.55) 5.99,105.57 JUSBC1.B3
  BOTTOM w0.18: v2(6.51,105.35) 6.61,105.25 arc(6.69,105.2) 6.78,105.18 7.11,105.18 arc(7.39,105.13) 7.62,104.97 7.92,104.67 arc(8.13,104.53) 8.37,104.48 8.75,104.48 arc(9.1,104.41) 9.39,104.22 9.77,103.84 arc(10.06,103.65) 10.4,103.58 12.78,103.58 arc(12.91,103.6) 13.02,103.67 RT489.1 arc(13.3,103.69) 13.49,103.65 arc(13.65,103.68) 13.78,103.77 CT96.2
TBT_A_TTX_C_DRX_N1: length 9.5
  TOP w0.18: CT98.2 14.46,106.48 arc(14.34,106.57) 14.19,106.6 arc(14,106.56) RT490.1 13.72,106.56 13.35,106.56 arc(13.04,106.63) 12.77,106.8 12.45,107.12 arc(12.26,107.42) 12.19,107.76 12.19,108.52 arc(12.14,108.77) 12,108.97 11.56,109.41 arc(11.36,109.55) 11.12,109.6 9.45,109.6 arc(9.43,109.6) 9.41,109.59 arc(9.09,109.52) 8.81,109.33 8.64,109.16 arc(8.44,109.03) 8.21,108.98 8.03,108.98 arc(7.94,108.96) 7.87,108.91 7.85,108.89 arc(7.77,108.84) 7.69,108.82 JUSBC1.A3
TBT_A_TTX_C_DRX_P0: length 8.9
  TOP w0.18: v2(6.54,104.79) 6.41,104.79 6.24,104.96 arc(6.11,105.04) 5.95,105.07 JUSBC1.B2
  BOTTOM w0.18: CT95.2 13.77,103.2 arc(13.64,103.29) 13.49,103.32 arc(13.3,103.28) 13.14,103.17 RT488.1 13.05,103.26 10.34,103.26 arc(9.99,103.33) 9.7,103.53 9.2,104.03 arc(8.99,104.17) 8.75,104.21 8.37,104.21 arc(8.02,104.28) 7.73,104.48 7.43,104.78 arc(7.28,104.88) 7.11,104.91 6.66,104.91 v2(6.54,104.79)
TBT_A_TTX_C_DRX_P1: length 9.5
  TOP w0.18: JUSBC1.A2 7.78,109.32 7.84,109.26 8.13,109.26 arc(8.14,109.26) 8.14,109.26 8.16,109.26 arc(8.35,109.31) 8.51,109.43 8.76,109.67 arc(8.97,109.82) 9.22,109.87 11.12,109.87 arc(11.46,109.8) 11.75,109.6 12.19,109.16 arc(12.39,108.87) 12.46,108.52 12.46,107.76 arc(12.5,107.52) 12.64,107.31 12.93,107.02 arc(13.12,106.9) 13.34,106.85 13.48,106.85 arc(13.61,106.88) 13.72,106.95 RT491.1 13.84,107.07 arc(14,106.96) 14.19,106.93 arc(14.34,106.96) 14.48,107.04 CT97.2
TBT_A_TTX_DRX_N0: length 21.4
  BOTTOM w0.076: 36,103.78 36.29,103.78 36.29,103.79 36.49,103.79 arc(36.55,103.8) 36.59,103.83 36.6,103.83 arc(36.69,103.9) 36.81,103.92 36.99,103.92 arc(37.13,103.9) 37.25,103.82 37.37,103.7 UT1.B19
  BOTTOM w0.18: 36,103.78 33.37,103.78 arc(33.15,103.82) 32.97,103.94 32.56,104.36 arc(32.43,104.44) 32.29,104.47 18.19,104.47 arc(18.04,104.44) 17.92,104.36 17.39,103.83 arc(17.36,103.81) 17.31,103.8 RT193.1
TBT_A_TTX_DRX_N1: length 21.2
  TOP w0.18: v2(33.65,105.08) 33.56,105.17 arc(33.48,105.22) 33.4,105.24 31.92,105.24 arc(31.58,105.3) 31.28,105.5 30.36,106.43 arc(30.15,106.56) 29.91,106.61 17.53,106.61 arc(17.43,106.59) 17.35,106.54 RT197.1
  BOTTOM w0.076: UT1.B17 37.28,104.53 arc(37.13,104.43) 36.96,104.4 36.8,104.4 arc(36.73,104.41) 36.67,104.45 36.66,104.46 arc(36.59,104.51) 36.52,104.52 36.12,104.52 36.07,104.47 36.04,104.47
  BOTTOM w0.18: v2(33.65,105.08) 33.74,105.17 arc(33.81,105.22) 33.9,105.24 34.1,105.24 arc(34.32,105.19) 34.52,105.06 34.85,104.73 arc(35.14,104.54) 35.48,104.47 36.04,104.47
TBT_A_TTX_DRX_P0: length 21.4
  BOTTOM w0.076: 36,103.51 36.06,103.51 arc(36.11,103.52) 36.15,103.54 36.22,103.61 36.35,103.61 36.36,103.62 36.44,103.62 arc(36.52,103.61) 36.59,103.56 36.6,103.55 arc(36.69,103.49) 36.81,103.47 36.89,103.47 arc(36.97,103.5) 37,103.58 37,103.62 arc(36.98,103.68) 36.92,103.7 UT1.A19
  BOTTOM w0.18: 36,103.51 33.37,103.51 arc(33.05,103.57) 32.78,103.75 32.36,104.17 arc(32.33,104.19) 32.29,104.2 18.19,104.2 arc(18.14,104.19) 18.11,104.17 17.58,103.64 arc(17.46,103.56) 17.31,103.53 17.12,103.53 arc(16.97,103.5) 16.85,103.42 16.59,103.16 RT192.1
TBT_A_TTX_DRX_P1: length 21.2
  TOP w0.18: RT196.1 17.36,106.96 arc(17.45,106.9) 17.56,106.88 29.91,106.88 arc(30.26,106.81) 30.55,106.62 31.48,105.69 arc(31.68,105.55) 31.92,105.5 33.4,105.5 arc(33.48,105.52) 33.56,105.57 v2(33.65,105.66)
  BOTTOM w0.076: UT1.A17 36.99,104.62 arc(37.03,104.63) 37.06,104.65 37.09,104.68 arc(37.09,104.69) 37.1,104.71 arc(37.05,104.82) 36.95,104.86 36.9,104.86 arc(36.78,104.84) 36.67,104.77 36.67,104.77 arc(36.58,104.71) 36.47,104.69 36.12,104.69 36.07,104.74 36.04,104.74
  BOTTOM w0.18: 36.04,104.74 35.48,104.74 arc(35.24,104.79) 35.04,104.92 34.71,105.25 arc(34.43,105.44) 34.1,105.5 33.9,105.5 arc(33.81,105.52) 33.74,105.57 v2(33.65,105.66)
TBT_A_TTX_R_DRX_N0: length 1.8
  BOTTOM w0.18: CT96.1 14.42,103.77 arc(14.55,103.68) 14.71,103.65 14.73,103.65 arc(14.97,103.7) DT6.1 arc(15.39,103.7) 15.63,103.65 arc(15.8,103.68) 15.95,103.78 RT193.2
TBT_A_TTX_R_DRX_N1: length 1.8
  TOP w0.18: CT98.1 15.11,106.46 arc(15.25,106.55) 15.43,106.59 15.55,106.59 arc(15.68,106.56) 15.79,106.49 DT18.1 15.98,106.5 arc(16.08,106.57) 16.19,106.59 16.3,106.59 arc(16.5,106.55) RT197.2
TBT_A_TTX_R_DRX_P0: length 1.8
  BOTTOM w0.18: RT192.2 15.93,103.2 arc(15.8,103.29) 15.65,103.32 arc(15.4,103.27) 15.18,103.12 DT5.1 15.18,103.12 arc(14.96,103.27) 14.71,103.32 arc(14.56,103.29) 14.43,103.2 CT95.1
TBT_A_TTX_R_DRX_P1: length 1.8
  TOP w0.18: CT97.1 15.12,107.05 arc(15.26,106.95) 15.43,106.92 15.55,106.92 arc(15.67,106.94) 15.78,107.01 DT17.1 15.99,107 arc(16.08,106.94) 16.19,106.92 16.31,106.92 arc(16.49,106.95) 16.65,107.06 RT196.2
TBT_CIO_PLUG_EVENT#: length 11.4
  BOTTOM w0.076: UT1.W2 45.41,111.74 45.41,112.36 45.49,112.45 45.49,112.87 45.61,112.99
  BOTTOM w0.089: v2(219.24,112.29) 219.93,111.6 219.93,110.83 219.95,110.8 219.95,110.78 220.01,110.73 UH1.BF8
  BOTTOM w0.102: 45,116.05 45.95,115.09 45.95,113.48 45.61,113.14 45.61,112.99
  BOTTOM w0.107: RT371.1 RT391.1 v2(42.61,116.26) 42.71,116.15 43.18,116.15 43.36,116.32 43.82,116.32 44.1,116.05 45,116.05
TBT_DP_RBIAS: length 2.2
  TOP w0.102: v2(39.75,115.77) v1(40.25,115.77) 40.83,116.34 RT35.1
  BOTTOM w0.102: UT1.N6 v2(42.94,109.2)
TBT_FORCE_PWR: length 9.7
  TOP w0.102: RT27.1 v1(41.97,115.9) 41.37,115.3 v2(38.69,115.3)
  BOTTOM w0.089: v2(223.2,114.06) 223.01,113.87 223.01,112.41 223.38,112.03 223.38,111.45 223.13,111.2 223.13,110.12 223.38,109.87 UH1.BE15
  BOTTOM w0.102: v2(39.69,110.5) UT1.H4
TBT_I2C_SCL: length 11.2
  BOTTOM w0.076: 60.67,105.74 60.81,105.88 61.12,105.88 61.37,106.13 61.96,106.13 UT5.D2 ; 43.65,113.05 43.65,113.03 43.61,112.98 43.61,112.88 43.69,112.79 44.21,112.79 44.49,112.51 44.49,111.74 UT1.U2
  BOTTOM w0.102: 43.65,113.74 42.8,114.59 v2(42.8,114.82) 42.69,114.82 42.59,114.72 40.67,114.72 40.48,114.91
  BOTTOM w0.107: 43.65,113.05 43.65,113.74 ; RT19.1 40.82,116.6 40.82,116.3 40.37,115.85 40.37,115.02 40.48,114.91
  BOTTOM w0.112: 60.67,105.74 60.55,105.62 60.53,105.62 60.53,105.62 v2(60.54,105.62)
TBT_I2C_SDA: length 10.8
  BOTTOM w0.076: 60.67,106.11 61.11,106.11 61.38,106.38 UT5.D1 ; 43.42,113.05 43.42,112.99 43.44,112.97 43.44,112.81 43.62,112.62 44.14,112.62 44.32,112.45 44.32,112.36 44.25,112.29 44.22,112.29 44.15,112.21 44.15,112.06 44.22,111.98 UT1.U1
  BOTTOM w0.102: v2(42.54,114.24) 40.47,114.24 40.28,114.43 40.28,114.43 40.13,114.57
  BOTTOM w0.107: 43.42,113.05 43.18,113.29 43.18,113.74 42.73,114.18 42.6,114.18 v2(42.54,114.24) ; 59.96,105.61 v2(59.95,105.61) ; 40.13,114.57 40.13,115.94 40.59,116.39 40.59,116.6 RT18.1
  BOTTOM w0.112: 59.96,105.61 60.46,106.11 60.67,106.11
TBT_JTAG_TCK: length 2.3
  TOP w0.102: 43.96,110.84 43.61,110.48 v2(43.6,110.48)
  TOP w0.107: RT6.1 44.2,111.07 v1(44.13,111) 43.96,110.84
  BOTTOM w0.102: UT1.T4 43.92,110.8 v2(43.6,110.48)
TBT_JTAG_TDI: length 3
  TOP w0.107: RT8.1 46.48,111.3 v1(46.69,111.08) 46.69,110.97 46.22,110.5 v2(45.54,110.5)
  BOTTOM w0.076: UT1.Y4 v2(45.54,110.5)
TBT_JTAG_TDO: length 2.4
  TOP w0.102: 45.09,110.69 v2(44.89,110.5)
  TOP w0.107: RT5.1 45.72,111.32 v1(45.42,111.02) 45.09,110.69
  BOTTOM w0.102: v2(44.89,110.5) UT1.W4
TBT_JTAG_TMS: length 2.4
  TOP w0.102: 44.58,110.84 v2(44.24,110.5)
  TOP w0.107: 44.58,110.84 44.96,111.21 RT7.1
  BOTTOM w0.102: UT1.V4 v2(44.24,110.5)
TBT_PCIE_RBIAS: length 1.4
  TOP w0.102: v2(42.94,104.65) 42.94,104.19 43.15,103.99 RT34.1
  BOTTOM w0.112: UT1.N16 v2(42.94,104.65)
TBT_PERST#: length 4.6
  BOTTOM w0.102: RT554.2 34.78,125.03 v1(34.68,124.93) 34.15,124.39 v2(34.11,124.39) 34.16,124.34 34.16,123.45 34.09,123.38 RT502.2 32.96,122.76 RT501.2 ; UT1.L4 v2(40.99,110.5)
TBT_PERST#_R: length 3
  BOTTOM w0.102: RT503.2 29.99,123.59 UT34.4 31.5,122.76 RT501.1
TBT_RBIAS: length 2.2
  TOP w0.089: v2(39.68,109.2) 39.68,109.82 v1(39.89,110.03)
  TOP w0.102: RT39.2 40.11,108.77 v2(39.68,109.2)
  BOTTOM w0.102: UT1.H6 39.76,109.26 39.74,109.26 39.68,109.2 v2(39.68,109.2)
TBT_RESET_N_EC: length 10.4
  TOP w0.102: v2(38.13,115.45) 38.03,115.45 37.9,115.33 37.9,114.5 38.31,114.1 RT11.1
  TOP w0.107: RT11.1 38.93,113.92 v1(39.3,113.55) 39.5,113.35 39.5,110.96 v2(39.04,110.5)
  TOP w0.109: RE506.1 256.95,101.11 256.33,101.11 256.22,101 255.05,101 v2(254.69,101.36)
  BOTTOM w0.102: v2(39.04,110.5) 39.37,110.82 UT1.F4 ; RT110.2 v2(71.94,107.42)
TBT_RESET_N_EC_R: length 6
  TOP w0.109: RE95.2 RE506.2 258.11,101.36 259.25,101.36 259.56,101.04 v1(259.56,100.3) 259.56,99.62 260.66,98.53 UE1.D1
TBT_ROM_CLK: length 6.3
  TOP w0.102: v1(48.76,113.93) 48.8,113.93 v2(49.3,113.43)
  BOTTOM w0.076: 47.86,111.93 47.84,111.92 47.84,111.42 47.26,110.84 46.8,110.84 46.57,110.6 UT1.AB4
  BOTTOM w0.107: 47.86,111.93 47.86,111.93 49.3,113.37 v2(49.3,113.43) ; UT2.6 34.65,120.72 34.43,120.5 34.35,120.5 v2(34.32,120.47)
TBT_ROM_CS#: length 12.7
  BOTTOM w0.076: 47.68,112.44 47.68,111.52 47.22,111.06 UT1.AC3
  BOTTOM w0.102: RT2.1 44.92,123.29 45.38,123.75 47.77,123.75 48.38,123.14 v1(48.38,122.63) 48.38,122.23 v2(47.22,121.06) ; 47.68,112.44 47.68,112.61
  BOTTOM w0.107: v2(47.68,114.44) 48.04,114.08 48.04,112.98 47.68,112.61 ; RT2.1 44.73,123.38 43.67,123.38 43.55,123.26 UT2.1
TBT_ROM_DI: length 5.5
  TOP w0.102: v1(33.66,119.54) 33.91,119.29 v2(34.32,119.29)
  BOTTOM w0.076: 47.37,112.75 47.35,112.73 47.35,111.45 47.19,111.29 46.8,111.29 UT1.AB3
  BOTTOM w0.102: 47.37,112.75 47.43,112.8
  BOTTOM w0.107: UT2.5 34.57,119.45 34.41,119.29 v2(34.32,119.29) ; v2(47.63,113.82) 47.63,113.49 47.43,113.29 47.43,112.8
TBT_ROM_DO: length 8.3
  BOTTOM w0.076: UT1.AC4 47.28,110.6 48.02,111.35 48.02,111.41
  BOTTOM w0.107: 48.02,111.41 50.16,113.55 51.49,113.55 v2(51.84,113.2) ; UT2.2 43.61,121.99 43.65,122.02 v2(44.17,122.02) 44.53,122.02 RT3.1
TBT_ROM_HOLD#: length 6.2
  BOTTOM w0.102: UT2.7 37.9,121.99 38.16,122.25 38.16,124.29 RT1.1 v1(38.73,124.66)
TBT_ROM_WP#: length 10
  TOP w0.102: v1(43.37,119.64) 43.68,119.96 v2(43.87,119.96)
  BOTTOM w0.076: 44.29,112.98 44.73,112.54 UT1.V1
  BOTTOM w0.107: v2(41.44,116.26) 41.44,115.64 41.77,115.31 42.94,115.31 43.56,114.69 44,114.69 44.29,114.4 44.29,112.98 ; RT4.1 44.82,120.65 44.13,119.96 v2(43.87,119.96) 43.87,120.15 43.31,120.72 UT2.3
TBT_RSENSE: length 1.5
  TOP w0.102: RT39.1 40.97,108.56 v2(40.33,109.2)
  BOTTOM w0.102: UT1.J6 40.67,109.52 40.32,109.17 40.32,109.2 v2(40.33,109.2)
TBT_RTD3_WAKE#: length 51
  TOP w0.102: v2(33.69,122.72) 33.54,122.57 RT555.1 ; v2(220.42,80.31) 220.56,80.31 222.23,78.64 v1(224.21,78.64) 224.32,78.75 226.18,78.75 226.82,79.39 236.41,79.39 239.14,82.12 244.34,82.12 244.85,82.62 244.85,88.75 244.03,89.57 244.03,93.7 v2(245.2,94.87)
  BOTTOM w0.089: RH663.2 245.69,94.38 v2(245.2,94.87)
  BOTTOM w0.102: v2(220.42,80.31) 220.29,80.17 215.62,80.17 214.49,79.04 v2(213.83,79.04) ; v2(33.69,122.72) RT456.1
  BOTTOM w0.109: v2(239.59,120.79) 239.61,120.79 239.72,120.68 RH662.2
TBT_RTD3_WAKE#_GPD7: length 11.3
  BOTTOM w0.089: UH1.BE41 236.25,109.89 236.02,110.13 236.02,110.48 235.93,110.57 235.93,111.34 235.98,111.39 235.98,113.58 236.74,114.35 236.74,115.67
  BOTTOM w0.109: RH662.1 238.81,119.83 RH602.1 238.77,119.01 238.77,119 v1(237.12,117.35) 236.74,116.97 236.74,115.67
TBT_RTD3_WAKE#_K18: length 7.9
  BOTTOM w0.089: UH1.T47 239.28,95.38 240.57,94.09 241.2,94.09 241.93,93.36 RH661.2 243.06,92.91 244.33,92.91 RH663.1 v1(244.78,94.38)
TBT_SRC_CFG1: length 7.4
  TOP w0.102: v1(47.77,116.18) 47.47,116.18 v2(47.24,116.41) 46.79,116.85 RT30.1 45.72,116.85 RT338.1
  BOTTOM w0.076: UT1.AA1 46.11,112.21 46.67,112.77 46.67,113.05
  BOTTOM w0.102: 46.67,113.05 46.67,113.19
  BOTTOM w0.107: v2(47.24,116.41) 46.92,116.41 46.67,116.15 46.67,113.19
TBT_SRC_HPD: length 5.6
  BOTTOM w0.076: UT1.G1 39.67,112.34 40.09,112.76
  BOTTOM w0.107: RT184.1 39.06,116.6 39.06,114.89 40.09,113.87 40.09,112.76
TBT_TMU_CLK_OUT: length 7.2
  BOTTOM w0.076: 44.64,113.05 44.64,112.91 44.92,112.63 44.92,112.17 44.94,112.15 44.94,111.81 44.92,111.79 44.92,111.71 UT1.V2
  BOTTOM w0.102: 44.64,113.05 44.64,113.1
  BOTTOM w0.107: RT28.1 41.84,116.86 41.84,116.4 42.41,115.83 42.93,115.83 43.69,115.07 44.07,115.07 44.64,114.51 v1(44.64,113.59) 44.64,113.1
TBTA_AUXN: length 1.5
  BOTTOM w0.094: CT81.1 56.87,110.12 56.43,110.12 v2(56.18,110.36)
  BOTTOM w0.102: UT1.W15 v2(44.88,105.29)
TBTA_AUXN_C: length 5.2
  BOTTOM w0.076: 59.94,110.06 60.17,110.06 60.22,110.01 60.55,110.01 61.43,109.13 61.96,109.13 UT5.J2
  BOTTOM w0.094: CT81.2 58.31,110.3 RT95.1 58.66,110.06 59.94,110.06
TBTA_AUXP: length 1.6
  BOTTOM w0.094: v2(56.19,109.78) 56.21,109.78 56.34,109.91 56.82,109.91 CT80.1
  BOTTOM w0.102: UT1.Y15 45.61,105.62 45.54,105.56 v2(45.54,105.29)
TBTA_AUXP_C: length 4.6
  BOTTOM w0.076: 59.94,109.84 60.39,109.84 61.33,108.9 61.68,108.9 UT5.J1
  BOTTOM w0.094: CT80.2 58.31,109.67 RT96.1 58.42,109.62 58.65,109.84 59.94,109.84
TBTA_CC1: length 14.4
  TOP w0.109: v2(6.51,106.44) 6.51,106.47 6.4,106.57 JUSBC1.B5
  BOTTOM w0.127: 65.78,110.36 65.75,110.34 65.75,109.93 UT5.L9
  BOTTOM w0.203: 65.78,110.36 65.78,111.47 66.2,111.88 66.2,112.45 66.4,112.65 RT104.2
  BOTTOM w0.254: v2(16.95,100.57) 17.06,100.47 20.63,100.47 20.88,100.72 DT40.7 DT40.4 24.38,100.72 v2(24.38,100.73) ; RT104.2 66.62,113.4 CT86.1 66.62,113.42 67.18,113.42 67.81,114.06 v2(68.26,114.06)
TBTA_CC2: length 13.5
  TOP w0.254: v2(8.15,107.77) 8.1,107.82 JUSBC1.A5
  BOTTOM w0.203: RT105.2 67.53,112.65 67.13,112.25 67.13,111.83 66.8,111.5 66.8,110.7 66.21,110.11 UT5.L10
  BOTTOM w0.254: v2(24.38,100.15) 24.31,100.22 DT40.5 DT40.6 20.92,100.22 20.79,100.09 17.05,100.09 v2(16.95,99.99) ; v2(67.88,113.42) 68.37,112.93 CT85.1 68.3,112.65 RT105.2
TBTA_DBG_CTL1: length 5.5
  TOP w0.107: RT106.1 59.58,108.97 60.54,108.97 61.16,108.35 61.16,107.68 v1(61.67,107.17) 62.01,106.83 62.69,106.83 v2(62.72,106.8)
  BOTTOM w0.076: v2(62.72,106.8) 62.8,106.88 UT5.E4
TBTA_DBG_CTL2: length 3.3
  TOP w0.102: RT107.1 63.24,105.17 63.76,104.65 63.76,104.05 63.99,103.82 v1(64.19,103.82)
  TOP w0.107: RT107.1 63.24,105.87 v2(63.28,105.91)
  BOTTOM w0.076: UT5.D5 63.28,105.95 v2(63.28,105.91)
TBTA_DEBUG1: length 3.9
  BOTTOM w0.076: 61.17,111 61.59,111 62.21,110.39 UT5.L2
  BOTTOM w0.107: 61.17,111 v1(61.06,111.11) 60.26,111.91 RT92.2
TBTA_DEBUG2: length 4.8
  BOTTOM w0.076: 61.56,110.75 61.96,110.36 61.96,109.63 UT5.K2
  BOTTOM w0.107: RT93.2 59.5,112.18 v1(59.93,111.76) 60.93,110.75 61.56,110.75
TBTA_DEBUG3: length 3.2
  BOTTOM w0.076: UT5.L3 62.71,110.39 62.23,110.86 62.23,111.05 62.19,111.08
  BOTTOM w0.107: 62.19,111.08 61.72,111.55 RT89.2
TBTA_DEBUG4: length 4
  BOTTOM w0.076: UT5.K3 62.46,109.63 62.46,110.39 61.11,111.74
  BOTTOM w0.102: RT90.2 60.96,111.88 61.11,111.74
TBTA_HPD: length 7.1
  TOP w0.102: RT73.2 65.6,103.32 v1(67.5,101.42) 68,100.91 v2(68,100.47)
  TOP w0.107: RT23.1 40.37,111.75 v2(41.63,110.49)
  BOTTOM w0.102: UT1.M4 v2(41.63,110.49)
TBTA_HPD_R: length 2.6
  TOP w0.102: v1(66.58,104.89) RT73.1
  TOP w0.107: RT73.1 65.61,104.91 v2(65.61,105.88)
  BOTTOM w0.102: v2(65.61,105.88) UT5.C10
TBTA_I2C_INT: length 15.8
  TOP w0.102: 40,110.84 v2(40.34,110.5)
  TOP w0.107: RT16.1 43.23,116.77 43.23,116.02 41.97,114.75 v1(41.21,114.75) 40.38,114.75 39.91,114.29 39.91,110.92 40,110.84
  BOTTOM w0.076: 59.94,105.23 60.82,105.23 61.47,105.88 UT5.C1
  BOTTOM w0.102: 59.94,105.23 59.43,105.23 59.36,105.3 56.45,105.3 55.75,105.99 v2(55.71,105.99) ; UT1.J4 v2(40.34,110.5)
TBTA_LSRX: length 5.3
  TOP w0.094: RT88.1 61.13,113.56 61.13,113.7 v2(60.94,113.88) ; v2(35.24,109.34) 35.07,109.17 34.59,109.17 RT21.1
  BOTTOM w0.076: 36.06,109.29 36.1,109.32 36.1,109.9 36.51,110.31 36.68,110.31 36.76,110.38 36.76,110.45 UT1.A4
  BOTTOM w0.094: 36.06,109.29 35.93,109.15 35.42,109.15 v2(35.24,109.34) ; RT90.1 61.19,113.5 61.19,113.64 60.95,113.88 v2(60.94,113.88)
TBTA_LSRX_R: length 4.5
  TOP w0.094: RT88.2 60.83,112.15 61.53,111.45 v2(62.45,111.45)
  BOTTOM w0.076: v2(62.45,111.45) 62.45,111.45 62.67,111.24 62.67,110.9 62.96,110.61 62.96,109.63 UT5.K4
TBTA_LSTX: length 5.2
  TOP w0.094: RT87.1 61.36,113.5 61.36,113.72 v2(61.53,113.88) ; RT22.1 34.59,108.96 35.06,108.96 35.24,108.79 v2(35.24,108.75)
  BOTTOM w0.076: 36.2,109.12 36.27,109.19 36.27,109.83 36.58,110.14 36.61,110.14 36.61,110.14 UT1.A5
  BOTTOM w0.094: v2(35.24,108.75) 35.42,108.94 36.02,108.94 36.2,109.12 ; v2(61.53,113.88) 61.47,113.82 61.47,113.53 RT89.1
TBTA_LSTX_R: length 3.4
  TOP w0.094: RT87.2 61.89,112.36 v2(62.23,112.02)
  BOTTOM w0.076: UT5.L4 63.21,110.74 63.04,110.91 63.04,111.4 v1(62.99,111.45) 62.99,111.45 62.71,111.74
  BOTTOM w0.094: v2(62.23,112.02) 62.42,112.02 62.71,111.74
TBTA_MRESET: length 5.3
  TOP w0.102: RT86.1 67.81,107.96 68.13,108.28 v1(68.26,108.28)
  TOP w0.107: v2(68.51,107.04) 68.5,107.05 68.31,107.05 68.07,106.82 67.7,106.82 67.25,107.26 RT86.1
  BOTTOM w0.076: 68.45,107.05 68.37,107.05 68.12,106.81 66.78,106.81 UT5.E11
  BOTTOM w0.102: v2(68.51,107.04) 68.5,107.05 68.45,107.05
TBTA_RESET_N_EC_R: length 3.6
  BOTTOM w0.076: 68.45,107.55 68.43,107.58 67.56,107.58 67.36,107.38 UT5.F11
  BOTTOM w0.102: RT110.1 70.11,107.46 68.55,107.46 68.45,107.55
TBTA_ROM_CLK_PD: length 15.3
  BOTTOM w0.076: 62.25,102.46 62.51,102.72 v1(62.51,103.01) 62.51,103.13 62.83,103.45 62.83,104.65 62.71,104.77 UT5.A3
  BOTTOM w0.102: 62.25,102.46 61.65,101.86 57.02,101.86 54.48,99.32 51.68,99.32 51.35,99.65 RT54.1
TBTA_ROM_CLK_PD_R: length 1.5
  BOTTOM w0.102: UT6.6 52.65,100.02 52.59,99.96 RT54.2
TBTA_ROM_CS#_PD: length 6.4
  BOTTOM w0.076: UT5.B3 62.46,105.13 62.46,104.78 62.67,104.57 62.67,103.58 62.48,103.39 62.03,103.39 61.65,103.77 60.83,103.77 60.64,103.96 v1(60.14,103.96) 59.94,103.96
  BOTTOM w0.102: RT57.1 59.94,103.96
TBTA_ROM_CS#_PD_R: length 6.9
  BOTTOM w0.076: UT6.1 60.95,103.2 60.57,103.58 59.94,103.58
  BOTTOM w0.102: 59.94,103.58 59.05,103.58 58.97,103.5 57.74,103.5 57.64,103.6 RT57.2 RT51.1 56.74,103.96 v1(55.73,104.96)
TBTA_ROM_DI_PD: length 17.7
  TOP w0.102: v2(56.95,100.15) 58.13,100.15 58.76,99.51 60.22,99.51 v1(60.59,99.88) v2(62.39,101.69)
  BOTTOM w0.076: UT5.B4 62.96,105.13 62.96,104.79 62.99,104.76 62.99,102.57 62.97,102.56 62.97,102.46
  BOTTOM w0.102: RT55.1 51.35,98.26 51.56,98.05 54.35,98.05 56.35,100.05 56.86,100.05 v2(56.95,100.15) ; 62.97,102.46 62.97,102.27 v2(62.39,101.69)
TBTA_ROM_DI_PD_R: length 1.4
  BOTTOM w0.102: RT55.2 UT6.5
TBTA_ROM_DO_PD: length 4.1
  BOTTOM w0.076: UT5.A4 63.21,102.46
  BOTTOM w0.107: RT56.1 63.21,100.96 v1(63.21,101.8) 63.21,102.46
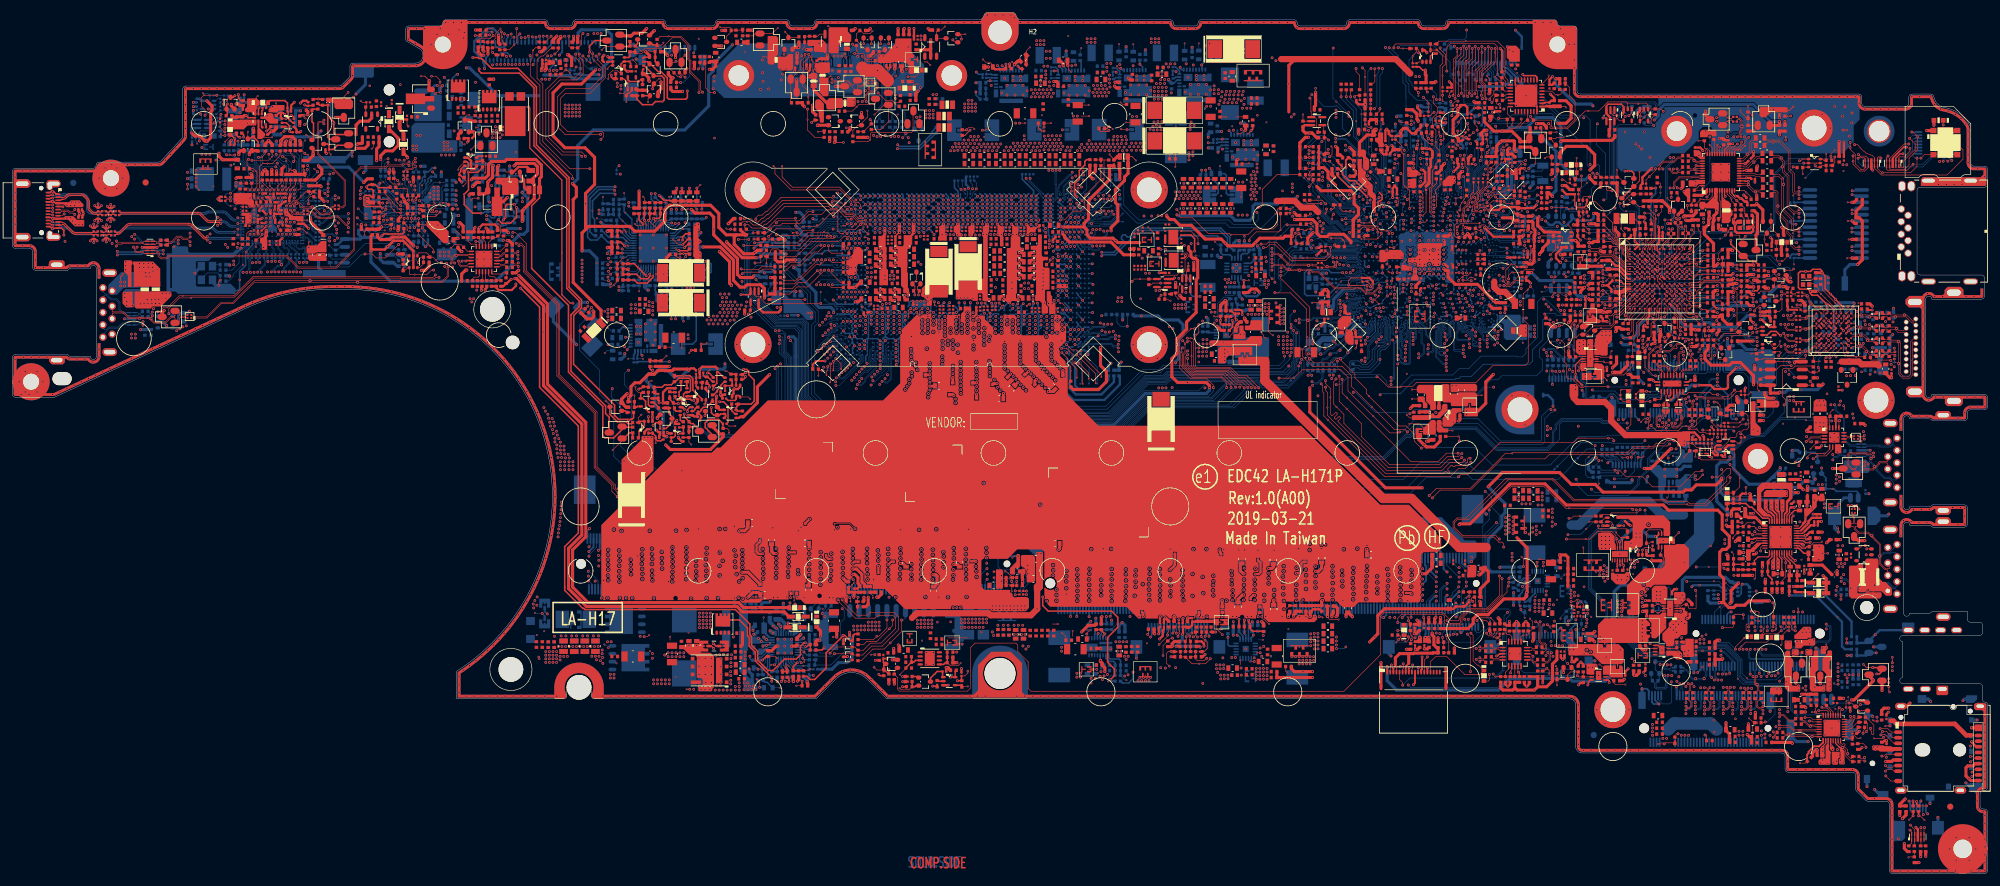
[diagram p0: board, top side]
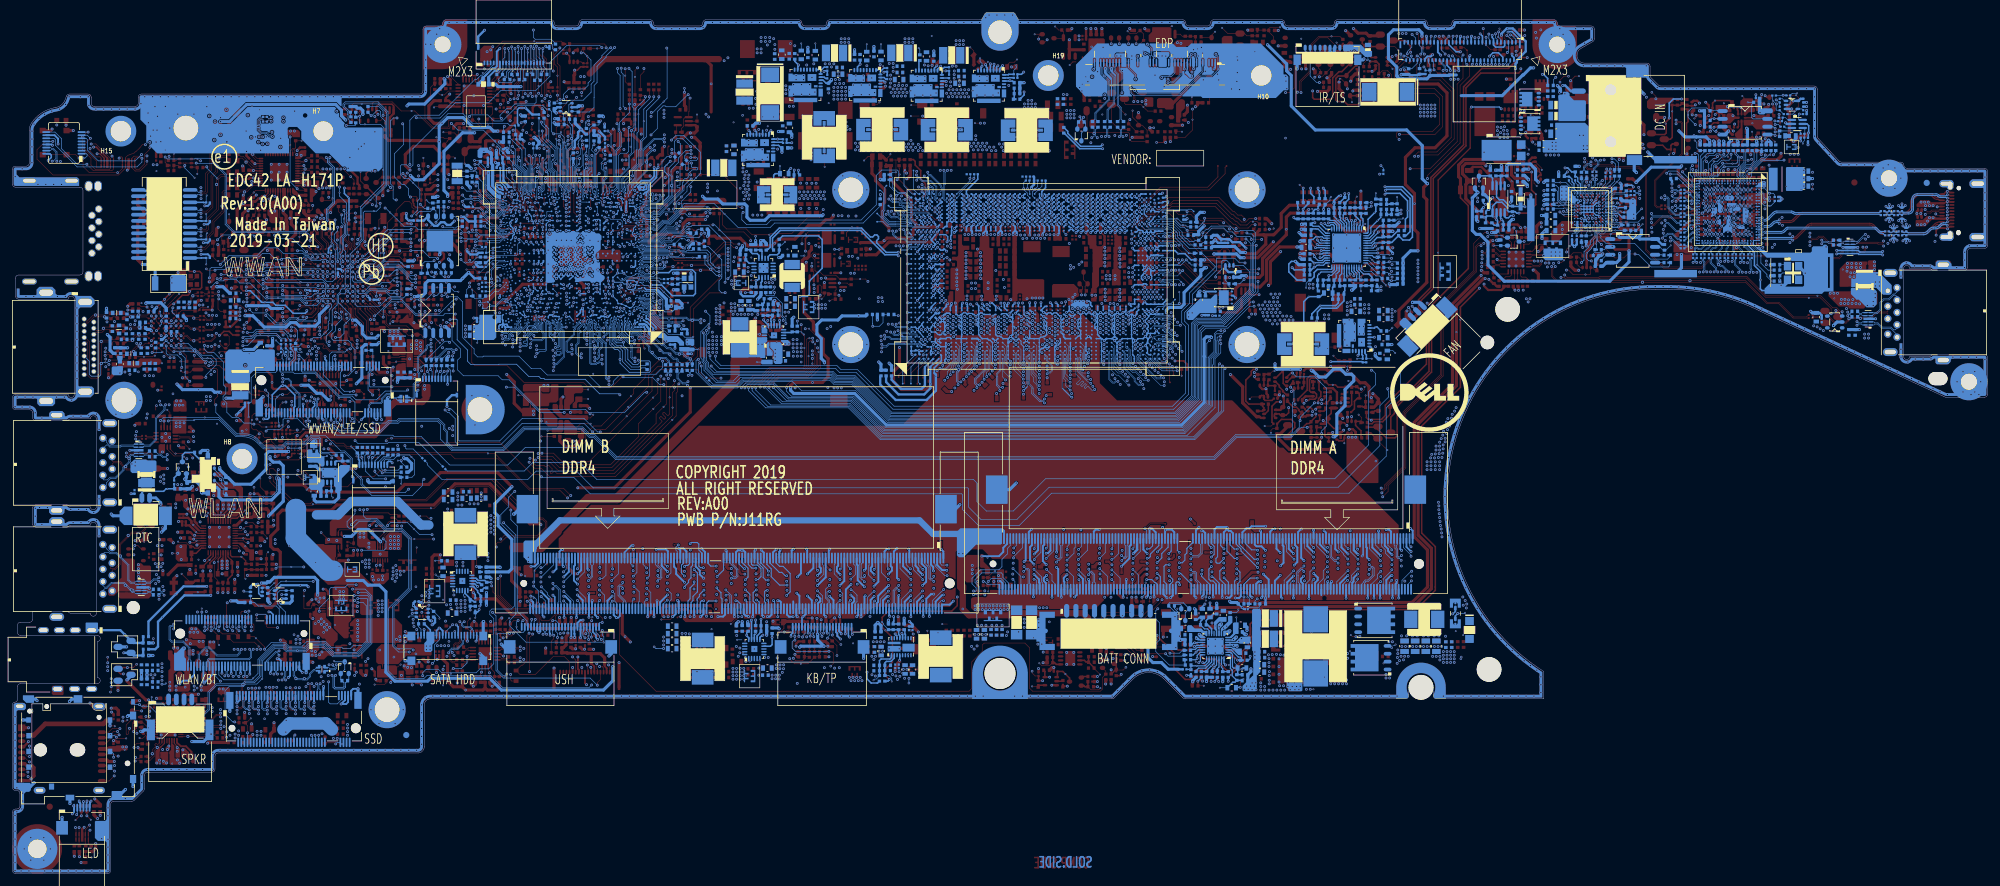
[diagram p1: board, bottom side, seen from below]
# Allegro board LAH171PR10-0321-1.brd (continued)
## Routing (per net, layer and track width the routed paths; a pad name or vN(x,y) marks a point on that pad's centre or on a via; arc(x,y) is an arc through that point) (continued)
TBTA_ROM_DO_PD_R: length 3.7
  BOTTOM w0.102: RT52.1 63.7,100.2 63.51,100.39 62.61,100.39 62.4,100.59 RT56.2 61.92,100.85 61.47,101.29 UT6.2
TBTA_ROM_HOLD#_PD: length 3.1
  BOTTOM w0.102: v1(51.18,101.55) 51.95,100.77 RT50.1 52.43,100.77 52.95,101.29 UT6.7
TBTA_ROM_WP#_PD: length 1.9
  BOTTOM w0.102: RT53.1 62.4,99.15 61.53,100.02 UT6.3
TBTA_ROSC: length 3.9
  TOP w0.107: RT100.1 59.75,108.46 v2(59.81,108.4)
  BOTTOM w0.076: UT5.G2 61.96,108.13 61,108.13 60.89,108.02 60.22,108.02 59.94,108.3
  BOTTOM w0.102: v1(59.41,108.09) 59.41,108.15 59.65,108.4 v2(59.81,108.4) 59.84,108.4 59.94,108.3
TBTA_SBU1: length 64
  TOP w0.089: JUSBC1.B8 6.5,108.07 v2(6.51,108.08)
  TOP w0.094: v2(64.07,115.03) 63.88,114.84 63.22,114.84 62.94,114.56 60.57,114.56 60.26,114.25 56.27,114.25 55.08,113.05 55.08,100.87 52.26,98.05 46.22,98.05 44.38,99.9 25.14,99.9 24.82,99.58 24.06,99.58 23.74,99.9 23.74,100.35 23.52,100.58 23.3,100.58 23.15,100.72 DT39.2 DT39.8 21.3,100.72 21.16,100.58 20.06,100.58 19.93,100.71 19.93,101.05 v2(20.14,101.25)
  BOTTOM w0.094: RT108.2 65.3,113.67 65.3,114.17 64.72,114.75 64.34,114.75 v2(64.07,115.03)
TBTA_SBU1_R: length 3.2
  BOTTOM w0.076: 65.54,112.07 65.54,110.1 65.46,110.02 65.46,109.63 UT5.K8
  BOTTOM w0.094: RT108.1 65.54,112.39 65.54,112.07
TBTA_SBU2: length 64.3
  TOP w0.094: v2(19.55,101.25) 19.72,101.09 19.72,100.62 19.98,100.36 21.16,100.36 21.3,100.22 DT39.9 DT39.1 23.15,100.22 23.3,100.36 23.43,100.36 23.53,100.26 23.53,99.81 23.97,99.37 24.91,99.37 25.23,99.68 44.29,99.68 46.14,97.84 52.34,97.84 55.29,100.79 55.29,112.96 56.36,114.03 60.35,114.03 60.66,114.35 63.03,114.35 63.3,114.63 63.88,114.63 v2(64.07,114.44) ; JUSBC1.A8 8.08,106.32
  TOP w0.102: 8.08,106.32 v2(8.38,106.63)
  BOTTOM w0.094: RT109.2 65.08,113.67 65.08,114.09 64.63,114.54 64.17,114.54 v2(64.07,114.44)
TBTA_SBU2_R: length 2.9
  BOTTOM w0.076: UT5.L8 65.21,110.02 65.37,110.19 65.37,110.49 65.37,111.74
  BOTTOM w0.094: RT109.1 65.37,111.85 65.37,111.74
TBTA_USB2_RBIAS: length 3
  TOP w0.102: RT41.1 v1(39.35,101.31)
  TOP w0.112: RT41.1 39.44,102.39 40.34,103.29 v2(40.34,103.35)
  BOTTOM w0.112: v2(40.34,103.35) UT1.H19
TBTA_USB20_N: length 3
  BOTTOM w0.076: UT1.D20 38.39,103.35 v2(38.41,103.35)
  BOTTOM w0.094: RT403.1 63.62,113.63 63.62,114.04 62.97,114.69 62.97,115.16 63.13,115.31 v2(63.3,115.31)
TBTA_USB20_N_R: length 4.8
  TOP w0.094: RT401.2 63.57,112.59 63.57,112.45 v2(63.77,112.25)
  BOTTOM w0.076: UT5.K5 63.96,109.8 63.96,109.8 63.96,110.87 63.52,111.3 63.52,111.71 63.53,111.72 63.53,111.74
  BOTTOM w0.094: RT401.2 63.57,112.59 63.57,112.4 63.73,112.25 v2(63.77,112.25) 63.59,112.07 63.59,112.04 63.53,111.97 63.53,111.74
TBTA_USB20_P: length 2.9
  BOTTOM w0.076: UT1.E20 v2(39.04,103.35)
  BOTTOM w0.094: v2(62.53,115.31) 62.69,115.31 62.78,115.22 62.78,114.61 63.44,113.96 63.44,113.67 RT402.1
TBTA_USB20_P_R: length 4.8
  TOP w0.094: v2(63.19,112.2) 63.37,112.38 63.37,112.67 63.2,112.84 RT400.2
  BOTTOM w0.076: 63.34,111.74 63.34,111.65 63.35,111.64 63.35,111.23 63.79,110.8 63.79,110.68 63.71,110.61 63.48,110.61 63.39,110.52 63.39,110.41 63.5,110.3 63.71,110.3 63.79,110.23 63.79,109.97 UT5.L5
  BOTTOM w0.094: RT400.2 63.39,112.64 63.39,112.44 63.31,112.36 63.31,112.33 v2(63.19,112.2) 63.34,112.05 63.34,111.74
TBTB_HPD: length 6.2
  BOTTOM w0.076: UT1.G2 39.67,111.53 39.88,111.75 39.88,112.12 40.18,112.42
  BOTTOM w0.107: RT33.1 39.36,116.66 39.36,114.93 40.42,113.87 v1(40.42,113.45) 40.48,113.39 40.48,112.72 40.18,112.42
TBTB_I2C_INT: length 9.1
  TOP w0.107: v2(34.61,116.18) 34.64,116.15 v1(35.11,116.15) v2(35.91,116.15)
  BOTTOM w0.076: 39.4,113.56 39.4,112.96 38.98,112.54 38.98,111.75 UT1.E2
  BOTTOM w0.107: RT17.1 34.23,116.56 v2(34.61,116.18) ; v2(35.91,116.15) 35.91,116 36.2,115.71 36.5,115.71 38.24,113.97 38.99,113.97 39.4,113.56
TBTB_LSRX: length 5.1
  BOTTOM w0.076: 36.71,109.9 37.14,109.9 37.37,110.13 UT1.B5
  BOTTOM w0.112: RT32.1 34.39,108.54 35.01,107.93 v1(35.24,107.93) 36.03,107.93 36.6,108.5 36.6,109.79 36.71,109.9
TBTB_LSTX: length 3.9
  BOTTOM w0.076: UT1.B4 37.14,110.82 36.55,110.82 36.41,110.69 36.27,110.69
  BOTTOM w0.107: RT31.1 34.39,109.72 34.64,109.97 v2(35.24,109.97) 35.96,110.69 36.27,110.69
TBTB_USB2_RBIAS: length 2.8
  TOP w0.102: 37.85,103 37.85,103.44 38.25,103.85 v1(38.54,103.85) 38.89,103.85 v2(39.04,104)
  TOP w0.107: 37.85,103 37.85,102.82 RT42.1
  BOTTOM w0.112: UT1.F19 v2(39.04,104)
TDOCK_BATLOW#: length 7.1
  BOTTOM w0.076: UT1.F2 39.42,111.74 39.42,112.42 39.85,112.85
  BOTTOM w0.107: 39.85,112.85 39.85,113.77 39.06,114.56 38.3,114.56 37.72,115.14 37.72,116.55 RT20.1
TEST_EN: length 7.2
  BOTTOM w0.076: UT1.E1 38.75,112.59 39.05,112.89 39.05,113.33 v1(38.88,113.5)
  BOTTOM w0.107: RT36.1 34.99,116.5 36.01,115.47 36.4,115.47 38.14,113.74 38.64,113.74 v1(38.88,113.5)
TEST_PWRGD: length 4.8
  BOTTOM w0.076: UT1.AB5 46.58,110.14 46.83,109.9 47.33,109.9 48.02,110.58
  BOTTOM w0.102: RT37.1 49.91,112.34 v1(49.21,111.64) 48.32,110.75 48.19,110.75 48.02,110.58
THERMDA: length 0.5
  BOTTOM w0.127: UT1.AC23 UT1.AB23
THERMTRIP1#: length 6.1
  TOP w0.109: UE1.B12 270.33,100.13 270.8,100.6 271.03,100.6 272.68,102.25 v1(272.68,102.93) 272.68,103.69 272.3,104.07 RE301.1
THERMTRIP2#: length 5.4
  TOP w0.102: CE36.1 RE69.2 285.45,90.88 285.83,91.26 285.83,92.77 v2(285.71,92.89) 285.34,92.53 QE4.1
  TOP w0.109: v2(262.43,94.92) 262.46,94.92 UE1.H3
TOUCH_SCREEN_DET#: length 10.3
  TOP w0.102: RV8.1 143.2,124.6 142.48,124.6 142.1,124.98 141.03,124.98 v2(139.82,126.18)
  BOTTOM w0.089: UH1.BC33 232.27,108.52 v2(232.02,108.28)
  BOTTOM w0.107: v2(139.82,126.18) 139.82,129.34 140.26,129.78 JEDP1.32
TOUCH_SCREEN_PD: length 5
  TOP w0.102: v1(251.33,104.79) 251.77,104.34 QH8.6
  TOP w0.109: QH8.6 252.04,103.66 252.15,103.55 252.15,103.12 252.04,103.01 QH8.5 251.58,103.01 251.28,102.71 251.28,102.04 251.91,101.41 RH104.2
TOUCH_SCREEN_PD#: length 14.8
  TOP w0.109: v2(246.63,102.76) 246.93,103.07 248.9,103.07 RH566.1 248.99,103.01 QH8.2 250.25,103.01 250.36,102.9 250.36,102.07 250.25,101.96 249.88,101.96 249.61,101.69 RH348.2
  BOTTOM w0.089: UH1.AM45 238.61,103.44 238.65,103.4 238.77,103.4 238.86,103.31 239.39,103.31 239.42,103.28 239.86,103.28 240.06,103.09 243.43,103.09 v1(243.68,102.85) 243.84,102.69 246.24,102.69 246.31,102.76 v2(246.63,102.76)
TOUCH_SCREEN_PD#_R: length 17.8
  TOP w0.109: v2(248.41,100.02) 249.24,100.86 249.24,101.84 RH566.2 249.1,102.36 QH8.3
  BOTTOM w0.107: v2(137.79,126.57) 137.26,126.04 130.4,126.04 126.76,129.67 JEDP1.5
TOUCHPAD_INTR#: length 13.1
  TOP w0.102: RH402.2 232.72,118.44 v2(233.39,117.77) v4(233.92,117.24)
  TOP w0.109: v2(256.92,96.95) 257.13,96.74 RE318.2
  BOTTOM w0.089: 232.94,117.61 232.41,117.07 232.41,113.86 231.86,113.31 UH1.BF32
  BOTTOM w0.102: v2(191.43,38.24) 191.43,38.39 191.01,38.8 JKBTP1.16 ; v2(233.39,117.77) 233.1,117.77 232.94,117.61
TP_LAN_JTAG_TCK: length 3.6
  TOP w0.102: RL2.1 v1(272.34,118.45)
  TOP w0.109: UL1.35 274.16,116.78 273.75,117.2 273.41,117.2 273.3,117.31 273.3,118.44 RL2.1
TP_LAN_JTAG_TDI: length 1.5
  TOP w0.102: T88.1 275.41,117.78 275.39,117.76
  TOP w0.109: UL1.32 275.36,117.73 275.39,117.76
TP_LAN_JTAG_TDO: length 1.6
  TOP w0.109: T89.1 274.56,117.38 UL1.34
TP_LAN_JTAG_TMS: length 2.4
  TOP w0.102: RL1.1 274.96,118.53 UL1.33
TP_SKL_E30: length 9.1
  BOTTOM w0.076: UC1.E30 171.53,104.58 173.57,104.58 173.7,104.71 175.51,104.71 175.7,104.9 176.34,104.9
  BOTTOM w0.109: T284.1 177.57,104.9 176.34,104.9
TP_SKL_F30: length 9.4
  BOTTOM w0.076: UC1.F30 171.05,104.41 173.64,104.41 173.77,104.55 175.61,104.55 175.72,104.66 176.34,104.66
  BOTTOM w0.109: T285.1 178.41,105.36 177.72,104.66 176.34,104.66
TPM_GPIO0: length 4.4
  TOP w0.102: RZ112.2 249.94,125.87 v1(249.61,125.87) 249.25,125.87 248.64,126.48 UZ12.6
TPM_GPIO0_NU: length 3.1
  TOP w0.102: UZ12.29 244.75,123.17 RZ1407.2 244.52,121.79 v1(243.45,120.72)
TPM_PIRQ#: length 30.9
  TOP w0.102: v2(231.69,129.72) 231.69,133.53 232.3,134.14 239.37,134.14 239.91,133.6 239.91,129.09 240.36,128.65 RZ69.2 241.17,128.08 241.17,127.26 241.46,126.98 UZ12.18 ; v2(229.53,125.57) 229.53,124.49 230.18,123.84 230.18,122.95 229.34,122.11 RC560.1
  TOP w0.109: RC561.1 230.44,116.94 229.93,117.44 v1(229.93,118.25) 229.93,120.14 RC560.1
TPM_PIRQ#_B20: length 10.5
  TOP w0.109: v2(229.59,106.23) 228.92,106.91 228.92,110.76 229.36,111.2 v1(229.36,111.39) 229.36,113.59 RH339.2 229.92,114.7 RC561.2
  BOTTOM w0.089: UH1.AU26 v2(229.59,106.23)
TPM_PIRQ#_R: length 12
  TOP w0.109: v2(230.7,119.17) 230.44,119.44 v1(230.44,119.83) 230.44,120.55 RC560.2
  BOTTOM w0.089: UH1.BD29 230.29,109.65 230.1,109.84 230.1,110.61 229.91,110.81 229.91,111.09 230.23,111.41 230.23,118.15 230.18,118.2 230.18,118.66 v2(230.7,119.17)
TPM_TYPE: length 5.9
  TOP w0.109: v2(233.36,105.61) 233.36,105.2 232.98,104.82 232.98,103.05 233.2,102.83 RH379.1
  BOTTOM w0.089: v2(233.36,105.61) 232.72,106.25 232.72,106.97 232.63,107.06 UH1.AW32
TS_INT#: length 8.7
  TOP w0.102: 107.26,127.87 RV319.2 ; 107.26,127.87 RV1657.2 ; 107.26,127.87 107.88,127.87 107.88,127.87 v2(107.93,127.87)
  BOTTOM w0.089: v2(226,105.8) 226,105.87 UH1.AV21
  BOTTOM w0.102: v2(107.93,127.87) 108.38,127.87 109.43,128.91 JIRTS1.2
TSENSE_2PH_CPU: length 4.9
  TOP w0.254: v2(103.42,81.33) 103.25,81.33 102.99,81.59 PRZ79.2
  BOTTOM w0.102: v2(103.42,81.33) v1(103.42,81.96)
  BOTTOM w0.203: PUZ1.25 107,99.11 107.37,98.74 108.71,98.74 v2(108.79,98.67)
  BOTTOM w0.254: PCZ33.1 109.42,99.3 v2(108.79,98.67)
TSENSE_4PH_CPU: length 5.4
  BOTTOM w0.203: PUZ1.14 106.89,103.51 108.02,104.64 108.96,104.64 PCZ32.1
  BOTTOM w0.254: v2(155.63,126.34) 155.63,125.85 156.1,125.38 156.1,125.38 PRZ78.2 ; v2(108.67,105.21) 109.03,105.21 PCZ32.1
TYPEC_CON_SEL1: length 2.8
  TOP w0.102: v1(227.11,125.73) v2(227.11,126.24) 226.69,126.65 RH555.1
  TOP w0.109: RH555.1 RH556.1
  BOTTOM w0.089: v2(227.39,107.59) 227.73,107.59 UH1.BA24
TYPEC_CON_SEL2: length 3.5
  TOP w0.102: v2(228.55,126.32) 228.34,126.53 RH554.1 RH553.1 ; v2(227.39,105.25) 228.17,105.25 228.47,105.55 v1(228.47,105.61)
  BOTTOM w0.089: v2(227.39,105.25) 227.39,105.21 UH1.AP24
TYPEC_ID: length 8.7
  TOP w0.102: RE343.1 CE62.1
  TOP w0.109: UE1.F2 261.67,97.33 260.97,97.33 259.34,98.95 259.13,98.95 v1(258.95,99.13) 258.34,99.75 256.55,99.75 255.98,99.17 CE62.1
UART_MISO: length 4.7
  TOP w0.102: v2(60.32,107.38) 60.32,107.65 60.34,107.67 v1(60.34,107.94)
  TOP w0.107: RT82.1 RT83.2 59.86,106.95 60.29,107.38 v2(60.32,107.38)
  BOTTOM w0.076: 60.95,107.38 61.2,107.63 61.96,107.63 UT5.F2
  BOTTOM w0.107: 60.95,107.38 v2(60.32,107.38)
UART_MOSI: length 4.8
  TOP w0.102: v2(59.94,106.26) 59.94,106.38 60.19,106.63 v1(60.32,106.63)
  TOP w0.107: RT81.1 59.27,105.9 59.25,105.91 RT83.1 59.25,106.13 59.39,106.26 v2(59.94,106.26)
  BOTTOM w0.076: UT5.E2 61.96,106.63 61.41,106.63 61.13,106.35 60.67,106.35
  BOTTOM w0.112: v2(59.94,106.26) 60.03,106.35 60.67,106.35
UG1_CHG: length 0.9
  TOP w0.102: v1(102.87,38.55) 102.61,38.3 v2(102.04,38.3)
  vias: v2(101.4,38.36) v2(123.73,40.36) v2(124.12,39.9)
UG2_CHG: length 0.7
  TOP w0.102: v1(122.36,37.22) 122.04,36.9 v2(121.82,36.9)
  vias: v2(116.04,31.25) v2(116.04,30.67) v2(121.23,36.75)
UIM_CLK: length 6.9
  TOP w0.102: CZ38.1 307.28,4.55 DZ13.2 DZ13.8 307.28,7.08 306.95,7.41 306.95,7.47 v2(306.58,7.84)
  BOTTOM w0.109: v2(266.96,83.74) 267.12,83.74 267.33,83.53 JNGFF2.32 ; v2(302.7,18.81) 302.7,19.38 303.07,19.75 JSIM1.C3
UIM_DATA: length 10.4
  TOP w0.102: RZ335.2 CZ39.1 308.28,4.54 DZ13.4 DZ13.7 v2(308.28,7.44)
  BOTTOM w0.102: v2(264.46,84.82) 264.81,84.82 v1(264.98,84.64) 265.33,84.3 267.43,84.3 267.82,83.91 JNGFF2.34
  BOTTOM w0.109: JSIM1.C7 316.29,19.9 v2(316.29,20.62)
UIM_RESET: length 6.9
  TOP w0.102: CZ40.1 306.78,4.94 DZ13.1 DZ13.9 306.78,6.9 306.65,7.02 v2(306.51,7.02) ; v1(300.67,21.85) 302.06,21.85 v2(302.26,22.04)
  BOTTOM w0.109: v2(266.91,83.15) 266.83,83.07 JNGFF2.30 ; JSIM1.C2 302.5,22.29 v2(302.26,22.04)
UPD1_SMBCLK: length 18.3
  TOP w0.102: v2(68.03,97.55) 67.69,97.55 66.97,96.83 v1(64.96,96.83) 64.22,96.83 64.12,96.93 QT1.1 ; v2(254.64,104.12) 254.55,104.21 254.39,104.21 RE303.1
  TOP w0.107: QT1.1 63.88,97.96 63.49,97.56 RT58.1
  TOP w0.109: v2(262.49,99.81) 262.49,99.71 UE1.C3
  BOTTOM w0.109: v2(254.64,104.12) 254.71,104.12 254.73,104.1 258.43,104.1 259.08,103.45 259.08,102.86 262.13,99.81 v2(262.49,99.81)
UPD1_SMBCLK_Q: length 12.7
  TOP w0.107: v2(64.01,99.04) 63.45,98.48 RT58.2 RT67.1 63.76,99.86 QT1.6
  BOTTOM w0.076: 63.69,102.46 63.37,102.79 63.37,103.82 63.58,104.03 63.58,104.56 63.46,104.69 63.46,105.13 UT5.B5
  BOTTOM w0.102: RT92.1 60.23,113.65 60.13,113.75 60.13,114.7 60.45,115.02 60.64,115.02 60.68,114.98 v2(60.68,114.97)
  BOTTOM w0.107: v2(64.01,99.04) 64.39,99.04 64.77,99.41 v1(64.77,100.26) 63.94,101.08 63.94,101.23 63.69,101.48 63.69,102.46
UPD1_SMBDAT: length 8.7
  TOP w0.102: v2(69.27,98.75) 68.83,98.75 v1(68.45,99.13) 67.94,99.64 RT59.1 ; UE1.B4 263.67,100.13 263.36,100.44 v2(263.28,100.44) 263.28,100.51 263.27,100.53 263.27,100.98 263.79,101.5 263.79,103.31 RE302.1
  TOP w0.107: RT59.1 67.32,99.95 66.93,100.34 65.66,100.34 65.42,100.1 QT1.4
UPD1_SMBDAT_Q: length 13.6
  TOP w0.102: RT59.2 66.38,99.64 ; 66.38,99.64 66.4,99.62 RT66.1 66.4,98.55 65.81,97.96 QT1.3 ; 66.38,99.64 66.04,99.64 65.59,99.2 v2(65.59,98.76)
  BOTTOM w0.076: UT5.A5 63.71,104.75 63.82,104.63 63.82,104.04 63.53,103.75 63.53,102.97 63.98,102.52
  BOTTOM w0.102: RT93.1 59.55,113.65 59.65,113.75 59.65,114.9 60.25,115.5 60.63,115.5 v2(60.68,115.55)
  BOTTOM w0.107: 63.98,102.52 64.18,102.32 64.18,101.69 64.43,101.44 64.43,101.28 65.19,100.52 65.19,99.16 v2(65.59,98.76)
UPD1_SMBINT#: length 12.8
  TOP w0.102: v2(278.55,98.35) 278.61,98.35 278.63,98.37 RE91.1
  TOP w0.109: UE1.F10 v2(268.87,97.33)
  BOTTOM w0.102: v2(268.87,97.33) 268.95,97.33 269.37,97.75 273.31,97.75 273.72,98.16 276.64,98.16 277.25,98.77 278.13,98.77 v2(278.55,98.35)
  BOTTOM w0.107: v2(65.4,101.21) 65.53,101.33 65.53,102.09 RT60.1
UPD1_SMBUS_ALERT#: length 4.3
  BOTTOM w0.076: UT5.B6 64.21,105.28 64.46,105.03 64.46,104.76 64.58,104.64 64.58,103.79 64.84,103.53 RT68.1 64.12,103.08 v1(63.94,103.26)
  BOTTOM w0.107: RT60.2 RT68.1
UPD2_SMBCLK: length 10.1
  TOP w0.102: RE721.1 v2(265.49,107.18)
  TOP w0.109: v2(265.66,98.93) 265.67,98.93 UE1.D7
  BOTTOM w0.102: v2(265.49,107.18) 265.43,107.13 265.43,105.92 v1(265.49,105.86) 265.49,105.23 265.21,104.96 265.21,103.35 265.77,102.8 265.77,100.38 266.06,100.09 266.06,99.57 265.67,99.19 265.67,98.93 v2(265.66,98.93)
UPD2_SMBDAT: length 11.3
  TOP w0.102: RE722.1 266.38,107.01 v2(265.84,106.47)
  TOP w0.109: v2(265.72,98.1) 265.72,98.08 UE1.E7
  BOTTOM w0.102: v2(265.84,106.47) 265.93,106.38 265.93,105.23 265.44,104.74 265.44,103.45 266.12,102.77 266.12,100.59 266.31,100.4 266.31,99.45 266.06,99.19 v1(266.06,98.56) 266.06,98.44 v2(265.72,98.1)
UPD2_SMBINT#: length 14.4
  TOP w0.102: RE92.1 v2(253.92,95.51)
  TOP w0.109: UE1.F5 264.15,97.25 v2(264.07,97.25)
  BOTTOM w0.109: v2(264.07,97.25) 264,97.25 263.66,96.91 263.66,96.19 263.29,95.81 261.84,95.81 261.21,96.44 260.4,96.44 258.9,97.95 256.75,97.95 255.27,96.47 v1(255.27,96.21) 254.58,95.53 253.93,95.53 v2(253.92,95.51)
USB2_COMP: length 6.1
  BOTTOM w0.089: RH193.1 213.37,88.15 214.13,88.15 216.18,90.2 216.18,90.38 216.47,90.67 216.92,90.67 216.96,90.64 217.52,90.64 UH1.F4
USB2_ID: length 5.9
  BOTTOM w0.089: RH365.1 214.24,88.53 215.99,90.27 215.99,90.46 216.39,90.86 217,90.86 217.03,90.83 217.44,90.83 UH1.G3
USB2_VBUSSENSE: length 10
  BOTTOM w0.089: 212.4,87.13 213.1,87.13 213.67,87.7 213.96,87.7 216.37,90.12 216.37,90.3 216.55,90.48 216.8,90.48 216.95,90.33 UH1.F3
  BOTTOM w0.102: RH364.1 210.96,87.21 210.43,86.69 209.16,86.69 v1(209.08,86.78)
  BOTTOM w0.109: 212.4,87.13 211.08,87.13 RH364.1
USB3_A_DE0: length 2.3
  TOP w0.109: RI60.1 RI74.1 76.43,96.04 UI6.16
USB3_A_DE1: length 3.7
  TOP w0.109: UI6.18 77.43,97.02 77.54,96.92 79.04,96.92 79.23,97.11 RI70.1 79.85,96.41 RI72.1
USB3_A_EQ0: length 3.1
  TOP w0.109: RI65.1 RI59.1 78.15,96.15 77.83,96.47 77.2,96.47 76.93,96.74 UI6.17
USB3_A_EQ1: length 2.2
  TOP w0.109: UI6.15 75.93,95.92 RI76.1 RI68.1
USB3_B_DE0: length 2.3
  TOP w0.109: UI6.3 76.43,102.07 76.05,102.45 RI62.1 RI78.1
USB3_B_DE1: length 4.8
  TOP w0.102: v1(71.62,103.77) 71.85,103.77 RI66.1
  TOP w0.109: UI6.6 74.93,101.66 74.85,101.74 74.08,101.74 73.58,102.25 RI73.1 RI66.1
USB3_B_EQ0: length 4.9
  TOP w0.102: v1(78.49,105.04) 78.86,104.67 78.86,103.52 RI67.1 78.15,102.81 RI71.1
  TOP w0.109: RI71.1 77.58,102.67 76.93,102.03 UI6.2
USB3_B_EQ1: length 2.5
  TOP w0.109: RI61.1 RI64.1 75.48,102.62 75.48,102.44 75.93,101.99 UI6.4
USB3_PD#_UI6: length 4
  TOP w0.102: UI6.5 75.43,101.99 75.24,102.18 v2(74.86,102.18)
  BOTTOM w0.102: v1(76.12,103.91) 76.12,102.61 QI2.1 74.89,102.15 v2(74.86,102.18)
USB3_PRX_C_RD_DTX_N3: length 2
  TOP w0.094: CI49.2 79.48,100.35 79.31,100.35 78.88,99.92 78.71,99.92 78.55,100.08 UI6.23
USB3_PRX_C_RD_DTX_P3: length 2
  TOP w0.094: CI53.2 79.52,100.17 79.39,100.17 78.96,99.74 78.7,99.74 78.54,99.58 UI6.22
USB3_PRX_DTX_N1: length 21.3
  BOTTOM w0.089: v2(220.72,86.35) 220.81,86.35 221.06,86.09 221.46,86.09 221.77,86.4 221.77,89.19 221.89,89.31 221.95,89.44 221.95,89.82 221.8,89.97 UH1.D11
  BOTTOM w0.094: v2(295.11,75.77) 294.89,75.77 294.57,75.45 294.57,75.01 295.97,73.61 295.97,70.18 296.88,69.27 297.73,69.27 297.88,69.43 DI4.9 DI4.1 299.33,69.43 299.48,69.27 301.51,69.27 301.65,69.13 303.25,69.13 303.83,69.71 303.83,69.97 304.26,70.4 JUSB1.5
USB3_PRX_DTX_N2: length 12.3
  TOP w0.094: UZ29.18 266.84,80.83 266.52,81.15 266.52,81.33 266.32,81.53 264.87,81.53 264.41,82 264.41,83.89 265.59,85.07 266,85.07 266.08,84.99 266.08,84.99 v2(266.28,84.79)
  BOTTOM w0.089: UH1.B9 220.68,88.83 220.68,88.83 220.68,88.64 220.85,88.46 220.85,88.28 220.68,88.11 220.68,87.39 219.31,86.02 218.88,86.02 218.56,85.71 v2(218.56,85.62)
USB3_PRX_DTX_N3: length 8.7
  TOP w0.094: CI49.1 81.12,100.37 81.49,100.37 v2(81.66,100.54)
  BOTTOM w0.089: v2(218.48,82.75) 218.48,82.83 218.56,82.91 ; 219.15,84.34 219.15,84.35 219.14,84.36 219.14,84.42 219.13,84.43 219.13,85.31 221.23,87.4 221.23,88.92 UH1.B10
  BOTTOM w0.094: 218.56,82.91 218.59,82.94 218.7,82.94 219.15,83.39 219.15,84.34
USB3_PRX_DTX_N4: length 14.1
  BOTTOM w0.094: v2(295.4,47.83) 295.59,47.64 296.27,47.64 296.79,47.12 297.37,47.12 297.47,47.12 297.61,47.26 DI6.9 DI6.1 299.17,47.26 299.33,47.11 299.84,47.11 300.22,47.49 300.22,49.92 302.19,51.88 303.21,51.88 303.83,52.51 303.83,52.6 JUSB3.5 ; UH1.K16 223.32,92.92 223.22,93.02 v2(223.22,93.05)
USB3_PRX_DTX_P1: length 21.3
  BOTTOM w0.089: UH1.C11 221.71,89.73 221.61,89.84 221.49,89.84 221.43,89.78 221.43,89.4 221.58,89.25 221.58,88.72 221.42,88.56 221.42,88.4 221.58,88.24 221.58,86.48 221.38,86.28 221.19,86.28 221.1,86.37 221.1,86.74 v2(221.13,86.77)
  BOTTOM w0.094: JUSB1.6 304.43,68.7 303.84,69.29 303.67,69.29 303.33,68.94 301.58,68.94 301.44,69.08 299.57,69.08 299.42,68.93 DI4.2 DI4.8 297.98,68.93 297.83,69.08 296.8,69.08 295.78,70.1 295.78,73.53 294.38,74.93 294.38,75.71 v2(294.31,75.78)
USB3_PRX_DTX_P2: length 12.4
  TOP w0.094: UZ29.19 266.34,81.25 266.24,81.35 264.8,81.35 264.22,81.92 264.22,83.97 265.51,85.26 266.16,85.26 v2(266.28,85.38)
  BOTTOM w0.089: UH1.C9 220.46,89.23 220.46,88.79 220.49,88.76 220.49,87.47 219.23,86.21 v2(218.54,86.21)
USB3_PRX_DTX_P3: length 8.7
  TOP w0.094: v2(81.66,99.96) 81.43,100.19 81.12,100.19 CI53.1
  BOTTOM w0.089: 218.94,84.34 218.94,85.38 221.04,87.48 221.04,89.45 221.17,89.58 UH1.C10 ; 218.56,83.34 v2(218.48,83.34)
  BOTTOM w0.094: 218.56,83.34 218.83,83.34 218.94,83.45 218.94,84.34
USB3_PRX_DTX_P4: length 14.2
  BOTTOM w0.094: JUSB3.6 304.29,51.34 304.29,51.8 304.19,51.89 303.47,51.89 303.28,51.7 302.26,51.7 300.41,49.84 300.41,47.41 299.92,46.92 299.33,46.92 299.17,46.76 DI6.2 DI6.8 297.54,46.76 297.37,46.93 296.71,46.93 296.19,47.45 295.61,47.45 v2(295.4,47.24) ; UH1.J15 223.43,92.34 223.09,92.34 v2(223,92.25)
USB3_PRX_RD_DTX_N3: length 12.2
  TOP w0.094: v2(70.86,98.69) 70.86,99.58 71.39,100.11 71.99,100.11 72.03,100.08 UI6.8
  BOTTOM w0.094: v2(21.1,88.63) 20.9,88.83 20.38,88.83 20.23,88.67 DI1.9 DI1.1 18.37,88.67 18.22,88.83 17.78,88.83 17.1,88.15 15.68,88.15 14.62,87.09 JUSB2.5
USB3_PRX_RD_DTX_P3: length 12.1
  TOP w0.094: UI6.9 73.89,99.58 73.57,99.89 v3(71.7,99.89) 71.44,99.89 71.05,99.5 71.05,99.09 v2(71.45,98.69)
  BOTTOM w0.094: JUSB2.6 14.62,88.19 14.92,87.89 15.16,87.89 15.6,88.34 17.02,88.34 17.7,89.02 18.22,89.02 18.37,89.17 DI1.2 DI1.8 20.23,89.17 20.38,89.02 20.91,89.02 v2(21.1,89.21)
USB3_PTX_C_DRX_N1: length 11
  BOTTOM w0.094: CI13.1 297.38,67.82 297.81,67.82 297.91,67.93 DI4.7 DI4.4 299.3,67.93 299.46,67.77 299.93,67.77 300.22,67.47 v3(300.22,67.12) 300.22,66.58 300.65,66.15 300.7,66.15 301.2,65.65 301.2,65.26 302.38,64.08 303.27,64.08 303.72,63.64 304.27,63.64 304.43,63.79 JUSB1.8
USB3_PTX_C_DRX_N2: length 4.1
  TOP w0.094: CZ151.2 265.73,82.49 265.73,82.28 265.84,82.18 267.11,82.18 v3(267.54,81.75) 267.71,81.57 267.71,81.22 267.84,81.09 UZ29.16
USB3_PTX_C_DRX_N3: length 9.3
  BOTTOM w0.094: JUSB2.8 14.62,93.24 14.86,93.48 15.16,93.48 15.92,92.72 16.75,92.72 17.2,92.26 17.2,91.13 17.85,90.49 18.36,90.49 18.67,90.17 DI1.4 DI1.7 20.23,90.17 20.38,90.33 20.66,90.33 CI5.1
USB3_PTX_C_DRX_N4: length 10.1
  BOTTOM w0.094: JUSB3.8 304.43,46.57 304.16,46.3 303.84,46.3 303.08,47.06 300.95,47.06 300.45,46.56 300.45,46.52 v3(299.79,45.85) 299.54,45.61 299.33,45.61 299.17,45.76 DI6.4 DI6.7 297.32,45.76 297.17,45.62 296.62,45.62 CI27.1
USB3_PTX_C_DRX_P1: length 10.9
  BOTTOM w0.094: JUSB1.9 304.26,62.4 303.83,62.83 303.83,63.2 303.14,63.9 302.31,63.9 301.02,65.19 301.02,65.53 v3(300.75,65.79) 300,66.54 300,67.43 299.85,67.58 299.53,67.58 299.38,67.43 DI4.5 DI4.6 297.9,67.43 297.68,67.64 297.06,67.64 296.91,67.49 CI16.1
USB3_PTX_C_DRX_P2: length 4
  TOP w0.094: UZ29.17 267.34,81.09 267.46,81.22 267.46,81.52 267.05,81.93 v3(266.12,81.93) 265.82,81.93 265.55,82.21 265.55,82.43 CZ150.2
USB3_PTX_C_DRX_P3: length 9.3
  BOTTOM w0.094: JUSB2.9 14.62,94.06 15.01,93.67 15.24,93.67 16,92.91 16.82,92.91 17.39,92.34 17.39,91.21 17.93,90.67 DI1.5 DI1.6 20.23,90.67 20.38,90.52 20.64,90.52 CI4.1
USB3_PTX_C_DRX_P4: length 10.1
  BOTTOM w0.094: JUSB3.9 304.43,45.75 304.07,46.12 303.77,46.12 303,46.88 301.08,46.88 v3(300.81,46.62) 300.15,45.95 300.15,45.9 299.73,45.49 299.69,45.49 299.62,45.42 299.33,45.42 299.17,45.26 DI6.5 DI6.6 297.32,45.26 297.17,45.41 296.64,45.41 CI28.1
USB3_PTX_C_RD_DRX_N3: length 1.9
  TOP w0.094: UI6.20 78.72,98.58 78.86,98.44 79.4,98.44 CI51.1
USB3_PTX_C_RD_DRX_P3: length 1.9
  TOP w0.094: CI54.1 79.85,98.15 79.76,98.24 78.86,98.24 78.7,98.08 UI6.19
USB3_PTX_DRX_N1: length 3.3
  BOTTOM w0.089: v2(220.86,91.42) 220.86,91.18 220.67,90.99 220.55,90.87 UH1.F9
  BOTTOM w0.094: CI13.2 295.5,67.81 295.07,67.81 294.71,67.45 294.13,67.45 294.04,67.54 v2(294.04,67.73)
USB3_PTX_DRX_N2: length 7
  TOP w0.094: v2(270.12,85.21) 269.82,85.51 268.95,85.51 268.77,85.34 268.77,85.2 268.89,85.08 268.89,84.95 268.76,84.82 268.63,84.82 268.5,84.94 268.37,84.94 267.76,84.33 266.76,84.33 266.61,84.18 266.06,84.18 265.91,84.33 265.77,84.33 265.68,84.24 265.68,84.1 CZ151.1
  BOTTOM w0.089: UH1.C3 217.61,89.57 217.37,89.8 v2(217.37,89.87)
USB3_PTX_DRX_N3: length 1.7
  TOP w0.094: v2(81.72,98.71) 81.54,98.53 81.12,98.53 CI51.2
  BOTTOM w0.094: v2(221.06,90.85) UH1.F11
USB3_PTX_DRX_N4: length 4.5
  BOTTOM w0.089: v2(223.53,86.74) 223.53,86.91 223.43,87.01 223.13,87.01 222.83,87.31 222.83,88.36 223.12,88.65 223.12,89.06 223.05,89.13 222.93,89.13 222.88,89.08 UH1.B14
  BOTTOM w0.094: v2(294.57,45.79) 294.57,45.67 294.7,45.53 294.97,45.53 CI27.2
USB3_PTX_DRX_P1: length 3.3
  BOTTOM w0.089: UH1.F7 v2(220.27,91.36)
  BOTTOM w0.094: v2(294.04,66.88) 294.04,67.11 294.2,67.26 294.78,67.26 295.14,67.62 295.76,67.62 CI16.2
USB3_PTX_DRX_P2: length 7
  TOP w0.094: v2(270.25,86.08) 270.25,86.02 269.93,85.7 268.87,85.7 267.68,84.52 266.69,84.52 266.53,84.36 266.14,84.36 265.98,84.52 265.7,84.52 265.49,84.31 265.49,84.05 CZ150.1
  BOTTOM w0.089: UH1.D4 217.77,89.88 217.77,90.01 v2(217.89,90.13)
USB3_PTX_DRX_P3: length 1.7
  TOP w0.094: v2(81.72,98.13) 81.5,98.35 81.12,98.35 CI54.2
  BOTTOM w0.094: v2(221.44,91.51) UH1.G12
USB3_PTX_DRX_P4: length 4.5
  BOTTOM w0.089: UH1.C14 223.01,89.32 223.13,89.32 223.31,89.14 223.31,88.57 223.03,88.29 223.03,87.38 223.21,87.2 223.38,87.2 223.53,87.35 v2(223.53,87.57)
  BOTTOM w0.094: v2(294.55,45) 294.55,45.07 294.83,45.35 295.12,45.35 295.38,45.1 CI28.2
USB3_PTX_RD_DRX_N3: length 3.7
  TOP w0.094: v2(72.64,99.01) 72.63,99.01 72.28,98.66 72.28,98.49 72.5,98.26 73.41,98.26 73.72,98.58 UI6.11
  BOTTOM w0.094: v2(22.6,90.18) 22.42,90.36 22.22,90.36 21.92,90.05 CI5.2
USB3_PTX_RD_DRX_P3: length 3.7
  TOP w0.094: UI6.12 72.42,98.08 72.09,98.41 72.09,98.97 v2(72.06,99.01)
  BOTTOM w0.094: v2(22.6,90.76) 22.38,90.54 22.17,90.54 21.92,90.8 CI4.2
USB3_TEST: length 2.3
  TOP w0.109: UI6.14 75.43,96.61 75.23,96.41 74.59,96.41 74.34,96.15 RI63.2
USB20_N1: length 7.7
  TOP w0.094: UI3.2 292.14,70.75 291.98,70.6 290.47,70.6 290.03,70.15 290.03,69.94 289.93,69.85 v2(289.75,69.85)
  BOTTOM w0.089: UH1.J3 217.91,92.43 217.6,92.74 217.08,92.74 216.88,92.55 216.16,92.55 215.43,91.82 215.43,91.61 215.34,91.52 214.59,91.52 v2(214.55,91.48)
USB20_N2: length 46.7
  TOP w0.094: LI3.4 28.94,90.3 29.25,89.99 31.35,89.99 33.7,92.33 35.61,92.33 39.1,95.83 v3(48.08,95.83) 62.49,95.83 62.6,95.72 69.37,95.72 70.23,96.58 70.23,97.72 v2(69.83,98.12)
  BOTTOM w0.094: UH1.N13 222.88,94.1 222.88,93.89 222.69,93.7 v2(222.61,93.7)
USB20_N2_R: length 15.6
  TOP w0.094: JUSB2.2 16.12,90.89 16.21,90.79 17.99,90.79 18.85,89.93 20.22,89.93 20.25,89.96 20.84,89.96 20.87,89.93 22.16,89.93 v3(22.39,89.69) 22.92,89.16 24.7,89.16 25.6,90.07 26.18,90.07 26.27,90.16 DI2.3 26.62,90.96 26.98,90.59 26.98,90.22 27.1,90.1 28.04,90.1 28.24,90.3 LI3.3
USB20_N3: length 5
  TOP w0.094: v2(297.1,59.51) 297.2,59.51 297.34,59.36 297.34,59.2 297.12,58.97 LI4.4
  BOTTOM w0.089: UH1.K4 218.22,93.12 216.9,93.12 216.76,92.98 216.05,92.98 215.75,92.68 214.45,92.68 v2(214.43,92.66)
USB20_N3_R: length 15.1
  TOP w0.094: LI4.3 297.27,58.16 297.27,57.61 297.4,57.48 297.4,56.64 297.31,56.55 DI3.3 297,56.08 297.37,56.08 297.5,55.95 297.5,55.69 298.17,55.02 299.71,55.02 299.98,54.75 299.98,54.71 300.39,54.29 300.44,54.29 300.87,53.86 300.87,53.86 301.6,53.13 v3(301.6,51.34) 301.6,49.99 302.49,49.11 302.84,49.11 302.93,49.01 JUSB3.2
USB20_N4: length 4.4
  TOP w0.094: RZ1388.2 278.6,121.6 278.6,121.74 278.77,121.91 278.96,121.91 279.21,121.66 v3(279.21,120.81) 279.21,120.23 279.02,120.04 279.02,119.47 v2(278.62,119.07)
  BOTTOM w0.089: UH1.M10 220.97,93.87 v2(220.82,94.01)
USB20_N4_FP: length 7.9
  TOP w0.094: RZ1388.1 277.72,121.79 277.43,121.79 v2(277.24,121.6) 276.88,121.6 DZ11.2 275.55,121.66 275.34,121.66 v2(275.27,121.59)
  BOTTOM w0.094: JFPBTN1.6 312.9,117.35 312.75,117.19 312.38,117.19 311.83,116.65 311.83,115.18 v2(311.88,115.14) ; RZ1388.1 277.72,121.79 277.43,121.79 v2(277.24,121.6)
USB20_N4_USH: length 6.7
  BOTTOM w0.094: JUSH1.23 235.28,40.68 235.14,40.82 235.14,41.06 v2(235.17,41.1) ; v2(277.12,119.85) 277.12,119.63 277.36,119.38 277.51,119.38 277.96,119.83 278.81,119.83 279.2,120.22 279.2,120.42 279.17,120.46 279.17,121.04 279.2,121.07 279.2,121.75 279.01,121.94 278.64,121.94 278.54,121.85 RZ350.2
USB20_N5: length 5.3
  TOP w0.094: v2(65.1,115.02) 65.08,115 64.98,115 64.83,114.86 64.83,114.61 64.92,114.52 65.18,114.52 65.27,114.42 65.27,114.23 65.18,114.14 64.92,114.14 64.83,114.05 64.83,114.03 64.59,113.79 63.78,113.79 63.69,113.7 63.69,113.56 RT401.1
  BOTTOM w0.089: UH1.M1 216.66,93.54 216.66,93.32 216.57,93.23 216.4,93.23 216.28,93.36 216.28,93.48 216.27,93.48 216.15,93.6 215.98,93.6 215.55,93.17 v2(215.55,93.06)
USB20_N6: length 2.2
  TOP w0.094: v2(219.4,92.98) 219.56,92.82 220.12,92.82 T300.1
  BOTTOM w0.094: UH1.K7 219.49,92.88 219.4,92.96 v2(219.4,92.98)
USB20_N8: length 21.4
  BOTTOM w0.089: UH1.G4 218.2,91.21 218.2,91.38 218.14,91.44 218.01,91.44 217.89,91.32 217.33,91.32 217.27,91.39 216.99,91.39 216.81,91.57 216.53,91.57 216.38,91.42 216.38,91.12 215.8,90.54 215.8,90.35 214.43,88.98 212.56,88.98 212.55,88.98 212.4,88.98
  BOTTOM w0.094: v2(210.58,88.55) 211.02,88.98 212.4,88.98 212.4,88.98 ; RI48.1 255.34,77.11 LI8.4 254.7,76.98 254.55,76.82 254.41,76.82 254.32,76.91 254.32,79.11 253.82,79.61 253.51,79.61 253.42,79.71 253.42,80.82 253.66,81.06 253.66,83.45 252.22,84.89 252.22,85.29 252,85.51 251.61,85.51 v2(251.41,85.7)
USB20_N8_R: length 7.9
  BOTTOM w0.094: RI48.2 256.32,77.11 LI8.3 257.46,76.98 258.07,77.59 258.66,77.59 259.45,76.8 259.45,76.27 259.55,76.17 261.12,76.17 261.58,75.72 JNGFF2.9
USB20_N10: length 12.8
  BOTTOM w0.089: 212.4,89.95 212.52,89.95 212.52,89.95 214.59,89.95 215.23,90.59 215.23,90.78 215.81,91.36 215.81,91.66 216.29,92.14 217.06,92.14 217.11,92.09 217.55,92.09 UH1.H3
  BOTTOM w0.094: v2(207.84,89.61) 208.9,89.61 208.94,89.64 209.52,89.64 209.55,89.61 209.81,89.61 210.14,89.94 212.38,89.94 212.39,89.95 212.4,89.95 ; JUSH1.19 233.28,39.3 233.13,39.15 233.13,38.89 v2(233.34,38.68)
USB20_N11: length 26
  TOP w0.094: v2(203.45,98.13) 203.63,98.31 205.08,98.31 205.92,97.47 206.54,97.47 206.57,97.5 v3(207.89,97.5) 209.61,97.5 210,97.11 210.99,97.11 213.6,94.5 217.79,94.5 218.61,93.68 219.8,93.68 220.79,94.67 220.92,94.67 v2(221.02,94.56) ; v2(137.27,124.79) 137.33,124.79 137.73,125.19 137.73,125.87 138.36,126.5 139.09,126.5 139.63,127.05 139.63,127.66 139.28,128.02 139.22,128.02 138.91,127.71 LZ1.1
  BOTTOM w0.094: v2(221.02,94.56) 221.02,94.78 221.23,94.99 UH1.R10
USB20_N11_R: length 12.5
  TOP w0.094: v2(132.39,127.84) 132.5,127.95 134.96,127.95 135.34,127.57 135.34,127.43 136.47,126.3 DA10.2 136.51,127.06 136.6,127.15 137.17,127.15 137.9,127.88 138.08,127.88 LZ1.2
  BOTTOM w0.094: JEDP1.12 130.26,129.07 131.5,127.84 v2(132.39,127.84)
USB20_N14: length 3.6
  BOTTOM w0.089: UH1.E5 218.96,90.51 218.96,90.65 v2(218.62,90.99)
  BOTTOM w0.094: v2(266.73,33.76) 266.73,33.14 266.93,32.94 267.77,32.94 267.93,32.78 LI9.1 268.63,32.58 LI50.1
USB20_N14_R: length 7
  BOTTOM w0.094: JNGFF1.5 273.7,31.96 v3(273.26,31.52) 273.07,31.33 272.21,31.33 272.18,31.3 271.43,31.3 270.9,31.82 270.9,32.24 270.36,32.78 LI9.2 269.63,32.78 269.48,32.63 LI50.2
USB20_P1: length 7.7
  TOP w0.094: v2(290.63,69.8) 290.54,69.7 290.3,69.7 290.21,69.79 290.21,70.06 290.56,70.41 291.98,70.41 292.14,70.25 UI3.3
  BOTTOM w0.089: UH1.J2 217.55,92.52 217.6,92.47 217.6,92.35 217.53,92.28 217.19,92.28 217.11,92.36 216.24,92.36 215.62,91.74 215.62,91.53 215.42,91.33 214.99,91.33 v2(214.55,90.9)
USB20_P2: length 46.7
  TOP w0.094: v2(70.42,98.12) 70.42,96.5 69.45,95.53 62.53,95.53 62.48,95.58 v3(55.75,95.58) 39.11,95.58 35.68,92.15 33.78,92.15 31.43,89.8 LI3.1
  BOTTOM w0.094: v2(223.23,93.63) 223.55,93.94 UH1.N15
USB20_P2_R: length 15.6
  TOP w0.094: JUSB2.3 16.12,90.51 16.21,90.61 17.91,90.61 18.78,89.74 v3(20.54,89.74) 22.03,89.74 22.44,89.33 22.49,89.33 22.84,88.98 24.77,88.98 25.68,89.88 26.17,89.88 26.27,89.77 DI2.2 26.72,89.02 26.95,89.26 26.95,89.74 27.12,89.91 28.17,89.91 LI3.2
USB20_P3: length 5.1
  TOP w0.094: LI4.1 297.53,59.01 297.53,59.3 297.69,59.46 v2(297.92,59.46)
  BOTTOM w0.089: v2(214.43,92.08) 214.57,92.08 214.66,92.17 214.66,92.36 214.79,92.49 215.03,92.49 215.09,92.43 215.09,92.34 215.18,92.25 215.34,92.25 215.43,92.34 215.43,92.4 215.51,92.49 215.83,92.49 216.13,92.79 216.85,92.79 217,92.93 217.8,92.93 UH1.K3
USB20_P3_R: length 15.1
  TOP w0.094: JUSB3.3 303.23,49.9 303.23,49.39 303.14,49.29 302.57,49.29 301.79,50.07 301.79,51.01 301.82,51.04 301.82,51.63 301.79,51.66 301.79,53.21 300.69,54.31 v3(300.34,54.66) 299.79,55.2 298.24,55.2 297.68,55.76 297.68,56.06 297.78,56.16 298.06,56.16 DI3.2 297.68,56.55 297.59,56.64 297.59,57.55 297.46,57.68 297.46,58.16 LI4.2
USB20_P4: length 4.4
  TOP w0.094: RZ1389.2 278.76,122.1 279.04,122.1 279.4,121.74 279.4,121.14 279.43,121.1 279.43,120.52 279.4,120.49 279.4,120.15 279.2,119.96 v2(279.2,119.07)
  BOTTOM w0.089: v2(220.16,93.5) 220.18,93.52 220.3,93.52 220.55,93.27 UH1.L9
USB20_P4_FP: length 7.9
  TOP w0.094: v2(275.27,122.18) 275.53,122.18 DZ11.3 276.96,122.18 v2(277.24,122.18) 277.36,122.06 277.71,122.06 RZ1389.1
  BOTTOM w0.094: v2(277.24,122.18) 277.36,122.06 277.71,122.06 RZ1389.1 ; JFPBTN1.4 312.9,116.85 312.74,117.01 312.46,117.01 312.02,116.57 312.02,115.58 312.44,115.16 v2(312.62,115.16)
USB20_P4_USH: length 6.8
  BOTTOM w0.094: JUSH1.22 234.78,40.72 234.59,40.92 234.59,41.1 v2(234.58,41.1) ; v2(277.05,119.12) 277.11,119.19 277.59,119.19 278.04,119.64 278.89,119.64 279.38,120.14 v3(279.38,120.75) 279.38,121.82 279.06,122.15 278.71,122.15 RZ351.2
USB20_P5: length 5.4
  TOP w0.094: v2(65.1,115.6) 64.95,115.46 64.95,115.42 64.93,115.42 64.64,115.13 64.64,114.1 64.52,113.98 63.68,113.98 63.43,113.73 63.43,113.66 RT400.1
  BOTTOM w0.089: v2(215.53,93.69) 215.64,93.79 216.78,93.79 216.79,93.78 216.83,93.78 217.15,93.46 UH1.L2
USB20_P6: length 1.9
  TOP w0.094: T301.1 220.17,92.64 219.88,92.64 v2(219.66,92.41)
  BOTTOM w0.094: UH1.K6 219.31,92.41 v2(219.66,92.41)
USB20_P8: length 21.4
  BOTTOM w0.089: 212.4,89.17 212.47,89.17 212.48,89.17 214.35,89.17 215.61,90.43 215.61,90.62 216.19,91.2 216.19,91.5 216.45,91.76 216.89,91.76 217.07,91.58 217.34,91.58 217.41,91.51 217.81,91.51 217.93,91.63 218.43,91.63 UH1.G5
  BOTTOM w0.094: v2(251.41,85.12) 251.61,85.32 251.93,85.32 252.03,85.21 252.03,84.81 253.47,83.37 253.47,81.13 253.23,80.9 253.23,79.63 253.44,79.43 253.74,79.43 254.13,79.04 254.13,76.84 254.34,76.63 254.55,76.63 254.7,76.48 LI8.1 255.34,76.35 RI47.1 ; 212.4,89.17 211.01,89.17 210.83,89.35 v2(210.71,89.35)
USB20_P8_R: length 7.9
  BOTTOM w0.094: JNGFF2.7 261.08,75.06 261.39,75.37 261.39,75.64 261.04,75.99 259.47,75.99 259.27,76.19 259.27,76.72 258.58,77.4 258.15,77.4 257.54,76.79 257.06,76.79 256.95,76.69 256.95,76.63 256.8,76.48 LI8.2 256.42,76.48 RI47.2
USB20_P10: length 12.7
  BOTTOM w0.089: UH1.H2 217.24,91.9 217.03,91.9 216.98,91.95 216.37,91.95 216,91.58 216,91.28 215.42,90.7 215.42,90.51 214.66,89.76 213.25,89.76 213.16,89.67 213.16,89.55 213.07,89.46 212.9,89.46 212.81,89.55 212.81,89.67 212.72,89.76 212.44,89.76 212.44,89.75 212.4,89.75
  BOTTOM w0.094: JUSH1.18 232.78,39.27 232.94,39.1 232.94,38.87 v2(232.75,38.68) ; v2(207.84,89.02) 208.24,89.42 v3(209.23,89.42) 209.89,89.42 210.22,89.75 212.4,89.75
USB20_P11: length 25.9
  TOP w0.094: LZ1.4 139.35,128.21 139.82,127.74 139.82,126.97 139.17,126.32 138.44,126.32 137.92,125.8 v2(137.92,124.79) ; v2(203.45,98.71) 203.67,98.5 205.16,98.5 205.97,97.69 v3(206.24,97.69) 207.57,97.69 207.6,97.72 208.19,97.72 208.22,97.69 209.68,97.69 210.08,97.29 211.07,97.29 213.67,94.69 217.86,94.69 218.69,93.86 219.72,93.86 220.78,94.92 220.83,95.03 v2(220.78,95.13)
  BOTTOM w0.094: UH1.P9 220.6,94.67 220.78,94.86 v2(220.78,95.13)
USB20_P11_R: length 12.5
  TOP w0.094: 136.51,128.2 136.51,127.45 136.62,127.34 137.09,127.34 137.82,128.07 138.12,128.07 LZ1.3 ; 136.51,128.2 136.07,127.77 136.07,127.65 135.9,127.48 135.62,127.48 135.53,127.57 135.53,127.65 135.04,128.13 132.68,128.13 v2(132.39,128.42) ; 136.51,128.2 DA10.3
  BOTTOM w0.094: JEDP1.13 130.76,130.63 130.45,130.31 130.45,129.14 131.57,128.02 131.99,128.02 v2(132.39,128.42)
USB20_P14: length 3.5
  BOTTOM w0.089: UH1.F6 219.24,90.94 219.15,90.85 219.15,90.58 v2(219.34,90.39)
  BOTTOM w0.094: v2(267.31,33.76) 267.31,33.54 267.22,33.45 267.01,33.45 266.92,33.35 266.92,33.22 267.01,33.12 267.77,33.12 267.93,33.28 LI9.4 268.63,33.48 LI49.1
USB20_P14_R: length 6.9
  BOTTOM w0.094: LI49.2 269.48,33.48 LI9.3 269.93,33.28 270.25,32.97 270.44,32.97 271.09,32.32 271.09,31.9 271.48,31.51 v3(271.89,31.51) 272.94,31.51 273.51,32.08 273.51,32.59 273.2,32.9 JNGFF1.3
USB_OC0#: length 61.5
  TOP w0.109: v2(295.14,73.22) 295.03,73.11 UI3.13 ; v2(240.78,95.8) 241.45,95.14 241.85,95.14 243.17,96.47 RH651.1
  BOTTOM w0.089: UH1.AH36 234.03,101.69 v2(234.41,102.06) ; RH644.1 241.77,94.82 v2(240.78,95.8)
  BOTTOM w0.102: v2(252.58,63.74) 252.8,63.52 252.8,62.73 254.44,61.1 260.98,61.1 262.76,62.88 262.76,63.64 264.37,65.26 264.37,67.01 265.44,68.08 269.04,68.08 269.24,68.28 269.24,70.32 269.5,70.58 270.67,70.58 271.72,69.54 274.82,69.54 275.48,68.88 278.42,68.88 279.56,70.03 arc(280.47,70.63) 281.54,70.85 282.83,70.85 285.72,73.73 v1(287.97,73.73) 294.63,73.73 v2(295.14,73.22)
USB_OC1#: length 50.6
  TOP w0.102: v2(23.49,90.82) 23.7,90.82 24.34,91.45 25.01,91.45 26.96,93.39 v1(27.49,93.39) 35.77,93.39 38.86,96.48 62.73,96.48 62.86,96.35 67.91,96.35 v2(68.32,96.75)
  TOP w0.109: RH650.1 RH641.1 244.14,100.65 v2(244.15,100.66)
  BOTTOM w0.089: UH1.AL40 235.65,103.29 235.75,103.39 v2(235.88,103.39)
  BOTTOM w0.102: UI1.3 v2(23.49,90.82)
USB_OC2#: length 6.9
  TOP w0.109: UI2.3 300.29,52.49 v2(299.52,52.49) ; v2(240.92,95.06) 241.2,95.06 241.35,94.91 241.94,94.91 242.87,95.83 RH652.1
  BOTTOM w0.089: RH642.1 241.86,94.12 v2(240.92,95.06) ; UH1.AJ44 237.87,102.7 v2(237.76,102.8)
USB_OC3#: length 6.1
  TOP w0.102: RH649.1 242.59,98.5 v1(242.12,98.5) 241.23,97.61 241.23,95.94 v2(241.62,95.55)
  BOTTOM w0.089: v2(236.41,103.64) 236.38,103.62 UH1.AL41 ; v2(241.62,95.55) 241.65,95.51 RH643.1
USB_OC4#: length 10.3
  TOP w0.109: RH645.1 238.31,111.24 236.85,109.79 236.85,109.03 236.44,108.61 236.44,108.19 236.14,107.89 236.14,107.34 236.3,107.17 236.6,107.17 237.1,107.68 v1(237.42,107.68) 237.87,107.68 238.18,107.37 238.18,107.21 238.64,106.75 239.24,106.75 239.63,106.36 v2(239.65,106.36)
  BOTTOM w0.089: UH1.AV47 239.59,106.4 239.63,106.36 v2(239.65,106.36)
USB_OC5#: length 7.9
  TOP w0.109: RH646.1 236.02,110.13 v1(235.85,109.95) 235.52,109.62 235.52,109.15 235.12,108.75 235.12,108.32 234.31,107.52 234.31,106.75 234.16,106.6 234.16,105.74 v2(233.95,105.53)
  BOTTOM w0.089: v2(233.95,105.53) 233.96,105.53 233.96,105.4 233.64,105.09 UH1.AR35
USB_OC6#: length 8.1
  TOP w0.109: v2(234.53,105.51) 234.37,105.66 234.37,106.5 234.56,106.69 234.56,107.45 235.33,108.21 235.33,108.66 235.77,109.1 235.77,109.4 236.79,110.42 v1(236.79,110.89) RH647.1
  BOTTOM w0.089: v2(234.53,105.51) 234.53,105.17 234.44,105.09 UH1.AR37
USB_OC7#: length 7.6
  TOP w0.109: v2(237.2,107.05) 237.11,106.96 235.94,106.96 235.78,107.12 v1(235.78,107.21) 235.83,107.26 235.83,107.89 236.23,108.28 236.23,108.76 236.6,109.13 236.6,109.91 237.55,110.86 RH648.1
  BOTTOM w0.089: v2(237.2,107.05) 237.2,107.05 237.2,107.05 237.07,106.91 UH1.AV43
USB_POWERSHARE_EN#: length 11.9
  TOP w0.102: RE728.1 v2(256.92,96.28)
  TOP w0.109: UE1.J3 262.51,94.16 v2(262.42,94.16) ; v2(290.88,67.05) 291,67.05 v1(291.33,67.38) 291.46,67.51 292.95,67.51 294.03,68.59 UI3.6
  BOTTOM w0.102: v2(262.42,94.16) 262.38,94.12 262.18,94.12 261.17,95.13 259.77,95.13 259.36,95.54 258.03,95.54 257.3,96.28 v2(256.92,96.28)
USB_POWERSHARE_VBUS_EN: length 16.6
  TOP w0.102: RE730.1 RE702.1 256.48,95.7 256.85,95.7 v2(256.92,95.64)
  TOP w0.109: v2(289.92,67.18) 289.92,67.35 290.47,67.89 v1(292.69,67.89) 292.84,67.89 293.53,68.58 UI3.5 ; v2(260.27,93.33) 260.29,93.33 261.05,94.09 261.64,94.09 UE1.J2
  BOTTOM w0.102: v2(260.27,93.33) 260.27,93.96 260.17,94.07 258.78,94.07 257.99,93.27 256.38,93.27 256.28,93.38 256.28,95.51 256.41,95.64 v2(256.92,95.64)
USB_PWR_EN1#: length 108.3
  TOP w0.102: v2(97.95,62.3) 97.76,62.11 97.6,62.11 97.38,62.34 97.38,62.84 94.43,65.78 94.43,74.6 88.4,80.64 88.4,92.07 83,97.47 83,101.86 81.22,103.64 v2(80.83,103.64) ; RE729.1 256.17,92.82 256.92,93.57 v2(256.92,93.68) ; v2(25.27,90.5) 25.27,91.32 27.01,93.06 v1(28.89,93.06) 28.99,93.16 35.86,93.16 38.96,96.25 62.64,96.25 62.77,96.12 68.17,96.12 68.4,96.36 v2(68.92,96.36)
  TOP w0.109: UE1.K3 262.49,93.34 262.47,93.34 v2(262.43,93.3)
  BOTTOM w0.102: QI2.2 78.08,102.8 78.46,103.18 80.37,103.18 v2(80.83,103.64) ; UI1.4 25.5,90.5 v2(25.27,90.5) ; v2(256.92,93.68) 257.04,93.8 258.19,93.8 258.69,94.29 261.24,94.29 262.21,93.33 262.37,93.33 262.41,93.3 v2(262.43,93.3)
USB_PWR_EN2#: length 12
  TOP w0.102: RE727.1 256.55,97.17 v2(256.92,97.54)
  TOP w0.109: v2(299.28,53.03) 298.77,53.03 298.23,52.48 UI2.4 ; v2(264.07,96.43) 264.17,96.53 264.36,96.53 264.47,96.42 UE1.G5
  BOTTOM w0.109: v2(264.07,96.43) 264.07,95.81 263.87,95.6 261.76,95.6 261.15,96.21 259.91,96.21 259.53,96.58 v1(258.63,96.58) 258.17,96.58 257.22,97.54 v2(256.92,97.54)
USH_DET#: length 28.2
  TOP w0.102: v2(223.77,40.59) 223.77,41.29 224.4,41.92 231.01,41.92 231.33,41.6 231.33,40.59 231.72,40.19 234.02,40.19 234.15,40.32 234.15,41.23 235.21,42.3 238.21,42.3 241.43,45.52 241.43,46.3 241.64,46.51 v2(241.64,46.51)
  TOP w0.109: UE1.C13 271.55,99.33 v2(271.63,99.24) 271.63,99.25 271.83,99.45 272.77,99.45 273.22,99.9 RE526.2
  BOTTOM w0.109: v2(223.77,40.59) 224.17,40.59 224.28,40.48 JUSH1.1
USH_EXPANDER_SMBCLK: length 23.2
  TOP w0.102: RZ8.2 CZ62.1 232.01,37.55 231.61,37.95 231.61,38.52 v2(231.6,38.52)
  TOP w0.109: UE1.B3 263.19,99.81 v2(263.26,99.81)
  BOTTOM w0.109: v2(267.89,85.37) 268.36,85.85 268.36,86.92 267.39,87.88 v1(267.39,88.66) 267.39,91.1 266.59,91.9 266.59,93.52 266.09,94.01 266.09,94.25 265.83,94.51 265.48,94.51 265.29,94.7 265.29,97.65 265.18,97.76 264.73,97.76 264.46,98.03 264.46,98.29 264.22,98.53 263.92,98.53 263.68,98.76 263.68,99.39 263.26,99.8 v2(263.26,99.81) ; v2(231.6,38.52) 231.61,38.52 231.61,38.52 231.78,38.69 JUSH1.16
USH_EXPANDER_SMBDAT: length 19.4
  TOP w0.109: RZ9.2 CZ63.1 231.19,37.62 231.01,37.81 v2(231.01,38.17) ; v2(264.07,98.08) 264.43,97.73 UE1.E5
  BOTTOM w0.109: v2(264.07,98.08) 264.46,97.7 264.46,94.63 264.58,94.51 265.03,94.51 265.26,94.29 265.26,93.84 265.39,93.71 266.1,93.71 266.38,93.43 266.38,92.23 266.33,92.23 264.5,90.4 264.5,89.65 v1(265.21,88.95) 265.49,88.66 265.49,87.3 266.12,86.66 v2(266.86,86.66) ; v2(231.01,38.17) 231.01,38.87 231.28,39.14 JUSH1.15
USH_PWR_STATE#: length 5.9
  TOP w0.109: v2(259.28,94.93) 261.68,94.93 UE1.H2 ; RZ10.2 225.86,37.66 225.96,37.75 225.96,37.84 v2(225.98,37.84)
  BOTTOM w0.109: v2(225.98,37.84) 225.96,37.84 225.96,38.41 225.93,38.44 225.93,38.89 226.28,39.24 JUSH1.5
VCI_IN1#: length 4.3
  TOP w0.109: RE507.1 v1(264.72,103.2) 264.72,102.29 264.32,101.89 264.32,101.24 264.15,101.06 264.15,100.45 UE1.B5
VCI_IN2#: length 12.6
  TOP w0.102: RE508.1 253.93,103.96 254.31,103.58 254.68,103.58 v2(254.71,103.54)
  TOP w0.109: UE1.D4 v2(263.27,98.93)
  BOTTOM w0.109: v2(263.27,98.93) 262.84,99.36 261.75,99.36 258.49,102.62 258.49,103.21 258.09,103.61 v1(255.9,103.61) 254.78,103.61 v2(254.71,103.54)
VCI_IN3#: length 13.2
  TOP w0.102: RE324.1 253.75,102.87 254.05,102.58 v2(254.72,102.58)
  TOP w0.109: UE1.E4 263.63,97.73 v2(263.27,98.09)
  BOTTOM w0.109: v2(263.27,98.09) 262.83,98.53 260.63,98.53 259.91,99.24 259.91,100.77 258.11,102.58 v1(256.98,102.58) v2(254.72,102.58)
VCT_LAN_R1: length 4.8
  TOP w0.109: RL3.1 275.86,106.02 275.86,108.72 275.76,108.82 UL1.6
VGA_IDENTIFY: length 12.1
  TOP w0.102: v2(275.39,92.57) 275.92,92.57 276.21,92.28 RE84.1 RE85.1
  TOP w0.109: v2(267.21,92.56) 267.31,92.56 UE1.L9
  BOTTOM w0.102: v2(267.21,92.56) 267.21,92.62 267.55,92.95 269.07,92.95 269.3,92.72 269.3,92.42 269.85,91.86 v1(270.44,91.86) 271.7,91.86 272.59,92.75 275.22,92.75 v2(275.39,92.57)
VID0_1VS_VCCIO: length 2.4
  BOTTOM w0.254: PU401.9 200.04,98.65 PR416.1 PR414.2
VID1_1VS_VCCIO: length 4.3
  BOTTOM w0.102: v1(200.78,101.93) 200.66,101.8 200.66,100.99 PR413.2
  BOTTOM w0.254: PR413.2 200.51,100.84 199.77,100.84 199.77,100.84 PR415.1 199.77,100.47 199.51,100.21 198.75,100.21 198.47,99.93 PU401.8
VOUT_1.2V_RUN: length 1.4
  BOTTOM w0.102: PC511.1 271.09,62.48 v1(271.52,62.05)
VOUT_2.5V_MEM:
  vias: v1(146.93,37.67)
VR_SVID_ALERT#: length 4.6
  TOP w0.102: v1(115.31,104.28) 115.43,104.16 v2(116.01,104.16) 116.08,104.09 RC152.2 RC153.1
  BOTTOM w0.109: PRZ21.2 96.7,97.97 v2(96.61,97.87) 95.37,97.87 PRZ8.2
VR_SVID_CLK: length 26.1
  TOP w0.102: CC325.1 v2(118.23,105.86) 118.69,105.86
  TOP w0.109: v2(137.78,106.26) 137.38,105.86 136.76,105.86 135.86,106.76 134.74,106.76 133.29,108.21 132.06,108.21 131.46,108.82 124.37,108.82 122.07,106.52 121.89,106.52 121.3,105.94 121.1,105.94 120.48,105.32 119.85,105.32 119.3,105.87 118.89,105.87 118.89,105.86 118.69,105.86
  BOTTOM w0.076: v2(137.78,106.26) 138.11,105.94 UC1.BH32
  BOTTOM w0.109: PRZ9.2 95.55,98.88 v2(96.64,98.88) 96.85,98.88 96.98,98.75 97.49,98.75 PRZ19.2
VR_SVID_DATA: length 27.7
  TOP w0.109: v2(138.2,103.39) 137.39,104.2 137.39,105.08 137.38,105.09 137.38,105.09 137.16,105.32 137.15,105.32 137.14,105.33 136.53,105.33 135.64,106.21 134.45,106.21 133.16,107.51 132.17,107.51 131.84,107.84 124.77,107.84 122.34,105.4 122.28,105.4 121.84,104.96 121.51,104.96 120.89,104.34 119.44,104.34 118.89,104.89 118.33,104.89 v2(118.32,104.88) 118.32,104.39 RC157.2
  BOTTOM w0.102: v2(138.2,103.39) 138.3,103.49 UC1.BH29
  BOTTOM w0.109: PRZ23.2 96.9,97.14 v2(96.63,96.87) 95.48,96.87 PRZ7.2
VRALERT#: length 13.4
  BOTTOM w0.089: UH1.BE32 231.86,109.95 231.62,110.18 231.62,113.35 232.21,113.94 232.21,117.16 233.87,118.81 233.87,118.95
  BOTTOM w0.109: RH203.1 v1(233.99,120.08) 233.99,119.08 233.87,118.95
VRHOT#_CPU: length 5.6
  BOTTOM w0.102: v1(97.15,95.07) 97.81,95.73 PRZ16.1
  BOTTOM w0.109: PUZ1.39 101.13,97.78 100.71,97.36 99.56,97.36 98.8,96.59 98.22,96.59 PRZ16.1
VRMP_CPU: length 4.1
  BOTTOM w0.203: PUZ1.15 107.06,103.11 108.16,104.2 v1(108.31,104.2) 108.52,104.2
  BOTTOM w0.254: PRZ57.2 PCZ31.1 109.14,104.2 108.52,104.2
VSET_5105: length 7.8
  TOP w0.102: RE77.1 CE38.1 273.11,100.78 v2(272.99,100.67)
  TOP w0.109: UE1.C9 v2(268.12,99.77)
  BOTTOM w0.102: v2(268.12,99.77) 268.12,99.77 268.12,99.87 268.42,100.16 269.07,100.16 269.1,100.13 v1(270.06,100.13) 271.69,100.13 272.22,100.67 v2(272.99,100.67)
VSN_1PH_CPU: length 5.5
  BOTTOM w0.203: PCZ1.2 98,106.08 v1(98.54,105.54) 99.63,104.45 99.63,103.52 100.04,103.11 PUZ1.51
  BOTTOM w0.254: PCZ1.2 PRZ12.2
VSN_2PH_CPU: length 3.2
  BOTTOM w0.203: PUZ1.37 101.93,97.55 101.48,97.11 101.48,96.2 PRZ37.2
  BOTTOM w0.254: PRZ37.2 PCZ16.2
VSN_4PH_CPU: length 3.8
  BOTTOM w0.203: 101.66,105.83 101.36,105.53 101.36,104.83 101.53,104.65 PUZ1.2
  BOTTOM w0.254: 101.66,105.83 102.18,106.35 PCZ14.2 PRZ32.2
VSP_1PH_CPU: length 6.3
  BOTTOM w0.203: PUZ1.52 100.21,103.51 100.07,103.64 100.07,105.76
  BOTTOM w0.254: 100.07,105.76 v1(99.01,106.82) 98.82,107.02 PCZ7.2 98.74,108.19 PRZ14.2
VSP_2PH_CPU: length 4.3
  BOTTOM w0.203: v1(100.33,96.91) 100.81,96.91 101.53,97.64 PUZ1.38
  BOTTOM w0.254: v1(100.33,96.91) 99.94,96.91 99.45,96.42 PCZ15.1 PRZ30.2
VSP_4PH_CPU: length 3.7
  BOTTOM w0.203: PUZ1.1 101.13,104.55 100.9,104.79 v1(100.9,105.42) 100.9,105.8
  BOTTOM w0.254: 100.9,105.8 101.19,106.09 101.19,106.61 PCZ13.1 PRZ27.2
VSYS_CHG: length 6.4
  TOP w0.102: v1(123.5,34.81) 123.2,35.11 PC745.1
  TOP w0.254: PC745.1 121.76,35.11 v2(121.15,34.51)
  BOTTOM w0.203: PU700.3 122.19,36.16 121.03,35 120.67,35 120.53,34.86 PR721.1
  BOTTOM w0.254: v2(121.15,34.51) 120.55,34.51 PR721.1
WIGIG_32KHZ: length 4.2
  TOP w0.109: RZ56.2 284.55,40.51 284.86,40.2 v1(284.86,39.57) 284.86,39.38 284.75,39.27 v2(284.26,39.27)
  BOTTOM w0.109: JNGFF1.50 284.95,39.73 284.49,39.27 v2(284.26,39.27)
WLAN_COEX1: length 8.5
  BOTTOM w0.109: v2(284.38,39.9) 284.45,39.97 JNGFF1.48 ; RZ130.2 275.64,86.22 276.36,86.93 v1(277.68,86.93) 279.59,86.93 279.9,86.62 279.9,86.5 281.07,85.33 v2(281.82,85.33)
WLAN_COEX2: length 10.1
  BOTTOM w0.109: v2(281.82,85.99) 281.74,86.07 281.74,86.08 281.33,86.49 280.37,86.49 279.59,87.27 v1(279.01,87.27) 276.36,87.27 275.62,86.53 274.99,86.53 274.88,86.43 RZ129.2 ; JNGFF1.46 283.95,39.74 v2(283.46,39.25)
WLAN_COEX3: length 10
  BOTTOM w0.102: v2(281.81,86.62) 281.61,86.83 v1(280.52,86.83) 280.36,86.83 279.59,87.6 275.29,87.6 274.54,86.86 274.54,86.59 RZ128.2
  BOTTOM w0.109: JNGFF1.44 v2(283.45,39.89)
WLAN_PWR_EN: length 13.4
  TOP w0.102: v2(272.59,84.75) 272.59,84.83 272.98,85.23 RZ70.2 ; v2(274.36,83.18) 274.5,83.32 274.5,85.1 274.75,85.34 RZ71.2 275.46,84.64 275.46,83.39 275.77,83.07 DZ9.1 ; v2(271.86,45.79) 271.97,45.68 v1(271.97,44.84) 271.97,42.91 271.86,42.81 270.87,42.81 270.72,42.96 270.72,43.34 270.57,43.5 RZ38.2
  TOP w0.109: RZ38.2 269.87,43.5 269.64,43.26 UZ4.5
WLAN_WIGIG60GHZ_DIS#: length 9.1
  TOP w0.102: v2(278.96,36.27) 278.96,36.4 v1(279.27,36.71) 279.97,37.41 283.37,37.41 DZ1.1
  TOP w0.109: RE8.1 271.8,93.14 v2(271.71,93.06) 271.58,92.93 UE1.L13
WLAN_WIGIG60GHZ_DIS#_R: length 5.1
  TOP w0.102: v1(285.67,36.95) 285.83,37.12 DZ1.2
  TOP w0.109: v2(286.95,39.26) 286.6,39.26 285.83,38.49 DZ1.2
  BOTTOM w0.109: JNGFF1.56 286.45,39.69 286.88,39.26 v2(286.95,39.26)
WWAN_ANT_CONFIG: length 12.1
  BOTTOM w0.102: v1(280.9,73.8) RZ1450.1 280.59,76.09 280.48,76.2 280.48,80.14 279.65,80.97 276.58,80.97 276.33,81.23 JNGFF2.68
WWAN_BB_RST#: length 9.4
  TOP w0.102: RZ1393.2 278.94,72.84 v1(279.09,73) v2(279.56,73.47)
  BOTTOM w0.089: UH1.BE36 234.06,109.91 233.82,110.14 233.82,110.48 233.54,110.76 233.54,111.17 233.82,111.45 233.82,113.05 233.69,113.19 233.69,114.77 233.87,114.95 233.87,116.02 233.88,116.04 v2(233.88,116.09)
WWAN_BB_RST#_PCH: length 22.2
  TOP w0.102: v2(280.04,72.65) 279.27,72.65 278.8,72.18 v1(278.02,72.18) 277.22,72.18 RC847.1
  BOTTOM w0.089: UH1.BF36 234.06,110.79 v2(233.93,110.92)
  BOTTOM w0.102: v2(288.02,85.38) 288.07,85.33 288.07,84.79 287.53,84.25 286.51,84.25 284.93,82.67 284.93,78.96 284.58,78.6 284.58,77.58 285.02,77.13 285.02,76.64 284.41,76.03 284.41,74.56 283.55,73.7 282.52,73.7 281.64,72.82 280.57,72.82 280.41,72.65 v2(280.04,72.65)
WWAN_BB_RST#_R: length 4.3
  TOP w0.102: v1(275.43,72.53) 275.62,72.34 v2(275.98,72.34) 275.98,72.58 276.25,72.84 RZ1393.1 RC847.2
  BOTTOM w0.109: v2(275.98,72.34) 275.98,72.9 276.08,73 JNGFF2.67
WWAN_COEX1: length 5
  BOTTOM w0.102: RZ130.1 275.87,85.58 v1(276.47,86.18)
  BOTTOM w0.109: JNGFF2.64 275.33,83.1 275.49,83.27 275.49,83.77 275.28,83.98 275.28,84.57 275.6,84.89 RZ373.1 RZ130.1
WWAN_COEX2: length 3.9
  BOTTOM w0.109: JNGFF2.62 274.82,83.29 274.52,83.6 274.52,84.57 274.84,84.89 RZ372.1 RZ129.1
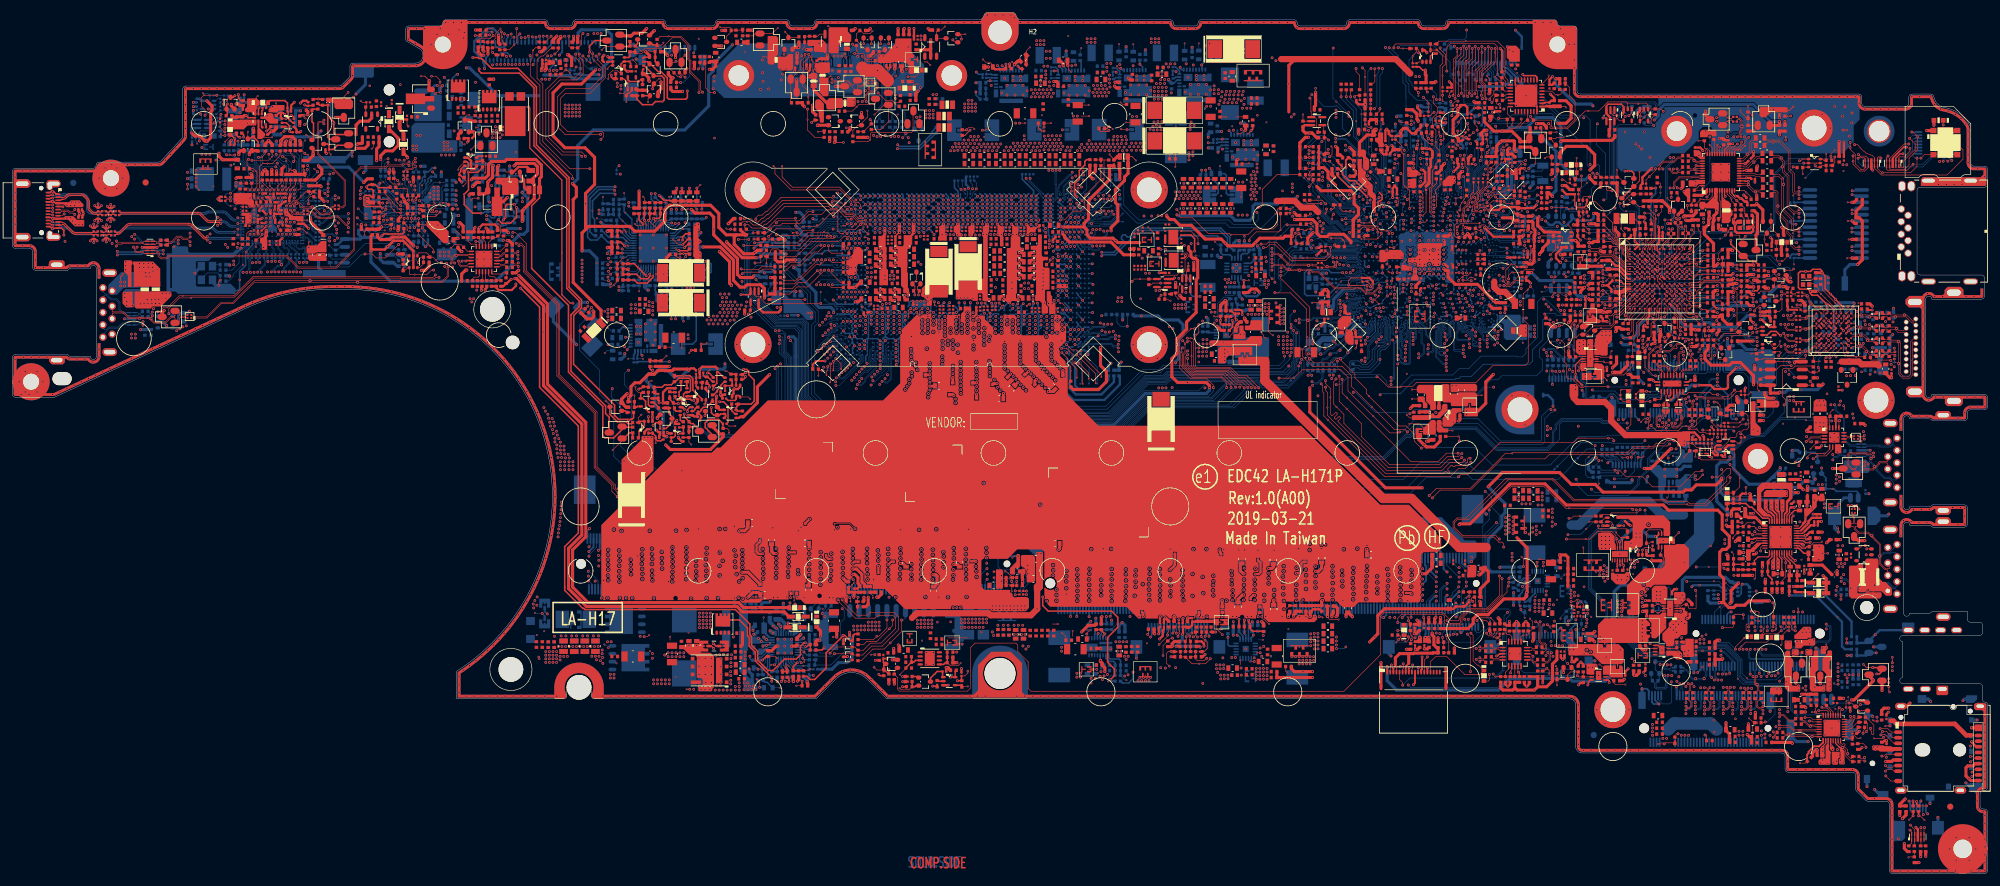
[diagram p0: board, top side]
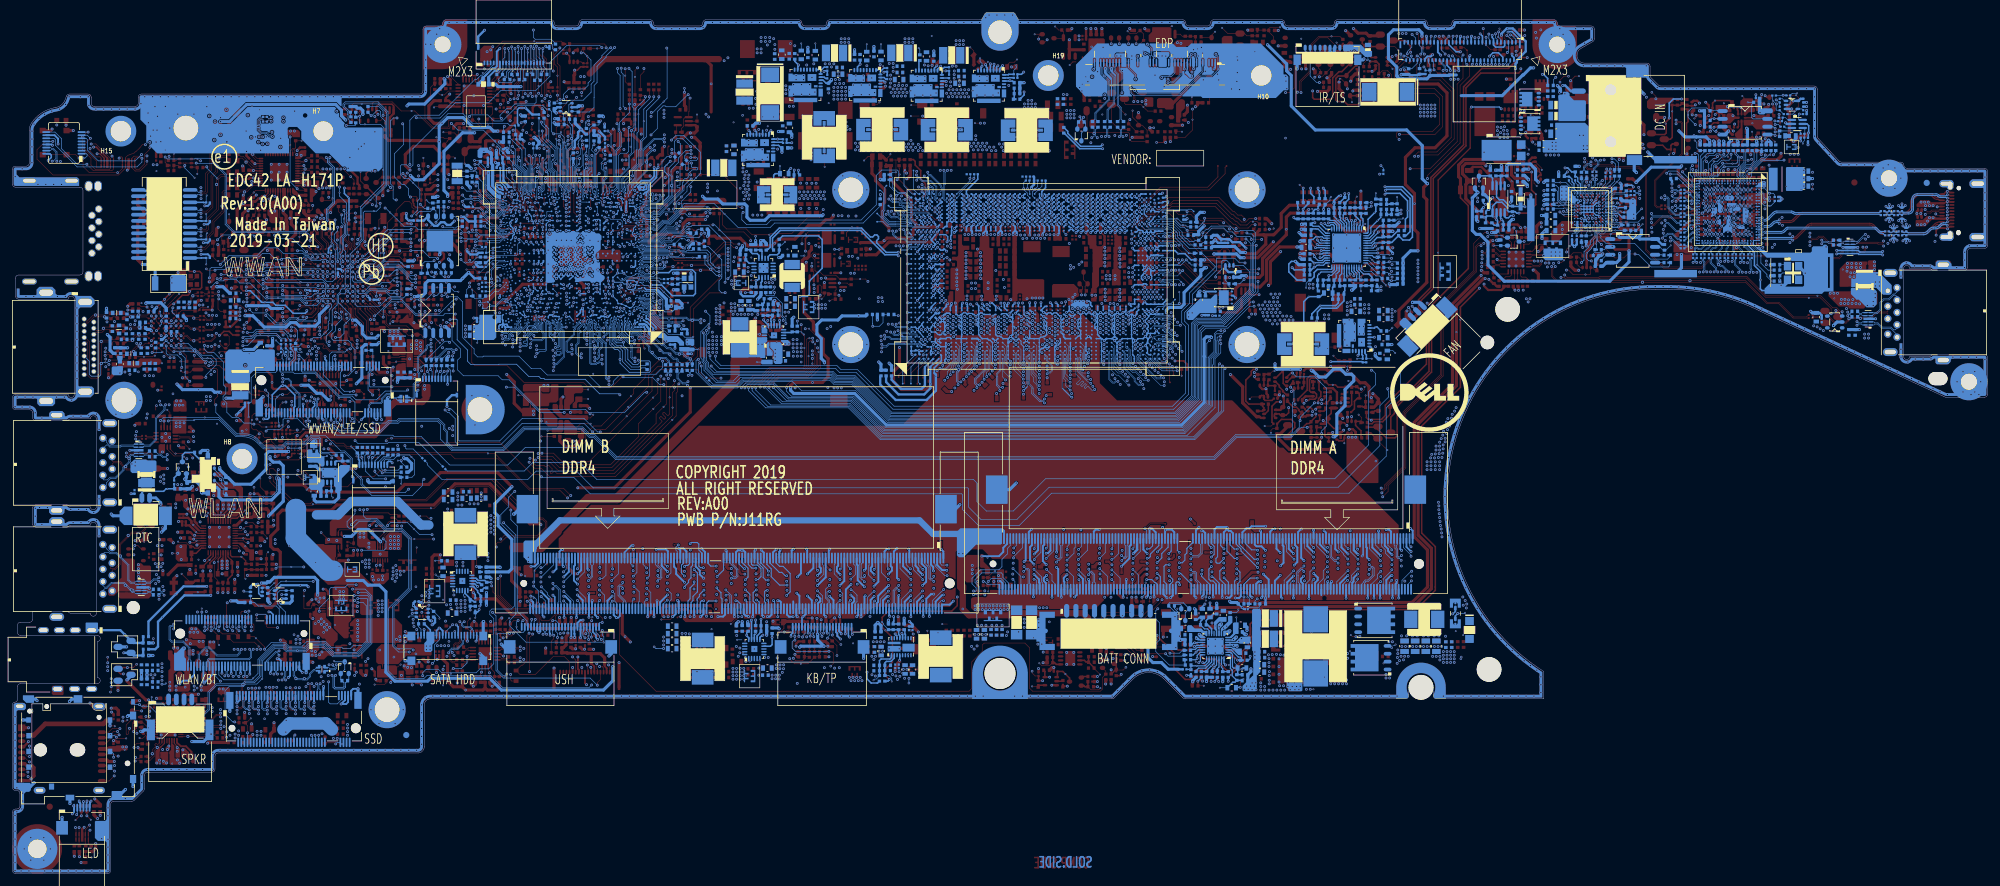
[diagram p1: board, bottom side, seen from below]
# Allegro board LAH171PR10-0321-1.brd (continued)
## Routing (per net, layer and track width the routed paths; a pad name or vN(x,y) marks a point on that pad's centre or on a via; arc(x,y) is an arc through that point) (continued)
WWAN_COEX3: length 6.2
  BOTTOM w0.102: RZ374.1 274.08,84.89 273.74,85.23 272.73,85.23 v1(272.35,85.61)
  BOTTOM w0.109: JNGFF2.60 274.33,82.62 273.59,83.35 273.59,84.29 273.76,84.45 273.76,84.57 273.87,84.68 273.91,84.68 RZ374.1 RZ128.1
WWAN_FULL_PWR_EN: length 31.3
  TOP w0.102: v2(249.57,86.23) 250.16,86.23 250.69,85.7 250.69,82.69 251.01,82.37 v1(251.01,82.12) 251.01,80.27 251.33,79.96 251.97,79.96 253.38,78.54 253.72,78.54 253.92,78.75 257.68,78.75 v2(257.74,78.69)
  BOTTOM w0.089: UH1.BF19 225.74,110.55 225.25,111.04 225.25,115.97 225.36,116.09 v2(225.45,116.09)
  BOTTOM w0.102: JNGFF2.6 260.82,81.44 261.36,80.9 261.36,78.77 261.26,78.67 257.76,78.67 v2(257.74,78.69)
  BOTTOM w0.109: JNGFF2.6 260.82,84.36 CZ198.1 RZ43.1
WWAN_GPIO_CTRL: length 14
  TOP w0.102: v2(272.08,76.73) 272.25,76.91 272.98,76.91 273.17,76.72 277.3,76.72 v1(277.84,77.26) 278.54,77.96 RZ1398.1
  TOP w0.109: UE1.K1 260.83,93.29 260.83,93.11 259.94,92.21 v2(259.77,92.21) 259.52,92.21 259.3,92.44 257.12,92.44 256.51,91.83 RE340.2
WWAN_GPIO_CTRL#: length 11.5
  TOP w0.102: RZ1397.2 278.04,74.33 278.06,74.31 278.8,74.31 278.86,74.37 QZ19.1 279.93,74.37 279.99,74.31 280.03,74.31 280.35,73.99 v1(280.35,73.31) 280.46,73.2 280.46,72.08 280.12,71.74 279.61,71.74 279.38,71.51 278.9,71.51 278.54,71.16 278.54,70.72 278.3,70.48 277.49,70.48 277.17,70.17 277.17,69.86 275.89,68.58 UZ51.6
WWAN_GPIO_CTRL_R: length 3
  TOP w0.102: QZ19.2 279.84,76.48 RZ1399.1 ; RZ1399.1 280.37,77.38 v1(280.79,77.8) ; RZ1399.1 RZ1398.2
WWAN_GPIO_PERST#: length 10.6
  TOP w0.102: v2(272.61,68.77) 272.47,68.91 271.99,68.91 RZ1405.2 RZ1485.2 270.7,69.1 270.94,68.86 RZ1402.2 270.94,68.26 270,67.32 v1(270,67.26) ; v2(223.65,108.06) 223.83,108.24 223.83,109.03 RC756.1 ; RZ1480.2 274.51,68.84 v2(274.51,68.83)
  BOTTOM w0.089: UH1.BC17 224.3,109 223.9,108.6 223.9,108.3 v2(223.65,108.06)
  BOTTOM w0.102: v2(272.61,68.77) 274.37,68.77 274.43,68.83 v2(274.51,68.83)
WWAN_GPIO_PERST#_R: length 2
  TOP w0.102: UZ52.A2 272.93,68.4 272.87,68.34 RZ1402.1 v1(271.85,67.4)
WWAN_GPIO_WAKE#: length 10.7
  TOP w0.102: RZ1394.2 279.81,70.62 279.36,71.08 v2(279.18,71.08) ; RZ1396.2 275.46,70.72 275.43,70.69 v2(275.43,70.52)
  BOTTOM w0.089: UH1.BD17 224.45,109.59 224.64,109.78 224.64,110.63 224.83,110.82 224.83,111.09 224.87,111.13 224.87,116.21 v1(224.73,116.34) 224.28,116.8 224.28,117.28 ; 224.73,117.28 224.83,117.18 v2(224.83,116.91)
  BOTTOM w0.102: 224.73,117.28 224.67,117.35 RC840.2 224.28,117.28
WWAN_GPIO_WAKE#_R: length 2.3
  TOP w0.102: RZ1394.1 279.23,69.8 v1(279,69.57) 278.65,69.57 278.34,69.88 UZ51.3
WWAN_PERST#: length 8.2
  TOP w0.102: RZ1401.2 RZ1480.1 274.82,70.47 RZ1406.1 RZ1481.1 273.67,71.09 273.49,71.27 272.59,71.27 v1(272.03,71.83) 270.92,71.83 v2(270.83,71.92)
  BOTTOM w0.109: v2(272.77,83.74) 272.7,83.74 271.82,82.86 JNGFF2.50
WWAN_PERST#_R: length 1.2
  TOP w0.102: UZ52.C2 273.93,68.7 273.99,68.76 273.99,69.08 273.87,69.2 RZ1401.1
WWAN_PEWAKE#: length 5
  TOP w0.102: RZ1400.1 RZ1395.2 RZ1396.1 275.46,71.95 274.51,72.9 v2(274.51,73.12) ; v2(272.77,83.15) 272.77,82.84 v1(273.06,82.55)
  BOTTOM w0.109: JNGFF2.54 272.82,83.09 v2(272.77,83.15)
WWAN_PEWAKE#_R: length 1.5
  TOP w0.102: RZ1395.1 276.09,70.05 275.92,69.88 UZ51.4
WWAN_RADIO_DIS#: length 15.9
  TOP w0.102: RZ86.2 260.17,76.32 DZ5.1 ; RE10.1 278.79,97.55 v2(278.57,97.77)
  TOP w0.109: DZ5.1 261.42,75.93 v1(261.42,74.62) 261.42,72.59 260.85,72.02 v2(260.85,71.99) ; UE1.F12 v2(270.47,97.33)
  BOTTOM w0.102: v2(270.47,97.33) 270.67,97.52 274.35,97.52 274.76,97.93 278.32,97.93 278.47,97.77 v2(278.57,97.77)
WWAN_RADIO_DIS#_R: length 8
  TOP w0.102: v2(260.85,77.36) 260.85,77.48 261.04,77.67 DZ5.2 260.83,78.22 v1(259.88,78.22) 259.75,78.09 RZ86.1
  BOTTOM w0.109: v2(260.85,77.36) 260.85,77.41 261.6,78.16 261.6,80.99 261.33,81.26 JNGFF2.8
WWAN_WAKE#: length 5.6
  TOP w0.102: v2(274.87,76.22) 275.32,76.22 v1(275.39,76.15) 275.84,75.7 QZ8.1 276.17,74.04 RZ133.2
  TOP w0.109: UE1.M13 271.17,91.83 v2(272.62,91.83)
WWAN_WAKE#_D: length 13.5
  TOP w0.102: RZ1483.2 273.62,74.04 QZ8.3
  TOP w0.109: v2(264.68,72.44) 265.51,71.61 269.08,71.61 269.8,72.33 v1(270.31,72.33) 271,72.33 271.14,72.19 271.67,72.19 272.03,72.55 272.03,73.34 RZ1483.2
  BOTTOM w0.109: v2(264.68,72.44) 265.08,72.84 JNGFF2.23
XCLK_RBIAS: length 6.4
  BOTTOM w0.109: RH435.2 212.67,92.86 v1(213.86,94.05) 214.56,94.75 215.99,94.75 216,94.75 216.06,94.75 216.33,95.02 216.99,95.02 217.51,95.54 UH1.T3
XDP_DBRESET#: length 9.5
  TOP w0.102: RH66.1 210.99,120.42 210.68,120.74 210.68,121.94 210.36,122.26 UC3.1 209.79,123.17 209.74,123.22 209.74,125.19 v2(209.58,125.35)
  BOTTOM w0.102: JXDP1.48 90.31,131.02 90.08,130.78 RC137.1 90.13,129.82 CC32.1 90.8,130.12 v2(91.05,130.38)
XDP_OBS0: length 11.9
  TOP w0.102: v2(131.18,101.51) 130.14,100.47 129.54,100.47 127.43,98.36 125.84,98.36 124.9,97.42 124.28,97.42 RC239.1
  BOTTOM w0.076: v2(131.18,101.51) 131.67,102 132.67,102 132.73,101.94 133.54,101.94 UC1.BR27
XDP_OBS0_R: length 6.6
  TOP w0.102: v2(117.88,96.95) 118.13,97.2 120.71,97.2 121.22,97.71 122.69,97.71 RC239.2
  BOTTOM w0.102: v2(82.2,135.12) 82.2,135.1 82.21,135.09 JXDP1.21
XDP_OBS1: length 10.9
  TOP w0.102: RC240.1 124.96,98.12 125.61,98.76 127.17,98.76 129.12,100.72
  TOP w0.109: v2(130.6,101.58) 130.5,101.47 129.87,101.47 129.12,100.72
  BOTTOM w0.076: v2(130.6,101.58) 131.29,102.27 UC1.BT27
XDP_OBS1_R: length 6.5
  TOP w0.102: v2(117.72,97.74) 117.8,97.74 117.92,97.61 120.54,97.61 121.05,98.12 RC240.2
  BOTTOM w0.102: JXDP1.23 v2(82.81,135.12)
XDP_PRSNT_PIN1: length 4.2
  TOP w0.102: RC122.1 76.77,136.59 v1(77.52,136.59) ; v2(77.07,135.56) 76.52,135.56 76.48,135.52 RC121.1
  TOP w0.107: RC121.1 76.46,136.28 RC122.1
  BOTTOM w0.107: v2(77.07,135.56) 76.92,135.56 76.21,134.85 JXDP1.1
XTAL24_IN: length 4.2
  BOTTOM w0.109: YH2.3 210.14,95.51 211.34,95.51 CH13.1 211.6,95.25 RH153.1 212.99,95.25 RH436.2
XTAL24_IN_R1: length 8.4
  BOTTOM w0.089: 216.07,95.9 216.37,96.19 216.89,96.19 217.08,96 217.91,96 218.08,96.17 218.67,96.17 218.74,96.1 219.96,96.1 220.24,95.81 220.72,95.81 UH1.U10
  BOTTOM w0.109: RH436.1 214.37,95.45 v1(214.63,95.71) 214.82,95.9 216.07,95.9
XTAL24_OUT: length 2.7
  BOTTOM w0.109: YH2.1 210.62,96.14 CH14.1 211.6,96.16 RH153.2 213.11,96.16 RH152.2
XTAL24_OUT_R1: length 7.2
  BOTTOM w0.089: 216.13,96.26 216.26,96.38 217.04,96.38 217.15,96.49 217.64,96.49 217.65,96.5 218.02,96.5 218.13,96.39 218.72,96.39 218.82,96.29 220.04,96.29 220.31,96.01 220.45,96.01 220.55,96.12 UH1.U9
  BOTTOM w0.102: RH152.1 214.37,96.09 214.55,96.26
  BOTTOM w0.109: 214.55,96.26 216.13,96.26
XTAL_25_IN: length 6.9
  BOTTOM w0.076: 36.62,100.22 37.23,100.83 37.25,100.83 38.04,101.62 38.04,102.08 UT1.D22
  BOTTOM w0.102: RT394.1 35.47,97.54 36.62,98.69 v1(36.62,99.9) 36.62,100.22
XTAL_25_IN_R: length 2.2
  BOTTOM w0.102: YT1.1 32.57,98.43 CT21.1 RT394.2
XTAL_25_OUT: length 7.9
  BOTTOM w0.076: UT1.D23 38.29,101.55 37.22,100.48
  BOTTOM w0.107: 37.22,100.48 37.23,100.47 37.23,98.43 v1(37.21,98.42) 35.65,96.85 35.65,96.52 34.89,95.76 RT40.1
XTAL_25_OUT_R: length 4.6
  BOTTOM w0.102: CT20.1 RT40.2
  BOTTOM w0.107: CT20.1 33.14,97.08 31.49,97.08 30.52,96.12 YT1.3
XTALI: length 6.4
  TOP w0.109: YL1.1 280.38,106.09 CL14.1 280.03,106.44 280.03,106.45 279.83,106.65 279.83,107.54 279.47,107.9 279.45,107.9 279.28,108.07 279.21,108.07 RL11.2 v2(278.55,108.77) 278.34,108.98 278.3,108.98 277.36,109.92 UL1.10
XTALO: length 3.7
  TOP w0.109: RL34.2 RL11.1 277.66,108.75 v1(277.66,109.09) 277.66,109.14 276.96,109.84 UL1.9
XTALO_R: length 3.4
  TOP w0.109: RL34.1 CL13.1 279.41,106.19 279.41,106.18 279.71,105.89 279.71,105 279.08,104.37 YL1.3
Z2805: length 3.1
  TOP w0.102: v2(297.16,99.5) 296.4,99.5 v1(296.35,99.45)
  TOP w0.508: v2(297.16,99.5) 297.2,99.47 RL18.1
  BOTTOM w0.508: TL1.24 v2(297.16,99.5)
Z2806: length 3.1
  TOP w0.102: v2(297.16,105.5) v1(296.46,105.5)
  TOP w0.508: RL16.1 297.57,105.09 v2(297.16,105.5)
  BOTTOM w0.508: TL1.18 v2(297.16,105.5)
Z2807: length 2.9
  TOP w0.102: v2(297.14,102.5) v1(296.6,102.5)
  TOP w0.508: v2(297.14,102.5) 297.15,102.51 RL17.1
  BOTTOM w0.508: TL1.21 v2(297.14,102.5)
Z2808: length 3.2
  TOP w0.102: v2(297.13,108.5) v1(296.44,108.5)
  TOP w0.508: RL15.1 297.46,108.5 v2(297.13,108.5)
  BOTTOM w0.508: TL1.15 v2(297.13,108.5)
N13800829: length 2
  TOP w0.102: v1(139,44.59) 139,44.9 138.55,45.35 CD31.2
  TOP w0.508: CD31.2 RD18.1
N13829184: length 2.1
  TOP w0.102: RD31.1 205.78,42.76 v1(205.38,42.76)
  TOP w0.254: RD31.1 CD62.2
N14169789: length 3.3
  BOTTOM w0.102: RN2.2 250.06,41.44 v1(250.06,41.22)
  BOTTOM w0.109: RN2.2 251.01,42.39 251.41,42.79 QN1.6 QN1.5
N16624469: length 3
  TOP w0.102: CT90.1 56.51,124.66 v1(56.26,124.91)
  TOP w0.107: CT90.1 57.17,124.03 57.07,123.92 RT111.2 57.07,123.44 57.08,123.42 UT7.3
N16783095: length 1
  BOTTOM w0.254: PC113.2 242.86,46.17 PR108.1
N16783134: length 3.1
  TOP w0.102: PR117.1 v1(198.99,38.82)
  TOP w0.254: PR117.1 198.99,40.7 199,40.71 v2(199,41)
  BOTTOM w0.254: PC127.2 v2(199,41)
N16783222: length 0.8
  BOTTOM w0.102: 201.23,37.79 v1(201.99,37.79)
N17114118: length 2.9
  TOP w0.102: v1(124.79,136.07) 125.35,135.5 QV2.1 126.91,135.13 RV5.2
N17115081: length 5
  TOP w0.102: LV1.1 136.33,133 v1(136.4,132.93)
  TOP w0.107: v2(135.72,134.06) 135.95,133.82 LV1.1
  BOTTOM w0.107: JEDP1.21 134.76,131.99 135.06,132.28 135.06,133.4 v2(135.72,134.06)
N17138495: length 2.2
  TOP w0.109: RZ360.1 266.14,76.61 v1(266.34,76.8) UZ29.2
N17142422: length 3.2
  TOP w0.102: v1(294.03,74.95) 293.61,74.53 RI14.2
  TOP w0.109: UI3.16 293.53,72.67 293.46,72.73 293.46,73.78 RI14.2
N17151556: length 1.9
  TOP w0.102: v1(306.26,2.61) 306.35,2.7 RZ334.1 CZ38.2
N17370862: length 0.4
  TOP w0.102: 75.31,120.6 v1(74.86,120.6)
  vias: v2(75.37,119.52)
N17370885: length 1.8
  TOP w0.102: PQ5.2 74.7,117.65 v1(74.07,117.03)
N17370921: length 1
  TOP w0.254: PQ1.6 75.23,115.96 PR15.2
N17370927: length 3.1
  TOP w0.102: v1(73.82,122.62) 73.44,122.62 73.07,122.25 PQ7.1
  TOP w0.508: PQ7.1 73.92,121.79 74.1,121.61 74.73,121.61 PR16.2
N17370961: length 8.4
  TOP w0.254: PQ2.1 51.24,118.69 50.95,118.98 v1(50.95,123.2) 50.95,124.2 50.95,124.2 ; PR6.1 49.61,124.2 PR3.1 50.95,124.2 ; 50.95,124.2 PL3.1
N17370983: length 11.6
  TOP w0.254: PR3.2 50.01,125.2 v2(49.44,125.2) 48.66,125.2 PR5.1 ; v2(51.43,122.12) 51.43,122.01 52,121.44 v1(52,121.23) 51.91,121.14 51.91,119.71 52.17,119.45 54.11,119.45 PQ2.3
  BOTTOM w0.254: v2(49.44,125.2) 49.44,125.2 50.77,125.2 51.43,124.53 v2(51.43,122.12)
N17370995: length 7.3
  TOP w0.102: PQ3.2 47.57,119.39 v1(47.43,119.39)
  TOP w0.254: PR6.2 48.57,123.57 PR8.1 48.4,121.54 48.64,121.3 48.64,118.83 PQ3.2
N17370999: length 6
  TOP w0.102: PR7.2 51.15,116.49 v1(51.43,116.22)
  TOP w0.254: PQ2.2 52.5,117.73 51.81,117.04 PR7.2 51.15,117.7 50.92,117.93 PQ3.1
N17371029: length 6.4
  TOP w0.254: PQ11.1 94.1,134.64 v1(93.97,134.51) 93.23,133.77 93.23,132.78 v2(93.21,132.76)
  BOTTOM w0.254: v2(71.92,129.18) 71.72,129.18 71.06,128.53 PR18.1
N17371043: length 3.7
  TOP w0.102: PQ6.1 103.63,127.68 104.42,128.47 v1(104.64,128.47)
  TOP w0.254: PQ6.1 103.42,127.43 v2(103.42,126.84)
  BOTTOM w0.102: v2(69.76,128.7) 70.15,128.31 PR18.2
N17371125: length 2.7
  TOP w0.102: PR20.1 72.04,118.7 72.88,117.87 v1(73.06,117.87)
  TOP w0.508: PQ7.2 72.04,119.51 PR20.1
N17371182: length 2.4
  TOP w0.102: PQ6.2 102.98,125.53 102.67,125.23 v1(102.67,124.69)
  TOP w0.254: PR22.2 102.97,125.74 PQ6.2
N17372063: length 4.6
  TOP w0.102: PR19.2 72.96,112.34 73.27,112.02 73.27,111.58 v1(72.83,111.14)
  TOP w0.254: PR19.2 72.74,112.52 72.37,112.89 PR17.2 72.19,113.22 72.42,113.45 72.42,113.84 73.01,114.42 PQ1.3
N17372074: length 3.2
  TOP w0.102: PR25.1 76.14,115.15 76.44,114.86 76.44,113.4 v1(76.31,113.27)
  TOP w0.254: PR25.1 75.41,115.15 75.34,115.09 75,115.09 PQ1.5
N17372283: length 4.1
  TOP w0.102: v1(72.02,113.75) 72.02,114 PQ1.2
  TOP w0.254: PR19.1 73.66,114.13 73.66,114.82 73.4,115.07 PQ1.2
N17538214: length 5.6
  TOP w0.102: PQ11.2 95.75,133.68 v1(95.18,133.11)
  TOP w0.254: PQ11.2 99.68,133.68 PR32.1 PR31.2
N17539406: length 2.7
  TOP w0.102: PQ10.6 96.56,130.61 96.12,130.17 v1(96.12,130.06)
  TOP w0.254: PR33.2 96.9,131.2 PQ10.5 PQ10.6
N18394878: length 7.4
  TOP w0.102: RE58.1 RE57.1
  TOP w0.109: UE1.B1 260.66,100.74 260.66,101.14 259.25,102.55 258.9,102.55 258.71,102.74 258.71,103.2 v1(257.97,103.93) RE57.1
N18394936: length 5.7
  TOP w0.102: v1(257.41,95.82) 257.86,96.26 258.74,96.26 258.99,96.51 RE318.1
  TOP w0.109: UE1.G2 261.69,95.75 260.69,95.75 259.7,96.74 RE318.1
N18783667: length 4.6
  BOTTOM w0.076: 67.38,110.97 67.38,110.87 67.25,110.75 67.25,110.56 66.71,110.01 UT5.L11
  BOTTOM w0.107: RT103.1 69.84,111.71 v1(69.02,111.71) 68.13,111.71 67.38,110.97
N18783677: length 3.1
  BOTTOM w0.076: 66.16,110.41 65.96,110.2 65.96,109.63 UT5.K9
  BOTTOM w0.107: 66.16,110.41 v1(66.16,111.25) 66.62,111.71 RT104.1
N18783744: length 5.8
  BOTTOM w0.076: UT5.F10 66.46,107.63 67.19,107.63 67.52,107.96 68.45,107.96
  BOTTOM w0.102: 68.45,107.96 v1(69.27,107.96) 69.94,107.96 RT99.1 70.15,108.81 70.15,108.81 RT98.2 70.15,109.61 70.15,109.61 RT97.2
N18783748: length 1.4
  TOP w0.107: v2(63.86,105.91) 63.86,106.63 RT101.1
  BOTTOM w0.076: v2(63.86,105.91) 63.86,106.04 UT5.D6
N18785154: length 1.9
  TOP w0.102: v2(64.57,108.86) 64.57,108.85 v1(64.96,108.47)
  TOP w0.107: v2(64.57,108.86) 64.57,109.48 CT87.1
  BOTTOM w0.076: v2(64.57,108.86) 64.57,108.51 UT5.H7
N18785244: length 1.9
  TOP w0.107: v2(62.72,107.97) 62.66,107.97 62.1,108.52 RT85.1
  BOTTOM w0.102: v2(62.72,107.97) 62.8,107.88 UT5.G4
N18785246: length 4.5
  TOP w0.107: v2(62.72,107.38) 62.45,107.38 61.41,108.42 61.41,108.6 v1(60.76,109.24) 60.22,109.79 RT84.1
  BOTTOM w0.076: UT5.F4 v2(62.72,107.38)
N18785591: length 3.3
  BOTTOM w0.076: 67.13,110.97 67.13,110.94 67.03,110.84 67.03,110.57 66.46,110 66.46,109.63 UT5.K10
  BOTTOM w0.107: 67.13,110.97 67.13,111.32 67.63,111.83 RT105.1
N18964580: length 3.4
  TOP w0.102: v1(258.31,84.47) 258.2,84.35 CZ109.1
  TOP w0.109: CZ109.1 256.54,83.46 256.41,83.6 UZ2.12
N18964619: length 1.8
  TOP w0.203: CZ113.1 260.26,49.16 v2(260.26,49.81) 260.26,49.93 260.05,50.14 UZ3.12
N18964665: length 4
  TOP w0.102: 259.99,54.33 259.75,54.33 259.04,55.04 v1(259.04,55.17)
  TOP w0.203: UZ3.3 260.05,53.97 259.99,54.03 259.99,54.33 RZ64.2
N18964738: length 1.7
  TOP w0.102: UZ8.6 264.24,36.39 CZ121.1
N18965068: length 2.4
  TOP w0.109: UZ2.10 257,82.8 v1(257.04,82.75) 257.22,82.57 CZ110.1
N18965149: length 2.1
  TOP w0.109: CZ117.1 265.38,42.42 265.64,42.16 v1(265.81,42.16) 265.98,42.16 266.28,42.46 UZ4.12
N18965206: length 1.6
  TOP w0.203: CZ114.1 259.23,49.64 259.2,49.67 259.2,50.05 259.25,50.09 UZ3.10
N18965394: length 2.1
  TOP w0.109: CZ118.1 265.37,43.33 265.62,43.57 v1(265.81,43.57) 266,43.57 266.31,43.26 UZ4.10
N19180571: length 3.3
  BOTTOM w0.076: 60.79,106.97 61.2,107.38 UT5.F1
  BOTTOM w0.112: RT63.1 59.07,106.87 59.29,107.1 60.04,107.1 60.16,106.97 60.79,106.97
N21789330: length 4
  TOP w0.102: v1(70.86,101.1) 71.45,101.69 72.43,101.69 RI77.2
  TOP w0.109: UI6.7 73.55,100.58 RI77.2
N21789359: length 2
  TOP w0.109: UI6.24 78.81,100.58 RI75.2
N22349729: length 4.1
  BOTTOM w0.102: 273.29,84.65 272.92,84.27 v1(272.35,84.27)
  BOTTOM w0.109: RZ132.2 273.29,83.2 273.82,82.67 JNGFF2.58
N23124850: length 3.3
  TOP w0.102: CE57.1 281.85,96.39 280.77,96.39 RE350.2 280.62,95.81 281.05,95.39 v1(281.11,95.39)
N23602829: length 3.1
  TOP w0.102: RE94.1 269.04,109.88 QE12.1 268.86,108.79 267.65,108.79 267.33,109.1 v1(267.33,109.17)
N23766683: length 4.1
  BOTTOM w0.102: 174.54,106.88 UC1.A33
  BOTTOM w0.109: 174.54,106.88 175.32,107.66 176.76,107.66 176.78,107.69 177.27,107.69 T194.1
N23770309: length 3.9
  BOTTOM w0.102: T199.1 131.89,92.15 132.69,92.15 133.2,91.64 134.13,91.64 UC1.BP13
N23795295: length 2.3
  TOP w0.076: v2(170.3,91.1) 170.3,91.45 169.81,91.94
  TOP w0.102: 169.81,91.94 169.54,92.21 T42.1
  BOTTOM w0.102: UC1.G13 169.95,91.45 v2(170.3,91.1)
N23795364: length 10.8
  BOTTOM w0.076: UC1.B30 173.25,104.86 173.83,105.43 174.46,105.43 174.76,105.13 176.34,105.13
  BOTTOM w0.109: 176.34,105.13 177.47,105.13 178.6,106.26 178.6,107.09 178.36,107.33 178.36,109.99 178.81,110.44 T18.1
N23795366: length 11.6
  BOTTOM w0.076: UC1.C30 172.81,104.86 173.09,105.14 173.3,105.14 173.76,105.6 174.53,105.6 174.75,105.37 176.34,105.37
  BOTTOM w0.109: 176.34,105.37 177.38,105.37 178.32,106.31 178.32,106.99 178.13,107.19 178.13,110.93 T19.1
N23795368: length 9.2
  TOP w0.109: T21.1 175.89,80.61 171.84,84.66 171.12,84.66 v2(170.26,85.51)
  BOTTOM w0.076: UC1.G3 170.03,84.52 170.26,84.75 170.26,85.51 v2(170.26,85.51)
N23795370: length 6.8
  TOP w0.109: T20.1 171.95,81.52 171.17,82.31 171.17,84.02 170.3,84.89 v2(169.49,84.89)
  BOTTOM w0.076: UC1.J3 169.11,84.52 v2(169.49,84.89)
N23795372: length 2
  TOP w0.102: v2(134.86,105.04) 134.54,104.72 T24.1
  BOTTOM w0.076: v2(134.86,105.04) 134.39,105.04 134.01,105.42 UC1.BR31
N23795374: length 1.3
  TOP w0.109: v2(137.79,105.02) 138.11,104.7 T22.1
  BOTTOM w0.076: UC1.BH30 138.18,104.63 v2(137.79,105.02)
N23795376: length 5.9
  BOTTOM w0.076: UC1.BR35 133.51,107.39 129.14,107.39
  BOTTOM w0.102: T23.1 128.59,107.39 129.14,107.39
N23795378: length 4.6
  BOTTOM w0.076: UC1.D1 172.08,83.22 172.52,82.77 172.56,82.77 172.66,82.66
  BOTTOM w0.109: 172.66,82.66 172.66,79.36 T1.1
N23795380: length 4.8
  TOP w0.109: v2(171.62,82.56) 172.88,81.3 T2.1
  BOTTOM w0.076: UC1.E1 171.62,82.67 v2(171.62,82.56)
N23795385: length 5
  TOP w0.109: T4.1 173.86,80.92 v2(172.26,82.51)
  BOTTOM w0.076: v2(172.26,82.51) 172.26,82.51 172.27,82.51 172.27,82.51 171.88,82.9 171.73,82.9 171.54,83.08 171.54,83.24 171.38,83.4 UC1.E2
N23795387: length 2.8
  TOP w0.109: T5.1 132.58,81.69 132.62,81.72 v2(132.62,82.8)
  BOTTOM w0.076: UC1.BR1 133.38,82.8 v2(132.62,82.8)
N23795389: length 2.7
  TOP w0.109: T6.1 133.85,82.39 v2(132.99,83.25)
  BOTTOM w0.076: v2(132.99,83.25) 132.99,83.25 133.22,83.49 UC1.BT2
N23795391: length 16.6
  TOP w0.109: T7.1 123.17,114.14 123.17,113.12 125.79,110.5 133.69,110.5 135.5,108.68 v2(135.5,108.13)
  BOTTOM w0.076: UC1.BN35 135.5,108.11 v2(135.5,108.13)
N23795393: length 17.4
  TOP w0.109: T8.1 124.33,112.6 125.98,110.94 133.63,110.94 136.09,108.49 136.64,108.49 136.99,108.14 v2(136.99,107.61)
  BOTTOM w0.076: UC1.BL34 136.97,107.61 v2(136.99,107.61)
N23795395: length 1.1
  TOP w0.102: v2(135.5,105.78) 135.48,105.76 T11.1
  BOTTOM w0.076: v2(135.5,105.78) 135.5,105.88 UC1.BN33
N23795397: length 1.1
  TOP w0.102: T9.1 168.87,99.81 v2(168.94,99.74)
  BOTTOM w0.102: v2(168.94,99.74) 168.94,99.8 UC1.J24
N23795399: length 1.3
  TOP w0.102: T10.1 170.12,100.29 v2(169.63,99.79)
  BOTTOM w0.102: v2(169.63,99.79) 169.59,99.79 169.25,100.13 UC1.H24
N23795401: length 1.4
  TOP w0.102: v2(159.38,92.21) 159.74,91.86 T12.1
  BOTTOM w0.076: UC1.AA14 159.3,92.14 v2(159.38,92.21)
N23795403: length 1.7
  TOP w0.109: v2(156.69,104.99) 156.69,104.99 T15.1
  BOTTOM w0.076: UC1.AE29 156.69,104.34 v2(156.69,104.99)
N23795405: length 2.1
  TOP w0.109: v2(165.36,104.96) 165.9,105.5 165.9,105.68 T14.1
  BOTTOM w0.076: UC1.N29 165.36,104.31 v2(165.36,104.96)
N23795407: length 1.2
  TOP w0.109: v2(164.31,92.03) 164.09,92.03 T13.1
  BOTTOM w0.102: UC1.R14 164.23,92.03 v2(164.31,92.03)
N23795412: length 1.3
  TOP w0.109: v2(148.87,103.29) 148.87,103.38 T28.1
  BOTTOM w0.102: v2(148.87,103.29) 149.2,103.62 UC1.AP29
N23795414: length 1.4
  TOP w0.102: T27.1 148.93,91.93 v2(148.93,92.42)
  BOTTOM w0.076: UC1.AP14 148.93,92 v2(148.93,92.42)
N23795416: length 1.1
  TOP w0.102: v2(136.9,103.54) 136.88,103.57 T29.1
  BOTTOM w0.102: UC1.BK28 137.13,103.32 v2(136.9,103.54)
N23795418: length 1.5
  TOP w0.109: v2(138.28,102.54) 137.99,102.84 T30.1
  BOTTOM w0.076: UC1.BJ28 v2(138.28,102.54)
N23795436: length 3.6
  TOP w0.109: T41.1 152.95,90.21 152.95,87.88 v2(152.51,87.45)
  BOTTOM w0.076: UC1.AJ8 152.84,87.78 v2(152.51,87.45)
N23795438: length 1.3
  TOP w0.102: v2(136.18,105) 136.1,105 T44.1
  BOTTOM w0.102: UC1.BL31 136.31,105 v2(136.18,105)
N23795440: length 5.5
  BOTTOM w0.109: T43.1 175.23,81.84 UC1.B2
N23795442: length 4.9
  BOTTOM w0.109: UC1.B38 173.71,109.84 175.03,111.16 175.03,113.56 T45.1
N23795444: length 4.9
  TOP w0.109: v2(131.71,81.98) 131.71,81.34 131.5,81.14 T46.1
  BOTTOM w0.076: UC1.BP1 134.51,83.1 133.39,81.98 131.71,81.98 131.71,81.98 v2(131.71,81.98)
N23795446: length 6.3
  TOP w0.109: T47.1 132.16,79.49 v2(132.16,82.38)
  BOTTOM w0.076: v2(132.16,82.38) 133.52,82.38 134.16,83.02 134.16,83.69 133.95,83.9 UC1.BR2
N23795448: length 4.6
  BOTTOM w0.109: T48.1 173.91,81.89 UC1.C1
N23795450: length 4.3
  BOTTOM w0.109: T49.1 173.49,110.58 172.76,109.84 UC1.C38
N23797472: length 1.1
  TOP w0.102: T25.1 145.8,91.34 v2(146.01,91.34)
  BOTTOM w0.076: v2(146.01,91.34) 145.69,91.03 UC1.AW13
N23797474: length 1.3
  TOP w0.102: T26.1 148.27,90.92 v2(147.85,91.34)
  BOTTOM w0.076: UC1.AT13 147.47,91.03 147.78,91.34 v2(147.85,91.34)
N23797500: length 2.1
  TOP w0.109: v2(145.12,91.34) 144.75,90.98 144.75,90.01 T32.1
  BOTTOM w0.076: UC1.AY13 144.8,91.03 v2(145.12,91.34)
N23797502: length 1.8
  TOP w0.102: T31.1 146.5,90.37 146.5,90.89 v2(146.96,91.34)
  BOTTOM w0.076: v2(146.96,91.34) 146.9,91.34 146.58,91.03 UC1.AU13
N23807582: length 3.8
  BOTTOM w0.102: UZ26.4 122.08,94.46 122.54,94.92 RZ120.2 123.4,95.32 123.5,95.42 v1(123.5,95.45)
  BOTTOM w0.109: UZ34.4 123.12,95.9 RZ120.2
N23944525: length 1.2
  TOP w0.109: T34.1 233.19,97.12 v2(233.68,97.12)
  BOTTOM w0.089: v2(233.68,97.12) 233.26,97.54 UH1.Y35
N23944527: length 2.3
  TOP w0.109: v2(234.26,97.1) 234.26,96.9 234.48,96.68 235.09,96.68 T33.1
  BOTTOM w0.089: UH1.Y36 234.26,97.4 v2(234.26,97.1)
N23944529: length 10.6
  TOP w0.109: T36.1 213.16,117.42 213.16,116.27 v2(212.77,115.88)
  BOTTOM w0.089: 214.13,114.94 214.13,112.82 215.97,110.98 215.97,110.37 216.36,109.97 216.36,109.48 216.65,109.18 UH1.BC1
  BOTTOM w0.102: 214.13,114.94 214.13,115.08
  BOTTOM w0.109: v2(212.77,115.88) 213.33,115.88 214.13,115.08
N23944531: length 1.1
  TOP w0.102: T35.1 233.33,103.54 v2(233.42,103.45)
  BOTTOM w0.089: UH1.AL35 233.36,103.39 v2(233.42,103.45)
N23948454: length 1.2
  TOP w0.102: v2(222.75,95.77) 222.96,95.98 T40.1
  BOTTOM w0.152: UH1.U13 222.81,95.84 v2(222.75,95.77)
N23950785: length 1.2
  TOP w0.102: T60.1 223.25,94.73 v2(223.17,94.81)
  BOTTOM w0.089: v2(223.17,94.81) 223.19,94.83 223.19,94.83 223.33,94.97 223.33,95.07 UH1.R15
N23950786: length 1.5
  TOP w0.109: v2(222.59,94.75) 222.59,94.79 222.08,95.3 T61.1
  BOTTOM w0.089: v2(222.59,94.75) 222.59,95.2 222.68,95.29 UH1.R13
N23950788: length 4.4
  TOP w0.109: T62.1 236.96,105.12 234.01,105.12 v2(233.39,104.5)
  BOTTOM w0.089: UH1.AN35 v2(233.39,104.5)
N23950789: length 2
  TOP w0.109: T63.1 234.3,104.74 v2(234.3,103.45)
  BOTTOM w0.089: UH1.AL37 234.13,103.28 v2(234.3,103.45)
N23950882: length 0.9
  TOP w0.109: CH321.1 251.84,91.21 RH28.2
N23950883: length 2.2
  BOTTOM w0.102: RH29.2 250.46,108.39 CH322.1 251.71,108.39 v1(252.17,108.85)
N23961117: length 1.6
  TOP w0.102: v2(233.6,95.86) 234.18,96.43 T70.1
  BOTTOM w0.089: UH1.U35 233.6,96.14 v2(233.6,95.86)
N23961134: length 1.1
  TOP w0.109: v2(222.81,102.22) 223.3,102.22 T66.1
  BOTTOM w0.089: v2(222.81,102.22) 222.81,102.19 222.9,102.09 UH1.AH14
N23961136: length 1.4
  TOP w0.109: v2(223.13,101.17) 223.07,101.23 T67.1
  BOTTOM w0.089: UH1.AH15 223.19,101.17 v2(223.13,101.17)
N23961138: length 1.3
  TOP w0.102: T68.1 231.24,94.97 v2(231.09,95.12)
  BOTTOM w0.089: v2(231.09,95.12) 231.22,95.25 UH1.R32
N23961140: length 2.8
  TOP w0.109: v2(234.31,95.91) 234.96,95.91 235.36,96.31 235.97,96.31 T71.1
  BOTTOM w0.089: UH1.U37 234.31,96.2 v2(234.31,95.91)
N23961142: length 1
  TOP w0.102: T72.1 224.1,97.14 v2(223.68,97.14)
  BOTTOM w0.089: UH1.Y15 v2(223.68,97.14)
N23961144: length 1.3
  TOP w0.109: T73.1 222.46,97.1 222.92,97.1 v2(222.94,97.09)
  BOTTOM w0.089: UH1.Y14 222.9,97.12 v2(222.94,97.09)
N23961148: length 1.8
  TOP w0.102: T69.1 231.07,93.58 v2(231.07,93.48)
  BOTTOM w0.089: v2(231.07,93.48) 231.07,93.83 UH1.N32
N23961156: length 3.7
  TOP w0.102: v1(250.57,119.01) 249.49,119.01 249.28,118.81 248.43,118.81
  TOP w0.109: RH433.2 248.43,118.81 248.82,118.42 248.82,118.31 249.3,117.83 QH6.1
N23961158: length 5.4
  TOP w0.102: RH433.1 248.52,119.83 v1(249.42,119.83)
  TOP w0.109: 246.96,119.03 246.96,120.44 CH340.1 RH432.2 ; 246.96,119.03 247.65,119.72 RH433.1 ; 246.96,119.03 QH7.2
N24088922: length 2.2
  TOP w0.102: QE17.1 283.4,103.52 283.01,103.13 v1(283.01,102.5) 283.01,102 RE546.2
N24114512: length 2.2
  BOTTOM w0.102: RI69.2 v1(79.8,101.5)
  BOTTOM w0.109: RI69.2 78.64,101.5 QI2.3
N24908379: length 1.1
  TOP w0.254: PR737.2 146.22,31.86 PD705.2
N24908381: length 4.3
  TOP w0.102: v1(143.3,29.98) 143.57,29.72 144.83,29.72 PR735.1
  TOP w0.254: PR736.2 PR735.1 145.79,30.21 145.97,30.39 PD705.3
N24908396: length 1.1
  TOP w0.254: PU701.2 149.48,31.1 PR741.2
N24908406: length 3.9
  TOP w0.254: PD705.1 148.29,31.6 v1(148.97,32.27) 149.37,32.67 PR739.1 150.25,31.88 PU701.1
N24908424: length 2.1
  TOP w0.102: v1(154.33,30.26) PR740.1
  TOP w0.254: PR740.1 153.17,30.45 PU701.4
N24908981: length 2.6
  TOP w0.102: v1(126.61,30.36) PC751.1
  TOP w0.254: v2(127.57,31.1) 127.55,31.08 PC751.1
  BOTTOM w0.203: PR728.2 127,31.67 v2(127.57,31.1)
N25075615: length 2.8
  BOTTOM w0.089: T302.1 240.43,102.63 240.15,102.9 239.98,102.9 239.85,103.03 UH1.AL48
N25591846: length 3.8
  TOP w0.254: PU3.5 99.41,128.31 99.69,128.03 101.21,128.03 101.52,128.33 PR47.2 PC13.2
N25591872: length 1.3
  TOP w0.102: PR43.2 100.78,130.96 v1(100.26,131.48)
N25591876: length 2.6
  TOP w0.102: v1(99.17,124.72) PR44.2
  TOP w0.203: PU3.2 100.06,126.58 99.63,126.15 99.37,126.15 99.17,125.94 PR44.2
N25591912: length 7.2
  TOP w0.102: v1(96.25,128.47) 96.25,129.11 96.89,129.74 96.9,129.74 96.91,129.75 97.78,129.75 98.24,129.3 PR41.2
  TOP w0.254: PR43.1 99.87,130.96 99.56,131.26 PQ10.2 98.73,131.26 98.29,130.83 98.29,129.37 PR41.2
N25591942: length 14.2
  TOP w0.254: PR27.1 102.06,130.6 103.56,129.1 PQ8.1 103.63,128.92 104.9,128.92 105.28,128.53 105.28,125.04 v1(105.02,124.79) 103.88,124.79 103.37,124.28 101.77,124.28 100.88,125.17 PR22.1 PR44.1
N25591952: length 3.9
  TOP w0.102: v1(98.1,126.12) 98.77,126.12 99.41,126.76 PU3.1
  TOP w0.203: PR42.2 98.74,128.47 99.41,127.8 PU3.1
N25736614: length 1.1
  TOP w0.102: PR1713.2 231.53,71.6 v1(232.61,71.6)
N25907811: length 9.7
  TOP w0.254: v2(78.48,105.69) 79.04,105.13 80.48,105.13 v1(81.31,105.96) 81.41,106.07 v2(81.41,107.68)
  BOTTOM w0.254: PR800.2 PR805.1 81.74,107.42 81.49,107.68 v2(81.41,107.68) ; PU800.3 78.66,105.87 v2(78.48,105.69) 78.21,105.42 PC804.1 78.24,104.87 PR817.1
N25907817: length 8
  TOP w0.254: v2(79.31,105.67) 79.65,106 v1(79.65,106.06) 79.65,107.92 79.9,108.18 v2(81.1,108.18)
  BOTTOM w0.254: v2(81.1,108.18) 81.21,108.18 81.47,108.43 PR809.2 ; PU800.2 v2(79.31,105.67) 79.31,105.66 79.15,105.5 PR815.1 79.69,104.8 PC800.1
N25907922: length 5.4
  TOP w0.102: v1(96.96,68.46) 98.48,69.99 PQ803.2
  TOP w0.254: PQ803.2 98.74,70.33 99.65,71.24 PR801.2 100.2,70.75 100.19,70.74 PR807.1
N25907924: length 5.6
  TOP w0.102: v1(101.6,74.18) 101.1,73.68 PR858.1
  TOP w0.254: PR807.2 101.21,70.55 101.21,71.57 102.09,72.45 PQ802.6 101.29,73.1 PR858.1
N25907948: length 2.8
  TOP w0.254: PR853.2 102.73,75.78 102.99,75.51 PU801.1
N25907954: length 3
  TOP w0.102: PR859.2 v1(100.47,77.29)
  TOP w0.254: PU801.5 100.96,75.51 100.83,75.38 PC814.2 PR859.2
N25907966: length 1.3
  TOP w0.254: PR818.2 106.94,75 107.2,74.75 PQ804.2
N25907978: length 5.1
  TOP w0.254: PR854.1 PR818.1 106.03,74.38 106.55,73.86 PQ807.1 106.55,72.91 105.58,71.94 PR822.2
N25907980: length 3.9
  TOP w0.102: PR857.2 102.73,79.44 102.93,79.64 v1(103.25,79.64)
  TOP w0.254: PQ802.5 v2(102.74,73.86) ; PR857.2 102.65,78.7 PR856.1 101.83,78.7 101.54,78.41 101.27,78.41 v2(101.17,78.31)
N25907988: length 5.9
  TOP w0.102: 101.75,77.79 101.1,77.79 100.64,78.24 v1(100.64,78.68)
  TOP w0.254: PR856.2 101.75,77.79 101.49,77.53 PU801.4 101.81,76.81 102.28,76.34 102.28,75.12 102.8,74.6 PR855.1
N25908000: length 1.4
  TOP w0.254: PU801.2 103.61,76.16 104.38,75.4 PR854.2
N25908024: length 2.2
  TOP w0.102: v2(75.24,109.17) 74.35,109.17 v1(74.1,108.91)
  TOP w0.254: PQ813.6 107.06,76.84 107.31,76.59 107.5,76.59 107.5,76.59 107.5,76.58 v2(107.58,76.58)
N25908041: length 9
  TOP w0.254: PR840.1 106.17,76.67 PC813.1 106.86,75.97 v2(107.58,75.97)
  BOTTOM w0.254: v2(74.73,107.77) 74.81,107.84 PD802.2 76.68,107.84 76.74,107.9 77.2,107.9 78.21,108.91 78.86,108.91 79.31,109.37 PU800.7
N25908049: length 3.4
  BOTTOM w0.254: PU800.6 78.66,112.65 PC812.1 ; PR843.1 PC812.1 ; PC812.1 PR832.2
N25908061: length 0.9
  TOP w0.254: PQ813.5 106.31,77.8 106.23,77.87 PR840.2
N25908120: length 2.4
  TOP w0.254: v2(109.03,74.67) 109.03,74.99 109.45,75.4 PQ804.6 ; v2(75.45,123.41) 75.45,123.67 75.19,123.92 PR811.2
N25908122: length 72.2
  TOP w0.254: v2(75.4,130.08) 75.4,129.73 75.75,129.38 81.87,129.38 84.26,127 84.26,117.63 89.54,112.35 89.54,94.59 91.54,92.59 91.54,91.63 90.23,90.31 v1(90.23,87.07) 90.23,81.19 95.82,75.61 95.82,74.37 96.4,73.78 PQ803.1
  vias: v2(74.85,123.24)
N25908132: length 1.1
  TOP w0.254: PR836.1 108.91,78.98 108.96,78.93 PQ813.3
N25908138: length 8.4
  TOP w0.102: v1(115.76,71.26) 115.76,71.64 115.43,71.97 PR802.2
  TOP w0.254: PR802.2 114.77,72.01 PR808.1 114.07,73.42 112.48,73.42 111.91,72.84 111.91,72.11 113.05,70.97 PQ805.2
N25908140: length 7
  TOP w0.102: v1(116.77,72.34) 115.73,72.34 PR808.2
  TOP w0.254: PQ806.3 111.96,76.53 111.96,75.97 v2(111.86,75.87) ; v2(114.23,76.25) 114.89,76.25 115.59,75.55 115.59,72.96 PR808.2
N25908152: length 43.9
  TOP w0.203: v2(83.37,123.9) 83.57,123.7 83.57,117.27 88.76,112.09 v1(88.76,100.38) 88.76,93.56 90.11,92.2 v2(90.54,92.2)
  TOP w0.254: PQ805.1 110.97,71.74 109.97,72.74 109.59,72.74 PR812.1 109.29,73.09 108.52,73.86 108.52,74.28 v2(108.51,74.29)
  BOTTOM w0.203: v2(78.57,123.61) 78.86,123.9 v2(83.37,123.9)
N25908168: length 2.4
  TOP w0.254: PQ806.6 110.45,78.77 PR814.2 110.45,80.11 PR852.2 110.46,80.7 PR813.2
N25908188: length 1.4
  TOP w0.254: PQ804.3 107.88,73.32 108.17,73.04 PR812.2
N25908210: length 0.9
  TOP w0.254: PR814.1 111.37,79.37 PQ806.5
N25908220: length 7.2
  TOP w0.254: PQ806.2 111.37,76.7 109.91,78.16 109.91,80 109.42,80.49 v1(108.45,80.49) 108.35,80.49 108.33,80.46 107.44,80.46 107.39,80.41 PR820.1
N25908319: length 1.3
  TOP w0.254: PR816.2 110.53,75.4 110.25,75.12 110.25,75 110,74.75 PQ804.5
N25908329: length 2.5
  TOP w0.254: PR825.2 111.6,80.54 111.86,80.29 PR826.2 112.33,80.29 113.1,79.51 PQ810.5
N25908331: length 3.7
  TOP w0.102: PR841.1 115.96,80.73 115.47,81.23 v1(115.18,81.23)
  TOP w0.254: PQ808.5 116.9,79.88 PR834.2 PR1652.2 116.81,80.73 PR841.1
N25908337: length 3
  TOP w0.254: PR830.2 115.12,78.86 PQ810.1 116.17,78.86 PQ808.6 116.25,79.64 PR841.2
N25908347: length 4.9
  TOP w0.102: PQ808.3 118.86,77.04 v1(119.18,76.72)
  TOP w0.254: PR833.2 115.59,76.48 116.71,76.48 116.9,76.67 PQ808.2 116.9,77.23 116.95,77.28 117.31,77.28 PQ808.3
N25908367: length 2
  TOP w0.254: PQ811.5 116.71,74.31 116.19,74.83 PR829.2
N25908379: length 3.1
  TOP w0.254: PQ810.2 115.01,79.51 114.4,78.9 114.4,78.66 113.81,78.07 PR824.2 113.25,77.37 PR827.2
N25908405: length 18.7
  TOP w0.102: v2(112.26,80.91) 112.26,81.04 v1(112.64,81.42)
  TOP w0.254: v2(112.26,80.91) 112.53,80.91 113.22,80.22 PQ810.4 ; v2(107.56,71.13) 108.01,71.13 108.02,71.15 PQ809.6 108.38,71.2 PR845.2 108.28,72.11 PR838.2
  BOTTOM w0.102: v2(107.56,71.13) 107.56,71.56 106.82,72.31 106.82,78.46 108.64,80.29 111.64,80.29 v2(112.26,80.91)
N25908421: length 2.2
  TOP w0.102: PR844.2 109.28,69.73 v1(109.66,69.35)
  TOP w0.254: PR844.2 109.27,70.5 PQ809.5
N25908431: length 2.7
  TOP w0.254: PQ809.3 PQ809.2 106.8,70.5 107.06,70.75 PR839.2
N26168283: length 2.5
  TOP w0.102: PR46.2 100.76,133.75 v1(101.53,132.98)
  TOP w0.254: PR46.2 101,134.18 PQ12.1
N26168409: length 2.6
  TOP w0.102: v1(105.15,134.31) 105.15,134.19 104.88,133.92 PR49.1
  TOP w0.254: PR49.1 103.51,133.92 103.25,134.18 PQ12.2
N26168635: length 6.8
  TOP w0.102: v1(95.82,76.4) 96.52,75.7 PQ814.1
  TOP w0.254: PQ814.1 96.52,74.24 97.72,73.04 99.12,73.04 99.44,72.72 100,72.72 PR858.2
N26172409: length 1.1
  TOP w0.254: PR861.1 99.22,74.55 98.97,74.8 PQ814.2
N26187732: length 3
  TOP w0.102: PRZ83.1 104.85,82.89 v1(105.66,83.7)
  TOP w0.254: PRZ79.1 PHZ5.1 PRZ83.1
N26187863: length 1.9
  TOP w0.102: v1(105.67,108.34) 105.55,108.46 PRZ42.2
  TOP w0.254: PRZ42.2 PCZ20.1
N26187879: length 3.5
  BOTTOM w0.102: PCZ14.1 v1(102.18,108.64)
  BOTTOM w0.254: PRZ32.1 PCZ14.1 PCZ13.2 101.29,108.43 PRZ31.2
N26187927: length 2.4
  BOTTOM w0.102: PRZ24.2 95.51,105.6 95.31,105.8 94.55,105.8 v1(94.42,105.93)
  BOTTOM w0.254: PCZ10.1 96.69,105.6 PRZ24.2
N26187941: length 9.1
  BOTTOM w0.254: v2(103.83,109.91) 103.83,109.28 PRZ50.1 104.64,108.47 PRZ54.2 ; v2(142.95,117.17) 146.64,117.17 149.16,119.7 PHZ2.1
N26187983: length 3.5
  BOTTOM w0.102: v1(101.23,94.13) PRZ37.1
  BOTTOM w0.254: PRZ37.1 PCZ16.1 PCZ15.2 99.45,94.3 PRZ38.2
N26188037: length 2.5
  BOTTOM w0.254: PCZ4.2 96.26,107.3 96.26,106.57 PRZ11.2 PCZ1.1 PRZ12.1
N26188062: length 1.8
  BOTTOM w0.254: PRZ78.1 PRZ82.1 PHZ4.1
N26189598: length 2.3
  TOP w0.102: v1(98.74,99.58) 98.67,99.51 98.66,99.51 PRZ43.2
  TOP w0.254: PRZ43.2 PCZ19.1
N26189600: length 1.9
  TOP w0.102: PCZ18.1 102.12,109.19 v1(101.89,109.42)
  TOP w0.254: PCZ18.1 PRZ40.2
N26189682: length 3.6
  BOTTOM w0.102: PRZ13.2 v1(95.39,109.36)
  BOTTOM w0.254: PRZ18.1 PRZ14.1 96.63,108.19 96.58,108.24 96.36,108.24 96.33,108.27 PCZ4.1 PRZ13.2
N26189729: length 7.1
  BOTTOM w0.254: PHZ3.1 109.16,90.46 v1(107.82,91.81) 105.3,91.81 104.88,92.23 PRZ55.2 PRZ52.1
N26189992: length 1.8
  BOTTOM w0.102: PCZ7.1 v1(98.82,109.98)
  BOTTOM w0.254: PRZ18.2 98.4,108.95 98.45,109 98.79,109 PCZ7.1
N26190033: length 12.1
  BOTTOM w0.254: v2(97.28,110.44) 97.12,110.59 94.74,110.59 93.29,109.14 93.29,103.75 93.94,103.11 PRZ3.1 ; v2(192.08,113.69) 192.08,113.13 PHZ1.2
N26190221: length 2.6
  TOP w0.102: PCZ23.1 97.71,95.76 96.77,94.82 v1(96.58,94.82)
  TOP w0.254: PCZ23.1 PRZ47.2
N26192621: length 2
  BOTTOM w0.254: PCH46.2 192.68,131.3 v2(192.08,130.71) 192.08,130.49 192.2,130.37 PUH4.7
N26192663: length 4.1
  TOP w0.102: v1(187.84,114.25) PRH13.1
  TOP w0.152: v2(187.93,117.55) 187.93,117.55 187.84,117.46 PRH13.1
  BOTTOM w0.152: PLH4.3 v2(187.93,117.55)
N26192730: length 2.5
  TOP w0.102: v1(177.73,120.34) 177.35,120.72 v2(177.1,120.72)
  TOP w0.152: PRH5.1 176.84,120.47 v2(177.1,120.72)
  BOTTOM w0.152: v2(177.1,120.72) 176.62,120.25 PLH3.3
N26193321: length 1.8
  BOTTOM w0.254: PUH3.7 182.55,130.38 v2(182.11,130.82) 182.11,131.47 PCH22.2
N26193447: length 3.4
  TOP w0.102: v2(154.11,120.22) 154.45,120.56 155.17,120.56 v1(155.38,120.34)
  TOP w0.152: v2(154.11,120.22) 154.11,120.22 154.05,120.15 153.51,120.15 153.44,120.23 PRH6.1
  BOTTOM w0.152: PLH1.3 154.05,120.15 154.11,120.22 v2(154.11,120.22)
N26193461: length 2.7
  TOP w0.102: PRH14.1 v1(167.76,121.3)
  TOP w0.152: v2(166.63,120.66) 166.63,120.8 166.63,120.8 PRH14.1
  BOTTOM w0.152: v2(166.63,120.66) 166.19,120.21 PLH2.3
N26194097: length 3
  TOP w0.254: PCH25.2 162.84,130.09 v2(162.43,130.5)
  BOTTOM w0.102: v2(162.43,130.5) 162.43,130.95 162.75,131.26 v1(162.75,131.77)
  BOTTOM w0.254: PUH1.7 162.58,130.35 v2(162.43,130.5)
N26194151: length 1.7
  BOTTOM w0.254: PUH2.7 172.62,131.27 PCH50.2
N26195379: length 2.2
  BOTTOM w0.254: PUT1.7 99.04,88.18 v1(98.85,88.37) 98.63,88.37 97.99,87.73 PCT12.2
N26195438: length 3.4
  TOP w0.102: v1(112.14,85.74) 111.99,85.59 v2(111.27,85.59)
  TOP w0.254: v2(111.27,85.59) 111.26,85.58 PRT3.1
  BOTTOM w0.254: PLT1.3 v2(111.27,85.59)
N26196770: length 2.4
  TOP w0.102: v2(200.08,120.09) v1(199.58,119.58)
  TOP w0.254: v2(200.08,120.09) 200.34,120.34 PCA10.2
  BOTTOM w0.254: PUA1.7 199.86,119.86 v2(200.08,120.09)
N26737016: length 3.2
  BOTTOM w0.102: PR1616.2 157.3,129.83 156.9,130.22 v1(156.9,130.63)
  BOTTOM w0.254: PUH1.17 158.2,129.11 158.11,129.19 PR1616.2
N26737032: length 1.6
  BOTTOM w0.254: PUH1.16 158.23,128.61 158.2,128.64 157.32,128.64 PR1617.2
N26738097: length 1.2
  BOTTOM w0.254: PUH2.16 167.78,128.59 PR1619.2
N26738100: length 2.2
  BOTTOM w0.254: PUH2.17 168.92,129.92 168.51,130.33 PR1618.2
N26738443: length 2.2
  BOTTOM w0.102: PR1620.2 v1(99.47,83.22)
  BOTTOM w0.254: PUT1.17 100.56,84.06 100.35,83.86 PR1620.2
N26738446: length 2.2
  BOTTOM w0.102: PR1621.2 v1(101.86,83.22)
  BOTTOM w0.254: PUT1.16 101.06,83.86 100.94,83.74 PR1621.2
N26738777: length 1.6
  BOTTOM w0.254: PUA1.16 194.68,118.21 PR1623.2
N26738780: length 1.6
  BOTTOM w0.254: PR1622.2 194.61,118.72 v2(195.44,118.72) PUA1.17
N26739146: length 1.8
  BOTTOM w0.254: PR1624.2 187.92,130.35 188.5,129.77 PUH4.17
N26739149: length 1.2
  BOTTOM w0.254: PR1625.2 187.71,128.52 187.93,128.74 PUH4.16
N26739609: length 1.8
  BOTTOM w0.254: PR1626.2 178.29,130.2 178.85,129.64 PUH3.17
N26739612: length 1.2
  BOTTOM w0.254: PR1627.2 178,128.42 178.25,128.67 PUH3.16
N26924776: length 1.6
  BOTTOM w0.254: PR311.2 195.38,90.27 PR1649.2 PR1648.1
N26924800: length 2.8
  BOTTOM w0.254: PC307.1 198,91.89 PR1650.1 ; PC307.1 197.87,91.21 PR306.1 ; PC307.1 197.62,92.28 PR1651.2
N26924806: length 0.9
  BOTTOM w0.254: PR308.1 197.04,91.95 PC307.2
N27521746:
  vias: v1(166.3,122.57)
N27522693: length 1.1
  TOP w0.102: v1(179,124.66) 179.33,124.33 PCH28.1
N27523201: length 1.8
  TOP w0.102: PRH16.2 v1(173.86,124.22)
N27523847: length 1
  TOP w0.102: PCH52.1 v1(196.1,122.3)
N27524640: length 1.3
  TOP w0.102: PCT14.1 106.38,85.1 v1(106.6,84.88)
N27525287: length 0.6
  TOP w0.102: 199.19,114.82 v1(199.77,114.82)
N27689839: length 3.1
  TOP w0.102: PC865.1 103.06,132.85 102.88,133.03 v1(102.88,133.03)
  TOP w0.254: PQ8.2 103.83,131.26 PR865.1 103.83,132.83 PC865.1
N27714854: length 5
  TOP w0.102: PD803.3 79.8,113.39 v1(79.46,113.73)
  TOP w0.381: PR871.1 83.16,114.22 81.75,114.22 80.91,113.39 PD803.3
N27715583: length 0.6
  TOP w0.102: v1(39.62,125.68) 39.37,125.42 39.37,125.19
N27715644: length 1.6
  TOP w0.102: 40.38,119.01 v1(41.97,119.01)
N27715680:
  vias: v1(37.99,121.28)
N27715692: length 3.9
  TOP w0.102: PD3000.1 38.03,119.9 v1(38.04,119.91)
  TOP w0.254: PD3000.1 38.36,118.75 38.68,119.07 PR3007.1 38.97,119.02 39.68,118.31 PR3006.2
N27715813: length 7
  TOP w0.102: PD3002.2 35.17,119.1 v1(34.37,118.3)
  TOP w0.254: PC3007.1 35.93,117.91 v2(35.93,118.77) 35.28,119.43 PD3002.2 ; v2(40.86,121.15) 40.97,121.05 PR3013.2 ; PC3009.1 44.94,119.82 v2(44.76,120) 44.76,120.86 44.26,121.36 PQ3000.2
N27715838: length 2.9
  TOP w0.102: v2(47.11,122.57) 47.11,122.18 47.24,122.06 v1(47.37,122.06)
  TOP w0.254: v2(45.04,122.52) 45.2,122.52 45.46,122.27 PQ3000.6
  TOP w0.381: v2(47.11,122.57) 46.53,122.57 PR3001.1 ; v2(44.21,120.62) 44.12,120.71 PQ3000.3
N27715861: length 8.2
  TOP w0.254: PR3012.2 40.99,124.31 PD3001.2 41.62,124.94 v1(44.03,124.94) 44.43,124.53 PC3006.1 PC3008.1 44.53,123.09 44.53,122.34 44.65,122.22 44.65,121.98 45.27,121.36 PQ3000.5
N27715969: length 3.7
  TOP w0.102: 42.6,124.09 v1(42.6,124.51)
  TOP w0.254: PU3000.2 39.75,123.71 v2(39.84,123.8)
  BOTTOM w0.254: v2(42.03,123.96) 40,123.96 v2(39.84,123.8)
N27884552:
  vias: v1(130.87,42.81)
N28028546: length 5.3
  TOP w0.102: PR872.1 83.45,109.21 v1(83.26,109.01)
  TOP w0.381: PD803.2 81.96,112.84 82.66,112.14 82.66,110.94 83.1,110.5 PR872.1
N29556778: length 2.5
  TOP w0.109: v2(292.61,89.34) 292.61,89.32 UV31.C6
  BOTTOM w0.109: v2(292.61,89.34) v1(293.01,88.93) 293.85,88.93 RV38.1
N29565659: length 3.3
  TOP w0.203: 288.71,52.44 288.54,52.6 UA1.21
  TOP w0.254: 288.71,52.44 289.37,51.78 CA51.1 290.11,51.76 RA44.1
N29565663: length 2.8
  TOP w0.203: UA1.6 282.43,54.2
  TOP w0.254: 282.43,54.2 281.77,54.2 v1(281.74,54.18) 281.73,54.19 281.37,54.19 281.24,54.06 CA53.1
N29565665: length 2.9
  TOP w0.203: UA1.32 287.02,57.86 v1(287.46,58.3) 287.62,58.46 287.62,58.47 287.84,58.7 CA52.1
N29565749: length 3.6
  TOP w0.203: UA1.15 285.42,51.23 285.81,50.84 v1(285.81,50.43) 285.81,49.2 285.87,49.13 CA25.1
N29565777: length 4
  TOP w0.203: v1(289.36,55.19) 289.17,55 288.18,55 UA1.27
  TOP w0.381: v1(289.36,55.19) 290.46,56.28 CA49.2 CA80.2
N29565781: length 6.2
  TOP w0.109: UA1.16 285.82,51.2 286.44,50.57 v2(286.44,50.26) 286.44,47.97 285.87,47.4 RA54.1 RA53.1
N29565804: length 4.7
  TOP w0.102: v1(292.29,53.67) 292.1,53.48 290.94,53.48 290.7,53.23 290.7,53.22 290.33,52.86 CA35.1
  TOP w0.203: UA1.22 288.65,53 289.05,52.6 289.62,52.6 289.87,52.86 CA35.1
N29566049: length 2.2
  TOP w0.102: CA33.1 278.7,55.14 277.91,54.35 v1(277.91,54.18)
  TOP w0.109: CA33.1 RA17.2
N29624840: length 3.5
  TOP w0.102: CZ306.1 266.71,51.01 266.71,50.05 v1(266.29,49.63)
  TOP w0.109: CZ306.1 266.24,51.92 266.4,52.08 UZ53.6
N29889874: length 3.2
  BOTTOM w0.109: SW1.1 286.42,65.33 v1(285.49,64.39) 285,63.91 285,63.58 RH101.2
N30096018: length 2.1
  TOP w0.109: T50.1 135.38,44.48 v2(135.25,44.61)
  BOTTOM w0.109: JDIMM1.162 135.12,44.74 v2(135.25,44.61)
N30096036: length 5.3
  TOP w0.102: T51.1 133.02,56.54 133.03,56.55
  TOP w0.109: v2(136.11,55.73) 135.29,56.55 133.03,56.55
  BOTTOM w0.109: v2(136.11,55.73) 135.87,55.49 JDIMM1.165
N30107347: length 1.9
  TOP w0.102: T52.1 211.5,41.52 v2(211.1,41.52)
  BOTTOM w0.109: JDIMM2.162 210.92,41.7 v2(211.1,41.52)
N30107379: length 3
  TOP w0.109: v2(211.5,53.12) 211.52,53.14 T53.1
  BOTTOM w0.109: v2(211.5,53.12) 211.88,52.74 211.88,52.31 211.67,52.1 JDIMM2.165
N30319136: length 6.3
  TOP w0.109: RZ326.1 264.54,74 264.54,73.26 v1(264.38,73.09) 264.38,72.93 264.27,72.82 264.27,72.06 v2(264.19,71.98)
  BOTTOM w0.109: JNGFF2.25 265.58,72.11 265.45,71.98 v2(264.19,71.98)
N31929130: length 6.2
  TOP w0.102: RV6.1 116.15,136.33 RV9.1 ; RV9.1 116.11,136.06 115.73,135.68 ; RV9.1 116.11,136.57 115.93,136.74 114.34,136.74 v1(114.3,136.79)
  TOP w0.107: QV7.1 115.37,135.32 115.73,135.68 ; RV1400.1 RV6.1
N31929169:
  vias: v1(118.36,132.85)
N31929212: length 6.2
  TOP w0.102: QV8.2 122.73,135.78 v1(123.64,136.69)
  TOP w0.107: QV8.2 120.02,135.78 119.65,135.42 CV1635.1 RV1400.2
N32006014: length 3
  BOTTOM w0.102: v1(276.73,47) 277.5,46.23 RZ381.2
  BOTTOM w0.109: RZ381.2 277.84,46.19 QZ18.6 QZ18.5
N32126868: length 4
  TOP w0.102: v1(260.54,30.55) 258.95,30.55 258.68,30.82 CZ130.1
  TOP w0.109: UZ23.6 257.9,31.8 258.5,31.19 CZ130.1
N33127151: length 2.6
  TOP w0.102: RZ63.1 238.67,127.69 CZ56.1 238.63,128.47 v1(238.18,128.92)
N35444529: length 6
  TOP w0.102: v1(282.09,93.83) 282.42,94.16 283.89,94.16 284.46,94.73 RE70.1 284.6,95.09 QE11.3 284.53,96.15 283.41,96.15 RE90.2
N35444573: length 4.3
  TOP w0.102: v2(286,95.51) 285.82,95.51 285.38,95.07 RE70.2 ; QE4.2 284.83,93.18 v2(285.02,93.37)
  BOTTOM w0.102: v1(286.95,94.82) 286.25,95.51 v2(286,95.51)
N35445396: length 1.5
  TOP w0.102: DV11.1 145.03,126.95 145.66,127.58 v1(146.24,127.58)
N35445409: length 6.1
  TOP w0.102: DV12.1 145.82,128.79 v1(145.66,128.79) v2(144.65,128.79) ; v2(138.55,121.87) 138.74,121.68 RV631.2 CV635.1 RV629.1
N35445460: length 6.2
  TOP w0.102: RV630.1 135.67,123.24 v1(136.36,123.93) 136.71,124.28 139.19,124.28 139.42,124.51 QV20.1
N35445475: length 8.9
  TOP w0.102: v1(139.25,122.69) 140.83,124.27 QV20.2 141.5,121.51 140.25,120.27 RV631.1
N35445606: length 14.3
  TOP w0.102: QV18.1 145.47,123.23 145.47,120.03 145.22,119.77 138.76,119.77 138.6,119.62 138.6,118.69 v1(138.53,118.62) 138.21,118.3 RV625.1
N35445635:
  vias: v1(143,122.69)
N35445977: length 2.7
  TOP w0.102: v1(259.2,113.78) RZ25.1 259.47,112.55 QZ3.1
N35754103: length 2.3
  BOTTOM w0.102: RT445.2 33.1,121.74 RT456.2 32.63,122.18 32.27,121.82 UT32.1
N35754105: length 1.3
  BOTTOM w0.102: RT448.2 32.64,120.52 UT32.3
N35754309: length 1.2
  BOTTOM w0.102: RT499.2 33.15,125.24 32.8,124.89 UT34.1
N35754313: length 3.4
  BOTTOM w0.102: v1(30.77,126.12) 31.55,126.12 RT500.2 31.9,124.41 32.06,124.24 UT34.2
N38529389: length 3.7
  BOTTOM w0.102: v1(287.59,103.52) 287.75,103.36 CL17.1
  BOTTOM w0.254: CL17.1 288.51,102.5 288.57,102.5 TL1.4
N38529394: length 3.7
  BOTTOM w0.102: CL16.1 v1(287.75,98.47)
  BOTTOM w0.254: TL1.1 288.56,99.5 288.51,99.51 CL16.1
N38529410: length 3.7
  BOTTOM w0.102: CL20.1 v1(287.75,106.6)
  BOTTOM w0.254: CL20.1 288.51,105.48 288.67,105.5 TL1.7
N38529414: length 3.8
  BOTTOM w0.102: v1(287.65,109.61) 287.75,109.52 CL21.1
  BOTTOM w0.254: TL1.10 288.22,108.5 288.19,108.47 CL21.1
N42376964: length 2.5
  TOP w0.102: UZ52.B2 273.43,68.7 273.43,68.7 273.43,68.91 273.24,69.1 CZ217.1 RZ1403.1 RZ1404.1
N356040180: length 1
  TOP w0.254: PR3012.1 40.41,123.38 40.3,123.27 PU3000.1
N356040181: length 1
  TOP w0.254: PU3000.7 40.25,120.74 PR3013.1

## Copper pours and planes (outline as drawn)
3.3V_CAM_EN#_R on TOP (solid shape): 131.08,124.45 131.08,121.47 130.98,121.37 130.46,121.37 130.42,121.42 130.42,122.1 130.23,122.28 130.23,123.12 129.68,123.68 129.68,124.89 129.92,125.14 130.4,125.14
3.3V_TS_EN_R on TOP: 113.78,135.48 109.89,135.48 109.41,135 109.41,131.9 109.56,131.74 112.93,131.74 112.99,131.8 112.99,133.89 114.06,134.95 114.06,135.21
+0.6V_DDR_VTT on TOP (solid shape): 160.02,48.93 160.02,46.18 159.89,46.05 158.94,46.05 158.87,46.11 158.87,46.17 158.87,49.12 158.94,49.18 159.76,49.18
+0.6V_DDR_VTT on TOP: 173.03,33.73 171.76,33.73 171.57,33.54 171.57,31.7 171.76,31.51 172.84,31.51 173.1,31.76 173.1,32.97 173.67,32.97 173.67,33.09 173.1,33.09 173.1,33.67
+0.6V_DDR_VTT on IN1: 165.67,35.51 170.43,30.74 172.78,30.74 173.35,31.32 173.35,32.78 172.97,33.16 171.38,33.16 168.78,35.76 168.78,42.49 167.51,43.76 167.51,44.4 164.84,47.06 162.94,47.06 161.22,48.78 159.57,48.78 159.13,48.33 159.13,45.24 159.84,44.52 164.12,44.52 165.67,42.97
+0.6V_DDR_VTT on IN4: 171.38,33.6 171.38,31.57 171.7,31.25 172.72,31.25 172.97,31.51 172.97,33.54 172.78,33.73 171.51,33.73
+0.6VSP on TOP: 175.38,32.27 175.19,32.08 173.54,32.08 173.29,32.33 173.29,32.78 173.86,32.78 173.86,33.28 173.29,33.28 173.29,33.92 173.48,34.11 175.32,34.11 175.38,34.05
+0.6VSP on BOTTOM: 175.38,35.7 175.45,35.63 175.45,34.24 175.51,34.17 175.51,32.9 175.38,32.78 174.37,32.78 174.3,32.84 174.3,34.36 174.62,34.68 174.62,35.63 174.68,35.7
+0.9V_LAN on TOP (solid shape): 277.86,107.22 277.86,106.46 277.55,106.14 277.55,105.44 277.23,105.13 276.21,105.13 276.11,105.23 276.11,107.21 276.24,107.35 277.74,107.35
+0.9V_LAN on TOP (solid shape): 272.56,112.11 273.38,112.11 273.42,112.08 273.42,111.48 273.37,111.43 272.35,111.43 271.96,111.03 270.88,111.03 270.75,111.16 270.75,112.03 270.79,112.07 270.8,112.06 271.74,112.06 271.83,112.16 272.51,112.16
+0.9V_LAN on TOP (solid shape): 272.9,116.45 272.88,115.99 273.35,116 273.36,115.99 273.36,115.59 273.32,115.55 272.48,115.55 272.11,115.92 271.71,115.92 271.58,116.05 271.58,116.94 272.41,116.94
+0.9V_LAN on IN3: 271.58,114.69 271.58,111.22 271.83,110.97 273.17,110.97 275.9,108.23 275.9,107.33 276.39,106.84 277.99,106.84 278.18,107.03 278.18,109 279.71,110.52 279.71,111.73 280.34,112.36 280.34,112.56 279.64,113.25 279.64,114.14 280.15,114.65 280.15,114.97 279.9,115.22 279.13,115.22 278.56,114.65 278.56,112.05 278.12,111.6 274.37,111.6 272.72,113.25 272.72,114.69
+0.9V_LAN on IN4: 271.4,116.43 271.4,114.25 271.63,114.02 272.63,114.02 272.97,114.37 272.97,116.42 272.83,116.57 271.53,116.57
+0.9V_TBT_CIO on BOTTOM (solid shape): 43.36,108.96 43.5,108.87 43.66,108.86 43.69,108.84 43.71,108.77 43.74,108.73 43.77,108.69 43.82,108.66 43.82,108.44 43.76,108.38 43.73,108.35 43.57,108.19 43.57,107.04 43.33,106.8 42.99,106.8 42.85,106.94 42.8,107.06 42.74,107.11 42.71,107.15 42.71,107.34 42.74,107.38 42.85,107.57 42.74,107.76 42.74,107.87 43.16,108.29 43.2,108.34 43.27,108.55 43.2,108.75 43.15,108.81 43.14,108.87 43.14,108.92 43.22,109 43.32,109
+0.9V_TBT_DP on TOP (solid shape): 44.51,107.35 44.51,107.02 45.13,106.4 45.28,106.4 45.41,106.27 46.98,106.27 47.01,106.24 47.01,105.41 46.48,105.41 46.46,105.42 46.01,105.42 45.78,105.65 44.66,105.65 44.66,106.08 44.51,106.23 44.13,106.23 43.9,106.46 43.9,107.35 44.03,107.48 44.38,107.48
+0.9V_TBT_DP on BOTTOM (solid shape): 42.43,109.39 42.46,109.36 42.55,109.27 42.55,109.09 42.53,109.08 42.43,109 42.39,108.87 42.39,108.85 42.3,108.76 41.22,108.76 40.96,109.02 40.96,109.35 41.19,109.58 41.22,109.61 41.27,109.66 41.35,109.66 41.51,109.51 41.78,109.51 41.97,109.7 42.12,109.7
+0.9V_TBT_DP on BOTTOM (solid shape): 43.96,107.72 44.2,107.55 44.47,107.64 44.51,107.65 44.55,107.63 44.57,107.6 44.59,107.57 44.57,107.54 44.46,107.24 44.59,106.94 44.68,106.85 44.57,106.71 44.56,106.6 44.57,106.46 44.64,106.38 44.71,106.32 44.71,106.22 44.67,106.19 44.64,106.16 44.5,106.16 44.33,106.33 44.17,106.33 44.13,106.37 44.12,106.37 44.08,106.43 44.02,106.48 44.01,106.48 43.7,106.8 43.7,107.62 43.82,107.75 43.95,107.75
+0.9V_TBT_LVR_OUT on BOTTOM (solid shape): 40.62,107.94 40.62,107.8 40.86,107.59 41,107.56 41.02,107.56 41.11,107.47 41.15,107.41 41.22,107.36 41.22,107.17 41.09,107.05 40.86,107.05 40.67,107.15 40.48,107.05 40.21,107.05 40.16,107.1 40.1,107.14 40.04,107.15 39.89,107.3 39.89,107.56 40.1,107.77 40.1,107.94 40.27,108.11 40.46,108.11
+0.9V_TBT_LVR_OUT on TOP: 35.29,102.39 35.24,102.44 35.24,103.45 36.08,104.29 37.92,104.29 38.03,104.41 38.07,104.41 38.07,104.48 38.11,104.52 38.11,104.88 38.15,104.91 38.64,104.91 38.68,104.88 39.76,104.88 39.85,104.86 39.93,104.88 40.51,104.88 40.57,104.81 40.57,104.55 40.3,104.28 39.26,104.28 38.91,104.33 38.69,104.05 38.59,103.95 38.06,103.95 37.57,103.47 37.57,102.47 37.49,102.39
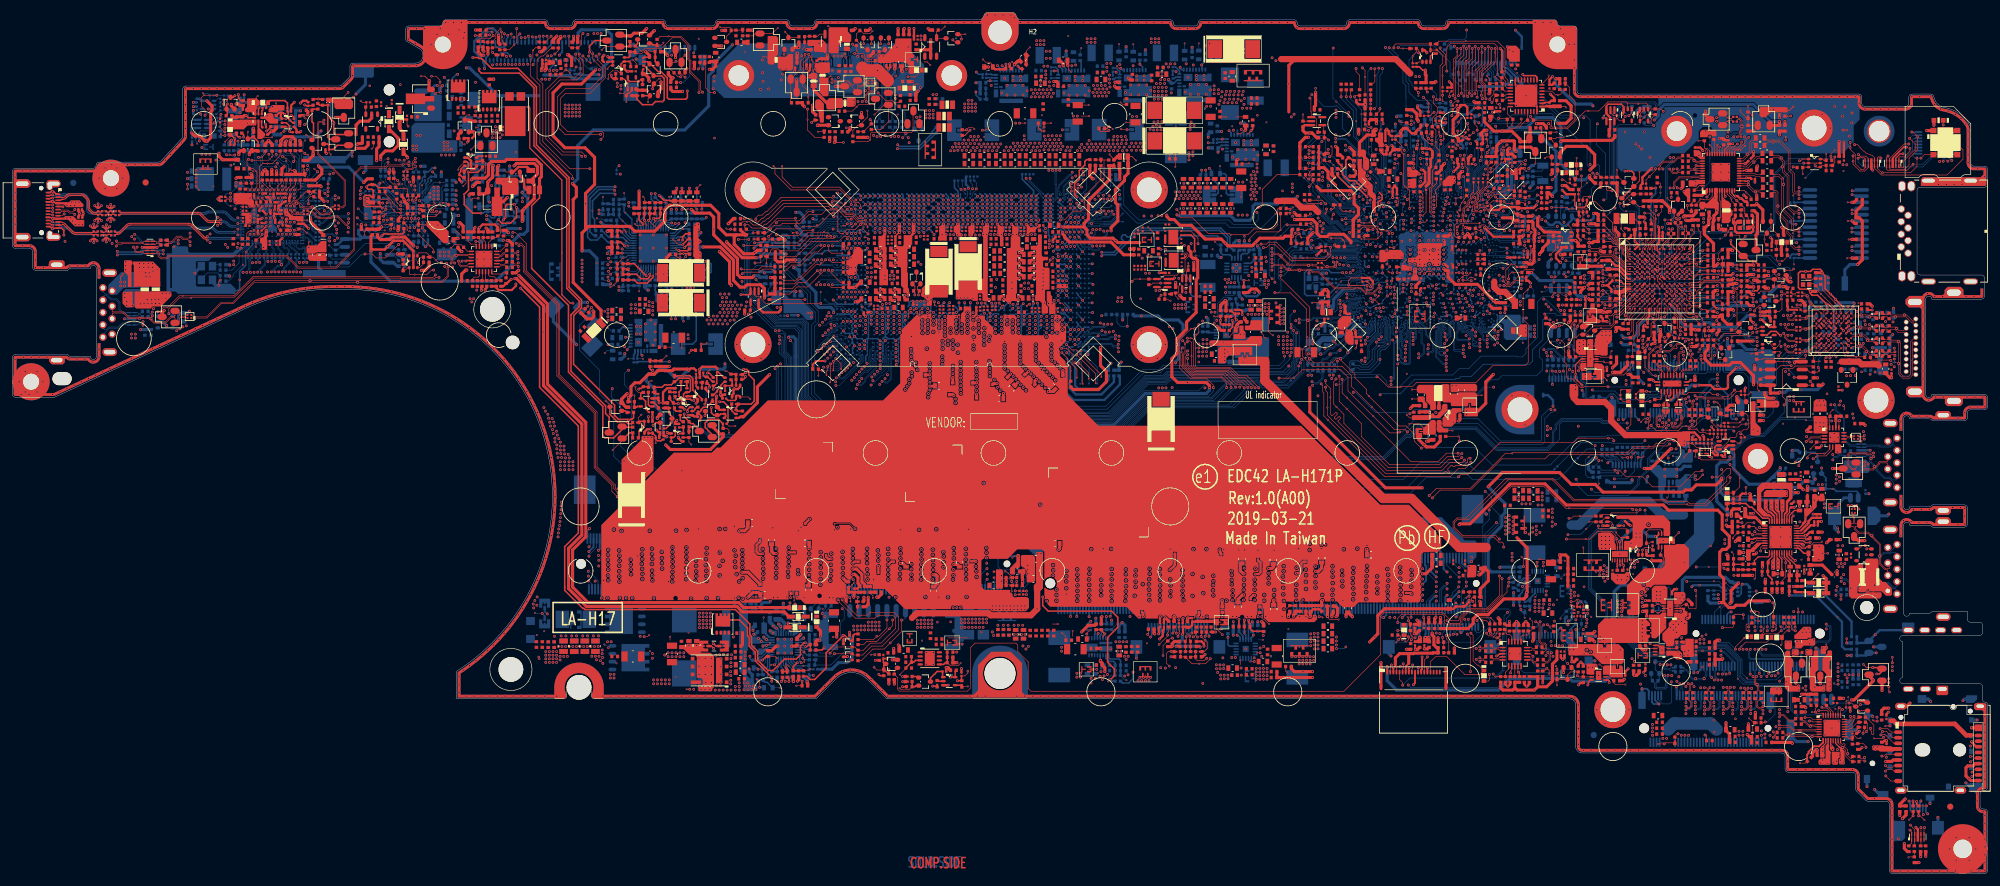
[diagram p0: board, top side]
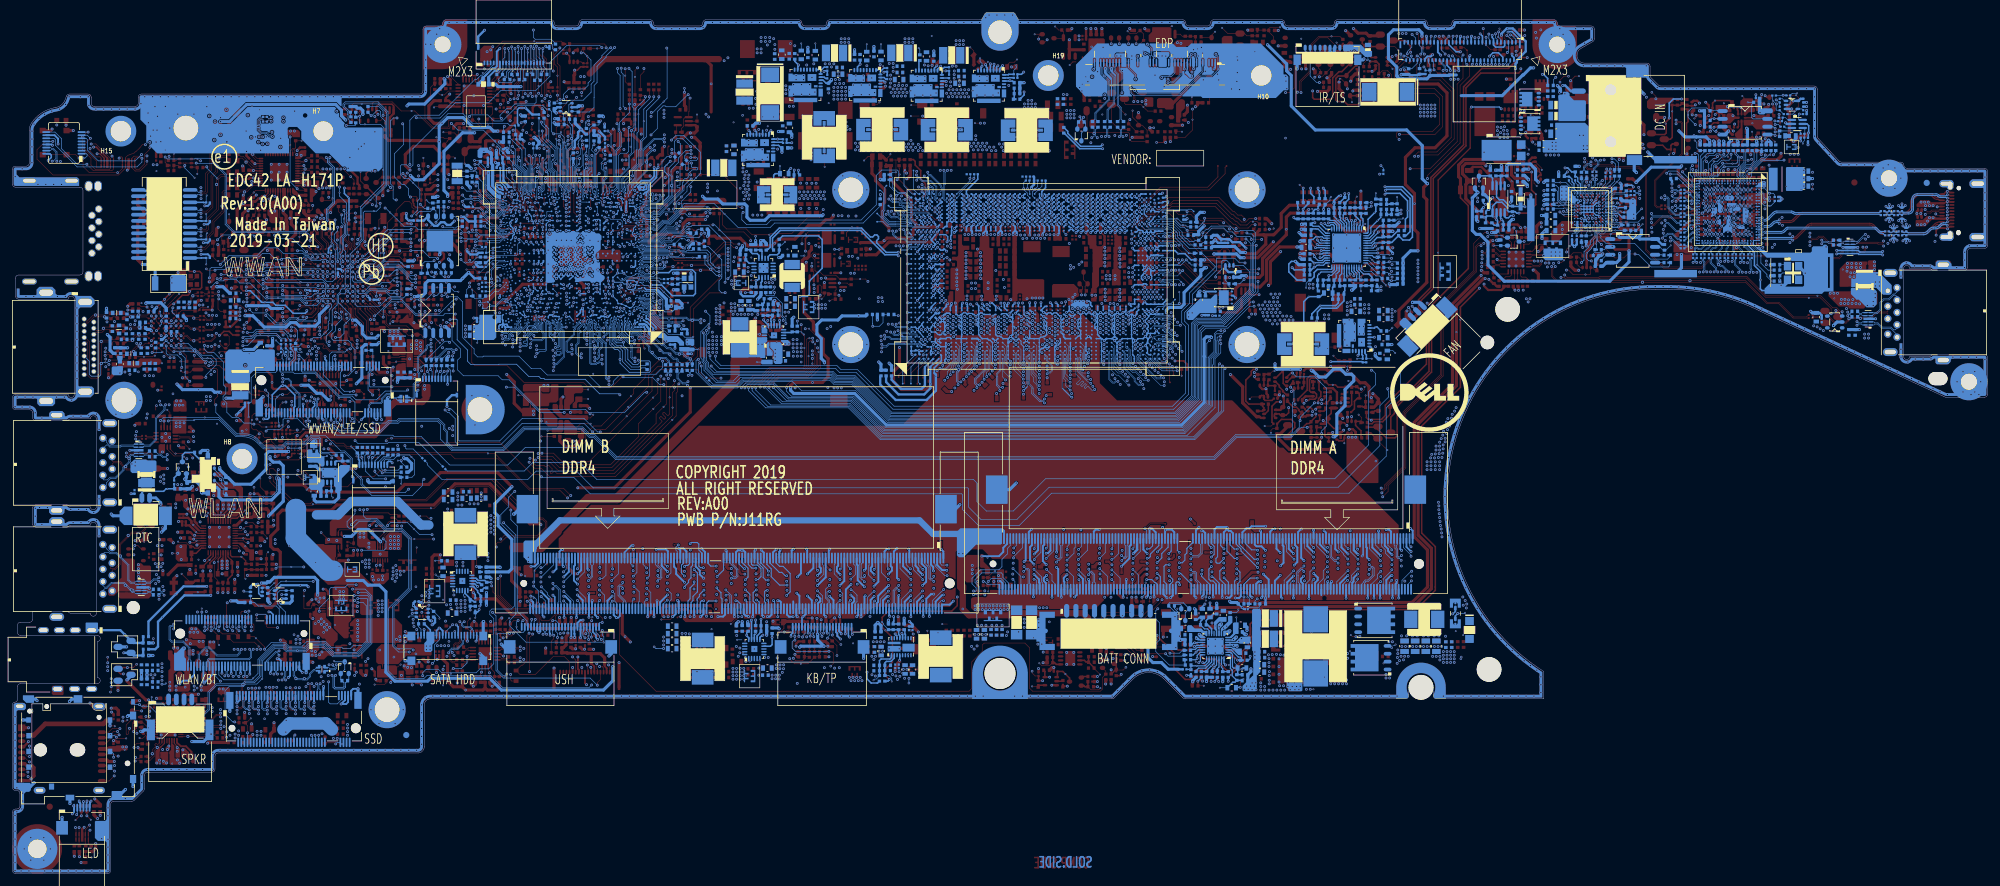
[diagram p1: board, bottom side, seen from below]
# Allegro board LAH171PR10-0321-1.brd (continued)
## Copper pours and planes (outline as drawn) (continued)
+0.9V_TBT_PCIE on BOTTOM (solid shape): 42.11,106.35 42.14,106.29 42.13,106.23 41.96,105.94 42.14,105.65 42.17,105.64 42.17,104.95 42.69,104.44 42.74,104.38 42.74,103.61 42.71,103.58 42.66,103.53 42.6,103.53 42.36,103.76 42.33,103.77 42.21,103.77 42.06,103.91 41.88,103.91 41.72,103.75 41.58,103.75 41.49,103.66 41.42,103.61 41.36,103.55 41.25,103.55 41.22,103.59 41.22,103.75 41.32,104 41.22,104.24 41.22,104.4 41.3,104.53 41.32,104.69 41.39,104.75 41.46,104.79 41.51,104.85 41.54,105.03 41.42,105.18 41.38,105.25 41.41,105.33 41.47,105.4 41.47,105.45 41.55,105.62 41.47,105.79 41.47,106.1 41.53,106.2 41.54,106.31 41.57,106.38 41.65,106.41 42.04,106.41
+0.9V_TBT_PCIE on TOP: 42.87,101.5 42.87,102.95 42.75,103.07 42.71,103.11 42.58,103.25 42.58,104.44 41.98,105.04 41.98,105.84 41.96,105.93 41.97,106.01 41.97,106.04 41.84,106.17 41.47,106.17 41.37,106.07 41.37,101.47 41.38,101.46 42.84,101.46
+0.9V_TBT_SVR on BOTTOM (solid shape): 32.58,114.08 32.58,110.47 32.45,110.34 29.97,110.34 29.46,110.85 29.46,113.83 29.84,114.21 32.45,114.21
+0.9V_TBT_SVR on BOTTOM (solid shape): 42.11,108.32 42.11,107.87 42.03,107.79 42,107.8 41.86,107.77 41.76,107.67 41.54,107.67 41.36,107.85 41.23,107.85 41.19,107.78 41.07,107.67 41.06,107.67 41,107.67 40.93,107.67 40.87,107.7 40.72,107.85 40.72,108 40.54,108.18 40.54,108.28 40.64,108.38 42.04,108.38
+0.9V_TBT_SVR on BOTTOM (solid shape): 39.44,107.68 39.48,107.64 39.57,107.56 39.57,105.4 39.37,105.2 39.35,105.2 39.25,105.17 39.18,105.1 39.16,105.08 38.92,105.08 38.86,105.15 38.82,105.18 38.82,105.37 38.96,105.51 38.96,105.72 38.74,105.94 38.74,106.07 38.7,106.1 38.65,106.17 38.6,106.22 38.6,106.33 38.72,106.62 38.55,106.89 38.55,107.17 38.72,107.34 38.74,107.34 38.84,107.38 38.92,107.46 38.93,107.49 38.95,107.54 38.98,107.57 39,107.57 39.16,107.59 39.3,107.68
+0.9V_TBT_SVR on TOP: 38.89,105.07 38.79,105.17 38.79,106.8 38.67,106.91 38.67,106.91 38.61,106.97 37.02,106.97 36.89,106.85 36.89,106.27 36.96,106.21 37.4,106.21 37.46,106.15 37.46,105.19 37.4,105.13 36.58,105.13 36.39,105.32 36.39,107.73 36.64,107.99 37.97,107.99 38.03,107.93 38.03,107.71 38.03,107.62 38.12,107.53 39.47,107.53 39.58,107.42 39.57,107.42 39.57,106.81 39.62,106.81 39.69,106.74 39.92,106.74 40,106.67 40,106.13 39.55,106.13 39.47,106.05 39.47,105.15 39.4,105.07
+0.9V_TBT_SVR on IN2: 29.91,104.52 28.89,105.53 28.89,114.15 29.27,114.53 35.32,114.53 35.69,114.15 35.69,109.84 37,108.53 43.06,108.53 43.54,108.05 43.54,102.66 43.32,102.44 37.75,102.44 37.35,102.84 34.25,102.84 32.57,104.52
+1.0V_ALW_PCH on BOTTOM (solid shape): 210.31,86.37 210.31,85.54 210.15,85.39 208.98,85.39 208.91,85.46 208.91,85.99 208.91,85.99 208.91,86.31 209.1,86.5 210.18,86.5
+1.0V_ALW_PCH on TOP: 241.57,100.6 241.68,100.49 241.68,100.16 241.55,100.04 241.17,100.04 241.04,99.91 241.04,99.22 241.17,99.1 241.52,99.1 241.68,98.94 241.68,98.36 241.55,98.23 241.02,98.23 241,98.24 240.41,98.24 240.34,98.18 237.36,98.18 237.29,98.24 237.29,100.47 237.43,100.6
+1.0V_ALW_PCH on TOP: 243.07,84.34 241.23,82.5 239.14,82.5 236.31,79.67 226.6,79.67 226.12,79.19 218.5,79.19 214.75,82.94 210.18,82.94 209.55,83.58 209.55,86.31 212.28,89.04 212.28,91.13 212.53,91.39 213.01,91.39 213.01,93.46 213.8,94.24 217.61,94.24 218.63,93.23 220.53,93.23 221.16,93.86 221.16,94.19 221.1,94.25 221.1,94.82 219.96,95.96 219.96,98.12 220.31,98.47 222.59,98.47 222.62,98.5 223.9,98.5 223.96,98.44 223.96,97.57 224.22,97.32 224.22,94.88 225.86,94.88 226.18,94.56 226.18,94.21 227.03,94.21 227.11,94.13 227.11,92.68 227.52,92.28 227.52,90.75 226.94,90.75 226.94,90.12 227.52,90.12 227.52,89.99 226.94,89.99 226.94,89.35 227.52,89.35 227.52,88.97 227.58,88.91 236.98,88.91 239.07,91.01 240.6,91.01 240.72,91.13 240.72,91.64 240.85,91.77 241.42,91.77 243.07,90.12 ; 2 cut-outs
+1.0V_ALW_PCH on IN1: 240.22,90.18 241.55,90.18 241.93,90.56 241.93,100.59 241.74,100.78 240.09,100.78 238.88,99.57 238.88,93.82 239.77,92.92 239.77,90.62
+1.0V_ALW_PCH on VCC: 211.19,84.2 209.8,85.59 209.8,89.06 218.17,97.43 226.73,97.43 226.73,92.15 229.52,89.35 237.88,89.35 238.54,90.01 238.54,100.07 239.23,100.76 241.91,100.76 242.93,99.74 242.93,86.46 240.67,84.2
+1.0V_ALW_PCH on IN2: 241.08,98.27 241.08,98.78 239.9,99.96 239.9,100.59 240.15,100.85 241.74,100.85 242.85,99.74 242.85,95.01 242.13,94.29 241.37,94.29 241.07,94.6 241.07,98.26
+1.0V_AMPHYPLL on TOP (solid shape): 244.67,88.68 244.67,86.86 244.57,86.75 243.42,86.75 243.3,86.88 243.3,88.47 243.61,88.78 244.57,88.78
+1.0V_AMPHYPLL on BOTTOM (solid shape): 243.63,90.23 243.63,88.99 243.9,88.72 244.47,88.72 244.66,88.53 244.66,86.37 244.53,86.24 241.3,86.24 240.89,86.65 240.89,88.73 240.6,89.02 240.18,89.02 240.14,89.06 240.14,89.42 240.15,89.44 240.15,89.95 240.84,89.95 240.84,89.9 240.85,89.85 240.86,89.8 240.89,89.75 240.92,89.71 240.95,89.67 241,89.64 241.04,89.62 241.09,89.6 241.14,89.6 241.19,89.6 241.25,89.6 241.3,89.62 241.34,89.64 241.38,89.67 241.42,89.71 241.45,89.75 241.47,89.8 241.49,89.85 241.5,89.9 241.5,89.95 241.49,90 241.47,90.05 241.45,90.1 241.42,90.14 241.38,90.18 241.34,90.21 241.3,90.23 241.25,90.25 241.19,90.26 241.14,90.26 241.09,90.25 241.04,90.23 241,90.21 240.95,90.18 240.92,90.14 240.89,90.1 240.86,90.05 240.85,90 240.84,89.95 240.15,89.95 240.15,90.27 240.2,90.31 240.77,90.31 240.79,90.33 243.53,90.33
+1.0V_AZPLL on TOP (solid shape): 216.28,90.05 216.28,88.97 215.2,87.89 214.43,87.89 214.05,88.28 214.05,89.35 214.82,90.12 216.21,90.12
+1.0V_BCLKPLL2 on BOTTOM (solid shape): 211.32,84.5 211.2,84.37 208.98,84.37 208.85,84.5 208.85,84.95 208.91,85.01 209.59,85.01 209.69,85.1 211.32,85.1
+1.0V_BCLKPLL2_R on BOTTOM (solid shape): 217.93,88.91 217.93,88.62 217.89,88.58 217.85,88.56 217.67,88.56 217.51,88.61 217.35,88.56 217.17,88.56 216.89,88.58 216.73,88.35 216.73,88.34 216.66,88.2 216.64,88.19 216.46,88.03 216.43,87.8 216.43,87.79 216.43,87.4 216.44,87.39 216.44,87.23 216.08,86.87 215.24,86.87 215.24,86.87 214.98,86.87 214.68,86.57 214.22,86.57 213.48,85.84 213.14,85.84 213.05,85.93 211.7,85.93 211.32,85.54 211.32,85.35 210.56,85.35 210.56,85.93 211.51,86.88 213.2,86.88 213.71,87.39 215.44,87.39 215.78,87.45 215.91,87.77 215.91,88.04 216.48,88.61 216.48,88.73 216.65,88.9 216.67,88.9 216.78,88.93 216.87,89.01 217.83,89.01
+1.0V_DUSB on TOP: 227.13,95.83 227.33,96.02 227.33,96.66 227.07,96.91 227.07,97.17 227.2,97.29 227.32,97.29 227.62,96.99 227.64,96.99 227.64,96.78 227.83,96.59 227.83,95.83 227.45,95.45 227.13,95.45
+1.0V_MPHY on TOP: 227.71,90.37 227.2,90.37 227.2,90.56 227.71,90.56 227.71,93.62 227.9,93.81 227.9,95.7 228.09,95.9 228.09,96.91 228.34,97.17 231.39,97.17 231.58,96.97 231.58,96.28 232.91,94.94 236.41,94.94 237.99,93.36 237.99,90.24 236.79,89.04 227.77,89.04 227.71,89.1 227.71,89.55 227.2,89.55 227.2,89.74 227.71,89.74
+1.0V_MPHY on VCC: 229.73,89.86 227.24,92.36 227.24,97.43 238.03,97.43 238.03,90.22 237.67,89.86
+1.0V_MPHY on IN2: 227.71,97.04 227.96,97.29 236.85,97.29 237.99,96.15 237.99,89.55 237.49,89.04 228.09,89.04 227.71,89.42
+1.0V_OC on TOP: 226,97.34 226.07,97.26 226.07,96.8 225.74,96.47 225.74,95.64 225.67,95.58 224.53,95.58 224.47,95.64 224.47,96.72 225.08,97.34
+1.0V_OCPLL1 on TOP: 217.13,85.09 216.78,85.44 216.78,86.31 216.85,86.37 217.99,86.37 218.24,86.12 218.24,85.21 218.13,85.09
+1.0V_OCPLL1_R on TOP (solid shape): 216.53,87.51 216.53,86.94 216.66,86.81 216.66,85.61 216.53,85.48 215.83,85.48 215.21,86.1 215.21,86.9 215.33,87.02 215.33,87.83 215.44,87.95 216.1,87.95
+1.0V_PRIM on TOP (solid shape): outline of 205 points within 225.43,97.92 231.01,101.9
+1.0V_PRIM on TOP: 86.04,130.57 85.91,130.69 85.91,131.65 86.04,131.77 87.31,131.77 87.39,131.69 87.39,130.65 87.31,130.57
+1.0V_PRIM on TOP: 188.16,105.15 188.46,104.85 188.46,103.07 188.78,102.75 190.37,102.75 190.69,102.44 190.69,101.42 190.3,101.04 188.91,101.04 188.53,100.66 188.53,99.32 188.78,99.07 188.97,99.07 189.16,98.88 189.16,97.67 188.91,97.42 188.53,97.42 187.96,96.85 186.62,96.85 186.62,105.06 186.71,105.15
+1.0V_PRIM on TOP: 203.7,89.29 204.21,89.29 204.21,90.12 203.7,90.12 203.7,90.5 204.21,90.5 204.21,91.32 203.64,91.32 203.64,92.47 203.83,92.66 207.01,92.66 208.78,90.88 208.78,85.35 208.15,84.72 208.15,83.45 208.02,83.32 204.21,83.32 203.7,83.83
+1.0V_PRIM on VCC: 219.1,77.31 214.84,81.56 203.14,81.56 201.61,83.08 201.61,92.45 203.79,94.63 203.79,96.5 203.64,96.64 203.62,96.64 201.61,98.65 201.61,101.02 200.89,101.74 196.04,101.74 194.39,100.09 188.15,100.09 188.15,102.79 189.37,104.01 202.28,104.01 205.54,107.26 230.59,107.26 233.44,104.4 243.54,104.4 247.07,100.87 247.07,77.98 219.77,77.98 ; 1 cut-out
+1.0V_PRIM on IN2: 203.77,92.66 205.35,92.66 205.8,92.21 205.8,88.08 206.94,86.94 206.94,83.58 206.69,83.32 203.77,83.32 203.26,83.83 203.26,92.15
+1.0V_PRIM_CNV_HVLO on TOP (solid shape): 221.68,100.82 222.01,100.47 222.34,100.82 224.24,100.82 224.75,100.31 224.75,99.42 224.65,99.32 222.24,99.32 221.75,98.83 220.9,98.83 220.78,98.94 220.78,100.59 221.01,100.82
+1.0V_PRIM_FUSE on TOP: 231.07,98.88 230.92,99.03 230.92,99.42 231.03,99.52 231.28,99.52 231.51,99.29 235.45,99.29 235.87,98.88 236.98,98.88 237.04,98.82 237.04,98.24 236.98,98.18 235.58,98.18 234.88,98.88
+1.0V_PRIM_XDP on TOP: 88.04,130.23 88.26,130.02 88.26,129.91 88.31,129.86 88.92,129.86 89.06,129.99 89.06,130.07 89.27,130.28 89.63,130.28 89.68,130.32 89.68,131.94 89.1,132.51 88.22,132.51 88.04,132.34
+1.0V_PRIM_XDP on BOTTOM: 89.37,131.2 89.24,131.07 88.96,131.07 88.83,131.2 88.83,131.77 88.7,131.9 88.13,131.9 88.04,131.99 88.04,132.31 88.27,132.54 89.2,132.54 89.37,132.37
+1.0V_SRC on TOP (solid shape): 225.31,98.2 225.54,98.2 225.74,98.12 225.96,98.18 225.99,98.21 226.05,98.15 226.05,97.51 226,97.46 224.42,97.46 224.37,97.52 224.37,98.35 224.4,98.38 225.13,98.38
+1.0V_VCCSFR_R on IN2: 169.23,103.81 168.76,103.34 168.28,103.34 167.85,102.92 167.74,102.92 167.32,102.5 167.32,102.31 167.55,102.08 168.48,102.08 168.63,101.93 176.82,101.93 177.84,102.94 177.84,104.02 177.71,104.15 177.39,104.15 177.05,103.81
+1.0V_VCCST on TOP: 181.61,100.66 181.73,100.53 182.18,100.53 182.5,100.21 183.36,100.21 183.45,100.3 183.45,102.18 182.88,102.18 182.88,102.69 183.45,102.69 183.45,103.85 183.22,104.07 182.39,104.07 181.99,103.67 181.67,103.67 181.55,103.55 181.55,103.17 181.47,103.08 181.07,103.08 180.97,102.98 180.97,101.45 181.02,101.4 181.52,101.4 181.61,101.32
+1.0V_VCCST_C on TOP: 183.7,103.07 185.73,103.07 186.05,103.39 186.3,103.39 186.49,103.2 186.49,101.86 186.3,101.67 183.7,101.67 183.64,101.74 183.64,102.37 183.07,102.37 183.07,102.5 183.64,102.5 183.64,103.01
+1.0V_VCCSTG on TOP: 184.59,99.26 183.32,99.26 182.24,100.34 180.78,100.34 180.59,100.15 180.59,98.5 181.1,97.99 184.59,97.99 184.65,98.05 184.65,98.31 184.08,98.31 184.08,98.82 184.65,98.82 184.65,99.2
+1.0V_VCCSTG_C on TOP: 185.42,100.47 184.78,100.47 184.72,100.4 184.72,99.45 184.84,99.32 184.84,98.63 184.27,98.63 184.27,98.5 184.84,98.5 184.84,97.93 184.91,97.86 186.43,97.86 186.49,97.93 186.49,99.58 186.37,99.71 185.67,99.71 185.54,99.83 185.54,100.34
+1.0V_XTAL on TOP: 212.86,92.72 210.99,92.72 210.87,92.61 210.87,90.41 211.09,90.19 212.01,90.19 212.14,90.32 212.14,91.3 212.27,91.43 212.75,91.43 212.93,91.61 212.93,92.65
+1.0V_XTAL on BOTTOM: 217.42,94.82 217.58,94.65 217.98,94.65 217.98,94.5 217.95,94.47 217.07,94.47 216.79,94.2 215.17,94.2 215.1,94.13 214.94,94.13 214.73,94.34 214.73,94.54 214.9,94.71 216.25,94.71 216.35,94.82
+1.0VS_VCCIO on TOP: 167.82,93.67 167.82,97.85 167.94,97.98 168.34,97.98 168.45,98.09 168.45,98.52 168.48,98.55 169.11,98.55 169.13,98.53 177.57,98.53 183.8,92.3 189.7,92.3 190.05,91.95 190.05,90.45 189.15,89.55 171.89,89.55 171.41,90.02 171.41,92.92 170.46,93.88 170.41,93.88 169.76,93.88 169.02,93.13 168.36,93.13
+1.0VS_VCCIO on BOTTOM: 175.06,99.45 173.73,100.78 171.32,100.78 169.98,102.12 169.98,102.69 169.79,102.88 167.64,102.88 167.13,102.37 167.13,93.55 169.79,90.88 181.67,90.88 182.62,89.93 190.37,89.93 190.56,90.12 190.56,90.88 190.05,90.88 190.05,91.51 190.56,91.51 190.56,91.64 190.05,91.64 190.05,92.28 190.56,92.28 190.56,94.75 187.88,97.43 187.88,99.24 187.67,99.45
+1.0VS_VCCIO on IN1: 154.86,84.54 154.08,85.32 154.08,91.08 156.45,91.08 158.28,89.25 158.28,85.29 157.53,84.54
+1.0VS_VCCIO on IN1: 167.5,93.28 167.5,97.62 166.68,98.44 166.68,101.42 167.25,101.99 167.7,101.99 167.95,101.74 168.49,101.74 168.6,101.63 168.6,100.91 169.67,99.84 172.1,99.84 172.35,99.59 173.38,99.59 173.72,99.92 173.72,100.58 173.73,100.59 181.33,100.59 189.77,92.15 189.77,90.96 188.33,89.51 182.02,89.51 179.26,86.75 179.26,84.39 175.51,84.39 175.24,84.66 175.24,85.54
+1.0VS_VCCIO on VCC: 179.79,89.53 179.08,90.24 168.84,90.24 168.84,92.58 168.51,92.91 168.51,97.36 166.33,99.54 166.33,102.31 168.48,102.31 169.88,100.91 172.1,100.91 173.44,99.58 191.65,99.58 191.65,89.53 ; 1 cut-out
+1.0VS_VCCIO on IN2: 174.07,85.95 174.07,87.98 170.6,91.45 169.33,91.45 166.68,94.1 166.68,101.42 167.25,101.99 167.7,101.99 167.95,101.74 177.22,101.74 178.94,100.02 184.78,100.02 185.03,99.77 185.03,89.42 184.4,88.78 182.24,88.78 180.34,86.88 180.34,85.29 179.32,84.27 175.74,84.27
+1.0VS_VCCIO on IN3: 168.02,98.31 171.13,98.31 172.27,97.17 177.67,97.17 182.58,92.25 189.82,92.25 190.08,92 190.08,89.51 188.63,88.06 181.45,88.06 180.34,86.94 180.34,84.85 179.32,83.83 176.68,83.83 174.66,85.85 174.66,87.73 172.81,89.58 169.57,89.58 166.87,92.28 166.87,101.93 167.03,102.09 168.3,102.09 168.52,101.86 168.52,101.42 167.95,100.85 167.95,98.37
+1.0VS_VCCIO on IN4: 168.46,102.18 167.06,102.18 166.81,101.93 166.81,94.56 168.27,93.1 170.68,93.1 171,93.42 171,99.45 170.18,100.28 169.22,100.28 168.52,100.98 168.52,102.12
+1.2V_DDRP on TOP: 158.94,40.52 168.21,40.52 168.59,40.14 168.59,39.13 168.52,39.06 158.94,39.06 158.75,39.25 158.75,40.33
+1.2V_DDRP on BOTTOM: 164.69,34.71 165.1,34.3 165.1,30.87 165.54,30.43 170.75,30.43 171.51,31.19 171.51,32.14 172.46,33.09 173.86,33.09 174.18,33.41 174.18,34.55 174.49,34.87 174.49,35.57 174.4,35.67 172.81,35.67 172.52,35.38 168.21,35.38 167,36.59 167,40.46 166.11,41.35 161.41,41.35 161.41,41.92 161.03,41.92 161.03,41.35 160.27,41.35 160.27,41.92 159.89,41.92 159.89,41.35 158.81,41.35 158.55,41.09 158.55,39.38 158.87,39.06 163.76,39.06 164.03,38.79 164.03,38.32 164.69,37.66
+1.2V_LDO on TOP (solid shape): 293,21.84 293,21.03 292.69,20.72 292.69,18.83 292.6,18.74 292.04,18.74 291.98,18.81 291.98,20.27 292.79,21.08 292.79,21.84 292.87,21.92 292.92,21.92
+1.2V_LDO on TOP (solid shape): 295.95,19.81 295.95,18.09 295.97,18.08 295.97,17.75 295.87,17.65 295.26,17.65 295.04,17.88 295.04,18.43 295.27,18.66 295.27,19.7 295.16,19.8 295.16,20.22 294.97,20.41 294.97,20.6 295.16,20.6
+1.2V_LDO on IN2: 295.82,19.58 293.61,19.58 293.24,19.95 293.24,20.84 293.11,20.97 292.35,20.97 292.01,20.62 292.01,19.06 292.26,18.81 293.28,18.81 293.37,18.72 294.81,18.72 295.08,18.45 295.08,17.85 295.33,17.6 296.05,17.6 296.12,17.68 296.12,19.28
+1.2V_LSPCON_VDD on BOTTOM: 295.59,88.02 295.97,88.02 296.6,87.39 296.98,87.39 297.18,87.58 297.49,87.58 297.62,87.7 302.19,87.7 302.26,87.64 302.26,86.12 302.06,85.93 301.24,85.93 301.05,86.12 301.05,86.75 300.92,86.88 295.65,86.88 295.46,87.07 295.46,87.89
+1.2V_LSPCON_VDD on IN2: 296.17,87.64 296.17,88.73 295.86,89.03 294.78,89.03 293.96,89.86 293.39,89.86 293.13,89.6 293.13,89.34 293.94,88.52 295.08,87.39 295.91,87.39
+1.2V_LSPCON_VDDA on BOTTOM: 294.84,83.83 294.44,83.83 294.25,83.64 294.25,82.31 294.51,82.05 299.27,82.05 299.33,82.12 299.33,83.04 299.22,83.16 295.51,83.16
+1.2V_LSPCON_VDDRX on BOTTOM: 291.9,86.7 292.03,86.82 292.03,89.48 292.01,89.48 291.9,89.58 291.8,89.58 291.19,88.97 290.61,88.97 290.46,89.13 290.46,90.04 290.99,90.57 292.08,90.57 292.64,91.13 292.64,91.67 292.51,91.79 289.26,91.79 288.91,91.44 287.98,91.44 286.82,92.59 286.38,92.59 285.43,93.55 283.52,93.55 283.46,93.48 283.46,87.07 283.83,86.7
+1.2V_LSPCON_VDDTX on BOTTOM: 296.44,91.89 297.32,91.89 297.33,91.88 298.1,92.66 301.68,92.66 301.94,92.4 301.94,90.31 301.81,90.18 300.22,90.18 300.16,90.24 300.16,90.37 300.03,90.5 298.64,90.5 298,89.86 298,88.85 297.87,88.72 297.11,88.72 296.67,88.28 296.48,88.28 296.29,88.47 296.29,90.24 296.41,90.37 296.57,90.37 296.82,90.62 296.82,91.19 296.63,91.38 296.44,91.38 296.31,91.51 296.31,91.76
+1.2V_LSPCON_VDDTX on IN3: 296.86,91.86 296.86,88.5 296.29,87.93 294.04,87.93 293.73,88.24 293.73,91.62 294.05,91.93 296.8,91.93
+1.2V_MEM on TOP (solid shape): 131.88,61.16 123.88,61.16 123.88,69.16 131.88,69.16
+1.2V_MEM on TOP (solid shape): 152.83,60.69 144.83,60.69 144.83,68.69 152.83,68.69
+1.2V_MEM on TOP (solid shape): 182.9,54.99 167.9,54.99 167.9,64.99 182.9,64.99
+1.2V_MEM on TOP (solid shape): outline of 25591 points within 95.12,40.65 230.81,91.67
+1.2V_MEM on BOTTOM: 121.7,92.17 121.7,92.78 121.83,92.91 122.4,92.91 122.51,93.02 122.51,94.33 122.61,94.43 124.14,94.43 124.2,94.37 124.2,91.89 124.33,91.77 124.33,89.99 124.27,89.94 123.94,89.94
+1.2V_MEM on BOTTOM: 158.36,44.4 163.89,44.4 164.08,44.21 164.08,41.98 163.63,41.54 161.67,41.54 161.67,42.11 160.84,42.11 160.84,41.54 160.46,41.54 160.46,42.11 159.63,42.11 159.63,41.54 158.24,41.54 158.05,41.73 158.05,44.08
+1.2V_MEM on IN3: 123.12,92.59 123.12,91.32 123.63,90.82 127.88,90.82 128.58,91.51 131.31,91.51 131.63,91.83 134.62,91.83 135.57,90.88 144.01,90.88 144.58,90.31 144.58,89.3 144.89,89 144.89,86.64 144.99,86.54 146.57,86.54 146.74,86.71 146.74,91.32 145.73,92.34 137.66,92.34 136.65,93.36 123.88,93.36
+1.2V_RUN on BOTTOM: 301.43,88.21 301.3,88.34 301.3,89.8 301.49,89.99 302.19,89.99 302.38,90.18 302.38,90.88 302.51,91.01 303.14,91.01 303.14,90.31 303.4,90.05 304.16,90.05 304.22,89.99 304.22,88.53 303.91,88.21
+1.2V_RUN on BOTTOM: 271.27,64.17 271.27,64.62 271.31,64.66 272.25,64.66 272.37,64.54 272.37,63.79 272.36,63.79 272.36,63.41 272.27,63.32 271.46,63.32 271.28,63.5 271.28,63.98 270.72,63.98 270.72,63.98 270.72,64.16 270.72,64.17 271.27,64.17
+1.2V_RUN on BOTTOM: 299.84,82.83 299.84,80.63 299.98,80.49 300.62,80.49 300.93,80.81 300.93,80.83 301.1,81 301.1,81.18 300.95,81.33 300.95,82.65 300.69,82.9 299.92,82.9
+1.2V_RUN on BOTTOM: 283.21,94.24 281.05,94.24 280.86,94.05 280.86,92.28 280.98,92.15 281.94,92.15 282,92.21 283.21,92.21 283.33,92.34 283.33,94.12
+1.2V_RUN on IN2: 286.19,81.58 286.19,72.31 288.65,69.85 288.65,67.56 288.27,67.18 288.27,65.48 288.58,65.17 290.23,65.17 291.32,66.27 291.32,70.97 288.93,73.35 288.93,81.58 288.35,82.17 286.77,82.17
+1.2V_RUN on IN3: 271.33,62.99 271.33,64.31 271.69,64.67 272.56,64.67 272.73,64.49 277.12,64.49 278.77,62.84 283.47,62.84 286.67,66.04 286.67,66.44 287.56,67.33 288.5,67.33 288.86,66.98 288.86,65.68 288.04,64.87 288.04,64.54 286.39,62.89 286.06,62.89 284.06,60.88 277.83,60.88 276.41,62.3 272.02,62.3
+1.2V_RUN on IN3: 303.79,89.79 301.4,89.79 299.68,88.06 299.68,83.39 299.14,82.85 289.26,82.85 288.78,83.34 286.32,83.34 285.68,82.7 285.68,81.51 286.77,80.41 291.63,80.41 291.73,80.52 299.02,80.52 299.19,80.34 299.91,80.34 299.96,80.39 301.68,80.39 302.19,80.9 302.19,86.81 304.07,88.69 304.07,89.51
+1.2V_RUN on IN4: 280.88,93.09 280.88,92.43 282.35,90.96 282.35,84.5 286.57,80.29 287.05,80.29 288.09,81.33 288.09,81.76 284.51,85.34 284.51,86.03 284.48,86.07 284.48,92.11 283.19,93.39 281.19,93.39
+1.05VALWP on TOP: 203.39,91.13 203.45,91.07 203.96,91.07 203.96,90.75 203.39,90.75 203.39,89.93 203.96,89.93 203.96,89.55 203.39,89.55 203.39,88.78 203.26,88.66 202.37,88.66 202.05,88.97 202.05,89.48 201.93,89.61 199.64,89.61 199.13,90.12 199.13,91.13 199.39,91.39 199.4,91.39 199.47,91.46 201.94,91.46 202.12,91.64 202.12,92.28 202.34,92.5 203.16,92.5 203.39,92.28
+1.05VALWP on BOTTOM: 198.31,88.67 198.31,90.18 198.5,90.37 198.94,90.37 199.26,90.69 199.26,91.34 199.39,91.46 201.99,91.46 202.12,91.59 202.12,92.33 202.22,92.43 203.44,92.43 203.89,91.97 203.89,87.27 203.7,87.08 199.89,87.08
+1.8V_ALW_PCHRES on TOP: 220.53,115.81 220.47,115.74 219.39,115.74 218.82,116.31 218.82,118.79 218.95,118.92 219.84,118.92 219.9,118.85 219.9,118.35 220.04,118.21 220.04,118.19 220.05,118.19 220.09,118.16 220.22,118.16 220.53,117.84
+1.8V_ALW_VTR3 on TOP (solid shape): 255.58,92.14 255.58,91.47 255.78,91.27 256.86,91.27 256.96,91.12 257.13,91.04 257.13,90.59 257.08,90.55 255.33,90.55 255.32,90.53 254.92,90.53 254.92,90.53 254.92,89.98 254.91,89.97 254.74,89.97 254.73,89.98 254.73,90.52 254.72,90.53 254.32,90.53 254.31,90.54 254.31,90.75 254.88,91.32 254.88,92.15 254.92,92.19 255.53,92.19
+1.8V_ALW_VTR3 on BOTTOM: 256.48,89.48 256.79,89.16 258.31,89.16 258.77,88.71 258.77,88.39 258.76,88.37 258.76,86.75 258.95,86.56 259.96,86.56 260.22,86.81 260.22,90.37 259.45,91.14 256.56,91.14 256.48,91.06
+1.8V_PHVLDO on TOP: outline of 82 points within 223.3,99.67 226.94,112.84
+1.8V_PRIM on TOP (solid shape): 235.45,75.32 236.6,75.32 236.72,75.19 236.72,73.99 236.63,73.89 234.57,73.89 234.51,73.95 234.51,75.14 234.69,75.32 235.33,75.32 235.33,75.89 235.45,75.89
+1.8V_PRIM on TOP (solid shape): 269.74,35.6 269.74,35.5 269.64,35.25 269.74,35.01 269.74,34.74 269.62,34.62 268.73,34.62 268.09,35.25 267.2,35.25 267.14,35.32 267.14,35.95 267.2,36.01 269.32,36.01
+1.8V_PRIM on TOP (solid shape): 254.58,90.37 254.58,89.85 254.6,89.83 255.07,89.83 255.07,89.85 255.07,90.38 255.33,90.38 256.1,89.61 256.34,89.61 256.54,89.42 256.54,89.1 256.41,88.97 255.07,88.97 254.07,87.97 253.4,87.97 253.23,88.14 253.23,88.61 253.53,88.91 253.75,88.91 254.29,89.44 254.29,90.35 254.33,90.4 254.55,90.4
+1.8V_PRIM on TOP: 220.91,115.71 219.71,115.71 219.39,115.39 219.39,114.37 220.72,113.04 221.36,113.04 221.55,113.23 221.55,115.07
+1.8V_PRIM on TOP: 190.69,95.01 190.69,92.66 190.56,92.53 190.05,92.53 189.86,92.72 189.86,93.16 189.29,93.74 189.29,95.26 189.48,95.45 190.24,95.45
+1.8V_PRIM on TOP: 207.01,111.71 203.46,111.71 202.12,110.36 202.12,107.71 201.23,106.82 198.05,106.82 197.61,106.37 197.61,104.34 197.8,104.15 203.26,104.15 204.15,105.04 204.15,107.66 206.1,109.61 206.81,109.61 207.13,109.93 207.13,111.58
+1.8V_PRIM on TOP: 272.52,74.51 274.93,74.51 275.21,74.79 275.21,75.65 274.2,76.67 274.2,76.68 273.67,76.68 272.44,75.45 272.44,74.59
+1.8V_PRIM on TOP: 211.64,105.42 211.39,105.17 211.13,105.17 210.24,106.06 210.24,107.33 210.5,107.58 211.51,107.58 211.64,107.45
+1.8V_PRIM on IN1: 189.1,95.07 189.1,93.61 189.67,93.04 190.88,93.04 190.91,93.07 191.67,93.07 191.89,93.29 191.89,95.01 191.45,95.45 189.48,95.45
+1.8V_PRIM on IN1: 197.73,106.44 197.73,104.53 197.92,104.34 200.02,104.34 200.15,104.47 200.15,106.37 199.89,106.63 197.92,106.63
+1.8V_PRIM on IN2: 210.75,106.65 215.88,106.65 217.41,105.13 217.41,91.41 215.83,89.84 215.83,79.73 217.88,77.68 225.47,77.68 226.96,76.2 235.11,76.2 236.3,75 236.3,74.09 235.95,73.73 232.06,73.73 231.5,73.18 227.77,73.18 227.13,73.81 226.75,73.81 226.73,73.78 225.86,73.78 225.27,74.38 214.78,74.38 211.23,77.92 211.23,98.37 213.39,100.53 213.39,104.34 212.28,105.46 211.62,105.46 211.2,105.04 210.75,105.04 210.4,105.4 210.4,106.3
+1.8V_PRIM on IN2: 268.78,34.95 270.3,34.95 271.48,36.12 271.48,44.6 270.25,45.83 270.25,69.23 267.7,69.23 267.37,68.89 267.37,67.79 267.36,67.78 267.36,36.36
+1.8V_PRIM on IN2: 218.63,115.9 218.63,114.12 216.15,111.64 205.42,111.64 205.29,111.52 205.29,109.61 205.61,109.29 217.99,109.29 220.78,112.09 220.78,115.96 220.66,116.09 218.82,116.09
+1.8V_PRIM on IN4: 273.92,76.76 272.67,76.76 271.1,75.19 271.1,75.16 270.14,74.2 270.14,72.88 267.14,69.88 267.14,68.09 267.37,67.85 269.09,67.85 269.53,68.29 269.53,69.37 272.54,72.38 272.54,73.47 274.28,75.22 274.28,76.4
+1.8V_PRIM on IN4: 253.36,82.12 253.11,81.86 253.11,80.85 252.79,80.53 252.66,80.53 251.96,79.83 251.96,76.4 252.41,75.96 252.41,71.51 252.53,71.38 253.49,71.38 253.58,71.48 253.58,75.23 253.61,75.26 253.61,77.1 253.11,77.61 253.11,79.13 254.88,80.91 254.88,81.8 254.57,82.12
+1.8V_PRIM_PCH on TOP: outline of 97 points within 215.83,100.64 226.09,115.2
+1.8V_RUN on TOP: 291.59,63.19 292.73,63.19 292.86,63.07 292.86,61.92 292.73,61.8 291.78,61.8 291.71,61.86 291.71,62.37 291.46,62.62 291.46,63.07
+1.8V_RUN on TOP: 277.02,54.55 273.79,54.55 273.05,53.81 273.05,40.72 276.62,37.15 276.62,33.78 275.77,32.93 264.82,32.93 264.81,32.91 263.29,32.91 262.85,32.47 262.85,30.51 263.26,30.1 277.48,30.1 278.92,31.54 278.92,38.16 275.34,41.74 275.34,51.99 276.01,52.66 277.19,52.66 277.37,52.84 277.37,54.21
+1.8V_RUN on TOP: 262.89,35.95 261.55,35.95 261.36,35.76 261.36,33.41 261.55,33.22 262.95,33.22 263.14,33.41 263.14,33.92 262.95,34.11 262.95,35.19 263.52,35.19 263.52,35.32 262.95,35.32 262.95,35.89
+1.8V_RUN on BOTTOM: 261.17,34.92 261.17,31.05 262.02,30.2 263.3,30.2 264.13,31.03 264.13,34.55 263.46,35.22 261.46,35.22
+1.8V_RUN on IN3: 276.44,52.71 274.85,54.3 274.85,55.06 274.83,55.08 274.83,58.92 276.56,60.65 283.9,60.65 286.04,62.79 286.77,62.79 287.03,63.04 287.03,63.09 288.02,64.08 291.9,64.08 292.6,63.38 292.6,61.99 292.41,61.8 289.15,61.8 288.65,61.29 287.97,61.29 287.52,60.84 287.52,60.64 284.62,57.73 279.71,57.73 279.38,57.4 279.38,54.63 277.46,52.71
+1.8V_RUN_AUDIO on TOP (solid shape): 291.59,61.11 292.73,61.11 292.73,60.48 292.6,60.35 291.71,60.35 291.46,60.09 291.46,59.27 289.82,57.62 289.82,56.84 288.95,55.97 288.87,55.97 288.84,56 288.84,56.15 289.05,56.36 289.05,56.68 289.43,57.06 289.43,59.01 290.25,59.01 290.7,59.46 290.7,61.24 290.83,61.36 291.33,61.36
+1.8V_RUN_CARD on TOP: 315.97,21.85 315.91,21.92 315.91,22.74 315.97,22.81 317.88,22.81 317.88,21.85
+1.8V_RUN_CARD on TOP: 303.72,25.22 303.84,25.09 303.84,24.52 303.46,24.14 300.99,24.14 300.86,24.27 300.86,25.41 301.05,25.6 301.24,25.6 301.62,25.22
+1.8V_RUN_CARD on TOP: 294.01,21.94 294.17,21.94 294.22,21.89 294.22,21 295.03,20.19 295.03,19.94 294.93,19.84 294.52,19.84 294.44,19.91 294.44,20.42 293.96,20.9 293.96,21.89
+1.8V_RUN_CARD on IN2: 300.92,25.54 301.37,25.54 301.62,25.28 301.62,23.95 301.43,23.76 300.6,23.76 300.48,23.89 300.48,24.71 300.86,25.09 300.86,25.47
+1.8V_RUN_UZ8 on TOP: 265.67,36.01 263.27,36.01 263.14,35.89 263.14,35.51 263.71,35.51 263.71,35 263.14,35 263.14,34.16 263.27,34.03 263.27,33.86 263.52,33.6 265.3,33.6 265.76,34.06 265.76,35.93
+1.8VALWP on TOP (solid shape): 232.12,78.94 232.12,77.83 232.34,77.61 233.42,77.61 233.61,77.8 236.28,77.8 236.6,77.48 236.6,75.64 236.53,75.58 235.64,75.58 235.64,76.08 235.14,76.08 235.14,75.58 235.11,75.55 232.49,75.55 232.34,75.7 232.34,76.05 232.24,76.14 231.23,76.14 230.84,76.53 230.84,79.02 230.93,79.11 231.95,79.11
+1.24V_LDOSRAM on TOP: 230.5,102.73 227.32,102.73 227.07,102.98 227.07,103.45 227.15,103.53 227.15,104.27 227.18,104.3 227.77,104.88 228.94,104.88 229.07,104.76 229.07,103.74 229.26,103.55 230.5,103.55 230.57,103.49 230.57,102.79
+1VS_VCCIOP on TOP: 193.04,91.07 192.97,91.01 191.77,91.01 191.61,91.16 191.61,95.42 191.77,95.58 192.72,95.58 193.04,95.26
+1VS_VCCIOP on BOTTOM: 196.59,97.29 195.77,97.29 195.64,97.17 191.64,97.17 191.1,96.63 191.1,93.32 190.81,93.04 190.81,92.09 190.24,92.09 190.24,91.89 190.81,91.89 190.81,91.26 190.24,91.26 190.24,91.07 190.81,91.07 190.81,90.5 192.91,90.5 193.29,90.88 193.29,93.29 193.8,93.8 194.37,93.8 195.38,94.82 195.38,96.21 195.83,96.66 196.21,96.66 196.65,97.1 196.65,97.23
+2.5V_MEM on TOP (solid shape): 166.48,51.85 166.48,46.84 166.47,46.83 166.47,46.09 166.08,45.69 165.07,45.69 164.97,45.79 164.97,46.59 165.27,46.89 165.35,46.97 165.35,51.49 165.27,51.57 165.27,51.85 165.4,51.98 166.35,51.98
+2.5V_MEM on BOTTOM (solid shape): 166.49,55.26 166.49,51.45 166.17,51.13 165.41,51.13 163.36,53.18 159.41,53.18 159.22,53.37 159.22,55.07 159.18,55.11 159.08,55.11 159.03,55.06 159.03,53.35 158.95,53.27 158.81,53.27 158.72,53.36 158.72,55.47 159.08,55.83 165.92,55.83
+2.5V_MEM on BOTTOM (solid shape): 235.34,53.84 236.24,53.84 236.51,53.58 236.51,51.14 236.41,51.05 236.28,50.97 236.2,50.83 235.49,50.12 235.12,50.12 235.04,50.2 235.04,51.87 234.99,51.93 234.86,51.93 234.81,51.87 234.81,50.2 234.76,50.15 234.58,50.15 234.53,50.2 234.53,51.87 234.41,52 234.41,52.38 234.31,52.48 234.31,53.67 234.5,53.86 235.33,53.86
+2.5V_MEM on TOP: 231.18,49.6 230.44,49.6 230.41,49.64 230.41,51.87 231.04,51.87 231.23,51.68 236.41,51.68 236.64,51.45 236.64,50.73 236.64,50.72 236.64,50.31 236.52,50.19 235.34,50.19 235.16,50.37 231.94,50.37
+2.5V_MEM on TOP: 145.66,38.54 145.55,38.43 144.99,38.43 144.99,37.84 144.84,37.84 144.84,38.43 144.18,38.43 144.08,38.53 144.08,41.67 144.39,41.98 145.73,41.98 145.98,41.73 145.98,41.22 145.66,40.9
+2.8V_FHV0 on TOP: 231.58,99.45 231.2,99.83 231.07,99.83 230.94,99.96 230.94,100.21 231.07,100.34 231.39,100.34 231.9,99.83 235.78,99.83 235.97,99.64 236.98,99.64 237.04,99.58 237.04,99.07 236.98,99.01 235.96,99.01 235.52,99.45
+2.8V_FHV1 on TOP: 231.9,100.02 231.39,100.53 231.07,100.53 230.94,100.66 230.94,100.98 231.07,101.1 231.71,101.1 232.34,100.47 236.91,100.47 237.04,100.34 237.04,99.83 236.98,99.77 236.09,99.77 235.83,100.02
+3.3V_1.8V_AZIO on TOP (solid shape): 221.42,119.72 221.42,118.09 221.55,117.97 221.55,117.92 221.54,117.91 221.5,117.81 221.49,117.71 221.49,117.46 221.42,117.39 220.79,117.39 220.66,117.52 220.66,117.56 220.67,117.58 220.68,117.83 220.52,118.03 220.52,118.04 220.27,118.28 220.15,118.28 220.1,118.33 220.1,118.92 220.14,118.96 220.3,118.96 220.3,118.96 220.51,118.96 220.61,119.06 220.61,119.77 220.64,119.8 221.34,119.8
+3.3V_1.8V_AZIO_R on IN2: 222.18,117.66 222.18,117.67 222.18,117.74 221.98,117.93 221.61,117.93 220.98,117.29 220.98,110.63 221.23,110.37 221.23,109.17 222.18,108.22 222.43,108.22 222.44,108.21 222.56,108.34 222.56,108.85 222.18,109.23
+3.3V_1.8V_GPPA on TOP: 232.09,110.79 232.5,110.79 233.58,111.87 233.93,111.87 234.43,112.37 235.43,112.37 235.49,112.3 235.49,111.05 235.2,110.75 235.2,110.28 235.14,110.22 234.59,110.22 234.44,110.07 234.44,109.17 233.59,107.85 233.59,107.25 233.57,107.21 233.56,107.17 233.51,107.11 233.43,107.1 233.12,106.93 233.28,106.61 233.33,106.56 233.34,106.48 233.33,106.45 233.32,106.41 233.3,106.34 233.3,106.26 233.3,106.25 233.15,105.89 233.13,105.87 232.97,105.63 233.07,105.35 233.09,105.34 233.09,105.29 233.07,105.27 233,105.18 232.98,105.06 232.98,105.04 232.83,104.88 232.83,103.39 232.7,103.3 232.63,103.3 232.63,103.36 232.45,103.74 232.03,103.68 231.77,103.42 231.33,103.62 231.32,103.73 231.33,103.75 231.38,103.95 231.32,104.14 231.31,104.16 231.33,104.52 231.33,104.53 231.38,104.69 231.35,104.85 231.35,104.86 231.47,106.8 231.48,106.82 231.57,107.03 231.52,107.26 231.58,107.49 231.6,107.5 231.75,107.7 231.73,107.95 231.73,107.96 231.81,108.25 231.82,108.26 231.94,108.44 231.94,108.65 231.93,108.66 231.99,108.86 231.99,108.98 232.15,109.28 231.99,109.57 231.99,110.69
+3.3V_1.8V_GPPD on TOP (solid shape): 225.97,114.18 225.96,114.16 226.14,113.78 226.55,113.83 226.56,113.84 226.63,113.84 226.79,113.68 226.79,113.68 226.94,113.68 227.52,113.1 227.52,112.91 227.45,112.85 226.97,112.85 226.76,112.64 226.01,112.64 225.97,112.6 225.39,112.6 225.3,112.7 225.3,114.16 225.36,114.22 225.93,114.22
+3.3V_1.8V_GPPD on IN3: 227.07,105.17 227.07,109.99 226.82,110.25 225.61,110.25 225.1,110.75 225.1,112.02 225.36,112.28 227.39,112.28 227.52,112.41 227.52,113.23 227.33,113.42 224.98,113.42 223.8,112.25 223.8,110.98 226.18,108.6 226.18,104.34 226.82,103.71 227.45,103.71 227.58,103.83 227.58,104.66
+3.3V_ALW on TOP (solid shape): 270.25,45.27 270.25,44.26 269.49,43.5 268.54,43.5 268.41,43.62 268.41,45.4 268.54,45.53 270,45.53
+3.3V_ALW on TOP (solid shape): 254.21,86.19 254.21,83.91 254.15,83.84 253,83.84 252.56,84.29 252.56,86.13 252.81,86.38 254.02,86.38
+3.3V_ALW on TOP (solid shape): 227.74,71.96 227.74,71.71 227.72,71.7 227.17,71.7 227.17,71.69 227.17,71.22 227.72,71.22 227.72,71.21 227.72,70.52 227.48,70.28 226.82,70.28 226.67,70.43 226.67,71.88 226.79,72 227.7,72
+3.3V_ALW on TOP (solid shape): 258.8,54.53 258.8,53.46 258.99,53.27 258.99,52.38 258.93,52.32 258.29,52.32 258.28,52.31 256.29,52.31 256.22,52.37 256.25,52.6 256.13,52.8 256.13,54.99 256.22,55.08 256.55,55.08 256.62,55.16 258.18,55.16
+3.3V_ALW on TOP (solid shape): 254.23,82.51 254.23,82.43 254.24,82.4 254.23,82.36 254.23,82.03 254.24,82 254.23,81.96 254.23,81.74 254.25,81.74 254.25,81.29 254.19,81.23 253.38,81.23 253.35,81.4 253.23,81.54 253.23,82.37 253.42,82.56 254.19,82.56
+3.3V_ALW on TOP (solid shape): 267.77,56.84 267.77,54.75 267.58,54.56 266.82,54.56 266.7,54.68 266.7,55.7 266.57,55.83 263.72,55.83 263.37,55.47 263.37,53.07 263.01,52.72 262.11,52.72 261.72,52.32 260.39,52.32 260.32,52.38 260.32,53.65 260.45,53.78 261.23,53.78 261.7,54.25 261.7,56.43 263.93,56.43 263.93,56.37 263.93,56.32 263.95,56.27 263.97,56.22 264,56.18 264.04,56.14 264.08,56.1 264.13,56.08 264.18,56.06 264.23,56.05 264.28,56.04 264.34,56.05 264.39,56.06 264.44,56.08 264.48,56.1 264.53,56.14 264.56,56.18 264.59,56.22 264.61,56.27 264.63,56.32 264.64,56.37 264.64,56.43 264.63,56.48 264.61,56.53 264.59,56.58 264.56,56.62 264.53,56.66 264.48,56.69 264.44,56.72 264.39,56.74 264.34,56.75 264.28,56.76 264.23,56.75 264.18,56.74 264.13,56.72 264.08,56.69 264.04,56.66 264,56.62 263.97,56.58 263.95,56.53 263.93,56.48 263.93,56.43 261.7,56.43 261.7,56.67 261.02,57.35 259.14,57.35 259.08,57.41 259.08,57.8 259.2,57.92 266.7,57.92
+3.3V_ALW on TOP: 146.3,136 147.63,136 147.67,135.96 147.67,133.93 147.41,133.68 145.79,133.68 145.6,133.87 145.6,134.31 145.73,134.44 145.92,134.44 145.98,134.5 145.98,135.68
+3.3V_ALW on TOP: 184.27,95.13 185.42,95.13 185.67,94.88 185.67,94.05 185.54,93.93 184.4,93.93 184.15,94.18 184.15,95.01
+3.3V_ALW on TOP: 251.77,100.78 251.39,100.4 251.39,99.13 251.39,99.13 251.17,98.91 250.32,98.91 249.02,97.61 249.02,95.47 249.33,95.16 252.63,95.16 252.8,95.33 252.8,96.64 252.65,96.8 252.65,98.68 252.98,98.68 252.99,98.69 252.99,99.24 253.45,99.24 253.47,99.22 253.47,98.67 253.76,98.67 253.76,99.53 253.92,99.68 255.01,99.68 255.13,99.8 255.13,100.31 255.06,100.37 254.39,100.37 254.25,100.51 254.25,100.71 254.17,100.78
+3.3V_ALW on TOP: 227.9,40.02 231.2,40.02 231.26,39.95 231.26,38.75 231.07,38.55 228.09,38.55 227.77,38.87 227.77,39.89
+3.3V_ALW on TOP: 151.63,38.11 153.54,38.11 153.79,37.86 153.79,36.59 153.47,36.27 151.76,36.27 151.57,36.46 151.57,37.03 152.14,37.03 152.14,37.6 151.57,37.6 151.57,38.05
+3.3V_ALW on TOP: 243.55,57.42 243.55,58.37 243.29,58.62 240.43,58.62 240.18,58.37 240.18,55.17 241.55,53.8 243.23,53.8 243.55,54.11 243.55,55.38 243.04,55.38 243.04,56.21 243.61,56.21 243.61,56.59 243.04,56.59 243.04,57.42
+3.3V_ALW on TOP: 258.52,122.21 258.52,118.99 258.63,118.88 264.16,118.88 264.57,119.29 264.57,122.03 264.43,122.16 263.74,122.16 263.67,122.1 263.67,121.08 263.57,120.97 262.58,120.97 262.2,121.35 262.2,122.03 261.52,122.71 260.41,122.71 260.27,122.57 260.27,122.31 260.82,121.76 260.82,121.13 260.79,121.09 259.74,121.09 259.63,121.2 259.63,122.15 259.48,122.3 258.6,122.3
+3.3V_ALW on BOTTOM: 229.17,40.59 230.37,40.59 230.5,40.46 230.5,39.25 230.82,38.94 230.82,38.62 230.69,38.49 229.29,38.49 229.1,38.68 229.1,40.52
+3.3V_ALW on BOTTOM: 174.43,39.57 174.56,39.44 174.56,37.73 174.49,37.67 174.24,37.67 174.18,37.73 174.18,38.75 173.79,39.13 173.16,39.13 172.84,38.81 172.59,38.81 172.46,38.94 172.46,39.19 172.84,39.57
+3.3V_ALW on BOTTOM: 256.74,69.46 256.49,69.2 256.49,68.31 258.64,68.31 258.84,68.5 263.53,68.5 263.66,68.63 263.66,69.24 263.44,69.46
+3.3V_ALW on BOTTOM: 201.23,96.21 202.94,96.21 203.13,96.02 203.13,94.69 202.88,94.43 201.23,94.43 201.16,94.5 201.16,95.2 201.73,95.2 201.73,95.77 201.16,95.77 201.16,96.15
+3.3V_ALW on IN1: 147.51,135.71 146.11,135.71 145.66,135.27 101.91,135.27 101.6,134.95 101.6,133.04 102.04,132.6 102.61,132.6 102.87,132.85 102.87,133.87 103.31,134.31 128.77,134.31 129.28,133.8 146.62,133.8 147.57,134.76 147.57,135.65
+3.3V_ALW on VCC: 256.07,52.27 254.44,53.9 220.41,53.9 202.4,71.91 124.6,71.91 108.03,88.47 108.03,120.85 101.38,127.51 101.38,132.43 101.97,133.02 104.63,133.02 105.55,132.1 105.55,128.16 111.13,122.57 111.13,88.67 112.12,87.68 116.72,87.68 116.72,85.31 126.9,75.13 190.54,75.13 194.04,78.63 194.04,87.5 192.16,89.38 192.16,99.58 194.6,99.58 196.25,101.23 200.68,101.23 201.1,100.81 201.1,98.44 203.28,96.26 203.28,94.84 201.1,92.66 201.1,82.87 202.93,81.05 209.15,81.05 209.15,77.57 222.48,64.23 238.26,64.23 238.69,64.66 238.69,67.34 232.5,73.53 222.87,73.53 219.45,76.95 219.98,77.47 252.87,77.47 253.42,78.02 253.42,83.49 251.65,85.27 251.65,109.17 271.73,109.17 281.87,99.03 281.87,84.85 280.19,84.85 267.93,72.58 267.93,66.93 265.03,64.03 265.03,55.78 261.52,52.27 ; 2 cut-outs
+3.3V_ALW on IN2: 280.82,93.81 280.82,92.61 281.96,91.46 281.96,89.43 282.24,89.15 283,89.15 283.08,89.24 283.08,93.61 282.73,93.96 280.96,93.96
+3.3V_ALW on IN2: 200.46,101.67 200.46,94.82 200.97,94.31 203.2,94.31 203.58,94.69 203.58,101.55 202.69,102.44 201.23,102.44
+3.3V_ALW on IN3: 267.25,51.39 267.25,47.68 270.72,44.21 270.72,42.98 270.19,42.45 265.22,42.45 264.54,43.13 264.54,45.85 258.49,51.89 256.31,51.89 256.09,52.11 256.09,54.83 256.83,55.57 263.07,55.57
+3.3V_ALW on IN3: 203.2,95.9 203.2,94.82 201.73,93.36 199.51,93.36 198.5,92.34 191.38,92.34 190.62,93.1 184.53,93.1 184.27,93.36 184.27,94.63 186.56,96.91 202.18,96.91
+3.3V_ALW on IN4: 107.5,73.8 103.94,73.8 103.69,73.54 103.69,70.3 103.88,70.11 104.96,70.11 105.15,70.3 105.15,71.64 106.17,72.65 107.37,72.65 107.63,72.91 107.63,73.67
+3.3V_ALW2 on IN2: 245.87,99.96 244.22,99.96 243.58,99.32 243.58,96.21 245.42,94.37 246.12,94.37 246.31,94.56 246.31,95.58 245.23,96.66 245.17,96.66 245.11,96.72 245.11,97.93 245.99,98.82 245.99,99.83
+3.3V_ALW_PCH on TOP: 227.59,129.28 227.59,128.78 227.08,128.27 227.08,127.66 226.94,127.52 225.14,127.52 224.98,127.68 224.98,129.41 225.48,129.92 226.96,129.92
+3.3V_ALW_PCH on TOP: 203.21,132.33 205.29,132.33 205.52,132.1 205.52,131.32 205.19,130.99 203.34,130.99 203.03,131.29 203.03,132.15
+3.3V_ALW_PCH on TOP: 205.52,123.31 206.94,123.31 207.35,122.91 207.35,121.99 206.92,121.56 205.77,121.56 205.37,121.97 205.37,123.16
+3.3V_ALW_PCH on TOP: 230.53,112.65 230.53,113.08 231.63,114.17 231.63,115.58 231.47,115.74 231.47,117.55 231.65,117.72 232.22,117.72 232.32,117.63 232.32,117.25 232.49,117.09 232.81,117.09 232.88,117.02 232.88,116.54 232.73,116.4 232.36,116.4 232.13,116.16 232.13,113.65 231.1,112.62 230.57,112.62
+3.3V_ALW_PCH on TOP: 71.94,105.46 72.91,105.46 73.24,105.13 73.24,103.55 73.03,103.35 72.65,103.35 71.76,104.24 71.76,105.28
+3.3V_ALW_PCH on TOP: 246.94,77.25 246.94,71.53 247.09,71.38 248.56,71.38 250.33,73.15 250.33,76.75 247.43,79.65 247.43,90.8 247.58,90.95 248.75,90.95 248.97,91.17 248.97,92.1 247.59,93.48 245.04,93.48 244.6,93.04 244.6,90.37 245.21,89.76 245.21,78.98
+3.3V_ALW_PCH on TOP: 78.99,103.39 80.77,103.39 81.02,103.13 81.02,102.82 80.83,102.63 79.12,102.63 78.54,102.05 77.97,102.05 77.66,101.74 77.66,100.98 77.53,100.85 77.34,100.85 77.21,100.98 77.21,101.99 77.59,102.37 78.35,102.37 78.93,102.94 78.93,103.32
+3.3V_ALW_PCH on TOP: 235.81,112.1 238.53,112.1 238.62,112.19 238.62,112.86 238.37,113.12 238.37,114.54 238.45,114.62 238.45,115.25 238.4,115.3 237.8,115.3 235.77,113.27 235.77,112.13
+3.3V_ALW_PCH on TOP: 74.8,97.74 75.05,97.74 75.12,97.67 75.12,96.91 74.86,96.66 74.16,96.66 73.91,96.4 73.91,95.39 73.97,95.32 75.31,95.32 75.43,95.2 75.43,94.32 75.18,94.07 73.71,94.07 73.08,94.69 73.08,96.28 73.78,96.97 74.54,96.97 74.73,97.17 74.73,97.67
+3.3V_ALW_PCH on BOTTOM: 242.95,93.96 242.95,95.7 243.01,95.76 243.76,95.76 243.93,95.59 243.93,93.11 243.84,93.03 243.25,93.03 243.15,93.13 243.15,93.76
+3.3V_ALW_PCH on BOTTOM: 85.23,129.33 86.88,129.33 87.03,129.18 87.03,128.29 86.8,128.06 85.33,128.06 85.07,128.32 85.07,129.18
+3.3V_ALW_PCH on BOTTOM: 271.65,59.81 271.65,62.43 272.16,62.94 272.16,63.27 272.44,63.55 272.44,64.62 272.16,64.9 272.16,68.02 272.73,68.59 274.57,68.59 274.96,68.2 274.96,66.11 274.91,66.07 274.91,60.02 274.96,59.98 274.96,58.07 274.95,58.06 274.95,56.64 274.58,56.27 269.69,56.27 269.29,56.66 269.29,59.02 269.54,59.26 271.1,59.26
+3.3V_ALW_PCH on BOTTOM: 226.02,128.21 226.02,130.85 228.15,132.98 229.61,132.98 230.94,131.65 230.94,128.09 232.75,126.29 232.75,124.11 232.58,123.94 231.88,123.94 228.6,127.22 227,127.22
+3.3V_ALW_PCH on BOTTOM: 248.34,56.9 248.34,55.48 248.66,55.17 252.39,55.17 252.55,55.33 252.55,56.83 252.24,57.14 248.58,57.14
+3.3V_ALW_PCH on BOTTOM: 264.6,50.75 267.9,50.75 268.16,50.49 268.16,47.25 267.71,46.81 264.6,46.81 264.54,46.87 264.54,49.1 264.03,49.1 264.03,49.22 264.54,49.22 264.54,50.68
+3.3V_ALW_PCH on IN1: 240.44,134.19 232.09,134.19 231.87,133.96 228.37,133.96 228.21,133.8 228.21,132.47 228.47,132.22 232.02,132.22 232.34,132.53 240.42,132.53 240.62,132.74 240.62,134.01 ; 1 cut-out
+3.3V_ALW_PCH on IN1: 228.2,117.42 228.2,116.82 229.79,115.24 232.15,115.24 232.43,115.51 232.43,116.04 231.77,116.7 230.11,116.7 229.23,117.57 228.36,117.57
+3.3V_ALW_PCH on IN1: 247.77,72.63 247.03,71.9 247.03,69.21 248.4,67.84 248.4,63.02 247.37,61.99 247.37,55.53 247.67,55.24 248.74,55.24 250.02,56.51 250.02,68.74 249.05,69.71 249.05,72.28 248.7,72.63
+3.3V_ALW_PCH on VCC: 81.42,101.6 79.92,103.1 71,103.1 71,104.9 71.89,105.79 81.88,105.79 84.62,108.53 84.62,128.37 84.95,128.7 87,128.7 87.13,128.57 87.13,107.44 82.63,102.95 82.63,101.6
+3.3V_ALW_PCH on IN3: 71.37,105.29 71.37,98.63 73.02,96.97 78.74,96.97 78.86,97.1 79.56,97.1 79.62,97.04 79.62,96.92 79.61,96.92 78.8,96.11 74.58,96.11 74.3,95.83 74.3,94.55 74.8,94.05 76.54,94.05 76.91,94.42 80.5,94.42 82.74,96.66 82.74,105.23 82.42,105.55 71.62,105.55
+3.3V_ALW_PCH on IN3: 243.99,90.47 249.07,90.47 249.57,90.97 249.57,102.64 248.34,103.87 248.34,109.88 241.27,116.95 231.78,116.95 231.41,116.58 231.41,115.5 234.26,112.66 236.34,112.66 236.63,112.37 240.69,112.37 243.96,109.1 243.96,100.93 243.02,99.99 243.02,91.43
+3.3V_ALW_PCH_UZ3 on TOP: 262.93,49.22 262.61,48.9 260.71,48.9 260.57,49.05 260.57,49.5 260.49,49.58 260.49,50.03 260.35,50.16 260.35,50.94 260.42,51.02 260.44,51 262.57,51 262.93,50.64
+3.3V_ALW_PCH_UZ3 on BOTTOM: 264.16,50.94 261.3,50.94 260.98,50.62 260.98,48.21 261.42,47.76 263.96,47.76 264.35,48.14 264.35,48.91 263.77,48.91 263.77,49.41 264.35,49.41 264.35,50.75
+3.3V_ALW_PCHRES on TOP (solid shape): 226.76,112.25 226.76,110.98 226.6,110.82 225.52,110.82 225.36,110.98 225.36,112.19 225.45,112.28 226.73,112.28
+3.3V_ALW_PCHRES on TOP (solid shape): 220.52,120.49 220.52,120.06 220.21,119.75 220.21,119.09 220.21,119.09 219.61,119.09 219.52,119.17 219.52,120.14 219.96,120.57 220.44,120.57
+3.3V_ALW_PCHRES on TOP (solid shape): 233.09,112.76 233.09,111.76 232.46,111.12 231.19,111.12 231.01,111.3 231.01,111.87 231.96,112.82 233.03,112.82
+3.3V_ALW_PCHRES on TOP (solid shape): 218.63,116.81 218.63,115.93 219.16,115.4 219.16,114.07 218.67,113.58 218.63,113.58 218.18,114.03 218.18,115.56 218.18,115.66 217.93,115.91 217.32,115.91 217.28,115.95 217.28,116.81 217.51,117.03 218.4,117.03
+3.3V_ALW_PCHRES on TOP: 236.79,97.17 240.15,97.17 240.53,96.78 240.53,94.94 240.28,94.69 238.56,94.69 236.72,96.53 236.72,97.1
+3.3V_ALW_PCHRES on IN2: 219.84,119.93 220.15,119.93 224.6,115.49 224.6,112.12 224.85,111.87 224.85,111.04 225.04,110.85 225.74,110.85 225.87,110.98 225.87,112.31 225.42,112.76 225.42,115.62 225.42,115.62 225.42,116 223.87,117.56 223.87,118.03 221.14,120.76 219.96,120.76 219.77,120.57 219.77,120
+3.3V_ALW_PCHRES on IN3: 225.3,112 225.3,110.82 225.64,110.47 239.48,110.47 241.49,108.47 241.49,102.31 239.83,100.66 239.83,94.63 240.03,94.43 241.93,94.43 242.18,94.69 242.18,99.77 244.53,102.12 244.53,103.58 244.15,103.96 244.15,108.47 240.28,112.34 233.52,112.34 232.92,112.95 231.33,112.95 230.5,112.12 225.42,112.12
+3.3V_ALW_UE1 on TOP (solid shape): 253.32,99.09 253.32,98.55 253.34,98.54 253.72,98.54 253.73,98.52 254.69,98.52 254.73,98.48 254.73,97.86 254.57,97.7 252.77,97.7 252.71,97.75 252.71,98.52 252.73,98.54 253.09,98.54 253.14,98.59 253.14,99.09 253.32,99.1
+3.3V_ALW_UE1 on IN1: 259.01,96.1 259.01,93.66 259.76,92.9 261.97,92.9 263.08,94.01 263.08,96.22 264.25,96.22 264.79,95.67 266.97,95.67 267.29,95.35 267.29,91.19 267.6,90.89 269.11,90.89 269.47,91.25 269.47,96.16 267.13,98.5 261.4,98.5
+3.3V_ALW_UE1 on VCC: 260.72,90.8 258.91,92.61 258.91,97.28 260.18,98.55 268.69,98.55 269.81,97.43 269.81,91.39 269.22,90.8
+3.3V_ALW_UE1 on IN2: 266.4,104.87 262.21,104.87 260.18,102.83 260.18,97.4 259.45,96.67 259.45,95.73 259.73,95.45 266.6,95.45 267.07,95.91 267.07,104.2 ; 1 cut-out
+3.3V_ALW_UZ12 on TOP (solid shape): 250.24,124.27 250.24,123.81 250.15,123.71 248.17,123.71 248.05,123.83 246.68,123.83 246.6,123.9 246.6,124.08 246.67,124.14 247.54,124.14 247.66,124.25 248.69,124.25 248.76,124.32 250.19,124.32
+3.3V_ALWP on TOP: 243.8,55.57 243.8,54.62 243.93,54.5 247.29,54.5 247.67,54.88 247.67,59.74 247.58,59.83 245.9,59.83 245.58,60.15 245.58,62.43 245.45,62.56 243.84,62.56 243.71,62.43 243.71,60.08 243.58,59.96 241.77,59.96 241.58,59.77 241.58,58.85 241.61,58.81 243.48,58.81 243.8,58.5 243.8,57.23 243.23,57.23 243.23,56.78 243.8,56.78 243.8,56.02 243.29,56.02 243.29,55.57
+3.3V_ALWP on BOTTOM: 248.31,54.9 247.77,54.37 243.89,54.37 243.49,54.77 243.49,59.99 243.71,60.21 243.71,61.86 243.96,62.11 245.49,62.11 245.7,61.9 245.7,59.99 245.87,59.83 247.52,59.83 247.61,59.92 247.61,62.05 247.67,62.12 248.22,62.12 248.31,62.02
+3.3V_CAM on TOP (solid shape): 132.06,131.04 132.06,129.6 131.85,129.39 130.06,129.39 129.58,129.87 129.57,129.91 129.55,129.95 129.55,130.78 129.73,130.95 130.14,130.95 130.31,131.13 131.97,131.13
+3.3V_CAM_F on TOP (solid shape): 131.83,128.6 131.83,125.83 131.63,125.63 131.01,125.63 130.34,126.31 130.34,128.61 130.37,128.65 131.78,128.65
+3.3V_DSW on BOTTOM (solid shape): 243.92,116.9 243.92,115.85 243.72,115.65 243.26,115.65 243.11,115.81 243.11,116.37 243.01,116.47 242.25,116.47 241.91,116.14 241.91,114.64 241.78,114.51 241.78,114.47 241.77,114.46 241.77,114.43 241.75,114.3 241.77,114.16 241.77,114.13 241.77,114.1 241.77,111.13 240.56,109.91 240.23,109.91 240.23,109.9 240.18,109.9 239.99,109.71 239.99,109.68 239.88,109.68 239.78,109.74 239.67,109.76 239.66,109.77 239.66,110.02 239.77,110.13 239.96,110.13 240.12,110.3 240.16,110.31 240.39,110.31 241.21,111.13 241.21,114.64 241.43,114.85 241.43,116.58 241.7,116.85 241.76,116.85 241.79,116.88 242.13,116.99 242.21,117.34 243.48,117.34
+3.3V_FPBTN on TOP (solid shape): 286.76,123.71 286.76,123.14 286.67,123.04 284,123.04 283.21,122.25 282.51,122.25 282.19,122.57 282.19,123.71 282.38,123.9 286.57,123.9
+3.3V_FPBTN on IN3: 280.45,97.11 280.25,96.9 280.25,92.01 280.9,91.35 281.41,91.35 281.79,91.73 281.79,96.89 281.56,97.11
+3.3V_FUSE on TOP: 240.6,105.67 240.03,105.67 239.83,105.48 237.55,105.48 237.42,105.61 237.42,105.86 237.51,105.95 237.51,105.95 237.65,106.09 237.96,106.09 237.96,106.09 238.5,106.63 240.85,106.63 240.85,105.93
+3.3V_HDD on TOP: 247.07,39.19 247.07,37.98 248.15,36.9 248.15,36.65 249.17,35.63 251.07,35.63 251.26,35.82 251.26,37.73 250.69,37.73 250.69,38.43 251.26,38.43 251.26,38.55 250.69,38.55 250.69,39.19 251.26,39.19 251.26,39.44 251.07,39.63 247.52,39.63
+3.3V_HDD on TOP: 240.6,39 241.04,39 241.87,38.17 241.87,37.09 241.74,36.97 241.61,36.97 241.49,37.09 241.49,37.54 241.36,37.67 240.72,37.67 240.53,37.48 240.15,37.48 240.03,37.6 240.03,37.79 240.53,38.3 240.53,38.94
+3.3V_HDD on TOP: 243.58,34.17 243.71,34.17 243.96,33.92 243.96,33.41 244.34,33.03 244.91,33.03 245.61,32.33 245.61,31.7 245.42,31.51 244.66,31.51 244.6,31.57 244.6,32.46 244.47,32.59 244.03,32.59 243.52,33.09 243.52,34.11
+3.3V_HDD on BOTTOM: 247.9,39 247.9,37.03 248.47,36.46 250.5,36.46 250.69,36.65 250.69,37.03 249.99,37.73 248.92,37.73 248.72,37.92 248.72,39 248.6,39.13 248.03,39.13
+3.3V_HDD_M2 on TOP: 264.85,26.24 265.62,26.24 266,25.85 266,21.98 265.62,21.6 264.73,21.6 264.54,21.79 264.54,25.92
+3.3V_HDD_M2 on TOP: 274.48,20.67 274.23,20.91 274.23,25.15 274.4,25.32 279.17,25.32 279.79,24.69 279.79,20.67
+3.3V_HDD_M2 on TOP: 258.06,45.73 260.28,45.73 260.6,45.41 260.6,43.89 261.17,43.89 261.17,43.7 260.6,43.7 260.6,43.06 261.17,43.06 261.17,42.87 260.6,42.87 260.6,41.67 260.41,41.48 258.06,41.48 257.87,41.67 257.87,42.94 257.3,42.94 257.3,43.06 257.87,43.06 257.87,43.7 257.3,43.7 257.3,43.89 257.87,43.89 257.87,45.54
+3.3V_HDD_M2 on TOP: 281.55,22.62 281.55,20.84 281.68,20.71 283.65,20.71 283.71,20.77 283.71,21.73 283.46,21.98 283.46,23.89 281.17,23.89 281.17,23
+3.3V_HDD_M2 on BOTTOM: 278.42,20.65 278.42,22.13 278.32,22.24 275.01,22.24 274.89,22.36 274.89,24.71 275.27,25.09 282.06,25.09 282.74,24.42 282.74,20.63 282.63,20.52 278.55,20.52
+3.3V_HDD_M2 on BOTTOM: 265.72,20.56 265.72,22.15 265.85,22.28 268.26,22.28 268.85,22.87 268.85,25.09 268.6,25.35 264.92,25.35 264.26,24.69 264.26,20.56 264.39,20.43 265.59,20.43
+3.3V_HDD_M2 on IN3: 260.03,44.4 257.36,44.4 257.04,44.08 257.04,32.9 262.31,27.63 262.31,25.92 263.39,24.84 264.09,24.84 264.66,24.27 264.66,21.98 265.36,21.28 283.21,21.28 284.09,22.17 284.09,24.2 283.33,24.97 269.55,24.97 260.22,34.3 260.22,44.21
+3.3V_LAN on TOP (solid shape): 271.01,108.55 270.5,108.55 270.5,109.32 269.93,109.89 269.93,110.33 270.31,110.71 271.01,110.71
+3.3V_LAN on TOP (solid shape): 255.1,80.86 255.1,79.84 255.03,79.78 253.57,79.78 253.51,79.84 253.51,80.86 253.57,80.92 255.03,80.92
+3.3V_LAN on TOP (solid shape): 275.21,120.04 275.21,119.91 275.26,119.79 275.26,119.28 275.15,119.17 274.53,119.17 274.12,119.42 273.83,119.03 273.74,119.03 273.71,119.01 272.66,119.01 272.6,119.07 272.6,119.9 272.93,120.22 275.02,120.22
+3.3V_LAN on TOP: 293.56,113.87 293.56,113.29 293.62,113.23 296.54,113.23 296.92,113.61 296.92,115.28 296.72,115.48 295.55,115.48 295.46,115.39 295.46,115.39 294.76,115.39 294.64,115.26 294.64,114.31 294.25,113.93 293.62,113.93
+3.3V_LAN on TOP: 273.49,104.91 272.98,104.91 272.73,105.17 272.73,105.99 272.47,106.25 272.47,106.88 272.66,107.07 273.44,107.07 273.62,106.89 273.62,105.04
+3.3V_LAN on BOTTOM: 274.32,120.55 273.11,120.55 272.52,119.97 272.52,118.69 269.74,115.91 269.74,107.79 272.52,105.02 273.64,105.02 274.33,105.71 274.33,106.83 272.7,108.47 272.7,111.43 273.89,112.61 273.89,118.88 274.46,119.45 274.46,120.42
+3.3V_LAN on IN2: 272.31,106.92 272.31,104.81 272.52,104.6 273.48,104.6 273.67,104.78 273.67,106.98 273.57,107.08 272.47,107.08
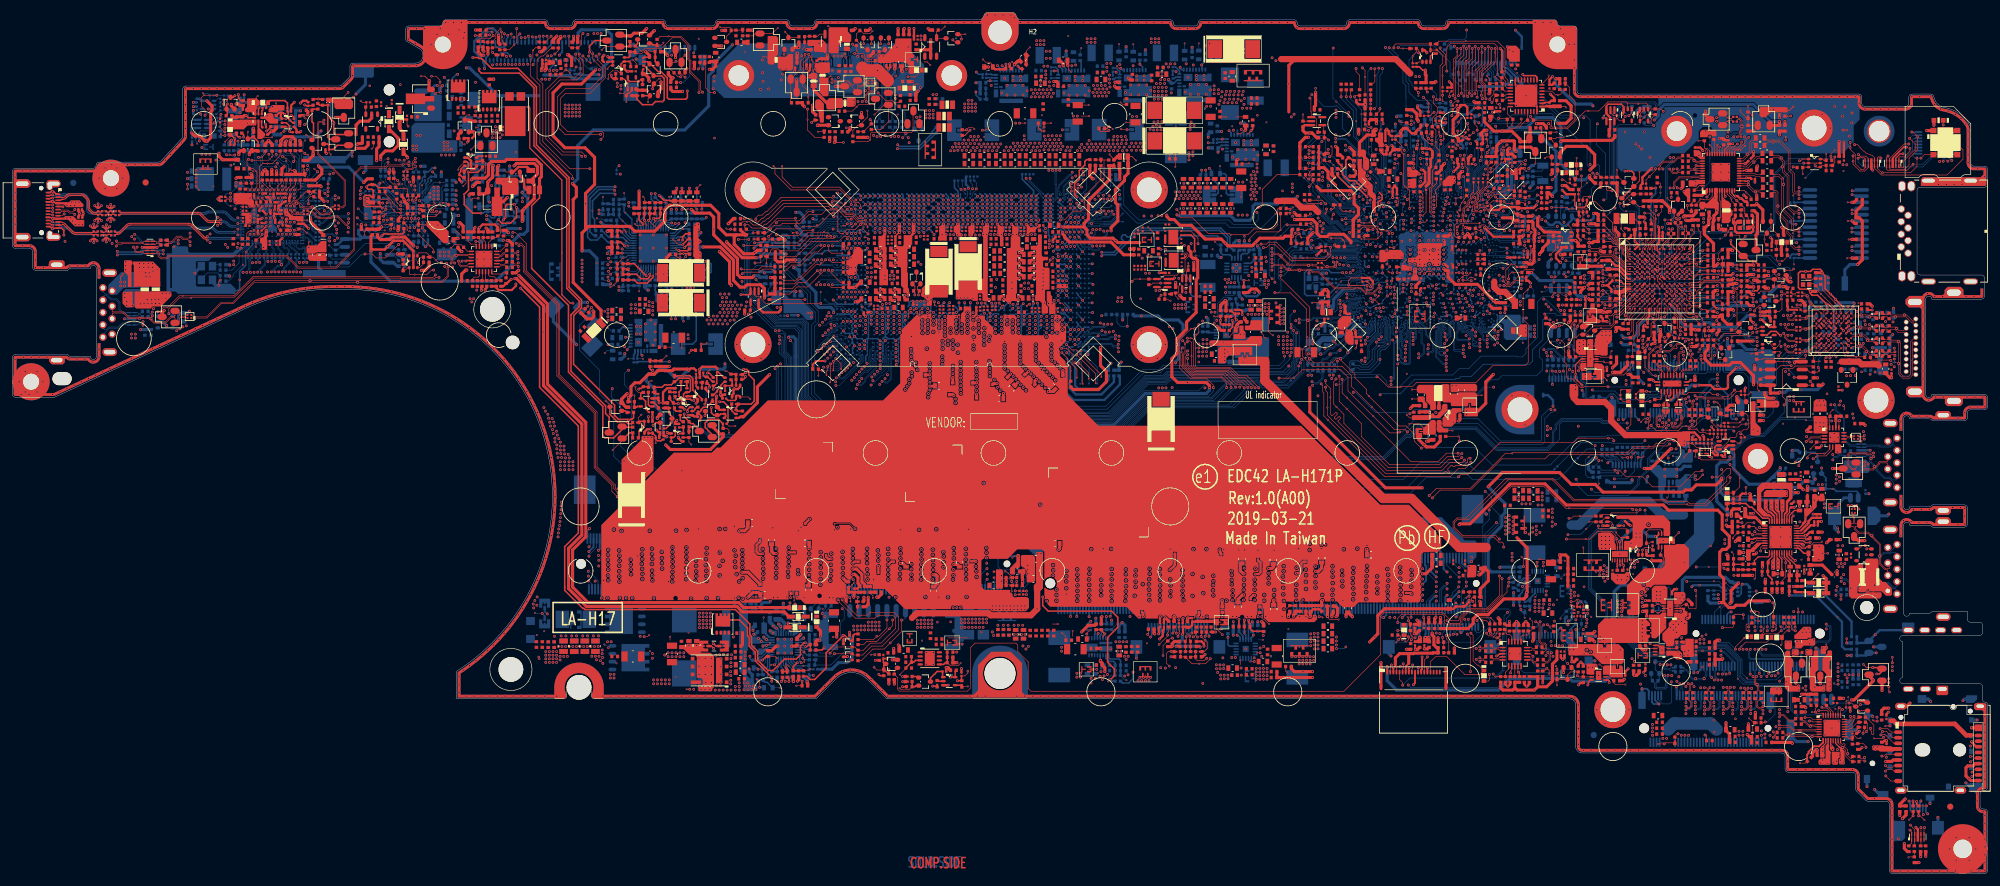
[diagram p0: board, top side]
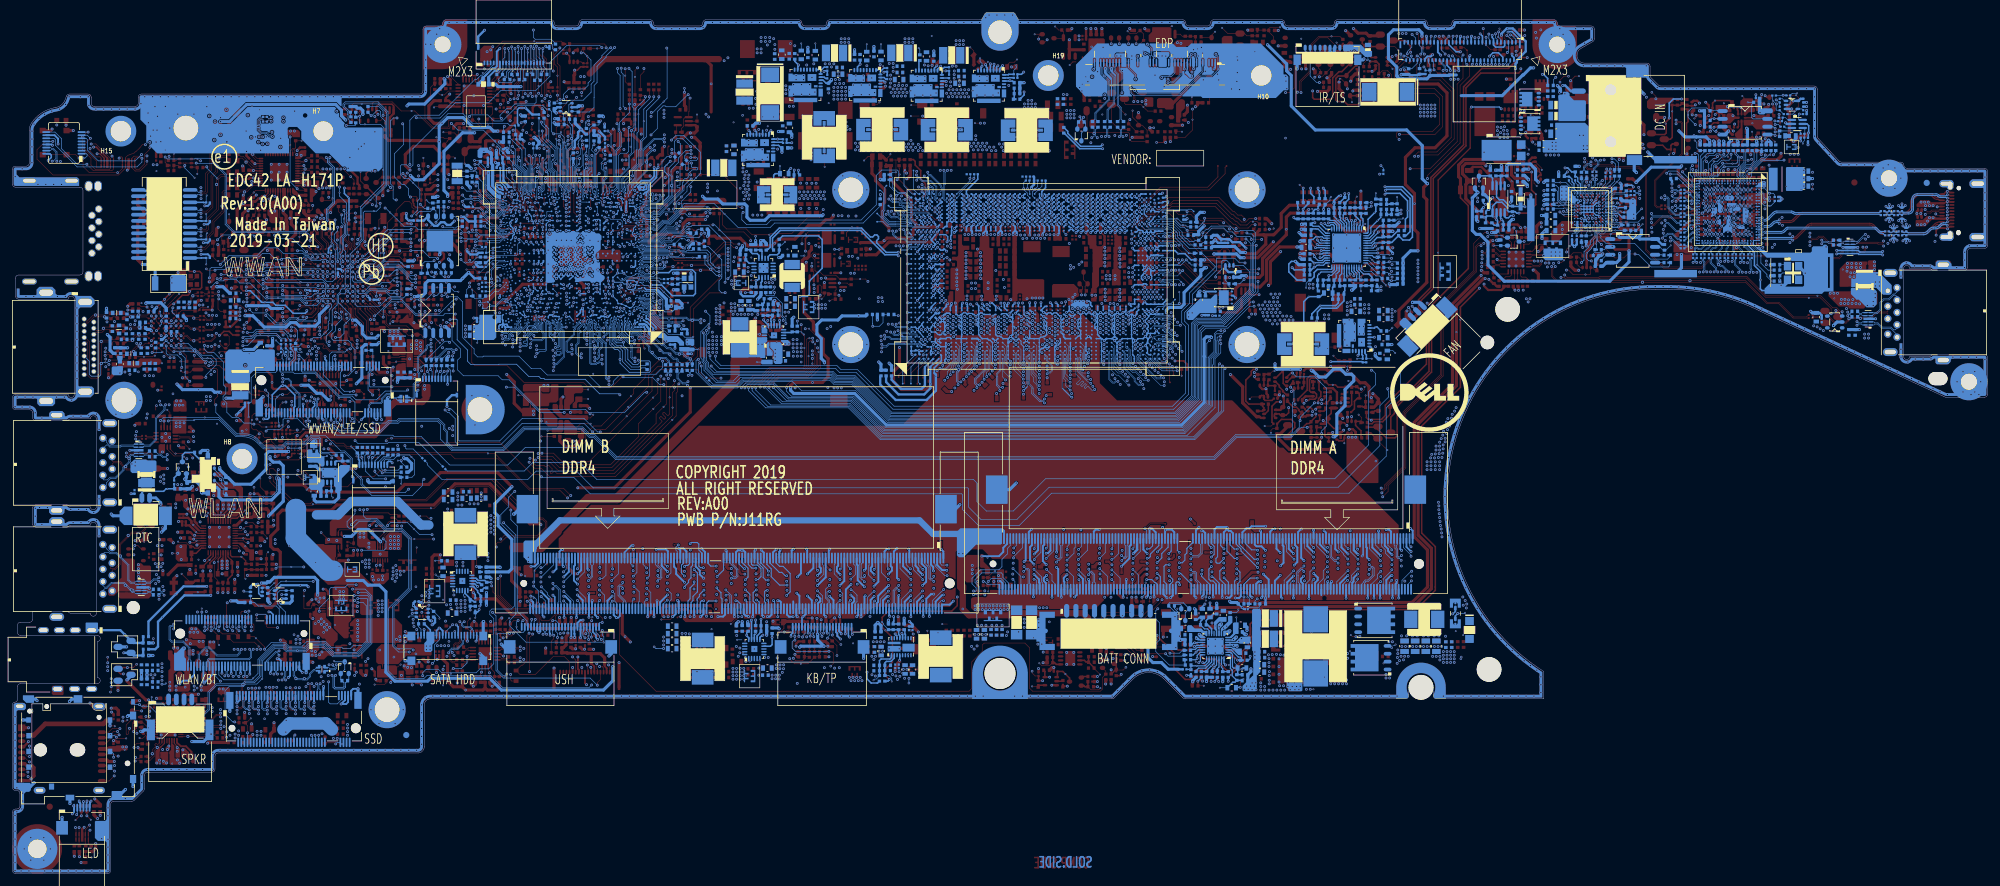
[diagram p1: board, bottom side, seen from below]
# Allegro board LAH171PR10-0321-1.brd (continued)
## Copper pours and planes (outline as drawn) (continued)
+3.3V_LAN on IN2: outline of 162 points within 249.31,79.63 258.88,116.52
+3.3V_LAN on IN3: 297.32,114.81 295.15,114.81 294.9,114.56 294.9,113.18 295.03,113.05 297.41,113.05 297.54,113.18 297.54,114.59
+3.3V_LAN on IN4: 272.68,119.34 273.12,118.91 279.12,118.91 284.66,113.37 296.72,113.37 296.93,113.58 296.93,114.99 296.46,115.46 286.8,115.46 280.64,121.62 273.46,121.62 272.68,120.85
+3.3V_LAN_OUT on TOP (solid shape): 275.46,110.79 275.46,109.14 275.45,109.13 275.45,108.68 275.64,108.49 275.64,107.16 275.44,106.95 275.19,106.95 275.01,107.13 275.01,107.39 274.88,107.52 273.54,107.52 273.43,107.63 272.52,107.63 272.47,107.68 272.47,108.28 272.54,108.35 273.72,108.35 274.85,109.48 274.85,110.77 274.93,110.84 275.41,110.84
+3.3V_LAN_OUT on IN4: 278.12,115.35 278.12,111.98 277.61,111.48 275.07,111.48 274.37,110.78 274.37,107.03 274.56,106.84 275.9,106.84 276.15,107.09 276.15,109.57 276.53,109.95 280.43,109.95 280.73,110.25 280.73,111.96 280.58,112.11 279.77,112.11 279.64,112.24 279.64,112.75 280.34,113.44 280.34,113.76 280.15,113.95 279.83,113.95 279.52,114.27 279.52,116.37 278.31,117.57 278.31,118.4 278.18,118.52 277.61,118.52 277.48,118.4 277.48,115.98
+3.3V_LAN_UZ2 on TOP (solid shape): 257.13,82 257.13,80.16 256.81,79.84 255.29,79.84 255.29,80.1 255.86,80.1 255.86,80.61 255.29,80.61 255.29,80.86 255.48,81.05 255.48,81.77 255.51,81.77 255.51,82.41 255.54,82.45 256.69,82.45
+3.3V_LSPCON on BOTTOM: 301.09,82.74 300.72,83.11 300.16,83.11 300.08,83.18 300.08,84.38 300.16,84.45 302.9,84.45 302.98,84.38 302.98,82.8 302.92,82.74
+3.3V_LSPCON_VDD on IN3 (solid shape): 297.43,87.89 297.43,85.29 297.11,84.97 296.29,84.97 296.22,85.04 296.22,86.16 296.24,86.16 296.24,86.11 296.25,86.06 296.27,86.01 296.29,85.96 296.32,85.91 296.36,85.87 296.4,85.84 296.44,85.81 296.49,85.79 296.54,85.78 296.6,85.78 296.65,85.78 296.7,85.79 296.75,85.81 296.8,85.84 296.84,85.87 296.88,85.91 296.91,85.96 296.93,86.01 296.95,86.06 296.95,86.11 296.95,86.16 296.95,86.22 296.93,86.27 296.91,86.31 296.88,86.36 296.84,86.4 296.8,86.43 296.75,86.46 296.7,86.48 296.65,86.49 296.6,86.49 296.54,86.49 296.49,86.48 296.44,86.46 296.4,86.43 296.36,86.4 296.32,86.36 296.29,86.31 296.27,86.27 296.25,86.22 296.24,86.16 296.22,86.16 296.22,88.02 296.35,88.15 297.18,88.15
+3.3V_LSPCON_VDD on BOTTOM: 296.48,85.61 296.71,85.61 296.81,85.51 296.81,84.62 296.87,84.55 299.5,84.55 299.63,84.43 299.63,83.41 299.5,83.28 295.74,83.28 295.59,83.44 295.59,85.29 295.65,85.35 296.22,85.35
+3.3V_LSPCON_VDD on IN4: 296.5,87.19 296.88,87.19 297.13,86.94 297.13,85.1 296.82,84.78 296.4,84.78 295.85,84.22 293.58,84.22 293.03,84.78 291.67,84.78 291.48,84.97 291.48,85.67 291.67,85.86 295.74,85.86 296.05,86.18 296.05,86.75
+3.3V_MMI_AUX on TOP: 294.44,25.12 294.39,25.18 294.39,26.08 294.21,26.25 294.21,26.62 293.45,27.38 293.45,27.61 293.33,27.73 290.93,27.73 290.78,27.59 290.78,26.95 290.72,26.89 289.96,26.89 289.47,27.37 289.38,27.37 289.1,27.66 289.1,28.52 289.15,28.57 291.96,28.57 292.17,28.78 294.34,28.78 294.52,28.6 294.52,27.99 294.38,27.85 294.38,27.25 294.7,26.93 294.7,26.24 294.59,26.13 294.59,25.18 294.54,25.12
+3.3V_MMI_IN on TOP (solid shape): 293.4,21.87 293.4,21.01 293.42,20.98 293.42,19.99 293.68,19.73 293.68,17.73 293.56,17.6 291.9,17.6 291.71,17.79 291.71,18.23 292.1,18.62 292.79,18.62 292.86,18.69 292.86,20.71 293.19,21.04 293.19,21.87 293.25,21.92 293.35,21.92
+3.3V_MMI_IN on IN3 (solid shape): 287.8,26.95 287.8,24.92 287.23,24.92 286.52,25.63 286.52,26.99 286.67,27.14 287.61,27.14
+3.3V_MMI_IN on IN3 (solid shape): 292.7,18.46 292.7,17.82 292.49,17.62 290.24,17.62 290.06,17.79 290.06,18.55 290.13,18.62 292.54,18.62
+3.3V_MMI_IN on TOP: 283.65,26.81 283.65,28.71 283.78,28.84 284.22,28.84 284.22,28.33 284.86,28.33 284.86,28.83 284.98,28.83 284.98,28.33 285.62,28.33 285.62,28.78 285.68,28.84 288.35,28.84 288.41,28.78 288.41,25.85 288.35,25.79 286.82,25.79 286.51,26.11 286.51,26.49 286.32,26.68 283.78,26.68
+3.3V_PGPPBC on TOP: 231.2,108.43 231.25,108.25 231.27,108.17 231.22,108.1 231.05,107.81 231.21,107.51 231.25,107.47 231.2,107.42 231.18,107.41 230.95,107.29 230.86,107.04 230.86,106.64 230.67,106.32 230.86,106.01 230.86,105.86 230.67,105.54 230.86,105.23 230.86,104.25 230.7,104.07 230.69,103.84 230.7,103.81 230.63,103.74 229.38,103.74 229.26,103.87 229.26,105.17 229.32,105.24 229.35,105.2 229.88,105.26 229.76,105.78 229.76,105.92 229.95,106.23 229.76,106.54 229.76,106.68 229.95,106.99 229.76,107.3 229.76,107.44 229.89,107.56 229.95,107.72 229.95,107.73 230.15,107.93 230.15,109.31 230.17,109.34 230.17,110.43 230.55,110.81 231.63,110.81 231.71,110.73 231.71,110.03 231.33,109.65 231.33,108.77 231.28,108.69 231.25,108.61
+3.3V_PGPPEF on TOP: 242.76,101.33 242.47,101.04 241.83,101.04 241.78,101.09 241.78,101.11 241.43,101.43 241.07,101.11 241.07,101.09 241.02,101.04 239.14,101.04 239.13,101.04 237.42,101.04 237.42,101.04 235.02,101.04 234.63,101.08 234.44,100.75 234.43,100.71 234.41,100.67 234.32,100.58 233.05,100.58 232.92,100.72 232.92,101.61 233.04,101.74 236.09,101.74 236.47,102.12 242.76,102.12
+3.3V_PGPPG on TOP: 227.04,107.18 226.99,106.99 227.04,106.81 227.04,106.41 226.99,106.23 227.04,106.05 227.04,105.65 226.99,105.48 227.03,105.3 227.04,105.28 227.04,104.89 226.99,104.71 227.04,104.52 227.04,104.13 226.99,103.97 227.01,103.81 227.03,103.78 226.91,103.66 226.14,103.66 226.12,103.64 225.77,103.64 225.62,103.79 225.62,104.12 225.8,104.3 225.8,104.3 225.8,107.39 225.82,107.4 225.78,107.41 225.74,107.45 225.74,107.52 225.76,107.53 225.82,107.59 225.86,107.66 225.86,110.4 225.96,110.5 226.66,110.5 226.76,110.41 226.76,109.89 227.06,109.58 227.06,109.5 227.05,109.49 226.99,109.29 227.04,109.09 227.04,108.7 226.99,108.52 227.04,108.33 227.04,107.94 226.99,107.75 227.04,107.57
+3.3V_PGPPHK on TOP: 234.31,98.76 234.45,98.62 234.45,98.59 234.66,98.19 235.1,98.33 235.35,98.08 237.53,98.08 237.61,97.99 237.61,97.36 237.55,97.29 235.2,97.29 235.01,97.48 233.17,97.48 233.04,97.61 233.04,98.63 233.17,98.76
+3.3V_PHVC on TOP: 220.84,112.51 220.84,111.68 220.84,111.64 220.84,110.01 220.66,109.83 220.28,109.83 219.94,110.17 219.94,111.3 219.52,111.72 219.52,112 219.58,112.12 219.59,112.26 219.56,112.45 219.43,112.59 219.24,112.78 219.24,112.81 219.15,113.02 218.95,113.14 218.95,113.36 219.38,113.79 219.42,113.83 219.51,113.83 219.58,113.77 219.58,113.76 219.68,113.55 219.88,113.45 219.9,113.45
+3.3V_PHVLDO on TOP (solid shape): 217.95,115.48 217.95,114.14 218.05,114.04 218.05,113.98 218.58,113.45 218.63,113.45 218.65,113.43 218.65,113.06 218.55,112.91 218.53,112.73 218.62,112.52 218.81,112.41 218.86,112.39 218.89,112.34 218.88,112.3 218.89,112.26 218.96,112.01 219.18,111.88 219.22,111.87 219.22,111.8 219.73,111.3 219.73,110.2 220.24,109.69 220.24,106.94 220.05,106.74 219.75,106.74 219.62,106.87 219.62,108.63 219.71,109.02 219.39,109.25 219.36,109.25 219.14,109.47 219.14,109.49 219.05,109.63 218.91,109.72 218.89,109.72 218.87,109.75 218.87,110.28 218.88,110.29 218.88,110.61 218.63,110.8 218.61,110.8 217.36,112.06 217.36,113.87 217.28,113.94 217.28,115.48 217.31,115.51 217.91,115.51
+3.3V_PRTC on TOP (solid shape): 243.12,113.95 243.12,112.86 243.2,112.79 243.2,112.13 242.67,112.13 242.67,112.79 242.54,112.91 242.11,112.91 241.96,113.07 241.96,113.57 242.13,113.75 242.49,113.75 242.72,113.98 243.1,113.98
+3.3V_PRTC on BOTTOM (solid shape): 242.44,110.6 241.04,109.19 240.67,109.19 240.57,109.09 240.52,109.09 240.39,108.97 240.17,108.97 240.12,109.02 240.12,109.65 240.24,109.77 240.6,109.77 241.9,111.07 241.9,113.68 242.44,113.68
+3.3V_PUSB2 on IN4: 228.34,94.88 227.65,95.57 227.65,98.12 228.02,98.5 238.06,98.5 238.63,97.93 238.63,95.64 237.87,94.88 ; 1 cut-out
+3.3V_RUN on TOP (solid shape): 136.22,125.36 136.22,124.23 135.92,123.94 134.87,123.94 134.76,124.05 134.76,125.31 134.92,125.47 136.1,125.47
+3.3V_RUN on TOP (solid shape): 252.94,78.74 252.94,77.19 252.51,76.77 251.9,76.77 251.51,77.15 251.51,78.97 251.67,79.13 252.54,79.13
+3.3V_RUN on TOP (solid shape): 285.85,29.9 285.85,29.04 285.8,28.98 283.92,28.98 283.9,29.01 283.9,29.9 284.13,30.13 285.62,30.13
+3.3V_RUN on TOP (solid shape): 196.47,41.02 196.47,40.26 196.35,40.13 195.08,40.13 195.08,40.38 195.65,40.38 195.65,40.89 195.08,40.89 195.08,41.14 196.35,41.14
+3.3V_RUN on TOP (solid shape): 283.42,76.46 285.18,76.46 285.4,76.25 285.4,75.59 285.13,75.32 281.74,75.32 281.74,75.58 282.32,75.58 282.32,76.08 281.74,76.08 281.74,76.59 281.82,76.67 283.21,76.67
+3.3V_RUN on TOP (solid shape): 270.27,71.49 270.85,71.49 271,71.33 271,70.01 270.9,69.91 270.47,69.91 270.39,69.83 270.39,69.17 270.26,69.04 269.02,69.04 268.91,69.15 268.91,71.39 268.95,71.43 269.66,71.43 269.73,71.49 270.26,71.49
+3.3V_RUN on BOTTOM (solid shape): 270.99,69.69 270.99,68.89 270.86,68.77 269.85,68.77 269.78,68.83 269.78,70.03 269.93,70.18 270.51,70.18
+3.3V_RUN on BOTTOM (solid shape): 303.01,81.81 303.01,80.8 302.76,80.55 301.48,80.55 301.2,80.82 301.2,80.94 301.23,81.07 301.2,81.21 301.2,81.96 301.23,81.99 302.83,81.99
+3.3V_RUN on IN3 (solid shape): 271.06,69.31 271.06,68.98 270.93,68.84 269.42,68.84 269.29,68.98 269.29,69.91 269.53,70.15 270.22,70.15
+3.3V_RUN on TOP: 211.96,111.31 210.77,110.13 210.76,110.13 209.9,109.27 207.41,109.27 207.26,109.42 207.26,110.17 207.45,110.36 209.04,110.36 210.67,112 210.69,112 210.69,113.24 210.8,113.34 211.77,113.34 211.96,113.15
+3.3V_RUN on TOP: 140.84,126.76 142.17,126.76 142.81,126.12 143.7,126.12 143.82,125.99 143.82,125.49 143.7,125.36 143.12,125.36 142.74,124.98 142.49,124.98 141.92,125.55 141.03,125.55 140.65,125.93 140.65,126.57
+3.3V_RUN on TOP: 216.63,128.4 216.63,127.32 216.56,127.25 214.27,127.25 214.18,127.15 214.18,122.06 213.86,121.74 211.2,121.74 210.86,122.07 210.86,127.73 211.77,128.63 216.4,128.63
+3.3V_RUN on TOP: 30.1,114.47 32.26,114.47 32.45,114.66 32.45,116.69 32.26,116.88 30.29,116.88 30.1,116.69
+3.3V_RUN on TOP: 251.65,37.28 251.52,37.41 251.52,37.98 250.95,37.98 250.95,38.17 251.52,38.17 251.52,38.81 250.95,38.81 250.95,39 251.52,39 251.52,40.33 251.84,40.65 252.85,40.65 253.11,40.91 253.11,41.86 253.17,41.92 253.36,41.92 253.49,41.79 254.5,41.79 254.57,41.73 254.76,41.73 255.01,41.98 255.01,43.57 253.3,45.29 253.3,49.86 253.49,50.05 254.25,50.05 254.25,49.48 255.07,49.48 255.07,50.05 255.46,50.05 255.46,49.48 256.28,49.48 256.28,50.05 257.49,50.05 257.81,49.73 257.81,49.03 257.93,48.91 257.93,45.98 257.61,45.67 257.61,44.08 257.11,44.08 257.11,43.51 257.61,43.51 257.61,43.32 257.11,43.32 257.11,42.68 257.61,42.68 257.61,41.98 254.88,39.25 254.25,39.25 254,39 254,37.35 253.93,37.28
+3.3V_RUN on BOTTOM: 252.09,80.59 252.92,80.59 253.04,80.46 253.04,78.12 252.85,77.92 252.28,77.92 252.03,78.18 252.03,80.53
+3.3V_RUN on VCC: outline of 172 points within 26.02,39.13 289.11,138.03 ; 1 cut-out
+3.3V_RUN on IN2: 254.99,32.12 258.69,28.42 261.25,28.42 262.65,27.02 262.65,24.46 264.23,22.88 284.84,22.88 287.61,25.66 287.61,30.25 286.97,30.89 271.17,30.89 262.12,39.94 262.12,47.72 261.66,48.19 259.65,50.2 256.26,50.2 254.02,50.2 251.4,50.2 251.06,49.86 251.06,48.28 253.42,45.92 253.42,44.65 252.38,43.61 252.38,34.74
+3.3V_RUN on IN2: 211.43,111.77 211.43,116.77 213.27,118.62 213.27,130.15 213.96,130.83 216.6,130.83 217.62,129.81 217.62,126.78 218.82,125.57 218.82,117.74 217.62,116.54 217.62,115.58 213.81,111.77
+3.3V_RUN on IN3: 180.08,41.67 180.08,41.03 180.78,40.33 196.34,40.33 196.53,40.52 196.53,41.54 196.02,42.05 180.46,42.05
+3.3V_RUN_AUDIO on TOP (solid shape): 281.55,72.91 282.41,72.06 282.41,71.05 282.15,70.79 280.88,70.79 280.73,70.95 280.73,76.15 280.92,76.34 281.55,76.34
+3.3V_RUN_AUDIO_DVDD on TOP (solid shape): 280.22,59.14 280.22,58 280.35,57.87 281.62,57.87 282.95,56.54 283.33,56.54 283.52,56.35 283.52,56.11 283.51,56.1 282.69,56.1 281.49,57.3 280.27,57.3 280.11,57.46 279.59,57.46 279.59,59.27 280.09,59.27
+3.3V_RUN_AUDIO_IO on TOP (solid shape): 283.52,53.45 283.52,53.36 283.46,53.3 282.51,53.3 281.4,52.19 281.4,52.03 281.34,51.97 280.92,51.97 280.79,51.84 280.79,50.7 280.67,50.57 280.16,50.57 280.03,50.7 280.03,52.35 280.09,52.41 280.73,52.41 281.85,53.53 283.45,53.53
+3.3V_RUN_CARD on TOP (solid shape): 293.8,21.87 293.8,20.88 294.31,20.37 294.31,19.97 294.21,19.87 293.8,19.87 293.58,20.1 293.58,21.87 293.63,21.92 293.75,21.92
+3.3V_RUN_CARD on TOP (solid shape): 302.4,20.6 303.48,20.6 303.61,20.48 305.01,20.48 305.13,20.35 305.13,19.97 305.01,19.84 303.93,19.84 303.8,19.71 301.64,19.71 301.45,19.9 300.56,19.9 300.43,20.03 300.43,20.6 300.56,20.73 302.27,20.73
+3.3V_RUN_CARD on IN2: 293.83,19.84 293.51,20.16 293.51,21.47 294.06,22.01 300.55,22.01 301.56,21 301.56,20.34 301.43,20.22 300.46,20.22 299.78,20.9 294.96,20.9 294.85,20.79 294.85,20.79 294.34,20.29 294.34,20.03 294.15,19.84
+3.3V_RUN_DIMM1 on TOP (solid shape): 162.73,51.54 162.73,49.55 162.61,49.42 162.09,49.42 161.96,49.29 161.96,48.39 161.92,48.36 161.31,48.36 161.13,48.53 161.13,49.39 162.16,50.42 162.16,51.54 162.29,51.66 162.61,51.66
+3.3V_RUN_DIMM2 on TOP (solid shape): 236.46,49.75 236.46,48.1 236.23,47.87 234.99,47.87 234.97,47.9 234.97,48.62 235.04,48.69 235.04,49.78 235.17,49.91 236.3,49.91
+3.3V_RUN_F on TOP (solid shape): 134.17,125.12 134.17,123.91 133.99,123.73 132.98,123.73 132.74,123.49 131.69,123.49 131.47,123.72 131.47,124.9 131.91,125.35 133.94,125.35
+3.3V_RUN_QZ1 on TOP (solid shape): 130.01,129.19 130.01,128.59 129.92,128.5 128.38,128.5 128.33,128.55 128.33,129.02 128.47,129.16 128.7,129.16 128.8,129.26 129.94,129.26
+3.3V_RUN_QZ1 on BOTTOM: 129.15,131.77 129.34,131.77 129.47,131.65 129.47,129.8 129.6,129.68 129.6,129.3 129.47,129.17 129.22,129.17 129.09,129.3 129.09,131.71
+3.3V_RUN_UZ3 on TOP: 258.99,50.99 258.99,50.28 258.76,50.05 258.76,48.91 258.63,48.78 258.31,48.78 258,49.1 258,49.73 257.49,50.24 256.03,50.24 256.03,49.67 255.65,49.67 255.65,50.24 254.88,50.24 254.88,49.67 254.5,49.67 254.5,50.24 253.36,50.24 253.17,50.43 253.17,51.95 253.3,52.08 258.06,52.08 258.19,51.95 258.19,51.06 258.25,51 258.63,51 258.64,51.01 258.96,51.01
+3.3V_SSD on TOP (solid shape): outline of 178 points within 260.79,41.79 270.82,53.26
+3.3V_TBT on BOTTOM (solid shape): 36.73,111.68 36.96,111.68 37.09,111.55 37.09,111.41 37.26,111.24 37.33,111.24 37.36,111.21 37.36,111.21 37.47,111.11 37.47,111.09 37.47,110.99 37.47,110.99 37.42,110.94 37.22,110.94 37.19,110.96 36.42,110.96 36.33,110.87 35.95,110.87 35.82,111 35.82,111.76 35.99,111.93 36.48,111.93
+3.3V_TBT on IN3 (solid shape): outline of 127 points within 41.47,113.12 45.39,118.7
+3.3V_TBT on TOP: 30.16,114.31 30.17,114.32 30.62,114.32 30.64,114.34 30.64,114.87 30.66,114.89 30.91,114.89 30.91,114.34 30.92,114.34 31.45,114.34 31.45,114.34 31.45,114.87 31.47,114.89 31.7,114.89 31.7,114.35 31.73,114.33 32.17,114.33 32.2,114.3 34.34,114.3 34.83,114.79 37.3,114.79 37.66,114.43 37.66,113.6 35.82,113.6 35.63,113.41 35.63,112.37 35.91,112.09 36.03,112.03 36.18,112.02 36.2,111.99 36.29,111.99 36.39,111.89 37.98,111.89 38.11,111.76 38.11,110.71 38.04,110.58 38.04,110.43 37.92,110.3 31.31,110.3 30.16,111.46
+3.3V_TBT_FLASH_R on BOTTOM (solid shape): 37.12,125.55 37.12,125.05 37.12,125.05 37.12,122.95 36.87,122.7 36.09,122.7 35.91,122.88 34.91,122.88 34.72,123.07 34.72,123.5 34.93,123.7 36.41,123.7 36.53,123.82 36.53,125.52 36.57,125.56 36.93,125.56 36.95,125.57 37.09,125.57
+3.3V_TBT_S0 on TOP (solid shape): 50.74,102.08 50.74,100.5 50.67,100.43 49.11,100.43 48.89,100.21 47.68,100.21 47.5,100.4 47.5,101.35 47.69,101.54 49.17,101.54 49.91,102.27 50.55,102.27
+3.3V_TBT_SX on IN2 (solid shape): outline of 97 points within 39.91,117.87 43.67,118.9
+3.3V_TBT_SX on BOTTOM: 32.07,119.73 33.26,119.73 34.52,118.47 34.52,117.54 34.43,117.44 33.82,117.44 33.69,117.31 33.69,116.27 33.58,116.16 32.55,116.16 32.04,116.68 32.04,117.35 32.03,117.36 31.48,117.36 31.48,117.36 31.48,117.54 31.48,117.54 32.02,117.54 32.04,117.56 32.04,119.7
+3.3V_TP on TOP (solid shape): 194.89,40.13 194.38,40.13 194,40.51 193.43,40.51 193.43,41.02 193.93,41.02 194.06,41.14 194.89,41.14
+3.3V_VDD_DCIN on TOP (solid shape): 42.18,122.66 42.18,122.15 42.36,121.97 42.87,121.97 42.93,121.92 42.93,121.29 42.85,121.21 41.59,121.21 40.83,121.98 40.17,121.98 40.05,122.09 40.05,122.32 40.11,122.37 40.67,122.37 41.22,122.91 41.92,122.91
+3.3V_VDD_PIC on BOTTOM: 30.23,118.16 31.72,118.16 31.9,117.99 31.9,117.69 31.88,117.68 31.35,117.68 31.34,117.67 31.34,117.22 31.35,117.21 31.89,117.21 31.9,117.21 31.9,116.86 31.74,116.71 30.22,116.71 30.15,116.78 30.15,118.08
+3.3V_VDD_PIC_R on TOP: 58.35,120.91 59.24,120.91 59.43,120.72 59.43,120.09 58.8,119.45 58.8,117.93 58.61,117.74 58.03,117.74 57.91,117.87 57.91,118.56 57.84,118.63 57.21,118.63 57.02,118.82 57.02,119.52 58.22,120.72 58.22,120.79
+3.3V_VPS_UZ12 on TOP: 241.93,131.01 243.45,131.01 243.58,130.88 243.58,130.5 243.33,130.25 243.33,129.36 243.96,128.72 243.96,127.9 243.84,127.77 243.64,127.77 243.52,127.9 243.52,128.66 241.87,130.31 241.87,130.95
+3.3V_VPS_UZ12 on TOP: 241.49,125.17 242.31,125.17 242.44,125.04 242.44,124.85 242.37,124.79 241.61,124.79 241.36,124.53 241.36,123.58 241.1,123.33 240.79,123.33 240.6,123.52 239.39,123.52 239.2,123.33 238.76,123.33 238.12,122.69 237.49,122.69 237.42,122.76 237.42,124.85 237.55,124.98 238.12,124.98 239.01,124.09 240.85,124.09 241.04,124.28 241.04,124.72
+3.3V_WLAN on TOP (solid shape): 290.57,39.7 290.57,38.17 290.52,38.12 290.08,38.12 289.87,37.92 287.87,37.92 287.82,37.97 287.82,38.53 287.97,38.68 288.08,38.68 289.3,39.9 290.37,39.9
+3.3V_WLAN on TOP: 271.71,37.86 271.71,33.35 271.9,33.16 274.44,33.16 274.63,33.35 274.63,38.11 274.38,38.36 273.9,38.84 273.01,38.84 272.32,38.16 272.01,38.16
+3.3V_WLAN on BOTTOM: 264.65,36.28 264.09,36.84 264.09,43.06 264.54,43.51 265.23,43.51 265.23,42.94 265.87,42.94 265.87,43.51 266,43.51 266,42.94 266.63,42.94 266.63,43.51 273.11,43.51 273.55,43.07 273.55,41.87 273.61,41.8 273.61,39.99 273.65,40.03 288.86,40.03 288.88,40.05 289.96,40.05 290.32,40.41 290.32,41.79 290.39,41.87 291.38,41.87 291.52,41.73 291.52,40.47 291.5,40.45 291.5,39.17 289.02,36.69 277.65,36.69 276.85,37.49 275.04,37.49 274.32,36.77 273.61,36.77 273.61,36.41 273.49,36.28
+3.3V_WLAN_UZ4 on TOP (solid shape): 267.34,46.16 267.34,44.58 267.17,44.41 267.14,44.38 267.14,43.58 267.11,43.55 266.45,43.55 266.12,43.88 264.85,43.88 264.79,43.94 264.79,46.04 265.3,46.54 266.95,46.54
+3.3V_WLAN_UZ4 on BOTTOM: 267.33,45.73 267.33,43.95 267.08,43.7 266.44,43.7 266.44,43.19 266.25,43.19 266.25,43.7 265.62,43.7 265.62,43.19 265.43,43.19 265.43,43.7 264.92,43.7 264.66,43.95 264.66,45.6 264.92,45.86 267.2,45.86
+3.3V_WWAN on BOTTOM (solid shape): 279.94,84.34 281.78,84.34 282,84.56 282,84.73 284.09,84.73 284.68,84.13 284.68,80.22 284.68,79.75 284.13,79.2 281.53,79.2 281.52,79.23 281.48,79.26 281.44,79.3 281.4,79.32 281.35,79.34 281.3,79.36 281.25,79.36 281.2,79.36 281.15,79.35 281.1,79.33 281.08,79.32 281.05,79.32 281,79.3 280.95,79.27 280.92,79.25 280.66,79.52 280.66,80.73 280.15,81.23 276.72,81.23 276.66,81.3 276.66,82.19 281.08,82.19 281.08,82.14 281.09,82.08 281.1,82.03 281.13,81.98 281.16,81.94 281.19,81.9 281.24,81.87 281.28,81.84 281.33,81.82 281.38,81.81 281.44,81.81 281.49,81.81 281.54,81.82 281.59,81.84 281.64,81.87 281.68,81.9 281.72,81.94 281.75,81.98 281.77,82.03 281.78,82.08 281.79,82.14 281.79,82.19 281.78,82.24 281.77,82.29 281.75,82.34 281.72,82.38 281.68,82.42 281.64,82.46 281.59,82.48 281.54,82.5 281.49,82.52 281.44,82.52 281.38,82.52 281.33,82.5 281.28,82.48 281.24,82.46 281.19,82.42 281.16,82.38 281.13,82.34 281.1,82.29 281.09,82.24 281.08,82.19 276.66,82.19 276.66,84.54 276.85,84.73 279.55,84.73
+3.3V_WWAN on TOP: 263.64,78.67 263.34,78.97 261.52,78.97 261.3,78.75 260.47,78.75 260.33,78.89 260.33,79.94 260.47,80.08 260.9,80.08 261.3,79.68 263.59,79.68 263.96,79.31 264.88,79.31 265.01,79.18 266.14,79.18 266.31,79 266.31,78.81 266.17,78.67
+3.3V_WWAN on TOP: 270,79.13 272.09,79.13 272.28,79.32 272.54,79.32 272.73,79.13 272.73,78.75 272.41,78.43 270.31,78.43 269.93,78.81 269.93,79.07
+3.3V_WWAN on BOTTOM: 260.49,80.18 260.49,84.26 258.5,86.26 257.97,86.26 257.95,86.24 257.95,85.71 257.22,85.71 257.19,85.73 257.19,86.25 256.77,86.25 256.76,86.24 256.76,85.71 256.76,85.7 256.02,85.7 256,85.72 256,86.25 255.48,86.25 254.24,85.01 254.24,80.73 257.42,80.73 258.05,81.36 259.07,81.36 259.43,81 259.43,78.36 259.51,78.28 260.37,78.28 260.86,78.77 260.86,79.81
+3.3V_WWAN on IN4: 279.18,82.21 278.09,82.21 277.93,82.05 277.93,81.54 278.2,81.27 278.9,81.27 279.27,80.91 279.54,80.91 279.73,81.1 279.73,81.66
+3.3V_WWAN_UZ2 on TOP (solid shape): 258.05,87.87 258.28,87.87 258.38,87.77 258.38,86.12 257.7,85.44 257.7,83.91 257.51,83.72 256.62,83.72 256.49,83.84 255.54,83.84 255.51,83.88 255.51,84.57 255.61,84.67 255.61,86.45 255.8,86.64 255.8,86.96 256.73,87.89 258.05,87.89
+3.3V_WWAN_UZ2 on BOTTOM: 254.57,86.43 254.38,86.62 254.38,88.71 254.64,88.97 258.32,88.97 258.57,88.71 258.57,86.68 258.32,86.43
+5V_ALW on TOP (solid shape): 295.44,69.2 295.44,68.04 295.31,67.92 294.47,67.92 294.39,67.99 294.39,69.33 294.47,69.41 295.23,69.41
+5V_ALW on TOP (solid shape): 256.02,33.76 256.02,33.25 255.52,32.74 255.52,32.3 255.39,32.17 254.37,32.17 254.25,32.3 254.25,33.82 254.37,33.95 255.83,33.95
+5V_ALW on TOP (solid shape): 229.07,38.28 229.07,37.82 229.12,37.77 229.12,37.23 228.49,37.23 228.38,37.34 227.95,37.34 227.88,37.41 227.88,38.28 228,38.4 228.94,38.4
+5V_ALW on TOP (solid shape): 293.03,73.68 293.2,73.52 293.2,71.2 293.14,71.14 292.23,71.14 292.22,71.13 291.02,71.13 290.95,71.19 290.95,73.89 291,73.94 293.03,73.94
+5V_ALW on TOP (solid shape): 270.22,42.96 270.2,42.56 270.57,42.4 270.57,41.57 270.15,41.22 270.57,40.87 270.57,38.81 270.31,38.55 269.55,38.55 268.98,37.98 268.6,37.98 268.45,37.83 268.45,37.02 268.18,36.75 267.19,36.75 267.13,36.82 267.13,37.16 266.57,37.72 266.57,37.73 266.5,37.79 266.5,38.81 267.53,39.83 267.53,40.49 268.41,41.37 268.41,42.11 268.48,42.17 269.09,42.17 269.15,42.12 269.21,42.14 269.27,42.12 269.84,42.39 269.3,42.71 269.3,42.99 270.19,42.99
+5V_ALW on BOTTOM (solid shape): 71.75,99.45 71.43,99.13 68.73,99.13 68.57,99.29 68.57,100.92 68.68,101.03 71.75,101.03
+5V_ALW on TOP: 208.91,36.21 209.35,36.21 210.12,35.44 210.43,35.44 210.56,35.32 210.56,33.86 210.24,33.54 207.26,33.54 206.12,34.68 206.12,36.14 206.18,36.21 206.88,36.21 206.88,35.63 207.7,35.63 207.7,36.21 208.08,36.21 208.08,35.63 208.91,35.63
+5V_ALW on TOP: 298.33,50.43 298.33,50.92 298.23,51.02 297.56,51.02 297.26,51.32 295.78,51.32 295.59,51.13 294.57,51.13 294.51,51.06 294.51,49.41 294.64,49.29 295.78,49.29 296.54,50.05 297.62,50.05 297.87,50.3 298.2,50.3
+5V_ALW on BOTTOM: 188.84,131.14 189.54,130.44 189.54,129.68 189.61,129.61 189.8,129.61 189.86,129.68 189.86,131.84 189.8,131.9 188.91,131.9 188.84,131.84
+5V_ALW on BOTTOM: 100.13,85.86 99.44,85.86 99.06,85.48 98.61,85.48 97.59,84.47 97.59,84.08 97.34,83.83 96.52,83.83 96.32,83.64 96.32,82.88 96.45,82.75 97.47,82.75 97.59,82.88 97.59,83.51 97.72,83.64 98.61,83.64 98.8,83.83 98.8,84.85 99.5,85.54 100.13,85.54 100.2,85.61 100.2,85.8
+5V_ALW on BOTTOM: 179.19,131.84 178.37,131.84 178.24,131.71 178.24,130.88 178.62,130.5 179.51,130.5 179.89,130.12 179.89,129.55 179.95,129.49 180.08,129.49 180.21,129.61 180.21,130.31 179.38,131.14 179.38,131.65
+5V_ALW on BOTTOM: 27.3,89.67 28.19,89.67 28.38,89.48 28.38,88.53 28.13,88.28 26.79,87.64 26.35,87.45 25.59,87.45 25.4,87.64 25.4,88.91 25.84,89.35 26.98,89.35
+5V_ALW on IN1: 290.28,70.6 294.32,66.56 294.32,49.1 294.44,48.97 297.43,48.97 297.87,49.41 297.87,68.73 293.32,73.28 291.25,73.28 290.28,72.31
+5V_ALW on IN1: 189.29,99.71 194.43,99.71 195.51,100.78 195.51,106.12 200.41,111.02 200.41,119.53 202.4,121.51 202.4,128.27 199.42,131.25 192.93,131.25 190.81,133.36 164.14,133.36 162.17,131.39 157.03,131.39 156.01,130.38 156.01,128.15 156.59,127.58 160.59,127.58 160.65,127.65 163.13,127.65 163.32,127.84 186.56,127.84 186.88,127.52 186.94,127.58 189.16,125.36 189.16,120.14 191.45,117.85 191.45,115.01 189.16,112.72 189.16,99.83
+5V_ALW on VCC: outline of 111 points within 26.02,1.17 307.72,102.59
+5V_ALW on IN2: 104.26,101.86 104.26,96.91 104.77,96.4 110.36,96.4 112.01,98.05 112.01,101.36 111.18,102.18 104.58,102.18
+5V_ALW on IN3: 215.3,38.81 229.04,38.81 230.25,37.6 254.12,37.6 256.66,35.06 256.66,31.57 255.14,30.05 206.88,30.05 206.34,30.59 206.34,38.14 207.92,39.72 214.38,39.72 ; 1 cut-out
+5V_ALW_PDA on TOP (solid shape): 70.48,103.77 70.48,102.06 70.3,101.89 69.65,101.89 66.86,104.67 66.86,104.85 66.86,104.89 66.86,104.93 66.86,105.29 67.05,105.48 68.77,105.48
+5V_ALW_PDA on BOTTOM: 71.22,101.21 71.21,101.22 71.21,101.76 71.21,101.76 70.47,101.76 70.46,101.76 70.46,101.22 70.46,101.21 70.01,101.21 70.01,101.22 70.01,101.76 70.01,101.76 69.27,101.76 69.26,101.76 69.26,101.22 69.26,101.21 68.04,101.21 67.63,101.62 67.63,103.38 66.58,104.44 66.58,106.39 66.66,106.47 68.52,106.47 68.71,106.65 70.1,106.65 70.48,106.27 70.48,103.28 70.65,103.12 71.47,103.12 71.7,102.89 71.64,102.54 71.9,102.31 71.9,101.28 71.83,101.21
+5V_ALWP on TOP: 212.09,35.76 212.28,35.95 212.28,40.33 212.12,40.49 204.43,40.49 203.58,39.63 201.29,39.63 200.97,39.32 200.97,38.17 201.42,37.73 205.16,37.73 205.54,37.35 205.54,36.78 205.93,36.4 207.07,36.4 207.1,36.43 207.1,35.92 207.13,35.89 207.45,35.89 207.45,36.4 208.34,36.4 208.34,35.89 208.66,35.89 208.66,36.4 209.61,36.4 210.24,35.76
+5V_ALWP on BOTTOM: 212.15,40.65 212.34,40.46 212.34,36.08 212.02,35.76 205.04,35.76 202.56,38.24 201.86,38.24 201.67,38.43 201.67,39.44 201.8,39.57 203.45,39.57 204.53,40.65
+5V_HDD on TOP (solid shape): outline of 105 points within 251.32,33.28 260.28,37.09
+5V_HDD on BOTTOM (solid shape): 252.15,37.62 252.52,37.25 252.52,36 252.34,35.82 251.46,35.82 251.2,36.08 251.2,37.03 250.88,37.35 250.88,39.03 250.94,39.09 252.15,39.09
+5V_HDD_UZ23 on TOP (solid shape): 259.01,33.09 259.52,33.09 259.52,33.67 259.9,33.67 260.15,33.41 260.15,31.76 260.09,31.7 258.28,31.7 257.8,32.17 256.98,32.17 256.91,32.24 256.91,33.41 257.17,33.67 259.01,33.67
+5V_PD_VDD on TOP: 58.45,123.29 58.29,123.45 57.72,123.45 57.59,123.58 57.59,124.22 57.67,124.29 60.57,124.29 60.94,124.66 62.86,124.66 63.38,124.13 63.38,122.88 63.13,122.63 62.16,122.63 61.1,121.57 58.69,121.57 58.45,121.81
+5V_RUN on TOP (solid shape): 227.67,38.28 227.67,37.31 227.62,37.26 226.35,37.26 226.35,37.64 226.43,37.72 226.78,37.72 227.06,38 227.06,38.35 227.17,38.45 227.5,38.45
+5V_RUN on TOP (solid shape): 264.54,40.46 264.54,40.02 263.96,40.02 263.96,39.38 264.54,39.38 264.54,39.19 263.96,39.19 263.96,38.62 264.54,38.62 264.54,38.21 264.27,37.98 264.32,37.64 263.96,37.28 256.29,37.28 256.09,37.48 256.09,40.21 257.17,41.29 263.71,41.29
+5V_RUN on BOTTOM (solid shape): 94.99,89.21 94.99,88.79 94.79,88.59 94.79,88.58 93.69,87.48 93.5,87.48 92.77,88.21 92.77,88.59 94.01,89.83 94.36,89.83
+5V_RUN on TOP: 289.58,75.81 289.56,75.79 289.08,75.79 289.07,75.78 289.07,75.25 289.07,75.25 288.82,75.25 288.81,75.79 288.8,75.8 288.27,75.8 288.27,75.79 288.27,75.25 288.26,75.25 288.01,75.25 288.01,75.25 288.01,75.79 288.01,75.79 287.31,75.79 286.7,76.41 286.7,77.99 287.21,78.5 291.97,78.5 292.29,78.81 292.29,79.32 292.95,79.98 296.68,79.98 296.86,79.8 296.86,77.67 296.16,76.97 291.14,76.97 289.98,75.81
+5V_RUN on TOP: 117.49,133.85 117.49,134.81 117.27,135.03 117.27,135.62 117.15,135.75 116.51,135.75 116.01,135.24 116.01,133.91 116.19,133.73 117.37,133.73
+5V_RUN on TOP: 96.13,88.85 96.13,88.66 95.05,87.58 92.71,87.58 91.94,88.34 91.94,88.47 92.39,88.91 93.4,88.91 94.55,90.05 94.93,90.05
+5V_RUN on VCC: 249.82,34.57 247.61,36.78 213.4,36.78 210.48,39.7 208.34,39.7 201.93,46.11 181.08,46.11 179.23,47.95 111.26,47.95 104.02,55.2 104.02,75.1 91.27,87.85 91.99,88.57 99.72,88.57 111.67,76.63 111.67,73.02 125.43,59.26 202.54,59.26 221.64,40.16 227.34,40.16 230.31,43.13 246.59,43.13 251.1,38.62 254.23,38.62 255.41,39.8 255.41,43.07 259.4,47.06 268.01,47.06 271.94,51 271.94,70.63 279.17,77.86 289.26,77.86 290.63,76.49 290.63,73.65 276.56,59.58 276.56,54.05 275.88,53.37 275.88,49.43 261.01,34.57
+5V_RUN_AUDIO on TOP: 284.92,64.21 285.11,64.02 286.51,64.02 286.76,64.27 288.22,64.27 288.35,64.4 288.35,64.59 288.41,64.65 289.17,64.65 289.36,64.46 290.25,64.46 290.44,64.65 290.44,64.72 290.98,65.25 290.98,67.42 289.36,69.03 289.36,73.04 290.32,73.99 290.32,75.38 290.06,75.64 289.24,75.64 289.24,75.07 287.84,75.07 287.84,75.64 286.57,75.64 284.92,73.99
+5V_RUN_PVDD_L on TOP (solid shape): 287.55,63.05 287.55,60.64 287.01,60.1 286.83,59.92 286.83,58.47 286.35,57.99 286.35,56.56 286.3,56.5 286.17,56.5 286.11,56.56 286.11,58.22 286.44,58.55 286.44,60.24 286.95,60.75 286.95,61.86 286.95,61.87 286.95,61.94 286.7,62.19 283.08,62.19 282.51,61.62 282.51,59.14 283.47,58.17 283.76,58.17 284.32,57.61 284.32,56.56 284.25,56.49 284.19,56.49 284.13,56.56 284.13,57.32 284.13,57.4 283.82,57.7 282.84,57.7 281.8,58.75 281.8,62.37 282.63,63.21 287.4,63.21
+5V_RUN_UZ4 on TOP (solid shape): 267.14,42.16 267.14,39.69 265.49,38.03 264.92,38.03 264.89,38.06 264.85,38.11 264.8,38.15 264.73,38.22 264.73,40.51 264.31,40.92 264.31,41.81 264.38,41.88 266.13,41.88 266.45,42.2 267.1,42.2
+5V_USB_CHG_PWR on TOP: 297.94,73.29 297.86,73.21 297.86,71.97 297.67,71.78 296.87,71.78 296.28,71.2 296.22,71.14 295.42,71.14 295.36,71.2 295.36,72.27 295.59,72.5 295.59,72.53 295.78,72.72 295.78,74.3 295.71,74.37 295.59,74.37 295.33,74.62 295.33,74.94 295.45,75.05 296.93,75.05 297.94,74.05
+5V_USB_CHG_PWR on BOTTOM: 303.03,63.55 303.48,63.1 303.48,63.09 303.48,61.73 302.95,61.2 300.62,61.2 300.06,61.77 298.79,61.77 298.51,62.05 294.76,62.05 294.17,62.65 294.17,64.44 294.47,64.74 295.38,64.74 295.51,64.62 300.77,64.62 301.84,63.55
+5V_USB_CHG_PWR on IN3: 298.05,75.05 298.31,74.8 298.31,70.89 297.98,70.56 295.74,70.56 295.51,70.79 295.51,74.9 295.66,75.05
+5V_USB_CHG_PWR on IN3: 298.32,67.7 296.1,67.7 294.64,66.24 294.64,65.03 294.29,64.69 294.29,62.96 295.27,61.99 297.87,61.99 298.57,62.68 298.57,67.45
+13.2VB_BATT on TOP: 116.33,41.98 116.33,40.08 115.75,39.51 110.87,39.51 110.49,39.89 110.49,42.05 110.8,42.36 115.95,42.36
+13.2VB_BATT on BOTTOM: 157.48,43.7 157.79,43.38 157.79,40.64 157.44,40.28 153.14,40.28 153.03,40.4 153.03,41.41 152.71,41.73 152.71,42.36 152.46,42.62 151.76,42.62 151.57,42.81 151.57,43.38 151.89,43.7
+13.2VB_BATT on IN2: 157.49,43.91 157.87,43.53 157.87,40.66 157.44,40.23 150.1,40.23 148.62,41.7 141.31,41.7 140.6,40.99 136.43,40.99 134.4,38.96 128.61,38.96 126.53,41.04 122.66,41.04 120.58,38.96 111.39,38.96 110.4,39.95 110.4,43.23 112.3,45.13 130.46,45.13 131.68,43.91
+13.2VB_BATT on IN3: 119.07,42.29 129.07,42.29 129.29,42.52 134.04,42.52 134.27,42.75 134.27,43.33 134.86,43.91 157.49,43.91 157.87,43.53 157.87,40.66 157.44,40.23 150.1,40.23 148.62,41.7 141.31,41.7 140.6,40.99 136.43,40.99 134.4,38.96 119.85,38.96 119.34,39.47 110.88,39.47 110.4,39.95 110.4,42.28 110.61,42.49 118.87,42.49
+13.2VB_PBATT_C on TOP: 157.35,38.68 157.35,39.74 157.06,40.03 153.22,40.03 151.96,41.29 146.11,41.29 145.85,41.03 145.85,38.45 145.91,38.4 152.84,38.4 152.86,38.38 157.05,38.38
+13.2VB_PBATT_C on BOTTOM: 145.35,43.76 149.54,43.76 149.73,43.57 149.73,35.95 149.98,35.7 152.27,35.7 153.03,36.46 153.03,39.95 153.13,40.05 157.56,40.05 157.86,39.76 157.86,37.98 157.54,37.67 157,37.67 153.98,34.65 153.98,31.63 153.47,31.13 146.3,31.13 145.16,32.27 145.16,43.57
+13.2VB_PBATT_C on IN1: 145.98,41.41 151.79,41.41 153.12,40.08 156.9,40.08 157.22,39.76 157.22,37.92 157.02,37.72 146.13,37.72 145.66,38.19 145.66,41.09
+13.2VB_PBATT_C on IN2: 145.98,41.41 151.79,41.41 153.12,40.08 156.9,40.08 157.22,39.76 157.22,39.51 156.97,39.25 152.33,39.25 150.8,37.72 146.13,37.72 145.66,38.19 145.66,41.09
+13.2VB_PBATT_C on IN3: 145.98,41.41 148.69,41.41 150.02,40.08 156.9,40.08 157.22,39.76 157.22,39.44 157.03,39.25 152.33,39.25 152.2,39.13 152.2,39.11 150.81,37.72 146.13,37.72 145.66,38.19 145.66,41.09
+13.2VB_PBATT_C on IN4: 145.98,41.41 151.79,41.41 153.12,40.08 156.9,40.08 157.22,39.76 157.22,38.11 156.83,37.72 146.13,37.72 145.66,38.19 145.66,41.09
+13.5VB on TOP (solid shape): 198.69,83.45 199.39,83.45 199.39,84.02 199.51,84.02 199.51,83.51 200.32,83.51 200.36,83.55 200.69,83.55 200.7,83.54 202.76,83.54 203.01,83.29 203.01,82.33 202.81,82.13 198.3,82.13 198.02,82.42 198.02,83.51 198.02,83.51 198.62,83.51 198.62,84.02 198.69,84.02
+13.5VB on TOP (solid shape): 131.52,134.14 131.52,132.87 131.44,132.78 130.19,132.78 129.98,132.85 129.78,132.78 129.67,132.78 129.47,132.98 129.47,133.69 129.41,133.75 128.58,133.75 128.39,133.94 128.39,134.63 128.52,134.76 130.91,134.76
+13.5VB on TOP: 240.7,52.45 239.67,53.48 237.79,53.48 237.64,53.33 237.64,50.15 237.9,49.88 242.22,49.88 242.6,50.26 242.6,52.14 242.3,52.45
+13.5VB on TOP: 117.28,37.41 117.28,32.33 117.66,31.95 117.66,29.54 117.6,29.47 113.41,29.47 113.34,29.54 113.34,30.68 113.53,30.87 113.53,36.27 113.79,36.52 114.61,36.52 114.8,36.71 114.8,37.16 114.68,37.28 113.91,37.28 113.85,37.35 113.85,37.73 113.91,37.67 117.03,37.67 ; 1 cut-out
+13.5VB on TOP: 182.49,32.24 182.49,32.81 182.68,32.81 182.68,32.24 183.32,32.24 183.32,32.81 183.51,32.81 183.51,32.24 184.21,32.24 184.46,31.99 184.46,31.89 194.24,31.89 195.32,30.81 199.39,30.81 199.89,31.32 199.89,33.41 199.93,33.44 202.97,33.44 203.07,33.35 203.07,33.16 203.2,33.03 203.58,33.03 203.64,32.97 203.64,30.05 203.26,29.66 181.1,29.66 181.09,29.67 165.05,29.67 164.37,30.35 164.37,34.26 162.67,35.96 162.67,36.85 163.18,37.36 168,37.36 168.79,36.57 168.79,32.33 170.09,31.04 177.63,31.04 178.84,32.24
+13.5VB on TOP: 252.98,45.16 253.17,44.97 253.17,44.71 252.79,44.33 251.65,44.33 251.46,44.52 251.46,45.86 251.71,46.11 251.71,49.64 251.95,49.88 252.74,49.88 252.98,49.64
+13.5VB on TOP: 150.12,119.71 149.56,119.71 148.88,119.02 148.09,119.02 147.89,118.82 147.89,117.78 148.45,117.78 148.45,117.4 147.89,117.4 147.89,116.58 148.45,116.58 148.45,116.2 147.89,116.2 147.89,111.52 147.47,111.1 134.01,111.1 133.85,111.26 127.88,111.26 124.26,114.88 112.26,114.88 106.42,120.72 90.36,120.72 88.9,122.18 88.9,124.79 89.53,125.42 97.91,125.42 98.86,124.47 122.55,124.47 129.38,117.64 143.73,117.64 145.85,119.77 145.85,121.8 146.05,121.99 146.74,121.99 147.12,122.37 147.12,124.43 147.42,124.72 149.47,124.72 149.94,125.19 150.55,125.19 150.78,124.97 150.78,123.67 150.2,123.09 150.2,119.78
+13.5VB on BOTTOM: outline of 90 points within 80.13,64.91 150.68,135.81
+13.5VB on BOTTOM: 113.47,35.32 113.22,35.57 113.22,42.36 113.79,42.94 117.09,42.94 117.22,42.81 117.22,32.46 117.79,31.89 117.79,29.6 117.62,29.44 113.32,29.44 113.22,29.54 113.22,29.79 113.47,30.05
+13.5VB on BOTTOM: 251.39,47 252.92,47 253.17,46.75 253.17,44.65 252.85,44.33 251.46,44.33 251.2,44.59 251.2,45.16 250.69,45.16 250.69,45.35 251.2,45.35 251.2,45.98 250.69,45.98 250.69,46.17 251.2,46.17 251.2,46.81
+13.5VB on BOTTOM: 203.04,33.13 203.04,30.9 202.88,30.74 200.53,30.74 200.4,30.87 200.4,31.44 199.83,31.44 199.83,31.63 200.34,31.63 200.34,32.27 199.83,32.27 199.83,32.4 200.4,32.4 200.4,33.16 200.72,33.47 202.69,33.47
+13.5VB on VCC: 112.64,29.42 112.64,35.59 113.51,36.46 129.01,36.46 130.78,38.24 163.26,38.24 164.14,37.36 164.14,29.42 141.71,29.42 138.83,32.3 135.52,33.67 132.22,32.3 129.34,29.42
+13.5VB on IN2: outline of 587 points within 82.69,29.47 253.17,125.04
+13.5VB on IN3: 129.92,134.31 129.92,130.57 130.87,129.61 136.96,129.61 140.33,126.25 142.49,126.25 145.71,123.03 146.26,123.03 147.42,121.87 149.6,121.87 150.08,122.34 150.08,125.34 149.74,125.68 146.36,125.68 144.08,127.96 144.08,129.99 142.68,131.39 132.58,131.39 131.88,132.09 131.88,134.38 131.57,134.69 130.3,134.69
+13.5VB on IN3: 94.36,33.35 86.74,33.35 85.15,34.94 85.15,45.86 86.93,50.49 88.39,56.14 88.39,56.33 88.51,56.46 88.51,64.72 88.2,65.03 87.75,68.02 87.24,70.3 87.24,70.56 86.04,74.11 84.51,77.29 82.86,80.02 82.86,124.66 83.12,124.91 91.69,124.91 91.94,124.66 91.94,122.06 88.83,118.95 88.83,84.08 95.69,77.23 95.69,60.59 94.61,59.51 94.61,55.19 93.4,53.99 93.4,45.98 93.85,45.54 105.98,45.54 106.36,45.16 106.36,42.17 110.23,38.3 117.22,38.3 119.31,36.21 120.84,36.21 120.84,36.33 122.3,37.79 145.28,37.79 145.6,37.48 150.93,37.48 152.52,39.06 157.35,39.06 157.54,39.25 157.54,39.76 159.32,41.54 165.16,41.54 167.64,39.06 171.51,39.06 172.52,38.05 193.1,38.05 194.37,36.78 202.18,36.78 204.21,34.74 204.21,31 203.13,29.92 195.13,29.92 193.61,31.44 192.21,31.44 190.62,29.86 164.63,29.86 163.25,33.16 163.25,33.17 163.11,33.51 162.85,33.94 162.37,34 162.19,34.03 156.18,33.99 153.61,29.86 141.35,29.86 137.54,33.67 133.35,33.67 129.15,29.47 98.23,29.47 ; 1 cut-out
+13.5VB on IN3: 242.29,47.94 245.92,47.94 249.58,44.27 252.92,44.27 253.17,44.52 253.17,45.35 250.88,47.64 250.88,47.83 246.19,52.53 242.2,52.53 241.79,52.12 241.79,48.44
+13.5VB_1.05VALWP on TOP (solid shape): 200.27,85.04 200.27,83.83 200.21,83.77 199.77,83.77 199.77,84.27 199.13,84.27 199.13,83.7 198.94,83.7 198.94,84.27 198.37,84.27 198.37,83.77 196.53,83.77 196.08,83.32 196.08,82.62 195.96,82.5 194.81,82.5 194.75,82.56 194.75,84.85 195.07,85.16 200.15,85.16
+13.5VB_1.05VALWP on BOTTOM (solid shape): 196.62,85.83 196.62,85 196.08,84.47 196.08,82.62 195.83,82.37 194.88,82.37 194.64,82.6 194.64,85.51 195.04,85.91 196.54,85.91
+13.5VB_3V on TOP: 248.22,44.78 249.42,44.78 249.74,44.46 249.74,41.67 249.55,41.48 248.15,41.48 247.96,41.67 247.96,44.52
+13.5VB_3V on BOTTOM: 251.01,44.65 250.47,44.11 250.47,41.67 250.07,41.27 248.07,41.27 247.86,41.48 247.86,44.4 248.24,44.78 248.24,46.18 248.18,46.24 247.61,46.24 247.48,46.37 247.48,47.83 247.55,47.89 248.44,47.89 248.82,47.51 250.82,47.51 251.01,47.32 251.01,46.37 250.44,46.37 250.44,45.73 251.01,45.73 251.01,45.6 250.44,45.6 250.44,44.97 251.01,44.97
+13.5VB_5V on TOP: 197.61,33.92 198.62,33.92 198.81,33.73 198.81,31.76 198.75,31.7 197.54,31.7 197.42,31.82 197.42,33.73
+13.5VB_5V on BOTTOM: 198.24,35.25 199.7,35.25 199.83,35.13 199.83,33.67 200.15,33.35 200.15,32.65 199.58,32.65 199.58,32.01 200.15,32.01 200.15,31.82 199.58,31.82 199.58,31.19 200.15,31.19 200.15,30.87 197.67,30.87 197.48,31.06 197.48,32.59 197.35,32.71 197.35,33.6 198.05,34.3 198.05,35.06
+13.5VB_CPU on TOP: outline of 102 points within 148.09,115.52 202.31,136.73
+13.5VB_CPU on BOTTOM: 185.8,136.79 164.65,136.79 164.59,136.73 164.59,133.8 162.94,132.15 162.94,129.36 162.75,129.17 161.41,129.17 161.29,129.04 161.29,128.03 161.41,127.9 163.95,127.9 164.59,127.26 165.67,127.26 165.73,127.33 165.73,130.5 166.11,130.88 166.56,130.88 166.62,130.95 166.62,133.61 167.13,134.12 172.84,134.12 173.16,133.8 173.16,130.44 172.97,130.25 172.97,129.3 172.84,129.17 171.51,129.17 171.45,129.11 171.45,127.9 171.57,127.77 175.38,127.77 175.51,127.9 175.51,134.25 175.7,134.44 183.64,134.44 183.83,134.25 183.83,132.03 183.64,131.84 182.75,131.84 182.68,131.77 182.68,130.88 182.94,130.63 182.94,129.42 182.75,129.23 181.35,129.23 181.29,129.17 181.29,128.03 181.41,127.9 184.4,127.9 185.29,128.79 185.29,130.76 186.05,131.52 186.05,134.06 186.49,134.5 196.34,134.5 196.46,134.38 196.46,132.15 196.34,132.03 193.35,132.03 193.23,131.9 193.23,130.95 192.59,130.31 192.59,129.49 192.4,129.3 191,129.3 190.94,129.23 190.94,128.09 191.07,127.96 194.37,127.96 195.26,127.07 199,127.07 199.39,126.69 202.12,126.69 202.24,126.82 202.24,135.27 200.78,136.73 192.91,136.73 191.89,135.71 186.88,135.71
+13.5VB_CPU on IN2: 185.8,135.52 186.43,134.88 195.19,134.88 195.89,135.58 198.43,135.58 199.58,134.44 199.58,124.66 197.23,122.31 154.11,122.31 153.28,123.14 153.28,124.47 154.62,125.8 155.76,125.8 156.21,126.25 156.21,130.76 157.48,132.03 161.09,132.03 164.59,135.52
+13.5VB_CPU on IN4: 194.69,131.46 195.51,130.63 195.51,124.72 193.21,122.43 183.78,122.43 182.89,121.54 154.25,121.54 153.03,122.76 153.03,125.99 156.33,129.3 163,129.3 165.16,131.46
+13.5VB_DDR on TOP: 182.3,36.33 178.11,36.33 177.99,36.46 177.99,38.43 178.18,38.62 182.75,38.62 184.72,36.65 184.72,32.97 184.21,32.46 183.7,32.46 183.7,33.03 183.07,33.03 183.07,32.46 182.94,32.46 182.94,33.03 182.3,33.03 182.3,32.46 181.86,32.46 181.73,32.59 181.73,33.41 182.56,34.24 182.56,36.08
+13.5VB_DDR on BOTTOM: 175.64,37.54 177.16,37.54 178.18,38.55 180.08,38.55 180.34,38.3 180.34,36.46 180.21,36.33 178.3,36.33 178.18,36.46 178.18,36.71 177.92,36.97 175.64,36.97 175.57,37.03 175.57,37.48
+13.5VB_GT on TOP: 97.79,91.32 97.79,87.45 98.29,86.94 99.88,86.94 100.01,86.81 101.6,86.81 101.78,87 101.78,93.33 101.53,93.57 98.67,93.57 98.4,93.29 97.34,93.29 96.83,93.8 96.83,94.18 95.37,95.64 95.37,99.13 94.74,99.77 91.56,99.77 90.99,99.2 90.99,95.77 94.99,91.77 97.34,91.77
+13.5VB_GT on BOTTOM: 88.01,99.9 88.01,99.07 87.43,99.07 87.43,98.75 88.01,98.75 88.01,97.86 87.5,97.86 87.5,97.55 88.01,97.55 88.01,95.96 91.24,92.72 93.02,92.72 94.04,91.7 97.59,91.7 97.72,91.58 97.72,88.72 97.91,88.53 100.33,88.53 100.45,88.4 100.45,87.07 100.58,86.94 101.79,86.94 101.85,87.01 101.85,93.1 101.72,93.23 97.53,93.23 96.07,94.69 94.17,94.69 93.02,95.83 93.02,99.51 92.45,100.09 88.2,100.09
+13.5VB_IR on BOTTOM (solid shape): 104.08,133.86 104.08,133.03 103.97,132.91 102.65,132.91 102.29,133.21 101.94,132.91 101.45,132.91 100.54,132 99.58,132 99.43,132.15 99.43,132.94 99.44,132.95 100.2,132.95 101.23,133.99 103.96,133.99
+13.5VB_SA on TOP: 198.81,118.82 199.39,118.82 200.91,120.34 200.91,122.44 200.66,122.69 200.66,125.74 198.75,127.65 198.75,128.53 198.81,128.6 199.64,128.6 199.64,129.11 199.96,129.11 199.96,128.6 200.78,128.6 200.78,129.17 201.16,129.17 201.16,128.6 202.75,128.6 204.34,127.01 204.34,117.61 204.02,117.29 201.29,117.29 201.04,117.55 198.75,117.55 198.56,117.74 198.56,118.56
+13.5VB_SA on BOTTOM: 200.02,121.42 199.89,121.3 199.89,120.47 200.21,120.15 200.21,118.88 200.15,118.82 198.69,118.82 198.56,118.69 198.56,117.49 198.62,117.42 201.61,117.42 201.8,117.23 204.34,117.23 204.72,116.85 204.72,112.72 205.04,112.41 206.31,112.41 206.69,112.79 206.69,120.53 205.8,121.42
+13.5VB_VCHGR on TOP: 108.71,38.94 108.71,37.35 108.83,37.22 111.06,37.22 111.25,37.03 111.25,35.95 111.31,35.89 112.77,35.89 112.83,35.95 112.83,36.46 112.77,36.52 112.07,36.52 111.88,36.71 111.88,37.22 112.01,37.35 113.09,37.35 113.6,37.86 114.8,37.86 115.31,38.36 115.31,39.19 115.18,39.32 109.09,39.32
+19.5V_AC on BOTTOM: 90.17,38.94 90.61,39.38 90.61,40.27 91.18,40.27 91.18,40.65 90.61,40.65 90.61,41.48 91.18,41.48 91.18,41.86 90.61,41.86 90.61,42.87 90.36,43.13 87.31,43.13 87.05,42.87 87.05,41.73 86.8,41.48 86.36,41.48 86.36,40.84 86.1,40.59 85.78,40.59 85.53,40.84 85.53,41.48 85.34,41.67 82.99,41.67 82.86,41.54 82.86,39.63 83.56,38.94
+19.5V_CHARGER on TOP: 94.8,38.81 95.18,38.43 95.18,37.48 94.86,37.16 84.39,37.16 84.2,37.35 84.2,38.55 84.45,38.81
+19.5V_CHARGER on BOTTOM: 100.26,43.44 91.37,43.44 90.86,42.94 90.86,42.05 91.37,42.05 91.37,41.22 90.86,41.22 90.86,40.84 91.37,40.84 91.37,40.02 90.86,40.02 90.86,39.44 90.23,38.81 86.29,38.81 86.16,38.68 86.16,37.28 86.29,37.16 94.93,37.16 96.13,38.36 100.01,38.36 100.45,38.81 100.45,43.25
+19.5V_DC_IN on BOTTOM: 71.5,125.93 69.85,125.93 69.65,125.74 69.65,121.74 69.97,121.42 69.97,118.95 70.16,118.76 71.69,118.76 71.94,119.01 71.94,122.57 72.96,123.58 72.96,125.68 72.89,125.74 71.69,125.74
+19.5V_DC_IN_SS on BOTTOM: 75.69,126.5 73.21,126.5 73.08,126.38 73.08,123.39 72.07,122.37 72.07,116.15 73.08,115.14 76.2,115.14 76.39,115.33 76.39,118.69 76.07,119.01 75.05,119.01 74.73,119.33 74.73,122.76 75.81,123.84 75.81,126.38
+19.5V_DCIN_JACK on BOTTOM (solid shape): 68.59,126.3 68.59,126.05 68.7,125.93 69.15,125.93 69.34,125.74 69.34,121.68 69.27,121.61 65.08,121.61 64.89,121.8 64.89,124.85 65.02,124.98 66.8,124.98 67.51,125.69 67.51,126.07 67.81,126.38 68.51,126.38
+19.5V_SDC_IN on TOP: 77.4,123.96 76.07,123.96 75.8,123.7 75.8,123.28 76.13,122.95 76.13,120.91 76.26,120.79 77.08,120.79 77.34,120.53 77.34,118.95 76.96,118.56 76.96,117.1 77.66,116.41 77.66,115.71 77.73,115.63 79.31,115.63 79.65,115.97 82.64,115.97 82.93,116.26 82.93,124.06 82.88,124.11 79.27,124.11 79.18,124.03 79.18,121.17 79.05,121.04 78.23,121.04 78.21,121.05 77.96,121.05 77.76,121.26 77.76,122.96 77.58,123.14 77.58,123.78
+19.5V_SDC_IN on BOTTOM: 75.12,122.44 81.85,122.44 82.23,122.06 82.23,115.39 81.91,115.07 76.83,115.07 76.7,115.2 76.7,120.03 76.07,120.66 75.12,120.66 74.99,120.79 74.99,122.31
+19.5V_SDC_IN on BOTTOM: 130.81,40.14 131,39.95 131,38.43 130.68,38.11 130.36,38.11 130.17,38.3 129.41,38.3 129.34,38.36 129.34,38.87 129.54,39.06 129.54,39.95 129.73,40.14
+19.5V_SDC_IN on BOTTOM: 83.82,42.56 83.75,42.62 83.75,43.57 84.01,43.83 84.01,44.02 84.13,44.14 84.13,44.21 84.51,44.59 84.51,44.84 84.64,44.97 84.64,45.16 84.76,45.27 86.04,48.14 86.99,50.81 87.69,53.54 88.07,55.83 88.27,56.9 88.45,60.34 88.7,60.59 89.78,60.59 90.29,60.08 90.29,59.19 91.5,57.99 91.5,44.46 90.04,43 87.12,43 86.99,42.87 86.99,41.67 86.86,41.54 86.29,41.54 86.23,41.6 86.23,42.43 86.1,42.56
+19.5V_SDC_IN on IN4: 91.12,47 90.86,47.25 90.86,51.45 91.72,52.3 91.72,55.22 98.48,61.99 98.48,69.1 97.72,69.86 92.26,69.86 91.44,69.03 91.44,65.35 89.72,63.64 89.09,63.64 88.45,63 88.45,57.99 88.07,55.89 88.01,55.57 87.94,54.81 87.5,52.84 86.36,48.71 84.2,44.21 83.81,43.58 83.81,43.5 83.82,43.49 83.82,42.87 84.16,42.52 90.77,42.52 91.12,42.87
+19.5V_SDC_IN on IN4: 90.42,119.77 90.42,116.79 89.72,116.09 76.96,116.09 75.94,117.1 75.94,120.85 76.35,121.26 80.73,121.26 80.98,121.01 89.18,121.01
+20V_LDO_INPUT on TOP (solid shape): 81.75,112.16 81.75,111.98 81.74,111.92 81.75,111.86 81.75,109.93 81.52,109.7 79.29,109.7 79.11,109.88 79.11,111.2 78.89,111.41 78.24,111.41 78.07,111.58 78.07,112.39 78.17,112.48 81.43,112.48
+20V_TBTA_VBUS on TOP (solid shape): 23.89,97.78 23.89,94.9 23.87,94.88 19.62,94.88 19.62,98.31 19.49,98.44 19.49,98.88 19.55,98.94 22.73,98.94
+20V_TBTA_VBUS on TOP (solid shape): 6.22,108.85 6.65,108.85 6.97,108.53 9.14,108.53 9.43,108.82 10.85,108.82 11.49,108.18 11.49,107.83 11.36,107.71 8.76,107.71 8.31,108.15 6.99,108.15 6.74,108.4 6.23,108.4 6.2,108.44 5.43,108.44 5.36,108.51 5.36,108.67 5.41,108.72 6.08,108.72 6.21,108.85
+20V_TBTA_VBUS on TOP (solid shape): 10.43,105.67 11.49,105.67 11.62,105.55 11.62,104.66 11.55,104.59 10.09,104.59 9.01,105.67 6.42,105.67 6.15,105.94 5.42,105.94 5.35,106 5.35,106.15 5.42,106.21 6.09,106.21 6.19,106.12 6.79,106.12 6.85,106.06 8.31,106.06 8.53,106.27 9.84,106.27
+20V_TBTA_VBUS on VCC: 19.37,95.58 17.84,97.11 17.84,99.05 15.02,101.86 10.01,101.86 7.53,104.34 6.39,104.34 6.15,104.57 6.15,109.82 6.32,109.99 25.51,109.99 25.51,95.58 ; 1 cut-out
+20V_TBTA_VBUS on IN2: 21.52,97.93 21.2,97.61 20.38,97.61 19.87,98.12 19.87,100.28 20.12,100.53 21.33,100.53 21.52,100.34
+20V_TBTA_VBUS on IN2: 10.95,105.74 12.28,107.07 12.5,107.07 13.01,106.56 13.01,105.64 11.97,104.59 9.93,104.59 9.36,105.17 9.36,105.58 9.52,105.74
+20V_TBTA_VBUS_1 on TOP (solid shape): 25.71,93.86 25.71,93.36 24.01,91.65 22.93,91.65 22.59,91.62 22.44,91.32 20,91.32 19.74,91.58 19.74,93.99 19.87,94.12 25.46,94.12
+20V_TBTA_VBUS_1 on BOTTOM (solid shape): 66.45,105.41 66.45,104.37 66.89,103.94 66.89,103.81 66.69,103.61 66.53,103.61 66.48,103.67 66.47,103.67 65.98,104.15 65.98,104.56 66.09,104.66 66.09,105.44 66.15,105.5 66.36,105.5
+20V_TBTA_VBUS_1 on BOTTOM (solid shape): 69.09,111.04 69.09,110.66 69.09,108.95 68.91,108.78 68.57,108.78 68.57,108.77 68.32,108.77 68.31,108.76 67.6,108.76 67.13,108.3 66.59,108.3 66.56,108.33 66.56,108.52 66.43,108.65 66.16,108.65 66.09,108.72 66.09,108.74 66.09,108.84 66.05,108.92 66.05,108.94 66.05,109.03 66.11,109.1 66.43,109.1 66.56,109.22 66.56,109.48 66.62,109.54 66.81,109.54 67,109.73 67,109.92 67.38,110.3 67.38,110.62 67.57,110.81 67.57,110.92 67.88,111.23 68.9,111.23
+20V_TBTA_VBUS_1 on TOP: 67.18,124.41 68.13,124.41 68.51,124.79 68.51,125.68 68.77,125.93 72.22,125.93 72.58,125.58 72.58,124.71 72.4,124.53 72.4,122.23 71.6,121.43 71.6,118.43 71.66,118.36 72.91,118.36 73.02,118.25 73.02,116.41 72.58,115.96 72.58,114.37 71.91,113.71 71.12,113.71 70.94,113.53 70.94,112.34 71.6,111.69 71.6,109.3 70.99,108.69 66.96,108.69 66.96,108.69 66.51,108.69 66.04,109.17 66.04,110.18 66.03,110.19 66.03,111.05 65.15,111.93 65.15,113.26 65.86,113.97 65.86,115.85 65.55,116.16 63.87,116.16 63.62,116.41 63.62,120.6 64.96,121.93 64.96,122.95 65.26,123.25 66.02,123.25
+20V_TBTA_VBUS_1 on IN2: 72.41,93.85 74.35,93.85 74.72,93.48 74.72,92.57 73.59,91.44 72.41,91.44 71.97,91.88 71.97,93.41
+20V_TBTA_VBUS_1 on IN2, IN3: 23.11,93.36 25.71,93.36 26.16,92.91 26.16,92.09 25.65,91.58 23.24,91.58 22.79,92.02 22.79,93.04
+20V_TBTA_VBUS_1 on IN3: 72.46,93.89 74.21,93.89 74.73,93.37 74.73,92.56 73.64,91.48 72.46,91.48 72.02,91.92 72.02,93.44
+20V_TBTA_VBUS_1 on IN3: 68.77,116.53 71.56,116.53 71.88,116.22 71.88,113.93 70.04,112.09 70.04,111.33 69.27,110.56 69.27,108.98 68.89,108.6 67.69,108.6 67.18,109.1 67.18,112.15 68.45,113.42 68.45,116.22
+20V_TBTA_VBUS_1 on IN4: 21.08,89.23 20.44,89.86 20.44,93.93 20.47,93.96 20.47,94.97 24.95,99.45 34.67,99.45 34.92,99.2 36.95,99.2 39.17,101.42 48.32,101.42 59.05,112.15 73.27,112.15 73.72,112.6 79.62,112.6 80.89,111.33 81.91,111.33 82.55,110.69 82.55,84.72 81.53,83.7 80.58,83.7 79.62,84.66 73.65,89.53 68.19,92.65 61.85,94.83 58.2,95.38 55.75,95.62 54.86,95.62 54.03,95.65 52.32,95.63 52.26,95.62 48.25,95.62 43.98,94.84 39.49,93.61 29.4,89.23
+20V_VBUS_DC_SS on TOP: 76.72,127.77 82.56,127.77 82.94,127.39 82.94,124.71 82.63,124.41 75.47,124.41 73.82,126.06 70.8,126.06 70.79,126.06 70.4,126.06 70.21,126.25 70.21,128.17 70.95,128.9 75.07,128.9 75.55,128.42 76.07,128.42
+DV33_18 on TOP: 295.56,22.65 296.58,22.65 296.76,22.83 297.42,22.83 297.47,22.78 297.47,22.38 297.34,22.25 296.58,22.25 296.43,22.4 295.56,22.4 295.49,22.48 295.49,22.58
+VCC_SFR_OC on BOTTOM (solid shape): 125.49,92.94 127.22,92.94 129.41,90.75 129.41,89.74 129.15,89.48 128.33,89.48 127.23,90.59 124.66,90.59 124.56,90.69 124.56,91.9 124.43,92.03 124.43,93.53 124.51,93.61 124.82,93.61
+VCC_SFR_OC on IN1 (solid shape): 130.54,91.16 130.54,90.63 129.69,89.78 128.95,89.78 128.8,89.93 128.8,90.75 128.95,90.9 129.66,90.9 130.03,91.27 130.43,91.27
+VCC_SFR_OC on IN1 (solid shape): 139.29,90.94 138.85,90.5 137.82,90.5 137.73,90.59 137.73,91.23 137.82,91.32 139.29,91.32
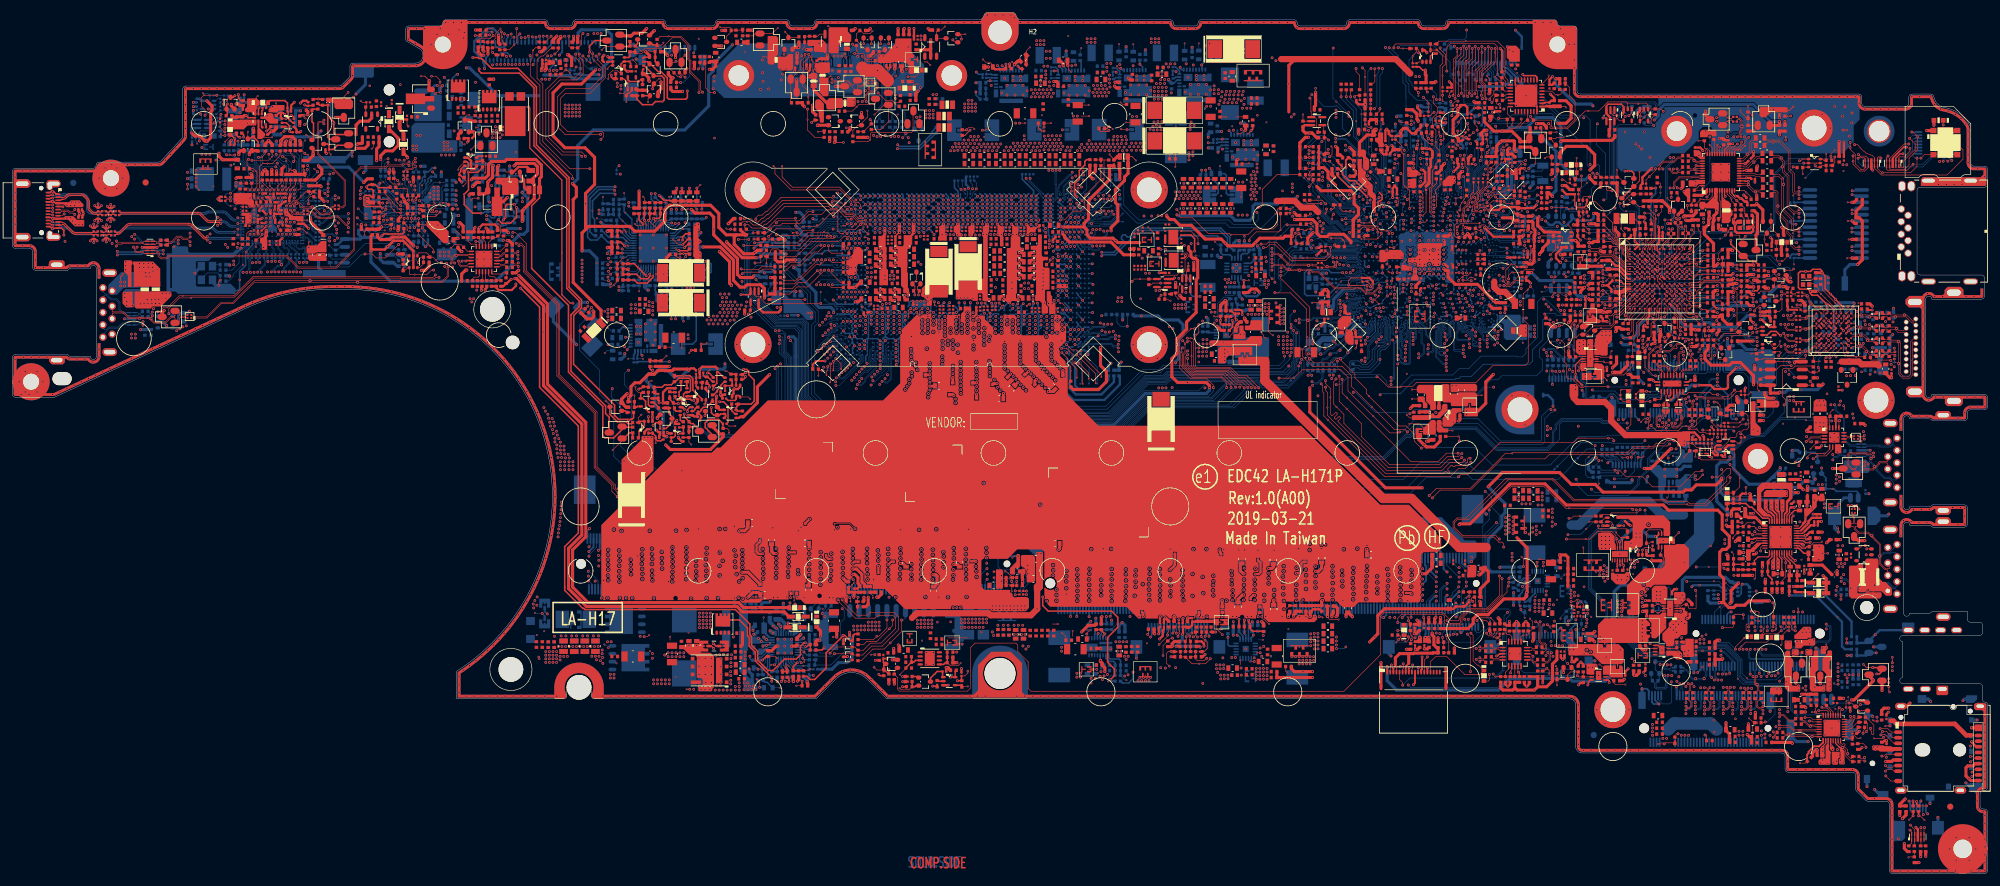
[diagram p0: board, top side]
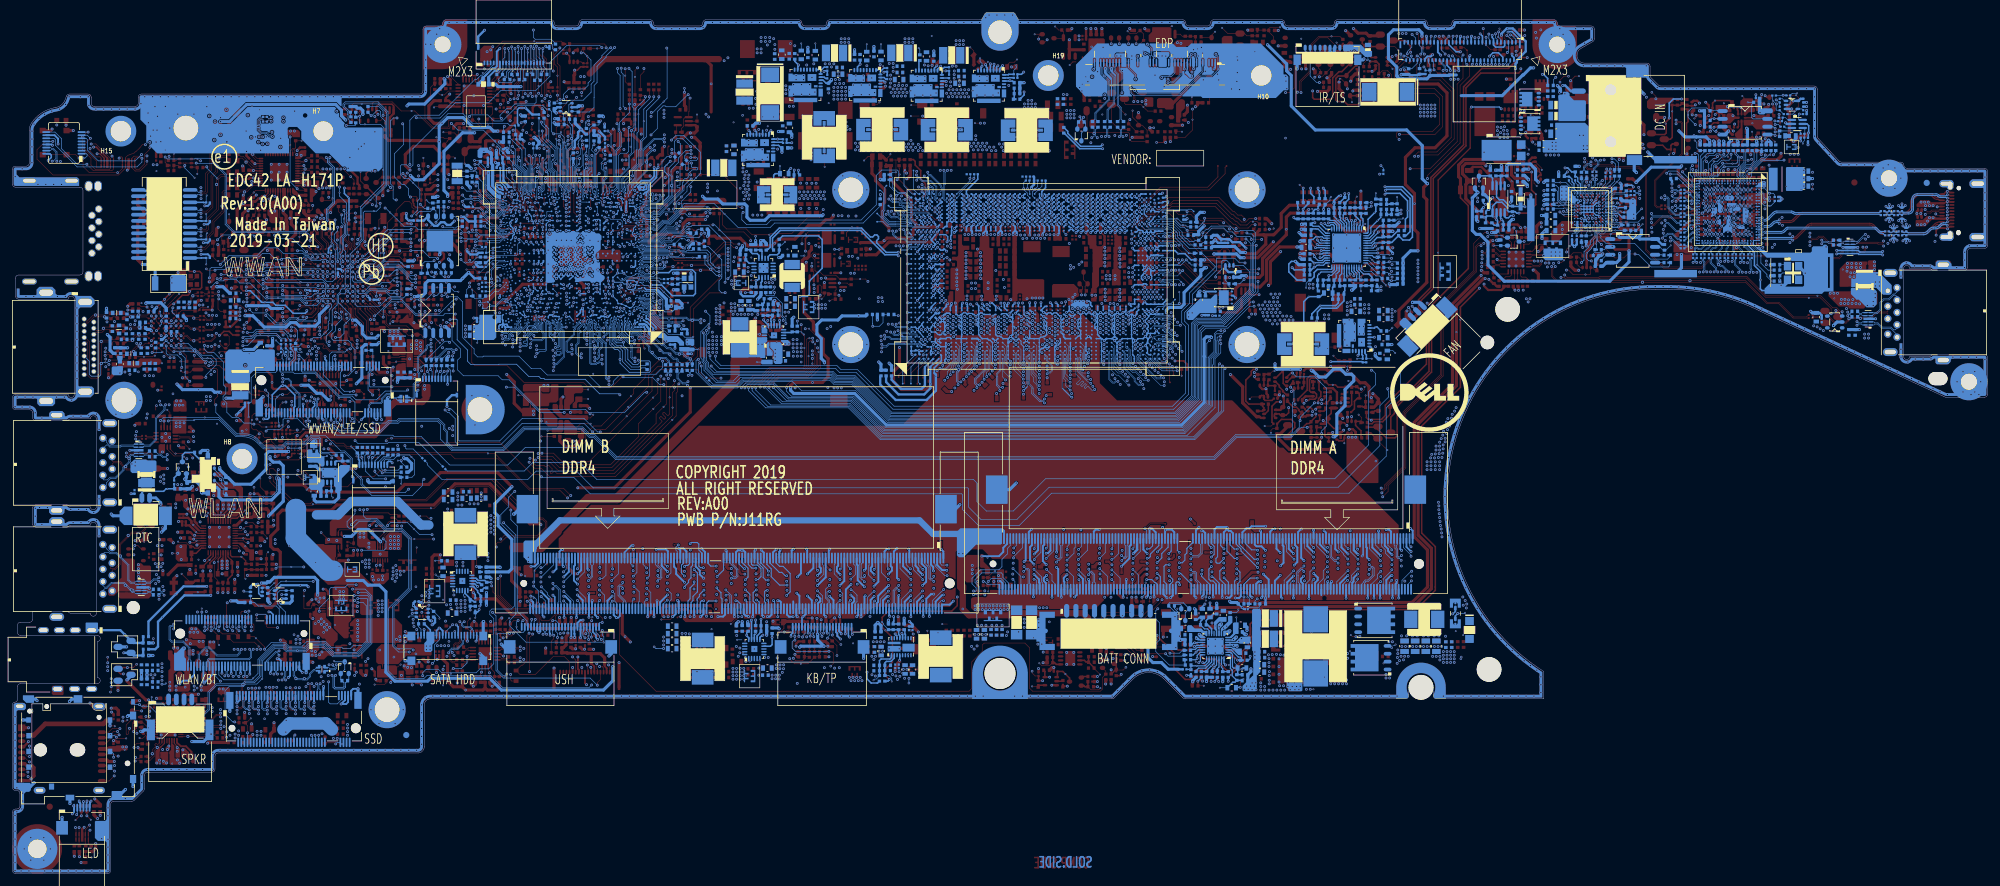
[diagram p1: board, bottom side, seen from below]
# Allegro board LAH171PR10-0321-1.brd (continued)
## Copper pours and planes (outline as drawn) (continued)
+VDDA_AVDD1 on TOP: 287.58,51.84 287.58,52.24 287.52,52.3 287.39,52.3 287.33,52.24 287.33,51.48 287.56,51.25 288.09,51.25 289.17,50.17 289.17,49.62 289.24,49.55 290.83,49.55 290.89,49.62 290.89,50.12 290.83,50.19 289.81,50.19 288.35,51.65 287.78,51.65
GND on TOP (solid shape): 293.03,76.35 293.03,74.7 290.94,74.7 290.94,76.29 291.32,76.67 292.72,76.67
GND on TOP (solid shape): 170.51,95.2 170.51,94.76 170.36,94.61 168.71,94.61 168.71,95.15 168.83,95.27 170.43,95.27
GND on TOP (solid shape): 286.76,61.87 286.76,60.98 286.63,60.86 282.89,60.86 282.89,61.62 283.27,62 286.63,62
GND on TOP (solid shape): 19.43,93.99 19.43,91.64 19.3,91.51 18.41,91.51 17.78,92.15 17.78,93.86 17.97,94.05 19.36,94.05
GND on TOP (solid shape): 103.56,70.62 103.56,65.16 101.53,63.13 98.48,63.13 98.39,63.22 98.39,66.91 101.6,70.11 101.6,70.62 101.72,70.75 103.44,70.75
GND on TOP (solid shape): 243.49,133.22 243.49,131.26 243.45,131.22 241.84,131.22 241.75,131.31 241.75,131.52 241.38,131.89 241.38,133.73 241.47,133.81 242.9,133.81
GND on TOP (solid shape): 50.74,100.05 50.74,99.1 50.67,99.04 48.04,99.04 47.75,99.32 47.75,100.03 47.81,100.09 48.95,100.09 49.17,100.31 50.48,100.31
GND on TOP (solid shape): 19.36,98.94 19.36,98.44 19.24,98.31 19.24,94.88 19.17,94.82 18.73,94.82 18.66,94.88 18.66,96.66 18.03,97.29 18.03,99.01 18.16,99.13 19.17,99.13
GND on TOP (solid shape): 236.6,78.88 236.6,78.05 236.47,77.92 233.48,77.92 233.36,77.8 232.44,77.8 232.43,77.79 232.28,77.94 232.28,79.11 232.35,79.18 236.29,79.18
GND on TOP (solid shape): 57.72,109.27 57.72,108.85 57.79,108.78 58.54,108.78 58.61,108.72 58.61,108.2 58.55,108.14 57.11,108.14 57.04,108.21 57.04,109.3 57.09,109.35 57.64,109.35
GND on TOP (solid shape): 155.4,105 155.4,103.6 155.15,103.34 155.15,103.08 155.05,102.98 155.04,102.97 154.51,102.97 154.41,103.07 154.41,104.62 154.71,104.62 154.81,104.72 154.81,105.06 154.94,105.19 155.21,105.19
GND on TOP (solid shape): 268.55,54.09 268.55,53.33 268.04,53.33 267.98,53.39 266.14,53.39 266.01,53.26 266.01,52.44 265.95,52.38 265.82,52.38 265.76,52.44 265.76,54.15 265.88,54.28 268.36,54.28
GND on TOP (solid shape): 226.88,97.9 226.88,96.76 227.13,96.51 227.13,96.02 226.98,95.87 225.99,95.87 225.93,95.93 225.93,96.38 226.25,96.69 226.25,97.77 226.44,97.96 226.82,97.96
GND on TOP (solid shape): 261.23,48.62 261.23,47.44 260.54,46.75 259.05,46.75 258.22,47.57 258.22,48.57 258.29,48.64 258.69,48.64 258.85,48.47 260.41,48.47 260.71,48.77 261.08,48.77
GND on TOP (solid shape): 165.21,51.14 165.21,47.35 164.93,47.06 163.97,47.06 163.81,47.22 163.81,49.04 163.38,49.48 163.19,49.48 162.87,49.79 162.87,51.32 163.06,51.51 164.84,51.51
GND on TOP (solid shape): 271.58,37.93 271.58,35.12 271.46,35 269.87,35 269.86,35.01 269.86,35.65 269.85,35.67 269.85,35.82 269.49,36.18 269.49,36.9 269.55,36.97 270.08,36.97 270.2,37.09 270.2,37.92 270.26,37.98 271.53,37.98
GND on TOP (solid shape): 291.21,37.98 291.21,37.03 291.02,36.84 289.36,36.84 288.92,36.4 288.04,36.4 287.97,36.47 287.97,37.67 288.09,37.79 290,37.79 290.18,37.97 290.69,37.97 290.76,38.05 291.14,38.05
GND on TOP (solid shape): 198.88,88.53 198.88,87.83 199.19,87.51 199.19,86.56 199.07,86.43 197.35,86.43 197.23,86.56 197.23,87.13 197.29,87.2 197.92,87.2 198.18,87.45 198.18,88.53 198.24,88.59 198.81,88.59
GND on TOP (solid shape): 294.51,19.7 295.08,19.7 295.14,19.63 295.14,18.79 294.91,18.55 294.91,17.75 294.76,17.59 294.07,17.59 293.87,17.79 293.87,19.63 293.94,19.7
GND on TOP (solid shape): 111.07,105.08 111.07,104.07 110.82,103.81 110.82,102.73 111.26,102.29 111.26,102.03 110.88,101.65 110.88,100.83 111.33,100.38 111.33,99.43 111.2,99.3 110.37,99.3 109.99,99.68 109.99,104.76 110.5,105.27 110.88,105.27
GND on TOP (solid shape): 298.94,50.11 298.94,47.19 298.03,46.28 298.03,45.43 298.17,45.29 299.21,45.29 299.4,45.48 301.81,45.48 301.94,45.35 301.94,44.78 301.62,44.46 297.04,44.46 296.65,44.84 296.65,49.6 296.85,49.79 297.86,49.79 298.24,50.18 298.88,50.18
GND on TOP (solid shape): 38.64,106.68 38.64,105.19 38.52,105.07 37.98,105.07 37.91,105 37.91,104.56 37.85,104.5 37.53,104.5 37.46,104.56 37.46,104.94 37.62,105.09 37.62,106.18 37.55,106.25 37.55,106.25 37.46,106.34 37.08,106.34 37.02,106.4 37.02,106.72 37.12,106.82 38.5,106.82
GND on TOP (solid shape): 151.11,95.09 151.11,93.14 148.77,93.14 148.54,92.91 148.54,91.89 148.41,91.77 147.7,91.77 147.7,92.65 147.14,93.21 146.92,93.21 146.73,93.4 146.73,93.71 146.87,93.85 146.87,94.57 147.6,95.3 150.9,95.3
GND on TOP (solid shape): 38.68,109.97 38.68,109.09 38.67,109.08 38.73,109.03 38.79,108.94 38.88,108.88 39.02,108.74 39.02,108.25 39.27,107.99 39.27,107.78 39.16,107.66 38.25,107.66 38.16,107.76 38.16,107.99 37.97,108.18 35.99,108.18 35.71,108.46 35.71,109.87 35.83,109.99 38.65,109.99
GND on TOP (solid shape): 150.67,105 150.67,103.58 150.75,103.5 150.93,103.5 151.02,103.41 151.02,103.09 150.9,102.97 150.9,102.31 149.53,102.31 149.53,102.92 149.69,103.08 149.69,104.6 149.71,104.62 149.86,104.62 150.09,104.85 150.09,105.08 150.24,105.23 150.44,105.23
GND on TOP (solid shape): 159.33,105.13 159.33,104.95 159.67,104.62 160.12,104.62 160.12,103.71 160.02,103.6 160.02,102.97 160.07,102.92 160.07,101.39 159.56,101.39 159.51,101.44 159.51,102.89 159.33,103.07 159.11,103.07 158.98,103.2 158.98,103.4 159.13,103.55 159.13,104.7 159.08,104.75 158.98,104.75 158.85,104.87 158.85,105.13 158.95,105.23 159.23,105.23
GND on TOP (solid shape): 41.28,104.06 41.28,103.04 41.15,102.91 41.15,101 40.93,100.79 40.39,100.79 40.29,100.89 40.29,101.75 40,102.04 40,102.68 40.14,102.82 40.51,102.82 40.68,102.99 40.68,103.23 40.7,103.35 40.68,103.46 40.68,103.54 40.75,103.62 40.75,104.08 40.89,104.22 41.12,104.22
GND on TOP (solid shape): 141.17,104.42 141.17,103.27 141.05,103.15 141.05,101.37 141.17,101.24 141.17,97.84 141.43,97.58 141.44,97.58 141.44,95.12 141.42,95.09 140.07,95.09 140.04,95.12 140.04,97.55 140.08,97.58 140.18,97.58 140.56,97.96 140.56,100.83 140.49,100.91 140.08,100.91 139.9,101.09 139.9,103.07 140.41,103.07 140.69,103.35 140.69,104.44 140.77,104.52 141.07,104.52
GND on TOP (solid shape): 153.06,105.08 153.06,103.66 153.25,103.47 153.37,103.47 153.5,103.34 153.5,103.09 153.37,102.96 153.11,102.96 152.97,103 152.82,102.96 152.61,102.96 152.42,103.15 152.42,103.43 152.19,103.65 152.07,103.65 152.05,103.68 152.05,104.59 152.07,104.62 152.3,104.62 152.43,104.75 152.43,105.1 152.53,105.2 152.93,105.2
GND on TOP (solid shape): 164.11,104.95 164.11,104.85 164.49,104.47 164.85,104.47 164.95,104.57 165.48,104.57 165.74,104.82 165.74,104.98 166.12,104.98 166.12,104.57 165.94,104.39 165.61,104.39 165.25,104.04 165.25,103.65 164.41,103.65 164.26,103.5 164.26,103.15 164.19,103.07 163.86,103.07 163.79,103.14 163.79,103.43 163.83,103.48 163.83,104.59 163.73,104.7 163.65,104.7 163.53,104.82 163.53,105.05 163.65,105.18 163.88,105.18
GND on TOP (solid shape): 157.76,104.99 157.76,103.71 157.63,103.58 157.63,103.17 157.54,103.08 157.54,93.15 157.63,93.06 157.86,93.06 158.02,92.9 158.02,92.63 157.92,92.53 157.29,92.53 157.26,92.56 156.77,92.56 156.69,92.64 156.69,93.64 156.55,93.79 156.08,93.79 155.92,93.63 155.92,92.64 155.89,92.61 155.1,92.61 154.9,92.81 152.47,92.81 152.38,92.91 152.38,95.89 152.57,96.09 156.62,96.09 156.8,96.26 156.8,102.9 156.61,103.09 156.61,103.47 156.74,103.6 156.74,104.55 156.8,104.61 156.99,104.61 157.12,104.74 157.12,105.06 157.25,105.19 157.56,105.19
GND on TOP (solid shape): 143.54,105.13 143.54,103.53 143.38,103.37 143.1,103.37 142.82,103.1 142.82,101.7 143.13,101.39 143.76,101.39 143.97,101.6 143.97,103.17 143.99,103.2 144.98,103.2 145.26,103.48 145.26,105.1 145.36,105.2 145.8,105.2 145.87,105.13 145.87,103.53 145.34,102.99 145.34,101.67 145.21,101.67 145.09,101.55 145.09,101.11 144.96,100.99 144.63,100.99 144.55,100.91 144.55,97.2 144.65,97.1 144.65,94.69 144.83,94.51 144.83,93.85 143.92,93.85 143.92,94.61 143.54,94.99 143.54,97.86 143.33,98.07 142.98,98.07 142.98,100.89 142.88,100.99 142.65,100.99 142.44,101.19 142.44,103.12 142.52,103.12 143,103.6 143,105.13 143.1,105.23 143.43,105.23
GND on TOP (solid shape): 255.33,86.31 255.33,83.39 255.45,83.26 256.16,83.26 256.22,83.21 256.22,83.08 256.16,83.03 255.45,83.03 255.33,82.9 255.33,81.86 254.36,81.86 254.36,81.94 254.37,82 254.36,82.05 254.36,82.34 254.37,82.4 254.36,82.45 254.36,82.74 254.37,82.8 254.36,82.85 254.36,83.14 254.37,83.2 254.36,83.25 254.36,83.54 254.37,83.6 254.36,83.65 254.36,83.94 254.37,84 254.36,84.05 254.36,84.34 254.37,84.4 254.36,84.45 254.36,86.23 254.51,86.38 255.25,86.38
GND on TOP (solid shape): 166.28,103.27 166.28,99.9 166.28,99.9 166.47,99.7 167.25,99.7 167.3,99.65 167.3,99.2 167.23,99.13 166.66,99.13 166.47,98.94 166.47,98.14 166.66,97.95 167.36,97.95 167.54,97.78 167.54,94.45 167.49,94.4 166.92,94.4 166.81,94.29 166.81,92.6 166.98,92.44 166.98,91.92 167.28,91.62 167.28,90.63 167.15,90.5 166.34,90.5 166.26,90.58 166.26,92.22 165.89,92.59 165.25,92.59 165.23,92.62 165.23,93.49 165.35,93.62 165.35,100.63 165.14,100.85 164.5,100.85 164.5,101.46 165.43,101.46 165.66,101.69 165.66,103.25 165.71,103.3 166.24,103.3
GND on TOP (solid shape): 161.65,105.1 161.65,104.9 161.93,104.62 162.43,104.62 162.48,104.57 162.48,103.02 162.56,102.94 162.79,102.94 162.79,100.89 162.77,100.87 162.64,100.87 162.28,100.52 162.28,93.85 162.1,93.67 162.1,92.58 161.49,92.58 161.32,92.4 161.32,92.15 161.19,92.02 160.99,92.02 160.5,92.5 160.5,93.49 160.63,93.62 160.63,101.09 161.11,101.09 161.24,101.22 161.24,102.84 161.39,102.99 161.39,103.43 161.49,103.53 161.49,104.64 161.39,104.75 161.29,104.75 161.16,104.87 161.16,105.1 161.27,105.2 161.54,105.2
GND on TOP (solid shape): 137.39,100.78 137.39,98.57 136.68,98.57 136.37,98.27 136.37,97.05 136.04,96.72 134.98,96.72 134.68,97.02 134.68,97.62 135.21,97.94 134.68,98.25 134.68,99.06 134.78,99.16 135.1,99.26 135.2,99.58 135.92,100.3 135.92,101.14 136.07,101.29 136.88,101.29
GND on TOP (solid shape): 110.87,37.16 111.12,36.9 111.12,35.89 111.31,35.7 112.77,35.7 113.34,35.13 113.34,30.66 113.24,30.41 113.3,30.14 113.3,30.1 113.28,30.07 113.09,29.87 113.06,29.59 113.03,29.51 112.96,29.47 110.93,29.47 110.8,29.6 110.8,30.43 110.87,30.49 111.37,30.49 111.5,30.62 111.5,31.38 111.25,31.63 110.68,31.63 110.55,31.76 110.55,35 110.23,35.32 110.22,35.32 109.41,35.32 108.45,36.27 108.38,36.27 107.75,36.27 107.69,36.33 107.69,36.9 107.75,36.97 108.77,36.97 108.96,37.16 109.85,37.16 109.98,37.16
GND on TOP (solid shape): 249.03,138 249.38,137.85 249.67,137.15 250.02,137 252.23,137 252.58,136.85 252.72,136.5 252.72,130.02 249.56,130.02 246.73,131.19 245.56,134.02 245.56,138
GND on TOP (solid shape): 73.52,134.02 70.79,130.23 66.33,131.61 66.33,132.2 66.32,132.2 66.32,132.31 66.33,132.31 66.33,136.5 66.47,136.85 66.83,137 69.03,137 69.38,137.15 69.67,137.85 70.03,138 73.52,138
GND on TOP (solid shape): 305.28,59.3 305.88,58.6 306.65,59.1 309.68,59.1 309.95,59.16 310.18,59.38 310.23,59.4 315.28,59.4 315.49,59.31 315.58,59.1 315.58,56.5 315.49,56.29 315.28,56.2 310.23,56.2 310.18,56.21 309.95,56.44 309.68,56.5 306.65,56.5 305.88,57 305.28,56.3 305.28,54.36 304.82,54.36 304.82,56.3 305.63,57.41 306.93,56.96 309.68,56.96 310.07,56.88 310.4,56.66 310.54,56.66 310.65,56.77 310.65,57.2 311.06,57.6 312.68,57.6 313.09,57.2 313.09,56.77 313.19,56.66 315.12,56.66 315.12,58.94 313.18,58.94 313.11,58.87 313.11,58.37 312.76,58.01 310.95,58.01 310.65,58.32 310.65,58.84 310.55,58.94 310.4,58.94 310.07,58.72 309.68,58.64 306.93,58.64 305.63,58.19 304.82,59.3 304.82,61.22 305.28,61.22
GND on TOP (solid shape): outline of 249 points within 156.12,28.95 162.93,35.75
GND on TOP (solid shape): outline of 87 points within 304.82,71.57 318.85,94.84
GND on TOP (solid shape): 53.73,95.11 86.47,70.68 72.39,32.34 72.39,28.91 88.17,28.91 88.17,28.45 71.93,28.45 71.93,32.59 86.07,70.43 53.73,94.65 51.72,94.65 43.96,93.75 36.62,91.08 6.76,77.2 0.5,77.2 0.29,77.29 0.2,77.5 0.2,83.4 0.29,83.61 0.5,83.7 8.82,83.7 8.87,83.68 9.1,83.46 9.37,83.4 12.4,83.4 13.17,82.9 13.77,83.6 13.77,85.73 14.23,85.73 14.23,83.6 13.42,82.49 12.12,82.94 9.37,82.94 8.98,83.02 8.65,83.24 8.54,83.24 8.46,83.17 8.46,82.62 8.15,82.31 6.39,82.31 5.94,82.76 5.94,83.18 5.88,83.24 0.66,83.24 0.66,77.66 6.66,77.66 36.42,91.49 43.86,94.19 51.72,95.11
GND on TOP (solid shape): outline of 582 points within 95.16,0.2 318.85,35.85
GND on TOP (solid shape): outline of 301 points within 0.2,96.16 318.85,139
GND on BOTTOM (solid shape): 265.32,114.5 259.32,114.5 259.32,120.5 265.32,120.5
GND on BOTTOM (solid shape): 293.56,96.48 293.56,94.3 293.38,94.12 291.08,94.12 290.95,94.24 290.95,96.53 291.21,96.78 293.25,96.78
GND on BOTTOM (solid shape): 299.98,66.32 299.98,65.02 299.7,64.74 296.1,64.74 295.78,65.06 295.78,66.61 295.97,66.8 297.32,66.8 297.44,66.93 299.37,66.93
GND on BOTTOM (solid shape): 138.69,132.45 138.69,131.93 138.44,131.68 138.44,130.5 138.33,130.39 137.71,130.39 137.69,130.4 137.6,130.49 137.6,131.7 137.69,131.79 137.69,132.43 137.78,132.52 138.62,132.52
GND on BOTTOM (solid shape): 292.54,35.7 292.86,35.7 292.92,35.63 292.92,32.9 292.79,32.78 291.14,32.78 291.02,32.9 291.02,34.74 291.27,35 291.27,36.01 291.02,36.27 291.02,36.52 291.21,36.71 291.52,36.71
GND on BOTTOM (solid shape): 22.09,94.56 22.09,93.67 21.2,92.78 20.82,92.78 19.55,91.51 18.41,91.51 17.9,92.02 17.9,94.12 18.28,94.5 20.76,94.5 20.95,94.69 21.97,94.69
GND on BOTTOM (solid shape): 113.22,34.94 113.22,30.17 113.22,30.11 112.96,29.86 112.96,29.6 112.83,29.47 110.8,29.47 110.68,29.6 110.68,30.25 110.68,30.25 110.68,35.19 110.74,35.25 112.9,35.25
GND on BOTTOM (solid shape): 266.61,65.46 268.96,65.46 268.96,64.07 267.31,64.07 267.12,63.88 267.12,62.67 266.86,62.42 266.86,61.59 266.23,61.59 265.85,61.97 265.85,63.88 264.58,65.15 264.58,66.04 266.04,66.04
GND on BOTTOM (solid shape): 69.85,121.3 69.85,118.69 69.97,118.56 71.69,118.56 71.88,118.37 71.88,116.66 71.75,116.53 64.57,116.53 64.45,116.66 64.45,120.79 65.02,121.36 69.78,121.36
GND on BOTTOM (solid shape): 118.8,42.62 118.8,36.08 118.61,35.89 118.61,32.08 120.36,30.33 120.36,29.63 120.2,29.47 118.23,29.47 118.03,29.68 118.03,29.99 118.04,30 118.04,32.01 117.47,32.59 117.47,42.75 117.53,42.81 118.61,42.81
GND on BOTTOM (solid shape): 59.53,109.32 59.53,108.84 59.15,108.46 58.06,108.46 57.88,108.28 57.88,107.48 58.3,107.06 58.3,105.74 58.24,105.67 56.83,105.67 56.76,105.74 56.76,108.85 57.03,109.12 57.48,109.12 57.62,108.98 58.72,108.98 59.08,109.33 59.52,109.33
GND on BOTTOM (solid shape): 141.51,130.41 141.59,130.38 141.66,130.33 141.74,130.31 141.75,130.3 141.75,129.7 140.89,128.84 140.89,125.61 140.76,125.61 140.76,129.09 141.28,129.61 141.28,130.3 141.32,130.31 141.39,130.34 141.44,130.38
GND on BOTTOM (solid shape): 142.51,130.41 142.59,130.38 142.62,130.35 142.68,130.32 142.75,130.25 142.75,129.36 141.62,128.24 141.62,125.61 141.42,125.61 141.42,128.61 142.28,129.48 142.28,130.3 142.29,130.31 142.37,130.33 142.44,130.38
GND on BOTTOM (solid shape): 26.68,101.41 28.15,101.41 28.35,101.21 28.35,101.21 28.41,101.15 28.41,100.57 28.61,100.37 35.62,100.37 36.1,100.85 36.43,100.85 36.57,100.98 36.68,101.1 36.68,101.25 36.78,101.35 37.07,101.35 37.24,101.18 37.24,101.09 36.54,100.38 36.49,100.35 36.32,100.18 36.31,100.18 35.68,99.54 32.19,99.54 31.66,99.01 29.8,99.01 29.65,98.86 29.65,97.49 29.87,97.27 29.87,96.86 29.65,96.64 29.65,95.07 29.84,94.88 32.89,94.88 33.03,95.02 33.03,95.17 33.21,95.35 35.24,95.35 36.03,94.55 36.03,93.76 35.97,93.7 26.77,93.7 25.78,94.68 25.78,101.13 25.8,101.15 25.8,101.38 26.09,101.67 26.41,101.67
GND on BOTTOM (solid shape): outline of 198 points within 155.02,28.25 164.02,36.85
GND on BOTTOM (solid shape): 305.28,59.3 305.88,58.6 306.65,59.1 309.68,59.1 309.95,59.16 310.18,59.38 310.23,59.4 315.28,59.4 315.49,59.31 315.58,59.1 315.58,56.5 315.49,56.29 315.28,56.2 310.23,56.2 310.18,56.21 309.95,56.44 309.68,56.5 306.65,56.5 305.88,57 305.28,56.3 305.28,54.36 304.82,54.36 304.82,56.3 305.63,57.41 306.93,56.96 309.68,56.96 310.07,56.88 310.4,56.66 310.54,56.66 310.65,56.77 310.65,57.2 311.06,57.6 312.68,57.6 313.09,57.2 313.09,56.77 313.19,56.66 315.12,56.66 315.12,58.94 313.18,58.94 313.11,58.87 313.11,58.37 312.76,58.01 310.95,58.01 310.65,58.32 310.65,58.84 310.55,58.94 310.4,58.94 310.07,58.72 309.68,58.64 306.93,58.64 305.63,58.19 304.82,59.3 304.82,61.22 305.28,61.22
GND on BOTTOM (solid shape): outline of 87 points within 304.82,71.57 318.85,94.84
GND on BOTTOM (solid shape): outline of 116 points within 95.16,0.2 318.85,33.16
GND on BOTTOM (solid shape): 53.73,95.11 86.47,70.68 72.39,32.34 72.39,28.91 88.17,28.91 88.17,28.45 71.93,28.45 71.93,32.59 86.07,70.43 53.73,94.65 51.72,94.65 43.96,93.75 36.62,91.08 6.76,77.2 0.5,77.2 0.29,77.29 0.2,77.5 0.2,83.4 0.29,83.61 0.5,83.7 8.82,83.7 8.87,83.68 9.1,83.46 9.37,83.4 12.4,83.4 13.17,82.9 13.77,83.6 13.77,85.73 14.23,85.73 14.23,83.6 13.42,82.49 12.12,82.94 9.37,82.94 8.98,83.02 8.65,83.24 8.48,83.24 8.41,83.18 8.41,82.53 8.2,82.32 6.39,82.32 6.01,82.7 6.01,83.01 5.78,83.24 0.66,83.24 0.66,77.66 6.66,77.66 36.42,91.49 43.86,94.19 51.72,95.11
GND on BOTTOM (solid shape): outline of 1051 points within 259.24,113.48 298.38,125.68
GND on BOTTOM (solid shape): outline of 1228 points within 112.94,125.36 147.25,134.19
GND on BOTTOM (solid shape): outline of 303 points within 0.2,96.16 318.85,139
GND on BOTTOM (solid shape): outline of 1598 points within 223.38,95.48 232.91,103.86
GND on IN1 (solid shape): 0.66,101.71 2.77,101.71 3.59,101.37 3.93,100.55 3.93,98.16 5.68,98.16 5.9,98.38 5.9,98.7 6.33,99.13 8.16,99.13 8.39,98.9 8.39,98.34 8.58,98.16 8.65,98.16 8.98,98.38 9.37,98.46 12.12,98.46 13.42,98.91 14.23,97.8 14.23,96.16 13.77,96.16 13.77,97.8 13.17,98.5 12.4,98 9.37,98 9.1,97.94 8.87,97.72 8.82,97.7 3.77,97.7 3.56,97.79 3.47,98 3.47,100.55 3.27,101.05 2.77,101.25 0.5,101.25 0.29,101.34 0.2,101.55 0.2,101.92 0.66,101.92
GND on IN1 (solid shape): 305.28,59.3 305.88,58.6 306.65,59.1 309.68,59.1 309.95,59.16 310.18,59.38 310.23,59.4 315.28,59.4 315.49,59.31 315.58,59.1 315.58,56.5 315.49,56.29 315.28,56.2 310.23,56.2 310.18,56.21 309.95,56.44 309.68,56.5 306.65,56.5 305.88,57 305.28,56.3 305.28,54.36 304.82,54.36 304.82,56.3 305.63,57.41 306.93,56.96 309.68,56.96 310.07,56.88 310.4,56.66 310.54,56.66 310.65,56.77 310.65,57.2 311.06,57.6 312.68,57.6 313.09,57.2 313.09,56.77 313.19,56.66 315.12,56.66 315.12,58.94 313.18,58.94 313.11,58.87 313.11,58.37 312.76,58.01 310.95,58.01 310.65,58.32 310.65,58.84 310.55,58.94 310.4,58.94 310.07,58.72 309.68,58.64 306.93,58.64 305.63,58.19 304.82,59.3 304.82,61.22 305.28,61.22
GND on IN1 (solid shape): outline of 87 points within 304.82,71.57 318.85,94.84
GND on IN1 (solid shape): outline of 97 points within 95.16,0.2 318.85,33.16
GND on IN1 (solid shape): 53.73,95.11 86.47,70.68 72.39,32.34 72.39,28.91 88.17,28.91 88.17,28.45 71.93,28.45 71.93,32.59 86.07,70.43 53.73,94.65 51.72,94.65 43.96,93.75 36.62,91.08 6.76,77.2 0.5,77.2 0.29,77.29 0.2,77.5 0.2,83.4 0.29,83.61 0.5,83.7 8.82,83.7 8.87,83.68 9.1,83.46 9.37,83.4 12.4,83.4 13.17,82.9 13.77,83.6 13.77,85.73 14.23,85.73 14.23,83.6 13.42,82.49 12.12,82.94 9.37,82.94 8.98,83.02 8.65,83.24 8.48,83.24 8.37,83.13 8.37,82.6 8.06,82.28 6.41,82.28 5.96,82.73 5.96,83.22 5.95,83.24 0.66,83.24 0.66,77.66 6.66,77.66 36.42,91.49 43.86,94.19 51.72,95.11
GND on IN1 (solid shape): outline of 252 points within 0.2,110.34 318.85,139
GND on IN2 (solid shape): 305.28,59.3 305.88,58.6 306.65,59.1 309.68,59.1 309.95,59.16 310.18,59.38 310.23,59.4 315.28,59.4 315.49,59.31 315.58,59.1 315.58,56.5 315.49,56.29 315.28,56.2 310.23,56.2 310.18,56.21 309.95,56.44 309.68,56.5 306.65,56.5 305.88,57 305.28,56.3 305.28,54.36 304.82,54.36 304.82,56.3 305.63,57.41 306.93,56.96 309.68,56.96 310.07,56.88 310.4,56.66 310.54,56.66 310.65,56.77 310.65,57.2 311.06,57.6 312.68,57.6 313.09,57.2 313.09,56.77 313.19,56.66 315.12,56.66 315.12,58.94 313.18,58.94 313.11,58.87 313.11,58.37 312.76,58.01 310.95,58.01 310.65,58.32 310.65,58.84 310.55,58.94 310.4,58.94 310.07,58.72 309.68,58.64 306.93,58.64 305.63,58.19 304.82,59.3 304.82,61.22 305.28,61.22
GND on IN2 (solid shape): outline of 87 points within 304.82,71.57 318.85,94.84
GND on IN2 (solid shape): outline of 97 points within 95.16,0.2 318.85,33.16
GND on IN2 (solid shape): 53.73,95.11 86.47,70.68 72.39,32.34 72.39,28.91 88.17,28.91 88.17,28.45 71.93,28.45 71.93,32.59 86.07,70.43 53.73,94.65 51.72,94.65 43.96,93.75 36.62,91.08 6.76,77.2 0.5,77.2 0.29,77.29 0.2,77.5 0.2,83.4 0.29,83.61 0.5,83.7 8.82,83.7 8.87,83.68 9.1,83.46 9.37,83.4 12.4,83.4 13.17,82.9 13.77,83.6 13.77,85.73 14.23,85.73 14.23,83.6 13.42,82.49 12.12,82.94 9.37,82.94 8.98,83.02 8.65,83.24 8.5,83.24 8.41,83.15 8.41,82.57 8.14,82.3 6.23,82.3 5.93,82.6 5.93,83.06 5.74,83.24 0.66,83.24 0.66,77.66 6.66,77.66 36.42,91.49 43.86,94.19 51.72,95.11
GND on IN2 (solid shape): outline of 303 points within 0.2,96.16 318.85,139
GND on IN3 (solid shape): 305.28,59.3 305.88,58.6 306.65,59.1 309.68,59.1 309.95,59.16 310.18,59.38 310.23,59.4 315.28,59.4 315.49,59.31 315.58,59.1 315.58,56.5 315.49,56.29 315.28,56.2 310.23,56.2 310.18,56.21 309.95,56.44 309.68,56.5 306.65,56.5 305.88,57 305.28,56.3 305.28,54.36 304.82,54.36 304.82,56.3 305.63,57.41 306.93,56.96 309.68,56.96 310.07,56.88 310.4,56.66 310.54,56.66 310.65,56.77 310.65,57.2 311.06,57.6 312.68,57.6 313.09,57.2 313.09,56.77 313.19,56.66 315.12,56.66 315.12,58.94 313.18,58.94 313.11,58.87 313.11,58.37 312.76,58.01 310.95,58.01 310.65,58.32 310.65,58.84 310.55,58.94 310.4,58.94 310.07,58.72 309.68,58.64 306.93,58.64 305.63,58.19 304.82,59.3 304.82,61.22 305.28,61.22
GND on IN3 (solid shape): outline of 87 points within 304.82,71.57 318.85,94.84
GND on IN3 (solid shape): outline of 97 points within 95.16,0.2 318.85,33.16
GND on IN3 (solid shape): 53.73,95.11 86.47,70.68 72.39,32.34 72.39,28.91 88.17,28.91 88.17,28.45 71.93,28.45 71.93,32.59 86.07,70.43 53.73,94.65 51.72,94.65 43.96,93.75 36.62,91.08 6.76,77.2 0.5,77.2 0.29,77.29 0.2,77.5 0.2,83.4 0.29,83.61 0.5,83.7 8.82,83.7 8.87,83.68 9.1,83.46 9.37,83.4 12.4,83.4 13.17,82.9 13.77,83.6 13.77,85.73 14.23,85.73 14.23,83.6 13.42,82.49 12.12,82.94 9.37,82.94 8.98,83.02 8.65,83.24 8.49,83.24 8.41,83.16 8.41,82.67 8.01,82.26 6.32,82.26 5.93,82.66 5.93,83.15 5.83,83.24 0.66,83.24 0.66,77.66 6.66,77.66 36.42,91.49 43.86,94.19 51.72,95.11
GND on IN3 (solid shape): outline of 303 points within 0.2,96.16 318.85,139
GND on IN4 (solid shape): 0.66,101.98 0.66,101.71 2.77,101.71 3.59,101.37 3.93,100.55 3.93,98.16 5.75,98.16 5.88,98.29 5.88,98.73 6.3,99.15 8.04,99.15 8.44,98.75 8.44,98.24 8.51,98.16 8.65,98.16 8.98,98.38 9.37,98.46 12.12,98.46 13.42,98.91 14.23,97.8 14.23,96.16 13.77,96.16 13.77,97.8 13.17,98.5 12.4,98 9.37,98 9.1,97.94 8.87,97.72 8.82,97.7 3.77,97.7 3.56,97.79 3.47,98 3.47,100.55 3.27,101.05 2.77,101.25 0.5,101.25 0.29,101.34 0.2,101.55 0.2,102.01 0.63,102.01
GND on IN4 (solid shape): 305.28,59.3 305.88,58.6 306.65,59.1 309.68,59.1 309.95,59.16 310.18,59.38 310.23,59.4 315.28,59.4 315.49,59.31 315.58,59.1 315.58,56.5 315.49,56.29 315.28,56.2 310.23,56.2 310.18,56.21 309.95,56.44 309.68,56.5 306.65,56.5 305.88,57 305.28,56.3 305.28,54.36 304.82,54.36 304.82,56.3 305.63,57.41 306.93,56.96 309.68,56.96 310.07,56.88 310.4,56.66 310.54,56.66 310.65,56.77 310.65,57.2 311.06,57.6 312.68,57.6 313.09,57.2 313.09,56.77 313.19,56.66 315.12,56.66 315.12,58.94 313.18,58.94 313.11,58.87 313.11,58.37 312.76,58.01 310.95,58.01 310.65,58.32 310.65,58.84 310.55,58.94 310.4,58.94 310.07,58.72 309.68,58.64 306.93,58.64 305.63,58.19 304.82,59.3 304.82,61.22 305.28,61.22
GND on IN4 (solid shape): outline of 87 points within 304.82,71.57 318.85,94.84
GND on IN4 (solid shape): outline of 97 points within 95.16,0.2 318.85,33.16
GND on IN4 (solid shape): 53.73,95.11 86.47,70.68 72.39,32.34 72.39,28.91 88.17,28.91 88.17,28.45 71.93,28.45 71.93,32.59 86.07,70.43 53.73,94.65 51.72,94.65 43.96,93.75 36.62,91.08 6.76,77.2 0.5,77.2 0.29,77.29 0.2,77.5 0.2,83.4 0.29,83.61 0.5,83.7 8.82,83.7 8.87,83.68 9.1,83.46 9.37,83.4 12.4,83.4 13.17,82.9 13.77,83.6 13.77,85.73 14.23,85.73 14.23,83.6 13.42,82.49 12.12,82.94 9.37,82.94 8.98,83.02 8.65,83.24 8.5,83.24 8.39,83.13 8.39,82.63 8.07,82.31 6.22,82.31 5.93,82.6 5.93,83.12 5.81,83.24 0.66,83.24 0.66,77.66 6.66,77.66 36.42,91.49 43.86,94.19 51.72,95.11
GND on IN4 (solid shape): outline of 252 points within 0.2,110.23 318.85,139
GND on TOP: 295.46,59.95 294.57,59.95 294.51,59.89 294.51,59.45 294,59.45 294,59.32 294.51,59.32 294.51,58.81 294.57,58.75 295.52,58.75 295.65,58.87 295.65,59.76
GND on TOP: 157.33,91.84 158.42,91.84 158.42,89.3 158.27,89.15 157.79,89.15 157.33,89.61
GND on TOP: 266.25,26.24 267.01,26.24 267.52,25.73 267.52,21.66 267.39,21.54 266.38,21.54 266.12,21.79 266.12,26.11
GND on TOP: 196.85,113.42 189.1,113.42 188.65,112.98 188.65,111.58 188.91,111.33 196.91,111.33 197.29,111.71 197.29,112.98
GND on TOP: 181.4,103.23 180.96,103.23 180.88,103.31 180.88,105.92 181.37,106.41 181.38,106.41 181.47,106.5 183.97,106.5 183.97,106.5 184.19,106.5 184.27,106.42 184.27,106.1 182.84,104.67 182.84,104.3 182.76,104.21 182.38,104.21 181.94,103.76 181.53,103.76 181.45,103.69 181.45,103.28
GND on TOP: 151.77,91.92 152.2,91.92 152.48,91.64 153.42,91.64 153.42,91.03 153.14,91.03 152.55,90.45 151.77,90.45
GND on TOP: 167.76,132.03 166.87,132.03 166.4,131.55 166.4,129.77 165.92,129.3 165.92,127.33 165.73,127.14 164.52,127.14 164.05,127.61 160.24,127.61 159.48,126.85 159.48,124.79 160.17,124.09 167.7,124.09 168.46,124.85 168.46,127.52 168.33,127.65 167.89,127.65 167.76,127.77 167.76,129.36 167.51,129.61 167.51,130.31 167.57,130.38 167.57,131.33 167.89,131.65 167.89,131.9
GND on TOP: 178.3,36.21 182.11,36.21 182.37,35.95 182.37,34.43 182.05,34.11 178.37,34.11 178.18,34.3 178.18,36.08
GND on TOP: 169.29,90.45 168.77,90.45 168.76,90.46 168.73,90.46 168.68,90.52 168.68,92.61 169.76,93.69 170.44,93.69 171.32,92.82 171.32,90.62 171.15,90.45
GND on TOP: 181.03,97.86 183.76,97.86 183.95,97.67 183.95,96.97 183.76,96.78 181.16,96.78 180.97,96.97 180.97,97.8
GND on TOP: 134.01,128.97 132.33,128.97 132.2,129.1 132.2,129.54 132.21,129.54 132.21,130.06 132.27,130.12 132.71,130.12 132.84,129.99 135.82,129.99 135.94,129.87 135.94,129.17 135.94,129.17 135.94,129 135.66,128.72 134.27,128.72
GND on TOP: 184.86,101.42 186.3,101.42 186.49,101.23 186.49,99.96 186.43,99.9 186.05,99.9 185.67,100.28 185.67,100.53 185.54,100.66 184.85,100.66 184.76,100.74 184.76,101.32
GND on TOP: 96.52,36.97 97.21,36.27 97.21,34.3 96.45,33.54 95.05,33.54 93.72,34.87 93.21,34.87 92.9,35.19 90.1,35.19 89.72,34.81 89.09,34.81 88.13,33.86 84.83,33.86 84.26,34.43 84.26,36.84 84.39,36.97
GND on TOP: 201.8,92.92 199.51,92.92 199.45,92.86 199.45,91.78 199.64,91.59 201.8,91.59 201.93,91.72 201.93,92.8
GND on TOP: 201.54,99.9 202.75,99.9 202.94,99.71 202.94,96.34 202.75,96.15 201.61,96.15 201.42,96.34 201.42,99.77
GND on TOP: 241.3,62.5 240.05,61.25 240.05,59.19 240.18,59.07 241.2,59.07 241.32,59.19 241.32,59.86 241.61,60.15 243.39,60.15 243.58,60.34 243.58,62.37 243.45,62.5
GND on TOP: 170.18,117.74 171.25,117.74 171.45,117.55 171.45,114.44 171.25,114.25 169.67,114.25 169.54,114.37 169.54,116.66 170.11,117.23 170.11,117.68
GND on TOP: 96.05,91.58 97.24,91.58 97.49,91.32 97.49,89.09 97.26,88.86 96.4,88.86 95.94,89.32 95.94,91.48
GND on TOP: 253.04,42.81 251.9,42.81 251.71,42.62 251.71,40.97 251.9,40.78 252.66,40.78 252.98,41.09 252.98,41.92 253.17,42.11 253.17,42.68
GND on TOP: 38.49,101.98 38.49,100.33 38.3,100.14 35.37,100.14 35.24,100.28 35.24,101.93 35.49,102.18 38.29,102.18
GND on TOP: 234.85,48.76 234.6,48.51 234.6,47.56 234.47,47.43 234.47,46.1 234.66,45.91 234.66,45.14 234.6,45.08 234.6,43.18 234.53,43.11 231.68,43.11 231.55,43.24 231.55,49.65 232.18,50.28 234.78,50.28 234.85,50.22
GND on TOP: 188.59,96.91 189.16,96.91 189.23,96.85 189.23,95.64 189.1,95.51 188.65,95.51 188.15,96.02 188.15,96.47
GND on TOP: 168.59,99.45 169.6,99.45 170.18,100.02 170.43,100.02 170.56,99.9 170.56,98.94 170.3,98.69 168.65,98.69 168.46,98.88 168.46,99.32
GND on TOP: 183.8,101.04 183.92,101.16 184.52,101.16 184.56,101.12 184.56,99.62 184.45,99.51 183.26,99.51 183.12,99.65 183.12,99.97 183.25,100.1 183.68,100.1 183.8,100.22
GND on TOP: 163.28,88.55 163.02,88.8 163.02,92.23 163.15,92.36 163.41,92.36 163.6,92.17 163.6,92.15 163.57,92.04 163.59,91.93 163.6,91.92 163.6,91.85 163.85,91.6 164.8,91.6 164.93,91.47 164.93,90.71 164.8,90.58 164.17,90.58 163.72,90.14 163.72,88.68 163.6,88.55
GND on TOP: 91.63,88.28 91.75,88.28 92.64,87.39 93.66,87.39 93.91,87.13 93.91,86.24 93.21,85.54 92.32,85.54 91.18,86.69 91.18,87.83
GND on TOP: 297.9,81.96 296.25,81.96 296.02,81.73 296.02,80.31 296.15,80.19 299.25,80.19 299.42,80.36 299.42,81.23 299.22,81.43 298.43,81.43
GND on TOP: 157.16,50.39 157.98,50.39 158.86,49.51 158.86,46.76 158.24,46.14 157.1,46.14 156.84,46.39 156.84,50.07
GND on TOP: 158.87,38.94 168.4,38.94 168.59,38.75 168.59,37.98 168.14,37.54 158.17,37.54 157.92,37.79 157.92,39.13 158.14,39.35 158.46,39.35
GND on TOP: 197.48,106.5 197.35,106.37 189.35,106.37 189.29,106.44 188.65,106.44 188.59,106.5 188.59,107.64 188.72,107.77 197.42,107.77 197.48,107.71
GND on TOP: 146.71,33.44 148.71,33.44 148.97,33.69 148.97,36.17 149.6,36.8 149.6,38.14 149.46,38.28 147.48,38.28 147.33,38.12 147.33,34.4 147.06,34.14 146.11,34.14 146.05,34.07 146.04,34.07 145.58,33.6 144.96,33.6 144.87,33.51 144.87,32.96 144.96,32.87 146.14,32.87
GND on TOP: 196.08,36.52 196.85,36.52 197.1,36.27 197.1,35.76 196.59,35.25 196.59,34.36 197.29,33.67 197.29,31.76 197.48,31.57 198.75,31.57 198.94,31.76 198.94,33.41 199.07,33.54 199.58,33.54 199.7,33.41 199.7,31.38 199.32,31 195.34,31 194.11,32.22 194.11,34.55
GND on TOP: 187.89,131.14 185.73,131.14 185.48,130.88 185.48,128.66 185.35,128.53 183.89,128.53 183.19,127.84 179.76,127.84 179.45,127.52 177.8,127.52 177.73,127.45 177.73,125.68 178.49,124.91 187,124.91 187.51,125.42 187.51,127.01 186.37,128.15 186.37,128.6 186.49,128.72 186.69,128.72 187.76,129.8 187.76,130.38 188.08,130.69 188.08,130.95
GND on TOP: 200.27,117.29 200.97,117.29 201.23,117.04 204.08,117.04 204.27,116.85 204.27,115.39 204.02,115.14 200.46,115.14 200.08,115.52 200.08,117.1
GND on TOP: 289.05,64.53 288.6,64.53 288.54,64.46 288.54,64.21 288.41,64.08 286.89,64.08 286.76,63.95 286.76,63.45 286.82,63.38 287.59,63.38 287.71,63.26 287.71,61.41 287.78,61.35 288.79,61.35 289.17,61.73 291.46,61.73 291.46,62.18 291.33,62.3 291.33,62.75 290.57,63.51 290.57,64.08 290.32,64.34 289.24,64.34
GND on TOP: 60.41,124.44 57.56,124.44 57.53,124.47 57.53,124.91 57.27,125.17 54.92,125.17 54.8,125.3 54.8,125.8 57.11,128.12 65.57,128.12 65.95,127.73 66.91,127.73 67.09,127.56 67.09,126.64 66.91,126.46 66.97,126.46 67.62,125.8 68.32,125.8 68.38,125.74 68.38,124.85 68.13,124.6 67.18,124.6 65.97,123.39 65.21,123.39 64.83,123.01 64.83,121.99 64.77,121.93 64.19,121.93 64.13,121.99 64.13,122.18 64.07,122.25 63.56,122.25 63.53,122.27 63.53,124.28 63,124.81 60.79,124.81
GND on TOP: 149.51,126.18 149.59,126.11 149.59,124.97 149.54,124.91 147.76,124.91 147.63,125.04 147.63,125.98 147.84,126.18
GND on TOP: 138.56,92.3 138.79,92.3 139.12,91.97 139.37,91.97 139.37,91.06 139.5,90.93 140.97,90.93 141.12,91.08 141.12,91.67 141.63,91.67 141.63,91.13 141.89,90.88 143.36,90.88 143.51,91.03 143.51,91.94 144.15,91.94 144.15,91.13 144.45,90.83 144.45,90.62 144.25,90.42 139.52,90.42 138.43,91.51 138.43,92.17
GND on TOP: 247.65,41.54 245.8,41.54 245.61,41.73 245.61,44.97 245.93,45.29 247.07,45.29 247.77,44.59 247.77,41.67
GND on TOP: 300.51,51.22 300.7,51.41 300.7,51.72 300.58,51.85 297.81,51.85 297.3,52.36 297.3,53.03 296.86,53.48 294.76,53.48 294.57,53.29 294.57,51.38 294.7,51.25 295.46,51.25 295.65,51.45 297.33,51.45 297.56,51.22 298.58,51.22 298.59,51.21 299.78,51.21 299.79,51.22
GND on TOP: 197.29,128.85 194.94,128.85 193.86,127.77 189.67,127.77 188.84,126.95 188.84,117.36 189.29,116.91 192.15,116.91 192.27,117.04 192.27,125.49 192.46,125.68 194.37,125.68 194.56,125.49 194.56,123.07 194.69,122.95 199.96,122.95 200.4,123.39 200.4,125.74
GND on TOP: 169.39,106.5 168.95,106.5 168.63,106.18 168.63,103.45 168.83,103.25 168.83,102.73 168.5,102.4 168.5,101.8 168.62,101.69 169.54,101.69 169.54,102.92 169.2,103.26 169.2,105.8 169.52,106.12 169.52,106.37
GND on TOP: 247.42,62.37 247.29,62.5 246.02,62.5 245.96,62.43 245.96,60.12 246.06,60.02 247.2,60.02 247.42,60.24
GND on TOP: 194.56,90.62 194.37,90.43 193.54,90.43 193.23,90.75 193.23,95.32 193.35,95.45 194.37,95.45 194.56,95.26
GND on TOP: 184.65,103.26 185.42,103.26 185.73,103.58 186.3,103.58 186.49,103.77 186.49,105.08 186,105.57 186,106.47 185.85,106.63 184.97,106.63 184.59,106.25 184.59,103.32
GND on TOP: 295.89,28.67 294.78,28.67 294.7,28.6 294.7,28.01 294.52,27.84 294.52,27.4 294.57,27.35 295.49,27.35 296.05,27.91 296.05,28.52
GND on TOP: 101.96,93.21 102.14,93.39 103.28,93.39 103.94,94.05 103.94,98.38 104.11,98.55 104.11,98.59 109.83,98.59 109.92,98.5 109.92,88.89 109.57,88.54 105.29,88.54 104.8,88.05 104.8,84.77 104.71,84.68 102.48,84.68 101.96,85.21
GND on TOP: 155.89,117.61 155.13,117.61 154.55,117.04 154.55,114.31 154.68,114.18 156.59,114.18 156.78,114.37 156.78,116.41 156.52,116.66 156.52,116.98
GND on TOP: 164.4,116.66 164.59,116.47 164.59,114.44 164.78,114.25 166.43,114.25 166.56,114.37 166.56,116.41 166.24,116.72 166.24,116.85 165.79,117.29 165.79,117.49 165.6,117.68 164.84,117.68 164.4,117.23
GND on TOP: 149.56,91.92 149.99,91.92 150.01,91.89 150.01,89.96 149.86,89.81 148.67,89.81 148.57,89.91 148.57,90.8 149.48,91.72 149.48,91.84
GND on TOP: 201.67,134.82 199.26,134.82 197.86,133.42 197.86,132.15 198.5,131.52 201.48,131.52 201.8,131.84 201.8,134.69
GND on TOP: 184.4,78.94 186.49,78.94 187.26,78.18 187.26,75.51 186.94,75.19 184.21,75.19 183.89,75.51 183.89,78.43
GND on TOP: 193.2,84.74 193.35,84.59 194.31,84.59 194.5,84.4 194.5,82.5 194.37,82.37 191.77,82.37 191.38,82.75 191.38,86.14 191.4,86.14 192.41,87.14 193.22,87.14 193.26,87.1 193.26,86.42 193.2,86.36
GND on TOP: 177.6,131.26 176.08,131.26 175.7,130.88 175.7,127.9 175.51,127.71 169.54,127.71 169.41,127.58 169.41,125.04 169.67,124.79 170.81,124.79 171.13,125.11 177.03,125.11 177.48,125.55 177.48,129.36 177.67,129.55 177.67,131.2
GND on TOP: 161.35,117.68 160.14,117.68 159.89,117.42 159.89,114.31 159.95,114.25 161.6,114.25 161.67,114.31 161.67,116.47 161.29,116.85 161.29,117.17 161.48,117.36 161.48,117.55
GND on TOP: 57.34,104.65 57.36,105.14 56.87,105.18 56.87,106.73 57.01,106.86 57.6,106.86 57.68,106.78 57.68,106.4 57.83,106.25 58.73,106.25 58.86,106.12 58.86,105.54 58.73,105.41 58.73,104.74 58.64,104.65
GND on TOP: 119.21,32.55 119.25,32.47 119.25,31.51 120.39,30.36 120.39,29.73 120.14,29.47 118.04,29.47 117.85,29.66 117.85,32.08 117.41,32.52 117.41,35.82 117.32,35.91 117.32,37.18 117.54,37.4 118.52,37.4 118.68,37.24 118.68,34.81 118.67,34.8 118.64,34.62 118.67,34.44 118.68,34.43 118.68,33.98 118.64,33.95 118.64,33.6 118.64,33.5 118.66,33.41 118.66,33.04 118.74,32.66 119.11,32.57
GND on TOP: 147.75,105.23 148.16,105.23 148.24,105.15 148.24,104.19 148.01,103.96 148.01,102.36 147.96,102.31 147.65,102.31 147.65,105.13
GND on TOP: 241.99,110.94 241.87,110.82 241.04,110.82 240.6,110.37 240.03,110.37 239.83,110.56 239.83,111.07 239.39,111.52 239.39,112.09 239.52,112.21 241.68,112.21 241.99,111.9
GND on TOP: 247.9,57.29 247.84,57.35 247.84,59.13 247.9,59.19 248.92,59.19 249.04,59.07 249.04,57.48 248.85,57.29
GND on TOP, BOTTOM: 212.91,40.65 213.99,40.65 214.24,40.4 214.24,35.89 214.12,35.76 212.97,35.76 212.66,36.08 212.66,40.4
GND on TOP, BOTTOM, IN1, IN2, IN3, IN4: 304.76,43.69 302.34,43.69 302.01,43.36 302.01,42.16 302.93,41.25 308.62,41.25 309.02,40.84 313.16,40.84 313.37,41.04 313.37,41.6 312.81,42.16 310.45,42.16 310.12,41.83 306.81,41.83 306.36,41.37 305.65,41.37 305.04,41.98 305.04,43.41
GND on BOTTOM: 244.98,88.85 245.93,88.85 246.12,88.66 246.12,86.62 245.99,86.5 244.91,86.5 244.85,86.56 244.85,88.72
GND on BOTTOM: 245.83,41.29 245.7,41.41 245.7,44.34 246.21,44.84 246.21,46.43 245.83,46.81 245.83,47.89 246.21,48.27 246.21,49.48 245.96,49.73 245.96,50.35 246.17,50.56 246.38,50.56 246.53,50.4 246.53,48.15 246.97,47.7 246.97,44.78 247.17,44.59 247.61,44.59 247.74,44.46 247.74,41.41 247.61,41.29
GND on BOTTOM: 86.23,36.97 95.05,36.97 96.01,36.01 97.47,36.01 97.7,35.79 97.7,31.61 97.28,31.19 96.71,31.19 96.39,31.51 96.39,32.27 93.78,34.87 93.47,34.87 93.15,35.19 90.17,35.19 89.85,34.87 89.21,34.87 88.2,33.86 85.28,33.86 82.67,36.46 82.67,38.49 82.86,38.68 84.51,38.68
GND on BOTTOM: 176.89,33.97 176.92,34 177.49,34 177.54,33.95 177.54,32.2 176.46,31.12 173.32,31.12 173.08,31.36 173.08,32.65 173.22,32.78 175.56,32.78 175.58,32.8 175.58,33.32 175.66,33.4 176.86,33.4 176.89,33.43
GND on BOTTOM: 29.27,114.25 27.87,114.25 27.62,113.99 27.62,110.82 28.06,110.37 29.14,110.37 29.33,110.56 29.33,114.18
GND on BOTTOM: 298.13,89.86 298.13,87.89 298.19,87.83 300.99,87.83 301.18,88.02 301.18,89.61 300.99,89.8 300.1,89.8 299.91,89.99 299.91,90.24 298.51,90.24
GND on BOTTOM: 177.73,134.25 175.89,134.25 175.7,134.06 175.7,127.84 175.51,127.65 170.94,127.65 170.81,127.77 168.52,127.77 168.4,127.65 168.08,127.65 167.95,127.52 167.95,127.33 168.14,127.14 168.33,127.14 168.65,127.45 170.18,127.45 170.24,127.39 170.24,126.88 170.18,126.82 169.54,126.82 169.48,126.76 169.48,125.42 169.54,125.36 176.97,125.36 177.54,125.93 177.54,127.65 177.55,127.66 177.55,127.83 177.7,127.98 177.7,130.79 177.92,131.01 177.92,134.06
GND on BOTTOM: 188.21,134.19 186.49,134.19 186.24,133.93 186.24,131.39 185.42,130.57 185.42,128.66 184.53,127.77 179.38,127.77 179.32,127.84 178.37,127.84 178.24,127.71 177.77,127.71 177.68,127.62 177.68,127.1 177.74,127.04 178.24,127.04 178.35,127.15 178.35,127.32 178.56,127.52 179.26,127.52 179.32,127.45 180.14,127.45 180.21,127.39 180.21,126.95 180.14,126.88 179.51,126.88 179.45,126.82 179.45,125.61 179.57,125.49 183.45,125.49 184.02,124.91 186.49,124.91 186.72,125.14 186.72,128.63 187.7,129.61 187.7,130.44 188.34,131.07 188.34,134.06
GND on BOTTOM: 160.84,130.38 160.9,130.31 160.9,129.42 160.71,129.23 159.63,129.23 159.51,129.11 159.51,127.96 159.57,127.9 160.97,127.9 161.09,128.03 161.09,129.23 161.22,129.36 161.22,130.38 161.35,130.5 161.35,131.01 161.22,131.14 160.97,131.14 160.84,131.01
GND on BOTTOM: 288.03,92.15 288.43,92.15 288.98,92.71 292.51,92.71 292.57,92.66 292.57,92.02 292.49,91.95 289.19,91.95 288.88,91.64 288.09,91.64 287.97,91.77 287.97,92.09
GND on BOTTOM: 93.45,135.78 93.68,136.01 95.64,136.01 96.12,135.53 96.12,133.4 95.83,133.11 93.66,133.11 93.45,133.32
GND on BOTTOM: 201.8,92.99 199.58,92.99 199.45,92.86 199.45,91.72 199.58,91.59 201.86,91.59 201.93,91.65 201.93,92.86
GND on BOTTOM: 191.6,82.32 191.32,82.6 191.32,86.05 192.4,87.13 195.15,87.13 195.54,87.52 196.5,87.52 196.88,87.14 197.17,87.14 197.18,87.15 198.01,87.15 198.32,87.46 199.13,87.46 199.19,87.39 199.19,87.01 199.06,86.87 197.18,86.87 197.17,86.87 196.8,86.49 194.91,86.49 194.85,86.43 193.58,86.43 193.2,86.06 193.2,85 193.42,84.78 194.24,84.78 194.24,84.78 194.52,84.5 194.52,82.55 194.53,82.53 194.53,82.51 194.34,82.32
GND on BOTTOM: 295.59,86.69 300.86,86.69 300.92,86.62 300.92,86.01 301.15,85.79 302.14,85.79 302.36,86 302.36,87.83 302.51,87.98 303.21,87.98 303.3,87.89 303.3,87.25 302.9,86.85 302.9,84.8 302.81,84.71 297.04,84.71 296.96,84.78 296.96,85.57 296.73,85.8 296.48,85.8 296.22,85.54 295.65,85.54 295.52,85.67 295.52,86.62
GND on BOTTOM: 91.91,58.15 90.74,59.32 90.74,64.3 94.17,64.3 96.22,62.24 118.22,62.24 120.23,60.23 156.12,60.23 157.53,58.83 157.53,53.38 157.53,53.37 157.53,53.29 157.57,53.25 157.65,53.25 158.12,52.78 158.12,48.26 158.23,48.14 158.23,47.3 157.82,46.89 157.78,46.84 157.78,45.01 157.19,44.42 136.9,44.42 136.27,45.06 119.57,45.06 118.74,44.23 94.01,44.23 93.76,44.49 93.35,44.49 91.91,45.93 91.91,49.01 92.9,50.06 91.91,51.11 ; 5 cut-outs
GND on BOTTOM: 170.94,129.42 170.94,130.31 170.87,130.38 170.87,130.69 171,130.82 171.25,130.82 171.38,130.69 171.38,130.44 171.25,130.31 171.25,128.03 171.13,127.9 169.6,127.9 169.54,127.96 169.54,129.11 169.67,129.23 170.75,129.23
GND on BOTTOM: 179.45,31.72 179.45,34.68 179.19,34.94 178.24,34.94 177.35,35.82 175.7,35.82 175.57,35.95 175.57,36.78 175.64,36.84 177.8,36.84 177.99,36.65 177.99,36.4 178.18,36.21 180.34,36.21 180.53,36.4 180.53,37.79 180.59,37.86 182.49,37.86 182.75,37.6 182.75,34.87 181.99,34.11 181.22,34.11 180.46,33.35 180.46,31.84 180.17,31.55 179.62,31.55
GND on BOTTOM: outline of 267 points within 166.19,40.78 234.44,54.91 ; 1 cut-out
GND on BOTTOM: 249.9,57.48 249.9,62.94 249.83,63 242.25,63 242.06,62.81 242.06,60.27 242.18,60.14 243.45,60.14 243.58,60.27 243.58,62.18 243.71,62.3 245.68,62.3 245.9,62.09 245.9,60.31 246.06,60.14 247.26,60.14 247.42,60.3 247.42,62.24 247.48,62.31 248.31,62.31 248.44,62.18 248.44,57.54 248.69,57.29 249.71,57.29
GND on BOTTOM: 190.56,129.42 190.56,130.5 190.5,130.57 190.5,130.82 190.62,130.95 190.81,130.95 191,130.76 191,130.63 190.88,130.5 190.88,128.22 190.69,128.03 189.23,128.03 189.16,128.09 189.16,129.23 189.23,129.3 190.43,129.3
GND on BOTTOM: 193.16,133.36 193.16,132.34 193.35,132.15 196.15,132.15 196.27,132.28 196.27,134.25 196.15,134.38 192.46,134.38 192.34,134.25 192.34,133.61 192.4,133.55 192.97,133.55
GND on BOTTOM: 102.84,93.29 101.98,93.29 101.91,93.23 101.91,84.15 101.98,84.08 102.17,84.08 102.23,84.15 102.23,85.67 102.29,85.74 102.8,85.74 102.87,85.67 102.87,85.16 102.93,85.1 104.07,85.1 104.26,85.29 104.26,89.16 104.31,89.22 107.13,89.22 107.42,89.51 107.42,90.85 107.15,91.13 105,91.13
GND on BOTTOM: 158.75,38.94 163.7,38.94 163.89,38.75 163.89,37.73 163.7,37.54 161.22,37.54 160.84,37.92 158.3,37.92 157.98,38.24 157.98,39.13 158.17,39.32 158.36,39.32
GND on BOTTOM: 193.67,93.48 194.37,93.48 194.56,93.29 194.56,90.62 194.37,90.43 193.54,90.43 193.42,90.56 193.42,93.23
GND on BOTTOM: 243.26,133.55 242.86,133.96 241.44,133.96 241.16,133.68 241.16,131.83 241.64,131.34 241.64,130.66 241.74,130.57 243.01,130.57 243.26,130.82
GND on BOTTOM: 197.35,99.96 197.54,99.96 197.61,99.9 197.61,98.94 197.73,98.82 198.5,98.82 198.62,98.69 198.62,97.17 198.5,97.04 197.92,97.04 197.67,96.78 197.67,95.32 197.54,95.2 195.89,95.2 195.64,95.45 195.64,96.15 195.89,96.4 196.21,96.4 196.85,97.04 196.85,98.69 196.97,98.82 197.16,98.82 197.29,98.94 197.29,99.9
GND on BOTTOM: 97.59,128.03 100.96,128.03 101.21,127.77 101.21,124.98 100.96,124.72 97.79,124.72 97.34,125.17 97.34,127.77
GND on BOTTOM: 201.73,116.98 201.42,117.29 198.62,117.29 198.5,117.42 198.43,117.42 198.5,117.49 198.5,119.96 198.69,120.15 198.69,120.41 198.62,120.47 198.31,120.47 198.24,120.41 198.24,120.09 198.18,120.03 198.18,119.01 198.05,118.88 197.61,118.88 197.54,118.95 197.54,120.28 197.42,120.41 197.04,120.41 196.91,120.28 196.91,120.03 197.16,119.77 197.16,118.88 197.1,118.82 196.85,118.82 196.72,118.69 196.72,117.55 196.59,117.42 196.4,117.42 196.34,117.36 195.26,117.36 195.19,117.29 195.19,116.91 195.26,116.85 195.64,116.85 195.77,116.98 196.4,116.98 196.53,117.1 197.42,117.1 197.54,116.98 197.54,116.53 197.42,116.41 196.85,116.41 196.78,116.34 196.78,115.26 196.85,115.2 200.46,115.2 200.85,114.82 200.85,114.18 199.83,113.17 199.83,108.79 200.15,108.47 203.96,108.47 204.4,108.91 204.4,116.66 204.08,116.98
GND on BOTTOM: outline of 392 points within 35.91,101.61 46.71,112.69
GND on BOTTOM: 281.94,89.32 282,89.26 283.08,89.26 283.21,89.39 283.21,91.86 283.08,91.99 282.06,91.99 281.94,91.86
GND on BOTTOM: 295.65,81.86 295.52,81.73 295.52,80.3 295.66,80.16 298.71,80.16 299.59,81.04 299.59,81.67 299.4,81.86
GND on BOTTOM: 180.88,129.3 180.88,130.38 180.81,130.44 180.81,130.69 180.94,130.82 181.13,130.82 181.32,130.63 181.32,130.5 181.19,130.38 181.19,128.09 181,127.9 179.54,127.9 179.48,127.96 179.48,129.11 179.54,129.17 180.75,129.17
GND on BOTTOM: 283.83,56.13 283.9,56.21 287.33,56.21 287.42,56.12 287.42,52.6 287.4,52.6 287.39,52.59 283.9,52.59 283.83,52.66
GND on BOTTOM: 202.12,99.96 202.75,99.96 202.81,99.9 202.81,96.91 202.62,96.72 201.86,96.72 201.67,96.91 201.67,97.74 201.42,97.99 201.42,98.75 201.23,98.94 201.23,99.51 201.29,99.58 201.73,99.58
GND on BOTTOM: 135.19,43.83 140.01,43.83 140.39,43.44 140.39,39.27 140.25,39.13 135.06,39.13 134.74,39.44 134.74,43.38
GND on BOTTOM: outline of 89 points within 39.88,107.81 45.62,110.31
GND on BOTTOM: 196.53,36.52 198.31,36.52 198.69,36.9 199.77,36.9 200.15,36.52 201.16,36.52 201.8,37.16 202.12,37.16 202.43,36.84 202.43,36.65 202.18,36.4 201.93,36.4 201.67,36.14 200.08,36.14 199.64,35.7 196.85,35.7 196.59,35.44 196.59,34.68 197.04,34.24 197.04,32.71 197.29,32.46 197.29,31.76 197.28,31.75 197.28,31.36 196.82,30.9 194.33,30.9 193.79,31.44 193.79,37.76 193.97,37.94 195.88,37.94 195.99,37.83 195.99,37.06
GND on BOTTOM: 148.59,126.18 149.47,126.18 149.98,125.68 150.49,125.68 150.62,125.55 150.62,125.04 150.49,124.91 148.27,124.91 148.2,124.98 148.2,125.8
GND on BOTTOM: 169.35,133.87 167.19,133.87 166.81,133.49 166.81,130.76 166.75,130.69 166.17,130.69 165.92,130.44 165.92,127.2 165.79,127.07 164.52,127.07 163.83,127.77 157.98,127.77 157.86,127.65 157.86,127.2 157.98,127.07 158.17,127.07 158.49,127.39 159.19,127.39 159.25,127.45 160.14,127.45 160.21,127.39 160.21,126.88 160.14,126.82 159.57,126.82 159.51,126.76 159.51,125.55 159.63,125.42 163.32,125.42 164.14,124.6 167,124.6 167.83,125.42 167.83,130.25 168.46,130.88 169.35,130.88 169.54,131.07 169.54,133.68
GND on BOTTOM: 188.21,127.9 194.18,127.9 195.23,126.85 198.97,126.85 199.39,126.44 202.37,126.44 202.62,126.18 202.62,122.37 201.93,121.68 194.81,121.68 194.43,122.06 194.43,124.47 193.35,125.55 189.35,125.55 189.16,125.74 189.16,126.88 189.23,126.95 189.8,126.95 189.86,127.01 189.86,127.52 189.8,127.58 188.21,127.58 188.02,127.39 188.02,127.14 187.57,126.69 187.57,126.18 187.32,125.93 187.07,125.93 186.94,126.06 186.94,127.26 187,127.33 187.64,127.33
GND on BOTTOM: 222.83,115.76 222.18,115.76 222.08,115.87 222.08,116.8 222.55,117.27 222.55,117.88 222.63,117.95 222.98,117.95 223.02,117.91 223.02,117.08 223.05,117.05 223.48,117.05 223.53,117 223.53,116.58 223.47,116.52 223.06,116.52 222.87,116.33 222.87,115.81
GND on BOTTOM: 95.5,91.45 95.5,89.29 95.69,89.1 97.28,89.1 97.34,89.16 97.34,91.45 97.21,91.58 95.63,91.58
GND on GND1: outline of 378 points within 0.2,0.2 318.85,139
GND on IN1: 4.01,101.29 3.45,101.7 2.77,101.84 1.17,101.84 1.17,112.12 1.52,112.47 10.16,112.47 13.52,109.1 18.73,109.1 19.24,109.61 33.08,109.61 34.16,108.53 34.16,103.07 31.87,100.78 15.81,100.78 15.68,100.91 4.39,100.91
GND on VCC: 0.5,77.2 0.29,77.29 0.2,77.5 0.2,81.62 0.2,81.62 0.2,83.4 0.29,83.61 0.5,83.7 8.82,83.7 8.87,83.68 9.1,83.46 9.37,83.4 12.4,83.4 13.17,82.9 13.77,83.6 13.77,88.2 13.77,88.2 13.77,94.76 13.77,94.76 13.77,97.8 13.17,98.5 12.4,98 9.37,98 9.1,97.94 8.87,97.72 8.82,97.7 3.77,97.7 3.56,97.79 3.47,98 3.47,100.55 3.27,101.05 2.77,101.25 0.5,101.25 0.29,101.34 0.2,101.55 0.2,104.41 0.2,104.41 0.2,113.5 0.29,113.71 0.5,113.8 13.03,113.8 13.52,114 13.82,114.71 14.02,114.8 23.61,114.8 23.89,114.85 24.12,115.02 25.51,116.52 25.51,110.5 6.11,110.5 5.65,110.03 5.65,104.36 6.18,103.83 7.32,103.83 9.8,101.36 14.81,101.36 17.33,98.84 17.33,96.9 19.16,95.07 25.51,95.07 25.51,85.92 6.76,77.2
GND on VCC: 222.69,64.74 209.66,77.78 209.66,81.05 214.63,81.05 222.66,73.02 232.29,73.02 238.18,67.13 238.18,64.87 238.05,64.74
GND on VCC: 308.22,0.2 308.22,12.63 298.17,22.68 273.6,22.68 271.65,24.63 271.65,26.07 282.25,36.67 282.25,46.58 282.59,46.24 286.02,46.24 286.19,46.07 286.19,44.74 287.16,43.76 290.34,43.76 294.13,39.97 294.13,30.26 295.48,28.9 296.37,28.9 297.01,28.27 318.05,28.27 318.05,28.11 318.22,27.68 318.79,27.45 318.85,27.31 318.85,13.94 318.76,13.73 318.55,13.64 318.32,13.64 317.83,13.44 317.62,12.94 317.62,10.94 317.83,10.44 318.32,10.24 318.55,10.24 318.76,10.15 318.85,9.94 318.85,0.5 318.76,0.29 318.55,0.2
GND on VCC: outline of 150 points within 225.18,40.78 318.85,132.61
GND on VCC: 127.11,75.64 117.23,85.52 117.23,87.83 120.59,91.18 153.93,91.18 155.38,89.74 178.87,89.74 179.58,89.02 191.8,89.02 193.53,87.29 193.53,78.84 190.33,75.64
GND on VCC: 115.12,100.1 115.12,127.5 116.12,128.5 127.51,128.5 134.07,121.94 148.62,121.94 148.62,110.44 125.89,110.44 115.55,100.1
GND on IN2: 131.19,90.31 130.68,90.31 127.25,86.88 127.25,81.16 109.91,63.83 109.91,46.49 110.8,45.6 130.55,45.6 131.79,44.37 165.64,44.37 168.33,41.67 196.27,41.67 197.99,43.38 214.24,43.38 214.56,43.06 232.6,43.06 235.01,45.48 235.01,53.16 205.74,82.43 177.35,82.43 173.92,85.86 173.92,87.89 170.87,90.94 131.82,90.94
GND on GND2: outline of 378 points within 0.2,0.2 318.85,139
GND on IN4: 4.33,100.98 4.01,101.29 3.45,101.7 2.77,101.84 1.17,101.84 1.17,112.12 1.52,112.47 10.16,112.47 13.52,109.1 18.73,109.1 23.55,113.93 32.19,113.93 33.27,112.85 33.27,108.79 33.24,108.75 34.35,107.64 36.13,107.64 37.78,105.99 37.78,102.31 36.44,100.98
GND on GND3: outline of 380 points within 0.2,0.2 318.85,139
GNDA on TOP (solid shape): 292.67,52.98 292.67,50.82 292.29,50.44 290.76,50.44 290.7,50.51 290.7,51.08 290.89,51.27 290.89,53.17 290.95,53.24 292.41,53.24
GNDA on TOP: 294.25,59.64 294.25,59.95 294.06,60.14 292.35,60.14 292.22,60.02 292.22,58.87 292.35,58.75 294.19,58.75 294.25,58.81 294.25,59.13 293.75,59.13 293.75,59.64
GNDA on GND1, GND2, GND3: 297.22,28.78 296.58,29.41 295.69,29.41 294.64,30.47 294.64,40.18 290.55,44.27 287.37,44.27 286.7,44.95 286.7,46.28 286.23,46.75 282.8,46.75 282.25,47.3 282.25,50.53 282.14,50.65 282.31,50.81 283.64,50.81 284.16,51.33 284.16,52.28 284.21,52.33 287.51,52.33 287.71,52.54 287.71,54.5 287.89,54.68 289.48,54.68 290.56,55.76 292.21,55.76 292.73,56.28 292.73,58.36 292.4,58.68 290.77,58.68 290.39,58.3 289.38,58.3 287.53,56.46 286.69,56.46 286.51,56.64 286.51,57.93 287.08,58.5 287.08,59.77 287.83,60.53 288.01,60.53 288.07,60.59 288.84,60.59 289.47,61.22 292.88,61.22 293.94,60.17 293.94,44.8 298.02,40.71 308.18,40.71 308.63,40.27 318.01,40.27 318.04,40.2 318.05,40.12 318.05,39 317.96,38.79 317.75,38.7 305.35,38.7 304.65,38.1 305.15,37.33 305.15,31.87 304.65,31.1 305.35,30.5 317.75,30.5 317.96,30.41 318.05,30.2 318.05,28.78
